<?xml version='1.0' encoding='utf-8'?>
<device xmlns:xsi="http://www.w3.org/2001/XMLSchema-instance" schemaVersion="1.3" xsi:noNamespaceSchemaLocation="CMSIS-SVD.xsd">
    <vendor>Renesas Electronics Corporation</vendor>
    <vendorID>Renesas</vendorID>
    <name>R7FA6M5BH</name>
    <series>RA6</series>
    <version>1.30.00</version>
    <description>Arm Cortex,M33 based Microcontroller RA6M5 group</description>
    <licenseText>This software is supplied by Renesas Electronics Corporation and is only intended for \n
use with Renesas products. No other uses are authorized. This software is owned by \n
Renesas Electronics Corporation and is protected under all applicable laws, including \n
copyright laws. \n
\n
THIS SOFTWARE IS PROVIDED "AS IS" AND RENESAS MAKES NO WARRANTIES REGARDING \n
THIS SOFTWARE, WHETHER EXPRESS, IMPLIED OR STATUTORY, INCLUDING BUT NOT LIMITED TO \n
WARRANTIES OF MERCHANTABILITY, FITNESS FOR A PARTICULAR PURPOSE AND NON-INFRINGEMENT. \n
ALL SUCH WARRANTIES ARE EXPRESSLY DISCLAIMED. TO THE MAXIMUM EXTENT PERMITTED NOT \n
PROHIBITED BY LAW, NEITHER RENESAS ELECTRONICS CORPORATION NOR ANY OF ITS AFFILIATED \n
COMPANIES SHALL BE LIABLE FOR ANY DIRECT, INDIRECT, SPECIAL, INCIDENTAL OR CONSEQUENTIAL \n
DAMAGES FOR ANY REASON RELATED TO THIS SOFTWARE, EVEN IF RENESAS OR ITS AFFILIATES HAVE \n
BEEN ADVISED OF THE POSSIBILITY OF SUCH DAMAGES. \n
\n
Renesas reserves the right, without notice, to make changes to this software and to \n
discontinue the availability of this software. By using this software, you agree to \n
the additional terms and conditions found by accessing the following link: \n
http://www.renesas.com/disclaimer \n
\n</licenseText>
    <cpu>
        <name>CM33</name>
        <revision>r0p4</revision>
        <endian>little</endian>
        <mpuPresent>true</mpuPresent>
        <fpuPresent>true</fpuPresent>
        <vtorPresent>true</vtorPresent>
        <nvicPrioBits>4</nvicPrioBits>
        <vendorSystickConfig>false</vendorSystickConfig>
        <deviceNumInterrupts>96</deviceNumInterrupts>
    </cpu>
    <headerSystemFilename>system_RA6</headerSystemFilename>
    <headerDefinitionsPrefix>R_</headerDefinitionsPrefix>
    <addressUnitBits>8</addressUnitBits>
    <width>32</width>
    <size>32</size>
    <access>read-write</access>
    <resetValue>0</resetValue>
    <resetMask>0xffffffff</resetMask>
    <peripherals>
        <peripheral>
            <name>RMPU</name>
            <description>Renesas Memory Protection Unit</description>
            <baseAddress>0x40000000</baseAddress>
            <addressBlock>
                <offset>0x00</offset>
                <size>2</size>
                <usage>registers</usage>
            </addressBlock>
            <addressBlock>
                <offset>0x04</offset>
                <size>2</size>
                <usage>registers</usage>
            </addressBlock>
            <addressBlock>
                <offset>0x100</offset>
                <size>2</size>
                <usage>registers</usage>
            </addressBlock>
            <addressBlock>
                <offset>0x104</offset>
                <size>2</size>
                <usage>registers</usage>
            </addressBlock>
            <addressBlock>
                <offset>0x108</offset>
                <size>2</size>
                <usage>registers</usage>
            </addressBlock>
            <addressBlock>
                <offset>0x10C</offset>
                <size>2</size>
                <usage>registers</usage>
            </addressBlock>
            <addressBlock>
                <offset>0x200</offset>
                <size>136</size>
                <usage>registers</usage>
            </addressBlock>
            <addressBlock>
                <offset>0x500</offset>
                <size>2</size>
                <usage>registers</usage>
            </addressBlock>
            <addressBlock>
                <offset>0x504</offset>
                <size>2</size>
                <usage>registers</usage>
            </addressBlock>
            <addressBlock>
                <offset>0x508</offset>
                <size>2</size>
                <usage>registers</usage>
            </addressBlock>
            <addressBlock>
                <offset>0x600</offset>
                <size>72</size>
                <usage>registers</usage>
            </addressBlock>
            <registers>
                <register>
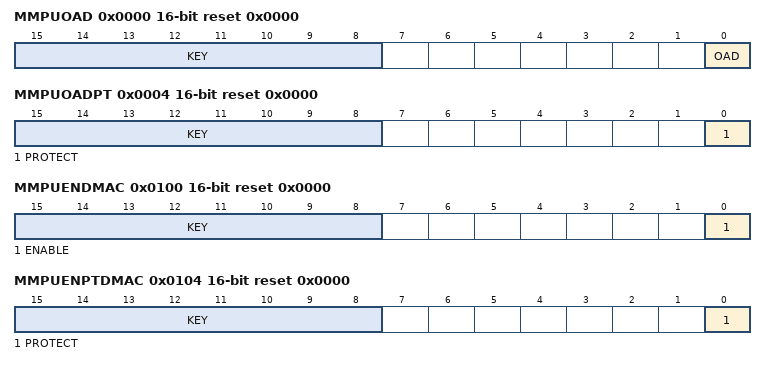
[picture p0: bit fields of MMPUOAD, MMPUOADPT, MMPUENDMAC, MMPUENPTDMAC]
                    <name>MMPUOAD</name>
                    <description>MMPU Operation After Detection Register</description>
                    <addressOffset>0x0000</addressOffset>
                    <size>16</size>
                    <access>read-write</access>
                    <resetValue>0x0000</resetValue>
                    <resetMask>0xffff</resetMask>
                    <fields>
                        <field>
                            <name>OAD</name>
                            <description>Operation after detection</description>
                            <lsb>0</lsb>
                            <msb>0</msb>
                            <access>read-write</access>
                            <enumeratedValues>
                                </enumeratedValues>
                        </field>
                        <field>
                            <name>KEY</name>
                            <description>This bit enables or disables writes to the OAD bit.</description>
                            <lsb>8</lsb>
                            <msb>15</msb>
                            <access>write-only</access>
                        </field>
                    </fields>
                </register>
                <register>
                    <name>MMPUOADPT</name>
                    <description>MMPU Operation After Detection Protect Register</description>
                    <addressOffset>0x0004</addressOffset>
                    <size>16</size>
                    <access>read-write</access>
                    <resetValue>0x0000</resetValue>
                    <resetMask>0xffff</resetMask>
                    <fields>
                        <field>
                            <name>PROTECT</name>
                            <description>Protection of register</description>
                            <lsb>0</lsb>
                            <msb>0</msb>
                            <access>read-write</access>
                            <enumeratedValues>
                                </enumeratedValues>
                        </field>
                        <field>
                            <name>KEY</name>
                            <description>Key code</description>
                            <lsb>8</lsb>
                            <msb>15</msb>
                            <access>write-only</access>
                        </field>
                    </fields>
                </register>
                <register>
                    <name>MMPUENDMAC</name>
                    <description>MMPU Enable Register for DMAC</description>
                    <addressOffset>0x0100</addressOffset>
                    <size>16</size>
                    <access>read-write</access>
                    <resetValue>0x0000</resetValue>
                    <resetMask>0xffff</resetMask>
                    <fields>
                        <field>
                            <name>ENABLE</name>
                            <description>Bus Master MPU of DMAC enable</description>
                            <lsb>0</lsb>
                            <msb>0</msb>
                            <access>read-write</access>
                            <enumeratedValues>
                                </enumeratedValues>
                        </field>
                        <field>
                            <name>KEY</name>
                            <description>These bits enable or disable writes to the ENABLE bit.</description>
                            <lsb>8</lsb>
                            <msb>15</msb>
                            <access>write-only</access>
                        </field>
                    </fields>
                </register>
                <register>
                    <name>MMPUENPTDMAC</name>
                    <description>MMPU Enable Protect Register for DMAC</description>
                    <addressOffset>0x0104</addressOffset>
                    <size>16</size>
                    <access>read-write</access>
                    <resetValue>0x0000</resetValue>
                    <resetMask>0xffff</resetMask>
                    <fields>
                        <field>
                            <name>PROTECT</name>
                            <description>Protection of register</description>
                            <lsb>0</lsb>
                            <msb>0</msb>
                            <access>read-write</access>
                            <enumeratedValues>
                                </enumeratedValues>
                        </field>
                        <field>
                            <name>KEY</name>
                            <description>These bits enable or disable writes to the PROTECT bit.</description>
                            <lsb>8</lsb>
                            <msb>15</msb>
                            <access>write-only</access>
                        </field>
                    </fields>
                </register>
                <register>
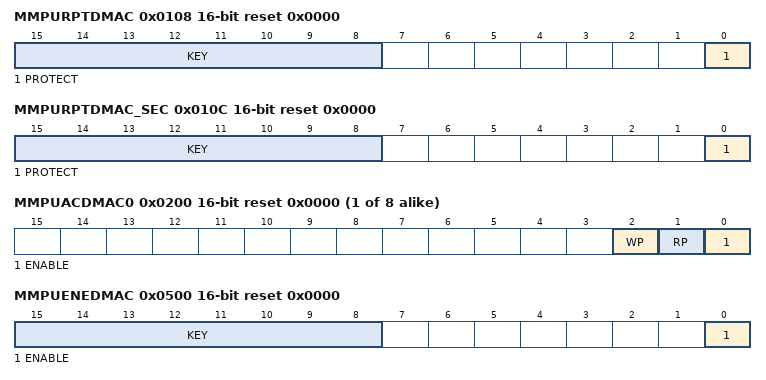
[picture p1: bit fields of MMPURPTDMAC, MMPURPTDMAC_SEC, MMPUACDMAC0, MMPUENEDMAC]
                    <name>MMPURPTDMAC</name>
                    <description>MMPU Regions Protect Register for DMAC</description>
                    <addressOffset>0x0108</addressOffset>
                    <size>16</size>
                    <access>read-write</access>
                    <resetValue>0x0000</resetValue>
                    <resetMask>0xffff</resetMask>
                    <fields>
                        <field>
                            <name>PROTECT</name>
                            <description>Protection of register</description>
                            <lsb>0</lsb>
                            <msb>0</msb>
                            <access>read-write</access>
                            <enumeratedValues>
                                </enumeratedValues>
                        </field>
                        <field>
                            <name>KEY</name>
                            <description>These bits enable or disable writes to the PROTECT bit.</description>
                            <lsb>8</lsb>
                            <msb>15</msb>
                            <access>write-only</access>
                        </field>
                    </fields>
                </register>
                <register>
                    <name>MMPURPTDMAC_SEC</name>
                    <description>MMPU Regions Protect register for DMAC Secure</description>
                    <addressOffset>0x010C</addressOffset>
                    <size>16</size>
                    <access>read-write</access>
                    <resetValue>0x0000</resetValue>
                    <resetMask>0xffff</resetMask>
                    <fields>
                        <field>
                            <name>PROTECT</name>
                            <description>Protection of register</description>
                            <lsb>0</lsb>
                            <msb>0</msb>
                            <access>read-write</access>
                            <enumeratedValues>
                                </enumeratedValues>
                        </field>
                        <field>
                            <name>KEY</name>
                            <description>These bits enable or disable writes to the PROTECT bit.</description>
                            <lsb>8</lsb>
                            <msb>15</msb>
                            <access>write-only</access>
                        </field>
                    </fields>
                </register>
                <register>
                    <dim>8</dim>
                    <dimIncrement>0x010</dimIncrement>
                    <dimIndex>0-7</dimIndex>
                    <name>MMPUACDMAC%s</name>
                    <description>MMPU Access Control Register for DMAC</description>
                    <addressOffset>0x0200</addressOffset>
                    <size>16</size>
                    <access>read-write</access>
                    <resetValue>0x0000</resetValue>
                    <resetMask>0xffff</resetMask>
                    <fields>
                        <field>
                            <name>ENABLE</name>
                            <description>Region enable</description>
                            <lsb>0</lsb>
                            <msb>0</msb>
                            <access>read-write</access>
                            <enumeratedValues>
                                </enumeratedValues>
                        </field>
                        <field>
                            <name>RP</name>
                            <description>Read protection</description>
                            <lsb>1</lsb>
                            <msb>1</msb>
                            <access>read-write</access>
                            <enumeratedValues>
                                </enumeratedValues>
                        </field>
                        <field>
                            <name>WP</name>
                            <description>Write protection</description>
                            <lsb>2</lsb>
                            <msb>2</msb>
                            <access>read-write</access>
                            <enumeratedValues>
                                </enumeratedValues>
                        </field>
                    </fields>
                </register>
                <register>
                    <dim>8</dim>
                    <dimIncrement>0x010</dimIncrement>
                    <dimIndex>0-7</dimIndex>
                    <name>MMPUSDMAC%s</name>
                    <description>MMPU Start Address Register for DMAC</description>
                    <addressOffset>0x0204</addressOffset>
                    <size>32</size>
                    <access>read-write</access>
                    <resetValue>0x00000000</resetValue>
                    <resetMask>0x0000001f</resetMask>
                    <fields>
                        <field>
                            <name>MMPUS</name>
                            <description>Region start address register</description>
                            <lsb>5</lsb>
                            <msb>31</msb>
                            <access>read-write</access>
                        </field>
                    </fields>
                </register>
                <register>
                    <dim>8</dim>
                    <dimIncrement>0x010</dimIncrement>
                    <dimIndex>0-7</dimIndex>
                    <name>MMPUEDMAC%s</name>
                    <description>MMPU End Address Register for DMAC</description>
                    <addressOffset>0x0208</addressOffset>
                    <size>32</size>
                    <access>read-write</access>
                    <resetValue>0x0000001f</resetValue>
                    <resetMask>0x0000001f</resetMask>
                    <fields>
                        <field>
                            <name>MMPUE</name>
                            <description>Region end address register</description>
                            <lsb>5</lsb>
                            <msb>31</msb>
                            <access>read-write</access>
                        </field>
                    </fields>
                </register>
                <register>
                    <name>MMPUENEDMAC</name>
                    <description>MMPU Enable Register for EDMAC</description>
                    <addressOffset>0x0500</addressOffset>
                    <size>16</size>
                    <access>read-write</access>
                    <resetValue>0x0000</resetValue>
                    <resetMask>0xffff</resetMask>
                    <fields>
                        <field>
                            <name>ENABLE</name>
                            <description>Bus Master MPU of EDMAC enable</description>
                            <lsb>0</lsb>
                            <msb>0</msb>
                            <access>read-write</access>
                            <enumeratedValues>
                                </enumeratedValues>
                        </field>
                        <field>
                            <name>KEY</name>
                            <description>These bits enable or disable writes to the ENABLE bit.</description>
                            <lsb>8</lsb>
                            <msb>15</msb>
                            <access>write-only</access>
                        </field>
                    </fields>
                </register>
                <register>
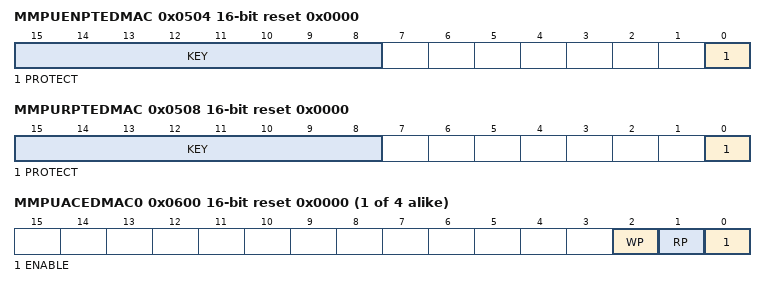
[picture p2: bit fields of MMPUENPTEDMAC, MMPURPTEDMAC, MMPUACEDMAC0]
                    <name>MMPUENPTEDMAC</name>
                    <description>MMPU Enable Protect Register for EDMAC</description>
                    <addressOffset>0x0504</addressOffset>
                    <size>16</size>
                    <access>read-write</access>
                    <resetValue>0x0000</resetValue>
                    <resetMask>0xffff</resetMask>
                    <fields>
                        <field>
                            <name>PROTECT</name>
                            <description>Protection of register</description>
                            <lsb>0</lsb>
                            <msb>0</msb>
                            <access>read-write</access>
                            <enumeratedValues>
                                </enumeratedValues>
                        </field>
                        <field>
                            <name>KEY</name>
                            <description>These bits enable or disable writes to the PROTECT bit.</description>
                            <lsb>8</lsb>
                            <msb>15</msb>
                            <access>write-only</access>
                        </field>
                    </fields>
                </register>
                <register>
                    <name>MMPURPTEDMAC</name>
                    <description>MMPU Regions Protect Register for EDMAC</description>
                    <addressOffset>0x0508</addressOffset>
                    <size>16</size>
                    <access>read-write</access>
                    <resetValue>0x0000</resetValue>
                    <resetMask>0xffff</resetMask>
                    <fields>
                        <field>
                            <name>PROTECT</name>
                            <description>Protection of register</description>
                            <lsb>0</lsb>
                            <msb>0</msb>
                            <access>read-write</access>
                            <enumeratedValues>
                                </enumeratedValues>
                        </field>
                        <field>
                            <name>KEY</name>
                            <description>This bit is used to enable or disable writing of the PROTECT bit.</description>
                            <lsb>8</lsb>
                            <msb>15</msb>
                            <access>write-only</access>
                        </field>
                    </fields>
                </register>
                <register>
                    <dim>4</dim>
                    <dimIncrement>0x010</dimIncrement>
                    <dimIndex>0-3</dimIndex>
                    <name>MMPUACEDMAC%s</name>
                    <description>MMPU Access Control Register for EDMAC</description>
                    <addressOffset>0x0600</addressOffset>
                    <size>16</size>
                    <access>read-write</access>
                    <resetValue>0x0000</resetValue>
                    <resetMask>0xffff</resetMask>
                    <fields>
                        <field>
                            <name>ENABLE</name>
                            <description>Region enable</description>
                            <lsb>0</lsb>
                            <msb>0</msb>
                            <access>read-write</access>
                            <enumeratedValues>
                                </enumeratedValues>
                        </field>
                        <field>
                            <name>RP</name>
                            <description>Read protection</description>
                            <lsb>1</lsb>
                            <msb>1</msb>
                            <access>read-write</access>
                            <enumeratedValues>
                                </enumeratedValues>
                        </field>
                        <field>
                            <name>WP</name>
                            <description>Write protection</description>
                            <lsb>2</lsb>
                            <msb>2</msb>
                            <access>read-write</access>
                            <enumeratedValues>
                                </enumeratedValues>
                        </field>
                    </fields>
                </register>
                <register>
                    <dim>4</dim>
                    <dimIncrement>0x010</dimIncrement>
                    <dimIndex>0-3</dimIndex>
                    <name>MMPUSEDMAC%s</name>
                    <description>MMPU Start Address Register for EDMAC</description>
                    <addressOffset>0x0604</addressOffset>
                    <size>32</size>
                    <access>read-write</access>
                    <resetValue>0x00000000</resetValue>
                    <resetMask>0x0000001f</resetMask>
                    <fields>
                        <field>
                            <name>MMPUS</name>
                            <description>Region start address register for EDMAC</description>
                            <lsb>5</lsb>
                            <msb>31</msb>
                            <access>read-write</access>
                        </field>
                    </fields>
                </register>
                <register>
                    <dim>4</dim>
                    <dimIncrement>0x010</dimIncrement>
                    <dimIndex>0-3</dimIndex>
                    <name>MMPUEEDMAC%s</name>
                    <description>MMPU End Address Register for EDMAC</description>
                    <addressOffset>0x0608</addressOffset>
                    <size>32</size>
                    <access>read-write</access>
                    <resetValue>0x0000001f</resetValue>
                    <resetMask>0x0000001f</resetMask>
                    <fields>
                        <field>
                            <name>MMPUE</name>
                            <description>Region end address register for EDMAC</description>
                            <lsb>5</lsb>
                            <msb>31</msb>
                            <access>read-write</access>
                        </field>
                    </fields>
                </register>
            </registers>
        </peripheral>
        <peripheral>
            <name>TZF</name>
            <description>TrustZone Filter</description>
            <baseAddress>0x40000E00</baseAddress>
            <addressBlock>
                <offset>0x00</offset>
                <size>2</size>
                <usage>registers</usage>
            </addressBlock>
            <addressBlock>
                <offset>0x04</offset>
                <size>2</size>
                <usage>registers</usage>
            </addressBlock>
            <registers>
                <register>
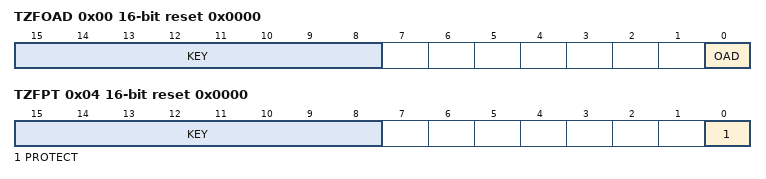
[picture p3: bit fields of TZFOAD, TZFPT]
                    <name>TZFOAD</name>
                    <description>TrustZone Filter Operation After Detection Register </description>
                    <addressOffset>0x00</addressOffset>
                    <size>16</size>
                    <access>read-write</access>
                    <resetValue>0x0000</resetValue>
                    <resetMask>0xffff</resetMask>
                    <fields>
                        <field>
                            <name>OAD</name>
                            <description>Operation after detection</description>
                            <lsb>0</lsb>
                            <msb>0</msb>
                            <access>read-write</access>
                            <enumeratedValues>
                                </enumeratedValues>
                        </field>
                        <field>
                            <name>KEY</name>
                            <description>KeyCode</description>
                            <lsb>8</lsb>
                            <msb>15</msb>
                            <access>write-only</access>
                        </field>
                    </fields>
                </register>
                <register>
                    <name>TZFPT</name>
                    <description>TrustZone Filter Protect Register</description>
                    <addressOffset>0x04</addressOffset>
                    <size>16</size>
                    <access>read-write</access>
                    <resetValue>0x0000</resetValue>
                    <resetMask>0xffff</resetMask>
                    <fields>
                        <field>
                            <name>PROTECT</name>
                            <description>Protection of register</description>
                            <lsb>0</lsb>
                            <msb>0</msb>
                            <access>read-write</access>
                            <enumeratedValues>
                                </enumeratedValues>
                        </field>
                        <field>
                            <name>KEY</name>
                            <description>KeyCode</description>
                            <lsb>8</lsb>
                            <msb>15</msb>
                            <access>write-only</access>
                        </field>
                    </fields>
                </register>
            </registers>
        </peripheral>
        <peripheral>
            <name>SRAM</name>
            <description>SRAM Control</description>
            <baseAddress>0x40002000</baseAddress>
            <addressBlock>
                <offset>0x00</offset>
                <size>1</size>
                <usage>registers</usage>
            </addressBlock>
            <addressBlock>
                <offset>0x04</offset>
                <size>1</size>
                <usage>registers</usage>
            </addressBlock>
            <addressBlock>
                <offset>0x08</offset>
                <size>1</size>
                <usage>registers</usage>
            </addressBlock>
            <addressBlock>
                <offset>0x0C</offset>
                <size>1</size>
                <usage>registers</usage>
            </addressBlock>
            <addressBlock>
                <offset>0xC0</offset>
                <size>5</size>
                <usage>registers</usage>
            </addressBlock>
            <addressBlock>
                <offset>0xD0</offset>
                <size>1</size>
                <usage>registers</usage>
            </addressBlock>
            <addressBlock>
                <offset>0xD4</offset>
                <size>1</size>
                <usage>registers</usage>
            </addressBlock>
            <addressBlock>
                <offset>0xD8</offset>
                <size>1</size>
                <usage>registers</usage>
            </addressBlock>
            <registers>
                <register>
                    <name>PARIOAD</name>
                    <description>SRAM Parity Error Operation After Detection Register</description>
                    <addressOffset>0x00</addressOffset>
                    <size>8</size>
                    <access>read-write</access>
                    <resetValue>0x00</resetValue>
                    <resetMask>0xff</resetMask>
                    <fields>
                        <field>
                            <name>OAD</name>
                            <description>Operation After Detection</description>
                            <lsb>0</lsb>
                            <msb>0</msb>
                            <access>read-write</access>
                            <enumeratedValues>
                                </enumeratedValues>
                        </field>
                    </fields>
                </register>
                <register>
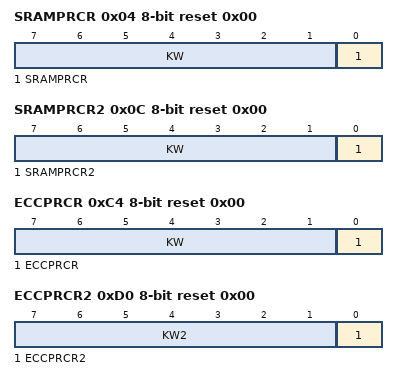
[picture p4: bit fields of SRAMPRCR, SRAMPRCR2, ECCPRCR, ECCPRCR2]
                    <name>SRAMPRCR</name>
                    <description>SRAM Protection Register</description>
                    <addressOffset>0x04</addressOffset>
                    <size>8</size>
                    <access>read-write</access>
                    <resetValue>0x00</resetValue>
                    <resetMask>0xff</resetMask>
                    <fields>
                        <field>
                            <name>SRAMPRCR</name>
                            <description>Register Write Control</description>
                            <lsb>0</lsb>
                            <msb>0</msb>
                            <access>read-write</access>
                            <enumeratedValues>
                                </enumeratedValues>
                        </field>
                        <field>
                            <name>KW</name>
                            <description>Write Key Code</description>
                            <lsb>1</lsb>
                            <msb>7</msb>
                            <access>write-only</access>
                        </field>
                    </fields>
                </register>
                <register>
                    <name>SRAMWTSC</name>
                    <description>SRAM Wait State Control Register</description>
                    <addressOffset>0x08</addressOffset>
                    <size>8</size>
                    <access>read-write</access>
                    <resetValue>0x01</resetValue>
                    <resetMask>0xff</resetMask>
                    <fields>
                        <field>
                            <name>SRAM0WTEN</name>
                            <description>SRAM0 wait enable</description>
                            <lsb>0</lsb>
                            <msb>0</msb>
                            <access>read-write</access>
                            <enumeratedValues>
                                </enumeratedValues>
                        </field>
                    </fields>
                </register>
                <register>
                    <name>SRAMPRCR2</name>
                    <description>SRAM Protection Register 2</description>
                    <addressOffset>0x0C</addressOffset>
                    <size>8</size>
                    <access>read-write</access>
                    <resetValue>0x00</resetValue>
                    <resetMask>0xff</resetMask>
                    <fields>
                        <field>
                            <name>SRAMPRCR2</name>
                            <description>Register Write Control</description>
                            <lsb>0</lsb>
                            <msb>0</msb>
                            <access>read-write</access>
                            <enumeratedValues>
                                </enumeratedValues>
                        </field>
                        <field>
                            <name>KW</name>
                            <description>Write Key Code</description>
                            <lsb>1</lsb>
                            <msb>7</msb>
                            <access>write-only</access>
                        </field>
                    </fields>
                </register>
                <register>
                    <name>ECCMODE</name>
                    <description>ECC Operating Mode Control Register</description>
                    <addressOffset>0xC0</addressOffset>
                    <size>8</size>
                    <access>read-write</access>
                    <resetValue>0x00</resetValue>
                    <resetMask>0xff</resetMask>
                    <fields>
                        <field>
                            <name>ECCMOD</name>
                            <description>ECC Operating Mode Select</description>
                            <lsb>0</lsb>
                            <msb>1</msb>
                            <access>read-write</access>
                            <enumeratedValues>
                                </enumeratedValues>
                        </field>
                    </fields>
                </register>
                <register>
                    <name>ECC2STS</name>
                    <description>ECC 2-Bit Error Status Register</description>
                    <addressOffset>0xC1</addressOffset>
                    <size>8</size>
                    <access>read-write</access>
                    <resetValue>0x00</resetValue>
                    <resetMask>0xff</resetMask>
                    <fields>
                        <field>
                            <name>ECC2ERR</name>
                            <description>ECC 2-Bit Error Status</description>
                            <lsb>0</lsb>
                            <msb>0</msb>
                            <access>read-write</access>
                            <enumeratedValues>
                                </enumeratedValues>
                        </field>
                    </fields>
                </register>
                <register>
                    <name>ECC1STSEN</name>
                    <description>ECC 1-Bit Error Information Update Enable Register</description>
                    <addressOffset>0xC2</addressOffset>
                    <size>8</size>
                    <access>read-write</access>
                    <resetValue>0x00</resetValue>
                    <resetMask>0xff</resetMask>
                    <fields>
                        <field>
                            <name>E1STSEN</name>
                            <description>ECC 1-Bit Error Information Update Enable</description>
                            <lsb>0</lsb>
                            <msb>0</msb>
                            <access>read-write</access>
                            <enumeratedValues>
                                </enumeratedValues>
                        </field>
                    </fields>
                </register>
                <register>
                    <name>ECC1STS</name>
                    <description>ECC 1-Bit Error Status Register</description>
                    <addressOffset>0xC3</addressOffset>
                    <size>8</size>
                    <access>read-write</access>
                    <resetValue>0x00</resetValue>
                    <resetMask>0xff</resetMask>
                    <fields>
                        <field>
                            <name>ECC1ERR</name>
                            <description>ECC 1-Bit Error Status</description>
                            <lsb>0</lsb>
                            <msb>0</msb>
                            <access>read-write</access>
                            <enumeratedValues>
                                </enumeratedValues>
                        </field>
                    </fields>
                </register>
                <register>
                    <name>ECCPRCR</name>
                    <description>ECC Protection Register</description>
                    <addressOffset>0xC4</addressOffset>
                    <size>8</size>
                    <access>read-write</access>
                    <resetValue>0x00</resetValue>
                    <resetMask>0xff</resetMask>
                    <fields>
                        <field>
                            <name>ECCPRCR</name>
                            <description>Register Write Control</description>
                            <lsb>0</lsb>
                            <msb>0</msb>
                            <access>read-write</access>
                            <enumeratedValues>
                                </enumeratedValues>
                        </field>
                        <field>
                            <name>KW</name>
                            <description>Write Key Code</description>
                            <lsb>1</lsb>
                            <msb>7</msb>
                            <access>write-only</access>
                            <enumeratedValues>
                                </enumeratedValues>
                        </field>
                    </fields>
                </register>
                <register>
                    <name>ECCPRCR2</name>
                    <description>ECC Protection Register 2</description>
                    <addressOffset>0xD0</addressOffset>
                    <size>8</size>
                    <access>read-write</access>
                    <resetValue>0x00</resetValue>
                    <resetMask>0xff</resetMask>
                    <fields>
                        <field>
                            <name>ECCPRCR2</name>
                            <description>Register Write Control</description>
                            <lsb>0</lsb>
                            <msb>0</msb>
                            <access>read-write</access>
                            <enumeratedValues>
                                </enumeratedValues>
                        </field>
                        <field>
                            <name>KW2</name>
                            <description>Write Key Code</description>
                            <lsb>1</lsb>
                            <msb>7</msb>
                            <access>write-only</access>
                            <enumeratedValues>
                                </enumeratedValues>
                        </field>
                    </fields>
                </register>
                <register>
                    <name>ECCETST</name>
                    <description>ECC Test Control Register</description>
                    <addressOffset>0xD4</addressOffset>
                    <size>8</size>
                    <access>read-write</access>
                    <resetValue>0x00</resetValue>
                    <resetMask>0xff</resetMask>
                    <fields>
                        <field>
                            <name>TSTBYP</name>
                            <description>ECC Bypass Select</description>
                            <lsb>0</lsb>
                            <msb>0</msb>
                            <access>read-write</access>
                            <enumeratedValues>
                                </enumeratedValues>
                        </field>
                    </fields>
                </register>
                <register>
                    <name>ECCOAD</name>
                    <description>SRAM ECC Error Operation After Detection Register</description>
                    <addressOffset>0xD8</addressOffset>
                    <size>8</size>
                    <access>read-write</access>
                    <resetValue>0x00</resetValue>
                    <resetMask>0xff</resetMask>
                    <fields>
                        <field>
                            <name>OAD</name>
                            <description>Operation After Detection</description>
                            <lsb>0</lsb>
                            <msb>0</msb>
                            <access>read-write</access>
                            <enumeratedValues>
                                </enumeratedValues>
                        </field>
                    </fields>
                </register>
            </registers>
        </peripheral>
        <peripheral>
            <name>BUS</name>
            <description>Bus Control</description>
            <baseAddress>0x40003000</baseAddress>
            <addressBlock>
                <offset>0x02</offset>
                <size>134</size>
                <usage>registers</usage>
            </addressBlock>
            <addressBlock>
                <offset>0x802</offset>
                <size>136</size>
                <usage>registers</usage>
            </addressBlock>
            <addressBlock>
                <offset>0x1100</offset>
                <size>2</size>
                <usage>registers</usage>
            </addressBlock>
            <addressBlock>
                <offset>0x1104</offset>
                <size>2</size>
                <usage>registers</usage>
            </addressBlock>
            <addressBlock>
                <offset>0x1110</offset>
                <size>2</size>
                <usage>registers</usage>
            </addressBlock>
            <addressBlock>
                <offset>0x1120</offset>
                <size>2</size>
                <usage>registers</usage>
            </addressBlock>
            <addressBlock>
                <offset>0x1130</offset>
                <size>2</size>
                <usage>registers</usage>
            </addressBlock>
            <addressBlock>
                <offset>0x1134</offset>
                <size>2</size>
                <usage>registers</usage>
            </addressBlock>
            <addressBlock>
                <offset>0x1140</offset>
                <size>2</size>
                <usage>registers</usage>
            </addressBlock>
            <addressBlock>
                <offset>0x1144</offset>
                <size>2</size>
                <usage>registers</usage>
            </addressBlock>
            <addressBlock>
                <offset>0x1148</offset>
                <size>2</size>
                <usage>registers</usage>
            </addressBlock>
            <addressBlock>
                <offset>0x1800</offset>
                <size>68</size>
                <usage>registers</usage>
            </addressBlock>
            <addressBlock>
                <offset>0x1900</offset>
                <size>68</size>
                <usage>registers</usage>
            </addressBlock>
            <addressBlock>
                <offset>0x1A00</offset>
                <size>72</size>
                <usage>registers</usage>
            </addressBlock>
            <registers>
                <register>
                    <dim>8</dim>
                    <dimIncrement>0x10</dimIncrement>
                    <dimIndex>0-7</dimIndex>
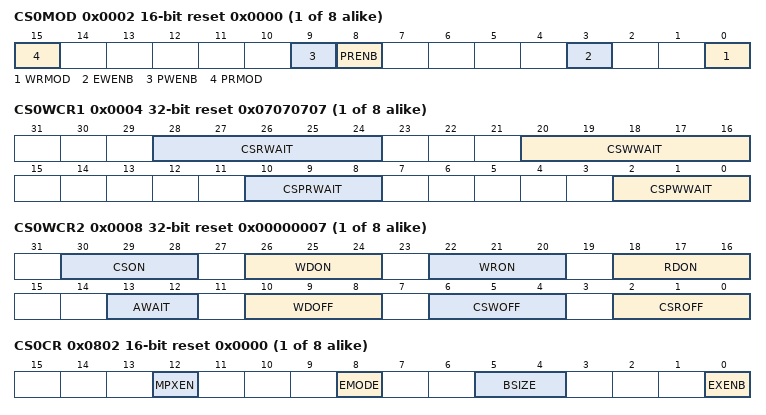
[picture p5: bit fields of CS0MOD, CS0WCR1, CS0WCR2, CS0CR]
                    <name>CS%sMOD</name>
                    <description>CS%s Mode Register</description>
                    <addressOffset>0x0002</addressOffset>
                    <size>16</size>
                    <access>read-write</access>
                    <resetValue>0x0000</resetValue>
                    <resetMask>0xffff</resetMask>
                    <fields>
                        <field>
                            <name>WRMOD</name>
                            <description>Write Access Mode Select</description>
                            <lsb>0</lsb>
                            <msb>0</msb>
                            <access>read-write</access>
                            <enumeratedValues>
                                </enumeratedValues>
                        </field>
                        <field>
                            <name>EWENB</name>
                            <description>External Wait Enable</description>
                            <lsb>3</lsb>
                            <msb>3</msb>
                            <access>read-write</access>
                            <enumeratedValues>
                                </enumeratedValues>
                        </field>
                        <field>
                            <name>PRENB</name>
                            <description>Page Read Access Enable</description>
                            <lsb>8</lsb>
                            <msb>8</msb>
                            <access>read-write</access>
                            <enumeratedValues>
                                </enumeratedValues>
                        </field>
                        <field>
                            <name>PWENB</name>
                            <description>Page Write Access Enable</description>
                            <lsb>9</lsb>
                            <msb>9</msb>
                            <access>read-write</access>
                            <enumeratedValues>
                                </enumeratedValues>
                        </field>
                        <field>
                            <name>PRMOD</name>
                            <description>Page Read Access Mode Select</description>
                            <lsb>15</lsb>
                            <msb>15</msb>
                            <access>read-write</access>
                            <enumeratedValues>
                                </enumeratedValues>
                        </field>
                    </fields>
                </register>
                <register>
                    <dim>8</dim>
                    <dimIncrement>0x10</dimIncrement>
                    <dimIndex>0-7</dimIndex>
                    <name>CS%sWCR1</name>
                    <description>CS%s Wait Control Register 1</description>
                    <addressOffset>0x0004</addressOffset>
                    <size>32</size>
                    <access>read-write</access>
                    <resetValue>0x07070707</resetValue>
                    <resetMask>0xffffffff</resetMask>
                    <fields>
                        <field>
                            <name>CSPWWAIT</name>
                            <description>Page Write Cycle Wait Select</description>
                            <lsb>0</lsb>
                            <msb>2</msb>
                            <access>read-write</access>
                        </field>
                        <field>
                            <name>CSPRWAIT</name>
                            <description>Page Read Cycle Wait Select</description>
                            <lsb>8</lsb>
                            <msb>10</msb>
                            <access>read-write</access>
                        </field>
                        <field>
                            <name>CSWWAIT</name>
                            <description>Normal Write Cycle Wait Select</description>
                            <lsb>16</lsb>
                            <msb>20</msb>
                            <access>read-write</access>
                        </field>
                        <field>
                            <name>CSRWAIT</name>
                            <description>Normal Read Cycle Wait Select</description>
                            <lsb>24</lsb>
                            <msb>28</msb>
                            <access>read-write</access>
                        </field>
                    </fields>
                </register>
                <register>
                    <dim>8</dim>
                    <dimIncrement>0x10</dimIncrement>
                    <dimIndex>0-7</dimIndex>
                    <name>CS%sWCR2</name>
                    <description>CS%s Wait Control Register 2</description>
                    <addressOffset>0x0008</addressOffset>
                    <size>32</size>
                    <access>read-write</access>
                    <resetValue>0x00000007</resetValue>
                    <resetMask>0xffffffff</resetMask>
                    <fields>
                        <field>
                            <name>CSROFF</name>
                            <description>Read,Access CS Extension Cycle Select</description>
                            <lsb>0</lsb>
                            <msb>2</msb>
                            <access>read-write</access>
                        </field>
                        <field>
                            <name>CSWOFF</name>
                            <description>Write,Access CS Extension Cycle Select</description>
                            <lsb>4</lsb>
                            <msb>6</msb>
                            <access>read-write</access>
                        </field>
                        <field>
                            <name>WDOFF</name>
                            <description>Write Data Output Extension Cycle Select</description>
                            <lsb>8</lsb>
                            <msb>10</msb>
                            <access>read-write</access>
                        </field>
                        <field>
                            <name>AWAIT</name>
                            <description>Address Cycle Wait Select</description>
                            <lsb>12</lsb>
                            <msb>13</msb>
                            <access>read-write</access>
                        </field>
                        <field>
                            <name>RDON</name>
                            <description>RD Assert Wait Select</description>
                            <lsb>16</lsb>
                            <msb>18</msb>
                            <access>read-write</access>
                        </field>
                        <field>
                            <name>WRON</name>
                            <description>WR Assert Wait Select</description>
                            <lsb>20</lsb>
                            <msb>22</msb>
                            <access>read-write</access>
                        </field>
                        <field>
                            <name>WDON</name>
                            <description>Write Data Output Wait Select</description>
                            <lsb>24</lsb>
                            <msb>26</msb>
                            <access>read-write</access>
                        </field>
                        <field>
                            <name>CSON</name>
                            <description>CS Assert Wait Select</description>
                            <lsb>28</lsb>
                            <msb>30</msb>
                            <access>read-write</access>
                        </field>
                    </fields>
                </register>
                <register>
                    <dim>8</dim>
                    <dimIncrement>0x10</dimIncrement>
                    <dimIndex>0-7</dimIndex>
                    <name>CS%sCR</name>
                    <description>CS%s Control Register</description>
                    <addressOffset>0x0802</addressOffset>
                    <size>16</size>
                    <access>read-write</access>
                    <resetValue>0x0000</resetValue>
                    <resetMask>0xffff</resetMask>
                    <fields>
                        <field>
                            <name>EXENB</name>
                            <description>Operation Enable</description>
                            <lsb>0</lsb>
                            <msb>0</msb>
                            <access>read-write</access>
                            <enumeratedValues>
                                </enumeratedValues>
                        </field>
                        <field>
                            <name>BSIZE</name>
                            <description>External Bus Width Select</description>
                            <lsb>4</lsb>
                            <msb>5</msb>
                            <access>read-write</access>
                            <enumeratedValues>
                                </enumeratedValues>
                        </field>
                        <field>
                            <name>EMODE</name>
                            <description>Endian Mode</description>
                            <lsb>8</lsb>
                            <msb>8</msb>
                            <access>read-write</access>
                            <enumeratedValues>
                                </enumeratedValues>
                        </field>
                        <field>
                            <name>MPXEN</name>
                            <description>Address/Data Multiplexed I/O Interface Select</description>
                            <lsb>12</lsb>
                            <msb>12</msb>
                            <access>read-write</access>
                            <enumeratedValues>
                                </enumeratedValues>
                        </field>
                    </fields>
                </register>
                <register>
                    <dim>8</dim>
                    <dimIncrement>0x10</dimIncrement>
                    <dimIndex>0-7</dimIndex>
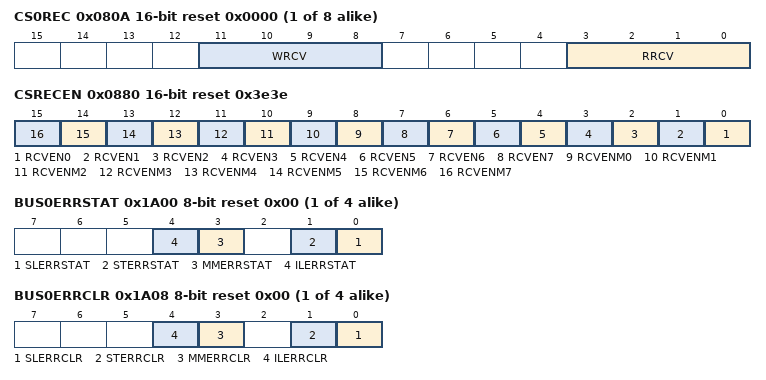
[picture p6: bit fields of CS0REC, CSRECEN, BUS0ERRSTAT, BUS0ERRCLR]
                    <name>CS%sREC</name>
                    <description>CS%s Recovery Cycle Register</description>
                    <addressOffset>0x080A</addressOffset>
                    <size>16</size>
                    <access>read-write</access>
                    <resetValue>0x0000</resetValue>
                    <resetMask>0xffff</resetMask>
                    <fields>
                        <field>
                            <name>RRCV</name>
                            <description>Read Recovery</description>
                            <lsb>0</lsb>
                            <msb>3</msb>
                            <access>read-write</access>
                            <enumeratedValues>
                                </enumeratedValues>
                        </field>
                        <field>
                            <name>WRCV</name>
                            <description>Write Recovery</description>
                            <lsb>8</lsb>
                            <msb>11</msb>
                            <access>read-write</access>
                            <enumeratedValues>
                                </enumeratedValues>
                        </field>
                    </fields>
                </register>
                <register>
                    <name>CSRECEN</name>
                    <description>CS Recovery Cycle Insertion Enable Register</description>
                    <addressOffset>0x0880</addressOffset>
                    <size>16</size>
                    <access>read-write</access>
                    <resetValue>0x3e3e</resetValue>
                    <resetMask>0xffff</resetMask>
                    <fields>
                        <field>
                            <name>RCVEN0</name>
                            <description>Separate Bus Recovery Cycle Insertion Enable 0</description>
                            <lsb>0</lsb>
                            <msb>0</msb>
                            <access>read-write</access>
                            <enumeratedValues>
                                </enumeratedValues>
                        </field>
                        <field>
                            <name>RCVEN1</name>
                            <description>Separate Bus Recovery Cycle Insertion Enable 1</description>
                            <lsb>1</lsb>
                            <msb>1</msb>
                            <access>read-write</access>
                            <enumeratedValues>
                                </enumeratedValues>
                        </field>
                        <field>
                            <name>RCVEN2</name>
                            <description>Separate Bus Recovery Cycle Insertion Enable 2</description>
                            <lsb>2</lsb>
                            <msb>2</msb>
                            <access>read-write</access>
                            <enumeratedValues>
                                </enumeratedValues>
                        </field>
                        <field>
                            <name>RCVEN3</name>
                            <description>Separate Bus Recovery Cycle Insertion Enable 3</description>
                            <lsb>3</lsb>
                            <msb>3</msb>
                            <access>read-write</access>
                            <enumeratedValues>
                                </enumeratedValues>
                        </field>
                        <field>
                            <name>RCVEN4</name>
                            <description>Separate Bus Recovery Cycle Insertion Enable 4</description>
                            <lsb>4</lsb>
                            <msb>4</msb>
                            <access>read-write</access>
                            <enumeratedValues>
                                </enumeratedValues>
                        </field>
                        <field>
                            <name>RCVEN5</name>
                            <description>Separate Bus Recovery Cycle Insertion Enable 5</description>
                            <lsb>5</lsb>
                            <msb>5</msb>
                            <access>read-write</access>
                            <enumeratedValues>
                                </enumeratedValues>
                        </field>
                        <field>
                            <name>RCVEN6</name>
                            <description>Separate Bus Recovery Cycle Insertion Enable 6</description>
                            <lsb>6</lsb>
                            <msb>6</msb>
                            <access>read-write</access>
                            <enumeratedValues>
                                </enumeratedValues>
                        </field>
                        <field>
                            <name>RCVEN7</name>
                            <description>Separate Bus Recovery Cycle Insertion Enable 7</description>
                            <lsb>7</lsb>
                            <msb>7</msb>
                            <access>read-write</access>
                            <enumeratedValues>
                                </enumeratedValues>
                        </field>
                        <field>
                            <name>RCVENM0</name>
                            <description>Multiplexed Bus Recovery Cycle Insertion Enable 0</description>
                            <lsb>8</lsb>
                            <msb>8</msb>
                            <access>read-write</access>
                            <enumeratedValues>
                                </enumeratedValues>
                        </field>
                        <field>
                            <name>RCVENM1</name>
                            <description>Multiplexed Bus Recovery Cycle Insertion Enable 1</description>
                            <lsb>9</lsb>
                            <msb>9</msb>
                            <access>read-write</access>
                            <enumeratedValues>
                                </enumeratedValues>
                        </field>
                        <field>
                            <name>RCVENM2</name>
                            <description>Multiplexed Bus Recovery Cycle Insertion Enable 2</description>
                            <lsb>10</lsb>
                            <msb>10</msb>
                            <access>read-write</access>
                            <enumeratedValues>
                                </enumeratedValues>
                        </field>
                        <field>
                            <name>RCVENM3</name>
                            <description>Multiplexed Bus Recovery Cycle Insertion Enable 3</description>
                            <lsb>11</lsb>
                            <msb>11</msb>
                            <access>read-write</access>
                            <enumeratedValues>
                                </enumeratedValues>
                        </field>
                        <field>
                            <name>RCVENM4</name>
                            <description>Multiplexed Bus Recovery Cycle Insertion Enable 4</description>
                            <lsb>12</lsb>
                            <msb>12</msb>
                            <access>read-write</access>
                            <enumeratedValues>
                                </enumeratedValues>
                        </field>
                        <field>
                            <name>RCVENM5</name>
                            <description>Multiplexed Bus Recovery Cycle Insertion Enable 5</description>
                            <lsb>13</lsb>
                            <msb>13</msb>
                            <access>read-write</access>
                            <enumeratedValues>
                                </enumeratedValues>
                        </field>
                        <field>
                            <name>RCVENM6</name>
                            <description>Multiplexed Bus Recovery Cycle Insertion Enable 6</description>
                            <lsb>14</lsb>
                            <msb>14</msb>
                            <access>read-write</access>
                            <enumeratedValues>
                                </enumeratedValues>
                        </field>
                        <field>
                            <name>RCVENM7</name>
                            <description>Multiplexed Bus Recovery Cycle Insertion Enable 7</description>
                            <lsb>15</lsb>
                            <msb>15</msb>
                            <access>read-write</access>
                            <enumeratedValues>
                                </enumeratedValues>
                        </field>
                    </fields>
                </register>
                <register>
                    <name>BUSSCNTFHBIU</name>
                    <description>Slave Bus Control Register</description>
                    <addressOffset>0x1100</addressOffset>
                    <size>16</size>
                    <access>read-write</access>
                    <resetValue>0x0000</resetValue>
                    <resetMask>0xffff</resetMask>
                    <fields>
                        <field>
                            <name>ARBS</name>
                            <description>Arbitration Select for three masters</description>
                            <lsb>0</lsb>
                            <msb>1</msb>
                            <access>read-write</access>
                            <enumeratedValues>
                                </enumeratedValues>
                        </field>
                    </fields>
                </register>
                <register>
                    <name>BUSSCNTFLBIU</name>
                    <description>Slave Bus Control Register</description>
                    <addressOffset>0x1104</addressOffset>
                    <size>16</size>
                    <access>read-write</access>
                    <resetValue>0x0000</resetValue>
                    <resetMask>0xffff</resetMask>
                    <fields>
                        <field>
                            <name>ARBS</name>
                            <description>Arbitration Select for three masters</description>
                            <lsb>0</lsb>
                            <msb>1</msb>
                            <access>read-write</access>
                            <enumeratedValues>
                                </enumeratedValues>
                        </field>
                    </fields>
                </register>
                <register>
                    <name>BUSSCNTS0BIU</name>
                    <description>Slave Bus Control Register</description>
                    <addressOffset>0x1110</addressOffset>
                    <size>16</size>
                    <access>read-write</access>
                    <resetValue>0x0000</resetValue>
                    <resetMask>0xffff</resetMask>
                    <fields>
                        <field>
                            <name>ARBS</name>
                            <description>Arbitration Select for three masters</description>
                            <lsb>0</lsb>
                            <msb>1</msb>
                            <access>read-write</access>
                            <enumeratedValues>
                                </enumeratedValues>
                        </field>
                    </fields>
                </register>
                <register>
                    <name>BUSSCNTPSBIU</name>
                    <description>Slave Bus Control Register</description>
                    <addressOffset>0x1120</addressOffset>
                    <size>16</size>
                    <access>read-write</access>
                    <resetValue>0x0000</resetValue>
                    <resetMask>0xffff</resetMask>
                    <fields>
                        <field>
                            <name>ARBS</name>
                            <description>Arbitration Select for two masters</description>
                            <lsb>0</lsb>
                            <msb>0</msb>
                            <access>read-write</access>
                            <enumeratedValues>
                                </enumeratedValues>
                        </field>
                    </fields>
                </register>
                <register>
                    <name>BUSSCNTPLBIU</name>
                    <description>Slave Bus Control Register</description>
                    <addressOffset>0x1130</addressOffset>
                    <size>16</size>
                    <access>read-write</access>
                    <resetValue>0x0000</resetValue>
                    <resetMask>0xffff</resetMask>
                    <fields>
                        <field>
                            <name>ARBS</name>
                            <description>Arbitration Select for two masters</description>
                            <lsb>0</lsb>
                            <msb>0</msb>
                            <access>read-write</access>
                            <enumeratedValues>
                                </enumeratedValues>
                        </field>
                    </fields>
                </register>
                <register>
                    <name>BUSSCNTPHBIU</name>
                    <description>Slave Bus Control Register</description>
                    <addressOffset>0x1134</addressOffset>
                    <size>16</size>
                    <access>read-write</access>
                    <resetValue>0x0000</resetValue>
                    <resetMask>0xffff</resetMask>
                    <fields>
                        <field>
                            <name>ARBS</name>
                            <description>Arbitration Select for two masters</description>
                            <lsb>0</lsb>
                            <msb>0</msb>
                            <access>read-write</access>
                            <enumeratedValues>
                                </enumeratedValues>
                        </field>
                    </fields>
                </register>
                <register>
                    <name>BUSSCNTEQBIU</name>
                    <description>Slave Bus Control Register</description>
                    <addressOffset>0x1140</addressOffset>
                    <size>16</size>
                    <access>read-write</access>
                    <resetValue>0x0000</resetValue>
                    <resetMask>0xffff</resetMask>
                    <fields>
                        <field>
                            <name>ARBS</name>
                            <description>Arbitration Select for three masters</description>
                            <lsb>0</lsb>
                            <msb>1</msb>
                            <access>read-write</access>
                            <enumeratedValues>
                                </enumeratedValues>
                        </field>
                    </fields>
                </register>
                <register>
                    <name>BUSSCNTEOBIU</name>
                    <description>Slave Bus Control Register</description>
                    <addressOffset>0x1144</addressOffset>
                    <size>16</size>
                    <access>read-write</access>
                    <resetValue>0x0000</resetValue>
                    <resetMask>0xffff</resetMask>
                    <fields>
                        <field>
                            <name>ARBS</name>
                            <description>Arbitration Select for three masters</description>
                            <lsb>0</lsb>
                            <msb>1</msb>
                            <access>read-write</access>
                            <enumeratedValues>
                                </enumeratedValues>
                        </field>
                    </fields>
                </register>
                <register>
                    <name>BUSSCNTECBIU</name>
                    <description>Slave Bus Control Register</description>
                    <addressOffset>0x1148</addressOffset>
                    <size>16</size>
                    <access>read-write</access>
                    <resetValue>0x0000</resetValue>
                    <resetMask>0xffff</resetMask>
                    <fields>
                        <field>
                            <name>ARBS</name>
                            <description>Arbitration Select for three masters</description>
                            <lsb>0</lsb>
                            <msb>1</msb>
                            <access>read-write</access>
                            <enumeratedValues>
                                </enumeratedValues>
                        </field>
                    </fields>
                </register>
                <register>
                    <dim>4</dim>
                    <dimIncrement>0x10</dimIncrement>
                    <dimIndex>1-4</dimIndex>
                    <name>BUS%sERRADD</name>
                    <description>BUS Error Address Register</description>
                    <addressOffset>0x1800</addressOffset>
                    <size>32</size>
                    <access>read-only</access>
                    <resetValue>0x00000000</resetValue>
                    <resetMask>0xffffffff</resetMask>
                    <fields>
                        <field>
                            <name>BERAD</name>
                            <description>Bus Error Address</description>
                            <lsb>0</lsb>
                            <msb>31</msb>
                            <access>read-only</access>
                        </field>
                    </fields>
                </register>
                <register>
                    <dim>4</dim>
                    <dimIncrement>0x10</dimIncrement>
                    <dimIndex>1-4</dimIndex>
                    <name>BUS%sERRRW</name>
                    <description>BUS Error Read Write Register</description>
                    <addressOffset>0x1804</addressOffset>
                    <size>8</size>
                    <access>read-write</access>
                    <resetValue>0x00</resetValue>
                    <resetMask>0xff</resetMask>
                    <fields>
                        <field>
                            <name>RWSTAT</name>
                            <description>Error Access Read/Write Status</description>
                            <lsb>0</lsb>
                            <msb>0</msb>
                            <access>read-only</access>
                            <enumeratedValues>
                                </enumeratedValues>
                        </field>
                    </fields>
                </register>
                <register>
                    <dim>4</dim>
                    <dimIncrement>0x10</dimIncrement>
                    <dimIndex>1-4</dimIndex>
                    <name>BTZF%sERRADD</name>
                    <description>BUS TZF Error Address Register</description>
                    <addressOffset>0x1900</addressOffset>
                    <size>32</size>
                    <access>read-only</access>
                    <resetValue>0x00000000</resetValue>
                    <resetMask>0xffffffff</resetMask>
                    <fields>
                        <field>
                            <name>BTZFERAD</name>
                            <description>Bus TrustZone Filter Error Address</description>
                            <lsb>0</lsb>
                            <msb>31</msb>
                            <access>read-only</access>
                        </field>
                    </fields>
                </register>
                <register>
                    <dim>4</dim>
                    <dimIncrement>0x10</dimIncrement>
                    <dimIndex>1-4</dimIndex>
                    <name>BTZF%sERRRW</name>
                    <description>BUS TZF Error Read Write Register</description>
                    <addressOffset>0x1904</addressOffset>
                    <size>8</size>
                    <access>read-write</access>
                    <resetValue>0x00</resetValue>
                    <resetMask>0xff</resetMask>
                    <fields>
                        <field>
                            <name>TRWSTAT</name>
                            <description>TrustZone filter error access Read/Write Status</description>
                            <lsb>0</lsb>
                            <msb>0</msb>
                            <access>read-only</access>
                            <enumeratedValues>
                                </enumeratedValues>
                        </field>
                    </fields>
                </register>
                <register>
                    <dim>4</dim>
                    <dimIncrement>0x10</dimIncrement>
                    <dimIndex>1-4</dimIndex>
                    <name>BUS%sERRSTAT</name>
                    <description>BUS Error Status Register %s</description>
                    <addressOffset>0x1A00</addressOffset>
                    <size>8</size>
                    <access>read-only</access>
                    <resetValue>0x00</resetValue>
                    <resetMask>0xff</resetMask>
                    <fields>
                        <field>
                            <name>SLERRSTAT</name>
                            <description>Slave bus Error Status</description>
                            <lsb>0</lsb>
                            <msb>0</msb>
                            <access>read-only</access>
                            <enumeratedValues>
                                </enumeratedValues>
                        </field>
                        <field>
                            <name>STERRSTAT</name>
                            <description>Slave TrustZone filter Error Status</description>
                            <lsb>1</lsb>
                            <msb>1</msb>
                            <access>read-only</access>
                            <enumeratedValues>
                                </enumeratedValues>
                        </field>
                        <field>
                            <name>MMERRSTAT</name>
                            <description>Master MPU Error Status</description>
                            <lsb>3</lsb>
                            <msb>3</msb>
                            <access>read-only</access>
                            <enumeratedValues>
                                </enumeratedValues>
                        </field>
                        <field>
                            <name>ILERRSTAT</name>
                            <description>Illegal address access Error Status</description>
                            <lsb>4</lsb>
                            <msb>4</msb>
                            <access>read-only</access>
                            <enumeratedValues>
                                </enumeratedValues>
                        </field>
                    </fields>
                </register>
                <register>
                    <dim>4</dim>
                    <dimIncrement>0x10</dimIncrement>
                    <dimIndex>1-4</dimIndex>
                    <name>BUS%sERRCLR</name>
                    <description>BUS Error Clear Register %s</description>
                    <addressOffset>0x1A08</addressOffset>
                    <size>8</size>
                    <access>read-write</access>
                    <resetValue>0x00</resetValue>
                    <resetMask>0xff</resetMask>
                    <fields>
                        <field>
                            <name>SLERRCLR</name>
                            <description>Slave bus Error Clear</description>
                            <lsb>0</lsb>
                            <msb>0</msb>
                            <access>read-write</access>
                        </field>
                        <field>
                            <name>STERRCLR</name>
                            <description>Slave TrustZone filter Error Clear</description>
                            <lsb>1</lsb>
                            <msb>1</msb>
                            <access>read-write</access>
                        </field>
                        <field>
                            <name>MMERRCLR</name>
                            <description>Master MPU Error Clear</description>
                            <lsb>3</lsb>
                            <msb>3</msb>
                            <access>read-write</access>
                        </field>
                        <field>
                            <name>ILERRCLR</name>
                            <description>Illegal Address Access Error Clear</description>
                            <lsb>4</lsb>
                            <msb>4</msb>
                            <access>read-write</access>
                        </field>
                    </fields>
                </register>
                <register>
                    <name>DMACDTCERRSTAT</name>
                    <description>DMAC/DTC Error Status Register</description>
                    <addressOffset>0x1A24</addressOffset>
                    <size>8</size>
                    <access>read-only</access>
                    <resetValue>0x00</resetValue>
                    <resetMask>0xff</resetMask>
                    <fields>
                        <field>
                            <name>MTERRSTAT</name>
                            <description>Master TrustZone Filter Error Status</description>
                            <lsb>0</lsb>
                            <msb>0</msb>
                            <access>read-only</access>
                            <enumeratedValues>
                                </enumeratedValues>
                        </field>
                    </fields>
                </register>
                <register>
                    <name>DMACDTCERRCLR</name>
                    <description>DMAC/DTC Error Clear Register</description>
                    <addressOffset>0x1A2C</addressOffset>
                    <size>8</size>
                    <access>read-write</access>
                    <resetValue>0x00</resetValue>
                    <resetMask>0xff</resetMask>
                    <fields>
                        <field>
                            <name>MTERRCLR</name>
                            <description>Master TrustZone filter Error Clear</description>
                            <lsb>0</lsb>
                            <msb>0</msb>
                            <access>read-write</access>
                        </field>
                    </fields>
                </register>
            </registers>
        </peripheral>
        <peripheral>
            <name>DMAC0</name>
            <description>Direct memory access controller 0</description>
            <baseAddress>0x40005000</baseAddress>
            <addressBlock>
                <offset>0x00</offset>
                <size>18</size>
                <usage>registers</usage>
            </addressBlock>
            <addressBlock>
                <offset>0x13</offset>
                <size>3</size>
                <usage>registers</usage>
            </addressBlock>
            <addressBlock>
                <offset>0x18</offset>
                <size>7</size>
                <usage>registers</usage>
            </addressBlock>
            <addressBlock>
                <offset>0x20</offset>
                <size>17</size>
                <usage>registers</usage>
            </addressBlock>
            <registers>
                <register>
                    <name>DMSAR</name>
                    <description>DMA Source Address Register</description>
                    <addressOffset>0x00</addressOffset>
                    <size>32</size>
                    <access>read-write</access>
                    <resetValue>0x00000000</resetValue>
                    <resetMask>0xffffffff</resetMask>
                </register>
                <register>
                    <name>DMDAR</name>
                    <description>DMA Destination Address Register</description>
                    <addressOffset>0x04</addressOffset>
                    <size>32</size>
                    <access>read-write</access>
                    <resetValue>0x00000000</resetValue>
                    <resetMask>0xffffffff</resetMask>
                </register>
                <register>
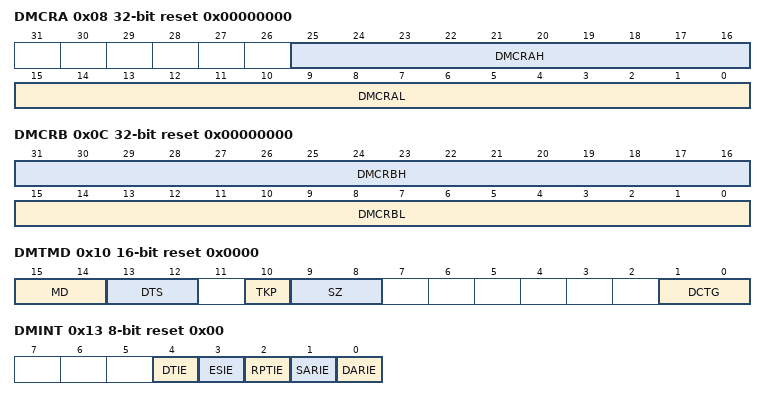
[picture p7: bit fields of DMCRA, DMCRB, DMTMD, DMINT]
                    <name>DMCRA</name>
                    <description>DMA Transfer Count Register</description>
                    <addressOffset>0x08</addressOffset>
                    <size>32</size>
                    <access>read-write</access>
                    <resetValue>0x00000000</resetValue>
                    <resetMask>0xffffffff</resetMask>
                    <fields>
                        <field>
                            <name>DMCRAL</name>
                            <description>Lower bits of transfer count</description>
                            <lsb>0</lsb>
                            <msb>15</msb>
                            <access>read-write</access>
                        </field>
                        <field>
                            <name>DMCRAH</name>
                            <description>Upper bits of transfer count</description>
                            <lsb>16</lsb>
                            <msb>25</msb>
                            <access>read-write</access>
                        </field>
                    </fields>
                </register>
                <register>
                    <name>DMCRB</name>
                    <description>DMA Block Transfer Count Register</description>
                    <addressOffset>0x0C</addressOffset>
                    <size>32</size>
                    <access>read-write</access>
                    <resetValue>0x00000000</resetValue>
                    <resetMask>0xffffffff</resetMask>
                    <fields>
                        <field>
                            <name>DMCRBL</name>
                            <description>Functions as a number of block, repeat or repeat,block transfer counter.</description>
                            <lsb>0</lsb>
                            <msb>15</msb>
                            <access>read-write</access>
                        </field>
                        <field>
                            <name>DMCRBH</name>
                            <description>Specifies the number of block, repeat or repeat,block transfer operations.</description>
                            <lsb>16</lsb>
                            <msb>31</msb>
                            <access>read-write</access>
                        </field>
                    </fields>
                </register>
                <register>
                    <name>DMTMD</name>
                    <description>DMA Transfer Mode Register</description>
                    <addressOffset>0x10</addressOffset>
                    <size>16</size>
                    <access>read-write</access>
                    <resetValue>0x0000</resetValue>
                    <resetMask>0xffff</resetMask>
                    <fields>
                        <field>
                            <name>DCTG</name>
                            <description>Transfer Request Source Select</description>
                            <lsb>0</lsb>
                            <msb>1</msb>
                            <access>read-write</access>
                            <enumeratedValues>
                                </enumeratedValues>
                        </field>
                        <field>
                            <name>SZ</name>
                            <description>Transfer Data Size Select</description>
                            <lsb>8</lsb>
                            <msb>9</msb>
                            <access>read-write</access>
                            <enumeratedValues>
                                </enumeratedValues>
                        </field>
                        <field>
                            <name>TKP</name>
                            <description>Transfer Keeping</description>
                            <lsb>10</lsb>
                            <msb>10</msb>
                            <access>read-write</access>
                            <enumeratedValues>
                                </enumeratedValues>
                        </field>
                        <field>
                            <name>DTS</name>
                            <description>Repeat Area Select</description>
                            <lsb>12</lsb>
                            <msb>13</msb>
                            <access>read-write</access>
                            <enumeratedValues>
                                </enumeratedValues>
                        </field>
                        <field>
                            <name>MD</name>
                            <description>Transfer Mode Select</description>
                            <lsb>14</lsb>
                            <msb>15</msb>
                            <access>read-write</access>
                            <enumeratedValues>
                                </enumeratedValues>
                        </field>
                    </fields>
                </register>
                <register>
                    <name>DMINT</name>
                    <description>DMA Interrupt Setting Register</description>
                    <addressOffset>0x13</addressOffset>
                    <size>8</size>
                    <access>read-write</access>
                    <resetValue>0x00</resetValue>
                    <resetMask>0xff</resetMask>
                    <fields>
                        <field>
                            <name>DARIE</name>
                            <description>Destination Address Extended Repeat Area Overflow Interrupt Enable</description>
                            <lsb>0</lsb>
                            <msb>0</msb>
                            <access>read-write</access>
                            <enumeratedValues>
                                </enumeratedValues>
                        </field>
                        <field>
                            <name>SARIE</name>
                            <description>Source Address Extended Repeat Area Overflow Interrupt Enable</description>
                            <lsb>1</lsb>
                            <msb>1</msb>
                            <access>read-write</access>
                            <enumeratedValues>
                                </enumeratedValues>
                        </field>
                        <field>
                            <name>RPTIE</name>
                            <description>Repeat Size End Interrupt Enable</description>
                            <lsb>2</lsb>
                            <msb>2</msb>
                            <access>read-write</access>
                            <enumeratedValues>
                                </enumeratedValues>
                        </field>
                        <field>
                            <name>ESIE</name>
                            <description>Transfer Escape End Interrupt Enable</description>
                            <lsb>3</lsb>
                            <msb>3</msb>
                            <access>read-write</access>
                            <enumeratedValues>
                                </enumeratedValues>
                        </field>
                        <field>
                            <name>DTIE</name>
                            <description>Transfer End Interrupt Enable</description>
                            <lsb>4</lsb>
                            <msb>4</msb>
                            <access>read-write</access>
                            <enumeratedValues>
                                </enumeratedValues>
                        </field>
                    </fields>
                </register>
                <register>
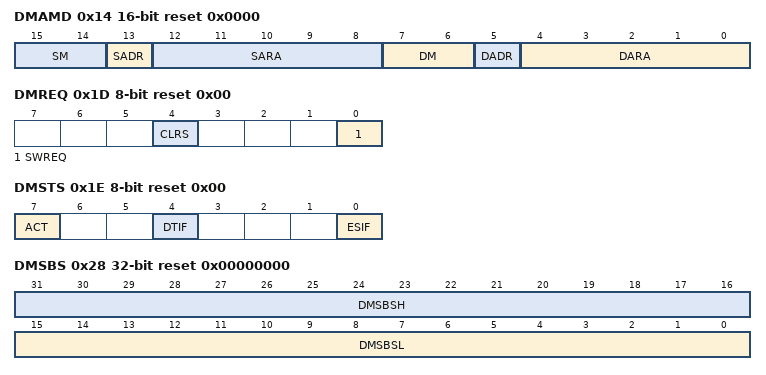
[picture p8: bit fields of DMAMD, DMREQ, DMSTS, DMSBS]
                    <name>DMAMD</name>
                    <description>DMA Address Mode Register</description>
                    <addressOffset>0x14</addressOffset>
                    <size>16</size>
                    <access>read-write</access>
                    <resetValue>0x0000</resetValue>
                    <resetMask>0xffff</resetMask>
                    <fields>
                        <field>
                            <name>DARA</name>
                            <description>Destination Address Extended Repeat Area</description>
                            <lsb>0</lsb>
                            <msb>4</msb>
                            <access>read-write</access>
                        </field>
                        <field>
                            <name>DADR</name>
                            <description>Destination Address Update Select After Reload</description>
                            <lsb>5</lsb>
                            <msb>5</msb>
                            <access>read-write</access>
                            <enumeratedValues>
                                </enumeratedValues>
                        </field>
                        <field>
                            <name>DM</name>
                            <description>Destination Address Update Mode</description>
                            <lsb>6</lsb>
                            <msb>7</msb>
                            <access>read-write</access>
                            <enumeratedValues>
                                </enumeratedValues>
                        </field>
                        <field>
                            <name>SARA</name>
                            <description>Source Address Extended Repeat Area</description>
                            <lsb>8</lsb>
                            <msb>12</msb>
                            <access>read-write</access>
                        </field>
                        <field>
                            <name>SADR</name>
                            <description>Source Address Update Select After Reload</description>
                            <lsb>13</lsb>
                            <msb>13</msb>
                            <access>read-write</access>
                            <enumeratedValues>
                                </enumeratedValues>
                        </field>
                        <field>
                            <name>SM</name>
                            <description>Source Address Update Mode</description>
                            <lsb>14</lsb>
                            <msb>15</msb>
                            <access>read-write</access>
                            <enumeratedValues>
                                </enumeratedValues>
                        </field>
                    </fields>
                </register>
                <register>
                    <name>DMOFR</name>
                    <description>DMA Offset Register</description>
                    <addressOffset>0x18</addressOffset>
                    <size>32</size>
                    <access>read-write</access>
                    <resetValue>0x00000000</resetValue>
                    <resetMask>0xffffffff</resetMask>
                </register>
                <register>
                    <name>DMCNT</name>
                    <description>DMA Transfer Enable Register</description>
                    <addressOffset>0x1C</addressOffset>
                    <size>8</size>
                    <access>read-write</access>
                    <resetValue>0x00</resetValue>
                    <resetMask>0xff</resetMask>
                    <fields>
                        <field>
                            <name>DTE</name>
                            <description>DMA Transfer Enable</description>
                            <lsb>0</lsb>
                            <msb>0</msb>
                            <access>read-write</access>
                            <enumeratedValues>
                                </enumeratedValues>
                        </field>
                    </fields>
                </register>
                <register>
                    <name>DMREQ</name>
                    <description>DMA Software Start Register</description>
                    <addressOffset>0x1D</addressOffset>
                    <size>8</size>
                    <access>read-write</access>
                    <resetValue>0x00</resetValue>
                    <resetMask>0xff</resetMask>
                    <fields>
                        <field>
                            <name>SWREQ</name>
                            <description>DMA Software Start</description>
                            <lsb>0</lsb>
                            <msb>0</msb>
                            <access>read-write</access>
                            <enumeratedValues>
                                </enumeratedValues>
                        </field>
                        <field>
                            <name>CLRS</name>
                            <description>DMA Software Start Bit Auto Clear Select</description>
                            <lsb>4</lsb>
                            <msb>4</msb>
                            <access>read-write</access>
                            <enumeratedValues>
                                </enumeratedValues>
                        </field>
                    </fields>
                </register>
                <register>
                    <name>DMSTS</name>
                    <description>DMA Status Register</description>
                    <addressOffset>0x1E</addressOffset>
                    <size>8</size>
                    <access>read-write</access>
                    <resetValue>0x00</resetValue>
                    <resetMask>0xff</resetMask>
                    <fields>
                        <field>
                            <name>ESIF</name>
                            <description>Transfer Escape End Interrupt Flag</description>
                            <lsb>0</lsb>
                            <msb>0</msb>
                            <access>read-write</access>
                            <enumeratedValues>
                                </enumeratedValues>
                        </field>
                        <field>
                            <name>DTIF</name>
                            <description>Transfer End Interrupt Flag</description>
                            <lsb>4</lsb>
                            <msb>4</msb>
                            <access>read-write</access>
                            <enumeratedValues>
                                </enumeratedValues>
                        </field>
                        <field>
                            <name>ACT</name>
                            <description>DMAC Active Flag</description>
                            <lsb>7</lsb>
                            <msb>7</msb>
                            <access>read-only</access>
                            <enumeratedValues>
                                </enumeratedValues>
                        </field>
                    </fields>
                </register>
                <register>
                    <name>DMSRR</name>
                    <description>DMA Source Reload Address Register</description>
                    <addressOffset>0x20</addressOffset>
                    <size>32</size>
                    <access>read-write</access>
                    <resetValue>0x00000000</resetValue>
                    <resetMask>0xffffffff</resetMask>
                </register>
                <register>
                    <name>DMDRR</name>
                    <description>DMA Destination Reload Address Register</description>
                    <addressOffset>0x24</addressOffset>
                    <size>32</size>
                    <access>read-write</access>
                    <resetValue>0x00000000</resetValue>
                    <resetMask>0xffffffff</resetMask>
                </register>
                <register>
                    <name>DMSBS</name>
                    <description>DMA Source Buffer Size Register</description>
                    <addressOffset>0x28</addressOffset>
                    <size>32</size>
                    <access>read-write</access>
                    <resetValue>0x00000000</resetValue>
                    <resetMask>0xffffffff</resetMask>
                    <fields>
                        <field>
                            <name>DMSBSL</name>
                            <description>Functions as data transfer counter in repeat,block transfer mode</description>
                            <lsb>0</lsb>
                            <msb>15</msb>
                            <access>read-write</access>
                        </field>
                        <field>
                            <name>DMSBSH</name>
                            <description>Specifies the repeat,area size in repeat,block transfer mode</description>
                            <lsb>16</lsb>
                            <msb>31</msb>
                            <access>read-write</access>
                        </field>
                    </fields>
                </register>
                <register>
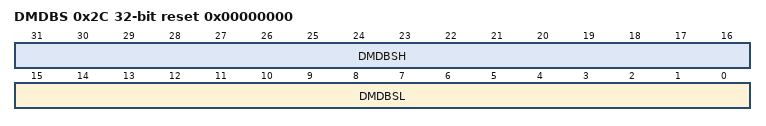
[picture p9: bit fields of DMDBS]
                    <name>DMDBS</name>
                    <description>DMA Destination Buffer Size Register</description>
                    <addressOffset>0x2C</addressOffset>
                    <size>32</size>
                    <access>read-write</access>
                    <resetValue>0x00000000</resetValue>
                    <resetMask>0xffffffff</resetMask>
                    <fields>
                        <field>
                            <name>DMDBSL</name>
                            <description>Functions as data transfer counter in repeat,block transfer mode.</description>
                            <lsb>0</lsb>
                            <msb>15</msb>
                            <access>read-write</access>
                        </field>
                        <field>
                            <name>DMDBSH</name>
                            <description>Specifies the repeat,area size in repeat,block transfer mode.</description>
                            <lsb>16</lsb>
                            <msb>31</msb>
                            <access>read-write</access>
                        </field>
                    </fields>
                </register>
                <register>
                    <name>DMBWR</name>
                    <description>DMA Bufferable Write Enable Register</description>
                    <addressOffset>0x30</addressOffset>
                    <size>8</size>
                    <access>read-write</access>
                    <resetValue>0x00</resetValue>
                    <resetMask>0xff</resetMask>
                    <fields>
                        <field>
                            <name>BWE</name>
                            <description>Bufferable Write Enable</description>
                            <lsb>0</lsb>
                            <msb>0</msb>
                            <access>read-write</access>
                            <enumeratedValues>
                                </enumeratedValues>
                        </field>
                    </fields>
                </register>
            </registers>
        </peripheral>
        <peripheral derivedFrom="DMAC0">
            <name>DMAC1</name>
            <description>Direct memory access controller 1</description>
            <baseAddress>0x40005040</baseAddress>
        </peripheral>
        <peripheral derivedFrom="DMAC0">
            <name>DMAC2</name>
            <description>Direct memory access controller 2</description>
            <baseAddress>0x40005080</baseAddress>
        </peripheral>
        <peripheral derivedFrom="DMAC0">
            <name>DMAC3</name>
            <description>Direct memory access controller 3</description>
            <baseAddress>0x400050C0</baseAddress>
        </peripheral>
        <peripheral derivedFrom="DMAC0">
            <name>DMAC4</name>
            <description>Direct memory access controller 4</description>
            <baseAddress>0x40005100</baseAddress>
        </peripheral>
        <peripheral derivedFrom="DMAC0">
            <name>DMAC5</name>
            <description>Direct memory access controller 5</description>
            <baseAddress>0x40005140</baseAddress>
        </peripheral>
        <peripheral derivedFrom="DMAC0">
            <name>DMAC6</name>
            <description>Direct memory access controller 6</description>
            <baseAddress>0x40005180</baseAddress>
        </peripheral>
        <peripheral derivedFrom="DMAC0">
            <name>DMAC7</name>
            <description>Direct memory access controller 7</description>
            <baseAddress>0x400051C0</baseAddress>
        </peripheral>
        <peripheral>
            <name>DMA</name>
            <description>DMAC Module Activation</description>
            <baseAddress>0x40005200</baseAddress>
            <addressBlock>
                <offset>0x00</offset>
                <size>1</size>
                <usage>registers</usage>
            </addressBlock>
            <addressBlock>
                <offset>0x40</offset>
                <size>4</size>
                <usage>registers</usage>
            </addressBlock>
            <registers>
                <register>
                    <name>DMAST</name>
                    <description>DMA Module Activation Register</description>
                    <addressOffset>0x00</addressOffset>
                    <size>8</size>
                    <access>read-write</access>
                    <resetValue>0x00</resetValue>
                    <resetMask>0xff</resetMask>
                    <fields>
                        <field>
                            <name>DMST</name>
                            <description>DMAC Operation Enable</description>
                            <lsb>0</lsb>
                            <msb>0</msb>
                            <access>read-write</access>
                            <enumeratedValues>
                                </enumeratedValues>
                        </field>
                    </fields>
                </register>
                <register>
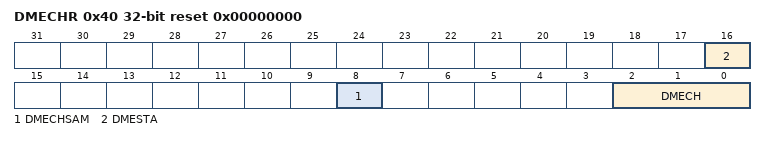
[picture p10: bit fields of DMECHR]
                    <name>DMECHR</name>
                    <description>DMAC Error Channel Register</description>
                    <addressOffset>0x40</addressOffset>
                    <size>32</size>
                    <access>read-write</access>
                    <resetValue>0x00000000</resetValue>
                    <resetMask>0xffffffff</resetMask>
                    <fields>
                        <field>
                            <name>DMECH</name>
                            <description>DMAC Error channel</description>
                            <lsb>0</lsb>
                            <msb>2</msb>
                            <access>read-only</access>
                        </field>
                        <field>
                            <name>DMECHSAM</name>
                            <description>DMAC Error channel Security Attribution Monitor</description>
                            <lsb>8</lsb>
                            <msb>8</msb>
                            <access>read-only</access>
                            <enumeratedValues>
                                </enumeratedValues>
                        </field>
                        <field>
                            <name>DMESTA</name>
                            <description>DMAC Error Status</description>
                            <lsb>16</lsb>
                            <msb>16</msb>
                            <access>read-write</access>
                            <enumeratedValues>
                                </enumeratedValues>
                        </field>
                    </fields>
                </register>
            </registers>
        </peripheral>
        <peripheral>
            <name>DTC</name>
            <description>Data Transfer Controller</description>
            <baseAddress>0x40005400</baseAddress>
            <addressBlock>
                <offset>0x00</offset>
                <size>1</size>
                <usage>registers</usage>
            </addressBlock>
            <addressBlock>
                <offset>0x04</offset>
                <size>4</size>
                <usage>registers</usage>
            </addressBlock>
            <addressBlock>
                <offset>0x0C</offset>
                <size>1</size>
                <usage>registers</usage>
            </addressBlock>
            <addressBlock>
                <offset>0x0E</offset>
                <size>3</size>
                <usage>registers</usage>
            </addressBlock>
            <addressBlock>
                <offset>0x14</offset>
                <size>4</size>
                <usage>registers</usage>
            </addressBlock>
            <addressBlock>
                <offset>0x20</offset>
                <size>4</size>
                <usage>registers</usage>
            </addressBlock>
            <registers>
                <register>
                    <name>DTCCR</name>
                    <description>DTC Control Register</description>
                    <addressOffset>0x00</addressOffset>
                    <size>8</size>
                    <access>read-write</access>
                    <resetValue>0x08</resetValue>
                    <resetMask>0xff</resetMask>
                    <fields>
                        <field>
                            <name>RRS</name>
                            <description>DTC Transfer Information Read Skip Enable</description>
                            <lsb>4</lsb>
                            <msb>4</msb>
                            <access>read-write</access>
                            <enumeratedValues>
                                </enumeratedValues>
                        </field>
                    </fields>
                </register>
                <register>
                    <name>DTCVBR</name>
                    <description>DTC Vector Base Register</description>
                    <addressOffset>0x04</addressOffset>
                    <size>32</size>
                    <access>read-write</access>
                    <resetValue>0x00000000</resetValue>
                    <resetMask>0xffffffff</resetMask>
                </register>
                <register>
                    <name>DTCST</name>
                    <description>DTC Module Start Register</description>
                    <addressOffset>0x0C</addressOffset>
                    <size>8</size>
                    <access>read-write</access>
                    <resetValue>0x00</resetValue>
                    <resetMask>0xff</resetMask>
                    <fields>
                        <field>
                            <name>DTCST</name>
                            <description>DTC Module Start</description>
                            <lsb>0</lsb>
                            <msb>0</msb>
                            <access>read-write</access>
                            <enumeratedValues>
                                </enumeratedValues>
                        </field>
                    </fields>
                </register>
                <register>
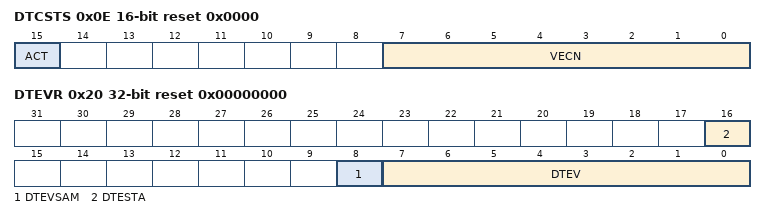
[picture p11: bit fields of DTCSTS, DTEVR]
                    <name>DTCSTS</name>
                    <description>DTC Status Register</description>
                    <addressOffset>0x0E</addressOffset>
                    <size>16</size>
                    <access>read-only</access>
                    <resetValue>0x0000</resetValue>
                    <resetMask>0xffff</resetMask>
                    <fields>
                        <field>
                            <name>VECN</name>
                            <description>DTC,Activating Vector Number Monitoring</description>
                            <lsb>0</lsb>
                            <msb>7</msb>
                            <access>read-only</access>
                        </field>
                        <field>
                            <name>ACT</name>
                            <description>DTC Active Flag</description>
                            <lsb>15</lsb>
                            <msb>15</msb>
                            <access>read-only</access>
                            <enumeratedValues>
                                </enumeratedValues>
                        </field>
                    </fields>
                </register>
                <register>
                    <name>DTCCR_SEC</name>
                    <description>DTC Control Register for secure Region</description>
                    <addressOffset>0x10</addressOffset>
                    <size>8</size>
                    <access>read-write</access>
                    <resetValue>0x08</resetValue>
                    <resetMask>0xff</resetMask>
                    <fields>
                        <field>
                            <name>RRS</name>
                            <description>DTC Transfer Information Read Skip Enable for Secure</description>
                            <lsb>4</lsb>
                            <msb>4</msb>
                            <access>read-write</access>
                            <enumeratedValues>
                                </enumeratedValues>
                        </field>
                    </fields>
                </register>
                <register>
                    <name>DTCVBR_SEC</name>
                    <description>DTC Vector Base Register for secure Region</description>
                    <addressOffset>0x14</addressOffset>
                    <size>32</size>
                    <access>read-write</access>
                    <resetValue>0x00000000</resetValue>
                    <resetMask>0xffffffff</resetMask>
                </register>
                <register>
                    <name>DTEVR</name>
                    <description>DTC Error Vector Register</description>
                    <addressOffset>0x20</addressOffset>
                    <size>32</size>
                    <access>read-write</access>
                    <resetValue>0x00000000</resetValue>
                    <resetMask>0xffffffff</resetMask>
                    <fields>
                        <field>
                            <name>DTEV</name>
                            <description>DTC Error Vector Number</description>
                            <lsb>0</lsb>
                            <msb>7</msb>
                            <access>read-only</access>
                        </field>
                        <field>
                            <name>DTEVSAM</name>
                            <description>DTC Error Vector Number SA Monitor</description>
                            <lsb>8</lsb>
                            <msb>8</msb>
                            <access>read-only</access>
                            <enumeratedValues>
                                </enumeratedValues>
                        </field>
                        <field>
                            <name>DTESTA</name>
                            <description>DTC Error Status Flag</description>
                            <lsb>16</lsb>
                            <msb>16</msb>
                            <access>read-write</access>
                            <enumeratedValues>
                                </enumeratedValues>
                        </field>
                    </fields>
                </register>
            </registers>
        </peripheral>
        <peripheral>
            <name>ICU</name>
            <description>Interrupt Controller</description>
            <baseAddress>0x40006000</baseAddress>
            <addressBlock>
                <offset>0x00</offset>
                <size>16</size>
                <usage>registers</usage>
            </addressBlock>
            <addressBlock>
                <offset>0x100</offset>
                <size>1</size>
                <usage>registers</usage>
            </addressBlock>
            <addressBlock>
                <offset>0x120</offset>
                <size>2</size>
                <usage>registers</usage>
            </addressBlock>
            <addressBlock>
                <offset>0x130</offset>
                <size>2</size>
                <usage>registers</usage>
            </addressBlock>
            <addressBlock>
                <offset>0x140</offset>
                <size>2</size>
                <usage>registers</usage>
            </addressBlock>
            <addressBlock>
                <offset>0x1A0</offset>
                <size>8</size>
                <usage>registers</usage>
            </addressBlock>
            <addressBlock>
                <offset>0x200</offset>
                <size>2</size>
                <usage>registers</usage>
            </addressBlock>
            <addressBlock>
                <offset>0x280</offset>
                <size>32</size>
                <usage>registers</usage>
            </addressBlock>
            <addressBlock>
                <offset>0x300</offset>
                <size>384</size>
                <usage>registers</usage>
            </addressBlock>
            <interrupt>
                <name>IEL0</name>
                <description>ICU Interrupt 0</description>
                <value>0</value>
            </interrupt>
            <interrupt>
                <name>IEL1</name>
                <description>ICU Interrupt 1</description>
                <value>1</value>
            </interrupt>
            <interrupt>
                <name>IEL2</name>
                <description>ICU Interrupt 2</description>
                <value>2</value>
            </interrupt>
            <interrupt>
                <name>IEL3</name>
                <description>ICU Interrupt 3</description>
                <value>3</value>
            </interrupt>
            <interrupt>
                <name>IEL4</name>
                <description>ICU Interrupt 4</description>
                <value>4</value>
            </interrupt>
            <interrupt>
                <name>IEL5</name>
                <description>ICU Interrupt 5</description>
                <value>5</value>
            </interrupt>
            <interrupt>
                <name>IEL6</name>
                <description>ICU Interrupt 6</description>
                <value>6</value>
            </interrupt>
            <interrupt>
                <name>IEL7</name>
                <description>ICU Interrupt 7</description>
                <value>7</value>
            </interrupt>
            <interrupt>
                <name>IEL8</name>
                <description>ICU Interrupt 8</description>
                <value>8</value>
            </interrupt>
            <interrupt>
                <name>IEL9</name>
                <description>ICU Interrupt 9</description>
                <value>9</value>
            </interrupt>
            <interrupt>
                <name>IEL10</name>
                <description>ICU Interrupt 10</description>
                <value>10</value>
            </interrupt>
            <interrupt>
                <name>IEL11</name>
                <description>ICU Interrupt 11</description>
                <value>11</value>
            </interrupt>
            <interrupt>
                <name>IEL12</name>
                <description>ICU Interrupt 12</description>
                <value>12</value>
            </interrupt>
            <interrupt>
                <name>IEL13</name>
                <description>ICU Interrupt 13</description>
                <value>13</value>
            </interrupt>
            <interrupt>
                <name>IEL14</name>
                <description>ICU Interrupt 14</description>
                <value>14</value>
            </interrupt>
            <interrupt>
                <name>IEL15</name>
                <description>ICU Interrupt 15</description>
                <value>15</value>
            </interrupt>
            <interrupt>
                <name>IEL16</name>
                <description>ICU Interrupt 16</description>
                <value>16</value>
            </interrupt>
            <interrupt>
                <name>IEL17</name>
                <description>ICU Interrupt 17</description>
                <value>17</value>
            </interrupt>
            <interrupt>
                <name>IEL18</name>
                <description>ICU Interrupt 18</description>
                <value>18</value>
            </interrupt>
            <interrupt>
                <name>IEL19</name>
                <description>ICU Interrupt 19</description>
                <value>19</value>
            </interrupt>
            <interrupt>
                <name>IEL20</name>
                <description>ICU Interrupt 20</description>
                <value>20</value>
            </interrupt>
            <interrupt>
                <name>IEL21</name>
                <description>ICU Interrupt 21</description>
                <value>21</value>
            </interrupt>
            <interrupt>
                <name>IEL22</name>
                <description>ICU Interrupt 22</description>
                <value>22</value>
            </interrupt>
            <interrupt>
                <name>IEL23</name>
                <description>ICU Interrupt 23</description>
                <value>23</value>
            </interrupt>
            <interrupt>
                <name>IEL24</name>
                <description>ICU Interrupt 24</description>
                <value>24</value>
            </interrupt>
            <interrupt>
                <name>IEL25</name>
                <description>ICU Interrupt 25</description>
                <value>25</value>
            </interrupt>
            <interrupt>
                <name>IEL26</name>
                <description>ICU Interrupt 26</description>
                <value>26</value>
            </interrupt>
            <interrupt>
                <name>IEL27</name>
                <description>ICU Interrupt 27</description>
                <value>27</value>
            </interrupt>
            <interrupt>
                <name>IEL28</name>
                <description>ICU Interrupt 28</description>
                <value>28</value>
            </interrupt>
            <interrupt>
                <name>IEL29</name>
                <description>ICU Interrupt 29</description>
                <value>29</value>
            </interrupt>
            <interrupt>
                <name>IEL30</name>
                <description>ICU Interrupt 30</description>
                <value>30</value>
            </interrupt>
            <interrupt>
                <name>IEL31</name>
                <description>ICU Interrupt 31</description>
                <value>31</value>
            </interrupt>
            <interrupt>
                <name>IEL32</name>
                <description>ICU Interrupt 32</description>
                <value>32</value>
            </interrupt>
            <interrupt>
                <name>IEL33</name>
                <description>ICU Interrupt 33</description>
                <value>33</value>
            </interrupt>
            <interrupt>
                <name>IEL34</name>
                <description>ICU Interrupt 34</description>
                <value>34</value>
            </interrupt>
            <interrupt>
                <name>IEL35</name>
                <description>ICU Interrupt 35</description>
                <value>35</value>
            </interrupt>
            <interrupt>
                <name>IEL36</name>
                <description>ICU Interrupt 36</description>
                <value>36</value>
            </interrupt>
            <interrupt>
                <name>IEL37</name>
                <description>ICU Interrupt 37</description>
                <value>37</value>
            </interrupt>
            <interrupt>
                <name>IEL38</name>
                <description>ICU Interrupt 38</description>
                <value>38</value>
            </interrupt>
            <interrupt>
                <name>IEL39</name>
                <description>ICU Interrupt 39</description>
                <value>39</value>
            </interrupt>
            <interrupt>
                <name>IEL40</name>
                <description>ICU Interrupt 40</description>
                <value>40</value>
            </interrupt>
            <interrupt>
                <name>IEL41</name>
                <description>ICU Interrupt 41</description>
                <value>41</value>
            </interrupt>
            <interrupt>
                <name>IEL42</name>
                <description>ICU Interrupt 42</description>
                <value>42</value>
            </interrupt>
            <interrupt>
                <name>IEL43</name>
                <description>ICU Interrupt 43</description>
                <value>43</value>
            </interrupt>
            <interrupt>
                <name>IEL44</name>
                <description>ICU Interrupt 44</description>
                <value>44</value>
            </interrupt>
            <interrupt>
                <name>IEL45</name>
                <description>ICU Interrupt 45</description>
                <value>45</value>
            </interrupt>
            <interrupt>
                <name>IEL46</name>
                <description>ICU Interrupt 46</description>
                <value>46</value>
            </interrupt>
            <interrupt>
                <name>IEL47</name>
                <description>ICU Interrupt 47</description>
                <value>47</value>
            </interrupt>
            <interrupt>
                <name>IEL48</name>
                <description>ICU Interrupt 48</description>
                <value>48</value>
            </interrupt>
            <interrupt>
                <name>IEL49</name>
                <description>ICU Interrupt 49</description>
                <value>49</value>
            </interrupt>
            <interrupt>
                <name>IEL50</name>
                <description>ICU Interrupt 50</description>
                <value>50</value>
            </interrupt>
            <interrupt>
                <name>IEL51</name>
                <description>ICU Interrupt 51</description>
                <value>51</value>
            </interrupt>
            <interrupt>
                <name>IEL52</name>
                <description>ICU Interrupt 52</description>
                <value>52</value>
            </interrupt>
            <interrupt>
                <name>IEL53</name>
                <description>ICU Interrupt 53</description>
                <value>53</value>
            </interrupt>
            <interrupt>
                <name>IEL54</name>
                <description>ICU Interrupt 54</description>
                <value>54</value>
            </interrupt>
            <interrupt>
                <name>IEL55</name>
                <description>ICU Interrupt 55</description>
                <value>55</value>
            </interrupt>
            <interrupt>
                <name>IEL56</name>
                <description>ICU Interrupt 56</description>
                <value>56</value>
            </interrupt>
            <interrupt>
                <name>IEL57</name>
                <description>ICU Interrupt 57</description>
                <value>57</value>
            </interrupt>
            <interrupt>
                <name>IEL58</name>
                <description>ICU Interrupt 58</description>
                <value>58</value>
            </interrupt>
            <interrupt>
                <name>IEL59</name>
                <description>ICU Interrupt 59</description>
                <value>59</value>
            </interrupt>
            <interrupt>
                <name>IEL60</name>
                <description>ICU Interrupt 60</description>
                <value>60</value>
            </interrupt>
            <interrupt>
                <name>IEL61</name>
                <description>ICU Interrupt 61</description>
                <value>61</value>
            </interrupt>
            <interrupt>
                <name>IEL62</name>
                <description>ICU Interrupt 62</description>
                <value>62</value>
            </interrupt>
            <interrupt>
                <name>IEL63</name>
                <description>ICU Interrupt 63</description>
                <value>63</value>
            </interrupt>
            <interrupt>
                <name>IEL64</name>
                <description>ICU Interrupt 64</description>
                <value>64</value>
            </interrupt>
            <interrupt>
                <name>IEL65</name>
                <description>ICU Interrupt 65</description>
                <value>65</value>
            </interrupt>
            <interrupt>
                <name>IEL66</name>
                <description>ICU Interrupt 66</description>
                <value>66</value>
            </interrupt>
            <interrupt>
                <name>IEL67</name>
                <description>ICU Interrupt 67</description>
                <value>67</value>
            </interrupt>
            <interrupt>
                <name>IEL68</name>
                <description>ICU Interrupt 68</description>
                <value>68</value>
            </interrupt>
            <interrupt>
                <name>IEL69</name>
                <description>ICU Interrupt 69</description>
                <value>69</value>
            </interrupt>
            <interrupt>
                <name>IEL70</name>
                <description>ICU Interrupt 70</description>
                <value>70</value>
            </interrupt>
            <interrupt>
                <name>IEL71</name>
                <description>ICU Interrupt 71</description>
                <value>71</value>
            </interrupt>
            <interrupt>
                <name>IEL72</name>
                <description>ICU Interrupt 72</description>
                <value>72</value>
            </interrupt>
            <interrupt>
                <name>IEL73</name>
                <description>ICU Interrupt 73</description>
                <value>73</value>
            </interrupt>
            <interrupt>
                <name>IEL74</name>
                <description>ICU Interrupt 74</description>
                <value>74</value>
            </interrupt>
            <interrupt>
                <name>IEL75</name>
                <description>ICU Interrupt 75</description>
                <value>75</value>
            </interrupt>
            <interrupt>
                <name>IEL76</name>
                <description>ICU Interrupt 76</description>
                <value>76</value>
            </interrupt>
            <interrupt>
                <name>IEL77</name>
                <description>ICU Interrupt 77</description>
                <value>77</value>
            </interrupt>
            <interrupt>
                <name>IEL78</name>
                <description>ICU Interrupt 78</description>
                <value>78</value>
            </interrupt>
            <interrupt>
                <name>IEL79</name>
                <description>ICU Interrupt 79</description>
                <value>79</value>
            </interrupt>
            <interrupt>
                <name>IEL80</name>
                <description>ICU Interrupt 80</description>
                <value>80</value>
            </interrupt>
            <interrupt>
                <name>IEL81</name>
                <description>ICU Interrupt 81</description>
                <value>81</value>
            </interrupt>
            <interrupt>
                <name>IEL82</name>
                <description>ICU Interrupt 82</description>
                <value>82</value>
            </interrupt>
            <interrupt>
                <name>IEL83</name>
                <description>ICU Interrupt 83</description>
                <value>83</value>
            </interrupt>
            <interrupt>
                <name>IEL84</name>
                <description>ICU Interrupt 84</description>
                <value>84</value>
            </interrupt>
            <interrupt>
                <name>IEL85</name>
                <description>ICU Interrupt 85</description>
                <value>85</value>
            </interrupt>
            <interrupt>
                <name>IEL86</name>
                <description>ICU Interrupt 86</description>
                <value>86</value>
            </interrupt>
            <interrupt>
                <name>IEL87</name>
                <description>ICU Interrupt 87</description>
                <value>87</value>
            </interrupt>
            <interrupt>
                <name>IEL88</name>
                <description>ICU Interrupt 88</description>
                <value>88</value>
            </interrupt>
            <interrupt>
                <name>IEL89</name>
                <description>ICU Interrupt 89</description>
                <value>89</value>
            </interrupt>
            <interrupt>
                <name>IEL90</name>
                <description>ICU Interrupt 90</description>
                <value>90</value>
            </interrupt>
            <interrupt>
                <name>IEL91</name>
                <description>ICU Interrupt 91</description>
                <value>91</value>
            </interrupt>
            <interrupt>
                <name>IEL92</name>
                <description>ICU Interrupt 92</description>
                <value>92</value>
            </interrupt>
            <interrupt>
                <name>IEL93</name>
                <description>ICU Interrupt 93</description>
                <value>93</value>
            </interrupt>
            <interrupt>
                <name>IEL94</name>
                <description>ICU Interrupt 94</description>
                <value>94</value>
            </interrupt>
            <interrupt>
                <name>IEL95</name>
                <description>ICU Interrupt 95</description>
                <value>95</value>
            </interrupt>
            <registers>
                <register>
                    <dim>16</dim>
                    <dimIncrement>0x1</dimIncrement>
                    <dimIndex>0-15</dimIndex>
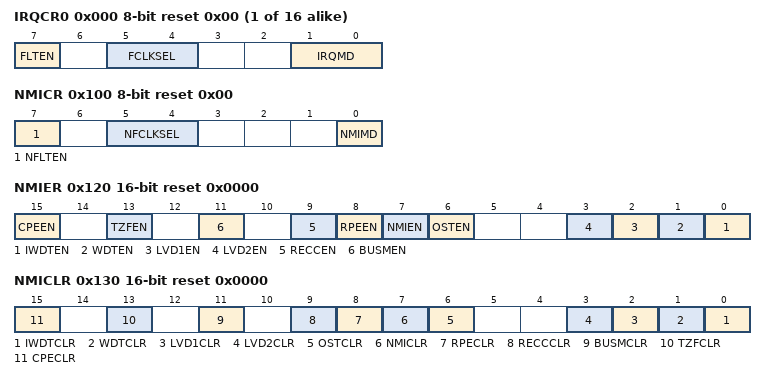
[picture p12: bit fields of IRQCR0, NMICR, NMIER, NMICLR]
                    <name>IRQCR%s</name>
                    <description>IRQ Control Register %s</description>
                    <addressOffset>0x000</addressOffset>
                    <size>8</size>
                    <access>read-write</access>
                    <resetValue>0x00</resetValue>
                    <resetMask>0xff</resetMask>
                    <fields>
                        <field>
                            <name>IRQMD</name>
                            <description>IRQi Detection Sense Select</description>
                            <lsb>0</lsb>
                            <msb>1</msb>
                            <access>read-write</access>
                            <enumeratedValues>
                                </enumeratedValues>
                        </field>
                        <field>
                            <name>FCLKSEL</name>
                            <description>IRQi Digital Filter Sampling Clock Select</description>
                            <lsb>4</lsb>
                            <msb>5</msb>
                            <access>read-write</access>
                            <enumeratedValues>
                                </enumeratedValues>
                        </field>
                        <field>
                            <name>FLTEN</name>
                            <description>IRQi Digital Filter Enable</description>
                            <lsb>7</lsb>
                            <msb>7</msb>
                            <access>read-write</access>
                            <enumeratedValues>
                                </enumeratedValues>
                        </field>
                    </fields>
                </register>
                <register>
                    <name>NMICR</name>
                    <description>NMI Pin Interrupt Control Register</description>
                    <addressOffset>0x100</addressOffset>
                    <size>8</size>
                    <access>read-write</access>
                    <resetValue>0x00</resetValue>
                    <resetMask>0xff</resetMask>
                    <fields>
                        <field>
                            <name>NMIMD</name>
                            <description>NMI Detection Set</description>
                            <lsb>0</lsb>
                            <msb>0</msb>
                            <access>read-write</access>
                            <enumeratedValues>
                                </enumeratedValues>
                        </field>
                        <field>
                            <name>NFCLKSEL</name>
                            <description>NMI Digital Filter Sampling Clock Select</description>
                            <lsb>4</lsb>
                            <msb>5</msb>
                            <access>read-write</access>
                            <enumeratedValues>
                                </enumeratedValues>
                        </field>
                        <field>
                            <name>NFLTEN</name>
                            <description>NMI Digital Filter Enable</description>
                            <lsb>7</lsb>
                            <msb>7</msb>
                            <access>read-write</access>
                            <enumeratedValues>
                                </enumeratedValues>
                        </field>
                    </fields>
                </register>
                <register>
                    <name>NMIER</name>
                    <description>Non,Maskable Interrupt Enable Register</description>
                    <addressOffset>0x120</addressOffset>
                    <size>16</size>
                    <access>read-write</access>
                    <resetValue>0x0000</resetValue>
                    <resetMask>0xffff</resetMask>
                    <fields>
                        <field>
                            <name>IWDTEN</name>
                            <description>IWDT Underflow/Refresh Error Interrupt Enable</description>
                            <lsb>0</lsb>
                            <msb>0</msb>
                            <access>read-write</access>
                            <enumeratedValues>
                                </enumeratedValues>
                        </field>
                        <field>
                            <name>WDTEN</name>
                            <description>WDT Underflow/Refresh Error Interrupt Enable</description>
                            <lsb>1</lsb>
                            <msb>1</msb>
                            <access>read-write</access>
                            <enumeratedValues>
                                </enumeratedValues>
                        </field>
                        <field>
                            <name>LVD1EN</name>
                            <description>Voltage monitor 1 Interrupt Enable</description>
                            <lsb>2</lsb>
                            <msb>2</msb>
                            <access>read-write</access>
                            <enumeratedValues>
                                </enumeratedValues>
                        </field>
                        <field>
                            <name>LVD2EN</name>
                            <description>Voltage monitor 2 Interrupt Enable</description>
                            <lsb>3</lsb>
                            <msb>3</msb>
                            <access>read-write</access>
                            <enumeratedValues>
                                </enumeratedValues>
                        </field>
                        <field>
                            <name>OSTEN</name>
                            <description>Main Clock Oscillation Stop Detection Interrupt Enable</description>
                            <lsb>6</lsb>
                            <msb>6</msb>
                            <access>read-write</access>
                            <enumeratedValues>
                                </enumeratedValues>
                        </field>
                        <field>
                            <name>NMIEN</name>
                            <description>NMI Pin Interrupt Enable</description>
                            <lsb>7</lsb>
                            <msb>7</msb>
                            <access>read-write</access>
                            <enumeratedValues>
                                </enumeratedValues>
                        </field>
                        <field>
                            <name>RPEEN</name>
                            <description>SRAM Parity Error Interrupt Enable</description>
                            <lsb>8</lsb>
                            <msb>8</msb>
                            <access>read-write</access>
                            <enumeratedValues>
                                </enumeratedValues>
                        </field>
                        <field>
                            <name>RECCEN</name>
                            <description>SRAM ECC Error Interrupt Enable</description>
                            <lsb>9</lsb>
                            <msb>9</msb>
                            <access>read-write</access>
                            <enumeratedValues>
                                </enumeratedValues>
                        </field>
                        <field>
                            <name>BUSMEN</name>
                            <description>Bus Master MPU Error Interrupt Enable</description>
                            <lsb>11</lsb>
                            <msb>11</msb>
                            <access>read-write</access>
                            <enumeratedValues>
                                </enumeratedValues>
                        </field>
                        <field>
                            <name>TZFEN</name>
                            <lsb>13</lsb>
                            <msb>13</msb>
                            <access>read-write</access>
                            <enumeratedValues>
                                </enumeratedValues>
                        </field>
                        <field>
                            <name>CPEEN</name>
                            <lsb>15</lsb>
                            <msb>15</msb>
                            <access>read-write</access>
                            <enumeratedValues>
                                </enumeratedValues>
                        </field>
                    </fields>
                </register>
                <register>
                    <name>NMICLR</name>
                    <description>Non,Maskable Interrupt Status Clear Register</description>
                    <addressOffset>0x130</addressOffset>
                    <size>16</size>
                    <access>read-write</access>
                    <resetValue>0x0000</resetValue>
                    <resetMask>0xffff</resetMask>
                    <fields>
                        <field>
                            <name>IWDTCLR</name>
                            <description>IWDT Underflow/Refresh Error Interrupt Status Flag Clear</description>
                            <lsb>0</lsb>
                            <msb>0</msb>
                            <access>read-write</access>
                            <enumeratedValues>
                                </enumeratedValues>
                        </field>
                        <field>
                            <name>WDTCLR</name>
                            <description>WDT Underflow/Refresh Error Interrupt Status Flag Clear</description>
                            <lsb>1</lsb>
                            <msb>1</msb>
                            <access>read-write</access>
                            <enumeratedValues>
                                </enumeratedValues>
                        </field>
                        <field>
                            <name>LVD1CLR</name>
                            <description>Voltage Monitor 1 Interrupt Status Flag Clear</description>
                            <lsb>2</lsb>
                            <msb>2</msb>
                            <access>read-write</access>
                            <enumeratedValues>
                                </enumeratedValues>
                        </field>
                        <field>
                            <name>LVD2CLR</name>
                            <description>Voltage Monitor 2 Interrupt Status Flag Clear</description>
                            <lsb>3</lsb>
                            <msb>3</msb>
                            <access>read-write</access>
                            <enumeratedValues>
                                </enumeratedValues>
                        </field>
                        <field>
                            <name>OSTCLR</name>
                            <description>Oscillation Stop Detection Interrupt Status Flag Clear</description>
                            <lsb>6</lsb>
                            <msb>6</msb>
                            <access>read-write</access>
                            <enumeratedValues>
                                </enumeratedValues>
                        </field>
                        <field>
                            <name>NMICLR</name>
                            <description>NMI Pin Interrupt Status Flag Clear</description>
                            <lsb>7</lsb>
                            <msb>7</msb>
                            <access>read-write</access>
                            <enumeratedValues>
                                </enumeratedValues>
                        </field>
                        <field>
                            <name>RPECLR</name>
                            <description>SRAM Parity Error Interrupt Status Flag Clear</description>
                            <lsb>8</lsb>
                            <msb>8</msb>
                            <access>read-write</access>
                            <enumeratedValues>
                                </enumeratedValues>
                        </field>
                        <field>
                            <name>RECCCLR</name>
                            <description>SRAM ECC Error Interrupt Status Flag Clear</description>
                            <lsb>9</lsb>
                            <msb>9</msb>
                            <access>read-write</access>
                            <enumeratedValues>
                                </enumeratedValues>
                        </field>
                        <field>
                            <name>BUSMCLR</name>
                            <description>Bus Master MPU Error Interrupt Status Flag Clear</description>
                            <lsb>11</lsb>
                            <msb>11</msb>
                            <access>read-write</access>
                            <enumeratedValues>
                                </enumeratedValues>
                        </field>
                        <field>
                            <name>TZFCLR</name>
                            <lsb>13</lsb>
                            <msb>13</msb>
                            <access>read-write</access>
                            <enumeratedValues>
                                </enumeratedValues>
                        </field>
                        <field>
                            <name>CPECLR</name>
                            <lsb>15</lsb>
                            <msb>15</msb>
                            <access>read-write</access>
                            <enumeratedValues>
                                </enumeratedValues>
                        </field>
                    </fields>
                </register>
                <register>
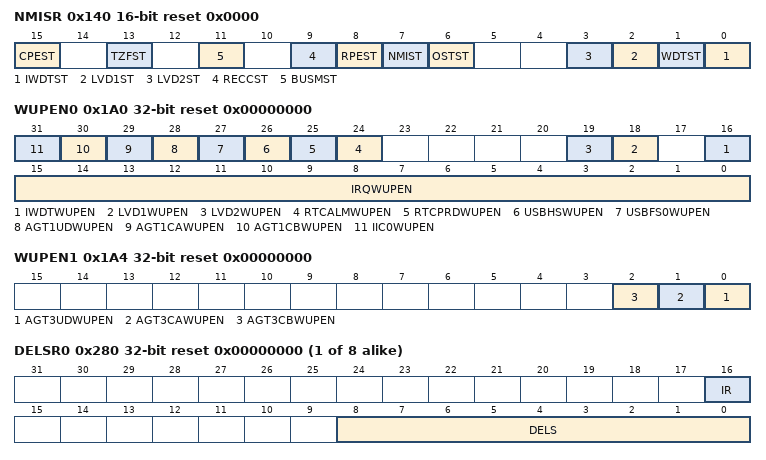
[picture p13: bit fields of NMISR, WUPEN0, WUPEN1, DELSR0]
                    <name>NMISR</name>
                    <description>Non,Maskable Interrupt Status Register</description>
                    <addressOffset>0x140</addressOffset>
                    <size>16</size>
                    <access>read-only</access>
                    <resetValue>0x0000</resetValue>
                    <resetMask>0xffff</resetMask>
                    <fields>
                        <field>
                            <name>IWDTST</name>
                            <description>IWDT Underflow/Refresh Error Interrupt Status Flag</description>
                            <lsb>0</lsb>
                            <msb>0</msb>
                            <access>read-only</access>
                            <enumeratedValues>
                                </enumeratedValues>
                        </field>
                        <field>
                            <name>WDTST</name>
                            <description>WDT Underflow/Refresh Error Interrupt Status Flag</description>
                            <lsb>1</lsb>
                            <msb>1</msb>
                            <access>read-only</access>
                            <enumeratedValues>
                                </enumeratedValues>
                        </field>
                        <field>
                            <name>LVD1ST</name>
                            <description>Voltage Monitor 1 Interrupt Status Flag</description>
                            <lsb>2</lsb>
                            <msb>2</msb>
                            <access>read-only</access>
                            <enumeratedValues>
                                </enumeratedValues>
                        </field>
                        <field>
                            <name>LVD2ST</name>
                            <description>Voltage Monitor 2 Interrupt Status Flag</description>
                            <lsb>3</lsb>
                            <msb>3</msb>
                            <access>read-only</access>
                            <enumeratedValues>
                                </enumeratedValues>
                        </field>
                        <field>
                            <name>OSTST</name>
                            <description>Main Clock Oscillation Stop Detection Interrupt Status Flag</description>
                            <lsb>6</lsb>
                            <msb>6</msb>
                            <access>read-only</access>
                            <enumeratedValues>
                                </enumeratedValues>
                        </field>
                        <field>
                            <name>NMIST</name>
                            <description>NMI Pin Interrupt Status Flag</description>
                            <lsb>7</lsb>
                            <msb>7</msb>
                            <access>read-only</access>
                            <enumeratedValues>
                                </enumeratedValues>
                        </field>
                        <field>
                            <name>RPEST</name>
                            <description>SRAM Parity Error Interrupt Status Flag</description>
                            <lsb>8</lsb>
                            <msb>8</msb>
                            <access>read-only</access>
                            <enumeratedValues>
                                </enumeratedValues>
                        </field>
                        <field>
                            <name>RECCST</name>
                            <description>SRAM ECC Error Interrupt Status Flag</description>
                            <lsb>9</lsb>
                            <msb>9</msb>
                            <access>read-only</access>
                            <enumeratedValues>
                                </enumeratedValues>
                        </field>
                        <field>
                            <name>BUSMST</name>
                            <description>Bus Master MPU Error Interrupt Status Flag</description>
                            <lsb>11</lsb>
                            <msb>11</msb>
                            <access>read-only</access>
                            <enumeratedValues>
                                </enumeratedValues>
                        </field>
                        <field>
                            <name>TZFST</name>
                            <lsb>13</lsb>
                            <msb>13</msb>
                            <access>read-only</access>
                            <enumeratedValues>
                                </enumeratedValues>
                        </field>
                        <field>
                            <name>CPEST</name>
                            <lsb>15</lsb>
                            <msb>15</msb>
                            <access>read-only</access>
                            <enumeratedValues>
                                </enumeratedValues>
                        </field>
                    </fields>
                </register>
                <register>
                    <name>WUPEN0</name>
                    <description>Wake Up Interrupt Enable Register 0</description>
                    <addressOffset>0x1A0</addressOffset>
                    <size>32</size>
                    <access>read-write</access>
                    <resetValue>0x00000000</resetValue>
                    <resetMask>0xffffffff</resetMask>
                    <fields>
                        <field>
                            <name>IRQWUPEN</name>
                            <description>IRQn Interrupt Software Standby/Snooze Mode Returns Enable bit (n = 0 to 15)</description>
                            <lsb>0</lsb>
                            <msb>15</msb>
                            <access>read-write</access>
                            <enumeratedValues>
                                </enumeratedValues>
                        </field>
                        <field>
                            <name>IWDTWUPEN</name>
                            <description>IWDT Interrupt Software Standby/Snooze Mode Returns Enable bit</description>
                            <lsb>16</lsb>
                            <msb>16</msb>
                            <access>read-write</access>
                            <enumeratedValues>
                                </enumeratedValues>
                        </field>
                        <field>
                            <name>LVD1WUPEN</name>
                            <description>LVD1 Interrupt Software Standby/Snooze Mode Returns Enable bit</description>
                            <lsb>18</lsb>
                            <msb>18</msb>
                            <access>read-write</access>
                            <enumeratedValues>
                                </enumeratedValues>
                        </field>
                        <field>
                            <name>LVD2WUPEN</name>
                            <description>LVD2 Interrupt Software Standby/Snooze Mode Returns Enable bit</description>
                            <lsb>19</lsb>
                            <msb>19</msb>
                            <access>read-write</access>
                            <enumeratedValues>
                                </enumeratedValues>
                        </field>
                        <field>
                            <name>RTCALMWUPEN</name>
                            <description>RTC Alarm Interrupt Software Standby/Snooze Mode Returns Enable bit</description>
                            <lsb>24</lsb>
                            <msb>24</msb>
                            <access>read-write</access>
                            <enumeratedValues>
                                </enumeratedValues>
                        </field>
                        <field>
                            <name>RTCPRDWUPEN</name>
                            <description>RTC Period Interrupt Software Standby/Snooze Mode Returns Enable bit</description>
                            <lsb>25</lsb>
                            <msb>25</msb>
                            <access>read-write</access>
                            <enumeratedValues>
                                </enumeratedValues>
                        </field>
                        <field>
                            <name>USBHSWUPEN</name>
                            <description>USBHS Interrupt Software Standby/Snooze Mode Returns Enable bit</description>
                            <lsb>26</lsb>
                            <msb>26</msb>
                            <access>read-write</access>
                            <enumeratedValues>
                                </enumeratedValues>
                        </field>
                        <field>
                            <name>USBFS0WUPEN</name>
                            <description>USBFS0 Interrupt Software Standby/Snooze Mode Returns Enable bit</description>
                            <lsb>27</lsb>
                            <msb>27</msb>
                            <access>read-write</access>
                            <enumeratedValues>
                                </enumeratedValues>
                        </field>
                        <field>
                            <name>AGT1UDWUPEN</name>
                            <description>AGT1 Underflow Interrupt Software Standby/Snooze Mode Returns Enable bit</description>
                            <lsb>28</lsb>
                            <msb>28</msb>
                            <access>read-write</access>
                            <enumeratedValues>
                                </enumeratedValues>
                        </field>
                        <field>
                            <name>AGT1CAWUPEN</name>
                            <description>AGT1 Compare Match A Interrupt Software Standby/Snooze Mode Returns Enable bit</description>
                            <lsb>29</lsb>
                            <msb>29</msb>
                            <access>read-write</access>
                            <enumeratedValues>
                                </enumeratedValues>
                        </field>
                        <field>
                            <name>AGT1CBWUPEN</name>
                            <description>AGT1 Compare Match B Interrupt Software Standby/Snooze Mode Returns Enable bit</description>
                            <lsb>30</lsb>
                            <msb>30</msb>
                            <access>read-write</access>
                            <enumeratedValues>
                                </enumeratedValues>
                        </field>
                        <field>
                            <name>IIC0WUPEN</name>
                            <description>IIC0 Address Match Interrupt Software Standby/Snooze Mode Returns Enable bit</description>
                            <lsb>31</lsb>
                            <msb>31</msb>
                            <access>read-write</access>
                            <enumeratedValues>
                                </enumeratedValues>
                        </field>
                    </fields>
                </register>
                <register>
                    <name>WUPEN1</name>
                    <description>Wake Up interrupt enable register 1</description>
                    <addressOffset>0x1A4</addressOffset>
                    <size>32</size>
                    <access>read-write</access>
                    <resetValue>0x00000000</resetValue>
                    <resetMask>0xffffffff</resetMask>
                    <fields>
                        <field>
                            <name>AGT3UDWUPEN</name>
                            <description>AGT3 Underflow Interrupt Software Standby Return Enable bit</description>
                            <lsb>0</lsb>
                            <msb>0</msb>
                            <access>read-write</access>
                            <enumeratedValues>
                                </enumeratedValues>
                        </field>
                        <field>
                            <name>AGT3CAWUPEN</name>
                            <description>AGT3 Compare Match A Interrupt Software Standby Return Enable bit</description>
                            <lsb>1</lsb>
                            <msb>1</msb>
                            <access>read-write</access>
                            <enumeratedValues>
                                </enumeratedValues>
                        </field>
                        <field>
                            <name>AGT3CBWUPEN</name>
                            <description>AGT3 Compare Match B Interrupt Software Standby Return Enable bit</description>
                            <lsb>2</lsb>
                            <msb>2</msb>
                            <access>read-write</access>
                            <enumeratedValues>
                                </enumeratedValues>
                        </field>
                    </fields>
                </register>
                <register>
                    <name>SELSR0</name>
                    <description>SYS Event Link Setting Register</description>
                    <addressOffset>0x200</addressOffset>
                    <size>16</size>
                    <access>read-write</access>
                    <resetValue>0x0000</resetValue>
                    <resetMask>0xffff</resetMask>
                </register>
                <register>
                    <dim>8</dim>
                    <dimIncrement>0x4</dimIncrement>
                    <dimIndex>0-7</dimIndex>
                    <name>DELSR%s</name>
                    <description>DMAC Event Link Setting Register %s</description>
                    <addressOffset>0x280</addressOffset>
                    <size>32</size>
                    <access>read-write</access>
                    <resetValue>0x00000000</resetValue>
                    <resetMask>0xffffffff</resetMask>
                    <fields>
                        <field>
                            <name>DELS</name>
                            <description>DMAC Event Link Select</description>
                            <lsb>0</lsb>
                            <msb>8</msb>
                            <access>read-write</access>
                            <enumeratedValues>
                                </enumeratedValues>
                        </field>
                        <field>
                            <name>IR</name>
                            <description>DMAC Activation Request Status Flag</description>
                            <lsb>16</lsb>
                            <msb>16</msb>
                            <access>read-write</access>
                            <enumeratedValues>
                                </enumeratedValues>
                        </field>
                    </fields>
                </register>
                <register>
                    <dim>96</dim>
                    <dimIncrement>0x4</dimIncrement>
                    <dimIndex>0-95</dimIndex>
                    <name>IELSR%s</name>
                    <description>ICU Event Link Setting Register %s</description>
                    <addressOffset>0x300</addressOffset>
                    <size>32</size>
                    <access>read-write</access>
                    <resetValue>0x00000000</resetValue>
                    <resetMask>0xffffffff</resetMask>
                </register>
            </registers>
        </peripheral>
        <peripheral>
            <name>CACHE</name>
            <description>CACHE</description>
            <baseAddress>0x40007000</baseAddress>
            <addressBlock>
                <offset>0x00</offset>
                <size>12</size>
                <usage>registers</usage>
            </addressBlock>
            <addressBlock>
                <offset>0x40</offset>
                <size>12</size>
                <usage>registers</usage>
            </addressBlock>
            <addressBlock>
                <offset>0x200</offset>
                <size>8</size>
                <usage>registers</usage>
            </addressBlock>
            <registers>
                <register>
                    <name>CCACTL</name>
                    <description>C,Cache Control Register</description>
                    <addressOffset>0x000</addressOffset>
                    <size>32</size>
                    <access>read-write</access>
                    <resetValue>0x00000000</resetValue>
                    <resetMask>0xffffffff</resetMask>
                    <fields>
                        <field>
                            <name>ENC</name>
                            <description>C,Cache Enable</description>
                            <lsb>0</lsb>
                            <msb>0</msb>
                            <access>read-write</access>
                            <enumeratedValues>
                                </enumeratedValues>
                        </field>
                    </fields>
                </register>
                <register>
                    <name>CCAFCT</name>
                    <description>C,Cache Flush Control Register</description>
                    <addressOffset>0x004</addressOffset>
                    <size>32</size>
                    <access>read-write</access>
                    <resetValue>0x00000000</resetValue>
                    <resetMask>0xffffffff</resetMask>
                    <fields>
                        <field>
                            <name>FC</name>
                            <description>C,Cache Flush</description>
                            <lsb>0</lsb>
                            <msb>0</msb>
                            <access>read-write</access>
                            <enumeratedValues>
                                </enumeratedValues>
                        </field>
                    </fields>
                </register>
                <register>
                    <name>CCALCF</name>
                    <description>C,Cache Line Configuration Register</description>
                    <addressOffset>0x008</addressOffset>
                    <size>32</size>
                    <access>read-write</access>
                    <resetValue>0x00000001</resetValue>
                    <resetMask>0xffffffff</resetMask>
                    <fields>
                        <field>
                            <name>CC</name>
                            <description>C,Cache Line Size</description>
                            <lsb>0</lsb>
                            <msb>1</msb>
                            <access>read-write</access>
                            <enumeratedValues>
                                </enumeratedValues>
                        </field>
                    </fields>
                </register>
                <register>
                    <name>SCACTL</name>
                    <description>S,Cache Control Register</description>
                    <addressOffset>0x040</addressOffset>
                    <size>32</size>
                    <access>read-write</access>
                    <resetValue>0x00000000</resetValue>
                    <resetMask>0xffffffff</resetMask>
                    <fields>
                        <field>
                            <name>ENS</name>
                            <description>S,Cache Enable</description>
                            <lsb>0</lsb>
                            <msb>0</msb>
                            <access>read-write</access>
                            <enumeratedValues>
                                </enumeratedValues>
                        </field>
                    </fields>
                </register>
                <register>
                    <name>SCAFCT</name>
                    <description>S,Cache Flush Control Register</description>
                    <addressOffset>0x044</addressOffset>
                    <size>32</size>
                    <access>read-write</access>
                    <resetValue>0x00000000</resetValue>
                    <resetMask>0xffffffff</resetMask>
                    <fields>
                        <field>
                            <name>FS</name>
                            <description>S,Cache Flush</description>
                            <lsb>0</lsb>
                            <msb>0</msb>
                            <access>read-write</access>
                            <enumeratedValues>
                                </enumeratedValues>
                        </field>
                    </fields>
                </register>
                <register>
                    <name>SCALCF</name>
                    <description>S,Cache Line Configuration Register</description>
                    <addressOffset>0x048</addressOffset>
                    <size>32</size>
                    <access>read-write</access>
                    <resetValue>0x00000001</resetValue>
                    <resetMask>0xffffffff</resetMask>
                    <fields>
                        <field>
                            <name>CS</name>
                            <description>S,Cache Line Size</description>
                            <lsb>0</lsb>
                            <msb>1</msb>
                            <access>read-write</access>
                            <enumeratedValues>
                                </enumeratedValues>
                        </field>
                    </fields>
                </register>
                <register>
                    <name>CAPOAD</name>
                    <description>Cache Parity Error Operation After Detection Register</description>
                    <addressOffset>0x200</addressOffset>
                    <size>32</size>
                    <access>read-write</access>
                    <resetValue>0x00000000</resetValue>
                    <resetMask>0xffffffff</resetMask>
                    <fields>
                        <field>
                            <name>OAD</name>
                            <description>Operation after Detection</description>
                            <lsb>0</lsb>
                            <msb>0</msb>
                            <access>read-write</access>
                            <enumeratedValues>
                                </enumeratedValues>
                        </field>
                    </fields>
                </register>
                <register>
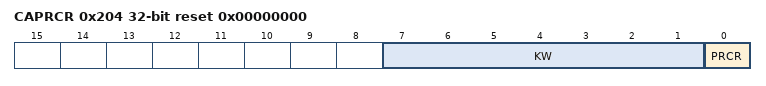
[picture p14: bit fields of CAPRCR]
                    <name>CAPRCR</name>
                    <description>Cache Protection Register</description>
                    <addressOffset>0x204</addressOffset>
                    <size>32</size>
                    <access>read-write</access>
                    <resetValue>0x00000000</resetValue>
                    <resetMask>0xffffffff</resetMask>
                    <fields>
                        <field>
                            <name>PRCR</name>
                            <description>Register Write Control</description>
                            <lsb>0</lsb>
                            <msb>0</msb>
                            <access>read-write</access>
                            <enumeratedValues>
                                </enumeratedValues>
                        </field>
                        <field>
                            <name>KW</name>
                            <description>Write key code</description>
                            <lsb>1</lsb>
                            <msb>7</msb>
                            <access>read-write</access>
                        </field>
                    </fields>
                </register>
            </registers>
        </peripheral>
        <peripheral>
            <name>CPSCU</name>
            <description>CPU System Security Control Unit</description>
            <baseAddress>0x40008000</baseAddress>
            <addressBlock>
                <offset>0x00</offset>
                <size>4</size>
                <usage>registers</usage>
            </addressBlock>
            <addressBlock>
                <offset>0x10</offset>
                <size>8</size>
                <usage>registers</usage>
            </addressBlock>
            <addressBlock>
                <offset>0x30</offset>
                <size>8</size>
                <usage>registers</usage>
            </addressBlock>
            <addressBlock>
                <offset>0x40</offset>
                <size>16</size>
                <usage>registers</usage>
            </addressBlock>
            <addressBlock>
                <offset>0x54</offset>
                <size>4</size>
                <usage>registers</usage>
            </addressBlock>
            <addressBlock>
                <offset>0x70</offset>
                <size>12</size>
                <usage>registers</usage>
            </addressBlock>
            <addressBlock>
                <offset>0x100</offset>
                <size>8</size>
                <usage>registers</usage>
            </addressBlock>
            <addressBlock>
                <offset>0x130</offset>
                <size>8</size>
                <usage>registers</usage>
            </addressBlock>
            <addressBlock>
                <offset>0x180</offset>
                <size>4</size>
                <usage>registers</usage>
            </addressBlock>
            <addressBlock>
                <offset>0x1B0</offset>
                <size>4</size>
                <usage>registers</usage>
            </addressBlock>
            <registers>
                <register>
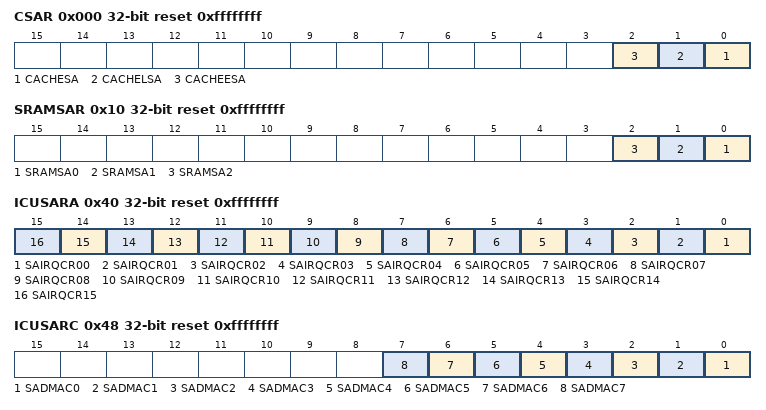
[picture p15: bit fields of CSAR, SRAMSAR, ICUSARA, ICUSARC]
                    <name>CSAR</name>
                    <description>Cache Security Attribution Register</description>
                    <addressOffset>0x000</addressOffset>
                    <size>32</size>
                    <access>read-write</access>
                    <resetValue>0xffffffff</resetValue>
                    <resetMask>0xffffffff</resetMask>
                    <fields>
                        <field>
                            <name>CACHESA</name>
                            <description>Security Attributes of Registers for Cache Control</description>
                            <lsb>0</lsb>
                            <msb>0</msb>
                            <access>read-write</access>
                            <enumeratedValues>
                                </enumeratedValues>
                        </field>
                        <field>
                            <name>CACHELSA</name>
                            <description>Security Attributes of Registers for Cache Line Configuration</description>
                            <lsb>1</lsb>
                            <msb>1</msb>
                            <access>read-write</access>
                            <enumeratedValues>
                                </enumeratedValues>
                        </field>
                        <field>
                            <name>CACHEESA</name>
                            <description>Security Attributes of Registers for Cache Error</description>
                            <lsb>2</lsb>
                            <msb>2</msb>
                            <access>read-write</access>
                            <enumeratedValues>
                                </enumeratedValues>
                        </field>
                    </fields>
                </register>
                <register>
                    <name>SRAMSAR</name>
                    <description>SRAM Security Attribution Register</description>
                    <addressOffset>0x10</addressOffset>
                    <size>32</size>
                    <access>read-write</access>
                    <resetValue>0xffffffff</resetValue>
                    <resetMask>0xffffffff</resetMask>
                    <fields>
                        <field>
                            <name>SRAMSA0</name>
                            <description>Security attributes of registers for SRAM Protection</description>
                            <lsb>0</lsb>
                            <msb>0</msb>
                            <access>read-write</access>
                            <enumeratedValues>
                                </enumeratedValues>
                        </field>
                        <field>
                            <name>SRAMSA1</name>
                            <description>Security attributes of registers for SRAM Protection 2</description>
                            <lsb>1</lsb>
                            <msb>1</msb>
                            <access>read-write</access>
                            <enumeratedValues>
                                </enumeratedValues>
                        </field>
                        <field>
                            <name>SRAMSA2</name>
                            <description>Security attributes of registers for ECC Relation</description>
                            <lsb>2</lsb>
                            <msb>2</msb>
                            <access>read-write</access>
                            <enumeratedValues>
                                </enumeratedValues>
                        </field>
                    </fields>
                </register>
                <register>
                    <name>STBRAMSAR</name>
                    <description>Standby RAM memory Security Attribution Register</description>
                    <addressOffset>0x014</addressOffset>
                    <size>32</size>
                    <access>read-write</access>
                    <resetValue>0xfffffff0</resetValue>
                    <resetMask>0xffffffff</resetMask>
                    <fields>
                        <field>
                            <name>NSBSTBR</name>
                            <description>Security attributes of each region for Standby RAM</description>
                            <lsb>0</lsb>
                            <msb>3</msb>
                            <access>read-write</access>
                            <enumeratedValues>
                                </enumeratedValues>
                        </field>
                    </fields>
                </register>
                <register>
                    <name>DTCSAR</name>
                    <description>DTC Controller Security Attribution Register</description>
                    <addressOffset>0x30</addressOffset>
                    <size>32</size>
                    <access>read-write</access>
                    <resetValue>0xffffffff</resetValue>
                    <resetMask>0xffffffff</resetMask>
                    <fields>
                        <field>
                            <name>DTCSTSA</name>
                            <description>DTC Security Attribution</description>
                            <lsb>0</lsb>
                            <msb>0</msb>
                            <access>read-write</access>
                            <enumeratedValues>
                                </enumeratedValues>
                        </field>
                    </fields>
                </register>
                <register>
                    <name>DMACSAR</name>
                    <description>DMAC Controller Security Attribution Register</description>
                    <addressOffset>0x34</addressOffset>
                    <size>32</size>
                    <access>read-write</access>
                    <resetValue>0xffffffff</resetValue>
                    <resetMask>0xffffffff</resetMask>
                    <fields>
                        <field>
                            <name>DMASTSA</name>
                            <description>DMAST Security Attribution</description>
                            <lsb>0</lsb>
                            <msb>0</msb>
                            <access>read-write</access>
                            <enumeratedValues>
                                </enumeratedValues>
                        </field>
                    </fields>
                </register>
                <register>
                    <name>ICUSARA</name>
                    <description>Interrupt Controller Unit Security Attribution Register A</description>
                    <addressOffset>0x40</addressOffset>
                    <size>32</size>
                    <access>read-write</access>
                    <resetValue>0xffffffff</resetValue>
                    <resetMask>0xffffffff</resetMask>
                    <fields>
                        <field>
                            <name>SAIRQCR00</name>
                            <description>Security attributes of registers for the IRQCRn register</description>
                            <lsb>0</lsb>
                            <msb>0</msb>
                            <access>read-write</access>
                            <enumeratedValues>
                                </enumeratedValues>
                        </field>
                        <field>
                            <name>SAIRQCR01</name>
                            <description>Security attributes of registers for the IRQCRn register</description>
                            <lsb>1</lsb>
                            <msb>1</msb>
                            <access>read-write</access>
                            <enumeratedValues>
                                </enumeratedValues>
                        </field>
                        <field>
                            <name>SAIRQCR02</name>
                            <description>Security attributes of registers for the IRQCRn register</description>
                            <lsb>2</lsb>
                            <msb>2</msb>
                            <access>read-write</access>
                            <enumeratedValues>
                                </enumeratedValues>
                        </field>
                        <field>
                            <name>SAIRQCR03</name>
                            <description>Security attributes of registers for the IRQCRn register</description>
                            <lsb>3</lsb>
                            <msb>3</msb>
                            <access>read-write</access>
                            <enumeratedValues>
                                </enumeratedValues>
                        </field>
                        <field>
                            <name>SAIRQCR04</name>
                            <description>Security attributes of registers for the IRQCRn register</description>
                            <lsb>4</lsb>
                            <msb>4</msb>
                            <access>read-write</access>
                            <enumeratedValues>
                                </enumeratedValues>
                        </field>
                        <field>
                            <name>SAIRQCR05</name>
                            <description>Security attributes of registers for the IRQCRn register</description>
                            <lsb>5</lsb>
                            <msb>5</msb>
                            <access>read-write</access>
                            <enumeratedValues>
                                </enumeratedValues>
                        </field>
                        <field>
                            <name>SAIRQCR06</name>
                            <description>Security attributes of registers for the IRQCRn register</description>
                            <lsb>6</lsb>
                            <msb>6</msb>
                            <access>read-write</access>
                            <enumeratedValues>
                                </enumeratedValues>
                        </field>
                        <field>
                            <name>SAIRQCR07</name>
                            <description>Security attributes of registers for the IRQCRn register</description>
                            <lsb>7</lsb>
                            <msb>7</msb>
                            <access>read-write</access>
                            <enumeratedValues>
                                </enumeratedValues>
                        </field>
                        <field>
                            <name>SAIRQCR08</name>
                            <description>Security attributes of registers for the IRQCRn register</description>
                            <lsb>8</lsb>
                            <msb>8</msb>
                            <access>read-write</access>
                            <enumeratedValues>
                                </enumeratedValues>
                        </field>
                        <field>
                            <name>SAIRQCR09</name>
                            <description>Security attributes of registers for the IRQCRn register</description>
                            <lsb>9</lsb>
                            <msb>9</msb>
                            <access>read-write</access>
                            <enumeratedValues>
                                </enumeratedValues>
                        </field>
                        <field>
                            <name>SAIRQCR10</name>
                            <description>Security attributes of registers for the IRQCRn register</description>
                            <lsb>10</lsb>
                            <msb>10</msb>
                            <access>read-write</access>
                            <enumeratedValues>
                                </enumeratedValues>
                        </field>
                        <field>
                            <name>SAIRQCR11</name>
                            <description>Security attributes of registers for the IRQCRn register</description>
                            <lsb>11</lsb>
                            <msb>11</msb>
                            <access>read-write</access>
                            <enumeratedValues>
                                </enumeratedValues>
                        </field>
                        <field>
                            <name>SAIRQCR12</name>
                            <description>Security attributes of registers for the IRQCRn register</description>
                            <lsb>12</lsb>
                            <msb>12</msb>
                            <access>read-write</access>
                            <enumeratedValues>
                                </enumeratedValues>
                        </field>
                        <field>
                            <name>SAIRQCR13</name>
                            <description>Security attributes of registers for the IRQCRn register</description>
                            <lsb>13</lsb>
                            <msb>13</msb>
                            <access>read-write</access>
                            <enumeratedValues>
                                </enumeratedValues>
                        </field>
                        <field>
                            <name>SAIRQCR14</name>
                            <description>Security attributes of registers for the IRQCRn register</description>
                            <lsb>14</lsb>
                            <msb>14</msb>
                            <access>read-write</access>
                            <enumeratedValues>
                                </enumeratedValues>
                        </field>
                        <field>
                            <name>SAIRQCR15</name>
                            <description>Security attributes of registers for the IRQCRn register</description>
                            <lsb>15</lsb>
                            <msb>15</msb>
                            <access>read-write</access>
                            <enumeratedValues>
                                </enumeratedValues>
                        </field>
                    </fields>
                </register>
                <register>
                    <name>ICUSARB</name>
                    <description>Interrupt Controller Unit Security Attribution Register B</description>
                    <addressOffset>0x44</addressOffset>
                    <size>32</size>
                    <access>read-write</access>
                    <resetValue>0xffffffff</resetValue>
                    <resetMask>0xffffffff</resetMask>
                    <fields>
                        <field>
                            <name>SANMI</name>
                            <description>Security attributes of registers for nonmaskable interrupt</description>
                            <lsb>0</lsb>
                            <msb>0</msb>
                            <access>read-write</access>
                            <enumeratedValues>
                                </enumeratedValues>
                        </field>
                    </fields>
                </register>
                <register>
                    <name>ICUSARC</name>
                    <description>Interrupt Controller Unit Security Attribution Register C</description>
                    <addressOffset>0x48</addressOffset>
                    <size>32</size>
                    <access>read-write</access>
                    <resetValue>0xffffffff</resetValue>
                    <resetMask>0xffffffff</resetMask>
                    <fields>
                        <field>
                            <name>SADMAC0</name>
                            <description>Security attributes of registers for DMAC channel</description>
                            <lsb>0</lsb>
                            <msb>0</msb>
                            <access>read-write</access>
                            <enumeratedValues>
                                </enumeratedValues>
                        </field>
                        <field>
                            <name>SADMAC1</name>
                            <description>Security attributes of registers for DMAC channel</description>
                            <lsb>1</lsb>
                            <msb>1</msb>
                            <access>read-write</access>
                            <enumeratedValues>
                                </enumeratedValues>
                        </field>
                        <field>
                            <name>SADMAC2</name>
                            <description>Security attributes of registers for DMAC channel</description>
                            <lsb>2</lsb>
                            <msb>2</msb>
                            <access>read-write</access>
                            <enumeratedValues>
                                </enumeratedValues>
                        </field>
                        <field>
                            <name>SADMAC3</name>
                            <description>Security attributes of registers for DMAC channel</description>
                            <lsb>3</lsb>
                            <msb>3</msb>
                            <access>read-write</access>
                            <enumeratedValues>
                                </enumeratedValues>
                        </field>
                        <field>
                            <name>SADMAC4</name>
                            <description>Security attributes of registers for DMAC channel</description>
                            <lsb>4</lsb>
                            <msb>4</msb>
                            <access>read-write</access>
                            <enumeratedValues>
                                </enumeratedValues>
                        </field>
                        <field>
                            <name>SADMAC5</name>
                            <description>Security attributes of registers for DMAC channel</description>
                            <lsb>5</lsb>
                            <msb>5</msb>
                            <access>read-write</access>
                            <enumeratedValues>
                                </enumeratedValues>
                        </field>
                        <field>
                            <name>SADMAC6</name>
                            <description>Security attributes of registers for DMAC channel</description>
                            <lsb>6</lsb>
                            <msb>6</msb>
                            <access>read-write</access>
                            <enumeratedValues>
                                </enumeratedValues>
                        </field>
                        <field>
                            <name>SADMAC7</name>
                            <description>Security attributes of registers for DMAC channel</description>
                            <lsb>7</lsb>
                            <msb>7</msb>
                            <access>read-write</access>
                            <enumeratedValues>
                                </enumeratedValues>
                        </field>
                    </fields>
                </register>
                <register>
                    <name>ICUSARD</name>
                    <description>Interrupt Controller Unit Security Attribution Register D</description>
                    <addressOffset>0x4C</addressOffset>
                    <size>32</size>
                    <access>read-write</access>
                    <resetValue>0xffffffff</resetValue>
                    <resetMask>0xffffffff</resetMask>
                    <fields>
                        <field>
                            <name>SASELSR0</name>
                            <description>Security attributes of registers for SELSR0</description>
                            <lsb>0</lsb>
                            <msb>0</msb>
                            <access>read-write</access>
                            <enumeratedValues>
                                </enumeratedValues>
                        </field>
                    </fields>
                </register>
                <register>
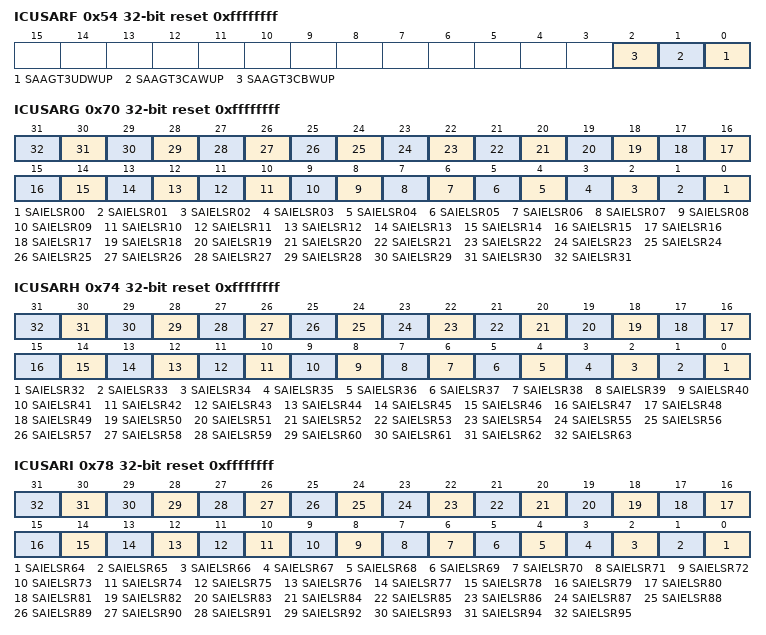
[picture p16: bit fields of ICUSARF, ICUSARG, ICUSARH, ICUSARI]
                    <name>ICUSARF</name>
                    <description>Interrupt Controller Unit Security Attribution Register F</description>
                    <addressOffset>0x54</addressOffset>
                    <size>32</size>
                    <access>read-write</access>
                    <resetValue>0xffffffff</resetValue>
                    <resetMask>0xffffffff</resetMask>
                    <fields>
                        <field>
                            <name>SAAGT3UDWUP</name>
                            <description>Security attributes of registers for WUPEN1.b0</description>
                            <lsb>0</lsb>
                            <msb>0</msb>
                            <access>read-write</access>
                            <enumeratedValues>
                                </enumeratedValues>
                        </field>
                        <field>
                            <name>SAAGT3CAWUP</name>
                            <description>Security attributes of registers for WUPEN1.b1</description>
                            <lsb>1</lsb>
                            <msb>1</msb>
                            <access>read-write</access>
                            <enumeratedValues>
                                </enumeratedValues>
                        </field>
                        <field>
                            <name>SAAGT3CBWUP</name>
                            <description>Security attributes of registers for WUPEN1.b2</description>
                            <lsb>2</lsb>
                            <msb>2</msb>
                            <access>read-write</access>
                            <enumeratedValues>
                                </enumeratedValues>
                        </field>
                    </fields>
                </register>
                <register>
                    <name>ICUSARG</name>
                    <description>Interrupt Controller Unit Security Attribution Register G</description>
                    <addressOffset>0x70</addressOffset>
                    <size>32</size>
                    <access>read-write</access>
                    <resetValue>0xffffffff</resetValue>
                    <resetMask>0xffffffff</resetMask>
                    <fields>
                        <field>
                            <name>SAIELSR00</name>
                            <description>Security attributes of registers for IELSR31 to IELSR0</description>
                            <lsb>0</lsb>
                            <msb>0</msb>
                            <access>read-write</access>
                            <enumeratedValues>
                                </enumeratedValues>
                        </field>
                        <field>
                            <name>SAIELSR01</name>
                            <description>Security attributes of registers for IELSR31 to IELSR0</description>
                            <lsb>1</lsb>
                            <msb>1</msb>
                            <access>read-write</access>
                            <enumeratedValues>
                                </enumeratedValues>
                        </field>
                        <field>
                            <name>SAIELSR02</name>
                            <description>Security attributes of registers for IELSR31 to IELSR0</description>
                            <lsb>2</lsb>
                            <msb>2</msb>
                            <access>read-write</access>
                            <enumeratedValues>
                                </enumeratedValues>
                        </field>
                        <field>
                            <name>SAIELSR03</name>
                            <description>Security attributes of registers for IELSR31 to IELSR0</description>
                            <lsb>3</lsb>
                            <msb>3</msb>
                            <access>read-write</access>
                            <enumeratedValues>
                                </enumeratedValues>
                        </field>
                        <field>
                            <name>SAIELSR04</name>
                            <description>Security attributes of registers for IELSR31 to IELSR0</description>
                            <lsb>4</lsb>
                            <msb>4</msb>
                            <access>read-write</access>
                            <enumeratedValues>
                                </enumeratedValues>
                        </field>
                        <field>
                            <name>SAIELSR05</name>
                            <description>Security attributes of registers for IELSR31 to IELSR0</description>
                            <lsb>5</lsb>
                            <msb>5</msb>
                            <access>read-write</access>
                            <enumeratedValues>
                                </enumeratedValues>
                        </field>
                        <field>
                            <name>SAIELSR06</name>
                            <description>Security attributes of registers for IELSR31 to IELSR0</description>
                            <lsb>6</lsb>
                            <msb>6</msb>
                            <access>read-write</access>
                            <enumeratedValues>
                                </enumeratedValues>
                        </field>
                        <field>
                            <name>SAIELSR07</name>
                            <description>Security attributes of registers for IELSR31 to IELSR0</description>
                            <lsb>7</lsb>
                            <msb>7</msb>
                            <access>read-write</access>
                            <enumeratedValues>
                                </enumeratedValues>
                        </field>
                        <field>
                            <name>SAIELSR08</name>
                            <description>Security attributes of registers for IELSR31 to IELSR0</description>
                            <lsb>8</lsb>
                            <msb>8</msb>
                            <access>read-write</access>
                            <enumeratedValues>
                                </enumeratedValues>
                        </field>
                        <field>
                            <name>SAIELSR09</name>
                            <description>Security attributes of registers for IELSR31 to IELSR0</description>
                            <lsb>9</lsb>
                            <msb>9</msb>
                            <access>read-write</access>
                            <enumeratedValues>
                                </enumeratedValues>
                        </field>
                        <field>
                            <name>SAIELSR10</name>
                            <description>Security attributes of registers for IELSR31 to IELSR0</description>
                            <lsb>10</lsb>
                            <msb>10</msb>
                            <access>read-write</access>
                            <enumeratedValues>
                                </enumeratedValues>
                        </field>
                        <field>
                            <name>SAIELSR11</name>
                            <description>Security attributes of registers for IELSR31 to IELSR0</description>
                            <lsb>11</lsb>
                            <msb>11</msb>
                            <access>read-write</access>
                            <enumeratedValues>
                                </enumeratedValues>
                        </field>
                        <field>
                            <name>SAIELSR12</name>
                            <description>Security attributes of registers for IELSR31 to IELSR0</description>
                            <lsb>12</lsb>
                            <msb>12</msb>
                            <access>read-write</access>
                            <enumeratedValues>
                                </enumeratedValues>
                        </field>
                        <field>
                            <name>SAIELSR13</name>
                            <description>Security attributes of registers for IELSR31 to IELSR0</description>
                            <lsb>13</lsb>
                            <msb>13</msb>
                            <access>read-write</access>
                            <enumeratedValues>
                                </enumeratedValues>
                        </field>
                        <field>
                            <name>SAIELSR14</name>
                            <description>Security attributes of registers for IELSR31 to IELSR0</description>
                            <lsb>14</lsb>
                            <msb>14</msb>
                            <access>read-write</access>
                            <enumeratedValues>
                                </enumeratedValues>
                        </field>
                        <field>
                            <name>SAIELSR15</name>
                            <description>Security attributes of registers for IELSR31 to IELSR0</description>
                            <lsb>15</lsb>
                            <msb>15</msb>
                            <access>read-write</access>
                            <enumeratedValues>
                                </enumeratedValues>
                        </field>
                        <field>
                            <name>SAIELSR16</name>
                            <description>Security attributes of registers for IELSR31 to IELSR0</description>
                            <lsb>16</lsb>
                            <msb>16</msb>
                            <access>read-write</access>
                            <enumeratedValues>
                                </enumeratedValues>
                        </field>
                        <field>
                            <name>SAIELSR17</name>
                            <description>Security attributes of registers for IELSR31 to IELSR0</description>
                            <lsb>17</lsb>
                            <msb>17</msb>
                            <access>read-write</access>
                            <enumeratedValues>
                                </enumeratedValues>
                        </field>
                        <field>
                            <name>SAIELSR18</name>
                            <description>Security attributes of registers for IELSR31 to IELSR0</description>
                            <lsb>18</lsb>
                            <msb>18</msb>
                            <access>read-write</access>
                            <enumeratedValues>
                                </enumeratedValues>
                        </field>
                        <field>
                            <name>SAIELSR19</name>
                            <description>Security attributes of registers for IELSR31 to IELSR0</description>
                            <lsb>19</lsb>
                            <msb>19</msb>
                            <access>read-write</access>
                            <enumeratedValues>
                                </enumeratedValues>
                        </field>
                        <field>
                            <name>SAIELSR20</name>
                            <description>Security attributes of registers for IELSR31 to IELSR0</description>
                            <lsb>20</lsb>
                            <msb>20</msb>
                            <access>read-write</access>
                            <enumeratedValues>
                                </enumeratedValues>
                        </field>
                        <field>
                            <name>SAIELSR21</name>
                            <description>Security attributes of registers for IELSR31 to IELSR0</description>
                            <lsb>21</lsb>
                            <msb>21</msb>
                            <access>read-write</access>
                            <enumeratedValues>
                                </enumeratedValues>
                        </field>
                        <field>
                            <name>SAIELSR22</name>
                            <description>Security attributes of registers for IELSR31 to IELSR0</description>
                            <lsb>22</lsb>
                            <msb>22</msb>
                            <access>read-write</access>
                            <enumeratedValues>
                                </enumeratedValues>
                        </field>
                        <field>
                            <name>SAIELSR23</name>
                            <description>Security attributes of registers for IELSR31 to IELSR0</description>
                            <lsb>23</lsb>
                            <msb>23</msb>
                            <access>read-write</access>
                            <enumeratedValues>
                                </enumeratedValues>
                        </field>
                        <field>
                            <name>SAIELSR24</name>
                            <description>Security attributes of registers for IELSR31 to IELSR0</description>
                            <lsb>24</lsb>
                            <msb>24</msb>
                            <access>read-write</access>
                            <enumeratedValues>
                                </enumeratedValues>
                        </field>
                        <field>
                            <name>SAIELSR25</name>
                            <description>Security attributes of registers for IELSR31 to IELSR0</description>
                            <lsb>25</lsb>
                            <msb>25</msb>
                            <access>read-write</access>
                            <enumeratedValues>
                                </enumeratedValues>
                        </field>
                        <field>
                            <name>SAIELSR26</name>
                            <description>Security attributes of registers for IELSR31 to IELSR0</description>
                            <lsb>26</lsb>
                            <msb>26</msb>
                            <access>read-write</access>
                            <enumeratedValues>
                                </enumeratedValues>
                        </field>
                        <field>
                            <name>SAIELSR27</name>
                            <description>Security attributes of registers for IELSR31 to IELSR0</description>
                            <lsb>27</lsb>
                            <msb>27</msb>
                            <access>read-write</access>
                            <enumeratedValues>
                                </enumeratedValues>
                        </field>
                        <field>
                            <name>SAIELSR28</name>
                            <description>Security attributes of registers for IELSR31 to IELSR0</description>
                            <lsb>28</lsb>
                            <msb>28</msb>
                            <access>read-write</access>
                            <enumeratedValues>
                                </enumeratedValues>
                        </field>
                        <field>
                            <name>SAIELSR29</name>
                            <description>Security attributes of registers for IELSR31 to IELSR0</description>
                            <lsb>29</lsb>
                            <msb>29</msb>
                            <access>read-write</access>
                            <enumeratedValues>
                                </enumeratedValues>
                        </field>
                        <field>
                            <name>SAIELSR30</name>
                            <description>Security attributes of registers for IELSR31 to IELSR0</description>
                            <lsb>30</lsb>
                            <msb>30</msb>
                            <access>read-write</access>
                            <enumeratedValues>
                                </enumeratedValues>
                        </field>
                        <field>
                            <name>SAIELSR31</name>
                            <description>Security attributes of registers for IELSR31 to IELSR0</description>
                            <lsb>31</lsb>
                            <msb>31</msb>
                            <access>read-write</access>
                            <enumeratedValues>
                                </enumeratedValues>
                        </field>
                    </fields>
                </register>
                <register>
                    <name>ICUSARH</name>
                    <description>Interrupt Controller Unit Security Attribution Register H</description>
                    <addressOffset>0x74</addressOffset>
                    <size>32</size>
                    <access>read-write</access>
                    <resetValue>0xffffffff</resetValue>
                    <resetMask>0xffffffff</resetMask>
                    <fields>
                        <field>
                            <name>SAIELSR32</name>
                            <description>Security attributes of registers for IELSR63 to IELSR32</description>
                            <lsb>0</lsb>
                            <msb>0</msb>
                            <access>read-write</access>
                            <enumeratedValues>
                                </enumeratedValues>
                        </field>
                        <field>
                            <name>SAIELSR33</name>
                            <description>Security attributes of registers for IELSR63 to IELSR32</description>
                            <lsb>1</lsb>
                            <msb>1</msb>
                            <access>read-write</access>
                            <enumeratedValues>
                                </enumeratedValues>
                        </field>
                        <field>
                            <name>SAIELSR34</name>
                            <description>Security attributes of registers for IELSR63 to IELSR32</description>
                            <lsb>2</lsb>
                            <msb>2</msb>
                            <access>read-write</access>
                            <enumeratedValues>
                                </enumeratedValues>
                        </field>
                        <field>
                            <name>SAIELSR35</name>
                            <description>Security attributes of registers for IELSR63 to IELSR32</description>
                            <lsb>3</lsb>
                            <msb>3</msb>
                            <access>read-write</access>
                            <enumeratedValues>
                                </enumeratedValues>
                        </field>
                        <field>
                            <name>SAIELSR36</name>
                            <description>Security attributes of registers for IELSR63 to IELSR32</description>
                            <lsb>4</lsb>
                            <msb>4</msb>
                            <access>read-write</access>
                            <enumeratedValues>
                                </enumeratedValues>
                        </field>
                        <field>
                            <name>SAIELSR37</name>
                            <description>Security attributes of registers for IELSR63 to IELSR32</description>
                            <lsb>5</lsb>
                            <msb>5</msb>
                            <access>read-write</access>
                            <enumeratedValues>
                                </enumeratedValues>
                        </field>
                        <field>
                            <name>SAIELSR38</name>
                            <description>Security attributes of registers for IELSR63 to IELSR32</description>
                            <lsb>6</lsb>
                            <msb>6</msb>
                            <access>read-write</access>
                            <enumeratedValues>
                                </enumeratedValues>
                        </field>
                        <field>
                            <name>SAIELSR39</name>
                            <description>Security attributes of registers for IELSR63 to IELSR32</description>
                            <lsb>7</lsb>
                            <msb>7</msb>
                            <access>read-write</access>
                            <enumeratedValues>
                                </enumeratedValues>
                        </field>
                        <field>
                            <name>SAIELSR40</name>
                            <description>Security attributes of registers for IELSR63 to IELSR32</description>
                            <lsb>8</lsb>
                            <msb>8</msb>
                            <access>read-write</access>
                            <enumeratedValues>
                                </enumeratedValues>
                        </field>
                        <field>
                            <name>SAIELSR41</name>
                            <description>Security attributes of registers for IELSR63 to IELSR32</description>
                            <lsb>9</lsb>
                            <msb>9</msb>
                            <access>read-write</access>
                            <enumeratedValues>
                                </enumeratedValues>
                        </field>
                        <field>
                            <name>SAIELSR42</name>
                            <description>Security attributes of registers for IELSR63 to IELSR32</description>
                            <lsb>10</lsb>
                            <msb>10</msb>
                            <access>read-write</access>
                            <enumeratedValues>
                                </enumeratedValues>
                        </field>
                        <field>
                            <name>SAIELSR43</name>
                            <description>Security attributes of registers for IELSR63 to IELSR32</description>
                            <lsb>11</lsb>
                            <msb>11</msb>
                            <access>read-write</access>
                            <enumeratedValues>
                                </enumeratedValues>
                        </field>
                        <field>
                            <name>SAIELSR44</name>
                            <description>Security attributes of registers for IELSR63 to IELSR32</description>
                            <lsb>12</lsb>
                            <msb>12</msb>
                            <access>read-write</access>
                            <enumeratedValues>
                                </enumeratedValues>
                        </field>
                        <field>
                            <name>SAIELSR45</name>
                            <description>Security attributes of registers for IELSR63 to IELSR32</description>
                            <lsb>13</lsb>
                            <msb>13</msb>
                            <access>read-write</access>
                            <enumeratedValues>
                                </enumeratedValues>
                        </field>
                        <field>
                            <name>SAIELSR46</name>
                            <description>Security attributes of registers for IELSR63 to IELSR32</description>
                            <lsb>14</lsb>
                            <msb>14</msb>
                            <access>read-write</access>
                            <enumeratedValues>
                                </enumeratedValues>
                        </field>
                        <field>
                            <name>SAIELSR47</name>
                            <description>Security attributes of registers for IELSR63 to IELSR32</description>
                            <lsb>15</lsb>
                            <msb>15</msb>
                            <access>read-write</access>
                            <enumeratedValues>
                                </enumeratedValues>
                        </field>
                        <field>
                            <name>SAIELSR48</name>
                            <description>Security attributes of registers for IELSR63 to IELSR32</description>
                            <lsb>16</lsb>
                            <msb>16</msb>
                            <access>read-write</access>
                            <enumeratedValues>
                                </enumeratedValues>
                        </field>
                        <field>
                            <name>SAIELSR49</name>
                            <description>Security attributes of registers for IELSR63 to IELSR32</description>
                            <lsb>17</lsb>
                            <msb>17</msb>
                            <access>read-write</access>
                            <enumeratedValues>
                                </enumeratedValues>
                        </field>
                        <field>
                            <name>SAIELSR50</name>
                            <description>Security attributes of registers for IELSR63 to IELSR32</description>
                            <lsb>18</lsb>
                            <msb>18</msb>
                            <access>read-write</access>
                            <enumeratedValues>
                                </enumeratedValues>
                        </field>
                        <field>
                            <name>SAIELSR51</name>
                            <description>Security attributes of registers for IELSR63 to IELSR32</description>
                            <lsb>19</lsb>
                            <msb>19</msb>
                            <access>read-write</access>
                            <enumeratedValues>
                                </enumeratedValues>
                        </field>
                        <field>
                            <name>SAIELSR52</name>
                            <description>Security attributes of registers for IELSR63 to IELSR32</description>
                            <lsb>20</lsb>
                            <msb>20</msb>
                            <access>read-write</access>
                            <enumeratedValues>
                                </enumeratedValues>
                        </field>
                        <field>
                            <name>SAIELSR53</name>
                            <description>Security attributes of registers for IELSR63 to IELSR32</description>
                            <lsb>21</lsb>
                            <msb>21</msb>
                            <access>read-write</access>
                            <enumeratedValues>
                                </enumeratedValues>
                        </field>
                        <field>
                            <name>SAIELSR54</name>
                            <description>Security attributes of registers for IELSR63 to IELSR32</description>
                            <lsb>22</lsb>
                            <msb>22</msb>
                            <access>read-write</access>
                            <enumeratedValues>
                                </enumeratedValues>
                        </field>
                        <field>
                            <name>SAIELSR55</name>
                            <description>Security attributes of registers for IELSR63 to IELSR32</description>
                            <lsb>23</lsb>
                            <msb>23</msb>
                            <access>read-write</access>
                            <enumeratedValues>
                                </enumeratedValues>
                        </field>
                        <field>
                            <name>SAIELSR56</name>
                            <description>Security attributes of registers for IELSR63 to IELSR32</description>
                            <lsb>24</lsb>
                            <msb>24</msb>
                            <access>read-write</access>
                            <enumeratedValues>
                                </enumeratedValues>
                        </field>
                        <field>
                            <name>SAIELSR57</name>
                            <description>Security attributes of registers for IELSR63 to IELSR32</description>
                            <lsb>25</lsb>
                            <msb>25</msb>
                            <access>read-write</access>
                            <enumeratedValues>
                                </enumeratedValues>
                        </field>
                        <field>
                            <name>SAIELSR58</name>
                            <description>Security attributes of registers for IELSR63 to IELSR32</description>
                            <lsb>26</lsb>
                            <msb>26</msb>
                            <access>read-write</access>
                            <enumeratedValues>
                                </enumeratedValues>
                        </field>
                        <field>
                            <name>SAIELSR59</name>
                            <description>Security attributes of registers for IELSR63 to IELSR32</description>
                            <lsb>27</lsb>
                            <msb>27</msb>
                            <access>read-write</access>
                            <enumeratedValues>
                                </enumeratedValues>
                        </field>
                        <field>
                            <name>SAIELSR60</name>
                            <description>Security attributes of registers for IELSR63 to IELSR32</description>
                            <lsb>28</lsb>
                            <msb>28</msb>
                            <access>read-write</access>
                            <enumeratedValues>
                                </enumeratedValues>
                        </field>
                        <field>
                            <name>SAIELSR61</name>
                            <description>Security attributes of registers for IELSR63 to IELSR32</description>
                            <lsb>29</lsb>
                            <msb>29</msb>
                            <access>read-write</access>
                            <enumeratedValues>
                                </enumeratedValues>
                        </field>
                        <field>
                            <name>SAIELSR62</name>
                            <description>Security attributes of registers for IELSR63 to IELSR32</description>
                            <lsb>30</lsb>
                            <msb>30</msb>
                            <access>read-write</access>
                            <enumeratedValues>
                                </enumeratedValues>
                        </field>
                        <field>
                            <name>SAIELSR63</name>
                            <description>Security attributes of registers for IELSR63 to IELSR32</description>
                            <lsb>31</lsb>
                            <msb>31</msb>
                            <access>read-write</access>
                            <enumeratedValues>
                                </enumeratedValues>
                        </field>
                    </fields>
                </register>
                <register>
                    <name>ICUSARI</name>
                    <description>Interrupt Controller Unit Security Attribution Register I</description>
                    <addressOffset>0x78</addressOffset>
                    <size>32</size>
                    <access>read-write</access>
                    <resetValue>0xffffffff</resetValue>
                    <resetMask>0xffffffff</resetMask>
                    <fields>
                        <field>
                            <name>SAIELSR64</name>
                            <description>Security attributes of registers for IELSR95 to IELSR64</description>
                            <lsb>0</lsb>
                            <msb>0</msb>
                            <access>read-write</access>
                            <enumeratedValues>
                                </enumeratedValues>
                        </field>
                        <field>
                            <name>SAIELSR65</name>
                            <description>Security attributes of registers for IELSR95 to IELSR64</description>
                            <lsb>1</lsb>
                            <msb>1</msb>
                            <access>read-write</access>
                            <enumeratedValues>
                                </enumeratedValues>
                        </field>
                        <field>
                            <name>SAIELSR66</name>
                            <description>Security attributes of registers for IELSR95 to IELSR64</description>
                            <lsb>2</lsb>
                            <msb>2</msb>
                            <access>read-write</access>
                            <enumeratedValues>
                                </enumeratedValues>
                        </field>
                        <field>
                            <name>SAIELSR67</name>
                            <description>Security attributes of registers for IELSR95 to IELSR64</description>
                            <lsb>3</lsb>
                            <msb>3</msb>
                            <access>read-write</access>
                            <enumeratedValues>
                                </enumeratedValues>
                        </field>
                        <field>
                            <name>SAIELSR68</name>
                            <description>Security attributes of registers for IELSR95 to IELSR64</description>
                            <lsb>4</lsb>
                            <msb>4</msb>
                            <access>read-write</access>
                            <enumeratedValues>
                                </enumeratedValues>
                        </field>
                        <field>
                            <name>SAIELSR69</name>
                            <description>Security attributes of registers for IELSR95 to IELSR64</description>
                            <lsb>5</lsb>
                            <msb>5</msb>
                            <access>read-write</access>
                            <enumeratedValues>
                                </enumeratedValues>
                        </field>
                        <field>
                            <name>SAIELSR70</name>
                            <description>Security attributes of registers for IELSR95 to IELSR64</description>
                            <lsb>6</lsb>
                            <msb>6</msb>
                            <access>read-write</access>
                            <enumeratedValues>
                                </enumeratedValues>
                        </field>
                        <field>
                            <name>SAIELSR71</name>
                            <description>Security attributes of registers for IELSR95 to IELSR64</description>
                            <lsb>7</lsb>
                            <msb>7</msb>
                            <access>read-write</access>
                            <enumeratedValues>
                                </enumeratedValues>
                        </field>
                        <field>
                            <name>SAIELSR72</name>
                            <description>Security attributes of registers for IELSR95 to IELSR64</description>
                            <lsb>8</lsb>
                            <msb>8</msb>
                            <access>read-write</access>
                            <enumeratedValues>
                                </enumeratedValues>
                        </field>
                        <field>
                            <name>SAIELSR73</name>
                            <description>Security attributes of registers for IELSR95 to IELSR64</description>
                            <lsb>9</lsb>
                            <msb>9</msb>
                            <access>read-write</access>
                            <enumeratedValues>
                                </enumeratedValues>
                        </field>
                        <field>
                            <name>SAIELSR74</name>
                            <description>Security attributes of registers for IELSR95 to IELSR64</description>
                            <lsb>10</lsb>
                            <msb>10</msb>
                            <access>read-write</access>
                            <enumeratedValues>
                                </enumeratedValues>
                        </field>
                        <field>
                            <name>SAIELSR75</name>
                            <description>Security attributes of registers for IELSR95 to IELSR64</description>
                            <lsb>11</lsb>
                            <msb>11</msb>
                            <access>read-write</access>
                            <enumeratedValues>
                                </enumeratedValues>
                        </field>
                        <field>
                            <name>SAIELSR76</name>
                            <description>Security attributes of registers for IELSR95 to IELSR64</description>
                            <lsb>12</lsb>
                            <msb>12</msb>
                            <access>read-write</access>
                            <enumeratedValues>
                                </enumeratedValues>
                        </field>
                        <field>
                            <name>SAIELSR77</name>
                            <description>Security attributes of registers for IELSR95 to IELSR64</description>
                            <lsb>13</lsb>
                            <msb>13</msb>
                            <access>read-write</access>
                            <enumeratedValues>
                                </enumeratedValues>
                        </field>
                        <field>
                            <name>SAIELSR78</name>
                            <description>Security attributes of registers for IELSR95 to IELSR64</description>
                            <lsb>14</lsb>
                            <msb>14</msb>
                            <access>read-write</access>
                            <enumeratedValues>
                                </enumeratedValues>
                        </field>
                        <field>
                            <name>SAIELSR79</name>
                            <description>Security attributes of registers for IELSR95 to IELSR64</description>
                            <lsb>15</lsb>
                            <msb>15</msb>
                            <access>read-write</access>
                            <enumeratedValues>
                                </enumeratedValues>
                        </field>
                        <field>
                            <name>SAIELSR80</name>
                            <description>Security attributes of registers for IELSR95 to IELSR64</description>
                            <lsb>16</lsb>
                            <msb>16</msb>
                            <access>read-write</access>
                            <enumeratedValues>
                                </enumeratedValues>
                        </field>
                        <field>
                            <name>SAIELSR81</name>
                            <description>Security attributes of registers for IELSR95 to IELSR64</description>
                            <lsb>17</lsb>
                            <msb>17</msb>
                            <access>read-write</access>
                            <enumeratedValues>
                                </enumeratedValues>
                        </field>
                        <field>
                            <name>SAIELSR82</name>
                            <description>Security attributes of registers for IELSR95 to IELSR64</description>
                            <lsb>18</lsb>
                            <msb>18</msb>
                            <access>read-write</access>
                            <enumeratedValues>
                                </enumeratedValues>
                        </field>
                        <field>
                            <name>SAIELSR83</name>
                            <description>Security attributes of registers for IELSR95 to IELSR64</description>
                            <lsb>19</lsb>
                            <msb>19</msb>
                            <access>read-write</access>
                            <enumeratedValues>
                                </enumeratedValues>
                        </field>
                        <field>
                            <name>SAIELSR84</name>
                            <description>Security attributes of registers for IELSR95 to IELSR64</description>
                            <lsb>20</lsb>
                            <msb>20</msb>
                            <access>read-write</access>
                            <enumeratedValues>
                                </enumeratedValues>
                        </field>
                        <field>
                            <name>SAIELSR85</name>
                            <description>Security attributes of registers for IELSR95 to IELSR64</description>
                            <lsb>21</lsb>
                            <msb>21</msb>
                            <access>read-write</access>
                            <enumeratedValues>
                                </enumeratedValues>
                        </field>
                        <field>
                            <name>SAIELSR86</name>
                            <description>Security attributes of registers for IELSR95 to IELSR64</description>
                            <lsb>22</lsb>
                            <msb>22</msb>
                            <access>read-write</access>
                            <enumeratedValues>
                                </enumeratedValues>
                        </field>
                        <field>
                            <name>SAIELSR87</name>
                            <description>Security attributes of registers for IELSR95 to IELSR64</description>
                            <lsb>23</lsb>
                            <msb>23</msb>
                            <access>read-write</access>
                            <enumeratedValues>
                                </enumeratedValues>
                        </field>
                        <field>
                            <name>SAIELSR88</name>
                            <description>Security attributes of registers for IELSR95 to IELSR64</description>
                            <lsb>24</lsb>
                            <msb>24</msb>
                            <access>read-write</access>
                            <enumeratedValues>
                                </enumeratedValues>
                        </field>
                        <field>
                            <name>SAIELSR89</name>
                            <description>Security attributes of registers for IELSR95 to IELSR64</description>
                            <lsb>25</lsb>
                            <msb>25</msb>
                            <access>read-write</access>
                            <enumeratedValues>
                                </enumeratedValues>
                        </field>
                        <field>
                            <name>SAIELSR90</name>
                            <description>Security attributes of registers for IELSR95 to IELSR64</description>
                            <lsb>26</lsb>
                            <msb>26</msb>
                            <access>read-write</access>
                            <enumeratedValues>
                                </enumeratedValues>
                        </field>
                        <field>
                            <name>SAIELSR91</name>
                            <description>Security attributes of registers for IELSR95 to IELSR64</description>
                            <lsb>27</lsb>
                            <msb>27</msb>
                            <access>read-write</access>
                            <enumeratedValues>
                                </enumeratedValues>
                        </field>
                        <field>
                            <name>SAIELSR92</name>
                            <description>Security attributes of registers for IELSR95 to IELSR64</description>
                            <lsb>28</lsb>
                            <msb>28</msb>
                            <access>read-write</access>
                            <enumeratedValues>
                                </enumeratedValues>
                        </field>
                        <field>
                            <name>SAIELSR93</name>
                            <description>Security attributes of registers for IELSR95 to IELSR64</description>
                            <lsb>29</lsb>
                            <msb>29</msb>
                            <access>read-write</access>
                            <enumeratedValues>
                                </enumeratedValues>
                        </field>
                        <field>
                            <name>SAIELSR94</name>
                            <description>Security attributes of registers for IELSR95 to IELSR64</description>
                            <lsb>30</lsb>
                            <msb>30</msb>
                            <access>read-write</access>
                            <enumeratedValues>
                                </enumeratedValues>
                        </field>
                        <field>
                            <name>SAIELSR95</name>
                            <description>Security attributes of registers for IELSR95 to IELSR64</description>
                            <lsb>31</lsb>
                            <msb>31</msb>
                            <access>read-write</access>
                            <enumeratedValues>
                                </enumeratedValues>
                        </field>
                    </fields>
                </register>
                <register>
                    <name>BUSSARA</name>
                    <description>BUS Security Attribution Register A</description>
                    <addressOffset>0x0100</addressOffset>
                    <size>32</size>
                    <access>read-write</access>
                    <resetValue>0xffffffff</resetValue>
                    <resetMask>0xffffffff</resetMask>
                    <fields>
                        <field>
                            <name>BUSSA0</name>
                            <description>BUS Security Attribution A0</description>
                            <lsb>0</lsb>
                            <msb>0</msb>
                            <access>read-write</access>
                            <enumeratedValues>
                                </enumeratedValues>
                        </field>
                    </fields>
                </register>
                <register>
                    <name>BUSSARB</name>
                    <description>BUS Security Attribution Register B</description>
                    <addressOffset>0x0104</addressOffset>
                    <size>32</size>
                    <access>read-write</access>
                    <resetValue>0xffffffff</resetValue>
                    <resetMask>0xffffffff</resetMask>
                    <fields>
                        <field>
                            <name>BUSSB0</name>
                            <description>BUS Security Attribution B0</description>
                            <lsb>0</lsb>
                            <msb>0</msb>
                            <access>read-write</access>
                            <enumeratedValues>
                                </enumeratedValues>
                        </field>
                    </fields>
                </register>
                <register>
                    <name>MMPUSARA</name>
                    <description>Master Memory Protection Unit Security Attribution Register A</description>
                    <addressOffset>0x130</addressOffset>
                    <size>32</size>
                    <access>read-write</access>
                    <resetValue>0xffffffff</resetValue>
                    <resetMask>0xffffffff</resetMask>
                    <fields>
                        <field>
                            <name>MMPUASAn</name>
                            <description>MMPUA Security Attribution (n = 0 to 7)</description>
                            <lsb>0</lsb>
                            <msb>7</msb>
                            <access>read-write</access>
                            <enumeratedValues>
                                </enumeratedValues>
                        </field>
                    </fields>
                </register>
                <register>
                    <name>MMPUSARB</name>
                    <description>Master Memory Protection Unit Security Attribution Register B</description>
                    <addressOffset>0x134</addressOffset>
                    <size>32</size>
                    <access>read-write</access>
                    <resetValue>0xffffffff</resetValue>
                    <resetMask>0xffffffff</resetMask>
                    <fields>
                        <field>
                            <name>MMPUBSA0</name>
                            <description>MMPUB Security Attribution</description>
                            <lsb>0</lsb>
                            <msb>0</msb>
                            <access>read-write</access>
                            <enumeratedValues>
                                </enumeratedValues>
                        </field>
                    </fields>
                </register>
                <register>
                    <name>TZFSAR</name>
                    <description>TrustZone Filter Security Attribution Register</description>
                    <addressOffset>0x180</addressOffset>
                    <size>32</size>
                    <access>read-write</access>
                    <resetValue>0xfffffffe</resetValue>
                    <resetMask>0xffffffff</resetMask>
                    <fields>
                        <field>
                            <name>TZFSA0</name>
                            <description>Security attributes of registers for TrustZone Filter</description>
                            <lsb>0</lsb>
                            <msb>0</msb>
                            <access>read-write</access>
                            <enumeratedValues>
                                </enumeratedValues>
                        </field>
                    </fields>
                </register>
                <register>
                    <name>CPUDSAR</name>
                    <description>CPU Debug Security Attribution Register</description>
                    <addressOffset>0x1B0</addressOffset>
                    <size>32</size>
                    <access>read-write</access>
                    <resetValue>0xfffffffe</resetValue>
                    <resetMask>0xffffffff</resetMask>
                    <fields>
                        <field>
                            <name>CPUDSA0</name>
                            <description>CPU Debug Security Attribution 0</description>
                            <lsb>0</lsb>
                            <msb>0</msb>
                            <access>read-write</access>
                            <enumeratedValues>
                                </enumeratedValues>
                        </field>
                    </fields>
                </register>
            </registers>
        </peripheral>
        <peripheral>
            <name>DBG</name>
            <description>Debug Function</description>
            <baseAddress>0x4001B000</baseAddress>
            <addressBlock>
                <offset>0x00</offset>
                <size>4</size>
                <usage>registers</usage>
            </addressBlock>
            <addressBlock>
                <offset>0x10</offset>
                <size>4</size>
                <usage>registers</usage>
            </addressBlock>
            <registers>
                <register>
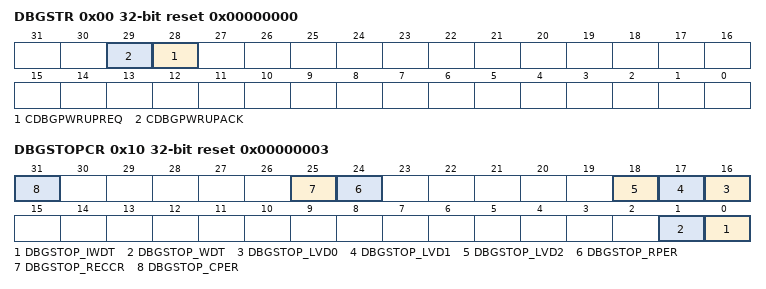
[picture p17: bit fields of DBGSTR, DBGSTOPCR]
                    <name>DBGSTR</name>
                    <description>Debug Status Register</description>
                    <addressOffset>0x00</addressOffset>
                    <size>32</size>
                    <access>read-only</access>
                    <resetValue>0x00000000</resetValue>
                    <resetMask>0xffffffff</resetMask>
                    <fields>
                        <field>
                            <name>CDBGPWRUPREQ</name>
                            <description>Debug power,up request</description>
                            <lsb>28</lsb>
                            <msb>28</msb>
                            <access>read-only</access>
                            <enumeratedValues>
                                </enumeratedValues>
                        </field>
                        <field>
                            <name>CDBGPWRUPACK</name>
                            <description>Debug power,up acknowledge</description>
                            <lsb>29</lsb>
                            <msb>29</msb>
                            <access>read-only</access>
                            <enumeratedValues>
                                </enumeratedValues>
                        </field>
                    </fields>
                </register>
                <register>
                    <name>DBGSTOPCR</name>
                    <description>Debug Stop Control Register</description>
                    <addressOffset>0x10</addressOffset>
                    <size>32</size>
                    <access>read-write</access>
                    <resetValue>0x00000003</resetValue>
                    <resetMask>0xffffffff</resetMask>
                    <fields>
                        <field>
                            <name>DBGSTOP_IWDT</name>
                            <description>Mask bit for IWDT reset/interrupt in the OCD run mode</description>
                            <lsb>0</lsb>
                            <msb>0</msb>
                            <access>read-write</access>
                            <enumeratedValues>
                                </enumeratedValues>
                        </field>
                        <field>
                            <name>DBGSTOP_WDT</name>
                            <description>Mask bit for WDT reset/interrupt in the OCD run mode</description>
                            <lsb>1</lsb>
                            <msb>1</msb>
                            <access>read-write</access>
                            <enumeratedValues>
                                </enumeratedValues>
                        </field>
                        <field>
                            <name>DBGSTOP_LVD0</name>
                            <description>Mask bit for LVD0 reset</description>
                            <lsb>16</lsb>
                            <msb>16</msb>
                            <access>read-write</access>
                            <enumeratedValues>
                                </enumeratedValues>
                        </field>
                        <field>
                            <name>DBGSTOP_LVD1</name>
                            <description>Mask bit for LVD1 reset/interrupt</description>
                            <lsb>17</lsb>
                            <msb>17</msb>
                            <access>read-write</access>
                            <enumeratedValues>
                                </enumeratedValues>
                        </field>
                        <field>
                            <name>DBGSTOP_LVD2</name>
                            <description>Mask bit for LVD2 reset/interrupt</description>
                            <lsb>18</lsb>
                            <msb>18</msb>
                            <access>read-write</access>
                            <enumeratedValues>
                                </enumeratedValues>
                        </field>
                        <field>
                            <name>DBGSTOP_RPER</name>
                            <description>Mask bit for SRAM parity error reset/interrupt</description>
                            <lsb>24</lsb>
                            <msb>24</msb>
                            <access>read-write</access>
                            <enumeratedValues>
                                </enumeratedValues>
                        </field>
                        <field>
                            <name>DBGSTOP_RECCR</name>
                            <description>Mask bit for SRAM ECC error reset/interrupt</description>
                            <lsb>25</lsb>
                            <msb>25</msb>
                            <access>read-write</access>
                            <enumeratedValues>
                                </enumeratedValues>
                        </field>
                        <field>
                            <name>DBGSTOP_CPER</name>
                            <description>Mask bit for Cache SRAM parity error reset/interrupt</description>
                            <lsb>31</lsb>
                            <msb>31</msb>
                            <access>read-write</access>
                            <enumeratedValues>
                                </enumeratedValues>
                        </field>
                    </fields>
                </register>
            </registers>
        </peripheral>
        <peripheral>
            <name>FCACHE</name>
            <description>SYSTEM/FLASH</description>
            <baseAddress>0x4001C100</baseAddress>
            <addressBlock>
                <offset>0x00</offset>
                <size>2</size>
                <usage>registers</usage>
            </addressBlock>
            <addressBlock>
                <offset>0x04</offset>
                <size>2</size>
                <usage>registers</usage>
            </addressBlock>
            <addressBlock>
                <offset>0x1C</offset>
                <size>1</size>
                <usage>registers</usage>
            </addressBlock>
            <addressBlock>
                <offset>0x40</offset>
                <size>2</size>
                <usage>registers</usage>
            </addressBlock>
            <registers>
                <register>
                    <name>FCACHEE</name>
                    <description>Flash Cache Enable Register</description>
                    <addressOffset>0x000</addressOffset>
                    <size>16</size>
                    <access>read-write</access>
                    <resetValue>0x0000</resetValue>
                    <resetMask>0xffff</resetMask>
                    <fields>
                        <field>
                            <name>FCACHEEN</name>
                            <description>Flash Cache Enable</description>
                            <lsb>0</lsb>
                            <msb>0</msb>
                            <access>read-write</access>
                            <enumeratedValues>
                                </enumeratedValues>
                        </field>
                    </fields>
                </register>
                <register>
                    <name>FCACHEIV</name>
                    <description>Flash Cache Invalidate Register</description>
                    <addressOffset>0x004</addressOffset>
                    <size>16</size>
                    <access>read-write</access>
                    <resetValue>0x0000</resetValue>
                    <resetMask>0xffff</resetMask>
                    <fields>
                        <field>
                            <name>FCACHEIV</name>
                            <description>Flash Cache Invalidate</description>
                            <lsb>0</lsb>
                            <msb>0</msb>
                            <access>read-write</access>
                            <enumeratedValues>
                                </enumeratedValues>
                        </field>
                    </fields>
                </register>
                <register>
                    <name>FLWT</name>
                    <description>Flash Wait Cycle Register</description>
                    <addressOffset>0x01C</addressOffset>
                    <size>8</size>
                    <access>read-write</access>
                    <resetValue>0x00</resetValue>
                    <resetMask>0xff</resetMask>
                    <fields>
                        <field>
                            <name>FLWT</name>
                            <description>Flash Wait Cycle</description>
                            <lsb>0</lsb>
                            <msb>2</msb>
                            <access>read-write</access>
                        </field>
                    </fields>
                </register>
                <register>
                    <name>FSAR</name>
                    <description>Flash Security Attribution Register</description>
                    <addressOffset>0x040</addressOffset>
                    <size>16</size>
                    <access>read-write</access>
                    <resetValue>0xffff</resetValue>
                    <resetMask>0xffff</resetMask>
                    <fields>
                        <field>
                            <name>FLWTSA</name>
                            <description>FLWT Security Attribution</description>
                            <lsb>0</lsb>
                            <msb>0</msb>
                            <access>read-write</access>
                            <enumeratedValues>
                                </enumeratedValues>
                        </field>
                        <field>
                            <name>FCKMHZSA</name>
                            <description>FCKMHZ Security Attribution</description>
                            <lsb>8</lsb>
                            <msb>8</msb>
                            <access>read-write</access>
                            <enumeratedValues>
                                </enumeratedValues>
                        </field>
                    </fields>
                </register>
            </registers>
        </peripheral>
        <peripheral>
            <name>SYSC</name>
            <description>System Control</description>
            <baseAddress>0x4001E000</baseAddress>
            <addressBlock>
                <offset>0x0C</offset>
                <size>2</size>
                <usage>registers</usage>
            </addressBlock>
            <addressBlock>
                <offset>0x20</offset>
                <size>4</size>
                <usage>registers</usage>
            </addressBlock>
            <addressBlock>
                <offset>0x26</offset>
                <size>1</size>
                <usage>registers</usage>
            </addressBlock>
            <addressBlock>
                <offset>0x28</offset>
                <size>3</size>
                <usage>registers</usage>
            </addressBlock>
            <addressBlock>
                <offset>0x30</offset>
                <size>1</size>
                <usage>registers</usage>
            </addressBlock>
            <addressBlock>
                <offset>0x32</offset>
                <size>1</size>
                <usage>registers</usage>
            </addressBlock>
            <addressBlock>
                <offset>0x36</offset>
                <size>1</size>
                <usage>registers</usage>
            </addressBlock>
            <addressBlock>
                <offset>0x38</offset>
                <size>5</size>
                <usage>registers</usage>
            </addressBlock>
            <addressBlock>
                <offset>0x3E</offset>
                <size>4</size>
                <usage>registers</usage>
            </addressBlock>
            <addressBlock>
                <offset>0x48</offset>
                <size>3</size>
                <usage>registers</usage>
            </addressBlock>
            <addressBlock>
                <offset>0x52</offset>
                <size>1</size>
                <usage>registers</usage>
            </addressBlock>
            <addressBlock>
                <offset>0x61</offset>
                <size>2</size>
                <usage>registers</usage>
            </addressBlock>
            <addressBlock>
                <offset>0x6C</offset>
                <size>5</size>
                <usage>registers</usage>
            </addressBlock>
            <addressBlock>
                <offset>0x74</offset>
                <size>5</size>
                <usage>registers</usage>
            </addressBlock>
            <addressBlock>
                <offset>0x88</offset>
                <size>4</size>
                <usage>registers</usage>
            </addressBlock>
            <addressBlock>
                <offset>0x92</offset>
                <size>1</size>
                <usage>registers</usage>
            </addressBlock>
            <addressBlock>
                <offset>0x94</offset>
                <size>2</size>
                <usage>registers</usage>
            </addressBlock>
            <addressBlock>
                <offset>0x98</offset>
                <size>4</size>
                <usage>registers</usage>
            </addressBlock>
            <addressBlock>
                <offset>0xA0</offset>
                <size>1</size>
                <usage>registers</usage>
            </addressBlock>
            <addressBlock>
                <offset>0xA2</offset>
                <size>1</size>
                <usage>registers</usage>
            </addressBlock>
            <addressBlock>
                <offset>0xAA</offset>
                <size>1</size>
                <usage>registers</usage>
            </addressBlock>
            <addressBlock>
                <offset>0xC0</offset>
                <size>2</size>
                <usage>registers</usage>
            </addressBlock>
            <addressBlock>
                <offset>0xE0</offset>
                <size>4</size>
                <usage>registers</usage>
            </addressBlock>
            <addressBlock>
                <offset>0x3C0</offset>
                <size>20</size>
                <usage>registers</usage>
            </addressBlock>
            <addressBlock>
                <offset>0x3E0</offset>
                <size>4</size>
                <usage>registers</usage>
            </addressBlock>
            <addressBlock>
                <offset>0x3FE</offset>
                <size>15</size>
                <usage>registers</usage>
            </addressBlock>
            <addressBlock>
                <offset>0x40E</offset>
                <size>1</size>
                <usage>registers</usage>
            </addressBlock>
            <addressBlock>
                <offset>0x410</offset>
                <size>2</size>
                <usage>registers</usage>
            </addressBlock>
            <addressBlock>
                <offset>0x413</offset>
                <size>1</size>
                <usage>registers</usage>
            </addressBlock>
            <addressBlock>
                <offset>0x416</offset>
                <size>3</size>
                <usage>registers</usage>
            </addressBlock>
            <addressBlock>
                <offset>0x41A</offset>
                <size>2</size>
                <usage>registers</usage>
            </addressBlock>
            <addressBlock>
                <offset>0x41D</offset>
                <size>2</size>
                <usage>registers</usage>
            </addressBlock>
            <addressBlock>
                <offset>0x480</offset>
                <size>2</size>
                <usage>registers</usage>
            </addressBlock>
            <addressBlock>
                <offset>0x490</offset>
                <size>1</size>
                <usage>registers</usage>
            </addressBlock>
            <addressBlock>
                <offset>0x492</offset>
                <size>1</size>
                <usage>registers</usage>
            </addressBlock>
            <addressBlock>
                <offset>0x4BB</offset>
                <size>1</size>
                <usage>registers</usage>
            </addressBlock>
            <addressBlock>
                <offset>0x4C0</offset>
                <size>1</size>
                <usage>registers</usage>
            </addressBlock>
            <addressBlock>
                <offset>0x500</offset>
                <size>128</size>
                <usage>registers</usage>
            </addressBlock>
            <registers>
                <register>
                    <name>SBYCR</name>
                    <description>Standby Control Register</description>
                    <addressOffset>0x00C</addressOffset>
                    <size>16</size>
                    <access>read-write</access>
                    <resetValue>0x4000</resetValue>
                    <resetMask>0xffff</resetMask>
                    <fields>
                        <field>
                            <name>OPE</name>
                            <description>Output Port Enable </description>
                            <lsb>14</lsb>
                            <msb>14</msb>
                            <access>read-write</access>
                            <enumeratedValues>
                                </enumeratedValues>
                        </field>
                        <field>
                            <name>SSBY</name>
                            <description>Software Standby Mode Select</description>
                            <lsb>15</lsb>
                            <msb>15</msb>
                            <access>read-write</access>
                            <enumeratedValues>
                                </enumeratedValues>
                        </field>
                    </fields>
                </register>
                <register>
                    <name>SCKDIVCR</name>
                    <description>System Clock Division Control Register</description>
                    <addressOffset>0x020</addressOffset>
                    <size>32</size>
                    <access>read-write</access>
                    <resetValue>0x22022222</resetValue>
                    <resetMask>0xffffffff</resetMask>
                    <fields>
                        <field>
                            <name>PCKD</name>
                            <description>Peripheral Module Clock D (PCLKD) Select</description>
                            <lsb>0</lsb>
                            <msb>2</msb>
                            <access>read-write</access>
                            <enumeratedValues>
                                </enumeratedValues>
                        </field>
                        <field>
                            <name>PCKC</name>
                            <description>Peripheral Module Clock C (PCLKC) Select</description>
                            <lsb>4</lsb>
                            <msb>6</msb>
                            <access>read-write</access>
                            <enumeratedValues>
                                </enumeratedValues>
                        </field>
                        <field>
                            <name>PCKB</name>
                            <description>Peripheral Module Clock B (PCLKB) Select</description>
                            <lsb>8</lsb>
                            <msb>10</msb>
                            <access>read-write</access>
                            <enumeratedValues>
                                </enumeratedValues>
                        </field>
                        <field>
                            <name>PCKA</name>
                            <description>Peripheral Module Clock A (PCLKA) Select</description>
                            <lsb>12</lsb>
                            <msb>14</msb>
                            <access>read-write</access>
                            <enumeratedValues>
                                </enumeratedValues>
                        </field>
                        <field>
                            <name>ICK</name>
                            <description>System Clock (ICLK) Select</description>
                            <lsb>24</lsb>
                            <msb>26</msb>
                            <access>read-write</access>
                            <enumeratedValues>
                                </enumeratedValues>
                        </field>
                        <field>
                            <name>FCK</name>
                            <description>FlashIF Clock (FCLK) Select</description>
                            <lsb>28</lsb>
                            <msb>30</msb>
                            <access>read-write</access>
                            <enumeratedValues>
                                </enumeratedValues>
                        </field>
                    </fields>
                </register>
                <register>
                    <name>SCKSCR</name>
                    <description>System Clock Source Control Register</description>
                    <addressOffset>0x026</addressOffset>
                    <size>8</size>
                    <access>read-write</access>
                    <resetValue>0x01</resetValue>
                    <resetMask>0xff</resetMask>
                    <fields>
                        <field>
                            <name>CKSEL</name>
                            <description>Clock Source Select</description>
                            <lsb>0</lsb>
                            <msb>2</msb>
                            <access>read-write</access>
                            <enumeratedValues>
                                </enumeratedValues>
                        </field>
                    </fields>
                </register>
                <register>
                    <name>PLLCCR</name>
                    <description>PLL Clock Control Register</description>
                    <addressOffset>0x028</addressOffset>
                    <size>16</size>
                    <access>read-write</access>
                    <resetValue>0x1300</resetValue>
                    <resetMask>0xffff</resetMask>
                    <fields>
                        <field>
                            <name>PLIDIV</name>
                            <description>PLL Input Frequency Division Ratio Select</description>
                            <lsb>0</lsb>
                            <msb>1</msb>
                            <access>read-write</access>
                            <enumeratedValues>
                                </enumeratedValues>
                        </field>
                        <field>
                            <name>PLSRCSEL</name>
                            <description>PLL Clock Source Select</description>
                            <lsb>4</lsb>
                            <msb>4</msb>
                            <access>read-write</access>
                            <enumeratedValues>
                                </enumeratedValues>
                        </field>
                        <field>
                            <name>PLLMUL</name>
                            <description>PLL Frequency Multiplication Factor Select</description>
                            <lsb>8</lsb>
                            <msb>13</msb>
                            <access>read-write</access>
                            <writeConstraint>
                                <range>
                                    <minimum>0x13</minimum>
                                    <maximum>0x3B</maximum>
                                </range>
                            </writeConstraint>
                        </field>
                    </fields>
                </register>
                <register>
                    <name>PLLCR</name>
                    <description>PLL Control Register</description>
                    <addressOffset>0x02A</addressOffset>
                    <size>8</size>
                    <access>read-write</access>
                    <resetValue>0x01</resetValue>
                    <resetMask>0xff</resetMask>
                    <fields>
                        <field>
                            <name>PLLSTP</name>
                            <description>PLL Stop Control</description>
                            <lsb>0</lsb>
                            <msb>0</msb>
                            <access>read-write</access>
                            <enumeratedValues>
                                </enumeratedValues>
                        </field>
                    </fields>
                </register>
                <register>
                    <name>BCKCR</name>
                    <description>External Bus Clock Control Register</description>
                    <addressOffset>0x030</addressOffset>
                    <size>8</size>
                    <access>read-write</access>
                    <resetValue>0x00</resetValue>
                    <resetMask>0xff</resetMask>
                    <fields>
                        <field>
                            <name>BCLKDIV</name>
                            <description>BCLK Pin Output Select</description>
                            <lsb>0</lsb>
                            <msb>0</msb>
                            <access>read-write</access>
                            <enumeratedValues>
                                </enumeratedValues>
                        </field>
                    </fields>
                </register>
                <register>
                    <name>MOSCCR</name>
                    <description>Main Clock Oscillator Control Register</description>
                    <addressOffset>0x032</addressOffset>
                    <size>8</size>
                    <access>read-write</access>
                    <resetValue>0x01</resetValue>
                    <resetMask>0xff</resetMask>
                    <fields>
                        <field>
                            <name>MOSTP</name>
                            <description>Main Clock Oscillator Stop</description>
                            <lsb>0</lsb>
                            <msb>0</msb>
                            <access>read-write</access>
                            <enumeratedValues>
                                </enumeratedValues>
                        </field>
                    </fields>
                </register>
                <register>
                    <name>HOCOCR</name>
                    <description>High,Speed On,Chip Oscillator Control Register</description>
                    <addressOffset>0x036</addressOffset>
                    <size>8</size>
                    <access>read-write</access>
                    <resetValue>0x00</resetValue>
                    <resetMask>0xfe</resetMask>
                    <fields>
                        <field>
                            <name>HCSTP</name>
                            <description>HOCO Stop</description>
                            <lsb>0</lsb>
                            <msb>0</msb>
                            <access>read-write</access>
                            <enumeratedValues>
                                </enumeratedValues>
                        </field>
                    </fields>
                </register>
                <register>
                    <name>MOCOCR</name>
                    <description>Middle,Speed On,Chip Oscillator Control Register</description>
                    <addressOffset>0x038</addressOffset>
                    <size>8</size>
                    <access>read-write</access>
                    <resetValue>0x00</resetValue>
                    <resetMask>0xff</resetMask>
                    <fields>
                        <field>
                            <name>MCSTP</name>
                            <description>MOCO Stop</description>
                            <lsb>0</lsb>
                            <msb>0</msb>
                            <access>read-write</access>
                            <enumeratedValues>
                                </enumeratedValues>
                        </field>
                    </fields>
                </register>
                <register>
                    <name>FLLCR1</name>
                    <description>FLL Control Register1</description>
                    <addressOffset>0x039</addressOffset>
                    <size>8</size>
                    <access>read-write</access>
                    <resetValue>0x00</resetValue>
                    <resetMask>0xff</resetMask>
                    <fields>
                        <field>
                            <name>FLLEN</name>
                            <description>FLL Enable</description>
                            <lsb>0</lsb>
                            <msb>0</msb>
                            <access>read-write</access>
                            <enumeratedValues>
                                </enumeratedValues>
                        </field>
                    </fields>
                </register>
                <register>
                    <name>FLLCR2</name>
                    <description>FLL Control Register2</description>
                    <addressOffset>0x03A</addressOffset>
                    <size>16</size>
                    <access>read-write</access>
                    <resetValue>0x0000</resetValue>
                    <resetMask>0xffff</resetMask>
                    <fields>
                        <field>
                            <name>FLLCNTL</name>
                            <description>FLL Multiplication Control</description>
                            <lsb>0</lsb>
                            <msb>10</msb>
                            <access>read-write</access>
                        </field>
                    </fields>
                </register>
                <register>
                    <name>OSCSF</name>
                    <description>Oscillation Stabilization Flag Register</description>
                    <addressOffset>0x03C</addressOffset>
                    <size>8</size>
                    <access>read-only</access>
                    <resetValue>0x00</resetValue>
                    <resetMask>0xfe</resetMask>
                    <fields>
                        <field>
                            <name>HOCOSF</name>
                            <description>HOCO Clock Oscillation Stabilization Flag</description>
                            <lsb>0</lsb>
                            <msb>0</msb>
                            <access>read-only</access>
                            <enumeratedValues>
                                </enumeratedValues>
                        </field>
                        <field>
                            <name>MOSCSF</name>
                            <description>Main Clock Oscillation Stabilization Flag</description>
                            <lsb>3</lsb>
                            <msb>3</msb>
                            <access>read-only</access>
                            <enumeratedValues>
                                </enumeratedValues>
                        </field>
                        <field>
                            <name>PLLSF</name>
                            <description>PLL Clock Oscillation Stabilization Flag</description>
                            <lsb>5</lsb>
                            <msb>5</msb>
                            <access>read-only</access>
                            <enumeratedValues>
                                </enumeratedValues>
                        </field>
                        <field>
                            <name>PLL2SF</name>
                            <description>PLL2 Clock Oscillation Stabilization Flag</description>
                            <lsb>6</lsb>
                            <msb>6</msb>
                            <access>read-only</access>
                            <enumeratedValues>
                                </enumeratedValues>
                        </field>
                    </fields>
                </register>
                <register>
                    <name>CKOCR</name>
                    <description>Clock Out Control Register</description>
                    <addressOffset>0x03E</addressOffset>
                    <size>8</size>
                    <access>read-write</access>
                    <resetValue>0x00</resetValue>
                    <resetMask>0xff</resetMask>
                    <fields>
                        <field>
                            <name>CKOSEL</name>
                            <description>Clock Out Source Select</description>
                            <lsb>0</lsb>
                            <msb>2</msb>
                            <access>read-write</access>
                            <enumeratedValues>
                                </enumeratedValues>
                        </field>
                        <field>
                            <name>CKODIV</name>
                            <description>Clock Output Frequency Division Ratio</description>
                            <lsb>4</lsb>
                            <msb>6</msb>
                            <access>read-write</access>
                            <enumeratedValues>
                                </enumeratedValues>
                        </field>
                        <field>
                            <name>CKOEN</name>
                            <description>Clock Out Enable</description>
                            <lsb>7</lsb>
                            <msb>7</msb>
                            <access>read-write</access>
                            <enumeratedValues>
                                </enumeratedValues>
                        </field>
                    </fields>
                </register>
                <register>
                    <name>TRCKCR</name>
                    <description>Trace Clock Control Register</description>
                    <addressOffset>0x03F</addressOffset>
                    <size>8</size>
                    <access>read-write</access>
                    <resetValue>0x01</resetValue>
                    <resetMask>0xff</resetMask>
                    <fields>
                        <field>
                            <name>TRCK</name>
                            <description>Trace Clock operating frequency select</description>
                            <lsb>0</lsb>
                            <msb>3</msb>
                            <access>read-write</access>
                            <enumeratedValues>
                                </enumeratedValues>
                        </field>
                        <field>
                            <name>TRCKEN</name>
                            <description>Trace Clock operating Enable</description>
                            <lsb>7</lsb>
                            <msb>7</msb>
                            <access>read-write</access>
                            <enumeratedValues>
                                </enumeratedValues>
                        </field>
                    </fields>
                </register>
                <register>
                    <name>OSTDCR</name>
                    <description>Oscillation Stop Detection Control Register</description>
                    <addressOffset>0x040</addressOffset>
                    <size>8</size>
                    <access>read-write</access>
                    <resetValue>0x00</resetValue>
                    <resetMask>0xff</resetMask>
                    <fields>
                        <field>
                            <name>OSTDIE</name>
                            <description>Oscillation Stop Detection Interrupt Enable</description>
                            <lsb>0</lsb>
                            <msb>0</msb>
                            <access>read-write</access>
                            <enumeratedValues>
                                </enumeratedValues>
                        </field>
                        <field>
                            <name>OSTDE</name>
                            <description>Oscillation Stop Detection Function Enable</description>
                            <lsb>7</lsb>
                            <msb>7</msb>
                            <access>read-write</access>
                            <enumeratedValues>
                                </enumeratedValues>
                        </field>
                    </fields>
                </register>
                <register>
                    <name>OSTDSR</name>
                    <description>Oscillation Stop Detection Status Register</description>
                    <addressOffset>0x041</addressOffset>
                    <size>8</size>
                    <access>read-write</access>
                    <resetValue>0x00</resetValue>
                    <resetMask>0xff</resetMask>
                    <fields>
                        <field>
                            <name>OSTDF</name>
                            <description>Oscillation Stop Detection Flag</description>
                            <lsb>0</lsb>
                            <msb>0</msb>
                            <access>read-write</access>
                            <enumeratedValues>
                                </enumeratedValues>
                        </field>
                    </fields>
                </register>
                <register>
                    <name>PLL2CCR</name>
                    <description>PLL2 Clock Control Register</description>
                    <addressOffset>0x048</addressOffset>
                    <size>16</size>
                    <access>read-write</access>
                    <resetValue>0x1300</resetValue>
                    <resetMask>0xffff</resetMask>
                    <fields>
                        <field>
                            <name>PL2IDIV</name>
                            <description>PLL2 Input Frequency Division Ratio Select</description>
                            <lsb>0</lsb>
                            <msb>1</msb>
                            <access>read-write</access>
                            <enumeratedValues>
                                </enumeratedValues>
                        </field>
                        <field>
                            <name>PL2SRCSEL</name>
                            <description>PLL2 Clock Source Select</description>
                            <lsb>4</lsb>
                            <msb>4</msb>
                            <access>read-write</access>
                            <enumeratedValues>
                                </enumeratedValues>
                        </field>
                        <field>
                            <name>PLL2MUL</name>
                            <description>PLL2 Frequency Multiplication Factor Select</description>
                            <lsb>8</lsb>
                            <msb>13</msb>
                            <access>read-write</access>
                        </field>
                    </fields>
                </register>
                <register>
                    <name>PLL2CR</name>
                    <description>PLL2 Control Register</description>
                    <addressOffset>0x04A</addressOffset>
                    <size>8</size>
                    <access>read-write</access>
                    <resetValue>0x01</resetValue>
                    <resetMask>0xff</resetMask>
                    <fields>
                        <field>
                            <name>PLL2STP</name>
                            <description>PLL2 Stop Control</description>
                            <lsb>0</lsb>
                            <msb>0</msb>
                            <access>read-write</access>
                            <enumeratedValues>
                                </enumeratedValues>
                        </field>
                    </fields>
                </register>
                <register>
                    <name>EBCKOCR</name>
                    <description>External Bus Clock Output Control Register</description>
                    <addressOffset>0x052</addressOffset>
                    <size>8</size>
                    <access>read-write</access>
                    <resetValue>0x00</resetValue>
                    <resetMask>0xff</resetMask>
                    <fields>
                        <field>
                            <name>EBCKOEN</name>
                            <description>EBCLK Pin Output Control</description>
                            <lsb>0</lsb>
                            <msb>0</msb>
                            <access>read-write</access>
                            <enumeratedValues>
                                </enumeratedValues>
                        </field>
                    </fields>
                </register>
                <register>
                    <name>MOCOUTCR</name>
                    <description>MOCO User Trimming Control Register</description>
                    <addressOffset>0x061</addressOffset>
                    <size>8</size>
                    <access>read-write</access>
                    <resetValue>0x00</resetValue>
                    <resetMask>0xff</resetMask>
                    <fields>
                        <field>
                            <name>MOCOUTRM</name>
                            <description>MOCO User Trimming</description>
                            <lsb>0</lsb>
                            <msb>7</msb>
                            <access>read-write</access>
                        </field>
                    </fields>
                </register>
                <register>
                    <name>HOCOUTCR</name>
                    <description>HOCO User Trimming Control Register</description>
                    <addressOffset>0x062</addressOffset>
                    <size>8</size>
                    <access>read-write</access>
                    <resetValue>0x00</resetValue>
                    <resetMask>0xff</resetMask>
                    <fields>
                        <field>
                            <name>HOCOUTRM</name>
                            <description>HOCO User Trimming</description>
                            <lsb>0</lsb>
                            <msb>7</msb>
                            <access>read-write</access>
                        </field>
                    </fields>
                </register>
                <register>
                    <name>USBCKDIVCR</name>
                    <description>USB Clock Division Control Register</description>
                    <addressOffset>0x06C</addressOffset>
                    <size>8</size>
                    <access>read-write</access>
                    <resetValue>0x00</resetValue>
                    <resetMask>0xff</resetMask>
                    <fields>
                        <field>
                            <name>USBCKDIV</name>
                            <description>USB Clock (USBCLK) Division Select</description>
                            <lsb>0</lsb>
                            <msb>2</msb>
                            <access>read-write</access>
                            <enumeratedValues>
                                </enumeratedValues>
                        </field>
                    </fields>
                </register>
                <register>
                    <name>OCTACKDIVCR</name>
                    <description>Octal,SPI Clock Division Control Register</description>
                    <addressOffset>0x06D</addressOffset>
                    <size>8</size>
                    <access>read-write</access>
                    <resetValue>0x00</resetValue>
                    <resetMask>0xff</resetMask>
                    <fields>
                        <field>
                            <name>OCTACKDIV</name>
                            <description>Octal,SPI Clock (OCTACLK) Division Select</description>
                            <lsb>0</lsb>
                            <msb>2</msb>
                            <access>read-write</access>
                            <enumeratedValues>
                                </enumeratedValues>
                        </field>
                    </fields>
                </register>
                <register>
                    <name>CANFDCKDIVCR</name>
                    <description>CANFD Clock Division Control Register</description>
                    <addressOffset>0x06E</addressOffset>
                    <size>8</size>
                    <access>read-write</access>
                    <resetValue>0x00</resetValue>
                    <resetMask>0xff</resetMask>
                    <fields>
                        <field>
                            <name>CANFDCKDIV</name>
                            <description>CANFD clock (CANFDCLK) Division Select</description>
                            <lsb>0</lsb>
                            <msb>2</msb>
                            <access>read-write</access>
                            <enumeratedValues>
                                </enumeratedValues>
                        </field>
                    </fields>
                </register>
                <register>
                    <name>USB60CKDIVCR</name>
                    <description>USB60 Clock Division Control Register</description>
                    <addressOffset>0x06F</addressOffset>
                    <size>8</size>
                    <access>read-write</access>
                    <resetValue>0x00</resetValue>
                    <resetMask>0xff</resetMask>
                    <fields>
                        <field>
                            <name>USB60CKDIV</name>
                            <description>USB clock (USB60CLK) Division Select</description>
                            <lsb>0</lsb>
                            <msb>2</msb>
                            <access>read-write</access>
                            <enumeratedValues>
                                </enumeratedValues>
                        </field>
                    </fields>
                </register>
                <register>
                    <name>CECCKDIVCR</name>
                    <description>CEC Clock Division Control Register</description>
                    <addressOffset>0x070</addressOffset>
                    <size>8</size>
                    <access>read-write</access>
                    <resetValue>0x01</resetValue>
                    <resetMask>0xff</resetMask>
                    <fields>
                        <field>
                            <name>CECCKDIV</name>
                            <description>CEC clock (CECCLK) Division Select</description>
                            <lsb>0</lsb>
                            <msb>2</msb>
                            <access>read-write</access>
                            <enumeratedValues>
                                </enumeratedValues>
                        </field>
                    </fields>
                </register>
                <register>
                    <name>USBCKCR</name>
                    <description>USB Clock Control Register</description>
                    <addressOffset>0x074</addressOffset>
                    <size>8</size>
                    <access>read-write</access>
                    <resetValue>0x01</resetValue>
                    <resetMask>0xff</resetMask>
                    <fields>
                        <field>
                            <name>USBCKSEL</name>
                            <description>USB Clock (USBCLK) Source Select</description>
                            <lsb>0</lsb>
                            <msb>2</msb>
                            <access>read-write</access>
                            <enumeratedValues>
                                </enumeratedValues>
                        </field>
                        <field>
                            <name>USBCKSREQ</name>
                            <description>USB Clock (USBCLK) Switching Request</description>
                            <lsb>6</lsb>
                            <msb>6</msb>
                            <access>read-write</access>
                            <enumeratedValues>
                                </enumeratedValues>
                        </field>
                        <field>
                            <name>USBCKSRDY</name>
                            <description>USB Clock (USBCLK) Switching Ready state flag</description>
                            <lsb>7</lsb>
                            <msb>7</msb>
                            <access>read-only</access>
                            <enumeratedValues>
                                </enumeratedValues>
                        </field>
                    </fields>
                </register>
                <register>
                    <name>OCTACKCR</name>
                    <description>Octal,SPI Clock Control Register</description>
                    <addressOffset>0x075</addressOffset>
                    <size>8</size>
                    <access>read-write</access>
                    <resetValue>0x01</resetValue>
                    <resetMask>0xff</resetMask>
                    <fields>
                        <field>
                            <name>OCTACKSEL</name>
                            <description>Octal,SPI Clock (OCTACLK) Source Select</description>
                            <lsb>0</lsb>
                            <msb>2</msb>
                            <access>read-write</access>
                            <enumeratedValues>
                                </enumeratedValues>
                        </field>
                        <field>
                            <name>OCTACKSREQ</name>
                            <description>Octal,SPI Clock (OCTACLK) Switching Request</description>
                            <lsb>6</lsb>
                            <msb>6</msb>
                            <access>read-write</access>
                            <enumeratedValues>
                                </enumeratedValues>
                        </field>
                        <field>
                            <name>OCTACKSRDY</name>
                            <description>Octal,SPI Clock (OCTACLK) Switching Ready state flag</description>
                            <lsb>7</lsb>
                            <msb>7</msb>
                            <access>read-only</access>
                            <enumeratedValues>
                                </enumeratedValues>
                        </field>
                    </fields>
                </register>
                <register>
                    <name>CANFDCKCR</name>
                    <description>CANFD Clock Control Register</description>
                    <addressOffset>0x076</addressOffset>
                    <size>8</size>
                    <access>read-write</access>
                    <resetValue>0x01</resetValue>
                    <resetMask>0xff</resetMask>
                    <fields>
                        <field>
                            <name>CANFDCKSEL</name>
                            <description>CANFD clock (CANFDCLK) Source Select</description>
                            <lsb>0</lsb>
                            <msb>2</msb>
                            <access>read-write</access>
                            <enumeratedValues>
                                </enumeratedValues>
                        </field>
                        <field>
                            <name>CANFDCKSREQ</name>
                            <description>CANFD clock (CANFDCLK) Switching Request</description>
                            <lsb>6</lsb>
                            <msb>6</msb>
                            <access>read-write</access>
                            <enumeratedValues>
                                </enumeratedValues>
                        </field>
                        <field>
                            <name>CANFDCKSRDY</name>
                            <description>CANFD clock (CANFDCLK) Switching Ready state flag</description>
                            <lsb>7</lsb>
                            <msb>7</msb>
                            <access>read-only</access>
                            <enumeratedValues>
                                </enumeratedValues>
                        </field>
                    </fields>
                </register>
                <register>
                    <name>USB60CKCR</name>
                    <description>USB60 Clock Control Register</description>
                    <addressOffset>0x077</addressOffset>
                    <size>8</size>
                    <access>read-write</access>
                    <resetValue>0x01</resetValue>
                    <resetMask>0xff</resetMask>
                    <fields>
                        <field>
                            <name>USB60CKSEL</name>
                            <description>USB clock (USB60CLK) Source Select</description>
                            <lsb>0</lsb>
                            <msb>2</msb>
                            <access>read-write</access>
                            <enumeratedValues>
                                </enumeratedValues>
                        </field>
                        <field>
                            <name>USB60CKSREQ</name>
                            <description>USB clock (USB60CLK) Switching Request</description>
                            <lsb>6</lsb>
                            <msb>6</msb>
                            <access>read-write</access>
                            <enumeratedValues>
                                </enumeratedValues>
                        </field>
                        <field>
                            <name>USB60CKSRDY</name>
                            <description>USB clock (USB60CLK) Switching Ready state flag</description>
                            <lsb>7</lsb>
                            <msb>7</msb>
                            <access>read-only</access>
                            <enumeratedValues>
                                </enumeratedValues>
                        </field>
                    </fields>
                </register>
                <register>
                    <name>CECCKCR</name>
                    <description>CEC Clock Control Register</description>
                    <addressOffset>0x078</addressOffset>
                    <size>8</size>
                    <access>read-write</access>
                    <resetValue>0x01</resetValue>
                    <resetMask>0xff</resetMask>
                    <fields>
                        <field>
                            <name>CECCKSEL</name>
                            <description>CEC clock (CECCLK) Source Select</description>
                            <lsb>0</lsb>
                            <msb>2</msb>
                            <access>read-write</access>
                            <enumeratedValues>
                                </enumeratedValues>
                        </field>
                        <field>
                            <name>CECCKSREQ</name>
                            <description>CEC clock (CECCLK) Switching Request</description>
                            <lsb>6</lsb>
                            <msb>6</msb>
                            <access>read-write</access>
                            <enumeratedValues>
                                </enumeratedValues>
                        </field>
                        <field>
                            <name>CECCKSRDY</name>
                            <description>CEC clock (CECCLK) Switching Ready state flag</description>
                            <lsb>7</lsb>
                            <msb>7</msb>
                            <access>read-only</access>
                            <enumeratedValues>
                                </enumeratedValues>
                        </field>
                    </fields>
                </register>
                <register>
                    <name>SNZREQCR1</name>
                    <description>Snooze Request Control Register 1</description>
                    <addressOffset>0x088</addressOffset>
                    <size>32</size>
                    <access>read-write</access>
                    <resetValue>0x00000000</resetValue>
                    <resetMask>0xffffffff</resetMask>
                    <fields>
                        <field>
                            <name>SNZREQEN0</name>
                            <description>Enable AGT3 underflow snooze request</description>
                            <lsb>0</lsb>
                            <msb>0</msb>
                            <access>read-write</access>
                            <enumeratedValues>
                                </enumeratedValues>
                        </field>
                        <field>
                            <name>SNZREQEN1</name>
                            <description>Enable AGT3 compare match A snooze request</description>
                            <lsb>1</lsb>
                            <msb>1</msb>
                            <access>read-write</access>
                            <enumeratedValues>
                                </enumeratedValues>
                        </field>
                        <field>
                            <name>SNZREQEN2</name>
                            <description>Enable AGT3 compare match B snooze request</description>
                            <lsb>2</lsb>
                            <msb>2</msb>
                            <access>read-write</access>
                            <enumeratedValues>
                                </enumeratedValues>
                        </field>
                    </fields>
                </register>
                <register>
                    <name>SNZCR</name>
                    <description>Snooze Control Register</description>
                    <addressOffset>0x092</addressOffset>
                    <size>8</size>
                    <access>read-write</access>
                    <resetValue>0x00</resetValue>
                    <resetMask>0xff</resetMask>
                    <fields>
                        <field>
                            <name>RXDREQEN</name>
                            <description>RXD0 Snooze Request Enable</description>
                            <lsb>0</lsb>
                            <msb>0</msb>
                            <access>read-write</access>
                            <enumeratedValues>
                                </enumeratedValues>
                        </field>
                        <field>
                            <name>SNZDTCEN</name>
                            <description>DTC Enable in Snooze mode</description>
                            <lsb>1</lsb>
                            <msb>1</msb>
                            <access>read-write</access>
                            <enumeratedValues>
                                </enumeratedValues>
                        </field>
                        <field>
                            <name>SNZE</name>
                            <description>Snooze mode Enable</description>
                            <lsb>7</lsb>
                            <msb>7</msb>
                            <access>read-write</access>
                            <enumeratedValues>
                                </enumeratedValues>
                        </field>
                    </fields>
                </register>
                <register>
                    <name>SNZEDCR0</name>
                    <description>Snooze End Control Register 0</description>
                    <addressOffset>0x094</addressOffset>
                    <size>8</size>
                    <access>read-write</access>
                    <resetValue>0x00</resetValue>
                    <resetMask>0xff</resetMask>
                    <fields>
                        <field>
                            <name>AGTUNFED</name>
                            <description>AGT1 Underflow Snooze End Enable</description>
                            <lsb>0</lsb>
                            <msb>0</msb>
                            <access>read-write</access>
                            <enumeratedValues>
                                </enumeratedValues>
                        </field>
                        <field>
                            <name>DTCZRED</name>
                            <description>Last DTC Transmission Completion Snooze End Enable</description>
                            <lsb>1</lsb>
                            <msb>1</msb>
                            <access>read-write</access>
                            <enumeratedValues>
                                </enumeratedValues>
                        </field>
                        <field>
                            <name>DTCNZRED</name>
                            <description>Not Last DTC Transmission Completion Snooze End Enable</description>
                            <lsb>2</lsb>
                            <msb>2</msb>
                            <access>read-write</access>
                            <enumeratedValues>
                                </enumeratedValues>
                        </field>
                        <field>
                            <name>AD0MATED</name>
                            <description>ADC120 Compare Match Snooze End Enable</description>
                            <lsb>3</lsb>
                            <msb>3</msb>
                            <access>read-write</access>
                            <enumeratedValues>
                                </enumeratedValues>
                        </field>
                        <field>
                            <name>AD0UMTED</name>
                            <description>ADC120 Compare Mismatch Snooze End Enable</description>
                            <lsb>4</lsb>
                            <msb>4</msb>
                            <access>read-write</access>
                            <enumeratedValues>
                                </enumeratedValues>
                        </field>
                        <field>
                            <name>AD1MATED</name>
                            <description>ADC121 Compare Match Snooze End Enable</description>
                            <lsb>5</lsb>
                            <msb>5</msb>
                            <access>read-write</access>
                            <enumeratedValues>
                                </enumeratedValues>
                        </field>
                        <field>
                            <name>AD1UMTED</name>
                            <description>ADC121 Compare Mismatch Snooze End Enable</description>
                            <lsb>6</lsb>
                            <msb>6</msb>
                            <access>read-write</access>
                            <enumeratedValues>
                                </enumeratedValues>
                        </field>
                        <field>
                            <name>SCI0UMTED</name>
                            <description>SCI0 Address Mismatch Snooze End Enable</description>
                            <lsb>7</lsb>
                            <msb>7</msb>
                            <access>read-write</access>
                            <enumeratedValues>
                                </enumeratedValues>
                        </field>
                    </fields>
                </register>
                <register>
                    <name>SNZEDCR1</name>
                    <description>Snooze End Control Register 1</description>
                    <addressOffset>0x095</addressOffset>
                    <size>8</size>
                    <access>read-write</access>
                    <resetValue>0x00</resetValue>
                    <resetMask>0xff</resetMask>
                    <fields>
                        <field>
                            <name>AGT3UNFED</name>
                            <description>AGT3 underflow Snooze End Enable</description>
                            <lsb>0</lsb>
                            <msb>0</msb>
                            <access>read-write</access>
                            <enumeratedValues>
                                </enumeratedValues>
                        </field>
                    </fields>
                </register>
                <register>
                    <name>SNZREQCR0</name>
                    <description>Snooze Request Control Register 0</description>
                    <addressOffset>0x098</addressOffset>
                    <size>32</size>
                    <access>read-write</access>
                    <resetValue>0x00000000</resetValue>
                    <resetMask>0xffffffff</resetMask>
                    <fields>
                        <field>
                            <name>SNZREQEN0</name>
                            <description>Enable IRQ0 pin snooze request</description>
                            <lsb>0</lsb>
                            <msb>0</msb>
                            <access>read-write</access>
                            <enumeratedValues>
                                </enumeratedValues>
                        </field>
                        <field>
                            <name>SNZREQEN1</name>
                            <description>Enable IRQ1 pin snooze request</description>
                            <lsb>1</lsb>
                            <msb>1</msb>
                            <access>read-write</access>
                            <enumeratedValues>
                                </enumeratedValues>
                        </field>
                        <field>
                            <name>SNZREQEN2</name>
                            <description>Enable IRQ2 pin snooze request</description>
                            <lsb>2</lsb>
                            <msb>2</msb>
                            <access>read-write</access>
                            <enumeratedValues>
                                </enumeratedValues>
                        </field>
                        <field>
                            <name>SNZREQEN3</name>
                            <description>Enable IRQ3 pin snooze request</description>
                            <lsb>3</lsb>
                            <msb>3</msb>
                            <access>read-write</access>
                            <enumeratedValues>
                                </enumeratedValues>
                        </field>
                        <field>
                            <name>SNZREQEN4</name>
                            <description>Enable IRQ4 pin snooze request</description>
                            <lsb>4</lsb>
                            <msb>4</msb>
                            <access>read-write</access>
                            <enumeratedValues>
                                </enumeratedValues>
                        </field>
                        <field>
                            <name>SNZREQEN5</name>
                            <description>Enable IRQ5 pin snooze request</description>
                            <lsb>5</lsb>
                            <msb>5</msb>
                            <access>read-write</access>
                            <enumeratedValues>
                                </enumeratedValues>
                        </field>
                        <field>
                            <name>SNZREQEN6</name>
                            <description>Enable IRQ6 pin snooze request</description>
                            <lsb>6</lsb>
                            <msb>6</msb>
                            <access>read-write</access>
                            <enumeratedValues>
                                </enumeratedValues>
                        </field>
                        <field>
                            <name>SNZREQEN7</name>
                            <description>Enable IRQ7 pin snooze request</description>
                            <lsb>7</lsb>
                            <msb>7</msb>
                            <access>read-write</access>
                            <enumeratedValues>
                                </enumeratedValues>
                        </field>
                        <field>
                            <name>SNZREQEN8</name>
                            <description>Enable IRQ8 pin snooze request</description>
                            <lsb>8</lsb>
                            <msb>8</msb>
                            <access>read-write</access>
                            <enumeratedValues>
                                </enumeratedValues>
                        </field>
                        <field>
                            <name>SNZREQEN9</name>
                            <description>Enable IRQ9 pin snooze request</description>
                            <lsb>9</lsb>
                            <msb>9</msb>
                            <access>read-write</access>
                            <enumeratedValues>
                                </enumeratedValues>
                        </field>
                        <field>
                            <name>SNZREQEN10</name>
                            <description>Enable IRQ10 pin snooze request</description>
                            <lsb>10</lsb>
                            <msb>10</msb>
                            <access>read-write</access>
                            <enumeratedValues>
                                </enumeratedValues>
                        </field>
                        <field>
                            <name>SNZREQEN11</name>
                            <description>Enable IRQ11 pin snooze request</description>
                            <lsb>11</lsb>
                            <msb>11</msb>
                            <access>read-write</access>
                            <enumeratedValues>
                                </enumeratedValues>
                        </field>
                        <field>
                            <name>SNZREQEN12</name>
                            <description>Enable IRQ12 pin snooze request</description>
                            <lsb>12</lsb>
                            <msb>12</msb>
                            <access>read-write</access>
                            <enumeratedValues>
                                </enumeratedValues>
                        </field>
                        <field>
                            <name>SNZREQEN13</name>
                            <description>Enable IRQ13 pin snooze request</description>
                            <lsb>13</lsb>
                            <msb>13</msb>
                            <access>read-write</access>
                            <enumeratedValues>
                                </enumeratedValues>
                        </field>
                        <field>
                            <name>SNZREQEN14</name>
                            <description>Enable IRQ14 pin snooze request</description>
                            <lsb>14</lsb>
                            <msb>14</msb>
                            <access>read-write</access>
                            <enumeratedValues>
                                </enumeratedValues>
                        </field>
                        <field>
                            <name>SNZREQEN15</name>
                            <description>Enable IRQ15 pin snooze request</description>
                            <lsb>15</lsb>
                            <msb>15</msb>
                            <access>read-write</access>
                            <enumeratedValues>
                                </enumeratedValues>
                        </field>
                        <field>
                            <name>SNZREQEN24</name>
                            <description>Enable RTC alarm snooze request</description>
                            <lsb>24</lsb>
                            <msb>24</msb>
                            <access>read-write</access>
                            <enumeratedValues>
                                </enumeratedValues>
                        </field>
                        <field>
                            <name>SNZREQEN25</name>
                            <description>Enable RTC period snooze request</description>
                            <lsb>25</lsb>
                            <msb>25</msb>
                            <access>read-write</access>
                            <enumeratedValues>
                                </enumeratedValues>
                        </field>
                        <field>
                            <name>SNZREQEN28</name>
                            <description>Enable AGT1 underflow snooze request</description>
                            <lsb>28</lsb>
                            <msb>28</msb>
                            <access>read-write</access>
                            <enumeratedValues>
                                </enumeratedValues>
                        </field>
                        <field>
                            <name>SNZREQEN29</name>
                            <description>Enable AGT1 compare match A snooze request</description>
                            <lsb>29</lsb>
                            <msb>29</msb>
                            <access>read-write</access>
                            <enumeratedValues>
                                </enumeratedValues>
                        </field>
                        <field>
                            <name>SNZREQEN30</name>
                            <description>Enable AGT1 compare match B snooze request</description>
                            <lsb>30</lsb>
                            <msb>30</msb>
                            <access>read-write</access>
                            <enumeratedValues>
                                </enumeratedValues>
                        </field>
                    </fields>
                </register>
                <register>
                    <name>OPCCR</name>
                    <description>Operating Power Control Register</description>
                    <addressOffset>0x0A0</addressOffset>
                    <size>8</size>
                    <access>read-write</access>
                    <resetValue>0x00</resetValue>
                    <resetMask>0xff</resetMask>
                    <fields>
                        <field>
                            <name>OPCM</name>
                            <description>Operating Power Control Mode Select</description>
                            <lsb>0</lsb>
                            <msb>1</msb>
                            <access>read-write</access>
                            <enumeratedValues>
                                </enumeratedValues>
                        </field>
                        <field>
                            <name>OPCMTSF</name>
                            <description>Operating Power Control Mode Transition Status Flag</description>
                            <lsb>4</lsb>
                            <msb>4</msb>
                            <access>read-only</access>
                            <enumeratedValues>
                                </enumeratedValues>
                        </field>
                    </fields>
                </register>
                <register>
                    <name>MOSCWTCR</name>
                    <description>Main Clock Oscillator Wait Control Register</description>
                    <addressOffset>0x0A2</addressOffset>
                    <size>8</size>
                    <access>read-write</access>
                    <resetValue>0x05</resetValue>
                    <resetMask>0xff</resetMask>
                    <fields>
                        <field>
                            <name>MSTS</name>
                            <description>Main Clock Oscillator Wait Time Setting</description>
                            <lsb>0</lsb>
                            <msb>3</msb>
                            <access>read-write</access>
                            <enumeratedValues>
                                </enumeratedValues>
                        </field>
                    </fields>
                </register>
                <register>
                    <name>SOPCCR</name>
                    <description>Sub Operating Power Control Register</description>
                    <addressOffset>0x0AA</addressOffset>
                    <size>8</size>
                    <access>read-write</access>
                    <resetValue>0x00</resetValue>
                    <resetMask>0xff</resetMask>
                    <fields>
                        <field>
                            <name>SOPCM</name>
                            <description>Sub Operating Power Control Mode Select</description>
                            <lsb>0</lsb>
                            <msb>0</msb>
                            <access>read-write</access>
                            <enumeratedValues>
                                </enumeratedValues>
                        </field>
                        <field>
                            <name>SOPCMTSF</name>
                            <description>Operating Power Control Mode Transition Status Flag</description>
                            <lsb>4</lsb>
                            <msb>4</msb>
                            <access>read-only</access>
                            <enumeratedValues>
                                </enumeratedValues>
                        </field>
                    </fields>
                </register>
                <register>
                    <name>RSTSR1</name>
                    <description>Reset Status Register 1</description>
                    <addressOffset>0x0C0</addressOffset>
                    <size>16</size>
                    <access>read-write</access>
                    <resetValue>0x0000</resetValue>
                    <resetMask>0x54f8</resetMask>
                    <fields>
                        <field>
                            <name>IWDTRF</name>
                            <description>Independent Watchdog Timer Reset Detect Flag</description>
                            <lsb>0</lsb>
                            <msb>0</msb>
                            <access>read-write</access>
                            <enumeratedValues>
                                </enumeratedValues>
                        </field>
                        <field>
                            <name>WDTRF</name>
                            <description>Watchdog Timer Reset Detect Flag</description>
                            <lsb>1</lsb>
                            <msb>1</msb>
                            <access>read-write</access>
                            <enumeratedValues>
                                </enumeratedValues>
                        </field>
                        <field>
                            <name>SWRF</name>
                            <description>Software Reset Detect Flag</description>
                            <lsb>2</lsb>
                            <msb>2</msb>
                            <access>read-write</access>
                            <enumeratedValues>
                                </enumeratedValues>
                        </field>
                        <field>
                            <name>RPERF</name>
                            <description>SRAM Parity Error Reset Detect Flag</description>
                            <lsb>8</lsb>
                            <msb>8</msb>
                            <access>read-write</access>
                            <enumeratedValues>
                                </enumeratedValues>
                        </field>
                        <field>
                            <name>REERF</name>
                            <description>SRAM ECC Error Reset Detect Flag</description>
                            <lsb>9</lsb>
                            <msb>9</msb>
                            <access>read-write</access>
                            <enumeratedValues>
                                </enumeratedValues>
                        </field>
                        <field>
                            <name>BUSMRF</name>
                            <description>Bus Master MPU Error Reset Detect Flag</description>
                            <lsb>11</lsb>
                            <msb>11</msb>
                            <access>read-write</access>
                            <enumeratedValues>
                                </enumeratedValues>
                        </field>
                        <field>
                            <name>TZERF</name>
                            <description>TrustZone Error Reset Detect Flag</description>
                            <lsb>13</lsb>
                            <msb>13</msb>
                            <access>read-write</access>
                            <enumeratedValues>
                                </enumeratedValues>
                        </field>
                        <field>
                            <name>CPERF</name>
                            <description>Cache Parity Error Reset Detect Flag</description>
                            <lsb>15</lsb>
                            <msb>15</msb>
                            <access>read-write</access>
                            <enumeratedValues>
                                </enumeratedValues>
                        </field>
                    </fields>
                </register>
                <register>
                    <name>LVD1CR1</name>
                    <description>Voltage Monitor 1 Circuit Control Register</description>
                    <addressOffset>0x0E0</addressOffset>
                    <size>8</size>
                    <access>read-write</access>
                    <resetValue>0x01</resetValue>
                    <resetMask>0xff</resetMask>
                    <fields>
                        <field>
                            <name>IDTSEL</name>
                            <description>Voltage Monitor 1 Interrupt Generation Condition Select</description>
                            <lsb>0</lsb>
                            <msb>1</msb>
                            <access>read-write</access>
                            <enumeratedValues>
                                </enumeratedValues>
                        </field>
                        <field>
                            <name>IRQSEL</name>
                            <description>Voltage Monitor 1 Interrupt Type Select</description>
                            <lsb>2</lsb>
                            <msb>2</msb>
                            <access>read-write</access>
                            <enumeratedValues>
                                </enumeratedValues>
                        </field>
                    </fields>
                </register>
                <register>
                    <name>LVD1SR</name>
                    <description>Voltage Monitor 1 Circuit Status Register</description>
                    <addressOffset>0x0E1</addressOffset>
                    <size>8</size>
                    <access>read-write</access>
                    <resetValue>0x02</resetValue>
                    <resetMask>0xff</resetMask>
                    <fields>
                        <field>
                            <name>DET</name>
                            <description>Voltage Monitor 1 Voltage Variation Detection Flag</description>
                            <lsb>0</lsb>
                            <msb>0</msb>
                            <access>read-write</access>
                            <enumeratedValues>
                                </enumeratedValues>
                        </field>
                        <field>
                            <name>MON</name>
                            <description>Voltage Monitor 1 Signal Monitor Flag</description>
                            <lsb>1</lsb>
                            <msb>1</msb>
                            <access>read-only</access>
                            <enumeratedValues>
                                </enumeratedValues>
                        </field>
                    </fields>
                </register>
                <register>
                    <name>LVD2CR1</name>
                    <description>Voltage Monitor 2 Circuit Control Register 1</description>
                    <addressOffset>0x0E2</addressOffset>
                    <size>8</size>
                    <access>read-write</access>
                    <resetValue>0x01</resetValue>
                    <resetMask>0xff</resetMask>
                    <fields>
                        <field>
                            <name>IDTSEL</name>
                            <description>Voltage Monitor 2 Interrupt Generation Condition Select</description>
                            <lsb>0</lsb>
                            <msb>1</msb>
                            <access>read-write</access>
                            <enumeratedValues>
                                </enumeratedValues>
                        </field>
                        <field>
                            <name>IRQSEL</name>
                            <description>Voltage Monitor 2 Interrupt Type Select</description>
                            <lsb>2</lsb>
                            <msb>2</msb>
                            <access>read-write</access>
                            <enumeratedValues>
                                </enumeratedValues>
                        </field>
                    </fields>
                </register>
                <register>
                    <name>LVD2SR</name>
                    <description>Voltage Monitor 2 Circuit Status Register</description>
                    <addressOffset>0x0E3</addressOffset>
                    <size>8</size>
                    <access>read-write</access>
                    <resetValue>0x02</resetValue>
                    <resetMask>0xff</resetMask>
                    <fields>
                        <field>
                            <name>DET</name>
                            <description>Voltage Monitor 2 Voltage Variation Detection Flag</description>
                            <lsb>0</lsb>
                            <msb>0</msb>
                            <access>read-write</access>
                            <enumeratedValues>
                                </enumeratedValues>
                        </field>
                        <field>
                            <name>MON</name>
                            <description>Voltage Monitor 2 Signal Monitor Flag</description>
                            <lsb>1</lsb>
                            <msb>1</msb>
                            <access>read-only</access>
                            <enumeratedValues>
                                </enumeratedValues>
                        </field>
                    </fields>
                </register>
                <register>
                    <name>CGFSAR</name>
                    <description>Clock Generation Function Security Attribute Register</description>
                    <addressOffset>0x3C0</addressOffset>
                    <size>32</size>
                    <access>read-write</access>
                    <resetValue>0xffffffff</resetValue>
                    <resetMask>0xffffffff</resetMask>
                    <fields>
                        <field>
                            <name>NONSEC00</name>
                            <description>Non Secure Attribute bit 00</description>
                            <lsb>0</lsb>
                            <msb>0</msb>
                            <access>read-write</access>
                            <enumeratedValues>
                                </enumeratedValues>
                        </field>
                        <field>
                            <name>NONSEC02</name>
                            <description>Non Secure Attribute bit 02</description>
                            <lsb>2</lsb>
                            <msb>2</msb>
                            <access>read-write</access>
                            <enumeratedValues>
                                </enumeratedValues>
                        </field>
                        <field>
                            <name>NONSEC03</name>
                            <description>Non Secure Attribute bit 03</description>
                            <lsb>3</lsb>
                            <msb>3</msb>
                            <access>read-write</access>
                            <enumeratedValues>
                                </enumeratedValues>
                        </field>
                        <field>
                            <name>NONSEC04</name>
                            <description>Non Secure Attribute bit 04</description>
                            <lsb>4</lsb>
                            <msb>4</msb>
                            <access>read-write</access>
                            <enumeratedValues>
                                </enumeratedValues>
                        </field>
                        <field>
                            <name>NONSEC05</name>
                            <description>Non Secure Attribute bit 05</description>
                            <lsb>5</lsb>
                            <msb>5</msb>
                            <access>read-write</access>
                            <enumeratedValues>
                                </enumeratedValues>
                        </field>
                        <field>
                            <name>NONSEC06</name>
                            <description>Non Secure Attribute bit 06</description>
                            <lsb>6</lsb>
                            <msb>6</msb>
                            <access>read-write</access>
                            <enumeratedValues>
                                </enumeratedValues>
                        </field>
                        <field>
                            <name>NONSEC07</name>
                            <description>Non Secure Attribute bit 07</description>
                            <lsb>7</lsb>
                            <msb>7</msb>
                            <access>read-write</access>
                            <enumeratedValues>
                                </enumeratedValues>
                        </field>
                        <field>
                            <name>NONSEC08</name>
                            <description>Non Secure Attribute bit 08</description>
                            <lsb>8</lsb>
                            <msb>8</msb>
                            <access>read-write</access>
                            <enumeratedValues>
                                </enumeratedValues>
                        </field>
                        <field>
                            <name>NONSEC09</name>
                            <description>Non Secure Attribute bit 09</description>
                            <lsb>9</lsb>
                            <msb>9</msb>
                            <access>read-write</access>
                            <enumeratedValues>
                                </enumeratedValues>
                        </field>
                        <field>
                            <name>NONSEC11</name>
                            <description>Non Secure Attribute bit 11</description>
                            <lsb>11</lsb>
                            <msb>11</msb>
                            <access>read-write</access>
                            <enumeratedValues>
                                </enumeratedValues>
                        </field>
                        <field>
                            <name>NONSEC12</name>
                            <description>Non Secure Attribute bit 12</description>
                            <lsb>12</lsb>
                            <msb>12</msb>
                            <access>read-write</access>
                            <enumeratedValues>
                                </enumeratedValues>
                        </field>
                        <field>
                            <name>NONSEC16</name>
                            <description>Non Secure Attribute bit 16</description>
                            <lsb>16</lsb>
                            <msb>16</msb>
                            <access>read-write</access>
                            <enumeratedValues>
                                </enumeratedValues>
                        </field>
                        <field>
                            <name>NONSEC17</name>
                            <description>Non Secure Attribute bit 17</description>
                            <lsb>17</lsb>
                            <msb>17</msb>
                            <access>read-write</access>
                            <enumeratedValues>
                                </enumeratedValues>
                        </field>
                        <field>
                            <name>NONSEC18</name>
                            <description>Non Secure Attribute bit 18</description>
                            <lsb>18</lsb>
                            <msb>18</msb>
                            <access>read-write</access>
                            <enumeratedValues>
                                </enumeratedValues>
                        </field>
                        <field>
                            <name>NONSEC19</name>
                            <description>Non Secure Attribute bit 19</description>
                            <lsb>19</lsb>
                            <msb>19</msb>
                            <access>read-write</access>
                            <enumeratedValues>
                                </enumeratedValues>
                        </field>
                        <field>
                            <name>NONSEC20</name>
                            <description>Non Secure Attribute bit 20</description>
                            <lsb>20</lsb>
                            <msb>20</msb>
                            <access>read-write</access>
                            <enumeratedValues>
                                </enumeratedValues>
                        </field>
                    </fields>
                </register>
                <register>
                    <name>RSTSAR</name>
                    <description>Reset Security Attribution Register</description>
                    <addressOffset>0x3C4</addressOffset>
                    <size>32</size>
                    <access>read-write</access>
                    <resetValue>0xffffffff</resetValue>
                    <resetMask>0xffffffff</resetMask>
                    <fields>
                        <field>
                            <name>NONSEC0</name>
                            <description>Non Secure Attribute bit 0</description>
                            <lsb>0</lsb>
                            <msb>0</msb>
                            <access>read-write</access>
                            <enumeratedValues>
                                </enumeratedValues>
                        </field>
                        <field>
                            <name>NONSEC1</name>
                            <description>Non Secure Attribute bit 1</description>
                            <lsb>1</lsb>
                            <msb>1</msb>
                            <access>read-write</access>
                            <enumeratedValues>
                                </enumeratedValues>
                        </field>
                        <field>
                            <name>NONSEC2</name>
                            <description>Non Secure Attribute bit 2</description>
                            <lsb>2</lsb>
                            <msb>2</msb>
                            <access>read-write</access>
                            <enumeratedValues>
                                </enumeratedValues>
                        </field>
                    </fields>
                </register>
                <register>
                    <name>LPMSAR</name>
                    <description>Low Power Mode Security Attribution Register</description>
                    <addressOffset>0x3C8</addressOffset>
                    <size>32</size>
                    <access>read-write</access>
                    <resetValue>0xffffffff</resetValue>
                    <resetMask>0xffffffff</resetMask>
                    <fields>
                        <field>
                            <name>NONSEC0</name>
                            <description>Non Secure Attribute bit 0</description>
                            <lsb>0</lsb>
                            <msb>0</msb>
                            <access>read-write</access>
                            <enumeratedValues>
                                </enumeratedValues>
                        </field>
                        <field>
                            <name>NONSEC2</name>
                            <description>Non Secure Attribute bit 2</description>
                            <lsb>2</lsb>
                            <msb>2</msb>
                            <access>read-write</access>
                            <enumeratedValues>
                                </enumeratedValues>
                        </field>
                        <field>
                            <name>NONSEC4</name>
                            <description>Non Secure Attribute bit 4</description>
                            <lsb>4</lsb>
                            <msb>4</msb>
                            <access>read-write</access>
                            <enumeratedValues>
                                </enumeratedValues>
                        </field>
                        <field>
                            <name>NONSEC8</name>
                            <description>Non Secure Attribute bit 8</description>
                            <lsb>8</lsb>
                            <msb>8</msb>
                            <access>read-write</access>
                            <enumeratedValues>
                                </enumeratedValues>
                        </field>
                        <field>
                            <name>NONSEC9</name>
                            <description>Non Secure Attribute bit 9</description>
                            <lsb>9</lsb>
                            <msb>9</msb>
                            <access>read-write</access>
                            <enumeratedValues>
                                </enumeratedValues>
                        </field>
                    </fields>
                </register>
                <register>
                    <name>LVDSAR</name>
                    <description>Low Voltage Detection Security Attribution Register</description>
                    <addressOffset>0x3CC</addressOffset>
                    <size>32</size>
                    <access>read-write</access>
                    <resetValue>0xffffffff</resetValue>
                    <resetMask>0xffffffff</resetMask>
                    <fields>
                        <field>
                            <name>NONSEC0</name>
                            <description>Non Secure Attribute bit 0</description>
                            <lsb>0</lsb>
                            <msb>0</msb>
                            <access>read-write</access>
                            <enumeratedValues>
                                </enumeratedValues>
                        </field>
                        <field>
                            <name>NONSEC1</name>
                            <description>Non Secure Attribute bit 1</description>
                            <lsb>1</lsb>
                            <msb>1</msb>
                            <access>read-write</access>
                            <enumeratedValues>
                                </enumeratedValues>
                        </field>
                    </fields>
                </register>
                <register>
                    <name>BBFSAR</name>
                    <description>Battery Backup Function Security Attribute Register</description>
                    <addressOffset>0x3D0</addressOffset>
                    <size>32</size>
                    <access>read-write</access>
                    <resetValue>0x0000ffff</resetValue>
                    <resetMask>0xffffffff</resetMask>
                    <fields>
                        <field>
                            <name>NONSEC0</name>
                            <description>Non Secure Attribute bit 0</description>
                            <lsb>0</lsb>
                            <msb>0</msb>
                            <access>read-write</access>
                            <enumeratedValues>
                                </enumeratedValues>
                        </field>
                        <field>
                            <name>NONSEC1</name>
                            <description>Non Secure Attribute bit 1</description>
                            <lsb>1</lsb>
                            <msb>1</msb>
                            <access>read-write</access>
                            <enumeratedValues>
                                </enumeratedValues>
                        </field>
                        <field>
                            <name>NONSEC2</name>
                            <description>Non Secure Attribute bit 2</description>
                            <lsb>2</lsb>
                            <msb>2</msb>
                            <access>read-write</access>
                            <enumeratedValues>
                                </enumeratedValues>
                        </field>
                        <field>
                            <name>NONSEC16</name>
                            <description>Non Secure Attribute bit 16</description>
                            <lsb>16</lsb>
                            <msb>16</msb>
                            <access>read-write</access>
                            <enumeratedValues>
                                </enumeratedValues>
                        </field>
                        <field>
                            <name>NONSEC17</name>
                            <description>Non Secure Attribute bit 17</description>
                            <lsb>17</lsb>
                            <msb>17</msb>
                            <access>read-write</access>
                            <enumeratedValues>
                                </enumeratedValues>
                        </field>
                        <field>
                            <name>NONSEC18</name>
                            <description>Non Secure Attribute bit 18</description>
                            <lsb>18</lsb>
                            <msb>18</msb>
                            <access>read-write</access>
                            <enumeratedValues>
                                </enumeratedValues>
                        </field>
                        <field>
                            <name>NONSEC19</name>
                            <description>Non Secure Attribute bit 19</description>
                            <lsb>19</lsb>
                            <msb>19</msb>
                            <access>read-write</access>
                            <enumeratedValues>
                                </enumeratedValues>
                        </field>
                        <field>
                            <name>NONSEC20</name>
                            <description>Non Secure Attribute bit 20</description>
                            <lsb>20</lsb>
                            <msb>20</msb>
                            <access>read-write</access>
                            <enumeratedValues>
                                </enumeratedValues>
                        </field>
                        <field>
                            <name>NONSEC21</name>
                            <description>Non Secure Attribute bit 21</description>
                            <lsb>21</lsb>
                            <msb>21</msb>
                            <access>read-write</access>
                            <enumeratedValues>
                                </enumeratedValues>
                        </field>
                        <field>
                            <name>NONSEC22</name>
                            <description>Non Secure Attribute bit 22</description>
                            <lsb>22</lsb>
                            <msb>22</msb>
                            <access>read-write</access>
                            <enumeratedValues>
                                </enumeratedValues>
                        </field>
                        <field>
                            <name>NONSEC23</name>
                            <description>Non Secure Attribute bit 23</description>
                            <lsb>23</lsb>
                            <msb>23</msb>
                            <access>read-write</access>
                            <enumeratedValues>
                                </enumeratedValues>
                        </field>
                    </fields>
                </register>
                <register>
                    <name>DPFSAR</name>
                    <description>Deep Software Standby Interrupt Factor Security Attribution Register</description>
                    <addressOffset>0x3E0</addressOffset>
                    <size>32</size>
                    <access>read-write</access>
                    <resetValue>0xffffffff</resetValue>
                    <resetMask>0xffffffff</resetMask>
                    <fields>
                        <field>
                            <name>DPFSA0</name>
                            <description>Deep Software Standby Interrupt Factor Security Attribute bit n (n = 0 to 7)</description>
                            <lsb>0</lsb>
                            <msb>0</msb>
                            <access>read-write</access>
                            <enumeratedValues>
                                </enumeratedValues>
                        </field>
                        <field>
                            <name>DPFSA1</name>
                            <description>Deep Software Standby Interrupt Factor Security Attribute bit n (n = 0 to 7)</description>
                            <lsb>1</lsb>
                            <msb>1</msb>
                            <access>read-write</access>
                            <enumeratedValues>
                                </enumeratedValues>
                        </field>
                        <field>
                            <name>DPFSA2</name>
                            <description>Deep Software Standby Interrupt Factor Security Attribute bit n (n = 0 to 7)</description>
                            <lsb>2</lsb>
                            <msb>2</msb>
                            <access>read-write</access>
                            <enumeratedValues>
                                </enumeratedValues>
                        </field>
                        <field>
                            <name>DPFSA3</name>
                            <description>Deep Software Standby Interrupt Factor Security Attribute bit n (n = 0 to 7)</description>
                            <lsb>3</lsb>
                            <msb>3</msb>
                            <access>read-write</access>
                            <enumeratedValues>
                                </enumeratedValues>
                        </field>
                        <field>
                            <name>DPFSA4</name>
                            <description>Deep Software Standby Interrupt Factor Security Attribute bit n (n = 0 to 7)</description>
                            <lsb>4</lsb>
                            <msb>4</msb>
                            <access>read-write</access>
                            <enumeratedValues>
                                </enumeratedValues>
                        </field>
                        <field>
                            <name>DPFSA5</name>
                            <description>Deep Software Standby Interrupt Factor Security Attribute bit n (n = 0 to 7)</description>
                            <lsb>5</lsb>
                            <msb>5</msb>
                            <access>read-write</access>
                            <enumeratedValues>
                                </enumeratedValues>
                        </field>
                        <field>
                            <name>DPFSA6</name>
                            <description>Deep Software Standby Interrupt Factor Security Attribute bit n (n = 0 to 7)</description>
                            <lsb>6</lsb>
                            <msb>6</msb>
                            <access>read-write</access>
                            <enumeratedValues>
                                </enumeratedValues>
                        </field>
                        <field>
                            <name>DPFSA7</name>
                            <description>Deep Software Standby Interrupt Factor Security Attribute bit n (n = 0 to 7)</description>
                            <lsb>7</lsb>
                            <msb>7</msb>
                            <access>read-write</access>
                            <enumeratedValues>
                                </enumeratedValues>
                        </field>
                        <field>
                            <name>DPFSA08</name>
                            <description>Deep Software Standby Interrupt Factor Security Attribute bit n (n = 8 to 15)</description>
                            <lsb>8</lsb>
                            <msb>8</msb>
                            <access>read-write</access>
                            <enumeratedValues>
                                </enumeratedValues>
                        </field>
                        <field>
                            <name>DPFSA09</name>
                            <description>Deep Software Standby Interrupt Factor Security Attribute bit n (n = 8 to 15)</description>
                            <lsb>9</lsb>
                            <msb>9</msb>
                            <access>read-write</access>
                            <enumeratedValues>
                                </enumeratedValues>
                        </field>
                        <field>
                            <name>DPFSA10</name>
                            <description>Deep Software Standby Interrupt Factor Security Attribute bit n (n = 8 to 15)</description>
                            <lsb>10</lsb>
                            <msb>10</msb>
                            <access>read-write</access>
                            <enumeratedValues>
                                </enumeratedValues>
                        </field>
                        <field>
                            <name>DPFSA11</name>
                            <description>Deep Software Standby Interrupt Factor Security Attribute bit n (n = 8 to 15)</description>
                            <lsb>11</lsb>
                            <msb>11</msb>
                            <access>read-write</access>
                            <enumeratedValues>
                                </enumeratedValues>
                        </field>
                        <field>
                            <name>DPFSA12</name>
                            <description>Deep Software Standby Interrupt Factor Security Attribute bit n (n = 8 to 15)</description>
                            <lsb>12</lsb>
                            <msb>12</msb>
                            <access>read-write</access>
                            <enumeratedValues>
                                </enumeratedValues>
                        </field>
                        <field>
                            <name>DPFSA13</name>
                            <description>Deep Software Standby Interrupt Factor Security Attribute bit n (n = 8 to 15)</description>
                            <lsb>13</lsb>
                            <msb>13</msb>
                            <access>read-write</access>
                            <enumeratedValues>
                                </enumeratedValues>
                        </field>
                        <field>
                            <name>DPFSA14</name>
                            <description>Deep Software Standby Interrupt Factor Security Attribute bit n (n = 8 to 15)</description>
                            <lsb>14</lsb>
                            <msb>14</msb>
                            <access>read-write</access>
                            <enumeratedValues>
                                </enumeratedValues>
                        </field>
                        <field>
                            <name>DPFSA15</name>
                            <description>Deep Software Standby Interrupt Factor Security Attribute bit n (n = 8 to 15)</description>
                            <lsb>15</lsb>
                            <msb>15</msb>
                            <access>read-write</access>
                            <enumeratedValues>
                                </enumeratedValues>
                        </field>
                        <field>
                            <name>DPFSA16</name>
                            <description>Deep Software Standby Interrupt Factor Security Attribute bit 16</description>
                            <lsb>16</lsb>
                            <msb>16</msb>
                            <access>read-write</access>
                            <enumeratedValues>
                                </enumeratedValues>
                        </field>
                        <field>
                            <name>DPFSA17</name>
                            <description>Deep Software Standby Interrupt Factor Security Attribute bit 17</description>
                            <lsb>17</lsb>
                            <msb>17</msb>
                            <access>read-write</access>
                            <enumeratedValues>
                                </enumeratedValues>
                        </field>
                        <field>
                            <name>DPFSA18</name>
                            <description>Deep Software Standby Interrupt Factor Security Attribute bit 18</description>
                            <lsb>18</lsb>
                            <msb>18</msb>
                            <access>read-write</access>
                            <enumeratedValues>
                                </enumeratedValues>
                        </field>
                        <field>
                            <name>DPFSA19</name>
                            <description>Deep Software Standby Interrupt Factor Security Attribute bit 19</description>
                            <lsb>19</lsb>
                            <msb>19</msb>
                            <access>read-write</access>
                            <enumeratedValues>
                                </enumeratedValues>
                        </field>
                        <field>
                            <name>DPFSA20</name>
                            <description>Deep Software Standby Interrupt Factor Security Attribute bit 20</description>
                            <lsb>20</lsb>
                            <msb>20</msb>
                            <access>read-write</access>
                            <enumeratedValues>
                                </enumeratedValues>
                        </field>
                        <field>
                            <name>DPFSA24</name>
                            <description>Deep Software Standby Interrupt Factor Security Attribute bit 24</description>
                            <lsb>24</lsb>
                            <msb>24</msb>
                            <access>read-write</access>
                            <enumeratedValues>
                                </enumeratedValues>
                        </field>
                        <field>
                            <name>DPFSA25</name>
                            <description>Deep Software Standby Interrupt Factor Security Attribute bit 25</description>
                            <lsb>25</lsb>
                            <msb>25</msb>
                            <access>read-write</access>
                            <enumeratedValues>
                                </enumeratedValues>
                        </field>
                        <field>
                            <name>DPFSA26</name>
                            <description>Deep Software Standby Interrupt Factor Security Attribute bit 26</description>
                            <lsb>26</lsb>
                            <msb>26</msb>
                            <access>read-write</access>
                            <enumeratedValues>
                                </enumeratedValues>
                        </field>
                        <field>
                            <name>DPFSA27</name>
                            <description>Deep Software Standby Interrupt Factor Security Attribute bit 27</description>
                            <lsb>27</lsb>
                            <msb>27</msb>
                            <access>read-write</access>
                            <enumeratedValues>
                                </enumeratedValues>
                        </field>
                    </fields>
                </register>
                <register>
                    <name>PRCR</name>
                    <description>Protect Register</description>
                    <addressOffset>0x3FE</addressOffset>
                    <size>16</size>
                    <access>read-write</access>
                    <resetValue>0x0000</resetValue>
                    <resetMask>0xffff</resetMask>
                    <fields>
                        <field>
                            <name>PRC0</name>
                            <description>Enable writing to the registers related to the clock generation circuit</description>
                            <lsb>0</lsb>
                            <msb>0</msb>
                            <access>read-write</access>
                            <enumeratedValues>
                                </enumeratedValues>
                        </field>
                        <field>
                            <name>PRC1</name>
                            <description>Enable writing to the registers related to the low power modes, and the battery backup function</description>
                            <lsb>1</lsb>
                            <msb>1</msb>
                            <access>read-write</access>
                            <enumeratedValues>
                                </enumeratedValues>
                        </field>
                        <field>
                            <name>PRC3</name>
                            <description>Enable writing to the registers related to the LVD</description>
                            <lsb>3</lsb>
                            <msb>3</msb>
                            <access>read-write</access>
                            <enumeratedValues>
                                </enumeratedValues>
                        </field>
                        <field>
                            <name>PRC4</name>
                            <lsb>4</lsb>
                            <msb>4</msb>
                            <access>read-write</access>
                            <enumeratedValues>
                                </enumeratedValues>
                        </field>
                        <field>
                            <name>PRKEY</name>
                            <description>PRC Key Code</description>
                            <lsb>8</lsb>
                            <msb>15</msb>
                            <access>write-only</access>
                        </field>
                    </fields>
                </register>
                <register>
                    <name>DPSBYCR</name>
                    <description>Deep Software Standby Control Register</description>
                    <addressOffset>0x400</addressOffset>
                    <size>8</size>
                    <access>read-write</access>
                    <resetValue>0x01</resetValue>
                    <resetMask>0xff</resetMask>
                    <fields>
                        <field>
                            <name>DEEPCUT</name>
                            <description>Power,Supply Control</description>
                            <lsb>0</lsb>
                            <msb>1</msb>
                            <access>read-write</access>
                            <enumeratedValues>
                                </enumeratedValues>
                        </field>
                        <field>
                            <name>IOKEEP</name>
                            <description>I/O Port Retention</description>
                            <lsb>6</lsb>
                            <msb>6</msb>
                            <access>read-write</access>
                            <enumeratedValues>
                                </enumeratedValues>
                        </field>
                        <field>
                            <name>DPSBY</name>
                            <description>Deep Software Standby</description>
                            <lsb>7</lsb>
                            <msb>7</msb>
                            <access>read-write</access>
                            <enumeratedValues>
                                </enumeratedValues>
                        </field>
                    </fields>
                </register>
                <register>
                    <name>DPSWCR</name>
                    <description>Deep Software Standby Wait Control Register</description>
                    <addressOffset>0x401</addressOffset>
                    <size>8</size>
                    <access>read-write</access>
                    <resetValue>0x19</resetValue>
                    <resetMask>0xff</resetMask>
                    <fields>
                        <field>
                            <name>WTSTS</name>
                            <description>Deep Software Wait Standby Time Setting Bit</description>
                            <lsb>0</lsb>
                            <msb>5</msb>
                            <access>read-write</access>
                            <enumeratedValues>
                                </enumeratedValues>
                        </field>
                    </fields>
                </register>
                <register>
                    <name>DPSIER0</name>
                    <description>Deep Software Standby Interrupt Enable Register 0</description>
                    <addressOffset>0x402</addressOffset>
                    <size>8</size>
                    <access>read-write</access>
                    <resetValue>0x00</resetValue>
                    <resetMask>0xff</resetMask>
                    <fields>
                        <field>
                            <name>DIRQ0E</name>
                            <description>IRQ0-DS Pin Enable</description>
                            <lsb>0</lsb>
                            <msb>0</msb>
                            <access>read-write</access>
                            <enumeratedValues>
                                </enumeratedValues>
                        </field>
                        <field>
                            <name>DIRQ1E</name>
                            <description>IRQ1-DS Pin Enable</description>
                            <lsb>1</lsb>
                            <msb>1</msb>
                            <access>read-write</access>
                            <enumeratedValues>
                                </enumeratedValues>
                        </field>
                        <field>
                            <name>DIRQ2E</name>
                            <description>IRQ2-DS Pin Enable</description>
                            <lsb>2</lsb>
                            <msb>2</msb>
                            <access>read-write</access>
                            <enumeratedValues>
                                </enumeratedValues>
                        </field>
                        <field>
                            <name>DIRQ3E</name>
                            <description>IRQ3-DS Pin Enable</description>
                            <lsb>3</lsb>
                            <msb>3</msb>
                            <access>read-write</access>
                            <enumeratedValues>
                                </enumeratedValues>
                        </field>
                        <field>
                            <name>DIRQ4E</name>
                            <description>IRQ4-DS Pin Enable</description>
                            <lsb>4</lsb>
                            <msb>4</msb>
                            <access>read-write</access>
                            <enumeratedValues>
                                </enumeratedValues>
                        </field>
                        <field>
                            <name>DIRQ5E</name>
                            <description>IRQ5-DS Pin Enable</description>
                            <lsb>5</lsb>
                            <msb>5</msb>
                            <access>read-write</access>
                            <enumeratedValues>
                                </enumeratedValues>
                        </field>
                        <field>
                            <name>DIRQ6E</name>
                            <description>IRQ6-DS Pin Enable</description>
                            <lsb>6</lsb>
                            <msb>6</msb>
                            <access>read-write</access>
                            <enumeratedValues>
                                </enumeratedValues>
                        </field>
                        <field>
                            <name>DIRQ7E</name>
                            <description>IRQ7-DS Pin Enable</description>
                            <lsb>7</lsb>
                            <msb>7</msb>
                            <access>read-write</access>
                            <enumeratedValues>
                                </enumeratedValues>
                        </field>
                    </fields>
                </register>
                <register>
                    <name>DPSIER1</name>
                    <description>Deep Software Standby Interrupt Enable Register 1</description>
                    <addressOffset>0x403</addressOffset>
                    <size>8</size>
                    <access>read-write</access>
                    <resetValue>0x00</resetValue>
                    <resetMask>0xff</resetMask>
                    <fields>
                        <field>
                            <name>DIRQ8E</name>
                            <description>IRQ8-DS Pin Enable</description>
                            <lsb>0</lsb>
                            <msb>0</msb>
                            <access>read-write</access>
                            <enumeratedValues>
                                </enumeratedValues>
                        </field>
                        <field>
                            <name>DIRQ9E</name>
                            <description>IRQ9-DS Pin Enable</description>
                            <lsb>1</lsb>
                            <msb>1</msb>
                            <access>read-write</access>
                            <enumeratedValues>
                                </enumeratedValues>
                        </field>
                        <field>
                            <name>DIRQ10E</name>
                            <description>IRQ10-DS Pin Enable</description>
                            <lsb>2</lsb>
                            <msb>2</msb>
                            <access>read-write</access>
                            <enumeratedValues>
                                </enumeratedValues>
                        </field>
                        <field>
                            <name>DIRQ11E</name>
                            <description>IRQ11-DS Pin Enable</description>
                            <lsb>3</lsb>
                            <msb>3</msb>
                            <access>read-write</access>
                            <enumeratedValues>
                                </enumeratedValues>
                        </field>
                        <field>
                            <name>DIRQ12E</name>
                            <description>IRQ12-DS Pin Enable</description>
                            <lsb>4</lsb>
                            <msb>4</msb>
                            <access>read-write</access>
                            <enumeratedValues>
                                </enumeratedValues>
                        </field>
                        <field>
                            <name>DIRQ13E</name>
                            <description>IRQ13-DS Pin Enable</description>
                            <lsb>5</lsb>
                            <msb>5</msb>
                            <access>read-write</access>
                            <enumeratedValues>
                                </enumeratedValues>
                        </field>
                        <field>
                            <name>DIRQ14E</name>
                            <description>IRQ14-DS Pin Enable</description>
                            <lsb>6</lsb>
                            <msb>6</msb>
                            <access>read-write</access>
                            <enumeratedValues>
                                </enumeratedValues>
                        </field>
                        <field>
                            <name>DIRQ15E</name>
                            <description>IRQ15-DS Pin Enable</description>
                            <lsb>7</lsb>
                            <msb>7</msb>
                            <access>read-write</access>
                            <enumeratedValues>
                                </enumeratedValues>
                        </field>
                    </fields>
                </register>
                <register>
                    <name>DPSIER2</name>
                    <description>Deep Software Standby Interrupt Enable Register 2</description>
                    <addressOffset>0x404</addressOffset>
                    <size>8</size>
                    <access>read-write</access>
                    <resetValue>0x00</resetValue>
                    <resetMask>0xff</resetMask>
                    <fields>
                        <field>
                            <name>DLVD1IE</name>
                            <description>LVD1 Deep Software Standby Cancel Signal Enable</description>
                            <lsb>0</lsb>
                            <msb>0</msb>
                            <access>read-write</access>
                            <enumeratedValues>
                                </enumeratedValues>
                        </field>
                        <field>
                            <name>DLVD2IE</name>
                            <description>LVD2 Deep Software Standby Cancel Signal Enable</description>
                            <lsb>1</lsb>
                            <msb>1</msb>
                            <access>read-write</access>
                            <enumeratedValues>
                                </enumeratedValues>
                        </field>
                        <field>
                            <name>DRTCIIE</name>
                            <description>RTC Interval interrupt Deep Software Standby Cancel Signal Enable</description>
                            <lsb>2</lsb>
                            <msb>2</msb>
                            <access>read-write</access>
                            <enumeratedValues>
                                </enumeratedValues>
                        </field>
                        <field>
                            <name>DRTCAIE</name>
                            <description>RTC Alarm interrupt Deep Software Standby Cancel Signal Enable</description>
                            <lsb>3</lsb>
                            <msb>3</msb>
                            <access>read-write</access>
                            <enumeratedValues>
                                </enumeratedValues>
                        </field>
                        <field>
                            <name>DNMIE</name>
                            <description>NMI Pin Enable</description>
                            <lsb>4</lsb>
                            <msb>4</msb>
                            <access>read-write</access>
                            <enumeratedValues>
                                </enumeratedValues>
                        </field>
                    </fields>
                </register>
                <register>
                    <name>DPSIER3</name>
                    <description>Deep Software Standby Interrupt Enable Register 3</description>
                    <addressOffset>0x405</addressOffset>
                    <size>8</size>
                    <access>read-write</access>
                    <resetValue>0x00</resetValue>
                    <resetMask>0xff</resetMask>
                    <fields>
                        <field>
                            <name>DUSBFS0IE</name>
                            <description>USBFS0 Suspend/Resume Deep Software Standby Cancel Signal Enable</description>
                            <lsb>0</lsb>
                            <msb>0</msb>
                            <access>read-write</access>
                            <enumeratedValues>
                                </enumeratedValues>
                        </field>
                        <field>
                            <name>DUSBHSIE</name>
                            <description>USBHS Suspend/Resume Deep Software Standby Cancel Signal Enable</description>
                            <lsb>1</lsb>
                            <msb>1</msb>
                            <access>read-write</access>
                            <enumeratedValues>
                                </enumeratedValues>
                        </field>
                        <field>
                            <name>DAGT1IE</name>
                            <description>AGT1 Underflow Deep Software Standby Cancel Signal Enable</description>
                            <lsb>2</lsb>
                            <msb>2</msb>
                            <access>read-write</access>
                            <enumeratedValues>
                                </enumeratedValues>
                        </field>
                        <field>
                            <name>DAGT3IE</name>
                            <description>AGT3 Underflow Deep Software Standby Cancel Signal Enable</description>
                            <lsb>3</lsb>
                            <msb>3</msb>
                            <access>read-write</access>
                            <enumeratedValues>
                                </enumeratedValues>
                        </field>
                    </fields>
                </register>
                <register>
                    <name>DPSIFR0</name>
                    <description>Deep Software Standby Interrupt Flag Register 0</description>
                    <addressOffset>0x406</addressOffset>
                    <size>8</size>
                    <access>read-write</access>
                    <resetValue>0x00</resetValue>
                    <resetMask>0xff</resetMask>
                    <fields>
                        <field>
                            <name>DIRQ0F</name>
                            <description>IRQ0-DS Pin Deep Software Standby Cancel Flag</description>
                            <lsb>0</lsb>
                            <msb>0</msb>
                            <access>read-write</access>
                            <enumeratedValues>
                                </enumeratedValues>
                        </field>
                        <field>
                            <name>DIRQ1F</name>
                            <description>IRQ1-DS Pin Deep Software Standby Cancel Flag</description>
                            <lsb>1</lsb>
                            <msb>1</msb>
                            <access>read-write</access>
                            <enumeratedValues>
                                </enumeratedValues>
                        </field>
                        <field>
                            <name>DIRQ2F</name>
                            <description>IRQ2-DS Pin Deep Software Standby Cancel Flag</description>
                            <lsb>2</lsb>
                            <msb>2</msb>
                            <access>read-write</access>
                            <enumeratedValues>
                                </enumeratedValues>
                        </field>
                        <field>
                            <name>DIRQ3F</name>
                            <description>IRQ3-DS Pin Deep Software Standby Cancel Flag</description>
                            <lsb>3</lsb>
                            <msb>3</msb>
                            <access>read-write</access>
                            <enumeratedValues>
                                </enumeratedValues>
                        </field>
                        <field>
                            <name>DIRQ4F</name>
                            <description>IRQ4-DS Pin Deep Software Standby Cancel Flag</description>
                            <lsb>4</lsb>
                            <msb>4</msb>
                            <access>read-write</access>
                            <enumeratedValues>
                                </enumeratedValues>
                        </field>
                        <field>
                            <name>DIRQ5F</name>
                            <description>IRQ5-DS Pin Deep Software Standby Cancel Flag</description>
                            <lsb>5</lsb>
                            <msb>5</msb>
                            <access>read-write</access>
                            <enumeratedValues>
                                </enumeratedValues>
                        </field>
                        <field>
                            <name>DIRQ6F</name>
                            <description>IRQ6-DS Pin Deep Software Standby Cancel Flag</description>
                            <lsb>6</lsb>
                            <msb>6</msb>
                            <access>read-write</access>
                            <enumeratedValues>
                                </enumeratedValues>
                        </field>
                        <field>
                            <name>DIRQ7F</name>
                            <description>IRQ7-DS Pin Deep Software Standby Cancel Flag</description>
                            <lsb>7</lsb>
                            <msb>7</msb>
                            <access>read-write</access>
                            <enumeratedValues>
                                </enumeratedValues>
                        </field>
                    </fields>
                </register>
                <register>
                    <name>DPSIFR1</name>
                    <description>Deep Software Standby Interrupt Flag Register 1</description>
                    <addressOffset>0x407</addressOffset>
                    <size>8</size>
                    <access>read-write</access>
                    <resetValue>0x00</resetValue>
                    <resetMask>0xff</resetMask>
                    <fields>
                        <field>
                            <name>DIRQ8F</name>
                            <description>IRQ8-DS Pin Deep Software Standby Cancel Flag</description>
                            <lsb>0</lsb>
                            <msb>0</msb>
                            <access>read-write</access>
                            <enumeratedValues>
                                </enumeratedValues>
                        </field>
                        <field>
                            <name>DIRQ9F</name>
                            <description>IRQ9-DS Pin Deep Software Standby Cancel Flag</description>
                            <lsb>1</lsb>
                            <msb>1</msb>
                            <access>read-write</access>
                            <enumeratedValues>
                                </enumeratedValues>
                        </field>
                        <field>
                            <name>DIRQ10F</name>
                            <description>IRQ10-DS Pin Deep Software Standby Cancel Flag</description>
                            <lsb>2</lsb>
                            <msb>2</msb>
                            <access>read-write</access>
                            <enumeratedValues>
                                </enumeratedValues>
                        </field>
                        <field>
                            <name>DIRQ11F</name>
                            <description>IRQ11-DS Pin Deep Software Standby Cancel Flag</description>
                            <lsb>3</lsb>
                            <msb>3</msb>
                            <access>read-write</access>
                            <enumeratedValues>
                                </enumeratedValues>
                        </field>
                        <field>
                            <name>DIRQ12F</name>
                            <description>IRQ12-DS Pin Deep Software Standby Cancel Flag</description>
                            <lsb>4</lsb>
                            <msb>4</msb>
                            <access>read-write</access>
                            <enumeratedValues>
                                </enumeratedValues>
                        </field>
                        <field>
                            <name>DIRQ13F</name>
                            <description>IRQ13-DS Pin Deep Software Standby Cancel Flag</description>
                            <lsb>5</lsb>
                            <msb>5</msb>
                            <access>read-write</access>
                            <enumeratedValues>
                                </enumeratedValues>
                        </field>
                        <field>
                            <name>DIRQ14F</name>
                            <description>IRQ14-DS Pin Deep Software Standby Cancel Flag</description>
                            <lsb>6</lsb>
                            <msb>6</msb>
                            <access>read-write</access>
                            <enumeratedValues>
                                </enumeratedValues>
                        </field>
                        <field>
                            <name>DIRQ15F</name>
                            <description>IRQ15-DS Pin Deep Software Standby Cancel Flag</description>
                            <lsb>7</lsb>
                            <msb>7</msb>
                            <access>read-write</access>
                            <enumeratedValues>
                                </enumeratedValues>
                        </field>
                    </fields>
                </register>
                <register>
                    <name>DPSIFR2</name>
                    <description>Deep Software Standby Interrupt Flag Register 2</description>
                    <addressOffset>0x408</addressOffset>
                    <size>8</size>
                    <access>read-write</access>
                    <resetValue>0x00</resetValue>
                    <resetMask>0xff</resetMask>
                    <fields>
                        <field>
                            <name>DLVD1IF</name>
                            <description>LVD1 Deep Software Standby Cancel Flag</description>
                            <lsb>0</lsb>
                            <msb>0</msb>
                            <access>read-write</access>
                            <enumeratedValues>
                                </enumeratedValues>
                        </field>
                        <field>
                            <name>DLVD2IF</name>
                            <description>LVD2 Deep Software Standby Cancel Flag</description>
                            <lsb>1</lsb>
                            <msb>1</msb>
                            <access>read-write</access>
                            <enumeratedValues>
                                </enumeratedValues>
                        </field>
                        <field>
                            <name>DRTCIIF</name>
                            <description>RTC Interval Interrupt Deep Software Standby Cancel Flag</description>
                            <lsb>2</lsb>
                            <msb>2</msb>
                            <access>read-write</access>
                            <enumeratedValues>
                                </enumeratedValues>
                        </field>
                        <field>
                            <name>DRTCAIF</name>
                            <description>RTC Alarm Interrupt Deep Software Standby Cancel Flag</description>
                            <lsb>3</lsb>
                            <msb>3</msb>
                            <access>read-write</access>
                            <enumeratedValues>
                                </enumeratedValues>
                        </field>
                        <field>
                            <name>DNMIF</name>
                            <description>NMI Pin Deep Software Standby Cancel Flag</description>
                            <lsb>4</lsb>
                            <msb>4</msb>
                            <access>read-write</access>
                            <enumeratedValues>
                                </enumeratedValues>
                        </field>
                    </fields>
                </register>
                <register>
                    <name>DPSIFR3</name>
                    <description>Deep Software Standby Interrupt Flag Register 3</description>
                    <addressOffset>0x409</addressOffset>
                    <size>8</size>
                    <access>read-write</access>
                    <resetValue>0x00</resetValue>
                    <resetMask>0xff</resetMask>
                    <fields>
                        <field>
                            <name>DUSBFS0IF</name>
                            <description>USBFS0 Suspend/Resume Deep Software Standby Cancel Flag</description>
                            <lsb>0</lsb>
                            <msb>0</msb>
                            <access>read-write</access>
                            <enumeratedValues>
                                </enumeratedValues>
                        </field>
                        <field>
                            <name>DUSBHSIF</name>
                            <description>USBHS Suspend/Resume Deep Software Standby Cancel Flag</description>
                            <lsb>1</lsb>
                            <msb>1</msb>
                            <access>read-write</access>
                            <enumeratedValues>
                                </enumeratedValues>
                        </field>
                        <field>
                            <name>DAGT1IF</name>
                            <description>AGT1 Underflow Deep Software Standby Cancel Flag</description>
                            <lsb>2</lsb>
                            <msb>2</msb>
                            <access>read-write</access>
                            <enumeratedValues>
                                </enumeratedValues>
                        </field>
                        <field>
                            <name>DAGT3IF</name>
                            <description>AGT3 Underflow Deep Software Standby Cancel Flag</description>
                            <lsb>3</lsb>
                            <msb>3</msb>
                            <access>read-write</access>
                            <enumeratedValues>
                                </enumeratedValues>
                        </field>
                    </fields>
                </register>
                <register>
                    <name>DPSIEGR0</name>
                    <description>Deep Software Standby Interrupt Edge Register 0</description>
                    <addressOffset>0x40A</addressOffset>
                    <size>8</size>
                    <access>read-write</access>
                    <resetValue>0x00</resetValue>
                    <resetMask>0xff</resetMask>
                    <fields>
                        <field>
                            <name>DIRQ0EG</name>
                            <description>IRQ0-DS Pin Edge Select</description>
                            <lsb>0</lsb>
                            <msb>0</msb>
                            <access>read-write</access>
                            <enumeratedValues>
                                </enumeratedValues>
                        </field>
                        <field>
                            <name>DIRQ1EG</name>
                            <description>IRQ1-DS Pin Edge Select</description>
                            <lsb>1</lsb>
                            <msb>1</msb>
                            <access>read-write</access>
                            <enumeratedValues>
                                </enumeratedValues>
                        </field>
                        <field>
                            <name>DIRQ2EG</name>
                            <description>IRQ2-DS Pin Edge Select</description>
                            <lsb>2</lsb>
                            <msb>2</msb>
                            <access>read-write</access>
                            <enumeratedValues>
                                </enumeratedValues>
                        </field>
                        <field>
                            <name>DIRQ3EG</name>
                            <description>IRQ3-DS Pin Edge Select</description>
                            <lsb>3</lsb>
                            <msb>3</msb>
                            <access>read-write</access>
                            <enumeratedValues>
                                </enumeratedValues>
                        </field>
                        <field>
                            <name>DIRQ4EG</name>
                            <description>IRQ4-DS Pin Edge Select</description>
                            <lsb>4</lsb>
                            <msb>4</msb>
                            <access>read-write</access>
                            <enumeratedValues>
                                </enumeratedValues>
                        </field>
                        <field>
                            <name>DIRQ5EG</name>
                            <description>IRQ5-DS Pin Edge Select</description>
                            <lsb>5</lsb>
                            <msb>5</msb>
                            <access>read-write</access>
                            <enumeratedValues>
                                </enumeratedValues>
                        </field>
                        <field>
                            <name>DIRQ6EG</name>
                            <description>IRQ6-DS Pin Edge Select</description>
                            <lsb>6</lsb>
                            <msb>6</msb>
                            <access>read-write</access>
                            <enumeratedValues>
                                </enumeratedValues>
                        </field>
                        <field>
                            <name>DIRQ7EG</name>
                            <description>IRQ7-DS Pin Edge Select</description>
                            <lsb>7</lsb>
                            <msb>7</msb>
                            <access>read-write</access>
                            <enumeratedValues>
                                </enumeratedValues>
                        </field>
                    </fields>
                </register>
                <register>
                    <name>DPSIEGR1</name>
                    <description>Deep Software Standby Interrupt Edge Register 1</description>
                    <addressOffset>0x40B</addressOffset>
                    <size>8</size>
                    <access>read-write</access>
                    <resetValue>0x00</resetValue>
                    <resetMask>0xff</resetMask>
                    <fields>
                        <field>
                            <name>DIRQ8EG</name>
                            <description>IRQ8-DS Pin Edge Select</description>
                            <lsb>0</lsb>
                            <msb>0</msb>
                            <access>read-write</access>
                            <enumeratedValues>
                                </enumeratedValues>
                        </field>
                        <field>
                            <name>DIRQ9EG</name>
                            <description>IRQ9-DS Pin Edge Select</description>
                            <lsb>1</lsb>
                            <msb>1</msb>
                            <access>read-write</access>
                            <enumeratedValues>
                                </enumeratedValues>
                        </field>
                        <field>
                            <name>DIRQ10EG</name>
                            <description>IRQ10-DS Pin Edge Select</description>
                            <lsb>2</lsb>
                            <msb>2</msb>
                            <access>read-write</access>
                            <enumeratedValues>
                                </enumeratedValues>
                        </field>
                        <field>
                            <name>DIRQ11EG</name>
                            <description>IRQ11-DS Pin Edge Select</description>
                            <lsb>3</lsb>
                            <msb>3</msb>
                            <access>read-write</access>
                            <enumeratedValues>
                                </enumeratedValues>
                        </field>
                        <field>
                            <name>DIRQ12EG</name>
                            <description>IRQ12-DS Pin Edge Select</description>
                            <lsb>4</lsb>
                            <msb>4</msb>
                            <access>read-write</access>
                            <enumeratedValues>
                                </enumeratedValues>
                        </field>
                        <field>
                            <name>DIRQ13EG</name>
                            <description>IRQ13-DS Pin Edge Select</description>
                            <lsb>5</lsb>
                            <msb>5</msb>
                            <access>read-write</access>
                            <enumeratedValues>
                                </enumeratedValues>
                        </field>
                        <field>
                            <name>DIRQ14EG</name>
                            <description>IRQ14-DS Pin Edge Select</description>
                            <lsb>6</lsb>
                            <msb>6</msb>
                            <access>read-write</access>
                            <enumeratedValues>
                                </enumeratedValues>
                        </field>
                        <field>
                            <name>DIRQ15EG</name>
                            <description>IRQ15-DS Pin Edge Select</description>
                            <lsb>7</lsb>
                            <msb>7</msb>
                            <access>read-write</access>
                            <enumeratedValues>
                                </enumeratedValues>
                        </field>
                    </fields>
                </register>
                <register>
                    <name>DPSIEGR2</name>
                    <description>Deep Software Standby Interrupt Edge Register 2</description>
                    <addressOffset>0x40C</addressOffset>
                    <size>8</size>
                    <access>read-write</access>
                    <resetValue>0x00</resetValue>
                    <resetMask>0xff</resetMask>
                    <fields>
                        <field>
                            <name>DLVD1EG</name>
                            <description>LVD1 Edge Select</description>
                            <lsb>0</lsb>
                            <msb>0</msb>
                            <access>read-write</access>
                            <enumeratedValues>
                                </enumeratedValues>
                        </field>
                        <field>
                            <name>DLVD2EG</name>
                            <description>LVD2 Edge Select</description>
                            <lsb>1</lsb>
                            <msb>1</msb>
                            <access>read-write</access>
                            <enumeratedValues>
                                </enumeratedValues>
                        </field>
                        <field>
                            <name>DNMIEG</name>
                            <description>NMI Pin Edge Select</description>
                            <lsb>4</lsb>
                            <msb>4</msb>
                            <access>read-write</access>
                            <enumeratedValues>
                                </enumeratedValues>
                        </field>
                    </fields>
                </register>
                <register>
                    <name>SYOCDCR</name>
                    <description>System Control OCD Control Register</description>
                    <addressOffset>0x040E</addressOffset>
                    <size>8</size>
                    <access>read-write</access>
                    <resetValue>0x00</resetValue>
                    <resetMask>0xfe</resetMask>
                    <fields>
                        <field>
                            <name>DOCDF</name>
                            <description>Deep Software Standby OCD flag</description>
                            <lsb>0</lsb>
                            <msb>0</msb>
                            <access>read-write</access>
                            <enumeratedValues>
                                </enumeratedValues>
                        </field>
                        <field>
                            <name>DBGEN</name>
                            <description>Debugger Enable bit</description>
                            <lsb>7</lsb>
                            <msb>7</msb>
                            <access>read-write</access>
                            <enumeratedValues>
                                </enumeratedValues>
                        </field>
                    </fields>
                </register>
                <register>
                    <name>RSTSR0</name>
                    <description>Reset Status Register 0</description>
                    <addressOffset>0x410</addressOffset>
                    <size>8</size>
                    <access>read-write</access>
                    <resetValue>0x00</resetValue>
                    <resetMask>0x70</resetMask>
                    <fields>
                        <field>
                            <name>PORF</name>
                            <description>Power,On Reset Detect Flag</description>
                            <lsb>0</lsb>
                            <msb>0</msb>
                            <access>read-write</access>
                            <enumeratedValues>
                                </enumeratedValues>
                        </field>
                        <field>
                            <name>LVD0RF</name>
                            <description>Voltage Monitor 0 Reset Detect Flag</description>
                            <lsb>1</lsb>
                            <msb>1</msb>
                            <access>read-write</access>
                            <enumeratedValues>
                                </enumeratedValues>
                        </field>
                        <field>
                            <name>LVD1RF</name>
                            <description>Voltage Monitor 1 Reset Detect Flag</description>
                            <lsb>2</lsb>
                            <msb>2</msb>
                            <access>read-write</access>
                            <enumeratedValues>
                                </enumeratedValues>
                        </field>
                        <field>
                            <name>LVD2RF</name>
                            <description>Voltage Monitor 2 Reset Detect Flag</description>
                            <lsb>3</lsb>
                            <msb>3</msb>
                            <access>read-write</access>
                            <enumeratedValues>
                                </enumeratedValues>
                        </field>
                        <field>
                            <name>DPSRSTF</name>
                            <description>Deep Software Standby Reset Detect Flag</description>
                            <lsb>7</lsb>
                            <msb>7</msb>
                            <access>read-write</access>
                            <enumeratedValues>
                                </enumeratedValues>
                        </field>
                    </fields>
                </register>
                <register>
                    <name>RSTSR2</name>
                    <description>Reset Status Register 2</description>
                    <addressOffset>0x411</addressOffset>
                    <size>8</size>
                    <access>read-write</access>
                    <resetValue>0x00</resetValue>
                    <resetMask>0xfe</resetMask>
                    <fields>
                        <field>
                            <name>CWSF</name>
                            <description>Cold/Warm Start Determination Flag</description>
                            <lsb>0</lsb>
                            <msb>0</msb>
                            <access>read-write</access>
                            <enumeratedValues>
                                </enumeratedValues>
                        </field>
                    </fields>
                </register>
                <register>
                    <name>MOMCR</name>
                    <description>Main Clock Oscillator Mode Oscillation Control Register</description>
                    <addressOffset>0x413</addressOffset>
                    <size>8</size>
                    <access>read-write</access>
                    <resetValue>0x00</resetValue>
                    <resetMask>0xff</resetMask>
                    <fields>
                        <field>
                            <name>MODRV</name>
                            <description>Main Clock Oscillator Drive Capability 0 Switching</description>
                            <lsb>4</lsb>
                            <msb>5</msb>
                            <access>read-write</access>
                            <enumeratedValues>
                                </enumeratedValues>
                        </field>
                        <field>
                            <name>MOSEL</name>
                            <description>Main Clock Oscillator Switching</description>
                            <lsb>6</lsb>
                            <msb>6</msb>
                            <access>read-write</access>
                            <enumeratedValues>
                                </enumeratedValues>
                        </field>
                    </fields>
                </register>
                <register>
                    <name>FWEPROR</name>
                    <description>Flash P/E Protect Register</description>
                    <addressOffset>0x416</addressOffset>
                    <size>8</size>
                    <access>read-write</access>
                    <resetValue>0x02</resetValue>
                    <resetMask>0xff</resetMask>
                    <fields>
                        <field>
                            <name>FLWE</name>
                            <description>Flash Programming and Erasure</description>
                            <lsb>0</lsb>
                            <msb>1</msb>
                            <access>read-write</access>
                            <enumeratedValues>
                                </enumeratedValues>
                        </field>
                    </fields>
                </register>
                <register>
                    <name>LVD1CMPCR</name>
                    <description>Voltage Monitoring 1 Comparator Control Register</description>
                    <addressOffset>0x417</addressOffset>
                    <size>8</size>
                    <access>read-write</access>
                    <resetValue>0x13</resetValue>
                    <resetMask>0xff</resetMask>
                    <fields>
                        <field>
                            <name>LVD1LVL</name>
                            <description>Voltage Detection 1 Level Select (Standard voltage during drop in voltage)</description>
                            <lsb>0</lsb>
                            <msb>4</msb>
                            <access>read-write</access>
                            <enumeratedValues>
                                </enumeratedValues>
                        </field>
                        <field>
                            <name>LVD1E</name>
                            <description>Voltage Detection 1 Enable</description>
                            <lsb>7</lsb>
                            <msb>7</msb>
                            <access>read-write</access>
                            <enumeratedValues>
                                </enumeratedValues>
                        </field>
                    </fields>
                </register>
                <register>
                    <name>LVD2CMPCR</name>
                    <description>Voltage Monitoring 2 Comparator Control Register</description>
                    <addressOffset>0x418</addressOffset>
                    <size>8</size>
                    <access>read-write</access>
                    <resetValue>0x07</resetValue>
                    <resetMask>0xff</resetMask>
                    <fields>
                        <field>
                            <name>LVD2LVL</name>
                            <description>Voltage Detection 2 Level Select (Standard voltage during drop in voltage)</description>
                            <lsb>0</lsb>
                            <msb>2</msb>
                            <access>read-write</access>
                            <enumeratedValues>
                                </enumeratedValues>
                        </field>
                        <field>
                            <name>LVD2E</name>
                            <description>Voltage Detection 2 Enable</description>
                            <lsb>7</lsb>
                            <msb>7</msb>
                            <access>read-write</access>
                            <enumeratedValues>
                                </enumeratedValues>
                        </field>
                    </fields>
                </register>
                <register>
                    <name>LVD1CR0</name>
                    <description>Voltage Monitor 1 Circuit Control Register 0</description>
                    <addressOffset>0x41A</addressOffset>
                    <size>8</size>
                    <access>read-write</access>
                    <resetValue>0x82</resetValue>
                    <resetMask>0xf7</resetMask>
                    <fields>
                        <field>
                            <name>RIE</name>
                            <description>Voltage Monitor 1 Interrupt/Reset Enable</description>
                            <lsb>0</lsb>
                            <msb>0</msb>
                            <access>read-write</access>
                            <enumeratedValues>
                                </enumeratedValues>
                        </field>
                        <field>
                            <name>DFDIS</name>
                            <description>Voltage monitor 1 Digital Filter Disabled Mode Select</description>
                            <lsb>1</lsb>
                            <msb>1</msb>
                            <access>read-write</access>
                            <enumeratedValues>
                                </enumeratedValues>
                        </field>
                        <field>
                            <name>CMPE</name>
                            <description>Voltage Monitor 1 Circuit Comparison Result Output Enable</description>
                            <lsb>2</lsb>
                            <msb>2</msb>
                            <access>read-write</access>
                            <enumeratedValues>
                                </enumeratedValues>
                        </field>
                        <field>
                            <name>FSAMP</name>
                            <description>Sampling Clock Select</description>
                            <lsb>4</lsb>
                            <msb>5</msb>
                            <access>read-write</access>
                            <enumeratedValues>
                                </enumeratedValues>
                        </field>
                        <field>
                            <name>RI</name>
                            <description>Voltage Monitor 1 Circuit Mode Select</description>
                            <lsb>6</lsb>
                            <msb>6</msb>
                            <access>read-write</access>
                            <enumeratedValues>
                                </enumeratedValues>
                        </field>
                        <field>
                            <name>RN</name>
                            <description>Voltage Monitor 1 Reset Negate Select</description>
                            <lsb>7</lsb>
                            <msb>7</msb>
                            <access>read-write</access>
                            <enumeratedValues>
                                </enumeratedValues>
                        </field>
                    </fields>
                </register>
                <register>
                    <name>LVD2CR0</name>
                    <description>Voltage Monitor 2 Circuit Control Register 0</description>
                    <addressOffset>0x41B</addressOffset>
                    <size>8</size>
                    <access>read-write</access>
                    <resetValue>0x82</resetValue>
                    <resetMask>0xf7</resetMask>
                    <fields>
                        <field>
                            <name>RIE</name>
                            <description>Voltage Monitor 2 Interrupt/Reset Enable</description>
                            <lsb>0</lsb>
                            <msb>0</msb>
                            <access>read-write</access>
                            <enumeratedValues>
                                </enumeratedValues>
                        </field>
                        <field>
                            <name>DFDIS</name>
                            <description>Voltage monitor 2 Digital Filter Disabled Mode Select</description>
                            <lsb>1</lsb>
                            <msb>1</msb>
                            <access>read-write</access>
                            <enumeratedValues>
                                </enumeratedValues>
                        </field>
                        <field>
                            <name>CMPE</name>
                            <description>Voltage Monitor 2 Circuit Comparison Result Output Enable</description>
                            <lsb>2</lsb>
                            <msb>2</msb>
                            <access>read-write</access>
                            <enumeratedValues>
                                </enumeratedValues>
                        </field>
                        <field>
                            <name>FSAMP</name>
                            <description>Sampling Clock Select</description>
                            <lsb>4</lsb>
                            <msb>5</msb>
                            <access>read-write</access>
                            <enumeratedValues>
                                </enumeratedValues>
                        </field>
                        <field>
                            <name>RI</name>
                            <description>Voltage Monitor 2 Circuit Mode Select</description>
                            <lsb>6</lsb>
                            <msb>6</msb>
                            <access>read-write</access>
                            <enumeratedValues>
                                </enumeratedValues>
                        </field>
                        <field>
                            <name>RN</name>
                            <description>Voltage Monitor 2 Reset Negate Select</description>
                            <lsb>7</lsb>
                            <msb>7</msb>
                            <access>read-write</access>
                            <enumeratedValues>
                                </enumeratedValues>
                        </field>
                    </fields>
                </register>
                <register>
                    <name>VBATTMNSELR</name>
                    <description>Battery Backup Voltage Monitor Function Select Register</description>
                    <addressOffset>0x41D</addressOffset>
                    <size>8</size>
                    <access>read-write</access>
                    <resetValue>0x00</resetValue>
                    <resetMask>0xff</resetMask>
                    <fields>
                        <field>
                            <name>VBATTMNSEL</name>
                            <description>VBATT Low Voltage Detect Function Select Bit</description>
                            <lsb>0</lsb>
                            <msb>0</msb>
                            <access>read-write</access>
                            <enumeratedValues>
                                </enumeratedValues>
                        </field>
                    </fields>
                </register>
                <register>
                    <name>VBATTMONR</name>
                    <description>Battery Backup Voltage Monitor Register</description>
                    <addressOffset>0x41E</addressOffset>
                    <size>8</size>
                    <access>read-only</access>
                    <resetValue>0x00</resetValue>
                    <resetMask>0xff</resetMask>
                    <fields>
                        <field>
                            <name>VBATTMON</name>
                            <description>VBATT Voltage Monitor Bit</description>
                            <lsb>0</lsb>
                            <msb>0</msb>
                            <access>read-only</access>
                            <enumeratedValues>
                                </enumeratedValues>
                        </field>
                    </fields>
                </register>
                <register>
                    <name>SOSCCR</name>
                    <description>Sub,Clock Oscillator Control Register</description>
                    <addressOffset>0x480</addressOffset>
                    <size>8</size>
                    <access>read-write</access>
                    <resetValue>0x00</resetValue>
                    <resetMask>0xff</resetMask>
                    <fields>
                        <field>
                            <name>SOSTP</name>
                            <description>Sub Clock Oscillator Stop</description>
                            <lsb>0</lsb>
                            <msb>0</msb>
                            <access>read-write</access>
                            <enumeratedValues>
                                </enumeratedValues>
                        </field>
                    </fields>
                </register>
                <register>
                    <name>SOMCR</name>
                    <description>Sub,Clock Oscillator Mode Control Register</description>
                    <addressOffset>0x481</addressOffset>
                    <size>8</size>
                    <access>read-write</access>
                    <resetValue>0x00</resetValue>
                    <resetMask>0xff</resetMask>
                    <fields>
                        <field>
                            <name>SODRV</name>
                            <description>Sub,Clock Oscillator Drive Capability Switching</description>
                            <lsb>1</lsb>
                            <msb>1</msb>
                            <access>read-write</access>
                            <enumeratedValues>
                                </enumeratedValues>
                        </field>
                    </fields>
                </register>
                <register>
                    <name>LOCOCR</name>
                    <description>Low,Speed On,Chip Oscillator Control Register</description>
                    <addressOffset>0x490</addressOffset>
                    <size>8</size>
                    <access>read-write</access>
                    <resetValue>0x00</resetValue>
                    <resetMask>0xff</resetMask>
                    <fields>
                        <field>
                            <name>LCSTP</name>
                            <description>LOCO Stop</description>
                            <lsb>0</lsb>
                            <msb>0</msb>
                            <access>read-write</access>
                            <enumeratedValues>
                                </enumeratedValues>
                        </field>
                    </fields>
                </register>
                <register>
                    <name>LOCOUTCR</name>
                    <description>LOCO User Trimming Control Register</description>
                    <addressOffset>0x492</addressOffset>
                    <size>8</size>
                    <access>read-write</access>
                    <resetValue>0x00</resetValue>
                    <resetMask>0xff</resetMask>
                    <fields>
                        <field>
                            <name>LOCOUTRM</name>
                            <description>LOCO User Trimming</description>
                            <lsb>0</lsb>
                            <msb>7</msb>
                            <access>read-write</access>
                        </field>
                    </fields>
                </register>
                <register>
                    <name>VBTICTLR</name>
                    <description>VBATT Input Control Register</description>
                    <addressOffset>0x4BB</addressOffset>
                    <size>8</size>
                    <access>read-write</access>
                    <resetValue>0x00</resetValue>
                    <resetMask>0xf8</resetMask>
                    <fields>
                        <field>
                            <name>VCH0INEN</name>
                            <description>VBATT CH0 Input Enable</description>
                            <lsb>0</lsb>
                            <msb>0</msb>
                            <access>read-write</access>
                            <enumeratedValues>
                                </enumeratedValues>
                        </field>
                        <field>
                            <name>VCH1INEN</name>
                            <description>VBATT CH1 Input Enable</description>
                            <lsb>1</lsb>
                            <msb>1</msb>
                            <access>read-write</access>
                            <enumeratedValues>
                                </enumeratedValues>
                        </field>
                        <field>
                            <name>VCH2INEN</name>
                            <description>VBATT CH2 Input Enable</description>
                            <lsb>2</lsb>
                            <msb>2</msb>
                            <access>read-write</access>
                            <enumeratedValues>
                                </enumeratedValues>
                        </field>
                    </fields>
                </register>
                <register>
                    <name>VBTBER</name>
                    <description>VBATT Backup Enable Register</description>
                    <addressOffset>0x4C0</addressOffset>
                    <size>8</size>
                    <access>read-write</access>
                    <resetValue>0x08</resetValue>
                    <resetMask>0xff</resetMask>
                    <fields>
                        <field>
                            <name>VBAE</name>
                            <description>VBATT backup register access enable bit</description>
                            <lsb>3</lsb>
                            <msb>3</msb>
                            <access>read-write</access>
                            <enumeratedValues>
                                </enumeratedValues>
                        </field>
                    </fields>
                </register>
                <register>
                    <dim>128</dim>
                    <dimIncrement>0x001</dimIncrement>
                    <name>VBTBKR[%s]</name>
                    <description>VBATT Backup Register</description>
                    <addressOffset>0x500</addressOffset>
                    <size>8</size>
                    <access>read-write</access>
                    <resetValue>0x00</resetValue>
                    <resetMask>0x00</resetMask>
                    <fields>
                        <field>
                            <name>VBTBKR</name>
                            <description>VBATT Backup Register</description>
                            <lsb>0</lsb>
                            <msb>7</msb>
                            <access>read-write</access>
                        </field>
                    </fields>
                </register>
            </registers>
        </peripheral>
        <peripheral>
            <name>PORT0</name>
            <description>Pmn Pin FunctionPort 0 Control RegistersPmn Pin Function Control Register</description>
            <baseAddress>0x40080000</baseAddress>
            <addressBlock>
                <offset>0x00</offset>
                <size>12</size>
                <usage>registers</usage>
            </addressBlock>
            <registers>
                <register>
                    <name>PCNTR1</name>
                    <description>Port Control Register 1</description>
                    <addressOffset>0x000</addressOffset>
                    <size>32</size>
                    <access>read-write</access>
                    <resetValue>0x00000000</resetValue>
                    <resetMask>0xffffffff</resetMask>
                    <fields>
                        <field>
                            <name>PDR00</name>
                            <description>Pmn Direction</description>
                            <lsb>0</lsb>
                            <msb>0</msb>
                            <access>read-write</access>
                            <enumeratedValues>
                                </enumeratedValues>
                        </field>
                        <field>
                            <name>PDR01</name>
                            <description>Pmn Direction</description>
                            <lsb>1</lsb>
                            <msb>1</msb>
                            <access>read-write</access>
                            <enumeratedValues>
                                </enumeratedValues>
                        </field>
                        <field>
                            <name>PDR02</name>
                            <description>Pmn Direction</description>
                            <lsb>2</lsb>
                            <msb>2</msb>
                            <access>read-write</access>
                            <enumeratedValues>
                                </enumeratedValues>
                        </field>
                        <field>
                            <name>PDR03</name>
                            <description>Pmn Direction</description>
                            <lsb>3</lsb>
                            <msb>3</msb>
                            <access>read-write</access>
                            <enumeratedValues>
                                </enumeratedValues>
                        </field>
                        <field>
                            <name>PDR04</name>
                            <description>Pmn Direction</description>
                            <lsb>4</lsb>
                            <msb>4</msb>
                            <access>read-write</access>
                            <enumeratedValues>
                                </enumeratedValues>
                        </field>
                        <field>
                            <name>PDR05</name>
                            <description>Pmn Direction</description>
                            <lsb>5</lsb>
                            <msb>5</msb>
                            <access>read-write</access>
                            <enumeratedValues>
                                </enumeratedValues>
                        </field>
                        <field>
                            <name>PDR06</name>
                            <description>Pmn Direction</description>
                            <lsb>6</lsb>
                            <msb>6</msb>
                            <access>read-write</access>
                            <enumeratedValues>
                                </enumeratedValues>
                        </field>
                        <field>
                            <name>PDR07</name>
                            <description>Pmn Direction</description>
                            <lsb>7</lsb>
                            <msb>7</msb>
                            <access>read-write</access>
                            <enumeratedValues>
                                </enumeratedValues>
                        </field>
                        <field>
                            <name>PDR08</name>
                            <description>Pmn Direction</description>
                            <lsb>8</lsb>
                            <msb>8</msb>
                            <access>read-write</access>
                            <enumeratedValues>
                                </enumeratedValues>
                        </field>
                        <field>
                            <name>PDR09</name>
                            <description>Pmn Direction</description>
                            <lsb>9</lsb>
                            <msb>9</msb>
                            <access>read-write</access>
                            <enumeratedValues>
                                </enumeratedValues>
                        </field>
                        <field>
                            <name>PDR10</name>
                            <description>Pmn Direction</description>
                            <lsb>10</lsb>
                            <msb>10</msb>
                            <access>read-write</access>
                            <enumeratedValues>
                                </enumeratedValues>
                        </field>
                        <field>
                            <name>PDR11</name>
                            <description>Pmn Direction</description>
                            <lsb>11</lsb>
                            <msb>11</msb>
                            <access>read-write</access>
                            <enumeratedValues>
                                </enumeratedValues>
                        </field>
                        <field>
                            <name>PDR12</name>
                            <description>Pmn Direction</description>
                            <lsb>12</lsb>
                            <msb>12</msb>
                            <access>read-write</access>
                            <enumeratedValues>
                                </enumeratedValues>
                        </field>
                        <field>
                            <name>PDR13</name>
                            <description>Pmn Direction</description>
                            <lsb>13</lsb>
                            <msb>13</msb>
                            <access>read-write</access>
                            <enumeratedValues>
                                </enumeratedValues>
                        </field>
                        <field>
                            <name>PDR14</name>
                            <description>Pmn Direction</description>
                            <lsb>14</lsb>
                            <msb>14</msb>
                            <access>read-write</access>
                            <enumeratedValues>
                                </enumeratedValues>
                        </field>
                        <field>
                            <name>PDR15</name>
                            <description>Pmn Direction</description>
                            <lsb>15</lsb>
                            <msb>15</msb>
                            <access>read-write</access>
                            <enumeratedValues>
                                </enumeratedValues>
                        </field>
                        <field>
                            <name>PODR00</name>
                            <description>Pmn Output Data</description>
                            <lsb>16</lsb>
                            <msb>16</msb>
                            <access>read-write</access>
                            <enumeratedValues>
                                </enumeratedValues>
                        </field>
                        <field>
                            <name>PODR01</name>
                            <description>Pmn Output Data</description>
                            <lsb>17</lsb>
                            <msb>17</msb>
                            <access>read-write</access>
                            <enumeratedValues>
                                </enumeratedValues>
                        </field>
                        <field>
                            <name>PODR02</name>
                            <description>Pmn Output Data</description>
                            <lsb>18</lsb>
                            <msb>18</msb>
                            <access>read-write</access>
                            <enumeratedValues>
                                </enumeratedValues>
                        </field>
                        <field>
                            <name>PODR03</name>
                            <description>Pmn Output Data</description>
                            <lsb>19</lsb>
                            <msb>19</msb>
                            <access>read-write</access>
                            <enumeratedValues>
                                </enumeratedValues>
                        </field>
                        <field>
                            <name>PODR04</name>
                            <description>Pmn Output Data</description>
                            <lsb>20</lsb>
                            <msb>20</msb>
                            <access>read-write</access>
                            <enumeratedValues>
                                </enumeratedValues>
                        </field>
                        <field>
                            <name>PODR05</name>
                            <description>Pmn Output Data</description>
                            <lsb>21</lsb>
                            <msb>21</msb>
                            <access>read-write</access>
                            <enumeratedValues>
                                </enumeratedValues>
                        </field>
                        <field>
                            <name>PODR06</name>
                            <description>Pmn Output Data</description>
                            <lsb>22</lsb>
                            <msb>22</msb>
                            <access>read-write</access>
                            <enumeratedValues>
                                </enumeratedValues>
                        </field>
                        <field>
                            <name>PODR07</name>
                            <description>Pmn Output Data</description>
                            <lsb>23</lsb>
                            <msb>23</msb>
                            <access>read-write</access>
                            <enumeratedValues>
                                </enumeratedValues>
                        </field>
                        <field>
                            <name>PODR08</name>
                            <description>Pmn Output Data</description>
                            <lsb>24</lsb>
                            <msb>24</msb>
                            <access>read-write</access>
                            <enumeratedValues>
                                </enumeratedValues>
                        </field>
                        <field>
                            <name>PODR09</name>
                            <description>Pmn Output Data</description>
                            <lsb>25</lsb>
                            <msb>25</msb>
                            <access>read-write</access>
                            <enumeratedValues>
                                </enumeratedValues>
                        </field>
                        <field>
                            <name>PODR10</name>
                            <description>Pmn Output Data</description>
                            <lsb>26</lsb>
                            <msb>26</msb>
                            <access>read-write</access>
                            <enumeratedValues>
                                </enumeratedValues>
                        </field>
                        <field>
                            <name>PODR11</name>
                            <description>Pmn Output Data</description>
                            <lsb>27</lsb>
                            <msb>27</msb>
                            <access>read-write</access>
                            <enumeratedValues>
                                </enumeratedValues>
                        </field>
                        <field>
                            <name>PODR12</name>
                            <description>Pmn Output Data</description>
                            <lsb>28</lsb>
                            <msb>28</msb>
                            <access>read-write</access>
                            <enumeratedValues>
                                </enumeratedValues>
                        </field>
                        <field>
                            <name>PODR13</name>
                            <description>Pmn Output Data</description>
                            <lsb>29</lsb>
                            <msb>29</msb>
                            <access>read-write</access>
                            <enumeratedValues>
                                </enumeratedValues>
                        </field>
                        <field>
                            <name>PODR14</name>
                            <description>Pmn Output Data</description>
                            <lsb>30</lsb>
                            <msb>30</msb>
                            <access>read-write</access>
                            <enumeratedValues>
                                </enumeratedValues>
                        </field>
                        <field>
                            <name>PODR15</name>
                            <description>Pmn Output Data</description>
                            <lsb>31</lsb>
                            <msb>31</msb>
                            <access>read-write</access>
                            <enumeratedValues>
                                </enumeratedValues>
                        </field>
                    </fields>
                </register>
                <register>
                    <name>PODR</name>
                    <description>Port Control Register 1</description>
                    <alternateRegister>PCNTR1</alternateRegister>
                    <addressOffset>0x000</addressOffset>
                    <size>16</size>
                    <access>read-write</access>
                    <resetValue>0x0000</resetValue>
                    <resetMask>0xffff</resetMask>
                    <fields>
                        <field>
                            <name>PODR00</name>
                            <description>Pmn Output Data</description>
                            <lsb>0</lsb>
                            <msb>0</msb>
                            <access>read-write</access>
                            <enumeratedValues>
                                </enumeratedValues>
                        </field>
                        <field>
                            <name>PODR01</name>
                            <description>Pmn Output Data</description>
                            <lsb>1</lsb>
                            <msb>1</msb>
                            <access>read-write</access>
                            <enumeratedValues>
                                </enumeratedValues>
                        </field>
                        <field>
                            <name>PODR02</name>
                            <description>Pmn Output Data</description>
                            <lsb>2</lsb>
                            <msb>2</msb>
                            <access>read-write</access>
                            <enumeratedValues>
                                </enumeratedValues>
                        </field>
                        <field>
                            <name>PODR03</name>
                            <description>Pmn Output Data</description>
                            <lsb>3</lsb>
                            <msb>3</msb>
                            <access>read-write</access>
                            <enumeratedValues>
                                </enumeratedValues>
                        </field>
                        <field>
                            <name>PODR04</name>
                            <description>Pmn Output Data</description>
                            <lsb>4</lsb>
                            <msb>4</msb>
                            <access>read-write</access>
                            <enumeratedValues>
                                </enumeratedValues>
                        </field>
                        <field>
                            <name>PODR05</name>
                            <description>Pmn Output Data</description>
                            <lsb>5</lsb>
                            <msb>5</msb>
                            <access>read-write</access>
                            <enumeratedValues>
                                </enumeratedValues>
                        </field>
                        <field>
                            <name>PODR06</name>
                            <description>Pmn Output Data</description>
                            <lsb>6</lsb>
                            <msb>6</msb>
                            <access>read-write</access>
                            <enumeratedValues>
                                </enumeratedValues>
                        </field>
                        <field>
                            <name>PODR07</name>
                            <description>Pmn Output Data</description>
                            <lsb>7</lsb>
                            <msb>7</msb>
                            <access>read-write</access>
                            <enumeratedValues>
                                </enumeratedValues>
                        </field>
                        <field>
                            <name>PODR08</name>
                            <description>Pmn Output Data</description>
                            <lsb>8</lsb>
                            <msb>8</msb>
                            <access>read-write</access>
                            <enumeratedValues>
                                </enumeratedValues>
                        </field>
                        <field>
                            <name>PODR09</name>
                            <description>Pmn Output Data</description>
                            <lsb>9</lsb>
                            <msb>9</msb>
                            <access>read-write</access>
                            <enumeratedValues>
                                </enumeratedValues>
                        </field>
                        <field>
                            <name>PODR10</name>
                            <description>Pmn Output Data</description>
                            <lsb>10</lsb>
                            <msb>10</msb>
                            <access>read-write</access>
                            <enumeratedValues>
                                </enumeratedValues>
                        </field>
                        <field>
                            <name>PODR11</name>
                            <description>Pmn Output Data</description>
                            <lsb>11</lsb>
                            <msb>11</msb>
                            <access>read-write</access>
                            <enumeratedValues>
                                </enumeratedValues>
                        </field>
                        <field>
                            <name>PODR12</name>
                            <description>Pmn Output Data</description>
                            <lsb>12</lsb>
                            <msb>12</msb>
                            <access>read-write</access>
                            <enumeratedValues>
                                </enumeratedValues>
                        </field>
                        <field>
                            <name>PODR13</name>
                            <description>Pmn Output Data</description>
                            <lsb>13</lsb>
                            <msb>13</msb>
                            <access>read-write</access>
                            <enumeratedValues>
                                </enumeratedValues>
                        </field>
                        <field>
                            <name>PODR14</name>
                            <description>Pmn Output Data</description>
                            <lsb>14</lsb>
                            <msb>14</msb>
                            <access>read-write</access>
                            <enumeratedValues>
                                </enumeratedValues>
                        </field>
                        <field>
                            <name>PODR15</name>
                            <description>Pmn Output Data</description>
                            <lsb>15</lsb>
                            <msb>15</msb>
                            <access>read-write</access>
                            <enumeratedValues>
                                </enumeratedValues>
                        </field>
                    </fields>
                </register>
                <register>
                    <name>PDR</name>
                    <description>Port Control Register 1</description>
                    <alternateRegister>PCNTR1</alternateRegister>
                    <addressOffset>0x002</addressOffset>
                    <size>16</size>
                    <access>read-write</access>
                    <resetValue>0x0000</resetValue>
                    <resetMask>0xffff</resetMask>
                    <fields>
                        <field>
                            <name>PDR00</name>
                            <description>Pmn Direction</description>
                            <lsb>0</lsb>
                            <msb>0</msb>
                            <access>read-write</access>
                            <enumeratedValues>
                                </enumeratedValues>
                        </field>
                        <field>
                            <name>PDR01</name>
                            <description>Pmn Direction</description>
                            <lsb>1</lsb>
                            <msb>1</msb>
                            <access>read-write</access>
                            <enumeratedValues>
                                </enumeratedValues>
                        </field>
                        <field>
                            <name>PDR02</name>
                            <description>Pmn Direction</description>
                            <lsb>2</lsb>
                            <msb>2</msb>
                            <access>read-write</access>
                            <enumeratedValues>
                                </enumeratedValues>
                        </field>
                        <field>
                            <name>PDR03</name>
                            <description>Pmn Direction</description>
                            <lsb>3</lsb>
                            <msb>3</msb>
                            <access>read-write</access>
                            <enumeratedValues>
                                </enumeratedValues>
                        </field>
                        <field>
                            <name>PDR04</name>
                            <description>Pmn Direction</description>
                            <lsb>4</lsb>
                            <msb>4</msb>
                            <access>read-write</access>
                            <enumeratedValues>
                                </enumeratedValues>
                        </field>
                        <field>
                            <name>PDR05</name>
                            <description>Pmn Direction</description>
                            <lsb>5</lsb>
                            <msb>5</msb>
                            <access>read-write</access>
                            <enumeratedValues>
                                </enumeratedValues>
                        </field>
                        <field>
                            <name>PDR06</name>
                            <description>Pmn Direction</description>
                            <lsb>6</lsb>
                            <msb>6</msb>
                            <access>read-write</access>
                            <enumeratedValues>
                                </enumeratedValues>
                        </field>
                        <field>
                            <name>PDR07</name>
                            <description>Pmn Direction</description>
                            <lsb>7</lsb>
                            <msb>7</msb>
                            <access>read-write</access>
                            <enumeratedValues>
                                </enumeratedValues>
                        </field>
                        <field>
                            <name>PDR08</name>
                            <description>Pmn Direction</description>
                            <lsb>8</lsb>
                            <msb>8</msb>
                            <access>read-write</access>
                            <enumeratedValues>
                                </enumeratedValues>
                        </field>
                        <field>
                            <name>PDR09</name>
                            <description>Pmn Direction</description>
                            <lsb>9</lsb>
                            <msb>9</msb>
                            <access>read-write</access>
                            <enumeratedValues>
                                </enumeratedValues>
                        </field>
                        <field>
                            <name>PDR10</name>
                            <description>Pmn Direction</description>
                            <lsb>10</lsb>
                            <msb>10</msb>
                            <access>read-write</access>
                            <enumeratedValues>
                                </enumeratedValues>
                        </field>
                        <field>
                            <name>PDR11</name>
                            <description>Pmn Direction</description>
                            <lsb>11</lsb>
                            <msb>11</msb>
                            <access>read-write</access>
                            <enumeratedValues>
                                </enumeratedValues>
                        </field>
                        <field>
                            <name>PDR12</name>
                            <description>Pmn Direction</description>
                            <lsb>12</lsb>
                            <msb>12</msb>
                            <access>read-write</access>
                            <enumeratedValues>
                                </enumeratedValues>
                        </field>
                        <field>
                            <name>PDR13</name>
                            <description>Pmn Direction</description>
                            <lsb>13</lsb>
                            <msb>13</msb>
                            <access>read-write</access>
                            <enumeratedValues>
                                </enumeratedValues>
                        </field>
                        <field>
                            <name>PDR14</name>
                            <description>Pmn Direction</description>
                            <lsb>14</lsb>
                            <msb>14</msb>
                            <access>read-write</access>
                            <enumeratedValues>
                                </enumeratedValues>
                        </field>
                        <field>
                            <name>PDR15</name>
                            <description>Pmn Direction</description>
                            <lsb>15</lsb>
                            <msb>15</msb>
                            <access>read-write</access>
                            <enumeratedValues>
                                </enumeratedValues>
                        </field>
                    </fields>
                </register>
                <register>
                    <name>PCNTR2</name>
                    <description>Port Control Register 2</description>
                    <addressOffset>0x004</addressOffset>
                    <size>32</size>
                    <access>read-only</access>
                    <resetValue>0x00000000</resetValue>
                    <resetMask>0xffff0000</resetMask>
                    <fields>
                        <field>
                            <name>PIDR00</name>
                            <description>Pmn State</description>
                            <lsb>0</lsb>
                            <msb>0</msb>
                            <access>read-only</access>
                            <enumeratedValues>
                                </enumeratedValues>
                        </field>
                        <field>
                            <name>PIDR01</name>
                            <description>Pmn State</description>
                            <lsb>1</lsb>
                            <msb>1</msb>
                            <access>read-only</access>
                            <enumeratedValues>
                                </enumeratedValues>
                        </field>
                        <field>
                            <name>PIDR02</name>
                            <description>Pmn State</description>
                            <lsb>2</lsb>
                            <msb>2</msb>
                            <access>read-only</access>
                            <enumeratedValues>
                                </enumeratedValues>
                        </field>
                        <field>
                            <name>PIDR03</name>
                            <description>Pmn State</description>
                            <lsb>3</lsb>
                            <msb>3</msb>
                            <access>read-only</access>
                            <enumeratedValues>
                                </enumeratedValues>
                        </field>
                        <field>
                            <name>PIDR04</name>
                            <description>Pmn State</description>
                            <lsb>4</lsb>
                            <msb>4</msb>
                            <access>read-only</access>
                            <enumeratedValues>
                                </enumeratedValues>
                        </field>
                        <field>
                            <name>PIDR05</name>
                            <description>Pmn State</description>
                            <lsb>5</lsb>
                            <msb>5</msb>
                            <access>read-only</access>
                            <enumeratedValues>
                                </enumeratedValues>
                        </field>
                        <field>
                            <name>PIDR06</name>
                            <description>Pmn State</description>
                            <lsb>6</lsb>
                            <msb>6</msb>
                            <access>read-only</access>
                            <enumeratedValues>
                                </enumeratedValues>
                        </field>
                        <field>
                            <name>PIDR07</name>
                            <description>Pmn State</description>
                            <lsb>7</lsb>
                            <msb>7</msb>
                            <access>read-only</access>
                            <enumeratedValues>
                                </enumeratedValues>
                        </field>
                        <field>
                            <name>PIDR08</name>
                            <description>Pmn State</description>
                            <lsb>8</lsb>
                            <msb>8</msb>
                            <access>read-only</access>
                            <enumeratedValues>
                                </enumeratedValues>
                        </field>
                        <field>
                            <name>PIDR09</name>
                            <description>Pmn State</description>
                            <lsb>9</lsb>
                            <msb>9</msb>
                            <access>read-only</access>
                            <enumeratedValues>
                                </enumeratedValues>
                        </field>
                        <field>
                            <name>PIDR10</name>
                            <description>Pmn State</description>
                            <lsb>10</lsb>
                            <msb>10</msb>
                            <access>read-only</access>
                            <enumeratedValues>
                                </enumeratedValues>
                        </field>
                        <field>
                            <name>PIDR11</name>
                            <description>Pmn State</description>
                            <lsb>11</lsb>
                            <msb>11</msb>
                            <access>read-only</access>
                            <enumeratedValues>
                                </enumeratedValues>
                        </field>
                        <field>
                            <name>PIDR12</name>
                            <description>Pmn State</description>
                            <lsb>12</lsb>
                            <msb>12</msb>
                            <access>read-only</access>
                            <enumeratedValues>
                                </enumeratedValues>
                        </field>
                        <field>
                            <name>PIDR13</name>
                            <description>Pmn State</description>
                            <lsb>13</lsb>
                            <msb>13</msb>
                            <access>read-only</access>
                            <enumeratedValues>
                                </enumeratedValues>
                        </field>
                        <field>
                            <name>PIDR14</name>
                            <description>Pmn State</description>
                            <lsb>14</lsb>
                            <msb>14</msb>
                            <access>read-only</access>
                            <enumeratedValues>
                                </enumeratedValues>
                        </field>
                        <field>
                            <name>PIDR15</name>
                            <description>Pmn State</description>
                            <lsb>15</lsb>
                            <msb>15</msb>
                            <access>read-only</access>
                            <enumeratedValues>
                                </enumeratedValues>
                        </field>
                    </fields>
                </register>
                <register>
                    <name>PIDR</name>
                    <description>Port Control Register 2</description>
                    <alternateRegister>PCNTR2</alternateRegister>
                    <addressOffset>0x006</addressOffset>
                    <size>16</size>
                    <access>read-only</access>
                    <resetValue>0x0000</resetValue>
                    <resetMask>0x0000</resetMask>
                    <fields>
                        <field>
                            <name>PIDR00</name>
                            <description>Pmn State</description>
                            <lsb>0</lsb>
                            <msb>0</msb>
                            <access>read-only</access>
                            <enumeratedValues>
                                </enumeratedValues>
                        </field>
                        <field>
                            <name>PIDR01</name>
                            <description>Pmn State</description>
                            <lsb>1</lsb>
                            <msb>1</msb>
                            <access>read-only</access>
                            <enumeratedValues>
                                </enumeratedValues>
                        </field>
                        <field>
                            <name>PIDR02</name>
                            <description>Pmn State</description>
                            <lsb>2</lsb>
                            <msb>2</msb>
                            <access>read-only</access>
                            <enumeratedValues>
                                </enumeratedValues>
                        </field>
                        <field>
                            <name>PIDR03</name>
                            <description>Pmn State</description>
                            <lsb>3</lsb>
                            <msb>3</msb>
                            <access>read-only</access>
                            <enumeratedValues>
                                </enumeratedValues>
                        </field>
                        <field>
                            <name>PIDR04</name>
                            <description>Pmn State</description>
                            <lsb>4</lsb>
                            <msb>4</msb>
                            <access>read-only</access>
                            <enumeratedValues>
                                </enumeratedValues>
                        </field>
                        <field>
                            <name>PIDR05</name>
                            <description>Pmn State</description>
                            <lsb>5</lsb>
                            <msb>5</msb>
                            <access>read-only</access>
                            <enumeratedValues>
                                </enumeratedValues>
                        </field>
                        <field>
                            <name>PIDR06</name>
                            <description>Pmn State</description>
                            <lsb>6</lsb>
                            <msb>6</msb>
                            <access>read-only</access>
                            <enumeratedValues>
                                </enumeratedValues>
                        </field>
                        <field>
                            <name>PIDR07</name>
                            <description>Pmn State</description>
                            <lsb>7</lsb>
                            <msb>7</msb>
                            <access>read-only</access>
                            <enumeratedValues>
                                </enumeratedValues>
                        </field>
                        <field>
                            <name>PIDR08</name>
                            <description>Pmn State</description>
                            <lsb>8</lsb>
                            <msb>8</msb>
                            <access>read-only</access>
                            <enumeratedValues>
                                </enumeratedValues>
                        </field>
                        <field>
                            <name>PIDR09</name>
                            <description>Pmn State</description>
                            <lsb>9</lsb>
                            <msb>9</msb>
                            <access>read-only</access>
                            <enumeratedValues>
                                </enumeratedValues>
                        </field>
                        <field>
                            <name>PIDR10</name>
                            <description>Pmn State</description>
                            <lsb>10</lsb>
                            <msb>10</msb>
                            <access>read-only</access>
                            <enumeratedValues>
                                </enumeratedValues>
                        </field>
                        <field>
                            <name>PIDR11</name>
                            <description>Pmn State</description>
                            <lsb>11</lsb>
                            <msb>11</msb>
                            <access>read-only</access>
                            <enumeratedValues>
                                </enumeratedValues>
                        </field>
                        <field>
                            <name>PIDR12</name>
                            <description>Pmn State</description>
                            <lsb>12</lsb>
                            <msb>12</msb>
                            <access>read-only</access>
                            <enumeratedValues>
                                </enumeratedValues>
                        </field>
                        <field>
                            <name>PIDR13</name>
                            <description>Pmn State</description>
                            <lsb>13</lsb>
                            <msb>13</msb>
                            <access>read-only</access>
                            <enumeratedValues>
                                </enumeratedValues>
                        </field>
                        <field>
                            <name>PIDR14</name>
                            <description>Pmn State</description>
                            <lsb>14</lsb>
                            <msb>14</msb>
                            <access>read-only</access>
                            <enumeratedValues>
                                </enumeratedValues>
                        </field>
                        <field>
                            <name>PIDR15</name>
                            <description>Pmn State</description>
                            <lsb>15</lsb>
                            <msb>15</msb>
                            <access>read-only</access>
                            <enumeratedValues>
                                </enumeratedValues>
                        </field>
                    </fields>
                </register>
                <register>
                    <name>PCNTR3</name>
                    <description>Port Control Register 3</description>
                    <addressOffset>0x008</addressOffset>
                    <size>32</size>
                    <access>write-only</access>
                    <resetValue>0x00000000</resetValue>
                    <resetMask>0xffffffff</resetMask>
                    <fields>
                        <field>
                            <name>POSR00</name>
                            <description>Pmn Output Set</description>
                            <lsb>0</lsb>
                            <msb>0</msb>
                            <access>write-only</access>
                            <enumeratedValues>
                                </enumeratedValues>
                        </field>
                        <field>
                            <name>POSR01</name>
                            <description>Pmn Output Set</description>
                            <lsb>1</lsb>
                            <msb>1</msb>
                            <access>write-only</access>
                            <enumeratedValues>
                                </enumeratedValues>
                        </field>
                        <field>
                            <name>POSR02</name>
                            <description>Pmn Output Set</description>
                            <lsb>2</lsb>
                            <msb>2</msb>
                            <access>write-only</access>
                            <enumeratedValues>
                                </enumeratedValues>
                        </field>
                        <field>
                            <name>POSR03</name>
                            <description>Pmn Output Set</description>
                            <lsb>3</lsb>
                            <msb>3</msb>
                            <access>write-only</access>
                            <enumeratedValues>
                                </enumeratedValues>
                        </field>
                        <field>
                            <name>POSR04</name>
                            <description>Pmn Output Set</description>
                            <lsb>4</lsb>
                            <msb>4</msb>
                            <access>write-only</access>
                            <enumeratedValues>
                                </enumeratedValues>
                        </field>
                        <field>
                            <name>POSR05</name>
                            <description>Pmn Output Set</description>
                            <lsb>5</lsb>
                            <msb>5</msb>
                            <access>write-only</access>
                            <enumeratedValues>
                                </enumeratedValues>
                        </field>
                        <field>
                            <name>POSR06</name>
                            <description>Pmn Output Set</description>
                            <lsb>6</lsb>
                            <msb>6</msb>
                            <access>write-only</access>
                            <enumeratedValues>
                                </enumeratedValues>
                        </field>
                        <field>
                            <name>POSR07</name>
                            <description>Pmn Output Set</description>
                            <lsb>7</lsb>
                            <msb>7</msb>
                            <access>write-only</access>
                            <enumeratedValues>
                                </enumeratedValues>
                        </field>
                        <field>
                            <name>POSR08</name>
                            <description>Pmn Output Set</description>
                            <lsb>8</lsb>
                            <msb>8</msb>
                            <access>write-only</access>
                            <enumeratedValues>
                                </enumeratedValues>
                        </field>
                        <field>
                            <name>POSR09</name>
                            <description>Pmn Output Set</description>
                            <lsb>9</lsb>
                            <msb>9</msb>
                            <access>write-only</access>
                            <enumeratedValues>
                                </enumeratedValues>
                        </field>
                        <field>
                            <name>POSR10</name>
                            <description>Pmn Output Set</description>
                            <lsb>10</lsb>
                            <msb>10</msb>
                            <access>write-only</access>
                            <enumeratedValues>
                                </enumeratedValues>
                        </field>
                        <field>
                            <name>POSR11</name>
                            <description>Pmn Output Set</description>
                            <lsb>11</lsb>
                            <msb>11</msb>
                            <access>write-only</access>
                            <enumeratedValues>
                                </enumeratedValues>
                        </field>
                        <field>
                            <name>POSR12</name>
                            <description>Pmn Output Set</description>
                            <lsb>12</lsb>
                            <msb>12</msb>
                            <access>write-only</access>
                            <enumeratedValues>
                                </enumeratedValues>
                        </field>
                        <field>
                            <name>POSR13</name>
                            <description>Pmn Output Set</description>
                            <lsb>13</lsb>
                            <msb>13</msb>
                            <access>write-only</access>
                            <enumeratedValues>
                                </enumeratedValues>
                        </field>
                        <field>
                            <name>POSR14</name>
                            <description>Pmn Output Set</description>
                            <lsb>14</lsb>
                            <msb>14</msb>
                            <access>write-only</access>
                            <enumeratedValues>
                                </enumeratedValues>
                        </field>
                        <field>
                            <name>POSR15</name>
                            <description>Pmn Output Set</description>
                            <lsb>15</lsb>
                            <msb>15</msb>
                            <access>write-only</access>
                            <enumeratedValues>
                                </enumeratedValues>
                        </field>
                        <field>
                            <name>PORR00</name>
                            <description>Pmn Output Reset</description>
                            <lsb>16</lsb>
                            <msb>16</msb>
                            <access>write-only</access>
                            <enumeratedValues>
                                </enumeratedValues>
                        </field>
                        <field>
                            <name>PORR01</name>
                            <description>Pmn Output Reset</description>
                            <lsb>17</lsb>
                            <msb>17</msb>
                            <access>write-only</access>
                            <enumeratedValues>
                                </enumeratedValues>
                        </field>
                        <field>
                            <name>PORR02</name>
                            <description>Pmn Output Reset</description>
                            <lsb>18</lsb>
                            <msb>18</msb>
                            <access>write-only</access>
                            <enumeratedValues>
                                </enumeratedValues>
                        </field>
                        <field>
                            <name>PORR03</name>
                            <description>Pmn Output Reset</description>
                            <lsb>19</lsb>
                            <msb>19</msb>
                            <access>write-only</access>
                            <enumeratedValues>
                                </enumeratedValues>
                        </field>
                        <field>
                            <name>PORR04</name>
                            <description>Pmn Output Reset</description>
                            <lsb>20</lsb>
                            <msb>20</msb>
                            <access>write-only</access>
                            <enumeratedValues>
                                </enumeratedValues>
                        </field>
                        <field>
                            <name>PORR05</name>
                            <description>Pmn Output Reset</description>
                            <lsb>21</lsb>
                            <msb>21</msb>
                            <access>write-only</access>
                            <enumeratedValues>
                                </enumeratedValues>
                        </field>
                        <field>
                            <name>PORR06</name>
                            <description>Pmn Output Reset</description>
                            <lsb>22</lsb>
                            <msb>22</msb>
                            <access>write-only</access>
                            <enumeratedValues>
                                </enumeratedValues>
                        </field>
                        <field>
                            <name>PORR07</name>
                            <description>Pmn Output Reset</description>
                            <lsb>23</lsb>
                            <msb>23</msb>
                            <access>write-only</access>
                            <enumeratedValues>
                                </enumeratedValues>
                        </field>
                        <field>
                            <name>PORR08</name>
                            <description>Pmn Output Reset</description>
                            <lsb>24</lsb>
                            <msb>24</msb>
                            <access>write-only</access>
                            <enumeratedValues>
                                </enumeratedValues>
                        </field>
                        <field>
                            <name>PORR09</name>
                            <description>Pmn Output Reset</description>
                            <lsb>25</lsb>
                            <msb>25</msb>
                            <access>write-only</access>
                            <enumeratedValues>
                                </enumeratedValues>
                        </field>
                        <field>
                            <name>PORR10</name>
                            <description>Pmn Output Reset</description>
                            <lsb>26</lsb>
                            <msb>26</msb>
                            <access>write-only</access>
                            <enumeratedValues>
                                </enumeratedValues>
                        </field>
                        <field>
                            <name>PORR11</name>
                            <description>Pmn Output Reset</description>
                            <lsb>27</lsb>
                            <msb>27</msb>
                            <access>write-only</access>
                            <enumeratedValues>
                                </enumeratedValues>
                        </field>
                        <field>
                            <name>PORR12</name>
                            <description>Pmn Output Reset</description>
                            <lsb>28</lsb>
                            <msb>28</msb>
                            <access>write-only</access>
                            <enumeratedValues>
                                </enumeratedValues>
                        </field>
                        <field>
                            <name>PORR13</name>
                            <description>Pmn Output Reset</description>
                            <lsb>29</lsb>
                            <msb>29</msb>
                            <access>write-only</access>
                            <enumeratedValues>
                                </enumeratedValues>
                        </field>
                        <field>
                            <name>PORR14</name>
                            <description>Pmn Output Reset</description>
                            <lsb>30</lsb>
                            <msb>30</msb>
                            <access>write-only</access>
                            <enumeratedValues>
                                </enumeratedValues>
                        </field>
                        <field>
                            <name>PORR15</name>
                            <description>Pmn Output Reset</description>
                            <lsb>31</lsb>
                            <msb>31</msb>
                            <access>write-only</access>
                            <enumeratedValues>
                                </enumeratedValues>
                        </field>
                    </fields>
                </register>
                <register>
                    <name>PORR</name>
                    <description>Port Control Register 3</description>
                    <alternateRegister>PCNTR3</alternateRegister>
                    <addressOffset>0x008</addressOffset>
                    <size>16</size>
                    <access>write-only</access>
                    <resetValue>0x0000</resetValue>
                    <resetMask>0xffff</resetMask>
                    <fields>
                        <field>
                            <name>PORR00</name>
                            <description>Pmn Output Reset</description>
                            <lsb>0</lsb>
                            <msb>0</msb>
                            <access>write-only</access>
                            <enumeratedValues>
                                </enumeratedValues>
                        </field>
                        <field>
                            <name>PORR01</name>
                            <description>Pmn Output Reset</description>
                            <lsb>1</lsb>
                            <msb>1</msb>
                            <access>write-only</access>
                            <enumeratedValues>
                                </enumeratedValues>
                        </field>
                        <field>
                            <name>PORR02</name>
                            <description>Pmn Output Reset</description>
                            <lsb>2</lsb>
                            <msb>2</msb>
                            <access>write-only</access>
                            <enumeratedValues>
                                </enumeratedValues>
                        </field>
                        <field>
                            <name>PORR03</name>
                            <description>Pmn Output Reset</description>
                            <lsb>3</lsb>
                            <msb>3</msb>
                            <access>write-only</access>
                            <enumeratedValues>
                                </enumeratedValues>
                        </field>
                        <field>
                            <name>PORR04</name>
                            <description>Pmn Output Reset</description>
                            <lsb>4</lsb>
                            <msb>4</msb>
                            <access>write-only</access>
                            <enumeratedValues>
                                </enumeratedValues>
                        </field>
                        <field>
                            <name>PORR05</name>
                            <description>Pmn Output Reset</description>
                            <lsb>5</lsb>
                            <msb>5</msb>
                            <access>write-only</access>
                            <enumeratedValues>
                                </enumeratedValues>
                        </field>
                        <field>
                            <name>PORR06</name>
                            <description>Pmn Output Reset</description>
                            <lsb>6</lsb>
                            <msb>6</msb>
                            <access>write-only</access>
                            <enumeratedValues>
                                </enumeratedValues>
                        </field>
                        <field>
                            <name>PORR07</name>
                            <description>Pmn Output Reset</description>
                            <lsb>7</lsb>
                            <msb>7</msb>
                            <access>write-only</access>
                            <enumeratedValues>
                                </enumeratedValues>
                        </field>
                        <field>
                            <name>PORR08</name>
                            <description>Pmn Output Reset</description>
                            <lsb>8</lsb>
                            <msb>8</msb>
                            <access>write-only</access>
                            <enumeratedValues>
                                </enumeratedValues>
                        </field>
                        <field>
                            <name>PORR09</name>
                            <description>Pmn Output Reset</description>
                            <lsb>9</lsb>
                            <msb>9</msb>
                            <access>write-only</access>
                            <enumeratedValues>
                                </enumeratedValues>
                        </field>
                        <field>
                            <name>PORR10</name>
                            <description>Pmn Output Reset</description>
                            <lsb>10</lsb>
                            <msb>10</msb>
                            <access>write-only</access>
                            <enumeratedValues>
                                </enumeratedValues>
                        </field>
                        <field>
                            <name>PORR11</name>
                            <description>Pmn Output Reset</description>
                            <lsb>11</lsb>
                            <msb>11</msb>
                            <access>write-only</access>
                            <enumeratedValues>
                                </enumeratedValues>
                        </field>
                        <field>
                            <name>PORR12</name>
                            <description>Pmn Output Reset</description>
                            <lsb>12</lsb>
                            <msb>12</msb>
                            <access>write-only</access>
                            <enumeratedValues>
                                </enumeratedValues>
                        </field>
                        <field>
                            <name>PORR13</name>
                            <description>Pmn Output Reset</description>
                            <lsb>13</lsb>
                            <msb>13</msb>
                            <access>write-only</access>
                            <enumeratedValues>
                                </enumeratedValues>
                        </field>
                        <field>
                            <name>PORR14</name>
                            <description>Pmn Output Reset</description>
                            <lsb>14</lsb>
                            <msb>14</msb>
                            <access>write-only</access>
                            <enumeratedValues>
                                </enumeratedValues>
                        </field>
                        <field>
                            <name>PORR15</name>
                            <description>Pmn Output Reset</description>
                            <lsb>15</lsb>
                            <msb>15</msb>
                            <access>write-only</access>
                            <enumeratedValues>
                                </enumeratedValues>
                        </field>
                    </fields>
                </register>
                <register>
                    <name>POSR</name>
                    <description>Port Control Register 3</description>
                    <alternateRegister>PCNTR3</alternateRegister>
                    <addressOffset>0x00A</addressOffset>
                    <size>16</size>
                    <access>write-only</access>
                    <resetValue>0x0000</resetValue>
                    <resetMask>0xffff</resetMask>
                    <fields>
                        <field>
                            <name>POSR00</name>
                            <description>Pmn Output Set</description>
                            <lsb>0</lsb>
                            <msb>0</msb>
                            <access>write-only</access>
                            <enumeratedValues>
                                </enumeratedValues>
                        </field>
                        <field>
                            <name>POSR01</name>
                            <description>Pmn Output Set</description>
                            <lsb>1</lsb>
                            <msb>1</msb>
                            <access>write-only</access>
                            <enumeratedValues>
                                </enumeratedValues>
                        </field>
                        <field>
                            <name>POSR02</name>
                            <description>Pmn Output Set</description>
                            <lsb>2</lsb>
                            <msb>2</msb>
                            <access>write-only</access>
                            <enumeratedValues>
                                </enumeratedValues>
                        </field>
                        <field>
                            <name>POSR03</name>
                            <description>Pmn Output Set</description>
                            <lsb>3</lsb>
                            <msb>3</msb>
                            <access>write-only</access>
                            <enumeratedValues>
                                </enumeratedValues>
                        </field>
                        <field>
                            <name>POSR04</name>
                            <description>Pmn Output Set</description>
                            <lsb>4</lsb>
                            <msb>4</msb>
                            <access>write-only</access>
                            <enumeratedValues>
                                </enumeratedValues>
                        </field>
                        <field>
                            <name>POSR05</name>
                            <description>Pmn Output Set</description>
                            <lsb>5</lsb>
                            <msb>5</msb>
                            <access>write-only</access>
                            <enumeratedValues>
                                </enumeratedValues>
                        </field>
                        <field>
                            <name>POSR06</name>
                            <description>Pmn Output Set</description>
                            <lsb>6</lsb>
                            <msb>6</msb>
                            <access>write-only</access>
                            <enumeratedValues>
                                </enumeratedValues>
                        </field>
                        <field>
                            <name>POSR07</name>
                            <description>Pmn Output Set</description>
                            <lsb>7</lsb>
                            <msb>7</msb>
                            <access>write-only</access>
                            <enumeratedValues>
                                </enumeratedValues>
                        </field>
                        <field>
                            <name>POSR08</name>
                            <description>Pmn Output Set</description>
                            <lsb>8</lsb>
                            <msb>8</msb>
                            <access>write-only</access>
                            <enumeratedValues>
                                </enumeratedValues>
                        </field>
                        <field>
                            <name>POSR09</name>
                            <description>Pmn Output Set</description>
                            <lsb>9</lsb>
                            <msb>9</msb>
                            <access>write-only</access>
                            <enumeratedValues>
                                </enumeratedValues>
                        </field>
                        <field>
                            <name>POSR10</name>
                            <description>Pmn Output Set</description>
                            <lsb>10</lsb>
                            <msb>10</msb>
                            <access>write-only</access>
                            <enumeratedValues>
                                </enumeratedValues>
                        </field>
                        <field>
                            <name>POSR11</name>
                            <description>Pmn Output Set</description>
                            <lsb>11</lsb>
                            <msb>11</msb>
                            <access>write-only</access>
                            <enumeratedValues>
                                </enumeratedValues>
                        </field>
                        <field>
                            <name>POSR12</name>
                            <description>Pmn Output Set</description>
                            <lsb>12</lsb>
                            <msb>12</msb>
                            <access>write-only</access>
                            <enumeratedValues>
                                </enumeratedValues>
                        </field>
                        <field>
                            <name>POSR13</name>
                            <description>Pmn Output Set</description>
                            <lsb>13</lsb>
                            <msb>13</msb>
                            <access>write-only</access>
                            <enumeratedValues>
                                </enumeratedValues>
                        </field>
                        <field>
                            <name>POSR14</name>
                            <description>Pmn Output Set</description>
                            <lsb>14</lsb>
                            <msb>14</msb>
                            <access>write-only</access>
                            <enumeratedValues>
                                </enumeratedValues>
                        </field>
                        <field>
                            <name>POSR15</name>
                            <description>Pmn Output Set</description>
                            <lsb>15</lsb>
                            <msb>15</msb>
                            <access>write-only</access>
                            <enumeratedValues>
                                </enumeratedValues>
                        </field>
                    </fields>
                </register>
            </registers>
        </peripheral>
        <peripheral>
            <name>PORT1</name>
            <description>Pmn Pin FunctionPort 1 Control RegistersPmn Pin Function Control Register</description>
            <baseAddress>0x40080020</baseAddress>
            <addressBlock>
                <offset>0x00</offset>
                <size>16</size>
                <usage>registers</usage>
            </addressBlock>
            <registers>
                <register>
                    <name>PCNTR1</name>
                    <description>Port Control Register 1</description>
                    <addressOffset>0x000</addressOffset>
                    <size>32</size>
                    <access>read-write</access>
                    <resetValue>0x00000000</resetValue>
                    <resetMask>0xffffffff</resetMask>
                    <fields>
                        <field>
                            <name>PDR00</name>
                            <description>Pmn Direction</description>
                            <lsb>0</lsb>
                            <msb>0</msb>
                            <access>read-write</access>
                            <enumeratedValues>
                                </enumeratedValues>
                        </field>
                        <field>
                            <name>PDR01</name>
                            <description>Pmn Direction</description>
                            <lsb>1</lsb>
                            <msb>1</msb>
                            <access>read-write</access>
                            <enumeratedValues>
                                </enumeratedValues>
                        </field>
                        <field>
                            <name>PDR02</name>
                            <description>Pmn Direction</description>
                            <lsb>2</lsb>
                            <msb>2</msb>
                            <access>read-write</access>
                            <enumeratedValues>
                                </enumeratedValues>
                        </field>
                        <field>
                            <name>PDR03</name>
                            <description>Pmn Direction</description>
                            <lsb>3</lsb>
                            <msb>3</msb>
                            <access>read-write</access>
                            <enumeratedValues>
                                </enumeratedValues>
                        </field>
                        <field>
                            <name>PDR04</name>
                            <description>Pmn Direction</description>
                            <lsb>4</lsb>
                            <msb>4</msb>
                            <access>read-write</access>
                            <enumeratedValues>
                                </enumeratedValues>
                        </field>
                        <field>
                            <name>PDR05</name>
                            <description>Pmn Direction</description>
                            <lsb>5</lsb>
                            <msb>5</msb>
                            <access>read-write</access>
                            <enumeratedValues>
                                </enumeratedValues>
                        </field>
                        <field>
                            <name>PDR06</name>
                            <description>Pmn Direction</description>
                            <lsb>6</lsb>
                            <msb>6</msb>
                            <access>read-write</access>
                            <enumeratedValues>
                                </enumeratedValues>
                        </field>
                        <field>
                            <name>PDR07</name>
                            <description>Pmn Direction</description>
                            <lsb>7</lsb>
                            <msb>7</msb>
                            <access>read-write</access>
                            <enumeratedValues>
                                </enumeratedValues>
                        </field>
                        <field>
                            <name>PDR08</name>
                            <description>Pmn Direction</description>
                            <lsb>8</lsb>
                            <msb>8</msb>
                            <access>read-write</access>
                            <enumeratedValues>
                                </enumeratedValues>
                        </field>
                        <field>
                            <name>PDR09</name>
                            <description>Pmn Direction</description>
                            <lsb>9</lsb>
                            <msb>9</msb>
                            <access>read-write</access>
                            <enumeratedValues>
                                </enumeratedValues>
                        </field>
                        <field>
                            <name>PDR10</name>
                            <description>Pmn Direction</description>
                            <lsb>10</lsb>
                            <msb>10</msb>
                            <access>read-write</access>
                            <enumeratedValues>
                                </enumeratedValues>
                        </field>
                        <field>
                            <name>PDR11</name>
                            <description>Pmn Direction</description>
                            <lsb>11</lsb>
                            <msb>11</msb>
                            <access>read-write</access>
                            <enumeratedValues>
                                </enumeratedValues>
                        </field>
                        <field>
                            <name>PDR12</name>
                            <description>Pmn Direction</description>
                            <lsb>12</lsb>
                            <msb>12</msb>
                            <access>read-write</access>
                            <enumeratedValues>
                                </enumeratedValues>
                        </field>
                        <field>
                            <name>PDR13</name>
                            <description>Pmn Direction</description>
                            <lsb>13</lsb>
                            <msb>13</msb>
                            <access>read-write</access>
                            <enumeratedValues>
                                </enumeratedValues>
                        </field>
                        <field>
                            <name>PDR14</name>
                            <description>Pmn Direction</description>
                            <lsb>14</lsb>
                            <msb>14</msb>
                            <access>read-write</access>
                            <enumeratedValues>
                                </enumeratedValues>
                        </field>
                        <field>
                            <name>PDR15</name>
                            <description>Pmn Direction</description>
                            <lsb>15</lsb>
                            <msb>15</msb>
                            <access>read-write</access>
                            <enumeratedValues>
                                </enumeratedValues>
                        </field>
                        <field>
                            <name>PODR00</name>
                            <description>Pmn Output Data</description>
                            <lsb>16</lsb>
                            <msb>16</msb>
                            <access>read-write</access>
                            <enumeratedValues>
                                </enumeratedValues>
                        </field>
                        <field>
                            <name>PODR01</name>
                            <description>Pmn Output Data</description>
                            <lsb>17</lsb>
                            <msb>17</msb>
                            <access>read-write</access>
                            <enumeratedValues>
                                </enumeratedValues>
                        </field>
                        <field>
                            <name>PODR02</name>
                            <description>Pmn Output Data</description>
                            <lsb>18</lsb>
                            <msb>18</msb>
                            <access>read-write</access>
                            <enumeratedValues>
                                </enumeratedValues>
                        </field>
                        <field>
                            <name>PODR03</name>
                            <description>Pmn Output Data</description>
                            <lsb>19</lsb>
                            <msb>19</msb>
                            <access>read-write</access>
                            <enumeratedValues>
                                </enumeratedValues>
                        </field>
                        <field>
                            <name>PODR04</name>
                            <description>Pmn Output Data</description>
                            <lsb>20</lsb>
                            <msb>20</msb>
                            <access>read-write</access>
                            <enumeratedValues>
                                </enumeratedValues>
                        </field>
                        <field>
                            <name>PODR05</name>
                            <description>Pmn Output Data</description>
                            <lsb>21</lsb>
                            <msb>21</msb>
                            <access>read-write</access>
                            <enumeratedValues>
                                </enumeratedValues>
                        </field>
                        <field>
                            <name>PODR06</name>
                            <description>Pmn Output Data</description>
                            <lsb>22</lsb>
                            <msb>22</msb>
                            <access>read-write</access>
                            <enumeratedValues>
                                </enumeratedValues>
                        </field>
                        <field>
                            <name>PODR07</name>
                            <description>Pmn Output Data</description>
                            <lsb>23</lsb>
                            <msb>23</msb>
                            <access>read-write</access>
                            <enumeratedValues>
                                </enumeratedValues>
                        </field>
                        <field>
                            <name>PODR08</name>
                            <description>Pmn Output Data</description>
                            <lsb>24</lsb>
                            <msb>24</msb>
                            <access>read-write</access>
                            <enumeratedValues>
                                </enumeratedValues>
                        </field>
                        <field>
                            <name>PODR09</name>
                            <description>Pmn Output Data</description>
                            <lsb>25</lsb>
                            <msb>25</msb>
                            <access>read-write</access>
                            <enumeratedValues>
                                </enumeratedValues>
                        </field>
                        <field>
                            <name>PODR10</name>
                            <description>Pmn Output Data</description>
                            <lsb>26</lsb>
                            <msb>26</msb>
                            <access>read-write</access>
                            <enumeratedValues>
                                </enumeratedValues>
                        </field>
                        <field>
                            <name>PODR11</name>
                            <description>Pmn Output Data</description>
                            <lsb>27</lsb>
                            <msb>27</msb>
                            <access>read-write</access>
                            <enumeratedValues>
                                </enumeratedValues>
                        </field>
                        <field>
                            <name>PODR12</name>
                            <description>Pmn Output Data</description>
                            <lsb>28</lsb>
                            <msb>28</msb>
                            <access>read-write</access>
                            <enumeratedValues>
                                </enumeratedValues>
                        </field>
                        <field>
                            <name>PODR13</name>
                            <description>Pmn Output Data</description>
                            <lsb>29</lsb>
                            <msb>29</msb>
                            <access>read-write</access>
                            <enumeratedValues>
                                </enumeratedValues>
                        </field>
                        <field>
                            <name>PODR14</name>
                            <description>Pmn Output Data</description>
                            <lsb>30</lsb>
                            <msb>30</msb>
                            <access>read-write</access>
                            <enumeratedValues>
                                </enumeratedValues>
                        </field>
                        <field>
                            <name>PODR15</name>
                            <description>Pmn Output Data</description>
                            <lsb>31</lsb>
                            <msb>31</msb>
                            <access>read-write</access>
                            <enumeratedValues>
                                </enumeratedValues>
                        </field>
                    </fields>
                </register>
                <register>
                    <name>PODR</name>
                    <description>Port Control Register 1</description>
                    <alternateRegister>PCNTR1</alternateRegister>
                    <addressOffset>0x000</addressOffset>
                    <size>16</size>
                    <access>read-write</access>
                    <resetValue>0x0000</resetValue>
                    <resetMask>0xffff</resetMask>
                    <fields>
                        <field>
                            <name>PODR00</name>
                            <description>Pmn Output Data</description>
                            <lsb>0</lsb>
                            <msb>0</msb>
                            <access>read-write</access>
                            <enumeratedValues>
                                </enumeratedValues>
                        </field>
                        <field>
                            <name>PODR01</name>
                            <description>Pmn Output Data</description>
                            <lsb>1</lsb>
                            <msb>1</msb>
                            <access>read-write</access>
                            <enumeratedValues>
                                </enumeratedValues>
                        </field>
                        <field>
                            <name>PODR02</name>
                            <description>Pmn Output Data</description>
                            <lsb>2</lsb>
                            <msb>2</msb>
                            <access>read-write</access>
                            <enumeratedValues>
                                </enumeratedValues>
                        </field>
                        <field>
                            <name>PODR03</name>
                            <description>Pmn Output Data</description>
                            <lsb>3</lsb>
                            <msb>3</msb>
                            <access>read-write</access>
                            <enumeratedValues>
                                </enumeratedValues>
                        </field>
                        <field>
                            <name>PODR04</name>
                            <description>Pmn Output Data</description>
                            <lsb>4</lsb>
                            <msb>4</msb>
                            <access>read-write</access>
                            <enumeratedValues>
                                </enumeratedValues>
                        </field>
                        <field>
                            <name>PODR05</name>
                            <description>Pmn Output Data</description>
                            <lsb>5</lsb>
                            <msb>5</msb>
                            <access>read-write</access>
                            <enumeratedValues>
                                </enumeratedValues>
                        </field>
                        <field>
                            <name>PODR06</name>
                            <description>Pmn Output Data</description>
                            <lsb>6</lsb>
                            <msb>6</msb>
                            <access>read-write</access>
                            <enumeratedValues>
                                </enumeratedValues>
                        </field>
                        <field>
                            <name>PODR07</name>
                            <description>Pmn Output Data</description>
                            <lsb>7</lsb>
                            <msb>7</msb>
                            <access>read-write</access>
                            <enumeratedValues>
                                </enumeratedValues>
                        </field>
                        <field>
                            <name>PODR08</name>
                            <description>Pmn Output Data</description>
                            <lsb>8</lsb>
                            <msb>8</msb>
                            <access>read-write</access>
                            <enumeratedValues>
                                </enumeratedValues>
                        </field>
                        <field>
                            <name>PODR09</name>
                            <description>Pmn Output Data</description>
                            <lsb>9</lsb>
                            <msb>9</msb>
                            <access>read-write</access>
                            <enumeratedValues>
                                </enumeratedValues>
                        </field>
                        <field>
                            <name>PODR10</name>
                            <description>Pmn Output Data</description>
                            <lsb>10</lsb>
                            <msb>10</msb>
                            <access>read-write</access>
                            <enumeratedValues>
                                </enumeratedValues>
                        </field>
                        <field>
                            <name>PODR11</name>
                            <description>Pmn Output Data</description>
                            <lsb>11</lsb>
                            <msb>11</msb>
                            <access>read-write</access>
                            <enumeratedValues>
                                </enumeratedValues>
                        </field>
                        <field>
                            <name>PODR12</name>
                            <description>Pmn Output Data</description>
                            <lsb>12</lsb>
                            <msb>12</msb>
                            <access>read-write</access>
                            <enumeratedValues>
                                </enumeratedValues>
                        </field>
                        <field>
                            <name>PODR13</name>
                            <description>Pmn Output Data</description>
                            <lsb>13</lsb>
                            <msb>13</msb>
                            <access>read-write</access>
                            <enumeratedValues>
                                </enumeratedValues>
                        </field>
                        <field>
                            <name>PODR14</name>
                            <description>Pmn Output Data</description>
                            <lsb>14</lsb>
                            <msb>14</msb>
                            <access>read-write</access>
                            <enumeratedValues>
                                </enumeratedValues>
                        </field>
                        <field>
                            <name>PODR15</name>
                            <description>Pmn Output Data</description>
                            <lsb>15</lsb>
                            <msb>15</msb>
                            <access>read-write</access>
                            <enumeratedValues>
                                </enumeratedValues>
                        </field>
                    </fields>
                </register>
                <register>
                    <name>PDR</name>
                    <description>Port Control Register 1</description>
                    <alternateRegister>PCNTR1</alternateRegister>
                    <addressOffset>0x002</addressOffset>
                    <size>16</size>
                    <access>read-write</access>
                    <resetValue>0x0000</resetValue>
                    <resetMask>0xffff</resetMask>
                    <fields>
                        <field>
                            <name>PDR00</name>
                            <description>Pmn Direction</description>
                            <lsb>0</lsb>
                            <msb>0</msb>
                            <access>read-write</access>
                            <enumeratedValues>
                                </enumeratedValues>
                        </field>
                        <field>
                            <name>PDR01</name>
                            <description>Pmn Direction</description>
                            <lsb>1</lsb>
                            <msb>1</msb>
                            <access>read-write</access>
                            <enumeratedValues>
                                </enumeratedValues>
                        </field>
                        <field>
                            <name>PDR02</name>
                            <description>Pmn Direction</description>
                            <lsb>2</lsb>
                            <msb>2</msb>
                            <access>read-write</access>
                            <enumeratedValues>
                                </enumeratedValues>
                        </field>
                        <field>
                            <name>PDR03</name>
                            <description>Pmn Direction</description>
                            <lsb>3</lsb>
                            <msb>3</msb>
                            <access>read-write</access>
                            <enumeratedValues>
                                </enumeratedValues>
                        </field>
                        <field>
                            <name>PDR04</name>
                            <description>Pmn Direction</description>
                            <lsb>4</lsb>
                            <msb>4</msb>
                            <access>read-write</access>
                            <enumeratedValues>
                                </enumeratedValues>
                        </field>
                        <field>
                            <name>PDR05</name>
                            <description>Pmn Direction</description>
                            <lsb>5</lsb>
                            <msb>5</msb>
                            <access>read-write</access>
                            <enumeratedValues>
                                </enumeratedValues>
                        </field>
                        <field>
                            <name>PDR06</name>
                            <description>Pmn Direction</description>
                            <lsb>6</lsb>
                            <msb>6</msb>
                            <access>read-write</access>
                            <enumeratedValues>
                                </enumeratedValues>
                        </field>
                        <field>
                            <name>PDR07</name>
                            <description>Pmn Direction</description>
                            <lsb>7</lsb>
                            <msb>7</msb>
                            <access>read-write</access>
                            <enumeratedValues>
                                </enumeratedValues>
                        </field>
                        <field>
                            <name>PDR08</name>
                            <description>Pmn Direction</description>
                            <lsb>8</lsb>
                            <msb>8</msb>
                            <access>read-write</access>
                            <enumeratedValues>
                                </enumeratedValues>
                        </field>
                        <field>
                            <name>PDR09</name>
                            <description>Pmn Direction</description>
                            <lsb>9</lsb>
                            <msb>9</msb>
                            <access>read-write</access>
                            <enumeratedValues>
                                </enumeratedValues>
                        </field>
                        <field>
                            <name>PDR10</name>
                            <description>Pmn Direction</description>
                            <lsb>10</lsb>
                            <msb>10</msb>
                            <access>read-write</access>
                            <enumeratedValues>
                                </enumeratedValues>
                        </field>
                        <field>
                            <name>PDR11</name>
                            <description>Pmn Direction</description>
                            <lsb>11</lsb>
                            <msb>11</msb>
                            <access>read-write</access>
                            <enumeratedValues>
                                </enumeratedValues>
                        </field>
                        <field>
                            <name>PDR12</name>
                            <description>Pmn Direction</description>
                            <lsb>12</lsb>
                            <msb>12</msb>
                            <access>read-write</access>
                            <enumeratedValues>
                                </enumeratedValues>
                        </field>
                        <field>
                            <name>PDR13</name>
                            <description>Pmn Direction</description>
                            <lsb>13</lsb>
                            <msb>13</msb>
                            <access>read-write</access>
                            <enumeratedValues>
                                </enumeratedValues>
                        </field>
                        <field>
                            <name>PDR14</name>
                            <description>Pmn Direction</description>
                            <lsb>14</lsb>
                            <msb>14</msb>
                            <access>read-write</access>
                            <enumeratedValues>
                                </enumeratedValues>
                        </field>
                        <field>
                            <name>PDR15</name>
                            <description>Pmn Direction</description>
                            <lsb>15</lsb>
                            <msb>15</msb>
                            <access>read-write</access>
                            <enumeratedValues>
                                </enumeratedValues>
                        </field>
                    </fields>
                </register>
                <register>
                    <name>PCNTR2</name>
                    <description>Port Control Register 2</description>
                    <addressOffset>0x004</addressOffset>
                    <size>32</size>
                    <access>read-only</access>
                    <resetValue>0x00000000</resetValue>
                    <resetMask>0xffff0000</resetMask>
                    <fields>
                        <field>
                            <name>PIDR00</name>
                            <description>Pmn State</description>
                            <lsb>0</lsb>
                            <msb>0</msb>
                            <access>read-only</access>
                            <enumeratedValues>
                                </enumeratedValues>
                        </field>
                        <field>
                            <name>PIDR01</name>
                            <description>Pmn State</description>
                            <lsb>1</lsb>
                            <msb>1</msb>
                            <access>read-only</access>
                            <enumeratedValues>
                                </enumeratedValues>
                        </field>
                        <field>
                            <name>PIDR02</name>
                            <description>Pmn State</description>
                            <lsb>2</lsb>
                            <msb>2</msb>
                            <access>read-only</access>
                            <enumeratedValues>
                                </enumeratedValues>
                        </field>
                        <field>
                            <name>PIDR03</name>
                            <description>Pmn State</description>
                            <lsb>3</lsb>
                            <msb>3</msb>
                            <access>read-only</access>
                            <enumeratedValues>
                                </enumeratedValues>
                        </field>
                        <field>
                            <name>PIDR04</name>
                            <description>Pmn State</description>
                            <lsb>4</lsb>
                            <msb>4</msb>
                            <access>read-only</access>
                            <enumeratedValues>
                                </enumeratedValues>
                        </field>
                        <field>
                            <name>PIDR05</name>
                            <description>Pmn State</description>
                            <lsb>5</lsb>
                            <msb>5</msb>
                            <access>read-only</access>
                            <enumeratedValues>
                                </enumeratedValues>
                        </field>
                        <field>
                            <name>PIDR06</name>
                            <description>Pmn State</description>
                            <lsb>6</lsb>
                            <msb>6</msb>
                            <access>read-only</access>
                            <enumeratedValues>
                                </enumeratedValues>
                        </field>
                        <field>
                            <name>PIDR07</name>
                            <description>Pmn State</description>
                            <lsb>7</lsb>
                            <msb>7</msb>
                            <access>read-only</access>
                            <enumeratedValues>
                                </enumeratedValues>
                        </field>
                        <field>
                            <name>PIDR08</name>
                            <description>Pmn State</description>
                            <lsb>8</lsb>
                            <msb>8</msb>
                            <access>read-only</access>
                            <enumeratedValues>
                                </enumeratedValues>
                        </field>
                        <field>
                            <name>PIDR09</name>
                            <description>Pmn State</description>
                            <lsb>9</lsb>
                            <msb>9</msb>
                            <access>read-only</access>
                            <enumeratedValues>
                                </enumeratedValues>
                        </field>
                        <field>
                            <name>PIDR10</name>
                            <description>Pmn State</description>
                            <lsb>10</lsb>
                            <msb>10</msb>
                            <access>read-only</access>
                            <enumeratedValues>
                                </enumeratedValues>
                        </field>
                        <field>
                            <name>PIDR11</name>
                            <description>Pmn State</description>
                            <lsb>11</lsb>
                            <msb>11</msb>
                            <access>read-only</access>
                            <enumeratedValues>
                                </enumeratedValues>
                        </field>
                        <field>
                            <name>PIDR12</name>
                            <description>Pmn State</description>
                            <lsb>12</lsb>
                            <msb>12</msb>
                            <access>read-only</access>
                            <enumeratedValues>
                                </enumeratedValues>
                        </field>
                        <field>
                            <name>PIDR13</name>
                            <description>Pmn State</description>
                            <lsb>13</lsb>
                            <msb>13</msb>
                            <access>read-only</access>
                            <enumeratedValues>
                                </enumeratedValues>
                        </field>
                        <field>
                            <name>PIDR14</name>
                            <description>Pmn State</description>
                            <lsb>14</lsb>
                            <msb>14</msb>
                            <access>read-only</access>
                            <enumeratedValues>
                                </enumeratedValues>
                        </field>
                        <field>
                            <name>PIDR15</name>
                            <description>Pmn State</description>
                            <lsb>15</lsb>
                            <msb>15</msb>
                            <access>read-only</access>
                            <enumeratedValues>
                                </enumeratedValues>
                        </field>
                        <field>
                            <name>EIDR00</name>
                            <description>Port Event Input Data</description>
                            <lsb>16</lsb>
                            <msb>16</msb>
                            <access>read-only</access>
                            <enumeratedValues>
                                </enumeratedValues>
                        </field>
                        <field>
                            <name>EIDR01</name>
                            <description>Port Event Input Data</description>
                            <lsb>17</lsb>
                            <msb>17</msb>
                            <access>read-only</access>
                            <enumeratedValues>
                                </enumeratedValues>
                        </field>
                        <field>
                            <name>EIDR02</name>
                            <description>Port Event Input Data</description>
                            <lsb>18</lsb>
                            <msb>18</msb>
                            <access>read-only</access>
                            <enumeratedValues>
                                </enumeratedValues>
                        </field>
                        <field>
                            <name>EIDR03</name>
                            <description>Port Event Input Data</description>
                            <lsb>19</lsb>
                            <msb>19</msb>
                            <access>read-only</access>
                            <enumeratedValues>
                                </enumeratedValues>
                        </field>
                        <field>
                            <name>EIDR04</name>
                            <description>Port Event Input Data</description>
                            <lsb>20</lsb>
                            <msb>20</msb>
                            <access>read-only</access>
                            <enumeratedValues>
                                </enumeratedValues>
                        </field>
                        <field>
                            <name>EIDR05</name>
                            <description>Port Event Input Data</description>
                            <lsb>21</lsb>
                            <msb>21</msb>
                            <access>read-only</access>
                            <enumeratedValues>
                                </enumeratedValues>
                        </field>
                        <field>
                            <name>EIDR06</name>
                            <description>Port Event Input Data</description>
                            <lsb>22</lsb>
                            <msb>22</msb>
                            <access>read-only</access>
                            <enumeratedValues>
                                </enumeratedValues>
                        </field>
                        <field>
                            <name>EIDR07</name>
                            <description>Port Event Input Data</description>
                            <lsb>23</lsb>
                            <msb>23</msb>
                            <access>read-only</access>
                            <enumeratedValues>
                                </enumeratedValues>
                        </field>
                        <field>
                            <name>EIDR08</name>
                            <description>Port Event Input Data</description>
                            <lsb>24</lsb>
                            <msb>24</msb>
                            <access>read-only</access>
                            <enumeratedValues>
                                </enumeratedValues>
                        </field>
                        <field>
                            <name>EIDR09</name>
                            <description>Port Event Input Data</description>
                            <lsb>25</lsb>
                            <msb>25</msb>
                            <access>read-only</access>
                            <enumeratedValues>
                                </enumeratedValues>
                        </field>
                        <field>
                            <name>EIDR10</name>
                            <description>Port Event Input Data</description>
                            <lsb>26</lsb>
                            <msb>26</msb>
                            <access>read-only</access>
                            <enumeratedValues>
                                </enumeratedValues>
                        </field>
                        <field>
                            <name>EIDR11</name>
                            <description>Port Event Input Data</description>
                            <lsb>27</lsb>
                            <msb>27</msb>
                            <access>read-only</access>
                            <enumeratedValues>
                                </enumeratedValues>
                        </field>
                        <field>
                            <name>EIDR12</name>
                            <description>Port Event Input Data</description>
                            <lsb>28</lsb>
                            <msb>28</msb>
                            <access>read-only</access>
                            <enumeratedValues>
                                </enumeratedValues>
                        </field>
                        <field>
                            <name>EIDR13</name>
                            <description>Port Event Input Data</description>
                            <lsb>29</lsb>
                            <msb>29</msb>
                            <access>read-only</access>
                            <enumeratedValues>
                                </enumeratedValues>
                        </field>
                        <field>
                            <name>EIDR14</name>
                            <description>Port Event Input Data</description>
                            <lsb>30</lsb>
                            <msb>30</msb>
                            <access>read-only</access>
                            <enumeratedValues>
                                </enumeratedValues>
                        </field>
                        <field>
                            <name>EIDR15</name>
                            <description>Port Event Input Data</description>
                            <lsb>31</lsb>
                            <msb>31</msb>
                            <access>read-only</access>
                            <enumeratedValues>
                                </enumeratedValues>
                        </field>
                    </fields>
                </register>
                <register>
                    <name>EIDR</name>
                    <description>Port Control Register 2</description>
                    <alternateRegister>PCNTR2</alternateRegister>
                    <addressOffset>0x004</addressOffset>
                    <size>16</size>
                    <access>read-only</access>
                    <resetValue>0x0000</resetValue>
                    <resetMask>0xffff</resetMask>
                    <fields>
                        <field>
                            <name>EIDR00</name>
                            <description>Port Event Input Data</description>
                            <lsb>0</lsb>
                            <msb>0</msb>
                            <access>read-only</access>
                            <enumeratedValues>
                                </enumeratedValues>
                        </field>
                        <field>
                            <name>EIDR01</name>
                            <description>Port Event Input Data</description>
                            <lsb>1</lsb>
                            <msb>1</msb>
                            <access>read-only</access>
                            <enumeratedValues>
                                </enumeratedValues>
                        </field>
                        <field>
                            <name>EIDR02</name>
                            <description>Port Event Input Data</description>
                            <lsb>2</lsb>
                            <msb>2</msb>
                            <access>read-only</access>
                            <enumeratedValues>
                                </enumeratedValues>
                        </field>
                        <field>
                            <name>EIDR03</name>
                            <description>Port Event Input Data</description>
                            <lsb>3</lsb>
                            <msb>3</msb>
                            <access>read-only</access>
                            <enumeratedValues>
                                </enumeratedValues>
                        </field>
                        <field>
                            <name>EIDR04</name>
                            <description>Port Event Input Data</description>
                            <lsb>4</lsb>
                            <msb>4</msb>
                            <access>read-only</access>
                            <enumeratedValues>
                                </enumeratedValues>
                        </field>
                        <field>
                            <name>EIDR05</name>
                            <description>Port Event Input Data</description>
                            <lsb>5</lsb>
                            <msb>5</msb>
                            <access>read-only</access>
                            <enumeratedValues>
                                </enumeratedValues>
                        </field>
                        <field>
                            <name>EIDR06</name>
                            <description>Port Event Input Data</description>
                            <lsb>6</lsb>
                            <msb>6</msb>
                            <access>read-only</access>
                            <enumeratedValues>
                                </enumeratedValues>
                        </field>
                        <field>
                            <name>EIDR07</name>
                            <description>Port Event Input Data</description>
                            <lsb>7</lsb>
                            <msb>7</msb>
                            <access>read-only</access>
                            <enumeratedValues>
                                </enumeratedValues>
                        </field>
                        <field>
                            <name>EIDR08</name>
                            <description>Port Event Input Data</description>
                            <lsb>8</lsb>
                            <msb>8</msb>
                            <access>read-only</access>
                            <enumeratedValues>
                                </enumeratedValues>
                        </field>
                        <field>
                            <name>EIDR09</name>
                            <description>Port Event Input Data</description>
                            <lsb>9</lsb>
                            <msb>9</msb>
                            <access>read-only</access>
                            <enumeratedValues>
                                </enumeratedValues>
                        </field>
                        <field>
                            <name>EIDR10</name>
                            <description>Port Event Input Data</description>
                            <lsb>10</lsb>
                            <msb>10</msb>
                            <access>read-only</access>
                            <enumeratedValues>
                                </enumeratedValues>
                        </field>
                        <field>
                            <name>EIDR11</name>
                            <description>Port Event Input Data</description>
                            <lsb>11</lsb>
                            <msb>11</msb>
                            <access>read-only</access>
                            <enumeratedValues>
                                </enumeratedValues>
                        </field>
                        <field>
                            <name>EIDR12</name>
                            <description>Port Event Input Data</description>
                            <lsb>12</lsb>
                            <msb>12</msb>
                            <access>read-only</access>
                            <enumeratedValues>
                                </enumeratedValues>
                        </field>
                        <field>
                            <name>EIDR13</name>
                            <description>Port Event Input Data</description>
                            <lsb>13</lsb>
                            <msb>13</msb>
                            <access>read-only</access>
                            <enumeratedValues>
                                </enumeratedValues>
                        </field>
                        <field>
                            <name>EIDR14</name>
                            <description>Port Event Input Data</description>
                            <lsb>14</lsb>
                            <msb>14</msb>
                            <access>read-only</access>
                            <enumeratedValues>
                                </enumeratedValues>
                        </field>
                        <field>
                            <name>EIDR15</name>
                            <description>Port Event Input Data</description>
                            <lsb>15</lsb>
                            <msb>15</msb>
                            <access>read-only</access>
                            <enumeratedValues>
                                </enumeratedValues>
                        </field>
                    </fields>
                </register>
                <register>
                    <name>PIDR</name>
                    <description>Port Control Register 2</description>
                    <alternateRegister>PCNTR2</alternateRegister>
                    <addressOffset>0x006</addressOffset>
                    <size>16</size>
                    <access>read-only</access>
                    <resetValue>0x0000</resetValue>
                    <resetMask>0x0000</resetMask>
                    <fields>
                        <field>
                            <name>PIDR00</name>
                            <description>Pmn State</description>
                            <lsb>0</lsb>
                            <msb>0</msb>
                            <access>read-only</access>
                            <enumeratedValues>
                                </enumeratedValues>
                        </field>
                        <field>
                            <name>PIDR01</name>
                            <description>Pmn State</description>
                            <lsb>1</lsb>
                            <msb>1</msb>
                            <access>read-only</access>
                            <enumeratedValues>
                                </enumeratedValues>
                        </field>
                        <field>
                            <name>PIDR02</name>
                            <description>Pmn State</description>
                            <lsb>2</lsb>
                            <msb>2</msb>
                            <access>read-only</access>
                            <enumeratedValues>
                                </enumeratedValues>
                        </field>
                        <field>
                            <name>PIDR03</name>
                            <description>Pmn State</description>
                            <lsb>3</lsb>
                            <msb>3</msb>
                            <access>read-only</access>
                            <enumeratedValues>
                                </enumeratedValues>
                        </field>
                        <field>
                            <name>PIDR04</name>
                            <description>Pmn State</description>
                            <lsb>4</lsb>
                            <msb>4</msb>
                            <access>read-only</access>
                            <enumeratedValues>
                                </enumeratedValues>
                        </field>
                        <field>
                            <name>PIDR05</name>
                            <description>Pmn State</description>
                            <lsb>5</lsb>
                            <msb>5</msb>
                            <access>read-only</access>
                            <enumeratedValues>
                                </enumeratedValues>
                        </field>
                        <field>
                            <name>PIDR06</name>
                            <description>Pmn State</description>
                            <lsb>6</lsb>
                            <msb>6</msb>
                            <access>read-only</access>
                            <enumeratedValues>
                                </enumeratedValues>
                        </field>
                        <field>
                            <name>PIDR07</name>
                            <description>Pmn State</description>
                            <lsb>7</lsb>
                            <msb>7</msb>
                            <access>read-only</access>
                            <enumeratedValues>
                                </enumeratedValues>
                        </field>
                        <field>
                            <name>PIDR08</name>
                            <description>Pmn State</description>
                            <lsb>8</lsb>
                            <msb>8</msb>
                            <access>read-only</access>
                            <enumeratedValues>
                                </enumeratedValues>
                        </field>
                        <field>
                            <name>PIDR09</name>
                            <description>Pmn State</description>
                            <lsb>9</lsb>
                            <msb>9</msb>
                            <access>read-only</access>
                            <enumeratedValues>
                                </enumeratedValues>
                        </field>
                        <field>
                            <name>PIDR10</name>
                            <description>Pmn State</description>
                            <lsb>10</lsb>
                            <msb>10</msb>
                            <access>read-only</access>
                            <enumeratedValues>
                                </enumeratedValues>
                        </field>
                        <field>
                            <name>PIDR11</name>
                            <description>Pmn State</description>
                            <lsb>11</lsb>
                            <msb>11</msb>
                            <access>read-only</access>
                            <enumeratedValues>
                                </enumeratedValues>
                        </field>
                        <field>
                            <name>PIDR12</name>
                            <description>Pmn State</description>
                            <lsb>12</lsb>
                            <msb>12</msb>
                            <access>read-only</access>
                            <enumeratedValues>
                                </enumeratedValues>
                        </field>
                        <field>
                            <name>PIDR13</name>
                            <description>Pmn State</description>
                            <lsb>13</lsb>
                            <msb>13</msb>
                            <access>read-only</access>
                            <enumeratedValues>
                                </enumeratedValues>
                        </field>
                        <field>
                            <name>PIDR14</name>
                            <description>Pmn State</description>
                            <lsb>14</lsb>
                            <msb>14</msb>
                            <access>read-only</access>
                            <enumeratedValues>
                                </enumeratedValues>
                        </field>
                        <field>
                            <name>PIDR15</name>
                            <description>Pmn State</description>
                            <lsb>15</lsb>
                            <msb>15</msb>
                            <access>read-only</access>
                            <enumeratedValues>
                                </enumeratedValues>
                        </field>
                    </fields>
                </register>
                <register>
                    <name>PCNTR3</name>
                    <description>Port Control Register 3</description>
                    <addressOffset>0x008</addressOffset>
                    <size>32</size>
                    <access>write-only</access>
                    <resetValue>0x00000000</resetValue>
                    <resetMask>0xffffffff</resetMask>
                    <fields>
                        <field>
                            <name>POSR00</name>
                            <description>Pmn Output Set</description>
                            <lsb>0</lsb>
                            <msb>0</msb>
                            <access>write-only</access>
                            <enumeratedValues>
                                </enumeratedValues>
                        </field>
                        <field>
                            <name>POSR01</name>
                            <description>Pmn Output Set</description>
                            <lsb>1</lsb>
                            <msb>1</msb>
                            <access>write-only</access>
                            <enumeratedValues>
                                </enumeratedValues>
                        </field>
                        <field>
                            <name>POSR02</name>
                            <description>Pmn Output Set</description>
                            <lsb>2</lsb>
                            <msb>2</msb>
                            <access>write-only</access>
                            <enumeratedValues>
                                </enumeratedValues>
                        </field>
                        <field>
                            <name>POSR03</name>
                            <description>Pmn Output Set</description>
                            <lsb>3</lsb>
                            <msb>3</msb>
                            <access>write-only</access>
                            <enumeratedValues>
                                </enumeratedValues>
                        </field>
                        <field>
                            <name>POSR04</name>
                            <description>Pmn Output Set</description>
                            <lsb>4</lsb>
                            <msb>4</msb>
                            <access>write-only</access>
                            <enumeratedValues>
                                </enumeratedValues>
                        </field>
                        <field>
                            <name>POSR05</name>
                            <description>Pmn Output Set</description>
                            <lsb>5</lsb>
                            <msb>5</msb>
                            <access>write-only</access>
                            <enumeratedValues>
                                </enumeratedValues>
                        </field>
                        <field>
                            <name>POSR06</name>
                            <description>Pmn Output Set</description>
                            <lsb>6</lsb>
                            <msb>6</msb>
                            <access>write-only</access>
                            <enumeratedValues>
                                </enumeratedValues>
                        </field>
                        <field>
                            <name>POSR07</name>
                            <description>Pmn Output Set</description>
                            <lsb>7</lsb>
                            <msb>7</msb>
                            <access>write-only</access>
                            <enumeratedValues>
                                </enumeratedValues>
                        </field>
                        <field>
                            <name>POSR08</name>
                            <description>Pmn Output Set</description>
                            <lsb>8</lsb>
                            <msb>8</msb>
                            <access>write-only</access>
                            <enumeratedValues>
                                </enumeratedValues>
                        </field>
                        <field>
                            <name>POSR09</name>
                            <description>Pmn Output Set</description>
                            <lsb>9</lsb>
                            <msb>9</msb>
                            <access>write-only</access>
                            <enumeratedValues>
                                </enumeratedValues>
                        </field>
                        <field>
                            <name>POSR10</name>
                            <description>Pmn Output Set</description>
                            <lsb>10</lsb>
                            <msb>10</msb>
                            <access>write-only</access>
                            <enumeratedValues>
                                </enumeratedValues>
                        </field>
                        <field>
                            <name>POSR11</name>
                            <description>Pmn Output Set</description>
                            <lsb>11</lsb>
                            <msb>11</msb>
                            <access>write-only</access>
                            <enumeratedValues>
                                </enumeratedValues>
                        </field>
                        <field>
                            <name>POSR12</name>
                            <description>Pmn Output Set</description>
                            <lsb>12</lsb>
                            <msb>12</msb>
                            <access>write-only</access>
                            <enumeratedValues>
                                </enumeratedValues>
                        </field>
                        <field>
                            <name>POSR13</name>
                            <description>Pmn Output Set</description>
                            <lsb>13</lsb>
                            <msb>13</msb>
                            <access>write-only</access>
                            <enumeratedValues>
                                </enumeratedValues>
                        </field>
                        <field>
                            <name>POSR14</name>
                            <description>Pmn Output Set</description>
                            <lsb>14</lsb>
                            <msb>14</msb>
                            <access>write-only</access>
                            <enumeratedValues>
                                </enumeratedValues>
                        </field>
                        <field>
                            <name>POSR15</name>
                            <description>Pmn Output Set</description>
                            <lsb>15</lsb>
                            <msb>15</msb>
                            <access>write-only</access>
                            <enumeratedValues>
                                </enumeratedValues>
                        </field>
                        <field>
                            <name>PORR00</name>
                            <description>Pmn Output Reset</description>
                            <lsb>16</lsb>
                            <msb>16</msb>
                            <access>write-only</access>
                            <enumeratedValues>
                                </enumeratedValues>
                        </field>
                        <field>
                            <name>PORR01</name>
                            <description>Pmn Output Reset</description>
                            <lsb>17</lsb>
                            <msb>17</msb>
                            <access>write-only</access>
                            <enumeratedValues>
                                </enumeratedValues>
                        </field>
                        <field>
                            <name>PORR02</name>
                            <description>Pmn Output Reset</description>
                            <lsb>18</lsb>
                            <msb>18</msb>
                            <access>write-only</access>
                            <enumeratedValues>
                                </enumeratedValues>
                        </field>
                        <field>
                            <name>PORR03</name>
                            <description>Pmn Output Reset</description>
                            <lsb>19</lsb>
                            <msb>19</msb>
                            <access>write-only</access>
                            <enumeratedValues>
                                </enumeratedValues>
                        </field>
                        <field>
                            <name>PORR04</name>
                            <description>Pmn Output Reset</description>
                            <lsb>20</lsb>
                            <msb>20</msb>
                            <access>write-only</access>
                            <enumeratedValues>
                                </enumeratedValues>
                        </field>
                        <field>
                            <name>PORR05</name>
                            <description>Pmn Output Reset</description>
                            <lsb>21</lsb>
                            <msb>21</msb>
                            <access>write-only</access>
                            <enumeratedValues>
                                </enumeratedValues>
                        </field>
                        <field>
                            <name>PORR06</name>
                            <description>Pmn Output Reset</description>
                            <lsb>22</lsb>
                            <msb>22</msb>
                            <access>write-only</access>
                            <enumeratedValues>
                                </enumeratedValues>
                        </field>
                        <field>
                            <name>PORR07</name>
                            <description>Pmn Output Reset</description>
                            <lsb>23</lsb>
                            <msb>23</msb>
                            <access>write-only</access>
                            <enumeratedValues>
                                </enumeratedValues>
                        </field>
                        <field>
                            <name>PORR08</name>
                            <description>Pmn Output Reset</description>
                            <lsb>24</lsb>
                            <msb>24</msb>
                            <access>write-only</access>
                            <enumeratedValues>
                                </enumeratedValues>
                        </field>
                        <field>
                            <name>PORR09</name>
                            <description>Pmn Output Reset</description>
                            <lsb>25</lsb>
                            <msb>25</msb>
                            <access>write-only</access>
                            <enumeratedValues>
                                </enumeratedValues>
                        </field>
                        <field>
                            <name>PORR10</name>
                            <description>Pmn Output Reset</description>
                            <lsb>26</lsb>
                            <msb>26</msb>
                            <access>write-only</access>
                            <enumeratedValues>
                                </enumeratedValues>
                        </field>
                        <field>
                            <name>PORR11</name>
                            <description>Pmn Output Reset</description>
                            <lsb>27</lsb>
                            <msb>27</msb>
                            <access>write-only</access>
                            <enumeratedValues>
                                </enumeratedValues>
                        </field>
                        <field>
                            <name>PORR12</name>
                            <description>Pmn Output Reset</description>
                            <lsb>28</lsb>
                            <msb>28</msb>
                            <access>write-only</access>
                            <enumeratedValues>
                                </enumeratedValues>
                        </field>
                        <field>
                            <name>PORR13</name>
                            <description>Pmn Output Reset</description>
                            <lsb>29</lsb>
                            <msb>29</msb>
                            <access>write-only</access>
                            <enumeratedValues>
                                </enumeratedValues>
                        </field>
                        <field>
                            <name>PORR14</name>
                            <description>Pmn Output Reset</description>
                            <lsb>30</lsb>
                            <msb>30</msb>
                            <access>write-only</access>
                            <enumeratedValues>
                                </enumeratedValues>
                        </field>
                        <field>
                            <name>PORR15</name>
                            <description>Pmn Output Reset</description>
                            <lsb>31</lsb>
                            <msb>31</msb>
                            <access>write-only</access>
                            <enumeratedValues>
                                </enumeratedValues>
                        </field>
                    </fields>
                </register>
                <register>
                    <name>PORR</name>
                    <description>Port Control Register 3</description>
                    <alternateRegister>PCNTR3</alternateRegister>
                    <addressOffset>0x008</addressOffset>
                    <size>16</size>
                    <access>write-only</access>
                    <resetValue>0x0000</resetValue>
                    <resetMask>0xffff</resetMask>
                    <fields>
                        <field>
                            <name>PORR00</name>
                            <description>Pmn Output Reset</description>
                            <lsb>0</lsb>
                            <msb>0</msb>
                            <access>write-only</access>
                            <enumeratedValues>
                                </enumeratedValues>
                        </field>
                        <field>
                            <name>PORR01</name>
                            <description>Pmn Output Reset</description>
                            <lsb>1</lsb>
                            <msb>1</msb>
                            <access>write-only</access>
                            <enumeratedValues>
                                </enumeratedValues>
                        </field>
                        <field>
                            <name>PORR02</name>
                            <description>Pmn Output Reset</description>
                            <lsb>2</lsb>
                            <msb>2</msb>
                            <access>write-only</access>
                            <enumeratedValues>
                                </enumeratedValues>
                        </field>
                        <field>
                            <name>PORR03</name>
                            <description>Pmn Output Reset</description>
                            <lsb>3</lsb>
                            <msb>3</msb>
                            <access>write-only</access>
                            <enumeratedValues>
                                </enumeratedValues>
                        </field>
                        <field>
                            <name>PORR04</name>
                            <description>Pmn Output Reset</description>
                            <lsb>4</lsb>
                            <msb>4</msb>
                            <access>write-only</access>
                            <enumeratedValues>
                                </enumeratedValues>
                        </field>
                        <field>
                            <name>PORR05</name>
                            <description>Pmn Output Reset</description>
                            <lsb>5</lsb>
                            <msb>5</msb>
                            <access>write-only</access>
                            <enumeratedValues>
                                </enumeratedValues>
                        </field>
                        <field>
                            <name>PORR06</name>
                            <description>Pmn Output Reset</description>
                            <lsb>6</lsb>
                            <msb>6</msb>
                            <access>write-only</access>
                            <enumeratedValues>
                                </enumeratedValues>
                        </field>
                        <field>
                            <name>PORR07</name>
                            <description>Pmn Output Reset</description>
                            <lsb>7</lsb>
                            <msb>7</msb>
                            <access>write-only</access>
                            <enumeratedValues>
                                </enumeratedValues>
                        </field>
                        <field>
                            <name>PORR08</name>
                            <description>Pmn Output Reset</description>
                            <lsb>8</lsb>
                            <msb>8</msb>
                            <access>write-only</access>
                            <enumeratedValues>
                                </enumeratedValues>
                        </field>
                        <field>
                            <name>PORR09</name>
                            <description>Pmn Output Reset</description>
                            <lsb>9</lsb>
                            <msb>9</msb>
                            <access>write-only</access>
                            <enumeratedValues>
                                </enumeratedValues>
                        </field>
                        <field>
                            <name>PORR10</name>
                            <description>Pmn Output Reset</description>
                            <lsb>10</lsb>
                            <msb>10</msb>
                            <access>write-only</access>
                            <enumeratedValues>
                                </enumeratedValues>
                        </field>
                        <field>
                            <name>PORR11</name>
                            <description>Pmn Output Reset</description>
                            <lsb>11</lsb>
                            <msb>11</msb>
                            <access>write-only</access>
                            <enumeratedValues>
                                </enumeratedValues>
                        </field>
                        <field>
                            <name>PORR12</name>
                            <description>Pmn Output Reset</description>
                            <lsb>12</lsb>
                            <msb>12</msb>
                            <access>write-only</access>
                            <enumeratedValues>
                                </enumeratedValues>
                        </field>
                        <field>
                            <name>PORR13</name>
                            <description>Pmn Output Reset</description>
                            <lsb>13</lsb>
                            <msb>13</msb>
                            <access>write-only</access>
                            <enumeratedValues>
                                </enumeratedValues>
                        </field>
                        <field>
                            <name>PORR14</name>
                            <description>Pmn Output Reset</description>
                            <lsb>14</lsb>
                            <msb>14</msb>
                            <access>write-only</access>
                            <enumeratedValues>
                                </enumeratedValues>
                        </field>
                        <field>
                            <name>PORR15</name>
                            <description>Pmn Output Reset</description>
                            <lsb>15</lsb>
                            <msb>15</msb>
                            <access>write-only</access>
                            <enumeratedValues>
                                </enumeratedValues>
                        </field>
                    </fields>
                </register>
                <register>
                    <name>POSR</name>
                    <description>Port Control Register 3</description>
                    <alternateRegister>PCNTR3</alternateRegister>
                    <addressOffset>0x00A</addressOffset>
                    <size>16</size>
                    <access>write-only</access>
                    <resetValue>0x0000</resetValue>
                    <resetMask>0xffff</resetMask>
                    <fields>
                        <field>
                            <name>POSR00</name>
                            <description>Pmn Output Set</description>
                            <lsb>0</lsb>
                            <msb>0</msb>
                            <access>write-only</access>
                            <enumeratedValues>
                                </enumeratedValues>
                        </field>
                        <field>
                            <name>POSR01</name>
                            <description>Pmn Output Set</description>
                            <lsb>1</lsb>
                            <msb>1</msb>
                            <access>write-only</access>
                            <enumeratedValues>
                                </enumeratedValues>
                        </field>
                        <field>
                            <name>POSR02</name>
                            <description>Pmn Output Set</description>
                            <lsb>2</lsb>
                            <msb>2</msb>
                            <access>write-only</access>
                            <enumeratedValues>
                                </enumeratedValues>
                        </field>
                        <field>
                            <name>POSR03</name>
                            <description>Pmn Output Set</description>
                            <lsb>3</lsb>
                            <msb>3</msb>
                            <access>write-only</access>
                            <enumeratedValues>
                                </enumeratedValues>
                        </field>
                        <field>
                            <name>POSR04</name>
                            <description>Pmn Output Set</description>
                            <lsb>4</lsb>
                            <msb>4</msb>
                            <access>write-only</access>
                            <enumeratedValues>
                                </enumeratedValues>
                        </field>
                        <field>
                            <name>POSR05</name>
                            <description>Pmn Output Set</description>
                            <lsb>5</lsb>
                            <msb>5</msb>
                            <access>write-only</access>
                            <enumeratedValues>
                                </enumeratedValues>
                        </field>
                        <field>
                            <name>POSR06</name>
                            <description>Pmn Output Set</description>
                            <lsb>6</lsb>
                            <msb>6</msb>
                            <access>write-only</access>
                            <enumeratedValues>
                                </enumeratedValues>
                        </field>
                        <field>
                            <name>POSR07</name>
                            <description>Pmn Output Set</description>
                            <lsb>7</lsb>
                            <msb>7</msb>
                            <access>write-only</access>
                            <enumeratedValues>
                                </enumeratedValues>
                        </field>
                        <field>
                            <name>POSR08</name>
                            <description>Pmn Output Set</description>
                            <lsb>8</lsb>
                            <msb>8</msb>
                            <access>write-only</access>
                            <enumeratedValues>
                                </enumeratedValues>
                        </field>
                        <field>
                            <name>POSR09</name>
                            <description>Pmn Output Set</description>
                            <lsb>9</lsb>
                            <msb>9</msb>
                            <access>write-only</access>
                            <enumeratedValues>
                                </enumeratedValues>
                        </field>
                        <field>
                            <name>POSR10</name>
                            <description>Pmn Output Set</description>
                            <lsb>10</lsb>
                            <msb>10</msb>
                            <access>write-only</access>
                            <enumeratedValues>
                                </enumeratedValues>
                        </field>
                        <field>
                            <name>POSR11</name>
                            <description>Pmn Output Set</description>
                            <lsb>11</lsb>
                            <msb>11</msb>
                            <access>write-only</access>
                            <enumeratedValues>
                                </enumeratedValues>
                        </field>
                        <field>
                            <name>POSR12</name>
                            <description>Pmn Output Set</description>
                            <lsb>12</lsb>
                            <msb>12</msb>
                            <access>write-only</access>
                            <enumeratedValues>
                                </enumeratedValues>
                        </field>
                        <field>
                            <name>POSR13</name>
                            <description>Pmn Output Set</description>
                            <lsb>13</lsb>
                            <msb>13</msb>
                            <access>write-only</access>
                            <enumeratedValues>
                                </enumeratedValues>
                        </field>
                        <field>
                            <name>POSR14</name>
                            <description>Pmn Output Set</description>
                            <lsb>14</lsb>
                            <msb>14</msb>
                            <access>write-only</access>
                            <enumeratedValues>
                                </enumeratedValues>
                        </field>
                        <field>
                            <name>POSR15</name>
                            <description>Pmn Output Set</description>
                            <lsb>15</lsb>
                            <msb>15</msb>
                            <access>write-only</access>
                            <enumeratedValues>
                                </enumeratedValues>
                        </field>
                    </fields>
                </register>
                <register>
                    <name>PCNTR4</name>
                    <description>Port Control Register 4</description>
                    <addressOffset>0x00C</addressOffset>
                    <size>32</size>
                    <access>read-write</access>
                    <resetValue>0x00000000</resetValue>
                    <resetMask>0xffffffff</resetMask>
                    <fields>
                        <field>
                            <name>EOSR00</name>
                            <description>Pmn Event Output Set</description>
                            <lsb>0</lsb>
                            <msb>0</msb>
                            <access>read-write</access>
                            <enumeratedValues>
                                </enumeratedValues>
                        </field>
                        <field>
                            <name>EOSR01</name>
                            <description>Pmn Event Output Set</description>
                            <lsb>1</lsb>
                            <msb>1</msb>
                            <access>read-write</access>
                            <enumeratedValues>
                                </enumeratedValues>
                        </field>
                        <field>
                            <name>EOSR02</name>
                            <description>Pmn Event Output Set</description>
                            <lsb>2</lsb>
                            <msb>2</msb>
                            <access>read-write</access>
                            <enumeratedValues>
                                </enumeratedValues>
                        </field>
                        <field>
                            <name>EOSR03</name>
                            <description>Pmn Event Output Set</description>
                            <lsb>3</lsb>
                            <msb>3</msb>
                            <access>read-write</access>
                            <enumeratedValues>
                                </enumeratedValues>
                        </field>
                        <field>
                            <name>EOSR04</name>
                            <description>Pmn Event Output Set</description>
                            <lsb>4</lsb>
                            <msb>4</msb>
                            <access>read-write</access>
                            <enumeratedValues>
                                </enumeratedValues>
                        </field>
                        <field>
                            <name>EOSR05</name>
                            <description>Pmn Event Output Set</description>
                            <lsb>5</lsb>
                            <msb>5</msb>
                            <access>read-write</access>
                            <enumeratedValues>
                                </enumeratedValues>
                        </field>
                        <field>
                            <name>EOSR06</name>
                            <description>Pmn Event Output Set</description>
                            <lsb>6</lsb>
                            <msb>6</msb>
                            <access>read-write</access>
                            <enumeratedValues>
                                </enumeratedValues>
                        </field>
                        <field>
                            <name>EOSR07</name>
                            <description>Pmn Event Output Set</description>
                            <lsb>7</lsb>
                            <msb>7</msb>
                            <access>read-write</access>
                            <enumeratedValues>
                                </enumeratedValues>
                        </field>
                        <field>
                            <name>EOSR08</name>
                            <description>Pmn Event Output Set</description>
                            <lsb>8</lsb>
                            <msb>8</msb>
                            <access>read-write</access>
                            <enumeratedValues>
                                </enumeratedValues>
                        </field>
                        <field>
                            <name>EOSR09</name>
                            <description>Pmn Event Output Set</description>
                            <lsb>9</lsb>
                            <msb>9</msb>
                            <access>read-write</access>
                            <enumeratedValues>
                                </enumeratedValues>
                        </field>
                        <field>
                            <name>EOSR10</name>
                            <description>Pmn Event Output Set</description>
                            <lsb>10</lsb>
                            <msb>10</msb>
                            <access>read-write</access>
                            <enumeratedValues>
                                </enumeratedValues>
                        </field>
                        <field>
                            <name>EOSR11</name>
                            <description>Pmn Event Output Set</description>
                            <lsb>11</lsb>
                            <msb>11</msb>
                            <access>read-write</access>
                            <enumeratedValues>
                                </enumeratedValues>
                        </field>
                        <field>
                            <name>EOSR12</name>
                            <description>Pmn Event Output Set</description>
                            <lsb>12</lsb>
                            <msb>12</msb>
                            <access>read-write</access>
                            <enumeratedValues>
                                </enumeratedValues>
                        </field>
                        <field>
                            <name>EOSR13</name>
                            <description>Pmn Event Output Set</description>
                            <lsb>13</lsb>
                            <msb>13</msb>
                            <access>read-write</access>
                            <enumeratedValues>
                                </enumeratedValues>
                        </field>
                        <field>
                            <name>EOSR14</name>
                            <description>Pmn Event Output Set</description>
                            <lsb>14</lsb>
                            <msb>14</msb>
                            <access>read-write</access>
                            <enumeratedValues>
                                </enumeratedValues>
                        </field>
                        <field>
                            <name>EOSR15</name>
                            <description>Pmn Event Output Set</description>
                            <lsb>15</lsb>
                            <msb>15</msb>
                            <access>read-write</access>
                            <enumeratedValues>
                                </enumeratedValues>
                        </field>
                        <field>
                            <name>EORR00</name>
                            <description>Pmn Event Output Reset</description>
                            <lsb>16</lsb>
                            <msb>16</msb>
                            <access>read-write</access>
                            <enumeratedValues>
                                </enumeratedValues>
                        </field>
                        <field>
                            <name>EORR01</name>
                            <description>Pmn Event Output Reset</description>
                            <lsb>17</lsb>
                            <msb>17</msb>
                            <access>read-write</access>
                            <enumeratedValues>
                                </enumeratedValues>
                        </field>
                        <field>
                            <name>EORR02</name>
                            <description>Pmn Event Output Reset</description>
                            <lsb>18</lsb>
                            <msb>18</msb>
                            <access>read-write</access>
                            <enumeratedValues>
                                </enumeratedValues>
                        </field>
                        <field>
                            <name>EORR03</name>
                            <description>Pmn Event Output Reset</description>
                            <lsb>19</lsb>
                            <msb>19</msb>
                            <access>read-write</access>
                            <enumeratedValues>
                                </enumeratedValues>
                        </field>
                        <field>
                            <name>EORR04</name>
                            <description>Pmn Event Output Reset</description>
                            <lsb>20</lsb>
                            <msb>20</msb>
                            <access>read-write</access>
                            <enumeratedValues>
                                </enumeratedValues>
                        </field>
                        <field>
                            <name>EORR05</name>
                            <description>Pmn Event Output Reset</description>
                            <lsb>21</lsb>
                            <msb>21</msb>
                            <access>read-write</access>
                            <enumeratedValues>
                                </enumeratedValues>
                        </field>
                        <field>
                            <name>EORR06</name>
                            <description>Pmn Event Output Reset</description>
                            <lsb>22</lsb>
                            <msb>22</msb>
                            <access>read-write</access>
                            <enumeratedValues>
                                </enumeratedValues>
                        </field>
                        <field>
                            <name>EORR07</name>
                            <description>Pmn Event Output Reset</description>
                            <lsb>23</lsb>
                            <msb>23</msb>
                            <access>read-write</access>
                            <enumeratedValues>
                                </enumeratedValues>
                        </field>
                        <field>
                            <name>EORR08</name>
                            <description>Pmn Event Output Reset</description>
                            <lsb>24</lsb>
                            <msb>24</msb>
                            <access>read-write</access>
                            <enumeratedValues>
                                </enumeratedValues>
                        </field>
                        <field>
                            <name>EORR09</name>
                            <description>Pmn Event Output Reset</description>
                            <lsb>25</lsb>
                            <msb>25</msb>
                            <access>read-write</access>
                            <enumeratedValues>
                                </enumeratedValues>
                        </field>
                        <field>
                            <name>EORR10</name>
                            <description>Pmn Event Output Reset</description>
                            <lsb>26</lsb>
                            <msb>26</msb>
                            <access>read-write</access>
                            <enumeratedValues>
                                </enumeratedValues>
                        </field>
                        <field>
                            <name>EORR11</name>
                            <description>Pmn Event Output Reset</description>
                            <lsb>27</lsb>
                            <msb>27</msb>
                            <access>read-write</access>
                            <enumeratedValues>
                                </enumeratedValues>
                        </field>
                        <field>
                            <name>EORR12</name>
                            <description>Pmn Event Output Reset</description>
                            <lsb>28</lsb>
                            <msb>28</msb>
                            <access>read-write</access>
                            <enumeratedValues>
                                </enumeratedValues>
                        </field>
                        <field>
                            <name>EORR13</name>
                            <description>Pmn Event Output Reset</description>
                            <lsb>29</lsb>
                            <msb>29</msb>
                            <access>read-write</access>
                            <enumeratedValues>
                                </enumeratedValues>
                        </field>
                        <field>
                            <name>EORR14</name>
                            <description>Pmn Event Output Reset</description>
                            <lsb>30</lsb>
                            <msb>30</msb>
                            <access>read-write</access>
                            <enumeratedValues>
                                </enumeratedValues>
                        </field>
                        <field>
                            <name>EORR15</name>
                            <description>Pmn Event Output Reset</description>
                            <lsb>31</lsb>
                            <msb>31</msb>
                            <access>read-write</access>
                            <enumeratedValues>
                                </enumeratedValues>
                        </field>
                    </fields>
                </register>
                <register>
                    <name>EORR</name>
                    <description>Port Control Register 4</description>
                    <alternateRegister>PCNTR4</alternateRegister>
                    <addressOffset>0x00C</addressOffset>
                    <size>16</size>
                    <access>read-write</access>
                    <resetValue>0x0000</resetValue>
                    <resetMask>0xffff</resetMask>
                    <fields>
                        <field>
                            <name>EORR00</name>
                            <description>Pmn Event Output Reset</description>
                            <lsb>0</lsb>
                            <msb>0</msb>
                            <access>read-write</access>
                            <enumeratedValues>
                                </enumeratedValues>
                        </field>
                        <field>
                            <name>EORR01</name>
                            <description>Pmn Event Output Reset</description>
                            <lsb>1</lsb>
                            <msb>1</msb>
                            <access>read-write</access>
                            <enumeratedValues>
                                </enumeratedValues>
                        </field>
                        <field>
                            <name>EORR02</name>
                            <description>Pmn Event Output Reset</description>
                            <lsb>2</lsb>
                            <msb>2</msb>
                            <access>read-write</access>
                            <enumeratedValues>
                                </enumeratedValues>
                        </field>
                        <field>
                            <name>EORR03</name>
                            <description>Pmn Event Output Reset</description>
                            <lsb>3</lsb>
                            <msb>3</msb>
                            <access>read-write</access>
                            <enumeratedValues>
                                </enumeratedValues>
                        </field>
                        <field>
                            <name>EORR04</name>
                            <description>Pmn Event Output Reset</description>
                            <lsb>4</lsb>
                            <msb>4</msb>
                            <access>read-write</access>
                            <enumeratedValues>
                                </enumeratedValues>
                        </field>
                        <field>
                            <name>EORR05</name>
                            <description>Pmn Event Output Reset</description>
                            <lsb>5</lsb>
                            <msb>5</msb>
                            <access>read-write</access>
                            <enumeratedValues>
                                </enumeratedValues>
                        </field>
                        <field>
                            <name>EORR06</name>
                            <description>Pmn Event Output Reset</description>
                            <lsb>6</lsb>
                            <msb>6</msb>
                            <access>read-write</access>
                            <enumeratedValues>
                                </enumeratedValues>
                        </field>
                        <field>
                            <name>EORR07</name>
                            <description>Pmn Event Output Reset</description>
                            <lsb>7</lsb>
                            <msb>7</msb>
                            <access>read-write</access>
                            <enumeratedValues>
                                </enumeratedValues>
                        </field>
                        <field>
                            <name>EORR08</name>
                            <description>Pmn Event Output Reset</description>
                            <lsb>8</lsb>
                            <msb>8</msb>
                            <access>read-write</access>
                            <enumeratedValues>
                                </enumeratedValues>
                        </field>
                        <field>
                            <name>EORR09</name>
                            <description>Pmn Event Output Reset</description>
                            <lsb>9</lsb>
                            <msb>9</msb>
                            <access>read-write</access>
                            <enumeratedValues>
                                </enumeratedValues>
                        </field>
                        <field>
                            <name>EORR10</name>
                            <description>Pmn Event Output Reset</description>
                            <lsb>10</lsb>
                            <msb>10</msb>
                            <access>read-write</access>
                            <enumeratedValues>
                                </enumeratedValues>
                        </field>
                        <field>
                            <name>EORR11</name>
                            <description>Pmn Event Output Reset</description>
                            <lsb>11</lsb>
                            <msb>11</msb>
                            <access>read-write</access>
                            <enumeratedValues>
                                </enumeratedValues>
                        </field>
                        <field>
                            <name>EORR12</name>
                            <description>Pmn Event Output Reset</description>
                            <lsb>12</lsb>
                            <msb>12</msb>
                            <access>read-write</access>
                            <enumeratedValues>
                                </enumeratedValues>
                        </field>
                        <field>
                            <name>EORR13</name>
                            <description>Pmn Event Output Reset</description>
                            <lsb>13</lsb>
                            <msb>13</msb>
                            <access>read-write</access>
                            <enumeratedValues>
                                </enumeratedValues>
                        </field>
                        <field>
                            <name>EORR14</name>
                            <description>Pmn Event Output Reset</description>
                            <lsb>14</lsb>
                            <msb>14</msb>
                            <access>read-write</access>
                            <enumeratedValues>
                                </enumeratedValues>
                        </field>
                        <field>
                            <name>EORR15</name>
                            <description>Pmn Event Output Reset</description>
                            <lsb>15</lsb>
                            <msb>15</msb>
                            <access>read-write</access>
                            <enumeratedValues>
                                </enumeratedValues>
                        </field>
                    </fields>
                </register>
                <register>
                    <name>EOSR</name>
                    <description>Port Control Register 4</description>
                    <alternateRegister>PCNTR4</alternateRegister>
                    <addressOffset>0x00E</addressOffset>
                    <size>16</size>
                    <access>read-write</access>
                    <resetValue>0x0000</resetValue>
                    <resetMask>0xffff</resetMask>
                    <fields>
                        <field>
                            <name>EOSR00</name>
                            <description>Pmn Event Output Set</description>
                            <lsb>0</lsb>
                            <msb>0</msb>
                            <access>read-write</access>
                            <enumeratedValues>
                                </enumeratedValues>
                        </field>
                        <field>
                            <name>EOSR01</name>
                            <description>Pmn Event Output Set</description>
                            <lsb>1</lsb>
                            <msb>1</msb>
                            <access>read-write</access>
                            <enumeratedValues>
                                </enumeratedValues>
                        </field>
                        <field>
                            <name>EOSR02</name>
                            <description>Pmn Event Output Set</description>
                            <lsb>2</lsb>
                            <msb>2</msb>
                            <access>read-write</access>
                            <enumeratedValues>
                                </enumeratedValues>
                        </field>
                        <field>
                            <name>EOSR03</name>
                            <description>Pmn Event Output Set</description>
                            <lsb>3</lsb>
                            <msb>3</msb>
                            <access>read-write</access>
                            <enumeratedValues>
                                </enumeratedValues>
                        </field>
                        <field>
                            <name>EOSR04</name>
                            <description>Pmn Event Output Set</description>
                            <lsb>4</lsb>
                            <msb>4</msb>
                            <access>read-write</access>
                            <enumeratedValues>
                                </enumeratedValues>
                        </field>
                        <field>
                            <name>EOSR05</name>
                            <description>Pmn Event Output Set</description>
                            <lsb>5</lsb>
                            <msb>5</msb>
                            <access>read-write</access>
                            <enumeratedValues>
                                </enumeratedValues>
                        </field>
                        <field>
                            <name>EOSR06</name>
                            <description>Pmn Event Output Set</description>
                            <lsb>6</lsb>
                            <msb>6</msb>
                            <access>read-write</access>
                            <enumeratedValues>
                                </enumeratedValues>
                        </field>
                        <field>
                            <name>EOSR07</name>
                            <description>Pmn Event Output Set</description>
                            <lsb>7</lsb>
                            <msb>7</msb>
                            <access>read-write</access>
                            <enumeratedValues>
                                </enumeratedValues>
                        </field>
                        <field>
                            <name>EOSR08</name>
                            <description>Pmn Event Output Set</description>
                            <lsb>8</lsb>
                            <msb>8</msb>
                            <access>read-write</access>
                            <enumeratedValues>
                                </enumeratedValues>
                        </field>
                        <field>
                            <name>EOSR09</name>
                            <description>Pmn Event Output Set</description>
                            <lsb>9</lsb>
                            <msb>9</msb>
                            <access>read-write</access>
                            <enumeratedValues>
                                </enumeratedValues>
                        </field>
                        <field>
                            <name>EOSR10</name>
                            <description>Pmn Event Output Set</description>
                            <lsb>10</lsb>
                            <msb>10</msb>
                            <access>read-write</access>
                            <enumeratedValues>
                                </enumeratedValues>
                        </field>
                        <field>
                            <name>EOSR11</name>
                            <description>Pmn Event Output Set</description>
                            <lsb>11</lsb>
                            <msb>11</msb>
                            <access>read-write</access>
                            <enumeratedValues>
                                </enumeratedValues>
                        </field>
                        <field>
                            <name>EOSR12</name>
                            <description>Pmn Event Output Set</description>
                            <lsb>12</lsb>
                            <msb>12</msb>
                            <access>read-write</access>
                            <enumeratedValues>
                                </enumeratedValues>
                        </field>
                        <field>
                            <name>EOSR13</name>
                            <description>Pmn Event Output Set</description>
                            <lsb>13</lsb>
                            <msb>13</msb>
                            <access>read-write</access>
                            <enumeratedValues>
                                </enumeratedValues>
                        </field>
                        <field>
                            <name>EOSR14</name>
                            <description>Pmn Event Output Set</description>
                            <lsb>14</lsb>
                            <msb>14</msb>
                            <access>read-write</access>
                            <enumeratedValues>
                                </enumeratedValues>
                        </field>
                        <field>
                            <name>EOSR15</name>
                            <description>Pmn Event Output Set</description>
                            <lsb>15</lsb>
                            <msb>15</msb>
                            <access>read-write</access>
                            <enumeratedValues>
                                </enumeratedValues>
                        </field>
                    </fields>
                </register>
            </registers>
        </peripheral>
        <peripheral derivedFrom="PORT1">
            <name>PORT2</name>
            <description>Pmn Pin FunctionPort 2 Control RegistersPmn Pin Function Control Register</description>
            <baseAddress>0x40080040</baseAddress>
        </peripheral>
        <peripheral derivedFrom="PORT1">
            <name>PORT3</name>
            <description>Pmn Pin FunctionPort 3 Control RegistersPmn Pin Function Control Register</description>
            <baseAddress>0x40080060</baseAddress>
        </peripheral>
        <peripheral derivedFrom="PORT1">
            <name>PORT4</name>
            <description>Pmn Pin FunctionPort 4 Control RegistersPmn Pin Function Control Register</description>
            <baseAddress>0x40080080</baseAddress>
        </peripheral>
        <peripheral derivedFrom="PORT0">
            <name>PORT5</name>
            <description>Pmn Pin FunctionPort 5 Control RegistersPmn Pin Function Control Register</description>
            <baseAddress>0x400800A0</baseAddress>
        </peripheral>
        <peripheral derivedFrom="PORT0">
            <name>PORT6</name>
            <description>Pmn Pin FunctionPort 6 Control RegistersPmn Pin Function Control Register</description>
            <baseAddress>0x400800C0</baseAddress>
        </peripheral>
        <peripheral derivedFrom="PORT0">
            <name>PORT7</name>
            <description>Pmn Pin FunctionPort 7 Control RegistersPmn Pin Function Control Register</description>
            <baseAddress>0x400800E0</baseAddress>
        </peripheral>
        <peripheral derivedFrom="PORT0">
            <name>PORT8</name>
            <description>Pmn Pin FunctionPort 8 Control RegistersPmn Pin Function Control Register</description>
            <baseAddress>0x40080100</baseAddress>
        </peripheral>
        <peripheral derivedFrom="PORT0">
            <name>PORT9</name>
            <description>Pmn Pin FunctionPort 9 Control RegistersPmn Pin Function Control Register</description>
            <baseAddress>0x40080120</baseAddress>
        </peripheral>
        <peripheral>
            <name>PORTA</name>
            <description>Pmn Pin FunctionPort A Control RegistersPmn Pin Function Control Register</description>
            <baseAddress>0x40080140</baseAddress>
            <addressBlock>
                <offset>0x00</offset>
                <size>12</size>
                <usage>registers</usage>
            </addressBlock>
            <registers>
                <register>
                    <name>PCNTR1</name>
                    <description>Port Control Register 1</description>
                    <addressOffset>0x000</addressOffset>
                    <size>32</size>
                    <access>read-write</access>
                    <resetValue>0x00000000</resetValue>
                    <resetMask>0xffffffff</resetMask>
                    <fields>
                        <field>
                            <name>PDR00</name>
                            <description>Pmn Direction</description>
                            <lsb>0</lsb>
                            <msb>0</msb>
                            <access>read-write</access>
                            <enumeratedValues>
                                </enumeratedValues>
                        </field>
                        <field>
                            <name>PDR01</name>
                            <description>Pmn Direction</description>
                            <lsb>1</lsb>
                            <msb>1</msb>
                            <access>read-write</access>
                            <enumeratedValues>
                                </enumeratedValues>
                        </field>
                        <field>
                            <name>PDR02</name>
                            <description>Pmn Direction</description>
                            <lsb>2</lsb>
                            <msb>2</msb>
                            <access>read-write</access>
                            <enumeratedValues>
                                </enumeratedValues>
                        </field>
                        <field>
                            <name>PDR03</name>
                            <description>Pmn Direction</description>
                            <lsb>3</lsb>
                            <msb>3</msb>
                            <access>read-write</access>
                            <enumeratedValues>
                                </enumeratedValues>
                        </field>
                        <field>
                            <name>PDR04</name>
                            <description>Pmn Direction</description>
                            <lsb>4</lsb>
                            <msb>4</msb>
                            <access>read-write</access>
                            <enumeratedValues>
                                </enumeratedValues>
                        </field>
                        <field>
                            <name>PDR05</name>
                            <description>Pmn Direction</description>
                            <lsb>5</lsb>
                            <msb>5</msb>
                            <access>read-write</access>
                            <enumeratedValues>
                                </enumeratedValues>
                        </field>
                        <field>
                            <name>PDR06</name>
                            <description>Pmn Direction</description>
                            <lsb>6</lsb>
                            <msb>6</msb>
                            <access>read-write</access>
                            <enumeratedValues>
                                </enumeratedValues>
                        </field>
                        <field>
                            <name>PDR07</name>
                            <description>Pmn Direction</description>
                            <lsb>7</lsb>
                            <msb>7</msb>
                            <access>read-write</access>
                            <enumeratedValues>
                                </enumeratedValues>
                        </field>
                        <field>
                            <name>PDR08</name>
                            <description>Pmn Direction</description>
                            <lsb>8</lsb>
                            <msb>8</msb>
                            <access>read-write</access>
                            <enumeratedValues>
                                </enumeratedValues>
                        </field>
                        <field>
                            <name>PDR09</name>
                            <description>Pmn Direction</description>
                            <lsb>9</lsb>
                            <msb>9</msb>
                            <access>read-write</access>
                            <enumeratedValues>
                                </enumeratedValues>
                        </field>
                        <field>
                            <name>PDR10</name>
                            <description>Pmn Direction</description>
                            <lsb>10</lsb>
                            <msb>10</msb>
                            <access>read-write</access>
                            <enumeratedValues>
                                </enumeratedValues>
                        </field>
                        <field>
                            <name>PDR11</name>
                            <description>Pmn Direction</description>
                            <lsb>11</lsb>
                            <msb>11</msb>
                            <access>read-write</access>
                            <enumeratedValues>
                                </enumeratedValues>
                        </field>
                        <field>
                            <name>PDR12</name>
                            <description>Pmn Direction</description>
                            <lsb>12</lsb>
                            <msb>12</msb>
                            <access>read-write</access>
                            <enumeratedValues>
                                </enumeratedValues>
                        </field>
                        <field>
                            <name>PDR13</name>
                            <description>Pmn Direction</description>
                            <lsb>13</lsb>
                            <msb>13</msb>
                            <access>read-write</access>
                            <enumeratedValues>
                                </enumeratedValues>
                        </field>
                        <field>
                            <name>PDR14</name>
                            <description>Pmn Direction</description>
                            <lsb>14</lsb>
                            <msb>14</msb>
                            <access>read-write</access>
                            <enumeratedValues>
                                </enumeratedValues>
                        </field>
                        <field>
                            <name>PDR15</name>
                            <description>Pmn Direction</description>
                            <lsb>15</lsb>
                            <msb>15</msb>
                            <access>read-write</access>
                            <enumeratedValues>
                                </enumeratedValues>
                        </field>
                        <field>
                            <name>PODR00</name>
                            <description>Pmn Output Data</description>
                            <lsb>16</lsb>
                            <msb>16</msb>
                            <access>read-write</access>
                            <enumeratedValues>
                                </enumeratedValues>
                        </field>
                        <field>
                            <name>PODR01</name>
                            <description>Pmn Output Data</description>
                            <lsb>17</lsb>
                            <msb>17</msb>
                            <access>read-write</access>
                            <enumeratedValues>
                                </enumeratedValues>
                        </field>
                        <field>
                            <name>PODR02</name>
                            <description>Pmn Output Data</description>
                            <lsb>18</lsb>
                            <msb>18</msb>
                            <access>read-write</access>
                            <enumeratedValues>
                                </enumeratedValues>
                        </field>
                        <field>
                            <name>PODR03</name>
                            <description>Pmn Output Data</description>
                            <lsb>19</lsb>
                            <msb>19</msb>
                            <access>read-write</access>
                            <enumeratedValues>
                                </enumeratedValues>
                        </field>
                        <field>
                            <name>PODR04</name>
                            <description>Pmn Output Data</description>
                            <lsb>20</lsb>
                            <msb>20</msb>
                            <access>read-write</access>
                            <enumeratedValues>
                                </enumeratedValues>
                        </field>
                        <field>
                            <name>PODR05</name>
                            <description>Pmn Output Data</description>
                            <lsb>21</lsb>
                            <msb>21</msb>
                            <access>read-write</access>
                            <enumeratedValues>
                                </enumeratedValues>
                        </field>
                        <field>
                            <name>PODR06</name>
                            <description>Pmn Output Data</description>
                            <lsb>22</lsb>
                            <msb>22</msb>
                            <access>read-write</access>
                            <enumeratedValues>
                                </enumeratedValues>
                        </field>
                        <field>
                            <name>PODR07</name>
                            <description>Pmn Output Data</description>
                            <lsb>23</lsb>
                            <msb>23</msb>
                            <access>read-write</access>
                            <enumeratedValues>
                                </enumeratedValues>
                        </field>
                        <field>
                            <name>PODR08</name>
                            <description>Pmn Output Data</description>
                            <lsb>24</lsb>
                            <msb>24</msb>
                            <access>read-write</access>
                            <enumeratedValues>
                                </enumeratedValues>
                        </field>
                        <field>
                            <name>PODR09</name>
                            <description>Pmn Output Data</description>
                            <lsb>25</lsb>
                            <msb>25</msb>
                            <access>read-write</access>
                            <enumeratedValues>
                                </enumeratedValues>
                        </field>
                        <field>
                            <name>PODR10</name>
                            <description>Pmn Output Data</description>
                            <lsb>26</lsb>
                            <msb>26</msb>
                            <access>read-write</access>
                            <enumeratedValues>
                                </enumeratedValues>
                        </field>
                        <field>
                            <name>PODR11</name>
                            <description>Pmn Output Data</description>
                            <lsb>27</lsb>
                            <msb>27</msb>
                            <access>read-write</access>
                            <enumeratedValues>
                                </enumeratedValues>
                        </field>
                        <field>
                            <name>PODR12</name>
                            <description>Pmn Output Data</description>
                            <lsb>28</lsb>
                            <msb>28</msb>
                            <access>read-write</access>
                            <enumeratedValues>
                                </enumeratedValues>
                        </field>
                        <field>
                            <name>PODR13</name>
                            <description>Pmn Output Data</description>
                            <lsb>29</lsb>
                            <msb>29</msb>
                            <access>read-write</access>
                            <enumeratedValues>
                                </enumeratedValues>
                        </field>
                        <field>
                            <name>PODR14</name>
                            <description>Pmn Output Data</description>
                            <lsb>30</lsb>
                            <msb>30</msb>
                            <access>read-write</access>
                            <enumeratedValues>
                                </enumeratedValues>
                        </field>
                        <field>
                            <name>PODR15</name>
                            <description>Pmn Output Data</description>
                            <lsb>31</lsb>
                            <msb>31</msb>
                            <access>read-write</access>
                            <enumeratedValues>
                                </enumeratedValues>
                        </field>
                    </fields>
                </register>
                <register>
                    <name>PODR</name>
                    <description>Port Control Register 1</description>
                    <alternateRegister>PCNTR1</alternateRegister>
                    <addressOffset>0x000</addressOffset>
                    <size>16</size>
                    <access>read-write</access>
                    <resetValue>0x0000</resetValue>
                    <resetMask>0xffff</resetMask>
                    <fields>
                        <field>
                            <name>PODR00</name>
                            <description>Pmn Output Data</description>
                            <lsb>0</lsb>
                            <msb>0</msb>
                            <access>read-write</access>
                            <enumeratedValues>
                                </enumeratedValues>
                        </field>
                        <field>
                            <name>PODR01</name>
                            <description>Pmn Output Data</description>
                            <lsb>1</lsb>
                            <msb>1</msb>
                            <access>read-write</access>
                            <enumeratedValues>
                                </enumeratedValues>
                        </field>
                        <field>
                            <name>PODR02</name>
                            <description>Pmn Output Data</description>
                            <lsb>2</lsb>
                            <msb>2</msb>
                            <access>read-write</access>
                            <enumeratedValues>
                                </enumeratedValues>
                        </field>
                        <field>
                            <name>PODR03</name>
                            <description>Pmn Output Data</description>
                            <lsb>3</lsb>
                            <msb>3</msb>
                            <access>read-write</access>
                            <enumeratedValues>
                                </enumeratedValues>
                        </field>
                        <field>
                            <name>PODR04</name>
                            <description>Pmn Output Data</description>
                            <lsb>4</lsb>
                            <msb>4</msb>
                            <access>read-write</access>
                            <enumeratedValues>
                                </enumeratedValues>
                        </field>
                        <field>
                            <name>PODR05</name>
                            <description>Pmn Output Data</description>
                            <lsb>5</lsb>
                            <msb>5</msb>
                            <access>read-write</access>
                            <enumeratedValues>
                                </enumeratedValues>
                        </field>
                        <field>
                            <name>PODR06</name>
                            <description>Pmn Output Data</description>
                            <lsb>6</lsb>
                            <msb>6</msb>
                            <access>read-write</access>
                            <enumeratedValues>
                                </enumeratedValues>
                        </field>
                        <field>
                            <name>PODR07</name>
                            <description>Pmn Output Data</description>
                            <lsb>7</lsb>
                            <msb>7</msb>
                            <access>read-write</access>
                            <enumeratedValues>
                                </enumeratedValues>
                        </field>
                        <field>
                            <name>PODR08</name>
                            <description>Pmn Output Data</description>
                            <lsb>8</lsb>
                            <msb>8</msb>
                            <access>read-write</access>
                            <enumeratedValues>
                                </enumeratedValues>
                        </field>
                        <field>
                            <name>PODR09</name>
                            <description>Pmn Output Data</description>
                            <lsb>9</lsb>
                            <msb>9</msb>
                            <access>read-write</access>
                            <enumeratedValues>
                                </enumeratedValues>
                        </field>
                        <field>
                            <name>PODR10</name>
                            <description>Pmn Output Data</description>
                            <lsb>10</lsb>
                            <msb>10</msb>
                            <access>read-write</access>
                            <enumeratedValues>
                                </enumeratedValues>
                        </field>
                        <field>
                            <name>PODR11</name>
                            <description>Pmn Output Data</description>
                            <lsb>11</lsb>
                            <msb>11</msb>
                            <access>read-write</access>
                            <enumeratedValues>
                                </enumeratedValues>
                        </field>
                        <field>
                            <name>PODR12</name>
                            <description>Pmn Output Data</description>
                            <lsb>12</lsb>
                            <msb>12</msb>
                            <access>read-write</access>
                            <enumeratedValues>
                                </enumeratedValues>
                        </field>
                        <field>
                            <name>PODR13</name>
                            <description>Pmn Output Data</description>
                            <lsb>13</lsb>
                            <msb>13</msb>
                            <access>read-write</access>
                            <enumeratedValues>
                                </enumeratedValues>
                        </field>
                        <field>
                            <name>PODR14</name>
                            <description>Pmn Output Data</description>
                            <lsb>14</lsb>
                            <msb>14</msb>
                            <access>read-write</access>
                            <enumeratedValues>
                                </enumeratedValues>
                        </field>
                        <field>
                            <name>PODR15</name>
                            <description>Pmn Output Data</description>
                            <lsb>15</lsb>
                            <msb>15</msb>
                            <access>read-write</access>
                            <enumeratedValues>
                                </enumeratedValues>
                        </field>
                    </fields>
                </register>
                <register>
                    <name>PDR</name>
                    <description>Port Control Register 1</description>
                    <alternateRegister>PCNTR1</alternateRegister>
                    <addressOffset>0x002</addressOffset>
                    <size>16</size>
                    <access>read-write</access>
                    <resetValue>0x0000</resetValue>
                    <resetMask>0xffff</resetMask>
                    <fields>
                        <field>
                            <name>PDR00</name>
                            <description>Pmn Direction</description>
                            <lsb>0</lsb>
                            <msb>0</msb>
                            <access>read-write</access>
                            <enumeratedValues>
                                </enumeratedValues>
                        </field>
                        <field>
                            <name>PDR01</name>
                            <description>Pmn Direction</description>
                            <lsb>1</lsb>
                            <msb>1</msb>
                            <access>read-write</access>
                            <enumeratedValues>
                                </enumeratedValues>
                        </field>
                        <field>
                            <name>PDR02</name>
                            <description>Pmn Direction</description>
                            <lsb>2</lsb>
                            <msb>2</msb>
                            <access>read-write</access>
                            <enumeratedValues>
                                </enumeratedValues>
                        </field>
                        <field>
                            <name>PDR03</name>
                            <description>Pmn Direction</description>
                            <lsb>3</lsb>
                            <msb>3</msb>
                            <access>read-write</access>
                            <enumeratedValues>
                                </enumeratedValues>
                        </field>
                        <field>
                            <name>PDR04</name>
                            <description>Pmn Direction</description>
                            <lsb>4</lsb>
                            <msb>4</msb>
                            <access>read-write</access>
                            <enumeratedValues>
                                </enumeratedValues>
                        </field>
                        <field>
                            <name>PDR05</name>
                            <description>Pmn Direction</description>
                            <lsb>5</lsb>
                            <msb>5</msb>
                            <access>read-write</access>
                            <enumeratedValues>
                                </enumeratedValues>
                        </field>
                        <field>
                            <name>PDR06</name>
                            <description>Pmn Direction</description>
                            <lsb>6</lsb>
                            <msb>6</msb>
                            <access>read-write</access>
                            <enumeratedValues>
                                </enumeratedValues>
                        </field>
                        <field>
                            <name>PDR07</name>
                            <description>Pmn Direction</description>
                            <lsb>7</lsb>
                            <msb>7</msb>
                            <access>read-write</access>
                            <enumeratedValues>
                                </enumeratedValues>
                        </field>
                        <field>
                            <name>PDR08</name>
                            <description>Pmn Direction</description>
                            <lsb>8</lsb>
                            <msb>8</msb>
                            <access>read-write</access>
                            <enumeratedValues>
                                </enumeratedValues>
                        </field>
                        <field>
                            <name>PDR09</name>
                            <description>Pmn Direction</description>
                            <lsb>9</lsb>
                            <msb>9</msb>
                            <access>read-write</access>
                            <enumeratedValues>
                                </enumeratedValues>
                        </field>
                        <field>
                            <name>PDR10</name>
                            <description>Pmn Direction</description>
                            <lsb>10</lsb>
                            <msb>10</msb>
                            <access>read-write</access>
                            <enumeratedValues>
                                </enumeratedValues>
                        </field>
                        <field>
                            <name>PDR11</name>
                            <description>Pmn Direction</description>
                            <lsb>11</lsb>
                            <msb>11</msb>
                            <access>read-write</access>
                            <enumeratedValues>
                                </enumeratedValues>
                        </field>
                        <field>
                            <name>PDR12</name>
                            <description>Pmn Direction</description>
                            <lsb>12</lsb>
                            <msb>12</msb>
                            <access>read-write</access>
                            <enumeratedValues>
                                </enumeratedValues>
                        </field>
                        <field>
                            <name>PDR13</name>
                            <description>Pmn Direction</description>
                            <lsb>13</lsb>
                            <msb>13</msb>
                            <access>read-write</access>
                            <enumeratedValues>
                                </enumeratedValues>
                        </field>
                        <field>
                            <name>PDR14</name>
                            <description>Pmn Direction</description>
                            <lsb>14</lsb>
                            <msb>14</msb>
                            <access>read-write</access>
                            <enumeratedValues>
                                </enumeratedValues>
                        </field>
                        <field>
                            <name>PDR15</name>
                            <description>Pmn Direction</description>
                            <lsb>15</lsb>
                            <msb>15</msb>
                            <access>read-write</access>
                            <enumeratedValues>
                                </enumeratedValues>
                        </field>
                    </fields>
                </register>
                <register>
                    <name>PCNTR2</name>
                    <description>Port Control Register 2</description>
                    <addressOffset>0x004</addressOffset>
                    <size>32</size>
                    <access>read-only</access>
                    <resetValue>0x00000000</resetValue>
                    <resetMask>0xffff0000</resetMask>
                    <fields>
                        <field>
                            <name>PIDR00</name>
                            <description>Pmn State</description>
                            <lsb>0</lsb>
                            <msb>0</msb>
                            <access>read-only</access>
                            <enumeratedValues>
                                </enumeratedValues>
                        </field>
                        <field>
                            <name>PIDR01</name>
                            <description>Pmn State</description>
                            <lsb>1</lsb>
                            <msb>1</msb>
                            <access>read-only</access>
                            <enumeratedValues>
                                </enumeratedValues>
                        </field>
                        <field>
                            <name>PIDR02</name>
                            <description>Pmn State</description>
                            <lsb>2</lsb>
                            <msb>2</msb>
                            <access>read-only</access>
                            <enumeratedValues>
                                </enumeratedValues>
                        </field>
                        <field>
                            <name>PIDR03</name>
                            <description>Pmn State</description>
                            <lsb>3</lsb>
                            <msb>3</msb>
                            <access>read-only</access>
                            <enumeratedValues>
                                </enumeratedValues>
                        </field>
                        <field>
                            <name>PIDR04</name>
                            <description>Pmn State</description>
                            <lsb>4</lsb>
                            <msb>4</msb>
                            <access>read-only</access>
                            <enumeratedValues>
                                </enumeratedValues>
                        </field>
                        <field>
                            <name>PIDR05</name>
                            <description>Pmn State</description>
                            <lsb>5</lsb>
                            <msb>5</msb>
                            <access>read-only</access>
                            <enumeratedValues>
                                </enumeratedValues>
                        </field>
                        <field>
                            <name>PIDR06</name>
                            <description>Pmn State</description>
                            <lsb>6</lsb>
                            <msb>6</msb>
                            <access>read-only</access>
                            <enumeratedValues>
                                </enumeratedValues>
                        </field>
                        <field>
                            <name>PIDR07</name>
                            <description>Pmn State</description>
                            <lsb>7</lsb>
                            <msb>7</msb>
                            <access>read-only</access>
                            <enumeratedValues>
                                </enumeratedValues>
                        </field>
                        <field>
                            <name>PIDR08</name>
                            <description>Pmn State</description>
                            <lsb>8</lsb>
                            <msb>8</msb>
                            <access>read-only</access>
                            <enumeratedValues>
                                </enumeratedValues>
                        </field>
                        <field>
                            <name>PIDR09</name>
                            <description>Pmn State</description>
                            <lsb>9</lsb>
                            <msb>9</msb>
                            <access>read-only</access>
                            <enumeratedValues>
                                </enumeratedValues>
                        </field>
                        <field>
                            <name>PIDR10</name>
                            <description>Pmn State</description>
                            <lsb>10</lsb>
                            <msb>10</msb>
                            <access>read-only</access>
                            <enumeratedValues>
                                </enumeratedValues>
                        </field>
                        <field>
                            <name>PIDR11</name>
                            <description>Pmn State</description>
                            <lsb>11</lsb>
                            <msb>11</msb>
                            <access>read-only</access>
                            <enumeratedValues>
                                </enumeratedValues>
                        </field>
                        <field>
                            <name>PIDR12</name>
                            <description>Pmn State</description>
                            <lsb>12</lsb>
                            <msb>12</msb>
                            <access>read-only</access>
                            <enumeratedValues>
                                </enumeratedValues>
                        </field>
                        <field>
                            <name>PIDR13</name>
                            <description>Pmn State</description>
                            <lsb>13</lsb>
                            <msb>13</msb>
                            <access>read-only</access>
                            <enumeratedValues>
                                </enumeratedValues>
                        </field>
                        <field>
                            <name>PIDR14</name>
                            <description>Pmn State</description>
                            <lsb>14</lsb>
                            <msb>14</msb>
                            <access>read-only</access>
                            <enumeratedValues>
                                </enumeratedValues>
                        </field>
                        <field>
                            <name>PIDR15</name>
                            <description>Pmn State</description>
                            <lsb>15</lsb>
                            <msb>15</msb>
                            <access>read-only</access>
                            <enumeratedValues>
                                </enumeratedValues>
                        </field>
                    </fields>
                </register>
                <register>
                    <name>PIDR</name>
                    <description>Port Control Register 2</description>
                    <alternateRegister>PCNTR2</alternateRegister>
                    <addressOffset>0x006</addressOffset>
                    <size>16</size>
                    <access>read-only</access>
                    <resetValue>0x0000</resetValue>
                    <resetMask>0x0000</resetMask>
                    <fields>
                        <field>
                            <name>PIDR00</name>
                            <description>Pmn State</description>
                            <lsb>0</lsb>
                            <msb>0</msb>
                            <access>read-only</access>
                            <enumeratedValues>
                                </enumeratedValues>
                        </field>
                        <field>
                            <name>PIDR01</name>
                            <description>Pmn State</description>
                            <lsb>1</lsb>
                            <msb>1</msb>
                            <access>read-only</access>
                            <enumeratedValues>
                                </enumeratedValues>
                        </field>
                        <field>
                            <name>PIDR02</name>
                            <description>Pmn State</description>
                            <lsb>2</lsb>
                            <msb>2</msb>
                            <access>read-only</access>
                            <enumeratedValues>
                                </enumeratedValues>
                        </field>
                        <field>
                            <name>PIDR03</name>
                            <description>Pmn State</description>
                            <lsb>3</lsb>
                            <msb>3</msb>
                            <access>read-only</access>
                            <enumeratedValues>
                                </enumeratedValues>
                        </field>
                        <field>
                            <name>PIDR04</name>
                            <description>Pmn State</description>
                            <lsb>4</lsb>
                            <msb>4</msb>
                            <access>read-only</access>
                            <enumeratedValues>
                                </enumeratedValues>
                        </field>
                        <field>
                            <name>PIDR05</name>
                            <description>Pmn State</description>
                            <lsb>5</lsb>
                            <msb>5</msb>
                            <access>read-only</access>
                            <enumeratedValues>
                                </enumeratedValues>
                        </field>
                        <field>
                            <name>PIDR06</name>
                            <description>Pmn State</description>
                            <lsb>6</lsb>
                            <msb>6</msb>
                            <access>read-only</access>
                            <enumeratedValues>
                                </enumeratedValues>
                        </field>
                        <field>
                            <name>PIDR07</name>
                            <description>Pmn State</description>
                            <lsb>7</lsb>
                            <msb>7</msb>
                            <access>read-only</access>
                            <enumeratedValues>
                                </enumeratedValues>
                        </field>
                        <field>
                            <name>PIDR08</name>
                            <description>Pmn State</description>
                            <lsb>8</lsb>
                            <msb>8</msb>
                            <access>read-only</access>
                            <enumeratedValues>
                                </enumeratedValues>
                        </field>
                        <field>
                            <name>PIDR09</name>
                            <description>Pmn State</description>
                            <lsb>9</lsb>
                            <msb>9</msb>
                            <access>read-only</access>
                            <enumeratedValues>
                                </enumeratedValues>
                        </field>
                        <field>
                            <name>PIDR10</name>
                            <description>Pmn State</description>
                            <lsb>10</lsb>
                            <msb>10</msb>
                            <access>read-only</access>
                            <enumeratedValues>
                                </enumeratedValues>
                        </field>
                        <field>
                            <name>PIDR11</name>
                            <description>Pmn State</description>
                            <lsb>11</lsb>
                            <msb>11</msb>
                            <access>read-only</access>
                            <enumeratedValues>
                                </enumeratedValues>
                        </field>
                        <field>
                            <name>PIDR12</name>
                            <description>Pmn State</description>
                            <lsb>12</lsb>
                            <msb>12</msb>
                            <access>read-only</access>
                            <enumeratedValues>
                                </enumeratedValues>
                        </field>
                        <field>
                            <name>PIDR13</name>
                            <description>Pmn State</description>
                            <lsb>13</lsb>
                            <msb>13</msb>
                            <access>read-only</access>
                            <enumeratedValues>
                                </enumeratedValues>
                        </field>
                        <field>
                            <name>PIDR14</name>
                            <description>Pmn State</description>
                            <lsb>14</lsb>
                            <msb>14</msb>
                            <access>read-only</access>
                            <enumeratedValues>
                                </enumeratedValues>
                        </field>
                        <field>
                            <name>PIDR15</name>
                            <description>Pmn State</description>
                            <lsb>15</lsb>
                            <msb>15</msb>
                            <access>read-only</access>
                            <enumeratedValues>
                                </enumeratedValues>
                        </field>
                    </fields>
                </register>
                <register>
                    <name>PCNTR3</name>
                    <description>Port Control Register 3</description>
                    <addressOffset>0x008</addressOffset>
                    <size>32</size>
                    <access>write-only</access>
                    <resetValue>0x00000000</resetValue>
                    <resetMask>0xffffffff</resetMask>
                    <fields>
                        <field>
                            <name>POSR00</name>
                            <description>Pmn Output Set</description>
                            <lsb>0</lsb>
                            <msb>0</msb>
                            <access>write-only</access>
                            <enumeratedValues>
                                </enumeratedValues>
                        </field>
                        <field>
                            <name>POSR01</name>
                            <description>Pmn Output Set</description>
                            <lsb>1</lsb>
                            <msb>1</msb>
                            <access>write-only</access>
                            <enumeratedValues>
                                </enumeratedValues>
                        </field>
                        <field>
                            <name>POSR02</name>
                            <description>Pmn Output Set</description>
                            <lsb>2</lsb>
                            <msb>2</msb>
                            <access>write-only</access>
                            <enumeratedValues>
                                </enumeratedValues>
                        </field>
                        <field>
                            <name>POSR03</name>
                            <description>Pmn Output Set</description>
                            <lsb>3</lsb>
                            <msb>3</msb>
                            <access>write-only</access>
                            <enumeratedValues>
                                </enumeratedValues>
                        </field>
                        <field>
                            <name>POSR04</name>
                            <description>Pmn Output Set</description>
                            <lsb>4</lsb>
                            <msb>4</msb>
                            <access>write-only</access>
                            <enumeratedValues>
                                </enumeratedValues>
                        </field>
                        <field>
                            <name>POSR05</name>
                            <description>Pmn Output Set</description>
                            <lsb>5</lsb>
                            <msb>5</msb>
                            <access>write-only</access>
                            <enumeratedValues>
                                </enumeratedValues>
                        </field>
                        <field>
                            <name>POSR06</name>
                            <description>Pmn Output Set</description>
                            <lsb>6</lsb>
                            <msb>6</msb>
                            <access>write-only</access>
                            <enumeratedValues>
                                </enumeratedValues>
                        </field>
                        <field>
                            <name>POSR07</name>
                            <description>Pmn Output Set</description>
                            <lsb>7</lsb>
                            <msb>7</msb>
                            <access>write-only</access>
                            <enumeratedValues>
                                </enumeratedValues>
                        </field>
                        <field>
                            <name>POSR08</name>
                            <description>Pmn Output Set</description>
                            <lsb>8</lsb>
                            <msb>8</msb>
                            <access>write-only</access>
                            <enumeratedValues>
                                </enumeratedValues>
                        </field>
                        <field>
                            <name>POSR09</name>
                            <description>Pmn Output Set</description>
                            <lsb>9</lsb>
                            <msb>9</msb>
                            <access>write-only</access>
                            <enumeratedValues>
                                </enumeratedValues>
                        </field>
                        <field>
                            <name>POSR10</name>
                            <description>Pmn Output Set</description>
                            <lsb>10</lsb>
                            <msb>10</msb>
                            <access>write-only</access>
                            <enumeratedValues>
                                </enumeratedValues>
                        </field>
                        <field>
                            <name>POSR11</name>
                            <description>Pmn Output Set</description>
                            <lsb>11</lsb>
                            <msb>11</msb>
                            <access>write-only</access>
                            <enumeratedValues>
                                </enumeratedValues>
                        </field>
                        <field>
                            <name>POSR12</name>
                            <description>Pmn Output Set</description>
                            <lsb>12</lsb>
                            <msb>12</msb>
                            <access>write-only</access>
                            <enumeratedValues>
                                </enumeratedValues>
                        </field>
                        <field>
                            <name>POSR13</name>
                            <description>Pmn Output Set</description>
                            <lsb>13</lsb>
                            <msb>13</msb>
                            <access>write-only</access>
                            <enumeratedValues>
                                </enumeratedValues>
                        </field>
                        <field>
                            <name>POSR14</name>
                            <description>Pmn Output Set</description>
                            <lsb>14</lsb>
                            <msb>14</msb>
                            <access>write-only</access>
                            <enumeratedValues>
                                </enumeratedValues>
                        </field>
                        <field>
                            <name>POSR15</name>
                            <description>Pmn Output Set</description>
                            <lsb>15</lsb>
                            <msb>15</msb>
                            <access>write-only</access>
                            <enumeratedValues>
                                </enumeratedValues>
                        </field>
                        <field>
                            <name>PORR00</name>
                            <description>Pmn Output Reset</description>
                            <lsb>16</lsb>
                            <msb>16</msb>
                            <access>write-only</access>
                            <enumeratedValues>
                                </enumeratedValues>
                        </field>
                        <field>
                            <name>PORR01</name>
                            <description>Pmn Output Reset</description>
                            <lsb>17</lsb>
                            <msb>17</msb>
                            <access>write-only</access>
                            <enumeratedValues>
                                </enumeratedValues>
                        </field>
                        <field>
                            <name>PORR02</name>
                            <description>Pmn Output Reset</description>
                            <lsb>18</lsb>
                            <msb>18</msb>
                            <access>write-only</access>
                            <enumeratedValues>
                                </enumeratedValues>
                        </field>
                        <field>
                            <name>PORR03</name>
                            <description>Pmn Output Reset</description>
                            <lsb>19</lsb>
                            <msb>19</msb>
                            <access>write-only</access>
                            <enumeratedValues>
                                </enumeratedValues>
                        </field>
                        <field>
                            <name>PORR04</name>
                            <description>Pmn Output Reset</description>
                            <lsb>20</lsb>
                            <msb>20</msb>
                            <access>write-only</access>
                            <enumeratedValues>
                                </enumeratedValues>
                        </field>
                        <field>
                            <name>PORR05</name>
                            <description>Pmn Output Reset</description>
                            <lsb>21</lsb>
                            <msb>21</msb>
                            <access>write-only</access>
                            <enumeratedValues>
                                </enumeratedValues>
                        </field>
                        <field>
                            <name>PORR06</name>
                            <description>Pmn Output Reset</description>
                            <lsb>22</lsb>
                            <msb>22</msb>
                            <access>write-only</access>
                            <enumeratedValues>
                                </enumeratedValues>
                        </field>
                        <field>
                            <name>PORR07</name>
                            <description>Pmn Output Reset</description>
                            <lsb>23</lsb>
                            <msb>23</msb>
                            <access>write-only</access>
                            <enumeratedValues>
                                </enumeratedValues>
                        </field>
                        <field>
                            <name>PORR08</name>
                            <description>Pmn Output Reset</description>
                            <lsb>24</lsb>
                            <msb>24</msb>
                            <access>write-only</access>
                            <enumeratedValues>
                                </enumeratedValues>
                        </field>
                        <field>
                            <name>PORR09</name>
                            <description>Pmn Output Reset</description>
                            <lsb>25</lsb>
                            <msb>25</msb>
                            <access>write-only</access>
                            <enumeratedValues>
                                </enumeratedValues>
                        </field>
                        <field>
                            <name>PORR10</name>
                            <description>Pmn Output Reset</description>
                            <lsb>26</lsb>
                            <msb>26</msb>
                            <access>write-only</access>
                            <enumeratedValues>
                                </enumeratedValues>
                        </field>
                        <field>
                            <name>PORR11</name>
                            <description>Pmn Output Reset</description>
                            <lsb>27</lsb>
                            <msb>27</msb>
                            <access>write-only</access>
                            <enumeratedValues>
                                </enumeratedValues>
                        </field>
                        <field>
                            <name>PORR12</name>
                            <description>Pmn Output Reset</description>
                            <lsb>28</lsb>
                            <msb>28</msb>
                            <access>write-only</access>
                            <enumeratedValues>
                                </enumeratedValues>
                        </field>
                        <field>
                            <name>PORR13</name>
                            <description>Pmn Output Reset</description>
                            <lsb>29</lsb>
                            <msb>29</msb>
                            <access>write-only</access>
                            <enumeratedValues>
                                </enumeratedValues>
                        </field>
                        <field>
                            <name>PORR14</name>
                            <description>Pmn Output Reset</description>
                            <lsb>30</lsb>
                            <msb>30</msb>
                            <access>write-only</access>
                            <enumeratedValues>
                                </enumeratedValues>
                        </field>
                        <field>
                            <name>PORR15</name>
                            <description>Pmn Output Reset</description>
                            <lsb>31</lsb>
                            <msb>31</msb>
                            <access>write-only</access>
                            <enumeratedValues>
                                </enumeratedValues>
                        </field>
                    </fields>
                </register>
                <register>
                    <name>PORR</name>
                    <description>Port Control Register 3</description>
                    <alternateRegister>PCNTR3</alternateRegister>
                    <addressOffset>0x008</addressOffset>
                    <size>16</size>
                    <access>write-only</access>
                    <resetValue>0x0000</resetValue>
                    <resetMask>0xffff</resetMask>
                    <fields>
                        <field>
                            <name>PORR00</name>
                            <description>Pmn Output Reset</description>
                            <lsb>0</lsb>
                            <msb>0</msb>
                            <access>write-only</access>
                            <enumeratedValues>
                                </enumeratedValues>
                        </field>
                        <field>
                            <name>PORR01</name>
                            <description>Pmn Output Reset</description>
                            <lsb>1</lsb>
                            <msb>1</msb>
                            <access>write-only</access>
                            <enumeratedValues>
                                </enumeratedValues>
                        </field>
                        <field>
                            <name>PORR02</name>
                            <description>Pmn Output Reset</description>
                            <lsb>2</lsb>
                            <msb>2</msb>
                            <access>write-only</access>
                            <enumeratedValues>
                                </enumeratedValues>
                        </field>
                        <field>
                            <name>PORR03</name>
                            <description>Pmn Output Reset</description>
                            <lsb>3</lsb>
                            <msb>3</msb>
                            <access>write-only</access>
                            <enumeratedValues>
                                </enumeratedValues>
                        </field>
                        <field>
                            <name>PORR04</name>
                            <description>Pmn Output Reset</description>
                            <lsb>4</lsb>
                            <msb>4</msb>
                            <access>write-only</access>
                            <enumeratedValues>
                                </enumeratedValues>
                        </field>
                        <field>
                            <name>PORR05</name>
                            <description>Pmn Output Reset</description>
                            <lsb>5</lsb>
                            <msb>5</msb>
                            <access>write-only</access>
                            <enumeratedValues>
                                </enumeratedValues>
                        </field>
                        <field>
                            <name>PORR06</name>
                            <description>Pmn Output Reset</description>
                            <lsb>6</lsb>
                            <msb>6</msb>
                            <access>write-only</access>
                            <enumeratedValues>
                                </enumeratedValues>
                        </field>
                        <field>
                            <name>PORR07</name>
                            <description>Pmn Output Reset</description>
                            <lsb>7</lsb>
                            <msb>7</msb>
                            <access>write-only</access>
                            <enumeratedValues>
                                </enumeratedValues>
                        </field>
                        <field>
                            <name>PORR08</name>
                            <description>Pmn Output Reset</description>
                            <lsb>8</lsb>
                            <msb>8</msb>
                            <access>write-only</access>
                            <enumeratedValues>
                                </enumeratedValues>
                        </field>
                        <field>
                            <name>PORR09</name>
                            <description>Pmn Output Reset</description>
                            <lsb>9</lsb>
                            <msb>9</msb>
                            <access>write-only</access>
                            <enumeratedValues>
                                </enumeratedValues>
                        </field>
                        <field>
                            <name>PORR10</name>
                            <description>Pmn Output Reset</description>
                            <lsb>10</lsb>
                            <msb>10</msb>
                            <access>write-only</access>
                            <enumeratedValues>
                                </enumeratedValues>
                        </field>
                        <field>
                            <name>PORR11</name>
                            <description>Pmn Output Reset</description>
                            <lsb>11</lsb>
                            <msb>11</msb>
                            <access>write-only</access>
                            <enumeratedValues>
                                </enumeratedValues>
                        </field>
                        <field>
                            <name>PORR12</name>
                            <description>Pmn Output Reset</description>
                            <lsb>12</lsb>
                            <msb>12</msb>
                            <access>write-only</access>
                            <enumeratedValues>
                                </enumeratedValues>
                        </field>
                        <field>
                            <name>PORR13</name>
                            <description>Pmn Output Reset</description>
                            <lsb>13</lsb>
                            <msb>13</msb>
                            <access>write-only</access>
                            <enumeratedValues>
                                </enumeratedValues>
                        </field>
                        <field>
                            <name>PORR14</name>
                            <description>Pmn Output Reset</description>
                            <lsb>14</lsb>
                            <msb>14</msb>
                            <access>write-only</access>
                            <enumeratedValues>
                                </enumeratedValues>
                        </field>
                        <field>
                            <name>PORR15</name>
                            <description>Pmn Output Reset</description>
                            <lsb>15</lsb>
                            <msb>15</msb>
                            <access>write-only</access>
                            <enumeratedValues>
                                </enumeratedValues>
                        </field>
                    </fields>
                </register>
                <register>
                    <name>POSR</name>
                    <description>Port Control Register 3</description>
                    <alternateRegister>PCNTR3</alternateRegister>
                    <addressOffset>0x00A</addressOffset>
                    <size>16</size>
                    <access>write-only</access>
                    <resetValue>0x0000</resetValue>
                    <resetMask>0xffff</resetMask>
                    <fields>
                        <field>
                            <name>POSR00</name>
                            <description>Pmn Output Set</description>
                            <lsb>0</lsb>
                            <msb>0</msb>
                            <access>write-only</access>
                            <enumeratedValues>
                                </enumeratedValues>
                        </field>
                        <field>
                            <name>POSR01</name>
                            <description>Pmn Output Set</description>
                            <lsb>1</lsb>
                            <msb>1</msb>
                            <access>write-only</access>
                            <enumeratedValues>
                                </enumeratedValues>
                        </field>
                        <field>
                            <name>POSR02</name>
                            <description>Pmn Output Set</description>
                            <lsb>2</lsb>
                            <msb>2</msb>
                            <access>write-only</access>
                            <enumeratedValues>
                                </enumeratedValues>
                        </field>
                        <field>
                            <name>POSR03</name>
                            <description>Pmn Output Set</description>
                            <lsb>3</lsb>
                            <msb>3</msb>
                            <access>write-only</access>
                            <enumeratedValues>
                                </enumeratedValues>
                        </field>
                        <field>
                            <name>POSR04</name>
                            <description>Pmn Output Set</description>
                            <lsb>4</lsb>
                            <msb>4</msb>
                            <access>write-only</access>
                            <enumeratedValues>
                                </enumeratedValues>
                        </field>
                        <field>
                            <name>POSR05</name>
                            <description>Pmn Output Set</description>
                            <lsb>5</lsb>
                            <msb>5</msb>
                            <access>write-only</access>
                            <enumeratedValues>
                                </enumeratedValues>
                        </field>
                        <field>
                            <name>POSR06</name>
                            <description>Pmn Output Set</description>
                            <lsb>6</lsb>
                            <msb>6</msb>
                            <access>write-only</access>
                            <enumeratedValues>
                                </enumeratedValues>
                        </field>
                        <field>
                            <name>POSR07</name>
                            <description>Pmn Output Set</description>
                            <lsb>7</lsb>
                            <msb>7</msb>
                            <access>write-only</access>
                            <enumeratedValues>
                                </enumeratedValues>
                        </field>
                        <field>
                            <name>POSR08</name>
                            <description>Pmn Output Set</description>
                            <lsb>8</lsb>
                            <msb>8</msb>
                            <access>write-only</access>
                            <enumeratedValues>
                                </enumeratedValues>
                        </field>
                        <field>
                            <name>POSR09</name>
                            <description>Pmn Output Set</description>
                            <lsb>9</lsb>
                            <msb>9</msb>
                            <access>write-only</access>
                            <enumeratedValues>
                                </enumeratedValues>
                        </field>
                        <field>
                            <name>POSR10</name>
                            <description>Pmn Output Set</description>
                            <lsb>10</lsb>
                            <msb>10</msb>
                            <access>write-only</access>
                            <enumeratedValues>
                                </enumeratedValues>
                        </field>
                        <field>
                            <name>POSR11</name>
                            <description>Pmn Output Set</description>
                            <lsb>11</lsb>
                            <msb>11</msb>
                            <access>write-only</access>
                            <enumeratedValues>
                                </enumeratedValues>
                        </field>
                        <field>
                            <name>POSR12</name>
                            <description>Pmn Output Set</description>
                            <lsb>12</lsb>
                            <msb>12</msb>
                            <access>write-only</access>
                            <enumeratedValues>
                                </enumeratedValues>
                        </field>
                        <field>
                            <name>POSR13</name>
                            <description>Pmn Output Set</description>
                            <lsb>13</lsb>
                            <msb>13</msb>
                            <access>write-only</access>
                            <enumeratedValues>
                                </enumeratedValues>
                        </field>
                        <field>
                            <name>POSR14</name>
                            <description>Pmn Output Set</description>
                            <lsb>14</lsb>
                            <msb>14</msb>
                            <access>write-only</access>
                            <enumeratedValues>
                                </enumeratedValues>
                        </field>
                        <field>
                            <name>POSR15</name>
                            <description>Pmn Output Set</description>
                            <lsb>15</lsb>
                            <msb>15</msb>
                            <access>write-only</access>
                            <enumeratedValues>
                                </enumeratedValues>
                        </field>
                    </fields>
                </register>
            </registers>
        </peripheral>
        <peripheral>
            <name>PORTB</name>
            <description>Pmn Pin FunctionPort B Control RegistersPmn Pin Function Control Register</description>
            <baseAddress>0x40080160</baseAddress>
            <addressBlock>
                <offset>0x00</offset>
                <size>12</size>
                <usage>registers</usage>
            </addressBlock>
            <registers>
                <register>
                    <name>PCNTR1</name>
                    <description>Port Control Register 1</description>
                    <addressOffset>0x000</addressOffset>
                    <size>32</size>
                    <access>read-write</access>
                    <resetValue>0x00000000</resetValue>
                    <resetMask>0xffffffff</resetMask>
                    <fields>
                        <field>
                            <name>PDR00</name>
                            <description>Pmn Direction</description>
                            <lsb>0</lsb>
                            <msb>0</msb>
                            <access>read-write</access>
                            <enumeratedValues>
                                </enumeratedValues>
                        </field>
                        <field>
                            <name>PDR01</name>
                            <description>Pmn Direction</description>
                            <lsb>1</lsb>
                            <msb>1</msb>
                            <access>read-write</access>
                            <enumeratedValues>
                                </enumeratedValues>
                        </field>
                        <field>
                            <name>PDR02</name>
                            <description>Pmn Direction</description>
                            <lsb>2</lsb>
                            <msb>2</msb>
                            <access>read-write</access>
                            <enumeratedValues>
                                </enumeratedValues>
                        </field>
                        <field>
                            <name>PDR03</name>
                            <description>Pmn Direction</description>
                            <lsb>3</lsb>
                            <msb>3</msb>
                            <access>read-write</access>
                            <enumeratedValues>
                                </enumeratedValues>
                        </field>
                        <field>
                            <name>PDR04</name>
                            <description>Pmn Direction</description>
                            <lsb>4</lsb>
                            <msb>4</msb>
                            <access>read-write</access>
                            <enumeratedValues>
                                </enumeratedValues>
                        </field>
                        <field>
                            <name>PDR05</name>
                            <description>Pmn Direction</description>
                            <lsb>5</lsb>
                            <msb>5</msb>
                            <access>read-write</access>
                            <enumeratedValues>
                                </enumeratedValues>
                        </field>
                        <field>
                            <name>PDR06</name>
                            <description>Pmn Direction</description>
                            <lsb>6</lsb>
                            <msb>6</msb>
                            <access>read-write</access>
                            <enumeratedValues>
                                </enumeratedValues>
                        </field>
                        <field>
                            <name>PDR07</name>
                            <description>Pmn Direction</description>
                            <lsb>7</lsb>
                            <msb>7</msb>
                            <access>read-write</access>
                            <enumeratedValues>
                                </enumeratedValues>
                        </field>
                        <field>
                            <name>PDR08</name>
                            <description>Pmn Direction</description>
                            <lsb>8</lsb>
                            <msb>8</msb>
                            <access>read-write</access>
                            <enumeratedValues>
                                </enumeratedValues>
                        </field>
                        <field>
                            <name>PDR09</name>
                            <description>Pmn Direction</description>
                            <lsb>9</lsb>
                            <msb>9</msb>
                            <access>read-write</access>
                            <enumeratedValues>
                                </enumeratedValues>
                        </field>
                        <field>
                            <name>PDR10</name>
                            <description>Pmn Direction</description>
                            <lsb>10</lsb>
                            <msb>10</msb>
                            <access>read-write</access>
                            <enumeratedValues>
                                </enumeratedValues>
                        </field>
                        <field>
                            <name>PDR11</name>
                            <description>Pmn Direction</description>
                            <lsb>11</lsb>
                            <msb>11</msb>
                            <access>read-write</access>
                            <enumeratedValues>
                                </enumeratedValues>
                        </field>
                        <field>
                            <name>PDR12</name>
                            <description>Pmn Direction</description>
                            <lsb>12</lsb>
                            <msb>12</msb>
                            <access>read-write</access>
                            <enumeratedValues>
                                </enumeratedValues>
                        </field>
                        <field>
                            <name>PDR13</name>
                            <description>Pmn Direction</description>
                            <lsb>13</lsb>
                            <msb>13</msb>
                            <access>read-write</access>
                            <enumeratedValues>
                                </enumeratedValues>
                        </field>
                        <field>
                            <name>PDR14</name>
                            <description>Pmn Direction</description>
                            <lsb>14</lsb>
                            <msb>14</msb>
                            <access>read-write</access>
                            <enumeratedValues>
                                </enumeratedValues>
                        </field>
                        <field>
                            <name>PDR15</name>
                            <description>Pmn Direction</description>
                            <lsb>15</lsb>
                            <msb>15</msb>
                            <access>read-write</access>
                            <enumeratedValues>
                                </enumeratedValues>
                        </field>
                        <field>
                            <name>PODR00</name>
                            <description>Pmn Output Data</description>
                            <lsb>16</lsb>
                            <msb>16</msb>
                            <access>read-write</access>
                            <enumeratedValues>
                                </enumeratedValues>
                        </field>
                        <field>
                            <name>PODR01</name>
                            <description>Pmn Output Data</description>
                            <lsb>17</lsb>
                            <msb>17</msb>
                            <access>read-write</access>
                            <enumeratedValues>
                                </enumeratedValues>
                        </field>
                        <field>
                            <name>PODR02</name>
                            <description>Pmn Output Data</description>
                            <lsb>18</lsb>
                            <msb>18</msb>
                            <access>read-write</access>
                            <enumeratedValues>
                                </enumeratedValues>
                        </field>
                        <field>
                            <name>PODR03</name>
                            <description>Pmn Output Data</description>
                            <lsb>19</lsb>
                            <msb>19</msb>
                            <access>read-write</access>
                            <enumeratedValues>
                                </enumeratedValues>
                        </field>
                        <field>
                            <name>PODR04</name>
                            <description>Pmn Output Data</description>
                            <lsb>20</lsb>
                            <msb>20</msb>
                            <access>read-write</access>
                            <enumeratedValues>
                                </enumeratedValues>
                        </field>
                        <field>
                            <name>PODR05</name>
                            <description>Pmn Output Data</description>
                            <lsb>21</lsb>
                            <msb>21</msb>
                            <access>read-write</access>
                            <enumeratedValues>
                                </enumeratedValues>
                        </field>
                        <field>
                            <name>PODR06</name>
                            <description>Pmn Output Data</description>
                            <lsb>22</lsb>
                            <msb>22</msb>
                            <access>read-write</access>
                            <enumeratedValues>
                                </enumeratedValues>
                        </field>
                        <field>
                            <name>PODR07</name>
                            <description>Pmn Output Data</description>
                            <lsb>23</lsb>
                            <msb>23</msb>
                            <access>read-write</access>
                            <enumeratedValues>
                                </enumeratedValues>
                        </field>
                        <field>
                            <name>PODR08</name>
                            <description>Pmn Output Data</description>
                            <lsb>24</lsb>
                            <msb>24</msb>
                            <access>read-write</access>
                            <enumeratedValues>
                                </enumeratedValues>
                        </field>
                        <field>
                            <name>PODR09</name>
                            <description>Pmn Output Data</description>
                            <lsb>25</lsb>
                            <msb>25</msb>
                            <access>read-write</access>
                            <enumeratedValues>
                                </enumeratedValues>
                        </field>
                        <field>
                            <name>PODR10</name>
                            <description>Pmn Output Data</description>
                            <lsb>26</lsb>
                            <msb>26</msb>
                            <access>read-write</access>
                            <enumeratedValues>
                                </enumeratedValues>
                        </field>
                        <field>
                            <name>PODR11</name>
                            <description>Pmn Output Data</description>
                            <lsb>27</lsb>
                            <msb>27</msb>
                            <access>read-write</access>
                            <enumeratedValues>
                                </enumeratedValues>
                        </field>
                        <field>
                            <name>PODR12</name>
                            <description>Pmn Output Data</description>
                            <lsb>28</lsb>
                            <msb>28</msb>
                            <access>read-write</access>
                            <enumeratedValues>
                                </enumeratedValues>
                        </field>
                        <field>
                            <name>PODR13</name>
                            <description>Pmn Output Data</description>
                            <lsb>29</lsb>
                            <msb>29</msb>
                            <access>read-write</access>
                            <enumeratedValues>
                                </enumeratedValues>
                        </field>
                        <field>
                            <name>PODR14</name>
                            <description>Pmn Output Data</description>
                            <lsb>30</lsb>
                            <msb>30</msb>
                            <access>read-write</access>
                            <enumeratedValues>
                                </enumeratedValues>
                        </field>
                        <field>
                            <name>PODR15</name>
                            <description>Pmn Output Data</description>
                            <lsb>31</lsb>
                            <msb>31</msb>
                            <access>read-write</access>
                            <enumeratedValues>
                                </enumeratedValues>
                        </field>
                    </fields>
                </register>
                <register>
                    <name>PODR</name>
                    <description>Port Control Register 1</description>
                    <alternateRegister>PCNTR1</alternateRegister>
                    <addressOffset>0x000</addressOffset>
                    <size>16</size>
                    <access>read-write</access>
                    <resetValue>0x0000</resetValue>
                    <resetMask>0xffff</resetMask>
                    <fields>
                        <field>
                            <name>PODR00</name>
                            <description>Pmn Output Data</description>
                            <lsb>0</lsb>
                            <msb>0</msb>
                            <access>read-write</access>
                            <enumeratedValues>
                                </enumeratedValues>
                        </field>
                        <field>
                            <name>PODR01</name>
                            <description>Pmn Output Data</description>
                            <lsb>1</lsb>
                            <msb>1</msb>
                            <access>read-write</access>
                            <enumeratedValues>
                                </enumeratedValues>
                        </field>
                        <field>
                            <name>PODR02</name>
                            <description>Pmn Output Data</description>
                            <lsb>2</lsb>
                            <msb>2</msb>
                            <access>read-write</access>
                            <enumeratedValues>
                                </enumeratedValues>
                        </field>
                        <field>
                            <name>PODR03</name>
                            <description>Pmn Output Data</description>
                            <lsb>3</lsb>
                            <msb>3</msb>
                            <access>read-write</access>
                            <enumeratedValues>
                                </enumeratedValues>
                        </field>
                        <field>
                            <name>PODR04</name>
                            <description>Pmn Output Data</description>
                            <lsb>4</lsb>
                            <msb>4</msb>
                            <access>read-write</access>
                            <enumeratedValues>
                                </enumeratedValues>
                        </field>
                        <field>
                            <name>PODR05</name>
                            <description>Pmn Output Data</description>
                            <lsb>5</lsb>
                            <msb>5</msb>
                            <access>read-write</access>
                            <enumeratedValues>
                                </enumeratedValues>
                        </field>
                        <field>
                            <name>PODR06</name>
                            <description>Pmn Output Data</description>
                            <lsb>6</lsb>
                            <msb>6</msb>
                            <access>read-write</access>
                            <enumeratedValues>
                                </enumeratedValues>
                        </field>
                        <field>
                            <name>PODR07</name>
                            <description>Pmn Output Data</description>
                            <lsb>7</lsb>
                            <msb>7</msb>
                            <access>read-write</access>
                            <enumeratedValues>
                                </enumeratedValues>
                        </field>
                        <field>
                            <name>PODR08</name>
                            <description>Pmn Output Data</description>
                            <lsb>8</lsb>
                            <msb>8</msb>
                            <access>read-write</access>
                            <enumeratedValues>
                                </enumeratedValues>
                        </field>
                        <field>
                            <name>PODR09</name>
                            <description>Pmn Output Data</description>
                            <lsb>9</lsb>
                            <msb>9</msb>
                            <access>read-write</access>
                            <enumeratedValues>
                                </enumeratedValues>
                        </field>
                        <field>
                            <name>PODR10</name>
                            <description>Pmn Output Data</description>
                            <lsb>10</lsb>
                            <msb>10</msb>
                            <access>read-write</access>
                            <enumeratedValues>
                                </enumeratedValues>
                        </field>
                        <field>
                            <name>PODR11</name>
                            <description>Pmn Output Data</description>
                            <lsb>11</lsb>
                            <msb>11</msb>
                            <access>read-write</access>
                            <enumeratedValues>
                                </enumeratedValues>
                        </field>
                        <field>
                            <name>PODR12</name>
                            <description>Pmn Output Data</description>
                            <lsb>12</lsb>
                            <msb>12</msb>
                            <access>read-write</access>
                            <enumeratedValues>
                                </enumeratedValues>
                        </field>
                        <field>
                            <name>PODR13</name>
                            <description>Pmn Output Data</description>
                            <lsb>13</lsb>
                            <msb>13</msb>
                            <access>read-write</access>
                            <enumeratedValues>
                                </enumeratedValues>
                        </field>
                        <field>
                            <name>PODR14</name>
                            <description>Pmn Output Data</description>
                            <lsb>14</lsb>
                            <msb>14</msb>
                            <access>read-write</access>
                            <enumeratedValues>
                                </enumeratedValues>
                        </field>
                        <field>
                            <name>PODR15</name>
                            <description>Pmn Output Data</description>
                            <lsb>15</lsb>
                            <msb>15</msb>
                            <access>read-write</access>
                            <enumeratedValues>
                                </enumeratedValues>
                        </field>
                    </fields>
                </register>
                <register>
                    <name>PDR</name>
                    <description>Port Control Register 1</description>
                    <alternateRegister>PCNTR1</alternateRegister>
                    <addressOffset>0x002</addressOffset>
                    <size>16</size>
                    <access>read-write</access>
                    <resetValue>0x0000</resetValue>
                    <resetMask>0xffff</resetMask>
                    <fields>
                        <field>
                            <name>PDR00</name>
                            <description>Pmn Direction</description>
                            <lsb>0</lsb>
                            <msb>0</msb>
                            <access>read-write</access>
                            <enumeratedValues>
                                </enumeratedValues>
                        </field>
                        <field>
                            <name>PDR01</name>
                            <description>Pmn Direction</description>
                            <lsb>1</lsb>
                            <msb>1</msb>
                            <access>read-write</access>
                            <enumeratedValues>
                                </enumeratedValues>
                        </field>
                        <field>
                            <name>PDR02</name>
                            <description>Pmn Direction</description>
                            <lsb>2</lsb>
                            <msb>2</msb>
                            <access>read-write</access>
                            <enumeratedValues>
                                </enumeratedValues>
                        </field>
                        <field>
                            <name>PDR03</name>
                            <description>Pmn Direction</description>
                            <lsb>3</lsb>
                            <msb>3</msb>
                            <access>read-write</access>
                            <enumeratedValues>
                                </enumeratedValues>
                        </field>
                        <field>
                            <name>PDR04</name>
                            <description>Pmn Direction</description>
                            <lsb>4</lsb>
                            <msb>4</msb>
                            <access>read-write</access>
                            <enumeratedValues>
                                </enumeratedValues>
                        </field>
                        <field>
                            <name>PDR05</name>
                            <description>Pmn Direction</description>
                            <lsb>5</lsb>
                            <msb>5</msb>
                            <access>read-write</access>
                            <enumeratedValues>
                                </enumeratedValues>
                        </field>
                        <field>
                            <name>PDR06</name>
                            <description>Pmn Direction</description>
                            <lsb>6</lsb>
                            <msb>6</msb>
                            <access>read-write</access>
                            <enumeratedValues>
                                </enumeratedValues>
                        </field>
                        <field>
                            <name>PDR07</name>
                            <description>Pmn Direction</description>
                            <lsb>7</lsb>
                            <msb>7</msb>
                            <access>read-write</access>
                            <enumeratedValues>
                                </enumeratedValues>
                        </field>
                        <field>
                            <name>PDR08</name>
                            <description>Pmn Direction</description>
                            <lsb>8</lsb>
                            <msb>8</msb>
                            <access>read-write</access>
                            <enumeratedValues>
                                </enumeratedValues>
                        </field>
                        <field>
                            <name>PDR09</name>
                            <description>Pmn Direction</description>
                            <lsb>9</lsb>
                            <msb>9</msb>
                            <access>read-write</access>
                            <enumeratedValues>
                                </enumeratedValues>
                        </field>
                        <field>
                            <name>PDR10</name>
                            <description>Pmn Direction</description>
                            <lsb>10</lsb>
                            <msb>10</msb>
                            <access>read-write</access>
                            <enumeratedValues>
                                </enumeratedValues>
                        </field>
                        <field>
                            <name>PDR11</name>
                            <description>Pmn Direction</description>
                            <lsb>11</lsb>
                            <msb>11</msb>
                            <access>read-write</access>
                            <enumeratedValues>
                                </enumeratedValues>
                        </field>
                        <field>
                            <name>PDR12</name>
                            <description>Pmn Direction</description>
                            <lsb>12</lsb>
                            <msb>12</msb>
                            <access>read-write</access>
                            <enumeratedValues>
                                </enumeratedValues>
                        </field>
                        <field>
                            <name>PDR13</name>
                            <description>Pmn Direction</description>
                            <lsb>13</lsb>
                            <msb>13</msb>
                            <access>read-write</access>
                            <enumeratedValues>
                                </enumeratedValues>
                        </field>
                        <field>
                            <name>PDR14</name>
                            <description>Pmn Direction</description>
                            <lsb>14</lsb>
                            <msb>14</msb>
                            <access>read-write</access>
                            <enumeratedValues>
                                </enumeratedValues>
                        </field>
                        <field>
                            <name>PDR15</name>
                            <description>Pmn Direction</description>
                            <lsb>15</lsb>
                            <msb>15</msb>
                            <access>read-write</access>
                            <enumeratedValues>
                                </enumeratedValues>
                        </field>
                    </fields>
                </register>
                <register>
                    <name>PCNTR2</name>
                    <description>Port Control Register 2</description>
                    <addressOffset>0x004</addressOffset>
                    <size>32</size>
                    <access>read-only</access>
                    <resetValue>0x00000000</resetValue>
                    <resetMask>0xffff0000</resetMask>
                    <fields>
                        <field>
                            <name>PIDR00</name>
                            <description>Pmn State</description>
                            <lsb>0</lsb>
                            <msb>0</msb>
                            <access>read-only</access>
                            <enumeratedValues>
                                </enumeratedValues>
                        </field>
                        <field>
                            <name>PIDR01</name>
                            <description>Pmn State</description>
                            <lsb>1</lsb>
                            <msb>1</msb>
                            <access>read-only</access>
                            <enumeratedValues>
                                </enumeratedValues>
                        </field>
                        <field>
                            <name>PIDR02</name>
                            <description>Pmn State</description>
                            <lsb>2</lsb>
                            <msb>2</msb>
                            <access>read-only</access>
                            <enumeratedValues>
                                </enumeratedValues>
                        </field>
                        <field>
                            <name>PIDR03</name>
                            <description>Pmn State</description>
                            <lsb>3</lsb>
                            <msb>3</msb>
                            <access>read-only</access>
                            <enumeratedValues>
                                </enumeratedValues>
                        </field>
                        <field>
                            <name>PIDR04</name>
                            <description>Pmn State</description>
                            <lsb>4</lsb>
                            <msb>4</msb>
                            <access>read-only</access>
                            <enumeratedValues>
                                </enumeratedValues>
                        </field>
                        <field>
                            <name>PIDR05</name>
                            <description>Pmn State</description>
                            <lsb>5</lsb>
                            <msb>5</msb>
                            <access>read-only</access>
                            <enumeratedValues>
                                </enumeratedValues>
                        </field>
                        <field>
                            <name>PIDR06</name>
                            <description>Pmn State</description>
                            <lsb>6</lsb>
                            <msb>6</msb>
                            <access>read-only</access>
                            <enumeratedValues>
                                </enumeratedValues>
                        </field>
                        <field>
                            <name>PIDR07</name>
                            <description>Pmn State</description>
                            <lsb>7</lsb>
                            <msb>7</msb>
                            <access>read-only</access>
                            <enumeratedValues>
                                </enumeratedValues>
                        </field>
                        <field>
                            <name>PIDR08</name>
                            <description>Pmn State</description>
                            <lsb>8</lsb>
                            <msb>8</msb>
                            <access>read-only</access>
                            <enumeratedValues>
                                </enumeratedValues>
                        </field>
                        <field>
                            <name>PIDR09</name>
                            <description>Pmn State</description>
                            <lsb>9</lsb>
                            <msb>9</msb>
                            <access>read-only</access>
                            <enumeratedValues>
                                </enumeratedValues>
                        </field>
                        <field>
                            <name>PIDR10</name>
                            <description>Pmn State</description>
                            <lsb>10</lsb>
                            <msb>10</msb>
                            <access>read-only</access>
                            <enumeratedValues>
                                </enumeratedValues>
                        </field>
                        <field>
                            <name>PIDR11</name>
                            <description>Pmn State</description>
                            <lsb>11</lsb>
                            <msb>11</msb>
                            <access>read-only</access>
                            <enumeratedValues>
                                </enumeratedValues>
                        </field>
                        <field>
                            <name>PIDR12</name>
                            <description>Pmn State</description>
                            <lsb>12</lsb>
                            <msb>12</msb>
                            <access>read-only</access>
                            <enumeratedValues>
                                </enumeratedValues>
                        </field>
                        <field>
                            <name>PIDR13</name>
                            <description>Pmn State</description>
                            <lsb>13</lsb>
                            <msb>13</msb>
                            <access>read-only</access>
                            <enumeratedValues>
                                </enumeratedValues>
                        </field>
                        <field>
                            <name>PIDR14</name>
                            <description>Pmn State</description>
                            <lsb>14</lsb>
                            <msb>14</msb>
                            <access>read-only</access>
                            <enumeratedValues>
                                </enumeratedValues>
                        </field>
                        <field>
                            <name>PIDR15</name>
                            <description>Pmn State</description>
                            <lsb>15</lsb>
                            <msb>15</msb>
                            <access>read-only</access>
                            <enumeratedValues>
                                </enumeratedValues>
                        </field>
                    </fields>
                </register>
                <register>
                    <name>PIDR</name>
                    <description>Port Control Register 2</description>
                    <alternateRegister>PCNTR2</alternateRegister>
                    <addressOffset>0x006</addressOffset>
                    <size>16</size>
                    <access>read-only</access>
                    <resetValue>0x0000</resetValue>
                    <resetMask>0x0000</resetMask>
                    <fields>
                        <field>
                            <name>PIDR00</name>
                            <description>Pmn State</description>
                            <lsb>0</lsb>
                            <msb>0</msb>
                            <access>read-only</access>
                            <enumeratedValues>
                                </enumeratedValues>
                        </field>
                        <field>
                            <name>PIDR01</name>
                            <description>Pmn State</description>
                            <lsb>1</lsb>
                            <msb>1</msb>
                            <access>read-only</access>
                            <enumeratedValues>
                                </enumeratedValues>
                        </field>
                        <field>
                            <name>PIDR02</name>
                            <description>Pmn State</description>
                            <lsb>2</lsb>
                            <msb>2</msb>
                            <access>read-only</access>
                            <enumeratedValues>
                                </enumeratedValues>
                        </field>
                        <field>
                            <name>PIDR03</name>
                            <description>Pmn State</description>
                            <lsb>3</lsb>
                            <msb>3</msb>
                            <access>read-only</access>
                            <enumeratedValues>
                                </enumeratedValues>
                        </field>
                        <field>
                            <name>PIDR04</name>
                            <description>Pmn State</description>
                            <lsb>4</lsb>
                            <msb>4</msb>
                            <access>read-only</access>
                            <enumeratedValues>
                                </enumeratedValues>
                        </field>
                        <field>
                            <name>PIDR05</name>
                            <description>Pmn State</description>
                            <lsb>5</lsb>
                            <msb>5</msb>
                            <access>read-only</access>
                            <enumeratedValues>
                                </enumeratedValues>
                        </field>
                        <field>
                            <name>PIDR06</name>
                            <description>Pmn State</description>
                            <lsb>6</lsb>
                            <msb>6</msb>
                            <access>read-only</access>
                            <enumeratedValues>
                                </enumeratedValues>
                        </field>
                        <field>
                            <name>PIDR07</name>
                            <description>Pmn State</description>
                            <lsb>7</lsb>
                            <msb>7</msb>
                            <access>read-only</access>
                            <enumeratedValues>
                                </enumeratedValues>
                        </field>
                        <field>
                            <name>PIDR08</name>
                            <description>Pmn State</description>
                            <lsb>8</lsb>
                            <msb>8</msb>
                            <access>read-only</access>
                            <enumeratedValues>
                                </enumeratedValues>
                        </field>
                        <field>
                            <name>PIDR09</name>
                            <description>Pmn State</description>
                            <lsb>9</lsb>
                            <msb>9</msb>
                            <access>read-only</access>
                            <enumeratedValues>
                                </enumeratedValues>
                        </field>
                        <field>
                            <name>PIDR10</name>
                            <description>Pmn State</description>
                            <lsb>10</lsb>
                            <msb>10</msb>
                            <access>read-only</access>
                            <enumeratedValues>
                                </enumeratedValues>
                        </field>
                        <field>
                            <name>PIDR11</name>
                            <description>Pmn State</description>
                            <lsb>11</lsb>
                            <msb>11</msb>
                            <access>read-only</access>
                            <enumeratedValues>
                                </enumeratedValues>
                        </field>
                        <field>
                            <name>PIDR12</name>
                            <description>Pmn State</description>
                            <lsb>12</lsb>
                            <msb>12</msb>
                            <access>read-only</access>
                            <enumeratedValues>
                                </enumeratedValues>
                        </field>
                        <field>
                            <name>PIDR13</name>
                            <description>Pmn State</description>
                            <lsb>13</lsb>
                            <msb>13</msb>
                            <access>read-only</access>
                            <enumeratedValues>
                                </enumeratedValues>
                        </field>
                        <field>
                            <name>PIDR14</name>
                            <description>Pmn State</description>
                            <lsb>14</lsb>
                            <msb>14</msb>
                            <access>read-only</access>
                            <enumeratedValues>
                                </enumeratedValues>
                        </field>
                        <field>
                            <name>PIDR15</name>
                            <description>Pmn State</description>
                            <lsb>15</lsb>
                            <msb>15</msb>
                            <access>read-only</access>
                            <enumeratedValues>
                                </enumeratedValues>
                        </field>
                    </fields>
                </register>
                <register>
                    <name>PCNTR3</name>
                    <description>Port Control Register 3</description>
                    <addressOffset>0x008</addressOffset>
                    <size>32</size>
                    <access>write-only</access>
                    <resetValue>0x00000000</resetValue>
                    <resetMask>0xffffffff</resetMask>
                    <fields>
                        <field>
                            <name>POSR00</name>
                            <description>Pmn Output Set</description>
                            <lsb>0</lsb>
                            <msb>0</msb>
                            <access>write-only</access>
                            <enumeratedValues>
                                </enumeratedValues>
                        </field>
                        <field>
                            <name>POSR01</name>
                            <description>Pmn Output Set</description>
                            <lsb>1</lsb>
                            <msb>1</msb>
                            <access>write-only</access>
                            <enumeratedValues>
                                </enumeratedValues>
                        </field>
                        <field>
                            <name>POSR02</name>
                            <description>Pmn Output Set</description>
                            <lsb>2</lsb>
                            <msb>2</msb>
                            <access>write-only</access>
                            <enumeratedValues>
                                </enumeratedValues>
                        </field>
                        <field>
                            <name>POSR03</name>
                            <description>Pmn Output Set</description>
                            <lsb>3</lsb>
                            <msb>3</msb>
                            <access>write-only</access>
                            <enumeratedValues>
                                </enumeratedValues>
                        </field>
                        <field>
                            <name>POSR04</name>
                            <description>Pmn Output Set</description>
                            <lsb>4</lsb>
                            <msb>4</msb>
                            <access>write-only</access>
                            <enumeratedValues>
                                </enumeratedValues>
                        </field>
                        <field>
                            <name>POSR05</name>
                            <description>Pmn Output Set</description>
                            <lsb>5</lsb>
                            <msb>5</msb>
                            <access>write-only</access>
                            <enumeratedValues>
                                </enumeratedValues>
                        </field>
                        <field>
                            <name>POSR06</name>
                            <description>Pmn Output Set</description>
                            <lsb>6</lsb>
                            <msb>6</msb>
                            <access>write-only</access>
                            <enumeratedValues>
                                </enumeratedValues>
                        </field>
                        <field>
                            <name>POSR07</name>
                            <description>Pmn Output Set</description>
                            <lsb>7</lsb>
                            <msb>7</msb>
                            <access>write-only</access>
                            <enumeratedValues>
                                </enumeratedValues>
                        </field>
                        <field>
                            <name>POSR08</name>
                            <description>Pmn Output Set</description>
                            <lsb>8</lsb>
                            <msb>8</msb>
                            <access>write-only</access>
                            <enumeratedValues>
                                </enumeratedValues>
                        </field>
                        <field>
                            <name>POSR09</name>
                            <description>Pmn Output Set</description>
                            <lsb>9</lsb>
                            <msb>9</msb>
                            <access>write-only</access>
                            <enumeratedValues>
                                </enumeratedValues>
                        </field>
                        <field>
                            <name>POSR10</name>
                            <description>Pmn Output Set</description>
                            <lsb>10</lsb>
                            <msb>10</msb>
                            <access>write-only</access>
                            <enumeratedValues>
                                </enumeratedValues>
                        </field>
                        <field>
                            <name>POSR11</name>
                            <description>Pmn Output Set</description>
                            <lsb>11</lsb>
                            <msb>11</msb>
                            <access>write-only</access>
                            <enumeratedValues>
                                </enumeratedValues>
                        </field>
                        <field>
                            <name>POSR12</name>
                            <description>Pmn Output Set</description>
                            <lsb>12</lsb>
                            <msb>12</msb>
                            <access>write-only</access>
                            <enumeratedValues>
                                </enumeratedValues>
                        </field>
                        <field>
                            <name>POSR13</name>
                            <description>Pmn Output Set</description>
                            <lsb>13</lsb>
                            <msb>13</msb>
                            <access>write-only</access>
                            <enumeratedValues>
                                </enumeratedValues>
                        </field>
                        <field>
                            <name>POSR14</name>
                            <description>Pmn Output Set</description>
                            <lsb>14</lsb>
                            <msb>14</msb>
                            <access>write-only</access>
                            <enumeratedValues>
                                </enumeratedValues>
                        </field>
                        <field>
                            <name>POSR15</name>
                            <description>Pmn Output Set</description>
                            <lsb>15</lsb>
                            <msb>15</msb>
                            <access>write-only</access>
                            <enumeratedValues>
                                </enumeratedValues>
                        </field>
                        <field>
                            <name>PORR00</name>
                            <description>Pmn Output Reset</description>
                            <lsb>16</lsb>
                            <msb>16</msb>
                            <access>write-only</access>
                            <enumeratedValues>
                                </enumeratedValues>
                        </field>
                        <field>
                            <name>PORR01</name>
                            <description>Pmn Output Reset</description>
                            <lsb>17</lsb>
                            <msb>17</msb>
                            <access>write-only</access>
                            <enumeratedValues>
                                </enumeratedValues>
                        </field>
                        <field>
                            <name>PORR02</name>
                            <description>Pmn Output Reset</description>
                            <lsb>18</lsb>
                            <msb>18</msb>
                            <access>write-only</access>
                            <enumeratedValues>
                                </enumeratedValues>
                        </field>
                        <field>
                            <name>PORR03</name>
                            <description>Pmn Output Reset</description>
                            <lsb>19</lsb>
                            <msb>19</msb>
                            <access>write-only</access>
                            <enumeratedValues>
                                </enumeratedValues>
                        </field>
                        <field>
                            <name>PORR04</name>
                            <description>Pmn Output Reset</description>
                            <lsb>20</lsb>
                            <msb>20</msb>
                            <access>write-only</access>
                            <enumeratedValues>
                                </enumeratedValues>
                        </field>
                        <field>
                            <name>PORR05</name>
                            <description>Pmn Output Reset</description>
                            <lsb>21</lsb>
                            <msb>21</msb>
                            <access>write-only</access>
                            <enumeratedValues>
                                </enumeratedValues>
                        </field>
                        <field>
                            <name>PORR06</name>
                            <description>Pmn Output Reset</description>
                            <lsb>22</lsb>
                            <msb>22</msb>
                            <access>write-only</access>
                            <enumeratedValues>
                                </enumeratedValues>
                        </field>
                        <field>
                            <name>PORR07</name>
                            <description>Pmn Output Reset</description>
                            <lsb>23</lsb>
                            <msb>23</msb>
                            <access>write-only</access>
                            <enumeratedValues>
                                </enumeratedValues>
                        </field>
                        <field>
                            <name>PORR08</name>
                            <description>Pmn Output Reset</description>
                            <lsb>24</lsb>
                            <msb>24</msb>
                            <access>write-only</access>
                            <enumeratedValues>
                                </enumeratedValues>
                        </field>
                        <field>
                            <name>PORR09</name>
                            <description>Pmn Output Reset</description>
                            <lsb>25</lsb>
                            <msb>25</msb>
                            <access>write-only</access>
                            <enumeratedValues>
                                </enumeratedValues>
                        </field>
                        <field>
                            <name>PORR10</name>
                            <description>Pmn Output Reset</description>
                            <lsb>26</lsb>
                            <msb>26</msb>
                            <access>write-only</access>
                            <enumeratedValues>
                                </enumeratedValues>
                        </field>
                        <field>
                            <name>PORR11</name>
                            <description>Pmn Output Reset</description>
                            <lsb>27</lsb>
                            <msb>27</msb>
                            <access>write-only</access>
                            <enumeratedValues>
                                </enumeratedValues>
                        </field>
                        <field>
                            <name>PORR12</name>
                            <description>Pmn Output Reset</description>
                            <lsb>28</lsb>
                            <msb>28</msb>
                            <access>write-only</access>
                            <enumeratedValues>
                                </enumeratedValues>
                        </field>
                        <field>
                            <name>PORR13</name>
                            <description>Pmn Output Reset</description>
                            <lsb>29</lsb>
                            <msb>29</msb>
                            <access>write-only</access>
                            <enumeratedValues>
                                </enumeratedValues>
                        </field>
                        <field>
                            <name>PORR14</name>
                            <description>Pmn Output Reset</description>
                            <lsb>30</lsb>
                            <msb>30</msb>
                            <access>write-only</access>
                            <enumeratedValues>
                                </enumeratedValues>
                        </field>
                        <field>
                            <name>PORR15</name>
                            <description>Pmn Output Reset</description>
                            <lsb>31</lsb>
                            <msb>31</msb>
                            <access>write-only</access>
                            <enumeratedValues>
                                </enumeratedValues>
                        </field>
                    </fields>
                </register>
                <register>
                    <name>PORR</name>
                    <description>Port Control Register 3</description>
                    <alternateRegister>PCNTR3</alternateRegister>
                    <addressOffset>0x008</addressOffset>
                    <size>16</size>
                    <access>write-only</access>
                    <resetValue>0x0000</resetValue>
                    <resetMask>0xffff</resetMask>
                    <fields>
                        <field>
                            <name>PORR00</name>
                            <description>Pmn Output Reset</description>
                            <lsb>0</lsb>
                            <msb>0</msb>
                            <access>write-only</access>
                            <enumeratedValues>
                                </enumeratedValues>
                        </field>
                        <field>
                            <name>PORR01</name>
                            <description>Pmn Output Reset</description>
                            <lsb>1</lsb>
                            <msb>1</msb>
                            <access>write-only</access>
                            <enumeratedValues>
                                </enumeratedValues>
                        </field>
                        <field>
                            <name>PORR02</name>
                            <description>Pmn Output Reset</description>
                            <lsb>2</lsb>
                            <msb>2</msb>
                            <access>write-only</access>
                            <enumeratedValues>
                                </enumeratedValues>
                        </field>
                        <field>
                            <name>PORR03</name>
                            <description>Pmn Output Reset</description>
                            <lsb>3</lsb>
                            <msb>3</msb>
                            <access>write-only</access>
                            <enumeratedValues>
                                </enumeratedValues>
                        </field>
                        <field>
                            <name>PORR04</name>
                            <description>Pmn Output Reset</description>
                            <lsb>4</lsb>
                            <msb>4</msb>
                            <access>write-only</access>
                            <enumeratedValues>
                                </enumeratedValues>
                        </field>
                        <field>
                            <name>PORR05</name>
                            <description>Pmn Output Reset</description>
                            <lsb>5</lsb>
                            <msb>5</msb>
                            <access>write-only</access>
                            <enumeratedValues>
                                </enumeratedValues>
                        </field>
                        <field>
                            <name>PORR06</name>
                            <description>Pmn Output Reset</description>
                            <lsb>6</lsb>
                            <msb>6</msb>
                            <access>write-only</access>
                            <enumeratedValues>
                                </enumeratedValues>
                        </field>
                        <field>
                            <name>PORR07</name>
                            <description>Pmn Output Reset</description>
                            <lsb>7</lsb>
                            <msb>7</msb>
                            <access>write-only</access>
                            <enumeratedValues>
                                </enumeratedValues>
                        </field>
                        <field>
                            <name>PORR08</name>
                            <description>Pmn Output Reset</description>
                            <lsb>8</lsb>
                            <msb>8</msb>
                            <access>write-only</access>
                            <enumeratedValues>
                                </enumeratedValues>
                        </field>
                        <field>
                            <name>PORR09</name>
                            <description>Pmn Output Reset</description>
                            <lsb>9</lsb>
                            <msb>9</msb>
                            <access>write-only</access>
                            <enumeratedValues>
                                </enumeratedValues>
                        </field>
                        <field>
                            <name>PORR10</name>
                            <description>Pmn Output Reset</description>
                            <lsb>10</lsb>
                            <msb>10</msb>
                            <access>write-only</access>
                            <enumeratedValues>
                                </enumeratedValues>
                        </field>
                        <field>
                            <name>PORR11</name>
                            <description>Pmn Output Reset</description>
                            <lsb>11</lsb>
                            <msb>11</msb>
                            <access>write-only</access>
                            <enumeratedValues>
                                </enumeratedValues>
                        </field>
                        <field>
                            <name>PORR12</name>
                            <description>Pmn Output Reset</description>
                            <lsb>12</lsb>
                            <msb>12</msb>
                            <access>write-only</access>
                            <enumeratedValues>
                                </enumeratedValues>
                        </field>
                        <field>
                            <name>PORR13</name>
                            <description>Pmn Output Reset</description>
                            <lsb>13</lsb>
                            <msb>13</msb>
                            <access>write-only</access>
                            <enumeratedValues>
                                </enumeratedValues>
                        </field>
                        <field>
                            <name>PORR14</name>
                            <description>Pmn Output Reset</description>
                            <lsb>14</lsb>
                            <msb>14</msb>
                            <access>write-only</access>
                            <enumeratedValues>
                                </enumeratedValues>
                        </field>
                        <field>
                            <name>PORR15</name>
                            <description>Pmn Output Reset</description>
                            <lsb>15</lsb>
                            <msb>15</msb>
                            <access>write-only</access>
                            <enumeratedValues>
                                </enumeratedValues>
                        </field>
                    </fields>
                </register>
                <register>
                    <name>POSR</name>
                    <description>Port Control Register 3</description>
                    <alternateRegister>PCNTR3</alternateRegister>
                    <addressOffset>0x00A</addressOffset>
                    <size>16</size>
                    <access>write-only</access>
                    <resetValue>0x0000</resetValue>
                    <resetMask>0xffff</resetMask>
                    <fields>
                        <field>
                            <name>POSR00</name>
                            <description>Pmn Output Set</description>
                            <lsb>0</lsb>
                            <msb>0</msb>
                            <access>write-only</access>
                            <enumeratedValues>
                                </enumeratedValues>
                        </field>
                        <field>
                            <name>POSR01</name>
                            <description>Pmn Output Set</description>
                            <lsb>1</lsb>
                            <msb>1</msb>
                            <access>write-only</access>
                            <enumeratedValues>
                                </enumeratedValues>
                        </field>
                        <field>
                            <name>POSR02</name>
                            <description>Pmn Output Set</description>
                            <lsb>2</lsb>
                            <msb>2</msb>
                            <access>write-only</access>
                            <enumeratedValues>
                                </enumeratedValues>
                        </field>
                        <field>
                            <name>POSR03</name>
                            <description>Pmn Output Set</description>
                            <lsb>3</lsb>
                            <msb>3</msb>
                            <access>write-only</access>
                            <enumeratedValues>
                                </enumeratedValues>
                        </field>
                        <field>
                            <name>POSR04</name>
                            <description>Pmn Output Set</description>
                            <lsb>4</lsb>
                            <msb>4</msb>
                            <access>write-only</access>
                            <enumeratedValues>
                                </enumeratedValues>
                        </field>
                        <field>
                            <name>POSR05</name>
                            <description>Pmn Output Set</description>
                            <lsb>5</lsb>
                            <msb>5</msb>
                            <access>write-only</access>
                            <enumeratedValues>
                                </enumeratedValues>
                        </field>
                        <field>
                            <name>POSR06</name>
                            <description>Pmn Output Set</description>
                            <lsb>6</lsb>
                            <msb>6</msb>
                            <access>write-only</access>
                            <enumeratedValues>
                                </enumeratedValues>
                        </field>
                        <field>
                            <name>POSR07</name>
                            <description>Pmn Output Set</description>
                            <lsb>7</lsb>
                            <msb>7</msb>
                            <access>write-only</access>
                            <enumeratedValues>
                                </enumeratedValues>
                        </field>
                        <field>
                            <name>POSR08</name>
                            <description>Pmn Output Set</description>
                            <lsb>8</lsb>
                            <msb>8</msb>
                            <access>write-only</access>
                            <enumeratedValues>
                                </enumeratedValues>
                        </field>
                        <field>
                            <name>POSR09</name>
                            <description>Pmn Output Set</description>
                            <lsb>9</lsb>
                            <msb>9</msb>
                            <access>write-only</access>
                            <enumeratedValues>
                                </enumeratedValues>
                        </field>
                        <field>
                            <name>POSR10</name>
                            <description>Pmn Output Set</description>
                            <lsb>10</lsb>
                            <msb>10</msb>
                            <access>write-only</access>
                            <enumeratedValues>
                                </enumeratedValues>
                        </field>
                        <field>
                            <name>POSR11</name>
                            <description>Pmn Output Set</description>
                            <lsb>11</lsb>
                            <msb>11</msb>
                            <access>write-only</access>
                            <enumeratedValues>
                                </enumeratedValues>
                        </field>
                        <field>
                            <name>POSR12</name>
                            <description>Pmn Output Set</description>
                            <lsb>12</lsb>
                            <msb>12</msb>
                            <access>write-only</access>
                            <enumeratedValues>
                                </enumeratedValues>
                        </field>
                        <field>
                            <name>POSR13</name>
                            <description>Pmn Output Set</description>
                            <lsb>13</lsb>
                            <msb>13</msb>
                            <access>write-only</access>
                            <enumeratedValues>
                                </enumeratedValues>
                        </field>
                        <field>
                            <name>POSR14</name>
                            <description>Pmn Output Set</description>
                            <lsb>14</lsb>
                            <msb>14</msb>
                            <access>write-only</access>
                            <enumeratedValues>
                                </enumeratedValues>
                        </field>
                        <field>
                            <name>POSR15</name>
                            <description>Pmn Output Set</description>
                            <lsb>15</lsb>
                            <msb>15</msb>
                            <access>write-only</access>
                            <enumeratedValues>
                                </enumeratedValues>
                        </field>
                    </fields>
                </register>
            </registers>
        </peripheral>
        <peripheral>
            <name>PFS</name>
            <description>Control Register</description>
            <baseAddress>0x40080800</baseAddress>
            <addressBlock>
                <offset>0x00</offset>
                <size>44</size>
                <usage>registers</usage>
            </addressBlock>
            <addressBlock>
                <offset>0x38</offset>
                <size>135</size>
                <usage>registers</usage>
            </addressBlock>
            <addressBlock>
                <offset>0xC0</offset>
                <size>167</size>
                <usage>registers</usage>
            </addressBlock>
            <addressBlock>
                <offset>0x16C</offset>
                <size>15</size>
                <usage>registers</usage>
            </addressBlock>
            <addressBlock>
                <offset>0x180</offset>
                <size>123</size>
                <usage>registers</usage>
            </addressBlock>
            <addressBlock>
                <offset>0x200</offset>
                <size>31</size>
                <usage>registers</usage>
            </addressBlock>
            <addressBlock>
                <offset>0x240</offset>
                <size>11</size>
                <usage>registers</usage>
            </addressBlock>
            <addressBlock>
                <offset>0x254</offset>
                <size>19</size>
                <usage>registers</usage>
            </addressBlock>
            <addressBlock>
                <offset>0x280</offset>
                <size>11</size>
                <usage>registers</usage>
            </addressBlock>
            <addressBlock>
                <offset>0x2A0</offset>
                <size>12</size>
                <usage>registers</usage>
            </addressBlock>
            <addressBlock>
                <offset>0x2C0</offset>
                <size>11</size>
                <usage>registers</usage>
            </addressBlock>
            <addressBlock>
                <offset>0x500</offset>
                <size>1</size>
                <usage>registers</usage>
            </addressBlock>
            <addressBlock>
                <offset>0x503</offset>
                <size>1</size>
                <usage>registers</usage>
            </addressBlock>
            <addressBlock>
                <offset>0x505</offset>
                <size>1</size>
                <usage>registers</usage>
            </addressBlock>
            <addressBlock>
                <offset>0x510</offset>
                <size>24</size>
                <usage>registers</usage>
            </addressBlock>
            <registers>
                <register>
                    <dim>8</dim>
                    <dimIncrement>0x4</dimIncrement>
                    <dimIndex>0-7</dimIndex>
                    <name>P00%sPFS</name>
                    <description>Port 00%s Pin Function Select Register</description>
                    <addressOffset>0x000</addressOffset>
                    <size>32</size>
                    <access>read-write</access>
                    <resetValue>0x00000000</resetValue>
                    <resetMask>0xfffffffd</resetMask>
                    <fields>
                        <field>
                            <name>PODR</name>
                            <description>Port Output Data</description>
                            <lsb>0</lsb>
                            <msb>0</msb>
                            <access>read-write</access>
                            <enumeratedValues>
                                </enumeratedValues>
                        </field>
                        <field>
                            <name>PIDR</name>
                            <description>Port State</description>
                            <lsb>1</lsb>
                            <msb>1</msb>
                            <access>read-only</access>
                            <enumeratedValues>
                                </enumeratedValues>
                        </field>
                        <field>
                            <name>PDR</name>
                            <description>Port Direction</description>
                            <lsb>2</lsb>
                            <msb>2</msb>
                            <access>read-write</access>
                            <enumeratedValues>
                                </enumeratedValues>
                        </field>
                        <field>
                            <name>PCR</name>
                            <description>Pull,up Control</description>
                            <lsb>4</lsb>
                            <msb>4</msb>
                            <access>read-write</access>
                            <enumeratedValues>
                                </enumeratedValues>
                        </field>
                        <field>
                            <name>NCODR</name>
                            <description>N,Channel Open,Drain Control</description>
                            <lsb>6</lsb>
                            <msb>6</msb>
                            <access>read-write</access>
                            <enumeratedValues>
                                </enumeratedValues>
                        </field>
                        <field>
                            <name>ISEL</name>
                            <description>IRQ Input Enable</description>
                            <lsb>14</lsb>
                            <msb>14</msb>
                            <access>read-write</access>
                            <enumeratedValues>
                                </enumeratedValues>
                        </field>
                        <field>
                            <name>ASEL</name>
                            <description>Analog Input Enable</description>
                            <lsb>15</lsb>
                            <msb>15</msb>
                            <access>read-write</access>
                            <enumeratedValues>
                                </enumeratedValues>
                        </field>
                        <field>
                            <name>PMR</name>
                            <description>Port Mode Control</description>
                            <lsb>16</lsb>
                            <msb>16</msb>
                            <access>read-write</access>
                            <enumeratedValues>
                                </enumeratedValues>
                        </field>
                        <field>
                            <name>PSEL</name>
                            <description>Peripheral Select</description>
                            <lsb>24</lsb>
                            <msb>28</msb>
                            <access>read-write</access>
                        </field>
                    </fields>
                </register>
                <register>
                    <dim>8</dim>
                    <dimIncrement>0x4</dimIncrement>
                    <dimIndex>0-7</dimIndex>
                    <name>P00%sPFS_HA</name>
                    <description>Port 00%s Pin Function Select Register</description>
                    <alternateRegister>P00%sPFS</alternateRegister>
                    <addressOffset>0x002</addressOffset>
                    <size>16</size>
                    <access>read-write</access>
                    <resetValue>0x0000</resetValue>
                    <resetMask>0xfffd</resetMask>
                    <fields>
                        <field>
                            <name>PODR</name>
                            <description>Port Output Data</description>
                            <lsb>0</lsb>
                            <msb>0</msb>
                            <access>read-write</access>
                            <enumeratedValues>
                                </enumeratedValues>
                        </field>
                        <field>
                            <name>PIDR</name>
                            <description>Port State</description>
                            <lsb>1</lsb>
                            <msb>1</msb>
                            <access>read-only</access>
                            <enumeratedValues>
                                </enumeratedValues>
                        </field>
                        <field>
                            <name>PDR</name>
                            <description>Port Direction</description>
                            <lsb>2</lsb>
                            <msb>2</msb>
                            <access>read-write</access>
                            <enumeratedValues>
                                </enumeratedValues>
                        </field>
                        <field>
                            <name>PCR</name>
                            <description>Pull,up Control</description>
                            <lsb>4</lsb>
                            <msb>4</msb>
                            <access>read-write</access>
                            <enumeratedValues>
                                </enumeratedValues>
                        </field>
                        <field>
                            <name>NCODR</name>
                            <description>N,Channel Open,Drain Control</description>
                            <lsb>6</lsb>
                            <msb>6</msb>
                            <access>read-write</access>
                            <enumeratedValues>
                                </enumeratedValues>
                        </field>
                        <field>
                            <name>ISEL</name>
                            <description>IRQ Input Enable</description>
                            <lsb>14</lsb>
                            <msb>14</msb>
                            <access>read-write</access>
                            <enumeratedValues>
                                </enumeratedValues>
                        </field>
                        <field>
                            <name>ASEL</name>
                            <description>Analog Input Enable</description>
                            <lsb>15</lsb>
                            <msb>15</msb>
                            <access>read-write</access>
                            <enumeratedValues>
                                </enumeratedValues>
                        </field>
                    </fields>
                </register>
                <register>
                    <dim>8</dim>
                    <dimIncrement>0x4</dimIncrement>
                    <dimIndex>0-7</dimIndex>
                    <name>P00%sPFS_BY</name>
                    <description>Port 00%s Pin Function Select Register</description>
                    <alternateRegister>P00%sPFS</alternateRegister>
                    <addressOffset>0x003</addressOffset>
                    <size>8</size>
                    <access>read-write</access>
                    <resetValue>0x00</resetValue>
                    <resetMask>0xfd</resetMask>
                    <fields>
                        <field>
                            <name>PODR</name>
                            <description>Port Output Data</description>
                            <lsb>0</lsb>
                            <msb>0</msb>
                            <access>read-write</access>
                            <enumeratedValues>
                                </enumeratedValues>
                        </field>
                        <field>
                            <name>PIDR</name>
                            <description>Port State</description>
                            <lsb>1</lsb>
                            <msb>1</msb>
                            <access>read-only</access>
                            <enumeratedValues>
                                </enumeratedValues>
                        </field>
                        <field>
                            <name>PDR</name>
                            <description>Port Direction</description>
                            <lsb>2</lsb>
                            <msb>2</msb>
                            <access>read-write</access>
                            <enumeratedValues>
                                </enumeratedValues>
                        </field>
                        <field>
                            <name>PCR</name>
                            <description>Pull,up Control</description>
                            <lsb>4</lsb>
                            <msb>4</msb>
                            <access>read-write</access>
                            <enumeratedValues>
                                </enumeratedValues>
                        </field>
                        <field>
                            <name>NCODR</name>
                            <description>N,Channel Open,Drain Control</description>
                            <lsb>6</lsb>
                            <msb>6</msb>
                            <access>read-write</access>
                            <enumeratedValues>
                                </enumeratedValues>
                        </field>
                    </fields>
                </register>
                <register>
                    <name>P008PFS</name>
                    <description>Port 008 Pin Function Select Register</description>
                    <addressOffset>0x020</addressOffset>
                    <size>32</size>
                    <access>read-write</access>
                    <resetValue>0x00010410</resetValue>
                    <resetMask>0xfffffffd</resetMask>
                    <fields>
                        <field>
                            <name>PODR</name>
                            <description>Port Output Data</description>
                            <lsb>0</lsb>
                            <msb>0</msb>
                            <access>read-write</access>
                            <enumeratedValues>
                                </enumeratedValues>
                        </field>
                        <field>
                            <name>PIDR</name>
                            <description>Port State</description>
                            <lsb>1</lsb>
                            <msb>1</msb>
                            <access>read-only</access>
                            <enumeratedValues>
                                </enumeratedValues>
                        </field>
                        <field>
                            <name>PDR</name>
                            <description>Port Direction</description>
                            <lsb>2</lsb>
                            <msb>2</msb>
                            <access>read-write</access>
                            <enumeratedValues>
                                </enumeratedValues>
                        </field>
                        <field>
                            <name>PCR</name>
                            <description>Pull,up Control</description>
                            <lsb>4</lsb>
                            <msb>4</msb>
                            <access>read-write</access>
                            <enumeratedValues>
                                </enumeratedValues>
                        </field>
                        <field>
                            <name>NCODR</name>
                            <description>N,Channel Open,Drain Control</description>
                            <lsb>6</lsb>
                            <msb>6</msb>
                            <access>read-write</access>
                            <enumeratedValues>
                                </enumeratedValues>
                        </field>
                        <field>
                            <name>ISEL</name>
                            <description>IRQ Input Enable</description>
                            <lsb>14</lsb>
                            <msb>14</msb>
                            <access>read-write</access>
                            <enumeratedValues>
                                </enumeratedValues>
                        </field>
                        <field>
                            <name>ASEL</name>
                            <description>Analog Input Enable</description>
                            <lsb>15</lsb>
                            <msb>15</msb>
                            <access>read-write</access>
                            <enumeratedValues>
                                </enumeratedValues>
                        </field>
                        <field>
                            <name>PMR</name>
                            <description>Port Mode Control</description>
                            <lsb>16</lsb>
                            <msb>16</msb>
                            <access>read-write</access>
                            <enumeratedValues>
                                </enumeratedValues>
                        </field>
                        <field>
                            <name>PSEL</name>
                            <description>Peripheral Select</description>
                            <lsb>24</lsb>
                            <msb>28</msb>
                            <access>read-write</access>
                        </field>
                    </fields>
                </register>
                <register>
                    <name>P008PFS_HA</name>
                    <description>Port 008 Pin Function Select Register</description>
                    <alternateRegister>P008PFS</alternateRegister>
                    <addressOffset>0x022</addressOffset>
                    <size>16</size>
                    <access>read-write</access>
                    <resetValue>0x0410</resetValue>
                    <resetMask>0xfffd</resetMask>
                    <fields>
                        <field>
                            <name>PODR</name>
                            <description>Port Output Data</description>
                            <lsb>0</lsb>
                            <msb>0</msb>
                            <access>read-write</access>
                            <enumeratedValues>
                                </enumeratedValues>
                        </field>
                        <field>
                            <name>PIDR</name>
                            <description>Port State</description>
                            <lsb>1</lsb>
                            <msb>1</msb>
                            <access>read-only</access>
                            <enumeratedValues>
                                </enumeratedValues>
                        </field>
                        <field>
                            <name>PDR</name>
                            <description>Port Direction</description>
                            <lsb>2</lsb>
                            <msb>2</msb>
                            <access>read-write</access>
                            <enumeratedValues>
                                </enumeratedValues>
                        </field>
                        <field>
                            <name>PCR</name>
                            <description>Pull,up Control</description>
                            <lsb>4</lsb>
                            <msb>4</msb>
                            <access>read-write</access>
                            <enumeratedValues>
                                </enumeratedValues>
                        </field>
                        <field>
                            <name>NCODR</name>
                            <description>N,Channel Open,Drain Control</description>
                            <lsb>6</lsb>
                            <msb>6</msb>
                            <access>read-write</access>
                            <enumeratedValues>
                                </enumeratedValues>
                        </field>
                        <field>
                            <name>ISEL</name>
                            <description>IRQ Input Enable</description>
                            <lsb>14</lsb>
                            <msb>14</msb>
                            <access>read-write</access>
                            <enumeratedValues>
                                </enumeratedValues>
                        </field>
                        <field>
                            <name>ASEL</name>
                            <description>Analog Input Enable</description>
                            <lsb>15</lsb>
                            <msb>15</msb>
                            <access>read-write</access>
                            <enumeratedValues>
                                </enumeratedValues>
                        </field>
                    </fields>
                </register>
                <register>
                    <name>P008PFS_BY</name>
                    <description>Port 008 Pin Function Select Register</description>
                    <alternateRegister>P008PFS</alternateRegister>
                    <addressOffset>0x023</addressOffset>
                    <size>8</size>
                    <access>read-write</access>
                    <resetValue>0x10</resetValue>
                    <resetMask>0xfd</resetMask>
                    <fields>
                        <field>
                            <name>PODR</name>
                            <description>Port Output Data</description>
                            <lsb>0</lsb>
                            <msb>0</msb>
                            <access>read-write</access>
                            <enumeratedValues>
                                </enumeratedValues>
                        </field>
                        <field>
                            <name>PIDR</name>
                            <description>Port State</description>
                            <lsb>1</lsb>
                            <msb>1</msb>
                            <access>read-only</access>
                            <enumeratedValues>
                                </enumeratedValues>
                        </field>
                        <field>
                            <name>PDR</name>
                            <description>Port Direction</description>
                            <lsb>2</lsb>
                            <msb>2</msb>
                            <access>read-write</access>
                            <enumeratedValues>
                                </enumeratedValues>
                        </field>
                        <field>
                            <name>PCR</name>
                            <description>Pull,up Control</description>
                            <lsb>4</lsb>
                            <msb>4</msb>
                            <access>read-write</access>
                            <enumeratedValues>
                                </enumeratedValues>
                        </field>
                        <field>
                            <name>NCODR</name>
                            <description>N,Channel Open,Drain Control</description>
                            <lsb>6</lsb>
                            <msb>6</msb>
                            <access>read-write</access>
                            <enumeratedValues>
                                </enumeratedValues>
                        </field>
                    </fields>
                </register>
                <register>
                    <name>P009PFS</name>
                    <description>Port 009 Pin Function Select Register</description>
                    <addressOffset>0x024</addressOffset>
                    <size>32</size>
                    <access>read-write</access>
                    <resetValue>0x00010400</resetValue>
                    <resetMask>0xfffffffd</resetMask>
                    <fields>
                        <field>
                            <name>PODR</name>
                            <description>Port Output Data</description>
                            <lsb>0</lsb>
                            <msb>0</msb>
                            <access>read-write</access>
                            <enumeratedValues>
                                </enumeratedValues>
                        </field>
                        <field>
                            <name>PIDR</name>
                            <description>Port State</description>
                            <lsb>1</lsb>
                            <msb>1</msb>
                            <access>read-only</access>
                            <enumeratedValues>
                                </enumeratedValues>
                        </field>
                        <field>
                            <name>PDR</name>
                            <description>Port Direction</description>
                            <lsb>2</lsb>
                            <msb>2</msb>
                            <access>read-write</access>
                            <enumeratedValues>
                                </enumeratedValues>
                        </field>
                        <field>
                            <name>PCR</name>
                            <description>Pull,up Control</description>
                            <lsb>4</lsb>
                            <msb>4</msb>
                            <access>read-write</access>
                            <enumeratedValues>
                                </enumeratedValues>
                        </field>
                        <field>
                            <name>NCODR</name>
                            <description>N,Channel Open,Drain Control</description>
                            <lsb>6</lsb>
                            <msb>6</msb>
                            <access>read-write</access>
                            <enumeratedValues>
                                </enumeratedValues>
                        </field>
                        <field>
                            <name>ISEL</name>
                            <description>IRQ Input Enable</description>
                            <lsb>14</lsb>
                            <msb>14</msb>
                            <access>read-write</access>
                            <enumeratedValues>
                                </enumeratedValues>
                        </field>
                        <field>
                            <name>ASEL</name>
                            <description>Analog Input Enable</description>
                            <lsb>15</lsb>
                            <msb>15</msb>
                            <access>read-write</access>
                            <enumeratedValues>
                                </enumeratedValues>
                        </field>
                        <field>
                            <name>PMR</name>
                            <description>Port Mode Control</description>
                            <lsb>16</lsb>
                            <msb>16</msb>
                            <access>read-write</access>
                            <enumeratedValues>
                                </enumeratedValues>
                        </field>
                        <field>
                            <name>PSEL</name>
                            <description>Peripheral Select</description>
                            <lsb>24</lsb>
                            <msb>28</msb>
                            <access>read-write</access>
                        </field>
                    </fields>
                </register>
                <register>
                    <name>P009PFS_HA</name>
                    <description>Port 009 Pin Function Select Register</description>
                    <alternateRegister>P009PFS</alternateRegister>
                    <addressOffset>0x026</addressOffset>
                    <size>16</size>
                    <access>read-write</access>
                    <resetValue>0x0400</resetValue>
                    <resetMask>0xfffd</resetMask>
                    <fields>
                        <field>
                            <name>PODR</name>
                            <description>Port Output Data</description>
                            <lsb>0</lsb>
                            <msb>0</msb>
                            <access>read-write</access>
                            <enumeratedValues>
                                </enumeratedValues>
                        </field>
                        <field>
                            <name>PIDR</name>
                            <description>Port State</description>
                            <lsb>1</lsb>
                            <msb>1</msb>
                            <access>read-only</access>
                            <enumeratedValues>
                                </enumeratedValues>
                        </field>
                        <field>
                            <name>PDR</name>
                            <description>Port Direction</description>
                            <lsb>2</lsb>
                            <msb>2</msb>
                            <access>read-write</access>
                            <enumeratedValues>
                                </enumeratedValues>
                        </field>
                        <field>
                            <name>PCR</name>
                            <description>Pull,up Control</description>
                            <lsb>4</lsb>
                            <msb>4</msb>
                            <access>read-write</access>
                            <enumeratedValues>
                                </enumeratedValues>
                        </field>
                        <field>
                            <name>NCODR</name>
                            <description>N,Channel Open,Drain Control</description>
                            <lsb>6</lsb>
                            <msb>6</msb>
                            <access>read-write</access>
                            <enumeratedValues>
                                </enumeratedValues>
                        </field>
                        <field>
                            <name>ISEL</name>
                            <description>IRQ Input Enable</description>
                            <lsb>14</lsb>
                            <msb>14</msb>
                            <access>read-write</access>
                            <enumeratedValues>
                                </enumeratedValues>
                        </field>
                        <field>
                            <name>ASEL</name>
                            <description>Analog Input Enable</description>
                            <lsb>15</lsb>
                            <msb>15</msb>
                            <access>read-write</access>
                            <enumeratedValues>
                                </enumeratedValues>
                        </field>
                    </fields>
                </register>
                <register>
                    <name>P009PFS_BY</name>
                    <description>Port 009 Pin Function Select Register</description>
                    <alternateRegister>P009PFS</alternateRegister>
                    <addressOffset>0x027</addressOffset>
                    <size>8</size>
                    <access>read-write</access>
                    <resetValue>0x00</resetValue>
                    <resetMask>0xfd</resetMask>
                    <fields>
                        <field>
                            <name>PODR</name>
                            <description>Port Output Data</description>
                            <lsb>0</lsb>
                            <msb>0</msb>
                            <access>read-write</access>
                            <enumeratedValues>
                                </enumeratedValues>
                        </field>
                        <field>
                            <name>PIDR</name>
                            <description>Port State</description>
                            <lsb>1</lsb>
                            <msb>1</msb>
                            <access>read-only</access>
                            <enumeratedValues>
                                </enumeratedValues>
                        </field>
                        <field>
                            <name>PDR</name>
                            <description>Port Direction</description>
                            <lsb>2</lsb>
                            <msb>2</msb>
                            <access>read-write</access>
                            <enumeratedValues>
                                </enumeratedValues>
                        </field>
                        <field>
                            <name>PCR</name>
                            <description>Pull,up Control</description>
                            <lsb>4</lsb>
                            <msb>4</msb>
                            <access>read-write</access>
                            <enumeratedValues>
                                </enumeratedValues>
                        </field>
                        <field>
                            <name>NCODR</name>
                            <description>N,Channel Open,Drain Control</description>
                            <lsb>6</lsb>
                            <msb>6</msb>
                            <access>read-write</access>
                            <enumeratedValues>
                                </enumeratedValues>
                        </field>
                    </fields>
                </register>
                <register>
                    <name>P010PFS</name>
                    <description>Port 010 Pin Function Select Register</description>
                    <addressOffset>0x028</addressOffset>
                    <size>32</size>
                    <access>read-write</access>
                    <resetValue>0x00000000</resetValue>
                    <resetMask>0xfffffffd</resetMask>
                    <fields>
                        <field>
                            <name>PODR</name>
                            <description>Port Output Data</description>
                            <lsb>0</lsb>
                            <msb>0</msb>
                            <access>read-write</access>
                            <enumeratedValues>
                                </enumeratedValues>
                        </field>
                        <field>
                            <name>PIDR</name>
                            <description>Port State</description>
                            <lsb>1</lsb>
                            <msb>1</msb>
                            <access>read-only</access>
                            <enumeratedValues>
                                </enumeratedValues>
                        </field>
                        <field>
                            <name>PDR</name>
                            <description>Port Direction</description>
                            <lsb>2</lsb>
                            <msb>2</msb>
                            <access>read-write</access>
                            <enumeratedValues>
                                </enumeratedValues>
                        </field>
                        <field>
                            <name>PCR</name>
                            <description>Pull,up Control</description>
                            <lsb>4</lsb>
                            <msb>4</msb>
                            <access>read-write</access>
                            <enumeratedValues>
                                </enumeratedValues>
                        </field>
                        <field>
                            <name>NCODR</name>
                            <description>N,Channel Open,Drain Control</description>
                            <lsb>6</lsb>
                            <msb>6</msb>
                            <access>read-write</access>
                            <enumeratedValues>
                                </enumeratedValues>
                        </field>
                        <field>
                            <name>ISEL</name>
                            <description>IRQ Input Enable</description>
                            <lsb>14</lsb>
                            <msb>14</msb>
                            <access>read-write</access>
                            <enumeratedValues>
                                </enumeratedValues>
                        </field>
                        <field>
                            <name>ASEL</name>
                            <description>Analog Input Enable</description>
                            <lsb>15</lsb>
                            <msb>15</msb>
                            <access>read-write</access>
                            <enumeratedValues>
                                </enumeratedValues>
                        </field>
                        <field>
                            <name>PMR</name>
                            <description>Port Mode Control</description>
                            <lsb>16</lsb>
                            <msb>16</msb>
                            <access>read-write</access>
                            <enumeratedValues>
                                </enumeratedValues>
                        </field>
                        <field>
                            <name>PSEL</name>
                            <description>Peripheral Select</description>
                            <lsb>24</lsb>
                            <msb>28</msb>
                            <access>read-write</access>
                        </field>
                    </fields>
                </register>
                <register>
                    <name>P010PFS_HA</name>
                    <description>Port 010 Pin Function Select Register</description>
                    <alternateRegister>P010PFS</alternateRegister>
                    <addressOffset>0x02A</addressOffset>
                    <size>16</size>
                    <access>read-write</access>
                    <resetValue>0x0000</resetValue>
                    <resetMask>0xfffd</resetMask>
                    <fields>
                        <field>
                            <name>PODR</name>
                            <description>Port Output Data</description>
                            <lsb>0</lsb>
                            <msb>0</msb>
                            <access>read-write</access>
                            <enumeratedValues>
                                </enumeratedValues>
                        </field>
                        <field>
                            <name>PIDR</name>
                            <description>Port State</description>
                            <lsb>1</lsb>
                            <msb>1</msb>
                            <access>read-only</access>
                            <enumeratedValues>
                                </enumeratedValues>
                        </field>
                        <field>
                            <name>PDR</name>
                            <description>Port Direction</description>
                            <lsb>2</lsb>
                            <msb>2</msb>
                            <access>read-write</access>
                            <enumeratedValues>
                                </enumeratedValues>
                        </field>
                        <field>
                            <name>PCR</name>
                            <description>Pull,up Control</description>
                            <lsb>4</lsb>
                            <msb>4</msb>
                            <access>read-write</access>
                            <enumeratedValues>
                                </enumeratedValues>
                        </field>
                        <field>
                            <name>NCODR</name>
                            <description>N,Channel Open,Drain Control</description>
                            <lsb>6</lsb>
                            <msb>6</msb>
                            <access>read-write</access>
                            <enumeratedValues>
                                </enumeratedValues>
                        </field>
                        <field>
                            <name>ISEL</name>
                            <description>IRQ Input Enable</description>
                            <lsb>14</lsb>
                            <msb>14</msb>
                            <access>read-write</access>
                            <enumeratedValues>
                                </enumeratedValues>
                        </field>
                        <field>
                            <name>ASEL</name>
                            <description>Analog Input Enable</description>
                            <lsb>15</lsb>
                            <msb>15</msb>
                            <access>read-write</access>
                            <enumeratedValues>
                                </enumeratedValues>
                        </field>
                    </fields>
                </register>
                <register>
                    <name>P010PFS_BY</name>
                    <description>Port 010 Pin Function Select Register</description>
                    <alternateRegister>P010PFS</alternateRegister>
                    <addressOffset>0x02B</addressOffset>
                    <size>8</size>
                    <access>read-write</access>
                    <resetValue>0x00</resetValue>
                    <resetMask>0xfd</resetMask>
                    <fields>
                        <field>
                            <name>PODR</name>
                            <description>Port Output Data</description>
                            <lsb>0</lsb>
                            <msb>0</msb>
                            <access>read-write</access>
                            <enumeratedValues>
                                </enumeratedValues>
                        </field>
                        <field>
                            <name>PIDR</name>
                            <description>Port State</description>
                            <lsb>1</lsb>
                            <msb>1</msb>
                            <access>read-only</access>
                            <enumeratedValues>
                                </enumeratedValues>
                        </field>
                        <field>
                            <name>PDR</name>
                            <description>Port Direction</description>
                            <lsb>2</lsb>
                            <msb>2</msb>
                            <access>read-write</access>
                            <enumeratedValues>
                                </enumeratedValues>
                        </field>
                        <field>
                            <name>PCR</name>
                            <description>Pull,up Control</description>
                            <lsb>4</lsb>
                            <msb>4</msb>
                            <access>read-write</access>
                            <enumeratedValues>
                                </enumeratedValues>
                        </field>
                        <field>
                            <name>NCODR</name>
                            <description>N,Channel Open,Drain Control</description>
                            <lsb>6</lsb>
                            <msb>6</msb>
                            <access>read-write</access>
                            <enumeratedValues>
                                </enumeratedValues>
                        </field>
                    </fields>
                </register>
                <register>
                    <dim>2</dim>
                    <dimIncrement>0x4</dimIncrement>
                    <dimIndex>14-15</dimIndex>
                    <name>P0%sPFS</name>
                    <description>Port 0%s Pin Function Select Register</description>
                    <addressOffset>0x038</addressOffset>
                    <size>32</size>
                    <access>read-write</access>
                    <resetValue>0x00000000</resetValue>
                    <resetMask>0xfffffffd</resetMask>
                    <fields>
                        <field>
                            <name>PODR</name>
                            <description>Port Output Data</description>
                            <lsb>0</lsb>
                            <msb>0</msb>
                            <access>read-write</access>
                            <enumeratedValues>
                                </enumeratedValues>
                        </field>
                        <field>
                            <name>PIDR</name>
                            <description>Port State</description>
                            <lsb>1</lsb>
                            <msb>1</msb>
                            <access>read-only</access>
                            <enumeratedValues>
                                </enumeratedValues>
                        </field>
                        <field>
                            <name>PDR</name>
                            <description>Port Direction</description>
                            <lsb>2</lsb>
                            <msb>2</msb>
                            <access>read-write</access>
                            <enumeratedValues>
                                </enumeratedValues>
                        </field>
                        <field>
                            <name>PCR</name>
                            <description>Pull,up Control</description>
                            <lsb>4</lsb>
                            <msb>4</msb>
                            <access>read-write</access>
                            <enumeratedValues>
                                </enumeratedValues>
                        </field>
                        <field>
                            <name>NCODR</name>
                            <description>N,Channel Open,Drain Control</description>
                            <lsb>6</lsb>
                            <msb>6</msb>
                            <access>read-write</access>
                            <enumeratedValues>
                                </enumeratedValues>
                        </field>
                        <field>
                            <name>ISEL</name>
                            <description>IRQ Input Enable</description>
                            <lsb>14</lsb>
                            <msb>14</msb>
                            <access>read-write</access>
                            <enumeratedValues>
                                </enumeratedValues>
                        </field>
                        <field>
                            <name>ASEL</name>
                            <description>Analog Input Enable</description>
                            <lsb>15</lsb>
                            <msb>15</msb>
                            <access>read-write</access>
                            <enumeratedValues>
                                </enumeratedValues>
                        </field>
                        <field>
                            <name>PMR</name>
                            <description>Port Mode Control</description>
                            <lsb>16</lsb>
                            <msb>16</msb>
                            <access>read-write</access>
                            <enumeratedValues>
                                </enumeratedValues>
                        </field>
                        <field>
                            <name>PSEL</name>
                            <description>Peripheral Select</description>
                            <lsb>24</lsb>
                            <msb>28</msb>
                            <access>read-write</access>
                        </field>
                    </fields>
                </register>
                <register>
                    <dim>2</dim>
                    <dimIncrement>0x4</dimIncrement>
                    <dimIndex>14-15</dimIndex>
                    <name>P0%sPFS_HA</name>
                    <description>Port 0%s Pin Function Select Register</description>
                    <alternateRegister>P0%sPFS</alternateRegister>
                    <addressOffset>0x03A</addressOffset>
                    <size>16</size>
                    <access>read-write</access>
                    <resetValue>0x0000</resetValue>
                    <resetMask>0xfffd</resetMask>
                    <fields>
                        <field>
                            <name>PODR</name>
                            <description>Port Output Data</description>
                            <lsb>0</lsb>
                            <msb>0</msb>
                            <access>read-write</access>
                            <enumeratedValues>
                                </enumeratedValues>
                        </field>
                        <field>
                            <name>PIDR</name>
                            <description>Port State</description>
                            <lsb>1</lsb>
                            <msb>1</msb>
                            <access>read-only</access>
                            <enumeratedValues>
                                </enumeratedValues>
                        </field>
                        <field>
                            <name>PDR</name>
                            <description>Port Direction</description>
                            <lsb>2</lsb>
                            <msb>2</msb>
                            <access>read-write</access>
                            <enumeratedValues>
                                </enumeratedValues>
                        </field>
                        <field>
                            <name>PCR</name>
                            <description>Pull,up Control</description>
                            <lsb>4</lsb>
                            <msb>4</msb>
                            <access>read-write</access>
                            <enumeratedValues>
                                </enumeratedValues>
                        </field>
                        <field>
                            <name>NCODR</name>
                            <description>N,Channel Open,Drain Control</description>
                            <lsb>6</lsb>
                            <msb>6</msb>
                            <access>read-write</access>
                            <enumeratedValues>
                                </enumeratedValues>
                        </field>
                        <field>
                            <name>ISEL</name>
                            <description>IRQ Input Enable</description>
                            <lsb>14</lsb>
                            <msb>14</msb>
                            <access>read-write</access>
                            <enumeratedValues>
                                </enumeratedValues>
                        </field>
                        <field>
                            <name>ASEL</name>
                            <description>Analog Input Enable</description>
                            <lsb>15</lsb>
                            <msb>15</msb>
                            <access>read-write</access>
                            <enumeratedValues>
                                </enumeratedValues>
                        </field>
                    </fields>
                </register>
                <register>
                    <dim>2</dim>
                    <dimIncrement>0x4</dimIncrement>
                    <dimIndex>14-15</dimIndex>
                    <name>P0%sPFS_BY</name>
                    <description>Port 0%s Pin Function Select Register</description>
                    <alternateRegister>P0%sPFS</alternateRegister>
                    <addressOffset>0x03B</addressOffset>
                    <size>8</size>
                    <access>read-write</access>
                    <resetValue>0x00</resetValue>
                    <resetMask>0xfd</resetMask>
                    <fields>
                        <field>
                            <name>PODR</name>
                            <description>Port Output Data</description>
                            <lsb>0</lsb>
                            <msb>0</msb>
                            <access>read-write</access>
                            <enumeratedValues>
                                </enumeratedValues>
                        </field>
                        <field>
                            <name>PIDR</name>
                            <description>Port State</description>
                            <lsb>1</lsb>
                            <msb>1</msb>
                            <access>read-only</access>
                            <enumeratedValues>
                                </enumeratedValues>
                        </field>
                        <field>
                            <name>PDR</name>
                            <description>Port Direction</description>
                            <lsb>2</lsb>
                            <msb>2</msb>
                            <access>read-write</access>
                            <enumeratedValues>
                                </enumeratedValues>
                        </field>
                        <field>
                            <name>PCR</name>
                            <description>Pull,up Control</description>
                            <lsb>4</lsb>
                            <msb>4</msb>
                            <access>read-write</access>
                            <enumeratedValues>
                                </enumeratedValues>
                        </field>
                        <field>
                            <name>NCODR</name>
                            <description>N,Channel Open,Drain Control</description>
                            <lsb>6</lsb>
                            <msb>6</msb>
                            <access>read-write</access>
                            <enumeratedValues>
                                </enumeratedValues>
                        </field>
                    </fields>
                </register>
                <register>
                    <dim>10</dim>
                    <dimIncrement>0x4</dimIncrement>
                    <dimIndex>0-9</dimIndex>
                    <name>P10%sPFS</name>
                    <description>Port 10%s Pin Function Select Register</description>
                    <addressOffset>0x040</addressOffset>
                    <size>32</size>
                    <access>read-write</access>
                    <resetValue>0x00000000</resetValue>
                    <resetMask>0xfffffffd</resetMask>
                    <fields>
                        <field>
                            <name>PODR</name>
                            <description>Port Output Data</description>
                            <lsb>0</lsb>
                            <msb>0</msb>
                            <access>read-write</access>
                            <enumeratedValues>
                                </enumeratedValues>
                        </field>
                        <field>
                            <name>PIDR</name>
                            <description>Port State</description>
                            <lsb>1</lsb>
                            <msb>1</msb>
                            <access>read-only</access>
                            <enumeratedValues>
                                </enumeratedValues>
                        </field>
                        <field>
                            <name>PDR</name>
                            <description>Port Direction</description>
                            <lsb>2</lsb>
                            <msb>2</msb>
                            <access>read-write</access>
                            <enumeratedValues>
                                </enumeratedValues>
                        </field>
                        <field>
                            <name>PCR</name>
                            <description>Pull,up Control</description>
                            <lsb>4</lsb>
                            <msb>4</msb>
                            <access>read-write</access>
                            <enumeratedValues>
                                </enumeratedValues>
                        </field>
                        <field>
                            <name>NCODR</name>
                            <description>N,Channel Open,Drain Control</description>
                            <lsb>6</lsb>
                            <msb>6</msb>
                            <access>read-write</access>
                            <enumeratedValues>
                                </enumeratedValues>
                        </field>
                        <field>
                            <name>EOFR</name>
                            <description>Event on Falling/Event on Rising</description>
                            <lsb>12</lsb>
                            <msb>13</msb>
                            <access>read-write</access>
                            <enumeratedValues>
                                </enumeratedValues>
                        </field>
                        <field>
                            <name>ISEL</name>
                            <description>IRQ Input Enable</description>
                            <lsb>14</lsb>
                            <msb>14</msb>
                            <access>read-write</access>
                            <enumeratedValues>
                                </enumeratedValues>
                        </field>
                        <field>
                            <name>ASEL</name>
                            <description>Analog Input Enable</description>
                            <lsb>15</lsb>
                            <msb>15</msb>
                            <access>read-write</access>
                            <enumeratedValues>
                                </enumeratedValues>
                        </field>
                        <field>
                            <name>PMR</name>
                            <description>Port Mode Control</description>
                            <lsb>16</lsb>
                            <msb>16</msb>
                            <access>read-write</access>
                            <enumeratedValues>
                                </enumeratedValues>
                        </field>
                        <field>
                            <name>PSEL</name>
                            <description>Peripheral Select</description>
                            <lsb>24</lsb>
                            <msb>28</msb>
                            <access>read-write</access>
                        </field>
                    </fields>
                </register>
                <register>
                    <dim>10</dim>
                    <dimIncrement>0x4</dimIncrement>
                    <dimIndex>0-9</dimIndex>
                    <name>P10%sPFS_HA</name>
                    <description>Port 10%s Pin Function Select Register</description>
                    <alternateRegister>P10%sPFS</alternateRegister>
                    <addressOffset>0x042</addressOffset>
                    <size>16</size>
                    <access>read-write</access>
                    <resetValue>0x0000</resetValue>
                    <resetMask>0xfffd</resetMask>
                    <fields>
                        <field>
                            <name>PODR</name>
                            <description>Port Output Data</description>
                            <lsb>0</lsb>
                            <msb>0</msb>
                            <access>read-write</access>
                            <enumeratedValues>
                                </enumeratedValues>
                        </field>
                        <field>
                            <name>PIDR</name>
                            <description>Port State</description>
                            <lsb>1</lsb>
                            <msb>1</msb>
                            <access>read-only</access>
                            <enumeratedValues>
                                </enumeratedValues>
                        </field>
                        <field>
                            <name>PDR</name>
                            <description>Port Direction</description>
                            <lsb>2</lsb>
                            <msb>2</msb>
                            <access>read-write</access>
                            <enumeratedValues>
                                </enumeratedValues>
                        </field>
                        <field>
                            <name>PCR</name>
                            <description>Pull,up Control</description>
                            <lsb>4</lsb>
                            <msb>4</msb>
                            <access>read-write</access>
                            <enumeratedValues>
                                </enumeratedValues>
                        </field>
                        <field>
                            <name>NCODR</name>
                            <description>N,Channel Open,Drain Control</description>
                            <lsb>6</lsb>
                            <msb>6</msb>
                            <access>read-write</access>
                            <enumeratedValues>
                                </enumeratedValues>
                        </field>
                        <field>
                            <name>EOFR</name>
                            <description>Event on Falling/Event on Rising</description>
                            <lsb>12</lsb>
                            <msb>13</msb>
                            <access>read-write</access>
                            <enumeratedValues>
                                </enumeratedValues>
                        </field>
                        <field>
                            <name>ISEL</name>
                            <description>IRQ Input Enable</description>
                            <lsb>14</lsb>
                            <msb>14</msb>
                            <access>read-write</access>
                            <enumeratedValues>
                                </enumeratedValues>
                        </field>
                        <field>
                            <name>ASEL</name>
                            <description>Analog Input Enable</description>
                            <lsb>15</lsb>
                            <msb>15</msb>
                            <access>read-write</access>
                            <enumeratedValues>
                                </enumeratedValues>
                        </field>
                    </fields>
                </register>
                <register>
                    <dim>10</dim>
                    <dimIncrement>0x4</dimIncrement>
                    <dimIndex>0-9</dimIndex>
                    <name>P10%sPFS_BY</name>
                    <description>Port 10%s Pin Function Select Register</description>
                    <alternateRegister>P10%sPFS</alternateRegister>
                    <addressOffset>0x043</addressOffset>
                    <size>8</size>
                    <access>read-write</access>
                    <resetValue>0x00</resetValue>
                    <resetMask>0xfd</resetMask>
                    <fields>
                        <field>
                            <name>PODR</name>
                            <description>Port Output Data</description>
                            <lsb>0</lsb>
                            <msb>0</msb>
                            <access>read-write</access>
                            <enumeratedValues>
                                </enumeratedValues>
                        </field>
                        <field>
                            <name>PIDR</name>
                            <description>Port State</description>
                            <lsb>1</lsb>
                            <msb>1</msb>
                            <access>read-only</access>
                            <enumeratedValues>
                                </enumeratedValues>
                        </field>
                        <field>
                            <name>PDR</name>
                            <description>Port Direction</description>
                            <lsb>2</lsb>
                            <msb>2</msb>
                            <access>read-write</access>
                            <enumeratedValues>
                                </enumeratedValues>
                        </field>
                        <field>
                            <name>PCR</name>
                            <description>Pull,up Control</description>
                            <lsb>4</lsb>
                            <msb>4</msb>
                            <access>read-write</access>
                            <enumeratedValues>
                                </enumeratedValues>
                        </field>
                        <field>
                            <name>NCODR</name>
                            <description>N,Channel Open,Drain Control</description>
                            <lsb>6</lsb>
                            <msb>6</msb>
                            <access>read-write</access>
                            <enumeratedValues>
                                </enumeratedValues>
                        </field>
                    </fields>
                </register>
                <register>
                    <dim>6</dim>
                    <dimIncrement>0x4</dimIncrement>
                    <dimIndex>10-15</dimIndex>
                    <name>P1%sPFS</name>
                    <description>Port 1%s Pin Function Select Register</description>
                    <addressOffset>0x068</addressOffset>
                    <size>32</size>
                    <access>read-write</access>
                    <resetValue>0x00000000</resetValue>
                    <resetMask>0xfffffffd</resetMask>
                    <fields>
                        <field>
                            <name>PODR</name>
                            <description>Port Output Data</description>
                            <lsb>0</lsb>
                            <msb>0</msb>
                            <access>read-write</access>
                            <enumeratedValues>
                                </enumeratedValues>
                        </field>
                        <field>
                            <name>PIDR</name>
                            <description>Port State</description>
                            <lsb>1</lsb>
                            <msb>1</msb>
                            <access>read-only</access>
                            <enumeratedValues>
                                </enumeratedValues>
                        </field>
                        <field>
                            <name>PDR</name>
                            <description>Port Direction</description>
                            <lsb>2</lsb>
                            <msb>2</msb>
                            <access>read-write</access>
                            <enumeratedValues>
                                </enumeratedValues>
                        </field>
                        <field>
                            <name>PCR</name>
                            <description>Pull,up Control</description>
                            <lsb>4</lsb>
                            <msb>4</msb>
                            <access>read-write</access>
                            <enumeratedValues>
                                </enumeratedValues>
                        </field>
                        <field>
                            <name>NCODR</name>
                            <description>N,Channel Open,Drain Control</description>
                            <lsb>6</lsb>
                            <msb>6</msb>
                            <access>read-write</access>
                            <enumeratedValues>
                                </enumeratedValues>
                        </field>
                        <field>
                            <name>EOFR</name>
                            <description>Event on Falling/Event on Rising</description>
                            <lsb>12</lsb>
                            <msb>13</msb>
                            <access>read-write</access>
                            <enumeratedValues>
                                </enumeratedValues>
                        </field>
                        <field>
                            <name>ISEL</name>
                            <description>IRQ Input Enable</description>
                            <lsb>14</lsb>
                            <msb>14</msb>
                            <access>read-write</access>
                            <enumeratedValues>
                                </enumeratedValues>
                        </field>
                        <field>
                            <name>ASEL</name>
                            <description>Analog Input Enable</description>
                            <lsb>15</lsb>
                            <msb>15</msb>
                            <access>read-write</access>
                            <enumeratedValues>
                                </enumeratedValues>
                        </field>
                        <field>
                            <name>PMR</name>
                            <description>Port Mode Control</description>
                            <lsb>16</lsb>
                            <msb>16</msb>
                            <access>read-write</access>
                            <enumeratedValues>
                                </enumeratedValues>
                        </field>
                        <field>
                            <name>PSEL</name>
                            <description>Peripheral Select</description>
                            <lsb>24</lsb>
                            <msb>28</msb>
                            <access>read-write</access>
                        </field>
                    </fields>
                </register>
                <register>
                    <dim>6</dim>
                    <dimIncrement>0x4</dimIncrement>
                    <dimIndex>10-15</dimIndex>
                    <name>P1%sPFS_HA</name>
                    <description>Port 1%s Pin Function Select Register</description>
                    <alternateRegister>P1%sPFS</alternateRegister>
                    <addressOffset>0x06A</addressOffset>
                    <size>16</size>
                    <access>read-write</access>
                    <resetValue>0x0000</resetValue>
                    <resetMask>0xfffd</resetMask>
                    <fields>
                        <field>
                            <name>PODR</name>
                            <description>Port Output Data</description>
                            <lsb>0</lsb>
                            <msb>0</msb>
                            <access>read-write</access>
                            <enumeratedValues>
                                </enumeratedValues>
                        </field>
                        <field>
                            <name>PIDR</name>
                            <description>Port State</description>
                            <lsb>1</lsb>
                            <msb>1</msb>
                            <access>read-only</access>
                            <enumeratedValues>
                                </enumeratedValues>
                        </field>
                        <field>
                            <name>PDR</name>
                            <description>Port Direction</description>
                            <lsb>2</lsb>
                            <msb>2</msb>
                            <access>read-write</access>
                            <enumeratedValues>
                                </enumeratedValues>
                        </field>
                        <field>
                            <name>PCR</name>
                            <description>Pull,up Control</description>
                            <lsb>4</lsb>
                            <msb>4</msb>
                            <access>read-write</access>
                            <enumeratedValues>
                                </enumeratedValues>
                        </field>
                        <field>
                            <name>NCODR</name>
                            <description>N,Channel Open,Drain Control</description>
                            <lsb>6</lsb>
                            <msb>6</msb>
                            <access>read-write</access>
                            <enumeratedValues>
                                </enumeratedValues>
                        </field>
                        <field>
                            <name>EOFR</name>
                            <description>Event on Falling/Event on Rising</description>
                            <lsb>12</lsb>
                            <msb>13</msb>
                            <access>read-write</access>
                            <enumeratedValues>
                                </enumeratedValues>
                        </field>
                        <field>
                            <name>ISEL</name>
                            <description>IRQ Input Enable</description>
                            <lsb>14</lsb>
                            <msb>14</msb>
                            <access>read-write</access>
                            <enumeratedValues>
                                </enumeratedValues>
                        </field>
                        <field>
                            <name>ASEL</name>
                            <description>Analog Input Enable</description>
                            <lsb>15</lsb>
                            <msb>15</msb>
                            <access>read-write</access>
                            <enumeratedValues>
                                </enumeratedValues>
                        </field>
                    </fields>
                </register>
                <register>
                    <dim>6</dim>
                    <dimIncrement>0x4</dimIncrement>
                    <dimIndex>10-15</dimIndex>
                    <name>P1%sPFS_BY</name>
                    <description>Port 1%s Pin Function Select Register</description>
                    <alternateRegister>P1%sPFS</alternateRegister>
                    <addressOffset>0x06B</addressOffset>
                    <size>8</size>
                    <access>read-write</access>
                    <resetValue>0x00</resetValue>
                    <resetMask>0xfd</resetMask>
                    <fields>
                        <field>
                            <name>PODR</name>
                            <description>Port Output Data</description>
                            <lsb>0</lsb>
                            <msb>0</msb>
                            <access>read-write</access>
                            <enumeratedValues>
                                </enumeratedValues>
                        </field>
                        <field>
                            <name>PIDR</name>
                            <description>Port State</description>
                            <lsb>1</lsb>
                            <msb>1</msb>
                            <access>read-only</access>
                            <enumeratedValues>
                                </enumeratedValues>
                        </field>
                        <field>
                            <name>PDR</name>
                            <description>Port Direction</description>
                            <lsb>2</lsb>
                            <msb>2</msb>
                            <access>read-write</access>
                            <enumeratedValues>
                                </enumeratedValues>
                        </field>
                        <field>
                            <name>PCR</name>
                            <description>Pull,up Control</description>
                            <lsb>4</lsb>
                            <msb>4</msb>
                            <access>read-write</access>
                            <enumeratedValues>
                                </enumeratedValues>
                        </field>
                        <field>
                            <name>NCODR</name>
                            <description>N,Channel Open,Drain Control</description>
                            <lsb>6</lsb>
                            <msb>6</msb>
                            <access>read-write</access>
                            <enumeratedValues>
                                </enumeratedValues>
                        </field>
                    </fields>
                </register>
                <register>
                    <name>P200PFS</name>
                    <description>Port 200 Pin Function Select Register</description>
                    <addressOffset>0x080</addressOffset>
                    <size>32</size>
                    <access>read-write</access>
                    <resetValue>0x00000000</resetValue>
                    <resetMask>0xfffffffd</resetMask>
                    <fields>
                        <field>
                            <name>PODR</name>
                            <description>Port Output Data</description>
                            <lsb>0</lsb>
                            <msb>0</msb>
                            <access>read-write</access>
                            <enumeratedValues>
                                </enumeratedValues>
                        </field>
                        <field>
                            <name>PIDR</name>
                            <description>Port State</description>
                            <lsb>1</lsb>
                            <msb>1</msb>
                            <access>read-only</access>
                            <enumeratedValues>
                                </enumeratedValues>
                        </field>
                        <field>
                            <name>PDR</name>
                            <description>Port Direction</description>
                            <lsb>2</lsb>
                            <msb>2</msb>
                            <access>read-write</access>
                            <enumeratedValues>
                                </enumeratedValues>
                        </field>
                        <field>
                            <name>PCR</name>
                            <description>Pull,up Control</description>
                            <lsb>4</lsb>
                            <msb>4</msb>
                            <access>read-write</access>
                            <enumeratedValues>
                                </enumeratedValues>
                        </field>
                        <field>
                            <name>NCODR</name>
                            <description>N,Channel Open,Drain Control</description>
                            <lsb>6</lsb>
                            <msb>6</msb>
                            <access>read-write</access>
                            <enumeratedValues>
                                </enumeratedValues>
                        </field>
                        <field>
                            <name>EOFR</name>
                            <description>Event on Falling/Event on Rising</description>
                            <lsb>12</lsb>
                            <msb>13</msb>
                            <access>read-write</access>
                            <enumeratedValues>
                                </enumeratedValues>
                        </field>
                        <field>
                            <name>ISEL</name>
                            <description>IRQ Input Enable</description>
                            <lsb>14</lsb>
                            <msb>14</msb>
                            <access>read-write</access>
                            <enumeratedValues>
                                </enumeratedValues>
                        </field>
                        <field>
                            <name>ASEL</name>
                            <description>Analog Input Enable</description>
                            <lsb>15</lsb>
                            <msb>15</msb>
                            <access>read-write</access>
                            <enumeratedValues>
                                </enumeratedValues>
                        </field>
                        <field>
                            <name>PMR</name>
                            <description>Port Mode Control</description>
                            <lsb>16</lsb>
                            <msb>16</msb>
                            <access>read-write</access>
                            <enumeratedValues>
                                </enumeratedValues>
                        </field>
                        <field>
                            <name>PSEL</name>
                            <description>Peripheral Select</description>
                            <lsb>24</lsb>
                            <msb>28</msb>
                            <access>read-write</access>
                        </field>
                    </fields>
                </register>
                <register>
                    <name>P200PFS_HA</name>
                    <description>Port 200 Pin Function Select Register</description>
                    <alternateRegister>P200PFS</alternateRegister>
                    <addressOffset>0x082</addressOffset>
                    <size>16</size>
                    <access>read-write</access>
                    <resetValue>0x0000</resetValue>
                    <resetMask>0xfffd</resetMask>
                    <fields>
                        <field>
                            <name>PODR</name>
                            <description>Port Output Data</description>
                            <lsb>0</lsb>
                            <msb>0</msb>
                            <access>read-write</access>
                            <enumeratedValues>
                                </enumeratedValues>
                        </field>
                        <field>
                            <name>PIDR</name>
                            <description>Port State</description>
                            <lsb>1</lsb>
                            <msb>1</msb>
                            <access>read-only</access>
                            <enumeratedValues>
                                </enumeratedValues>
                        </field>
                        <field>
                            <name>PDR</name>
                            <description>Port Direction</description>
                            <lsb>2</lsb>
                            <msb>2</msb>
                            <access>read-write</access>
                            <enumeratedValues>
                                </enumeratedValues>
                        </field>
                        <field>
                            <name>PCR</name>
                            <description>Pull,up Control</description>
                            <lsb>4</lsb>
                            <msb>4</msb>
                            <access>read-write</access>
                            <enumeratedValues>
                                </enumeratedValues>
                        </field>
                        <field>
                            <name>NCODR</name>
                            <description>N,Channel Open,Drain Control</description>
                            <lsb>6</lsb>
                            <msb>6</msb>
                            <access>read-write</access>
                            <enumeratedValues>
                                </enumeratedValues>
                        </field>
                        <field>
                            <name>EOFR</name>
                            <description>Event on Falling/Event on Rising</description>
                            <lsb>12</lsb>
                            <msb>13</msb>
                            <access>read-write</access>
                            <enumeratedValues>
                                </enumeratedValues>
                        </field>
                        <field>
                            <name>ISEL</name>
                            <description>IRQ Input Enable</description>
                            <lsb>14</lsb>
                            <msb>14</msb>
                            <access>read-write</access>
                            <enumeratedValues>
                                </enumeratedValues>
                        </field>
                        <field>
                            <name>ASEL</name>
                            <description>Analog Input Enable</description>
                            <lsb>15</lsb>
                            <msb>15</msb>
                            <access>read-write</access>
                            <enumeratedValues>
                                </enumeratedValues>
                        </field>
                    </fields>
                </register>
                <register>
                    <name>P200PFS_BY</name>
                    <description>Port 200 Pin Function Select Register</description>
                    <alternateRegister>P200PFS</alternateRegister>
                    <addressOffset>0x083</addressOffset>
                    <size>8</size>
                    <access>read-write</access>
                    <resetValue>0x00</resetValue>
                    <resetMask>0xfd</resetMask>
                    <fields>
                        <field>
                            <name>PODR</name>
                            <description>Port Output Data</description>
                            <lsb>0</lsb>
                            <msb>0</msb>
                            <access>read-write</access>
                            <enumeratedValues>
                                </enumeratedValues>
                        </field>
                        <field>
                            <name>PIDR</name>
                            <description>Port State</description>
                            <lsb>1</lsb>
                            <msb>1</msb>
                            <access>read-only</access>
                            <enumeratedValues>
                                </enumeratedValues>
                        </field>
                        <field>
                            <name>PDR</name>
                            <description>Port Direction</description>
                            <lsb>2</lsb>
                            <msb>2</msb>
                            <access>read-write</access>
                            <enumeratedValues>
                                </enumeratedValues>
                        </field>
                        <field>
                            <name>PCR</name>
                            <description>Pull,up Control</description>
                            <lsb>4</lsb>
                            <msb>4</msb>
                            <access>read-write</access>
                            <enumeratedValues>
                                </enumeratedValues>
                        </field>
                        <field>
                            <name>NCODR</name>
                            <description>N,Channel Open,Drain Control</description>
                            <lsb>6</lsb>
                            <msb>6</msb>
                            <access>read-write</access>
                            <enumeratedValues>
                                </enumeratedValues>
                        </field>
                    </fields>
                </register>
                <register>
                    <name>P201PFS</name>
                    <description>Port 201 Pin Function Select Register</description>
                    <addressOffset>0x084</addressOffset>
                    <size>32</size>
                    <access>read-write</access>
                    <resetValue>0x00000010</resetValue>
                    <resetMask>0xfffffffd</resetMask>
                    <fields>
                        <field>
                            <name>PODR</name>
                            <description>Port Output Data</description>
                            <lsb>0</lsb>
                            <msb>0</msb>
                            <access>read-write</access>
                            <enumeratedValues>
                                </enumeratedValues>
                        </field>
                        <field>
                            <name>PIDR</name>
                            <description>Port State</description>
                            <lsb>1</lsb>
                            <msb>1</msb>
                            <access>read-only</access>
                            <enumeratedValues>
                                </enumeratedValues>
                        </field>
                        <field>
                            <name>PDR</name>
                            <description>Port Direction</description>
                            <lsb>2</lsb>
                            <msb>2</msb>
                            <access>read-write</access>
                            <enumeratedValues>
                                </enumeratedValues>
                        </field>
                        <field>
                            <name>PCR</name>
                            <description>Pull,up Control</description>
                            <lsb>4</lsb>
                            <msb>4</msb>
                            <access>read-write</access>
                            <enumeratedValues>
                                </enumeratedValues>
                        </field>
                        <field>
                            <name>NCODR</name>
                            <description>N,Channel Open,Drain Control</description>
                            <lsb>6</lsb>
                            <msb>6</msb>
                            <access>read-write</access>
                            <enumeratedValues>
                                </enumeratedValues>
                        </field>
                        <field>
                            <name>EOFR</name>
                            <description>Event on Falling/Event on Rising</description>
                            <lsb>12</lsb>
                            <msb>13</msb>
                            <access>read-write</access>
                            <enumeratedValues>
                                </enumeratedValues>
                        </field>
                        <field>
                            <name>ISEL</name>
                            <description>IRQ Input Enable</description>
                            <lsb>14</lsb>
                            <msb>14</msb>
                            <access>read-write</access>
                            <enumeratedValues>
                                </enumeratedValues>
                        </field>
                        <field>
                            <name>ASEL</name>
                            <description>Analog Input Enable</description>
                            <lsb>15</lsb>
                            <msb>15</msb>
                            <access>read-write</access>
                            <enumeratedValues>
                                </enumeratedValues>
                        </field>
                        <field>
                            <name>PMR</name>
                            <description>Port Mode Control</description>
                            <lsb>16</lsb>
                            <msb>16</msb>
                            <access>read-write</access>
                            <enumeratedValues>
                                </enumeratedValues>
                        </field>
                        <field>
                            <name>PSEL</name>
                            <description>Peripheral Select</description>
                            <lsb>24</lsb>
                            <msb>28</msb>
                            <access>read-write</access>
                        </field>
                    </fields>
                </register>
                <register>
                    <name>P201PFS_HA</name>
                    <description>Port 201 Pin Function Select Register</description>
                    <alternateRegister>P201PFS</alternateRegister>
                    <addressOffset>0x086</addressOffset>
                    <size>16</size>
                    <access>read-write</access>
                    <resetValue>0x0010</resetValue>
                    <resetMask>0xfffd</resetMask>
                    <fields>
                        <field>
                            <name>PODR</name>
                            <description>Port Output Data</description>
                            <lsb>0</lsb>
                            <msb>0</msb>
                            <access>read-write</access>
                            <enumeratedValues>
                                </enumeratedValues>
                        </field>
                        <field>
                            <name>PIDR</name>
                            <description>Port State</description>
                            <lsb>1</lsb>
                            <msb>1</msb>
                            <access>read-only</access>
                            <enumeratedValues>
                                </enumeratedValues>
                        </field>
                        <field>
                            <name>PDR</name>
                            <description>Port Direction</description>
                            <lsb>2</lsb>
                            <msb>2</msb>
                            <access>read-write</access>
                            <enumeratedValues>
                                </enumeratedValues>
                        </field>
                        <field>
                            <name>PCR</name>
                            <description>Pull,up Control</description>
                            <lsb>4</lsb>
                            <msb>4</msb>
                            <access>read-write</access>
                            <enumeratedValues>
                                </enumeratedValues>
                        </field>
                        <field>
                            <name>NCODR</name>
                            <description>N,Channel Open,Drain Control</description>
                            <lsb>6</lsb>
                            <msb>6</msb>
                            <access>read-write</access>
                            <enumeratedValues>
                                </enumeratedValues>
                        </field>
                        <field>
                            <name>EOFR</name>
                            <description>Event on Falling/Event on Rising</description>
                            <lsb>12</lsb>
                            <msb>13</msb>
                            <access>read-write</access>
                            <enumeratedValues>
                                </enumeratedValues>
                        </field>
                        <field>
                            <name>ISEL</name>
                            <description>IRQ Input Enable</description>
                            <lsb>14</lsb>
                            <msb>14</msb>
                            <access>read-write</access>
                            <enumeratedValues>
                                </enumeratedValues>
                        </field>
                        <field>
                            <name>ASEL</name>
                            <description>Analog Input Enable</description>
                            <lsb>15</lsb>
                            <msb>15</msb>
                            <access>read-write</access>
                            <enumeratedValues>
                                </enumeratedValues>
                        </field>
                    </fields>
                </register>
                <register>
                    <name>P201PFS_BY</name>
                    <description>Port 201 Pin Function Select Register</description>
                    <alternateRegister>P201PFS</alternateRegister>
                    <addressOffset>0x087</addressOffset>
                    <size>8</size>
                    <access>read-write</access>
                    <resetValue>0x10</resetValue>
                    <resetMask>0xfd</resetMask>
                    <fields>
                        <field>
                            <name>PODR</name>
                            <description>Port Output Data</description>
                            <lsb>0</lsb>
                            <msb>0</msb>
                            <access>read-write</access>
                            <enumeratedValues>
                                </enumeratedValues>
                        </field>
                        <field>
                            <name>PIDR</name>
                            <description>Port State</description>
                            <lsb>1</lsb>
                            <msb>1</msb>
                            <access>read-only</access>
                            <enumeratedValues>
                                </enumeratedValues>
                        </field>
                        <field>
                            <name>PDR</name>
                            <description>Port Direction</description>
                            <lsb>2</lsb>
                            <msb>2</msb>
                            <access>read-write</access>
                            <enumeratedValues>
                                </enumeratedValues>
                        </field>
                        <field>
                            <name>PCR</name>
                            <description>Pull,up Control</description>
                            <lsb>4</lsb>
                            <msb>4</msb>
                            <access>read-write</access>
                            <enumeratedValues>
                                </enumeratedValues>
                        </field>
                        <field>
                            <name>NCODR</name>
                            <description>N,Channel Open,Drain Control</description>
                            <lsb>6</lsb>
                            <msb>6</msb>
                            <access>read-write</access>
                            <enumeratedValues>
                                </enumeratedValues>
                        </field>
                    </fields>
                </register>
                <register>
                    <dim>8</dim>
                    <dimIncrement>0x4</dimIncrement>
                    <dimIndex>2-9</dimIndex>
                    <name>P20%sPFS</name>
                    <description>Port 20%s Pin Function Select Register</description>
                    <addressOffset>0x088</addressOffset>
                    <size>32</size>
                    <access>read-write</access>
                    <resetValue>0x00000000</resetValue>
                    <resetMask>0xfffffffd</resetMask>
                    <fields>
                        <field>
                            <name>PODR</name>
                            <description>Port Output Data</description>
                            <lsb>0</lsb>
                            <msb>0</msb>
                            <access>read-write</access>
                            <enumeratedValues>
                                </enumeratedValues>
                        </field>
                        <field>
                            <name>PIDR</name>
                            <description>Port State</description>
                            <lsb>1</lsb>
                            <msb>1</msb>
                            <access>read-only</access>
                            <enumeratedValues>
                                </enumeratedValues>
                        </field>
                        <field>
                            <name>PDR</name>
                            <description>Port Direction</description>
                            <lsb>2</lsb>
                            <msb>2</msb>
                            <access>read-write</access>
                            <enumeratedValues>
                                </enumeratedValues>
                        </field>
                        <field>
                            <name>PCR</name>
                            <description>Pull,up Control</description>
                            <lsb>4</lsb>
                            <msb>4</msb>
                            <access>read-write</access>
                            <enumeratedValues>
                                </enumeratedValues>
                        </field>
                        <field>
                            <name>NCODR</name>
                            <description>N,Channel Open,Drain Control</description>
                            <lsb>6</lsb>
                            <msb>6</msb>
                            <access>read-write</access>
                            <enumeratedValues>
                                </enumeratedValues>
                        </field>
                        <field>
                            <name>EOFR</name>
                            <description>Event on Falling/Event on Rising</description>
                            <lsb>12</lsb>
                            <msb>13</msb>
                            <access>read-write</access>
                            <enumeratedValues>
                                </enumeratedValues>
                        </field>
                        <field>
                            <name>ISEL</name>
                            <description>IRQ Input Enable</description>
                            <lsb>14</lsb>
                            <msb>14</msb>
                            <access>read-write</access>
                            <enumeratedValues>
                                </enumeratedValues>
                        </field>
                        <field>
                            <name>ASEL</name>
                            <description>Analog Input Enable</description>
                            <lsb>15</lsb>
                            <msb>15</msb>
                            <access>read-write</access>
                            <enumeratedValues>
                                </enumeratedValues>
                        </field>
                        <field>
                            <name>PMR</name>
                            <description>Port Mode Control</description>
                            <lsb>16</lsb>
                            <msb>16</msb>
                            <access>read-write</access>
                            <enumeratedValues>
                                </enumeratedValues>
                        </field>
                        <field>
                            <name>PSEL</name>
                            <description>Peripheral Select</description>
                            <lsb>24</lsb>
                            <msb>28</msb>
                            <access>read-write</access>
                        </field>
                    </fields>
                </register>
                <register>
                    <dim>8</dim>
                    <dimIncrement>0x4</dimIncrement>
                    <dimIndex>2-9</dimIndex>
                    <name>P20%sPFS_HA</name>
                    <description>Port 20%s Pin Function Select Register</description>
                    <alternateRegister>P20%sPFS</alternateRegister>
                    <addressOffset>0x08A</addressOffset>
                    <size>16</size>
                    <access>read-write</access>
                    <resetValue>0x0000</resetValue>
                    <resetMask>0xfffd</resetMask>
                    <fields>
                        <field>
                            <name>PODR</name>
                            <description>Port Output Data</description>
                            <lsb>0</lsb>
                            <msb>0</msb>
                            <access>read-write</access>
                            <enumeratedValues>
                                </enumeratedValues>
                        </field>
                        <field>
                            <name>PIDR</name>
                            <description>Port State</description>
                            <lsb>1</lsb>
                            <msb>1</msb>
                            <access>read-only</access>
                            <enumeratedValues>
                                </enumeratedValues>
                        </field>
                        <field>
                            <name>PDR</name>
                            <description>Port Direction</description>
                            <lsb>2</lsb>
                            <msb>2</msb>
                            <access>read-write</access>
                            <enumeratedValues>
                                </enumeratedValues>
                        </field>
                        <field>
                            <name>PCR</name>
                            <description>Pull,up Control</description>
                            <lsb>4</lsb>
                            <msb>4</msb>
                            <access>read-write</access>
                            <enumeratedValues>
                                </enumeratedValues>
                        </field>
                        <field>
                            <name>NCODR</name>
                            <description>N,Channel Open,Drain Control</description>
                            <lsb>6</lsb>
                            <msb>6</msb>
                            <access>read-write</access>
                            <enumeratedValues>
                                </enumeratedValues>
                        </field>
                        <field>
                            <name>EOFR</name>
                            <description>Event on Falling/Event on Rising</description>
                            <lsb>12</lsb>
                            <msb>13</msb>
                            <access>read-write</access>
                            <enumeratedValues>
                                </enumeratedValues>
                        </field>
                        <field>
                            <name>ISEL</name>
                            <description>IRQ Input Enable</description>
                            <lsb>14</lsb>
                            <msb>14</msb>
                            <access>read-write</access>
                            <enumeratedValues>
                                </enumeratedValues>
                        </field>
                        <field>
                            <name>ASEL</name>
                            <description>Analog Input Enable</description>
                            <lsb>15</lsb>
                            <msb>15</msb>
                            <access>read-write</access>
                            <enumeratedValues>
                                </enumeratedValues>
                        </field>
                    </fields>
                </register>
                <register>
                    <dim>8</dim>
                    <dimIncrement>0x4</dimIncrement>
                    <dimIndex>2-9</dimIndex>
                    <name>P20%sPFS_BY</name>
                    <description>Port 20%s Pin Function Select Register</description>
                    <alternateRegister>P20%sPFS</alternateRegister>
                    <addressOffset>0x08B</addressOffset>
                    <size>8</size>
                    <access>read-write</access>
                    <resetValue>0x00</resetValue>
                    <resetMask>0xfd</resetMask>
                    <fields>
                        <field>
                            <name>PODR</name>
                            <description>Port Output Data</description>
                            <lsb>0</lsb>
                            <msb>0</msb>
                            <access>read-write</access>
                            <enumeratedValues>
                                </enumeratedValues>
                        </field>
                        <field>
                            <name>PIDR</name>
                            <description>Port State</description>
                            <lsb>1</lsb>
                            <msb>1</msb>
                            <access>read-only</access>
                            <enumeratedValues>
                                </enumeratedValues>
                        </field>
                        <field>
                            <name>PDR</name>
                            <description>Port Direction</description>
                            <lsb>2</lsb>
                            <msb>2</msb>
                            <access>read-write</access>
                            <enumeratedValues>
                                </enumeratedValues>
                        </field>
                        <field>
                            <name>PCR</name>
                            <description>Pull,up Control</description>
                            <lsb>4</lsb>
                            <msb>4</msb>
                            <access>read-write</access>
                            <enumeratedValues>
                                </enumeratedValues>
                        </field>
                        <field>
                            <name>NCODR</name>
                            <description>N,Channel Open,Drain Control</description>
                            <lsb>6</lsb>
                            <msb>6</msb>
                            <access>read-write</access>
                            <enumeratedValues>
                                </enumeratedValues>
                        </field>
                    </fields>
                </register>
                <register>
                    <dim>5</dim>
                    <dimIncrement>0x4</dimIncrement>
                    <dimIndex>10-14</dimIndex>
                    <name>P2%sPFS</name>
                    <description>Port 2%s Pin Function Select Register</description>
                    <addressOffset>0x0A8</addressOffset>
                    <size>32</size>
                    <access>read-write</access>
                    <resetValue>0x00000000</resetValue>
                    <resetMask>0xfffffffd</resetMask>
                    <fields>
                        <field>
                            <name>PODR</name>
                            <description>Port Output Data</description>
                            <lsb>0</lsb>
                            <msb>0</msb>
                            <access>read-write</access>
                            <enumeratedValues>
                                </enumeratedValues>
                        </field>
                        <field>
                            <name>PIDR</name>
                            <description>Port State</description>
                            <lsb>1</lsb>
                            <msb>1</msb>
                            <access>read-only</access>
                            <enumeratedValues>
                                </enumeratedValues>
                        </field>
                        <field>
                            <name>PDR</name>
                            <description>Port Direction</description>
                            <lsb>2</lsb>
                            <msb>2</msb>
                            <access>read-write</access>
                            <enumeratedValues>
                                </enumeratedValues>
                        </field>
                        <field>
                            <name>PCR</name>
                            <description>Pull,up Control</description>
                            <lsb>4</lsb>
                            <msb>4</msb>
                            <access>read-write</access>
                            <enumeratedValues>
                                </enumeratedValues>
                        </field>
                        <field>
                            <name>NCODR</name>
                            <description>N,Channel Open,Drain Control</description>
                            <lsb>6</lsb>
                            <msb>6</msb>
                            <access>read-write</access>
                            <enumeratedValues>
                                </enumeratedValues>
                        </field>
                        <field>
                            <name>EOFR</name>
                            <description>Event on Falling/Event on Rising</description>
                            <lsb>12</lsb>
                            <msb>13</msb>
                            <access>read-write</access>
                            <enumeratedValues>
                                </enumeratedValues>
                        </field>
                        <field>
                            <name>ISEL</name>
                            <description>IRQ Input Enable</description>
                            <lsb>14</lsb>
                            <msb>14</msb>
                            <access>read-write</access>
                            <enumeratedValues>
                                </enumeratedValues>
                        </field>
                        <field>
                            <name>ASEL</name>
                            <description>Analog Input Enable</description>
                            <lsb>15</lsb>
                            <msb>15</msb>
                            <access>read-write</access>
                            <enumeratedValues>
                                </enumeratedValues>
                        </field>
                        <field>
                            <name>PMR</name>
                            <description>Port Mode Control</description>
                            <lsb>16</lsb>
                            <msb>16</msb>
                            <access>read-write</access>
                            <enumeratedValues>
                                </enumeratedValues>
                        </field>
                        <field>
                            <name>PSEL</name>
                            <description>Peripheral Select</description>
                            <lsb>24</lsb>
                            <msb>28</msb>
                            <access>read-write</access>
                        </field>
                    </fields>
                </register>
                <register>
                    <dim>5</dim>
                    <dimIncrement>0x4</dimIncrement>
                    <dimIndex>10-14</dimIndex>
                    <name>P2%sPFS_HA</name>
                    <description>Port 2%s Pin Function Select Register</description>
                    <alternateRegister>P2%sPFS</alternateRegister>
                    <addressOffset>0x0AA</addressOffset>
                    <size>16</size>
                    <access>read-write</access>
                    <resetValue>0x0000</resetValue>
                    <resetMask>0xfffd</resetMask>
                    <fields>
                        <field>
                            <name>PODR</name>
                            <description>Port Output Data</description>
                            <lsb>0</lsb>
                            <msb>0</msb>
                            <access>read-write</access>
                            <enumeratedValues>
                                </enumeratedValues>
                        </field>
                        <field>
                            <name>PIDR</name>
                            <description>Port State</description>
                            <lsb>1</lsb>
                            <msb>1</msb>
                            <access>read-only</access>
                            <enumeratedValues>
                                </enumeratedValues>
                        </field>
                        <field>
                            <name>PDR</name>
                            <description>Port Direction</description>
                            <lsb>2</lsb>
                            <msb>2</msb>
                            <access>read-write</access>
                            <enumeratedValues>
                                </enumeratedValues>
                        </field>
                        <field>
                            <name>PCR</name>
                            <description>Pull,up Control</description>
                            <lsb>4</lsb>
                            <msb>4</msb>
                            <access>read-write</access>
                            <enumeratedValues>
                                </enumeratedValues>
                        </field>
                        <field>
                            <name>NCODR</name>
                            <description>N,Channel Open,Drain Control</description>
                            <lsb>6</lsb>
                            <msb>6</msb>
                            <access>read-write</access>
                            <enumeratedValues>
                                </enumeratedValues>
                        </field>
                        <field>
                            <name>EOFR</name>
                            <description>Event on Falling/Event on Rising</description>
                            <lsb>12</lsb>
                            <msb>13</msb>
                            <access>read-write</access>
                            <enumeratedValues>
                                </enumeratedValues>
                        </field>
                        <field>
                            <name>ISEL</name>
                            <description>IRQ Input Enable</description>
                            <lsb>14</lsb>
                            <msb>14</msb>
                            <access>read-write</access>
                            <enumeratedValues>
                                </enumeratedValues>
                        </field>
                        <field>
                            <name>ASEL</name>
                            <description>Analog Input Enable</description>
                            <lsb>15</lsb>
                            <msb>15</msb>
                            <access>read-write</access>
                            <enumeratedValues>
                                </enumeratedValues>
                        </field>
                    </fields>
                </register>
                <register>
                    <dim>5</dim>
                    <dimIncrement>0x4</dimIncrement>
                    <dimIndex>10-14</dimIndex>
                    <name>P2%sPFS_BY</name>
                    <description>Port 2%s Pin Function Select Register</description>
                    <alternateRegister>P2%sPFS</alternateRegister>
                    <addressOffset>0x0AB</addressOffset>
                    <size>8</size>
                    <access>read-write</access>
                    <resetValue>0x00</resetValue>
                    <resetMask>0xfd</resetMask>
                    <fields>
                        <field>
                            <name>PODR</name>
                            <description>Port Output Data</description>
                            <lsb>0</lsb>
                            <msb>0</msb>
                            <access>read-write</access>
                            <enumeratedValues>
                                </enumeratedValues>
                        </field>
                        <field>
                            <name>PIDR</name>
                            <description>Port State</description>
                            <lsb>1</lsb>
                            <msb>1</msb>
                            <access>read-only</access>
                            <enumeratedValues>
                                </enumeratedValues>
                        </field>
                        <field>
                            <name>PDR</name>
                            <description>Port Direction</description>
                            <lsb>2</lsb>
                            <msb>2</msb>
                            <access>read-write</access>
                            <enumeratedValues>
                                </enumeratedValues>
                        </field>
                        <field>
                            <name>PCR</name>
                            <description>Pull,up Control</description>
                            <lsb>4</lsb>
                            <msb>4</msb>
                            <access>read-write</access>
                            <enumeratedValues>
                                </enumeratedValues>
                        </field>
                        <field>
                            <name>NCODR</name>
                            <description>N,Channel Open,Drain Control</description>
                            <lsb>6</lsb>
                            <msb>6</msb>
                            <access>read-write</access>
                            <enumeratedValues>
                                </enumeratedValues>
                        </field>
                    </fields>
                </register>
                <register>
                    <name>P300PFS</name>
                    <description>Port 300 Pin Function Select Register</description>
                    <addressOffset>0x0C0</addressOffset>
                    <size>32</size>
                    <access>read-write</access>
                    <resetValue>0x00010010</resetValue>
                    <resetMask>0xfffffffd</resetMask>
                    <fields>
                        <field>
                            <name>PODR</name>
                            <description>Port Output Data</description>
                            <lsb>0</lsb>
                            <msb>0</msb>
                            <access>read-write</access>
                            <enumeratedValues>
                                </enumeratedValues>
                        </field>
                        <field>
                            <name>PIDR</name>
                            <description>Port State</description>
                            <lsb>1</lsb>
                            <msb>1</msb>
                            <access>read-only</access>
                            <enumeratedValues>
                                </enumeratedValues>
                        </field>
                        <field>
                            <name>PDR</name>
                            <description>Port Direction</description>
                            <lsb>2</lsb>
                            <msb>2</msb>
                            <access>read-write</access>
                            <enumeratedValues>
                                </enumeratedValues>
                        </field>
                        <field>
                            <name>PCR</name>
                            <description>Pull,up Control</description>
                            <lsb>4</lsb>
                            <msb>4</msb>
                            <access>read-write</access>
                            <enumeratedValues>
                                </enumeratedValues>
                        </field>
                        <field>
                            <name>NCODR</name>
                            <description>N,Channel Open,Drain Control</description>
                            <lsb>6</lsb>
                            <msb>6</msb>
                            <access>read-write</access>
                            <enumeratedValues>
                                </enumeratedValues>
                        </field>
                        <field>
                            <name>EOFR</name>
                            <description>Event on Falling/Event on Rising</description>
                            <lsb>12</lsb>
                            <msb>13</msb>
                            <access>read-write</access>
                            <enumeratedValues>
                                </enumeratedValues>
                        </field>
                        <field>
                            <name>ISEL</name>
                            <description>IRQ Input Enable</description>
                            <lsb>14</lsb>
                            <msb>14</msb>
                            <access>read-write</access>
                            <enumeratedValues>
                                </enumeratedValues>
                        </field>
                        <field>
                            <name>ASEL</name>
                            <description>Analog Input Enable</description>
                            <lsb>15</lsb>
                            <msb>15</msb>
                            <access>read-write</access>
                            <enumeratedValues>
                                </enumeratedValues>
                        </field>
                        <field>
                            <name>PMR</name>
                            <description>Port Mode Control</description>
                            <lsb>16</lsb>
                            <msb>16</msb>
                            <access>read-write</access>
                            <enumeratedValues>
                                </enumeratedValues>
                        </field>
                        <field>
                            <name>PSEL</name>
                            <description>Peripheral Select</description>
                            <lsb>24</lsb>
                            <msb>28</msb>
                            <access>read-write</access>
                        </field>
                    </fields>
                </register>
                <register>
                    <name>P300PFS_HA</name>
                    <description>Port 300 Pin Function Select Register</description>
                    <alternateRegister>P300PFS</alternateRegister>
                    <addressOffset>0x0C2</addressOffset>
                    <size>16</size>
                    <access>read-write</access>
                    <resetValue>0x0010</resetValue>
                    <resetMask>0xfffd</resetMask>
                    <fields>
                        <field>
                            <name>PODR</name>
                            <description>Port Output Data</description>
                            <lsb>0</lsb>
                            <msb>0</msb>
                            <access>read-write</access>
                            <enumeratedValues>
                                </enumeratedValues>
                        </field>
                        <field>
                            <name>PIDR</name>
                            <description>Port State</description>
                            <lsb>1</lsb>
                            <msb>1</msb>
                            <access>read-only</access>
                            <enumeratedValues>
                                </enumeratedValues>
                        </field>
                        <field>
                            <name>PDR</name>
                            <description>Port Direction</description>
                            <lsb>2</lsb>
                            <msb>2</msb>
                            <access>read-write</access>
                            <enumeratedValues>
                                </enumeratedValues>
                        </field>
                        <field>
                            <name>PCR</name>
                            <description>Pull,up Control</description>
                            <lsb>4</lsb>
                            <msb>4</msb>
                            <access>read-write</access>
                            <enumeratedValues>
                                </enumeratedValues>
                        </field>
                        <field>
                            <name>NCODR</name>
                            <description>N,Channel Open,Drain Control</description>
                            <lsb>6</lsb>
                            <msb>6</msb>
                            <access>read-write</access>
                            <enumeratedValues>
                                </enumeratedValues>
                        </field>
                        <field>
                            <name>EOFR</name>
                            <description>Event on Falling/Event on Rising</description>
                            <lsb>12</lsb>
                            <msb>13</msb>
                            <access>read-write</access>
                            <enumeratedValues>
                                </enumeratedValues>
                        </field>
                        <field>
                            <name>ISEL</name>
                            <description>IRQ Input Enable</description>
                            <lsb>14</lsb>
                            <msb>14</msb>
                            <access>read-write</access>
                            <enumeratedValues>
                                </enumeratedValues>
                        </field>
                        <field>
                            <name>ASEL</name>
                            <description>Analog Input Enable</description>
                            <lsb>15</lsb>
                            <msb>15</msb>
                            <access>read-write</access>
                            <enumeratedValues>
                                </enumeratedValues>
                        </field>
                    </fields>
                </register>
                <register>
                    <name>P300PFS_BY</name>
                    <description>Port 300 Pin Function Select Register</description>
                    <alternateRegister>P300PFS</alternateRegister>
                    <addressOffset>0x0C3</addressOffset>
                    <size>8</size>
                    <access>read-write</access>
                    <resetValue>0x10</resetValue>
                    <resetMask>0xfd</resetMask>
                    <fields>
                        <field>
                            <name>PODR</name>
                            <description>Port Output Data</description>
                            <lsb>0</lsb>
                            <msb>0</msb>
                            <access>read-write</access>
                            <enumeratedValues>
                                </enumeratedValues>
                        </field>
                        <field>
                            <name>PIDR</name>
                            <description>Port State</description>
                            <lsb>1</lsb>
                            <msb>1</msb>
                            <access>read-only</access>
                            <enumeratedValues>
                                </enumeratedValues>
                        </field>
                        <field>
                            <name>PDR</name>
                            <description>Port Direction</description>
                            <lsb>2</lsb>
                            <msb>2</msb>
                            <access>read-write</access>
                            <enumeratedValues>
                                </enumeratedValues>
                        </field>
                        <field>
                            <name>PCR</name>
                            <description>Pull,up Control</description>
                            <lsb>4</lsb>
                            <msb>4</msb>
                            <access>read-write</access>
                            <enumeratedValues>
                                </enumeratedValues>
                        </field>
                        <field>
                            <name>NCODR</name>
                            <description>N,Channel Open,Drain Control</description>
                            <lsb>6</lsb>
                            <msb>6</msb>
                            <access>read-write</access>
                            <enumeratedValues>
                                </enumeratedValues>
                        </field>
                    </fields>
                </register>
                <register>
                    <dim>9</dim>
                    <dimIncrement>0x4</dimIncrement>
                    <dimIndex>1-9</dimIndex>
                    <name>P30%sPFS</name>
                    <description>Port 30%s Pin Function Select Register</description>
                    <addressOffset>0x0C4</addressOffset>
                    <size>32</size>
                    <access>read-write</access>
                    <resetValue>0x00000000</resetValue>
                    <resetMask>0xfffffffd</resetMask>
                    <fields>
                        <field>
                            <name>PODR</name>
                            <description>Port Output Data</description>
                            <lsb>0</lsb>
                            <msb>0</msb>
                            <access>read-write</access>
                            <enumeratedValues>
                                </enumeratedValues>
                        </field>
                        <field>
                            <name>PIDR</name>
                            <description>Port State</description>
                            <lsb>1</lsb>
                            <msb>1</msb>
                            <access>read-only</access>
                            <enumeratedValues>
                                </enumeratedValues>
                        </field>
                        <field>
                            <name>PDR</name>
                            <description>Port Direction</description>
                            <lsb>2</lsb>
                            <msb>2</msb>
                            <access>read-write</access>
                            <enumeratedValues>
                                </enumeratedValues>
                        </field>
                        <field>
                            <name>PCR</name>
                            <description>Pull,up Control</description>
                            <lsb>4</lsb>
                            <msb>4</msb>
                            <access>read-write</access>
                            <enumeratedValues>
                                </enumeratedValues>
                        </field>
                        <field>
                            <name>NCODR</name>
                            <description>N,Channel Open,Drain Control</description>
                            <lsb>6</lsb>
                            <msb>6</msb>
                            <access>read-write</access>
                            <enumeratedValues>
                                </enumeratedValues>
                        </field>
                        <field>
                            <name>EOFR</name>
                            <description>Event on Falling/Event on Rising</description>
                            <lsb>12</lsb>
                            <msb>13</msb>
                            <access>read-write</access>
                            <enumeratedValues>
                                </enumeratedValues>
                        </field>
                        <field>
                            <name>ISEL</name>
                            <description>IRQ Input Enable</description>
                            <lsb>14</lsb>
                            <msb>14</msb>
                            <access>read-write</access>
                            <enumeratedValues>
                                </enumeratedValues>
                        </field>
                        <field>
                            <name>ASEL</name>
                            <description>Analog Input Enable</description>
                            <lsb>15</lsb>
                            <msb>15</msb>
                            <access>read-write</access>
                            <enumeratedValues>
                                </enumeratedValues>
                        </field>
                        <field>
                            <name>PMR</name>
                            <description>Port Mode Control</description>
                            <lsb>16</lsb>
                            <msb>16</msb>
                            <access>read-write</access>
                            <enumeratedValues>
                                </enumeratedValues>
                        </field>
                        <field>
                            <name>PSEL</name>
                            <description>Peripheral Select</description>
                            <lsb>24</lsb>
                            <msb>28</msb>
                            <access>read-write</access>
                        </field>
                    </fields>
                </register>
                <register>
                    <dim>9</dim>
                    <dimIncrement>0x4</dimIncrement>
                    <dimIndex>1-9</dimIndex>
                    <name>P30%sPFS_HA</name>
                    <description>Port 30%s Pin Function Select Register</description>
                    <alternateRegister>P30%sPFS</alternateRegister>
                    <addressOffset>0x0C6</addressOffset>
                    <size>16</size>
                    <access>read-write</access>
                    <resetValue>0x0000</resetValue>
                    <resetMask>0xfffd</resetMask>
                    <fields>
                        <field>
                            <name>PODR</name>
                            <description>Port Output Data</description>
                            <lsb>0</lsb>
                            <msb>0</msb>
                            <access>read-write</access>
                            <enumeratedValues>
                                </enumeratedValues>
                        </field>
                        <field>
                            <name>PIDR</name>
                            <description>Port State</description>
                            <lsb>1</lsb>
                            <msb>1</msb>
                            <access>read-only</access>
                            <enumeratedValues>
                                </enumeratedValues>
                        </field>
                        <field>
                            <name>PDR</name>
                            <description>Port Direction</description>
                            <lsb>2</lsb>
                            <msb>2</msb>
                            <access>read-write</access>
                            <enumeratedValues>
                                </enumeratedValues>
                        </field>
                        <field>
                            <name>PCR</name>
                            <description>Pull,up Control</description>
                            <lsb>4</lsb>
                            <msb>4</msb>
                            <access>read-write</access>
                            <enumeratedValues>
                                </enumeratedValues>
                        </field>
                        <field>
                            <name>NCODR</name>
                            <description>N,Channel Open,Drain Control</description>
                            <lsb>6</lsb>
                            <msb>6</msb>
                            <access>read-write</access>
                            <enumeratedValues>
                                </enumeratedValues>
                        </field>
                        <field>
                            <name>EOFR</name>
                            <description>Event on Falling/Event on Rising</description>
                            <lsb>12</lsb>
                            <msb>13</msb>
                            <access>read-write</access>
                            <enumeratedValues>
                                </enumeratedValues>
                        </field>
                        <field>
                            <name>ISEL</name>
                            <description>IRQ Input Enable</description>
                            <lsb>14</lsb>
                            <msb>14</msb>
                            <access>read-write</access>
                            <enumeratedValues>
                                </enumeratedValues>
                        </field>
                        <field>
                            <name>ASEL</name>
                            <description>Analog Input Enable</description>
                            <lsb>15</lsb>
                            <msb>15</msb>
                            <access>read-write</access>
                            <enumeratedValues>
                                </enumeratedValues>
                        </field>
                    </fields>
                </register>
                <register>
                    <dim>9</dim>
                    <dimIncrement>0x4</dimIncrement>
                    <dimIndex>1-9</dimIndex>
                    <name>P30%sPFS_BY</name>
                    <description>Port 30%s Pin Function Select Register</description>
                    <alternateRegister>P30%sPFS</alternateRegister>
                    <addressOffset>0x0C7</addressOffset>
                    <size>8</size>
                    <access>read-write</access>
                    <resetValue>0x00</resetValue>
                    <resetMask>0xfd</resetMask>
                    <fields>
                        <field>
                            <name>PODR</name>
                            <description>Port Output Data</description>
                            <lsb>0</lsb>
                            <msb>0</msb>
                            <access>read-write</access>
                            <enumeratedValues>
                                </enumeratedValues>
                        </field>
                        <field>
                            <name>PIDR</name>
                            <description>Port State</description>
                            <lsb>1</lsb>
                            <msb>1</msb>
                            <access>read-only</access>
                            <enumeratedValues>
                                </enumeratedValues>
                        </field>
                        <field>
                            <name>PDR</name>
                            <description>Port Direction</description>
                            <lsb>2</lsb>
                            <msb>2</msb>
                            <access>read-write</access>
                            <enumeratedValues>
                                </enumeratedValues>
                        </field>
                        <field>
                            <name>PCR</name>
                            <description>Pull,up Control</description>
                            <lsb>4</lsb>
                            <msb>4</msb>
                            <access>read-write</access>
                            <enumeratedValues>
                                </enumeratedValues>
                        </field>
                        <field>
                            <name>NCODR</name>
                            <description>N,Channel Open,Drain Control</description>
                            <lsb>6</lsb>
                            <msb>6</msb>
                            <access>read-write</access>
                            <enumeratedValues>
                                </enumeratedValues>
                        </field>
                    </fields>
                </register>
                <register>
                    <dim>6</dim>
                    <dimIncrement>0x4</dimIncrement>
                    <dimIndex>10-15</dimIndex>
                    <name>P3%sPFS</name>
                    <description>Port 3%s Pin Function Select Register</description>
                    <addressOffset>0x0E8</addressOffset>
                    <size>32</size>
                    <access>read-write</access>
                    <resetValue>0x00000000</resetValue>
                    <resetMask>0xfffffffd</resetMask>
                    <fields>
                        <field>
                            <name>PODR</name>
                            <description>Port Output Data</description>
                            <lsb>0</lsb>
                            <msb>0</msb>
                            <access>read-write</access>
                            <enumeratedValues>
                                </enumeratedValues>
                        </field>
                        <field>
                            <name>PIDR</name>
                            <description>Port State</description>
                            <lsb>1</lsb>
                            <msb>1</msb>
                            <access>read-only</access>
                            <enumeratedValues>
                                </enumeratedValues>
                        </field>
                        <field>
                            <name>PDR</name>
                            <description>Port Direction</description>
                            <lsb>2</lsb>
                            <msb>2</msb>
                            <access>read-write</access>
                            <enumeratedValues>
                                </enumeratedValues>
                        </field>
                        <field>
                            <name>PCR</name>
                            <description>Pull,up Control</description>
                            <lsb>4</lsb>
                            <msb>4</msb>
                            <access>read-write</access>
                            <enumeratedValues>
                                </enumeratedValues>
                        </field>
                        <field>
                            <name>NCODR</name>
                            <description>N,Channel Open,Drain Control</description>
                            <lsb>6</lsb>
                            <msb>6</msb>
                            <access>read-write</access>
                            <enumeratedValues>
                                </enumeratedValues>
                        </field>
                        <field>
                            <name>EOFR</name>
                            <description>Event on Falling/Event on Rising</description>
                            <lsb>12</lsb>
                            <msb>13</msb>
                            <access>read-write</access>
                            <enumeratedValues>
                                </enumeratedValues>
                        </field>
                        <field>
                            <name>ISEL</name>
                            <description>IRQ Input Enable</description>
                            <lsb>14</lsb>
                            <msb>14</msb>
                            <access>read-write</access>
                            <enumeratedValues>
                                </enumeratedValues>
                        </field>
                        <field>
                            <name>ASEL</name>
                            <description>Analog Input Enable</description>
                            <lsb>15</lsb>
                            <msb>15</msb>
                            <access>read-write</access>
                            <enumeratedValues>
                                </enumeratedValues>
                        </field>
                        <field>
                            <name>PMR</name>
                            <description>Port Mode Control</description>
                            <lsb>16</lsb>
                            <msb>16</msb>
                            <access>read-write</access>
                            <enumeratedValues>
                                </enumeratedValues>
                        </field>
                        <field>
                            <name>PSEL</name>
                            <description>Peripheral Select</description>
                            <lsb>24</lsb>
                            <msb>28</msb>
                            <access>read-write</access>
                        </field>
                    </fields>
                </register>
                <register>
                    <dim>6</dim>
                    <dimIncrement>0x4</dimIncrement>
                    <dimIndex>10-15</dimIndex>
                    <name>P3%sPFS_HA</name>
                    <description>Port 3%s Pin Function Select Register</description>
                    <alternateRegister>P3%sPFS</alternateRegister>
                    <addressOffset>0x0EA</addressOffset>
                    <size>16</size>
                    <access>read-write</access>
                    <resetValue>0x0000</resetValue>
                    <resetMask>0xfffd</resetMask>
                    <fields>
                        <field>
                            <name>PODR</name>
                            <description>Port Output Data</description>
                            <lsb>0</lsb>
                            <msb>0</msb>
                            <access>read-write</access>
                            <enumeratedValues>
                                </enumeratedValues>
                        </field>
                        <field>
                            <name>PIDR</name>
                            <description>Port State</description>
                            <lsb>1</lsb>
                            <msb>1</msb>
                            <access>read-only</access>
                            <enumeratedValues>
                                </enumeratedValues>
                        </field>
                        <field>
                            <name>PDR</name>
                            <description>Port Direction</description>
                            <lsb>2</lsb>
                            <msb>2</msb>
                            <access>read-write</access>
                            <enumeratedValues>
                                </enumeratedValues>
                        </field>
                        <field>
                            <name>PCR</name>
                            <description>Pull,up Control</description>
                            <lsb>4</lsb>
                            <msb>4</msb>
                            <access>read-write</access>
                            <enumeratedValues>
                                </enumeratedValues>
                        </field>
                        <field>
                            <name>NCODR</name>
                            <description>N,Channel Open,Drain Control</description>
                            <lsb>6</lsb>
                            <msb>6</msb>
                            <access>read-write</access>
                            <enumeratedValues>
                                </enumeratedValues>
                        </field>
                        <field>
                            <name>EOFR</name>
                            <description>Event on Falling/Event on Rising</description>
                            <lsb>12</lsb>
                            <msb>13</msb>
                            <access>read-write</access>
                            <enumeratedValues>
                                </enumeratedValues>
                        </field>
                        <field>
                            <name>ISEL</name>
                            <description>IRQ Input Enable</description>
                            <lsb>14</lsb>
                            <msb>14</msb>
                            <access>read-write</access>
                            <enumeratedValues>
                                </enumeratedValues>
                        </field>
                        <field>
                            <name>ASEL</name>
                            <description>Analog Input Enable</description>
                            <lsb>15</lsb>
                            <msb>15</msb>
                            <access>read-write</access>
                            <enumeratedValues>
                                </enumeratedValues>
                        </field>
                    </fields>
                </register>
                <register>
                    <dim>6</dim>
                    <dimIncrement>0x4</dimIncrement>
                    <dimIndex>10-15</dimIndex>
                    <name>P3%sPFS_BY</name>
                    <description>Port 3%s Pin Function Select Register</description>
                    <alternateRegister>P3%sPFS</alternateRegister>
                    <addressOffset>0x0EB</addressOffset>
                    <size>8</size>
                    <access>read-write</access>
                    <resetValue>0x00</resetValue>
                    <resetMask>0xfd</resetMask>
                    <fields>
                        <field>
                            <name>PODR</name>
                            <description>Port Output Data</description>
                            <lsb>0</lsb>
                            <msb>0</msb>
                            <access>read-write</access>
                            <enumeratedValues>
                                </enumeratedValues>
                        </field>
                        <field>
                            <name>PIDR</name>
                            <description>Port State</description>
                            <lsb>1</lsb>
                            <msb>1</msb>
                            <access>read-only</access>
                            <enumeratedValues>
                                </enumeratedValues>
                        </field>
                        <field>
                            <name>PDR</name>
                            <description>Port Direction</description>
                            <lsb>2</lsb>
                            <msb>2</msb>
                            <access>read-write</access>
                            <enumeratedValues>
                                </enumeratedValues>
                        </field>
                        <field>
                            <name>PCR</name>
                            <description>Pull,up Control</description>
                            <lsb>4</lsb>
                            <msb>4</msb>
                            <access>read-write</access>
                            <enumeratedValues>
                                </enumeratedValues>
                        </field>
                        <field>
                            <name>NCODR</name>
                            <description>N,Channel Open,Drain Control</description>
                            <lsb>6</lsb>
                            <msb>6</msb>
                            <access>read-write</access>
                            <enumeratedValues>
                                </enumeratedValues>
                        </field>
                    </fields>
                </register>
                <register>
                    <dim>10</dim>
                    <dimIncrement>0x4</dimIncrement>
                    <dimIndex>0-9</dimIndex>
                    <name>P40%sPFS</name>
                    <description>Port 40%s Pin Function Select Register</description>
                    <addressOffset>0x100</addressOffset>
                    <size>32</size>
                    <access>read-write</access>
                    <resetValue>0x00000000</resetValue>
                    <resetMask>0xfffffffd</resetMask>
                    <fields>
                        <field>
                            <name>PODR</name>
                            <description>Port Output Data</description>
                            <lsb>0</lsb>
                            <msb>0</msb>
                            <access>read-write</access>
                            <enumeratedValues>
                                </enumeratedValues>
                        </field>
                        <field>
                            <name>PIDR</name>
                            <description>Port State</description>
                            <lsb>1</lsb>
                            <msb>1</msb>
                            <access>read-only</access>
                            <enumeratedValues>
                                </enumeratedValues>
                        </field>
                        <field>
                            <name>PDR</name>
                            <description>Port Direction</description>
                            <lsb>2</lsb>
                            <msb>2</msb>
                            <access>read-write</access>
                            <enumeratedValues>
                                </enumeratedValues>
                        </field>
                        <field>
                            <name>PCR</name>
                            <description>Pull,up Control</description>
                            <lsb>4</lsb>
                            <msb>4</msb>
                            <access>read-write</access>
                            <enumeratedValues>
                                </enumeratedValues>
                        </field>
                        <field>
                            <name>NCODR</name>
                            <description>N,Channel Open,Drain Control</description>
                            <lsb>6</lsb>
                            <msb>6</msb>
                            <access>read-write</access>
                            <enumeratedValues>
                                </enumeratedValues>
                        </field>
                        <field>
                            <name>EOFR</name>
                            <description>Event on Falling/Event on Rising</description>
                            <lsb>12</lsb>
                            <msb>13</msb>
                            <access>read-write</access>
                            <enumeratedValues>
                                </enumeratedValues>
                        </field>
                        <field>
                            <name>ISEL</name>
                            <description>IRQ Input Enable</description>
                            <lsb>14</lsb>
                            <msb>14</msb>
                            <access>read-write</access>
                            <enumeratedValues>
                                </enumeratedValues>
                        </field>
                        <field>
                            <name>ASEL</name>
                            <description>Analog Input Enable</description>
                            <lsb>15</lsb>
                            <msb>15</msb>
                            <access>read-write</access>
                            <enumeratedValues>
                                </enumeratedValues>
                        </field>
                        <field>
                            <name>PMR</name>
                            <description>Port Mode Control</description>
                            <lsb>16</lsb>
                            <msb>16</msb>
                            <access>read-write</access>
                            <enumeratedValues>
                                </enumeratedValues>
                        </field>
                        <field>
                            <name>PSEL</name>
                            <description>Peripheral Select</description>
                            <lsb>24</lsb>
                            <msb>28</msb>
                            <access>read-write</access>
                        </field>
                    </fields>
                </register>
                <register>
                    <dim>10</dim>
                    <dimIncrement>0x4</dimIncrement>
                    <dimIndex>0-9</dimIndex>
                    <name>P40%sPFS_HA</name>
                    <description>Port 40%s Pin Function Select Register</description>
                    <alternateRegister>P40%sPFS</alternateRegister>
                    <addressOffset>0x102</addressOffset>
                    <size>16</size>
                    <access>read-write</access>
                    <resetValue>0x0000</resetValue>
                    <resetMask>0xfffd</resetMask>
                    <fields>
                        <field>
                            <name>PODR</name>
                            <description>Port Output Data</description>
                            <lsb>0</lsb>
                            <msb>0</msb>
                            <access>read-write</access>
                            <enumeratedValues>
                                </enumeratedValues>
                        </field>
                        <field>
                            <name>PIDR</name>
                            <description>Port State</description>
                            <lsb>1</lsb>
                            <msb>1</msb>
                            <access>read-only</access>
                            <enumeratedValues>
                                </enumeratedValues>
                        </field>
                        <field>
                            <name>PDR</name>
                            <description>Port Direction</description>
                            <lsb>2</lsb>
                            <msb>2</msb>
                            <access>read-write</access>
                            <enumeratedValues>
                                </enumeratedValues>
                        </field>
                        <field>
                            <name>PCR</name>
                            <description>Pull,up Control</description>
                            <lsb>4</lsb>
                            <msb>4</msb>
                            <access>read-write</access>
                            <enumeratedValues>
                                </enumeratedValues>
                        </field>
                        <field>
                            <name>NCODR</name>
                            <description>N,Channel Open,Drain Control</description>
                            <lsb>6</lsb>
                            <msb>6</msb>
                            <access>read-write</access>
                            <enumeratedValues>
                                </enumeratedValues>
                        </field>
                        <field>
                            <name>EOFR</name>
                            <description>Event on Falling/Event on Rising</description>
                            <lsb>12</lsb>
                            <msb>13</msb>
                            <access>read-write</access>
                            <enumeratedValues>
                                </enumeratedValues>
                        </field>
                        <field>
                            <name>ISEL</name>
                            <description>IRQ Input Enable</description>
                            <lsb>14</lsb>
                            <msb>14</msb>
                            <access>read-write</access>
                            <enumeratedValues>
                                </enumeratedValues>
                        </field>
                        <field>
                            <name>ASEL</name>
                            <description>Analog Input Enable</description>
                            <lsb>15</lsb>
                            <msb>15</msb>
                            <access>read-write</access>
                            <enumeratedValues>
                                </enumeratedValues>
                        </field>
                    </fields>
                </register>
                <register>
                    <dim>10</dim>
                    <dimIncrement>0x4</dimIncrement>
                    <dimIndex>0-9</dimIndex>
                    <name>P40%sPFS_BY</name>
                    <description>Port 40%s Pin Function Select Register</description>
                    <alternateRegister>P40%sPFS</alternateRegister>
                    <addressOffset>0x103</addressOffset>
                    <size>8</size>
                    <access>read-write</access>
                    <resetValue>0x00</resetValue>
                    <resetMask>0xfd</resetMask>
                    <fields>
                        <field>
                            <name>PODR</name>
                            <description>Port Output Data</description>
                            <lsb>0</lsb>
                            <msb>0</msb>
                            <access>read-write</access>
                            <enumeratedValues>
                                </enumeratedValues>
                        </field>
                        <field>
                            <name>PIDR</name>
                            <description>Port State</description>
                            <lsb>1</lsb>
                            <msb>1</msb>
                            <access>read-only</access>
                            <enumeratedValues>
                                </enumeratedValues>
                        </field>
                        <field>
                            <name>PDR</name>
                            <description>Port Direction</description>
                            <lsb>2</lsb>
                            <msb>2</msb>
                            <access>read-write</access>
                            <enumeratedValues>
                                </enumeratedValues>
                        </field>
                        <field>
                            <name>PCR</name>
                            <description>Pull,up Control</description>
                            <lsb>4</lsb>
                            <msb>4</msb>
                            <access>read-write</access>
                            <enumeratedValues>
                                </enumeratedValues>
                        </field>
                        <field>
                            <name>NCODR</name>
                            <description>N,Channel Open,Drain Control</description>
                            <lsb>6</lsb>
                            <msb>6</msb>
                            <access>read-write</access>
                            <enumeratedValues>
                                </enumeratedValues>
                        </field>
                    </fields>
                </register>
                <register>
                    <dim>6</dim>
                    <dimIncrement>0x4</dimIncrement>
                    <dimIndex>10-15</dimIndex>
                    <name>P4%sPFS</name>
                    <description>Port 4%s Pin Function Select Register</description>
                    <addressOffset>0x128</addressOffset>
                    <size>32</size>
                    <access>read-write</access>
                    <resetValue>0x00000000</resetValue>
                    <resetMask>0xfffffffd</resetMask>
                    <fields>
                        <field>
                            <name>PODR</name>
                            <description>Port Output Data</description>
                            <lsb>0</lsb>
                            <msb>0</msb>
                            <access>read-write</access>
                            <enumeratedValues>
                                </enumeratedValues>
                        </field>
                        <field>
                            <name>PIDR</name>
                            <description>Port State</description>
                            <lsb>1</lsb>
                            <msb>1</msb>
                            <access>read-only</access>
                            <enumeratedValues>
                                </enumeratedValues>
                        </field>
                        <field>
                            <name>PDR</name>
                            <description>Port Direction</description>
                            <lsb>2</lsb>
                            <msb>2</msb>
                            <access>read-write</access>
                            <enumeratedValues>
                                </enumeratedValues>
                        </field>
                        <field>
                            <name>PCR</name>
                            <description>Pull,up Control</description>
                            <lsb>4</lsb>
                            <msb>4</msb>
                            <access>read-write</access>
                            <enumeratedValues>
                                </enumeratedValues>
                        </field>
                        <field>
                            <name>NCODR</name>
                            <description>N,Channel Open,Drain Control</description>
                            <lsb>6</lsb>
                            <msb>6</msb>
                            <access>read-write</access>
                            <enumeratedValues>
                                </enumeratedValues>
                        </field>
                        <field>
                            <name>EOFR</name>
                            <description>Event on Falling/Event on Rising</description>
                            <lsb>12</lsb>
                            <msb>13</msb>
                            <access>read-write</access>
                            <enumeratedValues>
                                </enumeratedValues>
                        </field>
                        <field>
                            <name>ISEL</name>
                            <description>IRQ Input Enable</description>
                            <lsb>14</lsb>
                            <msb>14</msb>
                            <access>read-write</access>
                            <enumeratedValues>
                                </enumeratedValues>
                        </field>
                        <field>
                            <name>ASEL</name>
                            <description>Analog Input Enable</description>
                            <lsb>15</lsb>
                            <msb>15</msb>
                            <access>read-write</access>
                            <enumeratedValues>
                                </enumeratedValues>
                        </field>
                        <field>
                            <name>PMR</name>
                            <description>Port Mode Control</description>
                            <lsb>16</lsb>
                            <msb>16</msb>
                            <access>read-write</access>
                            <enumeratedValues>
                                </enumeratedValues>
                        </field>
                        <field>
                            <name>PSEL</name>
                            <description>Peripheral Select</description>
                            <lsb>24</lsb>
                            <msb>28</msb>
                            <access>read-write</access>
                        </field>
                    </fields>
                </register>
                <register>
                    <dim>6</dim>
                    <dimIncrement>0x4</dimIncrement>
                    <dimIndex>10-15</dimIndex>
                    <name>P4%sPFS_HA</name>
                    <description>Port 4%s Pin Function Select Register</description>
                    <alternateRegister>P4%sPFS</alternateRegister>
                    <addressOffset>0x12A</addressOffset>
                    <size>16</size>
                    <access>read-write</access>
                    <resetValue>0x0000</resetValue>
                    <resetMask>0xfffd</resetMask>
                    <fields>
                        <field>
                            <name>PODR</name>
                            <description>Port Output Data</description>
                            <lsb>0</lsb>
                            <msb>0</msb>
                            <access>read-write</access>
                            <enumeratedValues>
                                </enumeratedValues>
                        </field>
                        <field>
                            <name>PIDR</name>
                            <description>Port State</description>
                            <lsb>1</lsb>
                            <msb>1</msb>
                            <access>read-only</access>
                            <enumeratedValues>
                                </enumeratedValues>
                        </field>
                        <field>
                            <name>PDR</name>
                            <description>Port Direction</description>
                            <lsb>2</lsb>
                            <msb>2</msb>
                            <access>read-write</access>
                            <enumeratedValues>
                                </enumeratedValues>
                        </field>
                        <field>
                            <name>PCR</name>
                            <description>Pull,up Control</description>
                            <lsb>4</lsb>
                            <msb>4</msb>
                            <access>read-write</access>
                            <enumeratedValues>
                                </enumeratedValues>
                        </field>
                        <field>
                            <name>NCODR</name>
                            <description>N,Channel Open,Drain Control</description>
                            <lsb>6</lsb>
                            <msb>6</msb>
                            <access>read-write</access>
                            <enumeratedValues>
                                </enumeratedValues>
                        </field>
                        <field>
                            <name>EOFR</name>
                            <description>Event on Falling/Event on Rising</description>
                            <lsb>12</lsb>
                            <msb>13</msb>
                            <access>read-write</access>
                            <enumeratedValues>
                                </enumeratedValues>
                        </field>
                        <field>
                            <name>ISEL</name>
                            <description>IRQ Input Enable</description>
                            <lsb>14</lsb>
                            <msb>14</msb>
                            <access>read-write</access>
                            <enumeratedValues>
                                </enumeratedValues>
                        </field>
                        <field>
                            <name>ASEL</name>
                            <description>Analog Input Enable</description>
                            <lsb>15</lsb>
                            <msb>15</msb>
                            <access>read-write</access>
                            <enumeratedValues>
                                </enumeratedValues>
                        </field>
                    </fields>
                </register>
                <register>
                    <dim>6</dim>
                    <dimIncrement>0x4</dimIncrement>
                    <dimIndex>10-15</dimIndex>
                    <name>P4%sPFS_BY</name>
                    <description>Port 4%s Pin Function Select Register</description>
                    <alternateRegister>P4%sPFS</alternateRegister>
                    <addressOffset>0x12B</addressOffset>
                    <size>8</size>
                    <access>read-write</access>
                    <resetValue>0x00</resetValue>
                    <resetMask>0xfd</resetMask>
                    <fields>
                        <field>
                            <name>PODR</name>
                            <description>Port Output Data</description>
                            <lsb>0</lsb>
                            <msb>0</msb>
                            <access>read-write</access>
                            <enumeratedValues>
                                </enumeratedValues>
                        </field>
                        <field>
                            <name>PIDR</name>
                            <description>Port State</description>
                            <lsb>1</lsb>
                            <msb>1</msb>
                            <access>read-only</access>
                            <enumeratedValues>
                                </enumeratedValues>
                        </field>
                        <field>
                            <name>PDR</name>
                            <description>Port Direction</description>
                            <lsb>2</lsb>
                            <msb>2</msb>
                            <access>read-write</access>
                            <enumeratedValues>
                                </enumeratedValues>
                        </field>
                        <field>
                            <name>PCR</name>
                            <description>Pull,up Control</description>
                            <lsb>4</lsb>
                            <msb>4</msb>
                            <access>read-write</access>
                            <enumeratedValues>
                                </enumeratedValues>
                        </field>
                        <field>
                            <name>NCODR</name>
                            <description>N,Channel Open,Drain Control</description>
                            <lsb>6</lsb>
                            <msb>6</msb>
                            <access>read-write</access>
                            <enumeratedValues>
                                </enumeratedValues>
                        </field>
                    </fields>
                </register>
                <register>
                    <dim>9</dim>
                    <dimIncrement>0x4</dimIncrement>
                    <dimIndex>0-8</dimIndex>
                    <name>P50%sPFS</name>
                    <description>Port 50%s Pin Function Select Register</description>
                    <addressOffset>0x140</addressOffset>
                    <size>32</size>
                    <access>read-write</access>
                    <resetValue>0x00000000</resetValue>
                    <resetMask>0xfffffffd</resetMask>
                    <fields>
                        <field>
                            <name>PODR</name>
                            <description>Port Output Data</description>
                            <lsb>0</lsb>
                            <msb>0</msb>
                            <access>read-write</access>
                            <enumeratedValues>
                                </enumeratedValues>
                        </field>
                        <field>
                            <name>PIDR</name>
                            <description>Port State</description>
                            <lsb>1</lsb>
                            <msb>1</msb>
                            <access>read-only</access>
                            <enumeratedValues>
                                </enumeratedValues>
                        </field>
                        <field>
                            <name>PDR</name>
                            <description>Port Direction</description>
                            <lsb>2</lsb>
                            <msb>2</msb>
                            <access>read-write</access>
                            <enumeratedValues>
                                </enumeratedValues>
                        </field>
                        <field>
                            <name>PCR</name>
                            <description>Pull,up Control</description>
                            <lsb>4</lsb>
                            <msb>4</msb>
                            <access>read-write</access>
                            <enumeratedValues>
                                </enumeratedValues>
                        </field>
                        <field>
                            <name>NCODR</name>
                            <description>N,Channel Open,Drain Control</description>
                            <lsb>6</lsb>
                            <msb>6</msb>
                            <access>read-write</access>
                            <enumeratedValues>
                                </enumeratedValues>
                        </field>
                        <field>
                            <name>ISEL</name>
                            <description>IRQ Input Enable</description>
                            <lsb>14</lsb>
                            <msb>14</msb>
                            <access>read-write</access>
                            <enumeratedValues>
                                </enumeratedValues>
                        </field>
                        <field>
                            <name>ASEL</name>
                            <description>Analog Input Enable</description>
                            <lsb>15</lsb>
                            <msb>15</msb>
                            <access>read-write</access>
                            <enumeratedValues>
                                </enumeratedValues>
                        </field>
                        <field>
                            <name>PMR</name>
                            <description>Port Mode Control</description>
                            <lsb>16</lsb>
                            <msb>16</msb>
                            <access>read-write</access>
                            <enumeratedValues>
                                </enumeratedValues>
                        </field>
                        <field>
                            <name>PSEL</name>
                            <description>Peripheral Select</description>
                            <lsb>24</lsb>
                            <msb>28</msb>
                            <access>read-write</access>
                        </field>
                    </fields>
                </register>
                <register>
                    <dim>9</dim>
                    <dimIncrement>0x4</dimIncrement>
                    <dimIndex>0-8</dimIndex>
                    <name>P50%sPFS_HA</name>
                    <description>Port 50%s Pin Function Select Register</description>
                    <alternateRegister>P50%sPFS</alternateRegister>
                    <addressOffset>0x142</addressOffset>
                    <size>16</size>
                    <access>read-write</access>
                    <resetValue>0x0000</resetValue>
                    <resetMask>0xfffd</resetMask>
                    <fields>
                        <field>
                            <name>PODR</name>
                            <description>Port Output Data</description>
                            <lsb>0</lsb>
                            <msb>0</msb>
                            <access>read-write</access>
                            <enumeratedValues>
                                </enumeratedValues>
                        </field>
                        <field>
                            <name>PIDR</name>
                            <description>Port State</description>
                            <lsb>1</lsb>
                            <msb>1</msb>
                            <access>read-only</access>
                            <enumeratedValues>
                                </enumeratedValues>
                        </field>
                        <field>
                            <name>PDR</name>
                            <description>Port Direction</description>
                            <lsb>2</lsb>
                            <msb>2</msb>
                            <access>read-write</access>
                            <enumeratedValues>
                                </enumeratedValues>
                        </field>
                        <field>
                            <name>PCR</name>
                            <description>Pull,up Control</description>
                            <lsb>4</lsb>
                            <msb>4</msb>
                            <access>read-write</access>
                            <enumeratedValues>
                                </enumeratedValues>
                        </field>
                        <field>
                            <name>NCODR</name>
                            <description>N,Channel Open,Drain Control</description>
                            <lsb>6</lsb>
                            <msb>6</msb>
                            <access>read-write</access>
                            <enumeratedValues>
                                </enumeratedValues>
                        </field>
                        <field>
                            <name>ISEL</name>
                            <description>IRQ Input Enable</description>
                            <lsb>14</lsb>
                            <msb>14</msb>
                            <access>read-write</access>
                            <enumeratedValues>
                                </enumeratedValues>
                        </field>
                        <field>
                            <name>ASEL</name>
                            <description>Analog Input Enable</description>
                            <lsb>15</lsb>
                            <msb>15</msb>
                            <access>read-write</access>
                            <enumeratedValues>
                                </enumeratedValues>
                        </field>
                    </fields>
                </register>
                <register>
                    <dim>9</dim>
                    <dimIncrement>0x4</dimIncrement>
                    <dimIndex>0-8</dimIndex>
                    <name>P50%sPFS_BY</name>
                    <description>Port 50%s Pin Function Select Register</description>
                    <alternateRegister>P50%sPFS</alternateRegister>
                    <addressOffset>0x143</addressOffset>
                    <size>8</size>
                    <access>read-write</access>
                    <resetValue>0x00</resetValue>
                    <resetMask>0xfd</resetMask>
                    <fields>
                        <field>
                            <name>PODR</name>
                            <description>Port Output Data</description>
                            <lsb>0</lsb>
                            <msb>0</msb>
                            <access>read-write</access>
                            <enumeratedValues>
                                </enumeratedValues>
                        </field>
                        <field>
                            <name>PIDR</name>
                            <description>Port State</description>
                            <lsb>1</lsb>
                            <msb>1</msb>
                            <access>read-only</access>
                            <enumeratedValues>
                                </enumeratedValues>
                        </field>
                        <field>
                            <name>PDR</name>
                            <description>Port Direction</description>
                            <lsb>2</lsb>
                            <msb>2</msb>
                            <access>read-write</access>
                            <enumeratedValues>
                                </enumeratedValues>
                        </field>
                        <field>
                            <name>PCR</name>
                            <description>Pull,up Control</description>
                            <lsb>4</lsb>
                            <msb>4</msb>
                            <access>read-write</access>
                            <enumeratedValues>
                                </enumeratedValues>
                        </field>
                        <field>
                            <name>NCODR</name>
                            <description>N,Channel Open,Drain Control</description>
                            <lsb>6</lsb>
                            <msb>6</msb>
                            <access>read-write</access>
                            <enumeratedValues>
                                </enumeratedValues>
                        </field>
                    </fields>
                </register>
                <register>
                    <dim>3</dim>
                    <dimIncrement>0x4</dimIncrement>
                    <dimIndex>11-13</dimIndex>
                    <name>P5%sPFS</name>
                    <description>Port 5%s Pin Function Select Register</description>
                    <addressOffset>0x16C</addressOffset>
                    <size>32</size>
                    <access>read-write</access>
                    <resetValue>0x00000000</resetValue>
                    <resetMask>0xfffffffd</resetMask>
                    <fields>
                        <field>
                            <name>PODR</name>
                            <description>Port Output Data</description>
                            <lsb>0</lsb>
                            <msb>0</msb>
                            <access>read-write</access>
                            <enumeratedValues>
                                </enumeratedValues>
                        </field>
                        <field>
                            <name>PIDR</name>
                            <description>Port State</description>
                            <lsb>1</lsb>
                            <msb>1</msb>
                            <access>read-only</access>
                            <enumeratedValues>
                                </enumeratedValues>
                        </field>
                        <field>
                            <name>PDR</name>
                            <description>Port Direction</description>
                            <lsb>2</lsb>
                            <msb>2</msb>
                            <access>read-write</access>
                            <enumeratedValues>
                                </enumeratedValues>
                        </field>
                        <field>
                            <name>PCR</name>
                            <description>Pull,up Control</description>
                            <lsb>4</lsb>
                            <msb>4</msb>
                            <access>read-write</access>
                            <enumeratedValues>
                                </enumeratedValues>
                        </field>
                        <field>
                            <name>NCODR</name>
                            <description>N,Channel Open,Drain Control</description>
                            <lsb>6</lsb>
                            <msb>6</msb>
                            <access>read-write</access>
                            <enumeratedValues>
                                </enumeratedValues>
                        </field>
                        <field>
                            <name>ISEL</name>
                            <description>IRQ Input Enable</description>
                            <lsb>14</lsb>
                            <msb>14</msb>
                            <access>read-write</access>
                            <enumeratedValues>
                                </enumeratedValues>
                        </field>
                        <field>
                            <name>ASEL</name>
                            <description>Analog Input Enable</description>
                            <lsb>15</lsb>
                            <msb>15</msb>
                            <access>read-write</access>
                            <enumeratedValues>
                                </enumeratedValues>
                        </field>
                        <field>
                            <name>PMR</name>
                            <description>Port Mode Control</description>
                            <lsb>16</lsb>
                            <msb>16</msb>
                            <access>read-write</access>
                            <enumeratedValues>
                                </enumeratedValues>
                        </field>
                        <field>
                            <name>PSEL</name>
                            <description>Peripheral Select</description>
                            <lsb>24</lsb>
                            <msb>28</msb>
                            <access>read-write</access>
                        </field>
                    </fields>
                </register>
                <register>
                    <dim>3</dim>
                    <dimIncrement>0x4</dimIncrement>
                    <dimIndex>11-13</dimIndex>
                    <name>P5%sPFS_HA</name>
                    <description>Port 5%s Pin Function Select Register</description>
                    <alternateRegister>P5%sPFS</alternateRegister>
                    <addressOffset>0x16E</addressOffset>
                    <size>16</size>
                    <access>read-write</access>
                    <resetValue>0x0000</resetValue>
                    <resetMask>0xfffd</resetMask>
                    <fields>
                        <field>
                            <name>PODR</name>
                            <description>Port Output Data</description>
                            <lsb>0</lsb>
                            <msb>0</msb>
                            <access>read-write</access>
                            <enumeratedValues>
                                </enumeratedValues>
                        </field>
                        <field>
                            <name>PIDR</name>
                            <description>Port State</description>
                            <lsb>1</lsb>
                            <msb>1</msb>
                            <access>read-only</access>
                            <enumeratedValues>
                                </enumeratedValues>
                        </field>
                        <field>
                            <name>PDR</name>
                            <description>Port Direction</description>
                            <lsb>2</lsb>
                            <msb>2</msb>
                            <access>read-write</access>
                            <enumeratedValues>
                                </enumeratedValues>
                        </field>
                        <field>
                            <name>PCR</name>
                            <description>Pull,up Control</description>
                            <lsb>4</lsb>
                            <msb>4</msb>
                            <access>read-write</access>
                            <enumeratedValues>
                                </enumeratedValues>
                        </field>
                        <field>
                            <name>NCODR</name>
                            <description>N,Channel Open,Drain Control</description>
                            <lsb>6</lsb>
                            <msb>6</msb>
                            <access>read-write</access>
                            <enumeratedValues>
                                </enumeratedValues>
                        </field>
                        <field>
                            <name>ISEL</name>
                            <description>IRQ Input Enable</description>
                            <lsb>14</lsb>
                            <msb>14</msb>
                            <access>read-write</access>
                            <enumeratedValues>
                                </enumeratedValues>
                        </field>
                        <field>
                            <name>ASEL</name>
                            <description>Analog Input Enable</description>
                            <lsb>15</lsb>
                            <msb>15</msb>
                            <access>read-write</access>
                            <enumeratedValues>
                                </enumeratedValues>
                        </field>
                    </fields>
                </register>
                <register>
                    <dim>3</dim>
                    <dimIncrement>0x4</dimIncrement>
                    <dimIndex>11-13</dimIndex>
                    <name>P5%sPFS_BY</name>
                    <description>Port 5%s Pin Function Select Register</description>
                    <alternateRegister>P5%sPFS</alternateRegister>
                    <addressOffset>0x16F</addressOffset>
                    <size>8</size>
                    <access>read-write</access>
                    <resetValue>0x00</resetValue>
                    <resetMask>0xfd</resetMask>
                    <fields>
                        <field>
                            <name>PODR</name>
                            <description>Port Output Data</description>
                            <lsb>0</lsb>
                            <msb>0</msb>
                            <access>read-write</access>
                            <enumeratedValues>
                                </enumeratedValues>
                        </field>
                        <field>
                            <name>PIDR</name>
                            <description>Port State</description>
                            <lsb>1</lsb>
                            <msb>1</msb>
                            <access>read-only</access>
                            <enumeratedValues>
                                </enumeratedValues>
                        </field>
                        <field>
                            <name>PDR</name>
                            <description>Port Direction</description>
                            <lsb>2</lsb>
                            <msb>2</msb>
                            <access>read-write</access>
                            <enumeratedValues>
                                </enumeratedValues>
                        </field>
                        <field>
                            <name>PCR</name>
                            <description>Pull,up Control</description>
                            <lsb>4</lsb>
                            <msb>4</msb>
                            <access>read-write</access>
                            <enumeratedValues>
                                </enumeratedValues>
                        </field>
                        <field>
                            <name>NCODR</name>
                            <description>N,Channel Open,Drain Control</description>
                            <lsb>6</lsb>
                            <msb>6</msb>
                            <access>read-write</access>
                            <enumeratedValues>
                                </enumeratedValues>
                        </field>
                    </fields>
                </register>
                <register>
                    <dim>10</dim>
                    <dimIncrement>0x4</dimIncrement>
                    <dimIndex>0-9</dimIndex>
                    <name>P60%sPFS</name>
                    <description>Port 60%s Pin Function Select Register</description>
                    <addressOffset>0x180</addressOffset>
                    <size>32</size>
                    <access>read-write</access>
                    <resetValue>0x00000000</resetValue>
                    <resetMask>0xfffffffd</resetMask>
                    <fields>
                        <field>
                            <name>PODR</name>
                            <description>Port Output Data</description>
                            <lsb>0</lsb>
                            <msb>0</msb>
                            <access>read-write</access>
                            <enumeratedValues>
                                </enumeratedValues>
                        </field>
                        <field>
                            <name>PIDR</name>
                            <description>Port State</description>
                            <lsb>1</lsb>
                            <msb>1</msb>
                            <access>read-only</access>
                            <enumeratedValues>
                                </enumeratedValues>
                        </field>
                        <field>
                            <name>PDR</name>
                            <description>Port Direction</description>
                            <lsb>2</lsb>
                            <msb>2</msb>
                            <access>read-write</access>
                            <enumeratedValues>
                                </enumeratedValues>
                        </field>
                        <field>
                            <name>PCR</name>
                            <description>Pull,up Control</description>
                            <lsb>4</lsb>
                            <msb>4</msb>
                            <access>read-write</access>
                            <enumeratedValues>
                                </enumeratedValues>
                        </field>
                        <field>
                            <name>NCODR</name>
                            <description>N,Channel Open,Drain Control</description>
                            <lsb>6</lsb>
                            <msb>6</msb>
                            <access>read-write</access>
                            <enumeratedValues>
                                </enumeratedValues>
                        </field>
                        <field>
                            <name>ISEL</name>
                            <description>IRQ Input Enable</description>
                            <lsb>14</lsb>
                            <msb>14</msb>
                            <access>read-write</access>
                            <enumeratedValues>
                                </enumeratedValues>
                        </field>
                        <field>
                            <name>ASEL</name>
                            <description>Analog Input Enable</description>
                            <lsb>15</lsb>
                            <msb>15</msb>
                            <access>read-write</access>
                            <enumeratedValues>
                                </enumeratedValues>
                        </field>
                        <field>
                            <name>PMR</name>
                            <description>Port Mode Control</description>
                            <lsb>16</lsb>
                            <msb>16</msb>
                            <access>read-write</access>
                            <enumeratedValues>
                                </enumeratedValues>
                        </field>
                        <field>
                            <name>PSEL</name>
                            <description>Peripheral Select</description>
                            <lsb>24</lsb>
                            <msb>28</msb>
                            <access>read-write</access>
                        </field>
                    </fields>
                </register>
                <register>
                    <dim>10</dim>
                    <dimIncrement>0x4</dimIncrement>
                    <dimIndex>0-9</dimIndex>
                    <name>P60%sPFS_HA</name>
                    <description>Port 60%s Pin Function Select Register</description>
                    <alternateRegister>P60%sPFS</alternateRegister>
                    <addressOffset>0x182</addressOffset>
                    <size>16</size>
                    <access>read-write</access>
                    <resetValue>0x0000</resetValue>
                    <resetMask>0xfffd</resetMask>
                    <fields>
                        <field>
                            <name>PODR</name>
                            <description>Port Output Data</description>
                            <lsb>0</lsb>
                            <msb>0</msb>
                            <access>read-write</access>
                            <enumeratedValues>
                                </enumeratedValues>
                        </field>
                        <field>
                            <name>PIDR</name>
                            <description>Port State</description>
                            <lsb>1</lsb>
                            <msb>1</msb>
                            <access>read-only</access>
                            <enumeratedValues>
                                </enumeratedValues>
                        </field>
                        <field>
                            <name>PDR</name>
                            <description>Port Direction</description>
                            <lsb>2</lsb>
                            <msb>2</msb>
                            <access>read-write</access>
                            <enumeratedValues>
                                </enumeratedValues>
                        </field>
                        <field>
                            <name>PCR</name>
                            <description>Pull,up Control</description>
                            <lsb>4</lsb>
                            <msb>4</msb>
                            <access>read-write</access>
                            <enumeratedValues>
                                </enumeratedValues>
                        </field>
                        <field>
                            <name>NCODR</name>
                            <description>N,Channel Open,Drain Control</description>
                            <lsb>6</lsb>
                            <msb>6</msb>
                            <access>read-write</access>
                            <enumeratedValues>
                                </enumeratedValues>
                        </field>
                        <field>
                            <name>ISEL</name>
                            <description>IRQ Input Enable</description>
                            <lsb>14</lsb>
                            <msb>14</msb>
                            <access>read-write</access>
                            <enumeratedValues>
                                </enumeratedValues>
                        </field>
                        <field>
                            <name>ASEL</name>
                            <description>Analog Input Enable</description>
                            <lsb>15</lsb>
                            <msb>15</msb>
                            <access>read-write</access>
                            <enumeratedValues>
                                </enumeratedValues>
                        </field>
                    </fields>
                </register>
                <register>
                    <dim>10</dim>
                    <dimIncrement>0x4</dimIncrement>
                    <dimIndex>0-9</dimIndex>
                    <name>P60%sPFS_BY</name>
                    <description>Port 60%s Pin Function Select Register</description>
                    <alternateRegister>P60%sPFS</alternateRegister>
                    <addressOffset>0x183</addressOffset>
                    <size>8</size>
                    <access>read-write</access>
                    <resetValue>0x00</resetValue>
                    <resetMask>0xfd</resetMask>
                    <fields>
                        <field>
                            <name>PODR</name>
                            <description>Port Output Data</description>
                            <lsb>0</lsb>
                            <msb>0</msb>
                            <access>read-write</access>
                            <enumeratedValues>
                                </enumeratedValues>
                        </field>
                        <field>
                            <name>PIDR</name>
                            <description>Port State</description>
                            <lsb>1</lsb>
                            <msb>1</msb>
                            <access>read-only</access>
                            <enumeratedValues>
                                </enumeratedValues>
                        </field>
                        <field>
                            <name>PDR</name>
                            <description>Port Direction</description>
                            <lsb>2</lsb>
                            <msb>2</msb>
                            <access>read-write</access>
                            <enumeratedValues>
                                </enumeratedValues>
                        </field>
                        <field>
                            <name>PCR</name>
                            <description>Pull,up Control</description>
                            <lsb>4</lsb>
                            <msb>4</msb>
                            <access>read-write</access>
                            <enumeratedValues>
                                </enumeratedValues>
                        </field>
                        <field>
                            <name>NCODR</name>
                            <description>N,Channel Open,Drain Control</description>
                            <lsb>6</lsb>
                            <msb>6</msb>
                            <access>read-write</access>
                            <enumeratedValues>
                                </enumeratedValues>
                        </field>
                    </fields>
                </register>
                <register>
                    <dim>6</dim>
                    <dimIncrement>0x4</dimIncrement>
                    <dimIndex>10-15</dimIndex>
                    <name>P6%sPFS</name>
                    <description>Port 6%s Pin Function Select Register</description>
                    <addressOffset>0x1A8</addressOffset>
                    <size>32</size>
                    <access>read-write</access>
                    <resetValue>0x00000000</resetValue>
                    <resetMask>0xfffffffd</resetMask>
                    <fields>
                        <field>
                            <name>PODR</name>
                            <description>Port Output Data</description>
                            <lsb>0</lsb>
                            <msb>0</msb>
                            <access>read-write</access>
                            <enumeratedValues>
                                </enumeratedValues>
                        </field>
                        <field>
                            <name>PIDR</name>
                            <description>Port State</description>
                            <lsb>1</lsb>
                            <msb>1</msb>
                            <access>read-only</access>
                            <enumeratedValues>
                                </enumeratedValues>
                        </field>
                        <field>
                            <name>PDR</name>
                            <description>Port Direction</description>
                            <lsb>2</lsb>
                            <msb>2</msb>
                            <access>read-write</access>
                            <enumeratedValues>
                                </enumeratedValues>
                        </field>
                        <field>
                            <name>PCR</name>
                            <description>Pull,up Control</description>
                            <lsb>4</lsb>
                            <msb>4</msb>
                            <access>read-write</access>
                            <enumeratedValues>
                                </enumeratedValues>
                        </field>
                        <field>
                            <name>NCODR</name>
                            <description>N,Channel Open,Drain Control</description>
                            <lsb>6</lsb>
                            <msb>6</msb>
                            <access>read-write</access>
                            <enumeratedValues>
                                </enumeratedValues>
                        </field>
                        <field>
                            <name>ISEL</name>
                            <description>IRQ Input Enable</description>
                            <lsb>14</lsb>
                            <msb>14</msb>
                            <access>read-write</access>
                            <enumeratedValues>
                                </enumeratedValues>
                        </field>
                        <field>
                            <name>ASEL</name>
                            <description>Analog Input Enable</description>
                            <lsb>15</lsb>
                            <msb>15</msb>
                            <access>read-write</access>
                            <enumeratedValues>
                                </enumeratedValues>
                        </field>
                        <field>
                            <name>PMR</name>
                            <description>Port Mode Control</description>
                            <lsb>16</lsb>
                            <msb>16</msb>
                            <access>read-write</access>
                            <enumeratedValues>
                                </enumeratedValues>
                        </field>
                        <field>
                            <name>PSEL</name>
                            <description>Peripheral Select</description>
                            <lsb>24</lsb>
                            <msb>28</msb>
                            <access>read-write</access>
                        </field>
                    </fields>
                </register>
                <register>
                    <dim>6</dim>
                    <dimIncrement>0x4</dimIncrement>
                    <dimIndex>10-15</dimIndex>
                    <name>P6%sPFS_HA</name>
                    <description>Port 6%s Pin Function Select Register</description>
                    <alternateRegister>P6%sPFS</alternateRegister>
                    <addressOffset>0x1AA</addressOffset>
                    <size>16</size>
                    <access>read-write</access>
                    <resetValue>0x0000</resetValue>
                    <resetMask>0xfffd</resetMask>
                    <fields>
                        <field>
                            <name>PODR</name>
                            <description>Port Output Data</description>
                            <lsb>0</lsb>
                            <msb>0</msb>
                            <access>read-write</access>
                            <enumeratedValues>
                                </enumeratedValues>
                        </field>
                        <field>
                            <name>PIDR</name>
                            <description>Port State</description>
                            <lsb>1</lsb>
                            <msb>1</msb>
                            <access>read-only</access>
                            <enumeratedValues>
                                </enumeratedValues>
                        </field>
                        <field>
                            <name>PDR</name>
                            <description>Port Direction</description>
                            <lsb>2</lsb>
                            <msb>2</msb>
                            <access>read-write</access>
                            <enumeratedValues>
                                </enumeratedValues>
                        </field>
                        <field>
                            <name>PCR</name>
                            <description>Pull,up Control</description>
                            <lsb>4</lsb>
                            <msb>4</msb>
                            <access>read-write</access>
                            <enumeratedValues>
                                </enumeratedValues>
                        </field>
                        <field>
                            <name>NCODR</name>
                            <description>N,Channel Open,Drain Control</description>
                            <lsb>6</lsb>
                            <msb>6</msb>
                            <access>read-write</access>
                            <enumeratedValues>
                                </enumeratedValues>
                        </field>
                        <field>
                            <name>ISEL</name>
                            <description>IRQ Input Enable</description>
                            <lsb>14</lsb>
                            <msb>14</msb>
                            <access>read-write</access>
                            <enumeratedValues>
                                </enumeratedValues>
                        </field>
                        <field>
                            <name>ASEL</name>
                            <description>Analog Input Enable</description>
                            <lsb>15</lsb>
                            <msb>15</msb>
                            <access>read-write</access>
                            <enumeratedValues>
                                </enumeratedValues>
                        </field>
                    </fields>
                </register>
                <register>
                    <dim>6</dim>
                    <dimIncrement>0x4</dimIncrement>
                    <dimIndex>10-15</dimIndex>
                    <name>P6%sPFS_BY</name>
                    <description>Port 6%s Pin Function Select Register</description>
                    <alternateRegister>P6%sPFS</alternateRegister>
                    <addressOffset>0x1AB</addressOffset>
                    <size>8</size>
                    <access>read-write</access>
                    <resetValue>0x00</resetValue>
                    <resetMask>0xfd</resetMask>
                    <fields>
                        <field>
                            <name>PODR</name>
                            <description>Port Output Data</description>
                            <lsb>0</lsb>
                            <msb>0</msb>
                            <access>read-write</access>
                            <enumeratedValues>
                                </enumeratedValues>
                        </field>
                        <field>
                            <name>PIDR</name>
                            <description>Port State</description>
                            <lsb>1</lsb>
                            <msb>1</msb>
                            <access>read-only</access>
                            <enumeratedValues>
                                </enumeratedValues>
                        </field>
                        <field>
                            <name>PDR</name>
                            <description>Port Direction</description>
                            <lsb>2</lsb>
                            <msb>2</msb>
                            <access>read-write</access>
                            <enumeratedValues>
                                </enumeratedValues>
                        </field>
                        <field>
                            <name>PCR</name>
                            <description>Pull,up Control</description>
                            <lsb>4</lsb>
                            <msb>4</msb>
                            <access>read-write</access>
                            <enumeratedValues>
                                </enumeratedValues>
                        </field>
                        <field>
                            <name>NCODR</name>
                            <description>N,Channel Open,Drain Control</description>
                            <lsb>6</lsb>
                            <msb>6</msb>
                            <access>read-write</access>
                            <enumeratedValues>
                                </enumeratedValues>
                        </field>
                    </fields>
                </register>
                <register>
                    <dim>8</dim>
                    <dimIncrement>0x4</dimIncrement>
                    <dimIndex>0-7</dimIndex>
                    <name>P70%sPFS</name>
                    <description>Port 70%s Pin Function Select Register</description>
                    <addressOffset>0x1C0</addressOffset>
                    <size>32</size>
                    <access>read-write</access>
                    <resetValue>0x00000000</resetValue>
                    <resetMask>0xfffffffd</resetMask>
                    <fields>
                        <field>
                            <name>PODR</name>
                            <description>Port Output Data</description>
                            <lsb>0</lsb>
                            <msb>0</msb>
                            <access>read-write</access>
                            <enumeratedValues>
                                </enumeratedValues>
                        </field>
                        <field>
                            <name>PIDR</name>
                            <description>Port State</description>
                            <lsb>1</lsb>
                            <msb>1</msb>
                            <access>read-only</access>
                            <enumeratedValues>
                                </enumeratedValues>
                        </field>
                        <field>
                            <name>PDR</name>
                            <description>Port Direction</description>
                            <lsb>2</lsb>
                            <msb>2</msb>
                            <access>read-write</access>
                            <enumeratedValues>
                                </enumeratedValues>
                        </field>
                        <field>
                            <name>PCR</name>
                            <description>Pull,up Control</description>
                            <lsb>4</lsb>
                            <msb>4</msb>
                            <access>read-write</access>
                            <enumeratedValues>
                                </enumeratedValues>
                        </field>
                        <field>
                            <name>NCODR</name>
                            <description>N,Channel Open,Drain Control</description>
                            <lsb>6</lsb>
                            <msb>6</msb>
                            <access>read-write</access>
                            <enumeratedValues>
                                </enumeratedValues>
                        </field>
                        <field>
                            <name>ISEL</name>
                            <description>IRQ Input Enable</description>
                            <lsb>14</lsb>
                            <msb>14</msb>
                            <access>read-write</access>
                            <enumeratedValues>
                                </enumeratedValues>
                        </field>
                        <field>
                            <name>ASEL</name>
                            <description>Analog Input Enable</description>
                            <lsb>15</lsb>
                            <msb>15</msb>
                            <access>read-write</access>
                            <enumeratedValues>
                                </enumeratedValues>
                        </field>
                        <field>
                            <name>PMR</name>
                            <description>Port Mode Control</description>
                            <lsb>16</lsb>
                            <msb>16</msb>
                            <access>read-write</access>
                            <enumeratedValues>
                                </enumeratedValues>
                        </field>
                        <field>
                            <name>PSEL</name>
                            <description>Peripheral Select</description>
                            <lsb>24</lsb>
                            <msb>28</msb>
                            <access>read-write</access>
                        </field>
                    </fields>
                </register>
                <register>
                    <dim>8</dim>
                    <dimIncrement>0x4</dimIncrement>
                    <dimIndex>0-7</dimIndex>
                    <name>P70%sPFS_HA</name>
                    <description>Port 70%s Pin Function Select Register</description>
                    <alternateRegister>P70%sPFS</alternateRegister>
                    <addressOffset>0x1C2</addressOffset>
                    <size>16</size>
                    <access>read-write</access>
                    <resetValue>0x0000</resetValue>
                    <resetMask>0xfffd</resetMask>
                    <fields>
                        <field>
                            <name>PODR</name>
                            <description>Port Output Data</description>
                            <lsb>0</lsb>
                            <msb>0</msb>
                            <access>read-write</access>
                            <enumeratedValues>
                                </enumeratedValues>
                        </field>
                        <field>
                            <name>PIDR</name>
                            <description>Port State</description>
                            <lsb>1</lsb>
                            <msb>1</msb>
                            <access>read-only</access>
                            <enumeratedValues>
                                </enumeratedValues>
                        </field>
                        <field>
                            <name>PDR</name>
                            <description>Port Direction</description>
                            <lsb>2</lsb>
                            <msb>2</msb>
                            <access>read-write</access>
                            <enumeratedValues>
                                </enumeratedValues>
                        </field>
                        <field>
                            <name>PCR</name>
                            <description>Pull,up Control</description>
                            <lsb>4</lsb>
                            <msb>4</msb>
                            <access>read-write</access>
                            <enumeratedValues>
                                </enumeratedValues>
                        </field>
                        <field>
                            <name>NCODR</name>
                            <description>N,Channel Open,Drain Control</description>
                            <lsb>6</lsb>
                            <msb>6</msb>
                            <access>read-write</access>
                            <enumeratedValues>
                                </enumeratedValues>
                        </field>
                        <field>
                            <name>ISEL</name>
                            <description>IRQ Input Enable</description>
                            <lsb>14</lsb>
                            <msb>14</msb>
                            <access>read-write</access>
                            <enumeratedValues>
                                </enumeratedValues>
                        </field>
                        <field>
                            <name>ASEL</name>
                            <description>Analog Input Enable</description>
                            <lsb>15</lsb>
                            <msb>15</msb>
                            <access>read-write</access>
                            <enumeratedValues>
                                </enumeratedValues>
                        </field>
                    </fields>
                </register>
                <register>
                    <dim>8</dim>
                    <dimIncrement>0x4</dimIncrement>
                    <dimIndex>0-7</dimIndex>
                    <name>P70%sPFS_BY</name>
                    <description>Port 70%s Pin Function Select Register</description>
                    <alternateRegister>P70%sPFS</alternateRegister>
                    <addressOffset>0x1C3</addressOffset>
                    <size>8</size>
                    <access>read-write</access>
                    <resetValue>0x00</resetValue>
                    <resetMask>0xfd</resetMask>
                    <fields>
                        <field>
                            <name>PODR</name>
                            <description>Port Output Data</description>
                            <lsb>0</lsb>
                            <msb>0</msb>
                            <access>read-write</access>
                            <enumeratedValues>
                                </enumeratedValues>
                        </field>
                        <field>
                            <name>PIDR</name>
                            <description>Port State</description>
                            <lsb>1</lsb>
                            <msb>1</msb>
                            <access>read-only</access>
                            <enumeratedValues>
                                </enumeratedValues>
                        </field>
                        <field>
                            <name>PDR</name>
                            <description>Port Direction</description>
                            <lsb>2</lsb>
                            <msb>2</msb>
                            <access>read-write</access>
                            <enumeratedValues>
                                </enumeratedValues>
                        </field>
                        <field>
                            <name>PCR</name>
                            <description>Pull,up Control</description>
                            <lsb>4</lsb>
                            <msb>4</msb>
                            <access>read-write</access>
                            <enumeratedValues>
                                </enumeratedValues>
                        </field>
                        <field>
                            <name>NCODR</name>
                            <description>N,Channel Open,Drain Control</description>
                            <lsb>6</lsb>
                            <msb>6</msb>
                            <access>read-write</access>
                            <enumeratedValues>
                                </enumeratedValues>
                        </field>
                    </fields>
                </register>
                <register>
                    <dim>2</dim>
                    <dimIncrement>0x4</dimIncrement>
                    <dimIndex>8-9</dimIndex>
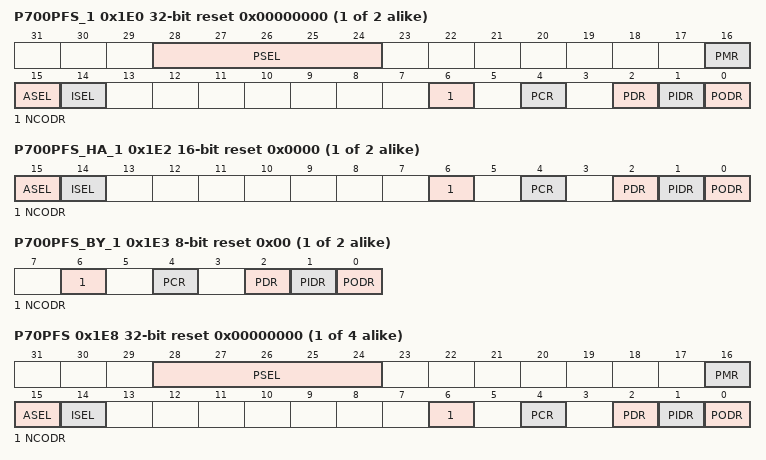
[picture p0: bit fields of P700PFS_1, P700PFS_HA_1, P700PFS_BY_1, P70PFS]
                    <name>P70%sPFS_1</name>
                    <description>Port 70%s Pin Function Select Register</description>
                    <addressOffset>0x1E0</addressOffset>
                    <size>32</size>
                    <access>read-write</access>
                    <resetValue>0x00000000</resetValue>
                    <resetMask>0xfffffffd</resetMask>
                    <fields>
                        <field>
                            <name>PODR</name>
                            <description>Port Output Data</description>
                            <lsb>0</lsb>
                            <msb>0</msb>
                            <access>read-write</access>
                            <enumeratedValues>
                                </enumeratedValues>
                        </field>
                        <field>
                            <name>PIDR</name>
                            <description>Port State</description>
                            <lsb>1</lsb>
                            <msb>1</msb>
                            <access>read-only</access>
                            <enumeratedValues>
                                </enumeratedValues>
                        </field>
                        <field>
                            <name>PDR</name>
                            <description>Port Direction</description>
                            <lsb>2</lsb>
                            <msb>2</msb>
                            <access>read-write</access>
                            <enumeratedValues>
                                </enumeratedValues>
                        </field>
                        <field>
                            <name>PCR</name>
                            <description>Pull,up Control</description>
                            <lsb>4</lsb>
                            <msb>4</msb>
                            <access>read-write</access>
                            <enumeratedValues>
                                </enumeratedValues>
                        </field>
                        <field>
                            <name>NCODR</name>
                            <description>N,Channel Open,Drain Control</description>
                            <lsb>6</lsb>
                            <msb>6</msb>
                            <access>read-write</access>
                            <enumeratedValues>
                                </enumeratedValues>
                        </field>
                        <field>
                            <name>ISEL</name>
                            <description>IRQ Input Enable</description>
                            <lsb>14</lsb>
                            <msb>14</msb>
                            <access>read-write</access>
                            <enumeratedValues>
                                </enumeratedValues>
                        </field>
                        <field>
                            <name>ASEL</name>
                            <description>Analog Input Enable</description>
                            <lsb>15</lsb>
                            <msb>15</msb>
                            <access>read-write</access>
                            <enumeratedValues>
                                </enumeratedValues>
                        </field>
                        <field>
                            <name>PMR</name>
                            <description>Port Mode Control</description>
                            <lsb>16</lsb>
                            <msb>16</msb>
                            <access>read-write</access>
                            <enumeratedValues>
                                </enumeratedValues>
                        </field>
                        <field>
                            <name>PSEL</name>
                            <description>Peripheral Select</description>
                            <lsb>24</lsb>
                            <msb>28</msb>
                            <access>read-write</access>
                        </field>
                    </fields>
                </register>
                <register>
                    <dim>2</dim>
                    <dimIncrement>0x4</dimIncrement>
                    <dimIndex>8-9</dimIndex>
                    <name>P70%sPFS_HA_1</name>
                    <description>Port 70%s Pin Function Select Register</description>
                    <alternateRegister>P70%sPFS</alternateRegister>
                    <addressOffset>0x1E2</addressOffset>
                    <size>16</size>
                    <access>read-write</access>
                    <resetValue>0x0000</resetValue>
                    <resetMask>0xfffd</resetMask>
                    <fields>
                        <field>
                            <name>PODR</name>
                            <description>Port Output Data</description>
                            <lsb>0</lsb>
                            <msb>0</msb>
                            <access>read-write</access>
                            <enumeratedValues>
                                </enumeratedValues>
                        </field>
                        <field>
                            <name>PIDR</name>
                            <description>Port State</description>
                            <lsb>1</lsb>
                            <msb>1</msb>
                            <access>read-only</access>
                            <enumeratedValues>
                                </enumeratedValues>
                        </field>
                        <field>
                            <name>PDR</name>
                            <description>Port Direction</description>
                            <lsb>2</lsb>
                            <msb>2</msb>
                            <access>read-write</access>
                            <enumeratedValues>
                                </enumeratedValues>
                        </field>
                        <field>
                            <name>PCR</name>
                            <description>Pull,up Control</description>
                            <lsb>4</lsb>
                            <msb>4</msb>
                            <access>read-write</access>
                            <enumeratedValues>
                                </enumeratedValues>
                        </field>
                        <field>
                            <name>NCODR</name>
                            <description>N,Channel Open,Drain Control</description>
                            <lsb>6</lsb>
                            <msb>6</msb>
                            <access>read-write</access>
                            <enumeratedValues>
                                </enumeratedValues>
                        </field>
                        <field>
                            <name>ISEL</name>
                            <description>IRQ Input Enable</description>
                            <lsb>14</lsb>
                            <msb>14</msb>
                            <access>read-write</access>
                            <enumeratedValues>
                                </enumeratedValues>
                        </field>
                        <field>
                            <name>ASEL</name>
                            <description>Analog Input Enable</description>
                            <lsb>15</lsb>
                            <msb>15</msb>
                            <access>read-write</access>
                            <enumeratedValues>
                                </enumeratedValues>
                        </field>
                    </fields>
                </register>
                <register>
                    <dim>2</dim>
                    <dimIncrement>0x4</dimIncrement>
                    <dimIndex>8-9</dimIndex>
                    <name>P70%sPFS_BY_1</name>
                    <description>Port 70%s Pin Function Select Register</description>
                    <alternateRegister>P70%sPFS</alternateRegister>
                    <addressOffset>0x1E3</addressOffset>
                    <size>8</size>
                    <access>read-write</access>
                    <resetValue>0x00</resetValue>
                    <resetMask>0xfd</resetMask>
                    <fields>
                        <field>
                            <name>PODR</name>
                            <description>Port Output Data</description>
                            <lsb>0</lsb>
                            <msb>0</msb>
                            <access>read-write</access>
                            <enumeratedValues>
                                </enumeratedValues>
                        </field>
                        <field>
                            <name>PIDR</name>
                            <description>Port State</description>
                            <lsb>1</lsb>
                            <msb>1</msb>
                            <access>read-only</access>
                            <enumeratedValues>
                                </enumeratedValues>
                        </field>
                        <field>
                            <name>PDR</name>
                            <description>Port Direction</description>
                            <lsb>2</lsb>
                            <msb>2</msb>
                            <access>read-write</access>
                            <enumeratedValues>
                                </enumeratedValues>
                        </field>
                        <field>
                            <name>PCR</name>
                            <description>Pull,up Control</description>
                            <lsb>4</lsb>
                            <msb>4</msb>
                            <access>read-write</access>
                            <enumeratedValues>
                                </enumeratedValues>
                        </field>
                        <field>
                            <name>NCODR</name>
                            <description>N,Channel Open,Drain Control</description>
                            <lsb>6</lsb>
                            <msb>6</msb>
                            <access>read-write</access>
                            <enumeratedValues>
                                </enumeratedValues>
                        </field>
                    </fields>
                </register>
                <register>
                    <dim>4</dim>
                    <dimIncrement>0x4</dimIncrement>
                    <dimIndex>10-13</dimIndex>
                    <name>P7%sPFS</name>
                    <description>Port 7%s Pin Function Select Register</description>
                    <addressOffset>0x1E8</addressOffset>
                    <size>32</size>
                    <access>read-write</access>
                    <resetValue>0x00000000</resetValue>
                    <resetMask>0xfffffffd</resetMask>
                    <fields>
                        <field>
                            <name>PODR</name>
                            <description>Port Output Data</description>
                            <lsb>0</lsb>
                            <msb>0</msb>
                            <access>read-write</access>
                            <enumeratedValues>
                                </enumeratedValues>
                        </field>
                        <field>
                            <name>PIDR</name>
                            <description>Port State</description>
                            <lsb>1</lsb>
                            <msb>1</msb>
                            <access>read-only</access>
                            <enumeratedValues>
                                </enumeratedValues>
                        </field>
                        <field>
                            <name>PDR</name>
                            <description>Port Direction</description>
                            <lsb>2</lsb>
                            <msb>2</msb>
                            <access>read-write</access>
                            <enumeratedValues>
                                </enumeratedValues>
                        </field>
                        <field>
                            <name>PCR</name>
                            <description>Pull,up Control</description>
                            <lsb>4</lsb>
                            <msb>4</msb>
                            <access>read-write</access>
                            <enumeratedValues>
                                </enumeratedValues>
                        </field>
                        <field>
                            <name>NCODR</name>
                            <description>N,Channel Open,Drain Control</description>
                            <lsb>6</lsb>
                            <msb>6</msb>
                            <access>read-write</access>
                            <enumeratedValues>
                                </enumeratedValues>
                        </field>
                        <field>
                            <name>ISEL</name>
                            <description>IRQ Input Enable</description>
                            <lsb>14</lsb>
                            <msb>14</msb>
                            <access>read-write</access>
                            <enumeratedValues>
                                </enumeratedValues>
                        </field>
                        <field>
                            <name>ASEL</name>
                            <description>Analog Input Enable</description>
                            <lsb>15</lsb>
                            <msb>15</msb>
                            <access>read-write</access>
                            <enumeratedValues>
                                </enumeratedValues>
                        </field>
                        <field>
                            <name>PMR</name>
                            <description>Port Mode Control</description>
                            <lsb>16</lsb>
                            <msb>16</msb>
                            <access>read-write</access>
                            <enumeratedValues>
                                </enumeratedValues>
                        </field>
                        <field>
                            <name>PSEL</name>
                            <description>Peripheral Select</description>
                            <lsb>24</lsb>
                            <msb>28</msb>
                            <access>read-write</access>
                        </field>
                    </fields>
                </register>
                <register>
                    <dim>4</dim>
                    <dimIncrement>0x4</dimIncrement>
                    <dimIndex>10-13</dimIndex>
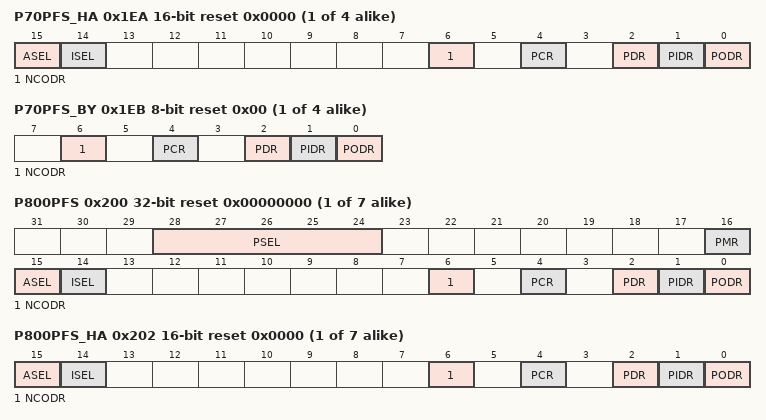
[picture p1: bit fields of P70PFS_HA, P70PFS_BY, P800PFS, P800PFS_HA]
                    <name>P7%sPFS_HA</name>
                    <description>Port 7%s Pin Function Select Register</description>
                    <alternateRegister>P7%sPFS</alternateRegister>
                    <addressOffset>0x1EA</addressOffset>
                    <size>16</size>
                    <access>read-write</access>
                    <resetValue>0x0000</resetValue>
                    <resetMask>0xfffd</resetMask>
                    <fields>
                        <field>
                            <name>PODR</name>
                            <description>Port Output Data</description>
                            <lsb>0</lsb>
                            <msb>0</msb>
                            <access>read-write</access>
                            <enumeratedValues>
                                </enumeratedValues>
                        </field>
                        <field>
                            <name>PIDR</name>
                            <description>Port State</description>
                            <lsb>1</lsb>
                            <msb>1</msb>
                            <access>read-only</access>
                            <enumeratedValues>
                                </enumeratedValues>
                        </field>
                        <field>
                            <name>PDR</name>
                            <description>Port Direction</description>
                            <lsb>2</lsb>
                            <msb>2</msb>
                            <access>read-write</access>
                            <enumeratedValues>
                                </enumeratedValues>
                        </field>
                        <field>
                            <name>PCR</name>
                            <description>Pull,up Control</description>
                            <lsb>4</lsb>
                            <msb>4</msb>
                            <access>read-write</access>
                            <enumeratedValues>
                                </enumeratedValues>
                        </field>
                        <field>
                            <name>NCODR</name>
                            <description>N,Channel Open,Drain Control</description>
                            <lsb>6</lsb>
                            <msb>6</msb>
                            <access>read-write</access>
                            <enumeratedValues>
                                </enumeratedValues>
                        </field>
                        <field>
                            <name>ISEL</name>
                            <description>IRQ Input Enable</description>
                            <lsb>14</lsb>
                            <msb>14</msb>
                            <access>read-write</access>
                            <enumeratedValues>
                                </enumeratedValues>
                        </field>
                        <field>
                            <name>ASEL</name>
                            <description>Analog Input Enable</description>
                            <lsb>15</lsb>
                            <msb>15</msb>
                            <access>read-write</access>
                            <enumeratedValues>
                                </enumeratedValues>
                        </field>
                    </fields>
                </register>
                <register>
                    <dim>4</dim>
                    <dimIncrement>0x4</dimIncrement>
                    <dimIndex>10-13</dimIndex>
                    <name>P7%sPFS_BY</name>
                    <description>Port 7%s Pin Function Select Register</description>
                    <alternateRegister>P7%sPFS</alternateRegister>
                    <addressOffset>0x1EB</addressOffset>
                    <size>8</size>
                    <access>read-write</access>
                    <resetValue>0x00</resetValue>
                    <resetMask>0xfd</resetMask>
                    <fields>
                        <field>
                            <name>PODR</name>
                            <description>Port Output Data</description>
                            <lsb>0</lsb>
                            <msb>0</msb>
                            <access>read-write</access>
                            <enumeratedValues>
                                </enumeratedValues>
                        </field>
                        <field>
                            <name>PIDR</name>
                            <description>Port State</description>
                            <lsb>1</lsb>
                            <msb>1</msb>
                            <access>read-only</access>
                            <enumeratedValues>
                                </enumeratedValues>
                        </field>
                        <field>
                            <name>PDR</name>
                            <description>Port Direction</description>
                            <lsb>2</lsb>
                            <msb>2</msb>
                            <access>read-write</access>
                            <enumeratedValues>
                                </enumeratedValues>
                        </field>
                        <field>
                            <name>PCR</name>
                            <description>Pull,up Control</description>
                            <lsb>4</lsb>
                            <msb>4</msb>
                            <access>read-write</access>
                            <enumeratedValues>
                                </enumeratedValues>
                        </field>
                        <field>
                            <name>NCODR</name>
                            <description>N,Channel Open,Drain Control</description>
                            <lsb>6</lsb>
                            <msb>6</msb>
                            <access>read-write</access>
                            <enumeratedValues>
                                </enumeratedValues>
                        </field>
                    </fields>
                </register>
                <register>
                    <dim>7</dim>
                    <dimIncrement>0x4</dimIncrement>
                    <dimIndex>0-6</dimIndex>
                    <name>P80%sPFS</name>
                    <description>Port 80%s Pin Function Select Register</description>
                    <addressOffset>0x200</addressOffset>
                    <size>32</size>
                    <access>read-write</access>
                    <resetValue>0x00000000</resetValue>
                    <resetMask>0xfffffffd</resetMask>
                    <fields>
                        <field>
                            <name>PODR</name>
                            <description>Port Output Data</description>
                            <lsb>0</lsb>
                            <msb>0</msb>
                            <access>read-write</access>
                            <enumeratedValues>
                                </enumeratedValues>
                        </field>
                        <field>
                            <name>PIDR</name>
                            <description>Port State</description>
                            <lsb>1</lsb>
                            <msb>1</msb>
                            <access>read-only</access>
                            <enumeratedValues>
                                </enumeratedValues>
                        </field>
                        <field>
                            <name>PDR</name>
                            <description>Port Direction</description>
                            <lsb>2</lsb>
                            <msb>2</msb>
                            <access>read-write</access>
                            <enumeratedValues>
                                </enumeratedValues>
                        </field>
                        <field>
                            <name>PCR</name>
                            <description>Pull,up Control</description>
                            <lsb>4</lsb>
                            <msb>4</msb>
                            <access>read-write</access>
                            <enumeratedValues>
                                </enumeratedValues>
                        </field>
                        <field>
                            <name>NCODR</name>
                            <description>N,Channel Open,Drain Control</description>
                            <lsb>6</lsb>
                            <msb>6</msb>
                            <access>read-write</access>
                            <enumeratedValues>
                                </enumeratedValues>
                        </field>
                        <field>
                            <name>ISEL</name>
                            <description>IRQ Input Enable</description>
                            <lsb>14</lsb>
                            <msb>14</msb>
                            <access>read-write</access>
                            <enumeratedValues>
                                </enumeratedValues>
                        </field>
                        <field>
                            <name>ASEL</name>
                            <description>Analog Input Enable</description>
                            <lsb>15</lsb>
                            <msb>15</msb>
                            <access>read-write</access>
                            <enumeratedValues>
                                </enumeratedValues>
                        </field>
                        <field>
                            <name>PMR</name>
                            <description>Port Mode Control</description>
                            <lsb>16</lsb>
                            <msb>16</msb>
                            <access>read-write</access>
                            <enumeratedValues>
                                </enumeratedValues>
                        </field>
                        <field>
                            <name>PSEL</name>
                            <description>Peripheral Select</description>
                            <lsb>24</lsb>
                            <msb>28</msb>
                            <access>read-write</access>
                        </field>
                    </fields>
                </register>
                <register>
                    <dim>7</dim>
                    <dimIncrement>0x4</dimIncrement>
                    <dimIndex>0-6</dimIndex>
                    <name>P80%sPFS_HA</name>
                    <description>Port 80%s Pin Function Select Register</description>
                    <alternateRegister>P80%sPFS</alternateRegister>
                    <addressOffset>0x202</addressOffset>
                    <size>16</size>
                    <access>read-write</access>
                    <resetValue>0x0000</resetValue>
                    <resetMask>0xfffd</resetMask>
                    <fields>
                        <field>
                            <name>PODR</name>
                            <description>Port Output Data</description>
                            <lsb>0</lsb>
                            <msb>0</msb>
                            <access>read-write</access>
                            <enumeratedValues>
                                </enumeratedValues>
                        </field>
                        <field>
                            <name>PIDR</name>
                            <description>Port State</description>
                            <lsb>1</lsb>
                            <msb>1</msb>
                            <access>read-only</access>
                            <enumeratedValues>
                                </enumeratedValues>
                        </field>
                        <field>
                            <name>PDR</name>
                            <description>Port Direction</description>
                            <lsb>2</lsb>
                            <msb>2</msb>
                            <access>read-write</access>
                            <enumeratedValues>
                                </enumeratedValues>
                        </field>
                        <field>
                            <name>PCR</name>
                            <description>Pull,up Control</description>
                            <lsb>4</lsb>
                            <msb>4</msb>
                            <access>read-write</access>
                            <enumeratedValues>
                                </enumeratedValues>
                        </field>
                        <field>
                            <name>NCODR</name>
                            <description>N,Channel Open,Drain Control</description>
                            <lsb>6</lsb>
                            <msb>6</msb>
                            <access>read-write</access>
                            <enumeratedValues>
                                </enumeratedValues>
                        </field>
                        <field>
                            <name>ISEL</name>
                            <description>IRQ Input Enable</description>
                            <lsb>14</lsb>
                            <msb>14</msb>
                            <access>read-write</access>
                            <enumeratedValues>
                                </enumeratedValues>
                        </field>
                        <field>
                            <name>ASEL</name>
                            <description>Analog Input Enable</description>
                            <lsb>15</lsb>
                            <msb>15</msb>
                            <access>read-write</access>
                            <enumeratedValues>
                                </enumeratedValues>
                        </field>
                    </fields>
                </register>
                <register>
                    <dim>7</dim>
                    <dimIncrement>0x4</dimIncrement>
                    <dimIndex>0-6</dimIndex>
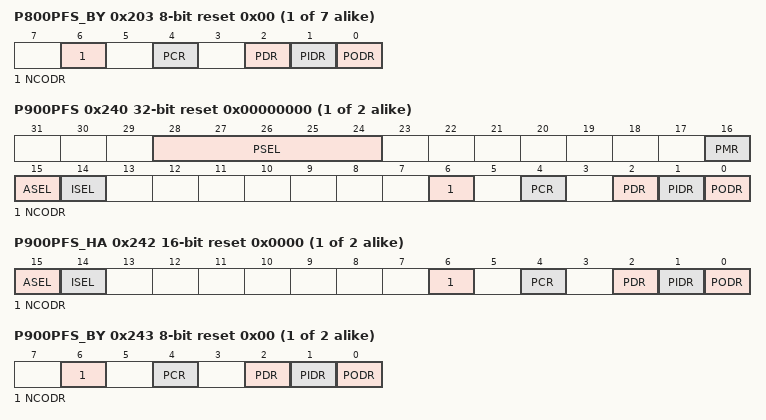
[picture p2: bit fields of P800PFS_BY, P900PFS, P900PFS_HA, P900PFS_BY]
                    <name>P80%sPFS_BY</name>
                    <description>Port 80%s Pin Function Select Register</description>
                    <alternateRegister>P80%sPFS</alternateRegister>
                    <addressOffset>0x203</addressOffset>
                    <size>8</size>
                    <access>read-write</access>
                    <resetValue>0x00</resetValue>
                    <resetMask>0xfd</resetMask>
                    <fields>
                        <field>
                            <name>PODR</name>
                            <description>Port Output Data</description>
                            <lsb>0</lsb>
                            <msb>0</msb>
                            <access>read-write</access>
                            <enumeratedValues>
                                </enumeratedValues>
                        </field>
                        <field>
                            <name>PIDR</name>
                            <description>Port State</description>
                            <lsb>1</lsb>
                            <msb>1</msb>
                            <access>read-only</access>
                            <enumeratedValues>
                                </enumeratedValues>
                        </field>
                        <field>
                            <name>PDR</name>
                            <description>Port Direction</description>
                            <lsb>2</lsb>
                            <msb>2</msb>
                            <access>read-write</access>
                            <enumeratedValues>
                                </enumeratedValues>
                        </field>
                        <field>
                            <name>PCR</name>
                            <description>Pull,up Control</description>
                            <lsb>4</lsb>
                            <msb>4</msb>
                            <access>read-write</access>
                            <enumeratedValues>
                                </enumeratedValues>
                        </field>
                        <field>
                            <name>NCODR</name>
                            <description>N,Channel Open,Drain Control</description>
                            <lsb>6</lsb>
                            <msb>6</msb>
                            <access>read-write</access>
                            <enumeratedValues>
                                </enumeratedValues>
                        </field>
                    </fields>
                </register>
                <register>
                    <dim>2</dim>
                    <dimIncrement>0x4</dimIncrement>
                    <dimIndex>0-1</dimIndex>
                    <name>P90%sPFS</name>
                    <description>Port 90%s Pin Function Select Register</description>
                    <addressOffset>0x240</addressOffset>
                    <size>32</size>
                    <access>read-write</access>
                    <resetValue>0x00000000</resetValue>
                    <resetMask>0xfffffffd</resetMask>
                    <fields>
                        <field>
                            <name>PODR</name>
                            <description>Port Output Data</description>
                            <lsb>0</lsb>
                            <msb>0</msb>
                            <access>read-write</access>
                            <enumeratedValues>
                                </enumeratedValues>
                        </field>
                        <field>
                            <name>PIDR</name>
                            <description>Port State</description>
                            <lsb>1</lsb>
                            <msb>1</msb>
                            <access>read-only</access>
                            <enumeratedValues>
                                </enumeratedValues>
                        </field>
                        <field>
                            <name>PDR</name>
                            <description>Port Direction</description>
                            <lsb>2</lsb>
                            <msb>2</msb>
                            <access>read-write</access>
                            <enumeratedValues>
                                </enumeratedValues>
                        </field>
                        <field>
                            <name>PCR</name>
                            <description>Pull,up Control</description>
                            <lsb>4</lsb>
                            <msb>4</msb>
                            <access>read-write</access>
                            <enumeratedValues>
                                </enumeratedValues>
                        </field>
                        <field>
                            <name>NCODR</name>
                            <description>N,Channel Open,Drain Control</description>
                            <lsb>6</lsb>
                            <msb>6</msb>
                            <access>read-write</access>
                            <enumeratedValues>
                                </enumeratedValues>
                        </field>
                        <field>
                            <name>ISEL</name>
                            <description>IRQ Input Enable</description>
                            <lsb>14</lsb>
                            <msb>14</msb>
                            <access>read-write</access>
                            <enumeratedValues>
                                </enumeratedValues>
                        </field>
                        <field>
                            <name>ASEL</name>
                            <description>Analog Input Enable</description>
                            <lsb>15</lsb>
                            <msb>15</msb>
                            <access>read-write</access>
                            <enumeratedValues>
                                </enumeratedValues>
                        </field>
                        <field>
                            <name>PMR</name>
                            <description>Port Mode Control</description>
                            <lsb>16</lsb>
                            <msb>16</msb>
                            <access>read-write</access>
                            <enumeratedValues>
                                </enumeratedValues>
                        </field>
                        <field>
                            <name>PSEL</name>
                            <description>Peripheral Select</description>
                            <lsb>24</lsb>
                            <msb>28</msb>
                            <access>read-write</access>
                        </field>
                    </fields>
                </register>
                <register>
                    <dim>2</dim>
                    <dimIncrement>0x4</dimIncrement>
                    <dimIndex>0-1</dimIndex>
                    <name>P90%sPFS_HA</name>
                    <description>Port 90%s Pin Function Select Register</description>
                    <alternateRegister>P90%sPFS</alternateRegister>
                    <addressOffset>0x242</addressOffset>
                    <size>16</size>
                    <access>read-write</access>
                    <resetValue>0x0000</resetValue>
                    <resetMask>0xfffd</resetMask>
                    <fields>
                        <field>
                            <name>PODR</name>
                            <description>Port Output Data</description>
                            <lsb>0</lsb>
                            <msb>0</msb>
                            <access>read-write</access>
                            <enumeratedValues>
                                </enumeratedValues>
                        </field>
                        <field>
                            <name>PIDR</name>
                            <description>Port State</description>
                            <lsb>1</lsb>
                            <msb>1</msb>
                            <access>read-only</access>
                            <enumeratedValues>
                                </enumeratedValues>
                        </field>
                        <field>
                            <name>PDR</name>
                            <description>Port Direction</description>
                            <lsb>2</lsb>
                            <msb>2</msb>
                            <access>read-write</access>
                            <enumeratedValues>
                                </enumeratedValues>
                        </field>
                        <field>
                            <name>PCR</name>
                            <description>Pull,up Control</description>
                            <lsb>4</lsb>
                            <msb>4</msb>
                            <access>read-write</access>
                            <enumeratedValues>
                                </enumeratedValues>
                        </field>
                        <field>
                            <name>NCODR</name>
                            <description>N,Channel Open,Drain Control</description>
                            <lsb>6</lsb>
                            <msb>6</msb>
                            <access>read-write</access>
                            <enumeratedValues>
                                </enumeratedValues>
                        </field>
                        <field>
                            <name>ISEL</name>
                            <description>IRQ Input Enable</description>
                            <lsb>14</lsb>
                            <msb>14</msb>
                            <access>read-write</access>
                            <enumeratedValues>
                                </enumeratedValues>
                        </field>
                        <field>
                            <name>ASEL</name>
                            <description>Analog Input Enable</description>
                            <lsb>15</lsb>
                            <msb>15</msb>
                            <access>read-write</access>
                            <enumeratedValues>
                                </enumeratedValues>
                        </field>
                    </fields>
                </register>
                <register>
                    <dim>2</dim>
                    <dimIncrement>0x4</dimIncrement>
                    <dimIndex>0-1</dimIndex>
                    <name>P90%sPFS_BY</name>
                    <description>Port 90%s Pin Function Select Register</description>
                    <alternateRegister>P90%sPFS</alternateRegister>
                    <addressOffset>0x243</addressOffset>
                    <size>8</size>
                    <access>read-write</access>
                    <resetValue>0x00</resetValue>
                    <resetMask>0xfd</resetMask>
                    <fields>
                        <field>
                            <name>PODR</name>
                            <description>Port Output Data</description>
                            <lsb>0</lsb>
                            <msb>0</msb>
                            <access>read-write</access>
                            <enumeratedValues>
                                </enumeratedValues>
                        </field>
                        <field>
                            <name>PIDR</name>
                            <description>Port State</description>
                            <lsb>1</lsb>
                            <msb>1</msb>
                            <access>read-only</access>
                            <enumeratedValues>
                                </enumeratedValues>
                        </field>
                        <field>
                            <name>PDR</name>
                            <description>Port Direction</description>
                            <lsb>2</lsb>
                            <msb>2</msb>
                            <access>read-write</access>
                            <enumeratedValues>
                                </enumeratedValues>
                        </field>
                        <field>
                            <name>PCR</name>
                            <description>Pull,up Control</description>
                            <lsb>4</lsb>
                            <msb>4</msb>
                            <access>read-write</access>
                            <enumeratedValues>
                                </enumeratedValues>
                        </field>
                        <field>
                            <name>NCODR</name>
                            <description>N,Channel Open,Drain Control</description>
                            <lsb>6</lsb>
                            <msb>6</msb>
                            <access>read-write</access>
                            <enumeratedValues>
                                </enumeratedValues>
                        </field>
                    </fields>
                </register>
                <register>
                    <dim>4</dim>
                    <dimIncrement>0x4</dimIncrement>
                    <dimIndex>5-8</dimIndex>
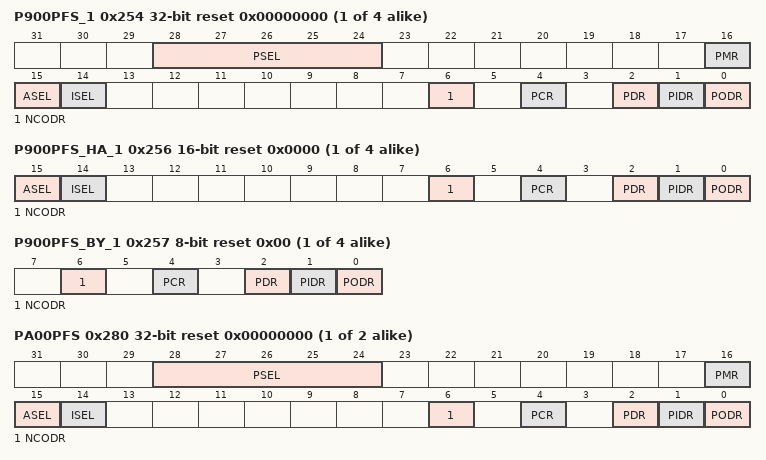
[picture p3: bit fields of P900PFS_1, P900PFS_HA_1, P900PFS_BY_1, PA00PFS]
                    <name>P90%sPFS_1</name>
                    <description>Port 90%s Pin Function Select Register</description>
                    <addressOffset>0x254</addressOffset>
                    <size>32</size>
                    <access>read-write</access>
                    <resetValue>0x00000000</resetValue>
                    <resetMask>0xfffffffd</resetMask>
                    <fields>
                        <field>
                            <name>PODR</name>
                            <description>Port Output Data</description>
                            <lsb>0</lsb>
                            <msb>0</msb>
                            <access>read-write</access>
                            <enumeratedValues>
                                </enumeratedValues>
                        </field>
                        <field>
                            <name>PIDR</name>
                            <description>Port State</description>
                            <lsb>1</lsb>
                            <msb>1</msb>
                            <access>read-only</access>
                            <enumeratedValues>
                                </enumeratedValues>
                        </field>
                        <field>
                            <name>PDR</name>
                            <description>Port Direction</description>
                            <lsb>2</lsb>
                            <msb>2</msb>
                            <access>read-write</access>
                            <enumeratedValues>
                                </enumeratedValues>
                        </field>
                        <field>
                            <name>PCR</name>
                            <description>Pull,up Control</description>
                            <lsb>4</lsb>
                            <msb>4</msb>
                            <access>read-write</access>
                            <enumeratedValues>
                                </enumeratedValues>
                        </field>
                        <field>
                            <name>NCODR</name>
                            <description>N,Channel Open,Drain Control</description>
                            <lsb>6</lsb>
                            <msb>6</msb>
                            <access>read-write</access>
                            <enumeratedValues>
                                </enumeratedValues>
                        </field>
                        <field>
                            <name>ISEL</name>
                            <description>IRQ Input Enable</description>
                            <lsb>14</lsb>
                            <msb>14</msb>
                            <access>read-write</access>
                            <enumeratedValues>
                                </enumeratedValues>
                        </field>
                        <field>
                            <name>ASEL</name>
                            <description>Analog Input Enable</description>
                            <lsb>15</lsb>
                            <msb>15</msb>
                            <access>read-write</access>
                            <enumeratedValues>
                                </enumeratedValues>
                        </field>
                        <field>
                            <name>PMR</name>
                            <description>Port Mode Control</description>
                            <lsb>16</lsb>
                            <msb>16</msb>
                            <access>read-write</access>
                            <enumeratedValues>
                                </enumeratedValues>
                        </field>
                        <field>
                            <name>PSEL</name>
                            <description>Peripheral Select</description>
                            <lsb>24</lsb>
                            <msb>28</msb>
                            <access>read-write</access>
                        </field>
                    </fields>
                </register>
                <register>
                    <dim>4</dim>
                    <dimIncrement>0x4</dimIncrement>
                    <dimIndex>5-8</dimIndex>
                    <name>P90%sPFS_HA_1</name>
                    <description>Port 90%s Pin Function Select Register</description>
                    <alternateRegister>P90%sPFS</alternateRegister>
                    <addressOffset>0x256</addressOffset>
                    <size>16</size>
                    <access>read-write</access>
                    <resetValue>0x0000</resetValue>
                    <resetMask>0xfffd</resetMask>
                    <fields>
                        <field>
                            <name>PODR</name>
                            <description>Port Output Data</description>
                            <lsb>0</lsb>
                            <msb>0</msb>
                            <access>read-write</access>
                            <enumeratedValues>
                                </enumeratedValues>
                        </field>
                        <field>
                            <name>PIDR</name>
                            <description>Port State</description>
                            <lsb>1</lsb>
                            <msb>1</msb>
                            <access>read-only</access>
                            <enumeratedValues>
                                </enumeratedValues>
                        </field>
                        <field>
                            <name>PDR</name>
                            <description>Port Direction</description>
                            <lsb>2</lsb>
                            <msb>2</msb>
                            <access>read-write</access>
                            <enumeratedValues>
                                </enumeratedValues>
                        </field>
                        <field>
                            <name>PCR</name>
                            <description>Pull,up Control</description>
                            <lsb>4</lsb>
                            <msb>4</msb>
                            <access>read-write</access>
                            <enumeratedValues>
                                </enumeratedValues>
                        </field>
                        <field>
                            <name>NCODR</name>
                            <description>N,Channel Open,Drain Control</description>
                            <lsb>6</lsb>
                            <msb>6</msb>
                            <access>read-write</access>
                            <enumeratedValues>
                                </enumeratedValues>
                        </field>
                        <field>
                            <name>ISEL</name>
                            <description>IRQ Input Enable</description>
                            <lsb>14</lsb>
                            <msb>14</msb>
                            <access>read-write</access>
                            <enumeratedValues>
                                </enumeratedValues>
                        </field>
                        <field>
                            <name>ASEL</name>
                            <description>Analog Input Enable</description>
                            <lsb>15</lsb>
                            <msb>15</msb>
                            <access>read-write</access>
                            <enumeratedValues>
                                </enumeratedValues>
                        </field>
                    </fields>
                </register>
                <register>
                    <dim>4</dim>
                    <dimIncrement>0x4</dimIncrement>
                    <dimIndex>5-8</dimIndex>
                    <name>P90%sPFS_BY_1</name>
                    <description>Port 90%s Pin Function Select Register</description>
                    <alternateRegister>P90%sPFS</alternateRegister>
                    <addressOffset>0x257</addressOffset>
                    <size>8</size>
                    <access>read-write</access>
                    <resetValue>0x00</resetValue>
                    <resetMask>0xfd</resetMask>
                    <fields>
                        <field>
                            <name>PODR</name>
                            <description>Port Output Data</description>
                            <lsb>0</lsb>
                            <msb>0</msb>
                            <access>read-write</access>
                            <enumeratedValues>
                                </enumeratedValues>
                        </field>
                        <field>
                            <name>PIDR</name>
                            <description>Port State</description>
                            <lsb>1</lsb>
                            <msb>1</msb>
                            <access>read-only</access>
                            <enumeratedValues>
                                </enumeratedValues>
                        </field>
                        <field>
                            <name>PDR</name>
                            <description>Port Direction</description>
                            <lsb>2</lsb>
                            <msb>2</msb>
                            <access>read-write</access>
                            <enumeratedValues>
                                </enumeratedValues>
                        </field>
                        <field>
                            <name>PCR</name>
                            <description>Pull,up Control</description>
                            <lsb>4</lsb>
                            <msb>4</msb>
                            <access>read-write</access>
                            <enumeratedValues>
                                </enumeratedValues>
                        </field>
                        <field>
                            <name>NCODR</name>
                            <description>N,Channel Open,Drain Control</description>
                            <lsb>6</lsb>
                            <msb>6</msb>
                            <access>read-write</access>
                            <enumeratedValues>
                                </enumeratedValues>
                        </field>
                    </fields>
                </register>
                <register>
                    <dim>2</dim>
                    <dimIncrement>0x4</dimIncrement>
                    <dimIndex>0-1</dimIndex>
                    <name>PA0%sPFS</name>
                    <description>Port A0%s Pin Function Select Register</description>
                    <addressOffset>0x280</addressOffset>
                    <size>32</size>
                    <access>read-write</access>
                    <resetValue>0x00000000</resetValue>
                    <resetMask>0xfffffffd</resetMask>
                    <fields>
                        <field>
                            <name>PODR</name>
                            <description>Port Output Data</description>
                            <lsb>0</lsb>
                            <msb>0</msb>
                            <access>read-write</access>
                            <enumeratedValues>
                                </enumeratedValues>
                        </field>
                        <field>
                            <name>PIDR</name>
                            <description>Port State</description>
                            <lsb>1</lsb>
                            <msb>1</msb>
                            <access>read-only</access>
                            <enumeratedValues>
                                </enumeratedValues>
                        </field>
                        <field>
                            <name>PDR</name>
                            <description>Port Direction</description>
                            <lsb>2</lsb>
                            <msb>2</msb>
                            <access>read-write</access>
                            <enumeratedValues>
                                </enumeratedValues>
                        </field>
                        <field>
                            <name>PCR</name>
                            <description>Pull,up Control</description>
                            <lsb>4</lsb>
                            <msb>4</msb>
                            <access>read-write</access>
                            <enumeratedValues>
                                </enumeratedValues>
                        </field>
                        <field>
                            <name>NCODR</name>
                            <description>N,Channel Open,Drain Control</description>
                            <lsb>6</lsb>
                            <msb>6</msb>
                            <access>read-write</access>
                            <enumeratedValues>
                                </enumeratedValues>
                        </field>
                        <field>
                            <name>ISEL</name>
                            <description>IRQ Input Enable</description>
                            <lsb>14</lsb>
                            <msb>14</msb>
                            <access>read-write</access>
                            <enumeratedValues>
                                </enumeratedValues>
                        </field>
                        <field>
                            <name>ASEL</name>
                            <description>Analog Input Enable</description>
                            <lsb>15</lsb>
                            <msb>15</msb>
                            <access>read-write</access>
                            <enumeratedValues>
                                </enumeratedValues>
                        </field>
                        <field>
                            <name>PMR</name>
                            <description>Port Mode Control</description>
                            <lsb>16</lsb>
                            <msb>16</msb>
                            <access>read-write</access>
                            <enumeratedValues>
                                </enumeratedValues>
                        </field>
                        <field>
                            <name>PSEL</name>
                            <description>Peripheral Select</description>
                            <lsb>24</lsb>
                            <msb>28</msb>
                            <access>read-write</access>
                        </field>
                    </fields>
                </register>
                <register>
                    <dim>2</dim>
                    <dimIncrement>0x4</dimIncrement>
                    <dimIndex>0-1</dimIndex>
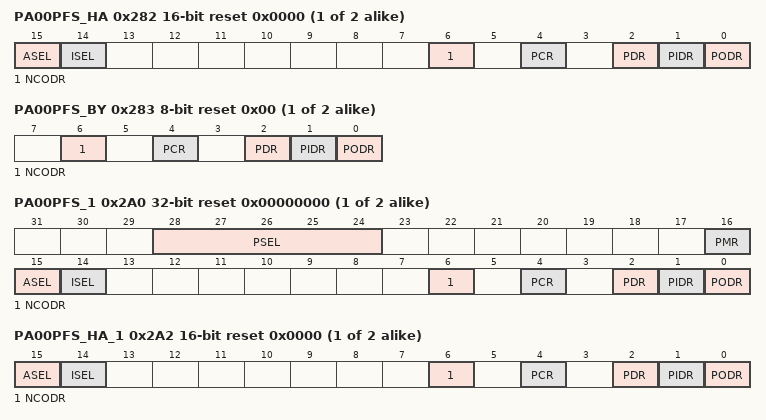
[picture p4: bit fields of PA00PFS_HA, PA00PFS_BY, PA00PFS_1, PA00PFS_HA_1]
                    <name>PA0%sPFS_HA</name>
                    <description>Port A0%s Pin Function Select Register</description>
                    <alternateRegister>PA0%sPFS</alternateRegister>
                    <addressOffset>0x282</addressOffset>
                    <size>16</size>
                    <access>read-write</access>
                    <resetValue>0x0000</resetValue>
                    <resetMask>0xfffd</resetMask>
                    <fields>
                        <field>
                            <name>PODR</name>
                            <description>Port Output Data</description>
                            <lsb>0</lsb>
                            <msb>0</msb>
                            <access>read-write</access>
                            <enumeratedValues>
                                </enumeratedValues>
                        </field>
                        <field>
                            <name>PIDR</name>
                            <description>Port State</description>
                            <lsb>1</lsb>
                            <msb>1</msb>
                            <access>read-only</access>
                            <enumeratedValues>
                                </enumeratedValues>
                        </field>
                        <field>
                            <name>PDR</name>
                            <description>Port Direction</description>
                            <lsb>2</lsb>
                            <msb>2</msb>
                            <access>read-write</access>
                            <enumeratedValues>
                                </enumeratedValues>
                        </field>
                        <field>
                            <name>PCR</name>
                            <description>Pull,up Control</description>
                            <lsb>4</lsb>
                            <msb>4</msb>
                            <access>read-write</access>
                            <enumeratedValues>
                                </enumeratedValues>
                        </field>
                        <field>
                            <name>NCODR</name>
                            <description>N,Channel Open,Drain Control</description>
                            <lsb>6</lsb>
                            <msb>6</msb>
                            <access>read-write</access>
                            <enumeratedValues>
                                </enumeratedValues>
                        </field>
                        <field>
                            <name>ISEL</name>
                            <description>IRQ Input Enable</description>
                            <lsb>14</lsb>
                            <msb>14</msb>
                            <access>read-write</access>
                            <enumeratedValues>
                                </enumeratedValues>
                        </field>
                        <field>
                            <name>ASEL</name>
                            <description>Analog Input Enable</description>
                            <lsb>15</lsb>
                            <msb>15</msb>
                            <access>read-write</access>
                            <enumeratedValues>
                                </enumeratedValues>
                        </field>
                    </fields>
                </register>
                <register>
                    <dim>2</dim>
                    <dimIncrement>0x4</dimIncrement>
                    <dimIndex>0-1</dimIndex>
                    <name>PA0%sPFS_BY</name>
                    <description>Port A0%s Pin Function Select Register</description>
                    <alternateRegister>PA0%sPFS</alternateRegister>
                    <addressOffset>0x283</addressOffset>
                    <size>8</size>
                    <access>read-write</access>
                    <resetValue>0x00</resetValue>
                    <resetMask>0xfd</resetMask>
                    <fields>
                        <field>
                            <name>PODR</name>
                            <description>Port Output Data</description>
                            <lsb>0</lsb>
                            <msb>0</msb>
                            <access>read-write</access>
                            <enumeratedValues>
                                </enumeratedValues>
                        </field>
                        <field>
                            <name>PIDR</name>
                            <description>Port State</description>
                            <lsb>1</lsb>
                            <msb>1</msb>
                            <access>read-only</access>
                            <enumeratedValues>
                                </enumeratedValues>
                        </field>
                        <field>
                            <name>PDR</name>
                            <description>Port Direction</description>
                            <lsb>2</lsb>
                            <msb>2</msb>
                            <access>read-write</access>
                            <enumeratedValues>
                                </enumeratedValues>
                        </field>
                        <field>
                            <name>PCR</name>
                            <description>Pull,up Control</description>
                            <lsb>4</lsb>
                            <msb>4</msb>
                            <access>read-write</access>
                            <enumeratedValues>
                                </enumeratedValues>
                        </field>
                        <field>
                            <name>NCODR</name>
                            <description>N,Channel Open,Drain Control</description>
                            <lsb>6</lsb>
                            <msb>6</msb>
                            <access>read-write</access>
                            <enumeratedValues>
                                </enumeratedValues>
                        </field>
                    </fields>
                </register>
                <register>
                    <dim>2</dim>
                    <dimIncrement>0x4</dimIncrement>
                    <dimIndex>8-9</dimIndex>
                    <name>PA0%sPFS_1</name>
                    <description>Port A0%s Pin Function Select Register</description>
                    <addressOffset>0x2A0</addressOffset>
                    <size>32</size>
                    <access>read-write</access>
                    <resetValue>0x00000000</resetValue>
                    <resetMask>0xfffffffd</resetMask>
                    <fields>
                        <field>
                            <name>PODR</name>
                            <description>Port Output Data</description>
                            <lsb>0</lsb>
                            <msb>0</msb>
                            <access>read-write</access>
                            <enumeratedValues>
                                </enumeratedValues>
                        </field>
                        <field>
                            <name>PIDR</name>
                            <description>Port State</description>
                            <lsb>1</lsb>
                            <msb>1</msb>
                            <access>read-only</access>
                            <enumeratedValues>
                                </enumeratedValues>
                        </field>
                        <field>
                            <name>PDR</name>
                            <description>Port Direction</description>
                            <lsb>2</lsb>
                            <msb>2</msb>
                            <access>read-write</access>
                            <enumeratedValues>
                                </enumeratedValues>
                        </field>
                        <field>
                            <name>PCR</name>
                            <description>Pull,up Control</description>
                            <lsb>4</lsb>
                            <msb>4</msb>
                            <access>read-write</access>
                            <enumeratedValues>
                                </enumeratedValues>
                        </field>
                        <field>
                            <name>NCODR</name>
                            <description>N,Channel Open,Drain Control</description>
                            <lsb>6</lsb>
                            <msb>6</msb>
                            <access>read-write</access>
                            <enumeratedValues>
                                </enumeratedValues>
                        </field>
                        <field>
                            <name>ISEL</name>
                            <description>IRQ Input Enable</description>
                            <lsb>14</lsb>
                            <msb>14</msb>
                            <access>read-write</access>
                            <enumeratedValues>
                                </enumeratedValues>
                        </field>
                        <field>
                            <name>ASEL</name>
                            <description>Analog Input Enable</description>
                            <lsb>15</lsb>
                            <msb>15</msb>
                            <access>read-write</access>
                            <enumeratedValues>
                                </enumeratedValues>
                        </field>
                        <field>
                            <name>PMR</name>
                            <description>Port Mode Control</description>
                            <lsb>16</lsb>
                            <msb>16</msb>
                            <access>read-write</access>
                            <enumeratedValues>
                                </enumeratedValues>
                        </field>
                        <field>
                            <name>PSEL</name>
                            <description>Peripheral Select</description>
                            <lsb>24</lsb>
                            <msb>28</msb>
                            <access>read-write</access>
                        </field>
                    </fields>
                </register>
                <register>
                    <dim>2</dim>
                    <dimIncrement>0x4</dimIncrement>
                    <dimIndex>8-9</dimIndex>
                    <name>PA0%sPFS_HA_1</name>
                    <description>Port A0%s Pin Function Select Register</description>
                    <alternateRegister>PA0%sPFS</alternateRegister>
                    <addressOffset>0x2A2</addressOffset>
                    <size>16</size>
                    <access>read-write</access>
                    <resetValue>0x0000</resetValue>
                    <resetMask>0xfffd</resetMask>
                    <fields>
                        <field>
                            <name>PODR</name>
                            <description>Port Output Data</description>
                            <lsb>0</lsb>
                            <msb>0</msb>
                            <access>read-write</access>
                            <enumeratedValues>
                                </enumeratedValues>
                        </field>
                        <field>
                            <name>PIDR</name>
                            <description>Port State</description>
                            <lsb>1</lsb>
                            <msb>1</msb>
                            <access>read-only</access>
                            <enumeratedValues>
                                </enumeratedValues>
                        </field>
                        <field>
                            <name>PDR</name>
                            <description>Port Direction</description>
                            <lsb>2</lsb>
                            <msb>2</msb>
                            <access>read-write</access>
                            <enumeratedValues>
                                </enumeratedValues>
                        </field>
                        <field>
                            <name>PCR</name>
                            <description>Pull,up Control</description>
                            <lsb>4</lsb>
                            <msb>4</msb>
                            <access>read-write</access>
                            <enumeratedValues>
                                </enumeratedValues>
                        </field>
                        <field>
                            <name>NCODR</name>
                            <description>N,Channel Open,Drain Control</description>
                            <lsb>6</lsb>
                            <msb>6</msb>
                            <access>read-write</access>
                            <enumeratedValues>
                                </enumeratedValues>
                        </field>
                        <field>
                            <name>ISEL</name>
                            <description>IRQ Input Enable</description>
                            <lsb>14</lsb>
                            <msb>14</msb>
                            <access>read-write</access>
                            <enumeratedValues>
                                </enumeratedValues>
                        </field>
                        <field>
                            <name>ASEL</name>
                            <description>Analog Input Enable</description>
                            <lsb>15</lsb>
                            <msb>15</msb>
                            <access>read-write</access>
                            <enumeratedValues>
                                </enumeratedValues>
                        </field>
                    </fields>
                </register>
                <register>
                    <dim>2</dim>
                    <dimIncrement>0x4</dimIncrement>
                    <dimIndex>8-9</dimIndex>
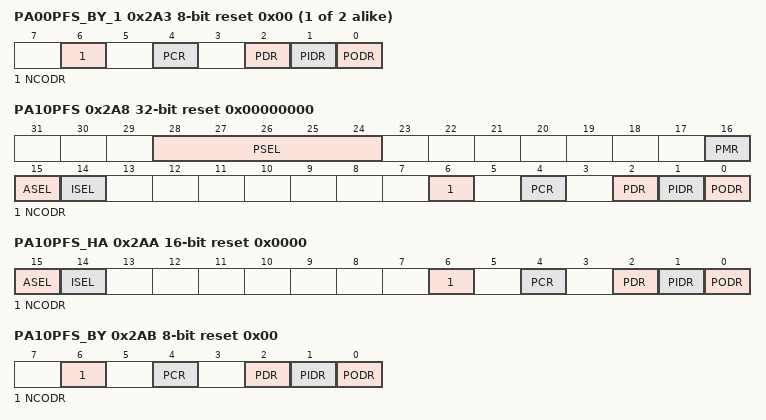
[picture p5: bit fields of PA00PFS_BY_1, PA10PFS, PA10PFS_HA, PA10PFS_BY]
                    <name>PA0%sPFS_BY_1</name>
                    <description>Port A0%s Pin Function Select Register</description>
                    <alternateRegister>PA0%sPFS</alternateRegister>
                    <addressOffset>0x2A3</addressOffset>
                    <size>8</size>
                    <access>read-write</access>
                    <resetValue>0x00</resetValue>
                    <resetMask>0xfd</resetMask>
                    <fields>
                        <field>
                            <name>PODR</name>
                            <description>Port Output Data</description>
                            <lsb>0</lsb>
                            <msb>0</msb>
                            <access>read-write</access>
                            <enumeratedValues>
                                </enumeratedValues>
                        </field>
                        <field>
                            <name>PIDR</name>
                            <description>Port State</description>
                            <lsb>1</lsb>
                            <msb>1</msb>
                            <access>read-only</access>
                            <enumeratedValues>
                                </enumeratedValues>
                        </field>
                        <field>
                            <name>PDR</name>
                            <description>Port Direction</description>
                            <lsb>2</lsb>
                            <msb>2</msb>
                            <access>read-write</access>
                            <enumeratedValues>
                                </enumeratedValues>
                        </field>
                        <field>
                            <name>PCR</name>
                            <description>Pull,up Control</description>
                            <lsb>4</lsb>
                            <msb>4</msb>
                            <access>read-write</access>
                            <enumeratedValues>
                                </enumeratedValues>
                        </field>
                        <field>
                            <name>NCODR</name>
                            <description>N,Channel Open,Drain Control</description>
                            <lsb>6</lsb>
                            <msb>6</msb>
                            <access>read-write</access>
                            <enumeratedValues>
                                </enumeratedValues>
                        </field>
                    </fields>
                </register>
                <register>
                    <name>PA10PFS</name>
                    <description>Port A10 Pin Function Select Register</description>
                    <addressOffset>0x2A8</addressOffset>
                    <size>32</size>
                    <access>read-write</access>
                    <resetValue>0x00000000</resetValue>
                    <resetMask>0xfffffffd</resetMask>
                    <fields>
                        <field>
                            <name>PODR</name>
                            <description>Port Output Data</description>
                            <lsb>0</lsb>
                            <msb>0</msb>
                            <access>read-write</access>
                            <enumeratedValues>
                                </enumeratedValues>
                        </field>
                        <field>
                            <name>PIDR</name>
                            <description>Port State</description>
                            <lsb>1</lsb>
                            <msb>1</msb>
                            <access>read-only</access>
                            <enumeratedValues>
                                </enumeratedValues>
                        </field>
                        <field>
                            <name>PDR</name>
                            <description>Port Direction</description>
                            <lsb>2</lsb>
                            <msb>2</msb>
                            <access>read-write</access>
                            <enumeratedValues>
                                </enumeratedValues>
                        </field>
                        <field>
                            <name>PCR</name>
                            <description>Pull,up Control</description>
                            <lsb>4</lsb>
                            <msb>4</msb>
                            <access>read-write</access>
                            <enumeratedValues>
                                </enumeratedValues>
                        </field>
                        <field>
                            <name>NCODR</name>
                            <description>N,Channel Open,Drain Control</description>
                            <lsb>6</lsb>
                            <msb>6</msb>
                            <access>read-write</access>
                            <enumeratedValues>
                                </enumeratedValues>
                        </field>
                        <field>
                            <name>ISEL</name>
                            <description>IRQ Input Enable</description>
                            <lsb>14</lsb>
                            <msb>14</msb>
                            <access>read-write</access>
                            <enumeratedValues>
                                </enumeratedValues>
                        </field>
                        <field>
                            <name>ASEL</name>
                            <description>Analog Input Enable</description>
                            <lsb>15</lsb>
                            <msb>15</msb>
                            <access>read-write</access>
                            <enumeratedValues>
                                </enumeratedValues>
                        </field>
                        <field>
                            <name>PMR</name>
                            <description>Port Mode Control</description>
                            <lsb>16</lsb>
                            <msb>16</msb>
                            <access>read-write</access>
                            <enumeratedValues>
                                </enumeratedValues>
                        </field>
                        <field>
                            <name>PSEL</name>
                            <description>Peripheral Select</description>
                            <lsb>24</lsb>
                            <msb>28</msb>
                            <access>read-write</access>
                        </field>
                    </fields>
                </register>
                <register>
                    <name>PA10PFS_HA</name>
                    <description>Port A10 Pin Function Select Register</description>
                    <alternateRegister>PA10PFS</alternateRegister>
                    <addressOffset>0x2AA</addressOffset>
                    <size>16</size>
                    <access>read-write</access>
                    <resetValue>0x0000</resetValue>
                    <resetMask>0xfffd</resetMask>
                    <fields>
                        <field>
                            <name>PODR</name>
                            <description>Port Output Data</description>
                            <lsb>0</lsb>
                            <msb>0</msb>
                            <access>read-write</access>
                            <enumeratedValues>
                                </enumeratedValues>
                        </field>
                        <field>
                            <name>PIDR</name>
                            <description>Port State</description>
                            <lsb>1</lsb>
                            <msb>1</msb>
                            <access>read-only</access>
                            <enumeratedValues>
                                </enumeratedValues>
                        </field>
                        <field>
                            <name>PDR</name>
                            <description>Port Direction</description>
                            <lsb>2</lsb>
                            <msb>2</msb>
                            <access>read-write</access>
                            <enumeratedValues>
                                </enumeratedValues>
                        </field>
                        <field>
                            <name>PCR</name>
                            <description>Pull,up Control</description>
                            <lsb>4</lsb>
                            <msb>4</msb>
                            <access>read-write</access>
                            <enumeratedValues>
                                </enumeratedValues>
                        </field>
                        <field>
                            <name>NCODR</name>
                            <description>N,Channel Open,Drain Control</description>
                            <lsb>6</lsb>
                            <msb>6</msb>
                            <access>read-write</access>
                            <enumeratedValues>
                                </enumeratedValues>
                        </field>
                        <field>
                            <name>ISEL</name>
                            <description>IRQ Input Enable</description>
                            <lsb>14</lsb>
                            <msb>14</msb>
                            <access>read-write</access>
                            <enumeratedValues>
                                </enumeratedValues>
                        </field>
                        <field>
                            <name>ASEL</name>
                            <description>Analog Input Enable</description>
                            <lsb>15</lsb>
                            <msb>15</msb>
                            <access>read-write</access>
                            <enumeratedValues>
                                </enumeratedValues>
                        </field>
                    </fields>
                </register>
                <register>
                    <name>PA10PFS_BY</name>
                    <description>Port A10 Pin Function Select Register</description>
                    <alternateRegister>PA10PFS</alternateRegister>
                    <addressOffset>0x2AB</addressOffset>
                    <size>8</size>
                    <access>read-write</access>
                    <resetValue>0x00</resetValue>
                    <resetMask>0xfd</resetMask>
                    <fields>
                        <field>
                            <name>PODR</name>
                            <description>Port Output Data</description>
                            <lsb>0</lsb>
                            <msb>0</msb>
                            <access>read-write</access>
                            <enumeratedValues>
                                </enumeratedValues>
                        </field>
                        <field>
                            <name>PIDR</name>
                            <description>Port State</description>
                            <lsb>1</lsb>
                            <msb>1</msb>
                            <access>read-only</access>
                            <enumeratedValues>
                                </enumeratedValues>
                        </field>
                        <field>
                            <name>PDR</name>
                            <description>Port Direction</description>
                            <lsb>2</lsb>
                            <msb>2</msb>
                            <access>read-write</access>
                            <enumeratedValues>
                                </enumeratedValues>
                        </field>
                        <field>
                            <name>PCR</name>
                            <description>Pull,up Control</description>
                            <lsb>4</lsb>
                            <msb>4</msb>
                            <access>read-write</access>
                            <enumeratedValues>
                                </enumeratedValues>
                        </field>
                        <field>
                            <name>NCODR</name>
                            <description>N,Channel Open,Drain Control</description>
                            <lsb>6</lsb>
                            <msb>6</msb>
                            <access>read-write</access>
                            <enumeratedValues>
                                </enumeratedValues>
                        </field>
                    </fields>
                </register>
                <register>
                    <dim>2</dim>
                    <dimIncrement>0x4</dimIncrement>
                    <dimIndex>0-1</dimIndex>
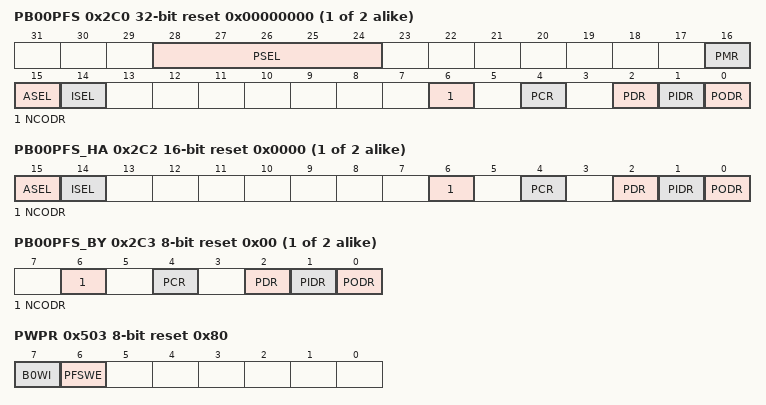
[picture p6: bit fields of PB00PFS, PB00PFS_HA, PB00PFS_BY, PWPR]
                    <name>PB0%sPFS</name>
                    <description>Port B0%s Pin Function Select Register</description>
                    <addressOffset>0x2C0</addressOffset>
                    <size>32</size>
                    <access>read-write</access>
                    <resetValue>0x00000000</resetValue>
                    <resetMask>0xfffffffd</resetMask>
                    <fields>
                        <field>
                            <name>PODR</name>
                            <description>Port Output Data</description>
                            <lsb>0</lsb>
                            <msb>0</msb>
                            <access>read-write</access>
                            <enumeratedValues>
                                </enumeratedValues>
                        </field>
                        <field>
                            <name>PIDR</name>
                            <description>Port State</description>
                            <lsb>1</lsb>
                            <msb>1</msb>
                            <access>read-only</access>
                            <enumeratedValues>
                                </enumeratedValues>
                        </field>
                        <field>
                            <name>PDR</name>
                            <description>Port Direction</description>
                            <lsb>2</lsb>
                            <msb>2</msb>
                            <access>read-write</access>
                            <enumeratedValues>
                                </enumeratedValues>
                        </field>
                        <field>
                            <name>PCR</name>
                            <description>Pull,up Control</description>
                            <lsb>4</lsb>
                            <msb>4</msb>
                            <access>read-write</access>
                            <enumeratedValues>
                                </enumeratedValues>
                        </field>
                        <field>
                            <name>NCODR</name>
                            <description>N,Channel Open,Drain Control</description>
                            <lsb>6</lsb>
                            <msb>6</msb>
                            <access>read-write</access>
                            <enumeratedValues>
                                </enumeratedValues>
                        </field>
                        <field>
                            <name>ISEL</name>
                            <description>IRQ Input Enable</description>
                            <lsb>14</lsb>
                            <msb>14</msb>
                            <access>read-write</access>
                            <enumeratedValues>
                                </enumeratedValues>
                        </field>
                        <field>
                            <name>ASEL</name>
                            <description>Analog Input Enable</description>
                            <lsb>15</lsb>
                            <msb>15</msb>
                            <access>read-write</access>
                            <enumeratedValues>
                                </enumeratedValues>
                        </field>
                        <field>
                            <name>PMR</name>
                            <description>Port Mode Control</description>
                            <lsb>16</lsb>
                            <msb>16</msb>
                            <access>read-write</access>
                            <enumeratedValues>
                                </enumeratedValues>
                        </field>
                        <field>
                            <name>PSEL</name>
                            <description>Peripheral Select</description>
                            <lsb>24</lsb>
                            <msb>28</msb>
                            <access>read-write</access>
                        </field>
                    </fields>
                </register>
                <register>
                    <dim>2</dim>
                    <dimIncrement>0x4</dimIncrement>
                    <dimIndex>0-1</dimIndex>
                    <name>PB0%sPFS_HA</name>
                    <description>Port B0%s Pin Function Select Register</description>
                    <alternateRegister>PB0%sPFS</alternateRegister>
                    <addressOffset>0x2C2</addressOffset>
                    <size>16</size>
                    <access>read-write</access>
                    <resetValue>0x0000</resetValue>
                    <resetMask>0xfffd</resetMask>
                    <fields>
                        <field>
                            <name>PODR</name>
                            <description>Port Output Data</description>
                            <lsb>0</lsb>
                            <msb>0</msb>
                            <access>read-write</access>
                            <enumeratedValues>
                                </enumeratedValues>
                        </field>
                        <field>
                            <name>PIDR</name>
                            <description>Port State</description>
                            <lsb>1</lsb>
                            <msb>1</msb>
                            <access>read-only</access>
                            <enumeratedValues>
                                </enumeratedValues>
                        </field>
                        <field>
                            <name>PDR</name>
                            <description>Port Direction</description>
                            <lsb>2</lsb>
                            <msb>2</msb>
                            <access>read-write</access>
                            <enumeratedValues>
                                </enumeratedValues>
                        </field>
                        <field>
                            <name>PCR</name>
                            <description>Pull,up Control</description>
                            <lsb>4</lsb>
                            <msb>4</msb>
                            <access>read-write</access>
                            <enumeratedValues>
                                </enumeratedValues>
                        </field>
                        <field>
                            <name>NCODR</name>
                            <description>N,Channel Open,Drain Control</description>
                            <lsb>6</lsb>
                            <msb>6</msb>
                            <access>read-write</access>
                            <enumeratedValues>
                                </enumeratedValues>
                        </field>
                        <field>
                            <name>ISEL</name>
                            <description>IRQ Input Enable</description>
                            <lsb>14</lsb>
                            <msb>14</msb>
                            <access>read-write</access>
                            <enumeratedValues>
                                </enumeratedValues>
                        </field>
                        <field>
                            <name>ASEL</name>
                            <description>Analog Input Enable</description>
                            <lsb>15</lsb>
                            <msb>15</msb>
                            <access>read-write</access>
                            <enumeratedValues>
                                </enumeratedValues>
                        </field>
                    </fields>
                </register>
                <register>
                    <dim>2</dim>
                    <dimIncrement>0x4</dimIncrement>
                    <dimIndex>0-1</dimIndex>
                    <name>PB0%sPFS_BY</name>
                    <description>Port B0%s Pin Function Select Register</description>
                    <alternateRegister>PB0%sPFS</alternateRegister>
                    <addressOffset>0x2C3</addressOffset>
                    <size>8</size>
                    <access>read-write</access>
                    <resetValue>0x00</resetValue>
                    <resetMask>0xfd</resetMask>
                    <fields>
                        <field>
                            <name>PODR</name>
                            <description>Port Output Data</description>
                            <lsb>0</lsb>
                            <msb>0</msb>
                            <access>read-write</access>
                            <enumeratedValues>
                                </enumeratedValues>
                        </field>
                        <field>
                            <name>PIDR</name>
                            <description>Port State</description>
                            <lsb>1</lsb>
                            <msb>1</msb>
                            <access>read-only</access>
                            <enumeratedValues>
                                </enumeratedValues>
                        </field>
                        <field>
                            <name>PDR</name>
                            <description>Port Direction</description>
                            <lsb>2</lsb>
                            <msb>2</msb>
                            <access>read-write</access>
                            <enumeratedValues>
                                </enumeratedValues>
                        </field>
                        <field>
                            <name>PCR</name>
                            <description>Pull,up Control</description>
                            <lsb>4</lsb>
                            <msb>4</msb>
                            <access>read-write</access>
                            <enumeratedValues>
                                </enumeratedValues>
                        </field>
                        <field>
                            <name>NCODR</name>
                            <description>N,Channel Open,Drain Control</description>
                            <lsb>6</lsb>
                            <msb>6</msb>
                            <access>read-write</access>
                            <enumeratedValues>
                                </enumeratedValues>
                        </field>
                    </fields>
                </register>
                <register>
                    <name>PFENET</name>
                    <description>Ethernet Control Register</description>
                    <addressOffset>0x500</addressOffset>
                    <size>8</size>
                    <access>read-write</access>
                    <resetValue>0x00</resetValue>
                    <resetMask>0xff</resetMask>
                    <fields>
                        <field>
                            <name>PHYMODE0</name>
                            <description>Ethernet Mode Setting ch0</description>
                            <lsb>4</lsb>
                            <msb>4</msb>
                            <access>read-write</access>
                            <enumeratedValues>
                                </enumeratedValues>
                        </field>
                    </fields>
                </register>
                <register>
                    <name>PWPR</name>
                    <description>Write,Protect Register</description>
                    <addressOffset>0x503</addressOffset>
                    <size>8</size>
                    <access>read-write</access>
                    <resetValue>0x80</resetValue>
                    <resetMask>0xff</resetMask>
                    <fields>
                        <field>
                            <name>PFSWE</name>
                            <description>PmnPFS Register Write Enable</description>
                            <lsb>6</lsb>
                            <msb>6</msb>
                            <access>read-write</access>
                            <enumeratedValues>
                                </enumeratedValues>
                        </field>
                        <field>
                            <name>B0WI</name>
                            <description>PFSWE Bit Write Disable</description>
                            <lsb>7</lsb>
                            <msb>7</msb>
                            <access>read-write</access>
                            <enumeratedValues>
                                </enumeratedValues>
                        </field>
                    </fields>
                </register>
                <register>
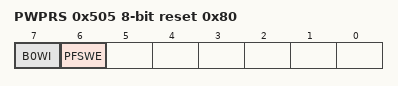
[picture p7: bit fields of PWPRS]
                    <name>PWPRS</name>
                    <description>Write,Protect Register for Secure</description>
                    <addressOffset>0x505</addressOffset>
                    <size>8</size>
                    <access>read-write</access>
                    <resetValue>0x80</resetValue>
                    <resetMask>0xff</resetMask>
                    <fields>
                        <field>
                            <name>PFSWE</name>
                            <description>PmnPFS Register Write Enable</description>
                            <lsb>6</lsb>
                            <msb>6</msb>
                            <access>read-write</access>
                            <enumeratedValues>
                                </enumeratedValues>
                        </field>
                        <field>
                            <name>B0WI</name>
                            <description>PFSWE Bit Write Disable</description>
                            <lsb>7</lsb>
                            <msb>7</msb>
                            <access>read-write</access>
                            <enumeratedValues>
                                </enumeratedValues>
                        </field>
                    </fields>
                </register>
                <register>
                    <dim>10</dim>
                    <dimIncrement>0x002</dimIncrement>
                    <dimIndex>0-9</dimIndex>
                    <name>P%sSAR</name>
                    <description>Port Security Attribution register</description>
                    <addressOffset>0x510</addressOffset>
                    <size>16</size>
                    <access>read-write</access>
                    <resetValue>0xffff</resetValue>
                    <resetMask>0xffff</resetMask>
                    <fields>
                        <field>
                            <name>PMNSA</name>
                            <description>Pmn Security Attribution</description>
                            <lsb>0</lsb>
                            <msb>15</msb>
                            <access>read-write</access>
                            <enumeratedValues>
                                </enumeratedValues>
                        </field>
                    </fields>
                </register>
                <register>
                    <dim>2</dim>
                    <dimIncrement>0x002</dimIncrement>
                    <dimIndex>A-B</dimIndex>
                    <name>P%sSAR_1</name>
                    <description>Port Security Attribution register</description>
                    <addressOffset>0x524</addressOffset>
                    <size>16</size>
                    <access>read-write</access>
                    <resetValue>0xffff</resetValue>
                    <resetMask>0xffff</resetMask>
                    <fields>
                        <field>
                            <name>PMNSA</name>
                            <description>Pmn Security Attribution</description>
                            <lsb>0</lsb>
                            <msb>15</msb>
                            <access>read-write</access>
                            <enumeratedValues>
                                </enumeratedValues>
                        </field>
                    </fields>
                </register>
            </registers>
        </peripheral>
        <peripheral>
            <name>ELC</name>
            <description>Event Link Controller</description>
            <baseAddress>0x40082000</baseAddress>
            <addressBlock>
                <offset>0x00</offset>
                <size>1</size>
                <usage>registers</usage>
            </addressBlock>
            <addressBlock>
                <offset>0x02</offset>
                <size>4</size>
                <usage>registers</usage>
            </addressBlock>
            <addressBlock>
                <offset>0x10</offset>
                <size>76</size>
                <usage>registers</usage>
            </addressBlock>
            <addressBlock>
                <offset>0x74</offset>
                <size>2</size>
                <usage>registers</usage>
            </addressBlock>
            <addressBlock>
                <offset>0x78</offset>
                <size>2</size>
                <usage>registers</usage>
            </addressBlock>
            <addressBlock>
                <offset>0x7C</offset>
                <size>2</size>
                <usage>registers</usage>
            </addressBlock>
            <registers>
                <register>
                    <name>ELCR</name>
                    <description>Event Link Controller Register</description>
                    <addressOffset>0x00</addressOffset>
                    <size>8</size>
                    <access>read-write</access>
                    <resetValue>0x00</resetValue>
                    <resetMask>0xff</resetMask>
                    <fields>
                        <field>
                            <name>ELCON</name>
                            <description>All Event Link Enable</description>
                            <lsb>7</lsb>
                            <msb>7</msb>
                            <access>read-write</access>
                            <enumeratedValues>
                                </enumeratedValues>
                        </field>
                    </fields>
                </register>
                <register>
                    <dim>2</dim>
                    <dimIncrement>0x02</dimIncrement>
                    <dimIndex>0-1</dimIndex>
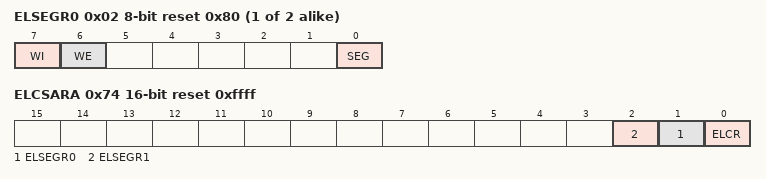
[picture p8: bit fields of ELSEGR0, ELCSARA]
                    <name>ELSEGR%s</name>
                    <description>Event Link Software Event Generation Register %s</description>
                    <addressOffset>0x02</addressOffset>
                    <size>8</size>
                    <access>read-write</access>
                    <resetValue>0x80</resetValue>
                    <resetMask>0xff</resetMask>
                    <fields>
                        <field>
                            <name>SEG</name>
                            <description>Software Event Generation</description>
                            <lsb>0</lsb>
                            <msb>0</msb>
                            <access>write-only</access>
                            <enumeratedValues>
                                </enumeratedValues>
                        </field>
                        <field>
                            <name>WE</name>
                            <description>SEG Bit Write Enable</description>
                            <lsb>6</lsb>
                            <msb>6</msb>
                            <access>read-write</access>
                            <enumeratedValues>
                                </enumeratedValues>
                        </field>
                        <field>
                            <name>WI</name>
                            <description>ELSEGR Register Write Disable</description>
                            <lsb>7</lsb>
                            <msb>7</msb>
                            <access>write-only</access>
                            <enumeratedValues>
                                </enumeratedValues>
                        </field>
                    </fields>
                </register>
                <register>
                    <dim>19</dim>
                    <dimIncrement>0x04</dimIncrement>
                    <dimIndex>0-18</dimIndex>
                    <name>ELSR%s</name>
                    <description>Event Link Setting Register %s</description>
                    <addressOffset>0x10</addressOffset>
                    <size>16</size>
                    <access>read-write</access>
                    <resetValue>0x0000</resetValue>
                    <resetMask>0xffff</resetMask>
                    <fields>
                        <field>
                            <name>ELS</name>
                            <description>Event Link Select</description>
                            <lsb>0</lsb>
                            <msb>8</msb>
                            <access>read-write</access>
                        </field>
                    </fields>
                </register>
                <register>
                    <name>ELCSARA</name>
                    <description>Event Link Controller Security Attribution Register A</description>
                    <addressOffset>0x74</addressOffset>
                    <size>16</size>
                    <access>read-write</access>
                    <resetValue>0xffff</resetValue>
                    <resetMask>0xffff</resetMask>
                    <fields>
                        <field>
                            <name>ELCR</name>
                            <description>Event Link Controller Register Security Attribution</description>
                            <lsb>0</lsb>
                            <msb>0</msb>
                            <access>read-write</access>
                            <enumeratedValues>
                                </enumeratedValues>
                        </field>
                        <field>
                            <name>ELSEGR0</name>
                            <description>Event Link Software Event Generation Register 0 Security Attribution</description>
                            <lsb>1</lsb>
                            <msb>1</msb>
                            <access>read-write</access>
                            <enumeratedValues>
                                </enumeratedValues>
                        </field>
                        <field>
                            <name>ELSEGR1</name>
                            <description>Event Link Software Event Generation Register 1 Security Attribution</description>
                            <lsb>2</lsb>
                            <msb>2</msb>
                            <access>read-write</access>
                            <enumeratedValues>
                                </enumeratedValues>
                        </field>
                    </fields>
                </register>
                <register>
                    <name>ELCSARB</name>
                    <description>Event Link Controller Security Attribution Register B</description>
                    <addressOffset>0x78</addressOffset>
                    <size>16</size>
                    <access>read-write</access>
                    <resetValue>0xffff</resetValue>
                    <resetMask>0xffff</resetMask>
                    <fields>
                        <field>
                            <name>ELSR</name>
                            <description>Event Link Setting Register n Security Attribution</description>
                            <lsb>0</lsb>
                            <msb>15</msb>
                            <access>read-write</access>
                            <enumeratedValues>
                                </enumeratedValues>
                        </field>
                    </fields>
                </register>
                <register>
                    <name>ELCSARC</name>
                    <description>Event Link Controller Security Attribution Register C</description>
                    <addressOffset>0x7C</addressOffset>
                    <size>16</size>
                    <access>read-write</access>
                    <resetValue>0xffff</resetValue>
                    <resetMask>0xffff</resetMask>
                    <fields>
                        <field>
                            <name>ELSR</name>
                            <description>Event Link Setting Register n Security Attribution (n = 16 to 18)</description>
                            <lsb>0</lsb>
                            <msb>2</msb>
                            <access>read-write</access>
                            <enumeratedValues>
                                </enumeratedValues>
                        </field>
                    </fields>
                </register>
            </registers>
        </peripheral>
        <peripheral>
            <name>RTC</name>
            <description>Realtime Clock</description>
            <baseAddress>0x40083000</baseAddress>
            <addressBlock>
                <offset>0x00</offset>
                <size>1</size>
                <usage>registers</usage>
            </addressBlock>
            <addressBlock>
                <offset>0x02</offset>
                <size>8</size>
                <usage>registers</usage>
            </addressBlock>
            <addressBlock>
                <offset>0x0A</offset>
                <size>1</size>
                <usage>registers</usage>
            </addressBlock>
            <addressBlock>
                <offset>0x0C</offset>
                <size>1</size>
                <usage>registers</usage>
            </addressBlock>
            <addressBlock>
                <offset>0x0E</offset>
                <size>10</size>
                <usage>registers</usage>
            </addressBlock>
            <addressBlock>
                <offset>0x18</offset>
                <size>4</size>
                <usage>registers</usage>
            </addressBlock>
            <addressBlock>
                <offset>0x1C</offset>
                <size>3</size>
                <usage>registers</usage>
            </addressBlock>
            <addressBlock>
                <offset>0x22</offset>
                <size>1</size>
                <usage>registers</usage>
            </addressBlock>
            <addressBlock>
                <offset>0x24</offset>
                <size>1</size>
                <usage>registers</usage>
            </addressBlock>
            <addressBlock>
                <offset>0x28</offset>
                <size>1</size>
                <usage>registers</usage>
            </addressBlock>
            <addressBlock>
                <offset>0x2A</offset>
                <size>5</size>
                <usage>registers</usage>
            </addressBlock>
            <addressBlock>
                <offset>0x40</offset>
                <size>6</size>
                <usage>registers</usage>
            </addressBlock>
            <addressBlock>
                <offset>0x52</offset>
                <size>58</size>
                <usage>registers</usage>
            </addressBlock>
            <registers>
                <register>
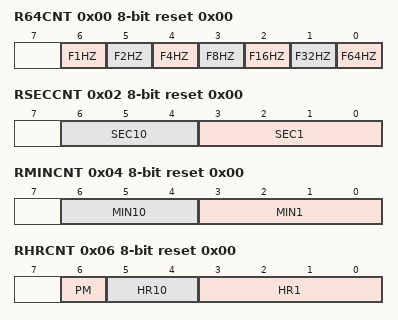
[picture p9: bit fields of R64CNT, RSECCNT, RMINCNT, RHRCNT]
                    <name>R64CNT</name>
                    <description>64-Hz Counter</description>
                    <addressOffset>0x00</addressOffset>
                    <size>8</size>
                    <access>read-only</access>
                    <resetValue>0x00</resetValue>
                    <resetMask>0x80</resetMask>
                    <fields>
                        <field>
                            <name>F64HZ</name>
                            <description>64-Hz Flag</description>
                            <lsb>0</lsb>
                            <msb>0</msb>
                            <access>read-only</access>
                        </field>
                        <field>
                            <name>F32HZ</name>
                            <description>32-Hz Flag</description>
                            <lsb>1</lsb>
                            <msb>1</msb>
                            <access>read-only</access>
                        </field>
                        <field>
                            <name>F16HZ</name>
                            <description>16-Hz Flag</description>
                            <lsb>2</lsb>
                            <msb>2</msb>
                            <access>read-only</access>
                        </field>
                        <field>
                            <name>F8HZ</name>
                            <description>8-Hz Flag</description>
                            <lsb>3</lsb>
                            <msb>3</msb>
                            <access>read-only</access>
                        </field>
                        <field>
                            <name>F4HZ</name>
                            <description>4-Hz Flag</description>
                            <lsb>4</lsb>
                            <msb>4</msb>
                            <access>read-only</access>
                        </field>
                        <field>
                            <name>F2HZ</name>
                            <description>2-Hz Flag</description>
                            <lsb>5</lsb>
                            <msb>5</msb>
                            <access>read-only</access>
                        </field>
                        <field>
                            <name>F1HZ</name>
                            <description>1-Hz Flag</description>
                            <lsb>6</lsb>
                            <msb>6</msb>
                            <access>read-only</access>
                        </field>
                    </fields>
                </register>
                <register>
                    <dim>4</dim>
                    <dimIncrement>0x02</dimIncrement>
                    <dimIndex>0-3</dimIndex>
                    <name>BCNT%s</name>
                    <description>Binary Counter %s</description>
                    <addressOffset>0x02</addressOffset>
                    <size>8</size>
                    <access>read-write</access>
                    <resetValue>0x00</resetValue>
                    <resetMask>0x00</resetMask>
                    <fields>
                        <field>
                            <name>BCNT</name>
                            <description>Binary Counter</description>
                            <lsb>0</lsb>
                            <msb>7</msb>
                            <access>read-write</access>
                        </field>
                    </fields>
                </register>
                <register>
                    <name>RSECCNT</name>
                    <description>Second Counter (in Calendar Count Mode)</description>
                    <addressOffset>0x02</addressOffset>
                    <size>8</size>
                    <access>read-write</access>
                    <resetValue>0x00</resetValue>
                    <resetMask>0x00</resetMask>
                    <fields>
                        <field>
                            <name>SEC1</name>
                            <description>1-Second Count</description>
                            <lsb>0</lsb>
                            <msb>3</msb>
                            <access>read-write</access>
                        </field>
                        <field>
                            <name>SEC10</name>
                            <description>10-Second Count</description>
                            <lsb>4</lsb>
                            <msb>6</msb>
                            <access>read-write</access>
                        </field>
                    </fields>
                </register>
                <register>
                    <name>RMINCNT</name>
                    <description>Minute Counter (in Calendar Count Mode)</description>
                    <addressOffset>0x04</addressOffset>
                    <size>8</size>
                    <access>read-write</access>
                    <resetValue>0x00</resetValue>
                    <resetMask>0x00</resetMask>
                    <fields>
                        <field>
                            <name>MIN1</name>
                            <description>1-Minute Count</description>
                            <lsb>0</lsb>
                            <msb>3</msb>
                            <access>read-write</access>
                        </field>
                        <field>
                            <name>MIN10</name>
                            <description>10-Minute Count</description>
                            <lsb>4</lsb>
                            <msb>6</msb>
                            <access>read-write</access>
                        </field>
                    </fields>
                </register>
                <register>
                    <name>RHRCNT</name>
                    <description>Hour Counter (in Calendar Count Mode)</description>
                    <addressOffset>0x06</addressOffset>
                    <size>8</size>
                    <access>read-write</access>
                    <resetValue>0x00</resetValue>
                    <resetMask>0x00</resetMask>
                    <fields>
                        <field>
                            <name>HR1</name>
                            <description>1-Hour Count</description>
                            <lsb>0</lsb>
                            <msb>3</msb>
                            <access>read-write</access>
                        </field>
                        <field>
                            <name>HR10</name>
                            <description>10-Hour Count</description>
                            <lsb>4</lsb>
                            <msb>5</msb>
                            <access>read-write</access>
                        </field>
                        <field>
                            <name>PM</name>
                            <description>AM/PM select for time counter setting.</description>
                            <lsb>6</lsb>
                            <msb>6</msb>
                            <access>read-write</access>
                            <enumeratedValues>
                                </enumeratedValues>
                        </field>
                    </fields>
                </register>
                <register>
                    <name>RWKCNT</name>
                    <description>Day,of,Week Counter (in Calendar Count Mode)</description>
                    <addressOffset>0x08</addressOffset>
                    <size>8</size>
                    <access>read-write</access>
                    <resetValue>0x00</resetValue>
                    <resetMask>0x00</resetMask>
                    <fields>
                        <field>
                            <name>DAYW</name>
                            <description>Day,of,Week Counting</description>
                            <lsb>0</lsb>
                            <msb>2</msb>
                            <access>read-write</access>
                            <enumeratedValues>
                                </enumeratedValues>
                        </field>
                    </fields>
                </register>
                <register>
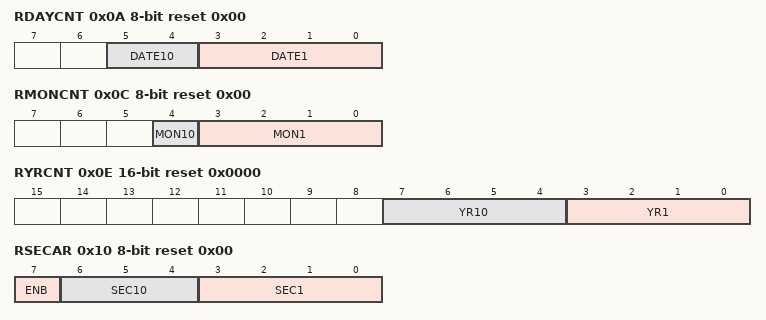
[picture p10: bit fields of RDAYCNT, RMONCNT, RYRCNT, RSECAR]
                    <name>RDAYCNT</name>
                    <description>Day Counter</description>
                    <addressOffset>0x0A</addressOffset>
                    <size>8</size>
                    <access>read-write</access>
                    <resetValue>0x00</resetValue>
                    <resetMask>0xc0</resetMask>
                    <fields>
                        <field>
                            <name>DATE1</name>
                            <description>1-Day Count</description>
                            <lsb>0</lsb>
                            <msb>3</msb>
                            <access>read-write</access>
                        </field>
                        <field>
                            <name>DATE10</name>
                            <description>10-Day Count</description>
                            <lsb>4</lsb>
                            <msb>5</msb>
                            <access>read-write</access>
                        </field>
                    </fields>
                </register>
                <register>
                    <name>RMONCNT</name>
                    <description>Month Counter</description>
                    <addressOffset>0x0C</addressOffset>
                    <size>8</size>
                    <access>read-write</access>
                    <resetValue>0x00</resetValue>
                    <resetMask>0xe0</resetMask>
                    <fields>
                        <field>
                            <name>MON1</name>
                            <description>1-Month Count</description>
                            <lsb>0</lsb>
                            <msb>3</msb>
                            <access>read-write</access>
                        </field>
                        <field>
                            <name>MON10</name>
                            <description>10-Month Count</description>
                            <lsb>4</lsb>
                            <msb>4</msb>
                            <access>read-write</access>
                        </field>
                    </fields>
                </register>
                <register>
                    <name>RYRCNT</name>
                    <description>Year Counter</description>
                    <addressOffset>0x0E</addressOffset>
                    <size>16</size>
                    <access>read-write</access>
                    <resetValue>0x0000</resetValue>
                    <resetMask>0xff00</resetMask>
                    <fields>
                        <field>
                            <name>YR1</name>
                            <description>1-Year Count</description>
                            <lsb>0</lsb>
                            <msb>3</msb>
                            <access>read-write</access>
                        </field>
                        <field>
                            <name>YR10</name>
                            <description>10-Year Count</description>
                            <lsb>4</lsb>
                            <msb>7</msb>
                            <access>read-write</access>
                        </field>
                    </fields>
                </register>
                <register>
                    <dim>4</dim>
                    <dimIncrement>0x02</dimIncrement>
                    <dimIndex>0-3</dimIndex>
                    <name>BCNT%sAR</name>
                    <description>Binary Counter %s Alarm Register</description>
                    <addressOffset>0x10</addressOffset>
                    <size>8</size>
                    <access>read-write</access>
                    <resetValue>0x00</resetValue>
                    <resetMask>0x00</resetMask>
                    <fields>
                        <field>
                            <name>BCNTAR</name>
                            <description>Alarm register associated with the 32-bit binary counter</description>
                            <lsb>0</lsb>
                            <msb>7</msb>
                            <access>read-write</access>
                        </field>
                    </fields>
                </register>
                <register>
                    <name>RSECAR</name>
                    <description>Second Alarm Register (in Calendar Count Mode)</description>
                    <addressOffset>0x10</addressOffset>
                    <size>8</size>
                    <access>read-write</access>
                    <resetValue>0x00</resetValue>
                    <resetMask>0x00</resetMask>
                    <fields>
                        <field>
                            <name>SEC1</name>
                            <description>1 Second</description>
                            <lsb>0</lsb>
                            <msb>3</msb>
                            <access>read-write</access>
                        </field>
                        <field>
                            <name>SEC10</name>
                            <description>10 Seconds</description>
                            <lsb>4</lsb>
                            <msb>6</msb>
                            <access>read-write</access>
                        </field>
                        <field>
                            <name>ENB</name>
                            <description>ENB</description>
                            <lsb>7</lsb>
                            <msb>7</msb>
                            <access>read-write</access>
                            <enumeratedValues>
                                </enumeratedValues>
                        </field>
                    </fields>
                </register>
                <register>
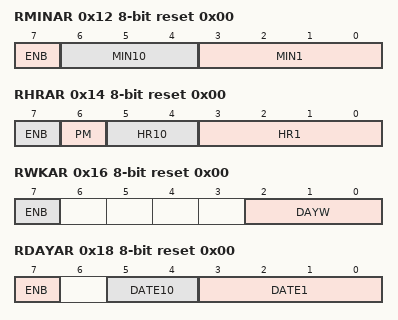
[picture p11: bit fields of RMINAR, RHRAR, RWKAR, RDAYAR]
                    <name>RMINAR</name>
                    <description>Minute Alarm Register (in Calendar Count Mode)</description>
                    <addressOffset>0x12</addressOffset>
                    <size>8</size>
                    <access>read-write</access>
                    <resetValue>0x00</resetValue>
                    <resetMask>0x00</resetMask>
                    <fields>
                        <field>
                            <name>MIN1</name>
                            <description>1 Minute</description>
                            <lsb>0</lsb>
                            <msb>3</msb>
                            <access>read-write</access>
                        </field>
                        <field>
                            <name>MIN10</name>
                            <description>10 Minutes</description>
                            <lsb>4</lsb>
                            <msb>6</msb>
                            <access>read-write</access>
                        </field>
                        <field>
                            <name>ENB</name>
                            <description>ENB</description>
                            <lsb>7</lsb>
                            <msb>7</msb>
                            <access>read-write</access>
                            <enumeratedValues>
                                </enumeratedValues>
                        </field>
                    </fields>
                </register>
                <register>
                    <name>RHRAR</name>
                    <description>Hour Alarm Register (in Calendar Count Mode)</description>
                    <addressOffset>0x14</addressOffset>
                    <size>8</size>
                    <access>read-write</access>
                    <resetValue>0x00</resetValue>
                    <resetMask>0x00</resetMask>
                    <fields>
                        <field>
                            <name>HR1</name>
                            <description>1 Hour</description>
                            <lsb>0</lsb>
                            <msb>3</msb>
                            <access>read-write</access>
                        </field>
                        <field>
                            <name>HR10</name>
                            <description>10 Hours</description>
                            <lsb>4</lsb>
                            <msb>5</msb>
                            <access>read-write</access>
                        </field>
                        <field>
                            <name>PM</name>
                            <description>AM/PM select for alarm setting.</description>
                            <lsb>6</lsb>
                            <msb>6</msb>
                            <access>read-write</access>
                            <enumeratedValues>
                                </enumeratedValues>
                        </field>
                        <field>
                            <name>ENB</name>
                            <description>ENB</description>
                            <lsb>7</lsb>
                            <msb>7</msb>
                            <access>read-write</access>
                            <enumeratedValues>
                                </enumeratedValues>
                        </field>
                    </fields>
                </register>
                <register>
                    <name>RWKAR</name>
                    <description>Day,of,Week Alarm Register (in Calendar Count Mode)</description>
                    <addressOffset>0x16</addressOffset>
                    <size>8</size>
                    <access>read-write</access>
                    <resetValue>0x00</resetValue>
                    <resetMask>0x00</resetMask>
                    <fields>
                        <field>
                            <name>DAYW</name>
                            <description>Day,of,Week Setting</description>
                            <lsb>0</lsb>
                            <msb>2</msb>
                            <access>read-write</access>
                            <enumeratedValues>
                                </enumeratedValues>
                        </field>
                        <field>
                            <name>ENB</name>
                            <description>ENB</description>
                            <lsb>7</lsb>
                            <msb>7</msb>
                            <access>read-write</access>
                            <enumeratedValues>
                                </enumeratedValues>
                        </field>
                    </fields>
                </register>
                <register>
                    <dim>2</dim>
                    <dimIncrement>0x02</dimIncrement>
                    <dimIndex>0-1</dimIndex>
                    <name>BCNT%sAER</name>
                    <description>Binary Counter %s Alarm Enable Register</description>
                    <addressOffset>0x18</addressOffset>
                    <size>8</size>
                    <access>read-write</access>
                    <resetValue>0x00</resetValue>
                    <resetMask>0x00</resetMask>
                    <fields>
                        <field>
                            <name>ENB</name>
                            <description>Setting the alarm enable associated with the 32-bit binary counter</description>
                            <lsb>0</lsb>
                            <msb>7</msb>
                            <access>read-write</access>
                        </field>
                    </fields>
                </register>
                <register>
                    <name>RDAYAR</name>
                    <description>Date Alarm Register (in Calendar Count Mode)</description>
                    <addressOffset>0x18</addressOffset>
                    <size>8</size>
                    <access>read-write</access>
                    <resetValue>0x00</resetValue>
                    <resetMask>0x00</resetMask>
                    <fields>
                        <field>
                            <name>DATE1</name>
                            <description>1 Day</description>
                            <lsb>0</lsb>
                            <msb>3</msb>
                            <access>read-write</access>
                        </field>
                        <field>
                            <name>DATE10</name>
                            <description>10 Days</description>
                            <lsb>4</lsb>
                            <msb>5</msb>
                            <access>read-write</access>
                        </field>
                        <field>
                            <name>ENB</name>
                            <description>ENB</description>
                            <lsb>7</lsb>
                            <msb>7</msb>
                            <access>read-write</access>
                            <enumeratedValues>
                                </enumeratedValues>
                        </field>
                    </fields>
                </register>
                <register>
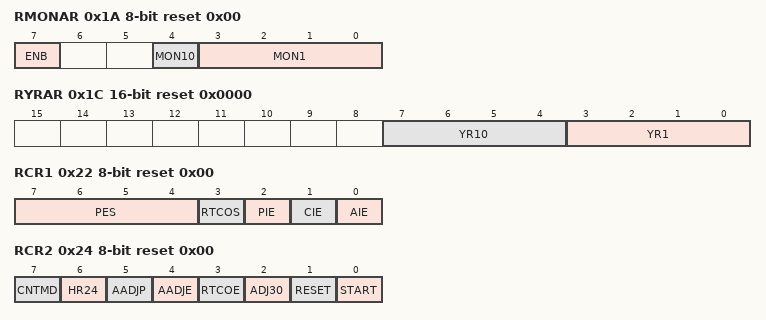
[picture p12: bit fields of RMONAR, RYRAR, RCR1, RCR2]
                    <name>RMONAR</name>
                    <description>Month Alarm Register (in Calendar Count Mode)</description>
                    <addressOffset>0x1A</addressOffset>
                    <size>8</size>
                    <access>read-write</access>
                    <resetValue>0x00</resetValue>
                    <resetMask>0x00</resetMask>
                    <fields>
                        <field>
                            <name>MON1</name>
                            <description>1 Month</description>
                            <lsb>0</lsb>
                            <msb>3</msb>
                            <access>read-write</access>
                        </field>
                        <field>
                            <name>MON10</name>
                            <description>10 Months</description>
                            <lsb>4</lsb>
                            <msb>4</msb>
                            <access>read-write</access>
                        </field>
                        <field>
                            <name>ENB</name>
                            <description>ENB</description>
                            <lsb>7</lsb>
                            <msb>7</msb>
                            <access>read-write</access>
                            <enumeratedValues>
                                </enumeratedValues>
                        </field>
                    </fields>
                </register>
                <register>
                    <name>BCNT2AER</name>
                    <description>Binary Counter 2 Alarm Enable Register</description>
                    <addressOffset>0x1C</addressOffset>
                    <size>16</size>
                    <access>read-write</access>
                    <resetValue>0x0000</resetValue>
                    <resetMask>0xff00</resetMask>
                    <fields>
                        <field>
                            <name>ENB</name>
                            <description>Setting the alarm enable associated with the 32-bit binary counter</description>
                            <lsb>0</lsb>
                            <msb>7</msb>
                            <access>read-write</access>
                        </field>
                    </fields>
                </register>
                <register>
                    <name>RYRAR</name>
                    <description>Year Alarm Register (in Calendar Count Mode)</description>
                    <alternateRegister>BCNT2AER</alternateRegister>
                    <addressOffset>0x1C</addressOffset>
                    <size>16</size>
                    <access>read-write</access>
                    <resetValue>0x0000</resetValue>
                    <resetMask>0xff00</resetMask>
                    <fields>
                        <field>
                            <name>YR1</name>
                            <description>1 Year</description>
                            <lsb>0</lsb>
                            <msb>3</msb>
                            <access>read-write</access>
                        </field>
                        <field>
                            <name>YR10</name>
                            <description>10 Years</description>
                            <lsb>4</lsb>
                            <msb>7</msb>
                            <access>read-write</access>
                        </field>
                    </fields>
                </register>
                <register>
                    <name>BCNT3AER</name>
                    <description>Binary Counter 3 Alarm Enable Register</description>
                    <addressOffset>0x1E</addressOffset>
                    <size>8</size>
                    <access>read-write</access>
                    <resetValue>0x00</resetValue>
                    <resetMask>0x00</resetMask>
                    <fields>
                        <field>
                            <name>ENB</name>
                            <description>Setting the alarm enable associated with the 32-bit binary counter</description>
                            <lsb>0</lsb>
                            <msb>7</msb>
                            <access>read-write</access>
                        </field>
                    </fields>
                </register>
                <register>
                    <name>RYRAREN</name>
                    <description>Year Alarm Enable Register (in Calendar Count Mode)</description>
                    <alternateRegister>BCNT3AER</alternateRegister>
                    <addressOffset>0x1E</addressOffset>
                    <size>8</size>
                    <access>read-write</access>
                    <resetValue>0x00</resetValue>
                    <resetMask>0x00</resetMask>
                    <fields>
                        <field>
                            <name>ENB</name>
                            <description>ENB</description>
                            <lsb>7</lsb>
                            <msb>7</msb>
                            <access>read-write</access>
                            <enumeratedValues>
                                </enumeratedValues>
                        </field>
                    </fields>
                </register>
                <register>
                    <name>RCR1</name>
                    <description>RTC Control Register 1</description>
                    <addressOffset>0x22</addressOffset>
                    <size>8</size>
                    <access>read-write</access>
                    <resetValue>0x00</resetValue>
                    <resetMask>0x0a</resetMask>
                    <fields>
                        <field>
                            <name>AIE</name>
                            <description>Alarm Interrupt Enable</description>
                            <lsb>0</lsb>
                            <msb>0</msb>
                            <access>read-write</access>
                            <enumeratedValues>
                                </enumeratedValues>
                        </field>
                        <field>
                            <name>CIE</name>
                            <description>Carry Interrupt Enable</description>
                            <lsb>1</lsb>
                            <msb>1</msb>
                            <access>read-write</access>
                            <enumeratedValues>
                                </enumeratedValues>
                        </field>
                        <field>
                            <name>PIE</name>
                            <description>Periodic Interrupt Enable</description>
                            <lsb>2</lsb>
                            <msb>2</msb>
                            <access>read-write</access>
                            <enumeratedValues>
                                </enumeratedValues>
                        </field>
                        <field>
                            <name>RTCOS</name>
                            <description>RTCOUT Output Select</description>
                            <lsb>3</lsb>
                            <msb>3</msb>
                            <access>read-write</access>
                            <enumeratedValues>
                                </enumeratedValues>
                        </field>
                        <field>
                            <name>PES</name>
                            <description>Periodic Interrupt Select</description>
                            <lsb>4</lsb>
                            <msb>7</msb>
                            <access>read-write</access>
                            <enumeratedValues>
                                </enumeratedValues>
                        </field>
                    </fields>
                </register>
                <register>
                    <name>RCR2</name>
                    <description>RTC Control Register 2 (in Calendar Count Mode)</description>
                    <addressOffset>0x24</addressOffset>
                    <size>8</size>
                    <access>read-write</access>
                    <resetValue>0x00</resetValue>
                    <resetMask>0x0e</resetMask>
                    <fields>
                        <field>
                            <name>START</name>
                            <description>Start</description>
                            <lsb>0</lsb>
                            <msb>0</msb>
                            <access>read-write</access>
                            <enumeratedValues>
                                </enumeratedValues>
                        </field>
                        <field>
                            <name>RESET</name>
                            <description>RTC Software Reset</description>
                            <lsb>1</lsb>
                            <msb>1</msb>
                            <access>read-write</access>
                            <enumeratedValues>
                                </enumeratedValues>
                        </field>
                        <field>
                            <name>ADJ30</name>
                            <description>30-Second Adjustment</description>
                            <lsb>2</lsb>
                            <msb>2</msb>
                            <access>read-write</access>
                            <enumeratedValues>
                                </enumeratedValues>
                        </field>
                        <field>
                            <name>RTCOE</name>
                            <description>RTCOUT Output Enable</description>
                            <lsb>3</lsb>
                            <msb>3</msb>
                            <access>read-write</access>
                            <enumeratedValues>
                                </enumeratedValues>
                        </field>
                        <field>
                            <name>AADJE</name>
                            <description>Automatic Adjustment Enable</description>
                            <lsb>4</lsb>
                            <msb>4</msb>
                            <access>read-write</access>
                            <enumeratedValues>
                                </enumeratedValues>
                        </field>
                        <field>
                            <name>AADJP</name>
                            <description>Automatic Adjustment Period Select</description>
                            <lsb>5</lsb>
                            <msb>5</msb>
                            <access>read-write</access>
                            <enumeratedValues>
                                </enumeratedValues>
                        </field>
                        <field>
                            <name>HR24</name>
                            <description>Hours Mode</description>
                            <lsb>6</lsb>
                            <msb>6</msb>
                            <access>read-write</access>
                            <enumeratedValues>
                                </enumeratedValues>
                        </field>
                        <field>
                            <name>CNTMD</name>
                            <description>Count Mode Select</description>
                            <lsb>7</lsb>
                            <msb>7</msb>
                            <access>read-write</access>
                            <enumeratedValues>
                                </enumeratedValues>
                        </field>
                    </fields>
                </register>
                <register>
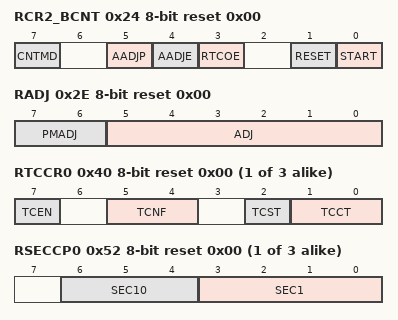
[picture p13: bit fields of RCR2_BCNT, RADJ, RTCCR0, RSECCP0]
                    <name>RCR2_BCNT</name>
                    <description>RTC Control Register 2 (in Binary Count Mode)</description>
                    <alternateRegister>RCR2</alternateRegister>
                    <addressOffset>0x24</addressOffset>
                    <size>8</size>
                    <access>read-write</access>
                    <resetValue>0x00</resetValue>
                    <resetMask>0x0e</resetMask>
                    <fields>
                        <field>
                            <name>START</name>
                            <description>Start</description>
                            <lsb>0</lsb>
                            <msb>0</msb>
                            <access>read-write</access>
                            <enumeratedValues>
                                </enumeratedValues>
                        </field>
                        <field>
                            <name>RESET</name>
                            <description>RTC Software Reset</description>
                            <lsb>1</lsb>
                            <msb>1</msb>
                            <access>read-write</access>
                            <enumeratedValues>
                                </enumeratedValues>
                        </field>
                        <field>
                            <name>RTCOE</name>
                            <description>RTCOUT Output Enable</description>
                            <lsb>3</lsb>
                            <msb>3</msb>
                            <access>read-write</access>
                            <enumeratedValues>
                                </enumeratedValues>
                        </field>
                        <field>
                            <name>AADJE</name>
                            <description>Automatic Adjustment Enable</description>
                            <lsb>4</lsb>
                            <msb>4</msb>
                            <access>read-write</access>
                            <enumeratedValues>
                                </enumeratedValues>
                        </field>
                        <field>
                            <name>AADJP</name>
                            <description>Automatic Adjustment Period Select</description>
                            <lsb>5</lsb>
                            <msb>5</msb>
                            <access>read-write</access>
                            <enumeratedValues>
                                </enumeratedValues>
                        </field>
                        <field>
                            <name>CNTMD</name>
                            <description>Count Mode Select</description>
                            <lsb>7</lsb>
                            <msb>7</msb>
                            <access>read-write</access>
                            <enumeratedValues>
                                </enumeratedValues>
                        </field>
                    </fields>
                </register>
                <register>
                    <name>RCR4</name>
                    <description>RTC Control Register 4</description>
                    <addressOffset>0x28</addressOffset>
                    <size>8</size>
                    <access>read-write</access>
                    <resetValue>0x00</resetValue>
                    <resetMask>0xfe</resetMask>
                    <fields>
                        <field>
                            <name>RCKSEL</name>
                            <description>Count Source Select </description>
                            <lsb>0</lsb>
                            <msb>0</msb>
                            <access>read-write</access>
                            <enumeratedValues>
                                </enumeratedValues>
                        </field>
                    </fields>
                </register>
                <register>
                    <name>RFRH</name>
                    <description>Frequency Register H</description>
                    <addressOffset>0x2A</addressOffset>
                    <size>16</size>
                    <access>read-write</access>
                    <resetValue>0x0000</resetValue>
                    <resetMask>0xfffe</resetMask>
                    <fields>
                        <field>
                            <name>RFC16</name>
                            <description>Write 0 before writing to the RFRL register after a cold start.</description>
                            <lsb>0</lsb>
                            <msb>0</msb>
                            <access>read-write</access>
                        </field>
                    </fields>
                </register>
                <register>
                    <name>RFRL</name>
                    <description>Frequency Register L</description>
                    <addressOffset>0x2C</addressOffset>
                    <size>16</size>
                    <access>read-write</access>
                    <resetValue>0x0000</resetValue>
                    <resetMask>0x0000</resetMask>
                    <fields>
                        <field>
                            <name>RFC</name>
                            <description>Frequency Comparison Value</description>
                            <lsb>0</lsb>
                            <msb>15</msb>
                            <access>read-write</access>
                        </field>
                    </fields>
                </register>
                <register>
                    <name>RADJ</name>
                    <description>Time Error Adjustment Register</description>
                    <addressOffset>0x2E</addressOffset>
                    <size>8</size>
                    <access>read-write</access>
                    <resetValue>0x00</resetValue>
                    <resetMask>0x00</resetMask>
                    <fields>
                        <field>
                            <name>ADJ</name>
                            <description>Adjustment Value</description>
                            <lsb>0</lsb>
                            <msb>5</msb>
                            <access>read-write</access>
                        </field>
                        <field>
                            <name>PMADJ</name>
                            <description>Plus,Minus</description>
                            <lsb>6</lsb>
                            <msb>7</msb>
                            <access>read-write</access>
                            <enumeratedValues>
                                </enumeratedValues>
                        </field>
                    </fields>
                </register>
                <register>
                    <dim>3</dim>
                    <dimIncrement>0x02</dimIncrement>
                    <dimIndex>0-2</dimIndex>
                    <name>RTCCR%s</name>
                    <description>Time Capture Control Register %s</description>
                    <addressOffset>0x40</addressOffset>
                    <size>8</size>
                    <access>read-write</access>
                    <resetValue>0x00</resetValue>
                    <resetMask>0x48</resetMask>
                    <fields>
                        <field>
                            <name>TCCT</name>
                            <description>Time Capture Control</description>
                            <lsb>0</lsb>
                            <msb>1</msb>
                            <access>read-write</access>
                            <enumeratedValues>
                                </enumeratedValues>
                        </field>
                        <field>
                            <name>TCST</name>
                            <description>Time Capture Status</description>
                            <lsb>2</lsb>
                            <msb>2</msb>
                            <access>read-write</access>
                            <enumeratedValues>
                                </enumeratedValues>
                        </field>
                        <field>
                            <name>TCNF</name>
                            <description>Time Capture Noise Filter Control</description>
                            <lsb>4</lsb>
                            <msb>5</msb>
                            <access>read-write</access>
                            <enumeratedValues>
                                </enumeratedValues>
                        </field>
                        <field>
                            <name>TCEN</name>
                            <description>Time Capture Event Input Pin Enable</description>
                            <lsb>7</lsb>
                            <msb>7</msb>
                            <access>read-write</access>
                            <enumeratedValues>
                                </enumeratedValues>
                        </field>
                    </fields>
                </register>
                <register>
                    <dim>3</dim>
                    <dimIncrement>0x10</dimIncrement>
                    <dimIndex>0-2</dimIndex>
                    <name>BCNT0CP%s</name>
                    <description>BCNT0 Capture Register %s</description>
                    <addressOffset>0x52</addressOffset>
                    <size>8</size>
                    <access>read-only</access>
                    <resetValue>0x00</resetValue>
                    <resetMask>0x00</resetMask>
                </register>
                <register>
                    <dim>3</dim>
                    <dimIncrement>0x10</dimIncrement>
                    <dimIndex>0-2</dimIndex>
                    <name>RSECCP%s</name>
                    <description>Second Capture Register %s</description>
                    <alternateRegister>BCNT0CP%s</alternateRegister>
                    <addressOffset>0x52</addressOffset>
                    <size>8</size>
                    <access>read-only</access>
                    <resetValue>0x00</resetValue>
                    <resetMask>0x00</resetMask>
                    <fields>
                        <field>
                            <name>SEC1</name>
                            <description>1-Second Capture</description>
                            <lsb>0</lsb>
                            <msb>3</msb>
                            <access>read-only</access>
                        </field>
                        <field>
                            <name>SEC10</name>
                            <description>10-Second Capture</description>
                            <lsb>4</lsb>
                            <msb>6</msb>
                            <access>read-only</access>
                        </field>
                    </fields>
                </register>
                <register>
                    <dim>3</dim>
                    <dimIncrement>0x10</dimIncrement>
                    <dimIndex>0-2</dimIndex>
                    <name>BCNT1CP%s</name>
                    <description>BCNT1 Capture Register %s</description>
                    <addressOffset>0x54</addressOffset>
                    <size>8</size>
                    <access>read-only</access>
                    <resetValue>0x00</resetValue>
                    <resetMask>0x00</resetMask>
                </register>
                <register>
                    <dim>3</dim>
                    <dimIncrement>0x10</dimIncrement>
                    <dimIndex>0-2</dimIndex>
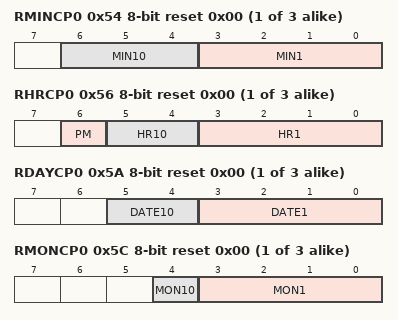
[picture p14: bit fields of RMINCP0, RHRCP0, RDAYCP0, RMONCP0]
                    <name>RMINCP%s</name>
                    <description>Minute Capture Register %s</description>
                    <alternateRegister>BCNT1CP%s</alternateRegister>
                    <addressOffset>0x54</addressOffset>
                    <size>8</size>
                    <access>read-only</access>
                    <resetValue>0x00</resetValue>
                    <resetMask>0x00</resetMask>
                    <fields>
                        <field>
                            <name>MIN1</name>
                            <description>1-Minute Capture</description>
                            <lsb>0</lsb>
                            <msb>3</msb>
                            <access>read-only</access>
                        </field>
                        <field>
                            <name>MIN10</name>
                            <description>10-Minute Capture</description>
                            <lsb>4</lsb>
                            <msb>6</msb>
                            <access>read-only</access>
                        </field>
                    </fields>
                </register>
                <register>
                    <dim>3</dim>
                    <dimIncrement>0x10</dimIncrement>
                    <dimIndex>0-2</dimIndex>
                    <name>BCNT2CP%s</name>
                    <description>BCNT2 Capture Register %s</description>
                    <addressOffset>0x56</addressOffset>
                    <size>8</size>
                    <access>read-only</access>
                    <resetValue>0x00</resetValue>
                    <resetMask>0x00</resetMask>
                </register>
                <register>
                    <dim>3</dim>
                    <dimIncrement>0x10</dimIncrement>
                    <dimIndex>0-2</dimIndex>
                    <name>RHRCP%s</name>
                    <description>Hour Capture Register %s</description>
                    <alternateRegister>BCNT2CP%s</alternateRegister>
                    <addressOffset>0x56</addressOffset>
                    <size>8</size>
                    <access>read-only</access>
                    <resetValue>0x00</resetValue>
                    <resetMask>0x00</resetMask>
                    <fields>
                        <field>
                            <name>HR1</name>
                            <description>1-Hour Capture</description>
                            <lsb>0</lsb>
                            <msb>3</msb>
                            <access>read-only</access>
                        </field>
                        <field>
                            <name>HR10</name>
                            <description>10-Hour Capture</description>
                            <lsb>4</lsb>
                            <msb>5</msb>
                            <access>read-only</access>
                        </field>
                        <field>
                            <name>PM</name>
                            <description>PM</description>
                            <lsb>6</lsb>
                            <msb>6</msb>
                            <access>read-only</access>
                            <enumeratedValues>
                                </enumeratedValues>
                        </field>
                    </fields>
                </register>
                <register>
                    <dim>3</dim>
                    <dimIncrement>0x10</dimIncrement>
                    <dimIndex>0-2</dimIndex>
                    <name>BCNT3CP%s</name>
                    <description>BCNT3 Capture Register %s</description>
                    <addressOffset>0x5A</addressOffset>
                    <size>8</size>
                    <access>read-only</access>
                    <resetValue>0x00</resetValue>
                    <resetMask>0x00</resetMask>
                </register>
                <register>
                    <dim>3</dim>
                    <dimIncrement>0x10</dimIncrement>
                    <dimIndex>0-2</dimIndex>
                    <name>RDAYCP%s</name>
                    <description>Date Capture Register %s</description>
                    <alternateRegister>BCNT3CP%s</alternateRegister>
                    <addressOffset>0x5A</addressOffset>
                    <size>8</size>
                    <access>read-only</access>
                    <resetValue>0x00</resetValue>
                    <resetMask>0x00</resetMask>
                    <fields>
                        <field>
                            <name>DATE1</name>
                            <description>1-Day Capture</description>
                            <lsb>0</lsb>
                            <msb>3</msb>
                            <access>read-only</access>
                        </field>
                        <field>
                            <name>DATE10</name>
                            <description>10-Day Capture</description>
                            <lsb>4</lsb>
                            <msb>5</msb>
                            <access>read-only</access>
                        </field>
                    </fields>
                </register>
                <register>
                    <dim>3</dim>
                    <dimIncrement>0x10</dimIncrement>
                    <dimIndex>0-2</dimIndex>
                    <name>RMONCP%s</name>
                    <description>Month Capture Register %s</description>
                    <addressOffset>0x5C</addressOffset>
                    <size>8</size>
                    <access>read-only</access>
                    <resetValue>0x00</resetValue>
                    <resetMask>0xe0</resetMask>
                    <fields>
                        <field>
                            <name>MON1</name>
                            <description>1-Month Capture</description>
                            <lsb>0</lsb>
                            <msb>3</msb>
                            <access>read-only</access>
                        </field>
                        <field>
                            <name>MON10</name>
                            <description>10-Month Capture</description>
                            <lsb>4</lsb>
                            <msb>4</msb>
                            <access>read-only</access>
                        </field>
                    </fields>
                </register>
            </registers>
        </peripheral>
        <peripheral>
            <name>IWDT</name>
            <description>Independent Watchdog Timer</description>
            <baseAddress>0x40083200</baseAddress>
            <addressBlock>
                <offset>0x00</offset>
                <size>1</size>
                <usage>registers</usage>
            </addressBlock>
            <addressBlock>
                <offset>0x04</offset>
                <size>2</size>
                <usage>registers</usage>
            </addressBlock>
            <registers>
                <register>
                    <name>IWDTRR</name>
                    <description>IWDT Refresh Register</description>
                    <addressOffset>0x00</addressOffset>
                    <size>8</size>
                    <access>read-write</access>
                    <resetValue>0xff</resetValue>
                    <resetMask>0xff</resetMask>
                </register>
                <register>
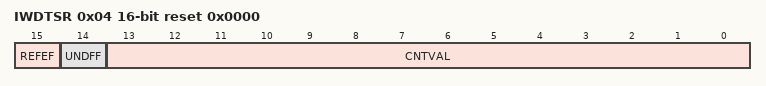
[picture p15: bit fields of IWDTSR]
                    <name>IWDTSR</name>
                    <description>IWDT Status Register</description>
                    <addressOffset>0x04</addressOffset>
                    <size>16</size>
                    <access>read-write</access>
                    <resetValue>0x0000</resetValue>
                    <resetMask>0xffff</resetMask>
                    <fields>
                        <field>
                            <name>CNTVAL</name>
                            <description>Down,counter Value</description>
                            <lsb>0</lsb>
                            <msb>13</msb>
                            <access>read-only</access>
                        </field>
                        <field>
                            <name>UNDFF</name>
                            <description>Underflow Flag</description>
                            <lsb>14</lsb>
                            <msb>14</msb>
                            <access>read-write</access>
                            <enumeratedValues>
                                </enumeratedValues>
                        </field>
                        <field>
                            <name>REFEF</name>
                            <description>Refresh Error Flag</description>
                            <lsb>15</lsb>
                            <msb>15</msb>
                            <access>read-write</access>
                            <enumeratedValues>
                                </enumeratedValues>
                        </field>
                    </fields>
                </register>
            </registers>
        </peripheral>
        <peripheral>
            <name>WDT</name>
            <description>Watchdog Timer</description>
            <baseAddress>0x40083400</baseAddress>
            <addressBlock>
                <offset>0x00</offset>
                <size>1</size>
                <usage>registers</usage>
            </addressBlock>
            <addressBlock>
                <offset>0x02</offset>
                <size>5</size>
                <usage>registers</usage>
            </addressBlock>
            <addressBlock>
                <offset>0x08</offset>
                <size>1</size>
                <usage>registers</usage>
            </addressBlock>
            <registers>
                <register>
                    <name>WDTRR</name>
                    <description>WDT Refresh Register</description>
                    <addressOffset>0x00</addressOffset>
                    <size>8</size>
                    <access>read-write</access>
                    <resetValue>0xff</resetValue>
                    <resetMask>0xff</resetMask>
                </register>
                <register>
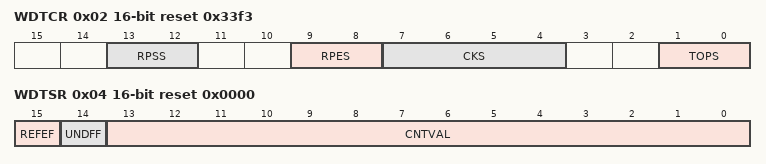
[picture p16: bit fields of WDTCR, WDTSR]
                    <name>WDTCR</name>
                    <description>WDT Control Register</description>
                    <addressOffset>0x02</addressOffset>
                    <size>16</size>
                    <access>read-write</access>
                    <resetValue>0x33f3</resetValue>
                    <resetMask>0xffff</resetMask>
                    <fields>
                        <field>
                            <name>TOPS</name>
                            <description>Timeout Period Select</description>
                            <lsb>0</lsb>
                            <msb>1</msb>
                            <access>read-write</access>
                            <enumeratedValues>
                                </enumeratedValues>
                        </field>
                        <field>
                            <name>CKS</name>
                            <description>Clock Division Ratio Select</description>
                            <lsb>4</lsb>
                            <msb>7</msb>
                            <access>read-write</access>
                            <enumeratedValues>
                                </enumeratedValues>
                        </field>
                        <field>
                            <name>RPES</name>
                            <description>Window End Position Select</description>
                            <lsb>8</lsb>
                            <msb>9</msb>
                            <access>read-write</access>
                            <enumeratedValues>
                                </enumeratedValues>
                        </field>
                        <field>
                            <name>RPSS</name>
                            <description>Window Start Position Select</description>
                            <lsb>12</lsb>
                            <msb>13</msb>
                            <access>read-write</access>
                            <enumeratedValues>
                                </enumeratedValues>
                        </field>
                    </fields>
                </register>
                <register>
                    <name>WDTSR</name>
                    <description>WDT Status Register</description>
                    <addressOffset>0x04</addressOffset>
                    <size>16</size>
                    <access>read-write</access>
                    <resetValue>0x0000</resetValue>
                    <resetMask>0xffff</resetMask>
                    <fields>
                        <field>
                            <name>CNTVAL</name>
                            <description>Down,Counter Value</description>
                            <lsb>0</lsb>
                            <msb>13</msb>
                            <access>read-only</access>
                        </field>
                        <field>
                            <name>UNDFF</name>
                            <description>Underflow Flag</description>
                            <lsb>14</lsb>
                            <msb>14</msb>
                            <access>read-write</access>
                            <enumeratedValues>
                                </enumeratedValues>
                        </field>
                        <field>
                            <name>REFEF</name>
                            <description>Refresh Error Flag</description>
                            <lsb>15</lsb>
                            <msb>15</msb>
                            <access>read-write</access>
                            <enumeratedValues>
                                </enumeratedValues>
                        </field>
                    </fields>
                </register>
                <register>
                    <name>WDTRCR</name>
                    <description>WDT Reset Control Register</description>
                    <addressOffset>0x06</addressOffset>
                    <size>8</size>
                    <access>read-write</access>
                    <resetValue>0x80</resetValue>
                    <resetMask>0xff</resetMask>
                    <fields>
                        <field>
                            <name>RSTIRQS</name>
                            <description>WDT Behavior Selection</description>
                            <lsb>7</lsb>
                            <msb>7</msb>
                            <access>read-write</access>
                            <enumeratedValues>
                                </enumeratedValues>
                        </field>
                    </fields>
                </register>
                <register>
                    <name>WDTCSTPR</name>
                    <description>WDT Count Stop Control Register</description>
                    <addressOffset>0x08</addressOffset>
                    <size>8</size>
                    <access>read-write</access>
                    <resetValue>0x80</resetValue>
                    <resetMask>0xff</resetMask>
                    <fields>
                        <field>
                            <name>SLCSTP</name>
                            <description>Sleep,Mode Count Stop Control Register</description>
                            <lsb>7</lsb>
                            <msb>7</msb>
                            <access>read-write</access>
                            <enumeratedValues>
                                </enumeratedValues>
                        </field>
                    </fields>
                </register>
            </registers>
        </peripheral>
        <peripheral>
            <name>CAC</name>
            <description>Clock Frequency Accuracy Measurement Circuit</description>
            <baseAddress>0x40083600</baseAddress>
            <addressBlock>
                <offset>0x00</offset>
                <size>5</size>
                <usage>registers</usage>
            </addressBlock>
            <addressBlock>
                <offset>0x06</offset>
                <size>6</size>
                <usage>registers</usage>
            </addressBlock>
            <registers>
                <register>
                    <name>CACR0</name>
                    <description>CAC Control Register 0</description>
                    <addressOffset>0x00</addressOffset>
                    <size>8</size>
                    <access>read-write</access>
                    <resetValue>0x00</resetValue>
                    <resetMask>0xff</resetMask>
                    <fields>
                        <field>
                            <name>CFME</name>
                            <description>Clock Frequency Measurement Enable</description>
                            <lsb>0</lsb>
                            <msb>0</msb>
                            <access>read-write</access>
                            <enumeratedValues>
                                </enumeratedValues>
                        </field>
                    </fields>
                </register>
                <register>
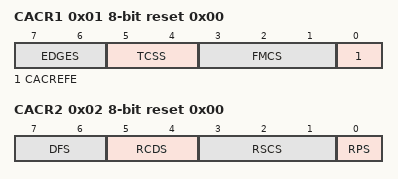
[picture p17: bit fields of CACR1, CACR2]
                    <name>CACR1</name>
                    <description>CAC Control Register 1</description>
                    <addressOffset>0x01</addressOffset>
                    <size>8</size>
                    <access>read-write</access>
                    <resetValue>0x00</resetValue>
                    <resetMask>0xff</resetMask>
                    <fields>
                        <field>
                            <name>CACREFE</name>
                            <description>CACREF Pin Input Enable</description>
                            <lsb>0</lsb>
                            <msb>0</msb>
                            <access>read-write</access>
                            <enumeratedValues>
                                </enumeratedValues>
                        </field>
                        <field>
                            <name>FMCS</name>
                            <description>Measurement Target Clock Select</description>
                            <lsb>1</lsb>
                            <msb>3</msb>
                            <access>read-write</access>
                            <enumeratedValues>
                                </enumeratedValues>
                        </field>
                        <field>
                            <name>TCSS</name>
                            <description>Timer Count Clock Source Select</description>
                            <lsb>4</lsb>
                            <msb>5</msb>
                            <access>read-write</access>
                            <enumeratedValues>
                                </enumeratedValues>
                        </field>
                        <field>
                            <name>EDGES</name>
                            <description>Valid Edge Select</description>
                            <lsb>6</lsb>
                            <msb>7</msb>
                            <access>read-write</access>
                            <enumeratedValues>
                                </enumeratedValues>
                        </field>
                    </fields>
                </register>
                <register>
                    <name>CACR2</name>
                    <description>CAC Control Register 2</description>
                    <addressOffset>0x02</addressOffset>
                    <size>8</size>
                    <access>read-write</access>
                    <resetValue>0x00</resetValue>
                    <resetMask>0xff</resetMask>
                    <fields>
                        <field>
                            <name>RPS</name>
                            <description>Reference Signal Select</description>
                            <lsb>0</lsb>
                            <msb>0</msb>
                            <access>read-write</access>
                            <enumeratedValues>
                                </enumeratedValues>
                        </field>
                        <field>
                            <name>RSCS</name>
                            <description>Measurement Reference Clock Select</description>
                            <lsb>1</lsb>
                            <msb>3</msb>
                            <access>read-write</access>
                            <enumeratedValues>
                                </enumeratedValues>
                        </field>
                        <field>
                            <name>RCDS</name>
                            <description>Measurement Reference Clock Frequency Division Ratio Select</description>
                            <lsb>4</lsb>
                            <msb>5</msb>
                            <access>read-write</access>
                            <enumeratedValues>
                                </enumeratedValues>
                        </field>
                        <field>
                            <name>DFS</name>
                            <description>Digital Filter Select</description>
                            <lsb>6</lsb>
                            <msb>7</msb>
                            <access>read-write</access>
                            <enumeratedValues>
                                </enumeratedValues>
                        </field>
                    </fields>
                </register>
                <register>
                    <name>CAICR</name>
                    <description>CAC Interrupt Control Register</description>
                    <addressOffset>0x03</addressOffset>
                    <size>8</size>
                    <access>read-write</access>
                    <resetValue>0x00</resetValue>
                    <resetMask>0xff</resetMask>
                    <fields>
                        <field>
                            <name>FERRIE</name>
                            <description>Frequency Error Interrupt Request Enable</description>
                            <lsb>0</lsb>
                            <msb>0</msb>
                            <access>read-write</access>
                            <enumeratedValues>
                                </enumeratedValues>
                        </field>
                        <field>
                            <name>MENDIE</name>
                            <description>Measurement End Interrupt Request Enable</description>
                            <lsb>1</lsb>
                            <msb>1</msb>
                            <access>read-write</access>
                            <enumeratedValues>
                                </enumeratedValues>
                        </field>
                        <field>
                            <name>OVFIE</name>
                            <description>Overflow Interrupt Request Enable</description>
                            <lsb>2</lsb>
                            <msb>2</msb>
                            <access>read-write</access>
                            <enumeratedValues>
                                </enumeratedValues>
                        </field>
                        <field>
                            <name>FERRFCL</name>
                            <description>FERRF Clear</description>
                            <lsb>4</lsb>
                            <msb>4</msb>
                            <access>write-only</access>
                            <enumeratedValues>
                                </enumeratedValues>
                        </field>
                        <field>
                            <name>MENDFCL</name>
                            <description>MENDF Clear</description>
                            <lsb>5</lsb>
                            <msb>5</msb>
                            <access>write-only</access>
                            <enumeratedValues>
                                </enumeratedValues>
                        </field>
                        <field>
                            <name>OVFFCL</name>
                            <description>OVFF Clear</description>
                            <lsb>6</lsb>
                            <msb>6</msb>
                            <access>write-only</access>
                            <enumeratedValues>
                                </enumeratedValues>
                        </field>
                    </fields>
                </register>
                <register>
                    <name>CASTR</name>
                    <description>CAC Status Register</description>
                    <addressOffset>0x04</addressOffset>
                    <size>8</size>
                    <access>read-only</access>
                    <resetValue>0x00</resetValue>
                    <resetMask>0xff</resetMask>
                    <fields>
                        <field>
                            <name>FERRF</name>
                            <description>Frequency Error Flag</description>
                            <lsb>0</lsb>
                            <msb>0</msb>
                            <access>read-only</access>
                            <enumeratedValues>
                                </enumeratedValues>
                        </field>
                        <field>
                            <name>MENDF</name>
                            <description>Measurement End Flag</description>
                            <lsb>1</lsb>
                            <msb>1</msb>
                            <access>read-only</access>
                            <enumeratedValues>
                                </enumeratedValues>
                        </field>
                        <field>
                            <name>OVFF</name>
                            <description>Overflow Flag</description>
                            <lsb>2</lsb>
                            <msb>2</msb>
                            <access>read-only</access>
                            <enumeratedValues>
                                </enumeratedValues>
                        </field>
                    </fields>
                </register>
                <register>
                    <name>CAULVR</name>
                    <description>CAC Upper,Limit Value Setting Register</description>
                    <addressOffset>0x06</addressOffset>
                    <size>16</size>
                    <access>read-write</access>
                    <resetValue>0x0000</resetValue>
                    <resetMask>0xffff</resetMask>
                </register>
                <register>
                    <name>CALLVR</name>
                    <description>CAC Lower,Limit Value Setting Register</description>
                    <addressOffset>0x08</addressOffset>
                    <size>16</size>
                    <access>read-write</access>
                    <resetValue>0x0000</resetValue>
                    <resetMask>0xffff</resetMask>
                </register>
                <register>
                    <name>CACNTBR</name>
                    <description>CAC Counter Buffer Register</description>
                    <addressOffset>0x0A</addressOffset>
                    <size>16</size>
                    <access>read-only</access>
                    <resetValue>0x0000</resetValue>
                    <resetMask>0xffff</resetMask>
                </register>
            </registers>
        </peripheral>
        <peripheral>
            <name>MSTP</name>
            <description>Module Stop Control</description>
            <baseAddress>0x40084000</baseAddress>
            <addressBlock>
                <offset>0x00</offset>
                <size>20</size>
                <usage>registers</usage>
            </addressBlock>
            <registers>
                <register>
                    <name>MSTPCRA</name>
                    <description>Module Stop Control Register A</description>
                    <addressOffset>0x000</addressOffset>
                    <size>32</size>
                    <access>read-write</access>
                    <resetValue>0xffbfff7e</resetValue>
                    <resetMask>0xffffffff</resetMask>
                    <fields>
                        <field>
                            <name>MSTPA0</name>
                            <description>SRAM0 Module Stop</description>
                            <lsb>0</lsb>
                            <msb>0</msb>
                            <access>read-write</access>
                            <enumeratedValues>
                                </enumeratedValues>
                        </field>
                        <field>
                            <name>MSTPA7</name>
                            <description>Standby SRAM Module Stop</description>
                            <lsb>7</lsb>
                            <msb>7</msb>
                            <access>read-write</access>
                            <enumeratedValues>
                                </enumeratedValues>
                        </field>
                        <field>
                            <name>MSTPA22</name>
                            <description>DMA Controller/Data Transfer Controller Module Stop</description>
                            <lsb>22</lsb>
                            <msb>22</msb>
                            <access>read-write</access>
                            <enumeratedValues>
                                </enumeratedValues>
                        </field>
                    </fields>
                </register>
                <register>
                    <name>MSTPCRB</name>
                    <description>Module Stop Control Register B</description>
                    <addressOffset>0x004</addressOffset>
                    <size>32</size>
                    <access>read-write</access>
                    <resetValue>0xffffffff</resetValue>
                    <resetMask>0xffffffff</resetMask>
                    <fields>
                        <field>
                            <name>MSTPB3</name>
                            <description>CEC Module Stop</description>
                            <lsb>3</lsb>
                            <msb>3</msb>
                            <access>read-write</access>
                            <enumeratedValues>
                                </enumeratedValues>
                        </field>
                        <field>
                            <name>MSTPB6</name>
                            <description>Quad Serial Peripheral Interface Module Stop</description>
                            <lsb>6</lsb>
                            <msb>6</msb>
                            <access>read-write</access>
                            <enumeratedValues>
                                </enumeratedValues>
                        </field>
                        <field>
                            <name>MSTPB7</name>
                            <description>I2C Bus Interface 2 Module Stop</description>
                            <lsb>7</lsb>
                            <msb>7</msb>
                            <access>read-write</access>
                            <enumeratedValues>
                                </enumeratedValues>
                        </field>
                        <field>
                            <name>MSTPB8</name>
                            <description>I2C Bus Interface 1 Module Stop</description>
                            <lsb>8</lsb>
                            <msb>8</msb>
                            <access>read-write</access>
                            <enumeratedValues>
                                </enumeratedValues>
                        </field>
                        <field>
                            <name>MSTPB9</name>
                            <description>I2C Bus Interface 0 Module Stop</description>
                            <lsb>9</lsb>
                            <msb>9</msb>
                            <access>read-write</access>
                            <enumeratedValues>
                                </enumeratedValues>
                        </field>
                        <field>
                            <name>MSTPB11</name>
                            <description>Universal Serial Bus 2.0 FS Interface 0 Module Stop</description>
                            <lsb>11</lsb>
                            <msb>11</msb>
                            <access>read-write</access>
                            <enumeratedValues>
                                </enumeratedValues>
                        </field>
                        <field>
                            <name>MSTPB12</name>
                            <description>Universal Serial Bus 2.0 HS Interface Module Stop</description>
                            <lsb>12</lsb>
                            <msb>12</msb>
                            <access>read-write</access>
                            <enumeratedValues>
                                </enumeratedValues>
                        </field>
                        <field>
                            <name>MSTPB15</name>
                            <description>ETHERC0 and EDMAC0 Module Stop</description>
                            <lsb>15</lsb>
                            <msb>15</msb>
                            <access>read-write</access>
                            <enumeratedValues>
                                </enumeratedValues>
                        </field>
                        <field>
                            <name>MSTPB16</name>
                            <description>OSPI Module Stop</description>
                            <lsb>16</lsb>
                            <msb>16</msb>
                            <access>read-write</access>
                            <enumeratedValues>
                                </enumeratedValues>
                        </field>
                        <field>
                            <name>MSTPB18</name>
                            <description>Serial Peripheral Interface 1 Module Stop</description>
                            <lsb>18</lsb>
                            <msb>18</msb>
                            <access>read-write</access>
                            <enumeratedValues>
                                </enumeratedValues>
                        </field>
                        <field>
                            <name>MSTPB19</name>
                            <description>Serial Peripheral Interface 0 Module Stop</description>
                            <lsb>19</lsb>
                            <msb>19</msb>
                            <access>read-write</access>
                            <enumeratedValues>
                                </enumeratedValues>
                        </field>
                        <field>
                            <name>MSTPB22</name>
                            <description>Serial Communication Interface 9 Module Stop</description>
                            <lsb>22</lsb>
                            <msb>22</msb>
                            <access>read-write</access>
                            <enumeratedValues>
                                </enumeratedValues>
                        </field>
                        <field>
                            <name>MSTPB23</name>
                            <description>Serial Communication Interface 8 Module Stop</description>
                            <lsb>23</lsb>
                            <msb>23</msb>
                            <access>read-write</access>
                            <enumeratedValues>
                                </enumeratedValues>
                        </field>
                        <field>
                            <name>MSTPB24</name>
                            <description>Serial Communication Interface 7 Module Stop</description>
                            <lsb>24</lsb>
                            <msb>24</msb>
                            <access>read-write</access>
                            <enumeratedValues>
                                </enumeratedValues>
                        </field>
                        <field>
                            <name>MSTPB25</name>
                            <description>Serial Communication Interface 6 Module Stop</description>
                            <lsb>25</lsb>
                            <msb>25</msb>
                            <access>read-write</access>
                            <enumeratedValues>
                                </enumeratedValues>
                        </field>
                        <field>
                            <name>MSTPB26</name>
                            <description>Serial Communication Interface 5 Module Stop</description>
                            <lsb>26</lsb>
                            <msb>26</msb>
                            <access>read-write</access>
                            <enumeratedValues>
                                </enumeratedValues>
                        </field>
                        <field>
                            <name>MSTPB27</name>
                            <description>Serial Communication Interface 4 Module Stop</description>
                            <lsb>27</lsb>
                            <msb>27</msb>
                            <access>read-write</access>
                            <enumeratedValues>
                                </enumeratedValues>
                        </field>
                        <field>
                            <name>MSTPB28</name>
                            <description>Serial Communication Interface 3 Module Stop</description>
                            <lsb>28</lsb>
                            <msb>28</msb>
                            <access>read-write</access>
                            <enumeratedValues>
                                </enumeratedValues>
                        </field>
                        <field>
                            <name>MSTPB29</name>
                            <description>Serial Communication Interface 2 Module Stop</description>
                            <lsb>29</lsb>
                            <msb>29</msb>
                            <access>read-write</access>
                            <enumeratedValues>
                                </enumeratedValues>
                        </field>
                        <field>
                            <name>MSTPB30</name>
                            <description>Serial Communication Interface 1 Module Stop</description>
                            <lsb>30</lsb>
                            <msb>30</msb>
                            <access>read-write</access>
                            <enumeratedValues>
                                </enumeratedValues>
                        </field>
                        <field>
                            <name>MSTPB31</name>
                            <description>Serial Communication Interface 0 Module Stop</description>
                            <lsb>31</lsb>
                            <msb>31</msb>
                            <access>read-write</access>
                            <enumeratedValues>
                                </enumeratedValues>
                        </field>
                    </fields>
                </register>
                <register>
                    <name>MSTPCRC</name>
                    <description>Module Stop Control Register C</description>
                    <addressOffset>0x008</addressOffset>
                    <size>32</size>
                    <access>read-write</access>
                    <resetValue>0xffffffff</resetValue>
                    <resetMask>0xffffffff</resetMask>
                    <fields>
                        <field>
                            <name>MSTPC0</name>
                            <description>Clock Frequency Accuracy Measurement Circuit Module Stop</description>
                            <lsb>0</lsb>
                            <msb>0</msb>
                            <access>read-write</access>
                            <enumeratedValues>
                                </enumeratedValues>
                        </field>
                        <field>
                            <name>MSTPC1</name>
                            <description>Cyclic Redundancy Check Calculator Module Stop</description>
                            <lsb>1</lsb>
                            <msb>1</msb>
                            <access>read-write</access>
                            <enumeratedValues>
                                </enumeratedValues>
                        </field>
                        <field>
                            <name>MSTPC3</name>
                            <description>Capacitive Touch Sensing Unit Module Stop</description>
                            <lsb>3</lsb>
                            <msb>3</msb>
                            <access>read-write</access>
                            <enumeratedValues>
                                </enumeratedValues>
                        </field>
                        <field>
                            <name>MSTPC8</name>
                            <description>Serial Sound Interface Enhanced Module Stop</description>
                            <lsb>8</lsb>
                            <msb>8</msb>
                            <access>read-write</access>
                            <enumeratedValues>
                                </enumeratedValues>
                        </field>
                        <field>
                            <name>MSTPC12</name>
                            <description>Secure Digital HOST IF / Multi Media Card 0 Module Stop</description>
                            <lsb>12</lsb>
                            <msb>12</msb>
                            <access>read-write</access>
                            <enumeratedValues>
                                </enumeratedValues>
                        </field>
                        <field>
                            <name>MSTPC13</name>
                            <description>Data Operation Circuit Module Stop</description>
                            <lsb>13</lsb>
                            <msb>13</msb>
                            <access>read-write</access>
                            <enumeratedValues>
                                </enumeratedValues>
                        </field>
                        <field>
                            <name>MSTPC14</name>
                            <description>Event Link Controller Module Stop</description>
                            <lsb>14</lsb>
                            <msb>14</msb>
                            <access>read-write</access>
                            <enumeratedValues>
                                </enumeratedValues>
                        </field>
                        <field>
                            <name>MSTPC27</name>
                            <description>CANFD Module Stop</description>
                            <lsb>27</lsb>
                            <msb>27</msb>
                            <access>read-write</access>
                            <enumeratedValues>
                                </enumeratedValues>
                        </field>
                        <field>
                            <name>MSTPC31</name>
                            <description>SCE9 Module Stop</description>
                            <lsb>31</lsb>
                            <msb>31</msb>
                            <access>read-write</access>
                            <enumeratedValues>
                                </enumeratedValues>
                        </field>
                    </fields>
                </register>
                <register>
                    <name>MSTPCRD</name>
                    <description>Module Stop Control Register D</description>
                    <addressOffset>0x00C</addressOffset>
                    <size>32</size>
                    <access>read-write</access>
                    <resetValue>0xffffffff</resetValue>
                    <resetMask>0xffffffff</resetMask>
                    <fields>
                        <field>
                            <name>MSTPD0</name>
                            <description>Low Power Asynchronous General Purpose Timer 3 Module Stop</description>
                            <lsb>0</lsb>
                            <msb>0</msb>
                            <access>read-write</access>
                            <enumeratedValues>
                                </enumeratedValues>
                        </field>
                        <field>
                            <name>MSTPD1</name>
                            <description>Low Power Asynchronous General Purpose Timer 2 Module Stop</description>
                            <lsb>1</lsb>
                            <msb>1</msb>
                            <access>read-write</access>
                            <enumeratedValues>
                                </enumeratedValues>
                        </field>
                        <field>
                            <name>MSTPD2</name>
                            <description>Low Power Asynchronous General Purpose Timer 1 Module Stop</description>
                            <lsb>2</lsb>
                            <msb>2</msb>
                            <access>read-write</access>
                            <enumeratedValues>
                                </enumeratedValues>
                        </field>
                        <field>
                            <name>MSTPD3</name>
                            <description>Low Power Asynchronous General Purpose Timer 0 Module Stop</description>
                            <lsb>3</lsb>
                            <msb>3</msb>
                            <access>read-write</access>
                            <enumeratedValues>
                                </enumeratedValues>
                        </field>
                        <field>
                            <name>MSTPD11</name>
                            <description>Port Output Enable for GPT Group D Module Stop</description>
                            <lsb>11</lsb>
                            <msb>11</msb>
                            <access>read-write</access>
                            <enumeratedValues>
                                </enumeratedValues>
                        </field>
                        <field>
                            <name>MSTPD12</name>
                            <description>Port Output Enable for GPT Group C Module Stop</description>
                            <lsb>12</lsb>
                            <msb>12</msb>
                            <access>read-write</access>
                            <enumeratedValues>
                                </enumeratedValues>
                        </field>
                        <field>
                            <name>MSTPD13</name>
                            <description>Port Output Enable for GPT Group B Module Stop</description>
                            <lsb>13</lsb>
                            <msb>13</msb>
                            <access>read-write</access>
                            <enumeratedValues>
                                </enumeratedValues>
                        </field>
                        <field>
                            <name>MSTPD14</name>
                            <description>Port Output Enable for GPT Group A Module Stop</description>
                            <lsb>14</lsb>
                            <msb>14</msb>
                            <access>read-write</access>
                            <enumeratedValues>
                                </enumeratedValues>
                        </field>
                        <field>
                            <name>MSTPD15</name>
                            <description>12-bit A/D Converter 1 Module Stop</description>
                            <lsb>15</lsb>
                            <msb>15</msb>
                            <access>read-write</access>
                            <enumeratedValues>
                                </enumeratedValues>
                        </field>
                        <field>
                            <name>MSTPD16</name>
                            <description>12-bit A/D Converter 0 Module Stop</description>
                            <lsb>16</lsb>
                            <msb>16</msb>
                            <access>read-write</access>
                            <enumeratedValues>
                                </enumeratedValues>
                        </field>
                        <field>
                            <name>MSTPD20</name>
                            <description>12-bit D/A Converter Module Stop</description>
                            <lsb>20</lsb>
                            <msb>20</msb>
                            <access>read-write</access>
                            <enumeratedValues>
                                </enumeratedValues>
                        </field>
                        <field>
                            <name>MSTPD22</name>
                            <description>Temperature Sensor Module Stop</description>
                            <lsb>22</lsb>
                            <msb>22</msb>
                            <access>read-write</access>
                            <enumeratedValues>
                                </enumeratedValues>
                        </field>
                    </fields>
                </register>
                <register>
                    <name>MSTPCRE</name>
                    <description>Module Stop Control Register E</description>
                    <addressOffset>0x010</addressOffset>
                    <size>32</size>
                    <access>read-write</access>
                    <resetValue>0xffffffff</resetValue>
                    <resetMask>0xffffffff</resetMask>
                    <fields>
                        <field>
                            <name>MSTPE14</name>
                            <description>Low Power Asynchronous General Purpose Timer 5 Module Stop</description>
                            <lsb>14</lsb>
                            <msb>14</msb>
                            <access>read-write</access>
                            <enumeratedValues>
                                </enumeratedValues>
                        </field>
                        <field>
                            <name>MSTPE15</name>
                            <description>Low Power Asynchronous General Purpose Timer 4 Module Stop</description>
                            <lsb>15</lsb>
                            <msb>15</msb>
                            <access>read-write</access>
                            <enumeratedValues>
                                </enumeratedValues>
                        </field>
                        <field>
                            <name>MSTPE22</name>
                            <description>GPT9 Module Stop</description>
                            <lsb>22</lsb>
                            <msb>22</msb>
                            <access>read-write</access>
                            <enumeratedValues>
                                </enumeratedValues>
                        </field>
                        <field>
                            <name>MSTPE23</name>
                            <description>GPT8 Module Stop</description>
                            <lsb>23</lsb>
                            <msb>23</msb>
                            <access>read-write</access>
                            <enumeratedValues>
                                </enumeratedValues>
                        </field>
                        <field>
                            <name>MSTPE24</name>
                            <description>GPT7 Module Stop</description>
                            <lsb>24</lsb>
                            <msb>24</msb>
                            <access>read-write</access>
                            <enumeratedValues>
                                </enumeratedValues>
                        </field>
                        <field>
                            <name>MSTPE25</name>
                            <description>GPT6 Module Stop</description>
                            <lsb>25</lsb>
                            <msb>25</msb>
                            <access>read-write</access>
                            <enumeratedValues>
                                </enumeratedValues>
                        </field>
                        <field>
                            <name>MSTPE26</name>
                            <description>GPT5 Module Stop</description>
                            <lsb>26</lsb>
                            <msb>26</msb>
                            <access>read-write</access>
                            <enumeratedValues>
                                </enumeratedValues>
                        </field>
                        <field>
                            <name>MSTPE27</name>
                            <description>GPT4 Module Stop</description>
                            <lsb>27</lsb>
                            <msb>27</msb>
                            <access>read-write</access>
                            <enumeratedValues>
                                </enumeratedValues>
                        </field>
                        <field>
                            <name>MSTPE28</name>
                            <description>GPT3 Module Stop</description>
                            <lsb>28</lsb>
                            <msb>28</msb>
                            <access>read-write</access>
                            <enumeratedValues>
                                </enumeratedValues>
                        </field>
                        <field>
                            <name>MSTPE29</name>
                            <description>GPT2 Module Stop</description>
                            <lsb>29</lsb>
                            <msb>29</msb>
                            <access>read-write</access>
                            <enumeratedValues>
                                </enumeratedValues>
                        </field>
                        <field>
                            <name>MSTPE30</name>
                            <description>GPT1 Module Stop</description>
                            <lsb>30</lsb>
                            <msb>30</msb>
                            <access>read-write</access>
                            <enumeratedValues>
                                </enumeratedValues>
                        </field>
                        <field>
                            <name>MSTPE31</name>
                            <description>GPT0 Module Stop</description>
                            <lsb>31</lsb>
                            <msb>31</msb>
                            <access>read-write</access>
                            <enumeratedValues>
                                </enumeratedValues>
                        </field>
                    </fields>
                </register>
            </registers>
        </peripheral>
        <peripheral>
            <name>POEG</name>
            <description>Port Output Enable Module for GPT</description>
            <baseAddress>0x4008A000</baseAddress>
            <addressBlock>
                <offset>0x00</offset>
                <size>4</size>
                <usage>registers</usage>
            </addressBlock>
            <addressBlock>
                <offset>0x100</offset>
                <size>4</size>
                <usage>registers</usage>
            </addressBlock>
            <addressBlock>
                <offset>0x200</offset>
                <size>4</size>
                <usage>registers</usage>
            </addressBlock>
            <addressBlock>
                <offset>0x300</offset>
                <size>4</size>
                <usage>registers</usage>
            </addressBlock>
            <registers>
                <register>
                    <name>POEGGA</name>
                    <description>POEG Group A Setting Register</description>
                    <addressOffset>0x000</addressOffset>
                    <size>32</size>
                    <access>read-write</access>
                    <resetValue>0x00000000</resetValue>
                    <resetMask>0xffffffff</resetMask>
                    <fields>
                        <field>
                            <name>PIDF</name>
                            <description>Port Input Detection Flag</description>
                            <lsb>0</lsb>
                            <msb>0</msb>
                            <access>read-write</access>
                            <enumeratedValues>
                                </enumeratedValues>
                        </field>
                        <field>
                            <name>IOCF</name>
                            <description>Detection Flag for GPT Output,Disable Request</description>
                            <lsb>1</lsb>
                            <msb>1</msb>
                            <access>read-write</access>
                            <enumeratedValues>
                                </enumeratedValues>
                        </field>
                        <field>
                            <name>OSTPF</name>
                            <description>Oscillation Stop Detection Flag</description>
                            <lsb>2</lsb>
                            <msb>2</msb>
                            <access>read-write</access>
                            <enumeratedValues>
                                </enumeratedValues>
                        </field>
                        <field>
                            <name>SSF</name>
                            <description>Software Stop Flag</description>
                            <lsb>3</lsb>
                            <msb>3</msb>
                            <access>read-write</access>
                            <enumeratedValues>
                                </enumeratedValues>
                        </field>
                        <field>
                            <name>PIDE</name>
                            <description>Port Input Detection Enable</description>
                            <lsb>4</lsb>
                            <msb>4</msb>
                            <access>read-write</access>
                            <enumeratedValues>
                                </enumeratedValues>
                        </field>
                        <field>
                            <name>IOCE</name>
                            <description>Enable for GPT Output,Disable Request</description>
                            <lsb>5</lsb>
                            <msb>5</msb>
                            <access>read-write</access>
                            <enumeratedValues>
                                </enumeratedValues>
                        </field>
                        <field>
                            <name>OSTPE</name>
                            <description>Oscillation Stop Detection Enable</description>
                            <lsb>6</lsb>
                            <msb>6</msb>
                            <access>read-write</access>
                            <enumeratedValues>
                                </enumeratedValues>
                        </field>
                        <field>
                            <name>ST</name>
                            <description>GTETRGn Input Status Flag</description>
                            <lsb>16</lsb>
                            <msb>16</msb>
                            <access>read-only</access>
                            <enumeratedValues>
                                </enumeratedValues>
                        </field>
                        <field>
                            <name>INV</name>
                            <description>GTETRGn Input Reverse</description>
                            <lsb>28</lsb>
                            <msb>28</msb>
                            <access>read-write</access>
                            <enumeratedValues>
                                </enumeratedValues>
                        </field>
                        <field>
                            <name>NFEN</name>
                            <description>Noise Filter Enable</description>
                            <lsb>29</lsb>
                            <msb>29</msb>
                            <access>read-write</access>
                            <enumeratedValues>
                                </enumeratedValues>
                        </field>
                        <field>
                            <name>NFCS</name>
                            <description>Noise Filter Clock Select</description>
                            <lsb>30</lsb>
                            <msb>31</msb>
                            <access>read-write</access>
                            <enumeratedValues>
                                </enumeratedValues>
                        </field>
                    </fields>
                </register>
                <register>
                    <name>POEGGB</name>
                    <description>POEG Group B Setting Register</description>
                    <addressOffset>0x100</addressOffset>
                    <size>32</size>
                    <access>read-write</access>
                    <resetValue>0x00000000</resetValue>
                    <resetMask>0xffffffff</resetMask>
                    <fields>
                        <field>
                            <name>PIDF</name>
                            <description>Port Input Detection Flag</description>
                            <lsb>0</lsb>
                            <msb>0</msb>
                            <access>read-write</access>
                            <enumeratedValues>
                                </enumeratedValues>
                        </field>
                        <field>
                            <name>IOCF</name>
                            <description>Detection Flag for GPT Output,Disable Request</description>
                            <lsb>1</lsb>
                            <msb>1</msb>
                            <access>read-write</access>
                            <enumeratedValues>
                                </enumeratedValues>
                        </field>
                        <field>
                            <name>OSTPF</name>
                            <description>Oscillation Stop Detection Flag</description>
                            <lsb>2</lsb>
                            <msb>2</msb>
                            <access>read-write</access>
                            <enumeratedValues>
                                </enumeratedValues>
                        </field>
                        <field>
                            <name>SSF</name>
                            <description>Software Stop Flag</description>
                            <lsb>3</lsb>
                            <msb>3</msb>
                            <access>read-write</access>
                            <enumeratedValues>
                                </enumeratedValues>
                        </field>
                        <field>
                            <name>PIDE</name>
                            <description>Port Input Detection Enable</description>
                            <lsb>4</lsb>
                            <msb>4</msb>
                            <access>read-write</access>
                            <enumeratedValues>
                                </enumeratedValues>
                        </field>
                        <field>
                            <name>IOCE</name>
                            <description>Enable for GPT Output,Disable Request</description>
                            <lsb>5</lsb>
                            <msb>5</msb>
                            <access>read-write</access>
                            <enumeratedValues>
                                </enumeratedValues>
                        </field>
                        <field>
                            <name>OSTPE</name>
                            <description>Oscillation Stop Detection Enable</description>
                            <lsb>6</lsb>
                            <msb>6</msb>
                            <access>read-write</access>
                            <enumeratedValues>
                                </enumeratedValues>
                        </field>
                        <field>
                            <name>ST</name>
                            <description>GTETRGn Input Status Flag</description>
                            <lsb>16</lsb>
                            <msb>16</msb>
                            <access>read-only</access>
                            <enumeratedValues>
                                </enumeratedValues>
                        </field>
                        <field>
                            <name>INV</name>
                            <description>GTETRGn Input Reverse</description>
                            <lsb>28</lsb>
                            <msb>28</msb>
                            <access>read-write</access>
                            <enumeratedValues>
                                </enumeratedValues>
                        </field>
                        <field>
                            <name>NFEN</name>
                            <description>Noise Filter Enable</description>
                            <lsb>29</lsb>
                            <msb>29</msb>
                            <access>read-write</access>
                            <enumeratedValues>
                                </enumeratedValues>
                        </field>
                        <field>
                            <name>NFCS</name>
                            <description>Noise Filter Clock Select</description>
                            <lsb>30</lsb>
                            <msb>31</msb>
                            <access>read-write</access>
                            <enumeratedValues>
                                </enumeratedValues>
                        </field>
                    </fields>
                </register>
                <register>
                    <name>POEGGC</name>
                    <description>POEG Group C Setting Register</description>
                    <addressOffset>0x200</addressOffset>
                    <size>32</size>
                    <access>read-write</access>
                    <resetValue>0x00000000</resetValue>
                    <resetMask>0xffffffff</resetMask>
                    <fields>
                        <field>
                            <name>PIDF</name>
                            <description>Port Input Detection Flag</description>
                            <lsb>0</lsb>
                            <msb>0</msb>
                            <access>read-write</access>
                            <enumeratedValues>
                                </enumeratedValues>
                        </field>
                        <field>
                            <name>IOCF</name>
                            <description>Detection Flag for GPT Output,Disable Request</description>
                            <lsb>1</lsb>
                            <msb>1</msb>
                            <access>read-write</access>
                            <enumeratedValues>
                                </enumeratedValues>
                        </field>
                        <field>
                            <name>OSTPF</name>
                            <description>Oscillation Stop Detection Flag</description>
                            <lsb>2</lsb>
                            <msb>2</msb>
                            <access>read-write</access>
                            <enumeratedValues>
                                </enumeratedValues>
                        </field>
                        <field>
                            <name>SSF</name>
                            <description>Software Stop Flag</description>
                            <lsb>3</lsb>
                            <msb>3</msb>
                            <access>read-write</access>
                            <enumeratedValues>
                                </enumeratedValues>
                        </field>
                        <field>
                            <name>PIDE</name>
                            <description>Port Input Detection Enable</description>
                            <lsb>4</lsb>
                            <msb>4</msb>
                            <access>read-write</access>
                            <enumeratedValues>
                                </enumeratedValues>
                        </field>
                        <field>
                            <name>IOCE</name>
                            <description>Enable for GPT Output,Disable Request</description>
                            <lsb>5</lsb>
                            <msb>5</msb>
                            <access>read-write</access>
                            <enumeratedValues>
                                </enumeratedValues>
                        </field>
                        <field>
                            <name>OSTPE</name>
                            <description>Oscillation Stop Detection Enable</description>
                            <lsb>6</lsb>
                            <msb>6</msb>
                            <access>read-write</access>
                            <enumeratedValues>
                                </enumeratedValues>
                        </field>
                        <field>
                            <name>ST</name>
                            <description>GTETRGn Input Status Flag</description>
                            <lsb>16</lsb>
                            <msb>16</msb>
                            <access>read-only</access>
                            <enumeratedValues>
                                </enumeratedValues>
                        </field>
                        <field>
                            <name>INV</name>
                            <description>GTETRGn Input Reverse</description>
                            <lsb>28</lsb>
                            <msb>28</msb>
                            <access>read-write</access>
                            <enumeratedValues>
                                </enumeratedValues>
                        </field>
                        <field>
                            <name>NFEN</name>
                            <description>Noise Filter Enable</description>
                            <lsb>29</lsb>
                            <msb>29</msb>
                            <access>read-write</access>
                            <enumeratedValues>
                                </enumeratedValues>
                        </field>
                        <field>
                            <name>NFCS</name>
                            <description>Noise Filter Clock Select</description>
                            <lsb>30</lsb>
                            <msb>31</msb>
                            <access>read-write</access>
                            <enumeratedValues>
                                </enumeratedValues>
                        </field>
                    </fields>
                </register>
                <register>
                    <name>POEGGD</name>
                    <description>POEG Group D Setting Register</description>
                    <addressOffset>0x300</addressOffset>
                    <size>32</size>
                    <access>read-write</access>
                    <resetValue>0x00000000</resetValue>
                    <resetMask>0xffffffff</resetMask>
                    <fields>
                        <field>
                            <name>PIDF</name>
                            <description>Port Input Detection Flag</description>
                            <lsb>0</lsb>
                            <msb>0</msb>
                            <access>read-write</access>
                            <enumeratedValues>
                                </enumeratedValues>
                        </field>
                        <field>
                            <name>IOCF</name>
                            <description>Detection Flag for GPT Output,Disable Request</description>
                            <lsb>1</lsb>
                            <msb>1</msb>
                            <access>read-write</access>
                            <enumeratedValues>
                                </enumeratedValues>
                        </field>
                        <field>
                            <name>OSTPF</name>
                            <description>Oscillation Stop Detection Flag</description>
                            <lsb>2</lsb>
                            <msb>2</msb>
                            <access>read-write</access>
                            <enumeratedValues>
                                </enumeratedValues>
                        </field>
                        <field>
                            <name>SSF</name>
                            <description>Software Stop Flag</description>
                            <lsb>3</lsb>
                            <msb>3</msb>
                            <access>read-write</access>
                            <enumeratedValues>
                                </enumeratedValues>
                        </field>
                        <field>
                            <name>PIDE</name>
                            <description>Port Input Detection Enable</description>
                            <lsb>4</lsb>
                            <msb>4</msb>
                            <access>read-write</access>
                            <enumeratedValues>
                                </enumeratedValues>
                        </field>
                        <field>
                            <name>IOCE</name>
                            <description>Enable for GPT Output,Disable Request</description>
                            <lsb>5</lsb>
                            <msb>5</msb>
                            <access>read-write</access>
                            <enumeratedValues>
                                </enumeratedValues>
                        </field>
                        <field>
                            <name>OSTPE</name>
                            <description>Oscillation Stop Detection Enable</description>
                            <lsb>6</lsb>
                            <msb>6</msb>
                            <access>read-write</access>
                            <enumeratedValues>
                                </enumeratedValues>
                        </field>
                        <field>
                            <name>ST</name>
                            <description>GTETRGn Input Status Flag</description>
                            <lsb>16</lsb>
                            <msb>16</msb>
                            <access>read-only</access>
                            <enumeratedValues>
                                </enumeratedValues>
                        </field>
                        <field>
                            <name>INV</name>
                            <description>GTETRGn Input Reverse</description>
                            <lsb>28</lsb>
                            <msb>28</msb>
                            <access>read-write</access>
                            <enumeratedValues>
                                </enumeratedValues>
                        </field>
                        <field>
                            <name>NFEN</name>
                            <description>Noise Filter Enable</description>
                            <lsb>29</lsb>
                            <msb>29</msb>
                            <access>read-write</access>
                            <enumeratedValues>
                                </enumeratedValues>
                        </field>
                        <field>
                            <name>NFCS</name>
                            <description>Noise Filter Clock Select</description>
                            <lsb>30</lsb>
                            <msb>31</msb>
                            <access>read-write</access>
                            <enumeratedValues>
                                </enumeratedValues>
                        </field>
                    </fields>
                </register>
            </registers>
        </peripheral>
        <peripheral>
            <name>USBFS</name>
            <description>USB 2.0 Full,Speed Module</description>
            <baseAddress>0x40090000</baseAddress>
            <addressBlock>
                <offset>0x00</offset>
                <size>2</size>
                <usage>registers</usage>
            </addressBlock>
            <addressBlock>
                <offset>0x04</offset>
                <size>2</size>
                <usage>registers</usage>
            </addressBlock>
            <addressBlock>
                <offset>0x08</offset>
                <size>2</size>
                <usage>registers</usage>
            </addressBlock>
            <addressBlock>
                <offset>0x14</offset>
                <size>2</size>
                <usage>registers</usage>
            </addressBlock>
            <addressBlock>
                <offset>0x18</offset>
                <size>12</size>
                <usage>registers</usage>
            </addressBlock>
            <addressBlock>
                <offset>0x28</offset>
                <size>12</size>
                <usage>registers</usage>
            </addressBlock>
            <addressBlock>
                <offset>0x36</offset>
                <size>8</size>
                <usage>registers</usage>
            </addressBlock>
            <addressBlock>
                <offset>0x40</offset>
                <size>4</size>
                <usage>registers</usage>
            </addressBlock>
            <addressBlock>
                <offset>0x46</offset>
                <size>12</size>
                <usage>registers</usage>
            </addressBlock>
            <addressBlock>
                <offset>0x54</offset>
                <size>14</size>
                <usage>registers</usage>
            </addressBlock>
            <addressBlock>
                <offset>0x64</offset>
                <size>2</size>
                <usage>registers</usage>
            </addressBlock>
            <addressBlock>
                <offset>0x68</offset>
                <size>2</size>
                <usage>registers</usage>
            </addressBlock>
            <addressBlock>
                <offset>0x6C</offset>
                <size>22</size>
                <usage>registers</usage>
            </addressBlock>
            <addressBlock>
                <offset>0x90</offset>
                <size>22</size>
                <usage>registers</usage>
            </addressBlock>
            <addressBlock>
                <offset>0xB0</offset>
                <size>8</size>
                <usage>registers</usage>
            </addressBlock>
            <addressBlock>
                <offset>0xD0</offset>
                <size>12</size>
                <usage>registers</usage>
            </addressBlock>
            <addressBlock>
                <offset>0xF4</offset>
                <size>4</size>
                <usage>registers</usage>
            </addressBlock>
            <addressBlock>
                <offset>0x400</offset>
                <size>8</size>
                <usage>registers</usage>
            </addressBlock>
            <registers>
                <register>
                    <name>SYSCFG</name>
                    <description>System Configuration Control Register</description>
                    <addressOffset>0x000</addressOffset>
                    <size>16</size>
                    <access>read-write</access>
                    <resetValue>0x0000</resetValue>
                    <resetMask>0xffff</resetMask>
                    <fields>
                        <field>
                            <name>USBE</name>
                            <description>USBFS Operation Enable</description>
                            <lsb>0</lsb>
                            <msb>0</msb>
                            <access>read-write</access>
                            <enumeratedValues>
                                </enumeratedValues>
                        </field>
                        <field>
                            <name>DPRPU</name>
                            <description>D+ Line Resistor Control</description>
                            <lsb>4</lsb>
                            <msb>4</msb>
                            <access>read-write</access>
                            <enumeratedValues>
                                </enumeratedValues>
                        </field>
                        <field>
                            <name>DRPD</name>
                            <description>D+/D– Line Resistor Control</description>
                            <lsb>5</lsb>
                            <msb>5</msb>
                            <access>read-write</access>
                            <enumeratedValues>
                                </enumeratedValues>
                        </field>
                        <field>
                            <name>DCFM</name>
                            <description>Controller Function Select</description>
                            <lsb>6</lsb>
                            <msb>6</msb>
                            <access>read-write</access>
                            <enumeratedValues>
                                </enumeratedValues>
                        </field>
                        <field>
                            <name>SCKE</name>
                            <description>USB Clock Enable</description>
                            <lsb>10</lsb>
                            <msb>10</msb>
                            <access>read-write</access>
                            <enumeratedValues>
                                </enumeratedValues>
                        </field>
                    </fields>
                </register>
                <register>
                    <name>SYSSTS0</name>
                    <description>System Configuration Status Register 0</description>
                    <addressOffset>0x004</addressOffset>
                    <size>16</size>
                    <access>read-only</access>
                    <resetValue>0x0000</resetValue>
                    <resetMask>0x3ffb</resetMask>
                    <fields>
                        <field>
                            <name>LNST</name>
                            <description>USB Data Line Status Monitor</description>
                            <lsb>0</lsb>
                            <msb>1</msb>
                            <access>read-only</access>
                        </field>
                        <field>
                            <name>IDMON</name>
                            <description>External ID0 Input Pin Monitor</description>
                            <lsb>2</lsb>
                            <msb>2</msb>
                            <access>read-only</access>
                            <enumeratedValues>
                                </enumeratedValues>
                        </field>
                        <field>
                            <name>SOFEA</name>
                            <description>Active Monitor When the Host Controller Is Selected</description>
                            <lsb>5</lsb>
                            <msb>5</msb>
                            <access>read-only</access>
                            <enumeratedValues>
                                </enumeratedValues>
                        </field>
                        <field>
                            <name>HTACT</name>
                            <description>USB Host Sequencer Status Monitor</description>
                            <lsb>6</lsb>
                            <msb>6</msb>
                            <access>read-only</access>
                            <enumeratedValues>
                                </enumeratedValues>
                        </field>
                        <field>
                            <name>OVCMON</name>
                            <description>External USB_OVRCURA/ USB_OVRCURB Input Pin Monitor</description>
                            <lsb>14</lsb>
                            <msb>15</msb>
                            <access>read-only</access>
                        </field>
                    </fields>
                </register>
                <register>
                    <name>DVSTCTR0</name>
                    <description>Device State Control Register 0</description>
                    <addressOffset>0x008</addressOffset>
                    <size>16</size>
                    <access>read-write</access>
                    <resetValue>0x0000</resetValue>
                    <resetMask>0xffff</resetMask>
                    <fields>
                        <field>
                            <name>RHST</name>
                            <description>USB Bus Reset Status</description>
                            <lsb>0</lsb>
                            <msb>2</msb>
                            <access>read-only</access>
                            <enumeratedValues>
                                </enumeratedValues>
                        </field>
                        <field>
                            <name>UACT</name>
                            <description>USB Bus Enable</description>
                            <lsb>4</lsb>
                            <msb>4</msb>
                            <access>read-write</access>
                            <enumeratedValues>
                                </enumeratedValues>
                        </field>
                        <field>
                            <name>RESUME</name>
                            <description>Resume Output</description>
                            <lsb>5</lsb>
                            <msb>5</msb>
                            <access>read-write</access>
                            <enumeratedValues>
                                </enumeratedValues>
                        </field>
                        <field>
                            <name>USBRST</name>
                            <description>USB Bus Reset Output</description>
                            <lsb>6</lsb>
                            <msb>6</msb>
                            <access>read-write</access>
                            <enumeratedValues>
                                </enumeratedValues>
                        </field>
                        <field>
                            <name>RWUPE</name>
                            <description>Wakeup Detection Enable</description>
                            <lsb>7</lsb>
                            <msb>7</msb>
                            <access>read-write</access>
                            <enumeratedValues>
                                </enumeratedValues>
                        </field>
                        <field>
                            <name>WKUP</name>
                            <description>Wakeup Output</description>
                            <lsb>8</lsb>
                            <msb>8</msb>
                            <access>read-write</access>
                            <enumeratedValues>
                                </enumeratedValues>
                        </field>
                        <field>
                            <name>VBUSEN</name>
                            <description>USB_VBUSEN Output Pin Control</description>
                            <lsb>9</lsb>
                            <msb>9</msb>
                            <access>read-write</access>
                            <enumeratedValues>
                                </enumeratedValues>
                        </field>
                        <field>
                            <name>EXICEN</name>
                            <description>USB_EXICEN Output Pin Control</description>
                            <lsb>10</lsb>
                            <msb>10</msb>
                            <access>read-write</access>
                            <enumeratedValues>
                                </enumeratedValues>
                        </field>
                        <field>
                            <name>HNPBTOA</name>
                            <description>Host Negotiation Protocol (HNP) Control</description>
                            <lsb>11</lsb>
                            <msb>11</msb>
                            <access>read-write</access>
                        </field>
                    </fields>
                </register>
                <register>
                    <name>CFIFO</name>
                    <description>CFIFO Port Register</description>
                    <addressOffset>0x014</addressOffset>
                    <size>16</size>
                    <access>read-write</access>
                    <resetValue>0x0000</resetValue>
                    <resetMask>0xffff</resetMask>
                    <fields>
                        <field>
                            <name>FIFOPORT</name>
                            <description>FIFO Port</description>
                            <lsb>0</lsb>
                            <msb>15</msb>
                            <access>read-write</access>
                        </field>
                    </fields>
                </register>
                <register>
                    <name>CFIFOL</name>
                    <description>CFIFO Port Register</description>
                    <alternateRegister>CFIFO</alternateRegister>
                    <addressOffset>0x014</addressOffset>
                    <size>8</size>
                    <access>read-write</access>
                    <resetValue>0x00</resetValue>
                    <resetMask>0xff</resetMask>
                </register>
                <register>
                    <dim>2</dim>
                    <dimIncrement>0x4</dimIncrement>
                    <dimIndex>0-1</dimIndex>
                    <name>D%sFIFO</name>
                    <description>D%sFIFO Port Register</description>
                    <addressOffset>0x018</addressOffset>
                    <size>16</size>
                    <access>read-write</access>
                    <resetValue>0x0000</resetValue>
                    <resetMask>0xffff</resetMask>
                    <fields>
                        <field>
                            <name>FIFOPORT</name>
                            <description>FIFO Port</description>
                            <lsb>0</lsb>
                            <msb>15</msb>
                            <access>read-write</access>
                        </field>
                    </fields>
                </register>
                <register>
                    <dim>2</dim>
                    <dimIncrement>0x4</dimIncrement>
                    <dimIndex>0-1</dimIndex>
                    <name>D%sFIFOL</name>
                    <description>D%sFIFO Port Register</description>
                    <alternateRegister>D%sFIFO</alternateRegister>
                    <addressOffset>0x018</addressOffset>
                    <size>8</size>
                    <access>read-write</access>
                    <resetValue>0x00</resetValue>
                    <resetMask>0xff</resetMask>
                </register>
                <register>
                    <name>CFIFOSEL</name>
                    <description>CFIFO Port Select Register</description>
                    <addressOffset>0x020</addressOffset>
                    <size>16</size>
                    <access>read-write</access>
                    <resetValue>0x0000</resetValue>
                    <resetMask>0xffff</resetMask>
                    <fields>
                        <field>
                            <name>CURPIPE</name>
                            <description>CFIFO Port Access Pipe Specification</description>
                            <lsb>0</lsb>
                            <msb>3</msb>
                            <access>read-write</access>
                            <enumeratedValues>
                                </enumeratedValues>
                        </field>
                        <field>
                            <name>ISEL</name>
                            <description>CFIFO Port Access Direction When DCP Is Selected</description>
                            <lsb>5</lsb>
                            <msb>5</msb>
                            <access>read-write</access>
                            <enumeratedValues>
                                </enumeratedValues>
                        </field>
                        <field>
                            <name>BIGEND</name>
                            <description>CFIFO Port Endian Control</description>
                            <lsb>8</lsb>
                            <msb>8</msb>
                            <access>read-write</access>
                            <enumeratedValues>
                                </enumeratedValues>
                        </field>
                        <field>
                            <name>MBW</name>
                            <description>CFIFO Port Access Bit Width</description>
                            <lsb>10</lsb>
                            <msb>10</msb>
                            <access>read-write</access>
                            <enumeratedValues>
                                </enumeratedValues>
                        </field>
                        <field>
                            <name>REW</name>
                            <description>Buffer Pointer Rewind</description>
                            <lsb>14</lsb>
                            <msb>14</msb>
                            <access>write-only</access>
                            <enumeratedValues>
                                </enumeratedValues>
                        </field>
                        <field>
                            <name>RCNT</name>
                            <description>Read Count Mode</description>
                            <lsb>15</lsb>
                            <msb>15</msb>
                            <access>read-write</access>
                            <enumeratedValues>
                                </enumeratedValues>
                        </field>
                    </fields>
                </register>
                <register>
                    <name>CFIFOCTR</name>
                    <description>CFIFO Port Control Register</description>
                    <addressOffset>0x022</addressOffset>
                    <size>16</size>
                    <access>read-write</access>
                    <resetValue>0x0000</resetValue>
                    <resetMask>0xffff</resetMask>
                    <fields>
                        <field>
                            <name>DTLN</name>
                            <description>Receive Data Length</description>
                            <lsb>0</lsb>
                            <msb>8</msb>
                            <access>read-only</access>
                        </field>
                        <field>
                            <name>FRDY</name>
                            <description>FIFO Port Ready</description>
                            <lsb>13</lsb>
                            <msb>13</msb>
                            <access>read-only</access>
                            <enumeratedValues>
                                </enumeratedValues>
                        </field>
                        <field>
                            <name>BCLR</name>
                            <description>CPU Buffer Clear</description>
                            <lsb>14</lsb>
                            <msb>14</msb>
                            <access>write-only</access>
                            <enumeratedValues>
                                </enumeratedValues>
                        </field>
                        <field>
                            <name>BVAL</name>
                            <description>Buffer Memory Valid Flag</description>
                            <lsb>15</lsb>
                            <msb>15</msb>
                            <access>read-write</access>
                            <enumeratedValues>
                                </enumeratedValues>
                        </field>
                    </fields>
                </register>
                <register>
                    <dim>2</dim>
                    <dimIncrement>0x4</dimIncrement>
                    <dimIndex>0-1</dimIndex>
                    <name>D%sFIFOSEL</name>
                    <description>D%sFIFO Port Select Register</description>
                    <addressOffset>0x028</addressOffset>
                    <size>16</size>
                    <access>read-write</access>
                    <resetValue>0x0000</resetValue>
                    <resetMask>0xffff</resetMask>
                    <fields>
                        <field>
                            <name>CURPIPE</name>
                            <description>FIFO Port Access Pipe Specification</description>
                            <lsb>0</lsb>
                            <msb>3</msb>
                            <access>read-write</access>
                            <enumeratedValues>
                                </enumeratedValues>
                        </field>
                        <field>
                            <name>BIGEND</name>
                            <description>FIFO Port Endian Control</description>
                            <lsb>8</lsb>
                            <msb>8</msb>
                            <access>read-write</access>
                            <enumeratedValues>
                                </enumeratedValues>
                        </field>
                        <field>
                            <name>MBW</name>
                            <description>FIFO Port Access Bit Width</description>
                            <lsb>10</lsb>
                            <msb>10</msb>
                            <access>read-write</access>
                            <enumeratedValues>
                                </enumeratedValues>
                        </field>
                        <field>
                            <name>DREQE</name>
                            <description>DMA/DTC Transfer Request Enable</description>
                            <lsb>12</lsb>
                            <msb>12</msb>
                            <access>read-write</access>
                            <enumeratedValues>
                                </enumeratedValues>
                        </field>
                        <field>
                            <name>DCLRM</name>
                            <description>Auto Buffer Memory Clear Mode Accessed after Specified Pipe Data is Read</description>
                            <lsb>13</lsb>
                            <msb>13</msb>
                            <access>read-write</access>
                            <enumeratedValues>
                                </enumeratedValues>
                        </field>
                        <field>
                            <name>REW</name>
                            <description>Buffer Pointer Rewind</description>
                            <lsb>14</lsb>
                            <msb>14</msb>
                            <access>write-only</access>
                            <enumeratedValues>
                                </enumeratedValues>
                        </field>
                        <field>
                            <name>RCNT</name>
                            <description>Read Count Mode</description>
                            <lsb>15</lsb>
                            <msb>15</msb>
                            <access>read-write</access>
                            <enumeratedValues>
                                </enumeratedValues>
                        </field>
                    </fields>
                </register>
                <register>
                    <dim>2</dim>
                    <dimIncrement>0x4</dimIncrement>
                    <dimIndex>0-1</dimIndex>
                    <name>D%sFIFOCTR</name>
                    <description>D%sFIFO Port Control Register</description>
                    <addressOffset>0x02A</addressOffset>
                    <size>16</size>
                    <access>read-write</access>
                    <resetValue>0x0000</resetValue>
                    <resetMask>0xffff</resetMask>
                    <fields>
                        <field>
                            <name>DTLN</name>
                            <description>Receive Data Length</description>
                            <lsb>0</lsb>
                            <msb>8</msb>
                            <access>read-only</access>
                        </field>
                        <field>
                            <name>FRDY</name>
                            <description>FIFO Port Ready</description>
                            <lsb>13</lsb>
                            <msb>13</msb>
                            <access>read-only</access>
                            <enumeratedValues>
                                </enumeratedValues>
                        </field>
                        <field>
                            <name>BCLR</name>
                            <description>CPU Buffer Clear</description>
                            <lsb>14</lsb>
                            <msb>14</msb>
                            <access>read-write</access>
                            <enumeratedValues>
                                </enumeratedValues>
                        </field>
                        <field>
                            <name>BVAL</name>
                            <description>Buffer Memory Valid Flag</description>
                            <lsb>15</lsb>
                            <msb>15</msb>
                            <access>read-write</access>
                            <enumeratedValues>
                                </enumeratedValues>
                        </field>
                    </fields>
                </register>
                <register>
                    <name>INTENB0</name>
                    <description>Interrupt Enable Register 0</description>
                    <addressOffset>0x030</addressOffset>
                    <size>16</size>
                    <access>read-write</access>
                    <resetValue>0x0000</resetValue>
                    <resetMask>0xffff</resetMask>
                    <fields>
                        <field>
                            <name>BRDYE</name>
                            <description>Buffer Ready Interrupt Enable</description>
                            <lsb>8</lsb>
                            <msb>8</msb>
                            <access>read-write</access>
                            <enumeratedValues>
                                </enumeratedValues>
                        </field>
                        <field>
                            <name>NRDYE</name>
                            <description>Buffer Not Ready Response Interrupt Enable</description>
                            <lsb>9</lsb>
                            <msb>9</msb>
                            <access>read-write</access>
                            <enumeratedValues>
                                </enumeratedValues>
                        </field>
                        <field>
                            <name>BEMPE</name>
                            <description>Buffer Empty Interrupt Enable</description>
                            <lsb>10</lsb>
                            <msb>10</msb>
                            <access>read-write</access>
                            <enumeratedValues>
                                </enumeratedValues>
                        </field>
                        <field>
                            <name>CTRE</name>
                            <description>Control Transfer Stage Transition Interrupt Enable</description>
                            <lsb>11</lsb>
                            <msb>11</msb>
                            <access>read-write</access>
                            <enumeratedValues>
                                </enumeratedValues>
                        </field>
                        <field>
                            <name>DVSE</name>
                            <description>Device State Transition Interrupt Enable</description>
                            <lsb>12</lsb>
                            <msb>12</msb>
                            <access>read-write</access>
                            <enumeratedValues>
                                </enumeratedValues>
                        </field>
                        <field>
                            <name>SOFE</name>
                            <description>Frame Number Update Interrupt Enable</description>
                            <lsb>13</lsb>
                            <msb>13</msb>
                            <access>read-write</access>
                            <enumeratedValues>
                                </enumeratedValues>
                        </field>
                        <field>
                            <name>RSME</name>
                            <description>Resume Interrupt Enable</description>
                            <lsb>14</lsb>
                            <msb>14</msb>
                            <access>read-write</access>
                            <enumeratedValues>
                                </enumeratedValues>
                        </field>
                        <field>
                            <name>VBSE</name>
                            <description>VBUS Interrupt Enable</description>
                            <lsb>15</lsb>
                            <msb>15</msb>
                            <access>read-write</access>
                            <enumeratedValues>
                                </enumeratedValues>
                        </field>
                    </fields>
                </register>
                <register>
                    <name>INTENB1</name>
                    <description>Interrupt Enable Register 1</description>
                    <addressOffset>0x032</addressOffset>
                    <size>16</size>
                    <access>read-write</access>
                    <resetValue>0x0000</resetValue>
                    <resetMask>0xffff</resetMask>
                    <fields>
                        <field>
                            <name>PDDETINTE</name>
                            <description>PDDETINT Detection Interrupt Request Enable</description>
                            <lsb>0</lsb>
                            <msb>0</msb>
                            <access>read-write</access>
                            <enumeratedValues>
                                </enumeratedValues>
                        </field>
                        <field>
                            <name>SACKE</name>
                            <description>Setup Transaction Normal Response Interrupt Enable</description>
                            <lsb>4</lsb>
                            <msb>4</msb>
                            <access>read-write</access>
                            <enumeratedValues>
                                </enumeratedValues>
                        </field>
                        <field>
                            <name>SIGNE</name>
                            <description>Setup Transaction Error Interrupt Enable</description>
                            <lsb>5</lsb>
                            <msb>5</msb>
                            <access>read-write</access>
                            <enumeratedValues>
                                </enumeratedValues>
                        </field>
                        <field>
                            <name>EOFERRE</name>
                            <description>EOF Error Detection Interrupt Enable</description>
                            <lsb>6</lsb>
                            <msb>6</msb>
                            <access>read-write</access>
                            <enumeratedValues>
                                </enumeratedValues>
                        </field>
                        <field>
                            <name>ATTCHE</name>
                            <description>Connection Detection Interrupt Enable</description>
                            <lsb>11</lsb>
                            <msb>11</msb>
                            <access>read-write</access>
                            <enumeratedValues>
                                </enumeratedValues>
                        </field>
                        <field>
                            <name>DTCHE</name>
                            <description>Disconnection Detection Interrupt Enable</description>
                            <lsb>12</lsb>
                            <msb>12</msb>
                            <access>read-write</access>
                            <enumeratedValues>
                                </enumeratedValues>
                        </field>
                        <field>
                            <name>BCHGE</name>
                            <description>USB Bus Change Interrupt Enable</description>
                            <lsb>14</lsb>
                            <msb>14</msb>
                            <access>read-write</access>
                            <enumeratedValues>
                                </enumeratedValues>
                        </field>
                        <field>
                            <name>OVRCRE</name>
                            <description>Overcurrent Input Change Interrupt Enable</description>
                            <lsb>15</lsb>
                            <msb>15</msb>
                            <access>read-write</access>
                            <enumeratedValues>
                                </enumeratedValues>
                        </field>
                    </fields>
                </register>
                <register>
                    <name>BRDYENB</name>
                    <description>BRDY Interrupt Enable Register</description>
                    <addressOffset>0x036</addressOffset>
                    <size>16</size>
                    <access>read-write</access>
                    <resetValue>0x0000</resetValue>
                    <resetMask>0xffff</resetMask>
                    <fields>
                        <field>
                            <name>PIPE0BRDYE</name>
                            <description>BRDY Interrupt Enable for Pipe 0</description>
                            <lsb>0</lsb>
                            <msb>0</msb>
                            <access>read-write</access>
                            <enumeratedValues>
                                </enumeratedValues>
                        </field>
                        <field>
                            <name>PIPE1BRDYE</name>
                            <description>BRDY Interrupt Enable for Pipe 1</description>
                            <lsb>1</lsb>
                            <msb>1</msb>
                            <access>read-write</access>
                            <enumeratedValues>
                                </enumeratedValues>
                        </field>
                        <field>
                            <name>PIPE2BRDYE</name>
                            <description>BRDY Interrupt Enable for Pipe 2</description>
                            <lsb>2</lsb>
                            <msb>2</msb>
                            <access>read-write</access>
                            <enumeratedValues>
                                </enumeratedValues>
                        </field>
                        <field>
                            <name>PIPE3BRDYE</name>
                            <description>BRDY Interrupt Enable for Pipe 3</description>
                            <lsb>3</lsb>
                            <msb>3</msb>
                            <access>read-write</access>
                            <enumeratedValues>
                                </enumeratedValues>
                        </field>
                        <field>
                            <name>PIPE4BRDYE</name>
                            <description>BRDY Interrupt Enable for Pipe 4</description>
                            <lsb>4</lsb>
                            <msb>4</msb>
                            <access>read-write</access>
                            <enumeratedValues>
                                </enumeratedValues>
                        </field>
                        <field>
                            <name>PIPE5BRDYE</name>
                            <description>BRDY Interrupt Enable for Pipe 5</description>
                            <lsb>5</lsb>
                            <msb>5</msb>
                            <access>read-write</access>
                            <enumeratedValues>
                                </enumeratedValues>
                        </field>
                        <field>
                            <name>PIPE6BRDYE</name>
                            <description>BRDY Interrupt Enable for Pipe 6</description>
                            <lsb>6</lsb>
                            <msb>6</msb>
                            <access>read-write</access>
                            <enumeratedValues>
                                </enumeratedValues>
                        </field>
                        <field>
                            <name>PIPE7BRDYE</name>
                            <description>BRDY Interrupt Enable for Pipe 7</description>
                            <lsb>7</lsb>
                            <msb>7</msb>
                            <access>read-write</access>
                            <enumeratedValues>
                                </enumeratedValues>
                        </field>
                        <field>
                            <name>PIPE8BRDYE</name>
                            <description>BRDY Interrupt Enable for Pipe 8</description>
                            <lsb>8</lsb>
                            <msb>8</msb>
                            <access>read-write</access>
                            <enumeratedValues>
                                </enumeratedValues>
                        </field>
                        <field>
                            <name>PIPE9BRDYE</name>
                            <description>BRDY Interrupt Enable for Pipe 9</description>
                            <lsb>9</lsb>
                            <msb>9</msb>
                            <access>read-write</access>
                            <enumeratedValues>
                                </enumeratedValues>
                        </field>
                    </fields>
                </register>
                <register>
                    <name>NRDYENB</name>
                    <description>NRDY Interrupt Enable Register</description>
                    <addressOffset>0x038</addressOffset>
                    <size>16</size>
                    <access>read-write</access>
                    <resetValue>0x0000</resetValue>
                    <resetMask>0xffff</resetMask>
                    <fields>
                        <field>
                            <name>PIPE0NRDYE</name>
                            <description>NRDY Interrupt Enable for Pipe 0</description>
                            <lsb>0</lsb>
                            <msb>0</msb>
                            <access>read-write</access>
                            <enumeratedValues>
                                </enumeratedValues>
                        </field>
                        <field>
                            <name>PIPE1NRDYE</name>
                            <description>NRDY Interrupt Enable for Pipe 1</description>
                            <lsb>1</lsb>
                            <msb>1</msb>
                            <access>read-write</access>
                            <enumeratedValues>
                                </enumeratedValues>
                        </field>
                        <field>
                            <name>PIPE2NRDYE</name>
                            <description>NRDY Interrupt Enable for Pipe 2</description>
                            <lsb>2</lsb>
                            <msb>2</msb>
                            <access>read-write</access>
                            <enumeratedValues>
                                </enumeratedValues>
                        </field>
                        <field>
                            <name>PIPE3NRDYE</name>
                            <description>NRDY Interrupt Enable for Pipe 3</description>
                            <lsb>3</lsb>
                            <msb>3</msb>
                            <access>read-write</access>
                            <enumeratedValues>
                                </enumeratedValues>
                        </field>
                        <field>
                            <name>PIPE4NRDYE</name>
                            <description>NRDY Interrupt Enable for Pipe 4</description>
                            <lsb>4</lsb>
                            <msb>4</msb>
                            <access>read-write</access>
                            <enumeratedValues>
                                </enumeratedValues>
                        </field>
                        <field>
                            <name>PIPE5NRDYE</name>
                            <description>NRDY Interrupt Enable for Pipe 5</description>
                            <lsb>5</lsb>
                            <msb>5</msb>
                            <access>read-write</access>
                            <enumeratedValues>
                                </enumeratedValues>
                        </field>
                        <field>
                            <name>PIPE6NRDYE</name>
                            <description>NRDY Interrupt Enable for Pipe 6</description>
                            <lsb>6</lsb>
                            <msb>6</msb>
                            <access>read-write</access>
                            <enumeratedValues>
                                </enumeratedValues>
                        </field>
                        <field>
                            <name>PIPE7NRDYE</name>
                            <description>NRDY Interrupt Enable for Pipe 7</description>
                            <lsb>7</lsb>
                            <msb>7</msb>
                            <access>read-write</access>
                            <enumeratedValues>
                                </enumeratedValues>
                        </field>
                        <field>
                            <name>PIPE8NRDYE</name>
                            <description>NRDY Interrupt Enable for Pipe 8</description>
                            <lsb>8</lsb>
                            <msb>8</msb>
                            <access>read-write</access>
                            <enumeratedValues>
                                </enumeratedValues>
                        </field>
                        <field>
                            <name>PIPE9NRDYE</name>
                            <description>NRDY Interrupt Enable for Pipe 9</description>
                            <lsb>9</lsb>
                            <msb>9</msb>
                            <access>read-write</access>
                            <enumeratedValues>
                                </enumeratedValues>
                        </field>
                    </fields>
                </register>
                <register>
                    <name>BEMPENB</name>
                    <description>BEMP Interrupt Enable Register</description>
                    <addressOffset>0x03A</addressOffset>
                    <size>16</size>
                    <access>read-write</access>
                    <resetValue>0x0000</resetValue>
                    <resetMask>0xffff</resetMask>
                    <fields>
                        <field>
                            <name>PIPE0BEMPE</name>
                            <description>BEMP Interrupt Enable for Pipe 0</description>
                            <lsb>0</lsb>
                            <msb>0</msb>
                            <access>read-write</access>
                            <enumeratedValues>
                                </enumeratedValues>
                        </field>
                        <field>
                            <name>PIPE1BEMPE</name>
                            <description>BEMP Interrupt Enable for Pipe 1</description>
                            <lsb>1</lsb>
                            <msb>1</msb>
                            <access>read-write</access>
                            <enumeratedValues>
                                </enumeratedValues>
                        </field>
                        <field>
                            <name>PIPE2BEMPE</name>
                            <description>BEMP Interrupt Enable for Pipe 2</description>
                            <lsb>2</lsb>
                            <msb>2</msb>
                            <access>read-write</access>
                            <enumeratedValues>
                                </enumeratedValues>
                        </field>
                        <field>
                            <name>PIPE3BEMPE</name>
                            <description>BEMP Interrupt Enable for Pipe 3</description>
                            <lsb>3</lsb>
                            <msb>3</msb>
                            <access>read-write</access>
                            <enumeratedValues>
                                </enumeratedValues>
                        </field>
                        <field>
                            <name>PIPE4BEMPE</name>
                            <description>BEMP Interrupt Enable for Pipe 4</description>
                            <lsb>4</lsb>
                            <msb>4</msb>
                            <access>read-write</access>
                            <enumeratedValues>
                                </enumeratedValues>
                        </field>
                        <field>
                            <name>PIPE5BEMPE</name>
                            <description>BEMP Interrupt Enable for Pipe 5</description>
                            <lsb>5</lsb>
                            <msb>5</msb>
                            <access>read-write</access>
                            <enumeratedValues>
                                </enumeratedValues>
                        </field>
                        <field>
                            <name>PIPE6BEMPE</name>
                            <description>BEMP Interrupt Enable for Pipe 6</description>
                            <lsb>6</lsb>
                            <msb>6</msb>
                            <access>read-write</access>
                            <enumeratedValues>
                                </enumeratedValues>
                        </field>
                        <field>
                            <name>PIPE7BEMPE</name>
                            <description>BEMP Interrupt Enable for Pipe 7</description>
                            <lsb>7</lsb>
                            <msb>7</msb>
                            <access>read-write</access>
                            <enumeratedValues>
                                </enumeratedValues>
                        </field>
                        <field>
                            <name>PIPE8BEMPE</name>
                            <description>BEMP Interrupt Enable for Pipe 8</description>
                            <lsb>8</lsb>
                            <msb>8</msb>
                            <access>read-write</access>
                            <enumeratedValues>
                                </enumeratedValues>
                        </field>
                        <field>
                            <name>PIPE9BEMPE</name>
                            <description>BEMP Interrupt Enable for Pipe 9</description>
                            <lsb>9</lsb>
                            <msb>9</msb>
                            <access>read-write</access>
                            <enumeratedValues>
                                </enumeratedValues>
                        </field>
                    </fields>
                </register>
                <register>
                    <name>SOFCFG</name>
                    <description>SOF Output Configuration Register</description>
                    <addressOffset>0x03C</addressOffset>
                    <size>16</size>
                    <access>read-write</access>
                    <resetValue>0x0000</resetValue>
                    <resetMask>0xffff</resetMask>
                    <fields>
                        <field>
                            <name>EDGESTS</name>
                            <description>Edge Interrupt Output Status Monitor</description>
                            <lsb>4</lsb>
                            <msb>4</msb>
                            <access>read-only</access>
                        </field>
                        <field>
                            <name>BRDYM</name>
                            <description>BRDY Interrupt Status Clear Timing</description>
                            <lsb>6</lsb>
                            <msb>6</msb>
                            <access>read-write</access>
                            <enumeratedValues>
                                </enumeratedValues>
                        </field>
                        <field>
                            <name>TRNENSEL</name>
                            <description>Transaction,Enabled Time Select</description>
                            <lsb>8</lsb>
                            <msb>8</msb>
                            <access>read-write</access>
                            <enumeratedValues>
                                </enumeratedValues>
                        </field>
                    </fields>
                </register>
                <register>
                    <name>INTSTS0</name>
                    <description>Interrupt Status Register 0</description>
                    <addressOffset>0x040</addressOffset>
                    <size>16</size>
                    <access>read-write</access>
                    <resetValue>0x0000</resetValue>
                    <resetMask>0xef6f</resetMask>
                    <fields>
                        <field>
                            <name>CTSQ</name>
                            <description>Control Transfer Stage</description>
                            <lsb>0</lsb>
                            <msb>2</msb>
                            <access>read-only</access>
                            <enumeratedValues>
                                </enumeratedValues>
                        </field>
                        <field>
                            <name>VALID</name>
                            <description>USB Request Reception</description>
                            <lsb>3</lsb>
                            <msb>3</msb>
                            <access>read-write</access>
                            <enumeratedValues>
                                </enumeratedValues>
                        </field>
                        <field>
                            <name>DVSQ</name>
                            <description>Device State</description>
                            <lsb>4</lsb>
                            <msb>6</msb>
                            <access>read-only</access>
                            <enumeratedValues>
                                </enumeratedValues>
                        </field>
                        <field>
                            <name>VBSTS</name>
                            <description>VBUS Input Status</description>
                            <lsb>7</lsb>
                            <msb>7</msb>
                            <access>read-only</access>
                            <enumeratedValues>
                                </enumeratedValues>
                        </field>
                        <field>
                            <name>BRDY</name>
                            <description>Buffer Ready Interrupt Status</description>
                            <lsb>8</lsb>
                            <msb>8</msb>
                            <access>read-only</access>
                            <enumeratedValues>
                                </enumeratedValues>
                        </field>
                        <field>
                            <name>NRDY</name>
                            <description>Buffer Not Ready Interrupt Status</description>
                            <lsb>9</lsb>
                            <msb>9</msb>
                            <access>read-only</access>
                            <enumeratedValues>
                                </enumeratedValues>
                        </field>
                        <field>
                            <name>BEMP</name>
                            <description>Buffer Empty Interrupt Status</description>
                            <lsb>10</lsb>
                            <msb>10</msb>
                            <access>read-only</access>
                            <enumeratedValues>
                                </enumeratedValues>
                        </field>
                        <field>
                            <name>CTRT</name>
                            <description>Control Transfer Stage Transition Interrupt Status</description>
                            <lsb>11</lsb>
                            <msb>11</msb>
                            <access>read-write</access>
                            <enumeratedValues>
                                </enumeratedValues>
                        </field>
                        <field>
                            <name>DVST</name>
                            <description>Device State Transition Interrupt Status</description>
                            <lsb>12</lsb>
                            <msb>12</msb>
                            <access>read-write</access>
                            <enumeratedValues>
                                </enumeratedValues>
                        </field>
                        <field>
                            <name>SOFR</name>
                            <description>Frame Number Refresh Interrupt Status</description>
                            <lsb>13</lsb>
                            <msb>13</msb>
                            <access>read-write</access>
                            <enumeratedValues>
                                </enumeratedValues>
                        </field>
                        <field>
                            <name>RESM</name>
                            <description>Resume Interrupt Status</description>
                            <lsb>14</lsb>
                            <msb>14</msb>
                            <access>read-write</access>
                            <enumeratedValues>
                                </enumeratedValues>
                        </field>
                        <field>
                            <name>VBINT</name>
                            <description>VBUS Interrupt Status</description>
                            <lsb>15</lsb>
                            <msb>15</msb>
                            <access>read-write</access>
                            <enumeratedValues>
                                </enumeratedValues>
                        </field>
                    </fields>
                </register>
                <register>
                    <name>INTSTS1</name>
                    <description>Interrupt Status Register 1</description>
                    <addressOffset>0x042</addressOffset>
                    <size>16</size>
                    <access>read-write</access>
                    <resetValue>0x0000</resetValue>
                    <resetMask>0xffff</resetMask>
                    <fields>
                        <field>
                            <name>PDDETINT</name>
                            <description>PDDET Detection Interrupt Status Flag</description>
                            <lsb>0</lsb>
                            <msb>0</msb>
                            <access>read-write</access>
                            <enumeratedValues>
                                </enumeratedValues>
                        </field>
                        <field>
                            <name>SACK</name>
                            <description>Setup Transaction Normal Response Interrupt Status</description>
                            <lsb>4</lsb>
                            <msb>4</msb>
                            <access>read-write</access>
                            <enumeratedValues>
                                </enumeratedValues>
                        </field>
                        <field>
                            <name>SIGN</name>
                            <description>Setup Transaction Error Interrupt Status</description>
                            <lsb>5</lsb>
                            <msb>5</msb>
                            <access>read-write</access>
                            <enumeratedValues>
                                </enumeratedValues>
                        </field>
                        <field>
                            <name>EOFERR</name>
                            <description>EOF Error Detection Interrupt Status</description>
                            <lsb>6</lsb>
                            <msb>6</msb>
                            <access>read-write</access>
                            <enumeratedValues>
                                </enumeratedValues>
                        </field>
                        <field>
                            <name>ATTCH</name>
                            <description>ATTCH Interrupt Status</description>
                            <lsb>11</lsb>
                            <msb>11</msb>
                            <access>read-write</access>
                            <enumeratedValues>
                                </enumeratedValues>
                        </field>
                        <field>
                            <name>DTCH</name>
                            <description>USB Disconnection Detection Interrupt Status</description>
                            <lsb>12</lsb>
                            <msb>12</msb>
                            <access>read-write</access>
                            <enumeratedValues>
                                </enumeratedValues>
                        </field>
                        <field>
                            <name>BCHG</name>
                            <description>USB Bus Change Interrupt Status</description>
                            <lsb>14</lsb>
                            <msb>14</msb>
                            <access>read-write</access>
                            <enumeratedValues>
                                </enumeratedValues>
                        </field>
                        <field>
                            <name>OVRCR</name>
                            <description>Overcurrent Input Change Interrupt Status</description>
                            <lsb>15</lsb>
                            <msb>15</msb>
                            <access>read-write</access>
                            <enumeratedValues>
                                </enumeratedValues>
                        </field>
                    </fields>
                </register>
                <register>
                    <name>BRDYSTS</name>
                    <description>BRDY Interrupt Status Register</description>
                    <addressOffset>0x046</addressOffset>
                    <size>16</size>
                    <access>read-write</access>
                    <resetValue>0x0000</resetValue>
                    <resetMask>0xffff</resetMask>
                    <fields>
                        <field>
                            <name>PIPE0BRDY</name>
                            <description>BRDY Interrupt Status for Pipe 0</description>
                            <lsb>0</lsb>
                            <msb>0</msb>
                            <access>read-write</access>
                            <enumeratedValues>
                                </enumeratedValues>
                        </field>
                        <field>
                            <name>PIPE1BRDY</name>
                            <description>BRDY Interrupt Status for Pipe 1</description>
                            <lsb>1</lsb>
                            <msb>1</msb>
                            <access>read-write</access>
                            <enumeratedValues>
                                </enumeratedValues>
                        </field>
                        <field>
                            <name>PIPE2BRDY</name>
                            <description>BRDY Interrupt Status for Pipe 2</description>
                            <lsb>2</lsb>
                            <msb>2</msb>
                            <access>read-write</access>
                            <enumeratedValues>
                                </enumeratedValues>
                        </field>
                        <field>
                            <name>PIPE3BRDY</name>
                            <description>BRDY Interrupt Status for Pipe 3</description>
                            <lsb>3</lsb>
                            <msb>3</msb>
                            <access>read-write</access>
                            <enumeratedValues>
                                </enumeratedValues>
                        </field>
                        <field>
                            <name>PIPE4BRDY</name>
                            <description>BRDY Interrupt Status for Pipe 4</description>
                            <lsb>4</lsb>
                            <msb>4</msb>
                            <access>read-write</access>
                            <enumeratedValues>
                                </enumeratedValues>
                        </field>
                        <field>
                            <name>PIPE5BRDY</name>
                            <description>BRDY Interrupt Status for Pipe 5</description>
                            <lsb>5</lsb>
                            <msb>5</msb>
                            <access>read-write</access>
                            <enumeratedValues>
                                </enumeratedValues>
                        </field>
                        <field>
                            <name>PIPE6BRDY</name>
                            <description>BRDY Interrupt Status for Pipe 6</description>
                            <lsb>6</lsb>
                            <msb>6</msb>
                            <access>read-write</access>
                            <enumeratedValues>
                                </enumeratedValues>
                        </field>
                        <field>
                            <name>PIPE7BRDY</name>
                            <description>BRDY Interrupt Status for Pipe 7</description>
                            <lsb>7</lsb>
                            <msb>7</msb>
                            <access>read-write</access>
                            <enumeratedValues>
                                </enumeratedValues>
                        </field>
                        <field>
                            <name>PIPE8BRDY</name>
                            <description>BRDY Interrupt Status for Pipe 8</description>
                            <lsb>8</lsb>
                            <msb>8</msb>
                            <access>read-write</access>
                            <enumeratedValues>
                                </enumeratedValues>
                        </field>
                        <field>
                            <name>PIPE9BRDY</name>
                            <description>BRDY Interrupt Status for Pipe 9</description>
                            <lsb>9</lsb>
                            <msb>9</msb>
                            <access>read-write</access>
                            <enumeratedValues>
                                </enumeratedValues>
                        </field>
                    </fields>
                </register>
                <register>
                    <name>NRDYSTS</name>
                    <description>NRDY Interrupt Status Register</description>
                    <addressOffset>0x048</addressOffset>
                    <size>16</size>
                    <access>read-write</access>
                    <resetValue>0x0000</resetValue>
                    <resetMask>0xffff</resetMask>
                    <fields>
                        <field>
                            <name>PIPE0NRDY</name>
                            <description>NRDY Interrupt Status for Pipe 0</description>
                            <lsb>0</lsb>
                            <msb>0</msb>
                            <access>read-write</access>
                            <enumeratedValues>
                                </enumeratedValues>
                        </field>
                        <field>
                            <name>PIPE1NRDY</name>
                            <description>NRDY Interrupt Status for Pipe 1</description>
                            <lsb>1</lsb>
                            <msb>1</msb>
                            <access>read-write</access>
                            <enumeratedValues>
                                </enumeratedValues>
                        </field>
                        <field>
                            <name>PIPE2NRDY</name>
                            <description>NRDY Interrupt Status for Pipe 2</description>
                            <lsb>2</lsb>
                            <msb>2</msb>
                            <access>read-write</access>
                            <enumeratedValues>
                                </enumeratedValues>
                        </field>
                        <field>
                            <name>PIPE3NRDY</name>
                            <description>NRDY Interrupt Status for Pipe 3</description>
                            <lsb>3</lsb>
                            <msb>3</msb>
                            <access>read-write</access>
                            <enumeratedValues>
                                </enumeratedValues>
                        </field>
                        <field>
                            <name>PIPE4NRDY</name>
                            <description>NRDY Interrupt Status for Pipe 4</description>
                            <lsb>4</lsb>
                            <msb>4</msb>
                            <access>read-write</access>
                            <enumeratedValues>
                                </enumeratedValues>
                        </field>
                        <field>
                            <name>PIPE5NRDY</name>
                            <description>NRDY Interrupt Status for Pipe 5</description>
                            <lsb>5</lsb>
                            <msb>5</msb>
                            <access>read-write</access>
                            <enumeratedValues>
                                </enumeratedValues>
                        </field>
                        <field>
                            <name>PIPE6NRDY</name>
                            <description>NRDY Interrupt Status for Pipe 6</description>
                            <lsb>6</lsb>
                            <msb>6</msb>
                            <access>read-write</access>
                            <enumeratedValues>
                                </enumeratedValues>
                        </field>
                        <field>
                            <name>PIPE7NRDY</name>
                            <description>NRDY Interrupt Status for Pipe 7</description>
                            <lsb>7</lsb>
                            <msb>7</msb>
                            <access>read-write</access>
                            <enumeratedValues>
                                </enumeratedValues>
                        </field>
                        <field>
                            <name>PIPE8NRDY</name>
                            <description>NRDY Interrupt Status for Pipe 8</description>
                            <lsb>8</lsb>
                            <msb>8</msb>
                            <access>read-write</access>
                            <enumeratedValues>
                                </enumeratedValues>
                        </field>
                        <field>
                            <name>PIPE9NRDY</name>
                            <description>NRDY Interrupt Status for Pipe 9</description>
                            <lsb>9</lsb>
                            <msb>9</msb>
                            <access>read-write</access>
                            <enumeratedValues>
                                </enumeratedValues>
                        </field>
                    </fields>
                </register>
                <register>
                    <name>BEMPSTS</name>
                    <description>BEMP Interrupt Status Register</description>
                    <addressOffset>0x04A</addressOffset>
                    <size>16</size>
                    <access>read-write</access>
                    <resetValue>0x0000</resetValue>
                    <resetMask>0xffff</resetMask>
                    <fields>
                        <field>
                            <name>PIPE0BEMP</name>
                            <description>BEMP Interrupt Status for Pipe 0</description>
                            <lsb>0</lsb>
                            <msb>0</msb>
                            <access>read-write</access>
                            <enumeratedValues>
                                </enumeratedValues>
                        </field>
                        <field>
                            <name>PIPE1BEMP</name>
                            <description>BEMP Interrupt Status for Pipe 1</description>
                            <lsb>1</lsb>
                            <msb>1</msb>
                            <access>read-write</access>
                            <enumeratedValues>
                                </enumeratedValues>
                        </field>
                        <field>
                            <name>PIPE2BEMP</name>
                            <description>BEMP Interrupt Status for Pipe 2</description>
                            <lsb>2</lsb>
                            <msb>2</msb>
                            <access>read-write</access>
                            <enumeratedValues>
                                </enumeratedValues>
                        </field>
                        <field>
                            <name>PIPE3BEMP</name>
                            <description>BEMP Interrupt Status for Pipe 3</description>
                            <lsb>3</lsb>
                            <msb>3</msb>
                            <access>read-write</access>
                            <enumeratedValues>
                                </enumeratedValues>
                        </field>
                        <field>
                            <name>PIPE4BEMP</name>
                            <description>BEMP Interrupt Status for Pipe 4</description>
                            <lsb>4</lsb>
                            <msb>4</msb>
                            <access>read-write</access>
                            <enumeratedValues>
                                </enumeratedValues>
                        </field>
                        <field>
                            <name>PIPE5BEMP</name>
                            <description>BEMP Interrupt Status for Pipe 5</description>
                            <lsb>5</lsb>
                            <msb>5</msb>
                            <access>read-write</access>
                            <enumeratedValues>
                                </enumeratedValues>
                        </field>
                        <field>
                            <name>PIPE6BEMP</name>
                            <description>BEMP Interrupt Status for Pipe 6</description>
                            <lsb>6</lsb>
                            <msb>6</msb>
                            <access>read-write</access>
                            <enumeratedValues>
                                </enumeratedValues>
                        </field>
                        <field>
                            <name>PIPE7BEMP</name>
                            <description>BEMP Interrupt Status for Pipe 7</description>
                            <lsb>7</lsb>
                            <msb>7</msb>
                            <access>read-write</access>
                            <enumeratedValues>
                                </enumeratedValues>
                        </field>
                        <field>
                            <name>PIPE8BEMP</name>
                            <description>BEMP Interrupt Status for Pipe 8</description>
                            <lsb>8</lsb>
                            <msb>8</msb>
                            <access>read-write</access>
                            <enumeratedValues>
                                </enumeratedValues>
                        </field>
                        <field>
                            <name>PIPE9BEMP</name>
                            <description>BEMP Interrupt Status for Pipe 9</description>
                            <lsb>9</lsb>
                            <msb>9</msb>
                            <access>read-write</access>
                            <enumeratedValues>
                                </enumeratedValues>
                        </field>
                    </fields>
                </register>
                <register>
                    <name>FRMNUM</name>
                    <description>Frame Number Register</description>
                    <addressOffset>0x04C</addressOffset>
                    <size>16</size>
                    <access>read-write</access>
                    <resetValue>0x0000</resetValue>
                    <resetMask>0xffff</resetMask>
                    <fields>
                        <field>
                            <name>FRNM</name>
                            <description>Frame Number</description>
                            <lsb>0</lsb>
                            <msb>10</msb>
                            <access>read-only</access>
                        </field>
                        <field>
                            <name>CRCE</name>
                            <description>Receive Data Error</description>
                            <lsb>14</lsb>
                            <msb>14</msb>
                            <access>read-write</access>
                            <enumeratedValues>
                                </enumeratedValues>
                        </field>
                        <field>
                            <name>OVRN</name>
                            <description>Overrun/Underrun Detection Status</description>
                            <lsb>15</lsb>
                            <msb>15</msb>
                            <access>read-write</access>
                            <enumeratedValues>
                                </enumeratedValues>
                        </field>
                    </fields>
                </register>
                <register>
                    <name>DVCHGR</name>
                    <description>Device State Change Register</description>
                    <addressOffset>0x04E</addressOffset>
                    <size>16</size>
                    <access>read-write</access>
                    <resetValue>0x0000</resetValue>
                    <resetMask>0xffff</resetMask>
                    <fields>
                        <field>
                            <name>DVCHG</name>
                            <description>Device State Change</description>
                            <lsb>15</lsb>
                            <msb>15</msb>
                            <access>read-write</access>
                            <enumeratedValues>
                                </enumeratedValues>
                        </field>
                    </fields>
                </register>
                <register>
                    <name>USBADDR</name>
                    <description>USB Address Register</description>
                    <addressOffset>0x050</addressOffset>
                    <size>16</size>
                    <access>read-write</access>
                    <resetValue>0x0000</resetValue>
                    <resetMask>0xffff</resetMask>
                    <fields>
                        <field>
                            <name>USBADDR</name>
                            <description>USB Address</description>
                            <lsb>0</lsb>
                            <msb>6</msb>
                            <access>read-write</access>
                        </field>
                        <field>
                            <name>STSRECOV</name>
                            <description>Status Recovery</description>
                            <lsb>8</lsb>
                            <msb>11</msb>
                            <access>read-write</access>
                            <enumeratedValues>
                                </enumeratedValues>
                        </field>
                    </fields>
                </register>
                <register>
                    <name>USBREQ</name>
                    <description>USB Request Type Register</description>
                    <addressOffset>0x054</addressOffset>
                    <size>16</size>
                    <access>read-write</access>
                    <resetValue>0x0000</resetValue>
                    <resetMask>0xffff</resetMask>
                    <fields>
                        <field>
                            <name>BMREQUESTTYPE</name>
                            <description>Request Type</description>
                            <lsb>0</lsb>
                            <msb>7</msb>
                            <access>read-write</access>
                        </field>
                        <field>
                            <name>BREQUEST</name>
                            <description>Request</description>
                            <lsb>8</lsb>
                            <msb>15</msb>
                            <access>read-write</access>
                        </field>
                    </fields>
                </register>
                <register>
                    <name>USBVAL</name>
                    <description>USB Request Value Register</description>
                    <addressOffset>0x056</addressOffset>
                    <size>16</size>
                    <access>read-write</access>
                    <resetValue>0x0000</resetValue>
                    <resetMask>0xffff</resetMask>
                    <fields>
                        <field>
                            <name>WVALUE</name>
                            <description>Value</description>
                            <lsb>0</lsb>
                            <msb>15</msb>
                            <access>read-write</access>
                        </field>
                    </fields>
                </register>
                <register>
                    <name>USBINDX</name>
                    <description>USB Request Index Register</description>
                    <addressOffset>0x058</addressOffset>
                    <size>16</size>
                    <access>read-write</access>
                    <resetValue>0x0000</resetValue>
                    <resetMask>0xffff</resetMask>
                    <fields>
                        <field>
                            <name>WINDEX</name>
                            <description>Index</description>
                            <lsb>0</lsb>
                            <msb>15</msb>
                            <access>read-write</access>
                        </field>
                    </fields>
                </register>
                <register>
                    <name>USBLENG</name>
                    <description>USB Request Length Register</description>
                    <addressOffset>0x05A</addressOffset>
                    <size>16</size>
                    <access>read-write</access>
                    <resetValue>0x0000</resetValue>
                    <resetMask>0xffff</resetMask>
                    <fields>
                        <field>
                            <name>WLENTUH</name>
                            <description>Length</description>
                            <lsb>0</lsb>
                            <msb>15</msb>
                            <access>read-write</access>
                        </field>
                    </fields>
                </register>
                <register>
                    <name>DCPCFG</name>
                    <description>DCP Configuration Register</description>
                    <addressOffset>0x05C</addressOffset>
                    <size>16</size>
                    <access>read-write</access>
                    <resetValue>0x0000</resetValue>
                    <resetMask>0xffff</resetMask>
                    <fields>
                        <field>
                            <name>DIR</name>
                            <description>Transfer Direction</description>
                            <lsb>4</lsb>
                            <msb>4</msb>
                            <access>read-write</access>
                            <enumeratedValues>
                                </enumeratedValues>
                        </field>
                        <field>
                            <name>SHTNAK</name>
                            <description>Pipe Disabled at End of Transfer</description>
                            <lsb>7</lsb>
                            <msb>7</msb>
                            <access>read-write</access>
                            <enumeratedValues>
                                </enumeratedValues>
                        </field>
                    </fields>
                </register>
                <register>
                    <name>DCPMAXP</name>
                    <description>DCP Maximum Packet Size Register</description>
                    <addressOffset>0x05E</addressOffset>
                    <size>16</size>
                    <access>read-write</access>
                    <resetValue>0x0040</resetValue>
                    <resetMask>0xffff</resetMask>
                    <fields>
                        <field>
                            <name>MXPS</name>
                            <description>Maximum Packet Size</description>
                            <lsb>0</lsb>
                            <msb>6</msb>
                            <access>read-write</access>
                        </field>
                        <field>
                            <name>DEVSEL</name>
                            <description>Device Select</description>
                            <lsb>12</lsb>
                            <msb>15</msb>
                            <access>read-write</access>
                            <enumeratedValues>
                                </enumeratedValues>
                        </field>
                    </fields>
                </register>
                <register>
                    <name>DCPCTR</name>
                    <description>DCP Control Register</description>
                    <addressOffset>0x060</addressOffset>
                    <size>16</size>
                    <access>read-write</access>
                    <resetValue>0x0040</resetValue>
                    <resetMask>0xffff</resetMask>
                    <fields>
                        <field>
                            <name>PID</name>
                            <description>Response PID</description>
                            <lsb>0</lsb>
                            <msb>1</msb>
                            <access>read-write</access>
                            <enumeratedValues>
                                </enumeratedValues>
                        </field>
                        <field>
                            <name>CCPL</name>
                            <description>Control Transfer End Enable</description>
                            <lsb>2</lsb>
                            <msb>2</msb>
                            <access>read-write</access>
                            <enumeratedValues>
                                </enumeratedValues>
                        </field>
                        <field>
                            <name>PBUSY</name>
                            <description>Pipe Busy</description>
                            <lsb>5</lsb>
                            <msb>5</msb>
                            <access>read-only</access>
                            <enumeratedValues>
                                </enumeratedValues>
                        </field>
                        <field>
                            <name>SQMON</name>
                            <description>Sequence Toggle Bit Monitor</description>
                            <lsb>6</lsb>
                            <msb>6</msb>
                            <access>read-only</access>
                            <enumeratedValues>
                                </enumeratedValues>
                        </field>
                        <field>
                            <name>SQSET</name>
                            <description>Sequence Toggle Bit Set</description>
                            <lsb>7</lsb>
                            <msb>7</msb>
                            <access>read-write</access>
                            <enumeratedValues>
                                </enumeratedValues>
                        </field>
                        <field>
                            <name>SQCLR</name>
                            <description>Sequence Toggle Bit Clear</description>
                            <lsb>8</lsb>
                            <msb>8</msb>
                            <access>read-write</access>
                            <enumeratedValues>
                                </enumeratedValues>
                        </field>
                        <field>
                            <name>SUREQCLR</name>
                            <description>SUREQ Bit Clear</description>
                            <lsb>11</lsb>
                            <msb>11</msb>
                            <access>read-write</access>
                            <enumeratedValues>
                                </enumeratedValues>
                        </field>
                        <field>
                            <name>SUREQ</name>
                            <description>Setup Token Transmission</description>
                            <lsb>14</lsb>
                            <msb>14</msb>
                            <access>read-write</access>
                            <enumeratedValues>
                                </enumeratedValues>
                        </field>
                        <field>
                            <name>BSTS</name>
                            <description>Buffer Status</description>
                            <lsb>15</lsb>
                            <msb>15</msb>
                            <access>read-only</access>
                            <enumeratedValues>
                                </enumeratedValues>
                        </field>
                    </fields>
                </register>
                <register>
                    <name>PIPESEL</name>
                    <description>Pipe Window Select Register</description>
                    <addressOffset>0x064</addressOffset>
                    <size>16</size>
                    <access>read-write</access>
                    <resetValue>0x0000</resetValue>
                    <resetMask>0xffff</resetMask>
                    <fields>
                        <field>
                            <name>PIPESEL</name>
                            <description>Pipe Window Select</description>
                            <lsb>0</lsb>
                            <msb>3</msb>
                            <access>read-write</access>
                            <enumeratedValues>
                                </enumeratedValues>
                        </field>
                    </fields>
                </register>
                <register>
                    <name>PIPECFG</name>
                    <description>Pipe Configuration Register</description>
                    <addressOffset>0x068</addressOffset>
                    <size>16</size>
                    <access>read-write</access>
                    <resetValue>0x0000</resetValue>
                    <resetMask>0xffff</resetMask>
                    <fields>
                        <field>
                            <name>EPNUM</name>
                            <description>Endpoint Number</description>
                            <lsb>0</lsb>
                            <msb>3</msb>
                            <access>read-write</access>
                        </field>
                        <field>
                            <name>DIR</name>
                            <description>Transfer Direction</description>
                            <lsb>4</lsb>
                            <msb>4</msb>
                            <access>read-write</access>
                            <enumeratedValues>
                                </enumeratedValues>
                        </field>
                        <field>
                            <name>SHTNAK</name>
                            <description>Pipe Disabled at End of Transfer</description>
                            <lsb>7</lsb>
                            <msb>7</msb>
                            <access>read-write</access>
                            <enumeratedValues>
                                </enumeratedValues>
                        </field>
                        <field>
                            <name>DBLB</name>
                            <description>Double Buffer Mode</description>
                            <lsb>9</lsb>
                            <msb>9</msb>
                            <access>read-write</access>
                            <enumeratedValues>
                                </enumeratedValues>
                        </field>
                        <field>
                            <name>BFRE</name>
                            <description>BRDY Interrupt Operation Specification</description>
                            <lsb>10</lsb>
                            <msb>10</msb>
                            <access>read-write</access>
                            <enumeratedValues>
                                </enumeratedValues>
                        </field>
                        <field>
                            <name>TYPE</name>
                            <description>Transfer Type</description>
                            <lsb>14</lsb>
                            <msb>15</msb>
                            <access>read-write</access>
                            <enumeratedValues>
                                </enumeratedValues>
                        </field>
                    </fields>
                </register>
                <register>
                    <name>PIPEMAXP</name>
                    <description>Pipe Maximum Packet Size Register</description>
                    <addressOffset>0x06C</addressOffset>
                    <size>16</size>
                    <access>read-write</access>
                    <resetValue>0x0000</resetValue>
                    <resetMask>0xffbf</resetMask>
                    <fields>
                        <field>
                            <name>MXPS</name>
                            <description>Maximum Packet Size</description>
                            <lsb>0</lsb>
                            <msb>8</msb>
                            <access>read-write</access>
                        </field>
                        <field>
                            <name>DEVSEL</name>
                            <description>Device Select</description>
                            <lsb>12</lsb>
                            <msb>15</msb>
                            <access>read-write</access>
                            <enumeratedValues>
                                </enumeratedValues>
                        </field>
                    </fields>
                </register>
                <register>
                    <name>PIPEPERI</name>
                    <description>Pipe Cycle Control Register</description>
                    <addressOffset>0x06E</addressOffset>
                    <size>16</size>
                    <access>read-write</access>
                    <resetValue>0x0000</resetValue>
                    <resetMask>0xffff</resetMask>
                    <fields>
                        <field>
                            <name>IITV</name>
                            <description>Interval Error Detection Interval</description>
                            <lsb>0</lsb>
                            <msb>2</msb>
                            <access>read-write</access>
                        </field>
                        <field>
                            <name>IFIS</name>
                            <description>Isochronous IN Buffer Flush</description>
                            <lsb>12</lsb>
                            <msb>12</msb>
                            <access>read-write</access>
                            <enumeratedValues>
                                </enumeratedValues>
                        </field>
                    </fields>
                </register>
                <register>
                    <dim>5</dim>
                    <dimIncrement>0x2</dimIncrement>
                    <dimIndex>1-5</dimIndex>
                    <name>PIPE%sCTR</name>
                    <description>PIPE%s Control Registers</description>
                    <addressOffset>0x070</addressOffset>
                    <size>16</size>
                    <access>read-write</access>
                    <resetValue>0x0000</resetValue>
                    <resetMask>0xffff</resetMask>
                    <fields>
                        <field>
                            <name>PID</name>
                            <description>Response PID</description>
                            <lsb>0</lsb>
                            <msb>1</msb>
                            <access>read-write</access>
                            <enumeratedValues>
                                </enumeratedValues>
                        </field>
                        <field>
                            <name>PBUSY</name>
                            <description>Pipe Busy</description>
                            <lsb>5</lsb>
                            <msb>5</msb>
                            <access>read-only</access>
                            <enumeratedValues>
                                </enumeratedValues>
                        </field>
                        <field>
                            <name>SQMON</name>
                            <description>Sequence Toggle Bit Confirmation</description>
                            <lsb>6</lsb>
                            <msb>6</msb>
                            <access>read-only</access>
                            <enumeratedValues>
                                </enumeratedValues>
                        </field>
                        <field>
                            <name>SQSET</name>
                            <description>Sequence Toggle Bit Set</description>
                            <lsb>7</lsb>
                            <msb>7</msb>
                            <access>read-write</access>
                            <enumeratedValues>
                                </enumeratedValues>
                        </field>
                        <field>
                            <name>SQCLR</name>
                            <description>Sequence Toggle Bit Clear</description>
                            <lsb>8</lsb>
                            <msb>8</msb>
                            <access>read-write</access>
                            <enumeratedValues>
                                </enumeratedValues>
                        </field>
                        <field>
                            <name>ACLRM</name>
                            <description>Auto Buffer Clear Mode</description>
                            <lsb>9</lsb>
                            <msb>9</msb>
                            <access>read-write</access>
                            <enumeratedValues>
                                </enumeratedValues>
                        </field>
                        <field>
                            <name>ATREPM</name>
                            <description>Auto Response Mode</description>
                            <lsb>10</lsb>
                            <msb>10</msb>
                            <access>read-write</access>
                            <enumeratedValues>
                                </enumeratedValues>
                        </field>
                        <field>
                            <name>INBUFM</name>
                            <description>Transmit Buffer Monitor</description>
                            <lsb>14</lsb>
                            <msb>14</msb>
                            <access>read-only</access>
                            <enumeratedValues>
                                </enumeratedValues>
                        </field>
                        <field>
                            <name>BSTS</name>
                            <description>Buffer Status</description>
                            <lsb>15</lsb>
                            <msb>15</msb>
                            <access>read-only</access>
                            <enumeratedValues>
                                </enumeratedValues>
                        </field>
                    </fields>
                </register>
                <register>
                    <dim>4</dim>
                    <dimIncrement>0x2</dimIncrement>
                    <dimIndex>6-9</dimIndex>
                    <name>PIPE%sCTR_1</name>
                    <description>PIPE%s Control Registers</description>
                    <addressOffset>0x07A</addressOffset>
                    <size>16</size>
                    <access>read-write</access>
                    <resetValue>0x0000</resetValue>
                    <resetMask>0xffff</resetMask>
                    <fields>
                        <field>
                            <name>PID</name>
                            <description>Response PID</description>
                            <lsb>0</lsb>
                            <msb>1</msb>
                            <access>read-write</access>
                            <enumeratedValues>
                                </enumeratedValues>
                        </field>
                        <field>
                            <name>PBUSY</name>
                            <description>Pipe Busy</description>
                            <lsb>5</lsb>
                            <msb>5</msb>
                            <access>read-only</access>
                            <enumeratedValues>
                                </enumeratedValues>
                        </field>
                        <field>
                            <name>SQMON</name>
                            <description>Sequence Toggle Bit Confirmation</description>
                            <lsb>6</lsb>
                            <msb>6</msb>
                            <access>read-only</access>
                            <enumeratedValues>
                                </enumeratedValues>
                        </field>
                        <field>
                            <name>SQSET</name>
                            <description>Sequence Toggle Bit Set</description>
                            <lsb>7</lsb>
                            <msb>7</msb>
                            <access>write-only</access>
                            <enumeratedValues>
                                </enumeratedValues>
                        </field>
                        <field>
                            <name>SQCLR</name>
                            <description>Sequence Toggle Bit Clear</description>
                            <lsb>8</lsb>
                            <msb>8</msb>
                            <access>write-only</access>
                            <enumeratedValues>
                                </enumeratedValues>
                        </field>
                        <field>
                            <name>ACLRM</name>
                            <description>Auto Buffer Clear Mode</description>
                            <lsb>9</lsb>
                            <msb>9</msb>
                            <access>read-write</access>
                            <enumeratedValues>
                                </enumeratedValues>
                        </field>
                        <field>
                            <name>BSTS</name>
                            <description>Buffer Status</description>
                            <lsb>15</lsb>
                            <msb>15</msb>
                            <access>read-only</access>
                            <enumeratedValues>
                                </enumeratedValues>
                        </field>
                    </fields>
                </register>
                <register>
                    <dim>5</dim>
                    <dimIncrement>0x4</dimIncrement>
                    <dimIndex>1-5</dimIndex>
                    <name>PIPE%sTRE</name>
                    <description>PIPE%s Transaction Counter Enable Register</description>
                    <addressOffset>0x090</addressOffset>
                    <size>16</size>
                    <access>read-write</access>
                    <resetValue>0x0000</resetValue>
                    <resetMask>0xffff</resetMask>
                    <fields>
                        <field>
                            <name>TRCLR</name>
                            <description>Transaction Counter Clear</description>
                            <lsb>8</lsb>
                            <msb>8</msb>
                            <access>read-write</access>
                            <enumeratedValues>
                                </enumeratedValues>
                        </field>
                        <field>
                            <name>TRENB</name>
                            <description>Transaction Counter Enable</description>
                            <lsb>9</lsb>
                            <msb>9</msb>
                            <access>read-write</access>
                            <enumeratedValues>
                                </enumeratedValues>
                        </field>
                    </fields>
                </register>
                <register>
                    <dim>5</dim>
                    <dimIncrement>0x4</dimIncrement>
                    <dimIndex>1-5</dimIndex>
                    <name>PIPE%sTRN</name>
                    <description>PIPE%s Transaction Counter Register</description>
                    <addressOffset>0x092</addressOffset>
                    <size>16</size>
                    <access>read-write</access>
                    <resetValue>0x0000</resetValue>
                    <resetMask>0xffff</resetMask>
                    <fields>
                        <field>
                            <name>TRNCNT</name>
                            <description>Transaction Counter</description>
                            <lsb>0</lsb>
                            <msb>15</msb>
                            <access>read-write</access>
                        </field>
                    </fields>
                </register>
                <register>
                    <name>BCCTRL1</name>
                    <description>Battery Charging Control Register 1</description>
                    <addressOffset>0x0B0</addressOffset>
                    <size>32</size>
                    <access>read-write</access>
                    <resetValue>0x00000000</resetValue>
                    <resetMask>0xffffffff</resetMask>
                    <fields>
                        <field>
                            <name>RPDME</name>
                            <description>D- Line Pull,down Control</description>
                            <lsb>0</lsb>
                            <msb>0</msb>
                            <access>read-write</access>
                            <enumeratedValues>
                                </enumeratedValues>
                        </field>
                        <field>
                            <name>IDPSRCE</name>
                            <description>D+ Line IDPSRC Output Control</description>
                            <lsb>1</lsb>
                            <msb>1</msb>
                            <access>read-write</access>
                            <enumeratedValues>
                                </enumeratedValues>
                        </field>
                        <field>
                            <name>VDMSRCE</name>
                            <description>D- Line VDMSRC (0.6 V) Output Control</description>
                            <lsb>2</lsb>
                            <msb>2</msb>
                            <access>read-write</access>
                            <enumeratedValues>
                                </enumeratedValues>
                        </field>
                        <field>
                            <name>VDPSRCE</name>
                            <description>D+ Line VDPSRC (0.6 V) Output Control</description>
                            <lsb>3</lsb>
                            <msb>3</msb>
                            <access>read-write</access>
                            <enumeratedValues>
                                </enumeratedValues>
                        </field>
                        <field>
                            <name>PDDETE</name>
                            <description>D+ Line 0.6 V Input Detection Control</description>
                            <lsb>4</lsb>
                            <msb>4</msb>
                            <access>read-write</access>
                            <enumeratedValues>
                                </enumeratedValues>
                        </field>
                        <field>
                            <name>CHGDETE</name>
                            <description>D- Line 0.6 V Input Detection Control</description>
                            <lsb>5</lsb>
                            <msb>5</msb>
                            <access>read-write</access>
                            <enumeratedValues>
                                </enumeratedValues>
                        </field>
                        <field>
                            <name>PDDETSTS</name>
                            <description>D+ Line 0.6 V Input Detection Status Flag</description>
                            <lsb>8</lsb>
                            <msb>8</msb>
                            <access>read-only</access>
                            <enumeratedValues>
                                </enumeratedValues>
                        </field>
                        <field>
                            <name>CHGDETSTS</name>
                            <description>D- Line 0.6 V Input Detection Status Flag</description>
                            <lsb>9</lsb>
                            <msb>9</msb>
                            <access>read-only</access>
                            <enumeratedValues>
                                </enumeratedValues>
                        </field>
                    </fields>
                </register>
                <register>
                    <name>BCCTRL2</name>
                    <description>Battery Charging Control Register 2</description>
                    <addressOffset>0x0B4</addressOffset>
                    <size>32</size>
                    <access>read-write</access>
                    <resetValue>0x00002000</resetValue>
                    <resetMask>0xffffffff</resetMask>
                    <fields>
                        <field>
                            <name>DCPMODE</name>
                            <description>Dedicated Charging Port (DCP) Mode Control</description>
                            <lsb>6</lsb>
                            <msb>6</msb>
                            <access>read-write</access>
                            <enumeratedValues>
                                </enumeratedValues>
                        </field>
                        <field>
                            <name>BATCHGE</name>
                            <description>Battery Charging Enable</description>
                            <lsb>7</lsb>
                            <msb>7</msb>
                            <access>read-write</access>
                            <enumeratedValues>
                                </enumeratedValues>
                        </field>
                        <field>
                            <name>PHYDET</name>
                            <description>Detect Sensitivity Adjustment</description>
                            <lsb>12</lsb>
                            <msb>13</msb>
                            <access>read-write</access>
                        </field>
                    </fields>
                </register>
                <register>
                    <dim>6</dim>
                    <dimIncrement>0x2</dimIncrement>
                    <dimIndex>0-5</dimIndex>
                    <name>DEVADD%s</name>
                    <description>Device Address %s Configuration Register</description>
                    <addressOffset>0x0D0</addressOffset>
                    <size>16</size>
                    <access>read-write</access>
                    <resetValue>0x0000</resetValue>
                    <resetMask>0xffff</resetMask>
                    <fields>
                        <field>
                            <name>USBSPD</name>
                            <description>Transfer Speed of Communication Target Device</description>
                            <lsb>6</lsb>
                            <msb>7</msb>
                            <access>read-write</access>
                            <enumeratedValues>
                                </enumeratedValues>
                        </field>
                    </fields>
                </register>
                <register>
                    <name>PHYSECTRL</name>
                    <description>PHY Single,ended Receiver Control Register</description>
                    <addressOffset>0x0F4</addressOffset>
                    <size>32</size>
                    <access>read-write</access>
                    <resetValue>0x00000000</resetValue>
                    <resetMask>0xffffffff</resetMask>
                    <fields>
                        <field>
                            <name>CNEN</name>
                            <description>Single,ended Receiver Enable</description>
                            <lsb>4</lsb>
                            <msb>4</msb>
                            <access>read-write</access>
                            <enumeratedValues>
                                </enumeratedValues>
                        </field>
                    </fields>
                </register>
                <register>
                    <name>DPUSR0R</name>
                    <description>Deep Software Standby USB Transceiver Control/Pin Monitor Register</description>
                    <addressOffset>0x400</addressOffset>
                    <size>32</size>
                    <access>read-write</access>
                    <resetValue>0x00000000</resetValue>
                    <resetMask>0xff4cffff</resetMask>
                    <fields>
                        <field>
                            <name>SRPC0</name>
                            <description>USB Single,ended Receiver Control</description>
                            <lsb>0</lsb>
                            <msb>0</msb>
                            <access>read-write</access>
                            <enumeratedValues>
                                </enumeratedValues>
                        </field>
                        <field>
                            <name>RPUE0</name>
                            <description>DP Pull,Up Resistor Control</description>
                            <lsb>1</lsb>
                            <msb>1</msb>
                            <access>read-write</access>
                            <enumeratedValues>
                                </enumeratedValues>
                        </field>
                        <field>
                            <name>DRPD0</name>
                            <description>D+/D- Pull,Down Resistor Control</description>
                            <lsb>3</lsb>
                            <msb>3</msb>
                            <access>read-write</access>
                            <enumeratedValues>
                                </enumeratedValues>
                        </field>
                        <field>
                            <name>FIXPHY0</name>
                            <description>USB Transceiver Output Fix</description>
                            <lsb>4</lsb>
                            <msb>4</msb>
                            <access>read-write</access>
                            <enumeratedValues>
                                </enumeratedValues>
                        </field>
                        <field>
                            <name>DP0</name>
                            <description>USB D+ Input</description>
                            <lsb>16</lsb>
                            <msb>16</msb>
                            <access>read-only</access>
                        </field>
                        <field>
                            <name>DM0</name>
                            <description>USB D- Input</description>
                            <lsb>17</lsb>
                            <msb>17</msb>
                            <access>read-only</access>
                        </field>
                        <field>
                            <name>DOVCA0</name>
                            <description>USB OVRCURA Input</description>
                            <lsb>20</lsb>
                            <msb>20</msb>
                            <access>read-only</access>
                        </field>
                        <field>
                            <name>DOVCB0</name>
                            <description>USB OVRCURB Input</description>
                            <lsb>21</lsb>
                            <msb>21</msb>
                            <access>read-only</access>
                        </field>
                        <field>
                            <name>DVBSTS0</name>
                            <description>USB VBUS Input</description>
                            <lsb>23</lsb>
                            <msb>23</msb>
                            <access>read-only</access>
                        </field>
                    </fields>
                </register>
                <register>
                    <name>DPUSR1R</name>
                    <description>Deep Software Standby USB Suspend/Resume Interrupt Register</description>
                    <addressOffset>0x404</addressOffset>
                    <size>32</size>
                    <access>read-write</access>
                    <resetValue>0x00000000</resetValue>
                    <resetMask>0xffffffff</resetMask>
                    <fields>
                        <field>
                            <name>DPINTE0</name>
                            <description>USB DP Interrupt Enable/Clear</description>
                            <lsb>0</lsb>
                            <msb>0</msb>
                            <access>read-write</access>
                            <enumeratedValues>
                                </enumeratedValues>
                        </field>
                        <field>
                            <name>DMINTE0</name>
                            <description>USB DM Interrupt Enable/Clear</description>
                            <lsb>1</lsb>
                            <msb>1</msb>
                            <access>read-write</access>
                            <enumeratedValues>
                                </enumeratedValues>
                        </field>
                        <field>
                            <name>DOVRCRAE0</name>
                            <description>USB OVRCURA Interrupt Enable/Clear</description>
                            <lsb>4</lsb>
                            <msb>4</msb>
                            <access>read-write</access>
                            <enumeratedValues>
                                </enumeratedValues>
                        </field>
                        <field>
                            <name>DOVRCRBE0</name>
                            <description>USB OVRCURB Interrupt Enable/Clear</description>
                            <lsb>5</lsb>
                            <msb>5</msb>
                            <access>read-write</access>
                            <enumeratedValues>
                                </enumeratedValues>
                        </field>
                        <field>
                            <name>DVBSE0</name>
                            <description>USB VBUS Interrupt Enable/Clear</description>
                            <lsb>7</lsb>
                            <msb>7</msb>
                            <access>read-write</access>
                            <enumeratedValues>
                                </enumeratedValues>
                        </field>
                        <field>
                            <name>DPINT0</name>
                            <description>USB DP Interrupt Source Recovery</description>
                            <lsb>16</lsb>
                            <msb>16</msb>
                            <access>read-only</access>
                            <enumeratedValues>
                                </enumeratedValues>
                        </field>
                        <field>
                            <name>DMINT0</name>
                            <description>USB DM Interrupt Source Recovery</description>
                            <lsb>17</lsb>
                            <msb>17</msb>
                            <access>read-only</access>
                            <enumeratedValues>
                                </enumeratedValues>
                        </field>
                        <field>
                            <name>DOVRCRA0</name>
                            <description>USB OVRCURA Interrupt Source Recovery</description>
                            <lsb>20</lsb>
                            <msb>20</msb>
                            <access>read-only</access>
                            <enumeratedValues>
                                </enumeratedValues>
                        </field>
                        <field>
                            <name>DOVRCRB0</name>
                            <description>USB OVRCURB Interrupt Source Recovery</description>
                            <lsb>21</lsb>
                            <msb>21</msb>
                            <access>read-only</access>
                            <enumeratedValues>
                                </enumeratedValues>
                        </field>
                        <field>
                            <name>DVBINT0</name>
                            <description>USB VBUS Interrupt Source Recovery</description>
                            <lsb>23</lsb>
                            <msb>23</msb>
                            <access>read-only</access>
                            <enumeratedValues>
                                </enumeratedValues>
                        </field>
                    </fields>
                </register>
            </registers>
        </peripheral>
        <peripheral>
            <name>SDHI0</name>
            <description>SD Host Interface 0</description>
            <baseAddress>0x40092000</baseAddress>
            <addressBlock>
                <offset>0x00</offset>
                <size>4</size>
                <usage>registers</usage>
            </addressBlock>
            <addressBlock>
                <offset>0x08</offset>
                <size>76</size>
                <usage>registers</usage>
            </addressBlock>
            <addressBlock>
                <offset>0x58</offset>
                <size>12</size>
                <usage>registers</usage>
            </addressBlock>
            <addressBlock>
                <offset>0x68</offset>
                <size>12</size>
                <usage>registers</usage>
            </addressBlock>
            <addressBlock>
                <offset>0x1B0</offset>
                <size>4</size>
                <usage>registers</usage>
            </addressBlock>
            <addressBlock>
                <offset>0x1C0</offset>
                <size>4</size>
                <usage>registers</usage>
            </addressBlock>
            <addressBlock>
                <offset>0x1CC</offset>
                <size>4</size>
                <usage>registers</usage>
            </addressBlock>
            <addressBlock>
                <offset>0x1E0</offset>
                <size>4</size>
                <usage>registers</usage>
            </addressBlock>
            <registers>
                <register>
                    <name>SD_CMD</name>
                    <description>Command Type Register</description>
                    <addressOffset>0x000</addressOffset>
                    <size>32</size>
                    <access>read-write</access>
                    <resetValue>0x00000000</resetValue>
                    <resetMask>0xffffffff</resetMask>
                    <fields>
                        <field>
                            <name>CMDIDX</name>
                            <description>Command Index Field Value Select</description>
                            <lsb>0</lsb>
                            <msb>5</msb>
                            <access>read-write</access>
                            <enumeratedValues>
                                </enumeratedValues>
                        </field>
                        <field>
                            <name>ACMD</name>
                            <description>Command Type Select</description>
                            <lsb>6</lsb>
                            <msb>7</msb>
                            <access>read-write</access>
                            <enumeratedValues>
                                </enumeratedValues>
                        </field>
                        <field>
                            <name>RSPTP</name>
                            <description>Response Type Select</description>
                            <lsb>8</lsb>
                            <msb>10</msb>
                            <access>read-write</access>
                            <enumeratedValues>
                                </enumeratedValues>
                        </field>
                        <field>
                            <name>CMDTP</name>
                            <description>Data Transfer Select</description>
                            <lsb>11</lsb>
                            <msb>11</msb>
                            <access>read-write</access>
                            <enumeratedValues>
                                </enumeratedValues>
                        </field>
                        <field>
                            <name>CMDRW</name>
                            <description>Data Transfer Direction Select</description>
                            <lsb>12</lsb>
                            <msb>12</msb>
                            <access>read-write</access>
                            <enumeratedValues>
                                </enumeratedValues>
                        </field>
                        <field>
                            <name>TRSTP</name>
                            <description>Block Transfer Select</description>
                            <lsb>13</lsb>
                            <msb>13</msb>
                            <access>read-write</access>
                            <enumeratedValues>
                                </enumeratedValues>
                        </field>
                        <field>
                            <name>CMD12AT</name>
                            <description>CMD12 Automatic Issue Select</description>
                            <lsb>14</lsb>
                            <msb>15</msb>
                            <access>read-write</access>
                            <enumeratedValues>
                                </enumeratedValues>
                        </field>
                    </fields>
                </register>
                <register>
                    <name>SD_ARG</name>
                    <description>SD Command Argument Register</description>
                    <addressOffset>0x008</addressOffset>
                    <size>32</size>
                    <access>read-write</access>
                    <resetValue>0x00000000</resetValue>
                    <resetMask>0xffffffff</resetMask>
                </register>
                <register>
                    <name>SD_ARG1</name>
                    <description>SD Command Argument Register 1</description>
                    <addressOffset>0x00C</addressOffset>
                    <size>32</size>
                    <access>read-write</access>
                    <resetValue>0x00000000</resetValue>
                    <resetMask>0xffffffff</resetMask>
                </register>
                <register>
                    <name>SD_STOP</name>
                    <description>Data Stop Register</description>
                    <addressOffset>0x010</addressOffset>
                    <size>32</size>
                    <access>read-write</access>
                    <resetValue>0x00000000</resetValue>
                    <resetMask>0xffffffff</resetMask>
                    <fields>
                        <field>
                            <name>STP</name>
                            <description>Transfer Stop</description>
                            <lsb>0</lsb>
                            <msb>0</msb>
                            <access>read-write</access>
                        </field>
                        <field>
                            <name>SEC</name>
                            <description>Block Count Register Value Select</description>
                            <lsb>8</lsb>
                            <msb>8</msb>
                            <access>read-write</access>
                            <enumeratedValues>
                                </enumeratedValues>
                        </field>
                    </fields>
                </register>
                <register>
                    <name>SD_SECCNT</name>
                    <description>Block Count Register</description>
                    <addressOffset>0x014</addressOffset>
                    <size>32</size>
                    <access>read-write</access>
                    <resetValue>0x00000000</resetValue>
                    <resetMask>0xffffffff</resetMask>
                </register>
                <register>
                    <name>SD_RSP10</name>
                    <description>SD Card Response Register 10</description>
                    <addressOffset>0x018</addressOffset>
                    <size>32</size>
                    <access>read-write</access>
                    <resetValue>0x00000000</resetValue>
                    <resetMask>0xffffffff</resetMask>
                </register>
                <register>
                    <name>SD_RSP1</name>
                    <description>SD Card Response Register 1</description>
                    <addressOffset>0x01C</addressOffset>
                    <size>32</size>
                    <access>read-only</access>
                    <resetValue>0x00000000</resetValue>
                    <resetMask>0xffffffff</resetMask>
                </register>
                <register>
                    <name>SD_RSP32</name>
                    <description>SD Card Response Register 32</description>
                    <addressOffset>0x020</addressOffset>
                    <size>32</size>
                    <access>read-write</access>
                    <resetValue>0x00000000</resetValue>
                    <resetMask>0xffffffff</resetMask>
                </register>
                <register>
                    <name>SD_RSP3</name>
                    <description>SD Card Response Register 3</description>
                    <addressOffset>0x024</addressOffset>
                    <size>32</size>
                    <access>read-only</access>
                    <resetValue>0x00000000</resetValue>
                    <resetMask>0xffffffff</resetMask>
                </register>
                <register>
                    <name>SD_RSP54</name>
                    <description>SD Card Response Register 54</description>
                    <addressOffset>0x028</addressOffset>
                    <size>32</size>
                    <access>read-write</access>
                    <resetValue>0x00000000</resetValue>
                    <resetMask>0xffffffff</resetMask>
                </register>
                <register>
                    <name>SD_RSP5</name>
                    <description>SD Card Response Register 5</description>
                    <addressOffset>0x02C</addressOffset>
                    <size>32</size>
                    <access>read-only</access>
                    <resetValue>0x00000000</resetValue>
                    <resetMask>0xffffffff</resetMask>
                </register>
                <register>
                    <name>SD_RSP76</name>
                    <description>SD Card Response Register 76</description>
                    <addressOffset>0x030</addressOffset>
                    <size>32</size>
                    <access>read-only</access>
                    <resetValue>0x00000000</resetValue>
                    <resetMask>0xffffffff</resetMask>
                    <fields>
                        <field>
                            <name>SD_RSP76</name>
                            <description>These bits store the response from the SD card/MMC.</description>
                            <lsb>0</lsb>
                            <msb>23</msb>
                            <access>read-only</access>
                        </field>
                    </fields>
                </register>
                <register>
                    <name>SD_RSP7</name>
                    <description>SD Card Response Register 7</description>
                    <addressOffset>0x034</addressOffset>
                    <size>32</size>
                    <access>read-only</access>
                    <resetValue>0x00000000</resetValue>
                    <resetMask>0xffffffff</resetMask>
                    <fields>
                        <field>
                            <name>SD_RSP7</name>
                            <description>These bits store the response from the SD card/MMC.</description>
                            <lsb>0</lsb>
                            <msb>7</msb>
                            <access>read-only</access>
                        </field>
                    </fields>
                </register>
                <register>
                    <name>SD_INFO1</name>
                    <description>SD Card Interrupt Flag Register 1</description>
                    <addressOffset>0x038</addressOffset>
                    <size>32</size>
                    <access>read-write</access>
                    <resetValue>0x00000000</resetValue>
                    <resetMask>0xfffffb5f</resetMask>
                    <fields>
                        <field>
                            <name>RSPEND</name>
                            <description>Response End Detection Flag</description>
                            <lsb>0</lsb>
                            <msb>0</msb>
                            <access>read-write</access>
                            <enumeratedValues>
                                </enumeratedValues>
                        </field>
                        <field>
                            <name>ACEND</name>
                            <description>Access End Detection Flag</description>
                            <lsb>2</lsb>
                            <msb>2</msb>
                            <access>read-write</access>
                            <enumeratedValues>
                                </enumeratedValues>
                        </field>
                        <field>
                            <name>SDCDRM</name>
                            <description>SDnCD Removal Flag</description>
                            <lsb>3</lsb>
                            <msb>3</msb>
                            <access>read-write</access>
                            <enumeratedValues>
                                </enumeratedValues>
                        </field>
                        <field>
                            <name>SDCDIN</name>
                            <description>SDnCD Insertion Flag</description>
                            <lsb>4</lsb>
                            <msb>4</msb>
                            <access>read-write</access>
                            <enumeratedValues>
                                </enumeratedValues>
                        </field>
                        <field>
                            <name>SDCDMON</name>
                            <description>SDnCD Pin Monitor Flag</description>
                            <lsb>5</lsb>
                            <msb>5</msb>
                            <access>read-only</access>
                            <enumeratedValues>
                                </enumeratedValues>
                        </field>
                        <field>
                            <name>SDWPMON</name>
                            <description>SDnWP Pin Monitor Flag</description>
                            <lsb>7</lsb>
                            <msb>7</msb>
                            <access>read-only</access>
                            <enumeratedValues>
                                </enumeratedValues>
                        </field>
                        <field>
                            <name>SDD3RM</name>
                            <description>SDnDAT3 Removal Flag</description>
                            <lsb>8</lsb>
                            <msb>8</msb>
                            <access>read-write</access>
                            <enumeratedValues>
                                </enumeratedValues>
                        </field>
                        <field>
                            <name>SDD3IN</name>
                            <description>SDnDAT3 Insertion Flag</description>
                            <lsb>9</lsb>
                            <msb>9</msb>
                            <access>read-write</access>
                            <enumeratedValues>
                                </enumeratedValues>
                        </field>
                        <field>
                            <name>SDD3MON</name>
                            <description>SDnDAT3 Pin Monitor Flag</description>
                            <lsb>10</lsb>
                            <msb>10</msb>
                            <access>read-only</access>
                            <enumeratedValues>
                                </enumeratedValues>
                        </field>
                    </fields>
                </register>
                <register>
                    <name>SD_INFO2</name>
                    <description>SD Card Interrupt Flag Register 2</description>
                    <addressOffset>0x03C</addressOffset>
                    <size>32</size>
                    <access>read-write</access>
                    <resetValue>0x00002000</resetValue>
                    <resetMask>0xfffff77f</resetMask>
                    <fields>
                        <field>
                            <name>CMDE</name>
                            <description>Command Error Detection Flag</description>
                            <lsb>0</lsb>
                            <msb>0</msb>
                            <access>read-write</access>
                            <enumeratedValues>
                                </enumeratedValues>
                        </field>
                        <field>
                            <name>CRCE</name>
                            <description>CRC Error Detection Flag</description>
                            <lsb>1</lsb>
                            <msb>1</msb>
                            <access>read-write</access>
                            <enumeratedValues>
                                </enumeratedValues>
                        </field>
                        <field>
                            <name>ENDE</name>
                            <description>End Bit Error Detection Flag</description>
                            <lsb>2</lsb>
                            <msb>2</msb>
                            <access>read-write</access>
                            <enumeratedValues>
                                </enumeratedValues>
                        </field>
                        <field>
                            <name>DTO</name>
                            <description>Data Timeout Detection Flag</description>
                            <lsb>3</lsb>
                            <msb>3</msb>
                            <access>read-write</access>
                            <enumeratedValues>
                                </enumeratedValues>
                        </field>
                        <field>
                            <name>ILW</name>
                            <description>SD_BUF0 Illegal Write Access Detection Flag</description>
                            <lsb>4</lsb>
                            <msb>4</msb>
                            <access>read-write</access>
                            <enumeratedValues>
                                </enumeratedValues>
                        </field>
                        <field>
                            <name>ILR</name>
                            <description>SD_BUF0 Illegal Read Access Detection Flag</description>
                            <lsb>5</lsb>
                            <msb>5</msb>
                            <access>read-write</access>
                            <enumeratedValues>
                                </enumeratedValues>
                        </field>
                        <field>
                            <name>RSPTO</name>
                            <description>Response Timeout Detection Flag</description>
                            <lsb>6</lsb>
                            <msb>6</msb>
                            <access>read-write</access>
                            <enumeratedValues>
                                </enumeratedValues>
                        </field>
                        <field>
                            <name>SDD0MON</name>
                            <description>SDnDAT0 Pin Status Flag</description>
                            <lsb>7</lsb>
                            <msb>7</msb>
                            <access>read-only</access>
                            <enumeratedValues>
                                </enumeratedValues>
                        </field>
                        <field>
                            <name>BRE</name>
                            <description>SD_BUF0 Read Enable Flag</description>
                            <lsb>8</lsb>
                            <msb>8</msb>
                            <access>read-write</access>
                            <enumeratedValues>
                                </enumeratedValues>
                        </field>
                        <field>
                            <name>BWE</name>
                            <description>SD_BUF0 Write Enable Flag</description>
                            <lsb>9</lsb>
                            <msb>9</msb>
                            <access>read-write</access>
                            <enumeratedValues>
                                </enumeratedValues>
                        </field>
                        <field>
                            <name>SD_CLK_CTRLEN</name>
                            <description>SD_CLK_CTRL Write Enable Flag</description>
                            <lsb>13</lsb>
                            <msb>13</msb>
                            <access>read-only</access>
                            <enumeratedValues>
                                </enumeratedValues>
                        </field>
                        <field>
                            <name>CBSY</name>
                            <description>Command Sequence Status Flag</description>
                            <lsb>14</lsb>
                            <msb>14</msb>
                            <access>read-only</access>
                            <enumeratedValues>
                                </enumeratedValues>
                        </field>
                        <field>
                            <name>ILA</name>
                            <description>Illegal Access Error Detection Flag</description>
                            <lsb>15</lsb>
                            <msb>15</msb>
                            <access>read-write</access>
                            <enumeratedValues>
                                </enumeratedValues>
                        </field>
                    </fields>
                </register>
                <register>
                    <name>SD_INFO1_MASK</name>
                    <description>SD INFO1 Interrupt Mask Register</description>
                    <addressOffset>0x040</addressOffset>
                    <size>32</size>
                    <access>read-write</access>
                    <resetValue>0x0000031d</resetValue>
                    <resetMask>0xffffffff</resetMask>
                    <fields>
                        <field>
                            <name>RSPENDM</name>
                            <description>Response End Interrupt Request Mask</description>
                            <lsb>0</lsb>
                            <msb>0</msb>
                            <access>read-write</access>
                            <enumeratedValues>
                                </enumeratedValues>
                        </field>
                        <field>
                            <name>ACENDM</name>
                            <description>Access End Interrupt Request Mask</description>
                            <lsb>2</lsb>
                            <msb>2</msb>
                            <access>read-write</access>
                            <enumeratedValues>
                                </enumeratedValues>
                        </field>
                        <field>
                            <name>SDCDRMM</name>
                            <description>SDnCD Removal Interrupt Request Mask</description>
                            <lsb>3</lsb>
                            <msb>3</msb>
                            <access>read-write</access>
                            <enumeratedValues>
                                </enumeratedValues>
                        </field>
                        <field>
                            <name>SDCDINM</name>
                            <description>SDnCD Insertion Interrupt Request Mask</description>
                            <lsb>4</lsb>
                            <msb>4</msb>
                            <access>read-write</access>
                            <enumeratedValues>
                                </enumeratedValues>
                        </field>
                        <field>
                            <name>SDD3RMM</name>
                            <description>SDnDAT3 Removal Interrupt Request Mask</description>
                            <lsb>8</lsb>
                            <msb>8</msb>
                            <access>read-write</access>
                            <enumeratedValues>
                                </enumeratedValues>
                        </field>
                        <field>
                            <name>SDD3INM</name>
                            <description>SDnDAT3 Insertion Interrupt Request Mask</description>
                            <lsb>9</lsb>
                            <msb>9</msb>
                            <access>read-write</access>
                            <enumeratedValues>
                                </enumeratedValues>
                        </field>
                    </fields>
                </register>
                <register>
                    <name>SD_INFO2_MASK</name>
                    <description>SD INFO2 Interrupt Mask Register</description>
                    <addressOffset>0x044</addressOffset>
                    <size>32</size>
                    <access>read-write</access>
                    <resetValue>0x00008b7f</resetValue>
                    <resetMask>0xffffffff</resetMask>
                    <fields>
                        <field>
                            <name>CMDEM</name>
                            <description>Command Error Interrupt Request Mask</description>
                            <lsb>0</lsb>
                            <msb>0</msb>
                            <access>read-write</access>
                            <enumeratedValues>
                                </enumeratedValues>
                        </field>
                        <field>
                            <name>CRCEM</name>
                            <description>CRC Error Interrupt Request Mask</description>
                            <lsb>1</lsb>
                            <msb>1</msb>
                            <access>read-write</access>
                            <enumeratedValues>
                                </enumeratedValues>
                        </field>
                        <field>
                            <name>ENDEM</name>
                            <description>End Bit Error Interrupt Request Mask</description>
                            <lsb>2</lsb>
                            <msb>2</msb>
                            <access>read-write</access>
                            <enumeratedValues>
                                </enumeratedValues>
                        </field>
                        <field>
                            <name>DTOM</name>
                            <description>Data Timeout Interrupt Request Mask</description>
                            <lsb>3</lsb>
                            <msb>3</msb>
                            <access>read-write</access>
                            <enumeratedValues>
                                </enumeratedValues>
                        </field>
                        <field>
                            <name>ILWM</name>
                            <description>SD_BUF0 Register Illegal Write Interrupt Request Mask</description>
                            <lsb>4</lsb>
                            <msb>4</msb>
                            <access>read-write</access>
                            <enumeratedValues>
                                </enumeratedValues>
                        </field>
                        <field>
                            <name>ILRM</name>
                            <description>SD_BUF0 Register Illegal Read Interrupt Request Mask</description>
                            <lsb>5</lsb>
                            <msb>5</msb>
                            <access>read-write</access>
                            <enumeratedValues>
                                </enumeratedValues>
                        </field>
                        <field>
                            <name>RSPTOM</name>
                            <description>Response Timeout Interrupt Request Mask</description>
                            <lsb>6</lsb>
                            <msb>6</msb>
                            <access>read-write</access>
                            <enumeratedValues>
                                </enumeratedValues>
                        </field>
                        <field>
                            <name>BREM</name>
                            <description>BRE Interrupt Request Mask</description>
                            <lsb>8</lsb>
                            <msb>8</msb>
                            <access>read-write</access>
                            <enumeratedValues>
                                </enumeratedValues>
                        </field>
                        <field>
                            <name>BWEM</name>
                            <description>BWE Interrupt Request Mask</description>
                            <lsb>9</lsb>
                            <msb>9</msb>
                            <access>read-write</access>
                            <enumeratedValues>
                                </enumeratedValues>
                        </field>
                        <field>
                            <name>ILAM</name>
                            <description>Illegal Access Error Interrupt Request Mask</description>
                            <lsb>15</lsb>
                            <msb>15</msb>
                            <access>read-write</access>
                            <enumeratedValues>
                                </enumeratedValues>
                        </field>
                    </fields>
                </register>
                <register>
                    <name>SD_CLK_CTRL</name>
                    <description>SD Clock Control Register</description>
                    <addressOffset>0x048</addressOffset>
                    <size>32</size>
                    <access>read-write</access>
                    <resetValue>0x00000020</resetValue>
                    <resetMask>0xffffffff</resetMask>
                    <fields>
                        <field>
                            <name>CLKSEL</name>
                            <description>SDHI Clock Frequency Select</description>
                            <lsb>0</lsb>
                            <msb>7</msb>
                            <access>read-write</access>
                            <enumeratedValues>
                                </enumeratedValues>
                        </field>
                        <field>
                            <name>CLKEN</name>
                            <description>SD/MMC Clock Output Control</description>
                            <lsb>8</lsb>
                            <msb>8</msb>
                            <access>read-write</access>
                            <enumeratedValues>
                                </enumeratedValues>
                        </field>
                        <field>
                            <name>CLKCTRLEN</name>
                            <description>SD/MMC Clock Output Automatic Control Select</description>
                            <lsb>9</lsb>
                            <msb>9</msb>
                            <access>read-write</access>
                            <enumeratedValues>
                                </enumeratedValues>
                        </field>
                    </fields>
                </register>
                <register>
                    <name>SD_SIZE</name>
                    <description>Transfer Data Length Register</description>
                    <addressOffset>0x04C</addressOffset>
                    <size>32</size>
                    <access>read-write</access>
                    <resetValue>0x00000200</resetValue>
                    <resetMask>0xffffffff</resetMask>
                    <fields>
                        <field>
                            <name>LEN</name>
                            <description>Transfer Data Size Setting</description>
                            <lsb>0</lsb>
                            <msb>9</msb>
                            <access>read-write</access>
                        </field>
                    </fields>
                </register>
                <register>
                    <name>SD_OPTION</name>
                    <description>SD Card Access Control Option Register</description>
                    <addressOffset>0x050</addressOffset>
                    <size>32</size>
                    <access>read-write</access>
                    <resetValue>0x000040ee</resetValue>
                    <resetMask>0xffffffff</resetMask>
                    <fields>
                        <field>
                            <name>CTOP</name>
                            <description>Card Detection Time Counter</description>
                            <lsb>0</lsb>
                            <msb>3</msb>
                            <access>read-write</access>
                            <enumeratedValues>
                                </enumeratedValues>
                        </field>
                        <field>
                            <name>TOP</name>
                            <description>Timeout Counter</description>
                            <lsb>4</lsb>
                            <msb>7</msb>
                            <access>read-write</access>
                            <enumeratedValues>
                                </enumeratedValues>
                        </field>
                        <field>
                            <name>TOUTMASK</name>
                            <description>Timeout Mask</description>
                            <lsb>8</lsb>
                            <msb>8</msb>
                            <access>read-write</access>
                            <enumeratedValues>
                                </enumeratedValues>
                        </field>
                        <field>
                            <name>WIDTH8</name>
                            <description>Bus Width</description>
                            <lsb>13</lsb>
                            <msb>13</msb>
                            <access>read-write</access>
                        </field>
                        <field>
                            <name>WIDTH</name>
                            <description>Bus Width</description>
                            <lsb>15</lsb>
                            <msb>15</msb>
                            <access>read-write</access>
                        </field>
                    </fields>
                </register>
                <register>
                    <name>SD_ERR_STS1</name>
                    <description>SD Error Status Register 1</description>
                    <addressOffset>0x058</addressOffset>
                    <size>32</size>
                    <access>read-only</access>
                    <resetValue>0x00002000</resetValue>
                    <resetMask>0x0000ffff</resetMask>
                    <fields>
                        <field>
                            <name>CMDE0</name>
                            <description>Command Error Flag 0</description>
                            <lsb>0</lsb>
                            <msb>0</msb>
                            <access>read-only</access>
                            <enumeratedValues>
                                </enumeratedValues>
                        </field>
                        <field>
                            <name>CMDE1</name>
                            <description>Command Error Flag 1</description>
                            <lsb>1</lsb>
                            <msb>1</msb>
                            <access>read-only</access>
                            <enumeratedValues>
                                </enumeratedValues>
                        </field>
                        <field>
                            <name>RSPLENE0</name>
                            <description>Response Length Error Flag 0</description>
                            <lsb>2</lsb>
                            <msb>2</msb>
                            <access>read-only</access>
                            <enumeratedValues>
                                </enumeratedValues>
                        </field>
                        <field>
                            <name>RSPLENE1</name>
                            <description>Response Length Error Flag 1</description>
                            <lsb>3</lsb>
                            <msb>3</msb>
                            <access>read-only</access>
                            <enumeratedValues>
                                </enumeratedValues>
                        </field>
                        <field>
                            <name>RDLENE</name>
                            <description>Read Data Length Error Flag</description>
                            <lsb>4</lsb>
                            <msb>4</msb>
                            <access>read-only</access>
                            <enumeratedValues>
                                </enumeratedValues>
                        </field>
                        <field>
                            <name>CRCLENE</name>
                            <description>CRC Status Token Length Error Flag</description>
                            <lsb>5</lsb>
                            <msb>5</msb>
                            <access>read-only</access>
                            <enumeratedValues>
                                </enumeratedValues>
                        </field>
                        <field>
                            <name>RSPCRCE0</name>
                            <description>Response CRC Error Flag 0</description>
                            <lsb>8</lsb>
                            <msb>8</msb>
                            <access>read-only</access>
                            <enumeratedValues>
                                </enumeratedValues>
                        </field>
                        <field>
                            <name>RSPCRCE1</name>
                            <description>Response CRC Error Flag 1</description>
                            <lsb>9</lsb>
                            <msb>9</msb>
                            <access>read-only</access>
                            <enumeratedValues>
                                </enumeratedValues>
                        </field>
                        <field>
                            <name>RDCRCE</name>
                            <description>Read Data CRC Error Flag</description>
                            <lsb>10</lsb>
                            <msb>10</msb>
                            <access>read-only</access>
                            <enumeratedValues>
                                </enumeratedValues>
                        </field>
                        <field>
                            <name>CRCTKE</name>
                            <description>CRC Status Token Error Flag</description>
                            <lsb>11</lsb>
                            <msb>11</msb>
                            <access>read-only</access>
                            <enumeratedValues>
                                </enumeratedValues>
                        </field>
                        <field>
                            <name>CRCTK</name>
                            <description>CRC Status Token</description>
                            <lsb>12</lsb>
                            <msb>14</msb>
                            <access>read-only</access>
                        </field>
                    </fields>
                </register>
                <register>
                    <name>SD_ERR_STS2</name>
                    <description>SD Error Status Register 2</description>
                    <addressOffset>0x05C</addressOffset>
                    <size>32</size>
                    <access>read-only</access>
                    <resetValue>0x00000000</resetValue>
                    <resetMask>0xffffffff</resetMask>
                    <fields>
                        <field>
                            <name>RSPTO0</name>
                            <description>Response Timeout Flag 0</description>
                            <lsb>0</lsb>
                            <msb>0</msb>
                            <access>read-only</access>
                            <enumeratedValues>
                                </enumeratedValues>
                        </field>
                        <field>
                            <name>RSPTO1</name>
                            <description>Response Timeout Flag 1</description>
                            <lsb>1</lsb>
                            <msb>1</msb>
                            <access>read-only</access>
                            <enumeratedValues>
                                </enumeratedValues>
                        </field>
                        <field>
                            <name>BSYTO0</name>
                            <description>Busy Timeout Flag 0</description>
                            <lsb>2</lsb>
                            <msb>2</msb>
                            <access>read-only</access>
                            <enumeratedValues>
                                </enumeratedValues>
                        </field>
                        <field>
                            <name>BSYTO1</name>
                            <description>Busy Timeout Flag 1</description>
                            <lsb>3</lsb>
                            <msb>3</msb>
                            <access>read-only</access>
                            <enumeratedValues>
                                </enumeratedValues>
                        </field>
                        <field>
                            <name>RDTO</name>
                            <description>Read Data Timeout Flag</description>
                            <lsb>4</lsb>
                            <msb>4</msb>
                            <access>read-only</access>
                        </field>
                        <field>
                            <name>CRCTO</name>
                            <description>CRC Status Token Timeout Flag</description>
                            <lsb>5</lsb>
                            <msb>5</msb>
                            <access>read-only</access>
                            <enumeratedValues>
                                </enumeratedValues>
                        </field>
                        <field>
                            <name>CRCBSYTO</name>
                            <description>CRC Status Token Busy Timeout Flag</description>
                            <lsb>6</lsb>
                            <msb>6</msb>
                            <access>read-only</access>
                            <enumeratedValues>
                                </enumeratedValues>
                        </field>
                    </fields>
                </register>
                <register>
                    <name>SD_BUF0</name>
                    <description>SD Buffer Register</description>
                    <addressOffset>0x060</addressOffset>
                    <size>32</size>
                    <access>read-write</access>
                    <resetValue>0x00000000</resetValue>
                    <resetMask>0x00000000</resetMask>
                </register>
                <register>
                    <name>SDIO_MODE</name>
                    <description>SDIO Mode Control Register</description>
                    <addressOffset>0x068</addressOffset>
                    <size>32</size>
                    <access>read-write</access>
                    <resetValue>0x00000000</resetValue>
                    <resetMask>0xffffffff</resetMask>
                    <fields>
                        <field>
                            <name>INTEN</name>
                            <description>SDIO Interrupt Acceptance Enable</description>
                            <lsb>0</lsb>
                            <msb>0</msb>
                            <access>read-write</access>
                            <enumeratedValues>
                                </enumeratedValues>
                        </field>
                        <field>
                            <name>RWREQ</name>
                            <description>Read Wait Request</description>
                            <lsb>2</lsb>
                            <msb>2</msb>
                            <access>read-write</access>
                            <enumeratedValues>
                                </enumeratedValues>
                        </field>
                        <field>
                            <name>IOABT</name>
                            <description>SDIO Abort</description>
                            <lsb>8</lsb>
                            <msb>8</msb>
                            <access>read-write</access>
                        </field>
                        <field>
                            <name>C52PUB</name>
                            <description>SDIO None Abort</description>
                            <lsb>9</lsb>
                            <msb>9</msb>
                            <access>read-write</access>
                        </field>
                    </fields>
                </register>
                <register>
                    <name>SDIO_INFO1</name>
                    <description>SDIO Interrupt Flag Register</description>
                    <addressOffset>0x06C</addressOffset>
                    <size>32</size>
                    <access>read-write</access>
                    <resetValue>0x00000000</resetValue>
                    <resetMask>0xfffffff9</resetMask>
                    <fields>
                        <field>
                            <name>IOIRQ</name>
                            <description>SDIO Interrupt Status Flag</description>
                            <lsb>0</lsb>
                            <msb>0</msb>
                            <access>read-write</access>
                            <enumeratedValues>
                                </enumeratedValues>
                        </field>
                        <field>
                            <name>EXPUB52</name>
                            <description>EXPUB52 Status Flag</description>
                            <lsb>14</lsb>
                            <msb>14</msb>
                            <access>read-write</access>
                        </field>
                        <field>
                            <name>EXWT</name>
                            <description>EXWT Status Flag</description>
                            <lsb>15</lsb>
                            <msb>15</msb>
                            <access>read-write</access>
                        </field>
                    </fields>
                </register>
                <register>
                    <name>SDIO_INFO1_MASK</name>
                    <description>SDIO INFO1 Interrupt Mask Register</description>
                    <addressOffset>0x070</addressOffset>
                    <size>32</size>
                    <access>read-write</access>
                    <resetValue>0x0000c007</resetValue>
                    <resetMask>0xffffffff</resetMask>
                    <fields>
                        <field>
                            <name>IOIRQM</name>
                            <description>IOIRQ Interrupt Mask Control</description>
                            <lsb>0</lsb>
                            <msb>0</msb>
                            <access>read-write</access>
                            <enumeratedValues>
                                </enumeratedValues>
                        </field>
                        <field>
                            <name>EXPUB52M</name>
                            <description>EXPUB52 Interrupt Request Mask Control</description>
                            <lsb>14</lsb>
                            <msb>14</msb>
                            <access>read-write</access>
                            <enumeratedValues>
                                </enumeratedValues>
                        </field>
                        <field>
                            <name>EXWTM</name>
                            <description>EXWT Interrupt Request Mask Control</description>
                            <lsb>15</lsb>
                            <msb>15</msb>
                            <access>read-write</access>
                            <enumeratedValues>
                                </enumeratedValues>
                        </field>
                    </fields>
                </register>
                <register>
                    <name>SD_DMAEN</name>
                    <description>DMA Mode Enable Register</description>
                    <addressOffset>0x1B0</addressOffset>
                    <size>32</size>
                    <access>read-write</access>
                    <resetValue>0x00001010</resetValue>
                    <resetMask>0xffffffff</resetMask>
                    <fields>
                        <field>
                            <name>DMAEN</name>
                            <description>DMA Transfer Enable</description>
                            <lsb>1</lsb>
                            <msb>1</msb>
                            <access>read-write</access>
                            <enumeratedValues>
                                </enumeratedValues>
                        </field>
                    </fields>
                </register>
                <register>
                    <name>SOFT_RST</name>
                    <description>Software Reset Register</description>
                    <addressOffset>0x1C0</addressOffset>
                    <size>32</size>
                    <access>read-write</access>
                    <resetValue>0x00000007</resetValue>
                    <resetMask>0xffffffff</resetMask>
                    <fields>
                        <field>
                            <name>SDRST</name>
                            <description>Software Reset Control</description>
                            <lsb>0</lsb>
                            <msb>0</msb>
                            <access>read-write</access>
                            <enumeratedValues>
                                </enumeratedValues>
                        </field>
                    </fields>
                </register>
                <register>
                    <name>SDIF_MODE</name>
                    <description>SD Interface Mode Setting Register</description>
                    <addressOffset>0x1CC</addressOffset>
                    <size>32</size>
                    <access>read-write</access>
                    <resetValue>0x00000000</resetValue>
                    <resetMask>0xffffffff</resetMask>
                    <fields>
                        <field>
                            <name>NOCHKCR</name>
                            <description>CRC Check Mask</description>
                            <lsb>8</lsb>
                            <msb>8</msb>
                            <access>read-write</access>
                            <enumeratedValues>
                                </enumeratedValues>
                        </field>
                    </fields>
                </register>
                <register>
                    <name>EXT_SWAP</name>
                    <description>Swap Control Register</description>
                    <addressOffset>0x1E0</addressOffset>
                    <size>32</size>
                    <access>read-write</access>
                    <resetValue>0x00000000</resetValue>
                    <resetMask>0xffffffff</resetMask>
                    <fields>
                        <field>
                            <name>BWSWP</name>
                            <description>SD_BUF0 Swap Write</description>
                            <lsb>6</lsb>
                            <msb>6</msb>
                            <access>read-write</access>
                            <enumeratedValues>
                                </enumeratedValues>
                        </field>
                        <field>
                            <name>BRSWP</name>
                            <description>SD_BUF0 Swap Read</description>
                            <lsb>7</lsb>
                            <msb>7</msb>
                            <access>read-write</access>
                            <enumeratedValues>
                                </enumeratedValues>
                        </field>
                    </fields>
                </register>
            </registers>
        </peripheral>
        <peripheral>
            <name>SSIE0</name>
            <description>Serial Sound Interface Enhanced (SSIE)</description>
            <baseAddress>0x4009D000</baseAddress>
            <addressBlock>
                <offset>0x00</offset>
                <size>8</size>
                <usage>registers</usage>
            </addressBlock>
            <addressBlock>
                <offset>0x10</offset>
                <size>24</size>
                <usage>registers</usage>
            </addressBlock>
            <registers>
                <register>
                    <name>SSICR</name>
                    <description>Control Register</description>
                    <addressOffset>0x00</addressOffset>
                    <size>32</size>
                    <access>read-write</access>
                    <resetValue>0x00000000</resetValue>
                    <resetMask>0xffffffff</resetMask>
                    <fields>
                        <field>
                            <name>REN</name>
                            <description>Reception Enable</description>
                            <lsb>0</lsb>
                            <msb>0</msb>
                            <access>read-write</access>
                            <enumeratedValues>
                                </enumeratedValues>
                        </field>
                        <field>
                            <name>TEN</name>
                            <description>Transmission Enable</description>
                            <lsb>1</lsb>
                            <msb>1</msb>
                            <access>read-write</access>
                            <enumeratedValues>
                                </enumeratedValues>
                        </field>
                        <field>
                            <name>MUEN</name>
                            <description>Mute Enable</description>
                            <lsb>3</lsb>
                            <msb>3</msb>
                            <access>read-write</access>
                            <enumeratedValues>
                                </enumeratedValues>
                        </field>
                        <field>
                            <name>CKDV</name>
                            <description>Selects Bit Clock Division Ratio</description>
                            <lsb>4</lsb>
                            <msb>7</msb>
                            <access>read-write</access>
                            <enumeratedValues>
                                </enumeratedValues>
                        </field>
                        <field>
                            <name>DEL</name>
                            <description>Selects Serial Data Delay</description>
                            <lsb>8</lsb>
                            <msb>8</msb>
                            <access>read-write</access>
                            <enumeratedValues>
                                </enumeratedValues>
                        </field>
                        <field>
                            <name>PDTA</name>
                            <description>Selects Placement Data Alignment</description>
                            <lsb>9</lsb>
                            <msb>9</msb>
                            <access>read-write</access>
                            <enumeratedValues>
                                </enumeratedValues>
                        </field>
                        <field>
                            <name>SDTA</name>
                            <description>Selects Serial Data Alignment</description>
                            <lsb>10</lsb>
                            <msb>10</msb>
                            <access>read-write</access>
                            <enumeratedValues>
                                </enumeratedValues>
                        </field>
                        <field>
                            <name>SPDP</name>
                            <description>Selects Serial Padding Polarity</description>
                            <lsb>11</lsb>
                            <msb>11</msb>
                            <access>read-write</access>
                            <enumeratedValues>
                                </enumeratedValues>
                        </field>
                        <field>
                            <name>LRCKP</name>
                            <description>Selects the Initial Value and Polarity of LR Clock/Frame Synchronization Signal</description>
                            <lsb>12</lsb>
                            <msb>12</msb>
                            <access>read-write</access>
                            <enumeratedValues>
                                </enumeratedValues>
                        </field>
                        <field>
                            <name>BCKP</name>
                            <description>Selects Bit Clock Polarity</description>
                            <lsb>13</lsb>
                            <msb>13</msb>
                            <access>read-write</access>
                            <enumeratedValues>
                                </enumeratedValues>
                        </field>
                        <field>
                            <name>MST</name>
                            <description>Master Enable</description>
                            <lsb>14</lsb>
                            <msb>14</msb>
                            <access>read-write</access>
                            <enumeratedValues>
                                </enumeratedValues>
                        </field>
                        <field>
                            <name>SWL</name>
                            <description>Selects System Word Length</description>
                            <lsb>16</lsb>
                            <msb>18</msb>
                            <access>read-write</access>
                            <enumeratedValues>
                                </enumeratedValues>
                        </field>
                        <field>
                            <name>DWL</name>
                            <description>Selects Data Word Length</description>
                            <lsb>19</lsb>
                            <msb>21</msb>
                            <access>read-write</access>
                            <enumeratedValues>
                                </enumeratedValues>
                        </field>
                        <field>
                            <name>FRM</name>
                            <description>Selects Frame Word Number</description>
                            <lsb>22</lsb>
                            <msb>23</msb>
                            <access>read-write</access>
                        </field>
                        <field>
                            <name>IIEN</name>
                            <description>Idle Mode Interrupt Output Enable</description>
                            <lsb>25</lsb>
                            <msb>25</msb>
                            <access>read-write</access>
                            <enumeratedValues>
                                </enumeratedValues>
                        </field>
                        <field>
                            <name>ROIEN</name>
                            <description>Receive Overflow Interrupt Output Enable</description>
                            <lsb>26</lsb>
                            <msb>26</msb>
                            <access>read-write</access>
                            <enumeratedValues>
                                </enumeratedValues>
                        </field>
                        <field>
                            <name>RUIEN</name>
                            <description>Receive Underflow Interrupt Output Enable</description>
                            <lsb>27</lsb>
                            <msb>27</msb>
                            <access>read-write</access>
                            <enumeratedValues>
                                </enumeratedValues>
                        </field>
                        <field>
                            <name>TOIEN</name>
                            <description>Transmit Overflow Interrupt Output Enable</description>
                            <lsb>28</lsb>
                            <msb>28</msb>
                            <access>read-write</access>
                            <enumeratedValues>
                                </enumeratedValues>
                        </field>
                        <field>
                            <name>TUIEN</name>
                            <description>Transmit Underflow Interrupt Output Enable</description>
                            <lsb>29</lsb>
                            <msb>29</msb>
                            <access>read-write</access>
                            <enumeratedValues>
                                </enumeratedValues>
                        </field>
                        <field>
                            <name>CKS</name>
                            <description>Selects an Audio Clock for Master,mode Communication</description>
                            <lsb>30</lsb>
                            <msb>30</msb>
                            <access>read-write</access>
                            <enumeratedValues>
                                </enumeratedValues>
                        </field>
                    </fields>
                </register>
                <register>
                    <name>SSISR</name>
                    <description>Status Register</description>
                    <addressOffset>0x04</addressOffset>
                    <size>32</size>
                    <access>read-write</access>
                    <resetValue>0x02000000</resetValue>
                    <resetMask>0xffffffff</resetMask>
                    <fields>
                        <field>
                            <name>IIRQ</name>
                            <description>Idle Mode Status Flag</description>
                            <lsb>25</lsb>
                            <msb>25</msb>
                            <access>read-only</access>
                            <enumeratedValues>
                                </enumeratedValues>
                        </field>
                        <field>
                            <name>ROIRQ</name>
                            <description>Receive Overflow Error Status Flag</description>
                            <lsb>26</lsb>
                            <msb>26</msb>
                            <access>read-write</access>
                            <enumeratedValues>
                                </enumeratedValues>
                        </field>
                        <field>
                            <name>RUIRQ</name>
                            <description>Receive Underflow Error Status Flag</description>
                            <lsb>27</lsb>
                            <msb>27</msb>
                            <access>read-write</access>
                            <enumeratedValues>
                                </enumeratedValues>
                        </field>
                        <field>
                            <name>TOIRQ</name>
                            <description>Transmit Overflow Error Status Flag</description>
                            <lsb>28</lsb>
                            <msb>28</msb>
                            <access>read-write</access>
                            <enumeratedValues>
                                </enumeratedValues>
                        </field>
                        <field>
                            <name>TUIRQ</name>
                            <description>Transmit Underflow Error Status flag</description>
                            <lsb>29</lsb>
                            <msb>29</msb>
                            <access>read-write</access>
                            <enumeratedValues>
                                </enumeratedValues>
                        </field>
                    </fields>
                </register>
                <register>
                    <name>SSIFCR</name>
                    <description>FIFO Control Register</description>
                    <addressOffset>0x10</addressOffset>
                    <size>32</size>
                    <access>read-write</access>
                    <resetValue>0x00000000</resetValue>
                    <resetMask>0xffffffff</resetMask>
                    <fields>
                        <field>
                            <name>RFRST</name>
                            <description>Receive FIFO Data Register Reset</description>
                            <lsb>0</lsb>
                            <msb>0</msb>
                            <access>read-write</access>
                            <enumeratedValues>
                                </enumeratedValues>
                        </field>
                        <field>
                            <name>TFRST</name>
                            <description>Transmit FIFO Data Register Reset</description>
                            <lsb>1</lsb>
                            <msb>1</msb>
                            <access>read-write</access>
                            <enumeratedValues>
                                </enumeratedValues>
                        </field>
                        <field>
                            <name>RIE</name>
                            <description>Receive Data Full Interrupt Output Enable</description>
                            <lsb>2</lsb>
                            <msb>2</msb>
                            <access>read-write</access>
                            <enumeratedValues>
                                </enumeratedValues>
                        </field>
                        <field>
                            <name>TIE</name>
                            <description>Transmit Data Empty Interrupt Output Enable</description>
                            <lsb>3</lsb>
                            <msb>3</msb>
                            <access>read-write</access>
                            <enumeratedValues>
                                </enumeratedValues>
                        </field>
                        <field>
                            <name>BSW</name>
                            <description>Byte Swap Enable</description>
                            <lsb>11</lsb>
                            <msb>11</msb>
                            <access>read-write</access>
                            <enumeratedValues>
                                </enumeratedValues>
                        </field>
                        <field>
                            <name>SSIRST</name>
                            <description>Software Reset</description>
                            <lsb>16</lsb>
                            <msb>16</msb>
                            <access>read-write</access>
                            <enumeratedValues>
                                </enumeratedValues>
                        </field>
                        <field>
                            <name>AUCKE</name>
                            <description>AUDIO_MCK Enable in Master,mode Communication</description>
                            <lsb>31</lsb>
                            <msb>31</msb>
                            <access>read-write</access>
                            <enumeratedValues>
                                </enumeratedValues>
                        </field>
                    </fields>
                </register>
                <register>
                    <name>SSIFSR</name>
                    <description>FIFO Status Register</description>
                    <addressOffset>0x14</addressOffset>
                    <size>32</size>
                    <access>read-write</access>
                    <resetValue>0x00010000</resetValue>
                    <resetMask>0xffffffff</resetMask>
                    <fields>
                        <field>
                            <name>RDF</name>
                            <description>Receive Data Full Flag</description>
                            <lsb>0</lsb>
                            <msb>0</msb>
                            <access>read-write</access>
                            <enumeratedValues>
                                </enumeratedValues>
                        </field>
                        <field>
                            <name>RDC</name>
                            <description>Receive Data Count</description>
                            <lsb>8</lsb>
                            <msb>13</msb>
                            <access>read-only</access>
                        </field>
                        <field>
                            <name>TDE</name>
                            <description>Transmit Data Empty Flag</description>
                            <lsb>16</lsb>
                            <msb>16</msb>
                            <access>read-write</access>
                            <enumeratedValues>
                                </enumeratedValues>
                        </field>
                        <field>
                            <name>TDC</name>
                            <description>Transmit Data Count</description>
                            <lsb>24</lsb>
                            <msb>29</msb>
                            <access>read-only</access>
                        </field>
                    </fields>
                </register>
                <register>
                    <name>SSIFTDR</name>
                    <description>Transmit FIFO Data Register</description>
                    <addressOffset>0x18</addressOffset>
                    <size>32</size>
                    <access>write-only</access>
                    <resetValue>0x00000000</resetValue>
                    <resetMask>0xffffffff</resetMask>
                    <fields>
                        <field>
                            <name>SSIFTDR</name>
                            <description>Transmit FIFO Data</description>
                            <lsb>0</lsb>
                            <msb>31</msb>
                            <access>write-only</access>
                        </field>
                    </fields>
                </register>
                <register>
                    <name>SSIFRDR</name>
                    <description>Receive FIFO Data Register</description>
                    <addressOffset>0x1C</addressOffset>
                    <size>32</size>
                    <access>read-only</access>
                    <resetValue>0x00000000</resetValue>
                    <resetMask>0xffffffff</resetMask>
                    <fields>
                        <field>
                            <name>SSIFRDR</name>
                            <description>Receive FIFO Data</description>
                            <lsb>0</lsb>
                            <msb>31</msb>
                            <access>read-only</access>
                        </field>
                    </fields>
                </register>
                <register>
                    <name>SSIOFR</name>
                    <description>Audio Format Register</description>
                    <addressOffset>0x20</addressOffset>
                    <size>32</size>
                    <access>read-write</access>
                    <resetValue>0x00000000</resetValue>
                    <resetMask>0xffffffff</resetMask>
                    <fields>
                        <field>
                            <name>OMOD</name>
                            <description>Audio Format Select</description>
                            <lsb>0</lsb>
                            <msb>1</msb>
                            <access>read-write</access>
                            <enumeratedValues>
                                </enumeratedValues>
                        </field>
                        <field>
                            <name>LRCONT</name>
                            <description>Whether to Enable LRCK/FS Continuation</description>
                            <lsb>8</lsb>
                            <msb>8</msb>
                            <access>read-write</access>
                            <enumeratedValues>
                                </enumeratedValues>
                        </field>
                        <field>
                            <name>BCKASTP</name>
                            <description>Whether to Enable Stopping BCK Output When SSIE is in Idle Status</description>
                            <lsb>9</lsb>
                            <msb>9</msb>
                            <access>read-write</access>
                            <enumeratedValues>
                                </enumeratedValues>
                        </field>
                    </fields>
                </register>
                <register>
                    <name>SSISCR</name>
                    <description>Status Control Register</description>
                    <addressOffset>0x24</addressOffset>
                    <size>32</size>
                    <access>read-write</access>
                    <resetValue>0x00000000</resetValue>
                    <resetMask>0xffffffff</resetMask>
                    <fields>
                        <field>
                            <name>RDFS</name>
                            <description>RDF Setting Condition Select</description>
                            <lsb>0</lsb>
                            <msb>4</msb>
                            <access>read-write</access>
                        </field>
                        <field>
                            <name>TDES</name>
                            <description>TDE Setting Condition Select</description>
                            <lsb>8</lsb>
                            <msb>12</msb>
                            <access>read-write</access>
                        </field>
                    </fields>
                </register>
            </registers>
        </peripheral>
        <peripheral>
            <name>IIC0</name>
            <description>Inter,Integrated Circuit 0</description>
            <baseAddress>0x4009F000</baseAddress>
            <addressBlock>
                <offset>0x00</offset>
                <size>20</size>
                <usage>registers</usage>
            </addressBlock>
            <registers>
                <register>
                    <name>ICCR1</name>
                    <description>I2C Bus Control Register 1</description>
                    <addressOffset>0x00</addressOffset>
                    <size>8</size>
                    <access>read-write</access>
                    <resetValue>0x1f</resetValue>
                    <resetMask>0xff</resetMask>
                    <fields>
                        <field>
                            <name>SDAI</name>
                            <description>SDA Line Monitor</description>
                            <lsb>0</lsb>
                            <msb>0</msb>
                            <access>read-only</access>
                            <enumeratedValues>
                                </enumeratedValues>
                        </field>
                        <field>
                            <name>SCLI</name>
                            <description>SCL Line Monitor</description>
                            <lsb>1</lsb>
                            <msb>1</msb>
                            <access>read-only</access>
                            <enumeratedValues>
                                </enumeratedValues>
                        </field>
                        <field>
                            <name>SDAO</name>
                            <description>SDA Output Control/Monitor</description>
                            <lsb>2</lsb>
                            <msb>2</msb>
                            <access>read-write</access>
                            <enumeratedValues>
                                </enumeratedValues>
                        </field>
                        <field>
                            <name>SCLO</name>
                            <description>SCL Output Control/Monitor</description>
                            <lsb>3</lsb>
                            <msb>3</msb>
                            <access>read-write</access>
                            <enumeratedValues>
                                </enumeratedValues>
                        </field>
                        <field>
                            <name>SOWP</name>
                            <description>SCLO/SDAO Write Protect</description>
                            <lsb>4</lsb>
                            <msb>4</msb>
                            <access>write-only</access>
                            <enumeratedValues>
                                </enumeratedValues>
                        </field>
                        <field>
                            <name>CLO</name>
                            <description>Extra SCL Clock Cycle Output</description>
                            <lsb>5</lsb>
                            <msb>5</msb>
                            <access>read-write</access>
                            <enumeratedValues>
                                </enumeratedValues>
                        </field>
                        <field>
                            <name>IICRST</name>
                            <description>I2C Bus Interface Internal Reset</description>
                            <lsb>6</lsb>
                            <msb>6</msb>
                            <access>read-write</access>
                            <enumeratedValues>
                                </enumeratedValues>
                        </field>
                        <field>
                            <name>ICE</name>
                            <description>I2C Bus Interface Enable</description>
                            <lsb>7</lsb>
                            <msb>7</msb>
                            <access>read-write</access>
                            <enumeratedValues>
                                </enumeratedValues>
                        </field>
                    </fields>
                </register>
                <register>
                    <name>ICCR2</name>
                    <description>I2C Bus Control Register 2</description>
                    <addressOffset>0x01</addressOffset>
                    <size>8</size>
                    <access>read-write</access>
                    <resetValue>0x00</resetValue>
                    <resetMask>0xff</resetMask>
                    <fields>
                        <field>
                            <name>ST</name>
                            <description>Start Condition Issuance Request</description>
                            <lsb>1</lsb>
                            <msb>1</msb>
                            <access>read-write</access>
                            <enumeratedValues>
                                </enumeratedValues>
                        </field>
                        <field>
                            <name>RS</name>
                            <description>Restart Condition Issuance Request</description>
                            <lsb>2</lsb>
                            <msb>2</msb>
                            <access>read-write</access>
                            <enumeratedValues>
                                </enumeratedValues>
                        </field>
                        <field>
                            <name>SP</name>
                            <description>Stop Condition Issuance Request</description>
                            <lsb>3</lsb>
                            <msb>3</msb>
                            <access>read-write</access>
                            <enumeratedValues>
                                </enumeratedValues>
                        </field>
                        <field>
                            <name>TRS</name>
                            <description>Transmit/Receive Mode</description>
                            <lsb>5</lsb>
                            <msb>5</msb>
                            <access>read-write</access>
                            <enumeratedValues>
                                </enumeratedValues>
                        </field>
                        <field>
                            <name>MST</name>
                            <description>Master/Slave Mode</description>
                            <lsb>6</lsb>
                            <msb>6</msb>
                            <access>read-write</access>
                            <enumeratedValues>
                                </enumeratedValues>
                        </field>
                        <field>
                            <name>BBSY</name>
                            <description>Bus Busy Detection Flag</description>
                            <lsb>7</lsb>
                            <msb>7</msb>
                            <access>read-only</access>
                            <enumeratedValues>
                                </enumeratedValues>
                        </field>
                    </fields>
                </register>
                <register>
                    <name>ICMR1</name>
                    <description>I2C Bus Mode Register 1</description>
                    <addressOffset>0x02</addressOffset>
                    <size>8</size>
                    <access>read-write</access>
                    <resetValue>0x08</resetValue>
                    <resetMask>0xff</resetMask>
                    <fields>
                        <field>
                            <name>BC</name>
                            <description>Bit Counter</description>
                            <lsb>0</lsb>
                            <msb>2</msb>
                            <access>read-write</access>
                            <enumeratedValues>
                                </enumeratedValues>
                        </field>
                        <field>
                            <name>BCWP</name>
                            <description>BC Write Protect</description>
                            <lsb>3</lsb>
                            <msb>3</msb>
                            <access>write-only</access>
                            <enumeratedValues>
                                </enumeratedValues>
                        </field>
                        <field>
                            <name>CKS</name>
                            <description>Internal Reference Clock Select</description>
                            <lsb>4</lsb>
                            <msb>6</msb>
                            <access>read-write</access>
                        </field>
                        <field>
                            <name>MTWP</name>
                            <description>MST/TRS Write Protect</description>
                            <lsb>7</lsb>
                            <msb>7</msb>
                            <access>read-write</access>
                            <enumeratedValues>
                                </enumeratedValues>
                        </field>
                    </fields>
                </register>
                <register>
                    <name>ICMR2</name>
                    <description>I2C Bus Mode Register 2</description>
                    <addressOffset>0x03</addressOffset>
                    <size>8</size>
                    <access>read-write</access>
                    <resetValue>0x06</resetValue>
                    <resetMask>0xff</resetMask>
                    <fields>
                        <field>
                            <name>TMOS</name>
                            <description>Timeout Detection Time Select</description>
                            <lsb>0</lsb>
                            <msb>0</msb>
                            <access>read-write</access>
                            <enumeratedValues>
                                </enumeratedValues>
                        </field>
                        <field>
                            <name>TMOL</name>
                            <description>Timeout L Count Control</description>
                            <lsb>1</lsb>
                            <msb>1</msb>
                            <access>read-write</access>
                            <enumeratedValues>
                                </enumeratedValues>
                        </field>
                        <field>
                            <name>TMOH</name>
                            <description>Timeout H Count Control</description>
                            <lsb>2</lsb>
                            <msb>2</msb>
                            <access>read-write</access>
                            <enumeratedValues>
                                </enumeratedValues>
                        </field>
                        <field>
                            <name>SDDL</name>
                            <description>SDA Output Delay Counter</description>
                            <lsb>4</lsb>
                            <msb>6</msb>
                            <access>read-write</access>
                            <enumeratedValues>
                                </enumeratedValues>
                        </field>
                        <field>
                            <name>DLCS</name>
                            <description>SDA Output Delay Clock Source Select</description>
                            <lsb>7</lsb>
                            <msb>7</msb>
                            <access>read-write</access>
                            <enumeratedValues>
                                </enumeratedValues>
                        </field>
                    </fields>
                </register>
                <register>
                    <name>ICMR3</name>
                    <description>I2C Bus Mode Register 3</description>
                    <addressOffset>0x04</addressOffset>
                    <size>8</size>
                    <access>read-write</access>
                    <resetValue>0x00</resetValue>
                    <resetMask>0xff</resetMask>
                    <fields>
                        <field>
                            <name>NF</name>
                            <description>Noise Filter Stage Select</description>
                            <lsb>0</lsb>
                            <msb>1</msb>
                            <access>read-write</access>
                            <enumeratedValues>
                                </enumeratedValues>
                        </field>
                        <field>
                            <name>ACKBR</name>
                            <description>Receive Acknowledge</description>
                            <lsb>2</lsb>
                            <msb>2</msb>
                            <access>read-only</access>
                            <enumeratedValues>
                                </enumeratedValues>
                        </field>
                        <field>
                            <name>ACKBT</name>
                            <description>Transmit Acknowledge</description>
                            <lsb>3</lsb>
                            <msb>3</msb>
                            <access>read-write</access>
                            <enumeratedValues>
                                </enumeratedValues>
                        </field>
                        <field>
                            <name>ACKWP</name>
                            <description>ACKBT Write Protect</description>
                            <lsb>4</lsb>
                            <msb>4</msb>
                            <access>read-write</access>
                            <enumeratedValues>
                                </enumeratedValues>
                        </field>
                        <field>
                            <name>RDRFS</name>
                            <description>RDRF Flag Set Timing Select</description>
                            <lsb>5</lsb>
                            <msb>5</msb>
                            <access>read-write</access>
                            <enumeratedValues>
                                </enumeratedValues>
                        </field>
                        <field>
                            <name>WAIT</name>
                            <description>Low,hold is released by reading ICDRR.</description>
                            <lsb>6</lsb>
                            <msb>6</msb>
                            <access>read-write</access>
                            <enumeratedValues>
                                </enumeratedValues>
                        </field>
                        <field>
                            <name>SMBS</name>
                            <description>SMBus/I2C Bus Select</description>
                            <lsb>7</lsb>
                            <msb>7</msb>
                            <access>read-write</access>
                            <enumeratedValues>
                                </enumeratedValues>
                        </field>
                    </fields>
                </register>
                <register>
                    <name>ICFER</name>
                    <description>I2C Bus Function Enable Register</description>
                    <addressOffset>0x05</addressOffset>
                    <size>8</size>
                    <access>read-write</access>
                    <resetValue>0x72</resetValue>
                    <resetMask>0xff</resetMask>
                    <fields>
                        <field>
                            <name>TMOE</name>
                            <description>Timeout Function Enable</description>
                            <lsb>0</lsb>
                            <msb>0</msb>
                            <access>read-write</access>
                            <enumeratedValues>
                                </enumeratedValues>
                        </field>
                        <field>
                            <name>MALE</name>
                            <description>Master Arbitration,Lost Detection Enable</description>
                            <lsb>1</lsb>
                            <msb>1</msb>
                            <access>read-write</access>
                            <enumeratedValues>
                                </enumeratedValues>
                        </field>
                        <field>
                            <name>NALE</name>
                            <description>NACK Transmission Arbitration,Lost Detection Enable</description>
                            <lsb>2</lsb>
                            <msb>2</msb>
                            <access>read-write</access>
                            <enumeratedValues>
                                </enumeratedValues>
                        </field>
                        <field>
                            <name>SALE</name>
                            <description>Slave Arbitration,Lost Detection Enable</description>
                            <lsb>3</lsb>
                            <msb>3</msb>
                            <access>read-write</access>
                            <enumeratedValues>
                                </enumeratedValues>
                        </field>
                        <field>
                            <name>NACKE</name>
                            <description>NACK Reception Transfer Suspension Enable</description>
                            <lsb>4</lsb>
                            <msb>4</msb>
                            <access>read-write</access>
                            <enumeratedValues>
                                </enumeratedValues>
                        </field>
                        <field>
                            <name>NFE</name>
                            <description>Digital Noise Filter Circuit Enable</description>
                            <lsb>5</lsb>
                            <msb>5</msb>
                            <access>read-write</access>
                            <enumeratedValues>
                                </enumeratedValues>
                        </field>
                        <field>
                            <name>SCLE</name>
                            <description>SCL Synchronous Circuit Enable</description>
                            <lsb>6</lsb>
                            <msb>6</msb>
                            <access>read-write</access>
                            <enumeratedValues>
                                </enumeratedValues>
                        </field>
                        <field>
                            <name>FMPE</name>
                            <description>Fast,Mode Plus Enable</description>
                            <lsb>7</lsb>
                            <msb>7</msb>
                            <access>read-write</access>
                            <enumeratedValues>
                                </enumeratedValues>
                        </field>
                    </fields>
                </register>
                <register>
                    <name>ICSER</name>
                    <description>I2C Bus Status Enable Register</description>
                    <addressOffset>0x06</addressOffset>
                    <size>8</size>
                    <access>read-write</access>
                    <resetValue>0x09</resetValue>
                    <resetMask>0xff</resetMask>
                    <fields>
                        <field>
                            <name>SAR0E</name>
                            <description>Slave Address Register 0 Enable</description>
                            <lsb>0</lsb>
                            <msb>0</msb>
                            <access>read-write</access>
                            <enumeratedValues>
                                </enumeratedValues>
                        </field>
                        <field>
                            <name>SAR1E</name>
                            <description>Slave Address Register 1 Enable</description>
                            <lsb>1</lsb>
                            <msb>1</msb>
                            <access>read-write</access>
                            <enumeratedValues>
                                </enumeratedValues>
                        </field>
                        <field>
                            <name>SAR2E</name>
                            <description>Slave Address Register 2 Enable</description>
                            <lsb>2</lsb>
                            <msb>2</msb>
                            <access>read-write</access>
                            <enumeratedValues>
                                </enumeratedValues>
                        </field>
                        <field>
                            <name>GCAE</name>
                            <description>General Call Address Enable</description>
                            <lsb>3</lsb>
                            <msb>3</msb>
                            <access>read-write</access>
                            <enumeratedValues>
                                </enumeratedValues>
                        </field>
                        <field>
                            <name>DIDE</name>
                            <description>Device,ID Address Detection Enable</description>
                            <lsb>5</lsb>
                            <msb>5</msb>
                            <access>read-write</access>
                            <enumeratedValues>
                                </enumeratedValues>
                        </field>
                        <field>
                            <name>HOAE</name>
                            <description>Host Address Enable</description>
                            <lsb>7</lsb>
                            <msb>7</msb>
                            <access>read-write</access>
                            <enumeratedValues>
                                </enumeratedValues>
                        </field>
                    </fields>
                </register>
                <register>
                    <name>ICIER</name>
                    <description>I2C Bus Interrupt Enable Register</description>
                    <addressOffset>0x07</addressOffset>
                    <size>8</size>
                    <access>read-write</access>
                    <resetValue>0x00</resetValue>
                    <resetMask>0xff</resetMask>
                    <fields>
                        <field>
                            <name>TMOIE</name>
                            <description>Timeout Interrupt Request Enable</description>
                            <lsb>0</lsb>
                            <msb>0</msb>
                            <access>read-write</access>
                            <enumeratedValues>
                                </enumeratedValues>
                        </field>
                        <field>
                            <name>ALIE</name>
                            <description>Arbitration,Lost Interrupt Request Enable</description>
                            <lsb>1</lsb>
                            <msb>1</msb>
                            <access>read-write</access>
                            <enumeratedValues>
                                </enumeratedValues>
                        </field>
                        <field>
                            <name>STIE</name>
                            <description>Start Condition Detection Interrupt Request Enable</description>
                            <lsb>2</lsb>
                            <msb>2</msb>
                            <access>read-write</access>
                            <enumeratedValues>
                                </enumeratedValues>
                        </field>
                        <field>
                            <name>SPIE</name>
                            <description>Stop Condition Detection Interrupt Request Enable</description>
                            <lsb>3</lsb>
                            <msb>3</msb>
                            <access>read-write</access>
                            <enumeratedValues>
                                </enumeratedValues>
                        </field>
                        <field>
                            <name>NAKIE</name>
                            <description>NACK Reception Interrupt Request Enable</description>
                            <lsb>4</lsb>
                            <msb>4</msb>
                            <access>read-write</access>
                            <enumeratedValues>
                                </enumeratedValues>
                        </field>
                        <field>
                            <name>RIE</name>
                            <description>Receive Data Full Interrupt Request Enable</description>
                            <lsb>5</lsb>
                            <msb>5</msb>
                            <access>read-write</access>
                            <enumeratedValues>
                                </enumeratedValues>
                        </field>
                        <field>
                            <name>TEIE</name>
                            <description>Transmit End Interrupt Request Enable</description>
                            <lsb>6</lsb>
                            <msb>6</msb>
                            <access>read-write</access>
                            <enumeratedValues>
                                </enumeratedValues>
                        </field>
                        <field>
                            <name>TIE</name>
                            <description>Transmit Data Empty Interrupt Request Enable</description>
                            <lsb>7</lsb>
                            <msb>7</msb>
                            <access>read-write</access>
                            <enumeratedValues>
                                </enumeratedValues>
                        </field>
                    </fields>
                </register>
                <register>
                    <name>ICSR1</name>
                    <description>I2C Bus Status Register 1</description>
                    <addressOffset>0x08</addressOffset>
                    <size>8</size>
                    <access>read-write</access>
                    <resetValue>0x00</resetValue>
                    <resetMask>0xff</resetMask>
                    <fields>
                        <field>
                            <name>AAS0</name>
                            <description>Slave Address 0 Detection Flag</description>
                            <lsb>0</lsb>
                            <msb>0</msb>
                            <access>read-write</access>
                            <enumeratedValues>
                                </enumeratedValues>
                        </field>
                        <field>
                            <name>AAS1</name>
                            <description>Slave Address 1 Detection Flag</description>
                            <lsb>1</lsb>
                            <msb>1</msb>
                            <access>read-write</access>
                            <enumeratedValues>
                                </enumeratedValues>
                        </field>
                        <field>
                            <name>AAS2</name>
                            <description>Slave Address 2 Detection Flag</description>
                            <lsb>2</lsb>
                            <msb>2</msb>
                            <access>read-write</access>
                            <enumeratedValues>
                                </enumeratedValues>
                        </field>
                        <field>
                            <name>GCA</name>
                            <description>General Call Address Detection Flag</description>
                            <lsb>3</lsb>
                            <msb>3</msb>
                            <access>read-write</access>
                            <enumeratedValues>
                                </enumeratedValues>
                        </field>
                        <field>
                            <name>DID</name>
                            <description>Device,ID Address Detection Flag</description>
                            <lsb>5</lsb>
                            <msb>5</msb>
                            <access>read-write</access>
                            <enumeratedValues>
                                </enumeratedValues>
                        </field>
                        <field>
                            <name>HOA</name>
                            <description>Host Address Detection Flag</description>
                            <lsb>7</lsb>
                            <msb>7</msb>
                            <access>read-write</access>
                            <enumeratedValues>
                                </enumeratedValues>
                        </field>
                    </fields>
                </register>
                <register>
                    <name>ICSR2</name>
                    <description>I2C Bus Status Register 2</description>
                    <addressOffset>0x09</addressOffset>
                    <size>8</size>
                    <access>read-write</access>
                    <resetValue>0x00</resetValue>
                    <resetMask>0xff</resetMask>
                    <fields>
                        <field>
                            <name>TMOF</name>
                            <description>Timeout Detection Flag</description>
                            <lsb>0</lsb>
                            <msb>0</msb>
                            <access>read-write</access>
                            <enumeratedValues>
                                </enumeratedValues>
                        </field>
                        <field>
                            <name>AL</name>
                            <description>Arbitration,Lost Flag</description>
                            <lsb>1</lsb>
                            <msb>1</msb>
                            <access>read-write</access>
                            <enumeratedValues>
                                </enumeratedValues>
                        </field>
                        <field>
                            <name>START</name>
                            <description>Start Condition Detection Flag</description>
                            <lsb>2</lsb>
                            <msb>2</msb>
                            <access>read-write</access>
                            <enumeratedValues>
                                </enumeratedValues>
                        </field>
                        <field>
                            <name>STOP</name>
                            <description>Stop Condition Detection Flag</description>
                            <lsb>3</lsb>
                            <msb>3</msb>
                            <access>read-write</access>
                            <enumeratedValues>
                                </enumeratedValues>
                        </field>
                        <field>
                            <name>NACKF</name>
                            <description>NACK Detection Flag</description>
                            <lsb>4</lsb>
                            <msb>4</msb>
                            <access>read-write</access>
                            <enumeratedValues>
                                </enumeratedValues>
                        </field>
                        <field>
                            <name>RDRF</name>
                            <description>Receive Data Full Flag</description>
                            <lsb>5</lsb>
                            <msb>5</msb>
                            <access>read-write</access>
                            <enumeratedValues>
                                </enumeratedValues>
                        </field>
                        <field>
                            <name>TEND</name>
                            <description>Transmit End Flag</description>
                            <lsb>6</lsb>
                            <msb>6</msb>
                            <access>read-write</access>
                            <enumeratedValues>
                                </enumeratedValues>
                        </field>
                        <field>
                            <name>TDRE</name>
                            <description>Transmit Data Empty Flag</description>
                            <lsb>7</lsb>
                            <msb>7</msb>
                            <access>read-only</access>
                            <enumeratedValues>
                                </enumeratedValues>
                        </field>
                    </fields>
                </register>
                <register>
                    <dim>3</dim>
                    <dimIncrement>0x02</dimIncrement>
                    <dimIndex>0-2</dimIndex>
                    <name>SARL%s</name>
                    <description>Slave Address Register Ly</description>
                    <addressOffset>0x0A</addressOffset>
                    <size>8</size>
                    <access>read-write</access>
                    <resetValue>0x00</resetValue>
                    <resetMask>0xff</resetMask>
                    <fields>
                        <field>
                            <name>SVA0</name>
                            <description>10-bit Address LSB</description>
                            <lsb>0</lsb>
                            <msb>0</msb>
                            <access>read-write</access>
                        </field>
                        <field>
                            <name>SVA</name>
                            <description>7-bit Address/10-bit Address Lower Bits</description>
                            <lsb>1</lsb>
                            <msb>7</msb>
                            <access>read-write</access>
                        </field>
                    </fields>
                </register>
                <register>
                    <dim>3</dim>
                    <dimIncrement>0x02</dimIncrement>
                    <dimIndex>0-2</dimIndex>
                    <name>SARU%s</name>
                    <description>Slave Address Register Uy</description>
                    <addressOffset>0x0B</addressOffset>
                    <size>8</size>
                    <access>read-write</access>
                    <resetValue>0x00</resetValue>
                    <resetMask>0xff</resetMask>
                    <fields>
                        <field>
                            <name>FS</name>
                            <description>7-bit/10-bit Address Format Select</description>
                            <lsb>0</lsb>
                            <msb>0</msb>
                            <access>read-write</access>
                            <enumeratedValues>
                                </enumeratedValues>
                        </field>
                        <field>
                            <name>SVA</name>
                            <description>10-bit Address Upper Bits</description>
                            <lsb>1</lsb>
                            <msb>2</msb>
                            <access>read-write</access>
                        </field>
                    </fields>
                </register>
                <register>
                    <name>ICBRL</name>
                    <description>I2C Bus Bit Rate Low,Level Register</description>
                    <addressOffset>0x10</addressOffset>
                    <size>8</size>
                    <access>read-write</access>
                    <resetValue>0xff</resetValue>
                    <resetMask>0xff</resetMask>
                    <fields>
                        <field>
                            <name>BRL</name>
                            <description>Bit Rate Low,Level Period</description>
                            <lsb>0</lsb>
                            <msb>4</msb>
                            <access>read-write</access>
                        </field>
                    </fields>
                </register>
                <register>
                    <name>ICBRH</name>
                    <description>I2C Bus Bit Rate High,Level Register</description>
                    <addressOffset>0x11</addressOffset>
                    <size>8</size>
                    <access>read-write</access>
                    <resetValue>0xff</resetValue>
                    <resetMask>0xff</resetMask>
                    <fields>
                        <field>
                            <name>BRH</name>
                            <description>Bit Rate High,Level Period</description>
                            <lsb>0</lsb>
                            <msb>4</msb>
                            <access>read-write</access>
                        </field>
                    </fields>
                </register>
                <register>
                    <name>ICDRT</name>
                    <description>I2C Bus Transmit Data Register</description>
                    <addressOffset>0x12</addressOffset>
                    <size>8</size>
                    <access>read-write</access>
                    <resetValue>0xff</resetValue>
                    <resetMask>0xff</resetMask>
                </register>
                <register>
                    <name>ICDRR</name>
                    <description>I2C Bus Receive Data Register</description>
                    <addressOffset>0x13</addressOffset>
                    <size>8</size>
                    <access>read-only</access>
                    <resetValue>0x00</resetValue>
                    <resetMask>0xff</resetMask>
                </register>
            </registers>
        </peripheral>
        <peripheral>
            <name>IIC0WU</name>
            <description>Inter,Integrated Circuit 0 Wake,up Unit</description>
            <baseAddress>0x4009F014</baseAddress>
            <addressBlock>
                <offset>0x02</offset>
                <size>2</size>
                <usage>registers</usage>
            </addressBlock>
            <registers>
                <register>
                    <name>ICWUR</name>
                    <description>I2C Bus Wakeup Unit Register</description>
                    <addressOffset>0x02</addressOffset>
                    <size>8</size>
                    <access>read-write</access>
                    <resetValue>0x10</resetValue>
                    <resetMask>0xff</resetMask>
                    <fields>
                        <field>
                            <name>WUAFA</name>
                            <description>Wakeup Analog Filter Additional Selection</description>
                            <lsb>0</lsb>
                            <msb>0</msb>
                            <access>read-write</access>
                            <enumeratedValues>
                                </enumeratedValues>
                        </field>
                        <field>
                            <name>WUACK</name>
                            <description>ACK Bit for Wakeup Mode</description>
                            <lsb>4</lsb>
                            <msb>4</msb>
                            <access>read-write</access>
                        </field>
                        <field>
                            <name>WUF</name>
                            <description>Wakeup Event Occurrence Flag</description>
                            <lsb>5</lsb>
                            <msb>5</msb>
                            <access>read-write</access>
                            <enumeratedValues>
                                </enumeratedValues>
                        </field>
                        <field>
                            <name>WUIE</name>
                            <description>Wakeup Interrupt Request Enable</description>
                            <lsb>6</lsb>
                            <msb>6</msb>
                            <access>read-write</access>
                            <enumeratedValues>
                                </enumeratedValues>
                        </field>
                        <field>
                            <name>WUE</name>
                            <description>Wakeup Function Enable</description>
                            <lsb>7</lsb>
                            <msb>7</msb>
                            <access>read-write</access>
                            <enumeratedValues>
                                </enumeratedValues>
                        </field>
                    </fields>
                </register>
                <register>
                    <name>ICWUR2</name>
                    <description>I2C Bus Wakeup Unit Register 2</description>
                    <addressOffset>0x03</addressOffset>
                    <size>8</size>
                    <access>read-write</access>
                    <resetValue>0xfd</resetValue>
                    <resetMask>0xff</resetMask>
                    <fields>
                        <field>
                            <name>WUSEN</name>
                            <description>Wakeup Function Synchronous Enable</description>
                            <lsb>0</lsb>
                            <msb>0</msb>
                            <access>read-write</access>
                            <enumeratedValues>
                                </enumeratedValues>
                        </field>
                        <field>
                            <name>WUASYF</name>
                            <description>Wakeup Function Asynchronous Operation Status Flag</description>
                            <lsb>1</lsb>
                            <msb>1</msb>
                            <access>read-only</access>
                            <enumeratedValues>
                                </enumeratedValues>
                        </field>
                        <field>
                            <name>WUSYF</name>
                            <description>Wakeup Function Synchronous Operation Status Flag</description>
                            <lsb>2</lsb>
                            <msb>2</msb>
                            <access>read-only</access>
                            <enumeratedValues>
                                </enumeratedValues>
                        </field>
                    </fields>
                </register>
            </registers>
        </peripheral>
        <peripheral derivedFrom="IIC0">
            <name>IIC1</name>
            <description>Inter,Integrated Circuit 1</description>
            <baseAddress>0x4009F100</baseAddress>
        </peripheral>
        <peripheral derivedFrom="IIC0">
            <name>IIC2</name>
            <description>Inter,Integrated Circuit 2</description>
            <baseAddress>0x4009F200</baseAddress>
        </peripheral>
        <peripheral>
            <name>OSPI</name>
            <description>Octa Serial Peripheral Interface</description>
            <baseAddress>0x400A6000</baseAddress>
            <addressBlock>
                <offset>0x00</offset>
                <size>36</size>
                <usage>registers</usage>
            </addressBlock>
            <addressBlock>
                <offset>0x34</offset>
                <size>52</size>
                <usage>registers</usage>
            </addressBlock>
            <addressBlock>
                <offset>0x7C</offset>
                <size>8</size>
                <usage>registers</usage>
            </addressBlock>
            <registers>
                <register>
                    <name>DCR</name>
                    <description>Device Command Register</description>
                    <addressOffset>0x00</addressOffset>
                    <size>32</size>
                    <access>read-write</access>
                    <resetValue>0x00000000</resetValue>
                    <resetMask>0xffffffff</resetMask>
                    <fields>
                        <field>
                            <name>DVCMD0</name>
                            <description>Device Command data</description>
                            <lsb>0</lsb>
                            <msb>7</msb>
                            <access>read-write</access>
                        </field>
                        <field>
                            <name>DVCMD1</name>
                            <description>Device Command data</description>
                            <lsb>8</lsb>
                            <msb>15</msb>
                            <access>read-write</access>
                        </field>
                    </fields>
                </register>
                <register>
                    <name>DAR</name>
                    <description>Device Address Register</description>
                    <addressOffset>0x04</addressOffset>
                    <size>32</size>
                    <access>read-write</access>
                    <resetValue>0x00000000</resetValue>
                    <resetMask>0xffffffff</resetMask>
                    <fields>
                        <field>
                            <name>DVAD0</name>
                            <description>Device Address data 0</description>
                            <lsb>0</lsb>
                            <msb>7</msb>
                            <access>read-write</access>
                        </field>
                        <field>
                            <name>DVAD1</name>
                            <description>Device Address data 1</description>
                            <lsb>8</lsb>
                            <msb>15</msb>
                            <access>read-write</access>
                        </field>
                        <field>
                            <name>DVAD2</name>
                            <description>Device Address data 2</description>
                            <lsb>16</lsb>
                            <msb>23</msb>
                            <access>read-write</access>
                        </field>
                        <field>
                            <name>DVAD3</name>
                            <description>Device Address data 3</description>
                            <lsb>24</lsb>
                            <msb>31</msb>
                            <access>read-write</access>
                        </field>
                    </fields>
                </register>
                <register>
                    <name>DCSR</name>
                    <description>Device Command Setting Register</description>
                    <addressOffset>0x08</addressOffset>
                    <size>32</size>
                    <access>read-write</access>
                    <resetValue>0x00000000</resetValue>
                    <resetMask>0xffffffff</resetMask>
                    <fields>
                        <field>
                            <name>DALEN</name>
                            <description>Transfer data length setting</description>
                            <lsb>0</lsb>
                            <msb>7</msb>
                            <access>read-write</access>
                        </field>
                        <field>
                            <name>DMLEN</name>
                            <description>Dummy cycle setting</description>
                            <lsb>8</lsb>
                            <msb>15</msb>
                            <access>read-write</access>
                        </field>
                        <field>
                            <name>ACDV</name>
                            <description>Access Device setting</description>
                            <lsb>19</lsb>
                            <msb>19</msb>
                            <access>read-write</access>
                            <enumeratedValues>
                                </enumeratedValues>
                        </field>
                        <field>
                            <name>CMDLEN</name>
                            <description>Transfer command length setting</description>
                            <lsb>20</lsb>
                            <msb>22</msb>
                            <access>read-write</access>
                        </field>
                        <field>
                            <name>DAOR</name>
                            <description>Data order setting</description>
                            <lsb>23</lsb>
                            <msb>23</msb>
                            <access>read-write</access>
                            <enumeratedValues>
                                </enumeratedValues>
                        </field>
                        <field>
                            <name>ADLEN</name>
                            <description>Transfer address length setting</description>
                            <lsb>24</lsb>
                            <msb>26</msb>
                            <access>read-write</access>
                        </field>
                        <field>
                            <name>DOPI</name>
                            <description>DOPI single byte setting</description>
                            <lsb>27</lsb>
                            <msb>27</msb>
                            <access>read-write</access>
                            <enumeratedValues>
                                </enumeratedValues>
                        </field>
                        <field>
                            <name>ACDA</name>
                            <description>Data Access Control</description>
                            <lsb>28</lsb>
                            <msb>28</msb>
                            <access>read-write</access>
                            <enumeratedValues>
                                </enumeratedValues>
                        </field>
                        <field>
                            <name>PREN</name>
                            <description>Preamble bit enable for OctaRAM</description>
                            <lsb>29</lsb>
                            <msb>29</msb>
                            <access>read-write</access>
                            <enumeratedValues>
                                </enumeratedValues>
                        </field>
                    </fields>
                </register>
                <register>
                    <name>DSR0</name>
                    <description>Device Size Register 0</description>
                    <addressOffset>0x0C</addressOffset>
                    <size>32</size>
                    <access>read-write</access>
                    <resetValue>0x00000000</resetValue>
                    <resetMask>0xffffffff</resetMask>
                    <fields>
                        <field>
                            <name>DV0SZ</name>
                            <description>Device 0 size setting</description>
                            <lsb>0</lsb>
                            <msb>29</msb>
                            <access>read-write</access>
                        </field>
                        <field>
                            <name>DV0TYP</name>
                            <description>Device 0 type setting</description>
                            <lsb>30</lsb>
                            <msb>31</msb>
                            <access>read-write</access>
                            <enumeratedValues>
                                </enumeratedValues>
                        </field>
                    </fields>
                </register>
                <register>
                    <name>DSR1</name>
                    <description>Device Size Register 1</description>
                    <addressOffset>0x10</addressOffset>
                    <size>32</size>
                    <access>read-write</access>
                    <resetValue>0x00000000</resetValue>
                    <resetMask>0xffffffff</resetMask>
                    <fields>
                        <field>
                            <name>DV1SZ</name>
                            <description>Device 1 size setting</description>
                            <lsb>0</lsb>
                            <msb>29</msb>
                            <access>read-write</access>
                        </field>
                        <field>
                            <name>DV1TYP</name>
                            <description>Device 1 type setting</description>
                            <lsb>30</lsb>
                            <msb>31</msb>
                            <access>read-write</access>
                            <enumeratedValues>
                                </enumeratedValues>
                        </field>
                    </fields>
                </register>
                <register>
                    <name>MDTR</name>
                    <description>Memory Delay Trim Register</description>
                    <addressOffset>0x14</addressOffset>
                    <size>32</size>
                    <access>read-write</access>
                    <resetValue>0x06009400</resetValue>
                    <resetMask>0xffffffff</resetMask>
                    <fields>
                        <field>
                            <name>DV0DEL</name>
                            <description>Device 0 delay setting</description>
                            <lsb>0</lsb>
                            <msb>7</msb>
                            <access>read-write</access>
                        </field>
                        <field>
                            <name>DQSERAM</name>
                            <description>OM_DQS enable counter</description>
                            <lsb>8</lsb>
                            <msb>11</msb>
                            <access>read-write</access>
                        </field>
                        <field>
                            <name>DQSESOPI</name>
                            <description>OM_DQS enable counter</description>
                            <lsb>12</lsb>
                            <msb>15</msb>
                            <access>read-write</access>
                        </field>
                        <field>
                            <name>DV1DEL</name>
                            <description>Device 1 delay setting</description>
                            <lsb>16</lsb>
                            <msb>23</msb>
                            <access>read-write</access>
                        </field>
                        <field>
                            <name>DQSEDOPI</name>
                            <description>OM_DQS enable counter</description>
                            <lsb>24</lsb>
                            <msb>27</msb>
                            <access>read-write</access>
                        </field>
                    </fields>
                </register>
                <register>
                    <name>ACTR</name>
                    <description>Auto,Calibration Timer Register</description>
                    <addressOffset>0x18</addressOffset>
                    <size>32</size>
                    <access>read-write</access>
                    <resetValue>0x10000000</resetValue>
                    <resetMask>0xffffffff</resetMask>
                    <fields>
                        <field>
                            <name>CTP</name>
                            <description>Automatic calibration cycle time setting</description>
                            <lsb>0</lsb>
                            <msb>31</msb>
                            <access>read-write</access>
                        </field>
                    </fields>
                </register>
                <register>
                    <name>ACAR0</name>
                    <description>Auto,Calibration Address Register 0</description>
                    <addressOffset>0x1C</addressOffset>
                    <size>32</size>
                    <access>read-write</access>
                    <resetValue>0x00000000</resetValue>
                    <resetMask>0xffffffff</resetMask>
                    <fields>
                        <field>
                            <name>CAD0</name>
                            <description>Automatic calibration address</description>
                            <lsb>0</lsb>
                            <msb>31</msb>
                            <access>read-write</access>
                        </field>
                    </fields>
                </register>
                <register>
                    <name>ACAR1</name>
                    <description>Auto,Calibration Address Register 1</description>
                    <addressOffset>0x20</addressOffset>
                    <size>32</size>
                    <access>read-write</access>
                    <resetValue>0x00000000</resetValue>
                    <resetMask>0xffffffff</resetMask>
                    <fields>
                        <field>
                            <name>CAD1</name>
                            <description>Automatic calibration address</description>
                            <lsb>0</lsb>
                            <msb>31</msb>
                            <access>read-write</access>
                        </field>
                    </fields>
                </register>
                <register>
                    <name>DRCSTR</name>
                    <description>Device Memory Map Read Chip Select Timing Setting Register</description>
                    <addressOffset>0x34</addressOffset>
                    <size>32</size>
                    <access>read-write</access>
                    <resetValue>0x00000000</resetValue>
                    <resetMask>0xffffffff</resetMask>
                    <fields>
                        <field>
                            <name>CTRW0</name>
                            <description>Device 0 single continuous read waiting cycle setting in PCLKA units</description>
                            <lsb>0</lsb>
                            <msb>6</msb>
                            <access>read-write</access>
                        </field>
                        <field>
                            <name>CTR0</name>
                            <description>Device 0 single continuous read mode setting</description>
                            <lsb>7</lsb>
                            <msb>7</msb>
                            <access>read-write</access>
                            <enumeratedValues>
                                </enumeratedValues>
                        </field>
                        <field>
                            <name>DVRDCMD0</name>
                            <description>Device 0 Command execution interval setting</description>
                            <lsb>8</lsb>
                            <msb>10</msb>
                            <access>read-write</access>
                            <enumeratedValues>
                                </enumeratedValues>
                        </field>
                        <field>
                            <name>DVRDHI0</name>
                            <description>Device 0 select signal pull,up timing setting</description>
                            <lsb>11</lsb>
                            <msb>13</msb>
                            <access>read-write</access>
                            <enumeratedValues>
                                </enumeratedValues>
                        </field>
                        <field>
                            <name>DVRDLO0</name>
                            <description>Device 0 select signal pull,down timing setting</description>
                            <lsb>14</lsb>
                            <msb>15</msb>
                            <access>read-write</access>
                            <enumeratedValues>
                                </enumeratedValues>
                        </field>
                        <field>
                            <name>CTRW1</name>
                            <description>Device 1 single continuous read waiting cycle setting in PCLKA units</description>
                            <lsb>16</lsb>
                            <msb>22</msb>
                            <access>read-write</access>
                        </field>
                        <field>
                            <name>CTR1</name>
                            <description>Device 1 single continuous read mode setting</description>
                            <lsb>23</lsb>
                            <msb>23</msb>
                            <access>read-write</access>
                            <enumeratedValues>
                                </enumeratedValues>
                        </field>
                        <field>
                            <name>DVRDCMD1</name>
                            <description>Device 1 Command execution interval</description>
                            <lsb>24</lsb>
                            <msb>26</msb>
                            <access>read-write</access>
                            <enumeratedValues>
                                </enumeratedValues>
                        </field>
                        <field>
                            <name>DVRDHI1</name>
                            <description>Device 1 select signal High timing setting</description>
                            <lsb>27</lsb>
                            <msb>29</msb>
                            <access>read-write</access>
                            <enumeratedValues>
                                </enumeratedValues>
                        </field>
                        <field>
                            <name>DVRDLO1</name>
                            <description>Device 1 select signal pull,down timing setting</description>
                            <lsb>30</lsb>
                            <msb>31</msb>
                            <access>read-write</access>
                            <enumeratedValues>
                                </enumeratedValues>
                        </field>
                    </fields>
                </register>
                <register>
                    <name>DWCSTR</name>
                    <description>Device Memory Map Write Chip Select Timing Setting Register</description>
                    <addressOffset>0x38</addressOffset>
                    <size>32</size>
                    <access>read-write</access>
                    <resetValue>0x00000000</resetValue>
                    <resetMask>0xffffffff</resetMask>
                    <fields>
                        <field>
                            <name>CTWW0</name>
                            <description>Device 0 single continuous write waiting cycle setting in PCLKA units</description>
                            <lsb>0</lsb>
                            <msb>6</msb>
                            <access>read-write</access>
                        </field>
                        <field>
                            <name>CTW0</name>
                            <description>Device 0 single continuous write mode setting</description>
                            <lsb>7</lsb>
                            <msb>7</msb>
                            <access>read-write</access>
                            <enumeratedValues>
                                </enumeratedValues>
                        </field>
                        <field>
                            <name>DVWCMD0</name>
                            <description>Device 0 Command execution interval setting</description>
                            <lsb>8</lsb>
                            <msb>10</msb>
                            <access>read-write</access>
                            <enumeratedValues>
                                </enumeratedValues>
                        </field>
                        <field>
                            <name>DVWHI0</name>
                            <description>Device 0 select signal pull,up timing setting</description>
                            <lsb>11</lsb>
                            <msb>13</msb>
                            <access>read-write</access>
                            <enumeratedValues>
                                </enumeratedValues>
                        </field>
                        <field>
                            <name>DVWLO0</name>
                            <description>Device 0 select signal pull,down timing setting</description>
                            <lsb>14</lsb>
                            <msb>15</msb>
                            <access>read-write</access>
                            <enumeratedValues>
                                </enumeratedValues>
                        </field>
                        <field>
                            <name>CTWW1</name>
                            <description>Device 1 single continuous write waiting cycle setting in PCLKA units</description>
                            <lsb>16</lsb>
                            <msb>22</msb>
                            <access>read-write</access>
                        </field>
                        <field>
                            <name>CTW1</name>
                            <description>Device 1 single continuous write mode setting</description>
                            <lsb>23</lsb>
                            <msb>23</msb>
                            <access>read-write</access>
                            <enumeratedValues>
                                </enumeratedValues>
                        </field>
                        <field>
                            <name>DVWCMD1</name>
                            <description>Device 1 Command execution interval setting</description>
                            <lsb>24</lsb>
                            <msb>26</msb>
                            <access>read-write</access>
                            <enumeratedValues>
                                </enumeratedValues>
                        </field>
                        <field>
                            <name>DVWHI1</name>
                            <description>Device 1 select signal pull,up timing setting</description>
                            <lsb>27</lsb>
                            <msb>29</msb>
                            <access>read-write</access>
                            <enumeratedValues>
                                </enumeratedValues>
                        </field>
                        <field>
                            <name>DVWLO1</name>
                            <description>Device 1 select signal pull,down timing setting</description>
                            <lsb>30</lsb>
                            <msb>31</msb>
                            <access>read-write</access>
                            <enumeratedValues>
                                </enumeratedValues>
                        </field>
                    </fields>
                </register>
                <register>
                    <name>DCSTR</name>
                    <description>Device Chip Select Timing Setting Register</description>
                    <addressOffset>0x3C</addressOffset>
                    <size>32</size>
                    <access>read-write</access>
                    <resetValue>0x00000000</resetValue>
                    <resetMask>0xffffffff</resetMask>
                    <fields>
                        <field>
                            <name>DVSELCMD</name>
                            <description>Device Command execution interval setting</description>
                            <lsb>8</lsb>
                            <msb>10</msb>
                            <access>read-write</access>
                            <enumeratedValues>
                                </enumeratedValues>
                        </field>
                        <field>
                            <name>DVSELHI</name>
                            <description>Device select signal pull,up timing setting</description>
                            <lsb>11</lsb>
                            <msb>13</msb>
                            <access>read-write</access>
                            <enumeratedValues>
                                </enumeratedValues>
                        </field>
                        <field>
                            <name>DVSELLO</name>
                            <description>Device select signal pull,down timing setting</description>
                            <lsb>14</lsb>
                            <msb>15</msb>
                            <access>read-write</access>
                            <enumeratedValues>
                                </enumeratedValues>
                        </field>
                    </fields>
                </register>
                <register>
                    <name>CDSR</name>
                    <description>Controller and Device Setting Register</description>
                    <addressOffset>0x40</addressOffset>
                    <size>32</size>
                    <access>read-write</access>
                    <resetValue>0x00000000</resetValue>
                    <resetMask>0xffffffff</resetMask>
                    <fields>
                        <field>
                            <name>DV0TTYP</name>
                            <description>Device0_transfer_type setting</description>
                            <lsb>0</lsb>
                            <msb>1</msb>
                            <access>read-write</access>
                            <enumeratedValues>
                                </enumeratedValues>
                        </field>
                        <field>
                            <name>DV1TTYP</name>
                            <description>Device1_transfer_type setting</description>
                            <lsb>2</lsb>
                            <msb>3</msb>
                            <access>read-write</access>
                            <enumeratedValues>
                                </enumeratedValues>
                        </field>
                        <field>
                            <name>DV0PC</name>
                            <description>Device0_memory precycle setting</description>
                            <lsb>4</lsb>
                            <msb>4</msb>
                            <access>read-write</access>
                            <enumeratedValues>
                                </enumeratedValues>
                        </field>
                        <field>
                            <name>DV1PC</name>
                            <description>Device1_memory precycle setting</description>
                            <lsb>5</lsb>
                            <msb>5</msb>
                            <access>read-write</access>
                            <enumeratedValues>
                                </enumeratedValues>
                        </field>
                        <field>
                            <name>ACMEME0</name>
                            <description>Automatic calibration memory enable setting for device 0</description>
                            <lsb>10</lsb>
                            <msb>10</msb>
                            <access>read-write</access>
                            <enumeratedValues>
                                </enumeratedValues>
                        </field>
                        <field>
                            <name>ACMEME1</name>
                            <description>Automatic calibration memory enable setting for device 1</description>
                            <lsb>11</lsb>
                            <msb>11</msb>
                            <access>read-write</access>
                            <enumeratedValues>
                                </enumeratedValues>
                        </field>
                        <field>
                            <name>ACMODE</name>
                            <description>Automatic calibration mode</description>
                            <lsb>12</lsb>
                            <msb>13</msb>
                            <access>read-write</access>
                            <enumeratedValues>
                                </enumeratedValues>
                        </field>
                        <field>
                            <name>DLFT</name>
                            <description>Deadlock Free Timer Enable</description>
                            <lsb>31</lsb>
                            <msb>31</msb>
                            <access>read-write</access>
                            <enumeratedValues>
                                </enumeratedValues>
                        </field>
                    </fields>
                </register>
                <register>
                    <name>MDLR</name>
                    <description>Memory Map Dummy Length Register</description>
                    <addressOffset>0x44</addressOffset>
                    <size>32</size>
                    <access>read-write</access>
                    <resetValue>0x00000000</resetValue>
                    <resetMask>0xffffffff</resetMask>
                    <fields>
                        <field>
                            <name>DV0RDL</name>
                            <description>Device 0 Read dummy length setting</description>
                            <lsb>0</lsb>
                            <msb>7</msb>
                            <access>read-write</access>
                        </field>
                        <field>
                            <name>DV0WDL</name>
                            <description>Device 0 Write dummy length setting</description>
                            <lsb>8</lsb>
                            <msb>15</msb>
                            <access>read-write</access>
                        </field>
                        <field>
                            <name>DV1RDL</name>
                            <description>Device 1 Read dummy length setting</description>
                            <lsb>16</lsb>
                            <msb>23</msb>
                            <access>read-write</access>
                        </field>
                        <field>
                            <name>DV1WDL</name>
                            <description>Device 1 Write dummy length setting</description>
                            <lsb>24</lsb>
                            <msb>31</msb>
                            <access>read-write</access>
                        </field>
                    </fields>
                </register>
                <register>
                    <name>MRWCR0</name>
                    <description>Memory Map Read/Write Command Register 0</description>
                    <addressOffset>0x48</addressOffset>
                    <size>32</size>
                    <access>read-write</access>
                    <resetValue>0x00000000</resetValue>
                    <resetMask>0xffffffff</resetMask>
                    <fields>
                        <field>
                            <name>D0MRCMD0</name>
                            <description>Memory map read command 0 setting</description>
                            <lsb>0</lsb>
                            <msb>7</msb>
                            <access>read-write</access>
                        </field>
                        <field>
                            <name>D0MRCMD1</name>
                            <description>Memory map read command 1 setting</description>
                            <lsb>8</lsb>
                            <msb>15</msb>
                            <access>read-write</access>
                        </field>
                        <field>
                            <name>D0MWCMD0</name>
                            <description>Memory map write command 0 setting</description>
                            <lsb>16</lsb>
                            <msb>23</msb>
                            <access>read-write</access>
                        </field>
                        <field>
                            <name>D0MWCMD1</name>
                            <description>Memory map write command 1 setting</description>
                            <lsb>24</lsb>
                            <msb>31</msb>
                            <access>read-write</access>
                        </field>
                    </fields>
                </register>
                <register>
                    <name>MRWCR1</name>
                    <description>Memory Map Read/Write Command Register 1</description>
                    <addressOffset>0x4C</addressOffset>
                    <size>32</size>
                    <access>read-write</access>
                    <resetValue>0x00000000</resetValue>
                    <resetMask>0xffffffff</resetMask>
                    <fields>
                        <field>
                            <name>D1MRCMD0</name>
                            <description>Memory map read command 0 setting</description>
                            <lsb>0</lsb>
                            <msb>7</msb>
                            <access>read-write</access>
                        </field>
                        <field>
                            <name>D1MRCMD1</name>
                            <description>Memory map read command 1 setting</description>
                            <lsb>8</lsb>
                            <msb>15</msb>
                            <access>read-write</access>
                        </field>
                        <field>
                            <name>D1MWCMD0</name>
                            <description>Memory map write command 0 setting</description>
                            <lsb>16</lsb>
                            <msb>23</msb>
                            <access>read-write</access>
                        </field>
                        <field>
                            <name>D1MWCMD1</name>
                            <description>Memory map write command 1 setting</description>
                            <lsb>24</lsb>
                            <msb>31</msb>
                            <access>read-write</access>
                        </field>
                    </fields>
                </register>
                <register>
                    <name>MRWCSR</name>
                    <description>Memory Map Read/Write Setting Register</description>
                    <addressOffset>0x50</addressOffset>
                    <size>32</size>
                    <access>read-write</access>
                    <resetValue>0x00000000</resetValue>
                    <resetMask>0xffffffff</resetMask>
                    <fields>
                        <field>
                            <name>MRAL0</name>
                            <description>Device 0 read address length setting</description>
                            <lsb>0</lsb>
                            <msb>2</msb>
                            <access>read-write</access>
                        </field>
                        <field>
                            <name>MRCL0</name>
                            <description>Device 0 read command length setting</description>
                            <lsb>3</lsb>
                            <msb>5</msb>
                            <access>read-write</access>
                        </field>
                        <field>
                            <name>MRO0</name>
                            <description>Device 0 read order setting</description>
                            <lsb>6</lsb>
                            <msb>6</msb>
                            <access>read-write</access>
                            <enumeratedValues>
                                </enumeratedValues>
                        </field>
                        <field>
                            <name>PREN0</name>
                            <description>Preamble bit enable for mem0 memory,map read</description>
                            <lsb>7</lsb>
                            <msb>7</msb>
                            <access>read-write</access>
                            <enumeratedValues>
                                </enumeratedValues>
                        </field>
                        <field>
                            <name>MWAL0</name>
                            <description>Device 0 write address length setting</description>
                            <lsb>8</lsb>
                            <msb>10</msb>
                            <access>read-write</access>
                        </field>
                        <field>
                            <name>MWCL0</name>
                            <description>Device 0 write command length setting</description>
                            <lsb>11</lsb>
                            <msb>13</msb>
                            <access>read-write</access>
                        </field>
                        <field>
                            <name>MWO0</name>
                            <description>Device 0 write order setting</description>
                            <lsb>14</lsb>
                            <msb>14</msb>
                            <access>read-write</access>
                            <enumeratedValues>
                                </enumeratedValues>
                        </field>
                        <field>
                            <name>MRAL1</name>
                            <description>Device 1 read address length setting</description>
                            <lsb>16</lsb>
                            <msb>18</msb>
                            <access>read-write</access>
                        </field>
                        <field>
                            <name>MRCL1</name>
                            <description>Device 1 read command length setting</description>
                            <lsb>19</lsb>
                            <msb>21</msb>
                            <access>read-write</access>
                        </field>
                        <field>
                            <name>MRO1</name>
                            <description>Device 1 read order setting</description>
                            <lsb>22</lsb>
                            <msb>22</msb>
                            <access>read-write</access>
                            <enumeratedValues>
                                </enumeratedValues>
                        </field>
                        <field>
                            <name>PREN1</name>
                            <description>Preamble bit enable for mem1 memory,map read</description>
                            <lsb>23</lsb>
                            <msb>23</msb>
                            <access>read-write</access>
                            <enumeratedValues>
                                </enumeratedValues>
                        </field>
                        <field>
                            <name>MWAL1</name>
                            <description>Device 1 write address length setting</description>
                            <lsb>24</lsb>
                            <msb>26</msb>
                            <access>read-write</access>
                        </field>
                        <field>
                            <name>MWCL1</name>
                            <description>Device 1 write command length setting</description>
                            <lsb>27</lsb>
                            <msb>29</msb>
                            <access>read-write</access>
                        </field>
                        <field>
                            <name>MWO1</name>
                            <description>Device 1 write order setting</description>
                            <lsb>30</lsb>
                            <msb>30</msb>
                            <access>read-write</access>
                            <enumeratedValues>
                                </enumeratedValues>
                        </field>
                    </fields>
                </register>
                <register>
                    <name>ESR</name>
                    <description>Error Status Register</description>
                    <addressOffset>0x54</addressOffset>
                    <size>32</size>
                    <access>read-write</access>
                    <resetValue>0x00000000</resetValue>
                    <resetMask>0xffffffff</resetMask>
                    <fields>
                        <field>
                            <name>MRESR</name>
                            <description>Memory map read error status</description>
                            <lsb>0</lsb>
                            <msb>7</msb>
                            <access>read-write</access>
                            <enumeratedValues>
                                </enumeratedValues>
                        </field>
                        <field>
                            <name>MWESR</name>
                            <description>Memory map write error status</description>
                            <lsb>8</lsb>
                            <msb>15</msb>
                            <access>read-write</access>
                            <enumeratedValues>
                                </enumeratedValues>
                        </field>
                    </fields>
                </register>
                <register>
                    <name>CWNDR</name>
                    <description>Configure Write without Data Register</description>
                    <addressOffset>0x58</addressOffset>
                    <size>32</size>
                    <access>write-only</access>
                    <resetValue>0x00000000</resetValue>
                    <resetMask>0xffffffff</resetMask>
                    <fields>
                        <field>
                            <name>WND</name>
                            <description>The write value should be 0.</description>
                            <lsb>0</lsb>
                            <msb>31</msb>
                            <access>write-only</access>
                        </field>
                    </fields>
                </register>
                <register>
                    <name>CWDR</name>
                    <description>Configure Write Data Register</description>
                    <addressOffset>0x5C</addressOffset>
                    <size>32</size>
                    <access>write-only</access>
                    <resetValue>0x00000000</resetValue>
                    <resetMask>0xffffffff</resetMask>
                    <fields>
                        <field>
                            <name>WD0</name>
                            <description>Write data 0</description>
                            <lsb>0</lsb>
                            <msb>7</msb>
                            <access>write-only</access>
                        </field>
                        <field>
                            <name>WD1</name>
                            <description>Write data 1</description>
                            <lsb>8</lsb>
                            <msb>15</msb>
                            <access>write-only</access>
                        </field>
                        <field>
                            <name>WD2</name>
                            <description>Write data 2</description>
                            <lsb>16</lsb>
                            <msb>23</msb>
                            <access>write-only</access>
                        </field>
                        <field>
                            <name>WD3</name>
                            <description>Write data 3</description>
                            <lsb>24</lsb>
                            <msb>31</msb>
                            <access>write-only</access>
                        </field>
                    </fields>
                </register>
                <register>
                    <name>CRR</name>
                    <description>Configure Read Register</description>
                    <addressOffset>0x60</addressOffset>
                    <size>32</size>
                    <access>read-only</access>
                    <resetValue>0x00000000</resetValue>
                    <resetMask>0xffffffff</resetMask>
                    <fields>
                        <field>
                            <name>RD0</name>
                            <description>Read data 0</description>
                            <lsb>0</lsb>
                            <msb>7</msb>
                            <access>read-only</access>
                        </field>
                        <field>
                            <name>RD1</name>
                            <description>Read data 1</description>
                            <lsb>8</lsb>
                            <msb>15</msb>
                            <access>read-only</access>
                        </field>
                        <field>
                            <name>RD2</name>
                            <description>Read data 2</description>
                            <lsb>16</lsb>
                            <msb>23</msb>
                            <access>read-only</access>
                        </field>
                        <field>
                            <name>RD3</name>
                            <description>Read data 3</description>
                            <lsb>24</lsb>
                            <msb>31</msb>
                            <access>read-only</access>
                        </field>
                    </fields>
                </register>
                <register>
                    <name>ACSR</name>
                    <description>Auto,Calibration Status Register</description>
                    <addressOffset>0x64</addressOffset>
                    <size>32</size>
                    <access>read-write</access>
                    <resetValue>0x00000000</resetValue>
                    <resetMask>0xffffffff</resetMask>
                    <fields>
                        <field>
                            <name>ACSR0</name>
                            <description>Auto,calibration status of device 0</description>
                            <lsb>0</lsb>
                            <msb>2</msb>
                            <access>read-write</access>
                            <enumeratedValues>
                                </enumeratedValues>
                        </field>
                        <field>
                            <name>ACSR1</name>
                            <description>Auto,calibration status of device 1</description>
                            <lsb>3</lsb>
                            <msb>5</msb>
                            <access>read-write</access>
                            <enumeratedValues>
                                </enumeratedValues>
                        </field>
                    </fields>
                </register>
                <register>
                    <name>DCSMXR</name>
                    <description>Device Chip Select Maximum Period Register</description>
                    <addressOffset>0x7C</addressOffset>
                    <size>32</size>
                    <access>read-write</access>
                    <resetValue>0x00000000</resetValue>
                    <resetMask>0xffffffff</resetMask>
                    <fields>
                        <field>
                            <name>CTWMX0</name>
                            <description>Indicates the maximum period that OM_CS0 and OM_CS1 are Low in single continuous write of OctaRAM.</description>
                            <lsb>0</lsb>
                            <msb>8</msb>
                            <access>read-write</access>
                        </field>
                        <field>
                            <name>CTWMX1</name>
                            <description>Indicates the maximum period that OM_CS0 and OM_CS1 are Low in single continuous read of OctaRAM.</description>
                            <lsb>16</lsb>
                            <msb>24</msb>
                            <access>read-write</access>
                        </field>
                    </fields>
                </register>
                <register>
                    <name>DWSCTSR</name>
                    <description>Device Memory Map Write single continuous translating size Register</description>
                    <addressOffset>0x80</addressOffset>
                    <size>32</size>
                    <access>read-write</access>
                    <resetValue>0x00000000</resetValue>
                    <resetMask>0xffffffff</resetMask>
                    <fields>
                        <field>
                            <name>CTSN0</name>
                            <description>Indicates the number of bytes to translate in single continuous write of device 0.</description>
                            <lsb>0</lsb>
                            <msb>10</msb>
                            <access>read-write</access>
                        </field>
                        <field>
                            <name>CTSN1</name>
                            <description>Indicates the number of bytes to translate in single continuous write of device 1.</description>
                            <lsb>16</lsb>
                            <msb>26</msb>
                            <access>read-write</access>
                        </field>
                    </fields>
                </register>
            </registers>
        </peripheral>
        <peripheral>
            <name>CEC</name>
            <description>Consumer Electronics Control</description>
            <baseAddress>0x400AC000</baseAddress>
            <addressBlock>
                <offset>0x00</offset>
                <size>3</size>
                <usage>registers</usage>
            </addressBlock>
            <addressBlock>
                <offset>0x04</offset>
                <size>34</size>
                <usage>registers</usage>
            </addressBlock>
            <addressBlock>
                <offset>0x28</offset>
                <size>1</size>
                <usage>registers</usage>
            </addressBlock>
            <addressBlock>
                <offset>0x2A</offset>
                <size>1</size>
                <usage>registers</usage>
            </addressBlock>
            <addressBlock>
                <offset>0x40</offset>
                <size>6</size>
                <usage>registers</usage>
            </addressBlock>
            <registers>
                <register>
                    <name>CADR</name>
                    <description>CEC Local Address Setting Register</description>
                    <addressOffset>0x00</addressOffset>
                    <size>16</size>
                    <access>read-write</access>
                    <resetValue>0x0000</resetValue>
                    <resetMask>0xffff</resetMask>
                    <fields>
                        <field>
                            <name>ADR00</name>
                            <description>Local Address at Address 0 (TV)</description>
                            <lsb>0</lsb>
                            <msb>0</msb>
                            <access>read-write</access>
                            <enumeratedValues>
                                </enumeratedValues>
                        </field>
                        <field>
                            <name>ADR01</name>
                            <description>Local Address Setting at Address 1 (recording device 1)</description>
                            <lsb>1</lsb>
                            <msb>1</msb>
                            <access>read-write</access>
                            <enumeratedValues>
                                </enumeratedValues>
                        </field>
                        <field>
                            <name>ADR02</name>
                            <description>Local Address Setting at Address 2 (recording device 2)</description>
                            <lsb>2</lsb>
                            <msb>2</msb>
                            <access>read-write</access>
                            <enumeratedValues>
                                </enumeratedValues>
                        </field>
                        <field>
                            <name>ADR03</name>
                            <description>Local Address Setting at Address 3 (tuner 1)</description>
                            <lsb>3</lsb>
                            <msb>3</msb>
                            <access>read-write</access>
                            <enumeratedValues>
                                </enumeratedValues>
                        </field>
                        <field>
                            <name>ADR04</name>
                            <description>Local Address Setting at Address 4 (playback device 1)</description>
                            <lsb>4</lsb>
                            <msb>4</msb>
                            <access>read-write</access>
                            <enumeratedValues>
                                </enumeratedValues>
                        </field>
                        <field>
                            <name>ADR05</name>
                            <description>Local Address Setting at Address 5 (audio system)</description>
                            <lsb>5</lsb>
                            <msb>5</msb>
                            <access>read-write</access>
                            <enumeratedValues>
                                </enumeratedValues>
                        </field>
                        <field>
                            <name>ADR06</name>
                            <description>Local Address Setting at Address 6 (tuner 2)</description>
                            <lsb>6</lsb>
                            <msb>6</msb>
                            <access>read-write</access>
                            <enumeratedValues>
                                </enumeratedValues>
                        </field>
                        <field>
                            <name>ADR07</name>
                            <description>Local Address Setting at Address 7 (tuner 3)</description>
                            <lsb>7</lsb>
                            <msb>7</msb>
                            <access>read-write</access>
                            <enumeratedValues>
                                </enumeratedValues>
                        </field>
                        <field>
                            <name>ADR08</name>
                            <description>Local Address Setting at Address 8 (playback device 2)</description>
                            <lsb>8</lsb>
                            <msb>8</msb>
                            <access>read-write</access>
                            <enumeratedValues>
                                </enumeratedValues>
                        </field>
                        <field>
                            <name>ADR09</name>
                            <description>Local Address Setting at Address 9 (recording device 3)</description>
                            <lsb>9</lsb>
                            <msb>9</msb>
                            <access>read-write</access>
                            <enumeratedValues>
                                </enumeratedValues>
                        </field>
                        <field>
                            <name>ADR10</name>
                            <description>Local Address Setting at Address 10 (tuner 4)</description>
                            <lsb>10</lsb>
                            <msb>10</msb>
                            <access>read-write</access>
                            <enumeratedValues>
                                </enumeratedValues>
                        </field>
                        <field>
                            <name>ADR11</name>
                            <description>Local Address Setting at Address 11 (playback device 3)</description>
                            <lsb>11</lsb>
                            <msb>11</msb>
                            <access>read-write</access>
                            <enumeratedValues>
                                </enumeratedValues>
                        </field>
                        <field>
                            <name>ADR12</name>
                            <description>Local Address Setting at Address 12 (reserved)</description>
                            <lsb>12</lsb>
                            <msb>12</msb>
                            <access>read-write</access>
                            <enumeratedValues>
                                </enumeratedValues>
                        </field>
                        <field>
                            <name>ADR13</name>
                            <description>Local Address Setting at Address 13 (reserved)</description>
                            <lsb>13</lsb>
                            <msb>13</msb>
                            <access>read-write</access>
                            <enumeratedValues>
                                </enumeratedValues>
                        </field>
                        <field>
                            <name>ADR14</name>
                            <description>Local Address Setting at Address 14 (specific use)</description>
                            <lsb>14</lsb>
                            <msb>14</msb>
                            <access>read-write</access>
                            <enumeratedValues>
                                </enumeratedValues>
                        </field>
                    </fields>
                </register>
                <register>
                    <name>CECCTL1</name>
                    <description>CEC Control Register 1</description>
                    <addressOffset>0x02</addressOffset>
                    <size>8</size>
                    <access>read-write</access>
                    <resetValue>0x00</resetValue>
                    <resetMask>0xff</resetMask>
                    <fields>
                        <field>
                            <name>SFT</name>
                            <description>Signal,Free Time Data Bit Width Select</description>
                            <lsb>0</lsb>
                            <msb>1</msb>
                            <access>read-write</access>
                            <enumeratedValues>
                                </enumeratedValues>
                        </field>
                        <field>
                            <name>CESEL</name>
                            <description>Communication Complete Interrupt (INTCE) Generation Timing Select</description>
                            <lsb>2</lsb>
                            <msb>3</msb>
                            <access>read-write</access>
                            <enumeratedValues>
                                </enumeratedValues>
                        </field>
                        <field>
                            <name>STERRD</name>
                            <description>Start Bit Error Detection Select</description>
                            <lsb>4</lsb>
                            <msb>4</msb>
                            <access>read-write</access>
                            <enumeratedValues>
                                </enumeratedValues>
                        </field>
                        <field>
                            <name>BLERRD</name>
                            <description>Bus Lock Detection Select</description>
                            <lsb>5</lsb>
                            <msb>5</msb>
                            <access>read-write</access>
                            <enumeratedValues>
                                </enumeratedValues>
                        </field>
                        <field>
                            <name>CINTMK</name>
                            <description>CEC Data Interrupt (INTDA) Generation Select</description>
                            <lsb>6</lsb>
                            <msb>6</msb>
                            <access>read-write</access>
                            <enumeratedValues>
                                </enumeratedValues>
                        </field>
                        <field>
                            <name>CDFC</name>
                            <description>Digital Filter Select</description>
                            <lsb>7</lsb>
                            <msb>7</msb>
                            <access>read-write</access>
                            <enumeratedValues>
                                </enumeratedValues>
                        </field>
                    </fields>
                </register>
                <register>
                    <name>STATB</name>
                    <description>CEC Transmission Start Bit Width Setting Register</description>
                    <addressOffset>0x04</addressOffset>
                    <size>16</size>
                    <access>read-write</access>
                    <resetValue>0x0000</resetValue>
                    <resetMask>0xffff</resetMask>
                    <fields>
                        <field>
                            <name>STATB</name>
                            <description>CEC Transmission Start Bit Width Setting</description>
                            <lsb>0</lsb>
                            <msb>8</msb>
                            <access>read-write</access>
                        </field>
                    </fields>
                </register>
                <register>
                    <name>STATL</name>
                    <description>CEC Transmission Start Bit Low Width Setting Register</description>
                    <addressOffset>0x06</addressOffset>
                    <size>16</size>
                    <access>read-write</access>
                    <resetValue>0x0000</resetValue>
                    <resetMask>0xffff</resetMask>
                    <fields>
                        <field>
                            <name>STATL</name>
                            <description>CEC Transmission Start Bit Low Width Setting</description>
                            <lsb>0</lsb>
                            <msb>8</msb>
                            <access>read-write</access>
                        </field>
                    </fields>
                </register>
                <register>
                    <name>LGC0L</name>
                    <description>CEC Transmission Logical 0 Low Width Setting Register</description>
                    <addressOffset>0x08</addressOffset>
                    <size>16</size>
                    <access>read-write</access>
                    <resetValue>0x0000</resetValue>
                    <resetMask>0xffff</resetMask>
                    <fields>
                        <field>
                            <name>LGC0L</name>
                            <description>CEC Transmission Logical 0 Low Width Setting</description>
                            <lsb>0</lsb>
                            <msb>8</msb>
                            <access>read-write</access>
                        </field>
                    </fields>
                </register>
                <register>
                    <name>LGC1L</name>
                    <description>CEC Transmission Logical 1 Low Width Setting Register</description>
                    <addressOffset>0x0A</addressOffset>
                    <size>16</size>
                    <access>read-write</access>
                    <resetValue>0x0000</resetValue>
                    <resetMask>0xffff</resetMask>
                    <fields>
                        <field>
                            <name>LGC1L</name>
                            <description>CEC Transmission Logical 1 Low Width Setting</description>
                            <lsb>0</lsb>
                            <msb>8</msb>
                            <access>read-write</access>
                        </field>
                    </fields>
                </register>
                <register>
                    <name>DATB</name>
                    <description>CEC Transmission Data Bit Width Setting Register</description>
                    <addressOffset>0x0C</addressOffset>
                    <size>16</size>
                    <access>read-write</access>
                    <resetValue>0x0000</resetValue>
                    <resetMask>0xffff</resetMask>
                    <fields>
                        <field>
                            <name>DATB</name>
                            <description>CEC Transmission Data Bit Width Setting</description>
                            <lsb>0</lsb>
                            <msb>8</msb>
                            <access>read-write</access>
                        </field>
                    </fields>
                </register>
                <register>
                    <name>NOMT</name>
                    <description>CEC Reception Data Sampling Time Setting Register</description>
                    <addressOffset>0x0E</addressOffset>
                    <size>16</size>
                    <access>read-write</access>
                    <resetValue>0x0000</resetValue>
                    <resetMask>0xffff</resetMask>
                    <fields>
                        <field>
                            <name>NOMT</name>
                            <description>CEC Reception Data Sampling Time Setting, </description>
                            <lsb>0</lsb>
                            <msb>8</msb>
                            <access>read-write</access>
                        </field>
                    </fields>
                </register>
                <register>
                    <name>STATLL</name>
                    <description>CEC Reception Start Bit Minimum Low Width Setting Register</description>
                    <addressOffset>0x10</addressOffset>
                    <size>16</size>
                    <access>read-write</access>
                    <resetValue>0x0000</resetValue>
                    <resetMask>0xffff</resetMask>
                    <fields>
                        <field>
                            <name>STATLL</name>
                            <description>CEC Reception Start Bit Minimum Low Width Setting</description>
                            <lsb>0</lsb>
                            <msb>8</msb>
                            <access>read-write</access>
                        </field>
                    </fields>
                </register>
                <register>
                    <name>STATLH</name>
                    <description>CEC Reception Start Bit Maximum Low Width Setting Register</description>
                    <addressOffset>0x12</addressOffset>
                    <size>16</size>
                    <access>read-write</access>
                    <resetValue>0x0000</resetValue>
                    <resetMask>0xffff</resetMask>
                    <fields>
                        <field>
                            <name>STATLH</name>
                            <description>CEC Reception Start Bit Maximum Bit Width Setting</description>
                            <lsb>0</lsb>
                            <msb>8</msb>
                            <access>read-write</access>
                        </field>
                    </fields>
                </register>
                <register>
                    <name>STATBL</name>
                    <description>CEC Reception Start Bit Minimum Bit Width Setting Register</description>
                    <addressOffset>0x14</addressOffset>
                    <size>16</size>
                    <access>read-write</access>
                    <resetValue>0x0000</resetValue>
                    <resetMask>0xffff</resetMask>
                    <fields>
                        <field>
                            <name>STATBL</name>
                            <description>CEC Reception Start Bit Minimum Bit Width Setting</description>
                            <lsb>0</lsb>
                            <msb>8</msb>
                            <access>read-write</access>
                        </field>
                    </fields>
                </register>
                <register>
                    <name>STATBH</name>
                    <description>CEC Reception Start Bit Maximum Bit Width Setting Register</description>
                    <addressOffset>0x16</addressOffset>
                    <size>16</size>
                    <access>read-write</access>
                    <resetValue>0x0000</resetValue>
                    <resetMask>0xffff</resetMask>
                    <fields>
                        <field>
                            <name>STATBH</name>
                            <description>CEC Reception Start Bit Maximum Bit Width Setting</description>
                            <lsb>0</lsb>
                            <msb>8</msb>
                            <access>read-write</access>
                        </field>
                    </fields>
                </register>
                <register>
                    <name>LGC0LL</name>
                    <description>CEC Reception Logical 0 Minimum Low Width Setting Register</description>
                    <addressOffset>0x18</addressOffset>
                    <size>16</size>
                    <access>read-write</access>
                    <resetValue>0x0000</resetValue>
                    <resetMask>0xffff</resetMask>
                    <fields>
                        <field>
                            <name>LGC0LL</name>
                            <description>CEC Reception Logical 0 Minimum Low Width Setting</description>
                            <lsb>0</lsb>
                            <msb>8</msb>
                            <access>read-write</access>
                        </field>
                    </fields>
                </register>
                <register>
                    <name>LGC0LH</name>
                    <description>CEC Reception Logical 0 Maximum Low Width Setting Register</description>
                    <addressOffset>0x1A</addressOffset>
                    <size>16</size>
                    <access>read-write</access>
                    <resetValue>0x0000</resetValue>
                    <resetMask>0xffff</resetMask>
                    <fields>
                        <field>
                            <name>LGC0LH</name>
                            <description>CEC Reception Logical 0 Minimum Low Width Setting</description>
                            <lsb>0</lsb>
                            <msb>8</msb>
                            <access>read-write</access>
                        </field>
                    </fields>
                </register>
                <register>
                    <name>LGC1LL</name>
                    <description>CEC Reception Logical 1 Minimum Low Width Setting Register</description>
                    <addressOffset>0x1C</addressOffset>
                    <size>16</size>
                    <access>read-write</access>
                    <resetValue>0x0000</resetValue>
                    <resetMask>0xffff</resetMask>
                    <fields>
                        <field>
                            <name>LGC1LL</name>
                            <description>CEC Reception Logical 1 Minimum Low Width Setting</description>
                            <lsb>0</lsb>
                            <msb>8</msb>
                            <access>read-write</access>
                        </field>
                    </fields>
                </register>
                <register>
                    <name>LGC1LH</name>
                    <description>CEC Reception Logical 1 Maximum Low Width Setting Register</description>
                    <addressOffset>0x1E</addressOffset>
                    <size>16</size>
                    <access>read-write</access>
                    <resetValue>0x0000</resetValue>
                    <resetMask>0xffff</resetMask>
                    <fields>
                        <field>
                            <name>LGC1LH</name>
                            <description>CEC Reception Logical 1 Maximum Low Width Setting</description>
                            <lsb>0</lsb>
                            <msb>8</msb>
                            <access>read-write</access>
                        </field>
                    </fields>
                </register>
                <register>
                    <name>DATBL</name>
                    <description>CEC Reception Data Bit Minimum Bit Width Setting Register</description>
                    <addressOffset>0x20</addressOffset>
                    <size>16</size>
                    <access>read-write</access>
                    <resetValue>0x0000</resetValue>
                    <resetMask>0xffff</resetMask>
                    <fields>
                        <field>
                            <name>DATBL</name>
                            <description>CEC Reception Data Bit Minimum Bit Width Setting</description>
                            <lsb>0</lsb>
                            <msb>8</msb>
                            <access>read-write</access>
                        </field>
                    </fields>
                </register>
                <register>
                    <name>DATBH</name>
                    <description>CEC Reception Data Bit Maximum Bit Width Setting Register</description>
                    <addressOffset>0x22</addressOffset>
                    <size>16</size>
                    <access>read-write</access>
                    <resetValue>0x0000</resetValue>
                    <resetMask>0xffff</resetMask>
                    <fields>
                        <field>
                            <name>DATBH</name>
                            <description>CEC Reception Data Bit Maximum Bit Width Setting</description>
                            <lsb>0</lsb>
                            <msb>8</msb>
                            <access>read-write</access>
                        </field>
                    </fields>
                </register>
                <register>
                    <name>NOMP</name>
                    <description>CEC Data Bit Reference Width Setting Register</description>
                    <addressOffset>0x24</addressOffset>
                    <size>16</size>
                    <access>read-write</access>
                    <resetValue>0x0000</resetValue>
                    <resetMask>0xffff</resetMask>
                    <fields>
                        <field>
                            <name>NOMP</name>
                            <description>CEC Data Bit Reference Width Setting</description>
                            <lsb>0</lsb>
                            <msb>8</msb>
                            <access>read-write</access>
                        </field>
                    </fields>
                </register>
                <register>
                    <name>CECEXMD</name>
                    <description>CEC Extension Mode Register</description>
                    <addressOffset>0x28</addressOffset>
                    <size>8</size>
                    <access>read-write</access>
                    <resetValue>0x00</resetValue>
                    <resetMask>0xff</resetMask>
                    <fields>
                        <field>
                            <name>LERPLEN</name>
                            <description>Pulse Output Function Enable by Long Bit Width Error</description>
                            <lsb>4</lsb>
                            <msb>4</msb>
                            <access>read-write</access>
                            <enumeratedValues>
                                </enumeratedValues>
                        </field>
                        <field>
                            <name>RERCVEN</name>
                            <description>Start Detection Reception Restart Enable</description>
                            <lsb>5</lsb>
                            <msb>5</msb>
                            <access>read-write</access>
                            <enumeratedValues>
                                </enumeratedValues>
                        </field>
                        <field>
                            <name>RCVINTDSEL</name>
                            <description>INTDA Reception Interrupt Timing Change</description>
                            <lsb>7</lsb>
                            <msb>7</msb>
                            <access>read-write</access>
                            <enumeratedValues>
                                </enumeratedValues>
                        </field>
                    </fields>
                </register>
                <register>
                    <name>CECEXMON</name>
                    <description>CEC Extension Monitor Register</description>
                    <addressOffset>0x2A</addressOffset>
                    <size>8</size>
                    <access>read-write</access>
                    <resetValue>0x00</resetValue>
                    <resetMask>0xfe</resetMask>
                    <fields>
                        <field>
                            <name>CECLNMON</name>
                            <description>CEC Line Monitor</description>
                            <lsb>0</lsb>
                            <msb>0</msb>
                            <access>read-only</access>
                            <enumeratedValues>
                                </enumeratedValues>
                        </field>
                        <field>
                            <name>ACKF</name>
                            <description>ACK Flag</description>
                            <lsb>1</lsb>
                            <msb>1</msb>
                            <access>read-only</access>
                        </field>
                    </fields>
                </register>
                <register>
                    <name>CTXD</name>
                    <description>CEC Transmission Buffer Register</description>
                    <addressOffset>0x40</addressOffset>
                    <size>8</size>
                    <access>read-write</access>
                    <resetValue>0x00</resetValue>
                    <resetMask>0xff</resetMask>
                </register>
                <register>
                    <name>CRXD</name>
                    <description>CEC Reception Buffer Register</description>
                    <addressOffset>0x41</addressOffset>
                    <size>8</size>
                    <access>read-write</access>
                    <resetValue>0x00</resetValue>
                    <resetMask>0xff</resetMask>
                </register>
                <register>
                    <name>CECES</name>
                    <description>CEC Communication Error Status Register</description>
                    <addressOffset>0x42</addressOffset>
                    <size>8</size>
                    <access>read-write</access>
                    <resetValue>0x00</resetValue>
                    <resetMask>0xff</resetMask>
                    <fields>
                        <field>
                            <name>OERR</name>
                            <description>Overrun Error Detection Flag</description>
                            <lsb>0</lsb>
                            <msb>0</msb>
                            <access>read-only</access>
                            <enumeratedValues>
                                </enumeratedValues>
                        </field>
                        <field>
                            <name>UERR</name>
                            <description>Underrun Error Detection Flag</description>
                            <lsb>1</lsb>
                            <msb>1</msb>
                            <access>read-only</access>
                            <enumeratedValues>
                                </enumeratedValues>
                        </field>
                        <field>
                            <name>ACKERR</name>
                            <description>ACK Error Detection Flag</description>
                            <lsb>2</lsb>
                            <msb>2</msb>
                            <access>read-only</access>
                            <enumeratedValues>
                                </enumeratedValues>
                        </field>
                        <field>
                            <name>TERR</name>
                            <description>Timing Error Detection Flag</description>
                            <lsb>3</lsb>
                            <msb>3</msb>
                            <access>read-only</access>
                            <enumeratedValues>
                                </enumeratedValues>
                        </field>
                        <field>
                            <name>TXERR</name>
                            <description>Transmission Error Detection Flag</description>
                            <lsb>4</lsb>
                            <msb>4</msb>
                            <access>read-only</access>
                            <enumeratedValues>
                                </enumeratedValues>
                        </field>
                        <field>
                            <name>AERR</name>
                            <description>Arbitration Loss Detection Flag</description>
                            <lsb>5</lsb>
                            <msb>5</msb>
                            <access>read-only</access>
                            <enumeratedValues>
                                </enumeratedValues>
                        </field>
                        <field>
                            <name>BLERR</name>
                            <description>Bus Lock Error Detection Flag</description>
                            <lsb>6</lsb>
                            <msb>6</msb>
                            <access>read-only</access>
                            <enumeratedValues>
                                </enumeratedValues>
                        </field>
                    </fields>
                </register>
                <register>
                    <name>CECS</name>
                    <description>CEC Communication Status Register</description>
                    <addressOffset>0x43</addressOffset>
                    <size>8</size>
                    <access>read-write</access>
                    <resetValue>0x00</resetValue>
                    <resetMask>0xff</resetMask>
                    <fields>
                        <field>
                            <name>ADRF</name>
                            <description>Address Match Detection Flag</description>
                            <lsb>0</lsb>
                            <msb>0</msb>
                            <access>read-only</access>
                            <enumeratedValues>
                                </enumeratedValues>
                        </field>
                        <field>
                            <name>BUSST</name>
                            <description>Bus Busy Detection Flag</description>
                            <lsb>1</lsb>
                            <msb>1</msb>
                            <access>read-only</access>
                            <enumeratedValues>
                                </enumeratedValues>
                        </field>
                        <field>
                            <name>TXST</name>
                            <description>Transmission Status Flag</description>
                            <lsb>2</lsb>
                            <msb>2</msb>
                            <access>read-only</access>
                            <enumeratedValues>
                                </enumeratedValues>
                        </field>
                        <field>
                            <name>EOMF</name>
                            <description>EOM Flag</description>
                            <lsb>3</lsb>
                            <msb>3</msb>
                            <access>read-only</access>
                            <enumeratedValues>
                                </enumeratedValues>
                        </field>
                        <field>
                            <name>ITCEF</name>
                            <description>INTCE Generation Source Flag</description>
                            <lsb>4</lsb>
                            <msb>4</msb>
                            <access>read-only</access>
                            <enumeratedValues>
                                </enumeratedValues>
                        </field>
                        <field>
                            <name>SFTST</name>
                            <description>Signal,Free Time Rewrite Disable Report Flag</description>
                            <lsb>7</lsb>
                            <msb>7</msb>
                            <access>read-only</access>
                            <enumeratedValues>
                                </enumeratedValues>
                        </field>
                    </fields>
                </register>
                <register>
                    <name>CECFC</name>
                    <description>CEC Communication Error Flag Clear Trigger Register</description>
                    <addressOffset>0x44</addressOffset>
                    <size>8</size>
                    <access>read-write</access>
                    <resetValue>0x00</resetValue>
                    <resetMask>0xff</resetMask>
                    <fields>
                        <field>
                            <name>OCTRG</name>
                            <description>Overrun Error Detection Flag Clear Trigger</description>
                            <lsb>0</lsb>
                            <msb>0</msb>
                            <access>write-only</access>
                            <enumeratedValues>
                                </enumeratedValues>
                        </field>
                        <field>
                            <name>UCTRG</name>
                            <description>Underrun Error Detection Flag Clear Trigger</description>
                            <lsb>1</lsb>
                            <msb>1</msb>
                            <access>write-only</access>
                            <enumeratedValues>
                                </enumeratedValues>
                        </field>
                        <field>
                            <name>ACKCTRG</name>
                            <description>ACK Error Detection Flag Clear Trigger</description>
                            <lsb>2</lsb>
                            <msb>2</msb>
                            <access>write-only</access>
                            <enumeratedValues>
                                </enumeratedValues>
                        </field>
                        <field>
                            <name>TCTRG</name>
                            <description>Timing Error Detection Flag Clear Trigger</description>
                            <lsb>3</lsb>
                            <msb>3</msb>
                            <access>write-only</access>
                            <enumeratedValues>
                                </enumeratedValues>
                        </field>
                        <field>
                            <name>TXCTRG</name>
                            <description>Transmission Error Detection Flag Clear Trigger</description>
                            <lsb>4</lsb>
                            <msb>4</msb>
                            <access>write-only</access>
                            <enumeratedValues>
                                </enumeratedValues>
                        </field>
                        <field>
                            <name>ACTRG</name>
                            <description>Arbitration Loss Detection Flag Clear Trigger</description>
                            <lsb>5</lsb>
                            <msb>5</msb>
                            <access>write-only</access>
                            <enumeratedValues>
                                </enumeratedValues>
                        </field>
                        <field>
                            <name>BLCTRG</name>
                            <description>Bus Lock Error Detection Flag Clear Trigger</description>
                            <lsb>6</lsb>
                            <msb>6</msb>
                            <access>write-only</access>
                            <enumeratedValues>
                                </enumeratedValues>
                        </field>
                    </fields>
                </register>
                <register>
                    <name>CECCTL0</name>
                    <description>CEC Control Register 0</description>
                    <addressOffset>0x45</addressOffset>
                    <size>8</size>
                    <access>read-write</access>
                    <resetValue>0x00</resetValue>
                    <resetMask>0xff</resetMask>
                    <fields>
                        <field>
                            <name>EOM</name>
                            <description>EOM Setting</description>
                            <lsb>0</lsb>
                            <msb>0</msb>
                            <access>read-write</access>
                            <enumeratedValues>
                                </enumeratedValues>
                        </field>
                        <field>
                            <name>CECRXEN</name>
                            <description>Reception Enable Control</description>
                            <lsb>1</lsb>
                            <msb>1</msb>
                            <access>read-write</access>
                            <enumeratedValues>
                                </enumeratedValues>
                        </field>
                        <field>
                            <name>TXTRG</name>
                            <description>Transmission Start Trigger</description>
                            <lsb>2</lsb>
                            <msb>2</msb>
                            <access>write-only</access>
                            <enumeratedValues>
                                </enumeratedValues>
                        </field>
                        <field>
                            <name>CCL</name>
                            <description>CEC Clock Select</description>
                            <lsb>3</lsb>
                            <msb>5</msb>
                            <access>read-write</access>
                            <enumeratedValues>
                                </enumeratedValues>
                        </field>
                        <field>
                            <name>ACKTEN</name>
                            <description>ACK Bit Timing Error (Bit Width) Check Enable</description>
                            <lsb>6</lsb>
                            <msb>6</msb>
                            <access>read-write</access>
                            <enumeratedValues>
                                </enumeratedValues>
                        </field>
                        <field>
                            <name>CECE</name>
                            <description>CEC Operation Enable Flag</description>
                            <lsb>7</lsb>
                            <msb>7</msb>
                            <access>read-write</access>
                            <enumeratedValues>
                                </enumeratedValues>
                        </field>
                    </fields>
                </register>
            </registers>
        </peripheral>
        <peripheral>
            <name>CANFD</name>
            <description>CANFD</description>
            <baseAddress>0x400B0000</baseAddress>
            <addressBlock>
                <offset>0x00</offset>
                <size>44</size>
                <usage>registers</usage>
            </addressBlock>
            <addressBlock>
                <offset>0x84</offset>
                <size>28</size>
                <usage>registers</usage>
            </addressBlock>
            <addressBlock>
                <offset>0xAC</offset>
                <size>8</size>
                <usage>registers</usage>
            </addressBlock>
            <addressBlock>
                <offset>0xC0</offset>
                <size>120</size>
                <usage>registers</usage>
            </addressBlock>
            <addressBlock>
                <offset>0x180</offset>
                <size>24</size>
                <usage>registers</usage>
            </addressBlock>
            <addressBlock>
                <offset>0x1E0</offset>
                <size>24</size>
                <usage>registers</usage>
            </addressBlock>
            <addressBlock>
                <offset>0x240</offset>
                <size>24</size>
                <usage>registers</usage>
            </addressBlock>
            <addressBlock>
                <offset>0x2A0</offset>
                <size>40</size>
                <usage>registers</usage>
            </addressBlock>
            <addressBlock>
                <offset>0x2D0</offset>
                <size>8</size>
                <usage>registers</usage>
            </addressBlock>
            <addressBlock>
                <offset>0x2F0</offset>
                <size>8</size>
                <usage>registers</usage>
            </addressBlock>
            <addressBlock>
                <offset>0x310</offset>
                <size>8</size>
                <usage>registers</usage>
            </addressBlock>
            <addressBlock>
                <offset>0x330</offset>
                <size>8</size>
                <usage>registers</usage>
            </addressBlock>
            <addressBlock>
                <offset>0x7D0</offset>
                <size>8</size>
                <usage>registers</usage>
            </addressBlock>
            <addressBlock>
                <offset>0x7F0</offset>
                <size>8</size>
                <usage>registers</usage>
            </addressBlock>
            <addressBlock>
                <offset>0x810</offset>
                <size>8</size>
                <usage>registers</usage>
            </addressBlock>
            <addressBlock>
                <offset>0x830</offset>
                <size>8</size>
                <usage>registers</usage>
            </addressBlock>
            <addressBlock>
                <offset>0xCD0</offset>
                <size>16</size>
                <usage>registers</usage>
            </addressBlock>
            <addressBlock>
                <offset>0xD70</offset>
                <size>16</size>
                <usage>registers</usage>
            </addressBlock>
            <addressBlock>
                <offset>0xE10</offset>
                <size>16</size>
                <usage>registers</usage>
            </addressBlock>
            <addressBlock>
                <offset>0xEB0</offset>
                <size>16</size>
                <usage>registers</usage>
            </addressBlock>
            <addressBlock>
                <offset>0xF50</offset>
                <size>16</size>
                <usage>registers</usage>
            </addressBlock>
            <addressBlock>
                <offset>0x1000</offset>
                <size>8</size>
                <usage>registers</usage>
            </addressBlock>
            <addressBlock>
                <offset>0x1020</offset>
                <size>8</size>
                <usage>registers</usage>
            </addressBlock>
            <addressBlock>
                <offset>0x1040</offset>
                <size>8</size>
                <usage>registers</usage>
            </addressBlock>
            <addressBlock>
                <offset>0x1060</offset>
                <size>8</size>
                <usage>registers</usage>
            </addressBlock>
            <addressBlock>
                <offset>0x1080</offset>
                <size>8</size>
                <usage>registers</usage>
            </addressBlock>
            <addressBlock>
                <offset>0x10A0</offset>
                <size>8</size>
                <usage>registers</usage>
            </addressBlock>
            <addressBlock>
                <offset>0x10C0</offset>
                <size>8</size>
                <usage>registers</usage>
            </addressBlock>
            <addressBlock>
                <offset>0x10E0</offset>
                <size>8</size>
                <usage>registers</usage>
            </addressBlock>
            <addressBlock>
                <offset>0x1100</offset>
                <size>8</size>
                <usage>registers</usage>
            </addressBlock>
            <addressBlock>
                <offset>0x1120</offset>
                <size>8</size>
                <usage>registers</usage>
            </addressBlock>
            <addressBlock>
                <offset>0x1140</offset>
                <size>8</size>
                <usage>registers</usage>
            </addressBlock>
            <addressBlock>
                <offset>0x1160</offset>
                <size>8</size>
                <usage>registers</usage>
            </addressBlock>
            <addressBlock>
                <offset>0x1180</offset>
                <size>12</size>
                <usage>registers</usage>
            </addressBlock>
            <addressBlock>
                <offset>0x1190</offset>
                <size>16</size>
                <usage>registers</usage>
            </addressBlock>
            <addressBlock>
                <offset>0x1200</offset>
                <size>8</size>
                <usage>registers</usage>
            </addressBlock>
            <addressBlock>
                <offset>0x1220</offset>
                <size>8</size>
                <usage>registers</usage>
            </addressBlock>
            <addressBlock>
                <offset>0x1240</offset>
                <size>8</size>
                <usage>registers</usage>
            </addressBlock>
            <addressBlock>
                <offset>0x1300</offset>
                <size>4</size>
                <usage>registers</usage>
            </addressBlock>
            <addressBlock>
                <offset>0x1308</offset>
                <size>8</size>
                <usage>registers</usage>
            </addressBlock>
            <addressBlock>
                <offset>0x1314</offset>
                <size>4</size>
                <usage>registers</usage>
            </addressBlock>
            <addressBlock>
                <offset>0x131C</offset>
                <size>4</size>
                <usage>registers</usage>
            </addressBlock>
            <addressBlock>
                <offset>0x1330</offset>
                <size>8</size>
                <usage>registers</usage>
            </addressBlock>
            <addressBlock>
                <offset>0x1340</offset>
                <size>8</size>
                <usage>registers</usage>
            </addressBlock>
            <addressBlock>
                <offset>0x1350</offset>
                <size>8</size>
                <usage>registers</usage>
            </addressBlock>
            <addressBlock>
                <offset>0x1380</offset>
                <size>4</size>
                <usage>registers</usage>
            </addressBlock>
            <addressBlock>
                <offset>0x1400</offset>
                <size>92</size>
                <usage>registers</usage>
            </addressBlock>
            <addressBlock>
                <offset>0x1800</offset>
                <size>268</size>
                <usage>registers</usage>
            </addressBlock>
            <addressBlock>
                <offset>0x2000</offset>
                <size>4168</size>
                <usage>registers</usage>
            </addressBlock>
            <addressBlock>
                <offset>0x6000</offset>
                <size>1864</size>
                <usage>registers</usage>
            </addressBlock>
            <addressBlock>
                <offset>0x8000</offset>
                <size>20</size>
                <usage>registers</usage>
            </addressBlock>
            <addressBlock>
                <offset>0x8400</offset>
                <size>256</size>
                <usage>registers</usage>
            </addressBlock>
            <addressBlock>
                <offset>0x10000</offset>
                <size>1096</size>
                <usage>registers</usage>
            </addressBlock>
            <addressBlock>
                <offset>0x11000</offset>
                <size>1096</size>
                <usage>registers</usage>
            </addressBlock>
            <addressBlock>
                <offset>0x12000</offset>
                <size>1096</size>
                <usage>registers</usage>
            </addressBlock>
            <addressBlock>
                <offset>0x13000</offset>
                <size>1096</size>
                <usage>registers</usage>
            </addressBlock>
            <registers>
                <register>
                    <dim>2</dim>
                    <dimIncrement>0x10</dimIncrement>
                    <dimIndex>0-1</dimIndex>
                    <name>CFDC%sNCFG</name>
                    <description>Channel %s Nominal Bitrate Configuration Register</description>
                    <addressOffset>0x0000</addressOffset>
                    <size>32</size>
                    <access>read-write</access>
                    <resetValue>0x00000000</resetValue>
                    <resetMask>0xffffffff</resetMask>
                    <fields>
                        <field>
                            <name>NBRP</name>
                            <description>Channel Nominal Baud Rate Prescaler</description>
                            <lsb>0</lsb>
                            <msb>9</msb>
                            <access>read-write</access>
                        </field>
                        <field>
                            <name>NSJW</name>
                            <description>Resynchronization Jump Width</description>
                            <lsb>10</lsb>
                            <msb>16</msb>
                            <access>read-write</access>
                        </field>
                        <field>
                            <name>NTSEG1</name>
                            <description>Timing Segment 1</description>
                            <lsb>17</lsb>
                            <msb>24</msb>
                            <access>read-write</access>
                        </field>
                        <field>
                            <name>NTSEG2</name>
                            <description>Timing Segment 2</description>
                            <lsb>25</lsb>
                            <msb>31</msb>
                            <access>read-write</access>
                        </field>
                    </fields>
                </register>
                <register>
                    <dim>2</dim>
                    <dimIncrement>0x10</dimIncrement>
                    <dimIndex>0-1</dimIndex>
                    <name>CFDC%sCTR</name>
                    <description>Channel %s Control Registers</description>
                    <addressOffset>0x0004</addressOffset>
                    <size>32</size>
                    <access>read-write</access>
                    <resetValue>0x00000005</resetValue>
                    <resetMask>0xffffffff</resetMask>
                    <fields>
                        <field>
                            <name>CHMDC</name>
                            <description>Channel Mode Control</description>
                            <lsb>0</lsb>
                            <msb>1</msb>
                            <access>read-write</access>
                            <enumeratedValues>
                                </enumeratedValues>
                        </field>
                        <field>
                            <name>CSLPR</name>
                            <description>Channel Sleep Request</description>
                            <lsb>2</lsb>
                            <msb>2</msb>
                            <access>read-write</access>
                            <enumeratedValues>
                                </enumeratedValues>
                        </field>
                        <field>
                            <name>RTBO</name>
                            <description>Return from Bus,Off</description>
                            <lsb>3</lsb>
                            <msb>3</msb>
                            <access>read-write</access>
                            <enumeratedValues>
                                </enumeratedValues>
                        </field>
                        <field>
                            <name>BEIE</name>
                            <description>Bus Error Interrupt Enable</description>
                            <lsb>8</lsb>
                            <msb>8</msb>
                            <access>read-write</access>
                            <enumeratedValues>
                                </enumeratedValues>
                        </field>
                        <field>
                            <name>EWIE</name>
                            <description>Error Warning Interrupt Enable</description>
                            <lsb>9</lsb>
                            <msb>9</msb>
                            <access>read-write</access>
                            <enumeratedValues>
                                </enumeratedValues>
                        </field>
                        <field>
                            <name>EPIE</name>
                            <description>Error Passive Interrupt Enable</description>
                            <lsb>10</lsb>
                            <msb>10</msb>
                            <access>read-write</access>
                            <enumeratedValues>
                                </enumeratedValues>
                        </field>
                        <field>
                            <name>BOEIE</name>
                            <description>Bus,Off Entry Interrupt Enable</description>
                            <lsb>11</lsb>
                            <msb>11</msb>
                            <access>read-write</access>
                            <enumeratedValues>
                                </enumeratedValues>
                        </field>
                        <field>
                            <name>BORIE</name>
                            <description>Bus,Off Recovery Interrupt Enable</description>
                            <lsb>12</lsb>
                            <msb>12</msb>
                            <access>read-write</access>
                            <enumeratedValues>
                                </enumeratedValues>
                        </field>
                        <field>
                            <name>OLIE</name>
                            <description>Overload Interrupt Enable</description>
                            <lsb>13</lsb>
                            <msb>13</msb>
                            <access>read-write</access>
                            <enumeratedValues>
                                </enumeratedValues>
                        </field>
                        <field>
                            <name>BLIE</name>
                            <description>Bus Lock Interrupt Enable</description>
                            <lsb>14</lsb>
                            <msb>14</msb>
                            <access>read-write</access>
                            <enumeratedValues>
                                </enumeratedValues>
                        </field>
                        <field>
                            <name>ALIE</name>
                            <description>Arbitration Lost Interrupt Enable</description>
                            <lsb>15</lsb>
                            <msb>15</msb>
                            <access>read-write</access>
                            <enumeratedValues>
                                </enumeratedValues>
                        </field>
                        <field>
                            <name>TAIE</name>
                            <description>Transmission Abort Interrupt Enable</description>
                            <lsb>16</lsb>
                            <msb>16</msb>
                            <access>read-write</access>
                            <enumeratedValues>
                                </enumeratedValues>
                        </field>
                        <field>
                            <name>EOCOIE</name>
                            <description>Error Occurrence Counter Overflow Interrupt Enable</description>
                            <lsb>17</lsb>
                            <msb>17</msb>
                            <access>read-write</access>
                            <enumeratedValues>
                                </enumeratedValues>
                        </field>
                        <field>
                            <name>SOCOIE</name>
                            <description>Successful Occurrence Counter Overflow Interrupt Enable</description>
                            <lsb>18</lsb>
                            <msb>18</msb>
                            <access>read-write</access>
                            <enumeratedValues>
                                </enumeratedValues>
                        </field>
                        <field>
                            <name>TDCVFIE</name>
                            <description>Transceiver Delay Compensation Violation Interrupt Enable</description>
                            <lsb>19</lsb>
                            <msb>19</msb>
                            <access>read-write</access>
                            <enumeratedValues>
                                </enumeratedValues>
                        </field>
                        <field>
                            <name>BOM</name>
                            <description>Channel Bus,Off Mode</description>
                            <lsb>21</lsb>
                            <msb>22</msb>
                            <access>read-write</access>
                            <enumeratedValues>
                                </enumeratedValues>
                        </field>
                        <field>
                            <name>ERRD</name>
                            <description>Channel Error Display</description>
                            <lsb>23</lsb>
                            <msb>23</msb>
                            <access>read-write</access>
                            <enumeratedValues>
                                </enumeratedValues>
                        </field>
                        <field>
                            <name>CTME</name>
                            <description>Channel Test Mode Enable</description>
                            <lsb>24</lsb>
                            <msb>24</msb>
                            <access>read-write</access>
                            <enumeratedValues>
                                </enumeratedValues>
                        </field>
                        <field>
                            <name>CTMS</name>
                            <description>Channel Test Mode Select</description>
                            <lsb>25</lsb>
                            <msb>26</msb>
                            <access>read-write</access>
                            <enumeratedValues>
                                </enumeratedValues>
                        </field>
                        <field>
                            <name>CRCT</name>
                            <description>CRC Error Test</description>
                            <lsb>30</lsb>
                            <msb>30</msb>
                            <access>read-write</access>
                            <enumeratedValues>
                                </enumeratedValues>
                        </field>
                        <field>
                            <name>ROM</name>
                            <description>Restricted Operation Mode</description>
                            <lsb>31</lsb>
                            <msb>31</msb>
                            <access>read-write</access>
                            <enumeratedValues>
                                </enumeratedValues>
                        </field>
                    </fields>
                </register>
                <register>
                    <dim>2</dim>
                    <dimIncrement>0x10</dimIncrement>
                    <dimIndex>0-1</dimIndex>
                    <name>CFDC%sSTS</name>
                    <description>Channel %s Status Registers</description>
                    <addressOffset>0x0008</addressOffset>
                    <size>32</size>
                    <access>read-write</access>
                    <resetValue>0x00000005</resetValue>
                    <resetMask>0xffffffff</resetMask>
                    <fields>
                        <field>
                            <name>CRSTSTS</name>
                            <description>Channel Reset Status</description>
                            <lsb>0</lsb>
                            <msb>0</msb>
                            <access>read-only</access>
                            <enumeratedValues>
                                </enumeratedValues>
                        </field>
                        <field>
                            <name>CHLTSTS</name>
                            <description>Channel Halt Status</description>
                            <lsb>1</lsb>
                            <msb>1</msb>
                            <access>read-only</access>
                            <enumeratedValues>
                                </enumeratedValues>
                        </field>
                        <field>
                            <name>CSLPSTS</name>
                            <description>Channel Sleep Status</description>
                            <lsb>2</lsb>
                            <msb>2</msb>
                            <access>read-only</access>
                            <enumeratedValues>
                                </enumeratedValues>
                        </field>
                        <field>
                            <name>EPSTS</name>
                            <description>Channel Error Passive Status</description>
                            <lsb>3</lsb>
                            <msb>3</msb>
                            <access>read-only</access>
                            <enumeratedValues>
                                </enumeratedValues>
                        </field>
                        <field>
                            <name>BOSTS</name>
                            <description>Channel Bus,Off Status</description>
                            <lsb>4</lsb>
                            <msb>4</msb>
                            <access>read-only</access>
                            <enumeratedValues>
                                </enumeratedValues>
                        </field>
                        <field>
                            <name>TRMSTS</name>
                            <description>Channel Transmit Status</description>
                            <lsb>5</lsb>
                            <msb>5</msb>
                            <access>read-only</access>
                            <enumeratedValues>
                                </enumeratedValues>
                        </field>
                        <field>
                            <name>RECSTS</name>
                            <description>Channel Receive Status</description>
                            <lsb>6</lsb>
                            <msb>6</msb>
                            <access>read-only</access>
                            <enumeratedValues>
                                </enumeratedValues>
                        </field>
                        <field>
                            <name>COMSTS</name>
                            <description>Channel Communication Status</description>
                            <lsb>7</lsb>
                            <msb>7</msb>
                            <access>read-only</access>
                            <enumeratedValues>
                                </enumeratedValues>
                        </field>
                        <field>
                            <name>ESIF</name>
                            <description>Error State Indication Flag</description>
                            <lsb>8</lsb>
                            <msb>8</msb>
                            <access>read-write</access>
                            <enumeratedValues>
                                </enumeratedValues>
                        </field>
                        <field>
                            <name>REC</name>
                            <description>Reception Error Count</description>
                            <lsb>16</lsb>
                            <msb>23</msb>
                            <access>read-only</access>
                        </field>
                        <field>
                            <name>TEC</name>
                            <description>Transmission Error Count</description>
                            <lsb>24</lsb>
                            <msb>31</msb>
                            <access>read-only</access>
                        </field>
                    </fields>
                </register>
                <register>
                    <dim>2</dim>
                    <dimIncrement>0x10</dimIncrement>
                    <dimIndex>0-1</dimIndex>
                    <name>CFDC%sERFL</name>
                    <description>Channel %s Error Flag Registers</description>
                    <addressOffset>0x000C</addressOffset>
                    <size>32</size>
                    <access>read-write</access>
                    <resetValue>0x00000000</resetValue>
                    <resetMask>0xffffffff</resetMask>
                    <fields>
                        <field>
                            <name>BEF</name>
                            <description>Bus Error Flag</description>
                            <lsb>0</lsb>
                            <msb>0</msb>
                            <access>read-write</access>
                            <enumeratedValues>
                                </enumeratedValues>
                        </field>
                        <field>
                            <name>EWF</name>
                            <description>Error Warning Flag</description>
                            <lsb>1</lsb>
                            <msb>1</msb>
                            <access>read-write</access>
                            <enumeratedValues>
                                </enumeratedValues>
                        </field>
                        <field>
                            <name>EPF</name>
                            <description>Error Passive Flag</description>
                            <lsb>2</lsb>
                            <msb>2</msb>
                            <access>read-write</access>
                            <enumeratedValues>
                                </enumeratedValues>
                        </field>
                        <field>
                            <name>BOEF</name>
                            <description>Bus,Off Entry Flag</description>
                            <lsb>3</lsb>
                            <msb>3</msb>
                            <access>read-write</access>
                            <enumeratedValues>
                                </enumeratedValues>
                        </field>
                        <field>
                            <name>BORF</name>
                            <description>Bus,Off Recovery Flag</description>
                            <lsb>4</lsb>
                            <msb>4</msb>
                            <access>read-write</access>
                            <enumeratedValues>
                                </enumeratedValues>
                        </field>
                        <field>
                            <name>OVLF</name>
                            <description>Overload Flag</description>
                            <lsb>5</lsb>
                            <msb>5</msb>
                            <access>read-write</access>
                            <enumeratedValues>
                                </enumeratedValues>
                        </field>
                        <field>
                            <name>BLF</name>
                            <description>Bus Lock Flag</description>
                            <lsb>6</lsb>
                            <msb>6</msb>
                            <access>read-write</access>
                            <enumeratedValues>
                                </enumeratedValues>
                        </field>
                        <field>
                            <name>ALF</name>
                            <description>Arbitration Lost Flag</description>
                            <lsb>7</lsb>
                            <msb>7</msb>
                            <access>read-write</access>
                            <enumeratedValues>
                                </enumeratedValues>
                        </field>
                        <field>
                            <name>SERR</name>
                            <description>Stuff Error</description>
                            <lsb>8</lsb>
                            <msb>8</msb>
                            <access>read-write</access>
                            <enumeratedValues>
                                </enumeratedValues>
                        </field>
                        <field>
                            <name>FERR</name>
                            <description>Form Error</description>
                            <lsb>9</lsb>
                            <msb>9</msb>
                            <access>read-write</access>
                            <enumeratedValues>
                                </enumeratedValues>
                        </field>
                        <field>
                            <name>AERR</name>
                            <description>Acknowledge Error</description>
                            <lsb>10</lsb>
                            <msb>10</msb>
                            <access>read-write</access>
                            <enumeratedValues>
                                </enumeratedValues>
                        </field>
                        <field>
                            <name>CERR</name>
                            <description>CRC Error</description>
                            <lsb>11</lsb>
                            <msb>11</msb>
                            <access>read-write</access>
                            <enumeratedValues>
                                </enumeratedValues>
                        </field>
                        <field>
                            <name>B1ERR</name>
                            <description>Bit 1 Error</description>
                            <lsb>12</lsb>
                            <msb>12</msb>
                            <access>read-write</access>
                            <enumeratedValues>
                                </enumeratedValues>
                        </field>
                        <field>
                            <name>B0ERR</name>
                            <description>Bit 0 Error</description>
                            <lsb>13</lsb>
                            <msb>13</msb>
                            <access>read-write</access>
                            <enumeratedValues>
                                </enumeratedValues>
                        </field>
                        <field>
                            <name>ADERR</name>
                            <description>Acknowledge Delimiter Error</description>
                            <lsb>14</lsb>
                            <msb>14</msb>
                            <access>read-write</access>
                            <enumeratedValues>
                                </enumeratedValues>
                        </field>
                        <field>
                            <name>CRCREG</name>
                            <description>CRC Register value</description>
                            <lsb>16</lsb>
                            <msb>30</msb>
                            <access>read-only</access>
                        </field>
                    </fields>
                </register>
                <register>
                    <name>CFDGCFG</name>
                    <description>Global Configuration Register</description>
                    <addressOffset>0x0084</addressOffset>
                    <size>32</size>
                    <access>read-write</access>
                    <resetValue>0x00000000</resetValue>
                    <resetMask>0xffffffff</resetMask>
                    <fields>
                        <field>
                            <name>TPRI</name>
                            <description>Transmission Priority</description>
                            <lsb>0</lsb>
                            <msb>0</msb>
                            <access>read-write</access>
                            <enumeratedValues>
                                </enumeratedValues>
                        </field>
                        <field>
                            <name>DCE</name>
                            <description>DLC Check Enable</description>
                            <lsb>1</lsb>
                            <msb>1</msb>
                            <access>read-write</access>
                            <enumeratedValues>
                                </enumeratedValues>
                        </field>
                        <field>
                            <name>DRE</name>
                            <description>DLC Replacement Enable</description>
                            <lsb>2</lsb>
                            <msb>2</msb>
                            <access>read-write</access>
                            <enumeratedValues>
                                </enumeratedValues>
                        </field>
                        <field>
                            <name>MME</name>
                            <description>Mirror Mode Enable</description>
                            <lsb>3</lsb>
                            <msb>3</msb>
                            <access>read-write</access>
                            <enumeratedValues>
                                </enumeratedValues>
                        </field>
                        <field>
                            <name>DCS</name>
                            <description>Data Link Controller Clock Select</description>
                            <lsb>4</lsb>
                            <msb>4</msb>
                            <access>read-write</access>
                            <enumeratedValues>
                                </enumeratedValues>
                        </field>
                        <field>
                            <name>CMPOC</name>
                            <description>CAN,FD Message Payload Overflow Configuration</description>
                            <lsb>5</lsb>
                            <msb>5</msb>
                            <access>read-write</access>
                            <enumeratedValues>
                                </enumeratedValues>
                        </field>
                        <field>
                            <name>TSP</name>
                            <description>Timestamp Prescaler</description>
                            <lsb>8</lsb>
                            <msb>11</msb>
                            <access>read-write</access>
                        </field>
                        <field>
                            <name>TSSS</name>
                            <description>Timestamp Source Select</description>
                            <lsb>12</lsb>
                            <msb>12</msb>
                            <access>read-write</access>
                            <enumeratedValues>
                                </enumeratedValues>
                        </field>
                        <field>
                            <name>TSBTCS</name>
                            <description>Timestamp Bit Time Channel Select</description>
                            <lsb>13</lsb>
                            <msb>15</msb>
                            <access>read-write</access>
                            <enumeratedValues>
                                </enumeratedValues>
                        </field>
                        <field>
                            <name>ITRCP</name>
                            <description>Interval Timer Reference Clock Prescaler</description>
                            <lsb>16</lsb>
                            <msb>31</msb>
                            <access>read-write</access>
                        </field>
                    </fields>
                </register>
                <register>
                    <name>CFDGCTR</name>
                    <description>Global Control Register</description>
                    <addressOffset>0x0088</addressOffset>
                    <size>32</size>
                    <access>read-write</access>
                    <resetValue>0x00000005</resetValue>
                    <resetMask>0xffffffff</resetMask>
                    <fields>
                        <field>
                            <name>GMDC</name>
                            <description>Global Mode Control</description>
                            <lsb>0</lsb>
                            <msb>1</msb>
                            <access>read-write</access>
                            <enumeratedValues>
                                </enumeratedValues>
                        </field>
                        <field>
                            <name>GSLPR</name>
                            <description>Global Sleep Request</description>
                            <lsb>2</lsb>
                            <msb>2</msb>
                            <access>read-write</access>
                            <enumeratedValues>
                                </enumeratedValues>
                        </field>
                        <field>
                            <name>DEIE</name>
                            <description>DLC Check Interrupt Enable</description>
                            <lsb>8</lsb>
                            <msb>8</msb>
                            <access>read-write</access>
                            <enumeratedValues>
                                </enumeratedValues>
                        </field>
                        <field>
                            <name>MEIE</name>
                            <description>Message Lost Error Interrupt Enable</description>
                            <lsb>9</lsb>
                            <msb>9</msb>
                            <access>read-write</access>
                            <enumeratedValues>
                                </enumeratedValues>
                        </field>
                        <field>
                            <name>THLEIE</name>
                            <description>TX History List Entry Lost Interrupt Enable</description>
                            <lsb>10</lsb>
                            <msb>10</msb>
                            <access>read-write</access>
                            <enumeratedValues>
                                </enumeratedValues>
                        </field>
                        <field>
                            <name>CMPOFIE</name>
                            <description>CANFD Message Payload Overflow Flag Interrupt Enable</description>
                            <lsb>11</lsb>
                            <msb>11</msb>
                            <access>read-write</access>
                            <enumeratedValues>
                                </enumeratedValues>
                        </field>
                        <field>
                            <name>QMEIE</name>
                            <description>TXQ Message Lost Error Interrupt Enable</description>
                            <lsb>14</lsb>
                            <msb>14</msb>
                            <access>read-write</access>
                            <enumeratedValues>
                                </enumeratedValues>
                        </field>
                        <field>
                            <name>MOWEIE</name>
                            <description>GW FIFO Message Overwrite Error Interrupt Enable</description>
                            <lsb>15</lsb>
                            <msb>15</msb>
                            <access>read-write</access>
                            <enumeratedValues>
                                </enumeratedValues>
                        </field>
                        <field>
                            <name>TSRST</name>
                            <description>Timestamp Reset</description>
                            <lsb>16</lsb>
                            <msb>16</msb>
                            <access>read-write</access>
                            <enumeratedValues>
                                </enumeratedValues>
                        </field>
                    </fields>
                </register>
                <register>
                    <name>CFDGSTS</name>
                    <description>Global Status Register</description>
                    <addressOffset>0x008C</addressOffset>
                    <size>32</size>
                    <access>read-only</access>
                    <resetValue>0x0000000d</resetValue>
                    <resetMask>0xffffffff</resetMask>
                    <fields>
                        <field>
                            <name>GRSTSTS</name>
                            <description>Global Reset Status</description>
                            <lsb>0</lsb>
                            <msb>0</msb>
                            <access>read-only</access>
                            <enumeratedValues>
                                </enumeratedValues>
                        </field>
                        <field>
                            <name>GHLTSTS</name>
                            <description>Global Halt Status</description>
                            <lsb>1</lsb>
                            <msb>1</msb>
                            <access>read-only</access>
                            <enumeratedValues>
                                </enumeratedValues>
                        </field>
                        <field>
                            <name>GSLPSTS</name>
                            <description>Global Sleep Status</description>
                            <lsb>2</lsb>
                            <msb>2</msb>
                            <access>read-only</access>
                            <enumeratedValues>
                                </enumeratedValues>
                        </field>
                        <field>
                            <name>GRAMINIT</name>
                            <description>Global RAM Initialization</description>
                            <lsb>3</lsb>
                            <msb>3</msb>
                            <access>read-only</access>
                            <enumeratedValues>
                                </enumeratedValues>
                        </field>
                    </fields>
                </register>
                <register>
                    <name>CFDGERFL</name>
                    <description>Global Error Flag Register</description>
                    <addressOffset>0x0090</addressOffset>
                    <size>32</size>
                    <access>read-write</access>
                    <resetValue>0x00000000</resetValue>
                    <resetMask>0xffffffff</resetMask>
                    <fields>
                        <field>
                            <name>DEF</name>
                            <description>DLC Error Flag</description>
                            <lsb>0</lsb>
                            <msb>0</msb>
                            <access>read-write</access>
                            <enumeratedValues>
                                </enumeratedValues>
                        </field>
                        <field>
                            <name>MES</name>
                            <description>Message Lost Error Status</description>
                            <lsb>1</lsb>
                            <msb>1</msb>
                            <access>read-only</access>
                            <enumeratedValues>
                                </enumeratedValues>
                        </field>
                        <field>
                            <name>THLES</name>
                            <description>TX History List Entry Lost Error Status</description>
                            <lsb>2</lsb>
                            <msb>2</msb>
                            <access>read-only</access>
                            <enumeratedValues>
                                </enumeratedValues>
                        </field>
                        <field>
                            <name>CMPOF</name>
                            <description>CANFD Message Payload Overflow Flag</description>
                            <lsb>3</lsb>
                            <msb>3</msb>
                            <access>read-write</access>
                            <enumeratedValues>
                                </enumeratedValues>
                        </field>
                        <field>
                            <name>QMES</name>
                            <description>TXQ Message Lost Error Status</description>
                            <lsb>6</lsb>
                            <msb>6</msb>
                            <access>read-only</access>
                            <enumeratedValues>
                                </enumeratedValues>
                        </field>
                        <field>
                            <name>EEF0</name>
                            <description>ECC Error Flag for Channel 0</description>
                            <lsb>16</lsb>
                            <msb>16</msb>
                            <access>read-write</access>
                            <enumeratedValues>
                                </enumeratedValues>
                        </field>
                        <field>
                            <name>EEF1</name>
                            <description>ECC Error Flag for Channel 1</description>
                            <lsb>17</lsb>
                            <msb>17</msb>
                            <access>read-write</access>
                            <enumeratedValues>
                                </enumeratedValues>
                        </field>
                    </fields>
                </register>
                <register>
                    <name>CFDGTSC</name>
                    <description>Global Timestamp Counter Register</description>
                    <addressOffset>0x0094</addressOffset>
                    <size>32</size>
                    <access>read-only</access>
                    <resetValue>0x00000000</resetValue>
                    <resetMask>0xffffffff</resetMask>
                    <fields>
                        <field>
                            <name>TS</name>
                            <description>Timestamp value</description>
                            <lsb>0</lsb>
                            <msb>15</msb>
                            <access>read-only</access>
                        </field>
                    </fields>
                </register>
                <register>
                    <name>CFDGAFLECTR</name>
                    <description>Global Acceptance Filter List Entry Control Register</description>
                    <addressOffset>0x0098</addressOffset>
                    <size>32</size>
                    <access>read-write</access>
                    <resetValue>0x00000000</resetValue>
                    <resetMask>0xffffffff</resetMask>
                    <fields>
                        <field>
                            <name>AFLPN</name>
                            <description>Acceptance Filter List Page Number</description>
                            <lsb>0</lsb>
                            <msb>3</msb>
                            <access>read-write</access>
                        </field>
                        <field>
                            <name>AFLDAE</name>
                            <description>Acceptance Filter List Data Access Enable</description>
                            <lsb>8</lsb>
                            <msb>8</msb>
                            <access>read-write</access>
                            <enumeratedValues>
                                </enumeratedValues>
                        </field>
                    </fields>
                </register>
                <register>
                    <name>CFDGAFLCFG0</name>
                    <description>Global Acceptance Filter List Configuration Register 0</description>
                    <addressOffset>0x009C</addressOffset>
                    <size>32</size>
                    <access>read-write</access>
                    <resetValue>0x00000000</resetValue>
                    <resetMask>0xffffffff</resetMask>
                    <fields>
                        <field>
                            <name>RNC1</name>
                            <description>Rule Number for Channel 1</description>
                            <lsb>0</lsb>
                            <msb>8</msb>
                            <access>read-write</access>
                        </field>
                        <field>
                            <name>RNC0</name>
                            <description>Rule Number for Channel 0</description>
                            <lsb>16</lsb>
                            <msb>24</msb>
                            <access>read-write</access>
                        </field>
                    </fields>
                </register>
                <register>
                    <name>CFDRMNB</name>
                    <description>RX Message Buffer Number Register</description>
                    <addressOffset>0x00AC</addressOffset>
                    <size>32</size>
                    <access>read-write</access>
                    <resetValue>0x00000000</resetValue>
                    <resetMask>0xffffffff</resetMask>
                    <fields>
                        <field>
                            <name>NRXMB</name>
                            <description>Number of RX Message Buffers</description>
                            <lsb>0</lsb>
                            <msb>7</msb>
                            <access>read-write</access>
                        </field>
                        <field>
                            <name>RMPLS</name>
                            <description>Reception Message Buffer Payload Data Size</description>
                            <lsb>8</lsb>
                            <msb>10</msb>
                            <access>read-write</access>
                            <enumeratedValues>
                                </enumeratedValues>
                        </field>
                    </fields>
                </register>
                <register>
                    <name>CFDRMND0</name>
                    <description>RX Message Buffer New Data Register 0</description>
                    <addressOffset>0x00B0</addressOffset>
                    <size>32</size>
                    <access>read-write</access>
                    <resetValue>0x00000000</resetValue>
                    <resetMask>0xffffffff</resetMask>
                    <fields>
                        <field>
                            <name>RMNS</name>
                            <description>RX Message Buffer New Data Status</description>
                            <lsb>0</lsb>
                            <msb>31</msb>
                            <access>read-write</access>
                            <enumeratedValues>
                                </enumeratedValues>
                        </field>
                    </fields>
                </register>
                <register>
                    <dim>8</dim>
                    <dimIncrement>0x04</dimIncrement>
                    <dimIndex>0-7</dimIndex>
                    <name>CFDRFCC%s</name>
                    <description>RX FIFO Configuration/Control Registers %s</description>
                    <addressOffset>0x00C0</addressOffset>
                    <size>32</size>
                    <access>read-write</access>
                    <resetValue>0x00000000</resetValue>
                    <resetMask>0xffffffff</resetMask>
                    <fields>
                        <field>
                            <name>RFE</name>
                            <description>RX FIFO Enable</description>
                            <lsb>0</lsb>
                            <msb>0</msb>
                            <access>read-write</access>
                            <enumeratedValues>
                                </enumeratedValues>
                        </field>
                        <field>
                            <name>RFIE</name>
                            <description>RX FIFO Interrupt Enable</description>
                            <lsb>1</lsb>
                            <msb>1</msb>
                            <access>read-write</access>
                            <enumeratedValues>
                                </enumeratedValues>
                        </field>
                        <field>
                            <name>RFPLS</name>
                            <description>Rx FIFO Payload Data Size Configuration</description>
                            <lsb>4</lsb>
                            <msb>6</msb>
                            <access>read-write</access>
                            <enumeratedValues>
                                </enumeratedValues>
                        </field>
                        <field>
                            <name>RFDC</name>
                            <description>RX FIFO Depth Configuration</description>
                            <lsb>8</lsb>
                            <msb>10</msb>
                            <access>read-write</access>
                            <enumeratedValues>
                                </enumeratedValues>
                        </field>
                        <field>
                            <name>RFIM</name>
                            <description>RX FIFO Interrupt Mode</description>
                            <lsb>12</lsb>
                            <msb>12</msb>
                            <access>read-write</access>
                            <enumeratedValues>
                                </enumeratedValues>
                        </field>
                        <field>
                            <name>RFIGCV</name>
                            <description>RX FIFO Interrupt Generation Counter Value</description>
                            <lsb>13</lsb>
                            <msb>15</msb>
                            <access>read-write</access>
                            <enumeratedValues>
                                </enumeratedValues>
                        </field>
                        <field>
                            <name>RFFIE</name>
                            <description>RX FIFO Full Interrupt Enable</description>
                            <lsb>16</lsb>
                            <msb>16</msb>
                            <access>read-write</access>
                            <enumeratedValues>
                                </enumeratedValues>
                        </field>
                    </fields>
                </register>
                <register>
                    <dim>8</dim>
                    <dimIncrement>0x04</dimIncrement>
                    <dimIndex>0-7</dimIndex>
                    <name>CFDRFSTS%s</name>
                    <description>RX FIFO Status Registers %s</description>
                    <addressOffset>0x00E0</addressOffset>
                    <size>32</size>
                    <access>read-write</access>
                    <resetValue>0x00000001</resetValue>
                    <resetMask>0xffffffff</resetMask>
                    <fields>
                        <field>
                            <name>RFEMP</name>
                            <description>RX FIFO Empty</description>
                            <lsb>0</lsb>
                            <msb>0</msb>
                            <access>read-only</access>
                            <enumeratedValues>
                                </enumeratedValues>
                        </field>
                        <field>
                            <name>RFFLL</name>
                            <description>RX FIFO Full</description>
                            <lsb>1</lsb>
                            <msb>1</msb>
                            <access>read-only</access>
                            <enumeratedValues>
                                </enumeratedValues>
                        </field>
                        <field>
                            <name>RFMLT</name>
                            <description>RX FIFO Message Lost</description>
                            <lsb>2</lsb>
                            <msb>2</msb>
                            <access>read-write</access>
                            <enumeratedValues>
                                </enumeratedValues>
                        </field>
                        <field>
                            <name>RFIF</name>
                            <description>RX FIFO Interrupt Flag</description>
                            <lsb>3</lsb>
                            <msb>3</msb>
                            <access>read-write</access>
                            <enumeratedValues>
                                </enumeratedValues>
                        </field>
                        <field>
                            <name>RFMC</name>
                            <description>RX FIFO Message Count</description>
                            <lsb>8</lsb>
                            <msb>15</msb>
                            <access>read-only</access>
                        </field>
                        <field>
                            <name>RFFIF</name>
                            <description>RX FIFO Full Interrupt Flag</description>
                            <lsb>16</lsb>
                            <msb>16</msb>
                            <access>read-write</access>
                            <enumeratedValues>
                                </enumeratedValues>
                        </field>
                    </fields>
                </register>
                <register>
                    <dim>8</dim>
                    <dimIncrement>0x04</dimIncrement>
                    <dimIndex>0-7</dimIndex>
                    <name>CFDRFPCTR%s</name>
                    <description>RX FIFO Pointer Control Registers %s</description>
                    <addressOffset>0x0100</addressOffset>
                    <size>32</size>
                    <access>read-write</access>
                    <resetValue>0x00000000</resetValue>
                    <resetMask>0xffffffff</resetMask>
                    <fields>
                        <field>
                            <name>RFPC</name>
                            <description>RX FIFO Pointer Control</description>
                            <lsb>0</lsb>
                            <msb>7</msb>
                            <access>write-only</access>
                        </field>
                    </fields>
                </register>
                <register>
                    <dim>6</dim>
                    <dimIncrement>0x04</dimIncrement>
                    <dimIndex>0-5</dimIndex>
                    <name>CFDCFCC%s</name>
                    <description>Common FIFO Configuration/Control Registers %s</description>
                    <addressOffset>0x0120</addressOffset>
                    <size>32</size>
                    <access>read-write</access>
                    <resetValue>0x00000000</resetValue>
                    <resetMask>0xffffffff</resetMask>
                    <fields>
                        <field>
                            <name>CFE</name>
                            <description>Common FIFO Enable</description>
                            <lsb>0</lsb>
                            <msb>0</msb>
                            <access>read-write</access>
                            <enumeratedValues>
                                </enumeratedValues>
                        </field>
                        <field>
                            <name>CFRXIE</name>
                            <description>Common FIFO RX Interrupt Enable</description>
                            <lsb>1</lsb>
                            <msb>1</msb>
                            <access>read-write</access>
                            <enumeratedValues>
                                </enumeratedValues>
                        </field>
                        <field>
                            <name>CFTXIE</name>
                            <description>Common FIFO TX Interrupt Enable</description>
                            <lsb>2</lsb>
                            <msb>2</msb>
                            <access>read-write</access>
                            <enumeratedValues>
                                </enumeratedValues>
                        </field>
                        <field>
                            <name>CFPLS</name>
                            <description>Common FIFO Payload Data Size Configuration</description>
                            <lsb>4</lsb>
                            <msb>6</msb>
                            <access>read-write</access>
                            <enumeratedValues>
                                </enumeratedValues>
                        </field>
                        <field>
                            <name>CFM</name>
                            <description>Common FIFO Mode</description>
                            <lsb>8</lsb>
                            <msb>9</msb>
                            <access>read-write</access>
                            <enumeratedValues>
                                </enumeratedValues>
                        </field>
                        <field>
                            <name>CFITSS</name>
                            <description>Common FIFO Interval Timer Source Select</description>
                            <lsb>10</lsb>
                            <msb>10</msb>
                            <access>read-write</access>
                            <enumeratedValues>
                                </enumeratedValues>
                        </field>
                        <field>
                            <name>CFITR</name>
                            <description>Common FIFO Interval Timer Resolution</description>
                            <lsb>11</lsb>
                            <msb>11</msb>
                            <access>read-write</access>
                            <enumeratedValues>
                                </enumeratedValues>
                        </field>
                        <field>
                            <name>CFIM</name>
                            <description>Common FIFO Interrupt Mode</description>
                            <lsb>12</lsb>
                            <msb>12</msb>
                            <access>read-write</access>
                            <enumeratedValues>
                                </enumeratedValues>
                        </field>
                        <field>
                            <name>CFIGCV</name>
                            <description>Common FIFO Interrupt Generation Counter Value</description>
                            <lsb>13</lsb>
                            <msb>15</msb>
                            <access>read-write</access>
                            <enumeratedValues>
                                </enumeratedValues>
                        </field>
                        <field>
                            <name>CFTML</name>
                            <description>Common FIFO TX Message Buffer Link</description>
                            <lsb>16</lsb>
                            <msb>20</msb>
                            <access>read-write</access>
                        </field>
                        <field>
                            <name>CFDC</name>
                            <description>Common FIFO Depth Configuration</description>
                            <lsb>21</lsb>
                            <msb>23</msb>
                            <access>read-write</access>
                            <enumeratedValues>
                                </enumeratedValues>
                        </field>
                        <field>
                            <name>CFITT</name>
                            <description>Common FIFO Interval Transmission Time</description>
                            <lsb>24</lsb>
                            <msb>31</msb>
                            <access>read-write</access>
                        </field>
                    </fields>
                </register>
                <register>
                    <dim>6</dim>
                    <dimIncrement>0x04</dimIncrement>
                    <dimIndex>0-5</dimIndex>
                    <name>CFDCFCCE%s</name>
                    <description>Common FIFO Configuration/Control Enhancement Registers %s</description>
                    <addressOffset>0x0180</addressOffset>
                    <size>32</size>
                    <access>read-write</access>
                    <resetValue>0x00000000</resetValue>
                    <resetMask>0xffffffff</resetMask>
                    <fields>
                        <field>
                            <name>CFFIE</name>
                            <description>Common FIFO Full Interrupt Enable</description>
                            <lsb>0</lsb>
                            <msb>0</msb>
                            <access>read-write</access>
                            <enumeratedValues>
                                </enumeratedValues>
                        </field>
                        <field>
                            <name>CFOFRXIE</name>
                            <description>Common FIFO One Frame Reception Interrupt Enable</description>
                            <lsb>1</lsb>
                            <msb>1</msb>
                            <access>read-write</access>
                            <enumeratedValues>
                                </enumeratedValues>
                        </field>
                        <field>
                            <name>CFOFTXIE</name>
                            <description>Common FIFO One Frame Transmission Interrupt Enable</description>
                            <lsb>2</lsb>
                            <msb>2</msb>
                            <access>read-write</access>
                            <enumeratedValues>
                                </enumeratedValues>
                        </field>
                        <field>
                            <name>CFMOWM</name>
                            <description>Common FIFO Message Overwrite Mode</description>
                            <lsb>8</lsb>
                            <msb>8</msb>
                            <access>read-write</access>
                            <enumeratedValues>
                                </enumeratedValues>
                        </field>
                        <field>
                            <name>CFBME</name>
                            <description>Common FIFO Buffering Mode Enable</description>
                            <lsb>16</lsb>
                            <msb>16</msb>
                            <access>read-write</access>
                            <enumeratedValues>
                                </enumeratedValues>
                        </field>
                    </fields>
                </register>
                <register>
                    <dim>6</dim>
                    <dimIncrement>0x04</dimIncrement>
                    <dimIndex>0-5</dimIndex>
                    <name>CFDCFSTS%s</name>
                    <description>Common FIFO Status Registers %s</description>
                    <addressOffset>0x01E0</addressOffset>
                    <size>32</size>
                    <access>read-write</access>
                    <resetValue>0x00000001</resetValue>
                    <resetMask>0xffffffff</resetMask>
                    <fields>
                        <field>
                            <name>CFEMP</name>
                            <description>Common FIFO Empty</description>
                            <lsb>0</lsb>
                            <msb>0</msb>
                            <access>read-only</access>
                            <enumeratedValues>
                                </enumeratedValues>
                        </field>
                        <field>
                            <name>CFFLL</name>
                            <description>Common FIFO Full</description>
                            <lsb>1</lsb>
                            <msb>1</msb>
                            <access>read-only</access>
                            <enumeratedValues>
                                </enumeratedValues>
                        </field>
                        <field>
                            <name>CFMLT</name>
                            <description>Common FIFO Message Lost</description>
                            <lsb>2</lsb>
                            <msb>2</msb>
                            <access>read-write</access>
                            <enumeratedValues>
                                </enumeratedValues>
                        </field>
                        <field>
                            <name>CFRXIF</name>
                            <description>Common RX FIFO Interrupt Flag</description>
                            <lsb>3</lsb>
                            <msb>3</msb>
                            <access>read-write</access>
                            <enumeratedValues>
                                </enumeratedValues>
                        </field>
                        <field>
                            <name>CFTXIF</name>
                            <description>Common TX FIFO Interrupt Flag</description>
                            <lsb>4</lsb>
                            <msb>4</msb>
                            <access>read-write</access>
                            <enumeratedValues>
                                </enumeratedValues>
                        </field>
                        <field>
                            <name>CFMC</name>
                            <description>Common FIFO Message Count</description>
                            <lsb>8</lsb>
                            <msb>15</msb>
                            <access>read-only</access>
                        </field>
                        <field>
                            <name>CFFIF</name>
                            <description>Common FIFO Full Interrupt Flag</description>
                            <lsb>16</lsb>
                            <msb>16</msb>
                            <access>read-write</access>
                            <enumeratedValues>
                                </enumeratedValues>
                        </field>
                        <field>
                            <name>CFOFRXIF</name>
                            <description>Common FIFO One Frame Reception Interrupt Flag</description>
                            <lsb>17</lsb>
                            <msb>17</msb>
                            <access>read-write</access>
                        </field>
                        <field>
                            <name>CFOFTXIF</name>
                            <description>Common FIFO One Frame Transmission Interrupt Flag</description>
                            <lsb>18</lsb>
                            <msb>18</msb>
                            <access>read-write</access>
                        </field>
                        <field>
                            <name>CFMOW</name>
                            <description>Common FIFO Message Overwrite</description>
                            <lsb>24</lsb>
                            <msb>24</msb>
                            <access>read-write</access>
                            <enumeratedValues>
                                </enumeratedValues>
                        </field>
                    </fields>
                </register>
                <register>
                    <dim>6</dim>
                    <dimIncrement>0x04</dimIncrement>
                    <dimIndex>0-5</dimIndex>
                    <name>CFDCFPCTR%s</name>
                    <description>Common FIFO Pointer Control Registers %s</description>
                    <addressOffset>0x0240</addressOffset>
                    <size>32</size>
                    <access>read-write</access>
                    <resetValue>0x00000000</resetValue>
                    <resetMask>0xffffffff</resetMask>
                    <fields>
                        <field>
                            <name>CFPC</name>
                            <description>Common FIFO Pointer Control</description>
                            <lsb>0</lsb>
                            <msb>7</msb>
                            <access>write-only</access>
                        </field>
                    </fields>
                </register>
                <register>
                    <name>CFDFESTS</name>
                    <description>FIFO Empty Status Register</description>
                    <addressOffset>0x02A0</addressOffset>
                    <size>32</size>
                    <access>read-only</access>
                    <resetValue>0x00003fff</resetValue>
                    <resetMask>0xffffffff</resetMask>
                    <fields>
                        <field>
                            <name>RFXEMP</name>
                            <description>RX FIFO Empty Status</description>
                            <lsb>0</lsb>
                            <msb>7</msb>
                            <access>read-only</access>
                            <enumeratedValues>
                                </enumeratedValues>
                        </field>
                        <field>
                            <name>CFXEMP</name>
                            <description>Common FIFO Empty Status</description>
                            <lsb>8</lsb>
                            <msb>13</msb>
                            <access>read-only</access>
                            <enumeratedValues>
                                </enumeratedValues>
                        </field>
                    </fields>
                </register>
                <register>
                    <name>CFDFFSTS</name>
                    <description>FIFO Full Status Register</description>
                    <addressOffset>0x02A4</addressOffset>
                    <size>32</size>
                    <access>read-only</access>
                    <resetValue>0x00000000</resetValue>
                    <resetMask>0xffffffff</resetMask>
                    <fields>
                        <field>
                            <name>RFXFLL</name>
                            <description>RX FIFO Full Status</description>
                            <lsb>0</lsb>
                            <msb>7</msb>
                            <access>read-only</access>
                            <enumeratedValues>
                                </enumeratedValues>
                        </field>
                        <field>
                            <name>CFXFLL</name>
                            <description>Common FIFO Full Status</description>
                            <lsb>8</lsb>
                            <msb>13</msb>
                            <access>read-only</access>
                            <enumeratedValues>
                                </enumeratedValues>
                        </field>
                    </fields>
                </register>
                <register>
                    <name>CFDFMSTS</name>
                    <description>FIFO Message Lost Status Register</description>
                    <addressOffset>0x02A8</addressOffset>
                    <size>32</size>
                    <access>read-only</access>
                    <resetValue>0x00000000</resetValue>
                    <resetMask>0xffffffff</resetMask>
                    <fields>
                        <field>
                            <name>RFXMLT</name>
                            <description>RX FIFO Message Lost Status</description>
                            <lsb>0</lsb>
                            <msb>7</msb>
                            <access>read-only</access>
                            <enumeratedValues>
                                </enumeratedValues>
                        </field>
                        <field>
                            <name>CFXMLT</name>
                            <description>Common FIFO Message Lost Status</description>
                            <lsb>8</lsb>
                            <msb>13</msb>
                            <access>read-only</access>
                            <enumeratedValues>
                                </enumeratedValues>
                        </field>
                    </fields>
                </register>
                <register>
                    <name>CFDRFISTS</name>
                    <description>RX FIFO Interrupt Flag Status Register</description>
                    <addressOffset>0x02AC</addressOffset>
                    <size>32</size>
                    <access>read-write</access>
                    <resetValue>0x00000000</resetValue>
                    <resetMask>0xffffffff</resetMask>
                    <fields>
                        <field>
                            <name>RFXIF</name>
                            <description>RX FIFO[x] Interrupt Flag Status</description>
                            <lsb>0</lsb>
                            <msb>7</msb>
                            <access>read-only</access>
                            <enumeratedValues>
                                </enumeratedValues>
                        </field>
                        <field>
                            <name>RFXFFLL</name>
                            <description>RX FIFO[x] Interrupt Full Flag Status</description>
                            <lsb>16</lsb>
                            <msb>23</msb>
                            <access>read-only</access>
                            <enumeratedValues>
                                </enumeratedValues>
                        </field>
                    </fields>
                </register>
                <register>
                    <name>CFDCFRISTS</name>
                    <description>Common FIFO RX Interrupt Flag Status Register</description>
                    <addressOffset>0x02B0</addressOffset>
                    <size>32</size>
                    <access>read-write</access>
                    <resetValue>0x00000000</resetValue>
                    <resetMask>0xffffffff</resetMask>
                    <fields>
                        <field>
                            <name>CFXRXIF</name>
                            <description>Common FIFO RX Interrupt Flag Status</description>
                            <lsb>0</lsb>
                            <msb>5</msb>
                            <access>read-only</access>
                            <enumeratedValues>
                                </enumeratedValues>
                        </field>
                    </fields>
                </register>
                <register>
                    <name>CFDCFTISTS</name>
                    <description>Common FIFO TX Interrupt Flag Status Register</description>
                    <addressOffset>0x02B4</addressOffset>
                    <size>32</size>
                    <access>read-write</access>
                    <resetValue>0x00000000</resetValue>
                    <resetMask>0xffffffff</resetMask>
                    <fields>
                        <field>
                            <name>CFXTXIF</name>
                            <description>Common FIFO [x] TX Interrupt Flag Status</description>
                            <lsb>0</lsb>
                            <msb>5</msb>
                            <access>read-only</access>
                            <enumeratedValues>
                                </enumeratedValues>
                        </field>
                    </fields>
                </register>
                <register>
                    <name>CFDCFOFRISTS</name>
                    <description>Common FIFO One Frame RX Interrupt Flag Status Register</description>
                    <addressOffset>0x02B8</addressOffset>
                    <size>32</size>
                    <access>read-only</access>
                    <resetValue>0x00000000</resetValue>
                    <resetMask>0xffffffff</resetMask>
                    <fields>
                        <field>
                            <name>CFXOFRXIF</name>
                            <description>Common FIFO One Frame RX Interrupt Flag Status</description>
                            <lsb>0</lsb>
                            <msb>5</msb>
                            <access>read-only</access>
                            <enumeratedValues>
                                </enumeratedValues>
                        </field>
                    </fields>
                </register>
                <register>
                    <name>CFDCFOFTISTS</name>
                    <description>Common FIFO One Frame TX Interrupt Flag Status Register</description>
                    <addressOffset>0x02BC</addressOffset>
                    <size>32</size>
                    <access>read-only</access>
                    <resetValue>0x00000000</resetValue>
                    <resetMask>0xffffffff</resetMask>
                    <fields>
                        <field>
                            <name>CFXOFTXIF</name>
                            <description>Common FIFO One Frame TX Interrupt Flag Status</description>
                            <lsb>0</lsb>
                            <msb>5</msb>
                            <access>read-only</access>
                            <enumeratedValues>
                                </enumeratedValues>
                        </field>
                    </fields>
                </register>
                <register>
                    <name>CFDCFMOWSTS</name>
                    <description>Common FIFO Message Over Write Status Register</description>
                    <addressOffset>0x02C0</addressOffset>
                    <size>32</size>
                    <access>read-only</access>
                    <resetValue>0x00000000</resetValue>
                    <resetMask>0xffffffff</resetMask>
                    <fields>
                        <field>
                            <name>CFXMOW</name>
                            <description>Common FIFO Massage Overwrite Status</description>
                            <lsb>0</lsb>
                            <msb>5</msb>
                            <access>read-only</access>
                            <enumeratedValues>
                                </enumeratedValues>
                        </field>
                    </fields>
                </register>
                <register>
                    <name>CFDFFFSTS</name>
                    <description>FIFO FDC Full Status Register</description>
                    <addressOffset>0x02C4</addressOffset>
                    <size>32</size>
                    <access>read-only</access>
                    <resetValue>0x00000000</resetValue>
                    <resetMask>0xffffffff</resetMask>
                    <fields>
                        <field>
                            <name>RFXFFLL</name>
                            <description>RX FIFO FDC Level Full Status</description>
                            <lsb>0</lsb>
                            <msb>7</msb>
                            <access>read-only</access>
                            <enumeratedValues>
                                </enumeratedValues>
                        </field>
                        <field>
                            <name>CFXFFLL</name>
                            <description>COMMON FIFO FDC Level Full Status</description>
                            <lsb>8</lsb>
                            <msb>13</msb>
                            <access>read-only</access>
                            <enumeratedValues>
                                </enumeratedValues>
                        </field>
                    </fields>
                </register>
                <register>
                    <dim>8</dim>
                    <dimIncrement>0x01</dimIncrement>
                    <dimIndex>0-7</dimIndex>
                    <name>CFDTMC%s</name>
                    <description>TX Message Buffer Control Registers %s</description>
                    <addressOffset>0x02D0</addressOffset>
                    <size>8</size>
                    <access>read-write</access>
                    <resetValue>0x00</resetValue>
                    <resetMask>0xff</resetMask>
                    <fields>
                        <field>
                            <name>TMTR</name>
                            <description>TX Message Buffer Transmission Request</description>
                            <lsb>0</lsb>
                            <msb>0</msb>
                            <access>read-write</access>
                            <enumeratedValues>
                                </enumeratedValues>
                        </field>
                        <field>
                            <name>TMTAR</name>
                            <description>TX Message Buffer Transmission Abort Request</description>
                            <lsb>1</lsb>
                            <msb>1</msb>
                            <access>read-write</access>
                            <enumeratedValues>
                                </enumeratedValues>
                        </field>
                        <field>
                            <name>TMOM</name>
                            <description>TX Message Buffer One,shot Mode</description>
                            <lsb>2</lsb>
                            <msb>2</msb>
                            <access>read-write</access>
                            <enumeratedValues>
                                </enumeratedValues>
                        </field>
                    </fields>
                </register>
                <register>
                    <dim>8</dim>
                    <dimIncrement>0x01</dimIncrement>
                    <dimIndex>32-39</dimIndex>
                    <name>CFDTMC%s_1</name>
                    <description>TX Message Buffer Control Registers %s</description>
                    <addressOffset>0x02F0</addressOffset>
                    <size>8</size>
                    <access>read-write</access>
                    <resetValue>0x00</resetValue>
                    <resetMask>0xff</resetMask>
                    <fields>
                        <field>
                            <name>TMTR</name>
                            <description>TX Message Buffer Transmission Request</description>
                            <lsb>0</lsb>
                            <msb>0</msb>
                            <access>read-write</access>
                            <enumeratedValues>
                                </enumeratedValues>
                        </field>
                        <field>
                            <name>TMTAR</name>
                            <description>TX Message Buffer Transmission Abort Request</description>
                            <lsb>1</lsb>
                            <msb>1</msb>
                            <access>read-write</access>
                            <enumeratedValues>
                                </enumeratedValues>
                        </field>
                        <field>
                            <name>TMOM</name>
                            <description>TX Message Buffer One,shot Mode</description>
                            <lsb>2</lsb>
                            <msb>2</msb>
                            <access>read-write</access>
                            <enumeratedValues>
                                </enumeratedValues>
                        </field>
                    </fields>
                </register>
                <register>
                    <dim>8</dim>
                    <dimIncrement>0x01</dimIncrement>
                    <dimIndex>64-71</dimIndex>
                    <name>CFDTMC%s_2</name>
                    <description>TX Message Buffer Control Registers %s</description>
                    <addressOffset>0x0310</addressOffset>
                    <size>8</size>
                    <access>read-write</access>
                    <resetValue>0x00</resetValue>
                    <resetMask>0xff</resetMask>
                    <fields>
                        <field>
                            <name>TMTR</name>
                            <description>TX Message Buffer Transmission Request</description>
                            <lsb>0</lsb>
                            <msb>0</msb>
                            <access>read-write</access>
                            <enumeratedValues>
                                </enumeratedValues>
                        </field>
                        <field>
                            <name>TMTAR</name>
                            <description>TX Message Buffer Transmission Abort Request</description>
                            <lsb>1</lsb>
                            <msb>1</msb>
                            <access>read-write</access>
                            <enumeratedValues>
                                </enumeratedValues>
                        </field>
                        <field>
                            <name>TMOM</name>
                            <description>TX Message Buffer One,shot Mode</description>
                            <lsb>2</lsb>
                            <msb>2</msb>
                            <access>read-write</access>
                            <enumeratedValues>
                                </enumeratedValues>
                        </field>
                    </fields>
                </register>
                <register>
                    <dim>8</dim>
                    <dimIncrement>0x01</dimIncrement>
                    <dimIndex>96-103</dimIndex>
                    <name>CFDTMC%s_3</name>
                    <description>TX Message Buffer Control Registers %s</description>
                    <addressOffset>0x0330</addressOffset>
                    <size>8</size>
                    <access>read-write</access>
                    <resetValue>0x00</resetValue>
                    <resetMask>0xff</resetMask>
                    <fields>
                        <field>
                            <name>TMTR</name>
                            <description>TX Message Buffer Transmission Request</description>
                            <lsb>0</lsb>
                            <msb>0</msb>
                            <access>read-write</access>
                            <enumeratedValues>
                                </enumeratedValues>
                        </field>
                        <field>
                            <name>TMTAR</name>
                            <description>TX Message Buffer Transmission Abort Request</description>
                            <lsb>1</lsb>
                            <msb>1</msb>
                            <access>read-write</access>
                            <enumeratedValues>
                                </enumeratedValues>
                        </field>
                        <field>
                            <name>TMOM</name>
                            <description>TX Message Buffer One,shot Mode</description>
                            <lsb>2</lsb>
                            <msb>2</msb>
                            <access>read-write</access>
                            <enumeratedValues>
                                </enumeratedValues>
                        </field>
                    </fields>
                </register>
                <register>
                    <dim>8</dim>
                    <dimIncrement>0x01</dimIncrement>
                    <dimIndex>0-7</dimIndex>
                    <name>CFDTMSTS%s</name>
                    <description>TX Message Buffer Status Registers %s</description>
                    <addressOffset>0x07D0</addressOffset>
                    <size>8</size>
                    <access>read-write</access>
                    <resetValue>0x00</resetValue>
                    <resetMask>0xff</resetMask>
                    <fields>
                        <field>
                            <name>TMTSTS</name>
                            <description>TX Message Buffer Transmission Status</description>
                            <lsb>0</lsb>
                            <msb>0</msb>
                            <access>read-only</access>
                            <enumeratedValues>
                                </enumeratedValues>
                        </field>
                        <field>
                            <name>TMTRF</name>
                            <description>TX Message Buffer Transmission Result Flag</description>
                            <lsb>1</lsb>
                            <msb>2</msb>
                            <access>read-write</access>
                            <enumeratedValues>
                                </enumeratedValues>
                        </field>
                        <field>
                            <name>TMTRM</name>
                            <description>TX Message Buffer Transmission Request Mirrored</description>
                            <lsb>3</lsb>
                            <msb>3</msb>
                            <access>read-only</access>
                            <enumeratedValues>
                                </enumeratedValues>
                        </field>
                        <field>
                            <name>TMTARM</name>
                            <description>TX Message Buffer Transmission Abort Request Mirrored</description>
                            <lsb>4</lsb>
                            <msb>4</msb>
                            <access>read-only</access>
                            <enumeratedValues>
                                </enumeratedValues>
                        </field>
                    </fields>
                </register>
                <register>
                    <dim>8</dim>
                    <dimIncrement>0x01</dimIncrement>
                    <dimIndex>32-39</dimIndex>
                    <name>CFDTMSTS%s_1</name>
                    <description>TX Message Buffer Status Registers %s</description>
                    <addressOffset>0x07F0</addressOffset>
                    <size>8</size>
                    <access>read-write</access>
                    <resetValue>0x00</resetValue>
                    <resetMask>0xff</resetMask>
                    <fields>
                        <field>
                            <name>TMTSTS</name>
                            <description>TX Message Buffer Transmission Status</description>
                            <lsb>0</lsb>
                            <msb>0</msb>
                            <access>read-only</access>
                            <enumeratedValues>
                                </enumeratedValues>
                        </field>
                        <field>
                            <name>TMTRF</name>
                            <description>TX Message Buffer Transmission Result Flag</description>
                            <lsb>1</lsb>
                            <msb>2</msb>
                            <access>read-write</access>
                            <enumeratedValues>
                                </enumeratedValues>
                        </field>
                        <field>
                            <name>TMTRM</name>
                            <description>TX Message Buffer Transmission Request Mirrored</description>
                            <lsb>3</lsb>
                            <msb>3</msb>
                            <access>read-only</access>
                            <enumeratedValues>
                                </enumeratedValues>
                        </field>
                        <field>
                            <name>TMTARM</name>
                            <description>TX Message Buffer Transmission Abort Request Mirrored</description>
                            <lsb>4</lsb>
                            <msb>4</msb>
                            <access>read-only</access>
                            <enumeratedValues>
                                </enumeratedValues>
                        </field>
                    </fields>
                </register>
                <register>
                    <dim>8</dim>
                    <dimIncrement>0x01</dimIncrement>
                    <dimIndex>64-71</dimIndex>
                    <name>CFDTMSTS%s_2</name>
                    <description>TX Message Buffer Status Registers %s</description>
                    <addressOffset>0x0810</addressOffset>
                    <size>8</size>
                    <access>read-write</access>
                    <resetValue>0x00</resetValue>
                    <resetMask>0xff</resetMask>
                    <fields>
                        <field>
                            <name>TMTSTS</name>
                            <description>TX Message Buffer Transmission Status</description>
                            <lsb>0</lsb>
                            <msb>0</msb>
                            <access>read-only</access>
                            <enumeratedValues>
                                </enumeratedValues>
                        </field>
                        <field>
                            <name>TMTRF</name>
                            <description>TX Message Buffer Transmission Result Flag</description>
                            <lsb>1</lsb>
                            <msb>2</msb>
                            <access>read-write</access>
                            <enumeratedValues>
                                </enumeratedValues>
                        </field>
                        <field>
                            <name>TMTRM</name>
                            <description>TX Message Buffer Transmission Request Mirrored</description>
                            <lsb>3</lsb>
                            <msb>3</msb>
                            <access>read-only</access>
                            <enumeratedValues>
                                </enumeratedValues>
                        </field>
                        <field>
                            <name>TMTARM</name>
                            <description>TX Message Buffer Transmission Abort Request Mirrored</description>
                            <lsb>4</lsb>
                            <msb>4</msb>
                            <access>read-only</access>
                            <enumeratedValues>
                                </enumeratedValues>
                        </field>
                    </fields>
                </register>
                <register>
                    <dim>8</dim>
                    <dimIncrement>0x01</dimIncrement>
                    <dimIndex>96-103</dimIndex>
                    <name>CFDTMSTS%s_3</name>
                    <description>TX Message Buffer Status Registers %s</description>
                    <addressOffset>0x0830</addressOffset>
                    <size>8</size>
                    <access>read-write</access>
                    <resetValue>0x00</resetValue>
                    <resetMask>0xff</resetMask>
                    <fields>
                        <field>
                            <name>TMTSTS</name>
                            <description>TX Message Buffer Transmission Status</description>
                            <lsb>0</lsb>
                            <msb>0</msb>
                            <access>read-only</access>
                            <enumeratedValues>
                                </enumeratedValues>
                        </field>
                        <field>
                            <name>TMTRF</name>
                            <description>TX Message Buffer Transmission Result Flag</description>
                            <lsb>1</lsb>
                            <msb>2</msb>
                            <access>read-write</access>
                            <enumeratedValues>
                                </enumeratedValues>
                        </field>
                        <field>
                            <name>TMTRM</name>
                            <description>TX Message Buffer Transmission Request Mirrored</description>
                            <lsb>3</lsb>
                            <msb>3</msb>
                            <access>read-only</access>
                            <enumeratedValues>
                                </enumeratedValues>
                        </field>
                        <field>
                            <name>TMTARM</name>
                            <description>TX Message Buffer Transmission Abort Request Mirrored</description>
                            <lsb>4</lsb>
                            <msb>4</msb>
                            <access>read-only</access>
                            <enumeratedValues>
                                </enumeratedValues>
                        </field>
                    </fields>
                </register>
                <register>
                    <dim>4</dim>
                    <dimIncrement>0x04</dimIncrement>
                    <dimIndex>0-3</dimIndex>
                    <name>CFDTMTRSTS%s</name>
                    <description>TX Message Buffer Transmission Request Status Register %s</description>
                    <addressOffset>0x0CD0</addressOffset>
                    <size>32</size>
                    <access>read-only</access>
                    <resetValue>0x00000000</resetValue>
                    <resetMask>0xffffffff</resetMask>
                    <fields>
                        <field>
                            <name>CFDTMTRSTS</name>
                            <description>TX Message Buffer Transmission Request Status</description>
                            <lsb>0</lsb>
                            <msb>7</msb>
                            <access>read-only</access>
                            <enumeratedValues>
                                </enumeratedValues>
                        </field>
                    </fields>
                </register>
                <register>
                    <dim>4</dim>
                    <dimIncrement>0x04</dimIncrement>
                    <dimIndex>0-3</dimIndex>
                    <name>CFDTMTARSTS%s</name>
                    <description>TX Message Buffer Transmission Abort Request Status Register %s</description>
                    <addressOffset>0x0D70</addressOffset>
                    <size>32</size>
                    <access>read-only</access>
                    <resetValue>0x00000000</resetValue>
                    <resetMask>0xffffffff</resetMask>
                    <fields>
                        <field>
                            <name>CFDTMTARSTS</name>
                            <description>TX Message Buffer Transmission Abort Request Status</description>
                            <lsb>0</lsb>
                            <msb>7</msb>
                            <access>read-only</access>
                            <enumeratedValues>
                                </enumeratedValues>
                        </field>
                    </fields>
                </register>
                <register>
                    <dim>4</dim>
                    <dimIncrement>0x04</dimIncrement>
                    <dimIndex>0-3</dimIndex>
                    <name>CFDTMTCSTS%s</name>
                    <description>TX Message Buffer Transmission Completion Status Register %s</description>
                    <addressOffset>0x0E10</addressOffset>
                    <size>32</size>
                    <access>read-only</access>
                    <resetValue>0x00000000</resetValue>
                    <resetMask>0xffffffff</resetMask>
                    <fields>
                        <field>
                            <name>CFDTMTCSTS</name>
                            <description>TX Message Buffer Transmission Completion Status</description>
                            <lsb>0</lsb>
                            <msb>7</msb>
                            <access>read-only</access>
                            <enumeratedValues>
                                </enumeratedValues>
                        </field>
                    </fields>
                </register>
                <register>
                    <dim>4</dim>
                    <dimIncrement>0x04</dimIncrement>
                    <dimIndex>0-3</dimIndex>
                    <name>CFDTMTASTS%s</name>
                    <description>TX Message Buffer Transmission Abort Status Register %s</description>
                    <addressOffset>0x0EB0</addressOffset>
                    <size>32</size>
                    <access>read-only</access>
                    <resetValue>0x00000000</resetValue>
                    <resetMask>0xffffffff</resetMask>
                    <fields>
                        <field>
                            <name>CFDTMTASTS</name>
                            <description>TX Message Buffer Transmission Abort Status</description>
                            <lsb>0</lsb>
                            <msb>7</msb>
                            <access>read-only</access>
                            <enumeratedValues>
                                </enumeratedValues>
                        </field>
                    </fields>
                </register>
                <register>
                    <dim>4</dim>
                    <dimIncrement>0x04</dimIncrement>
                    <dimIndex>0-3</dimIndex>
                    <name>CFDTMIEC%s</name>
                    <description>TX Message Buffer Interrupt Enable Configuration Register %s</description>
                    <addressOffset>0x0F50</addressOffset>
                    <size>32</size>
                    <access>read-write</access>
                    <resetValue>0x00000000</resetValue>
                    <resetMask>0xffffffff</resetMask>
                    <fields>
                        <field>
                            <name>TMIE</name>
                            <description>TX Message Buffer Interrupt Enable</description>
                            <lsb>0</lsb>
                            <msb>7</msb>
                            <access>read-write</access>
                            <enumeratedValues>
                                </enumeratedValues>
                        </field>
                    </fields>
                </register>
                <register>
                    <dim>2</dim>
                    <dimIncrement>0x04</dimIncrement>
                    <dimIndex>0-1</dimIndex>
                    <name>CFDTXQCC0%s</name>
                    <description>TX Queue Configuration/Control Registers 0%s</description>
                    <addressOffset>0x1000</addressOffset>
                    <size>32</size>
                    <access>read-write</access>
                    <resetValue>0x00000000</resetValue>
                    <resetMask>0xffffffff</resetMask>
                    <fields>
                        <field>
                            <name>TXQE</name>
                            <description>TX Queue Enable</description>
                            <lsb>0</lsb>
                            <msb>0</msb>
                            <access>read-write</access>
                            <enumeratedValues>
                                </enumeratedValues>
                        </field>
                        <field>
                            <name>TXQGWE</name>
                            <description>TX Queue Gateway Mode Enable</description>
                            <lsb>1</lsb>
                            <msb>1</msb>
                            <access>read-write</access>
                            <enumeratedValues>
                                </enumeratedValues>
                        </field>
                        <field>
                            <name>TXQTXIE</name>
                            <description>TX Queue TX Interrupt Enable</description>
                            <lsb>5</lsb>
                            <msb>5</msb>
                            <access>read-write</access>
                            <enumeratedValues>
                                </enumeratedValues>
                        </field>
                        <field>
                            <name>TXQIM</name>
                            <description>TX Queue Interrupt Mode</description>
                            <lsb>7</lsb>
                            <msb>7</msb>
                            <access>read-write</access>
                            <enumeratedValues>
                                </enumeratedValues>
                        </field>
                        <field>
                            <name>TXQDC</name>
                            <description>TX Queue Depth Configuration</description>
                            <lsb>8</lsb>
                            <msb>12</msb>
                            <access>read-write</access>
                        </field>
                        <field>
                            <name>TXQFIE</name>
                            <description>TXQ Full Interrupt Enable</description>
                            <lsb>16</lsb>
                            <msb>16</msb>
                            <access>read-write</access>
                            <enumeratedValues>
                                </enumeratedValues>
                        </field>
                        <field>
                            <name>TXQOFRXIE</name>
                            <description>TXQ One Frame Reception Interrupt Enable</description>
                            <lsb>17</lsb>
                            <msb>17</msb>
                            <access>read-write</access>
                            <enumeratedValues>
                                </enumeratedValues>
                        </field>
                        <field>
                            <name>TXQOFTXIE</name>
                            <description>TXQ One Frame Transmission Interrupt Enable</description>
                            <lsb>18</lsb>
                            <msb>18</msb>
                            <access>read-write</access>
                            <enumeratedValues>
                                </enumeratedValues>
                        </field>
                    </fields>
                </register>
                <register>
                    <dim>2</dim>
                    <dimIncrement>0x04</dimIncrement>
                    <dimIndex>0-1</dimIndex>
                    <name>CFDTXQSTS0%s</name>
                    <description>TX Queue Status Registers 0%s</description>
                    <addressOffset>0x1020</addressOffset>
                    <size>32</size>
                    <access>read-write</access>
                    <resetValue>0x00000001</resetValue>
                    <resetMask>0xffffffff</resetMask>
                    <fields>
                        <field>
                            <name>TXQEMP</name>
                            <description>TX Queue Empty</description>
                            <lsb>0</lsb>
                            <msb>0</msb>
                            <access>read-only</access>
                            <enumeratedValues>
                                </enumeratedValues>
                        </field>
                        <field>
                            <name>TXQFLL</name>
                            <description>TX Queue Full</description>
                            <lsb>1</lsb>
                            <msb>1</msb>
                            <access>read-only</access>
                            <enumeratedValues>
                                </enumeratedValues>
                        </field>
                        <field>
                            <name>TXQTXIF</name>
                            <description>TX Queue TX Interrupt Flag</description>
                            <lsb>2</lsb>
                            <msb>2</msb>
                            <access>read-write</access>
                            <enumeratedValues>
                                </enumeratedValues>
                        </field>
                        <field>
                            <name>TXQMC</name>
                            <description>TX Queue Message Count</description>
                            <lsb>8</lsb>
                            <msb>13</msb>
                            <access>read-only</access>
                        </field>
                        <field>
                            <name>TXQFIF</name>
                            <description>TXQ Full Interrupt Flag</description>
                            <lsb>16</lsb>
                            <msb>16</msb>
                            <access>read-write</access>
                        </field>
                        <field>
                            <name>TXQOFRXIF</name>
                            <description>TXQ One Frame Reception Interrupt Flag</description>
                            <lsb>17</lsb>
                            <msb>17</msb>
                            <access>read-write</access>
                        </field>
                        <field>
                            <name>TXQOFTXIF</name>
                            <description>TXQ One Frame Transmission Interrupt Flag</description>
                            <lsb>18</lsb>
                            <msb>18</msb>
                            <access>read-write</access>
                        </field>
                        <field>
                            <name>TXQMLT</name>
                            <description>TXQ Message Lost</description>
                            <lsb>19</lsb>
                            <msb>19</msb>
                            <access>read-write</access>
                            <enumeratedValues>
                                </enumeratedValues>
                        </field>
                    </fields>
                </register>
                <register>
                    <dim>2</dim>
                    <dimIncrement>0x04</dimIncrement>
                    <dimIndex>0-1</dimIndex>
                    <name>CFDTXQPCTR0%s</name>
                    <description>TX Queue Pointer Control Registers 0%s</description>
                    <addressOffset>0x1040</addressOffset>
                    <size>32</size>
                    <access>read-write</access>
                    <resetValue>0x00000000</resetValue>
                    <resetMask>0xffffffff</resetMask>
                    <fields>
                        <field>
                            <name>TXQPC</name>
                            <description>TX Queue Pointer Control</description>
                            <lsb>0</lsb>
                            <msb>7</msb>
                            <access>write-only</access>
                        </field>
                    </fields>
                </register>
                <register>
                    <dim>2</dim>
                    <dimIncrement>0x04</dimIncrement>
                    <dimIndex>0-1</dimIndex>
                    <name>CFDTXQCC1%s</name>
                    <description>TX Queue Configuration/Control Registers 1%s</description>
                    <addressOffset>0x1060</addressOffset>
                    <size>32</size>
                    <access>read-write</access>
                    <resetValue>0x00000000</resetValue>
                    <resetMask>0xffffffff</resetMask>
                    <fields>
                        <field>
                            <name>TXQE</name>
                            <description>TX Queue Enable</description>
                            <lsb>0</lsb>
                            <msb>0</msb>
                            <access>read-write</access>
                            <enumeratedValues>
                                </enumeratedValues>
                        </field>
                        <field>
                            <name>TXQGWE</name>
                            <description>TX Queue Gateway Mode Enable</description>
                            <lsb>1</lsb>
                            <msb>1</msb>
                            <access>read-write</access>
                            <enumeratedValues>
                                </enumeratedValues>
                        </field>
                        <field>
                            <name>TXQTXIE</name>
                            <description>TX Queue TX Interrupt Enable</description>
                            <lsb>5</lsb>
                            <msb>5</msb>
                            <access>read-write</access>
                            <enumeratedValues>
                                </enumeratedValues>
                        </field>
                        <field>
                            <name>TXQIM</name>
                            <description>TX Queue Interrupt Mode</description>
                            <lsb>7</lsb>
                            <msb>7</msb>
                            <access>read-write</access>
                            <enumeratedValues>
                                </enumeratedValues>
                        </field>
                        <field>
                            <name>TXQDC</name>
                            <description>TX Queue Depth Configuration</description>
                            <lsb>8</lsb>
                            <msb>12</msb>
                            <access>read-write</access>
                        </field>
                        <field>
                            <name>TXQFIE</name>
                            <description>TXQ Full Interrupt Enable</description>
                            <lsb>16</lsb>
                            <msb>16</msb>
                            <access>read-write</access>
                            <enumeratedValues>
                                </enumeratedValues>
                        </field>
                        <field>
                            <name>TXQOFRXIE</name>
                            <description>TXQ One Frame Reception Interrupt Enable</description>
                            <lsb>17</lsb>
                            <msb>17</msb>
                            <access>read-write</access>
                            <enumeratedValues>
                                </enumeratedValues>
                        </field>
                        <field>
                            <name>TXQOFTXIE</name>
                            <description>TXQ One Frame Transmission Interrupt Enable</description>
                            <lsb>18</lsb>
                            <msb>18</msb>
                            <access>read-write</access>
                            <enumeratedValues>
                                </enumeratedValues>
                        </field>
                    </fields>
                </register>
                <register>
                    <dim>2</dim>
                    <dimIncrement>0x04</dimIncrement>
                    <dimIndex>0-1</dimIndex>
                    <name>CFDTXQSTS1%s</name>
                    <description>TX Queue Status Registers 1%s</description>
                    <addressOffset>0x1080</addressOffset>
                    <size>32</size>
                    <access>read-write</access>
                    <resetValue>0x00000001</resetValue>
                    <resetMask>0xffffffff</resetMask>
                    <fields>
                        <field>
                            <name>TXQEMP</name>
                            <description>TX Queue Empty</description>
                            <lsb>0</lsb>
                            <msb>0</msb>
                            <access>read-only</access>
                            <enumeratedValues>
                                </enumeratedValues>
                        </field>
                        <field>
                            <name>TXQFLL</name>
                            <description>TX Queue Full</description>
                            <lsb>1</lsb>
                            <msb>1</msb>
                            <access>read-only</access>
                            <enumeratedValues>
                                </enumeratedValues>
                        </field>
                        <field>
                            <name>TXQTXIF</name>
                            <description>TX Queue TX Interrupt Flag</description>
                            <lsb>2</lsb>
                            <msb>2</msb>
                            <access>read-write</access>
                            <enumeratedValues>
                                </enumeratedValues>
                        </field>
                        <field>
                            <name>TXQMC</name>
                            <description>TX Queue Message Count</description>
                            <lsb>8</lsb>
                            <msb>13</msb>
                            <access>read-only</access>
                        </field>
                        <field>
                            <name>TXQFIF</name>
                            <description>TXQ Full Interrupt Flag</description>
                            <lsb>16</lsb>
                            <msb>16</msb>
                            <access>read-write</access>
                        </field>
                        <field>
                            <name>TXQOFRXIF</name>
                            <description>TXQ One Frame Reception Interrupt Flag</description>
                            <lsb>17</lsb>
                            <msb>17</msb>
                            <access>read-write</access>
                        </field>
                        <field>
                            <name>TXQOFTXIF</name>
                            <description>TXQ One Frame Transmission Interrupt Flag</description>
                            <lsb>18</lsb>
                            <msb>18</msb>
                            <access>read-write</access>
                        </field>
                        <field>
                            <name>TXQMLT</name>
                            <description>TXQ Message Lost</description>
                            <lsb>19</lsb>
                            <msb>19</msb>
                            <access>read-write</access>
                            <enumeratedValues>
                                </enumeratedValues>
                        </field>
                    </fields>
                </register>
                <register>
                    <dim>2</dim>
                    <dimIncrement>0x04</dimIncrement>
                    <dimIndex>0-1</dimIndex>
                    <name>CFDTXQPCTR1%s</name>
                    <description>TX Queue Pointer Control Registers 1%s</description>
                    <addressOffset>0x10A0</addressOffset>
                    <size>32</size>
                    <access>read-write</access>
                    <resetValue>0x00000000</resetValue>
                    <resetMask>0xffffffff</resetMask>
                    <fields>
                        <field>
                            <name>TXQPC</name>
                            <description>TX Queue Pointer Control</description>
                            <lsb>0</lsb>
                            <msb>7</msb>
                            <access>write-only</access>
                        </field>
                    </fields>
                </register>
                <register>
                    <dim>2</dim>
                    <dimIncrement>0x04</dimIncrement>
                    <dimIndex>0-1</dimIndex>
                    <name>CFDTXQCC2%s</name>
                    <description>TX Queue Configuration/Control Registers 2%s</description>
                    <addressOffset>0x10C0</addressOffset>
                    <size>32</size>
                    <access>read-write</access>
                    <resetValue>0x00000000</resetValue>
                    <resetMask>0xffffffff</resetMask>
                    <fields>
                        <field>
                            <name>TXQE</name>
                            <description>TX Queue Enable</description>
                            <lsb>0</lsb>
                            <msb>0</msb>
                            <access>read-write</access>
                            <enumeratedValues>
                                </enumeratedValues>
                        </field>
                        <field>
                            <name>TXQGWE</name>
                            <description>TX Queue Gateway Mode Enable</description>
                            <lsb>1</lsb>
                            <msb>1</msb>
                            <access>read-write</access>
                            <enumeratedValues>
                                </enumeratedValues>
                        </field>
                        <field>
                            <name>TXQTXIE</name>
                            <description>TX Queue TX Interrupt Enable</description>
                            <lsb>5</lsb>
                            <msb>5</msb>
                            <access>read-write</access>
                            <enumeratedValues>
                                </enumeratedValues>
                        </field>
                        <field>
                            <name>TXQIM</name>
                            <description>TX Queue Interrupt Mode</description>
                            <lsb>7</lsb>
                            <msb>7</msb>
                            <access>read-write</access>
                            <enumeratedValues>
                                </enumeratedValues>
                        </field>
                        <field>
                            <name>TXQDC</name>
                            <description>TX Queue Depth Configuration</description>
                            <lsb>8</lsb>
                            <msb>12</msb>
                            <access>read-write</access>
                        </field>
                        <field>
                            <name>TXQFIE</name>
                            <description>TXQ Full Interrupt Enable</description>
                            <lsb>16</lsb>
                            <msb>16</msb>
                            <access>read-write</access>
                            <enumeratedValues>
                                </enumeratedValues>
                        </field>
                        <field>
                            <name>TXQOFRXIE</name>
                            <description>TXQ One Frame Reception Interrupt Enable</description>
                            <lsb>17</lsb>
                            <msb>17</msb>
                            <access>read-write</access>
                            <enumeratedValues>
                                </enumeratedValues>
                        </field>
                        <field>
                            <name>TXQOFTXIE</name>
                            <description>TXQ One Frame Transmission Interrupt Enable</description>
                            <lsb>18</lsb>
                            <msb>18</msb>
                            <access>read-write</access>
                            <enumeratedValues>
                                </enumeratedValues>
                        </field>
                    </fields>
                </register>
                <register>
                    <dim>2</dim>
                    <dimIncrement>0x04</dimIncrement>
                    <dimIndex>0-1</dimIndex>
                    <name>CFDTXQSTS2%s</name>
                    <description>TX Queue Status Registers 2%s</description>
                    <addressOffset>0x10E0</addressOffset>
                    <size>32</size>
                    <access>read-write</access>
                    <resetValue>0x00000001</resetValue>
                    <resetMask>0xffffffff</resetMask>
                    <fields>
                        <field>
                            <name>TXQEMP</name>
                            <description>TX Queue Empty</description>
                            <lsb>0</lsb>
                            <msb>0</msb>
                            <access>read-only</access>
                            <enumeratedValues>
                                </enumeratedValues>
                        </field>
                        <field>
                            <name>TXQFLL</name>
                            <description>TX Queue Full</description>
                            <lsb>1</lsb>
                            <msb>1</msb>
                            <access>read-only</access>
                            <enumeratedValues>
                                </enumeratedValues>
                        </field>
                        <field>
                            <name>TXQTXIF</name>
                            <description>TX Queue TX Interrupt Flag</description>
                            <lsb>2</lsb>
                            <msb>2</msb>
                            <access>read-write</access>
                            <enumeratedValues>
                                </enumeratedValues>
                        </field>
                        <field>
                            <name>TXQMC</name>
                            <description>TX Queue Message Count</description>
                            <lsb>8</lsb>
                            <msb>13</msb>
                            <access>read-only</access>
                        </field>
                        <field>
                            <name>TXQFIF</name>
                            <description>TXQ Full Interrupt Flag</description>
                            <lsb>16</lsb>
                            <msb>16</msb>
                            <access>read-write</access>
                        </field>
                        <field>
                            <name>TXQOFRXIF</name>
                            <description>TXQ One Frame Reception Interrupt Flag</description>
                            <lsb>17</lsb>
                            <msb>17</msb>
                            <access>read-write</access>
                        </field>
                        <field>
                            <name>TXQOFTXIF</name>
                            <description>TXQ One Frame Transmission Interrupt Flag</description>
                            <lsb>18</lsb>
                            <msb>18</msb>
                            <access>read-write</access>
                        </field>
                        <field>
                            <name>TXQMLT</name>
                            <description>TXQ Message Lost</description>
                            <lsb>19</lsb>
                            <msb>19</msb>
                            <access>read-write</access>
                            <enumeratedValues>
                                </enumeratedValues>
                        </field>
                    </fields>
                </register>
                <register>
                    <dim>2</dim>
                    <dimIncrement>0x04</dimIncrement>
                    <dimIndex>0-1</dimIndex>
                    <name>CFDTXQPCTR2%s</name>
                    <description>TX Queue Pointer Control Registers 2%s</description>
                    <addressOffset>0x1100</addressOffset>
                    <size>32</size>
                    <access>read-write</access>
                    <resetValue>0x00000000</resetValue>
                    <resetMask>0xffffffff</resetMask>
                    <fields>
                        <field>
                            <name>TXQPC</name>
                            <description>TX Queue Pointer Control</description>
                            <lsb>0</lsb>
                            <msb>7</msb>
                            <access>write-only</access>
                        </field>
                    </fields>
                </register>
                <register>
                    <dim>2</dim>
                    <dimIncrement>0x04</dimIncrement>
                    <dimIndex>0-1</dimIndex>
                    <name>CFDTXQCC3%s</name>
                    <description>TX Queue Configuration/Control Registers 3%s</description>
                    <addressOffset>0x1120</addressOffset>
                    <size>32</size>
                    <access>read-write</access>
                    <resetValue>0x00000000</resetValue>
                    <resetMask>0xffffffff</resetMask>
                    <fields>
                        <field>
                            <name>TXQE</name>
                            <description>TX Queue Enable</description>
                            <lsb>0</lsb>
                            <msb>0</msb>
                            <access>read-write</access>
                            <enumeratedValues>
                                </enumeratedValues>
                        </field>
                        <field>
                            <name>TXQTXIE</name>
                            <description>TX Queue TX Interrupt Enable</description>
                            <lsb>5</lsb>
                            <msb>5</msb>
                            <access>read-write</access>
                            <enumeratedValues>
                                </enumeratedValues>
                        </field>
                        <field>
                            <name>TXQIM</name>
                            <description>TX Queue Interrupt Mode</description>
                            <lsb>7</lsb>
                            <msb>7</msb>
                            <access>read-write</access>
                            <enumeratedValues>
                                </enumeratedValues>
                        </field>
                        <field>
                            <name>TXQDC</name>
                            <description>TX Queue Depth Configuration</description>
                            <lsb>8</lsb>
                            <msb>12</msb>
                            <access>read-write</access>
                        </field>
                        <field>
                            <name>TXQOFTXIE</name>
                            <description>TXQ One Frame Transmission Interrupt Enable</description>
                            <lsb>18</lsb>
                            <msb>18</msb>
                            <access>read-write</access>
                            <enumeratedValues>
                                </enumeratedValues>
                        </field>
                    </fields>
                </register>
                <register>
                    <dim>2</dim>
                    <dimIncrement>0x04</dimIncrement>
                    <dimIndex>0-1</dimIndex>
                    <name>CFDTXQSTS3%s</name>
                    <description>TX Queue Status Registers 3%s</description>
                    <addressOffset>0x1140</addressOffset>
                    <size>32</size>
                    <access>read-write</access>
                    <resetValue>0x00000001</resetValue>
                    <resetMask>0xffffffff</resetMask>
                    <fields>
                        <field>
                            <name>TXQEMP</name>
                            <description>TX Queue Empty</description>
                            <lsb>0</lsb>
                            <msb>0</msb>
                            <access>read-only</access>
                            <enumeratedValues>
                                </enumeratedValues>
                        </field>
                        <field>
                            <name>TXQFLL</name>
                            <description>TX Queue Full</description>
                            <lsb>1</lsb>
                            <msb>1</msb>
                            <access>read-only</access>
                            <enumeratedValues>
                                </enumeratedValues>
                        </field>
                        <field>
                            <name>TXQTXIF</name>
                            <description>TX Queue TX Interrupt Flag</description>
                            <lsb>2</lsb>
                            <msb>2</msb>
                            <access>read-write</access>
                            <enumeratedValues>
                                </enumeratedValues>
                        </field>
                        <field>
                            <name>TXQMC</name>
                            <description>TX Queue Message Count</description>
                            <lsb>8</lsb>
                            <msb>13</msb>
                            <access>read-only</access>
                        </field>
                        <field>
                            <name>TXQOFTXIF</name>
                            <description>TXQ One Frame Transmission Interrupt Flag</description>
                            <lsb>18</lsb>
                            <msb>18</msb>
                            <access>read-write</access>
                        </field>
                    </fields>
                </register>
                <register>
                    <dim>2</dim>
                    <dimIncrement>0x04</dimIncrement>
                    <dimIndex>0-1</dimIndex>
                    <name>CFDTXQPCTR3%s</name>
                    <description>TX Queue Pointer Control Registers 3%s</description>
                    <addressOffset>0x1160</addressOffset>
                    <size>32</size>
                    <access>read-write</access>
                    <resetValue>0x00000000</resetValue>
                    <resetMask>0xffffffff</resetMask>
                    <fields>
                        <field>
                            <name>TXQPC</name>
                            <description>TX Queue Pointer Control</description>
                            <lsb>0</lsb>
                            <msb>7</msb>
                            <access>write-only</access>
                        </field>
                    </fields>
                </register>
                <register>
                    <name>CFDTXQESTS</name>
                    <description>TX Queue Empty Status Register</description>
                    <addressOffset>0x1180</addressOffset>
                    <size>32</size>
                    <access>read-only</access>
                    <resetValue>0x000000ff</resetValue>
                    <resetMask>0xffffffff</resetMask>
                    <fields>
                        <field>
                            <name>TXQxEMP</name>
                            <description>TXQ Empty Status</description>
                            <lsb>0</lsb>
                            <msb>7</msb>
                            <access>read-only</access>
                            <enumeratedValues>
                                </enumeratedValues>
                        </field>
                    </fields>
                </register>
                <register>
                    <name>CFDTXQFISTS</name>
                    <description>TX Queue Full Interrupt Status Register</description>
                    <addressOffset>0x1184</addressOffset>
                    <size>32</size>
                    <access>read-write</access>
                    <resetValue>0x00000000</resetValue>
                    <resetMask>0xffffffff</resetMask>
                    <fields>
                        <field>
                            <name>TXQ0FULL</name>
                            <description>TXQ Full Interrupt Status for Channel 0</description>
                            <lsb>0</lsb>
                            <msb>2</msb>
                            <access>read-only</access>
                            <enumeratedValues>
                                </enumeratedValues>
                        </field>
                        <field>
                            <name>TXQ1FULL</name>
                            <description>TXQ Full Interrupt Status for Channel 1</description>
                            <lsb>4</lsb>
                            <msb>6</msb>
                            <access>read-only</access>
                            <enumeratedValues>
                                </enumeratedValues>
                        </field>
                    </fields>
                </register>
                <register>
                    <name>CFDTXQMSTS</name>
                    <description>TX Queue Message Lost Status Register</description>
                    <addressOffset>0x1188</addressOffset>
                    <size>32</size>
                    <access>read-write</access>
                    <resetValue>0x00000000</resetValue>
                    <resetMask>0xffffffff</resetMask>
                    <fields>
                        <field>
                            <name>TXQ0ML</name>
                            <description>TXQ Message Lost Status for Channel 0</description>
                            <lsb>0</lsb>
                            <msb>2</msb>
                            <access>read-only</access>
                            <enumeratedValues>
                                </enumeratedValues>
                        </field>
                        <field>
                            <name>TXQ1ML</name>
                            <description>TXQ Message Lost Status for Channel 1</description>
                            <lsb>4</lsb>
                            <msb>6</msb>
                            <access>read-only</access>
                            <enumeratedValues>
                                </enumeratedValues>
                        </field>
                    </fields>
                </register>
                <register>
                    <name>CFDTXQISTS</name>
                    <description>TX Queue Interrupt Status Register</description>
                    <addressOffset>0x1190</addressOffset>
                    <size>32</size>
                    <access>read-write</access>
                    <resetValue>0x00000000</resetValue>
                    <resetMask>0xffffffff</resetMask>
                    <fields>
                        <field>
                            <name>TXQ0ISF</name>
                            <description>TXQ Interrupt Status Flag for Channel 0</description>
                            <lsb>0</lsb>
                            <msb>3</msb>
                            <access>read-only</access>
                            <enumeratedValues>
                                </enumeratedValues>
                        </field>
                        <field>
                            <name>TXQ1ISF</name>
                            <description>TXQ Interrupt Status Flag for Channel 1</description>
                            <lsb>4</lsb>
                            <msb>7</msb>
                            <access>read-only</access>
                            <enumeratedValues>
                                </enumeratedValues>
                        </field>
                    </fields>
                </register>
                <register>
                    <name>CFDTXQOFTISTS</name>
                    <description>TX Queue One Frame TX Interrupt Status Register</description>
                    <addressOffset>0x1194</addressOffset>
                    <size>32</size>
                    <access>read-write</access>
                    <resetValue>0x00000000</resetValue>
                    <resetMask>0xffffffff</resetMask>
                    <fields>
                        <field>
                            <name>TXQ0OFTISF</name>
                            <description>TXQ One Frame TX Interrupt Status Flag for Channel 0</description>
                            <lsb>0</lsb>
                            <msb>3</msb>
                            <access>read-only</access>
                            <enumeratedValues>
                                </enumeratedValues>
                        </field>
                        <field>
                            <name>TXQ1OFTISF</name>
                            <description>TXQ One Frame TX Interrupt Status Flag for Channel 1</description>
                            <lsb>4</lsb>
                            <msb>7</msb>
                            <access>read-only</access>
                            <enumeratedValues>
                                </enumeratedValues>
                        </field>
                    </fields>
                </register>
                <register>
                    <name>CFDTXQOFRISTS</name>
                    <description>TX Queue One Frame RX Interrupt Status Register</description>
                    <addressOffset>0x1198</addressOffset>
                    <size>32</size>
                    <access>read-write</access>
                    <resetValue>0x00000000</resetValue>
                    <resetMask>0xffffffff</resetMask>
                    <fields>
                        <field>
                            <name>TXQ0OFRISF</name>
                            <description>TXQ One Frame RX Interrupt Status Flag</description>
                            <lsb>0</lsb>
                            <msb>2</msb>
                            <access>read-only</access>
                            <enumeratedValues>
                                </enumeratedValues>
                        </field>
                        <field>
                            <name>TXQ1OFRISF</name>
                            <description>TXQ One Frame RX Interrupt Status Flag</description>
                            <lsb>4</lsb>
                            <msb>6</msb>
                            <access>read-only</access>
                            <enumeratedValues>
                                </enumeratedValues>
                        </field>
                    </fields>
                </register>
                <register>
                    <name>CFDTXQFSTS</name>
                    <description>TX Queue Full Status Register</description>
                    <addressOffset>0x119C</addressOffset>
                    <size>32</size>
                    <access>read-only</access>
                    <resetValue>0x00000000</resetValue>
                    <resetMask>0xffffffff</resetMask>
                    <fields>
                        <field>
                            <name>TXQ0FSF</name>
                            <description>TXQ Full Status Flag for Channel 0</description>
                            <lsb>0</lsb>
                            <msb>3</msb>
                            <access>read-only</access>
                            <enumeratedValues>
                                </enumeratedValues>
                        </field>
                        <field>
                            <name>TXQ1FSF</name>
                            <description>TXQ Full Status Flag for Channel 1</description>
                            <lsb>4</lsb>
                            <msb>7</msb>
                            <access>read-only</access>
                            <enumeratedValues>
                                </enumeratedValues>
                        </field>
                    </fields>
                </register>
                <register>
                    <dim>2</dim>
                    <dimIncrement>0x04</dimIncrement>
                    <dimIndex>0-1</dimIndex>
                    <name>CFDTHLCC%s</name>
                    <description>TX History List Configuration/Control Register %s</description>
                    <addressOffset>0x1200</addressOffset>
                    <size>32</size>
                    <access>read-write</access>
                    <resetValue>0x00000000</resetValue>
                    <resetMask>0xffffffff</resetMask>
                    <fields>
                        <field>
                            <name>THLE</name>
                            <description>TX History List Enable</description>
                            <lsb>0</lsb>
                            <msb>0</msb>
                            <access>read-write</access>
                            <enumeratedValues>
                                </enumeratedValues>
                        </field>
                        <field>
                            <name>THLIE</name>
                            <description>TX History List Interrupt Enable</description>
                            <lsb>8</lsb>
                            <msb>8</msb>
                            <access>read-write</access>
                            <enumeratedValues>
                                </enumeratedValues>
                        </field>
                        <field>
                            <name>THLIM</name>
                            <description>TX History List Interrupt Mode</description>
                            <lsb>9</lsb>
                            <msb>9</msb>
                            <access>read-write</access>
                            <enumeratedValues>
                                </enumeratedValues>
                        </field>
                        <field>
                            <name>THLDTE</name>
                            <description>TX History List Dedicated TX Enable</description>
                            <lsb>10</lsb>
                            <msb>10</msb>
                            <access>read-write</access>
                            <enumeratedValues>
                                </enumeratedValues>
                        </field>
                        <field>
                            <name>THLDGE</name>
                            <description>TX History List Dedicated Gateway Enable</description>
                            <lsb>11</lsb>
                            <msb>11</msb>
                            <access>read-write</access>
                            <enumeratedValues>
                                </enumeratedValues>
                        </field>
                    </fields>
                </register>
                <register>
                    <dim>2</dim>
                    <dimIncrement>0x04</dimIncrement>
                    <dimIndex>0-1</dimIndex>
                    <name>CFDTHLSTS%s</name>
                    <description>TX History List Status Register %s</description>
                    <addressOffset>0x1220</addressOffset>
                    <size>32</size>
                    <access>read-write</access>
                    <resetValue>0x00000001</resetValue>
                    <resetMask>0xffffffff</resetMask>
                    <fields>
                        <field>
                            <name>THLEMP</name>
                            <description>TX History List Empty</description>
                            <lsb>0</lsb>
                            <msb>0</msb>
                            <access>read-only</access>
                            <enumeratedValues>
                                </enumeratedValues>
                        </field>
                        <field>
                            <name>THLFLL</name>
                            <description>TX History List Full</description>
                            <lsb>1</lsb>
                            <msb>1</msb>
                            <access>read-only</access>
                            <enumeratedValues>
                                </enumeratedValues>
                        </field>
                        <field>
                            <name>THLELT</name>
                            <description>TX History List Entry Lost</description>
                            <lsb>2</lsb>
                            <msb>2</msb>
                            <access>read-write</access>
                            <enumeratedValues>
                                </enumeratedValues>
                        </field>
                        <field>
                            <name>THLIF</name>
                            <description>TX History List Interrupt Flag</description>
                            <lsb>3</lsb>
                            <msb>3</msb>
                            <access>read-write</access>
                            <enumeratedValues>
                                </enumeratedValues>
                        </field>
                        <field>
                            <name>THLMC</name>
                            <description>TX History List Message Count</description>
                            <lsb>8</lsb>
                            <msb>13</msb>
                            <access>read-only</access>
                        </field>
                    </fields>
                </register>
                <register>
                    <dim>2</dim>
                    <dimIncrement>0x04</dimIncrement>
                    <dimIndex>0-1</dimIndex>
                    <name>CFDTHLPCTR%s</name>
                    <description>TX History List Pointer Control Registers %s</description>
                    <addressOffset>0x1240</addressOffset>
                    <size>32</size>
                    <access>read-write</access>
                    <resetValue>0x00000000</resetValue>
                    <resetMask>0xffffffff</resetMask>
                    <fields>
                        <field>
                            <name>THLPC</name>
                            <description>TX History List Pointer Control</description>
                            <lsb>0</lsb>
                            <msb>7</msb>
                            <access>write-only</access>
                        </field>
                    </fields>
                </register>
                <register>
                    <name>CFDGTINTSTS0</name>
                    <description>Global TX Interrupt Status Register 0</description>
                    <addressOffset>0x1300</addressOffset>
                    <size>32</size>
                    <access>read-write</access>
                    <resetValue>0x00000000</resetValue>
                    <resetMask>0xffffffff</resetMask>
                    <fields>
                        <field>
                            <name>TSIF0</name>
                            <description>TX Successful Interrupt Flag Channel 0</description>
                            <lsb>0</lsb>
                            <msb>0</msb>
                            <access>read-only</access>
                            <enumeratedValues>
                                </enumeratedValues>
                        </field>
                        <field>
                            <name>TAI0</name>
                            <description>TX Abort Interrupt Flag Channel 0</description>
                            <lsb>1</lsb>
                            <msb>1</msb>
                            <access>read-only</access>
                            <enumeratedValues>
                                </enumeratedValues>
                        </field>
                        <field>
                            <name>TQIF0</name>
                            <description>TX Queue Interrupt Flag Channel 0</description>
                            <lsb>2</lsb>
                            <msb>2</msb>
                            <access>read-only</access>
                            <enumeratedValues>
                                </enumeratedValues>
                        </field>
                        <field>
                            <name>CFTIF0</name>
                            <description>COM FIFO TX/GW Mode Interrupt Flag Channel 0</description>
                            <lsb>3</lsb>
                            <msb>3</msb>
                            <access>read-only</access>
                            <enumeratedValues>
                                </enumeratedValues>
                        </field>
                        <field>
                            <name>THIF0</name>
                            <description>TX History List Interrupt Channel 0</description>
                            <lsb>4</lsb>
                            <msb>4</msb>
                            <access>read-only</access>
                            <enumeratedValues>
                                </enumeratedValues>
                        </field>
                        <field>
                            <name>TQOFIFO</name>
                            <description>TX Queue One Frame Transmission Interrupt Flag Channel 0</description>
                            <lsb>5</lsb>
                            <msb>5</msb>
                            <access>read-only</access>
                            <enumeratedValues>
                                </enumeratedValues>
                        </field>
                        <field>
                            <name>CFOTIFO</name>
                            <description>COM FIFO One Frame Transmission Interrupt Flag Channel 0</description>
                            <lsb>6</lsb>
                            <msb>6</msb>
                            <access>read-only</access>
                            <enumeratedValues>
                                </enumeratedValues>
                        </field>
                        <field>
                            <name>TSIF1</name>
                            <description>TX Successful Interrupt Flag Channel 1</description>
                            <lsb>8</lsb>
                            <msb>8</msb>
                            <access>read-only</access>
                            <enumeratedValues>
                                </enumeratedValues>
                        </field>
                        <field>
                            <name>TAIF1</name>
                            <description>TX Abort Interrupt Flag Channel 1</description>
                            <lsb>9</lsb>
                            <msb>9</msb>
                            <access>read-only</access>
                            <enumeratedValues>
                                </enumeratedValues>
                        </field>
                        <field>
                            <name>TQIF1</name>
                            <description>TX Queue Interrupt Flag Channel 1</description>
                            <lsb>10</lsb>
                            <msb>10</msb>
                            <access>read-only</access>
                            <enumeratedValues>
                                </enumeratedValues>
                        </field>
                        <field>
                            <name>CFTIF1</name>
                            <description>COM FIFO TX/GW Mode Interrupt Flag Channel 1</description>
                            <lsb>11</lsb>
                            <msb>11</msb>
                            <access>read-only</access>
                            <enumeratedValues>
                                </enumeratedValues>
                        </field>
                        <field>
                            <name>THIF1</name>
                            <description>TX History List Interrupt Channel 1</description>
                            <lsb>12</lsb>
                            <msb>12</msb>
                            <access>read-only</access>
                            <enumeratedValues>
                                </enumeratedValues>
                        </field>
                        <field>
                            <name>TQOFIF1</name>
                            <description>TX Queue One Frame Transmission Interrupt Flag Channel 1</description>
                            <lsb>13</lsb>
                            <msb>13</msb>
                            <access>read-only</access>
                            <enumeratedValues>
                                </enumeratedValues>
                        </field>
                        <field>
                            <name>CFOTIF1</name>
                            <description>COM FIFO One Frame Transmission Interrupt Flag Channel 1</description>
                            <lsb>14</lsb>
                            <msb>14</msb>
                            <access>read-only</access>
                            <enumeratedValues>
                                </enumeratedValues>
                        </field>
                    </fields>
                </register>
                <register>
                    <name>CFDGTSTCFG</name>
                    <description>Global Test Configuration Register</description>
                    <addressOffset>0x1308</addressOffset>
                    <size>32</size>
                    <access>read-write</access>
                    <resetValue>0x00000000</resetValue>
                    <resetMask>0xffffffff</resetMask>
                    <fields>
                        <field>
                            <name>ICBCE</name>
                            <description>Channel n Internal CAN Bus Communication Test Mode Enable</description>
                            <lsb>0</lsb>
                            <msb>1</msb>
                            <access>read-write</access>
                            <enumeratedValues>
                                </enumeratedValues>
                        </field>
                        <field>
                            <name>RTMPS</name>
                            <description>RAM Test Mode Page Select</description>
                            <lsb>16</lsb>
                            <msb>25</msb>
                            <access>read-write</access>
                        </field>
                    </fields>
                </register>
                <register>
                    <name>CFDGTSTCTR</name>
                    <description>Global Test Control Register</description>
                    <addressOffset>0x130C</addressOffset>
                    <size>32</size>
                    <access>read-write</access>
                    <resetValue>0x00000000</resetValue>
                    <resetMask>0xffffffff</resetMask>
                    <fields>
                        <field>
                            <name>ICBCTME</name>
                            <description>Internal CAN Bus Communication Test Mode Enable</description>
                            <lsb>0</lsb>
                            <msb>0</msb>
                            <access>read-write</access>
                            <enumeratedValues>
                                </enumeratedValues>
                        </field>
                        <field>
                            <name>RTME</name>
                            <description>RAM Test Mode Enable</description>
                            <lsb>2</lsb>
                            <msb>2</msb>
                            <access>read-write</access>
                            <enumeratedValues>
                                </enumeratedValues>
                        </field>
                    </fields>
                </register>
                <register>
                    <name>CFDGFDCFG</name>
                    <description>Global FD Configuration Register</description>
                    <addressOffset>0x1314</addressOffset>
                    <size>32</size>
                    <access>read-write</access>
                    <resetValue>0x00000000</resetValue>
                    <resetMask>0xffffffff</resetMask>
                    <fields>
                        <field>
                            <name>RPED</name>
                            <description>RES Bit Protocol Exception Disable</description>
                            <lsb>0</lsb>
                            <msb>0</msb>
                            <access>read-write</access>
                            <enumeratedValues>
                                </enumeratedValues>
                        </field>
                        <field>
                            <name>TSCCFG</name>
                            <description>Timestamp Capture Configuration</description>
                            <lsb>8</lsb>
                            <msb>9</msb>
                            <access>read-write</access>
                            <enumeratedValues>
                                </enumeratedValues>
                        </field>
                    </fields>
                </register>
                <register>
                    <name>CFDGLOCKK</name>
                    <description>Global Lock Key Register</description>
                    <addressOffset>0x131C</addressOffset>
                    <size>32</size>
                    <access>write-only</access>
                    <resetValue>0x00000000</resetValue>
                    <resetMask>0xffffffff</resetMask>
                    <fields>
                        <field>
                            <name>LOCK</name>
                            <description>Lock Key</description>
                            <lsb>0</lsb>
                            <msb>15</msb>
                            <access>write-only</access>
                        </field>
                    </fields>
                </register>
                <register>
                    <name>CFDCDTCT</name>
                    <description>DMA Transfer Control Register</description>
                    <addressOffset>0x1330</addressOffset>
                    <size>32</size>
                    <access>read-write</access>
                    <resetValue>0x00000000</resetValue>
                    <resetMask>0xffffffff</resetMask>
                    <fields>
                        <field>
                            <name>RFDMAE0</name>
                            <description>DMA Transfer Enable for RXFIFO 0</description>
                            <lsb>0</lsb>
                            <msb>0</msb>
                            <access>read-write</access>
                            <enumeratedValues>
                                </enumeratedValues>
                        </field>
                        <field>
                            <name>RFDMAE1</name>
                            <description>DMA Transfer Enable for RXFIFO 1</description>
                            <lsb>1</lsb>
                            <msb>1</msb>
                            <access>read-write</access>
                            <enumeratedValues>
                                </enumeratedValues>
                        </field>
                        <field>
                            <name>RFDMAE2</name>
                            <description>DMA Transfer Enable for RXFIFO 2</description>
                            <lsb>2</lsb>
                            <msb>2</msb>
                            <access>read-write</access>
                            <enumeratedValues>
                                </enumeratedValues>
                        </field>
                        <field>
                            <name>RFDMAE3</name>
                            <description>DMA Transfer Enable for RXFIFO 3</description>
                            <lsb>3</lsb>
                            <msb>3</msb>
                            <access>read-write</access>
                            <enumeratedValues>
                                </enumeratedValues>
                        </field>
                        <field>
                            <name>RFDMAE4</name>
                            <description>DMA Transfer Enable for RXFIFO 4</description>
                            <lsb>4</lsb>
                            <msb>4</msb>
                            <access>read-write</access>
                            <enumeratedValues>
                                </enumeratedValues>
                        </field>
                        <field>
                            <name>RFDMAE5</name>
                            <description>DMA Transfer Enable for RXFIFO 5</description>
                            <lsb>5</lsb>
                            <msb>5</msb>
                            <access>read-write</access>
                            <enumeratedValues>
                                </enumeratedValues>
                        </field>
                        <field>
                            <name>RFDMAE6</name>
                            <description>DMA Transfer Enable for RXFIFO 6</description>
                            <lsb>6</lsb>
                            <msb>6</msb>
                            <access>read-write</access>
                            <enumeratedValues>
                                </enumeratedValues>
                        </field>
                        <field>
                            <name>RFDMAE7</name>
                            <description>DMA Transfer Enable for RXFIFO 7</description>
                            <lsb>7</lsb>
                            <msb>7</msb>
                            <access>read-write</access>
                            <enumeratedValues>
                                </enumeratedValues>
                        </field>
                        <field>
                            <name>CFDMAE0</name>
                            <description>DMA Transfer Enable for Common FIFO 0 of Channel 0</description>
                            <lsb>8</lsb>
                            <msb>8</msb>
                            <access>read-write</access>
                            <enumeratedValues>
                                </enumeratedValues>
                        </field>
                        <field>
                            <name>CFDMAE1</name>
                            <description>DMA Transfer Enable for Common FIFO 0 of Channel 1</description>
                            <lsb>9</lsb>
                            <msb>9</msb>
                            <access>read-write</access>
                            <enumeratedValues>
                                </enumeratedValues>
                        </field>
                    </fields>
                </register>
                <register>
                    <name>CFDCDTSTS</name>
                    <description>DMA Transfer Status Register</description>
                    <addressOffset>0x1334</addressOffset>
                    <size>32</size>
                    <access>read-only</access>
                    <resetValue>0x00000000</resetValue>
                    <resetMask>0xffffffff</resetMask>
                    <fields>
                        <field>
                            <name>RFDMASTS0</name>
                            <description>DMA Transfer Status for RX FIFO 0</description>
                            <lsb>0</lsb>
                            <msb>0</msb>
                            <access>read-only</access>
                            <enumeratedValues>
                                </enumeratedValues>
                        </field>
                        <field>
                            <name>RFDMASTS1</name>
                            <description>DMA Transfer Status for RX FIFO 1</description>
                            <lsb>1</lsb>
                            <msb>1</msb>
                            <access>read-only</access>
                            <enumeratedValues>
                                </enumeratedValues>
                        </field>
                        <field>
                            <name>RFDMASTS2</name>
                            <description>DMA Transfer Status for RX FIFO 2</description>
                            <lsb>2</lsb>
                            <msb>2</msb>
                            <access>read-only</access>
                            <enumeratedValues>
                                </enumeratedValues>
                        </field>
                        <field>
                            <name>RFDMASTS3</name>
                            <description>DMA Transfer Status for RX FIFO 3</description>
                            <lsb>3</lsb>
                            <msb>3</msb>
                            <access>read-only</access>
                            <enumeratedValues>
                                </enumeratedValues>
                        </field>
                        <field>
                            <name>RFDMASTS4</name>
                            <description>DMA Transfer Status for RX FIFO 4</description>
                            <lsb>4</lsb>
                            <msb>4</msb>
                            <access>read-only</access>
                            <enumeratedValues>
                                </enumeratedValues>
                        </field>
                        <field>
                            <name>RFDMASTS5</name>
                            <description>DMA Transfer Status for RX FIFO 5</description>
                            <lsb>5</lsb>
                            <msb>5</msb>
                            <access>read-only</access>
                            <enumeratedValues>
                                </enumeratedValues>
                        </field>
                        <field>
                            <name>RFDMASTS6</name>
                            <description>DMA Transfer Status for RX FIFO 6</description>
                            <lsb>6</lsb>
                            <msb>6</msb>
                            <access>read-only</access>
                            <enumeratedValues>
                                </enumeratedValues>
                        </field>
                        <field>
                            <name>RFDMASTS7</name>
                            <description>DMA Transfer Status for RX FIFO 7</description>
                            <lsb>7</lsb>
                            <msb>7</msb>
                            <access>read-only</access>
                            <enumeratedValues>
                                </enumeratedValues>
                        </field>
                        <field>
                            <name>CFDMASTS0</name>
                            <description>DMA Transfer Status only for Common FIFO 0 of Channel 0</description>
                            <lsb>8</lsb>
                            <msb>8</msb>
                            <access>read-only</access>
                            <enumeratedValues>
                                </enumeratedValues>
                        </field>
                        <field>
                            <name>CFDMASTS1</name>
                            <description>DMA Transfer Status only for Common FIFO 0 of Channel 1</description>
                            <lsb>9</lsb>
                            <msb>9</msb>
                            <access>read-only</access>
                            <enumeratedValues>
                                </enumeratedValues>
                        </field>
                    </fields>
                </register>
                <register>
                    <name>CFDCDTTCT</name>
                    <description>DMA TX Transfer Control Register</description>
                    <addressOffset>0x1340</addressOffset>
                    <size>32</size>
                    <access>read-write</access>
                    <resetValue>0x00000000</resetValue>
                    <resetMask>0xffffffff</resetMask>
                    <fields>
                        <field>
                            <name>TQ0DMAE0</name>
                            <description>DMA TX Transfer Enable for TXQ 0 of Channel 0</description>
                            <lsb>0</lsb>
                            <msb>0</msb>
                            <access>read-write</access>
                            <enumeratedValues>
                                </enumeratedValues>
                        </field>
                        <field>
                            <name>TQ0DMAE1</name>
                            <description>DMA TX Transfer Enable for TXQ 0 of Channel 1</description>
                            <lsb>1</lsb>
                            <msb>1</msb>
                            <access>read-write</access>
                            <enumeratedValues>
                                </enumeratedValues>
                        </field>
                        <field>
                            <name>TQ3DMAE0</name>
                            <description>DMA TX Transfer Enable for TXQ 3 of Channel 0</description>
                            <lsb>8</lsb>
                            <msb>8</msb>
                            <access>read-write</access>
                            <enumeratedValues>
                                </enumeratedValues>
                        </field>
                        <field>
                            <name>TQ3DMAE1</name>
                            <description>DMA TX Transfer Enable for TXQ 3 of Channel 1</description>
                            <lsb>9</lsb>
                            <msb>9</msb>
                            <access>read-write</access>
                            <enumeratedValues>
                                </enumeratedValues>
                        </field>
                        <field>
                            <name>CFDMAE0</name>
                            <description>DMA TX Transfer Enable for Common FIFO 2 of Channel 0</description>
                            <lsb>16</lsb>
                            <msb>16</msb>
                            <access>read-write</access>
                            <enumeratedValues>
                                </enumeratedValues>
                        </field>
                        <field>
                            <name>CFDMAE1</name>
                            <description>DMA TX Transfer Enable for Common FIFO 2 of Channel 1</description>
                            <lsb>17</lsb>
                            <msb>17</msb>
                            <access>read-write</access>
                            <enumeratedValues>
                                </enumeratedValues>
                        </field>
                    </fields>
                </register>
                <register>
                    <name>CFDCDTTSTS</name>
                    <description>DMA TX Transfer Status Register</description>
                    <addressOffset>0x1344</addressOffset>
                    <size>32</size>
                    <access>read-write</access>
                    <resetValue>0x00000000</resetValue>
                    <resetMask>0xffffffff</resetMask>
                    <fields>
                        <field>
                            <name>TQ0DMASTS0</name>
                            <description>DMA TX Transfer Status for TXQ0 of Channel 0</description>
                            <lsb>0</lsb>
                            <msb>0</msb>
                            <access>read-only</access>
                            <enumeratedValues>
                                </enumeratedValues>
                        </field>
                        <field>
                            <name>TQ0DMASTS1</name>
                            <description>DMA TX Transfer Status for TXQ0 of Channel 1</description>
                            <lsb>1</lsb>
                            <msb>1</msb>
                            <access>read-only</access>
                            <enumeratedValues>
                                </enumeratedValues>
                        </field>
                        <field>
                            <name>TQ3DMASTS0</name>
                            <description>DMA TX Transfer Status for TXQ3 of Channel 0</description>
                            <lsb>8</lsb>
                            <msb>8</msb>
                            <access>read-only</access>
                            <enumeratedValues>
                                </enumeratedValues>
                        </field>
                        <field>
                            <name>TQ3DMASTS1</name>
                            <description>DMA TX Transfer Status for TXQ3 of Channel 1</description>
                            <lsb>9</lsb>
                            <msb>9</msb>
                            <access>read-only</access>
                            <enumeratedValues>
                                </enumeratedValues>
                        </field>
                        <field>
                            <name>CFDMASTS0</name>
                            <description>DMA TX Transfer Status only for Common FIFO 2 of Channel 0</description>
                            <lsb>16</lsb>
                            <msb>16</msb>
                            <access>read-only</access>
                            <enumeratedValues>
                                </enumeratedValues>
                        </field>
                        <field>
                            <name>CFDMASTS1</name>
                            <description>DMA TX Transfer Status only for Common FIFO 2 of Channel 1</description>
                            <lsb>17</lsb>
                            <msb>17</msb>
                            <access>read-only</access>
                            <enumeratedValues>
                                </enumeratedValues>
                        </field>
                    </fields>
                </register>
                <register>
                    <dim>2</dim>
                    <dimIncrement>0x04</dimIncrement>
                    <dimIndex>0-1</dimIndex>
                    <name>CFDGRINTSTS%s</name>
                    <description>Global RX Interrupt Status Register %s</description>
                    <addressOffset>0x1350</addressOffset>
                    <size>32</size>
                    <access>read-write</access>
                    <resetValue>0x00000000</resetValue>
                    <resetMask>0xffffffff</resetMask>
                    <fields>
                        <field>
                            <name>QFIF</name>
                            <description>TXQ Full Interrupt Flag Channel n (n = 0, 1)</description>
                            <lsb>0</lsb>
                            <msb>2</msb>
                            <access>read-only</access>
                            <enumeratedValues>
                                </enumeratedValues>
                        </field>
                        <field>
                            <name>QOFRIF</name>
                            <description>TXQ One Frame RX Interrupt Flag Channel n (n = 0, 1)</description>
                            <lsb>8</lsb>
                            <msb>10</msb>
                            <access>read-only</access>
                            <enumeratedValues>
                                </enumeratedValues>
                        </field>
                        <field>
                            <name>CFRIF</name>
                            <description>Common FIFO RX Interrupt Flag Channel n (n = 0, 1)</description>
                            <lsb>16</lsb>
                            <msb>18</msb>
                            <access>read-only</access>
                            <enumeratedValues>
                                </enumeratedValues>
                        </field>
                        <field>
                            <name>CFRFIF</name>
                            <description>Common FIFO FDC Level Full Interrupt Flag Channel n (n = 0, 1)</description>
                            <lsb>24</lsb>
                            <msb>26</msb>
                            <access>read-only</access>
                            <enumeratedValues>
                                </enumeratedValues>
                        </field>
                        <field>
                            <name>CFOFRIF</name>
                            <description>Common FIFO One Frame RX Interrupt Flag Channel n (n = 0, 1)</description>
                            <lsb>28</lsb>
                            <msb>30</msb>
                            <access>read-only</access>
                            <enumeratedValues>
                                </enumeratedValues>
                        </field>
                    </fields>
                </register>
                <register>
                    <name>CFDGRSTC</name>
                    <description>Global SW reset Register</description>
                    <addressOffset>0x1380</addressOffset>
                    <size>32</size>
                    <access>read-write</access>
                    <resetValue>0x00000000</resetValue>
                    <resetMask>0xffffffff</resetMask>
                    <fields>
                        <field>
                            <name>SRST</name>
                            <description>SW Reset</description>
                            <lsb>0</lsb>
                            <msb>0</msb>
                            <access>read-write</access>
                            <enumeratedValues>
                                </enumeratedValues>
                        </field>
                        <field>
                            <name>KEY</name>
                            <description>Key Code</description>
                            <lsb>8</lsb>
                            <msb>15</msb>
                            <access>write-only</access>
                        </field>
                    </fields>
                </register>
                <register>
                    <dim>2</dim>
                    <dimIncrement>0x20</dimIncrement>
                    <dimIndex>0-1</dimIndex>
                    <name>CFDC%sDCFG</name>
                    <description>Channel %s Data Bitrate Configuration Register</description>
                    <addressOffset>0x1400</addressOffset>
                    <size>32</size>
                    <access>read-write</access>
                    <resetValue>0x00000000</resetValue>
                    <resetMask>0xffffffff</resetMask>
                    <fields>
                        <field>
                            <name>DBRP</name>
                            <description>Channel Data Baud Rate Prescaler</description>
                            <lsb>0</lsb>
                            <msb>7</msb>
                            <access>read-write</access>
                        </field>
                        <field>
                            <name>DTSEG1</name>
                            <description>Timing Segment 1</description>
                            <lsb>8</lsb>
                            <msb>12</msb>
                            <access>read-write</access>
                        </field>
                        <field>
                            <name>DTSEG2</name>
                            <description>Timing Segment 2</description>
                            <lsb>16</lsb>
                            <msb>19</msb>
                            <access>read-write</access>
                        </field>
                        <field>
                            <name>DSJW</name>
                            <description>Resynchronization Jump Width</description>
                            <lsb>24</lsb>
                            <msb>27</msb>
                            <access>read-write</access>
                        </field>
                    </fields>
                </register>
                <register>
                    <dim>2</dim>
                    <dimIncrement>0x20</dimIncrement>
                    <dimIndex>0-1</dimIndex>
                    <name>CFDC%sFDCFG</name>
                    <description>Channel %s CAN,FD Configuration Register</description>
                    <addressOffset>0x1404</addressOffset>
                    <size>32</size>
                    <access>read-write</access>
                    <resetValue>0x00000000</resetValue>
                    <resetMask>0xffffffff</resetMask>
                    <fields>
                        <field>
                            <name>EOCCFG</name>
                            <description>Error Occurrence Counter Configuration</description>
                            <lsb>0</lsb>
                            <msb>2</msb>
                            <access>read-write</access>
                            <enumeratedValues>
                                </enumeratedValues>
                        </field>
                        <field>
                            <name>TDCOC</name>
                            <description>Transceiver Delay Compensation Offset Configuration</description>
                            <lsb>8</lsb>
                            <msb>8</msb>
                            <access>read-write</access>
                            <enumeratedValues>
                                </enumeratedValues>
                        </field>
                        <field>
                            <name>TDCE</name>
                            <description>Transceiver Delay Compensation Enable</description>
                            <lsb>9</lsb>
                            <msb>9</msb>
                            <access>read-write</access>
                            <enumeratedValues>
                                </enumeratedValues>
                        </field>
                        <field>
                            <name>ESIC</name>
                            <description>Error State Indication Configuration</description>
                            <lsb>10</lsb>
                            <msb>10</msb>
                            <access>read-write</access>
                            <enumeratedValues>
                                </enumeratedValues>
                        </field>
                        <field>
                            <name>TDCO</name>
                            <description>Transceiver Delay Compensation Offset</description>
                            <lsb>16</lsb>
                            <msb>23</msb>
                            <access>read-write</access>
                        </field>
                        <field>
                            <name>GWEN</name>
                            <description>CAN2.0, CAN,FD Multi,Gateway Enable</description>
                            <lsb>24</lsb>
                            <msb>24</msb>
                            <access>read-write</access>
                            <enumeratedValues>
                                </enumeratedValues>
                        </field>
                        <field>
                            <name>GWFDF</name>
                            <description>Gateway FDF Configuration Bit</description>
                            <lsb>25</lsb>
                            <msb>25</msb>
                            <access>read-write</access>
                            <enumeratedValues>
                                </enumeratedValues>
                        </field>
                        <field>
                            <name>GWBRS</name>
                            <description>Gateway BRS Configuration Bit</description>
                            <lsb>26</lsb>
                            <msb>26</msb>
                            <access>read-write</access>
                            <enumeratedValues>
                                </enumeratedValues>
                        </field>
                        <field>
                            <name>FDOE</name>
                            <description>FD,Only Enable</description>
                            <lsb>28</lsb>
                            <msb>28</msb>
                            <access>read-write</access>
                            <enumeratedValues>
                                </enumeratedValues>
                        </field>
                        <field>
                            <name>REFE</name>
                            <description>RX Edge Filter Enable</description>
                            <lsb>29</lsb>
                            <msb>29</msb>
                            <access>read-write</access>
                            <enumeratedValues>
                                </enumeratedValues>
                        </field>
                        <field>
                            <name>CLOE</name>
                            <description>Classical CAN Enable</description>
                            <lsb>30</lsb>
                            <msb>30</msb>
                            <access>read-write</access>
                            <enumeratedValues>
                                </enumeratedValues>
                        </field>
                        <field>
                            <name>CFDTE</name>
                            <description>CAN,FD Frame Distinction Enable</description>
                            <lsb>31</lsb>
                            <msb>31</msb>
                            <access>read-write</access>
                            <enumeratedValues>
                                </enumeratedValues>
                        </field>
                    </fields>
                </register>
                <register>
                    <dim>2</dim>
                    <dimIncrement>0x20</dimIncrement>
                    <dimIndex>0-1</dimIndex>
                    <name>CFDC%sFDCTR</name>
                    <description>Channel %s CANFD Control Register</description>
                    <addressOffset>0x1408</addressOffset>
                    <size>32</size>
                    <access>read-write</access>
                    <resetValue>0x00000000</resetValue>
                    <resetMask>0xffffffff</resetMask>
                    <fields>
                        <field>
                            <name>EOCCLR</name>
                            <description>Error Occurrence Counter Clear</description>
                            <lsb>0</lsb>
                            <msb>0</msb>
                            <access>read-write</access>
                            <enumeratedValues>
                                </enumeratedValues>
                        </field>
                        <field>
                            <name>SOCCLR</name>
                            <description>Successful Occurrence Counter Clear</description>
                            <lsb>1</lsb>
                            <msb>1</msb>
                            <access>read-write</access>
                            <enumeratedValues>
                                </enumeratedValues>
                        </field>
                    </fields>
                </register>
                <register>
                    <dim>2</dim>
                    <dimIncrement>0x20</dimIncrement>
                    <dimIndex>0-1</dimIndex>
                    <name>CFDC%sFDSTS</name>
                    <description>Channel %s CANFD Status Register</description>
                    <addressOffset>0x140C</addressOffset>
                    <size>32</size>
                    <access>read-write</access>
                    <resetValue>0x00000000</resetValue>
                    <resetMask>0xffffffff</resetMask>
                    <fields>
                        <field>
                            <name>TDCR</name>
                            <description>Transceiver Delay Compensation Result</description>
                            <lsb>0</lsb>
                            <msb>7</msb>
                            <access>read-only</access>
                        </field>
                        <field>
                            <name>EOCO</name>
                            <description>Error Occurrence Counter Overflow</description>
                            <lsb>8</lsb>
                            <msb>8</msb>
                            <access>read-write</access>
                            <enumeratedValues>
                                </enumeratedValues>
                        </field>
                        <field>
                            <name>SOCO</name>
                            <description>Successful Occurrence Counter Overflow</description>
                            <lsb>9</lsb>
                            <msb>9</msb>
                            <access>read-write</access>
                            <enumeratedValues>
                                </enumeratedValues>
                        </field>
                        <field>
                            <name>TDCVF</name>
                            <description>Transceiver Delay Compensation Violation Flag</description>
                            <lsb>15</lsb>
                            <msb>15</msb>
                            <access>read-write</access>
                            <enumeratedValues>
                                </enumeratedValues>
                        </field>
                        <field>
                            <name>EOC</name>
                            <description>Error Occurrence Counter</description>
                            <lsb>16</lsb>
                            <msb>23</msb>
                            <access>read-only</access>
                        </field>
                        <field>
                            <name>SOC</name>
                            <description>Successful occurrence counter</description>
                            <lsb>24</lsb>
                            <msb>31</msb>
                            <access>read-only</access>
                        </field>
                    </fields>
                </register>
                <register>
                    <dim>2</dim>
                    <dimIncrement>0x20</dimIncrement>
                    <dimIndex>0-1</dimIndex>
                    <name>CFDC%sFDCRC</name>
                    <description>Channel %s CANFD CRC Register</description>
                    <addressOffset>0x1410</addressOffset>
                    <size>32</size>
                    <access>read-write</access>
                    <resetValue>0x00000000</resetValue>
                    <resetMask>0xffffffff</resetMask>
                    <fields>
                        <field>
                            <name>CRCREG</name>
                            <description>CRC Register value</description>
                            <lsb>0</lsb>
                            <msb>20</msb>
                            <access>read-only</access>
                        </field>
                        <field>
                            <name>SCNT</name>
                            <description>Stuff bit count</description>
                            <lsb>24</lsb>
                            <msb>27</msb>
                            <access>read-only</access>
                        </field>
                    </fields>
                </register>
                <register>
                    <dim>2</dim>
                    <dimIncrement>0x20</dimIncrement>
                    <dimIndex>0-1</dimIndex>
                    <name>CFDC%sBLCT</name>
                    <description>Channel %s Bus Load Control Register</description>
                    <addressOffset>0x1418</addressOffset>
                    <size>32</size>
                    <access>read-write</access>
                    <resetValue>0x00000000</resetValue>
                    <resetMask>0xffffffff</resetMask>
                    <fields>
                        <field>
                            <name>BLCE</name>
                            <description>Bus Load Counter Enable</description>
                            <lsb>0</lsb>
                            <msb>0</msb>
                            <access>read-write</access>
                            <enumeratedValues>
                                </enumeratedValues>
                        </field>
                        <field>
                            <name>BLCLD</name>
                            <description>BUS Load Counter Load</description>
                            <lsb>8</lsb>
                            <msb>8</msb>
                            <access>write-only</access>
                        </field>
                    </fields>
                </register>
                <register>
                    <dim>2</dim>
                    <dimIncrement>0x20</dimIncrement>
                    <dimIndex>0-1</dimIndex>
                    <name>CFDC%sBLSTS</name>
                    <description>Channel %s Bus Load Status Register</description>
                    <addressOffset>0x141C</addressOffset>
                    <size>32</size>
                    <access>read-write</access>
                    <resetValue>0x00000000</resetValue>
                    <resetMask>0xffffffff</resetMask>
                    <fields>
                        <field>
                            <name>BLC</name>
                            <description>Bus Load Counter</description>
                            <lsb>3</lsb>
                            <msb>31</msb>
                            <access>read-only</access>
                        </field>
                    </fields>
                </register>
                <register>
                    <dim>16</dim>
                    <dimIncrement>0x10</dimIncrement>
                    <dimIndex>1-16</dimIndex>
                    <name>CFDGAFLID%s</name>
                    <description>Global Acceptance Filter List ID Registers</description>
                    <addressOffset>0x1800</addressOffset>
                    <size>32</size>
                    <access>read-write</access>
                    <resetValue>0x00000000</resetValue>
                    <resetMask>0xffffffff</resetMask>
                    <fields>
                        <field>
                            <name>GAFLID</name>
                            <description>Global Acceptance Filter List Entry ID Field</description>
                            <lsb>0</lsb>
                            <msb>28</msb>
                            <access>read-write</access>
                        </field>
                        <field>
                            <name>GAFLLB</name>
                            <description>Global Acceptance Filter List Entry Loopback Configuration</description>
                            <lsb>29</lsb>
                            <msb>29</msb>
                            <access>read-write</access>
                            <enumeratedValues>
                                </enumeratedValues>
                        </field>
                        <field>
                            <name>GAFLRTR</name>
                            <description>Global Acceptance Filter List Entry RTR Field</description>
                            <lsb>30</lsb>
                            <msb>30</msb>
                            <access>read-write</access>
                            <enumeratedValues>
                                </enumeratedValues>
                        </field>
                        <field>
                            <name>GAFLIDE</name>
                            <description>Global Acceptance Filter List Entry IDE Field</description>
                            <lsb>31</lsb>
                            <msb>31</msb>
                            <access>read-write</access>
                            <enumeratedValues>
                                </enumeratedValues>
                        </field>
                    </fields>
                </register>
                <register>
                    <dim>16</dim>
                    <dimIncrement>0x10</dimIncrement>
                    <dimIndex>1-16</dimIndex>
                    <name>CFDGAFLM%s</name>
                    <description>Global Acceptance Filter List Mask Registers</description>
                    <addressOffset>0x1804</addressOffset>
                    <size>32</size>
                    <access>read-write</access>
                    <resetValue>0x00000000</resetValue>
                    <resetMask>0xffffffff</resetMask>
                    <fields>
                        <field>
                            <name>GAFLIDM</name>
                            <description>Global Acceptance Filter List ID Mask Field</description>
                            <lsb>0</lsb>
                            <msb>28</msb>
                            <access>read-write</access>
                        </field>
                        <field>
                            <name>GAFLIFL1</name>
                            <description>Global Acceptance Filter List Information Label 1</description>
                            <lsb>29</lsb>
                            <msb>29</msb>
                            <access>read-write</access>
                        </field>
                        <field>
                            <name>GAFLRTRM</name>
                            <description>Global Acceptance Filter List Entry RTR Mask</description>
                            <lsb>30</lsb>
                            <msb>30</msb>
                            <access>read-write</access>
                            <enumeratedValues>
                                </enumeratedValues>
                        </field>
                        <field>
                            <name>GAFLIDEM</name>
                            <description>Global Acceptance Filter List IDE Mask</description>
                            <lsb>31</lsb>
                            <msb>31</msb>
                            <access>read-write</access>
                            <enumeratedValues>
                                </enumeratedValues>
                        </field>
                    </fields>
                </register>
                <register>
                    <dim>16</dim>
                    <dimIncrement>0x10</dimIncrement>
                    <dimIndex>1-16</dimIndex>
                    <name>CFDGAFLP0%s</name>
                    <description>Global Acceptance Filter List Pointer 0 Registers</description>
                    <addressOffset>0x1808</addressOffset>
                    <size>32</size>
                    <access>read-write</access>
                    <resetValue>0x00000000</resetValue>
                    <resetMask>0xffffffff</resetMask>
                    <fields>
                        <field>
                            <name>GAFLDLC</name>
                            <description>Global Acceptance Filter List DLC Field</description>
                            <lsb>0</lsb>
                            <msb>3</msb>
                            <access>read-write</access>
                        </field>
                        <field>
                            <name>GAFLSRD0</name>
                            <description>Global Acceptance Filter List Select Routing Destination 0</description>
                            <lsb>4</lsb>
                            <msb>4</msb>
                            <access>read-write</access>
                            <enumeratedValues>
                                </enumeratedValues>
                        </field>
                        <field>
                            <name>GAFLSRD1</name>
                            <description>Global Acceptance Filter List Select Routing Destination 1</description>
                            <lsb>5</lsb>
                            <msb>5</msb>
                            <access>read-write</access>
                            <enumeratedValues>
                                </enumeratedValues>
                        </field>
                        <field>
                            <name>GAFLSRD2</name>
                            <description>Global Acceptance Filter List Select Routing Destination 2</description>
                            <lsb>6</lsb>
                            <msb>6</msb>
                            <access>read-write</access>
                            <enumeratedValues>
                                </enumeratedValues>
                        </field>
                        <field>
                            <name>GAFLIFL0</name>
                            <description>Global Acceptance Filter List Information Label 0</description>
                            <lsb>7</lsb>
                            <msb>7</msb>
                            <access>read-write</access>
                        </field>
                        <field>
                            <name>GAFLRMDP</name>
                            <description>Global Acceptance Filter List RX Message Buffer Direction Pointer</description>
                            <lsb>8</lsb>
                            <msb>12</msb>
                            <access>read-write</access>
                        </field>
                        <field>
                            <name>GAFLRMV</name>
                            <description>Global Acceptance Filter List RX Message Buffer Valid</description>
                            <lsb>15</lsb>
                            <msb>15</msb>
                            <access>read-write</access>
                            <enumeratedValues>
                                </enumeratedValues>
                        </field>
                        <field>
                            <name>GAFLPTR</name>
                            <description>Global Acceptance Filter List Pointer</description>
                            <lsb>16</lsb>
                            <msb>31</msb>
                            <access>read-write</access>
                        </field>
                    </fields>
                </register>
                <register>
                    <dim>16</dim>
                    <dimIncrement>0x10</dimIncrement>
                    <dimIndex>1-16</dimIndex>
                    <name>CFDGAFLP1%s</name>
                    <description>Global Acceptance Filter List Pointer 1 Registers</description>
                    <addressOffset>0x180C</addressOffset>
                    <size>32</size>
                    <access>read-write</access>
                    <resetValue>0x00000000</resetValue>
                    <resetMask>0xffffffff</resetMask>
                    <fields>
                        <field>
                            <name>GAFLFDP</name>
                            <description>Global Acceptance Filter List FIFO Direction Pointer</description>
                            <lsb>0</lsb>
                            <msb>13</msb>
                            <access>read-write</access>
                        </field>
                    </fields>
                </register>
                <register>
                    <dim>16</dim>
                    <dimIncrement>0x080</dimIncrement>
                    <dimIndex>0-15</dimIndex>
                    <name>CFDRMID%s_0</name>
                    <description>RX Message Buffer ID Register %s Channel 0</description>
                    <addressOffset>0x2000</addressOffset>
                    <size>32</size>
                    <access>read-only</access>
                    <resetValue>0x00000000</resetValue>
                    <resetMask>0xffffffff</resetMask>
                    <fields>
                        <field>
                            <name>RMID</name>
                            <description>RX Message Buffer ID Field</description>
                            <lsb>0</lsb>
                            <msb>28</msb>
                            <access>read-only</access>
                        </field>
                        <field>
                            <name>RMRTR</name>
                            <description>RX Message Buffer RTR Bit</description>
                            <lsb>30</lsb>
                            <msb>30</msb>
                            <access>read-only</access>
                            <enumeratedValues>
                                </enumeratedValues>
                        </field>
                        <field>
                            <name>RMIDE</name>
                            <description>RX Message Buffer IDE Bit</description>
                            <lsb>31</lsb>
                            <msb>31</msb>
                            <access>read-only</access>
                            <enumeratedValues>
                                </enumeratedValues>
                        </field>
                    </fields>
                </register>
                <register>
                    <dim>16</dim>
                    <dimIncrement>0x080</dimIncrement>
                    <dimIndex>0-15</dimIndex>
                    <name>CFDRMPTR%s_0</name>
                    <description>RX Message Buffer Pointer Register %s Channel 0</description>
                    <addressOffset>0x2004</addressOffset>
                    <size>32</size>
                    <access>read-only</access>
                    <resetValue>0x00000000</resetValue>
                    <resetMask>0xffffffff</resetMask>
                    <fields>
                        <field>
                            <name>RMTS</name>
                            <description>RX Message Buffer Timestamp Field</description>
                            <lsb>0</lsb>
                            <msb>15</msb>
                            <access>read-only</access>
                        </field>
                        <field>
                            <name>RMDLC</name>
                            <description>RX Message Buffer DLC Field</description>
                            <lsb>28</lsb>
                            <msb>31</msb>
                            <access>read-only</access>
                        </field>
                    </fields>
                </register>
                <register>
                    <dim>16</dim>
                    <dimIncrement>0x080</dimIncrement>
                    <dimIndex>0-15</dimIndex>
                    <name>CFDRMFDSTS%s_0</name>
                    <description>RX Message Buffer CAN,FD Status Register %s Channel 0</description>
                    <addressOffset>0x2008</addressOffset>
                    <size>32</size>
                    <access>read-only</access>
                    <resetValue>0x00000000</resetValue>
                    <resetMask>0xffffffff</resetMask>
                    <fields>
                        <field>
                            <name>RMESI</name>
                            <description>Error State Indicator bit</description>
                            <lsb>0</lsb>
                            <msb>0</msb>
                            <access>read-only</access>
                            <enumeratedValues>
                                </enumeratedValues>
                        </field>
                        <field>
                            <name>RMBRS</name>
                            <description>Bit Rate Switch bit</description>
                            <lsb>1</lsb>
                            <msb>1</msb>
                            <access>read-only</access>
                            <enumeratedValues>
                                </enumeratedValues>
                        </field>
                        <field>
                            <name>RMFDF</name>
                            <description>CAN FD Format bit</description>
                            <lsb>2</lsb>
                            <msb>2</msb>
                            <access>read-only</access>
                            <enumeratedValues>
                                </enumeratedValues>
                        </field>
                        <field>
                            <name>RMIFL</name>
                            <description>RX Message Buffer Information Label Field</description>
                            <lsb>8</lsb>
                            <msb>9</msb>
                            <access>read-only</access>
                        </field>
                        <field>
                            <name>RMPTR</name>
                            <description>RX Message Buffer Pointer Field</description>
                            <lsb>16</lsb>
                            <msb>31</msb>
                            <access>read-only</access>
                        </field>
                    </fields>
                </register>
                <register>
                    <dim>16</dim>
                    <dimIncrement>0x080</dimIncrement>
                    <dimIndex>0-15</dimIndex>
                    <name>CFDRMDF0_%s_0</name>
                    <description>RX Message Buffer Data Field 0 Register %s Channel 0</description>
                    <addressOffset>0x200C</addressOffset>
                    <size>32</size>
                    <access>read-only</access>
                    <resetValue>0x00000000</resetValue>
                    <resetMask>0xffffffff</resetMask>
                    <fields>
                        <field>
                            <name>RMDB_LL</name>
                            <description>RX Message Buffer Data Byte 0</description>
                            <lsb>0</lsb>
                            <msb>7</msb>
                            <access>read-only</access>
                        </field>
                        <field>
                            <name>RMDB_LH</name>
                            <description>RX Message Buffer Data Byte 1</description>
                            <lsb>8</lsb>
                            <msb>15</msb>
                            <access>read-only</access>
                        </field>
                        <field>
                            <name>RMDB_HL</name>
                            <description>RX Message Buffer Data Byte 2</description>
                            <lsb>16</lsb>
                            <msb>23</msb>
                            <access>read-only</access>
                        </field>
                        <field>
                            <name>RMDB_HH</name>
                            <description>RX Message Buffer Data Byte 3</description>
                            <lsb>24</lsb>
                            <msb>31</msb>
                            <access>read-only</access>
                        </field>
                    </fields>
                </register>
                <register>
                    <dim>16</dim>
                    <dimIncrement>0x080</dimIncrement>
                    <dimIndex>0-15</dimIndex>
                    <name>CFDRMDF1_%s_0</name>
                    <description>RX Message Buffer Data Field 1 Register %s Channel 0</description>
                    <addressOffset>0x2010</addressOffset>
                    <size>32</size>
                    <access>read-only</access>
                    <resetValue>0x00000000</resetValue>
                    <resetMask>0xffffffff</resetMask>
                    <fields>
                        <field>
                            <name>RMDB_LL</name>
                            <description>RX Message Buffer Data Byte 4</description>
                            <lsb>0</lsb>
                            <msb>7</msb>
                            <access>read-only</access>
                        </field>
                        <field>
                            <name>RMDB_LH</name>
                            <description>RX Message Buffer Data Byte 5</description>
                            <lsb>8</lsb>
                            <msb>15</msb>
                            <access>read-only</access>
                        </field>
                        <field>
                            <name>RMDB_HL</name>
                            <description>RX Message Buffer Data Byte 6</description>
                            <lsb>16</lsb>
                            <msb>23</msb>
                            <access>read-only</access>
                        </field>
                        <field>
                            <name>RMDB_HH</name>
                            <description>RX Message Buffer Data Byte 7</description>
                            <lsb>24</lsb>
                            <msb>31</msb>
                            <access>read-only</access>
                        </field>
                    </fields>
                </register>
                <register>
                    <dim>16</dim>
                    <dimIncrement>0x080</dimIncrement>
                    <dimIndex>0-15</dimIndex>
                    <name>CFDRMDF2_%s_0</name>
                    <description>RX Message Buffer Data Field 2 Register %s Channel 0</description>
                    <addressOffset>0x2014</addressOffset>
                    <size>32</size>
                    <access>read-only</access>
                    <resetValue>0x00000000</resetValue>
                    <resetMask>0xffffffff</resetMask>
                    <fields>
                        <field>
                            <name>RMDB_LL</name>
                            <description>RX Message Buffer Data Byte 8</description>
                            <lsb>0</lsb>
                            <msb>7</msb>
                            <access>read-only</access>
                        </field>
                        <field>
                            <name>RMDB_LH</name>
                            <description>RX Message Buffer Data Byte 9</description>
                            <lsb>8</lsb>
                            <msb>15</msb>
                            <access>read-only</access>
                        </field>
                        <field>
                            <name>RMDB_HL</name>
                            <description>RX Message Buffer Data Byte 10</description>
                            <lsb>16</lsb>
                            <msb>23</msb>
                            <access>read-only</access>
                        </field>
                        <field>
                            <name>RMDB_HH</name>
                            <description>RX Message Buffer Data Byte 11</description>
                            <lsb>24</lsb>
                            <msb>31</msb>
                            <access>read-only</access>
                        </field>
                    </fields>
                </register>
                <register>
                    <dim>16</dim>
                    <dimIncrement>0x080</dimIncrement>
                    <dimIndex>0-15</dimIndex>
                    <name>CFDRMDF3_%s_0</name>
                    <description>RX Message Buffer Data Field 3 Register %s Channel 0</description>
                    <addressOffset>0x2018</addressOffset>
                    <size>32</size>
                    <access>read-only</access>
                    <resetValue>0x00000000</resetValue>
                    <resetMask>0xffffffff</resetMask>
                    <fields>
                        <field>
                            <name>RMDB_LL</name>
                            <description>RX Message Buffer Data Byte 12</description>
                            <lsb>0</lsb>
                            <msb>7</msb>
                            <access>read-only</access>
                        </field>
                        <field>
                            <name>RMDB_LH</name>
                            <description>RX Message Buffer Data Byte 13</description>
                            <lsb>8</lsb>
                            <msb>15</msb>
                            <access>read-only</access>
                        </field>
                        <field>
                            <name>RMDB_HL</name>
                            <description>RX Message Buffer Data Byte 14</description>
                            <lsb>16</lsb>
                            <msb>23</msb>
                            <access>read-only</access>
                        </field>
                        <field>
                            <name>RMDB_HH</name>
                            <description>RX Message Buffer Data Byte 15</description>
                            <lsb>24</lsb>
                            <msb>31</msb>
                            <access>read-only</access>
                        </field>
                    </fields>
                </register>
                <register>
                    <dim>16</dim>
                    <dimIncrement>0x080</dimIncrement>
                    <dimIndex>0-15</dimIndex>
                    <name>CFDRMDF4_%s_0</name>
                    <description>RX Message Buffer Data Field 4 Register %s Channel 0</description>
                    <addressOffset>0x201C</addressOffset>
                    <size>32</size>
                    <access>read-only</access>
                    <resetValue>0x00000000</resetValue>
                    <resetMask>0xffffffff</resetMask>
                    <fields>
                        <field>
                            <name>RMDB_LL</name>
                            <description>RX Message Buffer Data Byte 16</description>
                            <lsb>0</lsb>
                            <msb>7</msb>
                            <access>read-only</access>
                        </field>
                        <field>
                            <name>RMDB_LH</name>
                            <description>RX Message Buffer Data Byte 17</description>
                            <lsb>8</lsb>
                            <msb>15</msb>
                            <access>read-only</access>
                        </field>
                        <field>
                            <name>RMDB_HL</name>
                            <description>RX Message Buffer Data Byte 18</description>
                            <lsb>16</lsb>
                            <msb>23</msb>
                            <access>read-only</access>
                        </field>
                        <field>
                            <name>RMDB_HH</name>
                            <description>RX Message Buffer Data Byte 19</description>
                            <lsb>24</lsb>
                            <msb>31</msb>
                            <access>read-only</access>
                        </field>
                    </fields>
                </register>
                <register>
                    <dim>16</dim>
                    <dimIncrement>0x080</dimIncrement>
                    <dimIndex>0-15</dimIndex>
                    <name>CFDRMDF5_%s_0</name>
                    <description>RX Message Buffer Data Field 5 Register %s Channel 0</description>
                    <addressOffset>0x2020</addressOffset>
                    <size>32</size>
                    <access>read-only</access>
                    <resetValue>0x00000000</resetValue>
                    <resetMask>0xffffffff</resetMask>
                    <fields>
                        <field>
                            <name>RMDB_LL</name>
                            <description>RX Message Buffer Data Byte 20</description>
                            <lsb>0</lsb>
                            <msb>7</msb>
                            <access>read-only</access>
                        </field>
                        <field>
                            <name>RMDB_LH</name>
                            <description>RX Message Buffer Data Byte 21</description>
                            <lsb>8</lsb>
                            <msb>15</msb>
                            <access>read-only</access>
                        </field>
                        <field>
                            <name>RMDB_HL</name>
                            <description>RX Message Buffer Data Byte 22</description>
                            <lsb>16</lsb>
                            <msb>23</msb>
                            <access>read-only</access>
                        </field>
                        <field>
                            <name>RMDB_HH</name>
                            <description>RX Message Buffer Data Byte 23</description>
                            <lsb>24</lsb>
                            <msb>31</msb>
                            <access>read-only</access>
                        </field>
                    </fields>
                </register>
                <register>
                    <dim>16</dim>
                    <dimIncrement>0x080</dimIncrement>
                    <dimIndex>0-15</dimIndex>
                    <name>CFDRMDF6_%s_0</name>
                    <description>RX Message Buffer Data Field 6 Register %s Channel 0</description>
                    <addressOffset>0x2024</addressOffset>
                    <size>32</size>
                    <access>read-only</access>
                    <resetValue>0x00000000</resetValue>
                    <resetMask>0xffffffff</resetMask>
                    <fields>
                        <field>
                            <name>RMDB_LL</name>
                            <description>RX Message Buffer Data Byte 24</description>
                            <lsb>0</lsb>
                            <msb>7</msb>
                            <access>read-only</access>
                        </field>
                        <field>
                            <name>RMDB_LH</name>
                            <description>RX Message Buffer Data Byte 25</description>
                            <lsb>8</lsb>
                            <msb>15</msb>
                            <access>read-only</access>
                        </field>
                        <field>
                            <name>RMDB_HL</name>
                            <description>RX Message Buffer Data Byte 26</description>
                            <lsb>16</lsb>
                            <msb>23</msb>
                            <access>read-only</access>
                        </field>
                        <field>
                            <name>RMDB_HH</name>
                            <description>RX Message Buffer Data Byte 27</description>
                            <lsb>24</lsb>
                            <msb>31</msb>
                            <access>read-only</access>
                        </field>
                    </fields>
                </register>
                <register>
                    <dim>16</dim>
                    <dimIncrement>0x080</dimIncrement>
                    <dimIndex>0-15</dimIndex>
                    <name>CFDRMDF7_%s_0</name>
                    <description>RX Message Buffer Data Field 7 Register %s Channel 0</description>
                    <addressOffset>0x2028</addressOffset>
                    <size>32</size>
                    <access>read-only</access>
                    <resetValue>0x00000000</resetValue>
                    <resetMask>0xffffffff</resetMask>
                    <fields>
                        <field>
                            <name>RMDB_LL</name>
                            <description>RX Message Buffer Data Byte 27</description>
                            <lsb>0</lsb>
                            <msb>7</msb>
                            <access>read-only</access>
                        </field>
                        <field>
                            <name>RMDB_LH</name>
                            <description>RX Message Buffer Data Byte 28</description>
                            <lsb>8</lsb>
                            <msb>15</msb>
                            <access>read-only</access>
                        </field>
                        <field>
                            <name>RMDB_HL</name>
                            <description>RX Message Buffer Data Byte 29</description>
                            <lsb>16</lsb>
                            <msb>23</msb>
                            <access>read-only</access>
                        </field>
                        <field>
                            <name>RMDB_HH</name>
                            <description>RX Message Buffer Data Byte 30</description>
                            <lsb>24</lsb>
                            <msb>31</msb>
                            <access>read-only</access>
                        </field>
                    </fields>
                </register>
                <register>
                    <dim>16</dim>
                    <dimIncrement>0x080</dimIncrement>
                    <dimIndex>0-15</dimIndex>
                    <name>CFDRMDF8_%s_0</name>
                    <description>RX Message Buffer Data Field 8 Register %s Channel 0</description>
                    <addressOffset>0x202C</addressOffset>
                    <size>32</size>
                    <access>read-only</access>
                    <resetValue>0x00000000</resetValue>
                    <resetMask>0xffffffff</resetMask>
                    <fields>
                        <field>
                            <name>RMDB_LL</name>
                            <description>RX Message Buffer Data Byte (p * 4)</description>
                            <lsb>0</lsb>
                            <msb>7</msb>
                            <access>read-only</access>
                        </field>
                        <field>
                            <name>RMDB_LH</name>
                            <description>RX Message Buffer Data Byte ((p * 4) + 1)</description>
                            <lsb>8</lsb>
                            <msb>15</msb>
                            <access>read-only</access>
                        </field>
                        <field>
                            <name>RMDB_HL</name>
                            <description>RX Message Buffer Data Byte ((p * 4) + 2)</description>
                            <lsb>16</lsb>
                            <msb>23</msb>
                            <access>read-only</access>
                        </field>
                        <field>
                            <name>RMDB_HH</name>
                            <description>RX Message Buffer Data Byte ((p * 4) + 3)</description>
                            <lsb>24</lsb>
                            <msb>31</msb>
                            <access>read-only</access>
                        </field>
                    </fields>
                </register>
                <register>
                    <dim>16</dim>
                    <dimIncrement>0x080</dimIncrement>
                    <dimIndex>0-15</dimIndex>
                    <name>CFDRMDF9_%s_0</name>
                    <description>RX Message Buffer Data Field 9 Register %s Channel 0</description>
                    <addressOffset>0x2030</addressOffset>
                    <size>32</size>
                    <access>read-only</access>
                    <resetValue>0x00000000</resetValue>
                    <resetMask>0xffffffff</resetMask>
                    <fields>
                        <field>
                            <name>RMDB_LL</name>
                            <description>RX Message Buffer Data Byte 36</description>
                            <lsb>0</lsb>
                            <msb>7</msb>
                            <access>read-only</access>
                        </field>
                        <field>
                            <name>RMDB_LH</name>
                            <description>RX Message Buffer Data Byte 37</description>
                            <lsb>8</lsb>
                            <msb>15</msb>
                            <access>read-only</access>
                        </field>
                        <field>
                            <name>RMDB_HL</name>
                            <description>RX Message Buffer Data Byte 38</description>
                            <lsb>16</lsb>
                            <msb>23</msb>
                            <access>read-only</access>
                        </field>
                        <field>
                            <name>RMDB_HH</name>
                            <description>RX Message Buffer Data Byte 39</description>
                            <lsb>24</lsb>
                            <msb>31</msb>
                            <access>read-only</access>
                        </field>
                    </fields>
                </register>
                <register>
                    <dim>16</dim>
                    <dimIncrement>0x080</dimIncrement>
                    <dimIndex>0-15</dimIndex>
                    <name>CFDRMDF10_%s_0</name>
                    <description>RX Message Buffer Data Field 10 Register %s Channel 0</description>
                    <addressOffset>0x2034</addressOffset>
                    <size>32</size>
                    <access>read-only</access>
                    <resetValue>0x00000000</resetValue>
                    <resetMask>0xffffffff</resetMask>
                    <fields>
                        <field>
                            <name>RMDB_LL</name>
                            <description>RX Message Buffer Data Byte 40</description>
                            <lsb>0</lsb>
                            <msb>7</msb>
                            <access>read-only</access>
                        </field>
                        <field>
                            <name>RMDB_LH</name>
                            <description>RX Message Buffer Data Byte 41</description>
                            <lsb>8</lsb>
                            <msb>15</msb>
                            <access>read-only</access>
                        </field>
                        <field>
                            <name>RMDB_HL</name>
                            <description>RX Message Buffer Data Byte 42</description>
                            <lsb>16</lsb>
                            <msb>23</msb>
                            <access>read-only</access>
                        </field>
                        <field>
                            <name>RMDB_HH</name>
                            <description>RX Message Buffer Data Byte 43</description>
                            <lsb>24</lsb>
                            <msb>31</msb>
                            <access>read-only</access>
                        </field>
                    </fields>
                </register>
                <register>
                    <dim>16</dim>
                    <dimIncrement>0x080</dimIncrement>
                    <dimIndex>0-15</dimIndex>
                    <name>CFDRMDF11_%s_0</name>
                    <description>RX Message Buffer Data Field 11 Register %s Channel 0</description>
                    <addressOffset>0x2038</addressOffset>
                    <size>32</size>
                    <access>read-only</access>
                    <resetValue>0x00000000</resetValue>
                    <resetMask>0xffffffff</resetMask>
                    <fields>
                        <field>
                            <name>RMDB_LL</name>
                            <description>RX Message Buffer Data Byte 44</description>
                            <lsb>0</lsb>
                            <msb>7</msb>
                            <access>read-only</access>
                        </field>
                        <field>
                            <name>RMDB_LH</name>
                            <description>RX Message Buffer Data Byte 45</description>
                            <lsb>8</lsb>
                            <msb>15</msb>
                            <access>read-only</access>
                        </field>
                        <field>
                            <name>RMDB_HL</name>
                            <description>RX Message Buffer Data Byte 46</description>
                            <lsb>16</lsb>
                            <msb>23</msb>
                            <access>read-only</access>
                        </field>
                        <field>
                            <name>RMDB_HH</name>
                            <description>RX Message Buffer Data Byte 47</description>
                            <lsb>24</lsb>
                            <msb>31</msb>
                            <access>read-only</access>
                        </field>
                    </fields>
                </register>
                <register>
                    <dim>16</dim>
                    <dimIncrement>0x080</dimIncrement>
                    <dimIndex>0-15</dimIndex>
                    <name>CFDRMDF12_%s_0</name>
                    <description>RX Message Buffer Data Field 12 Register %s Channel 0</description>
                    <addressOffset>0x203C</addressOffset>
                    <size>32</size>
                    <access>read-only</access>
                    <resetValue>0x00000000</resetValue>
                    <resetMask>0xffffffff</resetMask>
                    <fields>
                        <field>
                            <name>RMDB_LL</name>
                            <description>RX Message Buffer Data Byte 48</description>
                            <lsb>0</lsb>
                            <msb>7</msb>
                            <access>read-only</access>
                        </field>
                        <field>
                            <name>RMDB_LH</name>
                            <description>RX Message Buffer Data Byte 49</description>
                            <lsb>8</lsb>
                            <msb>15</msb>
                            <access>read-only</access>
                        </field>
                        <field>
                            <name>RMDB_HL</name>
                            <description>RX Message Buffer Data Byte 50</description>
                            <lsb>16</lsb>
                            <msb>23</msb>
                            <access>read-only</access>
                        </field>
                        <field>
                            <name>RMDB_HH</name>
                            <description>RX Message Buffer Data Byte 51</description>
                            <lsb>24</lsb>
                            <msb>31</msb>
                            <access>read-only</access>
                        </field>
                    </fields>
                </register>
                <register>
                    <dim>16</dim>
                    <dimIncrement>0x080</dimIncrement>
                    <dimIndex>0-15</dimIndex>
                    <name>CFDRMDF13_%s_0</name>
                    <description>RX Message Buffer Data Field 13 Register %s Channel 0</description>
                    <addressOffset>0x2040</addressOffset>
                    <size>32</size>
                    <access>read-only</access>
                    <resetValue>0x00000000</resetValue>
                    <resetMask>0xffffffff</resetMask>
                    <fields>
                        <field>
                            <name>RMDB_LL</name>
                            <description>RX Message Buffer Data Byte 52</description>
                            <lsb>0</lsb>
                            <msb>7</msb>
                            <access>read-only</access>
                        </field>
                        <field>
                            <name>RMDB_LH</name>
                            <description>RX Message Buffer Data Byte 53</description>
                            <lsb>8</lsb>
                            <msb>15</msb>
                            <access>read-only</access>
                        </field>
                        <field>
                            <name>RMDB_HL</name>
                            <description>RX Message Buffer Data Byte 54</description>
                            <lsb>16</lsb>
                            <msb>23</msb>
                            <access>read-only</access>
                        </field>
                        <field>
                            <name>RMDB_HH</name>
                            <description>RX Message Buffer Data Byte 55</description>
                            <lsb>24</lsb>
                            <msb>31</msb>
                            <access>read-only</access>
                        </field>
                    </fields>
                </register>
                <register>
                    <dim>16</dim>
                    <dimIncrement>0x080</dimIncrement>
                    <dimIndex>0-15</dimIndex>
                    <name>CFDRMDF14_%s_0</name>
                    <description>RX Message Buffer Data Field 14 Register %s Channel 0</description>
                    <addressOffset>0x2044</addressOffset>
                    <size>32</size>
                    <access>read-only</access>
                    <resetValue>0x00000000</resetValue>
                    <resetMask>0xffffffff</resetMask>
                    <fields>
                        <field>
                            <name>RMDB_LL</name>
                            <description>RX Message Buffer Data Byte 56</description>
                            <lsb>0</lsb>
                            <msb>7</msb>
                            <access>read-only</access>
                        </field>
                        <field>
                            <name>RMDB_LH</name>
                            <description>RX Message Buffer Data Byte 57</description>
                            <lsb>8</lsb>
                            <msb>15</msb>
                            <access>read-only</access>
                        </field>
                        <field>
                            <name>RMDB_HL</name>
                            <description>RX Message Buffer Data Byte 58</description>
                            <lsb>16</lsb>
                            <msb>23</msb>
                            <access>read-only</access>
                        </field>
                        <field>
                            <name>RMDB_HH</name>
                            <description>RX Message Buffer Data Byte 59</description>
                            <lsb>24</lsb>
                            <msb>31</msb>
                            <access>read-only</access>
                        </field>
                    </fields>
                </register>
                <register>
                    <dim>16</dim>
                    <dimIncrement>0x080</dimIncrement>
                    <dimIndex>0-15</dimIndex>
                    <name>CFDRMDF15_%s_0</name>
                    <description>RX Message Buffer Data Field 15 Register %s Channel 0</description>
                    <addressOffset>0x2048</addressOffset>
                    <size>32</size>
                    <access>read-only</access>
                    <resetValue>0x00000000</resetValue>
                    <resetMask>0xffffffff</resetMask>
                    <fields>
                        <field>
                            <name>RMDB_LL</name>
                            <description>RX Message Buffer Data Byte 60</description>
                            <lsb>0</lsb>
                            <msb>7</msb>
                            <access>read-only</access>
                        </field>
                        <field>
                            <name>RMDB_LH</name>
                            <description>RX Message Buffer Data Byte 61</description>
                            <lsb>8</lsb>
                            <msb>15</msb>
                            <access>read-only</access>
                        </field>
                        <field>
                            <name>RMDB_HL</name>
                            <description>RX Message Buffer Data Byte 62</description>
                            <lsb>16</lsb>
                            <msb>23</msb>
                            <access>read-only</access>
                        </field>
                        <field>
                            <name>RMDB_HH</name>
                            <description>RX Message Buffer Data Byte 63</description>
                            <lsb>24</lsb>
                            <msb>31</msb>
                            <access>read-only</access>
                        </field>
                    </fields>
                </register>
                <register>
                    <dim>16</dim>
                    <dimIncrement>0x080</dimIncrement>
                    <dimIndex>0-15</dimIndex>
                    <name>CFDRMID%s_1</name>
                    <description>RX Message Buffer ID Register %s Channel 1</description>
                    <addressOffset>0x2800</addressOffset>
                    <size>32</size>
                    <access>read-only</access>
                    <resetValue>0x00000000</resetValue>
                    <resetMask>0xffffffff</resetMask>
                    <fields>
                        <field>
                            <name>RMID</name>
                            <description>RX Message Buffer ID Field</description>
                            <lsb>0</lsb>
                            <msb>28</msb>
                            <access>read-only</access>
                        </field>
                        <field>
                            <name>RMRTR</name>
                            <description>RX Message Buffer RTR Bit</description>
                            <lsb>30</lsb>
                            <msb>30</msb>
                            <access>read-only</access>
                            <enumeratedValues>
                                </enumeratedValues>
                        </field>
                        <field>
                            <name>RMIDE</name>
                            <description>RX Message Buffer IDE Bit</description>
                            <lsb>31</lsb>
                            <msb>31</msb>
                            <access>read-only</access>
                            <enumeratedValues>
                                </enumeratedValues>
                        </field>
                    </fields>
                </register>
                <register>
                    <dim>16</dim>
                    <dimIncrement>0x080</dimIncrement>
                    <dimIndex>0-15</dimIndex>
                    <name>CFDRMPTR%s_1</name>
                    <description>RX Message Buffer Pointer Register %s Channel 1</description>
                    <addressOffset>0x2804</addressOffset>
                    <size>32</size>
                    <access>read-only</access>
                    <resetValue>0x00000000</resetValue>
                    <resetMask>0xffffffff</resetMask>
                    <fields>
                        <field>
                            <name>RMTS</name>
                            <description>RX Message Buffer Timestamp Field</description>
                            <lsb>0</lsb>
                            <msb>15</msb>
                            <access>read-only</access>
                        </field>
                        <field>
                            <name>RMDLC</name>
                            <description>RX Message Buffer DLC Field</description>
                            <lsb>28</lsb>
                            <msb>31</msb>
                            <access>read-only</access>
                        </field>
                    </fields>
                </register>
                <register>
                    <dim>16</dim>
                    <dimIncrement>0x080</dimIncrement>
                    <dimIndex>0-15</dimIndex>
                    <name>CFDRMFDSTS%s_1</name>
                    <description>RX Message Buffer CAN,FD Status Register %s Channel 1</description>
                    <addressOffset>0x2808</addressOffset>
                    <size>32</size>
                    <access>read-only</access>
                    <resetValue>0x00000000</resetValue>
                    <resetMask>0xffffffff</resetMask>
                    <fields>
                        <field>
                            <name>RMESI</name>
                            <description>Error State Indicator bit</description>
                            <lsb>0</lsb>
                            <msb>0</msb>
                            <access>read-only</access>
                            <enumeratedValues>
                                </enumeratedValues>
                        </field>
                        <field>
                            <name>RMBRS</name>
                            <description>Bit Rate Switch bit</description>
                            <lsb>1</lsb>
                            <msb>1</msb>
                            <access>read-only</access>
                            <enumeratedValues>
                                </enumeratedValues>
                        </field>
                        <field>
                            <name>RMFDF</name>
                            <description>CAN FD Format bit</description>
                            <lsb>2</lsb>
                            <msb>2</msb>
                            <access>read-only</access>
                            <enumeratedValues>
                                </enumeratedValues>
                        </field>
                        <field>
                            <name>RMIFL</name>
                            <description>RX Message Buffer Information Label Field</description>
                            <lsb>8</lsb>
                            <msb>9</msb>
                            <access>read-only</access>
                        </field>
                        <field>
                            <name>RMPTR</name>
                            <description>RX Message Buffer Pointer Field</description>
                            <lsb>16</lsb>
                            <msb>31</msb>
                            <access>read-only</access>
                        </field>
                    </fields>
                </register>
                <register>
                    <dim>16</dim>
                    <dimIncrement>0x080</dimIncrement>
                    <dimIndex>0-15</dimIndex>
                    <name>CFDRMDF0_%s_1</name>
                    <description>RX Message Buffer Data Field 0 Register %s Channel 1</description>
                    <addressOffset>0x280C</addressOffset>
                    <size>32</size>
                    <access>read-only</access>
                    <resetValue>0x00000000</resetValue>
                    <resetMask>0xffffffff</resetMask>
                    <fields>
                        <field>
                            <name>RMDB_LL</name>
                            <description>RX Message Buffer Data Byte 0</description>
                            <lsb>0</lsb>
                            <msb>7</msb>
                            <access>read-only</access>
                        </field>
                        <field>
                            <name>RMDB_LH</name>
                            <description>RX Message Buffer Data Byte 1</description>
                            <lsb>8</lsb>
                            <msb>15</msb>
                            <access>read-only</access>
                        </field>
                        <field>
                            <name>RMDB_HL</name>
                            <description>RX Message Buffer Data Byte 2</description>
                            <lsb>16</lsb>
                            <msb>23</msb>
                            <access>read-only</access>
                        </field>
                        <field>
                            <name>RMDB_HH</name>
                            <description>RX Message Buffer Data Byte 3</description>
                            <lsb>24</lsb>
                            <msb>31</msb>
                            <access>read-only</access>
                        </field>
                    </fields>
                </register>
                <register>
                    <dim>16</dim>
                    <dimIncrement>0x080</dimIncrement>
                    <dimIndex>0-15</dimIndex>
                    <name>CFDRMDF1_%s_1</name>
                    <description>RX Message Buffer Data Field 1 Register %s Channel 1</description>
                    <addressOffset>0x2810</addressOffset>
                    <size>32</size>
                    <access>read-only</access>
                    <resetValue>0x00000000</resetValue>
                    <resetMask>0xffffffff</resetMask>
                    <fields>
                        <field>
                            <name>RMDB_LL</name>
                            <description>RX Message Buffer Data Byte 4</description>
                            <lsb>0</lsb>
                            <msb>7</msb>
                            <access>read-only</access>
                        </field>
                        <field>
                            <name>RMDB_LH</name>
                            <description>RX Message Buffer Data Byte 5</description>
                            <lsb>8</lsb>
                            <msb>15</msb>
                            <access>read-only</access>
                        </field>
                        <field>
                            <name>RMDB_HL</name>
                            <description>RX Message Buffer Data Byte 6</description>
                            <lsb>16</lsb>
                            <msb>23</msb>
                            <access>read-only</access>
                        </field>
                        <field>
                            <name>RMDB_HH</name>
                            <description>RX Message Buffer Data Byte 7</description>
                            <lsb>24</lsb>
                            <msb>31</msb>
                            <access>read-only</access>
                        </field>
                    </fields>
                </register>
                <register>
                    <dim>16</dim>
                    <dimIncrement>0x080</dimIncrement>
                    <dimIndex>0-15</dimIndex>
                    <name>CFDRMDF2_%s_1</name>
                    <description>RX Message Buffer Data Field 2 Register %s Channel 1</description>
                    <addressOffset>0x2814</addressOffset>
                    <size>32</size>
                    <access>read-only</access>
                    <resetValue>0x00000000</resetValue>
                    <resetMask>0xffffffff</resetMask>
                    <fields>
                        <field>
                            <name>RMDB_LL</name>
                            <description>RX Message Buffer Data Byte 8</description>
                            <lsb>0</lsb>
                            <msb>7</msb>
                            <access>read-only</access>
                        </field>
                        <field>
                            <name>RMDB_LH</name>
                            <description>RX Message Buffer Data Byte 9</description>
                            <lsb>8</lsb>
                            <msb>15</msb>
                            <access>read-only</access>
                        </field>
                        <field>
                            <name>RMDB_HL</name>
                            <description>RX Message Buffer Data Byte 10</description>
                            <lsb>16</lsb>
                            <msb>23</msb>
                            <access>read-only</access>
                        </field>
                        <field>
                            <name>RMDB_HH</name>
                            <description>RX Message Buffer Data Byte 11</description>
                            <lsb>24</lsb>
                            <msb>31</msb>
                            <access>read-only</access>
                        </field>
                    </fields>
                </register>
                <register>
                    <dim>16</dim>
                    <dimIncrement>0x080</dimIncrement>
                    <dimIndex>0-15</dimIndex>
                    <name>CFDRMDF3_%s_1</name>
                    <description>RX Message Buffer Data Field 3 Register %s Channel 1</description>
                    <addressOffset>0x2818</addressOffset>
                    <size>32</size>
                    <access>read-only</access>
                    <resetValue>0x00000000</resetValue>
                    <resetMask>0xffffffff</resetMask>
                    <fields>
                        <field>
                            <name>RMDB_LL</name>
                            <description>RX Message Buffer Data Byte 12</description>
                            <lsb>0</lsb>
                            <msb>7</msb>
                            <access>read-only</access>
                        </field>
                        <field>
                            <name>RMDB_LH</name>
                            <description>RX Message Buffer Data Byte 13</description>
                            <lsb>8</lsb>
                            <msb>15</msb>
                            <access>read-only</access>
                        </field>
                        <field>
                            <name>RMDB_HL</name>
                            <description>RX Message Buffer Data Byte 14</description>
                            <lsb>16</lsb>
                            <msb>23</msb>
                            <access>read-only</access>
                        </field>
                        <field>
                            <name>RMDB_HH</name>
                            <description>RX Message Buffer Data Byte 15</description>
                            <lsb>24</lsb>
                            <msb>31</msb>
                            <access>read-only</access>
                        </field>
                    </fields>
                </register>
                <register>
                    <dim>16</dim>
                    <dimIncrement>0x080</dimIncrement>
                    <dimIndex>0-15</dimIndex>
                    <name>CFDRMDF4_%s_1</name>
                    <description>RX Message Buffer Data Field 4 Register %s Channel 1</description>
                    <addressOffset>0x281C</addressOffset>
                    <size>32</size>
                    <access>read-only</access>
                    <resetValue>0x00000000</resetValue>
                    <resetMask>0xffffffff</resetMask>
                    <fields>
                        <field>
                            <name>RMDB_LL</name>
                            <description>RX Message Buffer Data Byte 16</description>
                            <lsb>0</lsb>
                            <msb>7</msb>
                            <access>read-only</access>
                        </field>
                        <field>
                            <name>RMDB_LH</name>
                            <description>RX Message Buffer Data Byte 17</description>
                            <lsb>8</lsb>
                            <msb>15</msb>
                            <access>read-only</access>
                        </field>
                        <field>
                            <name>RMDB_HL</name>
                            <description>RX Message Buffer Data Byte 18</description>
                            <lsb>16</lsb>
                            <msb>23</msb>
                            <access>read-only</access>
                        </field>
                        <field>
                            <name>RMDB_HH</name>
                            <description>RX Message Buffer Data Byte 19</description>
                            <lsb>24</lsb>
                            <msb>31</msb>
                            <access>read-only</access>
                        </field>
                    </fields>
                </register>
                <register>
                    <dim>16</dim>
                    <dimIncrement>0x080</dimIncrement>
                    <dimIndex>0-15</dimIndex>
                    <name>CFDRMDF5_%s_1</name>
                    <description>RX Message Buffer Data Field 5 Register %s Channel 1</description>
                    <addressOffset>0x2820</addressOffset>
                    <size>32</size>
                    <access>read-only</access>
                    <resetValue>0x00000000</resetValue>
                    <resetMask>0xffffffff</resetMask>
                    <fields>
                        <field>
                            <name>RMDB_LL</name>
                            <description>RX Message Buffer Data Byte 20</description>
                            <lsb>0</lsb>
                            <msb>7</msb>
                            <access>read-only</access>
                        </field>
                        <field>
                            <name>RMDB_LH</name>
                            <description>RX Message Buffer Data Byte 21</description>
                            <lsb>8</lsb>
                            <msb>15</msb>
                            <access>read-only</access>
                        </field>
                        <field>
                            <name>RMDB_HL</name>
                            <description>RX Message Buffer Data Byte 22</description>
                            <lsb>16</lsb>
                            <msb>23</msb>
                            <access>read-only</access>
                        </field>
                        <field>
                            <name>RMDB_HH</name>
                            <description>RX Message Buffer Data Byte 23</description>
                            <lsb>24</lsb>
                            <msb>31</msb>
                            <access>read-only</access>
                        </field>
                    </fields>
                </register>
                <register>
                    <dim>16</dim>
                    <dimIncrement>0x080</dimIncrement>
                    <dimIndex>0-15</dimIndex>
                    <name>CFDRMDF6_%s_1</name>
                    <description>RX Message Buffer Data Field 6 Register %s Channel 1</description>
                    <addressOffset>0x2824</addressOffset>
                    <size>32</size>
                    <access>read-only</access>
                    <resetValue>0x00000000</resetValue>
                    <resetMask>0xffffffff</resetMask>
                    <fields>
                        <field>
                            <name>RMDB_LL</name>
                            <description>RX Message Buffer Data Byte 24</description>
                            <lsb>0</lsb>
                            <msb>7</msb>
                            <access>read-only</access>
                        </field>
                        <field>
                            <name>RMDB_LH</name>
                            <description>RX Message Buffer Data Byte 25</description>
                            <lsb>8</lsb>
                            <msb>15</msb>
                            <access>read-only</access>
                        </field>
                        <field>
                            <name>RMDB_HL</name>
                            <description>RX Message Buffer Data Byte 26</description>
                            <lsb>16</lsb>
                            <msb>23</msb>
                            <access>read-only</access>
                        </field>
                        <field>
                            <name>RMDB_HH</name>
                            <description>RX Message Buffer Data Byte 27</description>
                            <lsb>24</lsb>
                            <msb>31</msb>
                            <access>read-only</access>
                        </field>
                    </fields>
                </register>
                <register>
                    <dim>16</dim>
                    <dimIncrement>0x080</dimIncrement>
                    <dimIndex>0-15</dimIndex>
                    <name>CFDRMDF7_%s_1</name>
                    <description>RX Message Buffer Data Field 7 Register %s Channel 1</description>
                    <addressOffset>0x2828</addressOffset>
                    <size>32</size>
                    <access>read-only</access>
                    <resetValue>0x00000000</resetValue>
                    <resetMask>0xffffffff</resetMask>
                    <fields>
                        <field>
                            <name>RMDB_LL</name>
                            <description>RX Message Buffer Data Byte 27</description>
                            <lsb>0</lsb>
                            <msb>7</msb>
                            <access>read-only</access>
                        </field>
                        <field>
                            <name>RMDB_LH</name>
                            <description>RX Message Buffer Data Byte 28</description>
                            <lsb>8</lsb>
                            <msb>15</msb>
                            <access>read-only</access>
                        </field>
                        <field>
                            <name>RMDB_HL</name>
                            <description>RX Message Buffer Data Byte 29</description>
                            <lsb>16</lsb>
                            <msb>23</msb>
                            <access>read-only</access>
                        </field>
                        <field>
                            <name>RMDB_HH</name>
                            <description>RX Message Buffer Data Byte 30</description>
                            <lsb>24</lsb>
                            <msb>31</msb>
                            <access>read-only</access>
                        </field>
                    </fields>
                </register>
                <register>
                    <dim>16</dim>
                    <dimIncrement>0x080</dimIncrement>
                    <dimIndex>0-15</dimIndex>
                    <name>CFDRMDF8_%s_1</name>
                    <description>RX Message Buffer Data Field 8 Register %s Channel 1</description>
                    <addressOffset>0x282C</addressOffset>
                    <size>32</size>
                    <access>read-only</access>
                    <resetValue>0x00000000</resetValue>
                    <resetMask>0xffffffff</resetMask>
                    <fields>
                        <field>
                            <name>RMDB_LL</name>
                            <description>RX Message Buffer Data Byte (p * 4)</description>
                            <lsb>0</lsb>
                            <msb>7</msb>
                            <access>read-only</access>
                        </field>
                        <field>
                            <name>RMDB_LH</name>
                            <description>RX Message Buffer Data Byte ((p * 4) + 1)</description>
                            <lsb>8</lsb>
                            <msb>15</msb>
                            <access>read-only</access>
                        </field>
                        <field>
                            <name>RMDB_HL</name>
                            <description>RX Message Buffer Data Byte ((p * 4) + 2)</description>
                            <lsb>16</lsb>
                            <msb>23</msb>
                            <access>read-only</access>
                        </field>
                        <field>
                            <name>RMDB_HH</name>
                            <description>RX Message Buffer Data Byte ((p * 4) + 3)</description>
                            <lsb>24</lsb>
                            <msb>31</msb>
                            <access>read-only</access>
                        </field>
                    </fields>
                </register>
                <register>
                    <dim>16</dim>
                    <dimIncrement>0x080</dimIncrement>
                    <dimIndex>0-15</dimIndex>
                    <name>CFDRMDF9_%s_1</name>
                    <description>RX Message Buffer Data Field 9 Register %s Channel 1</description>
                    <addressOffset>0x2830</addressOffset>
                    <size>32</size>
                    <access>read-only</access>
                    <resetValue>0x00000000</resetValue>
                    <resetMask>0xffffffff</resetMask>
                    <fields>
                        <field>
                            <name>RMDB_LL</name>
                            <description>RX Message Buffer Data Byte 36</description>
                            <lsb>0</lsb>
                            <msb>7</msb>
                            <access>read-only</access>
                        </field>
                        <field>
                            <name>RMDB_LH</name>
                            <description>RX Message Buffer Data Byte 37</description>
                            <lsb>8</lsb>
                            <msb>15</msb>
                            <access>read-only</access>
                        </field>
                        <field>
                            <name>RMDB_HL</name>
                            <description>RX Message Buffer Data Byte 38</description>
                            <lsb>16</lsb>
                            <msb>23</msb>
                            <access>read-only</access>
                        </field>
                        <field>
                            <name>RMDB_HH</name>
                            <description>RX Message Buffer Data Byte 39</description>
                            <lsb>24</lsb>
                            <msb>31</msb>
                            <access>read-only</access>
                        </field>
                    </fields>
                </register>
                <register>
                    <dim>16</dim>
                    <dimIncrement>0x080</dimIncrement>
                    <dimIndex>0-15</dimIndex>
                    <name>CFDRMDF10_%s_1</name>
                    <description>RX Message Buffer Data Field 10 Register %s Channel 1</description>
                    <addressOffset>0x2834</addressOffset>
                    <size>32</size>
                    <access>read-only</access>
                    <resetValue>0x00000000</resetValue>
                    <resetMask>0xffffffff</resetMask>
                    <fields>
                        <field>
                            <name>RMDB_LL</name>
                            <description>RX Message Buffer Data Byte 40</description>
                            <lsb>0</lsb>
                            <msb>7</msb>
                            <access>read-only</access>
                        </field>
                        <field>
                            <name>RMDB_LH</name>
                            <description>RX Message Buffer Data Byte 41</description>
                            <lsb>8</lsb>
                            <msb>15</msb>
                            <access>read-only</access>
                        </field>
                        <field>
                            <name>RMDB_HL</name>
                            <description>RX Message Buffer Data Byte 42</description>
                            <lsb>16</lsb>
                            <msb>23</msb>
                            <access>read-only</access>
                        </field>
                        <field>
                            <name>RMDB_HH</name>
                            <description>RX Message Buffer Data Byte 43</description>
                            <lsb>24</lsb>
                            <msb>31</msb>
                            <access>read-only</access>
                        </field>
                    </fields>
                </register>
                <register>
                    <dim>16</dim>
                    <dimIncrement>0x080</dimIncrement>
                    <dimIndex>0-15</dimIndex>
                    <name>CFDRMDF11_%s_1</name>
                    <description>RX Message Buffer Data Field 11 Register %s Channel 1</description>
                    <addressOffset>0x2838</addressOffset>
                    <size>32</size>
                    <access>read-only</access>
                    <resetValue>0x00000000</resetValue>
                    <resetMask>0xffffffff</resetMask>
                    <fields>
                        <field>
                            <name>RMDB_LL</name>
                            <description>RX Message Buffer Data Byte 44</description>
                            <lsb>0</lsb>
                            <msb>7</msb>
                            <access>read-only</access>
                        </field>
                        <field>
                            <name>RMDB_LH</name>
                            <description>RX Message Buffer Data Byte 45</description>
                            <lsb>8</lsb>
                            <msb>15</msb>
                            <access>read-only</access>
                        </field>
                        <field>
                            <name>RMDB_HL</name>
                            <description>RX Message Buffer Data Byte 46</description>
                            <lsb>16</lsb>
                            <msb>23</msb>
                            <access>read-only</access>
                        </field>
                        <field>
                            <name>RMDB_HH</name>
                            <description>RX Message Buffer Data Byte 47</description>
                            <lsb>24</lsb>
                            <msb>31</msb>
                            <access>read-only</access>
                        </field>
                    </fields>
                </register>
                <register>
                    <dim>16</dim>
                    <dimIncrement>0x080</dimIncrement>
                    <dimIndex>0-15</dimIndex>
                    <name>CFDRMDF12_%s_1</name>
                    <description>RX Message Buffer Data Field 12 Register %s Channel 1</description>
                    <addressOffset>0x283C</addressOffset>
                    <size>32</size>
                    <access>read-only</access>
                    <resetValue>0x00000000</resetValue>
                    <resetMask>0xffffffff</resetMask>
                    <fields>
                        <field>
                            <name>RMDB_LL</name>
                            <description>RX Message Buffer Data Byte 48</description>
                            <lsb>0</lsb>
                            <msb>7</msb>
                            <access>read-only</access>
                        </field>
                        <field>
                            <name>RMDB_LH</name>
                            <description>RX Message Buffer Data Byte 49</description>
                            <lsb>8</lsb>
                            <msb>15</msb>
                            <access>read-only</access>
                        </field>
                        <field>
                            <name>RMDB_HL</name>
                            <description>RX Message Buffer Data Byte 50</description>
                            <lsb>16</lsb>
                            <msb>23</msb>
                            <access>read-only</access>
                        </field>
                        <field>
                            <name>RMDB_HH</name>
                            <description>RX Message Buffer Data Byte 51</description>
                            <lsb>24</lsb>
                            <msb>31</msb>
                            <access>read-only</access>
                        </field>
                    </fields>
                </register>
                <register>
                    <dim>16</dim>
                    <dimIncrement>0x080</dimIncrement>
                    <dimIndex>0-15</dimIndex>
                    <name>CFDRMDF13_%s_1</name>
                    <description>RX Message Buffer Data Field 13 Register %s Channel 1</description>
                    <addressOffset>0x2840</addressOffset>
                    <size>32</size>
                    <access>read-only</access>
                    <resetValue>0x00000000</resetValue>
                    <resetMask>0xffffffff</resetMask>
                    <fields>
                        <field>
                            <name>RMDB_LL</name>
                            <description>RX Message Buffer Data Byte 52</description>
                            <lsb>0</lsb>
                            <msb>7</msb>
                            <access>read-only</access>
                        </field>
                        <field>
                            <name>RMDB_LH</name>
                            <description>RX Message Buffer Data Byte 53</description>
                            <lsb>8</lsb>
                            <msb>15</msb>
                            <access>read-only</access>
                        </field>
                        <field>
                            <name>RMDB_HL</name>
                            <description>RX Message Buffer Data Byte 54</description>
                            <lsb>16</lsb>
                            <msb>23</msb>
                            <access>read-only</access>
                        </field>
                        <field>
                            <name>RMDB_HH</name>
                            <description>RX Message Buffer Data Byte 55</description>
                            <lsb>24</lsb>
                            <msb>31</msb>
                            <access>read-only</access>
                        </field>
                    </fields>
                </register>
                <register>
                    <dim>16</dim>
                    <dimIncrement>0x080</dimIncrement>
                    <dimIndex>0-15</dimIndex>
                    <name>CFDRMDF14_%s_1</name>
                    <description>RX Message Buffer Data Field 14 Register %s Channel 1</description>
                    <addressOffset>0x2844</addressOffset>
                    <size>32</size>
                    <access>read-only</access>
                    <resetValue>0x00000000</resetValue>
                    <resetMask>0xffffffff</resetMask>
                    <fields>
                        <field>
                            <name>RMDB_LL</name>
                            <description>RX Message Buffer Data Byte 56</description>
                            <lsb>0</lsb>
                            <msb>7</msb>
                            <access>read-only</access>
                        </field>
                        <field>
                            <name>RMDB_LH</name>
                            <description>RX Message Buffer Data Byte 57</description>
                            <lsb>8</lsb>
                            <msb>15</msb>
                            <access>read-only</access>
                        </field>
                        <field>
                            <name>RMDB_HL</name>
                            <description>RX Message Buffer Data Byte 58</description>
                            <lsb>16</lsb>
                            <msb>23</msb>
                            <access>read-only</access>
                        </field>
                        <field>
                            <name>RMDB_HH</name>
                            <description>RX Message Buffer Data Byte 59</description>
                            <lsb>24</lsb>
                            <msb>31</msb>
                            <access>read-only</access>
                        </field>
                    </fields>
                </register>
                <register>
                    <dim>16</dim>
                    <dimIncrement>0x080</dimIncrement>
                    <dimIndex>0-15</dimIndex>
                    <name>CFDRMDF15_%s_1</name>
                    <description>RX Message Buffer Data Field 15 Register %s Channel 1</description>
                    <addressOffset>0x2848</addressOffset>
                    <size>32</size>
                    <access>read-only</access>
                    <resetValue>0x00000000</resetValue>
                    <resetMask>0xffffffff</resetMask>
                    <fields>
                        <field>
                            <name>RMDB_LL</name>
                            <description>RX Message Buffer Data Byte 60</description>
                            <lsb>0</lsb>
                            <msb>7</msb>
                            <access>read-only</access>
                        </field>
                        <field>
                            <name>RMDB_LH</name>
                            <description>RX Message Buffer Data Byte 61</description>
                            <lsb>8</lsb>
                            <msb>15</msb>
                            <access>read-only</access>
                        </field>
                        <field>
                            <name>RMDB_HL</name>
                            <description>RX Message Buffer Data Byte 62</description>
                            <lsb>16</lsb>
                            <msb>23</msb>
                            <access>read-only</access>
                        </field>
                        <field>
                            <name>RMDB_HH</name>
                            <description>RX Message Buffer Data Byte 63</description>
                            <lsb>24</lsb>
                            <msb>31</msb>
                            <access>read-only</access>
                        </field>
                    </fields>
                </register>
                <register>
                    <dim>8</dim>
                    <dimIncrement>0x080</dimIncrement>
                    <dimIndex>0-7</dimIndex>
                    <name>CFDRFID%s</name>
                    <description>RX FIFO Access ID Register %s</description>
                    <addressOffset>0x6000</addressOffset>
                    <size>32</size>
                    <access>read-only</access>
                    <resetValue>0x00000000</resetValue>
                    <resetMask>0xffffffff</resetMask>
                    <fields>
                        <field>
                            <name>RFID</name>
                            <description>RX FIFO Buffer ID Field</description>
                            <lsb>0</lsb>
                            <msb>28</msb>
                            <access>read-only</access>
                        </field>
                        <field>
                            <name>RFRTR</name>
                            <description>RX FIFO Buffer RTR bit</description>
                            <lsb>30</lsb>
                            <msb>30</msb>
                            <access>read-only</access>
                            <enumeratedValues>
                                </enumeratedValues>
                        </field>
                        <field>
                            <name>RFIDE</name>
                            <description>RX FIFO Buffer IDE bit</description>
                            <lsb>31</lsb>
                            <msb>31</msb>
                            <access>read-only</access>
                            <enumeratedValues>
                                </enumeratedValues>
                        </field>
                    </fields>
                </register>
                <register>
                    <dim>8</dim>
                    <dimIncrement>0x080</dimIncrement>
                    <dimIndex>0-7</dimIndex>
                    <name>CFDRFPTR%s</name>
                    <description>RX FIFO Access Pointer Register %s</description>
                    <addressOffset>0x6004</addressOffset>
                    <size>32</size>
                    <access>read-only</access>
                    <resetValue>0x00000000</resetValue>
                    <resetMask>0xffffffff</resetMask>
                    <fields>
                        <field>
                            <name>RFTS</name>
                            <description>RX FIFO Timestamp Value</description>
                            <lsb>0</lsb>
                            <msb>15</msb>
                            <access>read-only</access>
                        </field>
                        <field>
                            <name>RFDLC</name>
                            <description>RX FIFO Buffer DLC Field</description>
                            <lsb>28</lsb>
                            <msb>31</msb>
                            <access>read-only</access>
                        </field>
                    </fields>
                </register>
                <register>
                    <dim>8</dim>
                    <dimIncrement>0x080</dimIncrement>
                    <dimIndex>0-7</dimIndex>
                    <name>CFDRFFDSTS%s</name>
                    <description>RX FIFO Access CAN,FD Status Register %s</description>
                    <addressOffset>0x6008</addressOffset>
                    <size>32</size>
                    <access>read-only</access>
                    <resetValue>0x00000000</resetValue>
                    <resetMask>0xffffffff</resetMask>
                    <fields>
                        <field>
                            <name>RFESI</name>
                            <description>Error State Indicator bit</description>
                            <lsb>0</lsb>
                            <msb>0</msb>
                            <access>read-only</access>
                            <enumeratedValues>
                                </enumeratedValues>
                        </field>
                        <field>
                            <name>RFBRS</name>
                            <description>Bit Rate Switch bit</description>
                            <lsb>1</lsb>
                            <msb>1</msb>
                            <access>read-only</access>
                            <enumeratedValues>
                                </enumeratedValues>
                        </field>
                        <field>
                            <name>RFFDF</name>
                            <description>CAN FD Format bit</description>
                            <lsb>2</lsb>
                            <msb>2</msb>
                            <access>read-only</access>
                            <enumeratedValues>
                                </enumeratedValues>
                        </field>
                        <field>
                            <name>RFIFL</name>
                            <description>RX FIFO Buffer Information Label Field</description>
                            <lsb>8</lsb>
                            <msb>9</msb>
                            <access>read-only</access>
                        </field>
                        <field>
                            <name>CFDRFPTR</name>
                            <description>RX FIFO Buffer Pointer Field</description>
                            <lsb>16</lsb>
                            <msb>31</msb>
                            <access>read-only</access>
                        </field>
                    </fields>
                </register>
                <register>
                    <dim>8</dim>
                    <dimIncrement>0x080</dimIncrement>
                    <dimIndex>0-7</dimIndex>
                    <name>CFDRFDF0%s</name>
                    <description>RX FIFO Access Data Field 0 Register %s</description>
                    <addressOffset>0x600C</addressOffset>
                    <size>32</size>
                    <access>read-only</access>
                    <resetValue>0x00000000</resetValue>
                    <resetMask>0xffffffff</resetMask>
                    <fields>
                        <field>
                            <name>RFDB_LL</name>
                            <description>RX FIFO Buffer Data Byte 0</description>
                            <lsb>0</lsb>
                            <msb>7</msb>
                            <access>read-only</access>
                        </field>
                        <field>
                            <name>RFDB_LH</name>
                            <description>RX FIFO Buffer Data Byte 1</description>
                            <lsb>8</lsb>
                            <msb>15</msb>
                            <access>read-only</access>
                        </field>
                        <field>
                            <name>RFDB_HL</name>
                            <description>RX FIFO Buffer Data Byte 2</description>
                            <lsb>16</lsb>
                            <msb>23</msb>
                            <access>read-only</access>
                        </field>
                        <field>
                            <name>RFDB_HH</name>
                            <description>RX FIFO Buffer Data Byte 3</description>
                            <lsb>24</lsb>
                            <msb>31</msb>
                            <access>read-only</access>
                        </field>
                    </fields>
                </register>
                <register>
                    <dim>8</dim>
                    <dimIncrement>0x080</dimIncrement>
                    <dimIndex>0-7</dimIndex>
                    <name>CFDRFDF1%s</name>
                    <description>RX FIFO Access Data Field 1 Register %s</description>
                    <addressOffset>0x6010</addressOffset>
                    <size>32</size>
                    <access>read-only</access>
                    <resetValue>0x00000000</resetValue>
                    <resetMask>0xffffffff</resetMask>
                    <fields>
                        <field>
                            <name>RFDB_LL</name>
                            <description>RX FIFO Buffer Data Byte 4</description>
                            <lsb>0</lsb>
                            <msb>7</msb>
                            <access>read-only</access>
                        </field>
                        <field>
                            <name>RFDB_LH</name>
                            <description>RX FIFO Buffer Data Byte 5</description>
                            <lsb>8</lsb>
                            <msb>15</msb>
                            <access>read-only</access>
                        </field>
                        <field>
                            <name>RFDB_HL</name>
                            <description>RX FIFO Buffer Data Byte 6</description>
                            <lsb>16</lsb>
                            <msb>23</msb>
                            <access>read-only</access>
                        </field>
                        <field>
                            <name>RFDB_HH</name>
                            <description>RX FIFO Buffer Data Byte 7</description>
                            <lsb>24</lsb>
                            <msb>31</msb>
                            <access>read-only</access>
                        </field>
                    </fields>
                </register>
                <register>
                    <dim>8</dim>
                    <dimIncrement>0x080</dimIncrement>
                    <dimIndex>0-7</dimIndex>
                    <name>CFDRFDF2%s</name>
                    <description>RX FIFO Access Data Field 2 Register %s</description>
                    <addressOffset>0x6014</addressOffset>
                    <size>32</size>
                    <access>read-only</access>
                    <resetValue>0x00000000</resetValue>
                    <resetMask>0xffffffff</resetMask>
                    <fields>
                        <field>
                            <name>RFDB_LL</name>
                            <description>RX FIFO Buffer Data Byte 8</description>
                            <lsb>0</lsb>
                            <msb>7</msb>
                            <access>read-only</access>
                        </field>
                        <field>
                            <name>RFDB_LH</name>
                            <description>RX FIFO Buffer Data Byte 9</description>
                            <lsb>8</lsb>
                            <msb>15</msb>
                            <access>read-only</access>
                        </field>
                        <field>
                            <name>RFDB_HL</name>
                            <description>RX FIFO Buffer Data Byte 10</description>
                            <lsb>16</lsb>
                            <msb>23</msb>
                            <access>read-only</access>
                        </field>
                        <field>
                            <name>RFDB_HH</name>
                            <description>RX FIFO Buffer Data Byte 11</description>
                            <lsb>24</lsb>
                            <msb>31</msb>
                            <access>read-only</access>
                        </field>
                    </fields>
                </register>
                <register>
                    <dim>8</dim>
                    <dimIncrement>0x080</dimIncrement>
                    <dimIndex>0-7</dimIndex>
                    <name>CFDRFDF3%s</name>
                    <description>RX FIFO Access Data Field 3 Register %s</description>
                    <addressOffset>0x6018</addressOffset>
                    <size>32</size>
                    <access>read-only</access>
                    <resetValue>0x00000000</resetValue>
                    <resetMask>0xffffffff</resetMask>
                    <fields>
                        <field>
                            <name>RFDB_LL</name>
                            <description>RX FIFO Buffer Data Byte 12</description>
                            <lsb>0</lsb>
                            <msb>7</msb>
                            <access>read-only</access>
                        </field>
                        <field>
                            <name>RFDB_LH</name>
                            <description>RX FIFO Buffer Data Byte 13</description>
                            <lsb>8</lsb>
                            <msb>15</msb>
                            <access>read-only</access>
                        </field>
                        <field>
                            <name>RFDB_HL</name>
                            <description>RX FIFO Buffer Data Byte 14</description>
                            <lsb>16</lsb>
                            <msb>23</msb>
                            <access>read-only</access>
                        </field>
                        <field>
                            <name>RFDB_HH</name>
                            <description>RX FIFO Buffer Data Byte 15</description>
                            <lsb>24</lsb>
                            <msb>31</msb>
                            <access>read-only</access>
                        </field>
                    </fields>
                </register>
                <register>
                    <dim>8</dim>
                    <dimIncrement>0x080</dimIncrement>
                    <dimIndex>0-7</dimIndex>
                    <name>CFDRFDF4%s</name>
                    <description>RX FIFO Access Data Field 4 Register %s</description>
                    <addressOffset>0x601C</addressOffset>
                    <size>32</size>
                    <access>read-only</access>
                    <resetValue>0x00000000</resetValue>
                    <resetMask>0xffffffff</resetMask>
                    <fields>
                        <field>
                            <name>RFDB_LL</name>
                            <description>RX FIFO Buffer Data Byte 16</description>
                            <lsb>0</lsb>
                            <msb>7</msb>
                            <access>read-only</access>
                        </field>
                        <field>
                            <name>RFDB_LH</name>
                            <description>RX FIFO Buffer Data Byte 17</description>
                            <lsb>8</lsb>
                            <msb>15</msb>
                            <access>read-only</access>
                        </field>
                        <field>
                            <name>RFDB_HL</name>
                            <description>RX FIFO Buffer Data Byte 18</description>
                            <lsb>16</lsb>
                            <msb>23</msb>
                            <access>read-only</access>
                        </field>
                        <field>
                            <name>RFDB_HH</name>
                            <description>RX FIFO Buffer Data Byte 19</description>
                            <lsb>24</lsb>
                            <msb>31</msb>
                            <access>read-only</access>
                        </field>
                    </fields>
                </register>
                <register>
                    <dim>8</dim>
                    <dimIncrement>0x080</dimIncrement>
                    <dimIndex>0-7</dimIndex>
                    <name>CFDRFDF5%s</name>
                    <description>RX FIFO Access Data Field 5 Register %s</description>
                    <addressOffset>0x6020</addressOffset>
                    <size>32</size>
                    <access>read-only</access>
                    <resetValue>0x00000000</resetValue>
                    <resetMask>0xffffffff</resetMask>
                    <fields>
                        <field>
                            <name>RFDB_LL</name>
                            <description>RX FIFO Buffer Data Byte 20</description>
                            <lsb>0</lsb>
                            <msb>7</msb>
                            <access>read-only</access>
                        </field>
                        <field>
                            <name>RFDB_LH</name>
                            <description>RX FIFO Buffer Data Byte 21</description>
                            <lsb>8</lsb>
                            <msb>15</msb>
                            <access>read-only</access>
                        </field>
                        <field>
                            <name>RFDB_HL</name>
                            <description>RX FIFO Buffer Data Byte 22</description>
                            <lsb>16</lsb>
                            <msb>23</msb>
                            <access>read-only</access>
                        </field>
                        <field>
                            <name>RFDB_HH</name>
                            <description>RX FIFO Buffer Data Byte 23</description>
                            <lsb>24</lsb>
                            <msb>31</msb>
                            <access>read-only</access>
                        </field>
                    </fields>
                </register>
                <register>
                    <dim>8</dim>
                    <dimIncrement>0x080</dimIncrement>
                    <dimIndex>0-7</dimIndex>
                    <name>CFDRFDF6%s</name>
                    <description>RX FIFO Access Data Field 6 Register %s</description>
                    <addressOffset>0x6024</addressOffset>
                    <size>32</size>
                    <access>read-only</access>
                    <resetValue>0x00000000</resetValue>
                    <resetMask>0xffffffff</resetMask>
                    <fields>
                        <field>
                            <name>RFDB_LL</name>
                            <description>RX FIFO Buffer Data Byte 24</description>
                            <lsb>0</lsb>
                            <msb>7</msb>
                            <access>read-only</access>
                        </field>
                        <field>
                            <name>RFDB_LH</name>
                            <description>RX FIFO Buffer Data Byte 25</description>
                            <lsb>8</lsb>
                            <msb>15</msb>
                            <access>read-only</access>
                        </field>
                        <field>
                            <name>RFDB_HL</name>
                            <description>RX FIFO Buffer Data Byte 26</description>
                            <lsb>16</lsb>
                            <msb>23</msb>
                            <access>read-only</access>
                        </field>
                        <field>
                            <name>RFDB_HH</name>
                            <description>RX FIFO Buffer Data Byte 27</description>
                            <lsb>24</lsb>
                            <msb>31</msb>
                            <access>read-only</access>
                        </field>
                    </fields>
                </register>
                <register>
                    <dim>8</dim>
                    <dimIncrement>0x080</dimIncrement>
                    <dimIndex>0-7</dimIndex>
                    <name>CFDRFDF7%s</name>
                    <description>RX FIFO Access Data Field 7 Register %s</description>
                    <addressOffset>0x6028</addressOffset>
                    <size>32</size>
                    <access>read-only</access>
                    <resetValue>0x00000000</resetValue>
                    <resetMask>0xffffffff</resetMask>
                    <fields>
                        <field>
                            <name>RFDB_LL</name>
                            <description>RX FIFO Buffer Data Byte 28</description>
                            <lsb>0</lsb>
                            <msb>7</msb>
                            <access>read-only</access>
                        </field>
                        <field>
                            <name>RFDB_LH</name>
                            <description>RX FIFO Buffer Data Byte 29</description>
                            <lsb>8</lsb>
                            <msb>15</msb>
                            <access>read-only</access>
                        </field>
                        <field>
                            <name>RFDB_HL</name>
                            <description>RX FIFO Buffer Data Byte 30</description>
                            <lsb>16</lsb>
                            <msb>23</msb>
                            <access>read-only</access>
                        </field>
                        <field>
                            <name>RFDB_HH</name>
                            <description>RX FIFO Buffer Data Byte 31</description>
                            <lsb>24</lsb>
                            <msb>31</msb>
                            <access>read-only</access>
                        </field>
                    </fields>
                </register>
                <register>
                    <dim>8</dim>
                    <dimIncrement>0x080</dimIncrement>
                    <dimIndex>0-7</dimIndex>
                    <name>CFDRFDF8%s</name>
                    <description>RX FIFO Access Data Field 8 Register %s</description>
                    <addressOffset>0x602C</addressOffset>
                    <size>32</size>
                    <access>read-only</access>
                    <resetValue>0x00000000</resetValue>
                    <resetMask>0xffffffff</resetMask>
                    <fields>
                        <field>
                            <name>RFDB_LL</name>
                            <description>RX FIFO Buffer Data Byte 32</description>
                            <lsb>0</lsb>
                            <msb>7</msb>
                            <access>read-only</access>
                        </field>
                        <field>
                            <name>RFDB_LH</name>
                            <description>RX FIFO Buffer Data Byte 33</description>
                            <lsb>8</lsb>
                            <msb>15</msb>
                            <access>read-only</access>
                        </field>
                        <field>
                            <name>RFDB_HL</name>
                            <description>RX FIFO Buffer Data Byte 34</description>
                            <lsb>16</lsb>
                            <msb>23</msb>
                            <access>read-only</access>
                        </field>
                        <field>
                            <name>RFDB_HH</name>
                            <description>RX FIFO Buffer Data Byte 35</description>
                            <lsb>24</lsb>
                            <msb>31</msb>
                            <access>read-only</access>
                        </field>
                    </fields>
                </register>
                <register>
                    <dim>8</dim>
                    <dimIncrement>0x080</dimIncrement>
                    <dimIndex>0-7</dimIndex>
                    <name>CFDRFDF9%s</name>
                    <description>RX FIFO Access Data Field 9 Register %s</description>
                    <addressOffset>0x6030</addressOffset>
                    <size>32</size>
                    <access>read-only</access>
                    <resetValue>0x00000000</resetValue>
                    <resetMask>0xffffffff</resetMask>
                    <fields>
                        <field>
                            <name>RFDB_LL</name>
                            <description>RX FIFO Buffer Data Byte 36</description>
                            <lsb>0</lsb>
                            <msb>7</msb>
                            <access>read-only</access>
                        </field>
                        <field>
                            <name>RFDB_LH</name>
                            <description>RX FIFO Buffer Data Byte 37</description>
                            <lsb>8</lsb>
                            <msb>15</msb>
                            <access>read-only</access>
                        </field>
                        <field>
                            <name>RFDB_HL</name>
                            <description>RX FIFO Buffer Data Byte 38</description>
                            <lsb>16</lsb>
                            <msb>23</msb>
                            <access>read-only</access>
                        </field>
                        <field>
                            <name>RFDB_HH</name>
                            <description>RX FIFO Buffer Data Byte 39</description>
                            <lsb>24</lsb>
                            <msb>31</msb>
                            <access>read-only</access>
                        </field>
                    </fields>
                </register>
                <register>
                    <dim>8</dim>
                    <dimIncrement>0x080</dimIncrement>
                    <dimIndex>0-7</dimIndex>
                    <name>CFDRFDF10%s</name>
                    <description>RX FIFO Access Data Field 10 Register %s</description>
                    <addressOffset>0x6034</addressOffset>
                    <size>32</size>
                    <access>read-only</access>
                    <resetValue>0x00000000</resetValue>
                    <resetMask>0xffffffff</resetMask>
                    <fields>
                        <field>
                            <name>RFDB_LL</name>
                            <description>RX FIFO Buffer Data Byte 40</description>
                            <lsb>0</lsb>
                            <msb>7</msb>
                            <access>read-only</access>
                        </field>
                        <field>
                            <name>RFDB_LH</name>
                            <description>RX FIFO Buffer Data Byte 41</description>
                            <lsb>8</lsb>
                            <msb>15</msb>
                            <access>read-only</access>
                        </field>
                        <field>
                            <name>RFDB_HL</name>
                            <description>RX FIFO Buffer Data Byte 42</description>
                            <lsb>16</lsb>
                            <msb>23</msb>
                            <access>read-only</access>
                        </field>
                        <field>
                            <name>RFDB_HH</name>
                            <description>RX FIFO Buffer Data Byte 43</description>
                            <lsb>24</lsb>
                            <msb>31</msb>
                            <access>read-only</access>
                        </field>
                    </fields>
                </register>
                <register>
                    <dim>8</dim>
                    <dimIncrement>0x080</dimIncrement>
                    <dimIndex>0-7</dimIndex>
                    <name>CFDRFDF11%s</name>
                    <description>RX FIFO Access Data Field 11 Register %s</description>
                    <addressOffset>0x6038</addressOffset>
                    <size>32</size>
                    <access>read-only</access>
                    <resetValue>0x00000000</resetValue>
                    <resetMask>0xffffffff</resetMask>
                    <fields>
                        <field>
                            <name>RFDB_LL</name>
                            <description>RX FIFO Buffer Data Byte 44</description>
                            <lsb>0</lsb>
                            <msb>7</msb>
                            <access>read-only</access>
                        </field>
                        <field>
                            <name>RFDB_LH</name>
                            <description>RX FIFO Buffer Data Byte 45</description>
                            <lsb>8</lsb>
                            <msb>15</msb>
                            <access>read-only</access>
                        </field>
                        <field>
                            <name>RFDB_HL</name>
                            <description>RX FIFO Buffer Data Byte 46</description>
                            <lsb>16</lsb>
                            <msb>23</msb>
                            <access>read-only</access>
                        </field>
                        <field>
                            <name>RFDB_HH</name>
                            <description>RX FIFO Buffer Data Byte 47</description>
                            <lsb>24</lsb>
                            <msb>31</msb>
                            <access>read-only</access>
                        </field>
                    </fields>
                </register>
                <register>
                    <dim>8</dim>
                    <dimIncrement>0x080</dimIncrement>
                    <dimIndex>0-7</dimIndex>
                    <name>CFDRFDF12%s</name>
                    <description>RX FIFO Access Data Field 12 Register %s</description>
                    <addressOffset>0x603C</addressOffset>
                    <size>32</size>
                    <access>read-only</access>
                    <resetValue>0x00000000</resetValue>
                    <resetMask>0xffffffff</resetMask>
                    <fields>
                        <field>
                            <name>RFDB_LL</name>
                            <description>RX FIFO Buffer Data Byte 48</description>
                            <lsb>0</lsb>
                            <msb>7</msb>
                            <access>read-only</access>
                        </field>
                        <field>
                            <name>RFDB_LH</name>
                            <description>RX FIFO Buffer Data Byte 49</description>
                            <lsb>8</lsb>
                            <msb>15</msb>
                            <access>read-only</access>
                        </field>
                        <field>
                            <name>RFDB_HL</name>
                            <description>RX FIFO Buffer Data Byte 50</description>
                            <lsb>16</lsb>
                            <msb>23</msb>
                            <access>read-only</access>
                        </field>
                        <field>
                            <name>RFDB_HH</name>
                            <description>RX FIFO Buffer Data Byte 51</description>
                            <lsb>24</lsb>
                            <msb>31</msb>
                            <access>read-only</access>
                        </field>
                    </fields>
                </register>
                <register>
                    <dim>8</dim>
                    <dimIncrement>0x080</dimIncrement>
                    <dimIndex>0-7</dimIndex>
                    <name>CFDRFDF13%s</name>
                    <description>RX FIFO Access Data Field 13 Register %s</description>
                    <addressOffset>0x6040</addressOffset>
                    <size>32</size>
                    <access>read-only</access>
                    <resetValue>0x00000000</resetValue>
                    <resetMask>0xffffffff</resetMask>
                    <fields>
                        <field>
                            <name>RFDB_LL</name>
                            <description>RX FIFO Buffer Data Byte 52</description>
                            <lsb>0</lsb>
                            <msb>7</msb>
                            <access>read-only</access>
                        </field>
                        <field>
                            <name>RFDB_LH</name>
                            <description>RX FIFO Buffer Data Byte 53</description>
                            <lsb>8</lsb>
                            <msb>15</msb>
                            <access>read-only</access>
                        </field>
                        <field>
                            <name>RFDB_HL</name>
                            <description>RX FIFO Buffer Data Byte 54</description>
                            <lsb>16</lsb>
                            <msb>23</msb>
                            <access>read-only</access>
                        </field>
                        <field>
                            <name>RFDB_HH</name>
                            <description>RX FIFO Buffer Data Byte 55</description>
                            <lsb>24</lsb>
                            <msb>31</msb>
                            <access>read-only</access>
                        </field>
                    </fields>
                </register>
                <register>
                    <dim>8</dim>
                    <dimIncrement>0x080</dimIncrement>
                    <dimIndex>0-7</dimIndex>
                    <name>CFDRFDF14%s</name>
                    <description>RX FIFO Access Data Field 14 Register %s</description>
                    <addressOffset>0x6044</addressOffset>
                    <size>32</size>
                    <access>read-only</access>
                    <resetValue>0x00000000</resetValue>
                    <resetMask>0xffffffff</resetMask>
                    <fields>
                        <field>
                            <name>RFDB_LL</name>
                            <description>RX FIFO Buffer Data Byte 56</description>
                            <lsb>0</lsb>
                            <msb>7</msb>
                            <access>read-only</access>
                        </field>
                        <field>
                            <name>RFDB_LH</name>
                            <description>RX FIFO Buffer Data Byte 57</description>
                            <lsb>8</lsb>
                            <msb>15</msb>
                            <access>read-only</access>
                        </field>
                        <field>
                            <name>RFDB_HL</name>
                            <description>RX FIFO Buffer Data Byte 58</description>
                            <lsb>16</lsb>
                            <msb>23</msb>
                            <access>read-only</access>
                        </field>
                        <field>
                            <name>RFDB_HH</name>
                            <description>RX FIFO Buffer Data Byte 59</description>
                            <lsb>24</lsb>
                            <msb>31</msb>
                            <access>read-only</access>
                        </field>
                    </fields>
                </register>
                <register>
                    <dim>8</dim>
                    <dimIncrement>0x080</dimIncrement>
                    <dimIndex>0-7</dimIndex>
                    <name>CFDRFDF15%s</name>
                    <description>RX FIFO Access Data Field 15 Register %s</description>
                    <addressOffset>0x6048</addressOffset>
                    <size>32</size>
                    <access>read-only</access>
                    <resetValue>0x00000000</resetValue>
                    <resetMask>0xffffffff</resetMask>
                    <fields>
                        <field>
                            <name>RFDB_LL</name>
                            <description>RX FIFO Buffer Data Byte 60</description>
                            <lsb>0</lsb>
                            <msb>7</msb>
                            <access>read-only</access>
                        </field>
                        <field>
                            <name>RFDB_LH</name>
                            <description>RX FIFO Buffer Data Byte 61</description>
                            <lsb>8</lsb>
                            <msb>15</msb>
                            <access>read-only</access>
                        </field>
                        <field>
                            <name>RFDB_HL</name>
                            <description>RX FIFO Buffer Data Byte 62</description>
                            <lsb>16</lsb>
                            <msb>23</msb>
                            <access>read-only</access>
                        </field>
                        <field>
                            <name>RFDB_HH</name>
                            <description>RX FIFO Buffer Data Byte 63</description>
                            <lsb>24</lsb>
                            <msb>31</msb>
                            <access>read-only</access>
                        </field>
                    </fields>
                </register>
                <register>
                    <dim>3</dim>
                    <dimIncrement>0x080</dimIncrement>
                    <dimIndex>0-2</dimIndex>
                    <name>CFDCFID%s_0</name>
                    <description>Common FIFO Access ID Register %s Channel 0</description>
                    <addressOffset>0x6400</addressOffset>
                    <size>32</size>
                    <access>read-write</access>
                    <resetValue>0x00000000</resetValue>
                    <resetMask>0xffffffff</resetMask>
                    <fields>
                        <field>
                            <name>CFID</name>
                            <description>Common FIFO Buffer ID Field</description>
                            <lsb>0</lsb>
                            <msb>28</msb>
                            <access>read-write</access>
                        </field>
                        <field>
                            <name>THLEN</name>
                            <description>THL Entry Enable</description>
                            <lsb>29</lsb>
                            <msb>29</msb>
                            <access>read-write</access>
                            <enumeratedValues>
                                </enumeratedValues>
                        </field>
                        <field>
                            <name>CFRTR</name>
                            <description>Common FIFO Buffer RTR bit</description>
                            <lsb>30</lsb>
                            <msb>30</msb>
                            <access>read-write</access>
                            <enumeratedValues>
                                </enumeratedValues>
                        </field>
                        <field>
                            <name>CFIDE</name>
                            <description>Common FIFO Buffer IDE bit</description>
                            <lsb>31</lsb>
                            <msb>31</msb>
                            <access>read-write</access>
                            <enumeratedValues>
                                </enumeratedValues>
                        </field>
                    </fields>
                </register>
                <register>
                    <dim>3</dim>
                    <dimIncrement>0x080</dimIncrement>
                    <dimIndex>0-2</dimIndex>
                    <name>CFDCFPTR%s_0</name>
                    <description>Common FIFO Access Pointer Register %s Channel 0</description>
                    <addressOffset>0x6404</addressOffset>
                    <size>32</size>
                    <access>read-write</access>
                    <resetValue>0x00000000</resetValue>
                    <resetMask>0xffffffff</resetMask>
                    <fields>
                        <field>
                            <name>CFTS</name>
                            <description>Common FIFO Timestamp Value</description>
                            <lsb>0</lsb>
                            <msb>15</msb>
                            <access>read-write</access>
                        </field>
                        <field>
                            <name>CFDLC</name>
                            <description>Common FIFO Buffer DLC Field</description>
                            <lsb>28</lsb>
                            <msb>31</msb>
                            <access>read-write</access>
                        </field>
                    </fields>
                </register>
                <register>
                    <dim>3</dim>
                    <dimIncrement>0x080</dimIncrement>
                    <dimIndex>0-2</dimIndex>
                    <name>CFDCFFDCSTS%s_0</name>
                    <description>Common FIFO Access CAN,FD Control/Status Register %s Channel 0</description>
                    <addressOffset>0x6408</addressOffset>
                    <size>32</size>
                    <access>read-write</access>
                    <resetValue>0x00000000</resetValue>
                    <resetMask>0xffffffff</resetMask>
                    <fields>
                        <field>
                            <name>CFESI</name>
                            <description>Error State Indicator bit</description>
                            <lsb>0</lsb>
                            <msb>0</msb>
                            <access>read-write</access>
                            <enumeratedValues>
                                </enumeratedValues>
                        </field>
                        <field>
                            <name>CFBRS</name>
                            <description>Bit Rate Switch bit</description>
                            <lsb>1</lsb>
                            <msb>1</msb>
                            <access>read-write</access>
                            <enumeratedValues>
                                </enumeratedValues>
                        </field>
                        <field>
                            <name>CFFDF</name>
                            <description>CAN FD Format bit</description>
                            <lsb>2</lsb>
                            <msb>2</msb>
                            <access>read-write</access>
                            <enumeratedValues>
                                </enumeratedValues>
                        </field>
                        <field>
                            <name>CFIFL</name>
                            <description>COMMON FIFO Buffer Information Label Field</description>
                            <lsb>8</lsb>
                            <msb>9</msb>
                            <access>read-write</access>
                        </field>
                        <field>
                            <name>CFPTR</name>
                            <description>Common FIFO Buffer Pointer Field</description>
                            <lsb>16</lsb>
                            <msb>31</msb>
                            <access>read-write</access>
                        </field>
                    </fields>
                </register>
                <register>
                    <dim>3</dim>
                    <dimIncrement>0x080</dimIncrement>
                    <dimIndex>0-2</dimIndex>
                    <name>CFDCFDF0%s_0</name>
                    <description>Common FIFO Access Data Field 0 Register %s Channel 0</description>
                    <addressOffset>0x640C</addressOffset>
                    <size>32</size>
                    <access>read-write</access>
                    <resetValue>0x00000000</resetValue>
                    <resetMask>0xffffffff</resetMask>
                    <fields>
                        <field>
                            <name>CFDB_LL</name>
                            <description>Common FIFO Buffer Data Bytes 0</description>
                            <lsb>0</lsb>
                            <msb>7</msb>
                            <access>read-write</access>
                        </field>
                        <field>
                            <name>CFDB_LH</name>
                            <description>Common FIFO Buffer Data Bytes 1</description>
                            <lsb>8</lsb>
                            <msb>15</msb>
                            <access>read-write</access>
                        </field>
                        <field>
                            <name>CFDB_HL</name>
                            <description>Common FIFO Buffer Data Bytes 2</description>
                            <lsb>16</lsb>
                            <msb>23</msb>
                            <access>read-write</access>
                        </field>
                        <field>
                            <name>CFDB_HH</name>
                            <description>Common FIFO Buffer Data Bytes 3</description>
                            <lsb>24</lsb>
                            <msb>31</msb>
                            <access>read-write</access>
                        </field>
                    </fields>
                </register>
                <register>
                    <dim>3</dim>
                    <dimIncrement>0x080</dimIncrement>
                    <dimIndex>0-2</dimIndex>
                    <name>CFDCFDF1%s_0</name>
                    <description>Common FIFO Access Data Field 1 Register %s Channel 0</description>
                    <addressOffset>0x6410</addressOffset>
                    <size>32</size>
                    <access>read-write</access>
                    <resetValue>0x00000000</resetValue>
                    <resetMask>0xffffffff</resetMask>
                    <fields>
                        <field>
                            <name>CFDB_LL</name>
                            <description>Common FIFO Buffer Data Bytes 4</description>
                            <lsb>0</lsb>
                            <msb>7</msb>
                            <access>read-write</access>
                        </field>
                        <field>
                            <name>CFDB_LH</name>
                            <description>Common FIFO Buffer Data Bytes 5</description>
                            <lsb>8</lsb>
                            <msb>15</msb>
                            <access>read-write</access>
                        </field>
                        <field>
                            <name>CFDB_HL</name>
                            <description>Common FIFO Buffer Data Bytes 6</description>
                            <lsb>16</lsb>
                            <msb>23</msb>
                            <access>read-write</access>
                        </field>
                        <field>
                            <name>CFDB_HH</name>
                            <description>Common FIFO Buffer Data Bytes 7</description>
                            <lsb>24</lsb>
                            <msb>31</msb>
                            <access>read-write</access>
                        </field>
                    </fields>
                </register>
                <register>
                    <dim>3</dim>
                    <dimIncrement>0x080</dimIncrement>
                    <dimIndex>0-2</dimIndex>
                    <name>CFDCFDF2%s_0</name>
                    <description>Common FIFO Access Data Field 2 Register %s Channel 0</description>
                    <addressOffset>0x6414</addressOffset>
                    <size>32</size>
                    <access>read-write</access>
                    <resetValue>0x00000000</resetValue>
                    <resetMask>0xffffffff</resetMask>
                    <fields>
                        <field>
                            <name>CFDB_LL</name>
                            <description>Common FIFO Buffer Data Bytes 8</description>
                            <lsb>0</lsb>
                            <msb>7</msb>
                            <access>read-write</access>
                        </field>
                        <field>
                            <name>CFDB_LH</name>
                            <description>Common FIFO Buffer Data Bytes 9</description>
                            <lsb>8</lsb>
                            <msb>15</msb>
                            <access>read-write</access>
                        </field>
                        <field>
                            <name>CFDB_HL</name>
                            <description>Common FIFO Buffer Data Bytes 10</description>
                            <lsb>16</lsb>
                            <msb>23</msb>
                            <access>read-write</access>
                        </field>
                        <field>
                            <name>CFDB_HH</name>
                            <description>Common FIFO Buffer Data Bytes 11</description>
                            <lsb>24</lsb>
                            <msb>31</msb>
                            <access>read-write</access>
                        </field>
                    </fields>
                </register>
                <register>
                    <dim>3</dim>
                    <dimIncrement>0x080</dimIncrement>
                    <dimIndex>0-2</dimIndex>
                    <name>CFDCFDF3%s_0</name>
                    <description>Common FIFO Access Data Field 3 Register %s Channel 0</description>
                    <addressOffset>0x6418</addressOffset>
                    <size>32</size>
                    <access>read-write</access>
                    <resetValue>0x00000000</resetValue>
                    <resetMask>0xffffffff</resetMask>
                    <fields>
                        <field>
                            <name>CFDB_LL</name>
                            <description>Common FIFO Buffer Data Bytes 12</description>
                            <lsb>0</lsb>
                            <msb>7</msb>
                            <access>read-write</access>
                        </field>
                        <field>
                            <name>CFDB_LH</name>
                            <description>Common FIFO Buffer Data Bytes 13</description>
                            <lsb>8</lsb>
                            <msb>15</msb>
                            <access>read-write</access>
                        </field>
                        <field>
                            <name>CFDB_HL</name>
                            <description>Common FIFO Buffer Data Bytes 14</description>
                            <lsb>16</lsb>
                            <msb>23</msb>
                            <access>read-write</access>
                        </field>
                        <field>
                            <name>CFDB_HH</name>
                            <description>Common FIFO Buffer Data Bytes 15</description>
                            <lsb>24</lsb>
                            <msb>31</msb>
                            <access>read-write</access>
                        </field>
                    </fields>
                </register>
                <register>
                    <dim>3</dim>
                    <dimIncrement>0x080</dimIncrement>
                    <dimIndex>0-2</dimIndex>
                    <name>CFDCFDF4%s_0</name>
                    <description>Common FIFO Access Data Field 4 Register %s Channel 0</description>
                    <addressOffset>0x641C</addressOffset>
                    <size>32</size>
                    <access>read-write</access>
                    <resetValue>0x00000000</resetValue>
                    <resetMask>0xffffffff</resetMask>
                    <fields>
                        <field>
                            <name>CFDB_LL</name>
                            <description>Common FIFO Buffer Data Bytes 16</description>
                            <lsb>0</lsb>
                            <msb>7</msb>
                            <access>read-write</access>
                        </field>
                        <field>
                            <name>CFDB_LH</name>
                            <description>Common FIFO Buffer Data Bytes 17</description>
                            <lsb>8</lsb>
                            <msb>15</msb>
                            <access>read-write</access>
                        </field>
                        <field>
                            <name>CFDB_HL</name>
                            <description>Common FIFO Buffer Data Bytes 18</description>
                            <lsb>16</lsb>
                            <msb>23</msb>
                            <access>read-write</access>
                        </field>
                        <field>
                            <name>CFDB_HH</name>
                            <description>Common FIFO Buffer Data Bytes 19</description>
                            <lsb>24</lsb>
                            <msb>31</msb>
                            <access>read-write</access>
                        </field>
                    </fields>
                </register>
                <register>
                    <dim>3</dim>
                    <dimIncrement>0x080</dimIncrement>
                    <dimIndex>0-2</dimIndex>
                    <name>CFDCFDF5%s_0</name>
                    <description>Common FIFO Access Data Field 5 Register %s Channel 0</description>
                    <addressOffset>0x6420</addressOffset>
                    <size>32</size>
                    <access>read-write</access>
                    <resetValue>0x00000000</resetValue>
                    <resetMask>0xffffffff</resetMask>
                    <fields>
                        <field>
                            <name>CFDB_LL</name>
                            <description>Common FIFO Buffer Data Bytes 20</description>
                            <lsb>0</lsb>
                            <msb>7</msb>
                            <access>read-write</access>
                        </field>
                        <field>
                            <name>CFDB_LH</name>
                            <description>Common FIFO Buffer Data Bytes 21</description>
                            <lsb>8</lsb>
                            <msb>15</msb>
                            <access>read-write</access>
                        </field>
                        <field>
                            <name>CFDB_HL</name>
                            <description>Common FIFO Buffer Data Bytes 22</description>
                            <lsb>16</lsb>
                            <msb>23</msb>
                            <access>read-write</access>
                        </field>
                        <field>
                            <name>CFDB_HH</name>
                            <description>Common FIFO Buffer Data Bytes 23</description>
                            <lsb>24</lsb>
                            <msb>31</msb>
                            <access>read-write</access>
                        </field>
                    </fields>
                </register>
                <register>
                    <dim>3</dim>
                    <dimIncrement>0x080</dimIncrement>
                    <dimIndex>0-2</dimIndex>
                    <name>CFDCFDF6%s_0</name>
                    <description>Common FIFO Access Data Field 6 Register %s Channel 0</description>
                    <addressOffset>0x6424</addressOffset>
                    <size>32</size>
                    <access>read-write</access>
                    <resetValue>0x00000000</resetValue>
                    <resetMask>0xffffffff</resetMask>
                    <fields>
                        <field>
                            <name>CFDB_LL</name>
                            <description>Common FIFO Buffer Data Bytes 24</description>
                            <lsb>0</lsb>
                            <msb>7</msb>
                            <access>read-write</access>
                        </field>
                        <field>
                            <name>CFDB_LH</name>
                            <description>Common FIFO Buffer Data Bytes 25</description>
                            <lsb>8</lsb>
                            <msb>15</msb>
                            <access>read-write</access>
                        </field>
                        <field>
                            <name>CFDB_HL</name>
                            <description>Common FIFO Buffer Data Bytes 26</description>
                            <lsb>16</lsb>
                            <msb>23</msb>
                            <access>read-write</access>
                        </field>
                        <field>
                            <name>CFDB_HH</name>
                            <description>Common FIFO Buffer Data Bytes 27</description>
                            <lsb>24</lsb>
                            <msb>31</msb>
                            <access>read-write</access>
                        </field>
                    </fields>
                </register>
                <register>
                    <dim>3</dim>
                    <dimIncrement>0x080</dimIncrement>
                    <dimIndex>0-2</dimIndex>
                    <name>CFDCFDF7%s_0</name>
                    <description>Common FIFO Access Data Field 7 Register %s Channel 0</description>
                    <addressOffset>0x6428</addressOffset>
                    <size>32</size>
                    <access>read-write</access>
                    <resetValue>0x00000000</resetValue>
                    <resetMask>0xffffffff</resetMask>
                    <fields>
                        <field>
                            <name>CFDB_LL</name>
                            <description>Common FIFO Buffer Data Bytes 28</description>
                            <lsb>0</lsb>
                            <msb>7</msb>
                            <access>read-write</access>
                        </field>
                        <field>
                            <name>CFDB_LH</name>
                            <description>Common FIFO Buffer Data Bytes 29</description>
                            <lsb>8</lsb>
                            <msb>15</msb>
                            <access>read-write</access>
                        </field>
                        <field>
                            <name>CFDB_HL</name>
                            <description>Common FIFO Buffer Data Bytes 30</description>
                            <lsb>16</lsb>
                            <msb>23</msb>
                            <access>read-write</access>
                        </field>
                        <field>
                            <name>CFDB_HH</name>
                            <description>Common FIFO Buffer Data Bytes 31</description>
                            <lsb>24</lsb>
                            <msb>31</msb>
                            <access>read-write</access>
                        </field>
                    </fields>
                </register>
                <register>
                    <dim>3</dim>
                    <dimIncrement>0x080</dimIncrement>
                    <dimIndex>0-2</dimIndex>
                    <name>CFDCFDF8%s_0</name>
                    <description>Common FIFO Access Data Field 8 Register %s Channel 0</description>
                    <addressOffset>0x642C</addressOffset>
                    <size>32</size>
                    <access>read-write</access>
                    <resetValue>0x00000000</resetValue>
                    <resetMask>0xffffffff</resetMask>
                    <fields>
                        <field>
                            <name>CFDB_LL</name>
                            <description>Common FIFO Buffer Data Bytes 32</description>
                            <lsb>0</lsb>
                            <msb>7</msb>
                            <access>read-write</access>
                        </field>
                        <field>
                            <name>CFDB_LH</name>
                            <description>Common FIFO Buffer Data Bytes 33</description>
                            <lsb>8</lsb>
                            <msb>15</msb>
                            <access>read-write</access>
                        </field>
                        <field>
                            <name>CFDB_HL</name>
                            <description>Common FIFO Buffer Data Bytes 34</description>
                            <lsb>16</lsb>
                            <msb>23</msb>
                            <access>read-write</access>
                        </field>
                        <field>
                            <name>CFDB_HH</name>
                            <description>Common FIFO Buffer Data Bytes 35</description>
                            <lsb>24</lsb>
                            <msb>31</msb>
                            <access>read-write</access>
                        </field>
                    </fields>
                </register>
                <register>
                    <dim>3</dim>
                    <dimIncrement>0x080</dimIncrement>
                    <dimIndex>0-2</dimIndex>
                    <name>CFDCFDF9%s_0</name>
                    <description>Common FIFO Access Data Field 9 Register %s Channel 0</description>
                    <addressOffset>0x6430</addressOffset>
                    <size>32</size>
                    <access>read-write</access>
                    <resetValue>0x00000000</resetValue>
                    <resetMask>0xffffffff</resetMask>
                    <fields>
                        <field>
                            <name>CFDB_LL</name>
                            <description>Common FIFO Buffer Data Bytes 36</description>
                            <lsb>0</lsb>
                            <msb>7</msb>
                            <access>read-write</access>
                        </field>
                        <field>
                            <name>CFDB_LH</name>
                            <description>Common FIFO Buffer Data Bytes 37</description>
                            <lsb>8</lsb>
                            <msb>15</msb>
                            <access>read-write</access>
                        </field>
                        <field>
                            <name>CFDB_HL</name>
                            <description>Common FIFO Buffer Data Bytes 38</description>
                            <lsb>16</lsb>
                            <msb>23</msb>
                            <access>read-write</access>
                        </field>
                        <field>
                            <name>CFDB_HH</name>
                            <description>Common FIFO Buffer Data Bytes 39</description>
                            <lsb>24</lsb>
                            <msb>31</msb>
                            <access>read-write</access>
                        </field>
                    </fields>
                </register>
                <register>
                    <dim>3</dim>
                    <dimIncrement>0x080</dimIncrement>
                    <dimIndex>0-2</dimIndex>
                    <name>CFDCFDF10%s_0</name>
                    <description>Common FIFO Access Data Field 10 Register %s Channel 0</description>
                    <addressOffset>0x6434</addressOffset>
                    <size>32</size>
                    <access>read-write</access>
                    <resetValue>0x00000000</resetValue>
                    <resetMask>0xffffffff</resetMask>
                    <fields>
                        <field>
                            <name>CFDB_LL</name>
                            <description>Common FIFO Buffer Data Bytes 40</description>
                            <lsb>0</lsb>
                            <msb>7</msb>
                            <access>read-write</access>
                        </field>
                        <field>
                            <name>CFDB_LH</name>
                            <description>Common FIFO Buffer Data Bytes 41</description>
                            <lsb>8</lsb>
                            <msb>15</msb>
                            <access>read-write</access>
                        </field>
                        <field>
                            <name>CFDB_HL</name>
                            <description>Common FIFO Buffer Data Bytes 42</description>
                            <lsb>16</lsb>
                            <msb>23</msb>
                            <access>read-write</access>
                        </field>
                        <field>
                            <name>CFDB_HH</name>
                            <description>Common FIFO Buffer Data Bytes 43</description>
                            <lsb>24</lsb>
                            <msb>31</msb>
                            <access>read-write</access>
                        </field>
                    </fields>
                </register>
                <register>
                    <dim>3</dim>
                    <dimIncrement>0x080</dimIncrement>
                    <dimIndex>0-2</dimIndex>
                    <name>CFDCFDF11%s_0</name>
                    <description>Common FIFO Access Data Field 11 Register %s Channel 0</description>
                    <addressOffset>0x6438</addressOffset>
                    <size>32</size>
                    <access>read-write</access>
                    <resetValue>0x00000000</resetValue>
                    <resetMask>0xffffffff</resetMask>
                    <fields>
                        <field>
                            <name>CFDB_LL</name>
                            <description>Common FIFO Buffer Data Bytes 44</description>
                            <lsb>0</lsb>
                            <msb>7</msb>
                            <access>read-write</access>
                        </field>
                        <field>
                            <name>CFDB_LH</name>
                            <description>Common FIFO Buffer Data Bytes 45</description>
                            <lsb>8</lsb>
                            <msb>15</msb>
                            <access>read-write</access>
                        </field>
                        <field>
                            <name>CFDB_HL</name>
                            <description>Common FIFO Buffer Data Bytes 46</description>
                            <lsb>16</lsb>
                            <msb>23</msb>
                            <access>read-write</access>
                        </field>
                        <field>
                            <name>CFDB_HH</name>
                            <description>Common FIFO Buffer Data Bytes 47</description>
                            <lsb>24</lsb>
                            <msb>31</msb>
                            <access>read-write</access>
                        </field>
                    </fields>
                </register>
                <register>
                    <dim>3</dim>
                    <dimIncrement>0x080</dimIncrement>
                    <dimIndex>0-2</dimIndex>
                    <name>CFDCFDF12%s_0</name>
                    <description>Common FIFO Access Data Field 12 Register %s Channel 0</description>
                    <addressOffset>0x643C</addressOffset>
                    <size>32</size>
                    <access>read-write</access>
                    <resetValue>0x00000000</resetValue>
                    <resetMask>0xffffffff</resetMask>
                    <fields>
                        <field>
                            <name>CFDB_LL</name>
                            <description>Common FIFO Buffer Data Bytes 48</description>
                            <lsb>0</lsb>
                            <msb>7</msb>
                            <access>read-write</access>
                        </field>
                        <field>
                            <name>CFDB_LH</name>
                            <description>Common FIFO Buffer Data Bytes 49</description>
                            <lsb>8</lsb>
                            <msb>15</msb>
                            <access>read-write</access>
                        </field>
                        <field>
                            <name>CFDB_HL</name>
                            <description>Common FIFO Buffer Data Bytes 50</description>
                            <lsb>16</lsb>
                            <msb>23</msb>
                            <access>read-write</access>
                        </field>
                        <field>
                            <name>CFDB_HH</name>
                            <description>Common FIFO Buffer Data Bytes 51</description>
                            <lsb>24</lsb>
                            <msb>31</msb>
                            <access>read-write</access>
                        </field>
                    </fields>
                </register>
                <register>
                    <dim>3</dim>
                    <dimIncrement>0x080</dimIncrement>
                    <dimIndex>0-2</dimIndex>
                    <name>CFDCFDF13%s_0</name>
                    <description>Common FIFO Access Data Field 13 Register %s Channel 0</description>
                    <addressOffset>0x6440</addressOffset>
                    <size>32</size>
                    <access>read-write</access>
                    <resetValue>0x00000000</resetValue>
                    <resetMask>0xffffffff</resetMask>
                    <fields>
                        <field>
                            <name>CFDB_LL</name>
                            <description>Common FIFO Buffer Data Bytes 52</description>
                            <lsb>0</lsb>
                            <msb>7</msb>
                            <access>read-write</access>
                        </field>
                        <field>
                            <name>CFDB_LH</name>
                            <description>Common FIFO Buffer Data Bytes 53</description>
                            <lsb>8</lsb>
                            <msb>15</msb>
                            <access>read-write</access>
                        </field>
                        <field>
                            <name>CFDB_HL</name>
                            <description>Common FIFO Buffer Data Bytes 54</description>
                            <lsb>16</lsb>
                            <msb>23</msb>
                            <access>read-write</access>
                        </field>
                        <field>
                            <name>CFDB_HH</name>
                            <description>Common FIFO Buffer Data Bytes 55</description>
                            <lsb>24</lsb>
                            <msb>31</msb>
                            <access>read-write</access>
                        </field>
                    </fields>
                </register>
                <register>
                    <dim>3</dim>
                    <dimIncrement>0x080</dimIncrement>
                    <dimIndex>0-2</dimIndex>
                    <name>CFDCFDF14%s_0</name>
                    <description>Common FIFO Access Data Field 14 Register %s Channel 0</description>
                    <addressOffset>0x6444</addressOffset>
                    <size>32</size>
                    <access>read-write</access>
                    <resetValue>0x00000000</resetValue>
                    <resetMask>0xffffffff</resetMask>
                    <fields>
                        <field>
                            <name>CFDB_LL</name>
                            <description>Common FIFO Buffer Data Bytes 56</description>
                            <lsb>0</lsb>
                            <msb>7</msb>
                            <access>read-write</access>
                        </field>
                        <field>
                            <name>CFDB_LH</name>
                            <description>Common FIFO Buffer Data Bytes 57</description>
                            <lsb>8</lsb>
                            <msb>15</msb>
                            <access>read-write</access>
                        </field>
                        <field>
                            <name>CFDB_HL</name>
                            <description>Common FIFO Buffer Data Bytes 58</description>
                            <lsb>16</lsb>
                            <msb>23</msb>
                            <access>read-write</access>
                        </field>
                        <field>
                            <name>CFDB_HH</name>
                            <description>Common FIFO Buffer Data Bytes 59</description>
                            <lsb>24</lsb>
                            <msb>31</msb>
                            <access>read-write</access>
                        </field>
                    </fields>
                </register>
                <register>
                    <dim>3</dim>
                    <dimIncrement>0x080</dimIncrement>
                    <dimIndex>0-2</dimIndex>
                    <name>CFDCFDF15%s_0</name>
                    <description>Common FIFO Access Data Field 15 Register %s Channel 0</description>
                    <addressOffset>0x6448</addressOffset>
                    <size>32</size>
                    <access>read-write</access>
                    <resetValue>0x00000000</resetValue>
                    <resetMask>0xffffffff</resetMask>
                    <fields>
                        <field>
                            <name>CFDB_LL</name>
                            <description>Common FIFO Buffer Data Bytes 60</description>
                            <lsb>0</lsb>
                            <msb>7</msb>
                            <access>read-write</access>
                        </field>
                        <field>
                            <name>CFDB_LH</name>
                            <description>Common FIFO Buffer Data Bytes 61</description>
                            <lsb>8</lsb>
                            <msb>15</msb>
                            <access>read-write</access>
                        </field>
                        <field>
                            <name>CFDB_HL</name>
                            <description>Common FIFO Buffer Data Bytes 62</description>
                            <lsb>16</lsb>
                            <msb>23</msb>
                            <access>read-write</access>
                        </field>
                        <field>
                            <name>CFDB_HH</name>
                            <description>Common FIFO Buffer Data Bytes 63</description>
                            <lsb>24</lsb>
                            <msb>31</msb>
                            <access>read-write</access>
                        </field>
                    </fields>
                </register>
                <register>
                    <dim>3</dim>
                    <dimIncrement>0x080</dimIncrement>
                    <dimIndex>0-2</dimIndex>
                    <name>CFDCFID%s_1</name>
                    <description>Common FIFO Access ID Register %s Channel 1</description>
                    <addressOffset>0x6580</addressOffset>
                    <size>32</size>
                    <access>read-write</access>
                    <resetValue>0x00000000</resetValue>
                    <resetMask>0xffffffff</resetMask>
                    <fields>
                        <field>
                            <name>CFID</name>
                            <description>Common FIFO Buffer ID Field</description>
                            <lsb>0</lsb>
                            <msb>28</msb>
                            <access>read-write</access>
                        </field>
                        <field>
                            <name>THLEN</name>
                            <description>THL Entry Enable</description>
                            <lsb>29</lsb>
                            <msb>29</msb>
                            <access>read-write</access>
                            <enumeratedValues>
                                </enumeratedValues>
                        </field>
                        <field>
                            <name>CFRTR</name>
                            <description>Common FIFO Buffer RTR bit</description>
                            <lsb>30</lsb>
                            <msb>30</msb>
                            <access>read-write</access>
                            <enumeratedValues>
                                </enumeratedValues>
                        </field>
                        <field>
                            <name>CFIDE</name>
                            <description>Common FIFO Buffer IDE bit</description>
                            <lsb>31</lsb>
                            <msb>31</msb>
                            <access>read-write</access>
                            <enumeratedValues>
                                </enumeratedValues>
                        </field>
                    </fields>
                </register>
                <register>
                    <dim>3</dim>
                    <dimIncrement>0x080</dimIncrement>
                    <dimIndex>0-2</dimIndex>
                    <name>CFDCFPTR%s_1</name>
                    <description>Common FIFO Access Pointer Register %s Channel 1</description>
                    <addressOffset>0x6584</addressOffset>
                    <size>32</size>
                    <access>read-write</access>
                    <resetValue>0x00000000</resetValue>
                    <resetMask>0xffffffff</resetMask>
                    <fields>
                        <field>
                            <name>CFTS</name>
                            <description>Common FIFO Timestamp Value</description>
                            <lsb>0</lsb>
                            <msb>15</msb>
                            <access>read-write</access>
                        </field>
                        <field>
                            <name>CFDLC</name>
                            <description>Common FIFO Buffer DLC Field</description>
                            <lsb>28</lsb>
                            <msb>31</msb>
                            <access>read-write</access>
                        </field>
                    </fields>
                </register>
                <register>
                    <dim>3</dim>
                    <dimIncrement>0x080</dimIncrement>
                    <dimIndex>0-2</dimIndex>
                    <name>CFDCFFDCSTS%s_1</name>
                    <description>Common FIFO Access CAN,FD Control/Status Register %s Channel 1</description>
                    <addressOffset>0x6588</addressOffset>
                    <size>32</size>
                    <access>read-write</access>
                    <resetValue>0x00000000</resetValue>
                    <resetMask>0xffffffff</resetMask>
                    <fields>
                        <field>
                            <name>CFESI</name>
                            <description>Error State Indicator bit</description>
                            <lsb>0</lsb>
                            <msb>0</msb>
                            <access>read-write</access>
                            <enumeratedValues>
                                </enumeratedValues>
                        </field>
                        <field>
                            <name>CFBRS</name>
                            <description>Bit Rate Switch bit</description>
                            <lsb>1</lsb>
                            <msb>1</msb>
                            <access>read-write</access>
                            <enumeratedValues>
                                </enumeratedValues>
                        </field>
                        <field>
                            <name>CFFDF</name>
                            <description>CAN FD Format bit</description>
                            <lsb>2</lsb>
                            <msb>2</msb>
                            <access>read-write</access>
                            <enumeratedValues>
                                </enumeratedValues>
                        </field>
                        <field>
                            <name>CFIFL</name>
                            <description>COMMON FIFO Buffer Information Label Field</description>
                            <lsb>8</lsb>
                            <msb>9</msb>
                            <access>read-write</access>
                        </field>
                        <field>
                            <name>CFPTR</name>
                            <description>Common FIFO Buffer Pointer Field</description>
                            <lsb>16</lsb>
                            <msb>31</msb>
                            <access>read-write</access>
                        </field>
                    </fields>
                </register>
                <register>
                    <dim>3</dim>
                    <dimIncrement>0x080</dimIncrement>
                    <dimIndex>0-2</dimIndex>
                    <name>CFDCFDF0%s_1</name>
                    <description>Common FIFO Access Data Field 0 Register %s Channel 1</description>
                    <addressOffset>0x658C</addressOffset>
                    <size>32</size>
                    <access>read-write</access>
                    <resetValue>0x00000000</resetValue>
                    <resetMask>0xffffffff</resetMask>
                    <fields>
                        <field>
                            <name>CFDB_LL</name>
                            <description>Common FIFO Buffer Data Bytes 0</description>
                            <lsb>0</lsb>
                            <msb>7</msb>
                            <access>read-write</access>
                        </field>
                        <field>
                            <name>CFDB_LH</name>
                            <description>Common FIFO Buffer Data Bytes 1</description>
                            <lsb>8</lsb>
                            <msb>15</msb>
                            <access>read-write</access>
                        </field>
                        <field>
                            <name>CFDB_HL</name>
                            <description>Common FIFO Buffer Data Bytes 2</description>
                            <lsb>16</lsb>
                            <msb>23</msb>
                            <access>read-write</access>
                        </field>
                        <field>
                            <name>CFDB_HH</name>
                            <description>Common FIFO Buffer Data Bytes 3</description>
                            <lsb>24</lsb>
                            <msb>31</msb>
                            <access>read-write</access>
                        </field>
                    </fields>
                </register>
                <register>
                    <dim>3</dim>
                    <dimIncrement>0x080</dimIncrement>
                    <dimIndex>0-2</dimIndex>
                    <name>CFDCFDF1%s_1</name>
                    <description>Common FIFO Access Data Field 1 Register %s Channel 1</description>
                    <addressOffset>0x6590</addressOffset>
                    <size>32</size>
                    <access>read-write</access>
                    <resetValue>0x00000000</resetValue>
                    <resetMask>0xffffffff</resetMask>
                    <fields>
                        <field>
                            <name>CFDB_LL</name>
                            <description>Common FIFO Buffer Data Bytes 4</description>
                            <lsb>0</lsb>
                            <msb>7</msb>
                            <access>read-write</access>
                        </field>
                        <field>
                            <name>CFDB_LH</name>
                            <description>Common FIFO Buffer Data Bytes 5</description>
                            <lsb>8</lsb>
                            <msb>15</msb>
                            <access>read-write</access>
                        </field>
                        <field>
                            <name>CFDB_HL</name>
                            <description>Common FIFO Buffer Data Bytes 6</description>
                            <lsb>16</lsb>
                            <msb>23</msb>
                            <access>read-write</access>
                        </field>
                        <field>
                            <name>CFDB_HH</name>
                            <description>Common FIFO Buffer Data Bytes 7</description>
                            <lsb>24</lsb>
                            <msb>31</msb>
                            <access>read-write</access>
                        </field>
                    </fields>
                </register>
                <register>
                    <dim>3</dim>
                    <dimIncrement>0x080</dimIncrement>
                    <dimIndex>0-2</dimIndex>
                    <name>CFDCFDF2%s_1</name>
                    <description>Common FIFO Access Data Field 2 Register %s Channel 1</description>
                    <addressOffset>0x6594</addressOffset>
                    <size>32</size>
                    <access>read-write</access>
                    <resetValue>0x00000000</resetValue>
                    <resetMask>0xffffffff</resetMask>
                    <fields>
                        <field>
                            <name>CFDB_LL</name>
                            <description>Common FIFO Buffer Data Bytes 8</description>
                            <lsb>0</lsb>
                            <msb>7</msb>
                            <access>read-write</access>
                        </field>
                        <field>
                            <name>CFDB_LH</name>
                            <description>Common FIFO Buffer Data Bytes 9</description>
                            <lsb>8</lsb>
                            <msb>15</msb>
                            <access>read-write</access>
                        </field>
                        <field>
                            <name>CFDB_HL</name>
                            <description>Common FIFO Buffer Data Bytes 10</description>
                            <lsb>16</lsb>
                            <msb>23</msb>
                            <access>read-write</access>
                        </field>
                        <field>
                            <name>CFDB_HH</name>
                            <description>Common FIFO Buffer Data Bytes 11</description>
                            <lsb>24</lsb>
                            <msb>31</msb>
                            <access>read-write</access>
                        </field>
                    </fields>
                </register>
                <register>
                    <dim>3</dim>
                    <dimIncrement>0x080</dimIncrement>
                    <dimIndex>0-2</dimIndex>
                    <name>CFDCFDF3%s_1</name>
                    <description>Common FIFO Access Data Field 3 Register %s Channel 1</description>
                    <addressOffset>0x6598</addressOffset>
                    <size>32</size>
                    <access>read-write</access>
                    <resetValue>0x00000000</resetValue>
                    <resetMask>0xffffffff</resetMask>
                    <fields>
                        <field>
                            <name>CFDB_LL</name>
                            <description>Common FIFO Buffer Data Bytes 12</description>
                            <lsb>0</lsb>
                            <msb>7</msb>
                            <access>read-write</access>
                        </field>
                        <field>
                            <name>CFDB_LH</name>
                            <description>Common FIFO Buffer Data Bytes 13</description>
                            <lsb>8</lsb>
                            <msb>15</msb>
                            <access>read-write</access>
                        </field>
                        <field>
                            <name>CFDB_HL</name>
                            <description>Common FIFO Buffer Data Bytes 14</description>
                            <lsb>16</lsb>
                            <msb>23</msb>
                            <access>read-write</access>
                        </field>
                        <field>
                            <name>CFDB_HH</name>
                            <description>Common FIFO Buffer Data Bytes 15</description>
                            <lsb>24</lsb>
                            <msb>31</msb>
                            <access>read-write</access>
                        </field>
                    </fields>
                </register>
                <register>
                    <dim>3</dim>
                    <dimIncrement>0x080</dimIncrement>
                    <dimIndex>0-2</dimIndex>
                    <name>CFDCFDF4%s_1</name>
                    <description>Common FIFO Access Data Field 4 Register %s Channel 1</description>
                    <addressOffset>0x659C</addressOffset>
                    <size>32</size>
                    <access>read-write</access>
                    <resetValue>0x00000000</resetValue>
                    <resetMask>0xffffffff</resetMask>
                    <fields>
                        <field>
                            <name>CFDB_LL</name>
                            <description>Common FIFO Buffer Data Bytes 16</description>
                            <lsb>0</lsb>
                            <msb>7</msb>
                            <access>read-write</access>
                        </field>
                        <field>
                            <name>CFDB_LH</name>
                            <description>Common FIFO Buffer Data Bytes 17</description>
                            <lsb>8</lsb>
                            <msb>15</msb>
                            <access>read-write</access>
                        </field>
                        <field>
                            <name>CFDB_HL</name>
                            <description>Common FIFO Buffer Data Bytes 18</description>
                            <lsb>16</lsb>
                            <msb>23</msb>
                            <access>read-write</access>
                        </field>
                        <field>
                            <name>CFDB_HH</name>
                            <description>Common FIFO Buffer Data Bytes 19</description>
                            <lsb>24</lsb>
                            <msb>31</msb>
                            <access>read-write</access>
                        </field>
                    </fields>
                </register>
                <register>
                    <dim>3</dim>
                    <dimIncrement>0x080</dimIncrement>
                    <dimIndex>0-2</dimIndex>
                    <name>CFDCFDF5%s_1</name>
                    <description>Common FIFO Access Data Field 5 Register %s Channel 1</description>
                    <addressOffset>0x65A0</addressOffset>
                    <size>32</size>
                    <access>read-write</access>
                    <resetValue>0x00000000</resetValue>
                    <resetMask>0xffffffff</resetMask>
                    <fields>
                        <field>
                            <name>CFDB_LL</name>
                            <description>Common FIFO Buffer Data Bytes 20</description>
                            <lsb>0</lsb>
                            <msb>7</msb>
                            <access>read-write</access>
                        </field>
                        <field>
                            <name>CFDB_LH</name>
                            <description>Common FIFO Buffer Data Bytes 21</description>
                            <lsb>8</lsb>
                            <msb>15</msb>
                            <access>read-write</access>
                        </field>
                        <field>
                            <name>CFDB_HL</name>
                            <description>Common FIFO Buffer Data Bytes 22</description>
                            <lsb>16</lsb>
                            <msb>23</msb>
                            <access>read-write</access>
                        </field>
                        <field>
                            <name>CFDB_HH</name>
                            <description>Common FIFO Buffer Data Bytes 23</description>
                            <lsb>24</lsb>
                            <msb>31</msb>
                            <access>read-write</access>
                        </field>
                    </fields>
                </register>
                <register>
                    <dim>3</dim>
                    <dimIncrement>0x080</dimIncrement>
                    <dimIndex>0-2</dimIndex>
                    <name>CFDCFDF6%s_1</name>
                    <description>Common FIFO Access Data Field 6 Register %s Channel 1</description>
                    <addressOffset>0x65A4</addressOffset>
                    <size>32</size>
                    <access>read-write</access>
                    <resetValue>0x00000000</resetValue>
                    <resetMask>0xffffffff</resetMask>
                    <fields>
                        <field>
                            <name>CFDB_LL</name>
                            <description>Common FIFO Buffer Data Bytes 24</description>
                            <lsb>0</lsb>
                            <msb>7</msb>
                            <access>read-write</access>
                        </field>
                        <field>
                            <name>CFDB_LH</name>
                            <description>Common FIFO Buffer Data Bytes 25</description>
                            <lsb>8</lsb>
                            <msb>15</msb>
                            <access>read-write</access>
                        </field>
                        <field>
                            <name>CFDB_HL</name>
                            <description>Common FIFO Buffer Data Bytes 26</description>
                            <lsb>16</lsb>
                            <msb>23</msb>
                            <access>read-write</access>
                        </field>
                        <field>
                            <name>CFDB_HH</name>
                            <description>Common FIFO Buffer Data Bytes 27</description>
                            <lsb>24</lsb>
                            <msb>31</msb>
                            <access>read-write</access>
                        </field>
                    </fields>
                </register>
                <register>
                    <dim>3</dim>
                    <dimIncrement>0x080</dimIncrement>
                    <dimIndex>0-2</dimIndex>
                    <name>CFDCFDF7%s_1</name>
                    <description>Common FIFO Access Data Field 7 Register %s Channel 1</description>
                    <addressOffset>0x65A8</addressOffset>
                    <size>32</size>
                    <access>read-write</access>
                    <resetValue>0x00000000</resetValue>
                    <resetMask>0xffffffff</resetMask>
                    <fields>
                        <field>
                            <name>CFDB_LL</name>
                            <description>Common FIFO Buffer Data Bytes 28</description>
                            <lsb>0</lsb>
                            <msb>7</msb>
                            <access>read-write</access>
                        </field>
                        <field>
                            <name>CFDB_LH</name>
                            <description>Common FIFO Buffer Data Bytes 29</description>
                            <lsb>8</lsb>
                            <msb>15</msb>
                            <access>read-write</access>
                        </field>
                        <field>
                            <name>CFDB_HL</name>
                            <description>Common FIFO Buffer Data Bytes 30</description>
                            <lsb>16</lsb>
                            <msb>23</msb>
                            <access>read-write</access>
                        </field>
                        <field>
                            <name>CFDB_HH</name>
                            <description>Common FIFO Buffer Data Bytes 31</description>
                            <lsb>24</lsb>
                            <msb>31</msb>
                            <access>read-write</access>
                        </field>
                    </fields>
                </register>
                <register>
                    <dim>3</dim>
                    <dimIncrement>0x080</dimIncrement>
                    <dimIndex>0-2</dimIndex>
                    <name>CFDCFDF8%s_1</name>
                    <description>Common FIFO Access Data Field 8 Register %s Channel 1</description>
                    <addressOffset>0x65AC</addressOffset>
                    <size>32</size>
                    <access>read-write</access>
                    <resetValue>0x00000000</resetValue>
                    <resetMask>0xffffffff</resetMask>
                    <fields>
                        <field>
                            <name>CFDB_LL</name>
                            <description>Common FIFO Buffer Data Bytes 32</description>
                            <lsb>0</lsb>
                            <msb>7</msb>
                            <access>read-write</access>
                        </field>
                        <field>
                            <name>CFDB_LH</name>
                            <description>Common FIFO Buffer Data Bytes 33</description>
                            <lsb>8</lsb>
                            <msb>15</msb>
                            <access>read-write</access>
                        </field>
                        <field>
                            <name>CFDB_HL</name>
                            <description>Common FIFO Buffer Data Bytes 34</description>
                            <lsb>16</lsb>
                            <msb>23</msb>
                            <access>read-write</access>
                        </field>
                        <field>
                            <name>CFDB_HH</name>
                            <description>Common FIFO Buffer Data Bytes 35</description>
                            <lsb>24</lsb>
                            <msb>31</msb>
                            <access>read-write</access>
                        </field>
                    </fields>
                </register>
                <register>
                    <dim>3</dim>
                    <dimIncrement>0x080</dimIncrement>
                    <dimIndex>0-2</dimIndex>
                    <name>CFDCFDF9%s_1</name>
                    <description>Common FIFO Access Data Field 9 Register %s Channel 1</description>
                    <addressOffset>0x65B0</addressOffset>
                    <size>32</size>
                    <access>read-write</access>
                    <resetValue>0x00000000</resetValue>
                    <resetMask>0xffffffff</resetMask>
                    <fields>
                        <field>
                            <name>CFDB_LL</name>
                            <description>Common FIFO Buffer Data Bytes 36</description>
                            <lsb>0</lsb>
                            <msb>7</msb>
                            <access>read-write</access>
                        </field>
                        <field>
                            <name>CFDB_LH</name>
                            <description>Common FIFO Buffer Data Bytes 37</description>
                            <lsb>8</lsb>
                            <msb>15</msb>
                            <access>read-write</access>
                        </field>
                        <field>
                            <name>CFDB_HL</name>
                            <description>Common FIFO Buffer Data Bytes 38</description>
                            <lsb>16</lsb>
                            <msb>23</msb>
                            <access>read-write</access>
                        </field>
                        <field>
                            <name>CFDB_HH</name>
                            <description>Common FIFO Buffer Data Bytes 39</description>
                            <lsb>24</lsb>
                            <msb>31</msb>
                            <access>read-write</access>
                        </field>
                    </fields>
                </register>
                <register>
                    <dim>3</dim>
                    <dimIncrement>0x080</dimIncrement>
                    <dimIndex>0-2</dimIndex>
                    <name>CFDCFDF10%s_1</name>
                    <description>Common FIFO Access Data Field 10 Register %s Channel 1</description>
                    <addressOffset>0x65B4</addressOffset>
                    <size>32</size>
                    <access>read-write</access>
                    <resetValue>0x00000000</resetValue>
                    <resetMask>0xffffffff</resetMask>
                    <fields>
                        <field>
                            <name>CFDB_LL</name>
                            <description>Common FIFO Buffer Data Bytes 40</description>
                            <lsb>0</lsb>
                            <msb>7</msb>
                            <access>read-write</access>
                        </field>
                        <field>
                            <name>CFDB_LH</name>
                            <description>Common FIFO Buffer Data Bytes 41</description>
                            <lsb>8</lsb>
                            <msb>15</msb>
                            <access>read-write</access>
                        </field>
                        <field>
                            <name>CFDB_HL</name>
                            <description>Common FIFO Buffer Data Bytes 42</description>
                            <lsb>16</lsb>
                            <msb>23</msb>
                            <access>read-write</access>
                        </field>
                        <field>
                            <name>CFDB_HH</name>
                            <description>Common FIFO Buffer Data Bytes 43</description>
                            <lsb>24</lsb>
                            <msb>31</msb>
                            <access>read-write</access>
                        </field>
                    </fields>
                </register>
                <register>
                    <dim>3</dim>
                    <dimIncrement>0x080</dimIncrement>
                    <dimIndex>0-2</dimIndex>
                    <name>CFDCFDF11%s_1</name>
                    <description>Common FIFO Access Data Field 11 Register %s Channel 1</description>
                    <addressOffset>0x65B8</addressOffset>
                    <size>32</size>
                    <access>read-write</access>
                    <resetValue>0x00000000</resetValue>
                    <resetMask>0xffffffff</resetMask>
                    <fields>
                        <field>
                            <name>CFDB_LL</name>
                            <description>Common FIFO Buffer Data Bytes 44</description>
                            <lsb>0</lsb>
                            <msb>7</msb>
                            <access>read-write</access>
                        </field>
                        <field>
                            <name>CFDB_LH</name>
                            <description>Common FIFO Buffer Data Bytes 45</description>
                            <lsb>8</lsb>
                            <msb>15</msb>
                            <access>read-write</access>
                        </field>
                        <field>
                            <name>CFDB_HL</name>
                            <description>Common FIFO Buffer Data Bytes 46</description>
                            <lsb>16</lsb>
                            <msb>23</msb>
                            <access>read-write</access>
                        </field>
                        <field>
                            <name>CFDB_HH</name>
                            <description>Common FIFO Buffer Data Bytes 47</description>
                            <lsb>24</lsb>
                            <msb>31</msb>
                            <access>read-write</access>
                        </field>
                    </fields>
                </register>
                <register>
                    <dim>3</dim>
                    <dimIncrement>0x080</dimIncrement>
                    <dimIndex>0-2</dimIndex>
                    <name>CFDCFDF12%s_1</name>
                    <description>Common FIFO Access Data Field 12 Register %s Channel 1</description>
                    <addressOffset>0x65BC</addressOffset>
                    <size>32</size>
                    <access>read-write</access>
                    <resetValue>0x00000000</resetValue>
                    <resetMask>0xffffffff</resetMask>
                    <fields>
                        <field>
                            <name>CFDB_LL</name>
                            <description>Common FIFO Buffer Data Bytes 48</description>
                            <lsb>0</lsb>
                            <msb>7</msb>
                            <access>read-write</access>
                        </field>
                        <field>
                            <name>CFDB_LH</name>
                            <description>Common FIFO Buffer Data Bytes 49</description>
                            <lsb>8</lsb>
                            <msb>15</msb>
                            <access>read-write</access>
                        </field>
                        <field>
                            <name>CFDB_HL</name>
                            <description>Common FIFO Buffer Data Bytes 50</description>
                            <lsb>16</lsb>
                            <msb>23</msb>
                            <access>read-write</access>
                        </field>
                        <field>
                            <name>CFDB_HH</name>
                            <description>Common FIFO Buffer Data Bytes 51</description>
                            <lsb>24</lsb>
                            <msb>31</msb>
                            <access>read-write</access>
                        </field>
                    </fields>
                </register>
                <register>
                    <dim>3</dim>
                    <dimIncrement>0x080</dimIncrement>
                    <dimIndex>0-2</dimIndex>
                    <name>CFDCFDF13%s_1</name>
                    <description>Common FIFO Access Data Field 13 Register %s Channel 1</description>
                    <addressOffset>0x65C0</addressOffset>
                    <size>32</size>
                    <access>read-write</access>
                    <resetValue>0x00000000</resetValue>
                    <resetMask>0xffffffff</resetMask>
                    <fields>
                        <field>
                            <name>CFDB_LL</name>
                            <description>Common FIFO Buffer Data Bytes 52</description>
                            <lsb>0</lsb>
                            <msb>7</msb>
                            <access>read-write</access>
                        </field>
                        <field>
                            <name>CFDB_LH</name>
                            <description>Common FIFO Buffer Data Bytes 53</description>
                            <lsb>8</lsb>
                            <msb>15</msb>
                            <access>read-write</access>
                        </field>
                        <field>
                            <name>CFDB_HL</name>
                            <description>Common FIFO Buffer Data Bytes 54</description>
                            <lsb>16</lsb>
                            <msb>23</msb>
                            <access>read-write</access>
                        </field>
                        <field>
                            <name>CFDB_HH</name>
                            <description>Common FIFO Buffer Data Bytes 55</description>
                            <lsb>24</lsb>
                            <msb>31</msb>
                            <access>read-write</access>
                        </field>
                    </fields>
                </register>
                <register>
                    <dim>3</dim>
                    <dimIncrement>0x080</dimIncrement>
                    <dimIndex>0-2</dimIndex>
                    <name>CFDCFDF14%s_1</name>
                    <description>Common FIFO Access Data Field 14 Register %s Channel 1</description>
                    <addressOffset>0x65C4</addressOffset>
                    <size>32</size>
                    <access>read-write</access>
                    <resetValue>0x00000000</resetValue>
                    <resetMask>0xffffffff</resetMask>
                    <fields>
                        <field>
                            <name>CFDB_LL</name>
                            <description>Common FIFO Buffer Data Bytes 56</description>
                            <lsb>0</lsb>
                            <msb>7</msb>
                            <access>read-write</access>
                        </field>
                        <field>
                            <name>CFDB_LH</name>
                            <description>Common FIFO Buffer Data Bytes 57</description>
                            <lsb>8</lsb>
                            <msb>15</msb>
                            <access>read-write</access>
                        </field>
                        <field>
                            <name>CFDB_HL</name>
                            <description>Common FIFO Buffer Data Bytes 58</description>
                            <lsb>16</lsb>
                            <msb>23</msb>
                            <access>read-write</access>
                        </field>
                        <field>
                            <name>CFDB_HH</name>
                            <description>Common FIFO Buffer Data Bytes 59</description>
                            <lsb>24</lsb>
                            <msb>31</msb>
                            <access>read-write</access>
                        </field>
                    </fields>
                </register>
                <register>
                    <dim>3</dim>
                    <dimIncrement>0x080</dimIncrement>
                    <dimIndex>0-2</dimIndex>
                    <name>CFDCFDF15%s_1</name>
                    <description>Common FIFO Access Data Field 15 Register %s Channel 1</description>
                    <addressOffset>0x65C8</addressOffset>
                    <size>32</size>
                    <access>read-write</access>
                    <resetValue>0x00000000</resetValue>
                    <resetMask>0xffffffff</resetMask>
                    <fields>
                        <field>
                            <name>CFDB_LL</name>
                            <description>Common FIFO Buffer Data Bytes 60</description>
                            <lsb>0</lsb>
                            <msb>7</msb>
                            <access>read-write</access>
                        </field>
                        <field>
                            <name>CFDB_LH</name>
                            <description>Common FIFO Buffer Data Bytes 61</description>
                            <lsb>8</lsb>
                            <msb>15</msb>
                            <access>read-write</access>
                        </field>
                        <field>
                            <name>CFDB_HL</name>
                            <description>Common FIFO Buffer Data Bytes 62</description>
                            <lsb>16</lsb>
                            <msb>23</msb>
                            <access>read-write</access>
                        </field>
                        <field>
                            <name>CFDB_HH</name>
                            <description>Common FIFO Buffer Data Bytes 63</description>
                            <lsb>24</lsb>
                            <msb>31</msb>
                            <access>read-write</access>
                        </field>
                    </fields>
                </register>
                <register>
                    <dim>2</dim>
                    <dimIncrement>0x08</dimIncrement>
                    <dimIndex>0-1</dimIndex>
                    <name>CFDTHLACC0%s</name>
                    <description>TX History List Access Registers 0</description>
                    <addressOffset>0x8000</addressOffset>
                    <size>32</size>
                    <access>read-only</access>
                    <resetValue>0x00000000</resetValue>
                    <resetMask>0xffffffff</resetMask>
                    <fields>
                        <field>
                            <name>BT</name>
                            <description>Buffer Type</description>
                            <lsb>0</lsb>
                            <msb>2</msb>
                            <access>read-only</access>
                            <enumeratedValues>
                                </enumeratedValues>
                        </field>
                        <field>
                            <name>BN</name>
                            <description>Buffer Number</description>
                            <lsb>3</lsb>
                            <msb>9</msb>
                            <access>read-only</access>
                        </field>
                        <field>
                            <name>TGW</name>
                            <description>Transmit Gateway Buffer Indication</description>
                            <lsb>15</lsb>
                            <msb>15</msb>
                            <access>read-only</access>
                            <enumeratedValues>
                                </enumeratedValues>
                        </field>
                        <field>
                            <name>TMTS</name>
                            <description>Transmit Timestamp</description>
                            <lsb>16</lsb>
                            <msb>31</msb>
                            <access>read-only</access>
                        </field>
                    </fields>
                </register>
                <register>
                    <dim>2</dim>
                    <dimIncrement>0x08</dimIncrement>
                    <dimIndex>0-1</dimIndex>
                    <name>CFDTHLACC1%s</name>
                    <description>TX History List Access Registers 1</description>
                    <addressOffset>0x8004</addressOffset>
                    <size>32</size>
                    <access>read-write</access>
                    <resetValue>0x00000000</resetValue>
                    <resetMask>0xffffffff</resetMask>
                    <fields>
                        <field>
                            <name>TID</name>
                            <description>Transmit ID</description>
                            <lsb>0</lsb>
                            <msb>15</msb>
                            <access>read-only</access>
                        </field>
                        <field>
                            <name>TIFL</name>
                            <description>Transmit Information Label</description>
                            <lsb>16</lsb>
                            <msb>17</msb>
                            <access>read-only</access>
                        </field>
                    </fields>
                </register>
                <register>
                    <dim>64</dim>
                    <dimIncrement>0x04</dimIncrement>
                    <dimIndex>0-63</dimIndex>
                    <name>CFDRPGACC%s</name>
                    <description>RAM Test Page Access Registers %s</description>
                    <addressOffset>0x8400</addressOffset>
                    <size>32</size>
                    <access>read-write</access>
                    <resetValue>0x00000000</resetValue>
                    <resetMask>0xffffffff</resetMask>
                    <fields>
                        <field>
                            <name>RDTA</name>
                            <description>RAM Data Test Access</description>
                            <lsb>0</lsb>
                            <msb>31</msb>
                            <access>read-write</access>
                        </field>
                    </fields>
                </register>
                <register>
                    <dim>8</dim>
                    <dimIncrement>0x080</dimIncrement>
                    <dimIndex>0-7</dimIndex>
                    <name>CFDTMID%s_0</name>
                    <description>TX Message Buffer ID Register %s Channel 0</description>
                    <addressOffset>0x10000</addressOffset>
                    <size>32</size>
                    <access>read-write</access>
                    <resetValue>0x00000000</resetValue>
                    <resetMask>0xffffffff</resetMask>
                    <fields>
                        <field>
                            <name>TMID</name>
                            <description>TX Message Buffer ID Field</description>
                            <lsb>0</lsb>
                            <msb>28</msb>
                            <access>read-write</access>
                        </field>
                        <field>
                            <name>THLEN</name>
                            <description>Tx History List Entry</description>
                            <lsb>29</lsb>
                            <msb>29</msb>
                            <access>read-write</access>
                            <enumeratedValues>
                                </enumeratedValues>
                        </field>
                        <field>
                            <name>TMRTR</name>
                            <description>TX Message Buffer RTR bit</description>
                            <lsb>30</lsb>
                            <msb>30</msb>
                            <access>read-write</access>
                            <enumeratedValues>
                                </enumeratedValues>
                        </field>
                        <field>
                            <name>TMIDE</name>
                            <description>TX Message Buffer IDE bit</description>
                            <lsb>31</lsb>
                            <msb>31</msb>
                            <access>read-write</access>
                            <enumeratedValues>
                                </enumeratedValues>
                        </field>
                    </fields>
                </register>
                <register>
                    <dim>8</dim>
                    <dimIncrement>0x080</dimIncrement>
                    <dimIndex>0-7</dimIndex>
                    <name>CFDTMPTR%s_0</name>
                    <description>TX Message Buffer Pointer Register %s Channel 0</description>
                    <addressOffset>0x10004</addressOffset>
                    <size>32</size>
                    <access>read-write</access>
                    <resetValue>0x00000000</resetValue>
                    <resetMask>0xffffffff</resetMask>
                    <fields>
                        <field>
                            <name>TMDLC</name>
                            <description>TX Message Buffer DLC Field</description>
                            <lsb>28</lsb>
                            <msb>31</msb>
                            <access>read-write</access>
                        </field>
                    </fields>
                </register>
                <register>
                    <dim>8</dim>
                    <dimIncrement>0x080</dimIncrement>
                    <dimIndex>0-7</dimIndex>
                    <name>CFDTMFDCTR%s_0</name>
                    <description>TX Message Buffer CANFD Control Register %s Channel i</description>
                    <addressOffset>0x10008</addressOffset>
                    <size>32</size>
                    <access>read-write</access>
                    <resetValue>0x00000000</resetValue>
                    <resetMask>0xffffffff</resetMask>
                    <fields>
                        <field>
                            <name>TMESI</name>
                            <description>Error State Indicator bit</description>
                            <lsb>0</lsb>
                            <msb>0</msb>
                            <access>read-write</access>
                            <enumeratedValues>
                                </enumeratedValues>
                        </field>
                        <field>
                            <name>TMBRS</name>
                            <description>Bit Rate Switch bit</description>
                            <lsb>1</lsb>
                            <msb>1</msb>
                            <access>read-write</access>
                            <enumeratedValues>
                                </enumeratedValues>
                        </field>
                        <field>
                            <name>TMFDF</name>
                            <description>CAN FD Format bit</description>
                            <lsb>2</lsb>
                            <msb>2</msb>
                            <access>read-write</access>
                            <enumeratedValues>
                                </enumeratedValues>
                        </field>
                        <field>
                            <name>TMIFL</name>
                            <description>TX Message Buffer Information Label Field</description>
                            <lsb>8</lsb>
                            <msb>9</msb>
                            <access>read-write</access>
                        </field>
                        <field>
                            <name>TMPTR</name>
                            <description>TX Message Buffer Pointer Field</description>
                            <lsb>16</lsb>
                            <msb>31</msb>
                            <access>read-write</access>
                        </field>
                    </fields>
                </register>
                <register>
                    <dim>8</dim>
                    <dimIncrement>0x080</dimIncrement>
                    <dimIndex>0-7</dimIndex>
                    <name>CFDTMDF0_%s_0</name>
                    <description>TX Message Buffer Data Field 0 Register %s Channel 0</description>
                    <addressOffset>0x1000C</addressOffset>
                    <size>32</size>
                    <access>read-write</access>
                    <resetValue>0x00000000</resetValue>
                    <resetMask>0xffffffff</resetMask>
                    <fields>
                        <field>
                            <name>TMDB_LL</name>
                            <description>TX Message Buffer Data Byte 0</description>
                            <lsb>0</lsb>
                            <msb>7</msb>
                            <access>read-write</access>
                        </field>
                        <field>
                            <name>TMDB_LH</name>
                            <description>TX Message Buffer Data Byte 1</description>
                            <lsb>8</lsb>
                            <msb>15</msb>
                            <access>read-write</access>
                        </field>
                        <field>
                            <name>TMDB_HL</name>
                            <description>TX Message Buffer Data Byte 2</description>
                            <lsb>16</lsb>
                            <msb>23</msb>
                            <access>read-write</access>
                        </field>
                        <field>
                            <name>TMDB_HH</name>
                            <description>TX Message Buffer Data Byte 3</description>
                            <lsb>24</lsb>
                            <msb>31</msb>
                            <access>read-write</access>
                        </field>
                    </fields>
                </register>
                <register>
                    <dim>8</dim>
                    <dimIncrement>0x080</dimIncrement>
                    <dimIndex>0-7</dimIndex>
                    <name>CFDTMDF1_%s_0</name>
                    <description>TX Message Buffer Data Field 1 Register %s Channel 0</description>
                    <addressOffset>0x10010</addressOffset>
                    <size>32</size>
                    <access>read-write</access>
                    <resetValue>0x00000000</resetValue>
                    <resetMask>0xffffffff</resetMask>
                    <fields>
                        <field>
                            <name>TMDB_LL</name>
                            <description>TX Message Buffer Data Byte 4</description>
                            <lsb>0</lsb>
                            <msb>7</msb>
                            <access>read-write</access>
                        </field>
                        <field>
                            <name>TMDB_LH</name>
                            <description>TX Message Buffer Data Byte 5</description>
                            <lsb>8</lsb>
                            <msb>15</msb>
                            <access>read-write</access>
                        </field>
                        <field>
                            <name>TMDB_HL</name>
                            <description>TX Message Buffer Data Byte 6</description>
                            <lsb>16</lsb>
                            <msb>23</msb>
                            <access>read-write</access>
                        </field>
                        <field>
                            <name>TMDB_HH</name>
                            <description>TX Message Buffer Data Byte 7</description>
                            <lsb>24</lsb>
                            <msb>31</msb>
                            <access>read-write</access>
                        </field>
                    </fields>
                </register>
                <register>
                    <dim>8</dim>
                    <dimIncrement>0x080</dimIncrement>
                    <dimIndex>0-7</dimIndex>
                    <name>CFDTMDF2_%s_0</name>
                    <description>TX Message Buffer Data Field 2 Register %s Channel 0</description>
                    <addressOffset>0x10014</addressOffset>
                    <size>32</size>
                    <access>read-write</access>
                    <resetValue>0x00000000</resetValue>
                    <resetMask>0xffffffff</resetMask>
                    <fields>
                        <field>
                            <name>TMDB_LL</name>
                            <description>TX Message Buffer Data Byte 8</description>
                            <lsb>0</lsb>
                            <msb>7</msb>
                            <access>read-write</access>
                        </field>
                        <field>
                            <name>TMDB_LH</name>
                            <description>TX Message Buffer Data Byte 9</description>
                            <lsb>8</lsb>
                            <msb>15</msb>
                            <access>read-write</access>
                        </field>
                        <field>
                            <name>TMDB_HL</name>
                            <description>TX Message Buffer Data Byte 10</description>
                            <lsb>16</lsb>
                            <msb>23</msb>
                            <access>read-write</access>
                        </field>
                        <field>
                            <name>TMDB_HH</name>
                            <description>TX Message Buffer Data Byte 11</description>
                            <lsb>24</lsb>
                            <msb>31</msb>
                            <access>read-write</access>
                        </field>
                    </fields>
                </register>
                <register>
                    <dim>8</dim>
                    <dimIncrement>0x080</dimIncrement>
                    <dimIndex>0-7</dimIndex>
                    <name>CFDTMDF3_%s_0</name>
                    <description>TX Message Buffer Data Field 3 Register %s Channel 0</description>
                    <addressOffset>0x10018</addressOffset>
                    <size>32</size>
                    <access>read-write</access>
                    <resetValue>0x00000000</resetValue>
                    <resetMask>0xffffffff</resetMask>
                    <fields>
                        <field>
                            <name>TMDB_LL</name>
                            <description>TX Message Buffer Data Byte 12</description>
                            <lsb>0</lsb>
                            <msb>7</msb>
                            <access>read-write</access>
                        </field>
                        <field>
                            <name>TMDB_LH</name>
                            <description>TX Message Buffer Data Byte 12</description>
                            <lsb>8</lsb>
                            <msb>15</msb>
                            <access>read-write</access>
                        </field>
                        <field>
                            <name>TMDB_HL</name>
                            <description>TX Message Buffer Data Byte 12</description>
                            <lsb>16</lsb>
                            <msb>23</msb>
                            <access>read-write</access>
                        </field>
                        <field>
                            <name>TMDB_HH</name>
                            <description>TX Message Buffer Data Byte 12</description>
                            <lsb>24</lsb>
                            <msb>31</msb>
                            <access>read-write</access>
                        </field>
                    </fields>
                </register>
                <register>
                    <dim>8</dim>
                    <dimIncrement>0x080</dimIncrement>
                    <dimIndex>0-7</dimIndex>
                    <name>CFDTMDF4_%s_0</name>
                    <description>TX Message Buffer Data Field 4 Register %s Channel 0</description>
                    <addressOffset>0x1001C</addressOffset>
                    <size>32</size>
                    <access>read-write</access>
                    <resetValue>0x00000000</resetValue>
                    <resetMask>0xffffffff</resetMask>
                    <fields>
                        <field>
                            <name>TMDB_LL</name>
                            <description>TX Message Buffer Data Byte 16</description>
                            <lsb>0</lsb>
                            <msb>7</msb>
                            <access>read-write</access>
                        </field>
                        <field>
                            <name>TMDB_LH</name>
                            <description>TX Message Buffer Data Byte 17</description>
                            <lsb>8</lsb>
                            <msb>15</msb>
                            <access>read-write</access>
                        </field>
                        <field>
                            <name>TMDB_HL</name>
                            <description>TX Message Buffer Data Byte 18</description>
                            <lsb>16</lsb>
                            <msb>23</msb>
                            <access>read-write</access>
                        </field>
                        <field>
                            <name>TMDB_HH</name>
                            <description>TX Message Buffer Data Byte 19</description>
                            <lsb>24</lsb>
                            <msb>31</msb>
                            <access>read-write</access>
                        </field>
                    </fields>
                </register>
                <register>
                    <dim>8</dim>
                    <dimIncrement>0x080</dimIncrement>
                    <dimIndex>0-7</dimIndex>
                    <name>CFDTMDF5_%s_0</name>
                    <description>TX Message Buffer Data Field 5 Register %s Channel 0</description>
                    <addressOffset>0x10020</addressOffset>
                    <size>32</size>
                    <access>read-write</access>
                    <resetValue>0x00000000</resetValue>
                    <resetMask>0xffffffff</resetMask>
                    <fields>
                        <field>
                            <name>TMDB_LL</name>
                            <description>TX Message Buffer Data Byte 20</description>
                            <lsb>0</lsb>
                            <msb>7</msb>
                            <access>read-write</access>
                        </field>
                        <field>
                            <name>TMDB_LH</name>
                            <description>TX Message Buffer Data Byte 21</description>
                            <lsb>8</lsb>
                            <msb>15</msb>
                            <access>read-write</access>
                        </field>
                        <field>
                            <name>TMDB_HL</name>
                            <description>TX Message Buffer Data Byte 22</description>
                            <lsb>16</lsb>
                            <msb>23</msb>
                            <access>read-write</access>
                        </field>
                        <field>
                            <name>TMDB_HH</name>
                            <description>TX Message Buffer Data Byte 23</description>
                            <lsb>24</lsb>
                            <msb>31</msb>
                            <access>read-write</access>
                        </field>
                    </fields>
                </register>
                <register>
                    <dim>8</dim>
                    <dimIncrement>0x080</dimIncrement>
                    <dimIndex>0-7</dimIndex>
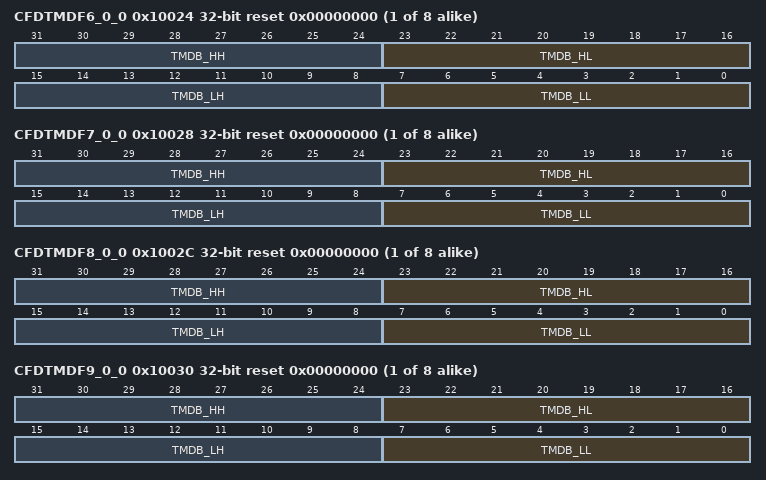
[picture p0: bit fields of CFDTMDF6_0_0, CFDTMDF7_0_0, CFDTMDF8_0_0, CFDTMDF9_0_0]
                    <name>CFDTMDF6_%s_0</name>
                    <description>TX Message Buffer Data Field 6 Register %s Channel 0</description>
                    <addressOffset>0x10024</addressOffset>
                    <size>32</size>
                    <access>read-write</access>
                    <resetValue>0x00000000</resetValue>
                    <resetMask>0xffffffff</resetMask>
                    <fields>
                        <field>
                            <name>TMDB_LL</name>
                            <description>TX Message Buffer Data Byte 24</description>
                            <lsb>0</lsb>
                            <msb>7</msb>
                            <access>read-write</access>
                        </field>
                        <field>
                            <name>TMDB_LH</name>
                            <description>TX Message Buffer Data Byte 25</description>
                            <lsb>8</lsb>
                            <msb>15</msb>
                            <access>read-write</access>
                        </field>
                        <field>
                            <name>TMDB_HL</name>
                            <description>TX Message Buffer Data Byte 26</description>
                            <lsb>16</lsb>
                            <msb>23</msb>
                            <access>read-write</access>
                        </field>
                        <field>
                            <name>TMDB_HH</name>
                            <description>TX Message Buffer Data Byte 27</description>
                            <lsb>24</lsb>
                            <msb>31</msb>
                            <access>read-write</access>
                        </field>
                    </fields>
                </register>
                <register>
                    <dim>8</dim>
                    <dimIncrement>0x080</dimIncrement>
                    <dimIndex>0-7</dimIndex>
                    <name>CFDTMDF7_%s_0</name>
                    <description>TX Message Buffer Data Field 7 Register %s Channel 0</description>
                    <addressOffset>0x10028</addressOffset>
                    <size>32</size>
                    <access>read-write</access>
                    <resetValue>0x00000000</resetValue>
                    <resetMask>0xffffffff</resetMask>
                    <fields>
                        <field>
                            <name>TMDB_LL</name>
                            <description>TX Message Buffer Data Byte 28</description>
                            <lsb>0</lsb>
                            <msb>7</msb>
                            <access>read-write</access>
                        </field>
                        <field>
                            <name>TMDB_LH</name>
                            <description>TX Message Buffer Data Byte29</description>
                            <lsb>8</lsb>
                            <msb>15</msb>
                            <access>read-write</access>
                        </field>
                        <field>
                            <name>TMDB_HL</name>
                            <description>TX Message Buffer Data Byte 30</description>
                            <lsb>16</lsb>
                            <msb>23</msb>
                            <access>read-write</access>
                        </field>
                        <field>
                            <name>TMDB_HH</name>
                            <description>TX Message Buffer Data Byte 31</description>
                            <lsb>24</lsb>
                            <msb>31</msb>
                            <access>read-write</access>
                        </field>
                    </fields>
                </register>
                <register>
                    <dim>8</dim>
                    <dimIncrement>0x080</dimIncrement>
                    <dimIndex>0-7</dimIndex>
                    <name>CFDTMDF8_%s_0</name>
                    <description>TX Message Buffer Data Field 8 Register %s Channel 0</description>
                    <addressOffset>0x1002C</addressOffset>
                    <size>32</size>
                    <access>read-write</access>
                    <resetValue>0x00000000</resetValue>
                    <resetMask>0xffffffff</resetMask>
                    <fields>
                        <field>
                            <name>TMDB_LL</name>
                            <description>TX Message Buffer Data Byte 32</description>
                            <lsb>0</lsb>
                            <msb>7</msb>
                            <access>read-write</access>
                        </field>
                        <field>
                            <name>TMDB_LH</name>
                            <description>TX Message Buffer Data Byte 33</description>
                            <lsb>8</lsb>
                            <msb>15</msb>
                            <access>read-write</access>
                        </field>
                        <field>
                            <name>TMDB_HL</name>
                            <description>TX Message Buffer Data Byte 34</description>
                            <lsb>16</lsb>
                            <msb>23</msb>
                            <access>read-write</access>
                        </field>
                        <field>
                            <name>TMDB_HH</name>
                            <description>TX Message Buffer Data Byte 35</description>
                            <lsb>24</lsb>
                            <msb>31</msb>
                            <access>read-write</access>
                        </field>
                    </fields>
                </register>
                <register>
                    <dim>8</dim>
                    <dimIncrement>0x080</dimIncrement>
                    <dimIndex>0-7</dimIndex>
                    <name>CFDTMDF9_%s_0</name>
                    <description>TX Message Buffer Data Field 9 Register %s Channel 0</description>
                    <addressOffset>0x10030</addressOffset>
                    <size>32</size>
                    <access>read-write</access>
                    <resetValue>0x00000000</resetValue>
                    <resetMask>0xffffffff</resetMask>
                    <fields>
                        <field>
                            <name>TMDB_LL</name>
                            <description>TX Message Buffer Data Byte 36</description>
                            <lsb>0</lsb>
                            <msb>7</msb>
                            <access>read-write</access>
                        </field>
                        <field>
                            <name>TMDB_LH</name>
                            <description>TX Message Buffer Data Byte 37</description>
                            <lsb>8</lsb>
                            <msb>15</msb>
                            <access>read-write</access>
                        </field>
                        <field>
                            <name>TMDB_HL</name>
                            <description>TX Message Buffer Data Byte 38</description>
                            <lsb>16</lsb>
                            <msb>23</msb>
                            <access>read-write</access>
                        </field>
                        <field>
                            <name>TMDB_HH</name>
                            <description>TX Message Buffer Data Byte 39</description>
                            <lsb>24</lsb>
                            <msb>31</msb>
                            <access>read-write</access>
                        </field>
                    </fields>
                </register>
                <register>
                    <dim>8</dim>
                    <dimIncrement>0x080</dimIncrement>
                    <dimIndex>0-7</dimIndex>
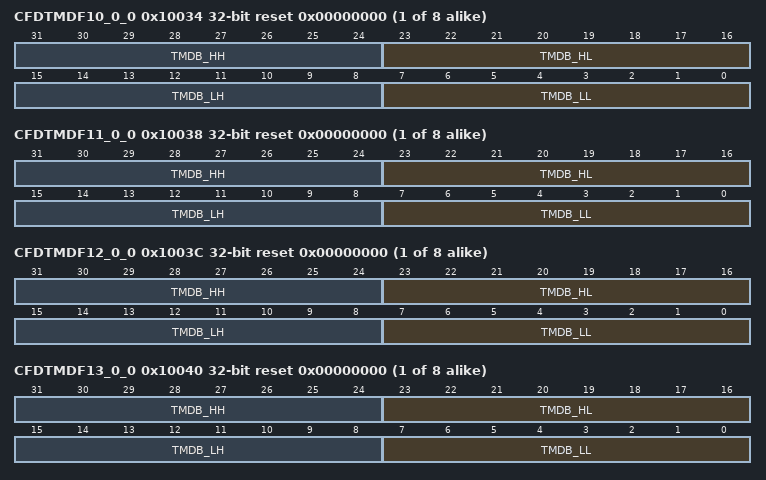
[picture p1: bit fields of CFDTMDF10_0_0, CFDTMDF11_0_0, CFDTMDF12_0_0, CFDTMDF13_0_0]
                    <name>CFDTMDF10_%s_0</name>
                    <description>TX Message Buffer Data Field 10 Register %s Channel 0</description>
                    <addressOffset>0x10034</addressOffset>
                    <size>32</size>
                    <access>read-write</access>
                    <resetValue>0x00000000</resetValue>
                    <resetMask>0xffffffff</resetMask>
                    <fields>
                        <field>
                            <name>TMDB_LL</name>
                            <description>TX Message Buffer Data Byte 40</description>
                            <lsb>0</lsb>
                            <msb>7</msb>
                            <access>read-write</access>
                        </field>
                        <field>
                            <name>TMDB_LH</name>
                            <description>TX Message Buffer Data Byte 41</description>
                            <lsb>8</lsb>
                            <msb>15</msb>
                            <access>read-write</access>
                        </field>
                        <field>
                            <name>TMDB_HL</name>
                            <description>TX Message Buffer Data Byte 42</description>
                            <lsb>16</lsb>
                            <msb>23</msb>
                            <access>read-write</access>
                        </field>
                        <field>
                            <name>TMDB_HH</name>
                            <description>TX Message Buffer Data Byte 43</description>
                            <lsb>24</lsb>
                            <msb>31</msb>
                            <access>read-write</access>
                        </field>
                    </fields>
                </register>
                <register>
                    <dim>8</dim>
                    <dimIncrement>0x080</dimIncrement>
                    <dimIndex>0-7</dimIndex>
                    <name>CFDTMDF11_%s_0</name>
                    <description>TX Message Buffer Data Field 11 Register %s Channel 0</description>
                    <addressOffset>0x10038</addressOffset>
                    <size>32</size>
                    <access>read-write</access>
                    <resetValue>0x00000000</resetValue>
                    <resetMask>0xffffffff</resetMask>
                    <fields>
                        <field>
                            <name>TMDB_LL</name>
                            <description>TX Message Buffer Data Byte 44</description>
                            <lsb>0</lsb>
                            <msb>7</msb>
                            <access>read-write</access>
                        </field>
                        <field>
                            <name>TMDB_LH</name>
                            <description>TX Message Buffer Data Byte 45</description>
                            <lsb>8</lsb>
                            <msb>15</msb>
                            <access>read-write</access>
                        </field>
                        <field>
                            <name>TMDB_HL</name>
                            <description>TX Message Buffer Data Byte 46</description>
                            <lsb>16</lsb>
                            <msb>23</msb>
                            <access>read-write</access>
                        </field>
                        <field>
                            <name>TMDB_HH</name>
                            <description>TX Message Buffer Data Byte 47</description>
                            <lsb>24</lsb>
                            <msb>31</msb>
                            <access>read-write</access>
                        </field>
                    </fields>
                </register>
                <register>
                    <dim>8</dim>
                    <dimIncrement>0x080</dimIncrement>
                    <dimIndex>0-7</dimIndex>
                    <name>CFDTMDF12_%s_0</name>
                    <description>TX Message Buffer Data Field 12 Register %s Channel 0</description>
                    <addressOffset>0x1003C</addressOffset>
                    <size>32</size>
                    <access>read-write</access>
                    <resetValue>0x00000000</resetValue>
                    <resetMask>0xffffffff</resetMask>
                    <fields>
                        <field>
                            <name>TMDB_LL</name>
                            <description>TX Message Buffer Data Byte 48</description>
                            <lsb>0</lsb>
                            <msb>7</msb>
                            <access>read-write</access>
                        </field>
                        <field>
                            <name>TMDB_LH</name>
                            <description>TX Message Buffer Data Byte 49</description>
                            <lsb>8</lsb>
                            <msb>15</msb>
                            <access>read-write</access>
                        </field>
                        <field>
                            <name>TMDB_HL</name>
                            <description>TX Message Buffer Data Byte 50</description>
                            <lsb>16</lsb>
                            <msb>23</msb>
                            <access>read-write</access>
                        </field>
                        <field>
                            <name>TMDB_HH</name>
                            <description>TX Message Buffer Data Byte 51</description>
                            <lsb>24</lsb>
                            <msb>31</msb>
                            <access>read-write</access>
                        </field>
                    </fields>
                </register>
                <register>
                    <dim>8</dim>
                    <dimIncrement>0x080</dimIncrement>
                    <dimIndex>0-7</dimIndex>
                    <name>CFDTMDF13_%s_0</name>
                    <description>TX Message Buffer Data Field 13 Register %s Channel 0</description>
                    <addressOffset>0x10040</addressOffset>
                    <size>32</size>
                    <access>read-write</access>
                    <resetValue>0x00000000</resetValue>
                    <resetMask>0xffffffff</resetMask>
                    <fields>
                        <field>
                            <name>TMDB_LL</name>
                            <description>TX Message Buffer Data Byte X</description>
                            <lsb>0</lsb>
                            <msb>7</msb>
                            <access>read-write</access>
                        </field>
                        <field>
                            <name>TMDB_LH</name>
                            <description>TX Message Buffer Data Byte X</description>
                            <lsb>8</lsb>
                            <msb>15</msb>
                            <access>read-write</access>
                        </field>
                        <field>
                            <name>TMDB_HL</name>
                            <description>TX Message Buffer Data Byte X</description>
                            <lsb>16</lsb>
                            <msb>23</msb>
                            <access>read-write</access>
                        </field>
                        <field>
                            <name>TMDB_HH</name>
                            <description>TX Message Buffer Data Byte X</description>
                            <lsb>24</lsb>
                            <msb>31</msb>
                            <access>read-write</access>
                        </field>
                    </fields>
                </register>
                <register>
                    <dim>8</dim>
                    <dimIncrement>0x080</dimIncrement>
                    <dimIndex>0-7</dimIndex>
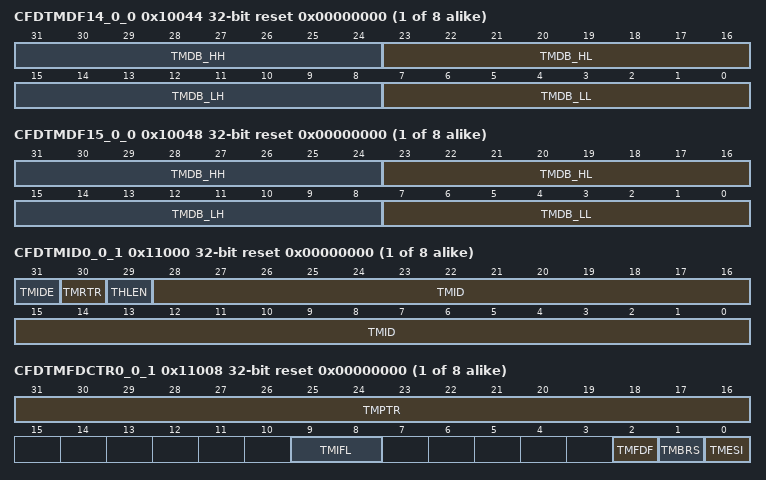
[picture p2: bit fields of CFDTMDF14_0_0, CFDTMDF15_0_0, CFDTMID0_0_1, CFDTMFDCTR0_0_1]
                    <name>CFDTMDF14_%s_0</name>
                    <description>TX Message Buffer Data Field 14 Register %s Channel 0</description>
                    <addressOffset>0x10044</addressOffset>
                    <size>32</size>
                    <access>read-write</access>
                    <resetValue>0x00000000</resetValue>
                    <resetMask>0xffffffff</resetMask>
                    <fields>
                        <field>
                            <name>TMDB_LL</name>
                            <description>TX Message Buffer Data Byte X</description>
                            <lsb>0</lsb>
                            <msb>7</msb>
                            <access>read-write</access>
                        </field>
                        <field>
                            <name>TMDB_LH</name>
                            <description>TX Message Buffer Data Byte X</description>
                            <lsb>8</lsb>
                            <msb>15</msb>
                            <access>read-write</access>
                        </field>
                        <field>
                            <name>TMDB_HL</name>
                            <description>TX Message Buffer Data Byte X</description>
                            <lsb>16</lsb>
                            <msb>23</msb>
                            <access>read-write</access>
                        </field>
                        <field>
                            <name>TMDB_HH</name>
                            <description>TX Message Buffer Data Byte X</description>
                            <lsb>24</lsb>
                            <msb>31</msb>
                            <access>read-write</access>
                        </field>
                    </fields>
                </register>
                <register>
                    <dim>8</dim>
                    <dimIncrement>0x080</dimIncrement>
                    <dimIndex>0-7</dimIndex>
                    <name>CFDTMDF15_%s_0</name>
                    <description>TX Message Buffer Data Field X Register 15 Channel 0</description>
                    <addressOffset>0x10048</addressOffset>
                    <size>32</size>
                    <access>read-write</access>
                    <resetValue>0x00000000</resetValue>
                    <resetMask>0xffffffff</resetMask>
                    <fields>
                        <field>
                            <name>TMDB_LL</name>
                            <description>TX Message Buffer Data Byte X</description>
                            <lsb>0</lsb>
                            <msb>7</msb>
                            <access>read-write</access>
                        </field>
                        <field>
                            <name>TMDB_LH</name>
                            <description>TX Message Buffer Data Byte X</description>
                            <lsb>8</lsb>
                            <msb>15</msb>
                            <access>read-write</access>
                        </field>
                        <field>
                            <name>TMDB_HL</name>
                            <description>TX Message Buffer Data Byte X</description>
                            <lsb>16</lsb>
                            <msb>23</msb>
                            <access>read-write</access>
                        </field>
                        <field>
                            <name>TMDB_HH</name>
                            <description>TX Message Buffer Data Byte X</description>
                            <lsb>24</lsb>
                            <msb>31</msb>
                            <access>read-write</access>
                        </field>
                    </fields>
                </register>
                <register>
                    <dim>8</dim>
                    <dimIncrement>0x080</dimIncrement>
                    <dimIndex>32-39</dimIndex>
                    <name>CFDTMID%s_0_1</name>
                    <description>TX Message Buffer ID Register %s Channel 0</description>
                    <addressOffset>0x11000</addressOffset>
                    <size>32</size>
                    <access>read-write</access>
                    <resetValue>0x00000000</resetValue>
                    <resetMask>0xffffffff</resetMask>
                    <fields>
                        <field>
                            <name>TMID</name>
                            <description>TX Message Buffer ID Field</description>
                            <lsb>0</lsb>
                            <msb>28</msb>
                            <access>read-write</access>
                        </field>
                        <field>
                            <name>THLEN</name>
                            <description>Tx History List Entry</description>
                            <lsb>29</lsb>
                            <msb>29</msb>
                            <access>read-write</access>
                            <enumeratedValues>
                                </enumeratedValues>
                        </field>
                        <field>
                            <name>TMRTR</name>
                            <description>TX Message Buffer RTR bit</description>
                            <lsb>30</lsb>
                            <msb>30</msb>
                            <access>read-write</access>
                            <enumeratedValues>
                                </enumeratedValues>
                        </field>
                        <field>
                            <name>TMIDE</name>
                            <description>TX Message Buffer IDE bit</description>
                            <lsb>31</lsb>
                            <msb>31</msb>
                            <access>read-write</access>
                            <enumeratedValues>
                                </enumeratedValues>
                        </field>
                    </fields>
                </register>
                <register>
                    <dim>8</dim>
                    <dimIncrement>0x080</dimIncrement>
                    <dimIndex>32-39</dimIndex>
                    <name>CFDTMPTR%s_0_1</name>
                    <description>TX Message Buffer Pointer Register %s Channel 0</description>
                    <addressOffset>0x11004</addressOffset>
                    <size>32</size>
                    <access>read-write</access>
                    <resetValue>0x00000000</resetValue>
                    <resetMask>0xffffffff</resetMask>
                    <fields>
                        <field>
                            <name>TMDLC</name>
                            <description>TX Message Buffer DLC Field</description>
                            <lsb>28</lsb>
                            <msb>31</msb>
                            <access>read-write</access>
                        </field>
                    </fields>
                </register>
                <register>
                    <dim>8</dim>
                    <dimIncrement>0x080</dimIncrement>
                    <dimIndex>32-39</dimIndex>
                    <name>CFDTMFDCTR%s_0_1</name>
                    <description>TX Message Buffer CANFD Control Register %s Channel i</description>
                    <addressOffset>0x11008</addressOffset>
                    <size>32</size>
                    <access>read-write</access>
                    <resetValue>0x00000000</resetValue>
                    <resetMask>0xffffffff</resetMask>
                    <fields>
                        <field>
                            <name>TMESI</name>
                            <description>Error State Indicator bit</description>
                            <lsb>0</lsb>
                            <msb>0</msb>
                            <access>read-write</access>
                            <enumeratedValues>
                                </enumeratedValues>
                        </field>
                        <field>
                            <name>TMBRS</name>
                            <description>Bit Rate Switch bit</description>
                            <lsb>1</lsb>
                            <msb>1</msb>
                            <access>read-write</access>
                            <enumeratedValues>
                                </enumeratedValues>
                        </field>
                        <field>
                            <name>TMFDF</name>
                            <description>CAN FD Format bit</description>
                            <lsb>2</lsb>
                            <msb>2</msb>
                            <access>read-write</access>
                            <enumeratedValues>
                                </enumeratedValues>
                        </field>
                        <field>
                            <name>TMIFL</name>
                            <description>TX Message Buffer Information Label Field</description>
                            <lsb>8</lsb>
                            <msb>9</msb>
                            <access>read-write</access>
                        </field>
                        <field>
                            <name>TMPTR</name>
                            <description>TX Message Buffer Pointer Field</description>
                            <lsb>16</lsb>
                            <msb>31</msb>
                            <access>read-write</access>
                        </field>
                    </fields>
                </register>
                <register>
                    <dim>8</dim>
                    <dimIncrement>0x080</dimIncrement>
                    <dimIndex>32-39</dimIndex>
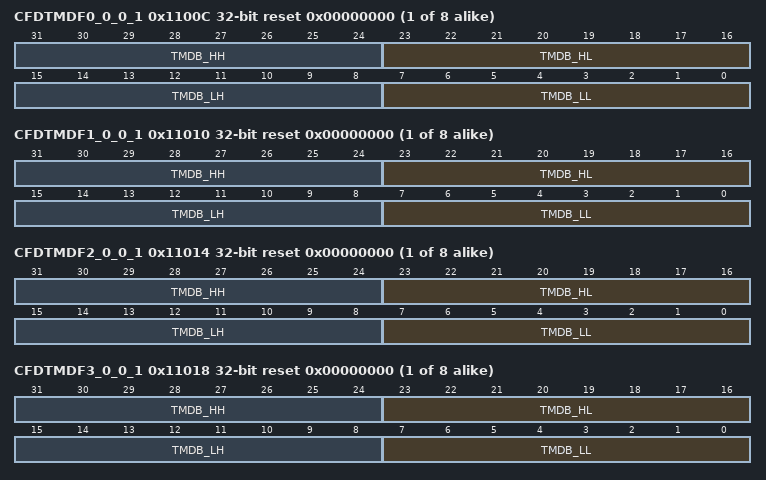
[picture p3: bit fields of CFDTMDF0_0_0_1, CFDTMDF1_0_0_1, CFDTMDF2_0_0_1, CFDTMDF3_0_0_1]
                    <name>CFDTMDF0_%s_0_1</name>
                    <description>TX Message Buffer Data Field 0 Register %s Channel 0</description>
                    <addressOffset>0x1100C</addressOffset>
                    <size>32</size>
                    <access>read-write</access>
                    <resetValue>0x00000000</resetValue>
                    <resetMask>0xffffffff</resetMask>
                    <fields>
                        <field>
                            <name>TMDB_LL</name>
                            <description>TX Message Buffer Data Byte 0</description>
                            <lsb>0</lsb>
                            <msb>7</msb>
                            <access>read-write</access>
                        </field>
                        <field>
                            <name>TMDB_LH</name>
                            <description>TX Message Buffer Data Byte 1</description>
                            <lsb>8</lsb>
                            <msb>15</msb>
                            <access>read-write</access>
                        </field>
                        <field>
                            <name>TMDB_HL</name>
                            <description>TX Message Buffer Data Byte 2</description>
                            <lsb>16</lsb>
                            <msb>23</msb>
                            <access>read-write</access>
                        </field>
                        <field>
                            <name>TMDB_HH</name>
                            <description>TX Message Buffer Data Byte 3</description>
                            <lsb>24</lsb>
                            <msb>31</msb>
                            <access>read-write</access>
                        </field>
                    </fields>
                </register>
                <register>
                    <dim>8</dim>
                    <dimIncrement>0x080</dimIncrement>
                    <dimIndex>32-39</dimIndex>
                    <name>CFDTMDF1_%s_0_1</name>
                    <description>TX Message Buffer Data Field 1 Register %s Channel 0</description>
                    <addressOffset>0x11010</addressOffset>
                    <size>32</size>
                    <access>read-write</access>
                    <resetValue>0x00000000</resetValue>
                    <resetMask>0xffffffff</resetMask>
                    <fields>
                        <field>
                            <name>TMDB_LL</name>
                            <description>TX Message Buffer Data Byte 4</description>
                            <lsb>0</lsb>
                            <msb>7</msb>
                            <access>read-write</access>
                        </field>
                        <field>
                            <name>TMDB_LH</name>
                            <description>TX Message Buffer Data Byte 5</description>
                            <lsb>8</lsb>
                            <msb>15</msb>
                            <access>read-write</access>
                        </field>
                        <field>
                            <name>TMDB_HL</name>
                            <description>TX Message Buffer Data Byte 6</description>
                            <lsb>16</lsb>
                            <msb>23</msb>
                            <access>read-write</access>
                        </field>
                        <field>
                            <name>TMDB_HH</name>
                            <description>TX Message Buffer Data Byte 7</description>
                            <lsb>24</lsb>
                            <msb>31</msb>
                            <access>read-write</access>
                        </field>
                    </fields>
                </register>
                <register>
                    <dim>8</dim>
                    <dimIncrement>0x080</dimIncrement>
                    <dimIndex>32-39</dimIndex>
                    <name>CFDTMDF2_%s_0_1</name>
                    <description>TX Message Buffer Data Field 2 Register %s Channel 0</description>
                    <addressOffset>0x11014</addressOffset>
                    <size>32</size>
                    <access>read-write</access>
                    <resetValue>0x00000000</resetValue>
                    <resetMask>0xffffffff</resetMask>
                    <fields>
                        <field>
                            <name>TMDB_LL</name>
                            <description>TX Message Buffer Data Byte 8</description>
                            <lsb>0</lsb>
                            <msb>7</msb>
                            <access>read-write</access>
                        </field>
                        <field>
                            <name>TMDB_LH</name>
                            <description>TX Message Buffer Data Byte 9</description>
                            <lsb>8</lsb>
                            <msb>15</msb>
                            <access>read-write</access>
                        </field>
                        <field>
                            <name>TMDB_HL</name>
                            <description>TX Message Buffer Data Byte 10</description>
                            <lsb>16</lsb>
                            <msb>23</msb>
                            <access>read-write</access>
                        </field>
                        <field>
                            <name>TMDB_HH</name>
                            <description>TX Message Buffer Data Byte 11</description>
                            <lsb>24</lsb>
                            <msb>31</msb>
                            <access>read-write</access>
                        </field>
                    </fields>
                </register>
                <register>
                    <dim>8</dim>
                    <dimIncrement>0x080</dimIncrement>
                    <dimIndex>32-39</dimIndex>
                    <name>CFDTMDF3_%s_0_1</name>
                    <description>TX Message Buffer Data Field 3 Register %s Channel 0</description>
                    <addressOffset>0x11018</addressOffset>
                    <size>32</size>
                    <access>read-write</access>
                    <resetValue>0x00000000</resetValue>
                    <resetMask>0xffffffff</resetMask>
                    <fields>
                        <field>
                            <name>TMDB_LL</name>
                            <description>TX Message Buffer Data Byte 12</description>
                            <lsb>0</lsb>
                            <msb>7</msb>
                            <access>read-write</access>
                        </field>
                        <field>
                            <name>TMDB_LH</name>
                            <description>TX Message Buffer Data Byte 12</description>
                            <lsb>8</lsb>
                            <msb>15</msb>
                            <access>read-write</access>
                        </field>
                        <field>
                            <name>TMDB_HL</name>
                            <description>TX Message Buffer Data Byte 12</description>
                            <lsb>16</lsb>
                            <msb>23</msb>
                            <access>read-write</access>
                        </field>
                        <field>
                            <name>TMDB_HH</name>
                            <description>TX Message Buffer Data Byte 12</description>
                            <lsb>24</lsb>
                            <msb>31</msb>
                            <access>read-write</access>
                        </field>
                    </fields>
                </register>
                <register>
                    <dim>8</dim>
                    <dimIncrement>0x080</dimIncrement>
                    <dimIndex>32-39</dimIndex>
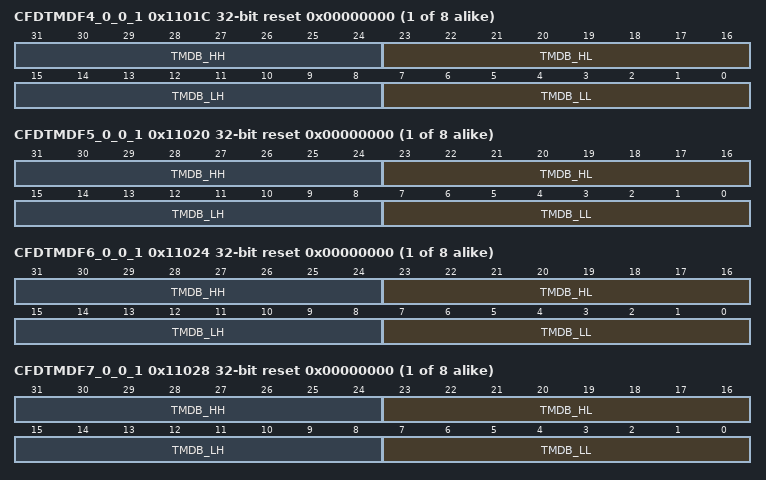
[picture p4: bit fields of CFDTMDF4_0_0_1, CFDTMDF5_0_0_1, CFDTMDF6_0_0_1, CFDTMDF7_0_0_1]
                    <name>CFDTMDF4_%s_0_1</name>
                    <description>TX Message Buffer Data Field 4 Register %s Channel 0</description>
                    <addressOffset>0x1101C</addressOffset>
                    <size>32</size>
                    <access>read-write</access>
                    <resetValue>0x00000000</resetValue>
                    <resetMask>0xffffffff</resetMask>
                    <fields>
                        <field>
                            <name>TMDB_LL</name>
                            <description>TX Message Buffer Data Byte 16</description>
                            <lsb>0</lsb>
                            <msb>7</msb>
                            <access>read-write</access>
                        </field>
                        <field>
                            <name>TMDB_LH</name>
                            <description>TX Message Buffer Data Byte 17</description>
                            <lsb>8</lsb>
                            <msb>15</msb>
                            <access>read-write</access>
                        </field>
                        <field>
                            <name>TMDB_HL</name>
                            <description>TX Message Buffer Data Byte 18</description>
                            <lsb>16</lsb>
                            <msb>23</msb>
                            <access>read-write</access>
                        </field>
                        <field>
                            <name>TMDB_HH</name>
                            <description>TX Message Buffer Data Byte 19</description>
                            <lsb>24</lsb>
                            <msb>31</msb>
                            <access>read-write</access>
                        </field>
                    </fields>
                </register>
                <register>
                    <dim>8</dim>
                    <dimIncrement>0x080</dimIncrement>
                    <dimIndex>32-39</dimIndex>
                    <name>CFDTMDF5_%s_0_1</name>
                    <description>TX Message Buffer Data Field 5 Register %s Channel 0</description>
                    <addressOffset>0x11020</addressOffset>
                    <size>32</size>
                    <access>read-write</access>
                    <resetValue>0x00000000</resetValue>
                    <resetMask>0xffffffff</resetMask>
                    <fields>
                        <field>
                            <name>TMDB_LL</name>
                            <description>TX Message Buffer Data Byte 20</description>
                            <lsb>0</lsb>
                            <msb>7</msb>
                            <access>read-write</access>
                        </field>
                        <field>
                            <name>TMDB_LH</name>
                            <description>TX Message Buffer Data Byte 21</description>
                            <lsb>8</lsb>
                            <msb>15</msb>
                            <access>read-write</access>
                        </field>
                        <field>
                            <name>TMDB_HL</name>
                            <description>TX Message Buffer Data Byte 22</description>
                            <lsb>16</lsb>
                            <msb>23</msb>
                            <access>read-write</access>
                        </field>
                        <field>
                            <name>TMDB_HH</name>
                            <description>TX Message Buffer Data Byte 23</description>
                            <lsb>24</lsb>
                            <msb>31</msb>
                            <access>read-write</access>
                        </field>
                    </fields>
                </register>
                <register>
                    <dim>8</dim>
                    <dimIncrement>0x080</dimIncrement>
                    <dimIndex>32-39</dimIndex>
                    <name>CFDTMDF6_%s_0_1</name>
                    <description>TX Message Buffer Data Field 6 Register %s Channel 0</description>
                    <addressOffset>0x11024</addressOffset>
                    <size>32</size>
                    <access>read-write</access>
                    <resetValue>0x00000000</resetValue>
                    <resetMask>0xffffffff</resetMask>
                    <fields>
                        <field>
                            <name>TMDB_LL</name>
                            <description>TX Message Buffer Data Byte 24</description>
                            <lsb>0</lsb>
                            <msb>7</msb>
                            <access>read-write</access>
                        </field>
                        <field>
                            <name>TMDB_LH</name>
                            <description>TX Message Buffer Data Byte 25</description>
                            <lsb>8</lsb>
                            <msb>15</msb>
                            <access>read-write</access>
                        </field>
                        <field>
                            <name>TMDB_HL</name>
                            <description>TX Message Buffer Data Byte 26</description>
                            <lsb>16</lsb>
                            <msb>23</msb>
                            <access>read-write</access>
                        </field>
                        <field>
                            <name>TMDB_HH</name>
                            <description>TX Message Buffer Data Byte 27</description>
                            <lsb>24</lsb>
                            <msb>31</msb>
                            <access>read-write</access>
                        </field>
                    </fields>
                </register>
                <register>
                    <dim>8</dim>
                    <dimIncrement>0x080</dimIncrement>
                    <dimIndex>32-39</dimIndex>
                    <name>CFDTMDF7_%s_0_1</name>
                    <description>TX Message Buffer Data Field 7 Register %s Channel 0</description>
                    <addressOffset>0x11028</addressOffset>
                    <size>32</size>
                    <access>read-write</access>
                    <resetValue>0x00000000</resetValue>
                    <resetMask>0xffffffff</resetMask>
                    <fields>
                        <field>
                            <name>TMDB_LL</name>
                            <description>TX Message Buffer Data Byte 28</description>
                            <lsb>0</lsb>
                            <msb>7</msb>
                            <access>read-write</access>
                        </field>
                        <field>
                            <name>TMDB_LH</name>
                            <description>TX Message Buffer Data Byte29</description>
                            <lsb>8</lsb>
                            <msb>15</msb>
                            <access>read-write</access>
                        </field>
                        <field>
                            <name>TMDB_HL</name>
                            <description>TX Message Buffer Data Byte 30</description>
                            <lsb>16</lsb>
                            <msb>23</msb>
                            <access>read-write</access>
                        </field>
                        <field>
                            <name>TMDB_HH</name>
                            <description>TX Message Buffer Data Byte 31</description>
                            <lsb>24</lsb>
                            <msb>31</msb>
                            <access>read-write</access>
                        </field>
                    </fields>
                </register>
                <register>
                    <dim>8</dim>
                    <dimIncrement>0x080</dimIncrement>
                    <dimIndex>32-39</dimIndex>
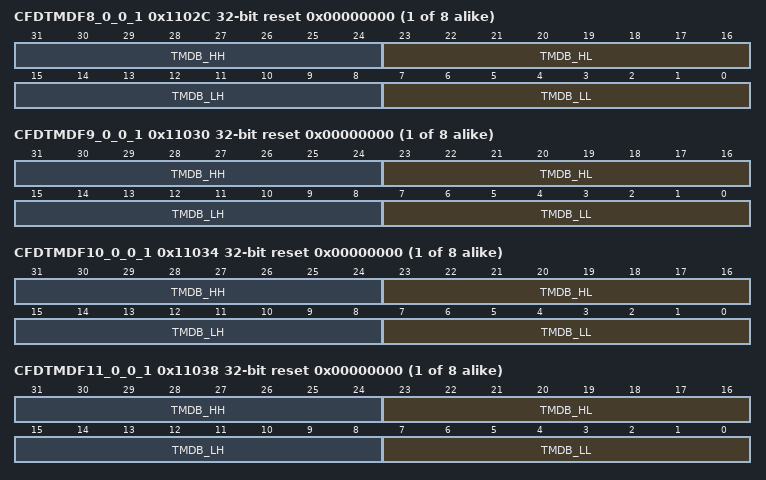
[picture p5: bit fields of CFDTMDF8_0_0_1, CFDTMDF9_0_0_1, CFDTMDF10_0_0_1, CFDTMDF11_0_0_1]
                    <name>CFDTMDF8_%s_0_1</name>
                    <description>TX Message Buffer Data Field 8 Register %s Channel 0</description>
                    <addressOffset>0x1102C</addressOffset>
                    <size>32</size>
                    <access>read-write</access>
                    <resetValue>0x00000000</resetValue>
                    <resetMask>0xffffffff</resetMask>
                    <fields>
                        <field>
                            <name>TMDB_LL</name>
                            <description>TX Message Buffer Data Byte 32</description>
                            <lsb>0</lsb>
                            <msb>7</msb>
                            <access>read-write</access>
                        </field>
                        <field>
                            <name>TMDB_LH</name>
                            <description>TX Message Buffer Data Byte 33</description>
                            <lsb>8</lsb>
                            <msb>15</msb>
                            <access>read-write</access>
                        </field>
                        <field>
                            <name>TMDB_HL</name>
                            <description>TX Message Buffer Data Byte 34</description>
                            <lsb>16</lsb>
                            <msb>23</msb>
                            <access>read-write</access>
                        </field>
                        <field>
                            <name>TMDB_HH</name>
                            <description>TX Message Buffer Data Byte 35</description>
                            <lsb>24</lsb>
                            <msb>31</msb>
                            <access>read-write</access>
                        </field>
                    </fields>
                </register>
                <register>
                    <dim>8</dim>
                    <dimIncrement>0x080</dimIncrement>
                    <dimIndex>32-39</dimIndex>
                    <name>CFDTMDF9_%s_0_1</name>
                    <description>TX Message Buffer Data Field 9 Register %s Channel 0</description>
                    <addressOffset>0x11030</addressOffset>
                    <size>32</size>
                    <access>read-write</access>
                    <resetValue>0x00000000</resetValue>
                    <resetMask>0xffffffff</resetMask>
                    <fields>
                        <field>
                            <name>TMDB_LL</name>
                            <description>TX Message Buffer Data Byte 36</description>
                            <lsb>0</lsb>
                            <msb>7</msb>
                            <access>read-write</access>
                        </field>
                        <field>
                            <name>TMDB_LH</name>
                            <description>TX Message Buffer Data Byte 37</description>
                            <lsb>8</lsb>
                            <msb>15</msb>
                            <access>read-write</access>
                        </field>
                        <field>
                            <name>TMDB_HL</name>
                            <description>TX Message Buffer Data Byte 38</description>
                            <lsb>16</lsb>
                            <msb>23</msb>
                            <access>read-write</access>
                        </field>
                        <field>
                            <name>TMDB_HH</name>
                            <description>TX Message Buffer Data Byte 39</description>
                            <lsb>24</lsb>
                            <msb>31</msb>
                            <access>read-write</access>
                        </field>
                    </fields>
                </register>
                <register>
                    <dim>8</dim>
                    <dimIncrement>0x080</dimIncrement>
                    <dimIndex>32-39</dimIndex>
                    <name>CFDTMDF10_%s_0_1</name>
                    <description>TX Message Buffer Data Field 10 Register %s Channel 0</description>
                    <addressOffset>0x11034</addressOffset>
                    <size>32</size>
                    <access>read-write</access>
                    <resetValue>0x00000000</resetValue>
                    <resetMask>0xffffffff</resetMask>
                    <fields>
                        <field>
                            <name>TMDB_LL</name>
                            <description>TX Message Buffer Data Byte 40</description>
                            <lsb>0</lsb>
                            <msb>7</msb>
                            <access>read-write</access>
                        </field>
                        <field>
                            <name>TMDB_LH</name>
                            <description>TX Message Buffer Data Byte 41</description>
                            <lsb>8</lsb>
                            <msb>15</msb>
                            <access>read-write</access>
                        </field>
                        <field>
                            <name>TMDB_HL</name>
                            <description>TX Message Buffer Data Byte 42</description>
                            <lsb>16</lsb>
                            <msb>23</msb>
                            <access>read-write</access>
                        </field>
                        <field>
                            <name>TMDB_HH</name>
                            <description>TX Message Buffer Data Byte 43</description>
                            <lsb>24</lsb>
                            <msb>31</msb>
                            <access>read-write</access>
                        </field>
                    </fields>
                </register>
                <register>
                    <dim>8</dim>
                    <dimIncrement>0x080</dimIncrement>
                    <dimIndex>32-39</dimIndex>
                    <name>CFDTMDF11_%s_0_1</name>
                    <description>TX Message Buffer Data Field 11 Register %s Channel 0</description>
                    <addressOffset>0x11038</addressOffset>
                    <size>32</size>
                    <access>read-write</access>
                    <resetValue>0x00000000</resetValue>
                    <resetMask>0xffffffff</resetMask>
                    <fields>
                        <field>
                            <name>TMDB_LL</name>
                            <description>TX Message Buffer Data Byte 44</description>
                            <lsb>0</lsb>
                            <msb>7</msb>
                            <access>read-write</access>
                        </field>
                        <field>
                            <name>TMDB_LH</name>
                            <description>TX Message Buffer Data Byte 45</description>
                            <lsb>8</lsb>
                            <msb>15</msb>
                            <access>read-write</access>
                        </field>
                        <field>
                            <name>TMDB_HL</name>
                            <description>TX Message Buffer Data Byte 46</description>
                            <lsb>16</lsb>
                            <msb>23</msb>
                            <access>read-write</access>
                        </field>
                        <field>
                            <name>TMDB_HH</name>
                            <description>TX Message Buffer Data Byte 47</description>
                            <lsb>24</lsb>
                            <msb>31</msb>
                            <access>read-write</access>
                        </field>
                    </fields>
                </register>
                <register>
                    <dim>8</dim>
                    <dimIncrement>0x080</dimIncrement>
                    <dimIndex>32-39</dimIndex>
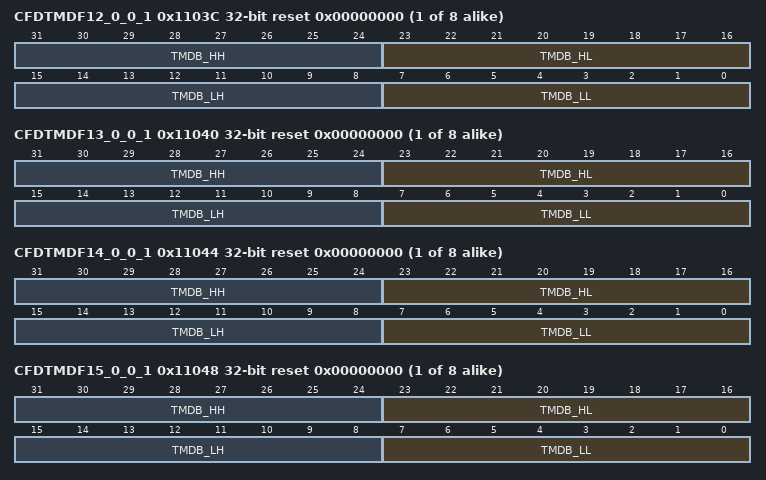
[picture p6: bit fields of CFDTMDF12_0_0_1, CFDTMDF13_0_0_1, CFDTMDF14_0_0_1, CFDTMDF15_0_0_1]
                    <name>CFDTMDF12_%s_0_1</name>
                    <description>TX Message Buffer Data Field 12 Register %s Channel 0</description>
                    <addressOffset>0x1103C</addressOffset>
                    <size>32</size>
                    <access>read-write</access>
                    <resetValue>0x00000000</resetValue>
                    <resetMask>0xffffffff</resetMask>
                    <fields>
                        <field>
                            <name>TMDB_LL</name>
                            <description>TX Message Buffer Data Byte 48</description>
                            <lsb>0</lsb>
                            <msb>7</msb>
                            <access>read-write</access>
                        </field>
                        <field>
                            <name>TMDB_LH</name>
                            <description>TX Message Buffer Data Byte 49</description>
                            <lsb>8</lsb>
                            <msb>15</msb>
                            <access>read-write</access>
                        </field>
                        <field>
                            <name>TMDB_HL</name>
                            <description>TX Message Buffer Data Byte 50</description>
                            <lsb>16</lsb>
                            <msb>23</msb>
                            <access>read-write</access>
                        </field>
                        <field>
                            <name>TMDB_HH</name>
                            <description>TX Message Buffer Data Byte 51</description>
                            <lsb>24</lsb>
                            <msb>31</msb>
                            <access>read-write</access>
                        </field>
                    </fields>
                </register>
                <register>
                    <dim>8</dim>
                    <dimIncrement>0x080</dimIncrement>
                    <dimIndex>32-39</dimIndex>
                    <name>CFDTMDF13_%s_0_1</name>
                    <description>TX Message Buffer Data Field 13 Register %s Channel 0</description>
                    <addressOffset>0x11040</addressOffset>
                    <size>32</size>
                    <access>read-write</access>
                    <resetValue>0x00000000</resetValue>
                    <resetMask>0xffffffff</resetMask>
                    <fields>
                        <field>
                            <name>TMDB_LL</name>
                            <description>TX Message Buffer Data Byte X</description>
                            <lsb>0</lsb>
                            <msb>7</msb>
                            <access>read-write</access>
                        </field>
                        <field>
                            <name>TMDB_LH</name>
                            <description>TX Message Buffer Data Byte X</description>
                            <lsb>8</lsb>
                            <msb>15</msb>
                            <access>read-write</access>
                        </field>
                        <field>
                            <name>TMDB_HL</name>
                            <description>TX Message Buffer Data Byte X</description>
                            <lsb>16</lsb>
                            <msb>23</msb>
                            <access>read-write</access>
                        </field>
                        <field>
                            <name>TMDB_HH</name>
                            <description>TX Message Buffer Data Byte X</description>
                            <lsb>24</lsb>
                            <msb>31</msb>
                            <access>read-write</access>
                        </field>
                    </fields>
                </register>
                <register>
                    <dim>8</dim>
                    <dimIncrement>0x080</dimIncrement>
                    <dimIndex>32-39</dimIndex>
                    <name>CFDTMDF14_%s_0_1</name>
                    <description>TX Message Buffer Data Field 14 Register %s Channel 0</description>
                    <addressOffset>0x11044</addressOffset>
                    <size>32</size>
                    <access>read-write</access>
                    <resetValue>0x00000000</resetValue>
                    <resetMask>0xffffffff</resetMask>
                    <fields>
                        <field>
                            <name>TMDB_LL</name>
                            <description>TX Message Buffer Data Byte X</description>
                            <lsb>0</lsb>
                            <msb>7</msb>
                            <access>read-write</access>
                        </field>
                        <field>
                            <name>TMDB_LH</name>
                            <description>TX Message Buffer Data Byte X</description>
                            <lsb>8</lsb>
                            <msb>15</msb>
                            <access>read-write</access>
                        </field>
                        <field>
                            <name>TMDB_HL</name>
                            <description>TX Message Buffer Data Byte X</description>
                            <lsb>16</lsb>
                            <msb>23</msb>
                            <access>read-write</access>
                        </field>
                        <field>
                            <name>TMDB_HH</name>
                            <description>TX Message Buffer Data Byte X</description>
                            <lsb>24</lsb>
                            <msb>31</msb>
                            <access>read-write</access>
                        </field>
                    </fields>
                </register>
                <register>
                    <dim>8</dim>
                    <dimIncrement>0x080</dimIncrement>
                    <dimIndex>32-39</dimIndex>
                    <name>CFDTMDF15_%s_0_1</name>
                    <description>TX Message Buffer Data Field X Register 15 Channel 0</description>
                    <addressOffset>0x11048</addressOffset>
                    <size>32</size>
                    <access>read-write</access>
                    <resetValue>0x00000000</resetValue>
                    <resetMask>0xffffffff</resetMask>
                    <fields>
                        <field>
                            <name>TMDB_LL</name>
                            <description>TX Message Buffer Data Byte X</description>
                            <lsb>0</lsb>
                            <msb>7</msb>
                            <access>read-write</access>
                        </field>
                        <field>
                            <name>TMDB_LH</name>
                            <description>TX Message Buffer Data Byte X</description>
                            <lsb>8</lsb>
                            <msb>15</msb>
                            <access>read-write</access>
                        </field>
                        <field>
                            <name>TMDB_HL</name>
                            <description>TX Message Buffer Data Byte X</description>
                            <lsb>16</lsb>
                            <msb>23</msb>
                            <access>read-write</access>
                        </field>
                        <field>
                            <name>TMDB_HH</name>
                            <description>TX Message Buffer Data Byte X</description>
                            <lsb>24</lsb>
                            <msb>31</msb>
                            <access>read-write</access>
                        </field>
                    </fields>
                </register>
                <register>
                    <dim>8</dim>
                    <dimIncrement>0x080</dimIncrement>
                    <dimIndex>0-7</dimIndex>
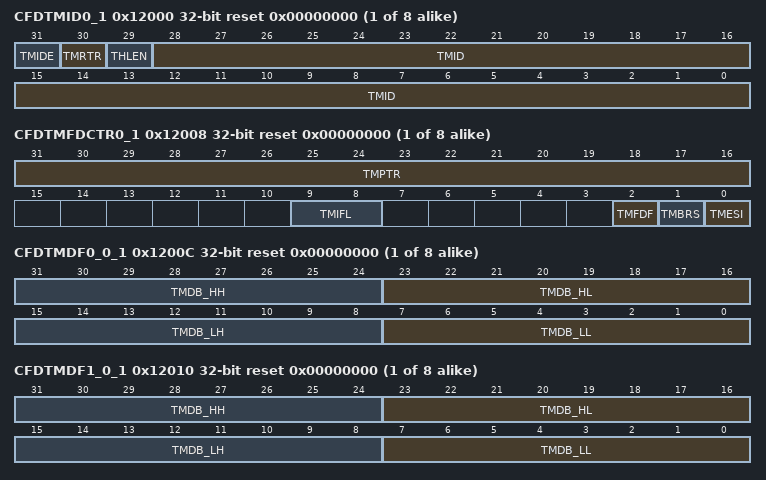
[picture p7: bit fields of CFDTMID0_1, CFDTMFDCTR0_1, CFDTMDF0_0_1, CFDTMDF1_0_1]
                    <name>CFDTMID%s_1</name>
                    <description>TX Message Buffer ID Register %s Channel 1</description>
                    <addressOffset>0x12000</addressOffset>
                    <size>32</size>
                    <access>read-write</access>
                    <resetValue>0x00000000</resetValue>
                    <resetMask>0xffffffff</resetMask>
                    <fields>
                        <field>
                            <name>TMID</name>
                            <description>TX Message Buffer ID Field</description>
                            <lsb>0</lsb>
                            <msb>28</msb>
                            <access>read-write</access>
                        </field>
                        <field>
                            <name>THLEN</name>
                            <description>Tx History List Entry</description>
                            <lsb>29</lsb>
                            <msb>29</msb>
                            <access>read-write</access>
                            <enumeratedValues>
                                </enumeratedValues>
                        </field>
                        <field>
                            <name>TMRTR</name>
                            <description>TX Message Buffer RTR bit</description>
                            <lsb>30</lsb>
                            <msb>30</msb>
                            <access>read-write</access>
                            <enumeratedValues>
                                </enumeratedValues>
                        </field>
                        <field>
                            <name>TMIDE</name>
                            <description>TX Message Buffer IDE bit</description>
                            <lsb>31</lsb>
                            <msb>31</msb>
                            <access>read-write</access>
                            <enumeratedValues>
                                </enumeratedValues>
                        </field>
                    </fields>
                </register>
                <register>
                    <dim>8</dim>
                    <dimIncrement>0x080</dimIncrement>
                    <dimIndex>0-7</dimIndex>
                    <name>CFDTMPTR%s_1</name>
                    <description>TX Message Buffer Pointer Register %s Channel 1</description>
                    <addressOffset>0x12004</addressOffset>
                    <size>32</size>
                    <access>read-write</access>
                    <resetValue>0x00000000</resetValue>
                    <resetMask>0xffffffff</resetMask>
                    <fields>
                        <field>
                            <name>TMDLC</name>
                            <description>TX Message Buffer DLC Field</description>
                            <lsb>28</lsb>
                            <msb>31</msb>
                            <access>read-write</access>
                        </field>
                    </fields>
                </register>
                <register>
                    <dim>8</dim>
                    <dimIncrement>0x080</dimIncrement>
                    <dimIndex>0-7</dimIndex>
                    <name>CFDTMFDCTR%s_1</name>
                    <description>TX Message Buffer CANFD Control Register %s Channel i</description>
                    <addressOffset>0x12008</addressOffset>
                    <size>32</size>
                    <access>read-write</access>
                    <resetValue>0x00000000</resetValue>
                    <resetMask>0xffffffff</resetMask>
                    <fields>
                        <field>
                            <name>TMESI</name>
                            <description>Error State Indicator bit</description>
                            <lsb>0</lsb>
                            <msb>0</msb>
                            <access>read-write</access>
                            <enumeratedValues>
                                </enumeratedValues>
                        </field>
                        <field>
                            <name>TMBRS</name>
                            <description>Bit Rate Switch bit</description>
                            <lsb>1</lsb>
                            <msb>1</msb>
                            <access>read-write</access>
                            <enumeratedValues>
                                </enumeratedValues>
                        </field>
                        <field>
                            <name>TMFDF</name>
                            <description>CAN FD Format bit</description>
                            <lsb>2</lsb>
                            <msb>2</msb>
                            <access>read-write</access>
                            <enumeratedValues>
                                </enumeratedValues>
                        </field>
                        <field>
                            <name>TMIFL</name>
                            <description>TX Message Buffer Information Label Field</description>
                            <lsb>8</lsb>
                            <msb>9</msb>
                            <access>read-write</access>
                        </field>
                        <field>
                            <name>TMPTR</name>
                            <description>TX Message Buffer Pointer Field</description>
                            <lsb>16</lsb>
                            <msb>31</msb>
                            <access>read-write</access>
                        </field>
                    </fields>
                </register>
                <register>
                    <dim>8</dim>
                    <dimIncrement>0x080</dimIncrement>
                    <dimIndex>0-7</dimIndex>
                    <name>CFDTMDF0_%s_1</name>
                    <description>TX Message Buffer Data Field 0 Register %s Channel 1</description>
                    <addressOffset>0x1200C</addressOffset>
                    <size>32</size>
                    <access>read-write</access>
                    <resetValue>0x00000000</resetValue>
                    <resetMask>0xffffffff</resetMask>
                    <fields>
                        <field>
                            <name>TMDB_LL</name>
                            <description>TX Message Buffer Data Byte 0</description>
                            <lsb>0</lsb>
                            <msb>7</msb>
                            <access>read-write</access>
                        </field>
                        <field>
                            <name>TMDB_LH</name>
                            <description>TX Message Buffer Data Byte 1</description>
                            <lsb>8</lsb>
                            <msb>15</msb>
                            <access>read-write</access>
                        </field>
                        <field>
                            <name>TMDB_HL</name>
                            <description>TX Message Buffer Data Byte 2</description>
                            <lsb>16</lsb>
                            <msb>23</msb>
                            <access>read-write</access>
                        </field>
                        <field>
                            <name>TMDB_HH</name>
                            <description>TX Message Buffer Data Byte 3</description>
                            <lsb>24</lsb>
                            <msb>31</msb>
                            <access>read-write</access>
                        </field>
                    </fields>
                </register>
                <register>
                    <dim>8</dim>
                    <dimIncrement>0x080</dimIncrement>
                    <dimIndex>0-7</dimIndex>
                    <name>CFDTMDF1_%s_1</name>
                    <description>TX Message Buffer Data Field 1 Register %s Channel 1</description>
                    <addressOffset>0x12010</addressOffset>
                    <size>32</size>
                    <access>read-write</access>
                    <resetValue>0x00000000</resetValue>
                    <resetMask>0xffffffff</resetMask>
                    <fields>
                        <field>
                            <name>TMDB_LL</name>
                            <description>TX Message Buffer Data Byte 4</description>
                            <lsb>0</lsb>
                            <msb>7</msb>
                            <access>read-write</access>
                        </field>
                        <field>
                            <name>TMDB_LH</name>
                            <description>TX Message Buffer Data Byte 5</description>
                            <lsb>8</lsb>
                            <msb>15</msb>
                            <access>read-write</access>
                        </field>
                        <field>
                            <name>TMDB_HL</name>
                            <description>TX Message Buffer Data Byte 6</description>
                            <lsb>16</lsb>
                            <msb>23</msb>
                            <access>read-write</access>
                        </field>
                        <field>
                            <name>TMDB_HH</name>
                            <description>TX Message Buffer Data Byte 7</description>
                            <lsb>24</lsb>
                            <msb>31</msb>
                            <access>read-write</access>
                        </field>
                    </fields>
                </register>
                <register>
                    <dim>8</dim>
                    <dimIncrement>0x080</dimIncrement>
                    <dimIndex>0-7</dimIndex>
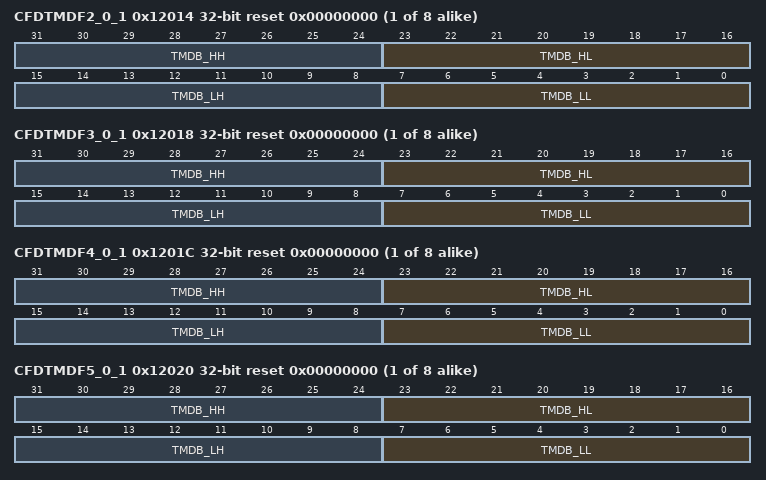
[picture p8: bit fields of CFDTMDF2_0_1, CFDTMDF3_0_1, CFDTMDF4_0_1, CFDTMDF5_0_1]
                    <name>CFDTMDF2_%s_1</name>
                    <description>TX Message Buffer Data Field 2 Register %s Channel 1</description>
                    <addressOffset>0x12014</addressOffset>
                    <size>32</size>
                    <access>read-write</access>
                    <resetValue>0x00000000</resetValue>
                    <resetMask>0xffffffff</resetMask>
                    <fields>
                        <field>
                            <name>TMDB_LL</name>
                            <description>TX Message Buffer Data Byte 8</description>
                            <lsb>0</lsb>
                            <msb>7</msb>
                            <access>read-write</access>
                        </field>
                        <field>
                            <name>TMDB_LH</name>
                            <description>TX Message Buffer Data Byte 9</description>
                            <lsb>8</lsb>
                            <msb>15</msb>
                            <access>read-write</access>
                        </field>
                        <field>
                            <name>TMDB_HL</name>
                            <description>TX Message Buffer Data Byte 10</description>
                            <lsb>16</lsb>
                            <msb>23</msb>
                            <access>read-write</access>
                        </field>
                        <field>
                            <name>TMDB_HH</name>
                            <description>TX Message Buffer Data Byte 11</description>
                            <lsb>24</lsb>
                            <msb>31</msb>
                            <access>read-write</access>
                        </field>
                    </fields>
                </register>
                <register>
                    <dim>8</dim>
                    <dimIncrement>0x080</dimIncrement>
                    <dimIndex>0-7</dimIndex>
                    <name>CFDTMDF3_%s_1</name>
                    <description>TX Message Buffer Data Field 3 Register %s Channel 1</description>
                    <addressOffset>0x12018</addressOffset>
                    <size>32</size>
                    <access>read-write</access>
                    <resetValue>0x00000000</resetValue>
                    <resetMask>0xffffffff</resetMask>
                    <fields>
                        <field>
                            <name>TMDB_LL</name>
                            <description>TX Message Buffer Data Byte 12</description>
                            <lsb>0</lsb>
                            <msb>7</msb>
                            <access>read-write</access>
                        </field>
                        <field>
                            <name>TMDB_LH</name>
                            <description>TX Message Buffer Data Byte 12</description>
                            <lsb>8</lsb>
                            <msb>15</msb>
                            <access>read-write</access>
                        </field>
                        <field>
                            <name>TMDB_HL</name>
                            <description>TX Message Buffer Data Byte 12</description>
                            <lsb>16</lsb>
                            <msb>23</msb>
                            <access>read-write</access>
                        </field>
                        <field>
                            <name>TMDB_HH</name>
                            <description>TX Message Buffer Data Byte 12</description>
                            <lsb>24</lsb>
                            <msb>31</msb>
                            <access>read-write</access>
                        </field>
                    </fields>
                </register>
                <register>
                    <dim>8</dim>
                    <dimIncrement>0x080</dimIncrement>
                    <dimIndex>0-7</dimIndex>
                    <name>CFDTMDF4_%s_1</name>
                    <description>TX Message Buffer Data Field 4 Register %s Channel 1</description>
                    <addressOffset>0x1201C</addressOffset>
                    <size>32</size>
                    <access>read-write</access>
                    <resetValue>0x00000000</resetValue>
                    <resetMask>0xffffffff</resetMask>
                    <fields>
                        <field>
                            <name>TMDB_LL</name>
                            <description>TX Message Buffer Data Byte 16</description>
                            <lsb>0</lsb>
                            <msb>7</msb>
                            <access>read-write</access>
                        </field>
                        <field>
                            <name>TMDB_LH</name>
                            <description>TX Message Buffer Data Byte 17</description>
                            <lsb>8</lsb>
                            <msb>15</msb>
                            <access>read-write</access>
                        </field>
                        <field>
                            <name>TMDB_HL</name>
                            <description>TX Message Buffer Data Byte 18</description>
                            <lsb>16</lsb>
                            <msb>23</msb>
                            <access>read-write</access>
                        </field>
                        <field>
                            <name>TMDB_HH</name>
                            <description>TX Message Buffer Data Byte 19</description>
                            <lsb>24</lsb>
                            <msb>31</msb>
                            <access>read-write</access>
                        </field>
                    </fields>
                </register>
                <register>
                    <dim>8</dim>
                    <dimIncrement>0x080</dimIncrement>
                    <dimIndex>0-7</dimIndex>
                    <name>CFDTMDF5_%s_1</name>
                    <description>TX Message Buffer Data Field 5 Register %s Channel 1</description>
                    <addressOffset>0x12020</addressOffset>
                    <size>32</size>
                    <access>read-write</access>
                    <resetValue>0x00000000</resetValue>
                    <resetMask>0xffffffff</resetMask>
                    <fields>
                        <field>
                            <name>TMDB_LL</name>
                            <description>TX Message Buffer Data Byte 20</description>
                            <lsb>0</lsb>
                            <msb>7</msb>
                            <access>read-write</access>
                        </field>
                        <field>
                            <name>TMDB_LH</name>
                            <description>TX Message Buffer Data Byte 21</description>
                            <lsb>8</lsb>
                            <msb>15</msb>
                            <access>read-write</access>
                        </field>
                        <field>
                            <name>TMDB_HL</name>
                            <description>TX Message Buffer Data Byte 22</description>
                            <lsb>16</lsb>
                            <msb>23</msb>
                            <access>read-write</access>
                        </field>
                        <field>
                            <name>TMDB_HH</name>
                            <description>TX Message Buffer Data Byte 23</description>
                            <lsb>24</lsb>
                            <msb>31</msb>
                            <access>read-write</access>
                        </field>
                    </fields>
                </register>
                <register>
                    <dim>8</dim>
                    <dimIncrement>0x080</dimIncrement>
                    <dimIndex>0-7</dimIndex>
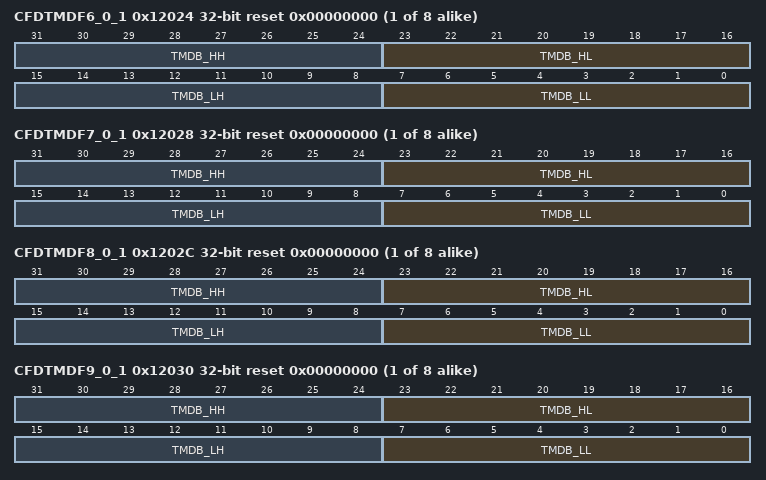
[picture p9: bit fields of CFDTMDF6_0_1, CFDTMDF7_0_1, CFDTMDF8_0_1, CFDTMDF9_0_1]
                    <name>CFDTMDF6_%s_1</name>
                    <description>TX Message Buffer Data Field 6 Register %s Channel 1</description>
                    <addressOffset>0x12024</addressOffset>
                    <size>32</size>
                    <access>read-write</access>
                    <resetValue>0x00000000</resetValue>
                    <resetMask>0xffffffff</resetMask>
                    <fields>
                        <field>
                            <name>TMDB_LL</name>
                            <description>TX Message Buffer Data Byte 24</description>
                            <lsb>0</lsb>
                            <msb>7</msb>
                            <access>read-write</access>
                        </field>
                        <field>
                            <name>TMDB_LH</name>
                            <description>TX Message Buffer Data Byte 25</description>
                            <lsb>8</lsb>
                            <msb>15</msb>
                            <access>read-write</access>
                        </field>
                        <field>
                            <name>TMDB_HL</name>
                            <description>TX Message Buffer Data Byte 26</description>
                            <lsb>16</lsb>
                            <msb>23</msb>
                            <access>read-write</access>
                        </field>
                        <field>
                            <name>TMDB_HH</name>
                            <description>TX Message Buffer Data Byte 27</description>
                            <lsb>24</lsb>
                            <msb>31</msb>
                            <access>read-write</access>
                        </field>
                    </fields>
                </register>
                <register>
                    <dim>8</dim>
                    <dimIncrement>0x080</dimIncrement>
                    <dimIndex>0-7</dimIndex>
                    <name>CFDTMDF7_%s_1</name>
                    <description>TX Message Buffer Data Field 7 Register %s Channel 1</description>
                    <addressOffset>0x12028</addressOffset>
                    <size>32</size>
                    <access>read-write</access>
                    <resetValue>0x00000000</resetValue>
                    <resetMask>0xffffffff</resetMask>
                    <fields>
                        <field>
                            <name>TMDB_LL</name>
                            <description>TX Message Buffer Data Byte 28</description>
                            <lsb>0</lsb>
                            <msb>7</msb>
                            <access>read-write</access>
                        </field>
                        <field>
                            <name>TMDB_LH</name>
                            <description>TX Message Buffer Data Byte29</description>
                            <lsb>8</lsb>
                            <msb>15</msb>
                            <access>read-write</access>
                        </field>
                        <field>
                            <name>TMDB_HL</name>
                            <description>TX Message Buffer Data Byte 30</description>
                            <lsb>16</lsb>
                            <msb>23</msb>
                            <access>read-write</access>
                        </field>
                        <field>
                            <name>TMDB_HH</name>
                            <description>TX Message Buffer Data Byte 31</description>
                            <lsb>24</lsb>
                            <msb>31</msb>
                            <access>read-write</access>
                        </field>
                    </fields>
                </register>
                <register>
                    <dim>8</dim>
                    <dimIncrement>0x080</dimIncrement>
                    <dimIndex>0-7</dimIndex>
                    <name>CFDTMDF8_%s_1</name>
                    <description>TX Message Buffer Data Field 8 Register %s Channel 1</description>
                    <addressOffset>0x1202C</addressOffset>
                    <size>32</size>
                    <access>read-write</access>
                    <resetValue>0x00000000</resetValue>
                    <resetMask>0xffffffff</resetMask>
                    <fields>
                        <field>
                            <name>TMDB_LL</name>
                            <description>TX Message Buffer Data Byte 32</description>
                            <lsb>0</lsb>
                            <msb>7</msb>
                            <access>read-write</access>
                        </field>
                        <field>
                            <name>TMDB_LH</name>
                            <description>TX Message Buffer Data Byte 33</description>
                            <lsb>8</lsb>
                            <msb>15</msb>
                            <access>read-write</access>
                        </field>
                        <field>
                            <name>TMDB_HL</name>
                            <description>TX Message Buffer Data Byte 34</description>
                            <lsb>16</lsb>
                            <msb>23</msb>
                            <access>read-write</access>
                        </field>
                        <field>
                            <name>TMDB_HH</name>
                            <description>TX Message Buffer Data Byte 35</description>
                            <lsb>24</lsb>
                            <msb>31</msb>
                            <access>read-write</access>
                        </field>
                    </fields>
                </register>
                <register>
                    <dim>8</dim>
                    <dimIncrement>0x080</dimIncrement>
                    <dimIndex>0-7</dimIndex>
                    <name>CFDTMDF9_%s_1</name>
                    <description>TX Message Buffer Data Field 9 Register %s Channel 1</description>
                    <addressOffset>0x12030</addressOffset>
                    <size>32</size>
                    <access>read-write</access>
                    <resetValue>0x00000000</resetValue>
                    <resetMask>0xffffffff</resetMask>
                    <fields>
                        <field>
                            <name>TMDB_LL</name>
                            <description>TX Message Buffer Data Byte 36</description>
                            <lsb>0</lsb>
                            <msb>7</msb>
                            <access>read-write</access>
                        </field>
                        <field>
                            <name>TMDB_LH</name>
                            <description>TX Message Buffer Data Byte 37</description>
                            <lsb>8</lsb>
                            <msb>15</msb>
                            <access>read-write</access>
                        </field>
                        <field>
                            <name>TMDB_HL</name>
                            <description>TX Message Buffer Data Byte 38</description>
                            <lsb>16</lsb>
                            <msb>23</msb>
                            <access>read-write</access>
                        </field>
                        <field>
                            <name>TMDB_HH</name>
                            <description>TX Message Buffer Data Byte 39</description>
                            <lsb>24</lsb>
                            <msb>31</msb>
                            <access>read-write</access>
                        </field>
                    </fields>
                </register>
                <register>
                    <dim>8</dim>
                    <dimIncrement>0x080</dimIncrement>
                    <dimIndex>0-7</dimIndex>
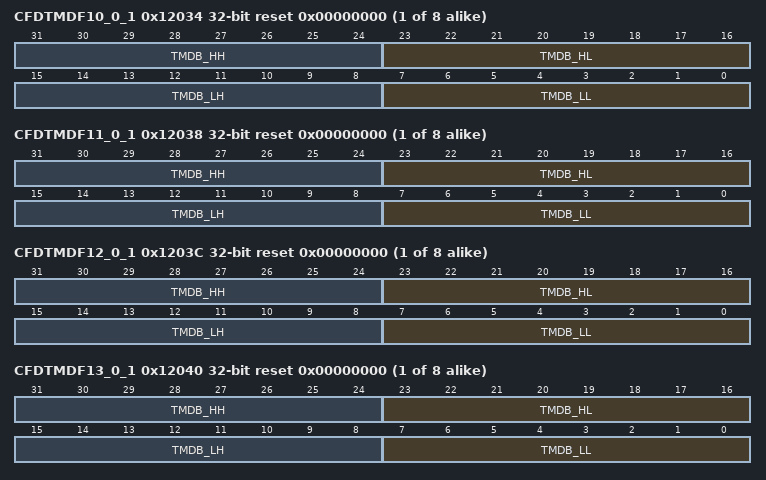
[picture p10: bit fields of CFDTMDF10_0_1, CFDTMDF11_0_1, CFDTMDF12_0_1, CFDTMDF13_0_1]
                    <name>CFDTMDF10_%s_1</name>
                    <description>TX Message Buffer Data Field 10 Register %s Channel 1</description>
                    <addressOffset>0x12034</addressOffset>
                    <size>32</size>
                    <access>read-write</access>
                    <resetValue>0x00000000</resetValue>
                    <resetMask>0xffffffff</resetMask>
                    <fields>
                        <field>
                            <name>TMDB_LL</name>
                            <description>TX Message Buffer Data Byte 40</description>
                            <lsb>0</lsb>
                            <msb>7</msb>
                            <access>read-write</access>
                        </field>
                        <field>
                            <name>TMDB_LH</name>
                            <description>TX Message Buffer Data Byte 41</description>
                            <lsb>8</lsb>
                            <msb>15</msb>
                            <access>read-write</access>
                        </field>
                        <field>
                            <name>TMDB_HL</name>
                            <description>TX Message Buffer Data Byte 42</description>
                            <lsb>16</lsb>
                            <msb>23</msb>
                            <access>read-write</access>
                        </field>
                        <field>
                            <name>TMDB_HH</name>
                            <description>TX Message Buffer Data Byte 43</description>
                            <lsb>24</lsb>
                            <msb>31</msb>
                            <access>read-write</access>
                        </field>
                    </fields>
                </register>
                <register>
                    <dim>8</dim>
                    <dimIncrement>0x080</dimIncrement>
                    <dimIndex>0-7</dimIndex>
                    <name>CFDTMDF11_%s_1</name>
                    <description>TX Message Buffer Data Field 11 Register %s Channel 1</description>
                    <addressOffset>0x12038</addressOffset>
                    <size>32</size>
                    <access>read-write</access>
                    <resetValue>0x00000000</resetValue>
                    <resetMask>0xffffffff</resetMask>
                    <fields>
                        <field>
                            <name>TMDB_LL</name>
                            <description>TX Message Buffer Data Byte 44</description>
                            <lsb>0</lsb>
                            <msb>7</msb>
                            <access>read-write</access>
                        </field>
                        <field>
                            <name>TMDB_LH</name>
                            <description>TX Message Buffer Data Byte 45</description>
                            <lsb>8</lsb>
                            <msb>15</msb>
                            <access>read-write</access>
                        </field>
                        <field>
                            <name>TMDB_HL</name>
                            <description>TX Message Buffer Data Byte 46</description>
                            <lsb>16</lsb>
                            <msb>23</msb>
                            <access>read-write</access>
                        </field>
                        <field>
                            <name>TMDB_HH</name>
                            <description>TX Message Buffer Data Byte 47</description>
                            <lsb>24</lsb>
                            <msb>31</msb>
                            <access>read-write</access>
                        </field>
                    </fields>
                </register>
                <register>
                    <dim>8</dim>
                    <dimIncrement>0x080</dimIncrement>
                    <dimIndex>0-7</dimIndex>
                    <name>CFDTMDF12_%s_1</name>
                    <description>TX Message Buffer Data Field 12 Register %s Channel 1</description>
                    <addressOffset>0x1203C</addressOffset>
                    <size>32</size>
                    <access>read-write</access>
                    <resetValue>0x00000000</resetValue>
                    <resetMask>0xffffffff</resetMask>
                    <fields>
                        <field>
                            <name>TMDB_LL</name>
                            <description>TX Message Buffer Data Byte 48</description>
                            <lsb>0</lsb>
                            <msb>7</msb>
                            <access>read-write</access>
                        </field>
                        <field>
                            <name>TMDB_LH</name>
                            <description>TX Message Buffer Data Byte 49</description>
                            <lsb>8</lsb>
                            <msb>15</msb>
                            <access>read-write</access>
                        </field>
                        <field>
                            <name>TMDB_HL</name>
                            <description>TX Message Buffer Data Byte 50</description>
                            <lsb>16</lsb>
                            <msb>23</msb>
                            <access>read-write</access>
                        </field>
                        <field>
                            <name>TMDB_HH</name>
                            <description>TX Message Buffer Data Byte 51</description>
                            <lsb>24</lsb>
                            <msb>31</msb>
                            <access>read-write</access>
                        </field>
                    </fields>
                </register>
                <register>
                    <dim>8</dim>
                    <dimIncrement>0x080</dimIncrement>
                    <dimIndex>0-7</dimIndex>
                    <name>CFDTMDF13_%s_1</name>
                    <description>TX Message Buffer Data Field 13 Register %s Channel 1</description>
                    <addressOffset>0x12040</addressOffset>
                    <size>32</size>
                    <access>read-write</access>
                    <resetValue>0x00000000</resetValue>
                    <resetMask>0xffffffff</resetMask>
                    <fields>
                        <field>
                            <name>TMDB_LL</name>
                            <description>TX Message Buffer Data Byte X</description>
                            <lsb>0</lsb>
                            <msb>7</msb>
                            <access>read-write</access>
                        </field>
                        <field>
                            <name>TMDB_LH</name>
                            <description>TX Message Buffer Data Byte X</description>
                            <lsb>8</lsb>
                            <msb>15</msb>
                            <access>read-write</access>
                        </field>
                        <field>
                            <name>TMDB_HL</name>
                            <description>TX Message Buffer Data Byte X</description>
                            <lsb>16</lsb>
                            <msb>23</msb>
                            <access>read-write</access>
                        </field>
                        <field>
                            <name>TMDB_HH</name>
                            <description>TX Message Buffer Data Byte X</description>
                            <lsb>24</lsb>
                            <msb>31</msb>
                            <access>read-write</access>
                        </field>
                    </fields>
                </register>
                <register>
                    <dim>8</dim>
                    <dimIncrement>0x080</dimIncrement>
                    <dimIndex>0-7</dimIndex>
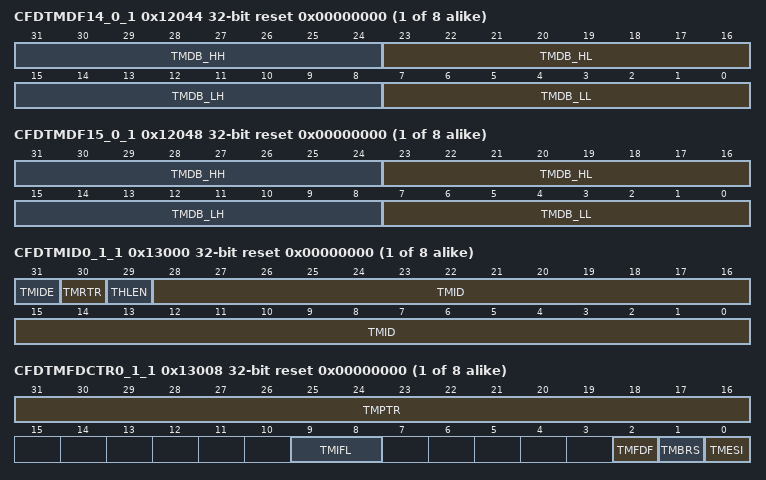
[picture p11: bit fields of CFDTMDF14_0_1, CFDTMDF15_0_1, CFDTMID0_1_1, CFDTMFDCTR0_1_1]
                    <name>CFDTMDF14_%s_1</name>
                    <description>TX Message Buffer Data Field 14 Register %s Channel 1</description>
                    <addressOffset>0x12044</addressOffset>
                    <size>32</size>
                    <access>read-write</access>
                    <resetValue>0x00000000</resetValue>
                    <resetMask>0xffffffff</resetMask>
                    <fields>
                        <field>
                            <name>TMDB_LL</name>
                            <description>TX Message Buffer Data Byte X</description>
                            <lsb>0</lsb>
                            <msb>7</msb>
                            <access>read-write</access>
                        </field>
                        <field>
                            <name>TMDB_LH</name>
                            <description>TX Message Buffer Data Byte X</description>
                            <lsb>8</lsb>
                            <msb>15</msb>
                            <access>read-write</access>
                        </field>
                        <field>
                            <name>TMDB_HL</name>
                            <description>TX Message Buffer Data Byte X</description>
                            <lsb>16</lsb>
                            <msb>23</msb>
                            <access>read-write</access>
                        </field>
                        <field>
                            <name>TMDB_HH</name>
                            <description>TX Message Buffer Data Byte X</description>
                            <lsb>24</lsb>
                            <msb>31</msb>
                            <access>read-write</access>
                        </field>
                    </fields>
                </register>
                <register>
                    <dim>8</dim>
                    <dimIncrement>0x080</dimIncrement>
                    <dimIndex>0-7</dimIndex>
                    <name>CFDTMDF15_%s_1</name>
                    <description>TX Message Buffer Data Field X Register 15 Channel 1</description>
                    <addressOffset>0x12048</addressOffset>
                    <size>32</size>
                    <access>read-write</access>
                    <resetValue>0x00000000</resetValue>
                    <resetMask>0xffffffff</resetMask>
                    <fields>
                        <field>
                            <name>TMDB_LL</name>
                            <description>TX Message Buffer Data Byte X</description>
                            <lsb>0</lsb>
                            <msb>7</msb>
                            <access>read-write</access>
                        </field>
                        <field>
                            <name>TMDB_LH</name>
                            <description>TX Message Buffer Data Byte X</description>
                            <lsb>8</lsb>
                            <msb>15</msb>
                            <access>read-write</access>
                        </field>
                        <field>
                            <name>TMDB_HL</name>
                            <description>TX Message Buffer Data Byte X</description>
                            <lsb>16</lsb>
                            <msb>23</msb>
                            <access>read-write</access>
                        </field>
                        <field>
                            <name>TMDB_HH</name>
                            <description>TX Message Buffer Data Byte X</description>
                            <lsb>24</lsb>
                            <msb>31</msb>
                            <access>read-write</access>
                        </field>
                    </fields>
                </register>
                <register>
                    <dim>8</dim>
                    <dimIncrement>0x080</dimIncrement>
                    <dimIndex>32-39</dimIndex>
                    <name>CFDTMID%s_1_1</name>
                    <description>TX Message Buffer ID Register %s Channel 1</description>
                    <addressOffset>0x13000</addressOffset>
                    <size>32</size>
                    <access>read-write</access>
                    <resetValue>0x00000000</resetValue>
                    <resetMask>0xffffffff</resetMask>
                    <fields>
                        <field>
                            <name>TMID</name>
                            <description>TX Message Buffer ID Field</description>
                            <lsb>0</lsb>
                            <msb>28</msb>
                            <access>read-write</access>
                        </field>
                        <field>
                            <name>THLEN</name>
                            <description>Tx History List Entry</description>
                            <lsb>29</lsb>
                            <msb>29</msb>
                            <access>read-write</access>
                            <enumeratedValues>
                                </enumeratedValues>
                        </field>
                        <field>
                            <name>TMRTR</name>
                            <description>TX Message Buffer RTR bit</description>
                            <lsb>30</lsb>
                            <msb>30</msb>
                            <access>read-write</access>
                            <enumeratedValues>
                                </enumeratedValues>
                        </field>
                        <field>
                            <name>TMIDE</name>
                            <description>TX Message Buffer IDE bit</description>
                            <lsb>31</lsb>
                            <msb>31</msb>
                            <access>read-write</access>
                            <enumeratedValues>
                                </enumeratedValues>
                        </field>
                    </fields>
                </register>
                <register>
                    <dim>8</dim>
                    <dimIncrement>0x080</dimIncrement>
                    <dimIndex>32-39</dimIndex>
                    <name>CFDTMPTR%s_1_1</name>
                    <description>TX Message Buffer Pointer Register %s Channel 1</description>
                    <addressOffset>0x13004</addressOffset>
                    <size>32</size>
                    <access>read-write</access>
                    <resetValue>0x00000000</resetValue>
                    <resetMask>0xffffffff</resetMask>
                    <fields>
                        <field>
                            <name>TMDLC</name>
                            <description>TX Message Buffer DLC Field</description>
                            <lsb>28</lsb>
                            <msb>31</msb>
                            <access>read-write</access>
                        </field>
                    </fields>
                </register>
                <register>
                    <dim>8</dim>
                    <dimIncrement>0x080</dimIncrement>
                    <dimIndex>32-39</dimIndex>
                    <name>CFDTMFDCTR%s_1_1</name>
                    <description>TX Message Buffer CANFD Control Register %s Channel i</description>
                    <addressOffset>0x13008</addressOffset>
                    <size>32</size>
                    <access>read-write</access>
                    <resetValue>0x00000000</resetValue>
                    <resetMask>0xffffffff</resetMask>
                    <fields>
                        <field>
                            <name>TMESI</name>
                            <description>Error State Indicator bit</description>
                            <lsb>0</lsb>
                            <msb>0</msb>
                            <access>read-write</access>
                            <enumeratedValues>
                                </enumeratedValues>
                        </field>
                        <field>
                            <name>TMBRS</name>
                            <description>Bit Rate Switch bit</description>
                            <lsb>1</lsb>
                            <msb>1</msb>
                            <access>read-write</access>
                            <enumeratedValues>
                                </enumeratedValues>
                        </field>
                        <field>
                            <name>TMFDF</name>
                            <description>CAN FD Format bit</description>
                            <lsb>2</lsb>
                            <msb>2</msb>
                            <access>read-write</access>
                            <enumeratedValues>
                                </enumeratedValues>
                        </field>
                        <field>
                            <name>TMIFL</name>
                            <description>TX Message Buffer Information Label Field</description>
                            <lsb>8</lsb>
                            <msb>9</msb>
                            <access>read-write</access>
                        </field>
                        <field>
                            <name>TMPTR</name>
                            <description>TX Message Buffer Pointer Field</description>
                            <lsb>16</lsb>
                            <msb>31</msb>
                            <access>read-write</access>
                        </field>
                    </fields>
                </register>
                <register>
                    <dim>8</dim>
                    <dimIncrement>0x080</dimIncrement>
                    <dimIndex>32-39</dimIndex>
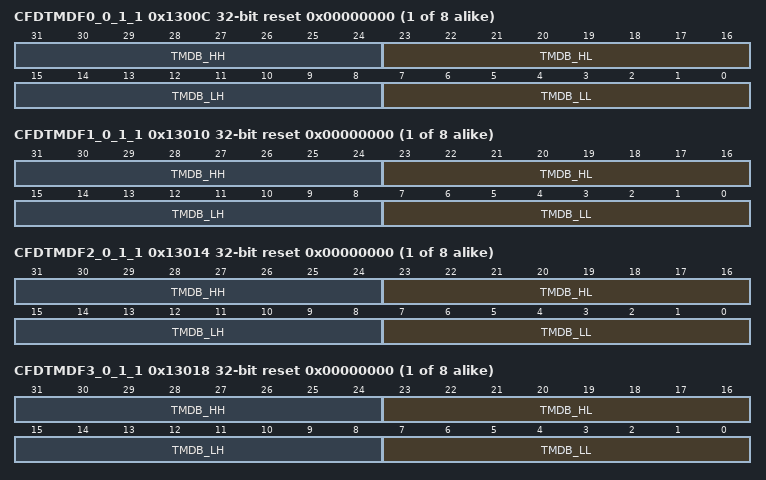
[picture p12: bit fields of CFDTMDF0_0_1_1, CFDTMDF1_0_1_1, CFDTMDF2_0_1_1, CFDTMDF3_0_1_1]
                    <name>CFDTMDF0_%s_1_1</name>
                    <description>TX Message Buffer Data Field 0 Register %s Channel 1</description>
                    <addressOffset>0x1300C</addressOffset>
                    <size>32</size>
                    <access>read-write</access>
                    <resetValue>0x00000000</resetValue>
                    <resetMask>0xffffffff</resetMask>
                    <fields>
                        <field>
                            <name>TMDB_LL</name>
                            <description>TX Message Buffer Data Byte 0</description>
                            <lsb>0</lsb>
                            <msb>7</msb>
                            <access>read-write</access>
                        </field>
                        <field>
                            <name>TMDB_LH</name>
                            <description>TX Message Buffer Data Byte 1</description>
                            <lsb>8</lsb>
                            <msb>15</msb>
                            <access>read-write</access>
                        </field>
                        <field>
                            <name>TMDB_HL</name>
                            <description>TX Message Buffer Data Byte 2</description>
                            <lsb>16</lsb>
                            <msb>23</msb>
                            <access>read-write</access>
                        </field>
                        <field>
                            <name>TMDB_HH</name>
                            <description>TX Message Buffer Data Byte 3</description>
                            <lsb>24</lsb>
                            <msb>31</msb>
                            <access>read-write</access>
                        </field>
                    </fields>
                </register>
                <register>
                    <dim>8</dim>
                    <dimIncrement>0x080</dimIncrement>
                    <dimIndex>32-39</dimIndex>
                    <name>CFDTMDF1_%s_1_1</name>
                    <description>TX Message Buffer Data Field 1 Register %s Channel 1</description>
                    <addressOffset>0x13010</addressOffset>
                    <size>32</size>
                    <access>read-write</access>
                    <resetValue>0x00000000</resetValue>
                    <resetMask>0xffffffff</resetMask>
                    <fields>
                        <field>
                            <name>TMDB_LL</name>
                            <description>TX Message Buffer Data Byte 4</description>
                            <lsb>0</lsb>
                            <msb>7</msb>
                            <access>read-write</access>
                        </field>
                        <field>
                            <name>TMDB_LH</name>
                            <description>TX Message Buffer Data Byte 5</description>
                            <lsb>8</lsb>
                            <msb>15</msb>
                            <access>read-write</access>
                        </field>
                        <field>
                            <name>TMDB_HL</name>
                            <description>TX Message Buffer Data Byte 6</description>
                            <lsb>16</lsb>
                            <msb>23</msb>
                            <access>read-write</access>
                        </field>
                        <field>
                            <name>TMDB_HH</name>
                            <description>TX Message Buffer Data Byte 7</description>
                            <lsb>24</lsb>
                            <msb>31</msb>
                            <access>read-write</access>
                        </field>
                    </fields>
                </register>
                <register>
                    <dim>8</dim>
                    <dimIncrement>0x080</dimIncrement>
                    <dimIndex>32-39</dimIndex>
                    <name>CFDTMDF2_%s_1_1</name>
                    <description>TX Message Buffer Data Field 2 Register %s Channel 1</description>
                    <addressOffset>0x13014</addressOffset>
                    <size>32</size>
                    <access>read-write</access>
                    <resetValue>0x00000000</resetValue>
                    <resetMask>0xffffffff</resetMask>
                    <fields>
                        <field>
                            <name>TMDB_LL</name>
                            <description>TX Message Buffer Data Byte 8</description>
                            <lsb>0</lsb>
                            <msb>7</msb>
                            <access>read-write</access>
                        </field>
                        <field>
                            <name>TMDB_LH</name>
                            <description>TX Message Buffer Data Byte 9</description>
                            <lsb>8</lsb>
                            <msb>15</msb>
                            <access>read-write</access>
                        </field>
                        <field>
                            <name>TMDB_HL</name>
                            <description>TX Message Buffer Data Byte 10</description>
                            <lsb>16</lsb>
                            <msb>23</msb>
                            <access>read-write</access>
                        </field>
                        <field>
                            <name>TMDB_HH</name>
                            <description>TX Message Buffer Data Byte 11</description>
                            <lsb>24</lsb>
                            <msb>31</msb>
                            <access>read-write</access>
                        </field>
                    </fields>
                </register>
                <register>
                    <dim>8</dim>
                    <dimIncrement>0x080</dimIncrement>
                    <dimIndex>32-39</dimIndex>
                    <name>CFDTMDF3_%s_1_1</name>
                    <description>TX Message Buffer Data Field 3 Register %s Channel 1</description>
                    <addressOffset>0x13018</addressOffset>
                    <size>32</size>
                    <access>read-write</access>
                    <resetValue>0x00000000</resetValue>
                    <resetMask>0xffffffff</resetMask>
                    <fields>
                        <field>
                            <name>TMDB_LL</name>
                            <description>TX Message Buffer Data Byte 12</description>
                            <lsb>0</lsb>
                            <msb>7</msb>
                            <access>read-write</access>
                        </field>
                        <field>
                            <name>TMDB_LH</name>
                            <description>TX Message Buffer Data Byte 12</description>
                            <lsb>8</lsb>
                            <msb>15</msb>
                            <access>read-write</access>
                        </field>
                        <field>
                            <name>TMDB_HL</name>
                            <description>TX Message Buffer Data Byte 12</description>
                            <lsb>16</lsb>
                            <msb>23</msb>
                            <access>read-write</access>
                        </field>
                        <field>
                            <name>TMDB_HH</name>
                            <description>TX Message Buffer Data Byte 12</description>
                            <lsb>24</lsb>
                            <msb>31</msb>
                            <access>read-write</access>
                        </field>
                    </fields>
                </register>
                <register>
                    <dim>8</dim>
                    <dimIncrement>0x080</dimIncrement>
                    <dimIndex>32-39</dimIndex>
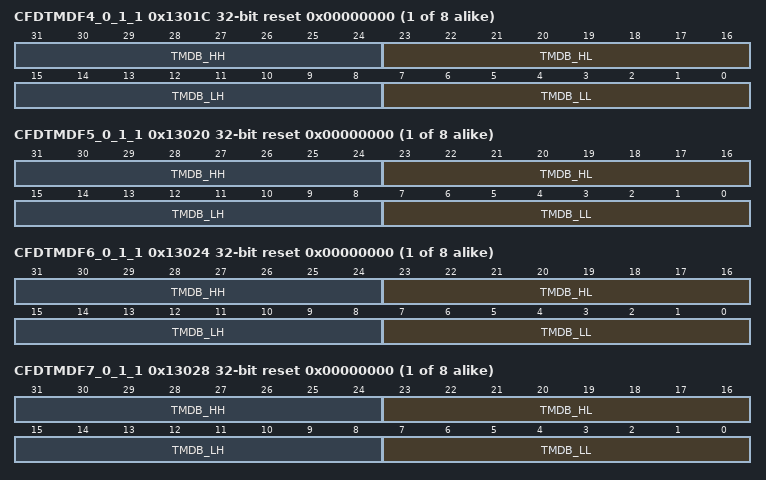
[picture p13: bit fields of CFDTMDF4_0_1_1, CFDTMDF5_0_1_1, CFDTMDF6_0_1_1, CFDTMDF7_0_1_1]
                    <name>CFDTMDF4_%s_1_1</name>
                    <description>TX Message Buffer Data Field 4 Register %s Channel 1</description>
                    <addressOffset>0x1301C</addressOffset>
                    <size>32</size>
                    <access>read-write</access>
                    <resetValue>0x00000000</resetValue>
                    <resetMask>0xffffffff</resetMask>
                    <fields>
                        <field>
                            <name>TMDB_LL</name>
                            <description>TX Message Buffer Data Byte 16</description>
                            <lsb>0</lsb>
                            <msb>7</msb>
                            <access>read-write</access>
                        </field>
                        <field>
                            <name>TMDB_LH</name>
                            <description>TX Message Buffer Data Byte 17</description>
                            <lsb>8</lsb>
                            <msb>15</msb>
                            <access>read-write</access>
                        </field>
                        <field>
                            <name>TMDB_HL</name>
                            <description>TX Message Buffer Data Byte 18</description>
                            <lsb>16</lsb>
                            <msb>23</msb>
                            <access>read-write</access>
                        </field>
                        <field>
                            <name>TMDB_HH</name>
                            <description>TX Message Buffer Data Byte 19</description>
                            <lsb>24</lsb>
                            <msb>31</msb>
                            <access>read-write</access>
                        </field>
                    </fields>
                </register>
                <register>
                    <dim>8</dim>
                    <dimIncrement>0x080</dimIncrement>
                    <dimIndex>32-39</dimIndex>
                    <name>CFDTMDF5_%s_1_1</name>
                    <description>TX Message Buffer Data Field 5 Register %s Channel 1</description>
                    <addressOffset>0x13020</addressOffset>
                    <size>32</size>
                    <access>read-write</access>
                    <resetValue>0x00000000</resetValue>
                    <resetMask>0xffffffff</resetMask>
                    <fields>
                        <field>
                            <name>TMDB_LL</name>
                            <description>TX Message Buffer Data Byte 20</description>
                            <lsb>0</lsb>
                            <msb>7</msb>
                            <access>read-write</access>
                        </field>
                        <field>
                            <name>TMDB_LH</name>
                            <description>TX Message Buffer Data Byte 21</description>
                            <lsb>8</lsb>
                            <msb>15</msb>
                            <access>read-write</access>
                        </field>
                        <field>
                            <name>TMDB_HL</name>
                            <description>TX Message Buffer Data Byte 22</description>
                            <lsb>16</lsb>
                            <msb>23</msb>
                            <access>read-write</access>
                        </field>
                        <field>
                            <name>TMDB_HH</name>
                            <description>TX Message Buffer Data Byte 23</description>
                            <lsb>24</lsb>
                            <msb>31</msb>
                            <access>read-write</access>
                        </field>
                    </fields>
                </register>
                <register>
                    <dim>8</dim>
                    <dimIncrement>0x080</dimIncrement>
                    <dimIndex>32-39</dimIndex>
                    <name>CFDTMDF6_%s_1_1</name>
                    <description>TX Message Buffer Data Field 6 Register %s Channel 1</description>
                    <addressOffset>0x13024</addressOffset>
                    <size>32</size>
                    <access>read-write</access>
                    <resetValue>0x00000000</resetValue>
                    <resetMask>0xffffffff</resetMask>
                    <fields>
                        <field>
                            <name>TMDB_LL</name>
                            <description>TX Message Buffer Data Byte 24</description>
                            <lsb>0</lsb>
                            <msb>7</msb>
                            <access>read-write</access>
                        </field>
                        <field>
                            <name>TMDB_LH</name>
                            <description>TX Message Buffer Data Byte 25</description>
                            <lsb>8</lsb>
                            <msb>15</msb>
                            <access>read-write</access>
                        </field>
                        <field>
                            <name>TMDB_HL</name>
                            <description>TX Message Buffer Data Byte 26</description>
                            <lsb>16</lsb>
                            <msb>23</msb>
                            <access>read-write</access>
                        </field>
                        <field>
                            <name>TMDB_HH</name>
                            <description>TX Message Buffer Data Byte 27</description>
                            <lsb>24</lsb>
                            <msb>31</msb>
                            <access>read-write</access>
                        </field>
                    </fields>
                </register>
                <register>
                    <dim>8</dim>
                    <dimIncrement>0x080</dimIncrement>
                    <dimIndex>32-39</dimIndex>
                    <name>CFDTMDF7_%s_1_1</name>
                    <description>TX Message Buffer Data Field 7 Register %s Channel 1</description>
                    <addressOffset>0x13028</addressOffset>
                    <size>32</size>
                    <access>read-write</access>
                    <resetValue>0x00000000</resetValue>
                    <resetMask>0xffffffff</resetMask>
                    <fields>
                        <field>
                            <name>TMDB_LL</name>
                            <description>TX Message Buffer Data Byte 28</description>
                            <lsb>0</lsb>
                            <msb>7</msb>
                            <access>read-write</access>
                        </field>
                        <field>
                            <name>TMDB_LH</name>
                            <description>TX Message Buffer Data Byte29</description>
                            <lsb>8</lsb>
                            <msb>15</msb>
                            <access>read-write</access>
                        </field>
                        <field>
                            <name>TMDB_HL</name>
                            <description>TX Message Buffer Data Byte 30</description>
                            <lsb>16</lsb>
                            <msb>23</msb>
                            <access>read-write</access>
                        </field>
                        <field>
                            <name>TMDB_HH</name>
                            <description>TX Message Buffer Data Byte 31</description>
                            <lsb>24</lsb>
                            <msb>31</msb>
                            <access>read-write</access>
                        </field>
                    </fields>
                </register>
                <register>
                    <dim>8</dim>
                    <dimIncrement>0x080</dimIncrement>
                    <dimIndex>32-39</dimIndex>
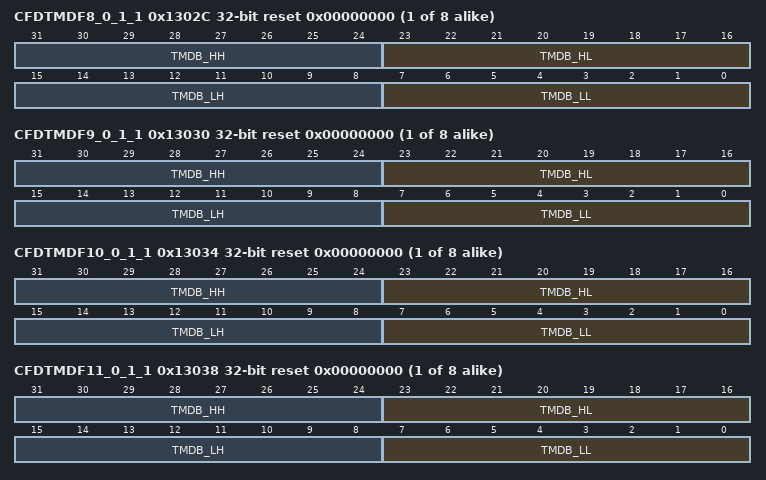
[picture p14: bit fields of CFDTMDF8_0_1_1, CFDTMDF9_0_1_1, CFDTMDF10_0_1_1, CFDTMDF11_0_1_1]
                    <name>CFDTMDF8_%s_1_1</name>
                    <description>TX Message Buffer Data Field 8 Register %s Channel 1</description>
                    <addressOffset>0x1302C</addressOffset>
                    <size>32</size>
                    <access>read-write</access>
                    <resetValue>0x00000000</resetValue>
                    <resetMask>0xffffffff</resetMask>
                    <fields>
                        <field>
                            <name>TMDB_LL</name>
                            <description>TX Message Buffer Data Byte 32</description>
                            <lsb>0</lsb>
                            <msb>7</msb>
                            <access>read-write</access>
                        </field>
                        <field>
                            <name>TMDB_LH</name>
                            <description>TX Message Buffer Data Byte 33</description>
                            <lsb>8</lsb>
                            <msb>15</msb>
                            <access>read-write</access>
                        </field>
                        <field>
                            <name>TMDB_HL</name>
                            <description>TX Message Buffer Data Byte 34</description>
                            <lsb>16</lsb>
                            <msb>23</msb>
                            <access>read-write</access>
                        </field>
                        <field>
                            <name>TMDB_HH</name>
                            <description>TX Message Buffer Data Byte 35</description>
                            <lsb>24</lsb>
                            <msb>31</msb>
                            <access>read-write</access>
                        </field>
                    </fields>
                </register>
                <register>
                    <dim>8</dim>
                    <dimIncrement>0x080</dimIncrement>
                    <dimIndex>32-39</dimIndex>
                    <name>CFDTMDF9_%s_1_1</name>
                    <description>TX Message Buffer Data Field 9 Register %s Channel 1</description>
                    <addressOffset>0x13030</addressOffset>
                    <size>32</size>
                    <access>read-write</access>
                    <resetValue>0x00000000</resetValue>
                    <resetMask>0xffffffff</resetMask>
                    <fields>
                        <field>
                            <name>TMDB_LL</name>
                            <description>TX Message Buffer Data Byte 36</description>
                            <lsb>0</lsb>
                            <msb>7</msb>
                            <access>read-write</access>
                        </field>
                        <field>
                            <name>TMDB_LH</name>
                            <description>TX Message Buffer Data Byte 37</description>
                            <lsb>8</lsb>
                            <msb>15</msb>
                            <access>read-write</access>
                        </field>
                        <field>
                            <name>TMDB_HL</name>
                            <description>TX Message Buffer Data Byte 38</description>
                            <lsb>16</lsb>
                            <msb>23</msb>
                            <access>read-write</access>
                        </field>
                        <field>
                            <name>TMDB_HH</name>
                            <description>TX Message Buffer Data Byte 39</description>
                            <lsb>24</lsb>
                            <msb>31</msb>
                            <access>read-write</access>
                        </field>
                    </fields>
                </register>
                <register>
                    <dim>8</dim>
                    <dimIncrement>0x080</dimIncrement>
                    <dimIndex>32-39</dimIndex>
                    <name>CFDTMDF10_%s_1_1</name>
                    <description>TX Message Buffer Data Field 10 Register %s Channel 1</description>
                    <addressOffset>0x13034</addressOffset>
                    <size>32</size>
                    <access>read-write</access>
                    <resetValue>0x00000000</resetValue>
                    <resetMask>0xffffffff</resetMask>
                    <fields>
                        <field>
                            <name>TMDB_LL</name>
                            <description>TX Message Buffer Data Byte 40</description>
                            <lsb>0</lsb>
                            <msb>7</msb>
                            <access>read-write</access>
                        </field>
                        <field>
                            <name>TMDB_LH</name>
                            <description>TX Message Buffer Data Byte 41</description>
                            <lsb>8</lsb>
                            <msb>15</msb>
                            <access>read-write</access>
                        </field>
                        <field>
                            <name>TMDB_HL</name>
                            <description>TX Message Buffer Data Byte 42</description>
                            <lsb>16</lsb>
                            <msb>23</msb>
                            <access>read-write</access>
                        </field>
                        <field>
                            <name>TMDB_HH</name>
                            <description>TX Message Buffer Data Byte 43</description>
                            <lsb>24</lsb>
                            <msb>31</msb>
                            <access>read-write</access>
                        </field>
                    </fields>
                </register>
                <register>
                    <dim>8</dim>
                    <dimIncrement>0x080</dimIncrement>
                    <dimIndex>32-39</dimIndex>
                    <name>CFDTMDF11_%s_1_1</name>
                    <description>TX Message Buffer Data Field 11 Register %s Channel 1</description>
                    <addressOffset>0x13038</addressOffset>
                    <size>32</size>
                    <access>read-write</access>
                    <resetValue>0x00000000</resetValue>
                    <resetMask>0xffffffff</resetMask>
                    <fields>
                        <field>
                            <name>TMDB_LL</name>
                            <description>TX Message Buffer Data Byte 44</description>
                            <lsb>0</lsb>
                            <msb>7</msb>
                            <access>read-write</access>
                        </field>
                        <field>
                            <name>TMDB_LH</name>
                            <description>TX Message Buffer Data Byte 45</description>
                            <lsb>8</lsb>
                            <msb>15</msb>
                            <access>read-write</access>
                        </field>
                        <field>
                            <name>TMDB_HL</name>
                            <description>TX Message Buffer Data Byte 46</description>
                            <lsb>16</lsb>
                            <msb>23</msb>
                            <access>read-write</access>
                        </field>
                        <field>
                            <name>TMDB_HH</name>
                            <description>TX Message Buffer Data Byte 47</description>
                            <lsb>24</lsb>
                            <msb>31</msb>
                            <access>read-write</access>
                        </field>
                    </fields>
                </register>
                <register>
                    <dim>8</dim>
                    <dimIncrement>0x080</dimIncrement>
                    <dimIndex>32-39</dimIndex>
                    <name>CFDTMDF12_%s_1_1</name>
                    <description>TX Message Buffer Data Field 12 Register %s Channel 1</description>
                    <addressOffset>0x1303C</addressOffset>
                    <size>32</size>
                    <access>read-write</access>
                    <resetValue>0x00000000</resetValue>
                    <resetMask>0xffffffff</resetMask>
                    <fields>
                        <field>
                            <name>TMDB_LL</name>
                            <description>TX Message Buffer Data Byte 48</description>
                            <lsb>0</lsb>
                            <msb>7</msb>
                            <access>read-write</access>
                        </field>
                        <field>
                            <name>TMDB_LH</name>
                            <description>TX Message Buffer Data Byte 49</description>
                            <lsb>8</lsb>
                            <msb>15</msb>
                            <access>read-write</access>
                        </field>
                        <field>
                            <name>TMDB_HL</name>
                            <description>TX Message Buffer Data Byte 50</description>
                            <lsb>16</lsb>
                            <msb>23</msb>
                            <access>read-write</access>
                        </field>
                        <field>
                            <name>TMDB_HH</name>
                            <description>TX Message Buffer Data Byte 51</description>
                            <lsb>24</lsb>
                            <msb>31</msb>
                            <access>read-write</access>
                        </field>
                    </fields>
                </register>
                <register>
                    <dim>8</dim>
                    <dimIncrement>0x080</dimIncrement>
                    <dimIndex>32-39</dimIndex>
                    <name>CFDTMDF13_%s_1_1</name>
                    <description>TX Message Buffer Data Field 13 Register %s Channel 1</description>
                    <addressOffset>0x13040</addressOffset>
                    <size>32</size>
                    <access>read-write</access>
                    <resetValue>0x00000000</resetValue>
                    <resetMask>0xffffffff</resetMask>
                    <fields>
                        <field>
                            <name>TMDB_LL</name>
                            <description>TX Message Buffer Data Byte X</description>
                            <lsb>0</lsb>
                            <msb>7</msb>
                            <access>read-write</access>
                        </field>
                        <field>
                            <name>TMDB_LH</name>
                            <description>TX Message Buffer Data Byte X</description>
                            <lsb>8</lsb>
                            <msb>15</msb>
                            <access>read-write</access>
                        </field>
                        <field>
                            <name>TMDB_HL</name>
                            <description>TX Message Buffer Data Byte X</description>
                            <lsb>16</lsb>
                            <msb>23</msb>
                            <access>read-write</access>
                        </field>
                        <field>
                            <name>TMDB_HH</name>
                            <description>TX Message Buffer Data Byte X</description>
                            <lsb>24</lsb>
                            <msb>31</msb>
                            <access>read-write</access>
                        </field>
                    </fields>
                </register>
                <register>
                    <dim>8</dim>
                    <dimIncrement>0x080</dimIncrement>
                    <dimIndex>32-39</dimIndex>
                    <name>CFDTMDF14_%s_1_1</name>
                    <description>TX Message Buffer Data Field 14 Register %s Channel 1</description>
                    <addressOffset>0x13044</addressOffset>
                    <size>32</size>
                    <access>read-write</access>
                    <resetValue>0x00000000</resetValue>
                    <resetMask>0xffffffff</resetMask>
                    <fields>
                        <field>
                            <name>TMDB_LL</name>
                            <description>TX Message Buffer Data Byte X</description>
                            <lsb>0</lsb>
                            <msb>7</msb>
                            <access>read-write</access>
                        </field>
                        <field>
                            <name>TMDB_LH</name>
                            <description>TX Message Buffer Data Byte X</description>
                            <lsb>8</lsb>
                            <msb>15</msb>
                            <access>read-write</access>
                        </field>
                        <field>
                            <name>TMDB_HL</name>
                            <description>TX Message Buffer Data Byte X</description>
                            <lsb>16</lsb>
                            <msb>23</msb>
                            <access>read-write</access>
                        </field>
                        <field>
                            <name>TMDB_HH</name>
                            <description>TX Message Buffer Data Byte X</description>
                            <lsb>24</lsb>
                            <msb>31</msb>
                            <access>read-write</access>
                        </field>
                    </fields>
                </register>
                <register>
                    <dim>8</dim>
                    <dimIncrement>0x080</dimIncrement>
                    <dimIndex>32-39</dimIndex>
                    <name>CFDTMDF15_%s_1_1</name>
                    <description>TX Message Buffer Data Field X Register 15 Channel 1</description>
                    <addressOffset>0x13048</addressOffset>
                    <size>32</size>
                    <access>read-write</access>
                    <resetValue>0x00000000</resetValue>
                    <resetMask>0xffffffff</resetMask>
                    <fields>
                        <field>
                            <name>TMDB_LL</name>
                            <description>TX Message Buffer Data Byte X</description>
                            <lsb>0</lsb>
                            <msb>7</msb>
                            <access>read-write</access>
                        </field>
                        <field>
                            <name>TMDB_LH</name>
                            <description>TX Message Buffer Data Byte X</description>
                            <lsb>8</lsb>
                            <msb>15</msb>
                            <access>read-write</access>
                        </field>
                        <field>
                            <name>TMDB_HL</name>
                            <description>TX Message Buffer Data Byte X</description>
                            <lsb>16</lsb>
                            <msb>23</msb>
                            <access>read-write</access>
                        </field>
                        <field>
                            <name>TMDB_HH</name>
                            <description>TX Message Buffer Data Byte X</description>
                            <lsb>24</lsb>
                            <msb>31</msb>
                            <access>read-write</access>
                        </field>
                    </fields>
                </register>
            </registers>
        </peripheral>
        <peripheral>
            <name>CTSU</name>
            <description>Capacitive Touch Sensing Unit</description>
            <baseAddress>0x400D0000</baseAddress>
            <addressBlock>
                <offset>0x00</offset>
                <size>9</size>
                <usage>registers</usage>
            </addressBlock>
            <addressBlock>
                <offset>0x0B</offset>
                <size>3</size>
                <usage>registers</usage>
            </addressBlock>
            <addressBlock>
                <offset>0x10</offset>
                <size>14</size>
                <usage>registers</usage>
            </addressBlock>
            <addressBlock>
                <offset>0x20</offset>
                <size>1</size>
                <usage>registers</usage>
            </addressBlock>
            <registers>
                <register>
                    <name>CTSUCR0</name>
                    <description>CTSU Control Register 0</description>
                    <addressOffset>0x00</addressOffset>
                    <size>8</size>
                    <access>read-write</access>
                    <resetValue>0x00</resetValue>
                    <resetMask>0xff</resetMask>
                </register>
                <register>
                    <name>CTSUCR1</name>
                    <description>CTSU Control Register 1</description>
                    <addressOffset>0x01</addressOffset>
                    <size>8</size>
                    <access>read-write</access>
                    <resetValue>0x00</resetValue>
                    <resetMask>0xff</resetMask>
                </register>
                <register>
                    <name>CTSUSDPRS</name>
                    <description>CTSU Synchronous Noise Reduction Setting Register</description>
                    <addressOffset>0x02</addressOffset>
                    <size>8</size>
                    <access>read-write</access>
                    <resetValue>0x00</resetValue>
                    <resetMask>0xff</resetMask>
                </register>
                <register>
                    <name>CTSUSST</name>
                    <description>CTSU Sensor Stabilization Wait Control Register</description>
                    <addressOffset>0x03</addressOffset>
                    <size>8</size>
                    <access>read-write</access>
                    <resetValue>0x00</resetValue>
                    <resetMask>0xff</resetMask>
                </register>
                <register>
                    <name>CTSUMCH0</name>
                    <description>CTSU Measurement Channel Register 0</description>
                    <addressOffset>0x04</addressOffset>
                    <size>8</size>
                    <access>read-write</access>
                    <resetValue>0x1f</resetValue>
                    <resetMask>0xff</resetMask>
                </register>
                <register>
                    <name>CTSUMCH1</name>
                    <description>CTSU Measurement Channel Register 1</description>
                    <addressOffset>0x05</addressOffset>
                    <size>8</size>
                    <access>read-only</access>
                    <resetValue>0x1f</resetValue>
                    <resetMask>0xff</resetMask>
                </register>
                <register>
                    <name>CTSUCHAC0</name>
                    <description>CTSU Channel Enable Control Register 0</description>
                    <addressOffset>0x06</addressOffset>
                    <size>8</size>
                    <access>read-write</access>
                    <resetValue>0x00</resetValue>
                    <resetMask>0xff</resetMask>
                </register>
                <register>
                    <name>CTSUCHAC1</name>
                    <description>CTSU Channel Enable Control Register 1</description>
                    <addressOffset>0x07</addressOffset>
                    <size>8</size>
                    <access>read-write</access>
                    <resetValue>0x00</resetValue>
                    <resetMask>0xff</resetMask>
                </register>
                <register>
                    <name>CTSUCHAC2</name>
                    <description>CTSU Channel Enable Control Register 2</description>
                    <addressOffset>0x08</addressOffset>
                    <size>8</size>
                    <access>read-write</access>
                    <resetValue>0x00</resetValue>
                    <resetMask>0xff</resetMask>
                </register>
                <register>
                    <name>CTSUCHTRC0</name>
                    <description>CTSU Channel Transmit/Receive Control Register 0</description>
                    <addressOffset>0x0B</addressOffset>
                    <size>8</size>
                    <access>read-write</access>
                    <resetValue>0x00</resetValue>
                    <resetMask>0xff</resetMask>
                </register>
                <register>
                    <name>CTSUCHTRC1</name>
                    <description>CTSU Channel Transmit/Receive Control Register 1</description>
                    <addressOffset>0x0C</addressOffset>
                    <size>8</size>
                    <access>read-write</access>
                    <resetValue>0x00</resetValue>
                    <resetMask>0xff</resetMask>
                </register>
                <register>
                    <name>CTSUCHTRC2</name>
                    <description>CTSU Channel Transmit/Receive Control Register 2</description>
                    <addressOffset>0x0D</addressOffset>
                    <size>8</size>
                    <access>read-write</access>
                    <resetValue>0x00</resetValue>
                    <resetMask>0xff</resetMask>
                </register>
                <register>
                    <name>CTSUDCLKC</name>
                    <description>CTSU High,Pass Noise Reduction Control Register</description>
                    <addressOffset>0x10</addressOffset>
                    <size>8</size>
                    <access>read-write</access>
                    <resetValue>0x00</resetValue>
                    <resetMask>0xff</resetMask>
                </register>
                <register>
                    <name>CTSUST</name>
                    <description>CTSU Status Register</description>
                    <addressOffset>0x11</addressOffset>
                    <size>8</size>
                    <access>read-write</access>
                    <resetValue>0x00</resetValue>
                    <resetMask>0xff</resetMask>
                </register>
                <register>
                    <name>CTSUSSC</name>
                    <description>CTSU High,Pass Noise Reduction Spectrum Diffusion Control Register</description>
                    <addressOffset>0x12</addressOffset>
                    <size>16</size>
                    <access>read-write</access>
                    <resetValue>0x0000</resetValue>
                    <resetMask>0xffff</resetMask>
                    <fields>
                        <field>
                            <name>CTSUSSDIV</name>
                            <description>CTSU Spectrum Diffusion Frequency Division Setting</description>
                            <lsb>8</lsb>
                            <msb>11</msb>
                            <access>read-write</access>
                        </field>
                    </fields>
                </register>
                <register>
                    <name>CTSUSO0</name>
                    <description>CTSU Sensor Offset Register 0</description>
                    <addressOffset>0x14</addressOffset>
                    <size>16</size>
                    <access>read-write</access>
                    <resetValue>0x0000</resetValue>
                    <resetMask>0xffff</resetMask>
                </register>
                <register>
                    <name>CTSUSO1</name>
                    <description>CTSU Sensor Offset Register 1</description>
                    <addressOffset>0x16</addressOffset>
                    <size>16</size>
                    <access>read-write</access>
                    <resetValue>0x0000</resetValue>
                    <resetMask>0xffff</resetMask>
                </register>
                <register>
                    <name>CTSUSC</name>
                    <description>CTSU Sensor Counter</description>
                    <addressOffset>0x18</addressOffset>
                    <size>16</size>
                    <access>read-only</access>
                    <resetValue>0x0000</resetValue>
                    <resetMask>0xffff</resetMask>
                </register>
                <register>
                    <name>CTSURC</name>
                    <description>CTSU Reference Counter</description>
                    <addressOffset>0x1A</addressOffset>
                    <size>16</size>
                    <access>read-only</access>
                    <resetValue>0x0000</resetValue>
                    <resetMask>0xffff</resetMask>
                    <fields>
                        <field>
                            <name>CTSURC</name>
                            <description>CTSU Reference Counter</description>
                            <lsb>0</lsb>
                            <msb>15</msb>
                            <access>read-only</access>
                        </field>
                    </fields>
                </register>
                <register>
                    <name>CTSUERRS</name>
                    <description>CTSU Error Status Register</description>
                    <addressOffset>0x1C</addressOffset>
                    <size>16</size>
                    <access>read-write</access>
                    <resetValue>0x0000</resetValue>
                    <resetMask>0x7fff</resetMask>
                    <fields>
                        <field>
                            <name>CTSUSPMD</name>
                            <description>Calibration Mode</description>
                            <lsb>0</lsb>
                            <msb>1</msb>
                            <access>read-write</access>
                            <enumeratedValues>
                                </enumeratedValues>
                        </field>
                        <field>
                            <name>CTSUTSOD</name>
                            <description>TS Pin Fixed Output</description>
                            <lsb>2</lsb>
                            <msb>2</msb>
                            <access>read-write</access>
                            <enumeratedValues>
                                </enumeratedValues>
                        </field>
                        <field>
                            <name>CTSUDRV</name>
                            <description>Calibration Setting 1</description>
                            <lsb>3</lsb>
                            <msb>3</msb>
                            <access>read-write</access>
                            <enumeratedValues>
                                </enumeratedValues>
                        </field>
                        <field>
                            <name>CTSUCLKSEL1</name>
                            <description>Calibration Setting 3</description>
                            <lsb>6</lsb>
                            <msb>6</msb>
                            <access>read-write</access>
                            <enumeratedValues>
                                </enumeratedValues>
                        </field>
                        <field>
                            <name>CTSUTSOC</name>
                            <description>Calibration Setting 2</description>
                            <lsb>7</lsb>
                            <msb>7</msb>
                            <access>read-write</access>
                            <enumeratedValues>
                                </enumeratedValues>
                        </field>
                        <field>
                            <name>CTSUICOMP</name>
                            <description>TSCAP Voltage Error Monitor</description>
                            <lsb>15</lsb>
                            <msb>15</msb>
                            <access>read-only</access>
                            <enumeratedValues>
                                </enumeratedValues>
                        </field>
                    </fields>
                </register>
                <register>
                    <name>CTSUTRMR</name>
                    <description>CTSU Reference Current Calibration Register</description>
                    <addressOffset>0x20</addressOffset>
                    <size>8</size>
                    <access>read-write</access>
                    <resetValue>0x00</resetValue>
                    <resetMask>0x00</resetMask>
                </register>
            </registers>
        </peripheral>
        <peripheral>
            <name>PSCU</name>
            <description>Peripheral Security Control Unit</description>
            <baseAddress>0x400E0000</baseAddress>
            <addressBlock>
                <offset>0x04</offset>
                <size>44</size>
                <usage>registers</usage>
            </addressBlock>
            <registers>
                <register>
                    <name>PSARB</name>
                    <description>Peripheral Security Attribution Register B</description>
                    <addressOffset>0x04</addressOffset>
                    <size>32</size>
                    <access>read-write</access>
                    <resetValue>0xffffffff</resetValue>
                    <resetMask>0xffffffff</resetMask>
                    <fields>
                        <field>
                            <name>PSARB3</name>
                            <description>CEC and the MSTPCRB.MSTPB3 bit security attribution</description>
                            <lsb>3</lsb>
                            <msb>3</msb>
                            <access>read-write</access>
                            <enumeratedValues>
                                </enumeratedValues>
                        </field>
                        <field>
                            <name>PSARB6</name>
                            <description>QSPI and the MSTPCRB.MSTPB6 bit security attribution</description>
                            <lsb>6</lsb>
                            <msb>6</msb>
                            <access>read-only</access>
                        </field>
                        <field>
                            <name>PSARB7</name>
                            <description>IIC2 and the MSTPCRB.MSTPB7 bit security attribution</description>
                            <lsb>7</lsb>
                            <msb>7</msb>
                            <access>read-write</access>
                            <enumeratedValues>
                                </enumeratedValues>
                        </field>
                        <field>
                            <name>PSARB8</name>
                            <description>IIC1 and the MSTPCRB.MSTPB8 bit security attribution</description>
                            <lsb>8</lsb>
                            <msb>8</msb>
                            <access>read-write</access>
                            <enumeratedValues>
                                </enumeratedValues>
                        </field>
                        <field>
                            <name>PSARB9</name>
                            <description>IIC0 and the MSTPCRB.MSTPB9 bit security attribution</description>
                            <lsb>9</lsb>
                            <msb>9</msb>
                            <access>read-write</access>
                            <enumeratedValues>
                                </enumeratedValues>
                        </field>
                        <field>
                            <name>PSARB11</name>
                            <description>USBFS and the MSTPCRB.MSTPB11 bit security attribution</description>
                            <lsb>11</lsb>
                            <msb>11</msb>
                            <access>read-write</access>
                            <enumeratedValues>
                                </enumeratedValues>
                        </field>
                        <field>
                            <name>PSARB12</name>
                            <description>USBHS and the MSTPCRB.MSTPB12 bit security attribution</description>
                            <lsb>12</lsb>
                            <msb>12</msb>
                            <access>read-write</access>
                            <enumeratedValues>
                                </enumeratedValues>
                        </field>
                        <field>
                            <name>PSARB15</name>
                            <description>ETHER0/EDMAC0, the MSTPCRB.MSTPB15 bit and the PFENET.PHYMODE0 bit security attribution</description>
                            <lsb>15</lsb>
                            <msb>15</msb>
                            <access>read-only</access>
                        </field>
                        <field>
                            <name>PSARB16</name>
                            <description>OSPI and the MSTPCRB.MSTPB16 bit security attribution</description>
                            <lsb>16</lsb>
                            <msb>16</msb>
                            <access>read-only</access>
                        </field>
                        <field>
                            <name>PSARB18</name>
                            <description>SPI1 and the MSTPCRB.MSTPB18 bit security attribution</description>
                            <lsb>18</lsb>
                            <msb>18</msb>
                            <access>read-write</access>
                            <enumeratedValues>
                                </enumeratedValues>
                        </field>
                        <field>
                            <name>PSARB19</name>
                            <description>SPI0 and the MSTPCRB.MSTPB19 bit security attribution</description>
                            <lsb>19</lsb>
                            <msb>19</msb>
                            <access>read-write</access>
                            <enumeratedValues>
                                </enumeratedValues>
                        </field>
                        <field>
                            <name>PSARB22</name>
                            <description>SCI9 and the MSTPCRB.MSTPB22 bit security attribution</description>
                            <lsb>22</lsb>
                            <msb>22</msb>
                            <access>read-write</access>
                            <enumeratedValues>
                                </enumeratedValues>
                        </field>
                        <field>
                            <name>PSARB23</name>
                            <description>SCI8 and the MSTPCRB.MSTPB23 bit security attribution</description>
                            <lsb>23</lsb>
                            <msb>23</msb>
                            <access>read-write</access>
                            <enumeratedValues>
                                </enumeratedValues>
                        </field>
                        <field>
                            <name>PSARB24</name>
                            <description>SCI7 and the MSTPCRB.MSTPB24 bit security attribution</description>
                            <lsb>24</lsb>
                            <msb>24</msb>
                            <access>read-write</access>
                            <enumeratedValues>
                                </enumeratedValues>
                        </field>
                        <field>
                            <name>PSARB25</name>
                            <description>SCI6 and the MSTPCRB.MSTPB25 bit security attribution</description>
                            <lsb>25</lsb>
                            <msb>25</msb>
                            <access>read-write</access>
                            <enumeratedValues>
                                </enumeratedValues>
                        </field>
                        <field>
                            <name>PSARB26</name>
                            <description>SCI5 and the MSTPCRB.MSTPB26 bit security attribution</description>
                            <lsb>26</lsb>
                            <msb>26</msb>
                            <access>read-write</access>
                            <enumeratedValues>
                                </enumeratedValues>
                        </field>
                        <field>
                            <name>PSARB27</name>
                            <description>SCI4 and the MSTPCRB.MSTPB27 bit security attribution</description>
                            <lsb>27</lsb>
                            <msb>27</msb>
                            <access>read-write</access>
                            <enumeratedValues>
                                </enumeratedValues>
                        </field>
                        <field>
                            <name>PSARB28</name>
                            <description>SCI3 and the MSTPCRB.MSTPB28 bit security attribution</description>
                            <lsb>28</lsb>
                            <msb>28</msb>
                            <access>read-write</access>
                            <enumeratedValues>
                                </enumeratedValues>
                        </field>
                        <field>
                            <name>PSARB29</name>
                            <description>SCI2 and the MSTPCRB.MSTPB29 bit security attribution</description>
                            <lsb>29</lsb>
                            <msb>29</msb>
                            <access>read-write</access>
                            <enumeratedValues>
                                </enumeratedValues>
                        </field>
                        <field>
                            <name>PSARB30</name>
                            <description>SCI1 and the MSTPCRB.MSTPB30 bit security attribution</description>
                            <lsb>30</lsb>
                            <msb>30</msb>
                            <access>read-write</access>
                            <enumeratedValues>
                                </enumeratedValues>
                        </field>
                        <field>
                            <name>PSARB31</name>
                            <description>SCI0 and the MSTPCRB.MSTPB31 bit security attribution</description>
                            <lsb>31</lsb>
                            <msb>31</msb>
                            <access>read-write</access>
                            <enumeratedValues>
                                </enumeratedValues>
                        </field>
                    </fields>
                </register>
                <register>
                    <name>PSARC</name>
                    <description>Peripheral Security Attribution Register C</description>
                    <addressOffset>0x08</addressOffset>
                    <size>32</size>
                    <access>read-write</access>
                    <resetValue>0xffffffff</resetValue>
                    <resetMask>0xffffffff</resetMask>
                    <fields>
                        <field>
                            <name>PSARC0</name>
                            <description>CAC and the MSTPCRC.MSTPC0 bit security attribution</description>
                            <lsb>0</lsb>
                            <msb>0</msb>
                            <access>read-write</access>
                            <enumeratedValues>
                                </enumeratedValues>
                        </field>
                        <field>
                            <name>PSARC1</name>
                            <description>CRC and the MSTPCRC.MSTPC1 bit security attribution</description>
                            <lsb>1</lsb>
                            <msb>1</msb>
                            <access>read-write</access>
                            <enumeratedValues>
                                </enumeratedValues>
                        </field>
                        <field>
                            <name>PSARC3</name>
                            <description>CTSU and the MSTPCRC.MSTPC3 bit security attribution</description>
                            <lsb>3</lsb>
                            <msb>3</msb>
                            <access>read-write</access>
                            <enumeratedValues>
                                </enumeratedValues>
                        </field>
                        <field>
                            <name>PSARC8</name>
                            <description>SSIE0 and the MSTPCRC.MSTPC8 bit security attribution</description>
                            <lsb>8</lsb>
                            <msb>8</msb>
                            <access>read-write</access>
                            <enumeratedValues>
                                </enumeratedValues>
                        </field>
                        <field>
                            <name>PSARC12</name>
                            <description>SDHI0 and the MSTPCRC.MSTPC12 bit security attribution</description>
                            <lsb>12</lsb>
                            <msb>12</msb>
                            <access>read-write</access>
                            <enumeratedValues>
                                </enumeratedValues>
                        </field>
                        <field>
                            <name>PSARC13</name>
                            <description>DOC and the MSTPCRC.MSTPC13 bit security attribution</description>
                            <lsb>13</lsb>
                            <msb>13</msb>
                            <access>read-write</access>
                            <enumeratedValues>
                                </enumeratedValues>
                        </field>
                        <field>
                            <name>PSARC27</name>
                            <description>CANFD0 and the MSTPCRC.MSTPC27 bit security attribution</description>
                            <lsb>27</lsb>
                            <msb>27</msb>
                            <access>read-write</access>
                            <enumeratedValues>
                                </enumeratedValues>
                        </field>
                        <field>
                            <name>PSARC31</name>
                            <description>SCE9 and the MSTPCRC.MSTPC31 bit security attribution</description>
                            <lsb>31</lsb>
                            <msb>31</msb>
                            <access>read-write</access>
                            <enumeratedValues>
                                </enumeratedValues>
                        </field>
                    </fields>
                </register>
                <register>
                    <name>PSARD</name>
                    <description>Peripheral Security Attribution Register D</description>
                    <addressOffset>0x0C</addressOffset>
                    <size>32</size>
                    <access>read-write</access>
                    <resetValue>0xffffffff</resetValue>
                    <resetMask>0xffffffff</resetMask>
                    <fields>
                        <field>
                            <name>PSARD0</name>
                            <description>AGT3 and the MSTPCRD.MSTPD0 bit security attribution</description>
                            <lsb>0</lsb>
                            <msb>0</msb>
                            <access>read-write</access>
                            <enumeratedValues>
                                </enumeratedValues>
                        </field>
                        <field>
                            <name>PSARD1</name>
                            <description>AGT2 and the MSTPCRD.MSTPD1 bit security attribution</description>
                            <lsb>1</lsb>
                            <msb>1</msb>
                            <access>read-write</access>
                            <enumeratedValues>
                                </enumeratedValues>
                        </field>
                        <field>
                            <name>PSARD2</name>
                            <description>AGT1 and the MSTPCRD.MSTPD2 bit security attribution</description>
                            <lsb>2</lsb>
                            <msb>2</msb>
                            <access>read-write</access>
                            <enumeratedValues>
                                </enumeratedValues>
                        </field>
                        <field>
                            <name>PSARD3</name>
                            <description>AGT0 and the MSTPCRD.MSTPD3 bit security attribution</description>
                            <lsb>3</lsb>
                            <msb>3</msb>
                            <access>read-write</access>
                            <enumeratedValues>
                                </enumeratedValues>
                        </field>
                        <field>
                            <name>PSARD11</name>
                            <description>POEG Group D and the MSTPCRD.MSTPD11 bit security attribution</description>
                            <lsb>11</lsb>
                            <msb>11</msb>
                            <access>read-write</access>
                            <enumeratedValues>
                                </enumeratedValues>
                        </field>
                        <field>
                            <name>PSARD12</name>
                            <description>POEG Group C and the MSTPCRD.MSTPD12 bit security attribution</description>
                            <lsb>12</lsb>
                            <msb>12</msb>
                            <access>read-write</access>
                            <enumeratedValues>
                                </enumeratedValues>
                        </field>
                        <field>
                            <name>PSARD13</name>
                            <description>POEG Group B and the MSTPCRD.MSTPD13 bit security attribution</description>
                            <lsb>13</lsb>
                            <msb>13</msb>
                            <access>read-write</access>
                            <enumeratedValues>
                                </enumeratedValues>
                        </field>
                        <field>
                            <name>PSARD14</name>
                            <description>POEG Group A and the MSTPCRD.MSTPD14 bit security attribution</description>
                            <lsb>14</lsb>
                            <msb>14</msb>
                            <access>read-write</access>
                            <enumeratedValues>
                                </enumeratedValues>
                        </field>
                        <field>
                            <name>PSARD15</name>
                            <description>ADC121 and the MSTPCRD.MSTPD15 bit security attribution</description>
                            <lsb>15</lsb>
                            <msb>15</msb>
                            <access>read-write</access>
                            <enumeratedValues>
                                </enumeratedValues>
                        </field>
                        <field>
                            <name>PSARD16</name>
                            <description>ADC120 and the MSTPCRD.MSTPD16 bit security attribution</description>
                            <lsb>16</lsb>
                            <msb>16</msb>
                            <access>read-write</access>
                            <enumeratedValues>
                                </enumeratedValues>
                        </field>
                        <field>
                            <name>PSARD20</name>
                            <description>DAC12 and the MSTPCRD.MSTPD20 bit security attribution</description>
                            <lsb>20</lsb>
                            <msb>20</msb>
                            <access>read-write</access>
                            <enumeratedValues>
                                </enumeratedValues>
                        </field>
                        <field>
                            <name>PSARD22</name>
                            <description>TSN and the MSTPCRD.MSTPD22 bit security attribution</description>
                            <lsb>22</lsb>
                            <msb>22</msb>
                            <access>read-write</access>
                            <enumeratedValues>
                                </enumeratedValues>
                        </field>
                    </fields>
                </register>
                <register>
                    <name>PSARE</name>
                    <description>Peripheral Security Attribution Register E</description>
                    <addressOffset>0x10</addressOffset>
                    <size>32</size>
                    <access>read-write</access>
                    <resetValue>0xffffffff</resetValue>
                    <resetMask>0xffffffff</resetMask>
                    <fields>
                        <field>
                            <name>PSARE0</name>
                            <description>WDT security attribution</description>
                            <lsb>0</lsb>
                            <msb>0</msb>
                            <access>read-write</access>
                            <enumeratedValues>
                                </enumeratedValues>
                        </field>
                        <field>
                            <name>PSARE1</name>
                            <description>IWDT security attribution</description>
                            <lsb>1</lsb>
                            <msb>1</msb>
                            <access>read-write</access>
                            <enumeratedValues>
                                </enumeratedValues>
                        </field>
                        <field>
                            <name>PSARE2</name>
                            <description>RTC security attribution</description>
                            <lsb>2</lsb>
                            <msb>2</msb>
                            <access>read-write</access>
                            <enumeratedValues>
                                </enumeratedValues>
                        </field>
                        <field>
                            <name>PSARE14</name>
                            <description>AGT5 and the MSTPCRE.MSTPE14 bit security attribution</description>
                            <lsb>14</lsb>
                            <msb>14</msb>
                            <access>read-write</access>
                            <enumeratedValues>
                                </enumeratedValues>
                        </field>
                        <field>
                            <name>PSARE15</name>
                            <description>AGT4 and the MSTPCRE.MSTPE15 bit security attribution</description>
                            <lsb>15</lsb>
                            <msb>15</msb>
                            <access>read-write</access>
                            <enumeratedValues>
                                </enumeratedValues>
                        </field>
                        <field>
                            <name>PSARE22</name>
                            <description>GPT9 and the MSTPCRE.MSTPE22 bit security attribution</description>
                            <lsb>22</lsb>
                            <msb>22</msb>
                            <access>read-write</access>
                            <enumeratedValues>
                                </enumeratedValues>
                        </field>
                        <field>
                            <name>PSARE23</name>
                            <description>GPT8 and the MSTPCRE.MSTPE23 bit security attribution</description>
                            <lsb>23</lsb>
                            <msb>23</msb>
                            <access>read-write</access>
                            <enumeratedValues>
                                </enumeratedValues>
                        </field>
                        <field>
                            <name>PSARE24</name>
                            <description>GPT7 and the MSTPCRE.MSTPE24 bit security attribution</description>
                            <lsb>24</lsb>
                            <msb>24</msb>
                            <access>read-write</access>
                            <enumeratedValues>
                                </enumeratedValues>
                        </field>
                        <field>
                            <name>PSARE25</name>
                            <description>GPT6 and the MSTPCRE.MSTPE25 bit security attribution</description>
                            <lsb>25</lsb>
                            <msb>25</msb>
                            <access>read-write</access>
                            <enumeratedValues>
                                </enumeratedValues>
                        </field>
                        <field>
                            <name>PSARE26</name>
                            <description>GPT5 and the MSTPCRE.MSTPE26 bit security attribution</description>
                            <lsb>26</lsb>
                            <msb>26</msb>
                            <access>read-write</access>
                            <enumeratedValues>
                                </enumeratedValues>
                        </field>
                        <field>
                            <name>PSARE27</name>
                            <description>GPT4 and the MSTPCRE.MSTPE27 bit security attribution</description>
                            <lsb>27</lsb>
                            <msb>27</msb>
                            <access>read-write</access>
                            <enumeratedValues>
                                </enumeratedValues>
                        </field>
                        <field>
                            <name>PSARE28</name>
                            <description>GPT3 and the MSTPCRE.MSTPE28 bit security attribution</description>
                            <lsb>28</lsb>
                            <msb>28</msb>
                            <access>read-write</access>
                            <enumeratedValues>
                                </enumeratedValues>
                        </field>
                        <field>
                            <name>PSARE29</name>
                            <description>GPT2 and the MSTPCRE.MSTPE29 bit security attribution</description>
                            <lsb>29</lsb>
                            <msb>29</msb>
                            <access>read-write</access>
                            <enumeratedValues>
                                </enumeratedValues>
                        </field>
                        <field>
                            <name>PSARE30</name>
                            <description>GPT1 and the MSTPCRE.MSTPE30 bit security attribution</description>
                            <lsb>30</lsb>
                            <msb>30</msb>
                            <access>read-write</access>
                            <enumeratedValues>
                                </enumeratedValues>
                        </field>
                        <field>
                            <name>PSARE31</name>
                            <description>GPT0, GPT_OPS and the MSTPCRE.MSTPE31 bit security attribution</description>
                            <lsb>31</lsb>
                            <msb>31</msb>
                            <access>read-write</access>
                            <enumeratedValues>
                                </enumeratedValues>
                        </field>
                    </fields>
                </register>
                <register>
                    <name>MSSAR</name>
                    <description>Module Stop Security Attribution Register</description>
                    <addressOffset>0x14</addressOffset>
                    <size>32</size>
                    <access>read-write</access>
                    <resetValue>0xffffffff</resetValue>
                    <resetMask>0xffffffff</resetMask>
                    <fields>
                        <field>
                            <name>MSSAR0</name>
                            <description>The MSTPCRC.MSTPC14 bit security attribution</description>
                            <lsb>0</lsb>
                            <msb>0</msb>
                            <access>read-write</access>
                            <enumeratedValues>
                                </enumeratedValues>
                        </field>
                        <field>
                            <name>MSSAR1</name>
                            <description>The MSTPCRA.MSTPA22 bit security attribution</description>
                            <lsb>1</lsb>
                            <msb>1</msb>
                            <access>read-write</access>
                            <enumeratedValues>
                                </enumeratedValues>
                        </field>
                        <field>
                            <name>MSSAR2</name>
                            <description>The MSTPCRA.MSTPA7 bit security attribution</description>
                            <lsb>2</lsb>
                            <msb>2</msb>
                            <access>read-write</access>
                            <enumeratedValues>
                                </enumeratedValues>
                        </field>
                        <field>
                            <name>MSSAR3</name>
                            <description>The MSTPCRA.MSTPA0 bit security attribution</description>
                            <lsb>3</lsb>
                            <msb>3</msb>
                            <access>read-write</access>
                            <enumeratedValues>
                                </enumeratedValues>
                        </field>
                    </fields>
                </register>
                <register>
                    <name>CFSAMONA</name>
                    <description>Code Flash Security Attribution Monitor Register A</description>
                    <addressOffset>0x18</addressOffset>
                    <size>32</size>
                    <access>read-only</access>
                    <resetValue>0x00000000</resetValue>
                    <resetMask>0xff007fff</resetMask>
                    <fields>
                        <field>
                            <name>CFS2</name>
                            <description>Code Flash Secure area 2</description>
                            <lsb>15</lsb>
                            <msb>23</msb>
                            <access>read-only</access>
                        </field>
                    </fields>
                </register>
                <register>
                    <name>CFSAMONB</name>
                    <description>Code Flash Security Attribution Monitor Register B</description>
                    <addressOffset>0x1C</addressOffset>
                    <size>32</size>
                    <access>read-only</access>
                    <resetValue>0x00000000</resetValue>
                    <resetMask>0xff0003ff</resetMask>
                    <fields>
                        <field>
                            <name>CFS1</name>
                            <description>Code Flash Secure area 1</description>
                            <lsb>10</lsb>
                            <msb>23</msb>
                            <access>read-only</access>
                        </field>
                    </fields>
                </register>
                <register>
                    <name>DFSAMON</name>
                    <description>Data Flash Security Attribution Monitor Register</description>
                    <addressOffset>0x20</addressOffset>
                    <size>32</size>
                    <access>read-only</access>
                    <resetValue>0x00000000</resetValue>
                    <resetMask>0xffff03ff</resetMask>
                    <fields>
                        <field>
                            <name>DFS</name>
                            <description>Data flash Secure area</description>
                            <lsb>10</lsb>
                            <msb>15</msb>
                            <access>read-only</access>
                        </field>
                    </fields>
                </register>
                <register>
                    <name>SSAMONA</name>
                    <description>SRAM Security Attribution Monitor Register A</description>
                    <addressOffset>0x24</addressOffset>
                    <size>32</size>
                    <access>read-only</access>
                    <resetValue>0x00000000</resetValue>
                    <resetMask>0xffe01fff</resetMask>
                    <fields>
                        <field>
                            <name>SS2</name>
                            <description>SRAM Secure area 2</description>
                            <lsb>13</lsb>
                            <msb>20</msb>
                            <access>read-only</access>
                        </field>
                    </fields>
                </register>
                <register>
                    <name>SSAMONB</name>
                    <description>SRAM Security Attribution Monitor Register B</description>
                    <addressOffset>0x28</addressOffset>
                    <size>32</size>
                    <access>read-only</access>
                    <resetValue>0x00000000</resetValue>
                    <resetMask>0xffe003ff</resetMask>
                    <fields>
                        <field>
                            <name>SS1</name>
                            <description>SRAM secure area 1</description>
                            <lsb>10</lsb>
                            <msb>20</msb>
                            <access>read-only</access>
                        </field>
                    </fields>
                </register>
                <register>
                    <name>DLMMON</name>
                    <description>Device Lifecycle Management State Monitor Register</description>
                    <addressOffset>0x2C</addressOffset>
                    <size>32</size>
                    <access>read-only</access>
                    <resetValue>0x00000000</resetValue>
                    <resetMask>0xfffffff0</resetMask>
                    <fields>
                        <field>
                            <name>DLMMON</name>
                            <description>Device Lifecycle Management State Monitor</description>
                            <lsb>0</lsb>
                            <msb>3</msb>
                            <access>read-only</access>
                            <enumeratedValues>
                                </enumeratedValues>
                        </field>
                    </fields>
                </register>
            </registers>
        </peripheral>
        <peripheral>
            <name>AGT0</name>
            <description>Low Power Asynchronous General Purpose Timer 0</description>
            <baseAddress>0x400E8000</baseAddress>
            <addressBlock>
                <offset>0x00</offset>
                <size>6</size>
                <usage>registers</usage>
            </addressBlock>
            <addressBlock>
                <offset>0x08</offset>
                <size>3</size>
                <usage>registers</usage>
            </addressBlock>
            <addressBlock>
                <offset>0x0C</offset>
                <size>4</size>
                <usage>registers</usage>
            </addressBlock>
            <registers>
                <register>
                    <name>AGT</name>
                    <description>AGT Counter Register</description>
                    <addressOffset>0x00</addressOffset>
                    <size>16</size>
                    <access>read-write</access>
                    <resetValue>0xffff</resetValue>
                    <resetMask>0xffff</resetMask>
                </register>
                <register>
                    <name>AGTCMA</name>
                    <description>AGT Compare Match A Register</description>
                    <addressOffset>0x02</addressOffset>
                    <size>16</size>
                    <access>read-write</access>
                    <resetValue>0xffff</resetValue>
                    <resetMask>0xffff</resetMask>
                </register>
                <register>
                    <name>AGTCMB</name>
                    <description>AGT Compare Match B Register</description>
                    <addressOffset>0x04</addressOffset>
                    <size>16</size>
                    <access>read-write</access>
                    <resetValue>0xffff</resetValue>
                    <resetMask>0xffff</resetMask>
                </register>
                <register>
                    <name>AGTCR</name>
                    <description>AGT Control Register</description>
                    <addressOffset>0x08</addressOffset>
                    <size>8</size>
                    <access>read-write</access>
                    <resetValue>0x00</resetValue>
                    <resetMask>0xff</resetMask>
                    <fields>
                        <field>
                            <name>TSTART</name>
                            <description>AGT Count Start</description>
                            <lsb>0</lsb>
                            <msb>0</msb>
                            <access>read-write</access>
                            <enumeratedValues>
                                </enumeratedValues>
                        </field>
                        <field>
                            <name>TCSTF</name>
                            <description>AGT Count Status Flag</description>
                            <lsb>1</lsb>
                            <msb>1</msb>
                            <access>read-only</access>
                            <enumeratedValues>
                                </enumeratedValues>
                        </field>
                        <field>
                            <name>TSTOP</name>
                            <description>AGT Count Forced Stop</description>
                            <lsb>2</lsb>
                            <msb>2</msb>
                            <access>write-only</access>
                            <enumeratedValues>
                                </enumeratedValues>
                        </field>
                        <field>
                            <name>TEDGF</name>
                            <description>Active Edge Judgment Flag</description>
                            <lsb>4</lsb>
                            <msb>4</msb>
                            <access>read-write</access>
                            <enumeratedValues>
                                </enumeratedValues>
                        </field>
                        <field>
                            <name>TUNDF</name>
                            <description>Underflow Flag</description>
                            <lsb>5</lsb>
                            <msb>5</msb>
                            <access>read-write</access>
                            <enumeratedValues>
                                </enumeratedValues>
                        </field>
                        <field>
                            <name>TCMAF</name>
                            <description>Compare Match A Flag</description>
                            <lsb>6</lsb>
                            <msb>6</msb>
                            <access>read-write</access>
                            <enumeratedValues>
                                </enumeratedValues>
                        </field>
                        <field>
                            <name>TCMBF</name>
                            <description>Compare Match B Flag</description>
                            <lsb>7</lsb>
                            <msb>7</msb>
                            <access>read-write</access>
                            <enumeratedValues>
                                </enumeratedValues>
                        </field>
                    </fields>
                </register>
                <register>
                    <name>AGTMR1</name>
                    <description>AGT Mode Register 1</description>
                    <addressOffset>0x09</addressOffset>
                    <size>8</size>
                    <access>read-write</access>
                    <resetValue>0x00</resetValue>
                    <resetMask>0xff</resetMask>
                    <fields>
                        <field>
                            <name>TMOD</name>
                            <description>Operating Mode</description>
                            <lsb>0</lsb>
                            <msb>2</msb>
                            <access>read-write</access>
                            <enumeratedValues>
                                </enumeratedValues>
                        </field>
                        <field>
                            <name>TEDGPL</name>
                            <description>Edge Polarity</description>
                            <lsb>3</lsb>
                            <msb>3</msb>
                            <access>read-write</access>
                            <enumeratedValues>
                                </enumeratedValues>
                        </field>
                        <field>
                            <name>TCK</name>
                            <description>Count Source</description>
                            <lsb>4</lsb>
                            <msb>6</msb>
                            <access>read-write</access>
                            <enumeratedValues>
                                </enumeratedValues>
                        </field>
                    </fields>
                </register>
                <register>
                    <name>AGTMR2</name>
                    <description>AGT Mode Register 2</description>
                    <addressOffset>0x0A</addressOffset>
                    <size>8</size>
                    <access>read-write</access>
                    <resetValue>0x00</resetValue>
                    <resetMask>0xff</resetMask>
                    <fields>
                        <field>
                            <name>CKS</name>
                            <description>AGTLCLK or AGTSCLK Count Source Clock Frequency Division Ratio</description>
                            <lsb>0</lsb>
                            <msb>2</msb>
                            <access>read-write</access>
                            <enumeratedValues>
                                </enumeratedValues>
                        </field>
                        <field>
                            <name>LPM</name>
                            <description>Low Power Mode</description>
                            <lsb>7</lsb>
                            <msb>7</msb>
                            <access>read-write</access>
                            <enumeratedValues>
                                </enumeratedValues>
                        </field>
                    </fields>
                </register>
                <register>
                    <name>AGTIOC</name>
                    <description>AGT I/O Control Register</description>
                    <addressOffset>0x0C</addressOffset>
                    <size>8</size>
                    <access>read-write</access>
                    <resetValue>0x00</resetValue>
                    <resetMask>0xff</resetMask>
                    <fields>
                        <field>
                            <name>TEDGSEL</name>
                            <description>I/O Polarity Switch</description>
                            <lsb>0</lsb>
                            <msb>0</msb>
                            <access>read-write</access>
                        </field>
                        <field>
                            <name>TOE</name>
                            <description>AGTOn pin Output Enable</description>
                            <lsb>2</lsb>
                            <msb>2</msb>
                            <access>read-write</access>
                            <enumeratedValues>
                                </enumeratedValues>
                        </field>
                        <field>
                            <name>TIPF</name>
                            <description>Input Filter</description>
                            <lsb>4</lsb>
                            <msb>5</msb>
                            <access>read-write</access>
                            <enumeratedValues>
                                </enumeratedValues>
                        </field>
                        <field>
                            <name>TIOGT</name>
                            <description>Count Control</description>
                            <lsb>6</lsb>
                            <msb>7</msb>
                            <access>read-write</access>
                            <enumeratedValues>
                                </enumeratedValues>
                        </field>
                    </fields>
                </register>
                <register>
                    <name>AGTISR</name>
                    <description>AGT Event Pin Select Register</description>
                    <addressOffset>0x0D</addressOffset>
                    <size>8</size>
                    <access>read-write</access>
                    <resetValue>0x00</resetValue>
                    <resetMask>0xff</resetMask>
                    <fields>
                        <field>
                            <name>EEPS</name>
                            <description>AGTEEn Polarity Selection</description>
                            <lsb>2</lsb>
                            <msb>2</msb>
                            <access>read-write</access>
                            <enumeratedValues>
                                </enumeratedValues>
                        </field>
                    </fields>
                </register>
                <register>
                    <name>AGTCMSR</name>
                    <description>AGT Compare Match Function Select Register</description>
                    <addressOffset>0x0E</addressOffset>
                    <size>8</size>
                    <access>read-write</access>
                    <resetValue>0x00</resetValue>
                    <resetMask>0xff</resetMask>
                    <fields>
                        <field>
                            <name>TCMEA</name>
                            <description>AGT Compare Match A Register Enable</description>
                            <lsb>0</lsb>
                            <msb>0</msb>
                            <access>read-write</access>
                            <enumeratedValues>
                                </enumeratedValues>
                        </field>
                        <field>
                            <name>TOEA</name>
                            <description>AGTOAn Pin Output Enable</description>
                            <lsb>1</lsb>
                            <msb>1</msb>
                            <access>read-write</access>
                            <enumeratedValues>
                                </enumeratedValues>
                        </field>
                        <field>
                            <name>TOPOLA</name>
                            <description>AGTOAn Pin Polarity Select</description>
                            <lsb>2</lsb>
                            <msb>2</msb>
                            <access>read-write</access>
                            <enumeratedValues>
                                </enumeratedValues>
                        </field>
                        <field>
                            <name>TCMEB</name>
                            <description>AGT Compare Match B Register Enable</description>
                            <lsb>4</lsb>
                            <msb>4</msb>
                            <access>read-write</access>
                            <enumeratedValues>
                                </enumeratedValues>
                        </field>
                        <field>
                            <name>TOEB</name>
                            <description>AGTOBn Pin Output Enable</description>
                            <lsb>5</lsb>
                            <msb>5</msb>
                            <access>read-write</access>
                            <enumeratedValues>
                                </enumeratedValues>
                        </field>
                        <field>
                            <name>TOPOLB</name>
                            <description>AGTOBn Pin Polarity Select</description>
                            <lsb>6</lsb>
                            <msb>6</msb>
                            <access>read-write</access>
                            <enumeratedValues>
                                </enumeratedValues>
                        </field>
                    </fields>
                </register>
                <register>
                    <name>AGTIOSEL</name>
                    <description>AGT Pin Select Register</description>
                    <addressOffset>0x0F</addressOffset>
                    <size>8</size>
                    <access>read-write</access>
                    <resetValue>0x00</resetValue>
                    <resetMask>0xff</resetMask>
                    <fields>
                        <field>
                            <name>SEL</name>
                            <description>AGTIOn Pin Select</description>
                            <lsb>0</lsb>
                            <msb>1</msb>
                            <access>read-write</access>
                            <enumeratedValues>
                                </enumeratedValues>
                        </field>
                        <field>
                            <name>TIES</name>
                            <description>AGTIOn Pin Input Enable</description>
                            <lsb>4</lsb>
                            <msb>4</msb>
                            <access>read-write</access>
                            <enumeratedValues>
                                </enumeratedValues>
                        </field>
                    </fields>
                </register>
            </registers>
        </peripheral>
        <peripheral derivedFrom="AGT0">
            <name>AGT1</name>
            <description>Low Power Asynchronous General Purpose Timer 1</description>
            <baseAddress>0x400E8100</baseAddress>
        </peripheral>
        <peripheral derivedFrom="AGT0">
            <name>AGT2</name>
            <description>Low Power Asynchronous General Purpose Timer 2</description>
            <baseAddress>0x400E8200</baseAddress>
        </peripheral>
        <peripheral derivedFrom="AGT0">
            <name>AGT3</name>
            <description>Low Power Asynchronous General Purpose Timer 3</description>
            <baseAddress>0x400E8300</baseAddress>
        </peripheral>
        <peripheral derivedFrom="AGT0">
            <name>AGT4</name>
            <description>Low Power Asynchronous General Purpose Timer 4</description>
            <baseAddress>0x400E8400</baseAddress>
        </peripheral>
        <peripheral derivedFrom="AGT0">
            <name>AGT5</name>
            <description>Low Power Asynchronous General Purpose Timer 5</description>
            <baseAddress>0x400E8500</baseAddress>
        </peripheral>
        <peripheral>
            <name>TSN</name>
            <description>Temperature Sensor</description>
            <baseAddress>0x400F3000</baseAddress>
            <addressBlock>
                <offset>0x00</offset>
                <size>1</size>
                <usage>registers</usage>
            </addressBlock>
            <registers>
                <register>
                    <name>TSCR</name>
                    <description>Temperature Sensor Control Register</description>
                    <addressOffset>0x00</addressOffset>
                    <size>8</size>
                    <access>read-write</access>
                    <resetValue>0x00</resetValue>
                    <resetMask>0xff</resetMask>
                    <fields>
                        <field>
                            <name>TSOE</name>
                            <description>Temperature Sensor Output Enable</description>
                            <lsb>4</lsb>
                            <msb>4</msb>
                            <access>read-write</access>
                            <enumeratedValues>
                                </enumeratedValues>
                        </field>
                        <field>
                            <name>TSEN</name>
                            <description>Temperature Sensor Enable</description>
                            <lsb>7</lsb>
                            <msb>7</msb>
                            <access>read-write</access>
                            <enumeratedValues>
                                </enumeratedValues>
                        </field>
                    </fields>
                </register>
            </registers>
        </peripheral>
        <peripheral>
            <name>CRC</name>
            <description>Cyclic Redundancy Check Calculator</description>
            <baseAddress>0x40108000</baseAddress>
            <addressBlock>
                <offset>0x00</offset>
                <size>1</size>
                <usage>registers</usage>
            </addressBlock>
            <addressBlock>
                <offset>0x04</offset>
                <size>4</size>
                <usage>registers</usage>
            </addressBlock>
            <addressBlock>
                <offset>0x08</offset>
                <size>4</size>
                <usage>registers</usage>
            </addressBlock>
            <registers>
                <register>
                    <name>CRCCR0</name>
                    <description>CRC Control Register 0</description>
                    <addressOffset>0x00</addressOffset>
                    <size>8</size>
                    <access>read-write</access>
                    <resetValue>0x00</resetValue>
                    <resetMask>0xff</resetMask>
                    <fields>
                        <field>
                            <name>GPS</name>
                            <description>CRC Generating Polynomial Switching</description>
                            <lsb>0</lsb>
                            <msb>2</msb>
                            <access>read-write</access>
                            <enumeratedValues>
                                </enumeratedValues>
                        </field>
                        <field>
                            <name>LMS</name>
                            <description>CRC Calculation Switching</description>
                            <lsb>6</lsb>
                            <msb>6</msb>
                            <access>read-write</access>
                            <enumeratedValues>
                                </enumeratedValues>
                        </field>
                        <field>
                            <name>DORCLR</name>
                            <description>CRCDOR/CRCDOR_HA/CRCDOR_BY Register Clear</description>
                            <lsb>7</lsb>
                            <msb>7</msb>
                            <access>write-only</access>
                            <enumeratedValues>
                                </enumeratedValues>
                        </field>
                    </fields>
                </register>
                <register>
                    <name>CRCDIR</name>
                    <description>CRC Data Input Register</description>
                    <addressOffset>0x04</addressOffset>
                    <size>32</size>
                    <access>read-write</access>
                    <resetValue>0x00000000</resetValue>
                    <resetMask>0xffffffff</resetMask>
                </register>
                <register>
                    <name>CRCDIR_BY</name>
                    <description>CRC Data Input Register</description>
                    <alternateRegister>CRCDIR</alternateRegister>
                    <addressOffset>0x04</addressOffset>
                    <size>8</size>
                    <access>read-write</access>
                    <resetValue>0x00</resetValue>
                    <resetMask>0xff</resetMask>
                </register>
                <register>
                    <name>CRCDOR</name>
                    <description>CRC Data Output Register</description>
                    <addressOffset>0x08</addressOffset>
                    <size>32</size>
                    <access>read-write</access>
                    <resetValue>0x00000000</resetValue>
                    <resetMask>0xffffffff</resetMask>
                </register>
                <register>
                    <name>CRCDOR_HA</name>
                    <description>CRC Data Output Register</description>
                    <alternateRegister>CRCDOR</alternateRegister>
                    <addressOffset>0x08</addressOffset>
                    <size>16</size>
                    <access>read-write</access>
                    <resetValue>0x0000</resetValue>
                    <resetMask>0xffff</resetMask>
                </register>
                <register>
                    <name>CRCDOR_BY</name>
                    <description>CRC Data Output Register</description>
                    <alternateRegister>CRCDOR</alternateRegister>
                    <addressOffset>0x08</addressOffset>
                    <size>8</size>
                    <access>read-write</access>
                    <resetValue>0x00</resetValue>
                    <resetMask>0xff</resetMask>
                </register>
            </registers>
        </peripheral>
        <peripheral>
            <name>DOC</name>
            <description>Data Operation Circuit</description>
            <baseAddress>0x40109000</baseAddress>
            <addressBlock>
                <offset>0x00</offset>
                <size>1</size>
                <usage>registers</usage>
            </addressBlock>
            <addressBlock>
                <offset>0x02</offset>
                <size>4</size>
                <usage>registers</usage>
            </addressBlock>
            <registers>
                <register>
                    <name>DOCR</name>
                    <description>DOC Control Register</description>
                    <addressOffset>0x00</addressOffset>
                    <size>8</size>
                    <access>read-write</access>
                    <resetValue>0x00</resetValue>
                    <resetMask>0xff</resetMask>
                    <fields>
                        <field>
                            <name>OMS</name>
                            <description>Operating Mode Select</description>
                            <lsb>0</lsb>
                            <msb>1</msb>
                            <access>read-write</access>
                            <enumeratedValues>
                                </enumeratedValues>
                        </field>
                        <field>
                            <name>DCSEL</name>
                            <description>Detection Condition Select</description>
                            <lsb>2</lsb>
                            <msb>2</msb>
                            <access>read-write</access>
                            <enumeratedValues>
                                </enumeratedValues>
                        </field>
                        <field>
                            <name>DOPCF</name>
                            <description>DOC Flag</description>
                            <lsb>5</lsb>
                            <msb>5</msb>
                            <access>read-only</access>
                        </field>
                        <field>
                            <name>DOPCFCL</name>
                            <description>DOPCF Clear</description>
                            <lsb>6</lsb>
                            <msb>6</msb>
                            <access>read-write</access>
                            <enumeratedValues>
                                </enumeratedValues>
                        </field>
                    </fields>
                </register>
                <register>
                    <name>DODIR</name>
                    <description>DOC Data Input Register</description>
                    <addressOffset>0x02</addressOffset>
                    <size>16</size>
                    <access>read-write</access>
                    <resetValue>0x0000</resetValue>
                    <resetMask>0xffff</resetMask>
                </register>
                <register>
                    <name>DODSR</name>
                    <description>DOC Data Setting Register</description>
                    <addressOffset>0x04</addressOffset>
                    <size>16</size>
                    <access>read-write</access>
                    <resetValue>0x0000</resetValue>
                    <resetMask>0xffff</resetMask>
                </register>
            </registers>
        </peripheral>
        <peripheral>
            <name>USBHS</name>
            <description>USB 2.0 High,Speed Module</description>
            <baseAddress>0x40111000</baseAddress>
            <addressBlock>
                <offset>0x00</offset>
                <size>10</size>
                <usage>registers</usage>
            </addressBlock>
            <addressBlock>
                <offset>0x0C</offset>
                <size>2</size>
                <usage>registers</usage>
            </addressBlock>
            <addressBlock>
                <offset>0x14</offset>
                <size>8</size>
                <usage>registers</usage>
            </addressBlock>
            <addressBlock>
                <offset>0x20</offset>
                <size>4</size>
                <usage>registers</usage>
            </addressBlock>
            <addressBlock>
                <offset>0x28</offset>
                <size>12</size>
                <usage>registers</usage>
            </addressBlock>
            <addressBlock>
                <offset>0x36</offset>
                <size>14</size>
                <usage>registers</usage>
            </addressBlock>
            <addressBlock>
                <offset>0x46</offset>
                <size>12</size>
                <usage>registers</usage>
            </addressBlock>
            <addressBlock>
                <offset>0x54</offset>
                <size>14</size>
                <usage>registers</usage>
            </addressBlock>
            <addressBlock>
                <offset>0x64</offset>
                <size>2</size>
                <usage>registers</usage>
            </addressBlock>
            <addressBlock>
                <offset>0x68</offset>
                <size>62</size>
                <usage>registers</usage>
            </addressBlock>
            <addressBlock>
                <offset>0xD0</offset>
                <size>22</size>
                <usage>registers</usage>
            </addressBlock>
            <addressBlock>
                <offset>0x100</offset>
                <size>4</size>
                <usage>registers</usage>
            </addressBlock>
            <addressBlock>
                <offset>0x140</offset>
                <size>2</size>
                <usage>registers</usage>
            </addressBlock>
            <addressBlock>
                <offset>0x144</offset>
                <size>8</size>
                <usage>registers</usage>
            </addressBlock>
            <addressBlock>
                <offset>0x160</offset>
                <size>12</size>
                <usage>registers</usage>
            </addressBlock>
            <registers>
                <register>
                    <name>SYSCFG</name>
                    <description>System Configuration Control Register</description>
                    <addressOffset>0x000</addressOffset>
                    <size>16</size>
                    <access>read-write</access>
                    <resetValue>0x0020</resetValue>
                    <resetMask>0x01f1</resetMask>
                    <fields>
                        <field>
                            <name>USBE</name>
                            <description>USBHS Operation Enable</description>
                            <lsb>0</lsb>
                            <msb>0</msb>
                            <access>read-write</access>
                            <enumeratedValues>
                                </enumeratedValues>
                        </field>
                        <field>
                            <name>DPRPU</name>
                            <description>D+ Line Resistor Control</description>
                            <lsb>4</lsb>
                            <msb>4</msb>
                            <access>read-write</access>
                            <enumeratedValues>
                                </enumeratedValues>
                        </field>
                        <field>
                            <name>DRPD</name>
                            <description>D+/D- Line Resistor Control</description>
                            <lsb>5</lsb>
                            <msb>5</msb>
                            <access>read-write</access>
                            <enumeratedValues>
                                </enumeratedValues>
                        </field>
                        <field>
                            <name>DCFM</name>
                            <description>Controller Operation Select</description>
                            <lsb>6</lsb>
                            <msb>6</msb>
                            <access>read-write</access>
                            <enumeratedValues>
                                </enumeratedValues>
                        </field>
                        <field>
                            <name>HSE</name>
                            <description>High,Speed Operation Enable</description>
                            <lsb>7</lsb>
                            <msb>7</msb>
                            <access>read-write</access>
                            <enumeratedValues>
                                </enumeratedValues>
                        </field>
                        <field>
                            <name>CNEN</name>
                            <description>Single,ended Receiver Enable</description>
                            <lsb>8</lsb>
                            <msb>8</msb>
                            <access>read-write</access>
                            <enumeratedValues>
                                </enumeratedValues>
                        </field>
                    </fields>
                </register>
                <register>
                    <name>BUSWAIT</name>
                    <description>CPU Bus Wait Register</description>
                    <addressOffset>0x002</addressOffset>
                    <size>16</size>
                    <access>read-write</access>
                    <resetValue>0x000f</resetValue>
                    <resetMask>0x3f3f</resetMask>
                    <fields>
                        <field>
                            <name>BWAIT</name>
                            <description>CPU Bus Access Wait Specification</description>
                            <lsb>0</lsb>
                            <msb>3</msb>
                            <access>read-write</access>
                        </field>
                    </fields>
                </register>
                <register>
                    <name>SYSSTS0</name>
                    <description>System Configuration Status Register</description>
                    <addressOffset>0x004</addressOffset>
                    <size>16</size>
                    <access>read-only</access>
                    <resetValue>0x0000</resetValue>
                    <resetMask>0x0060</resetMask>
                    <fields>
                        <field>
                            <name>LNST</name>
                            <description>USB Data Line Status Monitor Flag</description>
                            <lsb>0</lsb>
                            <msb>1</msb>
                            <access>read-only</access>
                        </field>
                        <field>
                            <name>IDMON</name>
                            <description>USBHS_ID Pin Monitor Flag</description>
                            <lsb>2</lsb>
                            <msb>2</msb>
                            <access>read-only</access>
                            <enumeratedValues>
                                </enumeratedValues>
                        </field>
                        <field>
                            <name>SOFEA</name>
                            <description>SOF Active Monitor Flag While Host Controller Operation Is Selected</description>
                            <lsb>5</lsb>
                            <msb>5</msb>
                            <access>read-only</access>
                            <enumeratedValues>
                                </enumeratedValues>
                        </field>
                        <field>
                            <name>HTACT</name>
                            <description>Host Sequencer Status Monitor Flag</description>
                            <lsb>6</lsb>
                            <msb>6</msb>
                            <access>read-only</access>
                            <enumeratedValues>
                                </enumeratedValues>
                        </field>
                        <field>
                            <name>OVCMON</name>
                            <description>External USBHS_OVRCURA/USBHS_O VRCURB Input Pin Monitor Flag</description>
                            <lsb>14</lsb>
                            <msb>15</msb>
                            <access>read-only</access>
                        </field>
                    </fields>
                </register>
                <register>
                    <name>PLLSTA</name>
                    <description>PLL Status Register</description>
                    <addressOffset>0x006</addressOffset>
                    <size>16</size>
                    <access>read-only</access>
                    <resetValue>0x0000</resetValue>
                    <resetMask>0x0001</resetMask>
                    <fields>
                        <field>
                            <name>PLLLOCK</name>
                            <description>PLL Lock Flag</description>
                            <lsb>0</lsb>
                            <msb>0</msb>
                            <access>read-only</access>
                            <enumeratedValues>
                                </enumeratedValues>
                        </field>
                    </fields>
                </register>
                <register>
                    <name>DVSTCTR0</name>
                    <description>Device State Control Register 0</description>
                    <addressOffset>0x008</addressOffset>
                    <size>16</size>
                    <access>read-write</access>
                    <resetValue>0x0000</resetValue>
                    <resetMask>0x0ff7</resetMask>
                    <fields>
                        <field>
                            <name>RHST</name>
                            <description>USB Bus Reset Status Flag</description>
                            <lsb>0</lsb>
                            <msb>2</msb>
                            <access>read-only</access>
                            <enumeratedValues>
                                </enumeratedValues>
                        </field>
                        <field>
                            <name>UACT</name>
                            <description>USB Bus Operation Enable for the Host Controller Operation</description>
                            <lsb>4</lsb>
                            <msb>4</msb>
                            <access>read-write</access>
                            <enumeratedValues>
                                </enumeratedValues>
                        </field>
                        <field>
                            <name>RESUME</name>
                            <description>Resume Signal Output for the Host Controller Operation</description>
                            <lsb>5</lsb>
                            <msb>5</msb>
                            <access>read-write</access>
                            <enumeratedValues>
                                </enumeratedValues>
                        </field>
                        <field>
                            <name>USBRST</name>
                            <description>USB Bus Reset Output for the Host Controller Operation</description>
                            <lsb>6</lsb>
                            <msb>6</msb>
                            <access>read-write</access>
                            <enumeratedValues>
                                </enumeratedValues>
                        </field>
                        <field>
                            <name>RWUPE</name>
                            <description>Remote Wakeup Detection Enable for the Host Controller Operation</description>
                            <lsb>7</lsb>
                            <msb>7</msb>
                            <access>read-write</access>
                            <enumeratedValues>
                                </enumeratedValues>
                        </field>
                        <field>
                            <name>WKUP</name>
                            <description>Remote Wakeup Output for the Device Controller Operation</description>
                            <lsb>8</lsb>
                            <msb>8</msb>
                            <access>read-write</access>
                            <enumeratedValues>
                                </enumeratedValues>
                        </field>
                        <field>
                            <name>VBUSEN</name>
                            <description>USBHS_VBUSEN Output Pin Control</description>
                            <lsb>9</lsb>
                            <msb>9</msb>
                            <access>read-write</access>
                            <enumeratedValues>
                                </enumeratedValues>
                        </field>
                        <field>
                            <name>EXICEN</name>
                            <description>USBHS_EXICEN Output Pin Control</description>
                            <lsb>10</lsb>
                            <msb>10</msb>
                            <access>read-write</access>
                            <enumeratedValues>
                                </enumeratedValues>
                        </field>
                        <field>
                            <name>HNPBTOA</name>
                            <description>Host Negotiation Protocol (HNP) Control</description>
                            <lsb>11</lsb>
                            <msb>11</msb>
                            <access>read-write</access>
                        </field>
                    </fields>
                </register>
                <register>
                    <name>TESTMODE</name>
                    <description>USB Test Mode Register</description>
                    <addressOffset>0x00C</addressOffset>
                    <size>16</size>
                    <access>read-write</access>
                    <resetValue>0x0000</resetValue>
                    <resetMask>0x000f</resetMask>
                    <fields>
                        <field>
                            <name>UTST</name>
                            <description>Test Mode</description>
                            <lsb>0</lsb>
                            <msb>3</msb>
                            <access>read-write</access>
                        </field>
                    </fields>
                </register>
                <register>
                    <name>CFIFO</name>
                    <description>FIFO Port Register</description>
                    <addressOffset>0x014</addressOffset>
                    <size>32</size>
                    <access>read-write</access>
                    <resetValue>0x00000000</resetValue>
                    <resetMask>0xffffffff</resetMask>
                    <fields>
                        <field>
                            <name>FIFOPORT</name>
                            <description>Read receive data from the FIFO buffer or write transmit data to the FIFO buffer by accessing these bits.</description>
                            <lsb>0</lsb>
                            <msb>31</msb>
                            <access>read-write</access>
                        </field>
                    </fields>
                </register>
                <register>
                    <name>CFIFOL</name>
                    <description>FIFO Port Register</description>
                    <alternateRegister>CFIFO</alternateRegister>
                    <addressOffset>0x014</addressOffset>
                    <size>16</size>
                    <access>read-write</access>
                    <resetValue>0x0000</resetValue>
                    <resetMask>0xffff</resetMask>
                </register>
                <register>
                    <name>CFIFOLL</name>
                    <description>FIFO Port Register</description>
                    <alternateRegister>CFIFO</alternateRegister>
                    <addressOffset>0x014</addressOffset>
                    <size>8</size>
                    <access>read-write</access>
                    <resetValue>0x00</resetValue>
                    <resetMask>0xff</resetMask>
                </register>
                <register>
                    <name>CFIFOH</name>
                    <description>FIFO Port Register</description>
                    <alternateRegister>CFIFO</alternateRegister>
                    <addressOffset>0x016</addressOffset>
                    <size>16</size>
                    <access>read-write</access>
                    <resetValue>0x0000</resetValue>
                    <resetMask>0xffff</resetMask>
                    <fields>
                        <field>
                            <name>FIFOPORT</name>
                            <description>Read receive data from the FIFO buffer or write transmit data to the FIFO buffer by accessing these bits.</description>
                            <lsb>0</lsb>
                            <msb>15</msb>
                            <access>read-write</access>
                        </field>
                    </fields>
                </register>
                <register>
                    <name>CFIFOHH</name>
                    <description>FIFO Port Register</description>
                    <alternateRegister>CFIFO</alternateRegister>
                    <addressOffset>0x017</addressOffset>
                    <size>8</size>
                    <access>read-write</access>
                    <resetValue>0x00</resetValue>
                    <resetMask>0xff</resetMask>
                    <fields>
                        <field>
                            <name>FIFOPORT</name>
                            <description>Read receive data from the FIFO buffer or write transmit data to the FIFO buffer by accessing these bits.</description>
                            <lsb>0</lsb>
                            <msb>7</msb>
                            <access>read-write</access>
                        </field>
                    </fields>
                </register>
                <register>
                    <name>D0FIFO</name>
                    <description>FIFO Port Register</description>
                    <addressOffset>0x018</addressOffset>
                    <size>32</size>
                    <access>read-write</access>
                    <resetValue>0x00000000</resetValue>
                    <resetMask>0xffffffff</resetMask>
                    <fields>
                        <field>
                            <name>FIFOPORT</name>
                            <description>Read receive data from the FIFO buffer or write transmit data to the FIFO buffer by accessing these bits.</description>
                            <lsb>0</lsb>
                            <msb>31</msb>
                            <access>read-write</access>
                        </field>
                    </fields>
                </register>
                <register>
                    <name>D1FIFO</name>
                    <description>FIFO Port Register</description>
                    <alternateRegister>D0FIFO</alternateRegister>
                    <addressOffset>0x018</addressOffset>
                    <size>32</size>
                    <access>read-write</access>
                    <resetValue>0x00000000</resetValue>
                    <resetMask>0xffffffff</resetMask>
                    <fields>
                        <field>
                            <name>FIFOPORT</name>
                            <description>Read receive data from the FIFO buffer or write transmit data to the FIFO buffer by accessing these bits.</description>
                            <lsb>0</lsb>
                            <msb>31</msb>
                            <access>read-write</access>
                        </field>
                    </fields>
                </register>
                <register>
                    <name>D0FIFOL</name>
                    <description>FIFO Port Register</description>
                    <alternateRegister>D0FIFO</alternateRegister>
                    <addressOffset>0x018</addressOffset>
                    <size>16</size>
                    <access>read-write</access>
                    <resetValue>0x0000</resetValue>
                    <resetMask>0xffff</resetMask>
                </register>
                <register>
                    <name>D1FIFOL</name>
                    <description>FIFO Port Register</description>
                    <alternateRegister>D0FIFO</alternateRegister>
                    <addressOffset>0x018</addressOffset>
                    <size>16</size>
                    <access>read-write</access>
                    <resetValue>0x0000</resetValue>
                    <resetMask>0xffff</resetMask>
                </register>
                <register>
                    <name>D0FIFOLL</name>
                    <description>FIFO Port Register</description>
                    <alternateRegister>D0FIFO</alternateRegister>
                    <addressOffset>0x018</addressOffset>
                    <size>8</size>
                    <access>read-write</access>
                    <resetValue>0x00</resetValue>
                    <resetMask>0xff</resetMask>
                </register>
                <register>
                    <name>D1FIFOLL</name>
                    <description>FIFO Port Register</description>
                    <alternateRegister>D0FIFO</alternateRegister>
                    <addressOffset>0x018</addressOffset>
                    <size>8</size>
                    <access>read-write</access>
                    <resetValue>0x00</resetValue>
                    <resetMask>0xff</resetMask>
                </register>
                <register>
                    <name>D0FIFOH</name>
                    <description>FIFO Port Register</description>
                    <alternateRegister>D0FIFO</alternateRegister>
                    <addressOffset>0x01A</addressOffset>
                    <size>16</size>
                    <access>read-write</access>
                    <resetValue>0x0000</resetValue>
                    <resetMask>0xffff</resetMask>
                    <fields>
                        <field>
                            <name>FIFOPORT</name>
                            <description>Read receive data from the FIFO buffer or write transmit data to the FIFO buffer by accessing these bits.</description>
                            <lsb>0</lsb>
                            <msb>15</msb>
                            <access>read-write</access>
                        </field>
                    </fields>
                </register>
                <register>
                    <name>D1FIFOH</name>
                    <description>FIFO Port Register</description>
                    <alternateRegister>D0FIFOH</alternateRegister>
                    <addressOffset>0x01A</addressOffset>
                    <size>16</size>
                    <access>read-write</access>
                    <resetValue>0x0000</resetValue>
                    <resetMask>0xffff</resetMask>
                    <fields>
                        <field>
                            <name>FIFOPORT</name>
                            <description>Read receive data from the FIFO buffer or write transmit data to the FIFO buffer by accessing these bits.</description>
                            <lsb>0</lsb>
                            <msb>15</msb>
                            <access>read-write</access>
                        </field>
                    </fields>
                </register>
                <register>
                    <name>D0FIFOHH</name>
                    <description>FIFO Port Register</description>
                    <alternateRegister>D0FIFO</alternateRegister>
                    <addressOffset>0x01B</addressOffset>
                    <size>8</size>
                    <access>read-write</access>
                    <resetValue>0x00</resetValue>
                    <resetMask>0xff</resetMask>
                    <fields>
                        <field>
                            <name>FIFOPORT</name>
                            <description>Read receive data from the FIFO buffer or write transmit data to the FIFO buffer by accessing these bits.</description>
                            <lsb>0</lsb>
                            <msb>7</msb>
                            <access>read-write</access>
                        </field>
                    </fields>
                </register>
                <register>
                    <name>D1FIFOHH</name>
                    <description>FIFO Port Register</description>
                    <alternateRegister>D0FIFOHH</alternateRegister>
                    <addressOffset>0x01B</addressOffset>
                    <size>8</size>
                    <access>read-write</access>
                    <resetValue>0x00</resetValue>
                    <resetMask>0xff</resetMask>
                    <fields>
                        <field>
                            <name>FIFOPORT</name>
                            <description>Read receive data from the FIFO buffer or write transmit data to the FIFO buffer by accessing these bits.</description>
                            <lsb>0</lsb>
                            <msb>7</msb>
                            <access>read-write</access>
                        </field>
                    </fields>
                </register>
                <register>
                    <name>CFIFOSEL</name>
                    <description>CFIFO Port Selection Register</description>
                    <addressOffset>0x020</addressOffset>
                    <size>16</size>
                    <access>read-write</access>
                    <resetValue>0x0000</resetValue>
                    <resetMask>0xcd2f</resetMask>
                    <fields>
                        <field>
                            <name>CURPIPE</name>
                            <description>FIFO Port Access Pipe Specification</description>
                            <lsb>0</lsb>
                            <msb>3</msb>
                            <access>read-write</access>
                            <enumeratedValues>
                                </enumeratedValues>
                        </field>
                        <field>
                            <name>ISEL</name>
                            <description>FIFO Port Access Direction when DCP Is Selected</description>
                            <lsb>5</lsb>
                            <msb>5</msb>
                            <access>read-write</access>
                            <enumeratedValues>
                                </enumeratedValues>
                        </field>
                        <field>
                            <name>BIGEND</name>
                            <description>FIFO Port Endian Control</description>
                            <lsb>8</lsb>
                            <msb>8</msb>
                            <access>read-write</access>
                            <enumeratedValues>
                                </enumeratedValues>
                        </field>
                        <field>
                            <name>MBW</name>
                            <description>CFIFO Port Access Bit Width</description>
                            <lsb>10</lsb>
                            <msb>11</msb>
                            <access>read-write</access>
                            <enumeratedValues>
                                </enumeratedValues>
                        </field>
                        <field>
                            <name>REW</name>
                            <description>Buffer Pointer Rewind</description>
                            <lsb>14</lsb>
                            <msb>14</msb>
                            <access>write-only</access>
                            <enumeratedValues>
                                </enumeratedValues>
                        </field>
                        <field>
                            <name>RCNT</name>
                            <description>Read Count Mode</description>
                            <lsb>15</lsb>
                            <msb>15</msb>
                            <access>read-write</access>
                            <enumeratedValues>
                                </enumeratedValues>
                        </field>
                    </fields>
                </register>
                <register>
                    <name>CFIFOCTR</name>
                    <description>FIFO Port Control Register</description>
                    <addressOffset>0x022</addressOffset>
                    <size>16</size>
                    <access>read-write</access>
                    <resetValue>0x0000</resetValue>
                    <resetMask>0xefff</resetMask>
                    <fields>
                        <field>
                            <name>DTLN</name>
                            <description>Receive Data Length Flag</description>
                            <lsb>0</lsb>
                            <msb>11</msb>
                            <access>read-only</access>
                        </field>
                        <field>
                            <name>FRDY</name>
                            <description>FIFO Port Ready Flag</description>
                            <lsb>13</lsb>
                            <msb>13</msb>
                            <access>read-only</access>
                            <enumeratedValues>
                                </enumeratedValues>
                        </field>
                        <field>
                            <name>BCLR</name>
                            <description>CPU Buffer Clear</description>
                            <lsb>14</lsb>
                            <msb>14</msb>
                            <access>write-only</access>
                            <enumeratedValues>
                                </enumeratedValues>
                        </field>
                        <field>
                            <name>BVAL</name>
                            <description>FIFO Buffer Valid Flag</description>
                            <lsb>15</lsb>
                            <msb>15</msb>
                            <access>read-write</access>
                            <enumeratedValues>
                                </enumeratedValues>
                        </field>
                    </fields>
                </register>
                <register>
                    <dim>2</dim>
                    <dimIncrement>0x4</dimIncrement>
                    <dimIndex>0-1</dimIndex>
                    <name>D%sFIFOSEL</name>
                    <description>D%sFIFO Port Selection Register</description>
                    <addressOffset>0x028</addressOffset>
                    <size>16</size>
                    <access>read-write</access>
                    <resetValue>0x0000</resetValue>
                    <resetMask>0xfd0f</resetMask>
                    <fields>
                        <field>
                            <name>CURPIPE</name>
                            <description>FIFO Port Access Pipe Specification</description>
                            <lsb>0</lsb>
                            <msb>3</msb>
                            <access>read-write</access>
                            <enumeratedValues>
                                </enumeratedValues>
                        </field>
                        <field>
                            <name>BIGEND</name>
                            <description>FIFO Port Endian Control</description>
                            <lsb>8</lsb>
                            <msb>8</msb>
                            <access>read-write</access>
                            <enumeratedValues>
                                </enumeratedValues>
                        </field>
                        <field>
                            <name>MBW</name>
                            <description>FIFO Port Access Bit Width</description>
                            <lsb>10</lsb>
                            <msb>11</msb>
                            <access>read-write</access>
                            <enumeratedValues>
                                </enumeratedValues>
                        </field>
                        <field>
                            <name>DREQE</name>
                            <description>DMA/DTC Transfer Request Enable</description>
                            <lsb>12</lsb>
                            <msb>12</msb>
                            <access>read-write</access>
                            <enumeratedValues>
                                </enumeratedValues>
                        </field>
                        <field>
                            <name>DCLRM</name>
                            <description>Auto FIFO Buffer Clear Mode after Specified Pipe is Read</description>
                            <lsb>13</lsb>
                            <msb>13</msb>
                            <access>read-write</access>
                            <enumeratedValues>
                                </enumeratedValues>
                        </field>
                        <field>
                            <name>REW</name>
                            <description>Buffer Pointer Rewind</description>
                            <lsb>14</lsb>
                            <msb>14</msb>
                            <access>write-only</access>
                            <enumeratedValues>
                                </enumeratedValues>
                        </field>
                        <field>
                            <name>RCNT</name>
                            <description>Read Count Mode</description>
                            <lsb>15</lsb>
                            <msb>15</msb>
                            <access>read-write</access>
                            <enumeratedValues>
                                </enumeratedValues>
                        </field>
                    </fields>
                </register>
                <register>
                    <dim>2</dim>
                    <dimIncrement>0x4</dimIncrement>
                    <dimIndex>0-1</dimIndex>
                    <name>D%sFIFOCTR</name>
                    <description>FIFO Port Control Register</description>
                    <addressOffset>0x02A</addressOffset>
                    <size>16</size>
                    <access>read-write</access>
                    <resetValue>0x0000</resetValue>
                    <resetMask>0xefff</resetMask>
                    <fields>
                        <field>
                            <name>DTLN</name>
                            <description>Receive Data Length Flag</description>
                            <lsb>0</lsb>
                            <msb>11</msb>
                            <access>read-only</access>
                        </field>
                        <field>
                            <name>FRDY</name>
                            <description>FIFO Port Ready Flag</description>
                            <lsb>13</lsb>
                            <msb>13</msb>
                            <access>read-only</access>
                            <enumeratedValues>
                                </enumeratedValues>
                        </field>
                        <field>
                            <name>BCLR</name>
                            <description>CPU Buffer Clear</description>
                            <lsb>14</lsb>
                            <msb>14</msb>
                            <access>write-only</access>
                            <enumeratedValues>
                                </enumeratedValues>
                        </field>
                        <field>
                            <name>BVAL</name>
                            <description>FIFO Buffer Valid Flag</description>
                            <lsb>15</lsb>
                            <msb>15</msb>
                            <access>read-write</access>
                            <enumeratedValues>
                                </enumeratedValues>
                        </field>
                    </fields>
                </register>
                <register>
                    <name>INTENB0</name>
                    <description>Interrupt Enable Register 0</description>
                    <addressOffset>0x030</addressOffset>
                    <size>16</size>
                    <access>read-write</access>
                    <resetValue>0x0000</resetValue>
                    <resetMask>0xff00</resetMask>
                    <fields>
                        <field>
                            <name>BRDYE</name>
                            <description>Buffer Ready Interrupt Request Enable</description>
                            <lsb>8</lsb>
                            <msb>8</msb>
                            <access>read-write</access>
                            <enumeratedValues>
                                </enumeratedValues>
                        </field>
                        <field>
                            <name>NRDYE</name>
                            <description>Buffer Not Ready Response Interrupt Request Enable</description>
                            <lsb>9</lsb>
                            <msb>9</msb>
                            <access>read-write</access>
                            <enumeratedValues>
                                </enumeratedValues>
                        </field>
                        <field>
                            <name>BEMPE</name>
                            <description>Buffer Empty Interrupt Request Enable</description>
                            <lsb>10</lsb>
                            <msb>10</msb>
                            <access>read-write</access>
                            <enumeratedValues>
                                </enumeratedValues>
                        </field>
                        <field>
                            <name>CTRE</name>
                            <description>Control Transfer Stage Transition Interrupt Request Enable</description>
                            <lsb>11</lsb>
                            <msb>11</msb>
                            <access>read-write</access>
                            <enumeratedValues>
                                </enumeratedValues>
                        </field>
                        <field>
                            <name>DVSE</name>
                            <description>Device State Transition Interrupt Request Enable</description>
                            <lsb>12</lsb>
                            <msb>12</msb>
                            <access>read-write</access>
                            <enumeratedValues>
                                </enumeratedValues>
                        </field>
                        <field>
                            <name>SOFE</name>
                            <description>Frame Number Update Interrupt Request Enable</description>
                            <lsb>13</lsb>
                            <msb>13</msb>
                            <access>read-write</access>
                            <enumeratedValues>
                                </enumeratedValues>
                        </field>
                        <field>
                            <name>RSME</name>
                            <description>Resume Interrupt Request Enable</description>
                            <lsb>14</lsb>
                            <msb>14</msb>
                            <access>read-write</access>
                            <enumeratedValues>
                                </enumeratedValues>
                        </field>
                        <field>
                            <name>VBSE</name>
                            <description>VBUS Interrupt Request Enable</description>
                            <lsb>15</lsb>
                            <msb>15</msb>
                            <access>read-write</access>
                            <enumeratedValues>
                                </enumeratedValues>
                        </field>
                    </fields>
                </register>
                <register>
                    <name>INTENB1</name>
                    <description>Interrupt Enable Register 1</description>
                    <addressOffset>0x032</addressOffset>
                    <size>16</size>
                    <access>read-write</access>
                    <resetValue>0x0000</resetValue>
                    <resetMask>0xdb71</resetMask>
                    <fields>
                        <field>
                            <name>PDDETINTE</name>
                            <description>PDDETINT Detection Interrupt Request Enable</description>
                            <lsb>0</lsb>
                            <msb>0</msb>
                            <access>read-write</access>
                            <enumeratedValues>
                                </enumeratedValues>
                        </field>
                        <field>
                            <name>SACKE</name>
                            <description>Setup Transaction Normal Response Interrupt Request Enable</description>
                            <lsb>4</lsb>
                            <msb>4</msb>
                            <access>read-write</access>
                            <enumeratedValues>
                                </enumeratedValues>
                        </field>
                        <field>
                            <name>SIGNE</name>
                            <description>Setup Transaction Error Interrupt Request Enable</description>
                            <lsb>5</lsb>
                            <msb>5</msb>
                            <access>read-write</access>
                            <enumeratedValues>
                                </enumeratedValues>
                        </field>
                        <field>
                            <name>EOFERRE</name>
                            <description>EOF Error Detection Interrupt Request Enable</description>
                            <lsb>6</lsb>
                            <msb>6</msb>
                            <access>read-write</access>
                            <enumeratedValues>
                                </enumeratedValues>
                        </field>
                        <field>
                            <name>LPMENDE</name>
                            <description>LPM Transaction End Interrupt Request Enable</description>
                            <lsb>8</lsb>
                            <msb>8</msb>
                            <access>read-write</access>
                            <enumeratedValues>
                                </enumeratedValues>
                        </field>
                        <field>
                            <name>L1RSMENDE</name>
                            <description>L1 Resume End Interrupt Enable</description>
                            <lsb>9</lsb>
                            <msb>9</msb>
                            <access>read-write</access>
                            <enumeratedValues>
                                </enumeratedValues>
                        </field>
                        <field>
                            <name>ATTCHE</name>
                            <description>Connection Detection Interrupt Request Enable</description>
                            <lsb>11</lsb>
                            <msb>11</msb>
                            <access>read-write</access>
                            <enumeratedValues>
                                </enumeratedValues>
                        </field>
                        <field>
                            <name>DTCHE</name>
                            <description>Disconnection Detection Interrupt Request Enable</description>
                            <lsb>12</lsb>
                            <msb>12</msb>
                            <access>read-write</access>
                            <enumeratedValues>
                                </enumeratedValues>
                        </field>
                        <field>
                            <name>BCHGE</name>
                            <description>USB Bus Change Interrupt Request Enable</description>
                            <lsb>14</lsb>
                            <msb>14</msb>
                            <access>read-write</access>
                            <enumeratedValues>
                                </enumeratedValues>
                        </field>
                        <field>
                            <name>OVRCRE</name>
                            <description>OVRCRE Interrupt Request Enable</description>
                            <lsb>15</lsb>
                            <msb>15</msb>
                            <access>read-write</access>
                            <enumeratedValues>
                                </enumeratedValues>
                        </field>
                    </fields>
                </register>
                <register>
                    <name>BRDYENB</name>
                    <description>BRDY Interrupt Enable Register</description>
                    <addressOffset>0x036</addressOffset>
                    <size>16</size>
                    <access>read-write</access>
                    <resetValue>0x0000</resetValue>
                    <resetMask>0xffff</resetMask>
                    <fields>
                        <field>
                            <name>PIPEBRDYE</name>
                            <description>BRDY Interrupt Request Enable for Pipes [9:0]</description>
                            <lsb>0</lsb>
                            <msb>9</msb>
                            <access>read-write</access>
                            <enumeratedValues>
                                </enumeratedValues>
                        </field>
                    </fields>
                </register>
                <register>
                    <name>NRDYENB</name>
                    <description>NRDY Interrupt Enable Register</description>
                    <addressOffset>0x038</addressOffset>
                    <size>16</size>
                    <access>read-write</access>
                    <resetValue>0x0000</resetValue>
                    <resetMask>0xffff</resetMask>
                    <fields>
                        <field>
                            <name>PIPENRDYE</name>
                            <description>NRDY Interrupt Enable for Pipes [9:0]</description>
                            <lsb>0</lsb>
                            <msb>9</msb>
                            <access>read-write</access>
                            <enumeratedValues>
                                </enumeratedValues>
                        </field>
                    </fields>
                </register>
                <register>
                    <name>BEMPENB</name>
                    <description>BEMP Interrupt Enable Register</description>
                    <addressOffset>0x03A</addressOffset>
                    <size>16</size>
                    <access>read-write</access>
                    <resetValue>0x0000</resetValue>
                    <resetMask>0xffff</resetMask>
                    <fields>
                        <field>
                            <name>PIPEBEMPE</name>
                            <description>BEMP Interrupt Enable for Pipes [9:0]</description>
                            <lsb>0</lsb>
                            <msb>9</msb>
                            <access>read-write</access>
                            <enumeratedValues>
                                </enumeratedValues>
                        </field>
                    </fields>
                </register>
                <register>
                    <name>SOFCFG</name>
                    <description>SOF Output Configuration Register</description>
                    <addressOffset>0x03C</addressOffset>
                    <size>16</size>
                    <access>read-write</access>
                    <resetValue>0x0000</resetValue>
                    <resetMask>0x0170</resetMask>
                    <fields>
                        <field>
                            <name>EDGESTS</name>
                            <description>Interrupt Edge Processing Status Flag</description>
                            <lsb>4</lsb>
                            <msb>4</msb>
                            <access>read-only</access>
                        </field>
                        <field>
                            <name>INTL</name>
                            <description>Interrupt Output Sense Select</description>
                            <lsb>5</lsb>
                            <msb>5</msb>
                            <access>read-write</access>
                            <enumeratedValues>
                                </enumeratedValues>
                        </field>
                        <field>
                            <name>BRDYM</name>
                            <description>PIPEBRDY Interrupt Status Clear Timing</description>
                            <lsb>6</lsb>
                            <msb>6</msb>
                            <access>read-write</access>
                            <enumeratedValues>
                                </enumeratedValues>
                        </field>
                        <field>
                            <name>TRNENSEL</name>
                            <description>Transaction,Enabled Time Select</description>
                            <lsb>8</lsb>
                            <msb>8</msb>
                            <access>read-write</access>
                            <enumeratedValues>
                                </enumeratedValues>
                        </field>
                    </fields>
                </register>
                <register>
                    <name>PHYSET</name>
                    <description>PHY Setting Register</description>
                    <addressOffset>0x03E</addressOffset>
                    <size>16</size>
                    <access>read-write</access>
                    <resetValue>0x0033</resetValue>
                    <resetMask>0x0b3b</resetMask>
                    <fields>
                        <field>
                            <name>DIRPD</name>
                            <description>Power,Down Control</description>
                            <lsb>0</lsb>
                            <msb>0</msb>
                            <access>read-write</access>
                            <enumeratedValues>
                                </enumeratedValues>
                        </field>
                        <field>
                            <name>PLLRESET</name>
                            <description>PLL Reset Control</description>
                            <lsb>1</lsb>
                            <msb>1</msb>
                            <access>read-write</access>
                            <enumeratedValues>
                                </enumeratedValues>
                        </field>
                        <field>
                            <name>CDPEN</name>
                            <description>Charging Downstream Port Enable</description>
                            <lsb>3</lsb>
                            <msb>3</msb>
                            <access>read-write</access>
                            <enumeratedValues>
                                </enumeratedValues>
                        </field>
                        <field>
                            <name>CLKSEL</name>
                            <description>Input System Clock Frequency</description>
                            <lsb>4</lsb>
                            <msb>5</msb>
                            <access>read-write</access>
                            <enumeratedValues>
                                </enumeratedValues>
                        </field>
                        <field>
                            <name>REPSEL</name>
                            <description>Terminating Resistance Adjustment Cycle</description>
                            <lsb>8</lsb>
                            <msb>9</msb>
                            <access>read-write</access>
                            <enumeratedValues>
                                </enumeratedValues>
                        </field>
                        <field>
                            <name>REPSTART</name>
                            <description>Forcibly Start Terminating Resistance Adjustment</description>
                            <lsb>11</lsb>
                            <msb>11</msb>
                            <access>read-write</access>
                            <enumeratedValues>
                                </enumeratedValues>
                        </field>
                        <field>
                            <name>HSEB</name>
                            <description>CL,only mode</description>
                            <lsb>15</lsb>
                            <msb>15</msb>
                            <access>read-write</access>
                            <enumeratedValues>
                                </enumeratedValues>
                        </field>
                    </fields>
                </register>
                <register>
                    <name>INTSTS0</name>
                    <description>Interrupt Status Register 0</description>
                    <addressOffset>0x040</addressOffset>
                    <size>16</size>
                    <access>read-write</access>
                    <resetValue>0x0000</resetValue>
                    <resetMask>0xff7f</resetMask>
                    <fields>
                        <field>
                            <name>CTSQ</name>
                            <description>Control Transfer Stage Flag</description>
                            <lsb>0</lsb>
                            <msb>2</msb>
                            <access>read-only</access>
                            <enumeratedValues>
                                </enumeratedValues>
                        </field>
                        <field>
                            <name>VALID</name>
                            <description>USB Request Reception Flag</description>
                            <lsb>3</lsb>
                            <msb>3</msb>
                            <access>read-write</access>
                            <enumeratedValues>
                                </enumeratedValues>
                        </field>
                        <field>
                            <name>DVSQ</name>
                            <description>Device State</description>
                            <lsb>4</lsb>
                            <msb>6</msb>
                            <access>read-only</access>
                            <enumeratedValues>
                                </enumeratedValues>
                        </field>
                        <field>
                            <name>VBSTS</name>
                            <description>VBUS Input Status Flag</description>
                            <lsb>7</lsb>
                            <msb>7</msb>
                            <access>read-only</access>
                            <enumeratedValues>
                                </enumeratedValues>
                        </field>
                        <field>
                            <name>BRDY</name>
                            <description>BRDY Interrupt Status Flag</description>
                            <lsb>8</lsb>
                            <msb>8</msb>
                            <access>read-only</access>
                            <enumeratedValues>
                                </enumeratedValues>
                        </field>
                        <field>
                            <name>NRDY</name>
                            <description>NRDY Interrupt Status Flag</description>
                            <lsb>9</lsb>
                            <msb>9</msb>
                            <access>read-only</access>
                            <enumeratedValues>
                                </enumeratedValues>
                        </field>
                        <field>
                            <name>BEMP</name>
                            <description>BEMP Interrupt Status Flag</description>
                            <lsb>10</lsb>
                            <msb>10</msb>
                            <access>read-only</access>
                            <enumeratedValues>
                                </enumeratedValues>
                        </field>
                        <field>
                            <name>CTRT</name>
                            <description>Control Transfer Stage Transition Interrupt Status Flag</description>
                            <lsb>11</lsb>
                            <msb>11</msb>
                            <access>read-write</access>
                            <enumeratedValues>
                                </enumeratedValues>
                        </field>
                        <field>
                            <name>DVST</name>
                            <description>Device State Transition Interrupt Status Flag</description>
                            <lsb>12</lsb>
                            <msb>12</msb>
                            <access>read-write</access>
                            <enumeratedValues>
                                </enumeratedValues>
                        </field>
                        <field>
                            <name>SOFR</name>
                            <description>Frame Number Refresh Interrupt Status Flag</description>
                            <lsb>13</lsb>
                            <msb>13</msb>
                            <access>read-write</access>
                            <enumeratedValues>
                                </enumeratedValues>
                        </field>
                        <field>
                            <name>RESM</name>
                            <description>Resume Interrupt Status Flag</description>
                            <lsb>14</lsb>
                            <msb>14</msb>
                            <access>read-write</access>
                            <enumeratedValues>
                                </enumeratedValues>
                        </field>
                        <field>
                            <name>VBINT</name>
                            <description>VBUS Interrupt Status Flag</description>
                            <lsb>15</lsb>
                            <msb>15</msb>
                            <access>read-write</access>
                            <enumeratedValues>
                                </enumeratedValues>
                        </field>
                    </fields>
                </register>
                <register>
                    <name>INTSTS1</name>
                    <description>Interrupt Status Register 1</description>
                    <addressOffset>0x042</addressOffset>
                    <size>16</size>
                    <access>read-write</access>
                    <resetValue>0x0000</resetValue>
                    <resetMask>0xdb71</resetMask>
                    <fields>
                        <field>
                            <name>PDDETINT</name>
                            <description>PDDET Detection Interrupt Status Flag</description>
                            <lsb>0</lsb>
                            <msb>0</msb>
                            <access>read-write</access>
                            <enumeratedValues>
                                </enumeratedValues>
                        </field>
                        <field>
                            <name>SACK</name>
                            <description>Setup Transaction Normal Response Interrupt Status Flag</description>
                            <lsb>4</lsb>
                            <msb>4</msb>
                            <access>read-write</access>
                            <enumeratedValues>
                                </enumeratedValues>
                        </field>
                        <field>
                            <name>SIGN</name>
                            <description>Setup Transaction Error Interrupt Status Flag</description>
                            <lsb>5</lsb>
                            <msb>5</msb>
                            <access>read-write</access>
                            <enumeratedValues>
                                </enumeratedValues>
                        </field>
                        <field>
                            <name>EOFERR</name>
                            <description>EOF Error Detection Interrupt Status Flag</description>
                            <lsb>6</lsb>
                            <msb>6</msb>
                            <access>read-write</access>
                            <enumeratedValues>
                                </enumeratedValues>
                        </field>
                        <field>
                            <name>LPMEND</name>
                            <description>LPM Transaction End Interrupt Status Flag</description>
                            <lsb>8</lsb>
                            <msb>8</msb>
                            <access>read-write</access>
                            <enumeratedValues>
                                </enumeratedValues>
                        </field>
                        <field>
                            <name>L1RSMEND</name>
                            <description>L1 Resume End Interrupt Status Flag</description>
                            <lsb>9</lsb>
                            <msb>9</msb>
                            <access>read-write</access>
                            <enumeratedValues>
                                </enumeratedValues>
                        </field>
                        <field>
                            <name>ATTCH</name>
                            <description>USB Connection Detection Interrupt Status Flag</description>
                            <lsb>11</lsb>
                            <msb>11</msb>
                            <access>read-write</access>
                            <enumeratedValues>
                                </enumeratedValues>
                        </field>
                        <field>
                            <name>DTCH</name>
                            <description>USB Disconnection Detection Interrupt Status Flag</description>
                            <lsb>12</lsb>
                            <msb>12</msb>
                            <access>read-write</access>
                            <enumeratedValues>
                                </enumeratedValues>
                        </field>
                        <field>
                            <name>BCHG</name>
                            <description>USB Bus Change Interrupt Status Flag</description>
                            <lsb>14</lsb>
                            <msb>14</msb>
                            <access>read-write</access>
                            <enumeratedValues>
                                </enumeratedValues>
                        </field>
                        <field>
                            <name>OVRCR</name>
                            <description>OVRCR Interrupt Status Flag</description>
                            <lsb>15</lsb>
                            <msb>15</msb>
                            <access>read-write</access>
                            <enumeratedValues>
                                </enumeratedValues>
                        </field>
                    </fields>
                </register>
                <register>
                    <name>BRDYSTS</name>
                    <description>BRDY Interrupt Status Register</description>
                    <addressOffset>0x046</addressOffset>
                    <size>16</size>
                    <access>read-write</access>
                    <resetValue>0x0000</resetValue>
                    <resetMask>0xffff</resetMask>
                    <fields>
                        <field>
                            <name>PIPEBRDY</name>
                            <description>BRDY Interrupt Status Flag for Pipe[9:0]</description>
                            <lsb>0</lsb>
                            <msb>9</msb>
                            <access>read-write</access>
                            <enumeratedValues>
                                </enumeratedValues>
                        </field>
                    </fields>
                </register>
                <register>
                    <name>NRDYSTS</name>
                    <description>NRDY Interrupt Status Register</description>
                    <addressOffset>0x048</addressOffset>
                    <size>16</size>
                    <access>read-write</access>
                    <resetValue>0x0000</resetValue>
                    <resetMask>0xffff</resetMask>
                    <fields>
                        <field>
                            <name>PIPENRDY</name>
                            <description>NRDY Interrupt Status Flag for Pipe[9:0]</description>
                            <lsb>0</lsb>
                            <msb>9</msb>
                            <access>read-write</access>
                            <enumeratedValues>
                                </enumeratedValues>
                        </field>
                    </fields>
                </register>
                <register>
                    <name>BEMPSTS</name>
                    <description>BEMP Interrupt Status Register</description>
                    <addressOffset>0x04A</addressOffset>
                    <size>16</size>
                    <access>read-write</access>
                    <resetValue>0x0000</resetValue>
                    <resetMask>0xffff</resetMask>
                    <fields>
                        <field>
                            <name>PIPEBEMP</name>
                            <description>BEMP Interrupt Status Flag for Pipe[9:0]</description>
                            <lsb>0</lsb>
                            <msb>9</msb>
                            <access>read-write</access>
                            <enumeratedValues>
                                </enumeratedValues>
                        </field>
                    </fields>
                </register>
                <register>
                    <name>FRMNUM</name>
                    <description>Frame Number Register</description>
                    <addressOffset>0x04C</addressOffset>
                    <size>16</size>
                    <access>read-write</access>
                    <resetValue>0x0000</resetValue>
                    <resetMask>0xffff</resetMask>
                    <fields>
                        <field>
                            <name>FRNM</name>
                            <description>Frame Number Flag</description>
                            <lsb>0</lsb>
                            <msb>10</msb>
                            <access>read-only</access>
                        </field>
                        <field>
                            <name>CRCE</name>
                            <description>CRC Error Detection Status Flag</description>
                            <lsb>14</lsb>
                            <msb>14</msb>
                            <access>read-write</access>
                            <enumeratedValues>
                                </enumeratedValues>
                        </field>
                        <field>
                            <name>OVRN</name>
                            <description>Overrun/Underrun Detection Status Flag</description>
                            <lsb>15</lsb>
                            <msb>15</msb>
                            <access>read-write</access>
                            <enumeratedValues>
                                </enumeratedValues>
                        </field>
                    </fields>
                </register>
                <register>
                    <name>UFRMNUM</name>
                    <description>µFrame Number Register</description>
                    <addressOffset>0x04E</addressOffset>
                    <size>16</size>
                    <access>read-write</access>
                    <resetValue>0x0000</resetValue>
                    <resetMask>0x8007</resetMask>
                    <fields>
                        <field>
                            <name>UFRNM</name>
                            <description>Microframe number</description>
                            <lsb>0</lsb>
                            <msb>2</msb>
                            <access>read-only</access>
                        </field>
                        <field>
                            <name>DVCHG</name>
                            <description>Device State Change</description>
                            <lsb>15</lsb>
                            <msb>15</msb>
                            <access>read-write</access>
                            <enumeratedValues>
                                </enumeratedValues>
                        </field>
                    </fields>
                </register>
                <register>
                    <name>USBADDR</name>
                    <description>USB Address Register</description>
                    <addressOffset>0x050</addressOffset>
                    <size>16</size>
                    <access>read-write</access>
                    <resetValue>0x0000</resetValue>
                    <resetMask>0x077f</resetMask>
                    <fields>
                        <field>
                            <name>USBADDR</name>
                            <description>USB Address Flag</description>
                            <lsb>0</lsb>
                            <msb>6</msb>
                            <access>read-only</access>
                        </field>
                        <field>
                            <name>STSRECOV0</name>
                            <description>Status Recovery</description>
                            <lsb>8</lsb>
                            <msb>10</msb>
                            <access>read-write</access>
                            <enumeratedValues>
                                </enumeratedValues>
                        </field>
                    </fields>
                </register>
                <register>
                    <name>USBREQ</name>
                    <description>USB Request Type Register</description>
                    <addressOffset>0x054</addressOffset>
                    <size>16</size>
                    <access>read-write</access>
                    <resetValue>0x0000</resetValue>
                    <resetMask>0xffff</resetMask>
                    <fields>
                        <field>
                            <name>BMREQUESTTYPE</name>
                            <description>USB request bmRequestType value</description>
                            <lsb>0</lsb>
                            <msb>7</msb>
                            <access>read-write</access>
                        </field>
                        <field>
                            <name>BREQUEST</name>
                            <description>USB request bRequest value</description>
                            <lsb>8</lsb>
                            <msb>15</msb>
                            <access>read-write</access>
                        </field>
                    </fields>
                </register>
                <register>
                    <name>USBVAL</name>
                    <description>USB Request Value Register</description>
                    <addressOffset>0x056</addressOffset>
                    <size>16</size>
                    <access>read-write</access>
                    <resetValue>0x0000</resetValue>
                    <resetMask>0xffff</resetMask>
                    <fields>
                        <field>
                            <name>WVALUE</name>
                            <description>USB request wValue value</description>
                            <lsb>0</lsb>
                            <msb>15</msb>
                            <access>read-write</access>
                        </field>
                    </fields>
                </register>
                <register>
                    <name>USBINDX</name>
                    <description>USB Request Index Register</description>
                    <addressOffset>0x058</addressOffset>
                    <size>16</size>
                    <access>read-write</access>
                    <resetValue>0x0000</resetValue>
                    <resetMask>0xffff</resetMask>
                    <fields>
                        <field>
                            <name>WINDEX</name>
                            <description>USB request wIndex value</description>
                            <lsb>0</lsb>
                            <msb>15</msb>
                            <access>read-write</access>
                        </field>
                    </fields>
                </register>
                <register>
                    <name>USBLENG</name>
                    <description>USB Request Length Register</description>
                    <addressOffset>0x05A</addressOffset>
                    <size>16</size>
                    <access>read-write</access>
                    <resetValue>0x0000</resetValue>
                    <resetMask>0xffff</resetMask>
                    <fields>
                        <field>
                            <name>WLENTUH</name>
                            <description>USB request wLength value</description>
                            <lsb>0</lsb>
                            <msb>15</msb>
                            <access>read-write</access>
                        </field>
                    </fields>
                </register>
                <register>
                    <name>DCPCFG</name>
                    <description>DCP Configuration Register</description>
                    <addressOffset>0x05C</addressOffset>
                    <size>16</size>
                    <access>read-write</access>
                    <resetValue>0x0000</resetValue>
                    <resetMask>0xffff</resetMask>
                    <fields>
                        <field>
                            <name>DIR</name>
                            <description>Transfer Direction</description>
                            <lsb>4</lsb>
                            <msb>4</msb>
                            <access>read-write</access>
                            <enumeratedValues>
                                </enumeratedValues>
                        </field>
                        <field>
                            <name>SHTNAK</name>
                            <description>Pipe Blocking on End of Transfer</description>
                            <lsb>7</lsb>
                            <msb>7</msb>
                            <access>read-write</access>
                            <enumeratedValues>
                                </enumeratedValues>
                        </field>
                        <field>
                            <name>CNTMD</name>
                            <description>Continuous Transfer Mode</description>
                            <lsb>8</lsb>
                            <msb>8</msb>
                            <access>read-write</access>
                            <enumeratedValues>
                                </enumeratedValues>
                        </field>
                    </fields>
                </register>
                <register>
                    <name>DCPMAXP</name>
                    <description>DCP Maximum Packet Size Register</description>
                    <addressOffset>0x05E</addressOffset>
                    <size>16</size>
                    <access>read-write</access>
                    <resetValue>0x0040</resetValue>
                    <resetMask>0xf07f</resetMask>
                    <fields>
                        <field>
                            <name>MXPS</name>
                            <description>Maximum Packet Size</description>
                            <lsb>0</lsb>
                            <msb>6</msb>
                            <access>read-write</access>
                        </field>
                        <field>
                            <name>DEVSEL</name>
                            <description>Device Select</description>
                            <lsb>12</lsb>
                            <msb>15</msb>
                            <access>read-write</access>
                            <enumeratedValues>
                                </enumeratedValues>
                        </field>
                    </fields>
                </register>
                <register>
                    <name>DCPCTR</name>
                    <description>DCP Control Register</description>
                    <addressOffset>0x060</addressOffset>
                    <size>16</size>
                    <access>read-write</access>
                    <resetValue>0x0040</resetValue>
                    <resetMask>0xf1f7</resetMask>
                    <fields>
                        <field>
                            <name>PID</name>
                            <description>Response PID</description>
                            <lsb>0</lsb>
                            <msb>1</msb>
                            <access>read-write</access>
                            <enumeratedValues>
                                </enumeratedValues>
                        </field>
                        <field>
                            <name>CCPL</name>
                            <description>Control Transfer End Enable</description>
                            <lsb>2</lsb>
                            <msb>2</msb>
                            <access>read-write</access>
                            <enumeratedValues>
                                </enumeratedValues>
                        </field>
                        <field>
                            <name>PINGE</name>
                            <description>PING Token Issue Enable</description>
                            <lsb>4</lsb>
                            <msb>4</msb>
                            <access>read-write</access>
                            <enumeratedValues>
                                </enumeratedValues>
                        </field>
                        <field>
                            <name>PBUSY</name>
                            <description>Pipe Busy Flag</description>
                            <lsb>5</lsb>
                            <msb>5</msb>
                            <access>read-only</access>
                            <enumeratedValues>
                                </enumeratedValues>
                        </field>
                        <field>
                            <name>SQMON</name>
                            <description>Sequence Toggle Bit Monitor Flag</description>
                            <lsb>6</lsb>
                            <msb>6</msb>
                            <access>read-only</access>
                            <enumeratedValues>
                                </enumeratedValues>
                        </field>
                        <field>
                            <name>SQSET</name>
                            <description>Sequence Toggle Bit Set</description>
                            <lsb>7</lsb>
                            <msb>7</msb>
                            <access>write-only</access>
                            <enumeratedValues>
                                </enumeratedValues>
                        </field>
                        <field>
                            <name>SQCLR</name>
                            <description>Sequence Toggle Bit Clear</description>
                            <lsb>8</lsb>
                            <msb>8</msb>
                            <access>write-only</access>
                            <enumeratedValues>
                                </enumeratedValues>
                        </field>
                        <field>
                            <name>SUREQCLR</name>
                            <description>SUREQ Bit Clear</description>
                            <lsb>11</lsb>
                            <msb>11</msb>
                            <access>write-only</access>
                            <enumeratedValues>
                                </enumeratedValues>
                        </field>
                        <field>
                            <name>CSSTS</name>
                            <description>CSSTS Status Flag</description>
                            <lsb>12</lsb>
                            <msb>12</msb>
                            <access>read-only</access>
                            <enumeratedValues>
                                </enumeratedValues>
                        </field>
                        <field>
                            <name>CSCLR</name>
                            <description>CSSTS Status Flag Clear</description>
                            <lsb>13</lsb>
                            <msb>13</msb>
                            <access>write-only</access>
                            <enumeratedValues>
                                </enumeratedValues>
                        </field>
                        <field>
                            <name>SUREQ</name>
                            <description>SETUP Token Transmission</description>
                            <lsb>14</lsb>
                            <msb>14</msb>
                            <access>read-write</access>
                            <enumeratedValues>
                                </enumeratedValues>
                        </field>
                        <field>
                            <name>BSTS</name>
                            <description>Buffer Status Flag</description>
                            <lsb>15</lsb>
                            <msb>15</msb>
                            <access>read-only</access>
                            <enumeratedValues>
                                </enumeratedValues>
                        </field>
                    </fields>
                </register>
                <register>
                    <name>PIPESEL</name>
                    <description>Pipe Window Select Register</description>
                    <addressOffset>0x064</addressOffset>
                    <size>16</size>
                    <access>read-write</access>
                    <resetValue>0x0000</resetValue>
                    <resetMask>0x000f</resetMask>
                    <fields>
                        <field>
                            <name>PIPESEL</name>
                            <description>Pipe Window Select</description>
                            <lsb>0</lsb>
                            <msb>3</msb>
                            <access>read-write</access>
                            <enumeratedValues>
                                </enumeratedValues>
                        </field>
                    </fields>
                </register>
                <register>
                    <name>PIPECFG</name>
                    <description>Pipe Configuration Register</description>
                    <addressOffset>0x068</addressOffset>
                    <size>16</size>
                    <access>read-write</access>
                    <resetValue>0x0000</resetValue>
                    <resetMask>0xc79f</resetMask>
                    <fields>
                        <field>
                            <name>EPNUM</name>
                            <description>Endpoint Number</description>
                            <lsb>0</lsb>
                            <msb>3</msb>
                            <access>read-write</access>
                        </field>
                        <field>
                            <name>DIR</name>
                            <description>Transfer Direction</description>
                            <lsb>4</lsb>
                            <msb>4</msb>
                            <access>read-write</access>
                            <enumeratedValues>
                                </enumeratedValues>
                        </field>
                        <field>
                            <name>SHTNAK</name>
                            <description>Pipe Disabled at End of Transfer</description>
                            <lsb>7</lsb>
                            <msb>7</msb>
                            <access>read-write</access>
                            <enumeratedValues>
                                </enumeratedValues>
                        </field>
                        <field>
                            <name>CNTMD</name>
                            <description>Continuous Transfer Mode</description>
                            <lsb>8</lsb>
                            <msb>8</msb>
                            <access>read-write</access>
                            <enumeratedValues>
                                </enumeratedValues>
                        </field>
                        <field>
                            <name>DBLB</name>
                            <description>Double Buffer Mode</description>
                            <lsb>9</lsb>
                            <msb>9</msb>
                            <access>read-write</access>
                            <enumeratedValues>
                                </enumeratedValues>
                        </field>
                        <field>
                            <name>BFRE</name>
                            <description>BRDY Interrupt Operation Specification</description>
                            <lsb>10</lsb>
                            <msb>10</msb>
                            <access>read-write</access>
                            <enumeratedValues>
                                </enumeratedValues>
                        </field>
                        <field>
                            <name>TYPE</name>
                            <description>Transfer Type</description>
                            <lsb>14</lsb>
                            <msb>15</msb>
                            <access>read-write</access>
                            <enumeratedValues>
                                </enumeratedValues>
                        </field>
                    </fields>
                </register>
                <register>
                    <name>PIPEBUF</name>
                    <description>Pipe Buffer Register</description>
                    <addressOffset>0x06A</addressOffset>
                    <size>16</size>
                    <access>read-write</access>
                    <resetValue>0x0000</resetValue>
                    <resetMask>0x7cff</resetMask>
                    <fields>
                        <field>
                            <name>BUFNMB</name>
                            <description>Buffer Number</description>
                            <lsb>0</lsb>
                            <msb>7</msb>
                            <access>read-write</access>
                        </field>
                        <field>
                            <name>BUFSIZE</name>
                            <description>Buffer Size</description>
                            <lsb>10</lsb>
                            <msb>14</msb>
                            <access>read-write</access>
                        </field>
                    </fields>
                </register>
                <register>
                    <name>PIPEMAXP</name>
                    <description>Pipe Maximum Packet Size Register</description>
                    <addressOffset>0x06C</addressOffset>
                    <size>16</size>
                    <access>read-write</access>
                    <resetValue>0x0000</resetValue>
                    <resetMask>0xefff</resetMask>
                    <fields>
                        <field>
                            <name>MXPS</name>
                            <description>Maximum Packet Size</description>
                            <lsb>0</lsb>
                            <msb>10</msb>
                            <access>read-write</access>
                        </field>
                        <field>
                            <name>DEVSEL</name>
                            <description>Device Select</description>
                            <lsb>12</lsb>
                            <msb>15</msb>
                            <access>read-write</access>
                        </field>
                    </fields>
                </register>
                <register>
                    <name>PIPEPERI</name>
                    <description>Pipe Cycle Control Register</description>
                    <addressOffset>0x06E</addressOffset>
                    <size>16</size>
                    <access>read-write</access>
                    <resetValue>0x0000</resetValue>
                    <resetMask>0x1007</resetMask>
                    <fields>
                        <field>
                            <name>IITV</name>
                            <description>Interval Error Detection Interval</description>
                            <lsb>0</lsb>
                            <msb>2</msb>
                            <access>read-write</access>
                        </field>
                        <field>
                            <name>IFIS</name>
                            <description>Isochronous IN Buffer Flush</description>
                            <lsb>12</lsb>
                            <msb>12</msb>
                            <access>read-write</access>
                            <enumeratedValues>
                                </enumeratedValues>
                        </field>
                    </fields>
                </register>
                <register>
                    <dim>9</dim>
                    <dimIncrement>0x4</dimIncrement>
                    <dimIndex>1-9</dimIndex>
                    <name>PIPE%sCTR</name>
                    <description>Pipe %s Control Register</description>
                    <addressOffset>0x070</addressOffset>
                    <size>16</size>
                    <access>read-write</access>
                    <resetValue>0x0000</resetValue>
                    <resetMask>0xf7e3</resetMask>
                    <fields>
                        <field>
                            <name>PID</name>
                            <description>Response PID</description>
                            <lsb>0</lsb>
                            <msb>1</msb>
                            <access>read-write</access>
                            <enumeratedValues>
                                </enumeratedValues>
                        </field>
                        <field>
                            <name>PBUSY</name>
                            <description>Pipe Busy Flag</description>
                            <lsb>5</lsb>
                            <msb>5</msb>
                            <access>read-only</access>
                            <enumeratedValues>
                                </enumeratedValues>
                        </field>
                        <field>
                            <name>SQMON</name>
                            <description>Sequence Toggle Bit Monitor Flag</description>
                            <lsb>6</lsb>
                            <msb>6</msb>
                            <access>read-only</access>
                            <enumeratedValues>
                                </enumeratedValues>
                        </field>
                        <field>
                            <name>SQSET</name>
                            <description>Sequence Toggle Bit Set</description>
                            <lsb>7</lsb>
                            <msb>7</msb>
                            <access>read-write</access>
                            <enumeratedValues>
                                </enumeratedValues>
                        </field>
                        <field>
                            <name>SQCLR</name>
                            <description>Sequence Toggle Bit Clear</description>
                            <lsb>8</lsb>
                            <msb>8</msb>
                            <access>write-only</access>
                            <enumeratedValues>
                                </enumeratedValues>
                        </field>
                        <field>
                            <name>ACLRM</name>
                            <description>Auto Buffer Clear Mode</description>
                            <lsb>9</lsb>
                            <msb>9</msb>
                            <access>read-write</access>
                            <enumeratedValues>
                                </enumeratedValues>
                        </field>
                        <field>
                            <name>ATREPM</name>
                            <description>Auto Response Mode</description>
                            <lsb>10</lsb>
                            <msb>10</msb>
                            <access>read-write</access>
                            <enumeratedValues>
                                </enumeratedValues>
                        </field>
                        <field>
                            <name>CSSTS</name>
                            <description>CSSTS Status Flag</description>
                            <lsb>12</lsb>
                            <msb>12</msb>
                            <access>read-only</access>
                            <enumeratedValues>
                                </enumeratedValues>
                        </field>
                        <field>
                            <name>CSCLR</name>
                            <description>CSPLIT Status Clear</description>
                            <lsb>13</lsb>
                            <msb>13</msb>
                            <access>write-only</access>
                            <enumeratedValues>
                                </enumeratedValues>
                        </field>
                        <field>
                            <name>INBUFM</name>
                            <description>Transmit Buffer Monitor Flag</description>
                            <lsb>14</lsb>
                            <msb>14</msb>
                            <access>read-only</access>
                            <enumeratedValues>
                                </enumeratedValues>
                        </field>
                        <field>
                            <name>BSTS</name>
                            <description>Buffer Status Flag</description>
                            <lsb>15</lsb>
                            <msb>15</msb>
                            <access>read-only</access>
                            <enumeratedValues>
                                </enumeratedValues>
                        </field>
                    </fields>
                </register>
                <register>
                    <dim>5</dim>
                    <dimIncrement>0x4</dimIncrement>
                    <dimIndex>1-5</dimIndex>
                    <name>PIPE%sTRE</name>
                    <description>Pipe %s Transaction Counter Enable Register</description>
                    <addressOffset>0x090</addressOffset>
                    <size>16</size>
                    <access>read-write</access>
                    <resetValue>0x0000</resetValue>
                    <resetMask>0x0300</resetMask>
                    <fields>
                        <field>
                            <name>TRCLR</name>
                            <description>Transaction Counter Clear</description>
                            <lsb>8</lsb>
                            <msb>8</msb>
                            <access>read-write</access>
                            <enumeratedValues>
                                </enumeratedValues>
                        </field>
                        <field>
                            <name>TRENB</name>
                            <description>Transaction Counter Enable</description>
                            <lsb>9</lsb>
                            <msb>9</msb>
                            <access>read-write</access>
                            <enumeratedValues>
                                </enumeratedValues>
                        </field>
                    </fields>
                </register>
                <register>
                    <dim>5</dim>
                    <dimIncrement>0x4</dimIncrement>
                    <dimIndex>1-5</dimIndex>
                    <name>PIPE%sTRN</name>
                    <description>Pipe %s Transaction Counter Register</description>
                    <addressOffset>0x092</addressOffset>
                    <size>16</size>
                    <access>read-write</access>
                    <resetValue>0x0000</resetValue>
                    <resetMask>0xffff</resetMask>
                    <fields>
                        <field>
                            <name>TRNCNT</name>
                            <description>Transaction Counter</description>
                            <lsb>0</lsb>
                            <msb>15</msb>
                            <access>read-write</access>
                        </field>
                    </fields>
                </register>
                <register>
                    <dim>10</dim>
                    <dimIncrement>0x2</dimIncrement>
                    <dimIndex>0-9</dimIndex>
                    <name>DEVADD%s</name>
                    <description>Device Address %s Configuration Register </description>
                    <addressOffset>0x0D0</addressOffset>
                    <size>16</size>
                    <access>read-write</access>
                    <resetValue>0x0000</resetValue>
                    <resetMask>0x7fc0</resetMask>
                    <fields>
                        <field>
                            <name>USBSPD</name>
                            <description>Transfer Speed of Communication Target Device</description>
                            <lsb>6</lsb>
                            <msb>7</msb>
                            <access>read-write</access>
                            <enumeratedValues>
                                </enumeratedValues>
                        </field>
                        <field>
                            <name>HUBPORT</name>
                            <description>Communication Target Connecting Hub Port</description>
                            <lsb>8</lsb>
                            <msb>10</msb>
                            <access>read-write</access>
                            <enumeratedValues>
                                </enumeratedValues>
                        </field>
                        <field>
                            <name>UPPHUB</name>
                            <description>Communication Target Connecting Hub Register</description>
                            <lsb>11</lsb>
                            <msb>14</msb>
                            <access>read-write</access>
                            <enumeratedValues>
                                </enumeratedValues>
                        </field>
                    </fields>
                </register>
                <register>
                    <name>DEVADDA</name>
                    <description>Device Address A Configuration Register </description>
                    <addressOffset>0x0E4</addressOffset>
                    <size>16</size>
                    <access>read-write</access>
                    <resetValue>0x0000</resetValue>
                    <resetMask>0x7fc0</resetMask>
                    <fields>
                        <field>
                            <name>USBSPD</name>
                            <description>Transfer Speed of Communication Target Device</description>
                            <lsb>6</lsb>
                            <msb>7</msb>
                            <access>read-write</access>
                            <enumeratedValues>
                                </enumeratedValues>
                        </field>
                        <field>
                            <name>HUBPORT</name>
                            <description>Communication Target Connecting Hub Port</description>
                            <lsb>8</lsb>
                            <msb>10</msb>
                            <access>read-write</access>
                            <enumeratedValues>
                                </enumeratedValues>
                        </field>
                        <field>
                            <name>UPPHUB</name>
                            <description>Communication Target Connecting Hub Register</description>
                            <lsb>11</lsb>
                            <msb>14</msb>
                            <access>read-write</access>
                            <enumeratedValues>
                                </enumeratedValues>
                        </field>
                    </fields>
                </register>
                <register>
                    <name>LPCTRL</name>
                    <description>Low Power Control Register</description>
                    <addressOffset>0x100</addressOffset>
                    <size>16</size>
                    <access>read-write</access>
                    <resetValue>0x0000</resetValue>
                    <resetMask>0x0181</resetMask>
                    <fields>
                        <field>
                            <name>HWUPM</name>
                            <description>Resume Return Mode Setting</description>
                            <lsb>7</lsb>
                            <msb>7</msb>
                            <access>read-write</access>
                            <enumeratedValues>
                                </enumeratedValues>
                        </field>
                    </fields>
                </register>
                <register>
                    <name>LPSTS</name>
                    <description>Low Power Status Register</description>
                    <addressOffset>0x102</addressOffset>
                    <size>16</size>
                    <access>read-write</access>
                    <resetValue>0x0000</resetValue>
                    <resetMask>0x510b</resetMask>
                    <fields>
                        <field>
                            <name>SUSPENDM</name>
                            <description>UTMI SuspendM Control</description>
                            <lsb>14</lsb>
                            <msb>14</msb>
                            <access>read-write</access>
                            <enumeratedValues>
                                </enumeratedValues>
                        </field>
                    </fields>
                </register>
                <register>
                    <name>BCCTRL</name>
                    <description>Battery Charging Control Register</description>
                    <addressOffset>0x140</addressOffset>
                    <size>16</size>
                    <access>read-write</access>
                    <resetValue>0x0000</resetValue>
                    <resetMask>0x033f</resetMask>
                    <fields>
                        <field>
                            <name>IDPSRCE</name>
                            <description>IDPSRC Control</description>
                            <lsb>0</lsb>
                            <msb>0</msb>
                            <access>read-write</access>
                            <enumeratedValues>
                                </enumeratedValues>
                        </field>
                        <field>
                            <name>IDMSINKE</name>
                            <description>IDMSINK Control</description>
                            <lsb>1</lsb>
                            <msb>1</msb>
                            <access>read-write</access>
                            <enumeratedValues>
                                </enumeratedValues>
                        </field>
                        <field>
                            <name>VDPSRCE</name>
                            <description>VDPSRC Control</description>
                            <lsb>2</lsb>
                            <msb>2</msb>
                            <access>read-write</access>
                            <enumeratedValues>
                                </enumeratedValues>
                        </field>
                        <field>
                            <name>IDPSINKE</name>
                            <description>IDPSINK Control</description>
                            <lsb>3</lsb>
                            <msb>3</msb>
                            <access>read-write</access>
                            <enumeratedValues>
                                </enumeratedValues>
                        </field>
                        <field>
                            <name>VDMSRCE</name>
                            <description>VDMSRC Control</description>
                            <lsb>4</lsb>
                            <msb>4</msb>
                            <access>read-write</access>
                            <enumeratedValues>
                                </enumeratedValues>
                        </field>
                        <field>
                            <name>DCPMODE</name>
                            <description>DCP Mode Control</description>
                            <lsb>5</lsb>
                            <msb>5</msb>
                            <access>read-write</access>
                            <enumeratedValues>
                                </enumeratedValues>
                        </field>
                        <field>
                            <name>CHGDETSTS</name>
                            <description>CHGDET Status Flag</description>
                            <lsb>8</lsb>
                            <msb>8</msb>
                            <access>read-only</access>
                            <enumeratedValues>
                                </enumeratedValues>
                        </field>
                        <field>
                            <name>PDDETSTS</name>
                            <description>PDDET Status Flag</description>
                            <lsb>9</lsb>
                            <msb>9</msb>
                            <access>read-only</access>
                            <enumeratedValues>
                                </enumeratedValues>
                        </field>
                    </fields>
                </register>
                <register>
                    <name>PL1CTRL1</name>
                    <description>Function L1 Control Register 1</description>
                    <addressOffset>0x144</addressOffset>
                    <size>16</size>
                    <access>read-write</access>
                    <resetValue>0x0000</resetValue>
                    <resetMask>0x4fff</resetMask>
                    <fields>
                        <field>
                            <name>L1RESPEN</name>
                            <description>L1 Response Enable</description>
                            <lsb>0</lsb>
                            <msb>0</msb>
                            <access>read-write</access>
                            <enumeratedValues>
                                </enumeratedValues>
                        </field>
                        <field>
                            <name>L1RESPMD</name>
                            <description>L1 Response Mode</description>
                            <lsb>1</lsb>
                            <msb>2</msb>
                            <access>read-write</access>
                            <enumeratedValues>
                                </enumeratedValues>
                        </field>
                        <field>
                            <name>L1NEGOMD</name>
                            <description>L1 Response Negotiation Control</description>
                            <lsb>3</lsb>
                            <msb>3</msb>
                            <access>read-write</access>
                            <enumeratedValues>
                                </enumeratedValues>
                        </field>
                        <field>
                            <name>DVSQ</name>
                            <description>DVSQ Extension Flag</description>
                            <lsb>4</lsb>
                            <msb>7</msb>
                            <access>read-only</access>
                            <enumeratedValues>
                                </enumeratedValues>
                        </field>
                        <field>
                            <name>HIRDTHR</name>
                            <description>L1 Response Negotiation Threshold Value</description>
                            <lsb>8</lsb>
                            <msb>11</msb>
                            <access>read-write</access>
                        </field>
                        <field>
                            <name>L1EXTMD</name>
                            <description>PHY Control Mode at L1 Return</description>
                            <lsb>14</lsb>
                            <msb>14</msb>
                            <access>read-write</access>
                            <enumeratedValues>
                                </enumeratedValues>
                        </field>
                    </fields>
                </register>
                <register>
                    <name>PL1CTRL2</name>
                    <description>Function L1 Control Register 2</description>
                    <addressOffset>0x146</addressOffset>
                    <size>16</size>
                    <access>read-write</access>
                    <resetValue>0x0000</resetValue>
                    <resetMask>0x1f00</resetMask>
                    <fields>
                        <field>
                            <name>HIRDMON</name>
                            <description>HIRD Value Monitor</description>
                            <lsb>8</lsb>
                            <msb>11</msb>
                            <access>read-only</access>
                        </field>
                        <field>
                            <name>RWEMON</name>
                            <description>RWE Value Monitor</description>
                            <lsb>12</lsb>
                            <msb>12</msb>
                            <access>read-only</access>
                        </field>
                    </fields>
                </register>
                <register>
                    <name>HL1CTRL1</name>
                    <description>Host L1 Control Register 1</description>
                    <addressOffset>0x148</addressOffset>
                    <size>16</size>
                    <access>read-write</access>
                    <resetValue>0x0000</resetValue>
                    <resetMask>0x0007</resetMask>
                    <fields>
                        <field>
                            <name>L1REQ</name>
                            <description>L1 Transition Request</description>
                            <lsb>0</lsb>
                            <msb>0</msb>
                            <access>read-write</access>
                        </field>
                        <field>
                            <name>L1STATUS</name>
                            <description>L1 Request Completion Status</description>
                            <lsb>1</lsb>
                            <msb>2</msb>
                            <access>read-only</access>
                            <enumeratedValues>
                                </enumeratedValues>
                        </field>
                    </fields>
                </register>
                <register>
                    <name>HL1CTRL2</name>
                    <description>Host L1 Control Register 2</description>
                    <addressOffset>0x14A</addressOffset>
                    <size>16</size>
                    <access>read-write</access>
                    <resetValue>0x0000</resetValue>
                    <resetMask>0x9f0f</resetMask>
                    <fields>
                        <field>
                            <name>L1ADDR</name>
                            <description>LPM Token DeviceAddress</description>
                            <lsb>0</lsb>
                            <msb>3</msb>
                            <access>read-write</access>
                        </field>
                        <field>
                            <name>HIRD</name>
                            <description>LPM Token HIRD</description>
                            <lsb>8</lsb>
                            <msb>11</msb>
                            <access>read-write</access>
                        </field>
                        <field>
                            <name>L1RWE</name>
                            <description>LPM Token L1 RemoteWake Enable</description>
                            <lsb>12</lsb>
                            <msb>12</msb>
                            <access>read-write</access>
                        </field>
                        <field>
                            <name>BESL</name>
                            <description>BESL &amp; Alternate HIRD</description>
                            <lsb>15</lsb>
                            <msb>15</msb>
                            <access>read-write</access>
                        </field>
                    </fields>
                </register>
                <register>
                    <name>DPUSR0R</name>
                    <description>Deep Software Standby USB Transceiver Control/Pin Monitor Register</description>
                    <addressOffset>0x160</addressOffset>
                    <size>32</size>
                    <access>read-only</access>
                    <resetValue>0x00000000</resetValue>
                    <resetMask>0xff4fffff</resetMask>
                    <fields>
                        <field>
                            <name>DOVCAHM</name>
                            <description>OVRCURA Input Flag</description>
                            <lsb>20</lsb>
                            <msb>20</msb>
                            <access>read-only</access>
                        </field>
                        <field>
                            <name>DOVCBHM</name>
                            <description>OVRCURB Input Flag</description>
                            <lsb>21</lsb>
                            <msb>21</msb>
                            <access>read-only</access>
                        </field>
                        <field>
                            <name>DVBSTSHM</name>
                            <description>VBUS Input Flag</description>
                            <lsb>23</lsb>
                            <msb>23</msb>
                            <access>read-only</access>
                        </field>
                    </fields>
                </register>
                <register>
                    <name>DPUSR1R</name>
                    <description>Deep Software Standby USB Suspend/Resume Interrupt Register</description>
                    <addressOffset>0x164</addressOffset>
                    <size>32</size>
                    <access>read-write</access>
                    <resetValue>0x00000000</resetValue>
                    <resetMask>0xffffffff</resetMask>
                    <fields>
                        <field>
                            <name>DOVCAHE</name>
                            <description>OVRCURA Interrupt Enable Clear</description>
                            <lsb>4</lsb>
                            <msb>4</msb>
                            <access>read-write</access>
                            <enumeratedValues>
                                </enumeratedValues>
                        </field>
                        <field>
                            <name>DOVCBHE</name>
                            <description>OVRCURB Interrupt Enable Clear</description>
                            <lsb>5</lsb>
                            <msb>5</msb>
                            <access>read-write</access>
                            <enumeratedValues>
                                </enumeratedValues>
                        </field>
                        <field>
                            <name>DVBSTSHE</name>
                            <description>VBUS Interrupt Enable/Clear</description>
                            <lsb>7</lsb>
                            <msb>7</msb>
                            <access>read-write</access>
                            <enumeratedValues>
                                </enumeratedValues>
                        </field>
                        <field>
                            <name>DOVCAH</name>
                            <description>OVRCURA Interrupt Source Return Status Flag</description>
                            <lsb>20</lsb>
                            <msb>20</msb>
                            <access>read-only</access>
                            <enumeratedValues>
                                </enumeratedValues>
                        </field>
                        <field>
                            <name>DOVCBH</name>
                            <description>OVRCURB Interrupt Source Return Status Flag</description>
                            <lsb>21</lsb>
                            <msb>21</msb>
                            <access>read-only</access>
                            <enumeratedValues>
                                </enumeratedValues>
                        </field>
                        <field>
                            <name>DVBSTSH</name>
                            <description>VBUS Interrupt Source Return Status Flag</description>
                            <lsb>23</lsb>
                            <msb>23</msb>
                            <access>read-only</access>
                            <enumeratedValues>
                                </enumeratedValues>
                        </field>
                    </fields>
                </register>
                <register>
                    <name>DPUSR2R</name>
                    <description>Deep Software Standby USB Suspend/Resume Interrupt Register</description>
                    <addressOffset>0x168</addressOffset>
                    <size>16</size>
                    <access>read-write</access>
                    <resetValue>0x0000</resetValue>
                    <resetMask>0xffff</resetMask>
                    <fields>
                        <field>
                            <name>DPINT</name>
                            <description>Indication of Return from DP Interrupt Source</description>
                            <lsb>0</lsb>
                            <msb>0</msb>
                            <access>read-only</access>
                            <enumeratedValues>
                                </enumeratedValues>
                        </field>
                        <field>
                            <name>DMINT</name>
                            <description>Indication of Return from DM Interrupt Source</description>
                            <lsb>1</lsb>
                            <msb>1</msb>
                            <access>read-only</access>
                            <enumeratedValues>
                                </enumeratedValues>
                        </field>
                        <field>
                            <name>DPVAL</name>
                            <description>DP Input</description>
                            <lsb>4</lsb>
                            <msb>4</msb>
                            <access>read-only</access>
                        </field>
                        <field>
                            <name>DMVAL</name>
                            <description>DM Input</description>
                            <lsb>5</lsb>
                            <msb>5</msb>
                            <access>read-only</access>
                        </field>
                        <field>
                            <name>DPINTE</name>
                            <description>DP Interrupt Enable Clear</description>
                            <lsb>8</lsb>
                            <msb>8</msb>
                            <access>read-write</access>
                            <enumeratedValues>
                                </enumeratedValues>
                        </field>
                        <field>
                            <name>DMINTE</name>
                            <description>DM Interrupt Enable Clear</description>
                            <lsb>9</lsb>
                            <msb>9</msb>
                            <access>read-write</access>
                            <enumeratedValues>
                                </enumeratedValues>
                        </field>
                    </fields>
                </register>
                <register>
                    <name>DPUSRCR</name>
                    <description>Deep Software Standby USB Suspend/Resume Command Register</description>
                    <addressOffset>0x16A</addressOffset>
                    <size>16</size>
                    <access>read-write</access>
                    <resetValue>0x0000</resetValue>
                    <resetMask>0xffff</resetMask>
                    <fields>
                        <field>
                            <name>FIXPHY</name>
                            <description>USB Transceiver Control Fix</description>
                            <lsb>0</lsb>
                            <msb>0</msb>
                            <access>read-write</access>
                            <enumeratedValues>
                                </enumeratedValues>
                        </field>
                        <field>
                            <name>FIXPHYPD</name>
                            <description>USB Transceiver Control Fix for PLL</description>
                            <lsb>1</lsb>
                            <msb>1</msb>
                            <access>read-write</access>
                            <enumeratedValues>
                                </enumeratedValues>
                        </field>
                    </fields>
                </register>
            </registers>
        </peripheral>
        <peripheral>
            <name>EDMAC0</name>
            <description>DMA Controller for the Ethernet Controller Channel 0</description>
            <baseAddress>0x40114000</baseAddress>
            <addressBlock>
                <offset>0x00</offset>
                <size>4</size>
                <usage>registers</usage>
            </addressBlock>
            <addressBlock>
                <offset>0x08</offset>
                <size>4</size>
                <usage>registers</usage>
            </addressBlock>
            <addressBlock>
                <offset>0x10</offset>
                <size>4</size>
                <usage>registers</usage>
            </addressBlock>
            <addressBlock>
                <offset>0x18</offset>
                <size>4</size>
                <usage>registers</usage>
            </addressBlock>
            <addressBlock>
                <offset>0x20</offset>
                <size>4</size>
                <usage>registers</usage>
            </addressBlock>
            <addressBlock>
                <offset>0x28</offset>
                <size>4</size>
                <usage>registers</usage>
            </addressBlock>
            <addressBlock>
                <offset>0x30</offset>
                <size>4</size>
                <usage>registers</usage>
            </addressBlock>
            <addressBlock>
                <offset>0x38</offset>
                <size>4</size>
                <usage>registers</usage>
            </addressBlock>
            <addressBlock>
                <offset>0x40</offset>
                <size>4</size>
                <usage>registers</usage>
            </addressBlock>
            <addressBlock>
                <offset>0x48</offset>
                <size>4</size>
                <usage>registers</usage>
            </addressBlock>
            <addressBlock>
                <offset>0x50</offset>
                <size>4</size>
                <usage>registers</usage>
            </addressBlock>
            <addressBlock>
                <offset>0x58</offset>
                <size>4</size>
                <usage>registers</usage>
            </addressBlock>
            <addressBlock>
                <offset>0x64</offset>
                <size>16</size>
                <usage>registers</usage>
            </addressBlock>
            <addressBlock>
                <offset>0x78</offset>
                <size>8</size>
                <usage>registers</usage>
            </addressBlock>
            <addressBlock>
                <offset>0xC8</offset>
                <size>8</size>
                <usage>registers</usage>
            </addressBlock>
            <addressBlock>
                <offset>0xD4</offset>
                <size>8</size>
                <usage>registers</usage>
            </addressBlock>
            <registers>
                <register>
                    <name>EDMR</name>
                    <description>EDMAC Mode Register</description>
                    <addressOffset>0x00</addressOffset>
                    <size>32</size>
                    <access>read-write</access>
                    <resetValue>0x00000000</resetValue>
                    <resetMask>0xffffffff</resetMask>
                    <fields>
                        <field>
                            <name>SWR</name>
                            <description>Software Reset</description>
                            <lsb>0</lsb>
                            <msb>0</msb>
                            <access>read-write</access>
                        </field>
                        <field>
                            <name>DL</name>
                            <description>Transmit/Receive Descriptor Length</description>
                            <lsb>4</lsb>
                            <msb>5</msb>
                            <access>read-write</access>
                            <enumeratedValues>
                                </enumeratedValues>
                        </field>
                        <field>
                            <name>DE</name>
                            <description>Big Endian Mode/Little Endian Mode</description>
                            <lsb>6</lsb>
                            <msb>6</msb>
                            <access>read-write</access>
                            <enumeratedValues>
                                </enumeratedValues>
                        </field>
                    </fields>
                </register>
                <register>
                    <name>EDTRR</name>
                    <description>EDMAC Transmit Request Register</description>
                    <addressOffset>0x08</addressOffset>
                    <size>32</size>
                    <access>read-write</access>
                    <resetValue>0x00000000</resetValue>
                    <resetMask>0xffffffff</resetMask>
                    <fields>
                        <field>
                            <name>TR</name>
                            <description>Transmit Request</description>
                            <lsb>0</lsb>
                            <msb>0</msb>
                            <access>read-write</access>
                        </field>
                    </fields>
                </register>
                <register>
                    <name>EDRRR</name>
                    <description>EDMAC Receive Request Register</description>
                    <addressOffset>0x10</addressOffset>
                    <size>32</size>
                    <access>read-write</access>
                    <resetValue>0x00000000</resetValue>
                    <resetMask>0xffffffff</resetMask>
                    <fields>
                        <field>
                            <name>RR</name>
                            <description>Receive Request</description>
                            <lsb>0</lsb>
                            <msb>0</msb>
                            <access>read-write</access>
                            <enumeratedValues>
                                </enumeratedValues>
                        </field>
                    </fields>
                </register>
                <register>
                    <name>TDLAR</name>
                    <description>Transmit Descriptor List Start Address Register</description>
                    <addressOffset>0x18</addressOffset>
                    <size>32</size>
                    <access>read-write</access>
                    <resetValue>0x00000000</resetValue>
                    <resetMask>0xffffffff</resetMask>
                </register>
                <register>
                    <name>RDLAR</name>
                    <description>Receive Descriptor List Start Address Register</description>
                    <addressOffset>0x20</addressOffset>
                    <size>32</size>
                    <access>read-write</access>
                    <resetValue>0x00000000</resetValue>
                    <resetMask>0xffffffff</resetMask>
                </register>
                <register>
                    <name>EESR</name>
                    <description>ETHERC/EDMAC Status Register</description>
                    <addressOffset>0x28</addressOffset>
                    <size>32</size>
                    <access>read-write</access>
                    <resetValue>0x00000000</resetValue>
                    <resetMask>0xffffffff</resetMask>
                    <fields>
                        <field>
                            <name>CERF</name>
                            <description>CRC Error Flag</description>
                            <lsb>0</lsb>
                            <msb>0</msb>
                            <access>read-write</access>
                            <enumeratedValues>
                                </enumeratedValues>
                        </field>
                        <field>
                            <name>PRE</name>
                            <description>PHY,LSI Receive Error Flag</description>
                            <lsb>1</lsb>
                            <msb>1</msb>
                            <access>read-write</access>
                            <enumeratedValues>
                                </enumeratedValues>
                        </field>
                        <field>
                            <name>RTSF</name>
                            <description>Frame,Too,Short Error Flag</description>
                            <lsb>2</lsb>
                            <msb>2</msb>
                            <access>read-write</access>
                            <enumeratedValues>
                                </enumeratedValues>
                        </field>
                        <field>
                            <name>RTLF</name>
                            <description>Frame,Too,Long Error Flag</description>
                            <lsb>3</lsb>
                            <msb>3</msb>
                            <access>read-write</access>
                            <enumeratedValues>
                                </enumeratedValues>
                        </field>
                        <field>
                            <name>RRF</name>
                            <description>Alignment Error Flag</description>
                            <lsb>4</lsb>
                            <msb>4</msb>
                            <access>read-write</access>
                            <enumeratedValues>
                                </enumeratedValues>
                        </field>
                        <field>
                            <name>RMAF</name>
                            <description>Multicast Address Frame Receive Flag</description>
                            <lsb>7</lsb>
                            <msb>7</msb>
                            <access>read-write</access>
                            <enumeratedValues>
                                </enumeratedValues>
                        </field>
                        <field>
                            <name>TRO</name>
                            <description>Transmit Retry Over Flag</description>
                            <lsb>8</lsb>
                            <msb>8</msb>
                            <access>read-write</access>
                            <enumeratedValues>
                                </enumeratedValues>
                        </field>
                        <field>
                            <name>CD</name>
                            <description>Late Collision Detect Flag</description>
                            <lsb>9</lsb>
                            <msb>9</msb>
                            <access>read-write</access>
                            <enumeratedValues>
                                </enumeratedValues>
                        </field>
                        <field>
                            <name>DLC</name>
                            <description>Loss of Carrier Detect Flag</description>
                            <lsb>10</lsb>
                            <msb>10</msb>
                            <access>read-write</access>
                            <enumeratedValues>
                                </enumeratedValues>
                        </field>
                        <field>
                            <name>CND</name>
                            <description>Carrier Not Detect Flag</description>
                            <lsb>11</lsb>
                            <msb>11</msb>
                            <access>read-write</access>
                            <enumeratedValues>
                                </enumeratedValues>
                        </field>
                        <field>
                            <name>RFOF</name>
                            <description>Receive FIFO Overflow Flag</description>
                            <lsb>16</lsb>
                            <msb>16</msb>
                            <access>read-write</access>
                            <enumeratedValues>
                                </enumeratedValues>
                        </field>
                        <field>
                            <name>RDE</name>
                            <description>Receive Descriptor Empty Flag</description>
                            <lsb>17</lsb>
                            <msb>17</msb>
                            <access>read-write</access>
                            <enumeratedValues>
                                </enumeratedValues>
                        </field>
                        <field>
                            <name>FR</name>
                            <description>Frame Receive Flag</description>
                            <lsb>18</lsb>
                            <msb>18</msb>
                            <access>read-write</access>
                            <enumeratedValues>
                                </enumeratedValues>
                        </field>
                        <field>
                            <name>TFUF</name>
                            <description>Transmit FIFO Underflow Flag</description>
                            <lsb>19</lsb>
                            <msb>19</msb>
                            <access>read-write</access>
                            <enumeratedValues>
                                </enumeratedValues>
                        </field>
                        <field>
                            <name>TDE</name>
                            <description>Transmit Descriptor Empty Flag</description>
                            <lsb>20</lsb>
                            <msb>20</msb>
                            <access>read-write</access>
                            <enumeratedValues>
                                </enumeratedValues>
                        </field>
                        <field>
                            <name>TC</name>
                            <description>Frame Transfer Complete Flag</description>
                            <lsb>21</lsb>
                            <msb>21</msb>
                            <access>read-write</access>
                            <enumeratedValues>
                                </enumeratedValues>
                        </field>
                        <field>
                            <name>ECI</name>
                            <description>ETHERC Status Register Source Flag</description>
                            <lsb>22</lsb>
                            <msb>22</msb>
                            <access>read-only</access>
                            <enumeratedValues>
                                </enumeratedValues>
                        </field>
                        <field>
                            <name>ADE</name>
                            <description>Address Error Flag</description>
                            <lsb>23</lsb>
                            <msb>23</msb>
                            <access>read-write</access>
                            <enumeratedValues>
                                </enumeratedValues>
                        </field>
                        <field>
                            <name>RFCOF</name>
                            <description>Receive Frame Counter Overflow Flag</description>
                            <lsb>24</lsb>
                            <msb>24</msb>
                            <access>read-write</access>
                            <enumeratedValues>
                                </enumeratedValues>
                        </field>
                        <field>
                            <name>RABT</name>
                            <description>Receive Abort Detect Flag</description>
                            <lsb>25</lsb>
                            <msb>25</msb>
                            <access>read-write</access>
                            <enumeratedValues>
                                </enumeratedValues>
                        </field>
                        <field>
                            <name>TABT</name>
                            <description>Transmit Abort Detect Flag</description>
                            <lsb>26</lsb>
                            <msb>26</msb>
                            <access>read-write</access>
                            <enumeratedValues>
                                </enumeratedValues>
                        </field>
                        <field>
                            <name>TWB</name>
                            <description>Write,Back Complete Flag</description>
                            <lsb>30</lsb>
                            <msb>30</msb>
                            <access>read-write</access>
                            <enumeratedValues>
                                </enumeratedValues>
                        </field>
                    </fields>
                </register>
                <register>
                    <name>EESIPR</name>
                    <description>ETHERC/EDMAC Status Interrupt Enable Register</description>
                    <addressOffset>0x30</addressOffset>
                    <size>32</size>
                    <access>read-write</access>
                    <resetValue>0x00000000</resetValue>
                    <resetMask>0xffffffff</resetMask>
                    <fields>
                        <field>
                            <name>CERFIP</name>
                            <description>CRC Error Interrupt Request Enable</description>
                            <lsb>0</lsb>
                            <msb>0</msb>
                            <access>read-write</access>
                            <enumeratedValues>
                                </enumeratedValues>
                        </field>
                        <field>
                            <name>PREIP</name>
                            <description>PHY,LSI Receive Error Interrupt Request Enable</description>
                            <lsb>1</lsb>
                            <msb>1</msb>
                            <access>read-write</access>
                            <enumeratedValues>
                                </enumeratedValues>
                        </field>
                        <field>
                            <name>RTSFIP</name>
                            <description>Frame,Too,Short Error Interrupt Request Enable</description>
                            <lsb>2</lsb>
                            <msb>2</msb>
                            <access>read-write</access>
                            <enumeratedValues>
                                </enumeratedValues>
                        </field>
                        <field>
                            <name>RTLFIP</name>
                            <description>Frame,Too,Long Error Interrupt Request Enable</description>
                            <lsb>3</lsb>
                            <msb>3</msb>
                            <access>read-write</access>
                            <enumeratedValues>
                                </enumeratedValues>
                        </field>
                        <field>
                            <name>RRFIP</name>
                            <description>Alignment Error Interrupt Request Enable</description>
                            <lsb>4</lsb>
                            <msb>4</msb>
                            <access>read-write</access>
                            <enumeratedValues>
                                </enumeratedValues>
                        </field>
                        <field>
                            <name>RMAFIP</name>
                            <description>Multicast Address Frame Receive Interrupt Request Enable</description>
                            <lsb>7</lsb>
                            <msb>7</msb>
                            <access>read-write</access>
                            <enumeratedValues>
                                </enumeratedValues>
                        </field>
                        <field>
                            <name>TROIP</name>
                            <description>Transmit Retry Over Interrupt Request Enable</description>
                            <lsb>8</lsb>
                            <msb>8</msb>
                            <access>read-write</access>
                            <enumeratedValues>
                                </enumeratedValues>
                        </field>
                        <field>
                            <name>CDIP</name>
                            <description>Late Collision Detect Interrupt Request Enable</description>
                            <lsb>9</lsb>
                            <msb>9</msb>
                            <access>read-write</access>
                            <enumeratedValues>
                                </enumeratedValues>
                        </field>
                        <field>
                            <name>DLCIP</name>
                            <description>Loss of Carrier Detect Interrupt Request Enable</description>
                            <lsb>10</lsb>
                            <msb>10</msb>
                            <access>read-write</access>
                            <enumeratedValues>
                                </enumeratedValues>
                        </field>
                        <field>
                            <name>CNDIP</name>
                            <description>Carrier Not Detect Interrupt Request Enable</description>
                            <lsb>11</lsb>
                            <msb>11</msb>
                            <access>read-write</access>
                            <enumeratedValues>
                                </enumeratedValues>
                        </field>
                        <field>
                            <name>RFOFIP</name>
                            <description>Receive FIFO Overflow Interrupt Request Enable</description>
                            <lsb>16</lsb>
                            <msb>16</msb>
                            <access>read-write</access>
                            <enumeratedValues>
                                </enumeratedValues>
                        </field>
                        <field>
                            <name>RDEIP</name>
                            <description>Receive Descriptor Empty Interrupt Request Enable</description>
                            <lsb>17</lsb>
                            <msb>17</msb>
                            <access>read-write</access>
                            <enumeratedValues>
                                </enumeratedValues>
                        </field>
                        <field>
                            <name>FRIP</name>
                            <description>Frame Receive Interrupt Request Enable</description>
                            <lsb>18</lsb>
                            <msb>18</msb>
                            <access>read-write</access>
                            <enumeratedValues>
                                </enumeratedValues>
                        </field>
                        <field>
                            <name>TFUFIP</name>
                            <description>Transmit FIFO Underflow Interrupt Request Enable</description>
                            <lsb>19</lsb>
                            <msb>19</msb>
                            <access>read-write</access>
                            <enumeratedValues>
                                </enumeratedValues>
                        </field>
                        <field>
                            <name>TDEIP</name>
                            <description>Transmit Descriptor Empty Interrupt Request Enable</description>
                            <lsb>20</lsb>
                            <msb>20</msb>
                            <access>read-write</access>
                            <enumeratedValues>
                                </enumeratedValues>
                        </field>
                        <field>
                            <name>TCIP</name>
                            <description>Frame Transfer Complete Interrupt Request Enable</description>
                            <lsb>21</lsb>
                            <msb>21</msb>
                            <access>read-write</access>
                            <enumeratedValues>
                                </enumeratedValues>
                        </field>
                        <field>
                            <name>ECIIP</name>
                            <description>ETHERC Status Register Source Interrupt Request Enable</description>
                            <lsb>22</lsb>
                            <msb>22</msb>
                            <access>read-write</access>
                            <enumeratedValues>
                                </enumeratedValues>
                        </field>
                        <field>
                            <name>ADEIP</name>
                            <description>Address Error Interrupt Request Enable</description>
                            <lsb>23</lsb>
                            <msb>23</msb>
                            <access>read-write</access>
                            <enumeratedValues>
                                </enumeratedValues>
                        </field>
                        <field>
                            <name>RFCOFIP</name>
                            <description>Receive Frame Counter Overflow Interrupt Request Enable</description>
                            <lsb>24</lsb>
                            <msb>24</msb>
                            <access>read-write</access>
                            <enumeratedValues>
                                </enumeratedValues>
                        </field>
                        <field>
                            <name>RABTIP</name>
                            <description>Receive Abort Detect Interrupt Request Enable</description>
                            <lsb>25</lsb>
                            <msb>25</msb>
                            <access>read-write</access>
                            <enumeratedValues>
                                </enumeratedValues>
                        </field>
                        <field>
                            <name>TABTIP</name>
                            <description>Transmit Abort Detect Interrupt Request Enable</description>
                            <lsb>26</lsb>
                            <msb>26</msb>
                            <access>read-write</access>
                            <enumeratedValues>
                                </enumeratedValues>
                        </field>
                        <field>
                            <name>TWBIP</name>
                            <description>Write,Back Complete Interrupt Request Enable</description>
                            <lsb>30</lsb>
                            <msb>30</msb>
                            <access>read-write</access>
                            <enumeratedValues>
                                </enumeratedValues>
                        </field>
                    </fields>
                </register>
                <register>
                    <name>TRSCER</name>
                    <description>ETHERC/EDMAC Transmit/Receive Status Copy Enable Register </description>
                    <addressOffset>0x38</addressOffset>
                    <size>32</size>
                    <access>read-write</access>
                    <resetValue>0x00000000</resetValue>
                    <resetMask>0xffffffff</resetMask>
                    <fields>
                        <field>
                            <name>RRFCE</name>
                            <description>RRF Flag Copy Enable</description>
                            <lsb>4</lsb>
                            <msb>4</msb>
                            <access>read-write</access>
                            <enumeratedValues>
                                </enumeratedValues>
                        </field>
                        <field>
                            <name>RMAFCE</name>
                            <description>RMAF Flag Copy Enable</description>
                            <lsb>7</lsb>
                            <msb>7</msb>
                            <access>read-write</access>
                            <enumeratedValues>
                                </enumeratedValues>
                        </field>
                    </fields>
                </register>
                <register>
                    <name>RMFCR</name>
                    <description>Missed,Frame Counter Register</description>
                    <addressOffset>0x40</addressOffset>
                    <size>32</size>
                    <access>read-write</access>
                    <resetValue>0x00000000</resetValue>
                    <resetMask>0xffffffff</resetMask>
                    <fields>
                        <field>
                            <name>MFC</name>
                            <description>Missed,Frame Counter</description>
                            <lsb>0</lsb>
                            <msb>15</msb>
                            <access>read-write</access>
                        </field>
                    </fields>
                </register>
                <register>
                    <name>TFTR</name>
                    <description>Transmit FIFO Threshold Register</description>
                    <addressOffset>0x48</addressOffset>
                    <size>32</size>
                    <access>read-write</access>
                    <resetValue>0x00000000</resetValue>
                    <resetMask>0xffffffff</resetMask>
                    <fields>
                        <field>
                            <name>TFT</name>
                            <description>Transmit FIFO Threshold</description>
                            <lsb>0</lsb>
                            <msb>10</msb>
                            <access>read-write</access>
                        </field>
                    </fields>
                </register>
                <register>
                    <name>FDR</name>
                    <description>FIFO Depth Register</description>
                    <addressOffset>0x50</addressOffset>
                    <size>32</size>
                    <access>read-write</access>
                    <resetValue>0x00000000</resetValue>
                    <resetMask>0xffffffff</resetMask>
                    <fields>
                        <field>
                            <name>RFD</name>
                            <description>Receive FIFO Depth</description>
                            <lsb>0</lsb>
                            <msb>4</msb>
                            <access>read-write</access>
                            <enumeratedValues>
                                </enumeratedValues>
                        </field>
                        <field>
                            <name>TFD</name>
                            <description>Transmit FIFO Depth</description>
                            <lsb>8</lsb>
                            <msb>12</msb>
                            <access>read-write</access>
                            <enumeratedValues>
                                </enumeratedValues>
                        </field>
                    </fields>
                </register>
                <register>
                    <name>RMCR</name>
                    <description>Receive Method Control Register</description>
                    <addressOffset>0x58</addressOffset>
                    <size>32</size>
                    <access>read-write</access>
                    <resetValue>0x00000000</resetValue>
                    <resetMask>0xffffffff</resetMask>
                    <fields>
                        <field>
                            <name>RNR</name>
                            <description>Receive Request Reset</description>
                            <lsb>0</lsb>
                            <msb>0</msb>
                            <access>read-write</access>
                            <enumeratedValues>
                                </enumeratedValues>
                        </field>
                    </fields>
                </register>
                <register>
                    <name>TFUCR</name>
                    <description>Transmit FIFO Underflow Counter</description>
                    <addressOffset>0x64</addressOffset>
                    <size>32</size>
                    <access>read-write</access>
                    <resetValue>0x00000000</resetValue>
                    <resetMask>0xffffffff</resetMask>
                    <fields>
                        <field>
                            <name>UNDER</name>
                            <description>Transmit FIFO Underflow Count</description>
                            <lsb>0</lsb>
                            <msb>15</msb>
                            <access>read-write</access>
                        </field>
                    </fields>
                </register>
                <register>
                    <name>RFOCR</name>
                    <description>Receive FIFO Overflow Counter</description>
                    <addressOffset>0x68</addressOffset>
                    <size>32</size>
                    <access>read-write</access>
                    <resetValue>0x00000000</resetValue>
                    <resetMask>0xffffffff</resetMask>
                    <fields>
                        <field>
                            <name>OVER</name>
                            <description>Receive FIFO Overflow Count</description>
                            <lsb>0</lsb>
                            <msb>15</msb>
                            <access>read-write</access>
                        </field>
                    </fields>
                </register>
                <register>
                    <name>IOSR</name>
                    <description>Independent Output Signal Setting Register</description>
                    <addressOffset>0x6C</addressOffset>
                    <size>32</size>
                    <access>read-write</access>
                    <resetValue>0x00000000</resetValue>
                    <resetMask>0xffffffff</resetMask>
                    <fields>
                        <field>
                            <name>ELB</name>
                            <description>External Loopback Mode</description>
                            <lsb>0</lsb>
                            <msb>0</msb>
                            <access>read-write</access>
                            <enumeratedValues>
                                </enumeratedValues>
                        </field>
                    </fields>
                </register>
                <register>
                    <name>FCFTR</name>
                    <description>Flow Control Start FIFO Threshold Setting Register</description>
                    <addressOffset>0x70</addressOffset>
                    <size>32</size>
                    <access>read-write</access>
                    <resetValue>0x00070007</resetValue>
                    <resetMask>0xffffffff</resetMask>
                    <fields>
                        <field>
                            <name>RFDO</name>
                            <description>Receive FIFO Data PAUSE Output Threshold</description>
                            <lsb>0</lsb>
                            <msb>2</msb>
                            <access>read-write</access>
                        </field>
                        <field>
                            <name>RFFO</name>
                            <description>Receive FIFO Frame PAUSE Output Threshold</description>
                            <lsb>16</lsb>
                            <msb>18</msb>
                            <access>read-write</access>
                        </field>
                    </fields>
                </register>
                <register>
                    <name>RPADIR</name>
                    <description>Receive Data Padding Insert Register</description>
                    <addressOffset>0x78</addressOffset>
                    <size>32</size>
                    <access>read-write</access>
                    <resetValue>0x00000000</resetValue>
                    <resetMask>0xffffffff</resetMask>
                    <fields>
                        <field>
                            <name>PADR</name>
                            <description>Padding Slot</description>
                            <lsb>0</lsb>
                            <msb>5</msb>
                            <access>read-write</access>
                        </field>
                        <field>
                            <name>PADS</name>
                            <description>Padding Size</description>
                            <lsb>16</lsb>
                            <msb>17</msb>
                            <access>read-write</access>
                            <enumeratedValues>
                                </enumeratedValues>
                        </field>
                    </fields>
                </register>
                <register>
                    <name>TRIMD</name>
                    <description>Transmit Interrupt Setting Register</description>
                    <addressOffset>0x7C</addressOffset>
                    <size>32</size>
                    <access>read-write</access>
                    <resetValue>0x00000000</resetValue>
                    <resetMask>0xffffffff</resetMask>
                    <fields>
                        <field>
                            <name>TIS</name>
                            <description>Transmit Interrupt Enable</description>
                            <lsb>0</lsb>
                            <msb>0</msb>
                            <access>read-write</access>
                            <enumeratedValues>
                                </enumeratedValues>
                        </field>
                        <field>
                            <name>TIM</name>
                            <description>Transmit Interrupt Mode</description>
                            <lsb>4</lsb>
                            <msb>4</msb>
                            <access>read-write</access>
                            <enumeratedValues>
                                </enumeratedValues>
                        </field>
                    </fields>
                </register>
                <register>
                    <name>RBWAR</name>
                    <description>Receive Buffer Write Address Register</description>
                    <addressOffset>0xC8</addressOffset>
                    <size>32</size>
                    <access>read-only</access>
                    <resetValue>0x00000000</resetValue>
                    <resetMask>0xffffffff</resetMask>
                </register>
                <register>
                    <name>RDFAR</name>
                    <description>Receive Descriptor Fetch Address Register</description>
                    <addressOffset>0xCC</addressOffset>
                    <size>32</size>
                    <access>read-only</access>
                    <resetValue>0x00000000</resetValue>
                    <resetMask>0xffffffff</resetMask>
                </register>
                <register>
                    <name>TBRAR</name>
                    <description>Transmit Buffer Read Address Register</description>
                    <addressOffset>0xD4</addressOffset>
                    <size>32</size>
                    <access>read-only</access>
                    <resetValue>0x00000000</resetValue>
                    <resetMask>0xffffffff</resetMask>
                </register>
                <register>
                    <name>TDFAR</name>
                    <description>Transmit Descriptor Fetch Address Register</description>
                    <addressOffset>0xD8</addressOffset>
                    <size>32</size>
                    <access>read-only</access>
                    <resetValue>0x00000000</resetValue>
                    <resetMask>0xffffffff</resetMask>
                </register>
            </registers>
        </peripheral>
        <peripheral>
            <name>ETHERC0</name>
            <description>Ethernet Controller Channel 0</description>
            <baseAddress>0x40114100</baseAddress>
            <addressBlock>
                <offset>0x00</offset>
                <size>4</size>
                <usage>registers</usage>
            </addressBlock>
            <addressBlock>
                <offset>0x08</offset>
                <size>4</size>
                <usage>registers</usage>
            </addressBlock>
            <addressBlock>
                <offset>0x10</offset>
                <size>4</size>
                <usage>registers</usage>
            </addressBlock>
            <addressBlock>
                <offset>0x18</offset>
                <size>4</size>
                <usage>registers</usage>
            </addressBlock>
            <addressBlock>
                <offset>0x20</offset>
                <size>4</size>
                <usage>registers</usage>
            </addressBlock>
            <addressBlock>
                <offset>0x28</offset>
                <size>4</size>
                <usage>registers</usage>
            </addressBlock>
            <addressBlock>
                <offset>0x40</offset>
                <size>4</size>
                <usage>registers</usage>
            </addressBlock>
            <addressBlock>
                <offset>0x50</offset>
                <size>12</size>
                <usage>registers</usage>
            </addressBlock>
            <addressBlock>
                <offset>0x60</offset>
                <size>16</size>
                <usage>registers</usage>
            </addressBlock>
            <addressBlock>
                <offset>0xC0</offset>
                <size>4</size>
                <usage>registers</usage>
            </addressBlock>
            <addressBlock>
                <offset>0xC8</offset>
                <size>4</size>
                <usage>registers</usage>
            </addressBlock>
            <addressBlock>
                <offset>0xD0</offset>
                <size>16</size>
                <usage>registers</usage>
            </addressBlock>
            <addressBlock>
                <offset>0xE4</offset>
                <size>24</size>
                <usage>registers</usage>
            </addressBlock>
            <registers>
                <register>
                    <name>ECMR</name>
                    <description>ETHERC Mode Register</description>
                    <addressOffset>0x00</addressOffset>
                    <size>32</size>
                    <access>read-write</access>
                    <resetValue>0x00000000</resetValue>
                    <resetMask>0xffffffff</resetMask>
                    <fields>
                        <field>
                            <name>PRM</name>
                            <description>Promiscuous Mode</description>
                            <lsb>0</lsb>
                            <msb>0</msb>
                            <access>read-write</access>
                            <enumeratedValues>
                                </enumeratedValues>
                        </field>
                        <field>
                            <name>DM</name>
                            <description>Duplex Mode</description>
                            <lsb>1</lsb>
                            <msb>1</msb>
                            <access>read-write</access>
                            <enumeratedValues>
                                </enumeratedValues>
                        </field>
                        <field>
                            <name>RTM</name>
                            <description>Bit Rate</description>
                            <lsb>2</lsb>
                            <msb>2</msb>
                            <access>read-write</access>
                            <enumeratedValues>
                                </enumeratedValues>
                        </field>
                        <field>
                            <name>ILB</name>
                            <description>Internal Loopback Mode</description>
                            <lsb>3</lsb>
                            <msb>3</msb>
                            <access>read-write</access>
                            <enumeratedValues>
                                </enumeratedValues>
                        </field>
                        <field>
                            <name>TE</name>
                            <description>Transmission Enable</description>
                            <lsb>5</lsb>
                            <msb>5</msb>
                            <access>read-write</access>
                            <enumeratedValues>
                                </enumeratedValues>
                        </field>
                        <field>
                            <name>RE</name>
                            <description>Reception Enable</description>
                            <lsb>6</lsb>
                            <msb>6</msb>
                            <access>read-write</access>
                            <enumeratedValues>
                                </enumeratedValues>
                        </field>
                        <field>
                            <name>MPDE</name>
                            <description>Magic Packet Detection Enable</description>
                            <lsb>9</lsb>
                            <msb>9</msb>
                            <access>read-write</access>
                            <enumeratedValues>
                                </enumeratedValues>
                        </field>
                        <field>
                            <name>PRCEF</name>
                            <description>CRC Error Frame Receive Mode</description>
                            <lsb>12</lsb>
                            <msb>12</msb>
                            <access>read-write</access>
                            <enumeratedValues>
                                </enumeratedValues>
                        </field>
                        <field>
                            <name>TXF</name>
                            <description>Transmit Flow Control Operating Mode</description>
                            <lsb>16</lsb>
                            <msb>16</msb>
                            <access>read-write</access>
                            <enumeratedValues>
                                </enumeratedValues>
                        </field>
                        <field>
                            <name>RXF</name>
                            <description>Receive Flow Control Operating Mode</description>
                            <lsb>17</lsb>
                            <msb>17</msb>
                            <access>read-write</access>
                            <enumeratedValues>
                                </enumeratedValues>
                        </field>
                        <field>
                            <name>PFR</name>
                            <description>PAUSE Frame Receive Mode</description>
                            <lsb>18</lsb>
                            <msb>18</msb>
                            <access>read-write</access>
                            <enumeratedValues>
                                </enumeratedValues>
                        </field>
                        <field>
                            <name>ZPF</name>
                            <description>0 Time PAUSE Frame Enable</description>
                            <lsb>19</lsb>
                            <msb>19</msb>
                            <access>read-write</access>
                            <enumeratedValues>
                                </enumeratedValues>
                        </field>
                        <field>
                            <name>TPC</name>
                            <description>PAUSE Frame Transmit</description>
                            <lsb>20</lsb>
                            <msb>20</msb>
                            <access>read-write</access>
                            <enumeratedValues>
                                </enumeratedValues>
                        </field>
                    </fields>
                </register>
                <register>
                    <name>RFLR</name>
                    <description>Receive Frame Maximum Length Register</description>
                    <addressOffset>0x08</addressOffset>
                    <size>32</size>
                    <access>read-write</access>
                    <resetValue>0x00000000</resetValue>
                    <resetMask>0xffffffff</resetMask>
                    <fields>
                        <field>
                            <name>RFL</name>
                            <description>Receive Frame Maximum Length</description>
                            <lsb>0</lsb>
                            <msb>11</msb>
                            <access>read-write</access>
                        </field>
                    </fields>
                </register>
                <register>
                    <name>ECSR</name>
                    <description>ETHERC Status Register</description>
                    <addressOffset>0x10</addressOffset>
                    <size>32</size>
                    <access>read-write</access>
                    <resetValue>0x00000000</resetValue>
                    <resetMask>0xffffffff</resetMask>
                    <fields>
                        <field>
                            <name>ICD</name>
                            <description>False Carrier Detect Flag</description>
                            <lsb>0</lsb>
                            <msb>0</msb>
                            <access>read-write</access>
                            <enumeratedValues>
                                </enumeratedValues>
                        </field>
                        <field>
                            <name>MPD</name>
                            <description>Magic Packet Detect Flag</description>
                            <lsb>1</lsb>
                            <msb>1</msb>
                            <access>read-write</access>
                            <enumeratedValues>
                                </enumeratedValues>
                        </field>
                        <field>
                            <name>LCHNG</name>
                            <description>Link Signal Change Flag</description>
                            <lsb>2</lsb>
                            <msb>2</msb>
                            <access>read-write</access>
                            <enumeratedValues>
                                </enumeratedValues>
                        </field>
                        <field>
                            <name>PSRTO</name>
                            <description>PAUSE Frame Retransmit Over Flag</description>
                            <lsb>4</lsb>
                            <msb>4</msb>
                            <access>read-write</access>
                            <enumeratedValues>
                                </enumeratedValues>
                        </field>
                        <field>
                            <name>BFR</name>
                            <description>Continuous Broadcast Frame Reception Flag</description>
                            <lsb>5</lsb>
                            <msb>5</msb>
                            <access>read-write</access>
                            <enumeratedValues>
                                </enumeratedValues>
                        </field>
                    </fields>
                </register>
                <register>
                    <name>ECSIPR</name>
                    <description>ETHERC Interrupt Enable Register</description>
                    <addressOffset>0x18</addressOffset>
                    <size>32</size>
                    <access>read-write</access>
                    <resetValue>0x00000000</resetValue>
                    <resetMask>0xffffffff</resetMask>
                    <fields>
                        <field>
                            <name>ICDIP</name>
                            <description>False Carrier Detect Interrupt Enable</description>
                            <lsb>0</lsb>
                            <msb>0</msb>
                            <access>read-write</access>
                            <enumeratedValues>
                                </enumeratedValues>
                        </field>
                        <field>
                            <name>MPDIP</name>
                            <description>Magic Packet Detect Interrupt Enable</description>
                            <lsb>1</lsb>
                            <msb>1</msb>
                            <access>read-write</access>
                            <enumeratedValues>
                                </enumeratedValues>
                        </field>
                        <field>
                            <name>LCHNGIP</name>
                            <description>LINK Signal Change Interrupt Enable</description>
                            <lsb>2</lsb>
                            <msb>2</msb>
                            <access>read-write</access>
                            <enumeratedValues>
                                </enumeratedValues>
                        </field>
                        <field>
                            <name>PSRTOIP</name>
                            <description>PAUSE Frame Retransmit Over Interrupt Enable</description>
                            <lsb>4</lsb>
                            <msb>4</msb>
                            <access>read-write</access>
                            <enumeratedValues>
                                </enumeratedValues>
                        </field>
                        <field>
                            <name>BFSIPR</name>
                            <description>Continuous Broadcast Frame Reception Interrupt Enable</description>
                            <lsb>5</lsb>
                            <msb>5</msb>
                            <access>read-write</access>
                            <enumeratedValues>
                                </enumeratedValues>
                        </field>
                    </fields>
                </register>
                <register>
                    <name>PIR</name>
                    <description>PHY Interface Register</description>
                    <addressOffset>0x20</addressOffset>
                    <size>32</size>
                    <access>read-write</access>
                    <resetValue>0x00000000</resetValue>
                    <resetMask>0xfffffff7</resetMask>
                    <fields>
                        <field>
                            <name>MDC</name>
                            <description>MII/RMII Management Data Clock</description>
                            <lsb>0</lsb>
                            <msb>0</msb>
                            <access>read-write</access>
                        </field>
                        <field>
                            <name>MMD</name>
                            <description>MII/RMII Management Mode</description>
                            <lsb>1</lsb>
                            <msb>1</msb>
                            <access>read-write</access>
                            <enumeratedValues>
                                </enumeratedValues>
                        </field>
                        <field>
                            <name>MDO</name>
                            <description>MII/RMII Management Data,Out</description>
                            <lsb>2</lsb>
                            <msb>2</msb>
                            <access>read-write</access>
                        </field>
                        <field>
                            <name>MDI</name>
                            <description>MII/RMII Management Data,In</description>
                            <lsb>3</lsb>
                            <msb>3</msb>
                            <access>read-only</access>
                        </field>
                    </fields>
                </register>
                <register>
                    <name>PSR</name>
                    <description>PHY Status Register</description>
                    <addressOffset>0x28</addressOffset>
                    <size>32</size>
                    <access>read-only</access>
                    <resetValue>0x00000000</resetValue>
                    <resetMask>0xfffffffe</resetMask>
                    <fields>
                        <field>
                            <name>LMON</name>
                            <description>ET0_LINKSTA Pin Status Flag</description>
                            <lsb>0</lsb>
                            <msb>0</msb>
                            <access>read-only</access>
                        </field>
                    </fields>
                </register>
                <register>
                    <name>RDMLR</name>
                    <description>Random Number Generation Counter Upper Limit Setting Register</description>
                    <addressOffset>0x40</addressOffset>
                    <size>32</size>
                    <access>read-write</access>
                    <resetValue>0x00000000</resetValue>
                    <resetMask>0xffff0000</resetMask>
                    <fields>
                        <field>
                            <name>RMD</name>
                            <description>Random Number Generation Counter</description>
                            <lsb>0</lsb>
                            <msb>19</msb>
                            <access>read-write</access>
                        </field>
                    </fields>
                </register>
                <register>
                    <name>IPGR</name>
                    <description>Interpacket Gap Register</description>
                    <addressOffset>0x50</addressOffset>
                    <size>32</size>
                    <access>read-write</access>
                    <resetValue>0x00000014</resetValue>
                    <resetMask>0xffffffff</resetMask>
                    <fields>
                        <field>
                            <name>IPG</name>
                            <lsb>0</lsb>
                            <msb>4</msb>
                            <access>read-write</access>
                        </field>
                    </fields>
                </register>
                <register>
                    <name>APR</name>
                    <description>Automatic PAUSE Frame Register</description>
                    <addressOffset>0x54</addressOffset>
                    <size>32</size>
                    <access>read-write</access>
                    <resetValue>0x00000000</resetValue>
                    <resetMask>0xffffffff</resetMask>
                    <fields>
                        <field>
                            <name>AP</name>
                            <description>Automatic PAUSE Time Setting</description>
                            <lsb>0</lsb>
                            <msb>15</msb>
                            <access>read-write</access>
                        </field>
                    </fields>
                </register>
                <register>
                    <name>MPR</name>
                    <description>Manual PAUSE Frame Register</description>
                    <addressOffset>0x58</addressOffset>
                    <size>32</size>
                    <access>read-write</access>
                    <resetValue>0x00000000</resetValue>
                    <resetMask>0xffff0000</resetMask>
                    <fields>
                        <field>
                            <name>MP</name>
                            <description>Manual PAUSE Time Setting</description>
                            <lsb>0</lsb>
                            <msb>15</msb>
                            <access>read-write</access>
                        </field>
                    </fields>
                </register>
                <register>
                    <name>RFCF</name>
                    <description>Received PAUSE Frame Counter</description>
                    <addressOffset>0x60</addressOffset>
                    <size>32</size>
                    <access>read-only</access>
                    <resetValue>0x00000000</resetValue>
                    <resetMask>0xffffffff</resetMask>
                    <fields>
                        <field>
                            <name>RPAUSE</name>
                            <description>Received PAUSE Frame Count</description>
                            <lsb>0</lsb>
                            <msb>7</msb>
                            <access>read-only</access>
                        </field>
                    </fields>
                </register>
                <register>
                    <name>TPAUSER</name>
                    <description>PAUSE Frame Retransmit Count Setting Register</description>
                    <addressOffset>0x64</addressOffset>
                    <size>32</size>
                    <access>read-write</access>
                    <resetValue>0x00000000</resetValue>
                    <resetMask>0xffffffff</resetMask>
                    <fields>
                        <field>
                            <name>TPAUSE</name>
                            <lsb>0</lsb>
                            <msb>15</msb>
                            <access>read-write</access>
                        </field>
                    </fields>
                </register>
                <register>
                    <name>TPAUSECR</name>
                    <description>PAUSE Frame Retransmit Counter</description>
                    <addressOffset>0x68</addressOffset>
                    <size>32</size>
                    <access>read-only</access>
                    <resetValue>0x00000000</resetValue>
                    <resetMask>0xffffffff</resetMask>
                    <fields>
                        <field>
                            <name>TXP</name>
                            <description>PAUSE Frame Retransmit Count</description>
                            <lsb>0</lsb>
                            <msb>7</msb>
                            <access>read-only</access>
                        </field>
                    </fields>
                </register>
                <register>
                    <name>BCFRR</name>
                    <description>Broadcast Frame Receive Count Setting Register</description>
                    <addressOffset>0x6C</addressOffset>
                    <size>32</size>
                    <access>read-write</access>
                    <resetValue>0x00000000</resetValue>
                    <resetMask>0xffffffff</resetMask>
                    <fields>
                        <field>
                            <name>BCF</name>
                            <lsb>0</lsb>
                            <msb>15</msb>
                            <access>read-write</access>
                        </field>
                    </fields>
                </register>
                <register>
                    <name>MAHR</name>
                    <description>MAC Address Upper Bit Register</description>
                    <addressOffset>0xC0</addressOffset>
                    <size>32</size>
                    <access>read-write</access>
                    <resetValue>0x00000000</resetValue>
                    <resetMask>0xffffffff</resetMask>
                    <fields>
                        <field>
                            <name>MAHR</name>
                            <description>MAC Address Upper Bit</description>
                            <lsb>0</lsb>
                            <msb>31</msb>
                            <access>read-write</access>
                        </field>
                    </fields>
                </register>
                <register>
                    <name>MALR</name>
                    <description>MAC Address Lower Bit Register</description>
                    <addressOffset>0xC8</addressOffset>
                    <size>32</size>
                    <access>read-write</access>
                    <resetValue>0x00000000</resetValue>
                    <resetMask>0xffffffff</resetMask>
                    <fields>
                        <field>
                            <name>MALR</name>
                            <description>MAC Address Lower Bit</description>
                            <lsb>0</lsb>
                            <msb>15</msb>
                            <access>read-write</access>
                        </field>
                    </fields>
                </register>
                <register>
                    <name>TROCR</name>
                    <description>Transmit Retry Over Counter Register</description>
                    <addressOffset>0xD0</addressOffset>
                    <size>32</size>
                    <access>read-write</access>
                    <resetValue>0x00000000</resetValue>
                    <resetMask>0xffffffff</resetMask>
                    <fields>
                        <field>
                            <name>TROCR</name>
                            <description>Transmit Retry Over Counter</description>
                            <lsb>0</lsb>
                            <msb>31</msb>
                            <access>read-write</access>
                        </field>
                    </fields>
                </register>
                <register>
                    <name>CDCR</name>
                    <description>Late Collision Detect Counter Register</description>
                    <addressOffset>0xD4</addressOffset>
                    <size>32</size>
                    <access>read-write</access>
                    <resetValue>0x00000000</resetValue>
                    <resetMask>0xffffffff</resetMask>
                    <fields>
                        <field>
                            <name>CDCR</name>
                            <description>Late Collision Detect Counter</description>
                            <lsb>0</lsb>
                            <msb>31</msb>
                            <access>read-write</access>
                        </field>
                    </fields>
                </register>
                <register>
                    <name>LCCR</name>
                    <description>Lost Carrier Counter Register</description>
                    <addressOffset>0xD8</addressOffset>
                    <size>32</size>
                    <access>read-write</access>
                    <resetValue>0x00000000</resetValue>
                    <resetMask>0xffffffff</resetMask>
                    <fields>
                        <field>
                            <name>LCCR</name>
                            <description>Lost Carrier Counter</description>
                            <lsb>0</lsb>
                            <msb>31</msb>
                            <access>read-write</access>
                        </field>
                    </fields>
                </register>
                <register>
                    <name>CNDCR</name>
                    <description>Carrier Not Detect Counter Register</description>
                    <addressOffset>0xDC</addressOffset>
                    <size>32</size>
                    <access>read-write</access>
                    <resetValue>0x00000000</resetValue>
                    <resetMask>0xffffffff</resetMask>
                    <fields>
                        <field>
                            <name>CNDCR</name>
                            <description>Carrier Not Detect Counter</description>
                            <lsb>0</lsb>
                            <msb>31</msb>
                            <access>read-write</access>
                        </field>
                    </fields>
                </register>
                <register>
                    <name>CEFCR</name>
                    <description>CRC Error Frame Receive Counter Register</description>
                    <addressOffset>0xE4</addressOffset>
                    <size>32</size>
                    <access>read-write</access>
                    <resetValue>0x00000000</resetValue>
                    <resetMask>0xffffffff</resetMask>
                    <fields>
                        <field>
                            <name>CEFCR</name>
                            <description>CRC Error Frame Receive Counter</description>
                            <lsb>0</lsb>
                            <msb>31</msb>
                            <access>read-write</access>
                        </field>
                    </fields>
                </register>
                <register>
                    <name>FRECR</name>
                    <description>Frame Receive Error Counter Register</description>
                    <addressOffset>0xE8</addressOffset>
                    <size>32</size>
                    <access>read-write</access>
                    <resetValue>0x00000000</resetValue>
                    <resetMask>0xffffffff</resetMask>
                    <fields>
                        <field>
                            <name>FRECR</name>
                            <description>Frame Receive Error Counter</description>
                            <lsb>0</lsb>
                            <msb>31</msb>
                            <access>read-write</access>
                        </field>
                    </fields>
                </register>
                <register>
                    <name>TSFRCR</name>
                    <description>Too,Short Frame Receive Counter Register</description>
                    <addressOffset>0xEC</addressOffset>
                    <size>32</size>
                    <access>read-write</access>
                    <resetValue>0x00000000</resetValue>
                    <resetMask>0xffffffff</resetMask>
                    <fields>
                        <field>
                            <name>TSFRCR</name>
                            <description>Too,Short Frame Receive Counter</description>
                            <lsb>0</lsb>
                            <msb>31</msb>
                            <access>read-write</access>
                        </field>
                    </fields>
                </register>
                <register>
                    <name>TLFRCR</name>
                    <description>Too,Long Frame Receive Counter Register</description>
                    <addressOffset>0xF0</addressOffset>
                    <size>32</size>
                    <access>read-write</access>
                    <resetValue>0x00000000</resetValue>
                    <resetMask>0xffffffff</resetMask>
                    <fields>
                        <field>
                            <name>TLFRCR</name>
                            <description>Too,Long Frame Receive Counter</description>
                            <lsb>0</lsb>
                            <msb>31</msb>
                            <access>read-write</access>
                        </field>
                    </fields>
                </register>
                <register>
                    <name>RFCR</name>
                    <description>Received Alignment Error Frame Counter Register</description>
                    <addressOffset>0xF4</addressOffset>
                    <size>32</size>
                    <access>read-write</access>
                    <resetValue>0x00000000</resetValue>
                    <resetMask>0xffffffff</resetMask>
                    <fields>
                        <field>
                            <name>RFCR</name>
                            <description>Received Alignment Error Frame Counter</description>
                            <lsb>0</lsb>
                            <msb>31</msb>
                            <access>read-write</access>
                        </field>
                    </fields>
                </register>
                <register>
                    <name>MAFCR</name>
                    <description>Multicast Address Frame Receive Counter Register</description>
                    <addressOffset>0xF8</addressOffset>
                    <size>32</size>
                    <access>read-write</access>
                    <resetValue>0x00000000</resetValue>
                    <resetMask>0xffffffff</resetMask>
                    <fields>
                        <field>
                            <name>MAFCR</name>
                            <description>Multicast Address Frame Receive Counter</description>
                            <lsb>0</lsb>
                            <msb>31</msb>
                            <access>read-write</access>
                        </field>
                    </fields>
                </register>
            </registers>
        </peripheral>
        <peripheral>
            <name>SCI0</name>
            <description>Serial Communication Interface</description>
            <baseAddress>0x40118000</baseAddress>
            <addressBlock>
                <offset>0x00</offset>
                <size>30</size>
                <usage>registers</usage>
            </addressBlock>
            <registers>
                <register>
                    <name>SMR</name>
                    <description>Serial Mode Register for Non,Smart Card Interface Mode (SCMR.SMIF = 0)</description>
                    <addressOffset>0x00</addressOffset>
                    <size>8</size>
                    <access>read-write</access>
                    <resetValue>0x00</resetValue>
                    <resetMask>0xff</resetMask>
                    <fields>
                        <field>
                            <name>CKS</name>
                            <description>Clock Select</description>
                            <lsb>0</lsb>
                            <msb>1</msb>
                            <access>read-write</access>
                            <enumeratedValues>
                                </enumeratedValues>
                        </field>
                        <field>
                            <name>MP</name>
                            <description>Multi,Processor Mode</description>
                            <lsb>2</lsb>
                            <msb>2</msb>
                            <access>read-write</access>
                            <enumeratedValues>
                                </enumeratedValues>
                        </field>
                        <field>
                            <name>STOP</name>
                            <description>Stop Bit Length</description>
                            <lsb>3</lsb>
                            <msb>3</msb>
                            <access>read-write</access>
                            <enumeratedValues>
                                </enumeratedValues>
                        </field>
                        <field>
                            <name>PM</name>
                            <description>Parity Mode</description>
                            <lsb>4</lsb>
                            <msb>4</msb>
                            <access>read-write</access>
                            <enumeratedValues>
                                </enumeratedValues>
                        </field>
                        <field>
                            <name>PE</name>
                            <description>Parity Enable</description>
                            <lsb>5</lsb>
                            <msb>5</msb>
                            <access>read-write</access>
                            <enumeratedValues>
                                </enumeratedValues>
                        </field>
                        <field>
                            <name>CHR</name>
                            <description>Character Length</description>
                            <lsb>6</lsb>
                            <msb>6</msb>
                            <access>read-write</access>
                            <enumeratedValues>
                                </enumeratedValues>
                        </field>
                        <field>
                            <name>CM</name>
                            <description>Communication Mode</description>
                            <lsb>7</lsb>
                            <msb>7</msb>
                            <access>read-write</access>
                            <enumeratedValues>
                                </enumeratedValues>
                        </field>
                    </fields>
                </register>
                <register>
                    <name>SMR_SMCI</name>
                    <description>Serial Mode Register for Smart Card Interface Mode (SCMR.SMIF = 1)</description>
                    <alternateRegister>SMR</alternateRegister>
                    <addressOffset>0x00</addressOffset>
                    <size>8</size>
                    <access>read-write</access>
                    <resetValue>0x00</resetValue>
                    <resetMask>0xff</resetMask>
                    <fields>
                        <field>
                            <name>CKS</name>
                            <description>Clock Select</description>
                            <lsb>0</lsb>
                            <msb>1</msb>
                            <access>read-write</access>
                            <enumeratedValues>
                                </enumeratedValues>
                        </field>
                        <field>
                            <name>BCP</name>
                            <description>Base Clock Pulse</description>
                            <lsb>2</lsb>
                            <msb>3</msb>
                            <access>read-write</access>
                        </field>
                        <field>
                            <name>PM</name>
                            <description>Parity Mode</description>
                            <lsb>4</lsb>
                            <msb>4</msb>
                            <access>read-write</access>
                            <enumeratedValues>
                                </enumeratedValues>
                        </field>
                        <field>
                            <name>PE</name>
                            <description>Parity Enable</description>
                            <lsb>5</lsb>
                            <msb>5</msb>
                            <access>read-write</access>
                        </field>
                        <field>
                            <name>BLK</name>
                            <description>Block Transfer Mode</description>
                            <lsb>6</lsb>
                            <msb>6</msb>
                            <access>read-write</access>
                            <enumeratedValues>
                                </enumeratedValues>
                        </field>
                        <field>
                            <name>GM</name>
                            <description>GSM Mode</description>
                            <lsb>7</lsb>
                            <msb>7</msb>
                            <access>read-write</access>
                            <enumeratedValues>
                                </enumeratedValues>
                        </field>
                    </fields>
                </register>
                <register>
                    <name>BRR</name>
                    <description>Bit Rate Register</description>
                    <addressOffset>0x01</addressOffset>
                    <size>8</size>
                    <access>read-write</access>
                    <resetValue>0xff</resetValue>
                    <resetMask>0xff</resetMask>
                </register>
                <register>
                    <name>SCR</name>
                    <description>Serial Control Register for Non,Smart Card Interface Mode (SCMR.SMIF = 0)</description>
                    <addressOffset>0x02</addressOffset>
                    <size>8</size>
                    <access>read-write</access>
                    <resetValue>0x00</resetValue>
                    <resetMask>0xff</resetMask>
                    <fields>
                        <field>
                            <name>CKE</name>
                            <description>Clock Enable</description>
                            <lsb>0</lsb>
                            <msb>1</msb>
                            <access>read-write</access>
                            <enumeratedValues>
                                </enumeratedValues>
                        </field>
                        <field>
                            <name>TEIE</name>
                            <description>Transmit End Interrupt Enable</description>
                            <lsb>2</lsb>
                            <msb>2</msb>
                            <access>read-write</access>
                            <enumeratedValues>
                                </enumeratedValues>
                        </field>
                        <field>
                            <name>MPIE</name>
                            <description>Multi,Processor Interrupt Enable</description>
                            <lsb>3</lsb>
                            <msb>3</msb>
                            <access>read-write</access>
                            <enumeratedValues>
                                </enumeratedValues>
                        </field>
                        <field>
                            <name>RE</name>
                            <description>Receive Enable</description>
                            <lsb>4</lsb>
                            <msb>4</msb>
                            <access>read-write</access>
                            <enumeratedValues>
                                </enumeratedValues>
                        </field>
                        <field>
                            <name>TE</name>
                            <description>Transmit Enable</description>
                            <lsb>5</lsb>
                            <msb>5</msb>
                            <access>read-write</access>
                            <enumeratedValues>
                                </enumeratedValues>
                        </field>
                        <field>
                            <name>RIE</name>
                            <description>Receive Interrupt Enable</description>
                            <lsb>6</lsb>
                            <msb>6</msb>
                            <access>read-write</access>
                            <enumeratedValues>
                                </enumeratedValues>
                        </field>
                        <field>
                            <name>TIE</name>
                            <description>Transmit Interrupt Enable</description>
                            <lsb>7</lsb>
                            <msb>7</msb>
                            <access>read-write</access>
                            <enumeratedValues>
                                </enumeratedValues>
                        </field>
                    </fields>
                </register>
                <register>
                    <name>SCR_SMCI</name>
                    <description>Serial Control Register for Smart Card Interface Mode (SCMR.SMIF = 1)</description>
                    <alternateRegister>SCR</alternateRegister>
                    <addressOffset>0x02</addressOffset>
                    <size>8</size>
                    <access>read-write</access>
                    <resetValue>0x00</resetValue>
                    <resetMask>0xff</resetMask>
                    <fields>
                        <field>
                            <name>CKE</name>
                            <description>Clock Enable</description>
                            <lsb>0</lsb>
                            <msb>1</msb>
                            <access>read-write</access>
                            <enumeratedValues>
                                </enumeratedValues>
                        </field>
                        <field>
                            <name>TEIE</name>
                            <description>Transmit End Interrupt Enable</description>
                            <lsb>2</lsb>
                            <msb>2</msb>
                            <access>read-write</access>
                        </field>
                        <field>
                            <name>MPIE</name>
                            <description>Multi,Processor Interrupt Enable</description>
                            <lsb>3</lsb>
                            <msb>3</msb>
                            <access>read-write</access>
                        </field>
                        <field>
                            <name>RE</name>
                            <description>Receive Enable</description>
                            <lsb>4</lsb>
                            <msb>4</msb>
                            <access>read-write</access>
                            <enumeratedValues>
                                </enumeratedValues>
                        </field>
                        <field>
                            <name>TE</name>
                            <description>Transmit Enable</description>
                            <lsb>5</lsb>
                            <msb>5</msb>
                            <access>read-write</access>
                            <enumeratedValues>
                                </enumeratedValues>
                        </field>
                        <field>
                            <name>RIE</name>
                            <description>Receive Interrupt Enable</description>
                            <lsb>6</lsb>
                            <msb>6</msb>
                            <access>read-write</access>
                            <enumeratedValues>
                                </enumeratedValues>
                        </field>
                        <field>
                            <name>TIE</name>
                            <description>Transmit Interrupt Enable</description>
                            <lsb>7</lsb>
                            <msb>7</msb>
                            <access>read-write</access>
                            <enumeratedValues>
                                </enumeratedValues>
                        </field>
                    </fields>
                </register>
                <register>
                    <name>TDR</name>
                    <description>Transmit Data Register</description>
                    <addressOffset>0x03</addressOffset>
                    <size>8</size>
                    <access>read-write</access>
                    <resetValue>0xff</resetValue>
                    <resetMask>0xff</resetMask>
                </register>
                <register>
                    <name>SSR</name>
                    <description>Serial Status Register for Non,Smart Card Interface and Non,FIFO Mode (SCMR.SMIF = 0, FCR.FM = 0, and MMR.MANEN = 0)</description>
                    <addressOffset>0x04</addressOffset>
                    <size>8</size>
                    <access>read-write</access>
                    <resetValue>0x84</resetValue>
                    <resetMask>0xff</resetMask>
                    <fields>
                        <field>
                            <name>MPBT</name>
                            <description>Multi,Processor Bit Transfer</description>
                            <lsb>0</lsb>
                            <msb>0</msb>
                            <access>read-write</access>
                            <enumeratedValues>
                                </enumeratedValues>
                        </field>
                        <field>
                            <name>MPB</name>
                            <description>Multi,Processor</description>
                            <lsb>1</lsb>
                            <msb>1</msb>
                            <access>read-only</access>
                            <enumeratedValues>
                                </enumeratedValues>
                        </field>
                        <field>
                            <name>TEND</name>
                            <description>Transmit End Flag</description>
                            <lsb>2</lsb>
                            <msb>2</msb>
                            <access>read-only</access>
                            <enumeratedValues>
                                </enumeratedValues>
                        </field>
                        <field>
                            <name>PER</name>
                            <description>Parity Error Flag</description>
                            <lsb>3</lsb>
                            <msb>3</msb>
                            <access>read-write</access>
                            <enumeratedValues>
                                </enumeratedValues>
                        </field>
                        <field>
                            <name>FER</name>
                            <description>Framing Error Flag</description>
                            <lsb>4</lsb>
                            <msb>4</msb>
                            <access>read-write</access>
                            <enumeratedValues>
                                </enumeratedValues>
                        </field>
                        <field>
                            <name>ORER</name>
                            <description>Overrun Error Flag</description>
                            <lsb>5</lsb>
                            <msb>5</msb>
                            <access>read-write</access>
                            <enumeratedValues>
                                </enumeratedValues>
                        </field>
                        <field>
                            <name>RDRF</name>
                            <description>Receive Data Full Flag</description>
                            <lsb>6</lsb>
                            <msb>6</msb>
                            <access>read-write</access>
                            <enumeratedValues>
                                </enumeratedValues>
                        </field>
                        <field>
                            <name>TDRE</name>
                            <description>Transmit Data Empty Flag</description>
                            <lsb>7</lsb>
                            <msb>7</msb>
                            <access>read-write</access>
                            <enumeratedValues>
                                </enumeratedValues>
                        </field>
                    </fields>
                </register>
                <register>
                    <name>SSR_FIFO</name>
                    <description>Serial Status Register for Non,Smart Card Interface and FIFO Mode (SCMR.SMIF = 0, FCR.FM = 1, and MMR.MANEN = 0)</description>
                    <alternateRegister>SSR</alternateRegister>
                    <addressOffset>0x04</addressOffset>
                    <size>8</size>
                    <access>read-write</access>
                    <resetValue>0x80</resetValue>
                    <resetMask>0xfd</resetMask>
                    <fields>
                        <field>
                            <name>DR</name>
                            <description>Receive Data Ready Flag</description>
                            <lsb>0</lsb>
                            <msb>0</msb>
                            <access>read-write</access>
                            <enumeratedValues>
                                </enumeratedValues>
                        </field>
                        <field>
                            <name>TEND</name>
                            <description>Transmit End Flag</description>
                            <lsb>2</lsb>
                            <msb>2</msb>
                            <access>read-write</access>
                            <enumeratedValues>
                                </enumeratedValues>
                        </field>
                        <field>
                            <name>PER</name>
                            <description>Parity Error Flag</description>
                            <lsb>3</lsb>
                            <msb>3</msb>
                            <access>read-write</access>
                            <enumeratedValues>
                                </enumeratedValues>
                        </field>
                        <field>
                            <name>FER</name>
                            <description>Framing Error Flag</description>
                            <lsb>4</lsb>
                            <msb>4</msb>
                            <access>read-write</access>
                            <enumeratedValues>
                                </enumeratedValues>
                        </field>
                        <field>
                            <name>ORER</name>
                            <description>Overrun Error Flag</description>
                            <lsb>5</lsb>
                            <msb>5</msb>
                            <access>read-write</access>
                            <enumeratedValues>
                                </enumeratedValues>
                        </field>
                        <field>
                            <name>RDF</name>
                            <description>Receive FIFO Data Full Flag</description>
                            <lsb>6</lsb>
                            <msb>6</msb>
                            <access>read-write</access>
                            <enumeratedValues>
                                </enumeratedValues>
                        </field>
                        <field>
                            <name>TDFE</name>
                            <description>Transmit FIFO Data Empty Flag</description>
                            <lsb>7</lsb>
                            <msb>7</msb>
                            <access>read-write</access>
                            <enumeratedValues>
                                </enumeratedValues>
                        </field>
                    </fields>
                </register>
                <register>
                    <name>SSR_SMCI</name>
                    <description>Serial Status Register for Smart Card Interface Mode (SCMR.SMIF = 1, and MMR.MANEN = 0)</description>
                    <alternateRegister>SSR</alternateRegister>
                    <addressOffset>0x04</addressOffset>
                    <size>8</size>
                    <access>read-write</access>
                    <resetValue>0x84</resetValue>
                    <resetMask>0xff</resetMask>
                    <fields>
                        <field>
                            <name>MPBT</name>
                            <description>Multi,Processor Bit Transfer</description>
                            <lsb>0</lsb>
                            <msb>0</msb>
                            <access>read-write</access>
                        </field>
                        <field>
                            <name>MPB</name>
                            <description>Multi,Processor</description>
                            <lsb>1</lsb>
                            <msb>1</msb>
                            <access>read-only</access>
                        </field>
                        <field>
                            <name>TEND</name>
                            <description>Transmit End Flag</description>
                            <lsb>2</lsb>
                            <msb>2</msb>
                            <access>read-only</access>
                            <enumeratedValues>
                                </enumeratedValues>
                        </field>
                        <field>
                            <name>PER</name>
                            <description>Parity Error Flag</description>
                            <lsb>3</lsb>
                            <msb>3</msb>
                            <access>read-write</access>
                            <enumeratedValues>
                                </enumeratedValues>
                        </field>
                        <field>
                            <name>ERS</name>
                            <description>Error Signal Status Flag</description>
                            <lsb>4</lsb>
                            <msb>4</msb>
                            <access>read-write</access>
                            <enumeratedValues>
                                </enumeratedValues>
                        </field>
                        <field>
                            <name>ORER</name>
                            <description>Overrun Error Flag</description>
                            <lsb>5</lsb>
                            <msb>5</msb>
                            <access>read-write</access>
                            <enumeratedValues>
                                </enumeratedValues>
                        </field>
                        <field>
                            <name>RDRF</name>
                            <description>Receive Data Full Flag</description>
                            <lsb>6</lsb>
                            <msb>6</msb>
                            <access>read-write</access>
                            <enumeratedValues>
                                </enumeratedValues>
                        </field>
                        <field>
                            <name>TDRE</name>
                            <description>Transmit Data Empty Flag</description>
                            <lsb>7</lsb>
                            <msb>7</msb>
                            <access>read-write</access>
                            <enumeratedValues>
                                </enumeratedValues>
                        </field>
                    </fields>
                </register>
                <register>
                    <name>RDR</name>
                    <description>Receive Data Register</description>
                    <addressOffset>0x05</addressOffset>
                    <size>8</size>
                    <access>read-only</access>
                    <resetValue>0x00</resetValue>
                    <resetMask>0xff</resetMask>
                </register>
                <register>
                    <name>SCMR</name>
                    <description>Smart Card Mode Register</description>
                    <addressOffset>0x06</addressOffset>
                    <size>8</size>
                    <access>read-write</access>
                    <resetValue>0xf2</resetValue>
                    <resetMask>0xff</resetMask>
                    <fields>
                        <field>
                            <name>SMIF</name>
                            <description>Smart Card Interface Mode Select</description>
                            <lsb>0</lsb>
                            <msb>0</msb>
                            <access>read-write</access>
                            <enumeratedValues>
                                </enumeratedValues>
                        </field>
                        <field>
                            <name>SINV</name>
                            <description>Transmitted/Received Data Invert</description>
                            <lsb>2</lsb>
                            <msb>2</msb>
                            <access>read-write</access>
                            <enumeratedValues>
                                </enumeratedValues>
                        </field>
                        <field>
                            <name>SDIR</name>
                            <description>Transmitted/Received Data Transfer Direction</description>
                            <lsb>3</lsb>
                            <msb>3</msb>
                            <access>read-write</access>
                            <enumeratedValues>
                                </enumeratedValues>
                        </field>
                        <field>
                            <name>CHR1</name>
                            <description>Character Length 1</description>
                            <lsb>4</lsb>
                            <msb>4</msb>
                            <access>read-write</access>
                            <enumeratedValues>
                                </enumeratedValues>
                        </field>
                        <field>
                            <name>BCP2</name>
                            <description>Base Clock Pulse 2</description>
                            <lsb>7</lsb>
                            <msb>7</msb>
                            <access>read-write</access>
                        </field>
                    </fields>
                </register>
                <register>
                    <name>SEMR</name>
                    <description>Serial Extended Mode Register</description>
                    <addressOffset>0x07</addressOffset>
                    <size>8</size>
                    <access>read-write</access>
                    <resetValue>0x00</resetValue>
                    <resetMask>0xff</resetMask>
                    <fields>
                        <field>
                            <name>ACS0</name>
                            <description>Asynchronous Mode Clock Source Select</description>
                            <lsb>0</lsb>
                            <msb>0</msb>
                            <access>read-write</access>
                            <enumeratedValues>
                                </enumeratedValues>
                        </field>
                        <field>
                            <name>PADIS</name>
                            <description>Preamble function Disable</description>
                            <lsb>1</lsb>
                            <msb>1</msb>
                            <access>read-write</access>
                            <enumeratedValues>
                                </enumeratedValues>
                        </field>
                        <field>
                            <name>BRME</name>
                            <description>Bit Rate Modulation Enable</description>
                            <lsb>2</lsb>
                            <msb>2</msb>
                            <access>read-write</access>
                            <enumeratedValues>
                                </enumeratedValues>
                        </field>
                        <field>
                            <name>ABCSE</name>
                            <description>Asynchronous Mode Extended Base Clock Select 1</description>
                            <lsb>3</lsb>
                            <msb>3</msb>
                            <access>read-write</access>
                            <enumeratedValues>
                                </enumeratedValues>
                        </field>
                        <field>
                            <name>ABCS</name>
                            <description>Asynchronous Mode Base Clock Select</description>
                            <lsb>4</lsb>
                            <msb>4</msb>
                            <access>read-write</access>
                            <enumeratedValues>
                                </enumeratedValues>
                        </field>
                        <field>
                            <name>NFEN</name>
                            <description>Digital Noise Filter Function Enable</description>
                            <lsb>5</lsb>
                            <msb>5</msb>
                            <access>read-write</access>
                            <enumeratedValues>
                                </enumeratedValues>
                        </field>
                        <field>
                            <name>BGDM</name>
                            <description>Baud Rate Generator Double,Speed Mode Select</description>
                            <lsb>6</lsb>
                            <msb>6</msb>
                            <access>read-write</access>
                            <enumeratedValues>
                                </enumeratedValues>
                        </field>
                        <field>
                            <name>RXDESEL</name>
                            <description>Asynchronous Start Bit Edge Detection Select</description>
                            <lsb>7</lsb>
                            <msb>7</msb>
                            <access>read-write</access>
                            <enumeratedValues>
                                </enumeratedValues>
                        </field>
                    </fields>
                </register>
                <register>
                    <name>SNFR</name>
                    <description>Noise Filter Setting Register</description>
                    <addressOffset>0x08</addressOffset>
                    <size>8</size>
                    <access>read-write</access>
                    <resetValue>0x00</resetValue>
                    <resetMask>0xff</resetMask>
                    <fields>
                        <field>
                            <name>NFCS</name>
                            <description>Noise Filter Clock Select</description>
                            <lsb>0</lsb>
                            <msb>2</msb>
                            <access>read-write</access>
                            <enumeratedValues>
                                </enumeratedValues>
                        </field>
                    </fields>
                </register>
                <register>
                    <name>SIMR1</name>
                    <description>IIC Mode Register 1</description>
                    <addressOffset>0x09</addressOffset>
                    <size>8</size>
                    <access>read-write</access>
                    <resetValue>0x00</resetValue>
                    <resetMask>0xff</resetMask>
                    <fields>
                        <field>
                            <name>IICM</name>
                            <description>Simple IIC Mode Select</description>
                            <lsb>0</lsb>
                            <msb>0</msb>
                            <access>read-write</access>
                            <enumeratedValues>
                                </enumeratedValues>
                        </field>
                        <field>
                            <name>IICDL</name>
                            <description>SDAn Delay Output Select</description>
                            <lsb>3</lsb>
                            <msb>7</msb>
                            <access>read-write</access>
                            <enumeratedValues>
                                </enumeratedValues>
                        </field>
                    </fields>
                </register>
                <register>
                    <name>SIMR2</name>
                    <description>IIC Mode Register 2</description>
                    <addressOffset>0x0A</addressOffset>
                    <size>8</size>
                    <access>read-write</access>
                    <resetValue>0x00</resetValue>
                    <resetMask>0xff</resetMask>
                    <fields>
                        <field>
                            <name>IICINTM</name>
                            <description>IIC Interrupt Mode Select</description>
                            <lsb>0</lsb>
                            <msb>0</msb>
                            <access>read-write</access>
                            <enumeratedValues>
                                </enumeratedValues>
                        </field>
                        <field>
                            <name>IICCSC</name>
                            <description>Clock Synchronization</description>
                            <lsb>1</lsb>
                            <msb>1</msb>
                            <access>read-write</access>
                            <enumeratedValues>
                                </enumeratedValues>
                        </field>
                        <field>
                            <name>IICACKT</name>
                            <description>ACK Transmission Data</description>
                            <lsb>5</lsb>
                            <msb>5</msb>
                            <access>read-write</access>
                            <enumeratedValues>
                                </enumeratedValues>
                        </field>
                    </fields>
                </register>
                <register>
                    <name>SIMR3</name>
                    <description>IIC Mode Register 3</description>
                    <addressOffset>0x0B</addressOffset>
                    <size>8</size>
                    <access>read-write</access>
                    <resetValue>0x00</resetValue>
                    <resetMask>0xff</resetMask>
                    <fields>
                        <field>
                            <name>IICSTAREQ</name>
                            <description>Start Condition Generation</description>
                            <lsb>0</lsb>
                            <msb>0</msb>
                            <access>read-write</access>
                            <enumeratedValues>
                                </enumeratedValues>
                        </field>
                        <field>
                            <name>IICRSTAREQ</name>
                            <description>Restart Condition Generation</description>
                            <lsb>1</lsb>
                            <msb>1</msb>
                            <access>read-write</access>
                            <enumeratedValues>
                                </enumeratedValues>
                        </field>
                        <field>
                            <name>IICSTPREQ</name>
                            <description>Stop Condition Generation</description>
                            <lsb>2</lsb>
                            <msb>2</msb>
                            <access>read-write</access>
                            <enumeratedValues>
                                </enumeratedValues>
                        </field>
                        <field>
                            <name>IICSTIF</name>
                            <description>Issuing of Start, Restart, or Stop Condition Completed Flag</description>
                            <lsb>3</lsb>
                            <msb>3</msb>
                            <access>read-write</access>
                            <enumeratedValues>
                                </enumeratedValues>
                        </field>
                        <field>
                            <name>IICSDAS</name>
                            <description>SDAn Output Select</description>
                            <lsb>4</lsb>
                            <msb>5</msb>
                            <access>read-write</access>
                            <enumeratedValues>
                                </enumeratedValues>
                        </field>
                        <field>
                            <name>IICSCLS</name>
                            <description>SCLn Output Select</description>
                            <lsb>6</lsb>
                            <msb>7</msb>
                            <access>read-write</access>
                            <enumeratedValues>
                                </enumeratedValues>
                        </field>
                    </fields>
                </register>
                <register>
                    <name>SISR</name>
                    <description>IIC Status Register</description>
                    <addressOffset>0x0C</addressOffset>
                    <size>8</size>
                    <access>read-only</access>
                    <resetValue>0x00</resetValue>
                    <resetMask>0xcb</resetMask>
                    <fields>
                        <field>
                            <name>IICACKR</name>
                            <description>ACK Reception Data Flag</description>
                            <lsb>0</lsb>
                            <msb>0</msb>
                            <access>read-only</access>
                            <enumeratedValues>
                                </enumeratedValues>
                        </field>
                    </fields>
                </register>
                <register>
                    <name>SPMR</name>
                    <description>SPI Mode Register</description>
                    <addressOffset>0x0D</addressOffset>
                    <size>8</size>
                    <access>read-write</access>
                    <resetValue>0x00</resetValue>
                    <resetMask>0xff</resetMask>
                    <fields>
                        <field>
                            <name>SSE</name>
                            <description>SSn Pin Function Enable</description>
                            <lsb>0</lsb>
                            <msb>0</msb>
                            <access>read-write</access>
                            <enumeratedValues>
                                </enumeratedValues>
                        </field>
                        <field>
                            <name>CTSE</name>
                            <description>CTS Enable</description>
                            <lsb>1</lsb>
                            <msb>1</msb>
                            <access>read-write</access>
                            <enumeratedValues>
                                </enumeratedValues>
                        </field>
                        <field>
                            <name>MSS</name>
                            <description>Master Slave Select</description>
                            <lsb>2</lsb>
                            <msb>2</msb>
                            <access>read-write</access>
                            <enumeratedValues>
                                </enumeratedValues>
                        </field>
                        <field>
                            <name>CTSPEN</name>
                            <description>CTS external pin Enable</description>
                            <lsb>3</lsb>
                            <msb>3</msb>
                            <access>read-write</access>
                            <enumeratedValues>
                                </enumeratedValues>
                        </field>
                        <field>
                            <name>MFF</name>
                            <description>Mode Fault Flag</description>
                            <lsb>4</lsb>
                            <msb>4</msb>
                            <access>read-write</access>
                            <enumeratedValues>
                                </enumeratedValues>
                        </field>
                        <field>
                            <name>CKPOL</name>
                            <description>Clock Polarity Select</description>
                            <lsb>6</lsb>
                            <msb>6</msb>
                            <access>read-write</access>
                            <enumeratedValues>
                                </enumeratedValues>
                        </field>
                        <field>
                            <name>CKPH</name>
                            <description>Clock Phase Select</description>
                            <lsb>7</lsb>
                            <msb>7</msb>
                            <access>read-write</access>
                            <enumeratedValues>
                                </enumeratedValues>
                        </field>
                    </fields>
                </register>
                <register>
                    <name>FTDRHL</name>
                    <description>Transmit FIFO Data Register</description>
                    <addressOffset>0x0E</addressOffset>
                    <size>16</size>
                    <access>write-only</access>
                    <resetValue>0xffff</resetValue>
                    <resetMask>0xffff</resetMask>
                    <fields>
                        <field>
                            <name>TDAT</name>
                            <description>Serial transmit data</description>
                            <lsb>0</lsb>
                            <msb>8</msb>
                            <access>write-only</access>
                        </field>
                        <field>
                            <name>MPBT</name>
                            <description>Multi,Processor Transfer Bit Flag</description>
                            <lsb>9</lsb>
                            <msb>9</msb>
                            <access>write-only</access>
                            <enumeratedValues>
                                </enumeratedValues>
                        </field>
                    </fields>
                </register>
                <register>
                    <name>TDRHL</name>
                    <description>Transmit Data Register for Non,Manchester mode (MMR.MANEN = 0)</description>
                    <alternateRegister>FTDRHL</alternateRegister>
                    <addressOffset>0x0E</addressOffset>
                    <size>16</size>
                    <access>read-write</access>
                    <resetValue>0xffff</resetValue>
                    <resetMask>0xffff</resetMask>
                    <fields>
                        <field>
                            <name>TDAT</name>
                            <description>Serial Transmit Data</description>
                            <lsb>0</lsb>
                            <msb>8</msb>
                            <access>read-write</access>
                        </field>
                    </fields>
                </register>
                <register>
                    <name>FTDRH</name>
                    <description>Transmit FIFO Data Register</description>
                    <alternateRegister>FTDRHL</alternateRegister>
                    <addressOffset>0x0E</addressOffset>
                    <size>8</size>
                    <access>write-only</access>
                    <resetValue>0xff</resetValue>
                    <resetMask>0xff</resetMask>
                    <fields>
                        <field>
                            <name>MPBT</name>
                            <description>Multi,Processor Transfer Bit Flag</description>
                            <lsb>1</lsb>
                            <msb>1</msb>
                            <access>write-only</access>
                            <enumeratedValues>
                                </enumeratedValues>
                        </field>
                    </fields>
                </register>
                <register>
                    <name>FTDRL</name>
                    <description>Transmit FIFO Data Register</description>
                    <alternateRegister>FTDRHL</alternateRegister>
                    <addressOffset>0x0F</addressOffset>
                    <size>8</size>
                    <access>write-only</access>
                    <resetValue>0xff</resetValue>
                    <resetMask>0xff</resetMask>
                    <fields>
                        <field>
                            <name>TDAT</name>
                            <description>Serial transmit data</description>
                            <lsb>0</lsb>
                            <msb>7</msb>
                            <access>write-only</access>
                        </field>
                    </fields>
                </register>
                <register>
                    <name>FRDRHL</name>
                    <description>Receive FIFO Data Register</description>
                    <addressOffset>0x10</addressOffset>
                    <size>16</size>
                    <access>read-only</access>
                    <resetValue>0x0000</resetValue>
                    <resetMask>0xffff</resetMask>
                    <fields>
                        <field>
                            <name>RDAT</name>
                            <description>Serial receive data</description>
                            <lsb>0</lsb>
                            <msb>8</msb>
                            <access>read-only</access>
                        </field>
                        <field>
                            <name>MPB</name>
                            <description>Multi,Processor Bit Flag</description>
                            <lsb>9</lsb>
                            <msb>9</msb>
                            <access>read-only</access>
                            <enumeratedValues>
                                </enumeratedValues>
                        </field>
                        <field>
                            <name>DR</name>
                            <description>Receive Data Ready Flag</description>
                            <lsb>10</lsb>
                            <msb>10</msb>
                            <access>read-only</access>
                            <enumeratedValues>
                                </enumeratedValues>
                        </field>
                        <field>
                            <name>PER</name>
                            <description>Parity Error Flag</description>
                            <lsb>11</lsb>
                            <msb>11</msb>
                            <access>read-only</access>
                            <enumeratedValues>
                                </enumeratedValues>
                        </field>
                        <field>
                            <name>FER</name>
                            <description>Framing Error Flag</description>
                            <lsb>12</lsb>
                            <msb>12</msb>
                            <access>read-only</access>
                            <enumeratedValues>
                                </enumeratedValues>
                        </field>
                        <field>
                            <name>ORER</name>
                            <description>Overrun Error Flag</description>
                            <lsb>13</lsb>
                            <msb>13</msb>
                            <access>read-only</access>
                            <enumeratedValues>
                                </enumeratedValues>
                        </field>
                        <field>
                            <name>RDF</name>
                            <description>Receive FIFO Data Full Flag</description>
                            <lsb>14</lsb>
                            <msb>14</msb>
                            <access>read-only</access>
                            <enumeratedValues>
                                </enumeratedValues>
                        </field>
                    </fields>
                </register>
                <register>
                    <name>RDRHL</name>
                    <description>Receive Data Register for Non,Manchester mode (MMR.MANEN = 0)</description>
                    <alternateRegister>FRDRHL</alternateRegister>
                    <addressOffset>0x10</addressOffset>
                    <size>16</size>
                    <access>read-only</access>
                    <resetValue>0x0000</resetValue>
                    <resetMask>0xffff</resetMask>
                    <fields>
                        <field>
                            <name>RDAT</name>
                            <description>Serial Receive Data</description>
                            <lsb>0</lsb>
                            <msb>8</msb>
                            <access>read-only</access>
                        </field>
                    </fields>
                </register>
                <register>
                    <name>FRDRH</name>
                    <description>Receive FIFO Data Register</description>
                    <alternateRegister>FRDRHL</alternateRegister>
                    <addressOffset>0x10</addressOffset>
                    <size>8</size>
                    <access>read-only</access>
                    <resetValue>0x00</resetValue>
                    <resetMask>0xff</resetMask>
                    <fields>
                        <field>
                            <name>MPB</name>
                            <description>Multi,Processor Bit Flag</description>
                            <lsb>1</lsb>
                            <msb>1</msb>
                            <access>read-only</access>
                            <enumeratedValues>
                                </enumeratedValues>
                        </field>
                        <field>
                            <name>DR</name>
                            <description>Receive Data Ready Flag</description>
                            <lsb>2</lsb>
                            <msb>2</msb>
                            <access>read-only</access>
                            <enumeratedValues>
                                </enumeratedValues>
                        </field>
                        <field>
                            <name>PER</name>
                            <description>Parity Error Flag</description>
                            <lsb>3</lsb>
                            <msb>3</msb>
                            <access>read-only</access>
                            <enumeratedValues>
                                </enumeratedValues>
                        </field>
                        <field>
                            <name>FER</name>
                            <description>Framing Error Flag</description>
                            <lsb>4</lsb>
                            <msb>4</msb>
                            <access>read-only</access>
                            <enumeratedValues>
                                </enumeratedValues>
                        </field>
                        <field>
                            <name>ORER</name>
                            <description>Overrun Error Flag</description>
                            <lsb>5</lsb>
                            <msb>5</msb>
                            <access>read-only</access>
                            <enumeratedValues>
                                </enumeratedValues>
                        </field>
                        <field>
                            <name>RDF</name>
                            <description>Receive FIFO Data Full Flag</description>
                            <lsb>6</lsb>
                            <msb>6</msb>
                            <access>read-only</access>
                            <enumeratedValues>
                                </enumeratedValues>
                        </field>
                    </fields>
                </register>
                <register>
                    <name>FRDRL</name>
                    <description>Receive FIFO Data Register</description>
                    <alternateRegister>FRDRHL</alternateRegister>
                    <addressOffset>0x11</addressOffset>
                    <size>8</size>
                    <access>read-only</access>
                    <resetValue>0x00</resetValue>
                    <resetMask>0xff</resetMask>
                    <fields>
                        <field>
                            <name>RDAT</name>
                            <description>Serial receive data</description>
                            <lsb>0</lsb>
                            <msb>7</msb>
                            <access>read-only</access>
                        </field>
                    </fields>
                </register>
                <register>
                    <name>MDDR</name>
                    <description>Modulation Duty Register</description>
                    <addressOffset>0x12</addressOffset>
                    <size>8</size>
                    <access>read-write</access>
                    <resetValue>0xff</resetValue>
                    <resetMask>0xff</resetMask>
                </register>
                <register>
                    <name>DCCR</name>
                    <description>Data Compare Match Control Register</description>
                    <addressOffset>0x13</addressOffset>
                    <size>8</size>
                    <access>read-write</access>
                    <resetValue>0x40</resetValue>
                    <resetMask>0xff</resetMask>
                    <fields>
                        <field>
                            <name>DCMF</name>
                            <description>Data Compare Match Flag</description>
                            <lsb>0</lsb>
                            <msb>0</msb>
                            <access>read-write</access>
                            <enumeratedValues>
                                </enumeratedValues>
                        </field>
                        <field>
                            <name>DPER</name>
                            <description>Data Compare Match Parity Error Flag</description>
                            <lsb>3</lsb>
                            <msb>3</msb>
                            <access>read-write</access>
                            <enumeratedValues>
                                </enumeratedValues>
                        </field>
                        <field>
                            <name>DFER</name>
                            <description>Data Compare Match Framing Error Flag</description>
                            <lsb>4</lsb>
                            <msb>4</msb>
                            <access>read-write</access>
                            <enumeratedValues>
                                </enumeratedValues>
                        </field>
                        <field>
                            <name>IDSEL</name>
                            <description>ID Frame Select</description>
                            <lsb>6</lsb>
                            <msb>6</msb>
                            <access>read-write</access>
                            <enumeratedValues>
                                </enumeratedValues>
                        </field>
                        <field>
                            <name>DCME</name>
                            <description>Data Compare Match Enable</description>
                            <lsb>7</lsb>
                            <msb>7</msb>
                            <access>read-write</access>
                            <enumeratedValues>
                                </enumeratedValues>
                        </field>
                    </fields>
                </register>
                <register>
                    <name>FCR</name>
                    <description>FIFO Control Register</description>
                    <addressOffset>0x14</addressOffset>
                    <size>16</size>
                    <access>read-write</access>
                    <resetValue>0xf800</resetValue>
                    <resetMask>0xffff</resetMask>
                    <fields>
                        <field>
                            <name>FM</name>
                            <description>FIFO Mode Select</description>
                            <lsb>0</lsb>
                            <msb>0</msb>
                            <access>read-write</access>
                            <enumeratedValues>
                                </enumeratedValues>
                        </field>
                        <field>
                            <name>RFRST</name>
                            <description>Receive FIFO Data Register Reset</description>
                            <lsb>1</lsb>
                            <msb>1</msb>
                            <access>read-write</access>
                            <enumeratedValues>
                                </enumeratedValues>
                        </field>
                        <field>
                            <name>TFRST</name>
                            <description>Transmit FIFO Data Register Reset</description>
                            <lsb>2</lsb>
                            <msb>2</msb>
                            <access>read-write</access>
                            <enumeratedValues>
                                </enumeratedValues>
                        </field>
                        <field>
                            <name>DRES</name>
                            <description>Receive Data Ready Error Select</description>
                            <lsb>3</lsb>
                            <msb>3</msb>
                            <access>read-write</access>
                            <enumeratedValues>
                                </enumeratedValues>
                        </field>
                        <field>
                            <name>TTRG</name>
                            <description>Transmit FIFO Data Trigger Number</description>
                            <lsb>4</lsb>
                            <msb>7</msb>
                            <access>read-write</access>
                        </field>
                        <field>
                            <name>RTRG</name>
                            <description>Receive FIFO Data Trigger Number</description>
                            <lsb>8</lsb>
                            <msb>11</msb>
                            <access>read-write</access>
                        </field>
                        <field>
                            <name>RSTRG</name>
                            <description>RTS Output Active Trigger Number Select</description>
                            <lsb>12</lsb>
                            <msb>15</msb>
                            <access>read-write</access>
                        </field>
                    </fields>
                </register>
                <register>
                    <name>FDR</name>
                    <description>FIFO Data Count Register</description>
                    <addressOffset>0x16</addressOffset>
                    <size>16</size>
                    <access>read-only</access>
                    <resetValue>0x0000</resetValue>
                    <resetMask>0xffff</resetMask>
                    <fields>
                        <field>
                            <name>R</name>
                            <description>Receive FIFO Data Count</description>
                            <lsb>0</lsb>
                            <msb>4</msb>
                            <access>read-only</access>
                        </field>
                        <field>
                            <name>T</name>
                            <description>Transmit FIFO Data Count</description>
                            <lsb>8</lsb>
                            <msb>12</msb>
                            <access>read-only</access>
                        </field>
                    </fields>
                </register>
                <register>
                    <name>LSR</name>
                    <description>Line Status Register</description>
                    <addressOffset>0x18</addressOffset>
                    <size>16</size>
                    <access>read-only</access>
                    <resetValue>0x0000</resetValue>
                    <resetMask>0xffff</resetMask>
                    <fields>
                        <field>
                            <name>ORER</name>
                            <description>Overrun Error Flag</description>
                            <lsb>0</lsb>
                            <msb>0</msb>
                            <access>read-only</access>
                            <enumeratedValues>
                                </enumeratedValues>
                        </field>
                        <field>
                            <name>FNUM</name>
                            <description>Framing Error Count</description>
                            <lsb>2</lsb>
                            <msb>6</msb>
                            <access>read-only</access>
                        </field>
                        <field>
                            <name>PNUM</name>
                            <description>Parity Error Count</description>
                            <lsb>8</lsb>
                            <msb>12</msb>
                            <access>read-only</access>
                        </field>
                    </fields>
                </register>
                <register>
                    <name>CDR</name>
                    <description>Compare Match Data Register</description>
                    <addressOffset>0x1A</addressOffset>
                    <size>16</size>
                    <access>read-write</access>
                    <resetValue>0x0000</resetValue>
                    <resetMask>0xffff</resetMask>
                    <fields>
                        <field>
                            <name>CMPD</name>
                            <description>Compare Match Data</description>
                            <lsb>0</lsb>
                            <msb>8</msb>
                            <access>read-write</access>
                        </field>
                    </fields>
                </register>
                <register>
                    <name>SPTR</name>
                    <description>Serial Port Register</description>
                    <addressOffset>0x1C</addressOffset>
                    <size>8</size>
                    <access>read-write</access>
                    <resetValue>0x03</resetValue>
                    <resetMask>0xff</resetMask>
                    <fields>
                        <field>
                            <name>RXDMON</name>
                            <description>Serial Input Data Monitor</description>
                            <lsb>0</lsb>
                            <msb>0</msb>
                            <access>read-only</access>
                        </field>
                        <field>
                            <name>SPB2DT</name>
                            <description>Serial Port Break Data Select</description>
                            <lsb>1</lsb>
                            <msb>1</msb>
                            <access>read-write</access>
                        </field>
                        <field>
                            <name>SPB2IO</name>
                            <description>Serial Port Break I/O</description>
                            <lsb>2</lsb>
                            <msb>2</msb>
                            <access>read-write</access>
                            <enumeratedValues>
                                </enumeratedValues>
                        </field>
                        <field>
                            <name>RINV</name>
                            <description>RXD invert bit</description>
                            <lsb>4</lsb>
                            <msb>4</msb>
                            <access>read-write</access>
                            <enumeratedValues>
                                </enumeratedValues>
                        </field>
                        <field>
                            <name>TINV</name>
                            <description>TXD invert bit</description>
                            <lsb>5</lsb>
                            <msb>5</msb>
                            <access>read-write</access>
                            <enumeratedValues>
                                </enumeratedValues>
                        </field>
                        <field>
                            <name>ASEN</name>
                            <description>Adjust receive sampling timing enable</description>
                            <lsb>6</lsb>
                            <msb>6</msb>
                            <access>read-write</access>
                            <enumeratedValues>
                                </enumeratedValues>
                        </field>
                        <field>
                            <name>ATEN</name>
                            <description>Adjust transmit timing enable</description>
                            <lsb>7</lsb>
                            <msb>7</msb>
                            <access>read-write</access>
                            <enumeratedValues>
                                </enumeratedValues>
                        </field>
                    </fields>
                </register>
                <register>
                    <name>ACTR</name>
                    <description>Adjustment Communication Timing Register</description>
                    <addressOffset>0x1D</addressOffset>
                    <size>8</size>
                    <access>read-write</access>
                    <resetValue>0x00</resetValue>
                    <resetMask>0xff</resetMask>
                    <fields>
                        <field>
                            <name>AST</name>
                            <description>Adjustment value for receive Sampling Timing</description>
                            <lsb>0</lsb>
                            <msb>2</msb>
                            <access>read-write</access>
                        </field>
                        <field>
                            <name>AJD</name>
                            <description>Adjustment Direction for receive sampling timing</description>
                            <lsb>3</lsb>
                            <msb>3</msb>
                            <access>read-write</access>
                            <enumeratedValues>
                                </enumeratedValues>
                        </field>
                        <field>
                            <name>ATT</name>
                            <description>Adjustment value for Transmit timing</description>
                            <lsb>4</lsb>
                            <msb>6</msb>
                            <access>read-write</access>
                        </field>
                        <field>
                            <name>AET</name>
                            <description>Adjustment edge for transmit timing</description>
                            <lsb>7</lsb>
                            <msb>7</msb>
                            <access>read-write</access>
                            <enumeratedValues>
                                </enumeratedValues>
                        </field>
                    </fields>
                </register>
            </registers>
        </peripheral>
        <peripheral>
            <name>SCI1</name>
            <description>Serial Communication Interface 0</description>
            <baseAddress>0x40118100</baseAddress>
            <addressBlock>
                <offset>0x00</offset>
                <size>19</size>
                <usage>registers</usage>
            </addressBlock>
            <addressBlock>
                <offset>0x20</offset>
                <size>20</size>
                <usage>registers</usage>
            </addressBlock>
            <registers>
                <register>
                    <name>SMR</name>
                    <description>Serial Mode Register for Non,Smart Card Interface Mode (SCMR.SMIF = 0)</description>
                    <addressOffset>0x00</addressOffset>
                    <size>8</size>
                    <access>read-write</access>
                    <resetValue>0x00</resetValue>
                    <resetMask>0xff</resetMask>
                    <fields>
                        <field>
                            <name>CKS</name>
                            <description>Clock Select</description>
                            <lsb>0</lsb>
                            <msb>1</msb>
                            <access>read-write</access>
                            <enumeratedValues>
                                </enumeratedValues>
                        </field>
                        <field>
                            <name>MP</name>
                            <description>Multi,Processor Mode</description>
                            <lsb>2</lsb>
                            <msb>2</msb>
                            <access>read-write</access>
                            <enumeratedValues>
                                </enumeratedValues>
                        </field>
                        <field>
                            <name>STOP</name>
                            <description>Stop Bit Length</description>
                            <lsb>3</lsb>
                            <msb>3</msb>
                            <access>read-write</access>
                            <enumeratedValues>
                                </enumeratedValues>
                        </field>
                        <field>
                            <name>PM</name>
                            <description>Parity Mode</description>
                            <lsb>4</lsb>
                            <msb>4</msb>
                            <access>read-write</access>
                            <enumeratedValues>
                                </enumeratedValues>
                        </field>
                        <field>
                            <name>PE</name>
                            <description>Parity Enable</description>
                            <lsb>5</lsb>
                            <msb>5</msb>
                            <access>read-write</access>
                            <enumeratedValues>
                                </enumeratedValues>
                        </field>
                        <field>
                            <name>CHR</name>
                            <description>Character Length</description>
                            <lsb>6</lsb>
                            <msb>6</msb>
                            <access>read-write</access>
                            <enumeratedValues>
                                </enumeratedValues>
                        </field>
                        <field>
                            <name>CM</name>
                            <description>Communication Mode</description>
                            <lsb>7</lsb>
                            <msb>7</msb>
                            <access>read-write</access>
                            <enumeratedValues>
                                </enumeratedValues>
                        </field>
                    </fields>
                </register>
                <register>
                    <name>SMR_SMCI</name>
                    <description>Serial Mode Register for Smart Card Interface Mode (SCMR.SMIF = 1)</description>
                    <alternateRegister>SMR</alternateRegister>
                    <addressOffset>0x00</addressOffset>
                    <size>8</size>
                    <access>read-write</access>
                    <resetValue>0x00</resetValue>
                    <resetMask>0xff</resetMask>
                    <fields>
                        <field>
                            <name>CKS</name>
                            <description>Clock Select</description>
                            <lsb>0</lsb>
                            <msb>1</msb>
                            <access>read-write</access>
                            <enumeratedValues>
                                </enumeratedValues>
                        </field>
                        <field>
                            <name>BCP</name>
                            <description>Base Clock Pulse</description>
                            <lsb>2</lsb>
                            <msb>3</msb>
                            <access>read-write</access>
                        </field>
                        <field>
                            <name>PM</name>
                            <description>Parity Mode</description>
                            <lsb>4</lsb>
                            <msb>4</msb>
                            <access>read-write</access>
                            <enumeratedValues>
                                </enumeratedValues>
                        </field>
                        <field>
                            <name>PE</name>
                            <description>Parity Enable</description>
                            <lsb>5</lsb>
                            <msb>5</msb>
                            <access>read-write</access>
                        </field>
                        <field>
                            <name>BLK</name>
                            <description>Block Transfer Mode</description>
                            <lsb>6</lsb>
                            <msb>6</msb>
                            <access>read-write</access>
                            <enumeratedValues>
                                </enumeratedValues>
                        </field>
                        <field>
                            <name>GM</name>
                            <description>GSM Mode</description>
                            <lsb>7</lsb>
                            <msb>7</msb>
                            <access>read-write</access>
                            <enumeratedValues>
                                </enumeratedValues>
                        </field>
                    </fields>
                </register>
                <register>
                    <name>BRR</name>
                    <description>Bit Rate Register</description>
                    <addressOffset>0x01</addressOffset>
                    <size>8</size>
                    <access>read-write</access>
                    <resetValue>0xff</resetValue>
                    <resetMask>0xff</resetMask>
                </register>
                <register>
                    <name>SCR</name>
                    <description>Serial Control Register for Non,Smart Card Interface Mode (SCMR.SMIF = 0)</description>
                    <addressOffset>0x02</addressOffset>
                    <size>8</size>
                    <access>read-write</access>
                    <resetValue>0x00</resetValue>
                    <resetMask>0xff</resetMask>
                    <fields>
                        <field>
                            <name>CKE</name>
                            <description>Clock Enable</description>
                            <lsb>0</lsb>
                            <msb>1</msb>
                            <access>read-write</access>
                            <enumeratedValues>
                                </enumeratedValues>
                        </field>
                        <field>
                            <name>TEIE</name>
                            <description>Transmit End Interrupt Enable</description>
                            <lsb>2</lsb>
                            <msb>2</msb>
                            <access>read-write</access>
                            <enumeratedValues>
                                </enumeratedValues>
                        </field>
                        <field>
                            <name>MPIE</name>
                            <description>Multi,Processor Interrupt Enable</description>
                            <lsb>3</lsb>
                            <msb>3</msb>
                            <access>read-write</access>
                            <enumeratedValues>
                                </enumeratedValues>
                        </field>
                        <field>
                            <name>RE</name>
                            <description>Receive Enable</description>
                            <lsb>4</lsb>
                            <msb>4</msb>
                            <access>read-write</access>
                            <enumeratedValues>
                                </enumeratedValues>
                        </field>
                        <field>
                            <name>TE</name>
                            <description>Transmit Enable</description>
                            <lsb>5</lsb>
                            <msb>5</msb>
                            <access>read-write</access>
                            <enumeratedValues>
                                </enumeratedValues>
                        </field>
                        <field>
                            <name>RIE</name>
                            <description>Receive Interrupt Enable</description>
                            <lsb>6</lsb>
                            <msb>6</msb>
                            <access>read-write</access>
                            <enumeratedValues>
                                </enumeratedValues>
                        </field>
                        <field>
                            <name>TIE</name>
                            <description>Transmit Interrupt Enable</description>
                            <lsb>7</lsb>
                            <msb>7</msb>
                            <access>read-write</access>
                            <enumeratedValues>
                                </enumeratedValues>
                        </field>
                    </fields>
                </register>
                <register>
                    <name>SCR_SMCI</name>
                    <description>Serial Control Register for Smart Card Interface Mode (SCMR.SMIF = 1)</description>
                    <alternateRegister>SCR</alternateRegister>
                    <addressOffset>0x02</addressOffset>
                    <size>8</size>
                    <access>read-write</access>
                    <resetValue>0x00</resetValue>
                    <resetMask>0xff</resetMask>
                    <fields>
                        <field>
                            <name>CKE</name>
                            <description>Clock Enable</description>
                            <lsb>0</lsb>
                            <msb>1</msb>
                            <access>read-write</access>
                            <enumeratedValues>
                                </enumeratedValues>
                        </field>
                        <field>
                            <name>TEIE</name>
                            <description>Transmit End Interrupt Enable</description>
                            <lsb>2</lsb>
                            <msb>2</msb>
                            <access>read-write</access>
                        </field>
                        <field>
                            <name>MPIE</name>
                            <description>Multi,Processor Interrupt Enable</description>
                            <lsb>3</lsb>
                            <msb>3</msb>
                            <access>read-write</access>
                        </field>
                        <field>
                            <name>RE</name>
                            <description>Receive Enable</description>
                            <lsb>4</lsb>
                            <msb>4</msb>
                            <access>read-write</access>
                            <enumeratedValues>
                                </enumeratedValues>
                        </field>
                        <field>
                            <name>TE</name>
                            <description>Transmit Enable</description>
                            <lsb>5</lsb>
                            <msb>5</msb>
                            <access>read-write</access>
                            <enumeratedValues>
                                </enumeratedValues>
                        </field>
                        <field>
                            <name>RIE</name>
                            <description>Receive Interrupt Enable</description>
                            <lsb>6</lsb>
                            <msb>6</msb>
                            <access>read-write</access>
                            <enumeratedValues>
                                </enumeratedValues>
                        </field>
                        <field>
                            <name>TIE</name>
                            <description>Transmit Interrupt Enable</description>
                            <lsb>7</lsb>
                            <msb>7</msb>
                            <access>read-write</access>
                            <enumeratedValues>
                                </enumeratedValues>
                        </field>
                    </fields>
                </register>
                <register>
                    <name>TDR</name>
                    <description>Transmit Data Register</description>
                    <addressOffset>0x03</addressOffset>
                    <size>8</size>
                    <access>read-write</access>
                    <resetValue>0xff</resetValue>
                    <resetMask>0xff</resetMask>
                </register>
                <register>
                    <name>SSR</name>
                    <description>Serial Status Register for Non,Smart Card Interface and Non,FIFO Mode (SCMR.SMIF = 0, FCR.FM = 0, and MMR.MANEN = 0)</description>
                    <addressOffset>0x04</addressOffset>
                    <size>8</size>
                    <access>read-write</access>
                    <resetValue>0x84</resetValue>
                    <resetMask>0xff</resetMask>
                    <fields>
                        <field>
                            <name>MPBT</name>
                            <description>Multi,Processor Bit Transfer</description>
                            <lsb>0</lsb>
                            <msb>0</msb>
                            <access>read-write</access>
                            <enumeratedValues>
                                </enumeratedValues>
                        </field>
                        <field>
                            <name>MPB</name>
                            <description>Multi,Processor</description>
                            <lsb>1</lsb>
                            <msb>1</msb>
                            <access>read-only</access>
                            <enumeratedValues>
                                </enumeratedValues>
                        </field>
                        <field>
                            <name>TEND</name>
                            <description>Transmit End Flag</description>
                            <lsb>2</lsb>
                            <msb>2</msb>
                            <access>read-only</access>
                            <enumeratedValues>
                                </enumeratedValues>
                        </field>
                        <field>
                            <name>PER</name>
                            <description>Parity Error Flag</description>
                            <lsb>3</lsb>
                            <msb>3</msb>
                            <access>read-write</access>
                            <enumeratedValues>
                                </enumeratedValues>
                        </field>
                        <field>
                            <name>FER</name>
                            <description>Framing Error Flag</description>
                            <lsb>4</lsb>
                            <msb>4</msb>
                            <access>read-write</access>
                            <enumeratedValues>
                                </enumeratedValues>
                        </field>
                        <field>
                            <name>ORER</name>
                            <description>Overrun Error Flag</description>
                            <lsb>5</lsb>
                            <msb>5</msb>
                            <access>read-write</access>
                            <enumeratedValues>
                                </enumeratedValues>
                        </field>
                        <field>
                            <name>RDRF</name>
                            <description>Receive Data Full Flag</description>
                            <lsb>6</lsb>
                            <msb>6</msb>
                            <access>read-write</access>
                            <enumeratedValues>
                                </enumeratedValues>
                        </field>
                        <field>
                            <name>TDRE</name>
                            <description>Transmit Data Empty Flag</description>
                            <lsb>7</lsb>
                            <msb>7</msb>
                            <access>read-write</access>
                            <enumeratedValues>
                                </enumeratedValues>
                        </field>
                    </fields>
                </register>
                <register>
                    <name>SSR_SMCI</name>
                    <description>Serial Status Register for Smart Card Interface Mode (SCMR.SMIF = 1, and MMR.MANEN = 0)</description>
                    <alternateRegister>SSR</alternateRegister>
                    <addressOffset>0x04</addressOffset>
                    <size>8</size>
                    <access>read-write</access>
                    <resetValue>0x84</resetValue>
                    <resetMask>0xff</resetMask>
                    <fields>
                        <field>
                            <name>MPBT</name>
                            <description>Multi,Processor Bit Transfer</description>
                            <lsb>0</lsb>
                            <msb>0</msb>
                            <access>read-write</access>
                        </field>
                        <field>
                            <name>MPB</name>
                            <description>Multi,Processor</description>
                            <lsb>1</lsb>
                            <msb>1</msb>
                            <access>read-only</access>
                        </field>
                        <field>
                            <name>TEND</name>
                            <description>Transmit End Flag</description>
                            <lsb>2</lsb>
                            <msb>2</msb>
                            <access>read-only</access>
                            <enumeratedValues>
                                </enumeratedValues>
                        </field>
                        <field>
                            <name>PER</name>
                            <description>Parity Error Flag</description>
                            <lsb>3</lsb>
                            <msb>3</msb>
                            <access>read-write</access>
                            <enumeratedValues>
                                </enumeratedValues>
                        </field>
                        <field>
                            <name>ERS</name>
                            <description>Error Signal Status Flag</description>
                            <lsb>4</lsb>
                            <msb>4</msb>
                            <access>read-write</access>
                            <enumeratedValues>
                                </enumeratedValues>
                        </field>
                        <field>
                            <name>ORER</name>
                            <description>Overrun Error Flag</description>
                            <lsb>5</lsb>
                            <msb>5</msb>
                            <access>read-write</access>
                            <enumeratedValues>
                                </enumeratedValues>
                        </field>
                        <field>
                            <name>RDRF</name>
                            <description>Receive Data Full Flag</description>
                            <lsb>6</lsb>
                            <msb>6</msb>
                            <access>read-write</access>
                            <enumeratedValues>
                                </enumeratedValues>
                        </field>
                        <field>
                            <name>TDRE</name>
                            <description>Transmit Data Empty Flag</description>
                            <lsb>7</lsb>
                            <msb>7</msb>
                            <access>read-write</access>
                            <enumeratedValues>
                                </enumeratedValues>
                        </field>
                    </fields>
                </register>
                <register>
                    <name>RDR</name>
                    <description>Receive Data Register</description>
                    <addressOffset>0x05</addressOffset>
                    <size>8</size>
                    <access>read-only</access>
                    <resetValue>0x00</resetValue>
                    <resetMask>0xff</resetMask>
                </register>
                <register>
                    <name>SCMR</name>
                    <description>Smart Card Mode Register</description>
                    <addressOffset>0x06</addressOffset>
                    <size>8</size>
                    <access>read-write</access>
                    <resetValue>0xf2</resetValue>
                    <resetMask>0xff</resetMask>
                    <fields>
                        <field>
                            <name>SMIF</name>
                            <description>Smart Card Interface Mode Select</description>
                            <lsb>0</lsb>
                            <msb>0</msb>
                            <access>read-write</access>
                            <enumeratedValues>
                                </enumeratedValues>
                        </field>
                        <field>
                            <name>SINV</name>
                            <description>Transmitted/Received Data Invert</description>
                            <lsb>2</lsb>
                            <msb>2</msb>
                            <access>read-write</access>
                            <enumeratedValues>
                                </enumeratedValues>
                        </field>
                        <field>
                            <name>SDIR</name>
                            <description>Transmitted/Received Data Transfer Direction</description>
                            <lsb>3</lsb>
                            <msb>3</msb>
                            <access>read-write</access>
                            <enumeratedValues>
                                </enumeratedValues>
                        </field>
                        <field>
                            <name>CHR1</name>
                            <description>Character Length 1</description>
                            <lsb>4</lsb>
                            <msb>4</msb>
                            <access>read-write</access>
                            <enumeratedValues>
                                </enumeratedValues>
                        </field>
                        <field>
                            <name>BCP2</name>
                            <description>Base Clock Pulse 2</description>
                            <lsb>7</lsb>
                            <msb>7</msb>
                            <access>read-write</access>
                        </field>
                    </fields>
                </register>
                <register>
                    <name>SEMR</name>
                    <description>Serial Extended Mode Register</description>
                    <addressOffset>0x07</addressOffset>
                    <size>8</size>
                    <access>read-write</access>
                    <resetValue>0x00</resetValue>
                    <resetMask>0xff</resetMask>
                    <fields>
                        <field>
                            <name>ACS0</name>
                            <description>Asynchronous Mode Clock Source Select</description>
                            <lsb>0</lsb>
                            <msb>0</msb>
                            <access>read-write</access>
                            <enumeratedValues>
                                </enumeratedValues>
                        </field>
                        <field>
                            <name>PADIS</name>
                            <description>Preamble function Disable</description>
                            <lsb>1</lsb>
                            <msb>1</msb>
                            <access>read-write</access>
                            <enumeratedValues>
                                </enumeratedValues>
                        </field>
                        <field>
                            <name>BRME</name>
                            <description>Bit Rate Modulation Enable</description>
                            <lsb>2</lsb>
                            <msb>2</msb>
                            <access>read-write</access>
                            <enumeratedValues>
                                </enumeratedValues>
                        </field>
                        <field>
                            <name>ABCSE</name>
                            <description>Asynchronous Mode Extended Base Clock Select 1</description>
                            <lsb>3</lsb>
                            <msb>3</msb>
                            <access>read-write</access>
                            <enumeratedValues>
                                </enumeratedValues>
                        </field>
                        <field>
                            <name>ABCS</name>
                            <description>Asynchronous Mode Base Clock Select</description>
                            <lsb>4</lsb>
                            <msb>4</msb>
                            <access>read-write</access>
                            <enumeratedValues>
                                </enumeratedValues>
                        </field>
                        <field>
                            <name>NFEN</name>
                            <description>Digital Noise Filter Function Enable</description>
                            <lsb>5</lsb>
                            <msb>5</msb>
                            <access>read-write</access>
                            <enumeratedValues>
                                </enumeratedValues>
                        </field>
                        <field>
                            <name>BGDM</name>
                            <description>Baud Rate Generator Double,Speed Mode Select</description>
                            <lsb>6</lsb>
                            <msb>6</msb>
                            <access>read-write</access>
                            <enumeratedValues>
                                </enumeratedValues>
                        </field>
                        <field>
                            <name>RXDESEL</name>
                            <description>Asynchronous Start Bit Edge Detection Select</description>
                            <lsb>7</lsb>
                            <msb>7</msb>
                            <access>read-write</access>
                            <enumeratedValues>
                                </enumeratedValues>
                        </field>
                    </fields>
                </register>
                <register>
                    <name>SNFR</name>
                    <description>Noise Filter Setting Register</description>
                    <addressOffset>0x08</addressOffset>
                    <size>8</size>
                    <access>read-write</access>
                    <resetValue>0x00</resetValue>
                    <resetMask>0xff</resetMask>
                    <fields>
                        <field>
                            <name>NFCS</name>
                            <description>Noise Filter Clock Select</description>
                            <lsb>0</lsb>
                            <msb>2</msb>
                            <access>read-write</access>
                            <enumeratedValues>
                                </enumeratedValues>
                        </field>
                    </fields>
                </register>
                <register>
                    <name>SIMR1</name>
                    <description>IIC Mode Register 1</description>
                    <addressOffset>0x09</addressOffset>
                    <size>8</size>
                    <access>read-write</access>
                    <resetValue>0x00</resetValue>
                    <resetMask>0xff</resetMask>
                    <fields>
                        <field>
                            <name>IICM</name>
                            <description>Simple IIC Mode Select</description>
                            <lsb>0</lsb>
                            <msb>0</msb>
                            <access>read-write</access>
                            <enumeratedValues>
                                </enumeratedValues>
                        </field>
                        <field>
                            <name>IICDL</name>
                            <description>SDAn Delay Output Select</description>
                            <lsb>3</lsb>
                            <msb>7</msb>
                            <access>read-write</access>
                            <enumeratedValues>
                                </enumeratedValues>
                        </field>
                    </fields>
                </register>
                <register>
                    <name>SIMR2</name>
                    <description>IIC Mode Register 2</description>
                    <addressOffset>0x0A</addressOffset>
                    <size>8</size>
                    <access>read-write</access>
                    <resetValue>0x00</resetValue>
                    <resetMask>0xff</resetMask>
                    <fields>
                        <field>
                            <name>IICINTM</name>
                            <description>IIC Interrupt Mode Select</description>
                            <lsb>0</lsb>
                            <msb>0</msb>
                            <access>read-write</access>
                            <enumeratedValues>
                                </enumeratedValues>
                        </field>
                        <field>
                            <name>IICCSC</name>
                            <description>Clock Synchronization</description>
                            <lsb>1</lsb>
                            <msb>1</msb>
                            <access>read-write</access>
                            <enumeratedValues>
                                </enumeratedValues>
                        </field>
                        <field>
                            <name>IICACKT</name>
                            <description>ACK Transmission Data</description>
                            <lsb>5</lsb>
                            <msb>5</msb>
                            <access>read-write</access>
                            <enumeratedValues>
                                </enumeratedValues>
                        </field>
                    </fields>
                </register>
                <register>
                    <name>SIMR3</name>
                    <description>IIC Mode Register 3</description>
                    <addressOffset>0x0B</addressOffset>
                    <size>8</size>
                    <access>read-write</access>
                    <resetValue>0x00</resetValue>
                    <resetMask>0xff</resetMask>
                    <fields>
                        <field>
                            <name>IICSTAREQ</name>
                            <description>Start Condition Generation</description>
                            <lsb>0</lsb>
                            <msb>0</msb>
                            <access>read-write</access>
                            <enumeratedValues>
                                </enumeratedValues>
                        </field>
                        <field>
                            <name>IICRSTAREQ</name>
                            <description>Restart Condition Generation</description>
                            <lsb>1</lsb>
                            <msb>1</msb>
                            <access>read-write</access>
                            <enumeratedValues>
                                </enumeratedValues>
                        </field>
                        <field>
                            <name>IICSTPREQ</name>
                            <description>Stop Condition Generation</description>
                            <lsb>2</lsb>
                            <msb>2</msb>
                            <access>read-write</access>
                            <enumeratedValues>
                                </enumeratedValues>
                        </field>
                        <field>
                            <name>IICSTIF</name>
                            <description>Issuing of Start, Restart, or Stop Condition Completed Flag</description>
                            <lsb>3</lsb>
                            <msb>3</msb>
                            <access>read-write</access>
                            <enumeratedValues>
                                </enumeratedValues>
                        </field>
                        <field>
                            <name>IICSDAS</name>
                            <description>SDAn Output Select</description>
                            <lsb>4</lsb>
                            <msb>5</msb>
                            <access>read-write</access>
                            <enumeratedValues>
                                </enumeratedValues>
                        </field>
                        <field>
                            <name>IICSCLS</name>
                            <description>SCLn Output Select</description>
                            <lsb>6</lsb>
                            <msb>7</msb>
                            <access>read-write</access>
                            <enumeratedValues>
                                </enumeratedValues>
                        </field>
                    </fields>
                </register>
                <register>
                    <name>SISR</name>
                    <description>IIC Status Register</description>
                    <addressOffset>0x0C</addressOffset>
                    <size>8</size>
                    <access>read-only</access>
                    <resetValue>0x00</resetValue>
                    <resetMask>0xcb</resetMask>
                    <fields>
                        <field>
                            <name>IICACKR</name>
                            <description>ACK Reception Data Flag</description>
                            <lsb>0</lsb>
                            <msb>0</msb>
                            <access>read-only</access>
                            <enumeratedValues>
                                </enumeratedValues>
                        </field>
                    </fields>
                </register>
                <register>
                    <name>SPMR</name>
                    <description>SPI Mode Register</description>
                    <addressOffset>0x0D</addressOffset>
                    <size>8</size>
                    <access>read-write</access>
                    <resetValue>0x00</resetValue>
                    <resetMask>0xff</resetMask>
                    <fields>
                        <field>
                            <name>SSE</name>
                            <description>SSn Pin Function Enable</description>
                            <lsb>0</lsb>
                            <msb>0</msb>
                            <access>read-write</access>
                            <enumeratedValues>
                                </enumeratedValues>
                        </field>
                        <field>
                            <name>CTSE</name>
                            <description>CTS Enable</description>
                            <lsb>1</lsb>
                            <msb>1</msb>
                            <access>read-write</access>
                            <enumeratedValues>
                                </enumeratedValues>
                        </field>
                        <field>
                            <name>MSS</name>
                            <description>Master Slave Select</description>
                            <lsb>2</lsb>
                            <msb>2</msb>
                            <access>read-write</access>
                            <enumeratedValues>
                                </enumeratedValues>
                        </field>
                        <field>
                            <name>CTSPEN</name>
                            <description>CTS external pin Enable</description>
                            <lsb>3</lsb>
                            <msb>3</msb>
                            <access>read-write</access>
                            <enumeratedValues>
                                </enumeratedValues>
                        </field>
                        <field>
                            <name>MFF</name>
                            <description>Mode Fault Flag</description>
                            <lsb>4</lsb>
                            <msb>4</msb>
                            <access>read-write</access>
                            <enumeratedValues>
                                </enumeratedValues>
                        </field>
                        <field>
                            <name>CKPOL</name>
                            <description>Clock Polarity Select</description>
                            <lsb>6</lsb>
                            <msb>6</msb>
                            <access>read-write</access>
                            <enumeratedValues>
                                </enumeratedValues>
                        </field>
                        <field>
                            <name>CKPH</name>
                            <description>Clock Phase Select</description>
                            <lsb>7</lsb>
                            <msb>7</msb>
                            <access>read-write</access>
                            <enumeratedValues>
                                </enumeratedValues>
                        </field>
                    </fields>
                </register>
                <register>
                    <name>TDRHL</name>
                    <description>Transmit Data Register for Non,Manchester mode (MMR.MANEN = 0)</description>
                    <alternateRegister>FTDRHL</alternateRegister>
                    <addressOffset>0x0E</addressOffset>
                    <size>16</size>
                    <access>read-write</access>
                    <resetValue>0xffff</resetValue>
                    <resetMask>0xffff</resetMask>
                    <fields>
                        <field>
                            <name>TDAT</name>
                            <description>Serial Transmit Data</description>
                            <lsb>0</lsb>
                            <msb>8</msb>
                            <access>read-write</access>
                        </field>
                    </fields>
                </register>
                <register>
                    <name>RDRHL</name>
                    <description>Receive Data Register for Non,Manchester mode (MMR.MANEN = 0)</description>
                    <alternateRegister>FRDRHL</alternateRegister>
                    <addressOffset>0x10</addressOffset>
                    <size>16</size>
                    <access>read-only</access>
                    <resetValue>0x0000</resetValue>
                    <resetMask>0xffff</resetMask>
                    <fields>
                        <field>
                            <name>RDAT</name>
                            <description>Serial Receive Data</description>
                            <lsb>0</lsb>
                            <msb>8</msb>
                            <access>read-only</access>
                        </field>
                    </fields>
                </register>
                <register>
                    <name>MDDR</name>
                    <description>Modulation Duty Register</description>
                    <addressOffset>0x12</addressOffset>
                    <size>8</size>
                    <access>read-write</access>
                    <resetValue>0xff</resetValue>
                    <resetMask>0xff</resetMask>
                </register>
                <register>
                    <name>ESMER</name>
                    <description>Extended Serial Module Enable Register</description>
                    <addressOffset>0x20</addressOffset>
                    <size>8</size>
                    <access>read-write</access>
                    <resetValue>0x00</resetValue>
                    <resetMask>0xff</resetMask>
                    <fields>
                        <field>
                            <name>ESME</name>
                            <description>Extended Serial Mode Enable</description>
                            <lsb>0</lsb>
                            <msb>0</msb>
                            <access>read-write</access>
                            <enumeratedValues>
                                </enumeratedValues>
                        </field>
                    </fields>
                </register>
                <register>
                    <name>CR0</name>
                    <description>Control Register 0</description>
                    <addressOffset>0x21</addressOffset>
                    <size>8</size>
                    <access>read-write</access>
                    <resetValue>0x00</resetValue>
                    <resetMask>0xff</resetMask>
                    <fields>
                        <field>
                            <name>SFSF</name>
                            <description>Start Frame Status Flag</description>
                            <lsb>1</lsb>
                            <msb>1</msb>
                            <access>read-only</access>
                            <enumeratedValues>
                                </enumeratedValues>
                        </field>
                        <field>
                            <name>RXDSF</name>
                            <description>RXDXn Input Status Flag</description>
                            <lsb>2</lsb>
                            <msb>2</msb>
                            <access>read-only</access>
                            <enumeratedValues>
                                </enumeratedValues>
                        </field>
                        <field>
                            <name>BRME</name>
                            <description>Bit Rate Measurement Enable</description>
                            <lsb>3</lsb>
                            <msb>3</msb>
                            <access>read-write</access>
                            <enumeratedValues>
                                </enumeratedValues>
                        </field>
                    </fields>
                </register>
                <register>
                    <name>CR1</name>
                    <description>Control Register 1</description>
                    <addressOffset>0x22</addressOffset>
                    <size>8</size>
                    <access>read-write</access>
                    <resetValue>0x00</resetValue>
                    <resetMask>0xff</resetMask>
                    <fields>
                        <field>
                            <name>BFE</name>
                            <description>Break Field Enable</description>
                            <lsb>0</lsb>
                            <msb>0</msb>
                            <access>read-write</access>
                            <enumeratedValues>
                                </enumeratedValues>
                        </field>
                        <field>
                            <name>CF0RE</name>
                            <description>Control Field 0 Reception Enable</description>
                            <lsb>1</lsb>
                            <msb>1</msb>
                            <access>read-write</access>
                            <enumeratedValues>
                                </enumeratedValues>
                        </field>
                        <field>
                            <name>CF1DS</name>
                            <description>Control Field 1 Data Register Select</description>
                            <lsb>2</lsb>
                            <msb>3</msb>
                            <access>read-write</access>
                            <enumeratedValues>
                                </enumeratedValues>
                        </field>
                        <field>
                            <name>PIBE</name>
                            <description>Priority Interrupt Bit Enable</description>
                            <lsb>4</lsb>
                            <msb>4</msb>
                            <access>read-write</access>
                            <enumeratedValues>
                                </enumeratedValues>
                        </field>
                        <field>
                            <name>PIBS</name>
                            <description>Priority Interrupt Bit Select</description>
                            <lsb>5</lsb>
                            <msb>7</msb>
                            <access>read-write</access>
                            <enumeratedValues>
                                </enumeratedValues>
                        </field>
                    </fields>
                </register>
                <register>
                    <name>CR2</name>
                    <description>Control Register 2</description>
                    <addressOffset>0x23</addressOffset>
                    <size>8</size>
                    <access>read-write</access>
                    <resetValue>0x00</resetValue>
                    <resetMask>0xff</resetMask>
                    <fields>
                        <field>
                            <name>DFCS</name>
                            <description>RXDXn Signal Digital Filter Clock Select</description>
                            <lsb>0</lsb>
                            <msb>2</msb>
                            <access>read-write</access>
                            <enumeratedValues>
                                </enumeratedValues>
                        </field>
                        <field>
                            <name>BCCS</name>
                            <description>Bus Collision Detection Clock Select</description>
                            <lsb>4</lsb>
                            <msb>5</msb>
                            <access>read-write</access>
                            <enumeratedValues>
                                </enumeratedValues>
                        </field>
                        <field>
                            <name>RTS</name>
                            <description>RXDXn Reception Sampling Timing Select</description>
                            <lsb>6</lsb>
                            <msb>7</msb>
                            <access>read-write</access>
                            <enumeratedValues>
                                </enumeratedValues>
                        </field>
                    </fields>
                </register>
                <register>
                    <name>CR3</name>
                    <description>Control Register 3</description>
                    <addressOffset>0x24</addressOffset>
                    <size>8</size>
                    <access>read-write</access>
                    <resetValue>0x00</resetValue>
                    <resetMask>0xff</resetMask>
                    <fields>
                        <field>
                            <name>SDST</name>
                            <description>Start Frame Detection Start</description>
                            <lsb>0</lsb>
                            <msb>0</msb>
                            <access>read-write</access>
                            <enumeratedValues>
                                </enumeratedValues>
                        </field>
                    </fields>
                </register>
                <register>
                    <name>PCR</name>
                    <description>Port Control Register</description>
                    <addressOffset>0x25</addressOffset>
                    <size>8</size>
                    <access>read-write</access>
                    <resetValue>0x00</resetValue>
                    <resetMask>0xff</resetMask>
                    <fields>
                        <field>
                            <name>TXDXPS</name>
                            <description>TXDXn Signal Polarity Select</description>
                            <lsb>0</lsb>
                            <msb>0</msb>
                            <access>read-write</access>
                            <enumeratedValues>
                                </enumeratedValues>
                        </field>
                        <field>
                            <name>RXDXPS</name>
                            <description>RXDXn Signal Polarity Select</description>
                            <lsb>1</lsb>
                            <msb>1</msb>
                            <access>read-write</access>
                            <enumeratedValues>
                                </enumeratedValues>
                        </field>
                        <field>
                            <name>SHARPS</name>
                            <description>TXDXn/RXDXn Pin Multiplexing Select</description>
                            <lsb>4</lsb>
                            <msb>4</msb>
                            <access>read-write</access>
                            <enumeratedValues>
                                </enumeratedValues>
                        </field>
                    </fields>
                </register>
                <register>
                    <name>ICR</name>
                    <description>Interrupt Control Register</description>
                    <addressOffset>0x26</addressOffset>
                    <size>8</size>
                    <access>read-write</access>
                    <resetValue>0x00</resetValue>
                    <resetMask>0xff</resetMask>
                    <fields>
                        <field>
                            <name>BFDIE</name>
                            <description>Break Field Low Width Detected Interrupt Enable</description>
                            <lsb>0</lsb>
                            <msb>0</msb>
                            <access>read-write</access>
                            <enumeratedValues>
                                </enumeratedValues>
                        </field>
                        <field>
                            <name>CF0MIE</name>
                            <description>Control Field 0 Match Detected Interrupt Enable</description>
                            <lsb>1</lsb>
                            <msb>1</msb>
                            <access>read-write</access>
                            <enumeratedValues>
                                </enumeratedValues>
                        </field>
                        <field>
                            <name>CF1MIE</name>
                            <description>Control Field 1 Match Detected Interrupt Enable</description>
                            <lsb>2</lsb>
                            <msb>2</msb>
                            <access>read-write</access>
                            <enumeratedValues>
                                </enumeratedValues>
                        </field>
                        <field>
                            <name>PIBDIE</name>
                            <description>Priority Interrupt Bit Detected Interrupt Enable</description>
                            <lsb>3</lsb>
                            <msb>3</msb>
                            <access>read-write</access>
                            <enumeratedValues>
                                </enumeratedValues>
                        </field>
                        <field>
                            <name>BCDIE</name>
                            <description>Bus Collision Detected Interrupt Enable</description>
                            <lsb>4</lsb>
                            <msb>4</msb>
                            <access>read-write</access>
                            <enumeratedValues>
                                </enumeratedValues>
                        </field>
                        <field>
                            <name>AEDIE</name>
                            <description>Valid Edge Detected Interrupt Enable</description>
                            <lsb>5</lsb>
                            <msb>5</msb>
                            <access>read-write</access>
                            <enumeratedValues>
                                </enumeratedValues>
                        </field>
                    </fields>
                </register>
                <register>
                    <name>STR</name>
                    <description>Status Register</description>
                    <addressOffset>0x27</addressOffset>
                    <size>8</size>
                    <access>read-only</access>
                    <resetValue>0x00</resetValue>
                    <resetMask>0xff</resetMask>
                    <fields>
                        <field>
                            <name>BFDF</name>
                            <description>Break Field Low Width Detection Flag</description>
                            <lsb>0</lsb>
                            <msb>0</msb>
                            <access>read-only</access>
                        </field>
                        <field>
                            <name>CF0MF</name>
                            <description>Control Field 0 Match Flag</description>
                            <lsb>1</lsb>
                            <msb>1</msb>
                            <access>read-only</access>
                        </field>
                        <field>
                            <name>CF1MF</name>
                            <description>Control Field 1 Match Flag</description>
                            <lsb>2</lsb>
                            <msb>2</msb>
                            <access>read-only</access>
                        </field>
                        <field>
                            <name>PIBDF</name>
                            <description>Priority Interrupt Bit Detection Flag</description>
                            <lsb>3</lsb>
                            <msb>3</msb>
                            <access>read-only</access>
                        </field>
                        <field>
                            <name>BCDF</name>
                            <description>Bus Collision Detected Flag</description>
                            <lsb>4</lsb>
                            <msb>4</msb>
                            <access>read-only</access>
                        </field>
                        <field>
                            <name>AEDF</name>
                            <description>Valid Edge Detection Flag</description>
                            <lsb>5</lsb>
                            <msb>5</msb>
                            <access>read-only</access>
                        </field>
                    </fields>
                </register>
                <register>
                    <name>STCR</name>
                    <description>Status Clear Register</description>
                    <addressOffset>0x28</addressOffset>
                    <size>8</size>
                    <access>read-write</access>
                    <resetValue>0x00</resetValue>
                    <resetMask>0xff</resetMask>
                    <fields>
                        <field>
                            <name>BFDCL</name>
                            <description>BFDF Clear</description>
                            <lsb>0</lsb>
                            <msb>0</msb>
                            <access>read-write</access>
                        </field>
                        <field>
                            <name>CF0MCL</name>
                            <description>CF0MF Clear</description>
                            <lsb>1</lsb>
                            <msb>1</msb>
                            <access>read-write</access>
                        </field>
                        <field>
                            <name>CF1MCL</name>
                            <description>CF1MF Clear</description>
                            <lsb>2</lsb>
                            <msb>2</msb>
                            <access>read-write</access>
                        </field>
                        <field>
                            <name>PIBDCL</name>
                            <description>PIBDF Clear</description>
                            <lsb>3</lsb>
                            <msb>3</msb>
                            <access>read-write</access>
                        </field>
                        <field>
                            <name>BCDCL</name>
                            <description>BCDF Clear</description>
                            <lsb>4</lsb>
                            <msb>4</msb>
                            <access>read-write</access>
                        </field>
                        <field>
                            <name>AEDCL</name>
                            <description>AEDF Clear</description>
                            <lsb>5</lsb>
                            <msb>5</msb>
                            <access>read-write</access>
                        </field>
                    </fields>
                </register>
                <register>
                    <name>CF0DR</name>
                    <description>Control Field 0 Data Register</description>
                    <addressOffset>0x29</addressOffset>
                    <size>8</size>
                    <access>read-write</access>
                    <resetValue>0x00</resetValue>
                    <resetMask>0xff</resetMask>
                </register>
                <register>
                    <name>CF0CR</name>
                    <description>Control Field 0 Compare Enable Register</description>
                    <addressOffset>0x2A</addressOffset>
                    <size>8</size>
                    <access>read-write</access>
                    <resetValue>0x00</resetValue>
                    <resetMask>0xff</resetMask>
                    <fields>
                        <field>
                            <name>CF0CE0</name>
                            <description>Control Field 0 Bit 0 Compare Enable</description>
                            <lsb>0</lsb>
                            <msb>0</msb>
                            <access>read-write</access>
                            <enumeratedValues>
                                </enumeratedValues>
                        </field>
                        <field>
                            <name>CF0CE1</name>
                            <description>Control Field 1 Bit 0 Compare Enable</description>
                            <lsb>1</lsb>
                            <msb>1</msb>
                            <access>read-write</access>
                            <enumeratedValues>
                                </enumeratedValues>
                        </field>
                        <field>
                            <name>CF0CE2</name>
                            <description>Control Field 2 Bit 0 Compare Enable</description>
                            <lsb>2</lsb>
                            <msb>2</msb>
                            <access>read-write</access>
                            <enumeratedValues>
                                </enumeratedValues>
                        </field>
                        <field>
                            <name>CF0CE3</name>
                            <description>Control Field 3 Bit 0 Compare Enable</description>
                            <lsb>3</lsb>
                            <msb>3</msb>
                            <access>read-write</access>
                            <enumeratedValues>
                                </enumeratedValues>
                        </field>
                        <field>
                            <name>CF0CE4</name>
                            <description>Control Field 4 Bit 0 Compare Enable</description>
                            <lsb>4</lsb>
                            <msb>4</msb>
                            <access>read-write</access>
                            <enumeratedValues>
                                </enumeratedValues>
                        </field>
                        <field>
                            <name>CF0CE5</name>
                            <description>Control Field 5 Bit 0 Compare Enable</description>
                            <lsb>5</lsb>
                            <msb>5</msb>
                            <access>read-write</access>
                            <enumeratedValues>
                                </enumeratedValues>
                        </field>
                        <field>
                            <name>CF0CE6</name>
                            <description>Control Field 6 Bit 0 Compare Enable</description>
                            <lsb>6</lsb>
                            <msb>6</msb>
                            <access>read-write</access>
                            <enumeratedValues>
                                </enumeratedValues>
                        </field>
                        <field>
                            <name>CF0CE7</name>
                            <description>Control Field 7 Bit 0 Compare Enable</description>
                            <lsb>7</lsb>
                            <msb>7</msb>
                            <access>read-write</access>
                            <enumeratedValues>
                                </enumeratedValues>
                        </field>
                    </fields>
                </register>
                <register>
                    <name>CF0RR</name>
                    <description>Control Field 0 Receive Data Register</description>
                    <addressOffset>0x2B</addressOffset>
                    <size>8</size>
                    <access>read-write</access>
                    <resetValue>0x00</resetValue>
                    <resetMask>0xff</resetMask>
                </register>
                <register>
                    <name>PCF1DR</name>
                    <description>Primary Control Field 1 Data Register</description>
                    <addressOffset>0x2C</addressOffset>
                    <size>8</size>
                    <access>read-write</access>
                    <resetValue>0x00</resetValue>
                    <resetMask>0xff</resetMask>
                </register>
                <register>
                    <name>SCF1DR</name>
                    <description>Secondary Control Field 1 Data Register</description>
                    <addressOffset>0x2D</addressOffset>
                    <size>8</size>
                    <access>read-write</access>
                    <resetValue>0x00</resetValue>
                    <resetMask>0xff</resetMask>
                </register>
                <register>
                    <name>CF1CR</name>
                    <description>Control Field 1 Compare Enable Register</description>
                    <addressOffset>0x2E</addressOffset>
                    <size>8</size>
                    <access>read-write</access>
                    <resetValue>0x00</resetValue>
                    <resetMask>0xff</resetMask>
                    <fields>
                        <field>
                            <name>CF1CE0</name>
                            <description>Control Field 1 Bit 0 Compare Enable</description>
                            <lsb>0</lsb>
                            <msb>0</msb>
                            <access>read-write</access>
                            <enumeratedValues>
                                </enumeratedValues>
                        </field>
                        <field>
                            <name>CF1CE1</name>
                            <description>Control Field 1 Bit 1 Compare Enable</description>
                            <lsb>1</lsb>
                            <msb>1</msb>
                            <access>read-write</access>
                            <enumeratedValues>
                                </enumeratedValues>
                        </field>
                        <field>
                            <name>CF1CE2</name>
                            <description>Control Field 1 Bit 2 Compare Enable</description>
                            <lsb>2</lsb>
                            <msb>2</msb>
                            <access>read-write</access>
                            <enumeratedValues>
                                </enumeratedValues>
                        </field>
                        <field>
                            <name>CF1CE3</name>
                            <description>Control Field 1 Bit 3 Compare Enable</description>
                            <lsb>3</lsb>
                            <msb>3</msb>
                            <access>read-write</access>
                            <enumeratedValues>
                                </enumeratedValues>
                        </field>
                        <field>
                            <name>CF1CE4</name>
                            <description>Control Field 1 Bit 4 Compare Enable</description>
                            <lsb>4</lsb>
                            <msb>4</msb>
                            <access>read-write</access>
                            <enumeratedValues>
                                </enumeratedValues>
                        </field>
                        <field>
                            <name>CF1CE5</name>
                            <description>Control Field 1 Bit 5 Compare Enable</description>
                            <lsb>5</lsb>
                            <msb>5</msb>
                            <access>read-write</access>
                            <enumeratedValues>
                                </enumeratedValues>
                        </field>
                        <field>
                            <name>CF1CE6</name>
                            <description>Control Field 1 Bit 6 Compare Enable</description>
                            <lsb>6</lsb>
                            <msb>6</msb>
                            <access>read-write</access>
                            <enumeratedValues>
                                </enumeratedValues>
                        </field>
                        <field>
                            <name>CF1CE7</name>
                            <description>Control Field 1 Bit 7 Compare Enable</description>
                            <lsb>7</lsb>
                            <msb>7</msb>
                            <access>read-write</access>
                            <enumeratedValues>
                                </enumeratedValues>
                        </field>
                    </fields>
                </register>
                <register>
                    <name>CF1RR</name>
                    <description>Control Field 1 Receive Data Register</description>
                    <addressOffset>0x2F</addressOffset>
                    <size>8</size>
                    <access>read-write</access>
                    <resetValue>0x00</resetValue>
                    <resetMask>0xff</resetMask>
                </register>
                <register>
                    <name>TCR</name>
                    <description>Timer Control Register</description>
                    <addressOffset>0x30</addressOffset>
                    <size>8</size>
                    <access>read-write</access>
                    <resetValue>0x00</resetValue>
                    <resetMask>0xff</resetMask>
                    <fields>
                        <field>
                            <name>TCST</name>
                            <description>Timer Count Start</description>
                            <lsb>0</lsb>
                            <msb>0</msb>
                            <access>read-write</access>
                            <enumeratedValues>
                                </enumeratedValues>
                        </field>
                    </fields>
                </register>
                <register>
                    <name>TMR</name>
                    <description>Timer Mode Register</description>
                    <addressOffset>0x31</addressOffset>
                    <size>8</size>
                    <access>read-write</access>
                    <resetValue>0x00</resetValue>
                    <resetMask>0xff</resetMask>
                    <fields>
                        <field>
                            <name>TOMS</name>
                            <description>Timer Operating Mode Select</description>
                            <lsb>0</lsb>
                            <msb>1</msb>
                            <access>read-write</access>
                            <enumeratedValues>
                                </enumeratedValues>
                        </field>
                        <field>
                            <name>TWRC</name>
                            <description>Counter Write Control</description>
                            <lsb>3</lsb>
                            <msb>3</msb>
                            <access>read-write</access>
                            <enumeratedValues>
                                </enumeratedValues>
                        </field>
                        <field>
                            <name>TCSS</name>
                            <description>Timer Count Clock Source Select</description>
                            <lsb>4</lsb>
                            <msb>6</msb>
                            <access>read-write</access>
                            <enumeratedValues>
                                </enumeratedValues>
                        </field>
                    </fields>
                </register>
                <register>
                    <name>TPRE</name>
                    <description>Timer Prescaler Register</description>
                    <addressOffset>0x32</addressOffset>
                    <size>8</size>
                    <access>read-write</access>
                    <resetValue>0xff</resetValue>
                    <resetMask>0xff</resetMask>
                </register>
                <register>
                    <name>TCNT</name>
                    <description>Timer Count Register</description>
                    <addressOffset>0x33</addressOffset>
                    <size>8</size>
                    <access>read-write</access>
                    <resetValue>0xff</resetValue>
                    <resetMask>0xff</resetMask>
                </register>
            </registers>
        </peripheral>
        <peripheral derivedFrom="SCI1">
            <name>SCI2</name>
            <description>Serial Communication Interface 0</description>
            <baseAddress>0x40118200</baseAddress>
        </peripheral>
        <peripheral>
            <name>SCI3</name>
            <description>Serial Communication Interface</description>
            <baseAddress>0x40118300</baseAddress>
            <addressBlock>
                <offset>0x00</offset>
                <size>30</size>
                <usage>registers</usage>
            </addressBlock>
            <addressBlock>
                <offset>0x20</offset>
                <size>1</size>
                <usage>registers</usage>
            </addressBlock>
            <addressBlock>
                <offset>0x22</offset>
                <size>4</size>
                <usage>registers</usage>
            </addressBlock>
            <registers>
                <register>
                    <name>SMR</name>
                    <description>Serial Mode Register for Non,Smart Card Interface Mode (SCMR.SMIF = 0)</description>
                    <addressOffset>0x00</addressOffset>
                    <size>8</size>
                    <access>read-write</access>
                    <resetValue>0x00</resetValue>
                    <resetMask>0xff</resetMask>
                    <fields>
                        <field>
                            <name>CKS</name>
                            <description>Clock Select</description>
                            <lsb>0</lsb>
                            <msb>1</msb>
                            <access>read-write</access>
                            <enumeratedValues>
                                </enumeratedValues>
                        </field>
                        <field>
                            <name>MP</name>
                            <description>Multi,Processor Mode</description>
                            <lsb>2</lsb>
                            <msb>2</msb>
                            <access>read-write</access>
                            <enumeratedValues>
                                </enumeratedValues>
                        </field>
                        <field>
                            <name>STOP</name>
                            <description>Stop Bit Length</description>
                            <lsb>3</lsb>
                            <msb>3</msb>
                            <access>read-write</access>
                            <enumeratedValues>
                                </enumeratedValues>
                        </field>
                        <field>
                            <name>PM</name>
                            <description>Parity Mode</description>
                            <lsb>4</lsb>
                            <msb>4</msb>
                            <access>read-write</access>
                            <enumeratedValues>
                                </enumeratedValues>
                        </field>
                        <field>
                            <name>PE</name>
                            <description>Parity Enable</description>
                            <lsb>5</lsb>
                            <msb>5</msb>
                            <access>read-write</access>
                            <enumeratedValues>
                                </enumeratedValues>
                        </field>
                        <field>
                            <name>CHR</name>
                            <description>Character Length</description>
                            <lsb>6</lsb>
                            <msb>6</msb>
                            <access>read-write</access>
                            <enumeratedValues>
                                </enumeratedValues>
                        </field>
                        <field>
                            <name>CM</name>
                            <description>Communication Mode</description>
                            <lsb>7</lsb>
                            <msb>7</msb>
                            <access>read-write</access>
                            <enumeratedValues>
                                </enumeratedValues>
                        </field>
                    </fields>
                </register>
                <register>
                    <name>SMR_SMCI</name>
                    <description>Serial Mode Register for Smart Card Interface Mode (SCMR.SMIF = 1)</description>
                    <alternateRegister>SMR</alternateRegister>
                    <addressOffset>0x00</addressOffset>
                    <size>8</size>
                    <access>read-write</access>
                    <resetValue>0x00</resetValue>
                    <resetMask>0xff</resetMask>
                    <fields>
                        <field>
                            <name>CKS</name>
                            <description>Clock Select</description>
                            <lsb>0</lsb>
                            <msb>1</msb>
                            <access>read-write</access>
                            <enumeratedValues>
                                </enumeratedValues>
                        </field>
                        <field>
                            <name>BCP</name>
                            <description>Base Clock Pulse</description>
                            <lsb>2</lsb>
                            <msb>3</msb>
                            <access>read-write</access>
                        </field>
                        <field>
                            <name>PM</name>
                            <description>Parity Mode</description>
                            <lsb>4</lsb>
                            <msb>4</msb>
                            <access>read-write</access>
                            <enumeratedValues>
                                </enumeratedValues>
                        </field>
                        <field>
                            <name>PE</name>
                            <description>Parity Enable</description>
                            <lsb>5</lsb>
                            <msb>5</msb>
                            <access>read-write</access>
                        </field>
                        <field>
                            <name>BLK</name>
                            <description>Block Transfer Mode</description>
                            <lsb>6</lsb>
                            <msb>6</msb>
                            <access>read-write</access>
                            <enumeratedValues>
                                </enumeratedValues>
                        </field>
                        <field>
                            <name>GM</name>
                            <description>GSM Mode</description>
                            <lsb>7</lsb>
                            <msb>7</msb>
                            <access>read-write</access>
                            <enumeratedValues>
                                </enumeratedValues>
                        </field>
                    </fields>
                </register>
                <register>
                    <name>BRR</name>
                    <description>Bit Rate Register</description>
                    <addressOffset>0x01</addressOffset>
                    <size>8</size>
                    <access>read-write</access>
                    <resetValue>0xff</resetValue>
                    <resetMask>0xff</resetMask>
                </register>
                <register>
                    <name>SCR</name>
                    <description>Serial Control Register for Non,Smart Card Interface Mode (SCMR.SMIF = 0)</description>
                    <addressOffset>0x02</addressOffset>
                    <size>8</size>
                    <access>read-write</access>
                    <resetValue>0x00</resetValue>
                    <resetMask>0xff</resetMask>
                    <fields>
                        <field>
                            <name>CKE</name>
                            <description>Clock Enable</description>
                            <lsb>0</lsb>
                            <msb>1</msb>
                            <access>read-write</access>
                            <enumeratedValues>
                                </enumeratedValues>
                        </field>
                        <field>
                            <name>TEIE</name>
                            <description>Transmit End Interrupt Enable</description>
                            <lsb>2</lsb>
                            <msb>2</msb>
                            <access>read-write</access>
                            <enumeratedValues>
                                </enumeratedValues>
                        </field>
                        <field>
                            <name>MPIE</name>
                            <description>Multi,Processor Interrupt Enable</description>
                            <lsb>3</lsb>
                            <msb>3</msb>
                            <access>read-write</access>
                            <enumeratedValues>
                                </enumeratedValues>
                        </field>
                        <field>
                            <name>RE</name>
                            <description>Receive Enable</description>
                            <lsb>4</lsb>
                            <msb>4</msb>
                            <access>read-write</access>
                            <enumeratedValues>
                                </enumeratedValues>
                        </field>
                        <field>
                            <name>TE</name>
                            <description>Transmit Enable</description>
                            <lsb>5</lsb>
                            <msb>5</msb>
                            <access>read-write</access>
                            <enumeratedValues>
                                </enumeratedValues>
                        </field>
                        <field>
                            <name>RIE</name>
                            <description>Receive Interrupt Enable</description>
                            <lsb>6</lsb>
                            <msb>6</msb>
                            <access>read-write</access>
                            <enumeratedValues>
                                </enumeratedValues>
                        </field>
                        <field>
                            <name>TIE</name>
                            <description>Transmit Interrupt Enable</description>
                            <lsb>7</lsb>
                            <msb>7</msb>
                            <access>read-write</access>
                            <enumeratedValues>
                                </enumeratedValues>
                        </field>
                    </fields>
                </register>
                <register>
                    <name>SCR_SMCI</name>
                    <description>Serial Control Register for Smart Card Interface Mode (SCMR.SMIF = 1)</description>
                    <alternateRegister>SCR</alternateRegister>
                    <addressOffset>0x02</addressOffset>
                    <size>8</size>
                    <access>read-write</access>
                    <resetValue>0x00</resetValue>
                    <resetMask>0xff</resetMask>
                    <fields>
                        <field>
                            <name>CKE</name>
                            <description>Clock Enable</description>
                            <lsb>0</lsb>
                            <msb>1</msb>
                            <access>read-write</access>
                            <enumeratedValues>
                                </enumeratedValues>
                        </field>
                        <field>
                            <name>TEIE</name>
                            <description>Transmit End Interrupt Enable</description>
                            <lsb>2</lsb>
                            <msb>2</msb>
                            <access>read-write</access>
                        </field>
                        <field>
                            <name>MPIE</name>
                            <description>Multi,Processor Interrupt Enable</description>
                            <lsb>3</lsb>
                            <msb>3</msb>
                            <access>read-write</access>
                        </field>
                        <field>
                            <name>RE</name>
                            <description>Receive Enable</description>
                            <lsb>4</lsb>
                            <msb>4</msb>
                            <access>read-write</access>
                            <enumeratedValues>
                                </enumeratedValues>
                        </field>
                        <field>
                            <name>TE</name>
                            <description>Transmit Enable</description>
                            <lsb>5</lsb>
                            <msb>5</msb>
                            <access>read-write</access>
                            <enumeratedValues>
                                </enumeratedValues>
                        </field>
                        <field>
                            <name>RIE</name>
                            <description>Receive Interrupt Enable</description>
                            <lsb>6</lsb>
                            <msb>6</msb>
                            <access>read-write</access>
                            <enumeratedValues>
                                </enumeratedValues>
                        </field>
                        <field>
                            <name>TIE</name>
                            <description>Transmit Interrupt Enable</description>
                            <lsb>7</lsb>
                            <msb>7</msb>
                            <access>read-write</access>
                            <enumeratedValues>
                                </enumeratedValues>
                        </field>
                    </fields>
                </register>
                <register>
                    <name>TDR</name>
                    <description>Transmit Data Register</description>
                    <addressOffset>0x03</addressOffset>
                    <size>8</size>
                    <access>read-write</access>
                    <resetValue>0xff</resetValue>
                    <resetMask>0xff</resetMask>
                </register>
                <register>
                    <name>SSR</name>
                    <description>Serial Status Register for Non,Smart Card Interface and Non,FIFO Mode (SCMR.SMIF = 0, FCR.FM = 0, and MMR.MANEN = 0)</description>
                    <addressOffset>0x04</addressOffset>
                    <size>8</size>
                    <access>read-write</access>
                    <resetValue>0x84</resetValue>
                    <resetMask>0xff</resetMask>
                    <fields>
                        <field>
                            <name>MPBT</name>
                            <description>Multi,Processor Bit Transfer</description>
                            <lsb>0</lsb>
                            <msb>0</msb>
                            <access>read-write</access>
                            <enumeratedValues>
                                </enumeratedValues>
                        </field>
                        <field>
                            <name>MPB</name>
                            <description>Multi,Processor</description>
                            <lsb>1</lsb>
                            <msb>1</msb>
                            <access>read-only</access>
                            <enumeratedValues>
                                </enumeratedValues>
                        </field>
                        <field>
                            <name>TEND</name>
                            <description>Transmit End Flag</description>
                            <lsb>2</lsb>
                            <msb>2</msb>
                            <access>read-only</access>
                            <enumeratedValues>
                                </enumeratedValues>
                        </field>
                        <field>
                            <name>PER</name>
                            <description>Parity Error Flag</description>
                            <lsb>3</lsb>
                            <msb>3</msb>
                            <access>read-write</access>
                            <enumeratedValues>
                                </enumeratedValues>
                        </field>
                        <field>
                            <name>FER</name>
                            <description>Framing Error Flag</description>
                            <lsb>4</lsb>
                            <msb>4</msb>
                            <access>read-write</access>
                            <enumeratedValues>
                                </enumeratedValues>
                        </field>
                        <field>
                            <name>ORER</name>
                            <description>Overrun Error Flag</description>
                            <lsb>5</lsb>
                            <msb>5</msb>
                            <access>read-write</access>
                            <enumeratedValues>
                                </enumeratedValues>
                        </field>
                        <field>
                            <name>RDRF</name>
                            <description>Receive Data Full Flag</description>
                            <lsb>6</lsb>
                            <msb>6</msb>
                            <access>read-write</access>
                            <enumeratedValues>
                                </enumeratedValues>
                        </field>
                        <field>
                            <name>TDRE</name>
                            <description>Transmit Data Empty Flag</description>
                            <lsb>7</lsb>
                            <msb>7</msb>
                            <access>read-write</access>
                            <enumeratedValues>
                                </enumeratedValues>
                        </field>
                    </fields>
                </register>
                <register>
                    <name>SSR_FIFO</name>
                    <description>Serial Status Register for Non,Smart Card Interface and FIFO Mode (SCMR.SMIF = 0, FCR.FM = 1, and MMR.MANEN = 0)</description>
                    <alternateRegister>SSR</alternateRegister>
                    <addressOffset>0x04</addressOffset>
                    <size>8</size>
                    <access>read-write</access>
                    <resetValue>0x80</resetValue>
                    <resetMask>0xfd</resetMask>
                    <fields>
                        <field>
                            <name>DR</name>
                            <description>Receive Data Ready Flag</description>
                            <lsb>0</lsb>
                            <msb>0</msb>
                            <access>read-write</access>
                            <enumeratedValues>
                                </enumeratedValues>
                        </field>
                        <field>
                            <name>TEND</name>
                            <description>Transmit End Flag</description>
                            <lsb>2</lsb>
                            <msb>2</msb>
                            <access>read-write</access>
                            <enumeratedValues>
                                </enumeratedValues>
                        </field>
                        <field>
                            <name>PER</name>
                            <description>Parity Error Flag</description>
                            <lsb>3</lsb>
                            <msb>3</msb>
                            <access>read-write</access>
                            <enumeratedValues>
                                </enumeratedValues>
                        </field>
                        <field>
                            <name>FER</name>
                            <description>Framing Error Flag</description>
                            <lsb>4</lsb>
                            <msb>4</msb>
                            <access>read-write</access>
                            <enumeratedValues>
                                </enumeratedValues>
                        </field>
                        <field>
                            <name>ORER</name>
                            <description>Overrun Error Flag</description>
                            <lsb>5</lsb>
                            <msb>5</msb>
                            <access>read-write</access>
                            <enumeratedValues>
                                </enumeratedValues>
                        </field>
                        <field>
                            <name>RDF</name>
                            <description>Receive FIFO Data Full Flag</description>
                            <lsb>6</lsb>
                            <msb>6</msb>
                            <access>read-write</access>
                            <enumeratedValues>
                                </enumeratedValues>
                        </field>
                        <field>
                            <name>TDFE</name>
                            <description>Transmit FIFO Data Empty Flag</description>
                            <lsb>7</lsb>
                            <msb>7</msb>
                            <access>read-write</access>
                            <enumeratedValues>
                                </enumeratedValues>
                        </field>
                    </fields>
                </register>
                <register>
                    <name>SSR_MANC</name>
                    <description>Serial Status Register for Manchester Mode (SCMR.SMIF = 0, and MMR.MANEN = 1)</description>
                    <alternateRegister>SSR</alternateRegister>
                    <addressOffset>0x04</addressOffset>
                    <size>8</size>
                    <access>read-write</access>
                    <resetValue>0x84</resetValue>
                    <resetMask>0xff</resetMask>
                    <fields>
                        <field>
                            <name>MER</name>
                            <description>Manchester Error Flag</description>
                            <lsb>0</lsb>
                            <msb>0</msb>
                            <access>read-write</access>
                            <enumeratedValues>
                                </enumeratedValues>
                        </field>
                        <field>
                            <name>MPB</name>
                            <description>Multi,Processor</description>
                            <lsb>1</lsb>
                            <msb>1</msb>
                            <access>read-only</access>
                            <enumeratedValues>
                                </enumeratedValues>
                        </field>
                        <field>
                            <name>TEND</name>
                            <description>Transmit End Flag</description>
                            <lsb>2</lsb>
                            <msb>2</msb>
                            <access>read-only</access>
                            <enumeratedValues>
                                </enumeratedValues>
                        </field>
                        <field>
                            <name>PER</name>
                            <description>Parity Error Flag</description>
                            <lsb>3</lsb>
                            <msb>3</msb>
                            <access>read-write</access>
                            <enumeratedValues>
                                </enumeratedValues>
                        </field>
                        <field>
                            <name>FER</name>
                            <description>Framing Error Flag</description>
                            <lsb>4</lsb>
                            <msb>4</msb>
                            <access>read-write</access>
                            <enumeratedValues>
                                </enumeratedValues>
                        </field>
                        <field>
                            <name>ORER</name>
                            <description>Overrun Error Flag</description>
                            <lsb>5</lsb>
                            <msb>5</msb>
                            <access>read-write</access>
                            <enumeratedValues>
                                </enumeratedValues>
                        </field>
                        <field>
                            <name>RDRF</name>
                            <description>Receive Data Full Flag</description>
                            <lsb>6</lsb>
                            <msb>6</msb>
                            <access>read-write</access>
                            <enumeratedValues>
                                </enumeratedValues>
                        </field>
                        <field>
                            <name>TDRE</name>
                            <description>Transmit Data Empty Flag</description>
                            <lsb>7</lsb>
                            <msb>7</msb>
                            <access>read-write</access>
                            <enumeratedValues>
                                </enumeratedValues>
                        </field>
                    </fields>
                </register>
                <register>
                    <name>SSR_SMCI</name>
                    <description>Serial Status Register for Smart Card Interface Mode (SCMR.SMIF = 1, and MMR.MANEN = 0)</description>
                    <alternateRegister>SSR</alternateRegister>
                    <addressOffset>0x04</addressOffset>
                    <size>8</size>
                    <access>read-write</access>
                    <resetValue>0x84</resetValue>
                    <resetMask>0xff</resetMask>
                    <fields>
                        <field>
                            <name>MPBT</name>
                            <description>Multi,Processor Bit Transfer</description>
                            <lsb>0</lsb>
                            <msb>0</msb>
                            <access>read-write</access>
                        </field>
                        <field>
                            <name>MPB</name>
                            <description>Multi,Processor</description>
                            <lsb>1</lsb>
                            <msb>1</msb>
                            <access>read-only</access>
                        </field>
                        <field>
                            <name>TEND</name>
                            <description>Transmit End Flag</description>
                            <lsb>2</lsb>
                            <msb>2</msb>
                            <access>read-only</access>
                            <enumeratedValues>
                                </enumeratedValues>
                        </field>
                        <field>
                            <name>PER</name>
                            <description>Parity Error Flag</description>
                            <lsb>3</lsb>
                            <msb>3</msb>
                            <access>read-write</access>
                            <enumeratedValues>
                                </enumeratedValues>
                        </field>
                        <field>
                            <name>ERS</name>
                            <description>Error Signal Status Flag</description>
                            <lsb>4</lsb>
                            <msb>4</msb>
                            <access>read-write</access>
                            <enumeratedValues>
                                </enumeratedValues>
                        </field>
                        <field>
                            <name>ORER</name>
                            <description>Overrun Error Flag</description>
                            <lsb>5</lsb>
                            <msb>5</msb>
                            <access>read-write</access>
                            <enumeratedValues>
                                </enumeratedValues>
                        </field>
                        <field>
                            <name>RDRF</name>
                            <description>Receive Data Full Flag</description>
                            <lsb>6</lsb>
                            <msb>6</msb>
                            <access>read-write</access>
                            <enumeratedValues>
                                </enumeratedValues>
                        </field>
                        <field>
                            <name>TDRE</name>
                            <description>Transmit Data Empty Flag</description>
                            <lsb>7</lsb>
                            <msb>7</msb>
                            <access>read-write</access>
                            <enumeratedValues>
                                </enumeratedValues>
                        </field>
                    </fields>
                </register>
                <register>
                    <name>RDR</name>
                    <description>Receive Data Register</description>
                    <addressOffset>0x05</addressOffset>
                    <size>8</size>
                    <access>read-only</access>
                    <resetValue>0x00</resetValue>
                    <resetMask>0xff</resetMask>
                </register>
                <register>
                    <name>SCMR</name>
                    <description>Smart Card Mode Register</description>
                    <addressOffset>0x06</addressOffset>
                    <size>8</size>
                    <access>read-write</access>
                    <resetValue>0xf2</resetValue>
                    <resetMask>0xff</resetMask>
                    <fields>
                        <field>
                            <name>SMIF</name>
                            <description>Smart Card Interface Mode Select</description>
                            <lsb>0</lsb>
                            <msb>0</msb>
                            <access>read-write</access>
                            <enumeratedValues>
                                </enumeratedValues>
                        </field>
                        <field>
                            <name>SINV</name>
                            <description>Transmitted/Received Data Invert</description>
                            <lsb>2</lsb>
                            <msb>2</msb>
                            <access>read-write</access>
                            <enumeratedValues>
                                </enumeratedValues>
                        </field>
                        <field>
                            <name>SDIR</name>
                            <description>Transmitted/Received Data Transfer Direction</description>
                            <lsb>3</lsb>
                            <msb>3</msb>
                            <access>read-write</access>
                            <enumeratedValues>
                                </enumeratedValues>
                        </field>
                        <field>
                            <name>CHR1</name>
                            <description>Character Length 1</description>
                            <lsb>4</lsb>
                            <msb>4</msb>
                            <access>read-write</access>
                            <enumeratedValues>
                                </enumeratedValues>
                        </field>
                        <field>
                            <name>BCP2</name>
                            <description>Base Clock Pulse 2</description>
                            <lsb>7</lsb>
                            <msb>7</msb>
                            <access>read-write</access>
                        </field>
                    </fields>
                </register>
                <register>
                    <name>SEMR</name>
                    <description>Serial Extended Mode Register</description>
                    <addressOffset>0x07</addressOffset>
                    <size>8</size>
                    <access>read-write</access>
                    <resetValue>0x00</resetValue>
                    <resetMask>0xff</resetMask>
                    <fields>
                        <field>
                            <name>ACS0</name>
                            <description>Asynchronous Mode Clock Source Select</description>
                            <lsb>0</lsb>
                            <msb>0</msb>
                            <access>read-write</access>
                            <enumeratedValues>
                                </enumeratedValues>
                        </field>
                        <field>
                            <name>PADIS</name>
                            <description>Preamble function Disable</description>
                            <lsb>1</lsb>
                            <msb>1</msb>
                            <access>read-write</access>
                            <enumeratedValues>
                                </enumeratedValues>
                        </field>
                        <field>
                            <name>BRME</name>
                            <description>Bit Rate Modulation Enable</description>
                            <lsb>2</lsb>
                            <msb>2</msb>
                            <access>read-write</access>
                            <enumeratedValues>
                                </enumeratedValues>
                        </field>
                        <field>
                            <name>ABCSE</name>
                            <description>Asynchronous Mode Extended Base Clock Select 1</description>
                            <lsb>3</lsb>
                            <msb>3</msb>
                            <access>read-write</access>
                            <enumeratedValues>
                                </enumeratedValues>
                        </field>
                        <field>
                            <name>ABCS</name>
                            <description>Asynchronous Mode Base Clock Select</description>
                            <lsb>4</lsb>
                            <msb>4</msb>
                            <access>read-write</access>
                            <enumeratedValues>
                                </enumeratedValues>
                        </field>
                        <field>
                            <name>NFEN</name>
                            <description>Digital Noise Filter Function Enable</description>
                            <lsb>5</lsb>
                            <msb>5</msb>
                            <access>read-write</access>
                            <enumeratedValues>
                                </enumeratedValues>
                        </field>
                        <field>
                            <name>BGDM</name>
                            <description>Baud Rate Generator Double,Speed Mode Select</description>
                            <lsb>6</lsb>
                            <msb>6</msb>
                            <access>read-write</access>
                            <enumeratedValues>
                                </enumeratedValues>
                        </field>
                        <field>
                            <name>RXDESEL</name>
                            <description>Asynchronous Start Bit Edge Detection Select</description>
                            <lsb>7</lsb>
                            <msb>7</msb>
                            <access>read-write</access>
                            <enumeratedValues>
                                </enumeratedValues>
                        </field>
                    </fields>
                </register>
                <register>
                    <name>SNFR</name>
                    <description>Noise Filter Setting Register</description>
                    <addressOffset>0x08</addressOffset>
                    <size>8</size>
                    <access>read-write</access>
                    <resetValue>0x00</resetValue>
                    <resetMask>0xff</resetMask>
                    <fields>
                        <field>
                            <name>NFCS</name>
                            <description>Noise Filter Clock Select</description>
                            <lsb>0</lsb>
                            <msb>2</msb>
                            <access>read-write</access>
                            <enumeratedValues>
                                </enumeratedValues>
                        </field>
                    </fields>
                </register>
                <register>
                    <name>SIMR1</name>
                    <description>IIC Mode Register 1</description>
                    <addressOffset>0x09</addressOffset>
                    <size>8</size>
                    <access>read-write</access>
                    <resetValue>0x00</resetValue>
                    <resetMask>0xff</resetMask>
                    <fields>
                        <field>
                            <name>IICM</name>
                            <description>Simple IIC Mode Select</description>
                            <lsb>0</lsb>
                            <msb>0</msb>
                            <access>read-write</access>
                            <enumeratedValues>
                                </enumeratedValues>
                        </field>
                        <field>
                            <name>IICDL</name>
                            <description>SDAn Delay Output Select</description>
                            <lsb>3</lsb>
                            <msb>7</msb>
                            <access>read-write</access>
                            <enumeratedValues>
                                </enumeratedValues>
                        </field>
                    </fields>
                </register>
                <register>
                    <name>SIMR2</name>
                    <description>IIC Mode Register 2</description>
                    <addressOffset>0x0A</addressOffset>
                    <size>8</size>
                    <access>read-write</access>
                    <resetValue>0x00</resetValue>
                    <resetMask>0xff</resetMask>
                    <fields>
                        <field>
                            <name>IICINTM</name>
                            <description>IIC Interrupt Mode Select</description>
                            <lsb>0</lsb>
                            <msb>0</msb>
                            <access>read-write</access>
                            <enumeratedValues>
                                </enumeratedValues>
                        </field>
                        <field>
                            <name>IICCSC</name>
                            <description>Clock Synchronization</description>
                            <lsb>1</lsb>
                            <msb>1</msb>
                            <access>read-write</access>
                            <enumeratedValues>
                                </enumeratedValues>
                        </field>
                        <field>
                            <name>IICACKT</name>
                            <description>ACK Transmission Data</description>
                            <lsb>5</lsb>
                            <msb>5</msb>
                            <access>read-write</access>
                            <enumeratedValues>
                                </enumeratedValues>
                        </field>
                    </fields>
                </register>
                <register>
                    <name>SIMR3</name>
                    <description>IIC Mode Register 3</description>
                    <addressOffset>0x0B</addressOffset>
                    <size>8</size>
                    <access>read-write</access>
                    <resetValue>0x00</resetValue>
                    <resetMask>0xff</resetMask>
                    <fields>
                        <field>
                            <name>IICSTAREQ</name>
                            <description>Start Condition Generation</description>
                            <lsb>0</lsb>
                            <msb>0</msb>
                            <access>read-write</access>
                            <enumeratedValues>
                                </enumeratedValues>
                        </field>
                        <field>
                            <name>IICRSTAREQ</name>
                            <description>Restart Condition Generation</description>
                            <lsb>1</lsb>
                            <msb>1</msb>
                            <access>read-write</access>
                            <enumeratedValues>
                                </enumeratedValues>
                        </field>
                        <field>
                            <name>IICSTPREQ</name>
                            <description>Stop Condition Generation</description>
                            <lsb>2</lsb>
                            <msb>2</msb>
                            <access>read-write</access>
                            <enumeratedValues>
                                </enumeratedValues>
                        </field>
                        <field>
                            <name>IICSTIF</name>
                            <description>Issuing of Start, Restart, or Stop Condition Completed Flag</description>
                            <lsb>3</lsb>
                            <msb>3</msb>
                            <access>read-write</access>
                            <enumeratedValues>
                                </enumeratedValues>
                        </field>
                        <field>
                            <name>IICSDAS</name>
                            <description>SDAn Output Select</description>
                            <lsb>4</lsb>
                            <msb>5</msb>
                            <access>read-write</access>
                            <enumeratedValues>
                                </enumeratedValues>
                        </field>
                        <field>
                            <name>IICSCLS</name>
                            <description>SCLn Output Select</description>
                            <lsb>6</lsb>
                            <msb>7</msb>
                            <access>read-write</access>
                            <enumeratedValues>
                                </enumeratedValues>
                        </field>
                    </fields>
                </register>
                <register>
                    <name>SISR</name>
                    <description>IIC Status Register</description>
                    <addressOffset>0x0C</addressOffset>
                    <size>8</size>
                    <access>read-only</access>
                    <resetValue>0x00</resetValue>
                    <resetMask>0xcb</resetMask>
                    <fields>
                        <field>
                            <name>IICACKR</name>
                            <description>ACK Reception Data Flag</description>
                            <lsb>0</lsb>
                            <msb>0</msb>
                            <access>read-only</access>
                            <enumeratedValues>
                                </enumeratedValues>
                        </field>
                    </fields>
                </register>
                <register>
                    <name>SPMR</name>
                    <description>SPI Mode Register</description>
                    <addressOffset>0x0D</addressOffset>
                    <size>8</size>
                    <access>read-write</access>
                    <resetValue>0x00</resetValue>
                    <resetMask>0xff</resetMask>
                    <fields>
                        <field>
                            <name>SSE</name>
                            <description>SSn Pin Function Enable</description>
                            <lsb>0</lsb>
                            <msb>0</msb>
                            <access>read-write</access>
                            <enumeratedValues>
                                </enumeratedValues>
                        </field>
                        <field>
                            <name>CTSE</name>
                            <description>CTS Enable</description>
                            <lsb>1</lsb>
                            <msb>1</msb>
                            <access>read-write</access>
                            <enumeratedValues>
                                </enumeratedValues>
                        </field>
                        <field>
                            <name>MSS</name>
                            <description>Master Slave Select</description>
                            <lsb>2</lsb>
                            <msb>2</msb>
                            <access>read-write</access>
                            <enumeratedValues>
                                </enumeratedValues>
                        </field>
                        <field>
                            <name>CTSPEN</name>
                            <description>CTS external pin Enable</description>
                            <lsb>3</lsb>
                            <msb>3</msb>
                            <access>read-write</access>
                            <enumeratedValues>
                                </enumeratedValues>
                        </field>
                        <field>
                            <name>MFF</name>
                            <description>Mode Fault Flag</description>
                            <lsb>4</lsb>
                            <msb>4</msb>
                            <access>read-write</access>
                            <enumeratedValues>
                                </enumeratedValues>
                        </field>
                        <field>
                            <name>CKPOL</name>
                            <description>Clock Polarity Select</description>
                            <lsb>6</lsb>
                            <msb>6</msb>
                            <access>read-write</access>
                            <enumeratedValues>
                                </enumeratedValues>
                        </field>
                        <field>
                            <name>CKPH</name>
                            <description>Clock Phase Select</description>
                            <lsb>7</lsb>
                            <msb>7</msb>
                            <access>read-write</access>
                            <enumeratedValues>
                                </enumeratedValues>
                        </field>
                    </fields>
                </register>
                <register>
                    <name>FTDRHL</name>
                    <description>Transmit FIFO Data Register</description>
                    <addressOffset>0x0E</addressOffset>
                    <size>16</size>
                    <access>write-only</access>
                    <resetValue>0xffff</resetValue>
                    <resetMask>0xffff</resetMask>
                    <fields>
                        <field>
                            <name>TDAT</name>
                            <description>Serial transmit data</description>
                            <lsb>0</lsb>
                            <msb>8</msb>
                            <access>write-only</access>
                        </field>
                        <field>
                            <name>MPBT</name>
                            <description>Multi,Processor Transfer Bit Flag</description>
                            <lsb>9</lsb>
                            <msb>9</msb>
                            <access>write-only</access>
                            <enumeratedValues>
                                </enumeratedValues>
                        </field>
                    </fields>
                </register>
                <register>
                    <name>TDRHL</name>
                    <description>Transmit Data Register for Non,Manchester mode (MMR.MANEN = 0)</description>
                    <alternateRegister>FTDRHL</alternateRegister>
                    <addressOffset>0x0E</addressOffset>
                    <size>16</size>
                    <access>read-write</access>
                    <resetValue>0xffff</resetValue>
                    <resetMask>0xffff</resetMask>
                    <fields>
                        <field>
                            <name>TDAT</name>
                            <description>Serial Transmit Data</description>
                            <lsb>0</lsb>
                            <msb>8</msb>
                            <access>read-write</access>
                        </field>
                    </fields>
                </register>
                <register>
                    <name>TDRHL_MAN</name>
                    <description>Transmit Data Register for Manchester mode (MMR.MANEN = 1)</description>
                    <alternateRegister>FTDRHL</alternateRegister>
                    <addressOffset>0x0E</addressOffset>
                    <size>16</size>
                    <access>read-write</access>
                    <resetValue>0xffff</resetValue>
                    <resetMask>0xffff</resetMask>
                    <fields>
                        <field>
                            <name>TDAT</name>
                            <description>Serial transmit data</description>
                            <lsb>0</lsb>
                            <msb>8</msb>
                            <access>read-write</access>
                        </field>
                        <field>
                            <name>MPBT</name>
                            <description>Multi,processor transfer bit flag</description>
                            <lsb>9</lsb>
                            <msb>9</msb>
                            <access>read-write</access>
                            <enumeratedValues>
                                </enumeratedValues>
                        </field>
                        <field>
                            <name>TSYNC</name>
                            <description>Transmit SYNC data bit</description>
                            <lsb>12</lsb>
                            <msb>12</msb>
                            <access>read-write</access>
                            <enumeratedValues>
                                </enumeratedValues>
                        </field>
                    </fields>
                </register>
                <register>
                    <name>FTDRH</name>
                    <description>Transmit FIFO Data Register</description>
                    <alternateRegister>FTDRHL</alternateRegister>
                    <addressOffset>0x0E</addressOffset>
                    <size>8</size>
                    <access>write-only</access>
                    <resetValue>0xff</resetValue>
                    <resetMask>0xff</resetMask>
                    <fields>
                        <field>
                            <name>MPBT</name>
                            <description>Multi,Processor Transfer Bit Flag</description>
                            <lsb>1</lsb>
                            <msb>1</msb>
                            <access>write-only</access>
                            <enumeratedValues>
                                </enumeratedValues>
                        </field>
                    </fields>
                </register>
                <register>
                    <name>FTDRL</name>
                    <description>Transmit FIFO Data Register</description>
                    <alternateRegister>FTDRHL</alternateRegister>
                    <addressOffset>0x0F</addressOffset>
                    <size>8</size>
                    <access>write-only</access>
                    <resetValue>0xff</resetValue>
                    <resetMask>0xff</resetMask>
                    <fields>
                        <field>
                            <name>TDAT</name>
                            <description>Serial transmit data</description>
                            <lsb>0</lsb>
                            <msb>7</msb>
                            <access>write-only</access>
                        </field>
                    </fields>
                </register>
                <register>
                    <name>FRDRHL</name>
                    <description>Receive FIFO Data Register</description>
                    <addressOffset>0x10</addressOffset>
                    <size>16</size>
                    <access>read-only</access>
                    <resetValue>0x0000</resetValue>
                    <resetMask>0xffff</resetMask>
                    <fields>
                        <field>
                            <name>RDAT</name>
                            <description>Serial receive data</description>
                            <lsb>0</lsb>
                            <msb>8</msb>
                            <access>read-only</access>
                        </field>
                        <field>
                            <name>MPB</name>
                            <description>Multi,Processor Bit Flag</description>
                            <lsb>9</lsb>
                            <msb>9</msb>
                            <access>read-only</access>
                            <enumeratedValues>
                                </enumeratedValues>
                        </field>
                        <field>
                            <name>DR</name>
                            <description>Receive Data Ready Flag</description>
                            <lsb>10</lsb>
                            <msb>10</msb>
                            <access>read-only</access>
                            <enumeratedValues>
                                </enumeratedValues>
                        </field>
                        <field>
                            <name>PER</name>
                            <description>Parity Error Flag</description>
                            <lsb>11</lsb>
                            <msb>11</msb>
                            <access>read-only</access>
                            <enumeratedValues>
                                </enumeratedValues>
                        </field>
                        <field>
                            <name>FER</name>
                            <description>Framing Error Flag</description>
                            <lsb>12</lsb>
                            <msb>12</msb>
                            <access>read-only</access>
                            <enumeratedValues>
                                </enumeratedValues>
                        </field>
                        <field>
                            <name>ORER</name>
                            <description>Overrun Error Flag</description>
                            <lsb>13</lsb>
                            <msb>13</msb>
                            <access>read-only</access>
                            <enumeratedValues>
                                </enumeratedValues>
                        </field>
                        <field>
                            <name>RDF</name>
                            <description>Receive FIFO Data Full Flag</description>
                            <lsb>14</lsb>
                            <msb>14</msb>
                            <access>read-only</access>
                            <enumeratedValues>
                                </enumeratedValues>
                        </field>
                    </fields>
                </register>
                <register>
                    <name>RDRHL</name>
                    <description>Receive Data Register for Non,Manchester mode (MMR.MANEN = 0)</description>
                    <alternateRegister>FRDRHL</alternateRegister>
                    <addressOffset>0x10</addressOffset>
                    <size>16</size>
                    <access>read-only</access>
                    <resetValue>0x0000</resetValue>
                    <resetMask>0xffff</resetMask>
                    <fields>
                        <field>
                            <name>RDAT</name>
                            <description>Serial Receive Data</description>
                            <lsb>0</lsb>
                            <msb>8</msb>
                            <access>read-only</access>
                        </field>
                    </fields>
                </register>
                <register>
                    <name>RDRHL_MAN</name>
                    <description>Receive Data Register for Manchester mode (MMR.MANEN = 1)</description>
                    <alternateRegister>FRDRHL</alternateRegister>
                    <addressOffset>0x10</addressOffset>
                    <size>16</size>
                    <access>read-only</access>
                    <resetValue>0x0000</resetValue>
                    <resetMask>0xffff</resetMask>
                    <fields>
                        <field>
                            <name>RDAT</name>
                            <description>Serial receive data</description>
                            <lsb>0</lsb>
                            <msb>8</msb>
                            <access>read-only</access>
                        </field>
                        <field>
                            <name>MPB</name>
                            <description>Multi,processor bit</description>
                            <lsb>9</lsb>
                            <msb>9</msb>
                            <access>read-only</access>
                            <enumeratedValues>
                                </enumeratedValues>
                        </field>
                        <field>
                            <name>RSYNC</name>
                            <description>Receive SYNC data bit</description>
                            <lsb>12</lsb>
                            <msb>12</msb>
                            <access>read-only</access>
                            <enumeratedValues>
                                </enumeratedValues>
                        </field>
                    </fields>
                </register>
                <register>
                    <name>FRDRH</name>
                    <description>Receive FIFO Data Register</description>
                    <alternateRegister>FRDRHL</alternateRegister>
                    <addressOffset>0x10</addressOffset>
                    <size>8</size>
                    <access>read-only</access>
                    <resetValue>0x00</resetValue>
                    <resetMask>0xff</resetMask>
                    <fields>
                        <field>
                            <name>MPB</name>
                            <description>Multi,Processor Bit Flag</description>
                            <lsb>1</lsb>
                            <msb>1</msb>
                            <access>read-only</access>
                            <enumeratedValues>
                                </enumeratedValues>
                        </field>
                        <field>
                            <name>DR</name>
                            <description>Receive Data Ready Flag</description>
                            <lsb>2</lsb>
                            <msb>2</msb>
                            <access>read-only</access>
                            <enumeratedValues>
                                </enumeratedValues>
                        </field>
                        <field>
                            <name>PER</name>
                            <description>Parity Error Flag</description>
                            <lsb>3</lsb>
                            <msb>3</msb>
                            <access>read-only</access>
                            <enumeratedValues>
                                </enumeratedValues>
                        </field>
                        <field>
                            <name>FER</name>
                            <description>Framing Error Flag</description>
                            <lsb>4</lsb>
                            <msb>4</msb>
                            <access>read-only</access>
                            <enumeratedValues>
                                </enumeratedValues>
                        </field>
                        <field>
                            <name>ORER</name>
                            <description>Overrun Error Flag</description>
                            <lsb>5</lsb>
                            <msb>5</msb>
                            <access>read-only</access>
                            <enumeratedValues>
                                </enumeratedValues>
                        </field>
                        <field>
                            <name>RDF</name>
                            <description>Receive FIFO Data Full Flag</description>
                            <lsb>6</lsb>
                            <msb>6</msb>
                            <access>read-only</access>
                            <enumeratedValues>
                                </enumeratedValues>
                        </field>
                    </fields>
                </register>
                <register>
                    <name>FRDRL</name>
                    <description>Receive FIFO Data Register</description>
                    <alternateRegister>FRDRHL</alternateRegister>
                    <addressOffset>0x11</addressOffset>
                    <size>8</size>
                    <access>read-only</access>
                    <resetValue>0x00</resetValue>
                    <resetMask>0xff</resetMask>
                    <fields>
                        <field>
                            <name>RDAT</name>
                            <description>Serial receive data</description>
                            <lsb>0</lsb>
                            <msb>7</msb>
                            <access>read-only</access>
                        </field>
                    </fields>
                </register>
                <register>
                    <name>MDDR</name>
                    <description>Modulation Duty Register</description>
                    <addressOffset>0x12</addressOffset>
                    <size>8</size>
                    <access>read-write</access>
                    <resetValue>0xff</resetValue>
                    <resetMask>0xff</resetMask>
                </register>
                <register>
                    <name>DCCR</name>
                    <description>Data Compare Match Control Register</description>
                    <addressOffset>0x13</addressOffset>
                    <size>8</size>
                    <access>read-write</access>
                    <resetValue>0x40</resetValue>
                    <resetMask>0xff</resetMask>
                    <fields>
                        <field>
                            <name>DCMF</name>
                            <description>Data Compare Match Flag</description>
                            <lsb>0</lsb>
                            <msb>0</msb>
                            <access>read-write</access>
                            <enumeratedValues>
                                </enumeratedValues>
                        </field>
                        <field>
                            <name>DPER</name>
                            <description>Data Compare Match Parity Error Flag</description>
                            <lsb>3</lsb>
                            <msb>3</msb>
                            <access>read-write</access>
                            <enumeratedValues>
                                </enumeratedValues>
                        </field>
                        <field>
                            <name>DFER</name>
                            <description>Data Compare Match Framing Error Flag</description>
                            <lsb>4</lsb>
                            <msb>4</msb>
                            <access>read-write</access>
                            <enumeratedValues>
                                </enumeratedValues>
                        </field>
                        <field>
                            <name>IDSEL</name>
                            <description>ID Frame Select</description>
                            <lsb>6</lsb>
                            <msb>6</msb>
                            <access>read-write</access>
                            <enumeratedValues>
                                </enumeratedValues>
                        </field>
                        <field>
                            <name>DCME</name>
                            <description>Data Compare Match Enable</description>
                            <lsb>7</lsb>
                            <msb>7</msb>
                            <access>read-write</access>
                            <enumeratedValues>
                                </enumeratedValues>
                        </field>
                    </fields>
                </register>
                <register>
                    <name>FCR</name>
                    <description>FIFO Control Register</description>
                    <addressOffset>0x14</addressOffset>
                    <size>16</size>
                    <access>read-write</access>
                    <resetValue>0xf800</resetValue>
                    <resetMask>0xffff</resetMask>
                    <fields>
                        <field>
                            <name>FM</name>
                            <description>FIFO Mode Select</description>
                            <lsb>0</lsb>
                            <msb>0</msb>
                            <access>read-write</access>
                            <enumeratedValues>
                                </enumeratedValues>
                        </field>
                        <field>
                            <name>RFRST</name>
                            <description>Receive FIFO Data Register Reset</description>
                            <lsb>1</lsb>
                            <msb>1</msb>
                            <access>read-write</access>
                            <enumeratedValues>
                                </enumeratedValues>
                        </field>
                        <field>
                            <name>TFRST</name>
                            <description>Transmit FIFO Data Register Reset</description>
                            <lsb>2</lsb>
                            <msb>2</msb>
                            <access>read-write</access>
                            <enumeratedValues>
                                </enumeratedValues>
                        </field>
                        <field>
                            <name>DRES</name>
                            <description>Receive Data Ready Error Select</description>
                            <lsb>3</lsb>
                            <msb>3</msb>
                            <access>read-write</access>
                            <enumeratedValues>
                                </enumeratedValues>
                        </field>
                        <field>
                            <name>TTRG</name>
                            <description>Transmit FIFO Data Trigger Number</description>
                            <lsb>4</lsb>
                            <msb>7</msb>
                            <access>read-write</access>
                        </field>
                        <field>
                            <name>RTRG</name>
                            <description>Receive FIFO Data Trigger Number</description>
                            <lsb>8</lsb>
                            <msb>11</msb>
                            <access>read-write</access>
                        </field>
                        <field>
                            <name>RSTRG</name>
                            <description>RTS Output Active Trigger Number Select</description>
                            <lsb>12</lsb>
                            <msb>15</msb>
                            <access>read-write</access>
                        </field>
                    </fields>
                </register>
                <register>
                    <name>FDR</name>
                    <description>FIFO Data Count Register</description>
                    <addressOffset>0x16</addressOffset>
                    <size>16</size>
                    <access>read-only</access>
                    <resetValue>0x0000</resetValue>
                    <resetMask>0xffff</resetMask>
                    <fields>
                        <field>
                            <name>R</name>
                            <description>Receive FIFO Data Count</description>
                            <lsb>0</lsb>
                            <msb>4</msb>
                            <access>read-only</access>
                        </field>
                        <field>
                            <name>T</name>
                            <description>Transmit FIFO Data Count</description>
                            <lsb>8</lsb>
                            <msb>12</msb>
                            <access>read-only</access>
                        </field>
                    </fields>
                </register>
                <register>
                    <name>LSR</name>
                    <description>Line Status Register</description>
                    <addressOffset>0x18</addressOffset>
                    <size>16</size>
                    <access>read-only</access>
                    <resetValue>0x0000</resetValue>
                    <resetMask>0xffff</resetMask>
                    <fields>
                        <field>
                            <name>ORER</name>
                            <description>Overrun Error Flag</description>
                            <lsb>0</lsb>
                            <msb>0</msb>
                            <access>read-only</access>
                            <enumeratedValues>
                                </enumeratedValues>
                        </field>
                        <field>
                            <name>FNUM</name>
                            <description>Framing Error Count</description>
                            <lsb>2</lsb>
                            <msb>6</msb>
                            <access>read-only</access>
                        </field>
                        <field>
                            <name>PNUM</name>
                            <description>Parity Error Count</description>
                            <lsb>8</lsb>
                            <msb>12</msb>
                            <access>read-only</access>
                        </field>
                    </fields>
                </register>
                <register>
                    <name>CDR</name>
                    <description>Compare Match Data Register</description>
                    <addressOffset>0x1A</addressOffset>
                    <size>16</size>
                    <access>read-write</access>
                    <resetValue>0x0000</resetValue>
                    <resetMask>0xffff</resetMask>
                    <fields>
                        <field>
                            <name>CMPD</name>
                            <description>Compare Match Data</description>
                            <lsb>0</lsb>
                            <msb>8</msb>
                            <access>read-write</access>
                        </field>
                    </fields>
                </register>
                <register>
                    <name>SPTR</name>
                    <description>Serial Port Register</description>
                    <addressOffset>0x1C</addressOffset>
                    <size>8</size>
                    <access>read-write</access>
                    <resetValue>0x03</resetValue>
                    <resetMask>0xff</resetMask>
                    <fields>
                        <field>
                            <name>RXDMON</name>
                            <description>Serial Input Data Monitor</description>
                            <lsb>0</lsb>
                            <msb>0</msb>
                            <access>read-only</access>
                        </field>
                        <field>
                            <name>SPB2DT</name>
                            <description>Serial Port Break Data Select</description>
                            <lsb>1</lsb>
                            <msb>1</msb>
                            <access>read-write</access>
                        </field>
                        <field>
                            <name>SPB2IO</name>
                            <description>Serial Port Break I/O</description>
                            <lsb>2</lsb>
                            <msb>2</msb>
                            <access>read-write</access>
                            <enumeratedValues>
                                </enumeratedValues>
                        </field>
                        <field>
                            <name>RINV</name>
                            <description>RXD invert bit</description>
                            <lsb>4</lsb>
                            <msb>4</msb>
                            <access>read-write</access>
                            <enumeratedValues>
                                </enumeratedValues>
                        </field>
                        <field>
                            <name>TINV</name>
                            <description>TXD invert bit</description>
                            <lsb>5</lsb>
                            <msb>5</msb>
                            <access>read-write</access>
                            <enumeratedValues>
                                </enumeratedValues>
                        </field>
                        <field>
                            <name>ASEN</name>
                            <description>Adjust receive sampling timing enable</description>
                            <lsb>6</lsb>
                            <msb>6</msb>
                            <access>read-write</access>
                            <enumeratedValues>
                                </enumeratedValues>
                        </field>
                        <field>
                            <name>ATEN</name>
                            <description>Adjust transmit timing enable</description>
                            <lsb>7</lsb>
                            <msb>7</msb>
                            <access>read-write</access>
                            <enumeratedValues>
                                </enumeratedValues>
                        </field>
                    </fields>
                </register>
                <register>
                    <name>ACTR</name>
                    <description>Adjustment Communication Timing Register</description>
                    <addressOffset>0x1D</addressOffset>
                    <size>8</size>
                    <access>read-write</access>
                    <resetValue>0x00</resetValue>
                    <resetMask>0xff</resetMask>
                    <fields>
                        <field>
                            <name>AST</name>
                            <description>Adjustment value for receive Sampling Timing</description>
                            <lsb>0</lsb>
                            <msb>2</msb>
                            <access>read-write</access>
                        </field>
                        <field>
                            <name>AJD</name>
                            <description>Adjustment Direction for receive sampling timing</description>
                            <lsb>3</lsb>
                            <msb>3</msb>
                            <access>read-write</access>
                            <enumeratedValues>
                                </enumeratedValues>
                        </field>
                        <field>
                            <name>ATT</name>
                            <description>Adjustment value for Transmit timing</description>
                            <lsb>4</lsb>
                            <msb>6</msb>
                            <access>read-write</access>
                        </field>
                        <field>
                            <name>AET</name>
                            <description>Adjustment edge for transmit timing</description>
                            <lsb>7</lsb>
                            <msb>7</msb>
                            <access>read-write</access>
                            <enumeratedValues>
                                </enumeratedValues>
                        </field>
                    </fields>
                </register>
                <register>
                    <name>MMR</name>
                    <description>Manchester Mode Register</description>
                    <addressOffset>0x20</addressOffset>
                    <size>8</size>
                    <access>read-write</access>
                    <resetValue>0x00</resetValue>
                    <resetMask>0xff</resetMask>
                    <fields>
                        <field>
                            <name>RMPOL</name>
                            <description>Polarity of Received Manchester Code</description>
                            <lsb>0</lsb>
                            <msb>0</msb>
                            <access>read-write</access>
                            <enumeratedValues>
                                </enumeratedValues>
                        </field>
                        <field>
                            <name>TMPOL</name>
                            <description>Polarity of Transmit Manchester Code</description>
                            <lsb>1</lsb>
                            <msb>1</msb>
                            <access>read-write</access>
                            <enumeratedValues>
                                </enumeratedValues>
                        </field>
                        <field>
                            <name>ERTEN</name>
                            <description>Manchester Edge Retiming Enable</description>
                            <lsb>2</lsb>
                            <msb>2</msb>
                            <access>read-write</access>
                            <enumeratedValues>
                                </enumeratedValues>
                        </field>
                        <field>
                            <name>SYNVAL</name>
                            <description>SYNC value Setting</description>
                            <lsb>4</lsb>
                            <msb>4</msb>
                            <access>read-write</access>
                            <enumeratedValues>
                                </enumeratedValues>
                        </field>
                        <field>
                            <name>SYNSEL</name>
                            <description>SYNC Select</description>
                            <lsb>5</lsb>
                            <msb>5</msb>
                            <access>read-write</access>
                            <enumeratedValues>
                                </enumeratedValues>
                        </field>
                        <field>
                            <name>SBSEL</name>
                            <description>Start Bit Select</description>
                            <lsb>6</lsb>
                            <msb>6</msb>
                            <access>read-write</access>
                            <enumeratedValues>
                                </enumeratedValues>
                        </field>
                        <field>
                            <name>MANEN</name>
                            <description>Manchester Mode Enable</description>
                            <lsb>7</lsb>
                            <msb>7</msb>
                            <access>read-write</access>
                            <enumeratedValues>
                                </enumeratedValues>
                        </field>
                    </fields>
                </register>
                <register>
                    <name>TMPR</name>
                    <description>Transmit Manchester Preface Setting Register</description>
                    <addressOffset>0x22</addressOffset>
                    <size>8</size>
                    <access>read-write</access>
                    <resetValue>0x00</resetValue>
                    <resetMask>0xff</resetMask>
                    <fields>
                        <field>
                            <name>TPLEN</name>
                            <description>Transmit preface length</description>
                            <lsb>0</lsb>
                            <msb>3</msb>
                            <access>read-write</access>
                            <enumeratedValues>
                                </enumeratedValues>
                        </field>
                        <field>
                            <name>TPPAT</name>
                            <description>Transmit preface pattern</description>
                            <lsb>4</lsb>
                            <msb>5</msb>
                            <access>read-write</access>
                            <enumeratedValues>
                                </enumeratedValues>
                        </field>
                    </fields>
                </register>
                <register>
                    <name>RMPR</name>
                    <description>Receive Manchester Preface Setting Register</description>
                    <addressOffset>0x23</addressOffset>
                    <size>8</size>
                    <access>read-write</access>
                    <resetValue>0x00</resetValue>
                    <resetMask>0xff</resetMask>
                    <fields>
                        <field>
                            <name>RPLEN</name>
                            <description>Receive Preface Length</description>
                            <lsb>0</lsb>
                            <msb>3</msb>
                            <access>read-write</access>
                            <enumeratedValues>
                                </enumeratedValues>
                        </field>
                        <field>
                            <name>RPPAT</name>
                            <description>Receive Preface Pattern</description>
                            <lsb>4</lsb>
                            <msb>5</msb>
                            <access>read-write</access>
                            <enumeratedValues>
                                </enumeratedValues>
                        </field>
                    </fields>
                </register>
                <register>
                    <name>MESR</name>
                    <description>Manchester Extended Error Status Register</description>
                    <addressOffset>0x24</addressOffset>
                    <size>8</size>
                    <access>read-write</access>
                    <resetValue>0x00</resetValue>
                    <resetMask>0xff</resetMask>
                    <fields>
                        <field>
                            <name>PFER</name>
                            <description>Preface Error flag</description>
                            <lsb>0</lsb>
                            <msb>0</msb>
                            <access>read-write</access>
                            <enumeratedValues>
                                </enumeratedValues>
                        </field>
                        <field>
                            <name>SYER</name>
                            <description>SYNC Error flag</description>
                            <lsb>1</lsb>
                            <msb>1</msb>
                            <access>read-write</access>
                            <enumeratedValues>
                                </enumeratedValues>
                        </field>
                        <field>
                            <name>SBER</name>
                            <description>Start Bit Error flag</description>
                            <lsb>2</lsb>
                            <msb>2</msb>
                            <access>read-write</access>
                            <enumeratedValues>
                                </enumeratedValues>
                        </field>
                    </fields>
                </register>
                <register>
                    <name>MECR</name>
                    <description>Manchester Extended Error Control Register</description>
                    <addressOffset>0x25</addressOffset>
                    <size>8</size>
                    <access>read-write</access>
                    <resetValue>0x00</resetValue>
                    <resetMask>0xff</resetMask>
                    <fields>
                        <field>
                            <name>PFEREN</name>
                            <description>Preface Error Enable</description>
                            <lsb>0</lsb>
                            <msb>0</msb>
                            <access>read-write</access>
                            <enumeratedValues>
                                </enumeratedValues>
                        </field>
                        <field>
                            <name>SYEREN</name>
                            <description>Receive SYNC Error Enable</description>
                            <lsb>1</lsb>
                            <msb>1</msb>
                            <access>read-write</access>
                            <enumeratedValues>
                                </enumeratedValues>
                        </field>
                        <field>
                            <name>SBEREN</name>
                            <description>Start Bit Error Enable</description>
                            <lsb>2</lsb>
                            <msb>2</msb>
                            <access>read-write</access>
                            <enumeratedValues>
                                </enumeratedValues>
                        </field>
                    </fields>
                </register>
            </registers>
        </peripheral>
        <peripheral derivedFrom="SCI3">
            <name>SCI4</name>
            <description>Serial Communication Interface</description>
            <baseAddress>0x40118400</baseAddress>
        </peripheral>
        <peripheral derivedFrom="SCI0">
            <name>SCI5</name>
            <description>Serial Communication Interface</description>
            <baseAddress>0x40118500</baseAddress>
        </peripheral>
        <peripheral derivedFrom="SCI0">
            <name>SCI6</name>
            <description>Serial Communication Interface</description>
            <baseAddress>0x40118600</baseAddress>
        </peripheral>
        <peripheral derivedFrom="SCI0">
            <name>SCI7</name>
            <description>Serial Communication Interface</description>
            <baseAddress>0x40118700</baseAddress>
        </peripheral>
        <peripheral derivedFrom="SCI0">
            <name>SCI8</name>
            <description>Serial Communication Interface</description>
            <baseAddress>0x40118800</baseAddress>
        </peripheral>
        <peripheral derivedFrom="SCI0">
            <name>SCI9</name>
            <description>Serial Communication Interface</description>
            <baseAddress>0x40118900</baseAddress>
        </peripheral>
        <peripheral>
            <name>SPI0</name>
            <description>Serial Peripheral Interface 0</description>
            <baseAddress>0x4011A000</baseAddress>
            <addressBlock>
                <offset>0x00</offset>
                <size>8</size>
                <usage>registers</usage>
            </addressBlock>
            <addressBlock>
                <offset>0x08</offset>
                <size>26</size>
                <usage>registers</usage>
            </addressBlock>
            <registers>
                <register>
                    <name>SPCR</name>
                    <description>SPI Control Register</description>
                    <addressOffset>0x00</addressOffset>
                    <size>8</size>
                    <access>read-write</access>
                    <resetValue>0x00</resetValue>
                    <resetMask>0xff</resetMask>
                    <fields>
                        <field>
                            <name>SPMS</name>
                            <description>SPI Mode Select</description>
                            <lsb>0</lsb>
                            <msb>0</msb>
                            <access>read-write</access>
                            <enumeratedValues>
                                </enumeratedValues>
                        </field>
                        <field>
                            <name>TXMD</name>
                            <description>Communications Operating Mode Select</description>
                            <lsb>1</lsb>
                            <msb>1</msb>
                            <access>read-write</access>
                            <enumeratedValues>
                                </enumeratedValues>
                        </field>
                        <field>
                            <name>MODFEN</name>
                            <description>Mode Fault Error Detection Enable</description>
                            <lsb>2</lsb>
                            <msb>2</msb>
                            <access>read-write</access>
                            <enumeratedValues>
                                </enumeratedValues>
                        </field>
                        <field>
                            <name>MSTR</name>
                            <description>SPI Master/Slave Mode Select</description>
                            <lsb>3</lsb>
                            <msb>3</msb>
                            <access>read-write</access>
                            <enumeratedValues>
                                </enumeratedValues>
                        </field>
                        <field>
                            <name>SPEIE</name>
                            <description>SPI Error Interrupt Enable</description>
                            <lsb>4</lsb>
                            <msb>4</msb>
                            <access>read-write</access>
                            <enumeratedValues>
                                </enumeratedValues>
                        </field>
                        <field>
                            <name>SPTIE</name>
                            <description>Transmit Buffer Empty Interrupt Enable</description>
                            <lsb>5</lsb>
                            <msb>5</msb>
                            <access>read-write</access>
                            <enumeratedValues>
                                </enumeratedValues>
                        </field>
                        <field>
                            <name>SPE</name>
                            <description>SPI Function Enable</description>
                            <lsb>6</lsb>
                            <msb>6</msb>
                            <access>read-write</access>
                            <enumeratedValues>
                                </enumeratedValues>
                        </field>
                        <field>
                            <name>SPRIE</name>
                            <description>SPI Receive Buffer Full Interrupt Enable</description>
                            <lsb>7</lsb>
                            <msb>7</msb>
                            <access>read-write</access>
                            <enumeratedValues>
                                </enumeratedValues>
                        </field>
                    </fields>
                </register>
                <register>
                    <name>SSLP</name>
                    <description>SPI Slave Select Polarity Register</description>
                    <addressOffset>0x01</addressOffset>
                    <size>8</size>
                    <access>read-write</access>
                    <resetValue>0x00</resetValue>
                    <resetMask>0xff</resetMask>
                    <fields>
                        <field>
                            <name>SSL0P</name>
                            <description>SSLn0 Signal Polarity Setting</description>
                            <lsb>0</lsb>
                            <msb>0</msb>
                            <access>read-write</access>
                            <enumeratedValues>
                                </enumeratedValues>
                        </field>
                        <field>
                            <name>SSL1P</name>
                            <description>SSLn1 Signal Polarity Setting</description>
                            <lsb>1</lsb>
                            <msb>1</msb>
                            <access>read-write</access>
                            <enumeratedValues>
                                </enumeratedValues>
                        </field>
                        <field>
                            <name>SSL2P</name>
                            <description>SSLn2 Signal Polarity Setting</description>
                            <lsb>2</lsb>
                            <msb>2</msb>
                            <access>read-write</access>
                            <enumeratedValues>
                                </enumeratedValues>
                        </field>
                        <field>
                            <name>SSL3P</name>
                            <description>SSLn3 Signal Polarity Setting</description>
                            <lsb>3</lsb>
                            <msb>3</msb>
                            <access>read-write</access>
                            <enumeratedValues>
                                </enumeratedValues>
                        </field>
                    </fields>
                </register>
                <register>
                    <name>SPPCR</name>
                    <description>SPI Pin Control Register</description>
                    <addressOffset>0x02</addressOffset>
                    <size>8</size>
                    <access>read-write</access>
                    <resetValue>0x00</resetValue>
                    <resetMask>0xff</resetMask>
                    <fields>
                        <field>
                            <name>SPLP</name>
                            <description>SPI Loopback</description>
                            <lsb>0</lsb>
                            <msb>0</msb>
                            <access>read-write</access>
                            <enumeratedValues>
                                </enumeratedValues>
                        </field>
                        <field>
                            <name>SPLP2</name>
                            <description>SPI Loopback 2</description>
                            <lsb>1</lsb>
                            <msb>1</msb>
                            <access>read-write</access>
                            <enumeratedValues>
                                </enumeratedValues>
                        </field>
                        <field>
                            <name>MOIFV</name>
                            <description>MOSI Idle Fixed Value</description>
                            <lsb>4</lsb>
                            <msb>4</msb>
                            <access>read-write</access>
                            <enumeratedValues>
                                </enumeratedValues>
                        </field>
                        <field>
                            <name>MOIFE</name>
                            <description>MOSI Idle Value Fixing Enable</description>
                            <lsb>5</lsb>
                            <msb>5</msb>
                            <access>read-write</access>
                            <enumeratedValues>
                                </enumeratedValues>
                        </field>
                    </fields>
                </register>
                <register>
                    <name>SPSR</name>
                    <description>SPI Status Register</description>
                    <addressOffset>0x03</addressOffset>
                    <size>8</size>
                    <access>read-write</access>
                    <resetValue>0x20</resetValue>
                    <resetMask>0xff</resetMask>
                    <fields>
                        <field>
                            <name>OVRF</name>
                            <description>Overrun Error Flag</description>
                            <lsb>0</lsb>
                            <msb>0</msb>
                            <access>read-write</access>
                            <enumeratedValues>
                                </enumeratedValues>
                        </field>
                        <field>
                            <name>IDLNF</name>
                            <description>SPI Idle Flag</description>
                            <lsb>1</lsb>
                            <msb>1</msb>
                            <access>read-only</access>
                            <enumeratedValues>
                                </enumeratedValues>
                        </field>
                        <field>
                            <name>MODF</name>
                            <description>Mode Fault Error Flag</description>
                            <lsb>2</lsb>
                            <msb>2</msb>
                            <access>read-write</access>
                            <enumeratedValues>
                                </enumeratedValues>
                        </field>
                        <field>
                            <name>PERF</name>
                            <description>Parity Error Flag</description>
                            <lsb>3</lsb>
                            <msb>3</msb>
                            <access>read-write</access>
                            <enumeratedValues>
                                </enumeratedValues>
                        </field>
                        <field>
                            <name>UDRF</name>
                            <description>Underrun Error Flag</description>
                            <lsb>4</lsb>
                            <msb>4</msb>
                            <access>read-write</access>
                            <enumeratedValues>
                                </enumeratedValues>
                        </field>
                        <field>
                            <name>SPTEF</name>
                            <description>SPI Transmit Buffer Empty Flag</description>
                            <lsb>5</lsb>
                            <msb>5</msb>
                            <access>read-write</access>
                            <enumeratedValues>
                                </enumeratedValues>
                        </field>
                        <field>
                            <name>CENDF</name>
                            <description>Communication End Flag</description>
                            <lsb>6</lsb>
                            <msb>6</msb>
                            <access>read-write</access>
                            <enumeratedValues>
                                </enumeratedValues>
                        </field>
                        <field>
                            <name>SPRF</name>
                            <description>SPI Receive Buffer Full Flag</description>
                            <lsb>7</lsb>
                            <msb>7</msb>
                            <access>read-write</access>
                            <enumeratedValues>
                                </enumeratedValues>
                        </field>
                    </fields>
                </register>
                <register>
                    <name>SPDR</name>
                    <description>SPI Data Register</description>
                    <addressOffset>0x04</addressOffset>
                    <size>32</size>
                    <access>read-write</access>
                    <resetValue>0x00000000</resetValue>
                    <resetMask>0xffffffff</resetMask>
                </register>
                <register>
                    <name>SPDR_HA</name>
                    <description>SPI Data Register</description>
                    <alternateRegister>SPDR</alternateRegister>
                    <addressOffset>0x04</addressOffset>
                    <size>16</size>
                    <access>read-write</access>
                    <resetValue>0x0000</resetValue>
                    <resetMask>0xffff</resetMask>
                </register>
                <register>
                    <name>SPDR_BY</name>
                    <description>SPI Data Register</description>
                    <alternateRegister>SPDR</alternateRegister>
                    <addressOffset>0x04</addressOffset>
                    <size>8</size>
                    <access>read-write</access>
                    <resetValue>0x00</resetValue>
                    <resetMask>0xff</resetMask>
                </register>
                <register>
                    <name>SPSCR</name>
                    <description>SPI Sequence Control Register</description>
                    <addressOffset>0x08</addressOffset>
                    <size>8</size>
                    <access>read-write</access>
                    <resetValue>0x00</resetValue>
                    <resetMask>0xff</resetMask>
                    <fields>
                        <field>
                            <name>SPSLN</name>
                            <description>SPI Sequence Length Specification</description>
                            <lsb>0</lsb>
                            <msb>2</msb>
                            <access>read-write</access>
                            <enumeratedValues>
                                </enumeratedValues>
                        </field>
                    </fields>
                </register>
                <register>
                    <name>SPSSR</name>
                    <description>SPI Sequence Status Register</description>
                    <addressOffset>0x09</addressOffset>
                    <size>8</size>
                    <access>read-only</access>
                    <resetValue>0x00</resetValue>
                    <resetMask>0xff</resetMask>
                    <fields>
                        <field>
                            <name>SPCP</name>
                            <description>SPI Command Pointer</description>
                            <lsb>0</lsb>
                            <msb>2</msb>
                            <access>read-only</access>
                            <enumeratedValues>
                                </enumeratedValues>
                        </field>
                        <field>
                            <name>SPECM</name>
                            <description>SPI Error Command</description>
                            <lsb>4</lsb>
                            <msb>6</msb>
                            <access>read-only</access>
                            <enumeratedValues>
                                </enumeratedValues>
                        </field>
                    </fields>
                </register>
                <register>
                    <name>SPBR</name>
                    <description>SPI Bit Rate Register</description>
                    <addressOffset>0x0A</addressOffset>
                    <size>8</size>
                    <access>read-write</access>
                    <resetValue>0xff</resetValue>
                    <resetMask>0xff</resetMask>
                </register>
                <register>
                    <name>SPDCR</name>
                    <description>SPI Data Control Register</description>
                    <addressOffset>0x0B</addressOffset>
                    <size>8</size>
                    <access>read-write</access>
                    <resetValue>0x00</resetValue>
                    <resetMask>0xff</resetMask>
                    <fields>
                        <field>
                            <name>SPFC</name>
                            <description>Number of Frames Specification</description>
                            <lsb>0</lsb>
                            <msb>1</msb>
                            <access>read-write</access>
                            <enumeratedValues>
                                </enumeratedValues>
                        </field>
                        <field>
                            <name>SPRDTD</name>
                            <description>SPI Receive/Transmit Data Select</description>
                            <lsb>4</lsb>
                            <msb>4</msb>
                            <access>read-write</access>
                            <enumeratedValues>
                                </enumeratedValues>
                        </field>
                        <field>
                            <name>SPLW</name>
                            <description>SPI Word Access/Halfword Access Specification</description>
                            <lsb>5</lsb>
                            <msb>5</msb>
                            <access>read-write</access>
                            <enumeratedValues>
                                </enumeratedValues>
                        </field>
                        <field>
                            <name>SPBYT</name>
                            <description>SPI Byte Access Specification</description>
                            <lsb>6</lsb>
                            <msb>6</msb>
                            <access>read-write</access>
                            <enumeratedValues>
                                </enumeratedValues>
                        </field>
                    </fields>
                </register>
                <register>
                    <name>SPCKD</name>
                    <description>SPI Clock Delay Register</description>
                    <addressOffset>0x0C</addressOffset>
                    <size>8</size>
                    <access>read-write</access>
                    <resetValue>0x00</resetValue>
                    <resetMask>0xff</resetMask>
                    <fields>
                        <field>
                            <name>SCKDL</name>
                            <description>RSPCK Delay Setting</description>
                            <lsb>0</lsb>
                            <msb>2</msb>
                            <access>read-write</access>
                            <enumeratedValues>
                                </enumeratedValues>
                        </field>
                    </fields>
                </register>
                <register>
                    <name>SSLND</name>
                    <description>SPI Slave Select Negation Delay Register</description>
                    <addressOffset>0x0D</addressOffset>
                    <size>8</size>
                    <access>read-write</access>
                    <resetValue>0x00</resetValue>
                    <resetMask>0xff</resetMask>
                    <fields>
                        <field>
                            <name>SLNDL</name>
                            <description>SSL Negation Delay Setting</description>
                            <lsb>0</lsb>
                            <msb>2</msb>
                            <access>read-write</access>
                            <enumeratedValues>
                                </enumeratedValues>
                        </field>
                    </fields>
                </register>
                <register>
                    <name>SPND</name>
                    <description>SPI Next,Access Delay Register</description>
                    <addressOffset>0x0E</addressOffset>
                    <size>8</size>
                    <access>read-write</access>
                    <resetValue>0x00</resetValue>
                    <resetMask>0xff</resetMask>
                    <fields>
                        <field>
                            <name>SPNDL</name>
                            <description>SPI Next,Access Delay Setting</description>
                            <lsb>0</lsb>
                            <msb>2</msb>
                            <access>read-write</access>
                            <enumeratedValues>
                                </enumeratedValues>
                        </field>
                    </fields>
                </register>
                <register>
                    <name>SPCR2</name>
                    <description>SPI Control Register 2</description>
                    <addressOffset>0x0F</addressOffset>
                    <size>8</size>
                    <access>read-write</access>
                    <resetValue>0x00</resetValue>
                    <resetMask>0xff</resetMask>
                    <fields>
                        <field>
                            <name>SPPE</name>
                            <description>Parity Enable</description>
                            <lsb>0</lsb>
                            <msb>0</msb>
                            <access>read-write</access>
                            <enumeratedValues>
                                </enumeratedValues>
                        </field>
                        <field>
                            <name>SPOE</name>
                            <description>Parity Mode</description>
                            <lsb>1</lsb>
                            <msb>1</msb>
                            <access>read-write</access>
                            <enumeratedValues>
                                </enumeratedValues>
                        </field>
                        <field>
                            <name>SPIIE</name>
                            <description>SPI Idle Interrupt Enable</description>
                            <lsb>2</lsb>
                            <msb>2</msb>
                            <access>read-write</access>
                            <enumeratedValues>
                                </enumeratedValues>
                        </field>
                        <field>
                            <name>PTE</name>
                            <description>Parity Self,Testing</description>
                            <lsb>3</lsb>
                            <msb>3</msb>
                            <access>read-write</access>
                            <enumeratedValues>
                                </enumeratedValues>
                        </field>
                        <field>
                            <name>SCKASE</name>
                            <description>RSPCK Auto,Stop Function Enable</description>
                            <lsb>4</lsb>
                            <msb>4</msb>
                            <access>read-write</access>
                            <enumeratedValues>
                                </enumeratedValues>
                        </field>
                    </fields>
                </register>
                <register>
                    <dim>8</dim>
                    <dimIncrement>0x02</dimIncrement>
                    <dimIndex>0-7</dimIndex>
                    <name>SPCMD%s</name>
                    <description>SPI Command Register %s</description>
                    <addressOffset>0x10</addressOffset>
                    <size>16</size>
                    <access>read-write</access>
                    <resetValue>0x070d</resetValue>
                    <resetMask>0xffff</resetMask>
                    <fields>
                        <field>
                            <name>CPHA</name>
                            <description>RSPCK Phase Setting</description>
                            <lsb>0</lsb>
                            <msb>0</msb>
                            <access>read-write</access>
                            <enumeratedValues>
                                </enumeratedValues>
                        </field>
                        <field>
                            <name>CPOL</name>
                            <description>RSPCK Polarity Setting</description>
                            <lsb>1</lsb>
                            <msb>1</msb>
                            <access>read-write</access>
                            <enumeratedValues>
                                </enumeratedValues>
                        </field>
                        <field>
                            <name>BRDV</name>
                            <description>Bit Rate Division Setting</description>
                            <lsb>2</lsb>
                            <msb>3</msb>
                            <access>read-write</access>
                            <enumeratedValues>
                                </enumeratedValues>
                        </field>
                        <field>
                            <name>SSLA</name>
                            <description>SSL Signal Assertion Setting</description>
                            <lsb>4</lsb>
                            <msb>6</msb>
                            <access>read-write</access>
                            <enumeratedValues>
                                </enumeratedValues>
                        </field>
                        <field>
                            <name>SSLKP</name>
                            <description>SSL Signal Level Keeping</description>
                            <lsb>7</lsb>
                            <msb>7</msb>
                            <access>read-write</access>
                            <enumeratedValues>
                                </enumeratedValues>
                        </field>
                        <field>
                            <name>SPB</name>
                            <description>SPI Data Length Setting</description>
                            <lsb>8</lsb>
                            <msb>11</msb>
                            <access>read-write</access>
                            <enumeratedValues>
                                </enumeratedValues>
                        </field>
                        <field>
                            <name>LSBF</name>
                            <description>SPI LSB First</description>
                            <lsb>12</lsb>
                            <msb>12</msb>
                            <access>read-write</access>
                            <enumeratedValues>
                                </enumeratedValues>
                        </field>
                        <field>
                            <name>SPNDEN</name>
                            <description>SPI Next,Access Delay Enable</description>
                            <lsb>13</lsb>
                            <msb>13</msb>
                            <access>read-write</access>
                            <enumeratedValues>
                                </enumeratedValues>
                        </field>
                        <field>
                            <name>SLNDEN</name>
                            <description>SSL Negation Delay Setting Enable</description>
                            <lsb>14</lsb>
                            <msb>14</msb>
                            <access>read-write</access>
                            <enumeratedValues>
                                </enumeratedValues>
                        </field>
                        <field>
                            <name>SCKDEN</name>
                            <description>RSPCK Delay Setting Enable</description>
                            <lsb>15</lsb>
                            <msb>15</msb>
                            <access>read-write</access>
                            <enumeratedValues>
                                </enumeratedValues>
                        </field>
                    </fields>
                </register>
                <register>
                    <name>SPDCR2</name>
                    <description>SPI Data Control Register 2</description>
                    <addressOffset>0x20</addressOffset>
                    <size>8</size>
                    <access>read-write</access>
                    <resetValue>0x00</resetValue>
                    <resetMask>0xff</resetMask>
                    <fields>
                        <field>
                            <name>BYSW</name>
                            <description>Byte Swap Operating Mode Select</description>
                            <lsb>0</lsb>
                            <msb>0</msb>
                            <access>read-write</access>
                            <enumeratedValues>
                                </enumeratedValues>
                        </field>
                        <field>
                            <name>SINV</name>
                            <description>Serial Data Invert Bit</description>
                            <lsb>1</lsb>
                            <msb>1</msb>
                            <access>read-write</access>
                            <enumeratedValues>
                                </enumeratedValues>
                        </field>
                    </fields>
                </register>
                <register>
                    <name>SPCR3</name>
                    <description>SPI Control Register 3</description>
                    <addressOffset>0x21</addressOffset>
                    <size>8</size>
                    <access>read-write</access>
                    <resetValue>0x00</resetValue>
                    <resetMask>0xff</resetMask>
                    <fields>
                        <field>
                            <name>ETXMD</name>
                            <description>Extended Communication Mode Select</description>
                            <lsb>0</lsb>
                            <msb>0</msb>
                            <access>read-write</access>
                            <enumeratedValues>
                                </enumeratedValues>
                        </field>
                        <field>
                            <name>BFDS</name>
                            <description>Between Burst Transfer Frames Delay Select</description>
                            <lsb>1</lsb>
                            <msb>1</msb>
                            <access>read-write</access>
                            <enumeratedValues>
                                </enumeratedValues>
                        </field>
                        <field>
                            <name>CENDIE</name>
                            <description>SPI Communication End Interrupt Enable</description>
                            <lsb>4</lsb>
                            <msb>4</msb>
                            <access>read-write</access>
                            <enumeratedValues>
                                </enumeratedValues>
                        </field>
                    </fields>
                </register>
            </registers>
        </peripheral>
        <peripheral derivedFrom="SPI0">
            <name>SPI1</name>
            <description>Serial Peripheral Interface 1</description>
            <baseAddress>0x4011A100</baseAddress>
        </peripheral>
        <peripheral>
            <name>ECCAFL0</name>
            <description>ECCAFL</description>
            <baseAddress>0x4012F000</baseAddress>
            <addressBlock>
                <offset>0x00</offset>
                <size>6</size>
                <usage>registers</usage>
            </addressBlock>
            <addressBlock>
                <offset>0x0C</offset>
                <size>8</size>
                <usage>registers</usage>
            </addressBlock>
            <registers>
                <register>
                    <name>EC710CTL</name>
                    <description>ECC Control Register</description>
                    <addressOffset>0x00</addressOffset>
                    <size>32</size>
                    <access>read-write</access>
                    <resetValue>0x00000010</resetValue>
                    <resetMask>0xffffffff</resetMask>
                    <fields>
                        <field>
                            <name>ECEMF</name>
                            <description>ECC Error Message Flag</description>
                            <lsb>0</lsb>
                            <msb>0</msb>
                            <access>read-only</access>
                            <enumeratedValues>
                                </enumeratedValues>
                        </field>
                        <field>
                            <name>ECER1F</name>
                            <description>ECC Error Detection and Correction Flag</description>
                            <lsb>1</lsb>
                            <msb>1</msb>
                            <access>read-only</access>
                            <enumeratedValues>
                                </enumeratedValues>
                        </field>
                        <field>
                            <name>ECER2F</name>
                            <description>2-bit ECC Error Detection Flag</description>
                            <lsb>2</lsb>
                            <msb>2</msb>
                            <access>read-only</access>
                            <enumeratedValues>
                                </enumeratedValues>
                        </field>
                        <field>
                            <name>EC1EDIC</name>
                            <description>ECC 1-bit Error Detection Interrupt Control</description>
                            <lsb>3</lsb>
                            <msb>3</msb>
                            <access>read-write</access>
                            <enumeratedValues>
                                </enumeratedValues>
                        </field>
                        <field>
                            <name>EC2EDIC</name>
                            <description>ECC 2-bit Error Detection Interrupt Control</description>
                            <lsb>4</lsb>
                            <msb>4</msb>
                            <access>read-write</access>
                            <enumeratedValues>
                                </enumeratedValues>
                        </field>
                        <field>
                            <name>EC1ECP</name>
                            <description>ECC 1-bit Error Correction Permission</description>
                            <lsb>5</lsb>
                            <msb>5</msb>
                            <access>read-write</access>
                            <enumeratedValues>
                                </enumeratedValues>
                        </field>
                        <field>
                            <name>ECERVF</name>
                            <description>ECC Error Judgment Enable Flag</description>
                            <lsb>6</lsb>
                            <msb>6</msb>
                            <access>read-write</access>
                            <enumeratedValues>
                                </enumeratedValues>
                        </field>
                        <field>
                            <name>ECER1C</name>
                            <description>Accumulating ECC Error Detection and Correction Flag Clear</description>
                            <lsb>9</lsb>
                            <msb>9</msb>
                            <access>read-write</access>
                            <enumeratedValues>
                                </enumeratedValues>
                        </field>
                        <field>
                            <name>ECER2C</name>
                            <description>2-bit ECC Error Detection Flag Clear</description>
                            <lsb>10</lsb>
                            <msb>10</msb>
                            <access>read-write</access>
                            <enumeratedValues>
                                </enumeratedValues>
                        </field>
                        <field>
                            <name>ECOVFF</name>
                            <description>ECC Overflow Detection Flag</description>
                            <lsb>11</lsb>
                            <msb>11</msb>
                            <access>read-only</access>
                            <enumeratedValues>
                                </enumeratedValues>
                        </field>
                        <field>
                            <name>EMCA</name>
                            <description>Access Control to ECC Mode Select bit</description>
                            <lsb>14</lsb>
                            <msb>15</msb>
                            <access>read-write</access>
                        </field>
                        <field>
                            <name>ECSEDF0</name>
                            <description>ECC Single bit Error Address Detection Flag</description>
                            <lsb>16</lsb>
                            <msb>16</msb>
                            <access>read-only</access>
                            <enumeratedValues>
                                </enumeratedValues>
                        </field>
                        <field>
                            <name>ECDEDF0</name>
                            <description>ECC Dual Bit Error Address Detection Flag</description>
                            <lsb>17</lsb>
                            <msb>17</msb>
                            <access>read-only</access>
                            <enumeratedValues>
                                </enumeratedValues>
                        </field>
                    </fields>
                </register>
                <register>
                    <name>EC710TMC</name>
                    <description>ECC Test Mode Control Register</description>
                    <addressOffset>0x04</addressOffset>
                    <size>16</size>
                    <access>read-write</access>
                    <resetValue>0x0000</resetValue>
                    <resetMask>0xffff</resetMask>
                    <fields>
                        <field>
                            <name>ECDCS</name>
                            <description>ECC Decode Input Select</description>
                            <lsb>1</lsb>
                            <msb>1</msb>
                            <access>read-write</access>
                            <enumeratedValues>
                                </enumeratedValues>
                        </field>
                        <field>
                            <name>ECTMCE</name>
                            <description>ECC Test Mode Control Enable</description>
                            <lsb>7</lsb>
                            <msb>7</msb>
                            <access>read-write</access>
                            <enumeratedValues>
                                </enumeratedValues>
                        </field>
                        <field>
                            <name>ETMA</name>
                            <description>ECC Test Mode Bit Access Control</description>
                            <lsb>14</lsb>
                            <msb>15</msb>
                            <access>read-write</access>
                        </field>
                    </fields>
                </register>
                <register>
                    <name>EC710TED</name>
                    <description>ECC Test Substitute Data Register</description>
                    <addressOffset>0x0C</addressOffset>
                    <size>32</size>
                    <access>read-write</access>
                    <resetValue>0x00000000</resetValue>
                    <resetMask>0xffffffff</resetMask>
                    <fields>
                        <field>
                            <name>ECEDB</name>
                            <description>ECC Test Substitute Data</description>
                            <lsb>0</lsb>
                            <msb>31</msb>
                            <access>read-write</access>
                        </field>
                    </fields>
                </register>
                <register>
                    <name>EC710EAD0</name>
                    <description>ECC Error Address Register</description>
                    <addressOffset>0x10</addressOffset>
                    <size>32</size>
                    <access>read-only</access>
                    <resetValue>0x00000000</resetValue>
                    <resetMask>0xffffffff</resetMask>
                    <fields>
                        <field>
                            <name>ECEAD</name>
                            <description>ECC Error Address</description>
                            <lsb>0</lsb>
                            <msb>10</msb>
                            <access>read-only</access>
                        </field>
                    </fields>
                </register>
            </registers>
        </peripheral>
        <peripheral derivedFrom="ECCAFL0">
            <name>ECCAFL1</name>
            <description>ECCAFL</description>
            <baseAddress>0x4012F100</baseAddress>
        </peripheral>
        <peripheral>
            <name>ECCMB</name>
            <description>ECCMB</description>
            <baseAddress>0x4012F200</baseAddress>
            <addressBlock>
                <offset>0x00</offset>
                <size>6</size>
                <usage>registers</usage>
            </addressBlock>
            <addressBlock>
                <offset>0x0C</offset>
                <size>8</size>
                <usage>registers</usage>
            </addressBlock>
            <registers>
                <register>
                    <name>EC710CTL</name>
                    <description>ECC Control Register</description>
                    <addressOffset>0x00</addressOffset>
                    <size>32</size>
                    <access>read-write</access>
                    <resetValue>0x00000010</resetValue>
                    <resetMask>0xffffffff</resetMask>
                    <fields>
                        <field>
                            <name>ECEMF</name>
                            <description>ECC Error Message Flag</description>
                            <lsb>0</lsb>
                            <msb>0</msb>
                            <access>read-only</access>
                            <enumeratedValues>
                                </enumeratedValues>
                        </field>
                        <field>
                            <name>ECER1F</name>
                            <description>ECC Error Detection and Correction Flag</description>
                            <lsb>1</lsb>
                            <msb>1</msb>
                            <access>read-only</access>
                            <enumeratedValues>
                                </enumeratedValues>
                        </field>
                        <field>
                            <name>ECER2F</name>
                            <description>2-bit ECC Error Detection Flag</description>
                            <lsb>2</lsb>
                            <msb>2</msb>
                            <access>read-only</access>
                            <enumeratedValues>
                                </enumeratedValues>
                        </field>
                        <field>
                            <name>EC1EDIC</name>
                            <description>ECC 1-bit Error Detection Interrupt Control</description>
                            <lsb>3</lsb>
                            <msb>3</msb>
                            <access>read-write</access>
                            <enumeratedValues>
                                </enumeratedValues>
                        </field>
                        <field>
                            <name>EC2EDIC</name>
                            <description>ECC 2-bit Error Detection Interrupt Control</description>
                            <lsb>4</lsb>
                            <msb>4</msb>
                            <access>read-write</access>
                            <enumeratedValues>
                                </enumeratedValues>
                        </field>
                        <field>
                            <name>EC1ECP</name>
                            <description>ECC 1-bit Error Correction Permission</description>
                            <lsb>5</lsb>
                            <msb>5</msb>
                            <access>read-write</access>
                            <enumeratedValues>
                                </enumeratedValues>
                        </field>
                        <field>
                            <name>ECERVF</name>
                            <description>ECC Error Judgment Enable Flag</description>
                            <lsb>6</lsb>
                            <msb>6</msb>
                            <access>read-write</access>
                            <enumeratedValues>
                                </enumeratedValues>
                        </field>
                        <field>
                            <name>ECER1C</name>
                            <description>Accumulating ECC Error Detection and Correction Flag Clear</description>
                            <lsb>9</lsb>
                            <msb>9</msb>
                            <access>read-write</access>
                            <enumeratedValues>
                                </enumeratedValues>
                        </field>
                        <field>
                            <name>ECER2C</name>
                            <description>2-bit ECC Error Detection Flag Clear</description>
                            <lsb>10</lsb>
                            <msb>10</msb>
                            <access>read-write</access>
                            <enumeratedValues>
                                </enumeratedValues>
                        </field>
                        <field>
                            <name>ECOVFF</name>
                            <description>ECC Overflow Detection Flag</description>
                            <lsb>11</lsb>
                            <msb>11</msb>
                            <access>read-only</access>
                            <enumeratedValues>
                                </enumeratedValues>
                        </field>
                        <field>
                            <name>EMCA</name>
                            <description>Access Control to ECC Mode Select bit</description>
                            <lsb>14</lsb>
                            <msb>15</msb>
                            <access>read-write</access>
                        </field>
                        <field>
                            <name>ECSEDF0</name>
                            <description>ECC Single bit Error Address Detection Flag</description>
                            <lsb>16</lsb>
                            <msb>16</msb>
                            <access>read-only</access>
                            <enumeratedValues>
                                </enumeratedValues>
                        </field>
                        <field>
                            <name>ECDEDF0</name>
                            <description>ECC Dual Bit Error Address Detection Flag</description>
                            <lsb>17</lsb>
                            <msb>17</msb>
                            <access>read-only</access>
                            <enumeratedValues>
                                </enumeratedValues>
                        </field>
                    </fields>
                </register>
                <register>
                    <name>EC710TMC</name>
                    <description>ECC Test Mode Control Register</description>
                    <addressOffset>0x04</addressOffset>
                    <size>16</size>
                    <access>read-write</access>
                    <resetValue>0x0000</resetValue>
                    <resetMask>0xffff</resetMask>
                    <fields>
                        <field>
                            <name>ECDCS</name>
                            <description>ECC Decode Input Select</description>
                            <lsb>1</lsb>
                            <msb>1</msb>
                            <access>read-write</access>
                            <enumeratedValues>
                                </enumeratedValues>
                        </field>
                        <field>
                            <name>ECTMCE</name>
                            <description>ECC Test Mode Control Enable</description>
                            <lsb>7</lsb>
                            <msb>7</msb>
                            <access>read-write</access>
                            <enumeratedValues>
                                </enumeratedValues>
                        </field>
                        <field>
                            <name>ETMA</name>
                            <description>ECC Test Mode Bit Access Control</description>
                            <lsb>14</lsb>
                            <msb>15</msb>
                            <access>read-write</access>
                        </field>
                    </fields>
                </register>
                <register>
                    <name>EC710TED</name>
                    <description>ECC Test Substitute Data Register</description>
                    <addressOffset>0x0C</addressOffset>
                    <size>32</size>
                    <access>read-write</access>
                    <resetValue>0x00000000</resetValue>
                    <resetMask>0xffffffff</resetMask>
                    <fields>
                        <field>
                            <name>ECEDB</name>
                            <description>ECC Test Substitute Data</description>
                            <lsb>0</lsb>
                            <msb>31</msb>
                            <access>read-write</access>
                        </field>
                    </fields>
                </register>
                <register>
                    <name>EC710EAD0</name>
                    <description>ECC Error Address Register</description>
                    <addressOffset>0x10</addressOffset>
                    <size>32</size>
                    <access>read-only</access>
                    <resetValue>0x00000000</resetValue>
                    <resetMask>0xffffffff</resetMask>
                    <fields>
                        <field>
                            <name>ECEAD</name>
                            <description>ECC Error Address</description>
                            <lsb>0</lsb>
                            <msb>10</msb>
                            <access>read-only</access>
                        </field>
                    </fields>
                </register>
            </registers>
        </peripheral>
        <peripheral>
            <name>GPT320</name>
            <description>General PWM 32-bit Timer 0</description>
            <baseAddress>0x40169000</baseAddress>
            <addressBlock>
                <offset>0x00</offset>
                <size>68</size>
                <usage>registers</usage>
            </addressBlock>
            <addressBlock>
                <offset>0x48</offset>
                <size>36</size>
                <usage>registers</usage>
            </addressBlock>
            <addressBlock>
                <offset>0x88</offset>
                <size>8</size>
                <usage>registers</usage>
            </addressBlock>
            <addressBlock>
                <offset>0xB8</offset>
                <size>8</size>
                <usage>registers</usage>
            </addressBlock>
            <addressBlock>
                <offset>0xD0</offset>
                <size>8</size>
                <usage>registers</usage>
            </addressBlock>
            <registers>
                <register>
                    <name>GTWP</name>
                    <description>General PWM Timer Write,Protection Register</description>
                    <addressOffset>0x00</addressOffset>
                    <size>32</size>
                    <access>read-write</access>
                    <resetValue>0x00000000</resetValue>
                    <resetMask>0xffffffff</resetMask>
                    <fields>
                        <field>
                            <name>WP</name>
                            <description>Register Write Disable</description>
                            <lsb>0</lsb>
                            <msb>0</msb>
                            <access>read-write</access>
                            <enumeratedValues>
                                </enumeratedValues>
                        </field>
                        <field>
                            <name>STRWP</name>
                            <description>GTSTR.CSTRT Bit Write Disable</description>
                            <lsb>1</lsb>
                            <msb>1</msb>
                            <access>read-write</access>
                            <enumeratedValues>
                                </enumeratedValues>
                        </field>
                        <field>
                            <name>STPWP</name>
                            <description>GTSTP.CSTOP Bit Write Disable</description>
                            <lsb>2</lsb>
                            <msb>2</msb>
                            <access>read-write</access>
                            <enumeratedValues>
                                </enumeratedValues>
                        </field>
                        <field>
                            <name>CLRWP</name>
                            <description>GTCLR.CCLR Bit Write Disable</description>
                            <lsb>3</lsb>
                            <msb>3</msb>
                            <access>read-write</access>
                            <enumeratedValues>
                                </enumeratedValues>
                        </field>
                        <field>
                            <name>CMNWP</name>
                            <description>Common Register Write Disabled</description>
                            <lsb>4</lsb>
                            <msb>4</msb>
                            <access>read-write</access>
                            <enumeratedValues>
                                </enumeratedValues>
                        </field>
                        <field>
                            <name>PRKEY</name>
                            <description>GTWP Key Code</description>
                            <lsb>8</lsb>
                            <msb>15</msb>
                            <access>write-only</access>
                        </field>
                    </fields>
                </register>
                <register>
                    <name>GTSTR</name>
                    <description>General PWM Timer Software Start Register</description>
                    <addressOffset>0x04</addressOffset>
                    <size>32</size>
                    <access>read-write</access>
                    <resetValue>0x00000000</resetValue>
                    <resetMask>0xffffffff</resetMask>
                    <fields>
                        <field>
                            <name>CSTRT0</name>
                            <description>Channel n GTCNT Count Start (n : the same as bit position value)</description>
                            <lsb>0</lsb>
                            <msb>0</msb>
                            <access>read-write</access>
                            <enumeratedValues>
                                </enumeratedValues>
                        </field>
                        <field>
                            <name>CSTRT1</name>
                            <description>Channel n GTCNT Count Start (n : the same as bit position value)</description>
                            <lsb>1</lsb>
                            <msb>1</msb>
                            <access>read-write</access>
                            <enumeratedValues>
                                </enumeratedValues>
                        </field>
                        <field>
                            <name>CSTRT2</name>
                            <description>Channel n GTCNT Count Start (n : the same as bit position value)</description>
                            <lsb>2</lsb>
                            <msb>2</msb>
                            <access>read-write</access>
                            <enumeratedValues>
                                </enumeratedValues>
                        </field>
                        <field>
                            <name>CSTRT3</name>
                            <description>Channel n GTCNT Count Start (n : the same as bit position value)</description>
                            <lsb>3</lsb>
                            <msb>3</msb>
                            <access>read-write</access>
                            <enumeratedValues>
                                </enumeratedValues>
                        </field>
                        <field>
                            <name>CSTRT4</name>
                            <description>Channel n GTCNT Count Start (n : the same as bit position value)</description>
                            <lsb>4</lsb>
                            <msb>4</msb>
                            <access>read-write</access>
                            <enumeratedValues>
                                </enumeratedValues>
                        </field>
                        <field>
                            <name>CSTRT5</name>
                            <description>Channel n GTCNT Count Start (n : the same as bit position value)</description>
                            <lsb>5</lsb>
                            <msb>5</msb>
                            <access>read-write</access>
                            <enumeratedValues>
                                </enumeratedValues>
                        </field>
                        <field>
                            <name>CSTRT6</name>
                            <description>Channel n GTCNT Count Start (n : the same as bit position value)</description>
                            <lsb>6</lsb>
                            <msb>6</msb>
                            <access>read-write</access>
                            <enumeratedValues>
                                </enumeratedValues>
                        </field>
                        <field>
                            <name>CSTRT7</name>
                            <description>Channel n GTCNT Count Start (n : the same as bit position value)</description>
                            <lsb>7</lsb>
                            <msb>7</msb>
                            <access>read-write</access>
                            <enumeratedValues>
                                </enumeratedValues>
                        </field>
                        <field>
                            <name>CSTRT8</name>
                            <description>Channel n GTCNT Count Start (n : the same as bit position value)</description>
                            <lsb>8</lsb>
                            <msb>8</msb>
                            <access>read-write</access>
                            <enumeratedValues>
                                </enumeratedValues>
                        </field>
                        <field>
                            <name>CSTRT9</name>
                            <description>Channel n GTCNT Count Start (n : the same as bit position value)</description>
                            <lsb>9</lsb>
                            <msb>9</msb>
                            <access>read-write</access>
                            <enumeratedValues>
                                </enumeratedValues>
                        </field>
                    </fields>
                </register>
                <register>
                    <name>GTSTP</name>
                    <description>General PWM Timer Software Stop Register</description>
                    <addressOffset>0x08</addressOffset>
                    <size>32</size>
                    <access>read-write</access>
                    <resetValue>0xffffffff</resetValue>
                    <resetMask>0xffffffff</resetMask>
                    <fields>
                        <field>
                            <name>CSTOP0</name>
                            <description>Channel n GTCNT Count Stop (n : the same as bit position value)</description>
                            <lsb>0</lsb>
                            <msb>0</msb>
                            <access>read-write</access>
                            <enumeratedValues>
                                </enumeratedValues>
                        </field>
                        <field>
                            <name>CSTOP1</name>
                            <description>Channel n GTCNT Count Stop (n : the same as bit position value)</description>
                            <lsb>1</lsb>
                            <msb>1</msb>
                            <access>read-write</access>
                            <enumeratedValues>
                                </enumeratedValues>
                        </field>
                        <field>
                            <name>CSTOP2</name>
                            <description>Channel n GTCNT Count Stop (n : the same as bit position value)</description>
                            <lsb>2</lsb>
                            <msb>2</msb>
                            <access>read-write</access>
                            <enumeratedValues>
                                </enumeratedValues>
                        </field>
                        <field>
                            <name>CSTOP3</name>
                            <description>Channel n GTCNT Count Stop (n : the same as bit position value)</description>
                            <lsb>3</lsb>
                            <msb>3</msb>
                            <access>read-write</access>
                            <enumeratedValues>
                                </enumeratedValues>
                        </field>
                        <field>
                            <name>CSTOP4</name>
                            <description>Channel n GTCNT Count Stop (n : the same as bit position value)</description>
                            <lsb>4</lsb>
                            <msb>4</msb>
                            <access>read-write</access>
                            <enumeratedValues>
                                </enumeratedValues>
                        </field>
                        <field>
                            <name>CSTOP5</name>
                            <description>Channel n GTCNT Count Stop (n : the same as bit position value)</description>
                            <lsb>5</lsb>
                            <msb>5</msb>
                            <access>read-write</access>
                            <enumeratedValues>
                                </enumeratedValues>
                        </field>
                        <field>
                            <name>CSTOP6</name>
                            <description>Channel n GTCNT Count Stop (n : the same as bit position value)</description>
                            <lsb>6</lsb>
                            <msb>6</msb>
                            <access>read-write</access>
                            <enumeratedValues>
                                </enumeratedValues>
                        </field>
                        <field>
                            <name>CSTOP7</name>
                            <description>Channel n GTCNT Count Stop (n : the same as bit position value)</description>
                            <lsb>7</lsb>
                            <msb>7</msb>
                            <access>read-write</access>
                            <enumeratedValues>
                                </enumeratedValues>
                        </field>
                        <field>
                            <name>CSTOP8</name>
                            <description>Channel n GTCNT Count Stop (n : the same as bit position value)</description>
                            <lsb>8</lsb>
                            <msb>8</msb>
                            <access>read-write</access>
                            <enumeratedValues>
                                </enumeratedValues>
                        </field>
                        <field>
                            <name>CSTOP9</name>
                            <description>Channel n GTCNT Count Stop (n : the same as bit position value)</description>
                            <lsb>9</lsb>
                            <msb>9</msb>
                            <access>read-write</access>
                            <enumeratedValues>
                                </enumeratedValues>
                        </field>
                    </fields>
                </register>
                <register>
                    <name>GTCLR</name>
                    <description>General PWM Timer Software Clear Register</description>
                    <addressOffset>0x0C</addressOffset>
                    <size>32</size>
                    <access>write-only</access>
                    <resetValue>0x00000000</resetValue>
                    <resetMask>0xffffffff</resetMask>
                    <fields>
                        <field>
                            <name>CCLR0</name>
                            <description>Channel n GTCNT Count Clear (n : the same as bit position value)</description>
                            <lsb>0</lsb>
                            <msb>0</msb>
                            <access>write-only</access>
                            <enumeratedValues>
                                </enumeratedValues>
                        </field>
                        <field>
                            <name>CCLR1</name>
                            <description>Channel n GTCNT Count Clear (n : the same as bit position value)</description>
                            <lsb>1</lsb>
                            <msb>1</msb>
                            <access>write-only</access>
                            <enumeratedValues>
                                </enumeratedValues>
                        </field>
                        <field>
                            <name>CCLR2</name>
                            <description>Channel n GTCNT Count Clear (n : the same as bit position value)</description>
                            <lsb>2</lsb>
                            <msb>2</msb>
                            <access>write-only</access>
                            <enumeratedValues>
                                </enumeratedValues>
                        </field>
                        <field>
                            <name>CCLR3</name>
                            <description>Channel n GTCNT Count Clear (n : the same as bit position value)</description>
                            <lsb>3</lsb>
                            <msb>3</msb>
                            <access>write-only</access>
                            <enumeratedValues>
                                </enumeratedValues>
                        </field>
                        <field>
                            <name>CCLR4</name>
                            <description>Channel n GTCNT Count Clear (n : the same as bit position value)</description>
                            <lsb>4</lsb>
                            <msb>4</msb>
                            <access>write-only</access>
                            <enumeratedValues>
                                </enumeratedValues>
                        </field>
                        <field>
                            <name>CCLR5</name>
                            <description>Channel n GTCNT Count Clear (n : the same as bit position value)</description>
                            <lsb>5</lsb>
                            <msb>5</msb>
                            <access>write-only</access>
                            <enumeratedValues>
                                </enumeratedValues>
                        </field>
                        <field>
                            <name>CCLR6</name>
                            <description>Channel n GTCNT Count Clear (n : the same as bit position value)</description>
                            <lsb>6</lsb>
                            <msb>6</msb>
                            <access>write-only</access>
                            <enumeratedValues>
                                </enumeratedValues>
                        </field>
                        <field>
                            <name>CCLR7</name>
                            <description>Channel n GTCNT Count Clear (n : the same as bit position value)</description>
                            <lsb>7</lsb>
                            <msb>7</msb>
                            <access>write-only</access>
                            <enumeratedValues>
                                </enumeratedValues>
                        </field>
                        <field>
                            <name>CCLR8</name>
                            <description>Channel n GTCNT Count Clear (n : the same as bit position value)</description>
                            <lsb>8</lsb>
                            <msb>8</msb>
                            <access>write-only</access>
                            <enumeratedValues>
                                </enumeratedValues>
                        </field>
                        <field>
                            <name>CCLR9</name>
                            <description>Channel n GTCNT Count Clear (n : the same as bit position value)</description>
                            <lsb>9</lsb>
                            <msb>9</msb>
                            <access>write-only</access>
                            <enumeratedValues>
                                </enumeratedValues>
                        </field>
                    </fields>
                </register>
                <register>
                    <name>GTSSR</name>
                    <description>General PWM Timer Start Source Select Register</description>
                    <addressOffset>0x10</addressOffset>
                    <size>32</size>
                    <access>read-write</access>
                    <resetValue>0x00000000</resetValue>
                    <resetMask>0xffffffff</resetMask>
                    <fields>
                        <field>
                            <name>SSGTRGAR</name>
                            <description>GTETRGA Pin Rising Input Source Counter Start Enable</description>
                            <lsb>0</lsb>
                            <msb>0</msb>
                            <access>read-write</access>
                            <enumeratedValues>
                                </enumeratedValues>
                        </field>
                        <field>
                            <name>SSGTRGAF</name>
                            <description>GTETRGA Pin Falling Input Source Counter Start Enable</description>
                            <lsb>1</lsb>
                            <msb>1</msb>
                            <access>read-write</access>
                            <enumeratedValues>
                                </enumeratedValues>
                        </field>
                        <field>
                            <name>SSGTRGBR</name>
                            <description>GTETRGB Pin Rising Input Source Counter Start Enable</description>
                            <lsb>2</lsb>
                            <msb>2</msb>
                            <access>read-write</access>
                            <enumeratedValues>
                                </enumeratedValues>
                        </field>
                        <field>
                            <name>SSGTRGBF</name>
                            <description>GTETRGB Pin Falling Input Source Counter Start Enable</description>
                            <lsb>3</lsb>
                            <msb>3</msb>
                            <access>read-write</access>
                            <enumeratedValues>
                                </enumeratedValues>
                        </field>
                        <field>
                            <name>SSGTRGCR</name>
                            <description>GTETRGC Pin Rising Input Source Counter Start Enable</description>
                            <lsb>4</lsb>
                            <msb>4</msb>
                            <access>read-write</access>
                            <enumeratedValues>
                                </enumeratedValues>
                        </field>
                        <field>
                            <name>SSGTRGCF</name>
                            <description>GTETRGC Pin Falling Input Source Counter Start Enable</description>
                            <lsb>5</lsb>
                            <msb>5</msb>
                            <access>read-write</access>
                            <enumeratedValues>
                                </enumeratedValues>
                        </field>
                        <field>
                            <name>SSGTRGDR</name>
                            <description>GTETRGD Pin Rising Input Source Counter Start Enable</description>
                            <lsb>6</lsb>
                            <msb>6</msb>
                            <access>read-write</access>
                            <enumeratedValues>
                                </enumeratedValues>
                        </field>
                        <field>
                            <name>SSGTRGDF</name>
                            <description>GTETRGD Pin Falling Input Source Counter Start Enable</description>
                            <lsb>7</lsb>
                            <msb>7</msb>
                            <access>read-write</access>
                            <enumeratedValues>
                                </enumeratedValues>
                        </field>
                        <field>
                            <name>SSCARBL</name>
                            <description>GTIOCnA Pin Rising Input during GTIOCnB Value Low Source Counter Start Enable</description>
                            <lsb>8</lsb>
                            <msb>8</msb>
                            <access>read-write</access>
                            <enumeratedValues>
                                </enumeratedValues>
                        </field>
                        <field>
                            <name>SSCARBH</name>
                            <description>GTIOCnA Pin Rising Input during GTIOCnB Value High Source Counter Start Enable</description>
                            <lsb>9</lsb>
                            <msb>9</msb>
                            <access>read-write</access>
                            <enumeratedValues>
                                </enumeratedValues>
                        </field>
                        <field>
                            <name>SSCAFBL</name>
                            <description>GTIOCnA Pin Falling Input during GTIOCnB Value Low Source Counter Start Enable</description>
                            <lsb>10</lsb>
                            <msb>10</msb>
                            <access>read-write</access>
                            <enumeratedValues>
                                </enumeratedValues>
                        </field>
                        <field>
                            <name>SSCAFBH</name>
                            <description>GTIOCnA Pin Falling Input during GTIOCnB Value High Source Counter Start Enable</description>
                            <lsb>11</lsb>
                            <msb>11</msb>
                            <access>read-write</access>
                            <enumeratedValues>
                                </enumeratedValues>
                        </field>
                        <field>
                            <name>SSCBRAL</name>
                            <description>GTIOCnB Pin Rising Input during GTIOCnA Value Low Source Counter Start Enable</description>
                            <lsb>12</lsb>
                            <msb>12</msb>
                            <access>read-write</access>
                            <enumeratedValues>
                                </enumeratedValues>
                        </field>
                        <field>
                            <name>SSCBRAH</name>
                            <description>GTIOCnB Pin Rising Input during GTIOCnA Value High Source Counter Start Enable</description>
                            <lsb>13</lsb>
                            <msb>13</msb>
                            <access>read-write</access>
                            <enumeratedValues>
                                </enumeratedValues>
                        </field>
                        <field>
                            <name>SSCBFAL</name>
                            <description>GTIOCnB Pin Falling Input during GTIOCnA Value Low Source Counter Start Enable</description>
                            <lsb>14</lsb>
                            <msb>14</msb>
                            <access>read-write</access>
                            <enumeratedValues>
                                </enumeratedValues>
                        </field>
                        <field>
                            <name>SSCBFAH</name>
                            <description>GTIOCnB Pin Falling Input during GTIOCnA Value High Source Counter Start Enable</description>
                            <lsb>15</lsb>
                            <msb>15</msb>
                            <access>read-write</access>
                            <enumeratedValues>
                                </enumeratedValues>
                        </field>
                        <field>
                            <name>SSELCA</name>
                            <description>ELC_GPTA Event Source Counter Start Enable</description>
                            <lsb>16</lsb>
                            <msb>16</msb>
                            <access>read-write</access>
                            <enumeratedValues>
                                </enumeratedValues>
                        </field>
                        <field>
                            <name>SSELCB</name>
                            <description>ELC_GPTB Event Source Counter Start Enable</description>
                            <lsb>17</lsb>
                            <msb>17</msb>
                            <access>read-write</access>
                            <enumeratedValues>
                                </enumeratedValues>
                        </field>
                        <field>
                            <name>SSELCC</name>
                            <description>ELC_GPTC Event Source Counter Start Enable</description>
                            <lsb>18</lsb>
                            <msb>18</msb>
                            <access>read-write</access>
                            <enumeratedValues>
                                </enumeratedValues>
                        </field>
                        <field>
                            <name>SSELCD</name>
                            <description>ELC_GPTD Event Source Counter Start Enable</description>
                            <lsb>19</lsb>
                            <msb>19</msb>
                            <access>read-write</access>
                            <enumeratedValues>
                                </enumeratedValues>
                        </field>
                        <field>
                            <name>SSELCE</name>
                            <description>ELC_GPTE Event Source Counter Start Enable</description>
                            <lsb>20</lsb>
                            <msb>20</msb>
                            <access>read-write</access>
                            <enumeratedValues>
                                </enumeratedValues>
                        </field>
                        <field>
                            <name>SSELCF</name>
                            <description>ELC_GPTF Event Source Counter Start Enable</description>
                            <lsb>21</lsb>
                            <msb>21</msb>
                            <access>read-write</access>
                            <enumeratedValues>
                                </enumeratedValues>
                        </field>
                        <field>
                            <name>SSELCG</name>
                            <description>ELC_GPTG Event Source Counter Start Enable</description>
                            <lsb>22</lsb>
                            <msb>22</msb>
                            <access>read-write</access>
                            <enumeratedValues>
                                </enumeratedValues>
                        </field>
                        <field>
                            <name>SSELCH</name>
                            <description>ELC_GPTH Event Source Counter Start Enable</description>
                            <lsb>23</lsb>
                            <msb>23</msb>
                            <access>read-write</access>
                            <enumeratedValues>
                                </enumeratedValues>
                        </field>
                        <field>
                            <name>CSTRT</name>
                            <description>Software Source Counter Start Enable</description>
                            <lsb>31</lsb>
                            <msb>31</msb>
                            <access>read-write</access>
                            <enumeratedValues>
                                </enumeratedValues>
                        </field>
                    </fields>
                </register>
                <register>
                    <name>GTPSR</name>
                    <description>General PWM Timer Stop Source Select Register</description>
                    <addressOffset>0x14</addressOffset>
                    <size>32</size>
                    <access>read-write</access>
                    <resetValue>0x00000000</resetValue>
                    <resetMask>0xffffffff</resetMask>
                    <fields>
                        <field>
                            <name>PSGTRGAR</name>
                            <description>GTETRGA Pin Rising Input Source Counter Stop Enable</description>
                            <lsb>0</lsb>
                            <msb>0</msb>
                            <access>read-write</access>
                            <enumeratedValues>
                                </enumeratedValues>
                        </field>
                        <field>
                            <name>PSGTRGAF</name>
                            <description>GTETRGA Pin Falling Input Source Counter Stop Enable</description>
                            <lsb>1</lsb>
                            <msb>1</msb>
                            <access>read-write</access>
                            <enumeratedValues>
                                </enumeratedValues>
                        </field>
                        <field>
                            <name>PSGTRGBR</name>
                            <description>GTETRGB Pin Rising Input Source Counter Stop Enable</description>
                            <lsb>2</lsb>
                            <msb>2</msb>
                            <access>read-write</access>
                            <enumeratedValues>
                                </enumeratedValues>
                        </field>
                        <field>
                            <name>PSGTRGBF</name>
                            <description>GTETRGB Pin Falling Input Source Counter Stop Enable</description>
                            <lsb>3</lsb>
                            <msb>3</msb>
                            <access>read-write</access>
                            <enumeratedValues>
                                </enumeratedValues>
                        </field>
                        <field>
                            <name>PSGTRGCR</name>
                            <description>GTETRGC Pin Rising Input Source Counter Stop Enable</description>
                            <lsb>4</lsb>
                            <msb>4</msb>
                            <access>read-write</access>
                            <enumeratedValues>
                                </enumeratedValues>
                        </field>
                        <field>
                            <name>PSGTRGCF</name>
                            <description>GTETRGC Pin Falling Input Source Counter Stop Enable</description>
                            <lsb>5</lsb>
                            <msb>5</msb>
                            <access>read-write</access>
                            <enumeratedValues>
                                </enumeratedValues>
                        </field>
                        <field>
                            <name>PSGTRGDR</name>
                            <description>GTETRGD Pin Rising Input Source Counter Stop Enable</description>
                            <lsb>6</lsb>
                            <msb>6</msb>
                            <access>read-write</access>
                            <enumeratedValues>
                                </enumeratedValues>
                        </field>
                        <field>
                            <name>PSGTRGDF</name>
                            <description>GTETRGD Pin Falling Input Source Counter Stop Enable</description>
                            <lsb>7</lsb>
                            <msb>7</msb>
                            <access>read-write</access>
                            <enumeratedValues>
                                </enumeratedValues>
                        </field>
                        <field>
                            <name>PSCARBL</name>
                            <description>GTIOCnA Pin Rising Input during GTIOCnB Value Low Source Counter Stop Enable</description>
                            <lsb>8</lsb>
                            <msb>8</msb>
                            <access>read-write</access>
                            <enumeratedValues>
                                </enumeratedValues>
                        </field>
                        <field>
                            <name>PSCARBH</name>
                            <description>GTIOCnA Pin Rising Input during GTIOCnB Value High Source Counter Stop Enable</description>
                            <lsb>9</lsb>
                            <msb>9</msb>
                            <access>read-write</access>
                            <enumeratedValues>
                                </enumeratedValues>
                        </field>
                        <field>
                            <name>PSCAFBL</name>
                            <description>GTIOCnA Pin Falling Input during GTIOCnB Value Low Source Counter Stop Enable</description>
                            <lsb>10</lsb>
                            <msb>10</msb>
                            <access>read-write</access>
                            <enumeratedValues>
                                </enumeratedValues>
                        </field>
                        <field>
                            <name>PSCAFBH</name>
                            <description>GTIOCnA Pin Falling Input during GTIOCnB Value High Source Counter Stop Enable</description>
                            <lsb>11</lsb>
                            <msb>11</msb>
                            <access>read-write</access>
                            <enumeratedValues>
                                </enumeratedValues>
                        </field>
                        <field>
                            <name>PSCBRAL</name>
                            <description>GTIOCnB Pin Rising Input during GTIOCnA Value Low Source Counter Stop Enable</description>
                            <lsb>12</lsb>
                            <msb>12</msb>
                            <access>read-write</access>
                            <enumeratedValues>
                                </enumeratedValues>
                        </field>
                        <field>
                            <name>PSCBRAH</name>
                            <description>GTIOCnB Pin Rising Input during GTIOCnA Value High Source Counter Stop Enable</description>
                            <lsb>13</lsb>
                            <msb>13</msb>
                            <access>read-write</access>
                            <enumeratedValues>
                                </enumeratedValues>
                        </field>
                        <field>
                            <name>PSCBFAL</name>
                            <description>GTIOCnB Pin Falling Input during GTIOCnA Value Low Source Counter Stop Enable</description>
                            <lsb>14</lsb>
                            <msb>14</msb>
                            <access>read-write</access>
                            <enumeratedValues>
                                </enumeratedValues>
                        </field>
                        <field>
                            <name>PSCBFAH</name>
                            <description>GTIOCnB Pin Falling Input during GTIOCnA Value High Source Counter Stop Enable</description>
                            <lsb>15</lsb>
                            <msb>15</msb>
                            <access>read-write</access>
                            <enumeratedValues>
                                </enumeratedValues>
                        </field>
                        <field>
                            <name>PSELCA</name>
                            <description>ELC_GPTA Event Source Counter Stop Enable</description>
                            <lsb>16</lsb>
                            <msb>16</msb>
                            <access>read-write</access>
                            <enumeratedValues>
                                </enumeratedValues>
                        </field>
                        <field>
                            <name>PSELCB</name>
                            <description>ELC_GPTB Event Source Counter Stop Enable</description>
                            <lsb>17</lsb>
                            <msb>17</msb>
                            <access>read-write</access>
                            <enumeratedValues>
                                </enumeratedValues>
                        </field>
                        <field>
                            <name>PSELCC</name>
                            <description>ELC_GPTC Event Source Counter Stop Enable</description>
                            <lsb>18</lsb>
                            <msb>18</msb>
                            <access>read-write</access>
                            <enumeratedValues>
                                </enumeratedValues>
                        </field>
                        <field>
                            <name>PSELCD</name>
                            <description>ELC_GPTD Event Source Counter Stop Enable</description>
                            <lsb>19</lsb>
                            <msb>19</msb>
                            <access>read-write</access>
                            <enumeratedValues>
                                </enumeratedValues>
                        </field>
                        <field>
                            <name>PSELCE</name>
                            <description>ELC_GPTE Event Source Counter Stop Enable</description>
                            <lsb>20</lsb>
                            <msb>20</msb>
                            <access>read-write</access>
                            <enumeratedValues>
                                </enumeratedValues>
                        </field>
                        <field>
                            <name>PSELCF</name>
                            <description>ELC_GPTF Event Source Counter Stop Enable</description>
                            <lsb>21</lsb>
                            <msb>21</msb>
                            <access>read-write</access>
                            <enumeratedValues>
                                </enumeratedValues>
                        </field>
                        <field>
                            <name>PSELCG</name>
                            <description>ELC_GPTG Event Source Counter Stop Enable</description>
                            <lsb>22</lsb>
                            <msb>22</msb>
                            <access>read-write</access>
                            <enumeratedValues>
                                </enumeratedValues>
                        </field>
                        <field>
                            <name>PSELCH</name>
                            <description>ELC_GPTH Event Source Counter Stop Enable</description>
                            <lsb>23</lsb>
                            <msb>23</msb>
                            <access>read-write</access>
                            <enumeratedValues>
                                </enumeratedValues>
                        </field>
                        <field>
                            <name>CSTOP</name>
                            <description>Software Source Counter Stop Enable</description>
                            <lsb>31</lsb>
                            <msb>31</msb>
                            <access>read-write</access>
                            <enumeratedValues>
                                </enumeratedValues>
                        </field>
                    </fields>
                </register>
                <register>
                    <name>GTCSR</name>
                    <description>General PWM Timer Clear Source Select Register</description>
                    <addressOffset>0x18</addressOffset>
                    <size>32</size>
                    <access>read-write</access>
                    <resetValue>0x00000000</resetValue>
                    <resetMask>0xffffffff</resetMask>
                    <fields>
                        <field>
                            <name>CSGTRGAR</name>
                            <description>GTETRGA Pin Rising Input Source Counter Clear Enable</description>
                            <lsb>0</lsb>
                            <msb>0</msb>
                            <access>read-write</access>
                            <enumeratedValues>
                                </enumeratedValues>
                        </field>
                        <field>
                            <name>CSGTRGAF</name>
                            <description>GTETRGA Pin Falling Input Source Counter Clear Enable</description>
                            <lsb>1</lsb>
                            <msb>1</msb>
                            <access>read-write</access>
                            <enumeratedValues>
                                </enumeratedValues>
                        </field>
                        <field>
                            <name>CSGTRGBR</name>
                            <description>GTETRGB Pin Rising Input Source Counter Clear Enable</description>
                            <lsb>2</lsb>
                            <msb>2</msb>
                            <access>read-write</access>
                            <enumeratedValues>
                                </enumeratedValues>
                        </field>
                        <field>
                            <name>CSGTRGBF</name>
                            <description>GTETRGB Pin Falling Input Source Counter Clear Enable</description>
                            <lsb>3</lsb>
                            <msb>3</msb>
                            <access>read-write</access>
                            <enumeratedValues>
                                </enumeratedValues>
                        </field>
                        <field>
                            <name>CSGTRGCR</name>
                            <description>GTETRGC Pin Rising Input Source Counter Clear Enable</description>
                            <lsb>4</lsb>
                            <msb>4</msb>
                            <access>read-write</access>
                            <enumeratedValues>
                                </enumeratedValues>
                        </field>
                        <field>
                            <name>CSGTRGCF</name>
                            <description>GTETRGC Pin Falling Input Source Counter Clear Enable</description>
                            <lsb>5</lsb>
                            <msb>5</msb>
                            <access>read-write</access>
                            <enumeratedValues>
                                </enumeratedValues>
                        </field>
                        <field>
                            <name>CSGTRGDR</name>
                            <description>GTETRGD Pin Rising Input Source Counter Clear Enable</description>
                            <lsb>6</lsb>
                            <msb>6</msb>
                            <access>read-write</access>
                            <enumeratedValues>
                                </enumeratedValues>
                        </field>
                        <field>
                            <name>CSGTRGDF</name>
                            <description>GTETRGD Pin Falling Input Source Counter Clear Enable</description>
                            <lsb>7</lsb>
                            <msb>7</msb>
                            <access>read-write</access>
                            <enumeratedValues>
                                </enumeratedValues>
                        </field>
                        <field>
                            <name>CSCARBL</name>
                            <description>GTIOCnA Pin Rising Input during GTIOCnB Value Low Source Counter Clear Enable</description>
                            <lsb>8</lsb>
                            <msb>8</msb>
                            <access>read-write</access>
                            <enumeratedValues>
                                </enumeratedValues>
                        </field>
                        <field>
                            <name>CSCARBH</name>
                            <description>GTIOCnA Pin Rising Input during GTIOCnB Value High Source Counter Clear Enable</description>
                            <lsb>9</lsb>
                            <msb>9</msb>
                            <access>read-write</access>
                            <enumeratedValues>
                                </enumeratedValues>
                        </field>
                        <field>
                            <name>CSCAFBL</name>
                            <description>GTIOCnA Pin Falling Input during GTIOCnB Value Low Source Counter Clear Enable</description>
                            <lsb>10</lsb>
                            <msb>10</msb>
                            <access>read-write</access>
                            <enumeratedValues>
                                </enumeratedValues>
                        </field>
                        <field>
                            <name>CSCAFBH</name>
                            <description>GTIOCnA Pin Falling Input during GTIOCnB Value High Source Counter Clear Enable</description>
                            <lsb>11</lsb>
                            <msb>11</msb>
                            <access>read-write</access>
                            <enumeratedValues>
                                </enumeratedValues>
                        </field>
                        <field>
                            <name>CSCBRAL</name>
                            <description>GTIOCnB Pin Rising Input during GTIOCnA Value Low Source Counter Clear Enable</description>
                            <lsb>12</lsb>
                            <msb>12</msb>
                            <access>read-write</access>
                            <enumeratedValues>
                                </enumeratedValues>
                        </field>
                        <field>
                            <name>CSCBRAH</name>
                            <description>GTIOCnB Pin Rising Input during GTIOCnA Value High Source Counter Clear Enable</description>
                            <lsb>13</lsb>
                            <msb>13</msb>
                            <access>read-write</access>
                            <enumeratedValues>
                                </enumeratedValues>
                        </field>
                        <field>
                            <name>CSCBFAL</name>
                            <description>GTIOCnB Pin Falling Input during GTIOCnA Value Low Source Counter Clear Enable</description>
                            <lsb>14</lsb>
                            <msb>14</msb>
                            <access>read-write</access>
                            <enumeratedValues>
                                </enumeratedValues>
                        </field>
                        <field>
                            <name>CSCBFAH</name>
                            <description>GTIOCnB Pin Falling Input during GTIOCnA Value High Source Counter Clear Enable</description>
                            <lsb>15</lsb>
                            <msb>15</msb>
                            <access>read-write</access>
                            <enumeratedValues>
                                </enumeratedValues>
                        </field>
                        <field>
                            <name>CSELCA</name>
                            <description>ELC_GPTA Event Source Counter Clear Enable</description>
                            <lsb>16</lsb>
                            <msb>16</msb>
                            <access>read-write</access>
                            <enumeratedValues>
                                </enumeratedValues>
                        </field>
                        <field>
                            <name>CSELCB</name>
                            <description>ELC_GPTB Event Source Counter Clear Enable</description>
                            <lsb>17</lsb>
                            <msb>17</msb>
                            <access>read-write</access>
                            <enumeratedValues>
                                </enumeratedValues>
                        </field>
                        <field>
                            <name>CSELCC</name>
                            <description>ELC_GPTC Event Source Counter Clear Enable</description>
                            <lsb>18</lsb>
                            <msb>18</msb>
                            <access>read-write</access>
                            <enumeratedValues>
                                </enumeratedValues>
                        </field>
                        <field>
                            <name>CSELCD</name>
                            <description>ELC_GPTD Event Source Counter Clear Enable</description>
                            <lsb>19</lsb>
                            <msb>19</msb>
                            <access>read-write</access>
                            <enumeratedValues>
                                </enumeratedValues>
                        </field>
                        <field>
                            <name>CSELCE</name>
                            <description>ELC_GPTE Event Source Counter Clear Enable</description>
                            <lsb>20</lsb>
                            <msb>20</msb>
                            <access>read-write</access>
                            <enumeratedValues>
                                </enumeratedValues>
                        </field>
                        <field>
                            <name>CSELCF</name>
                            <description>ELC_GPTF Event Source Counter Clear Enable</description>
                            <lsb>21</lsb>
                            <msb>21</msb>
                            <access>read-write</access>
                            <enumeratedValues>
                                </enumeratedValues>
                        </field>
                        <field>
                            <name>CSELCG</name>
                            <description>ELC_GPTG Event Source Counter Clear Enable</description>
                            <lsb>22</lsb>
                            <msb>22</msb>
                            <access>read-write</access>
                            <enumeratedValues>
                                </enumeratedValues>
                        </field>
                        <field>
                            <name>CSELCH</name>
                            <description>ELC_GPTH Event Source Counter Clear Enable</description>
                            <lsb>23</lsb>
                            <msb>23</msb>
                            <access>read-write</access>
                            <enumeratedValues>
                                </enumeratedValues>
                        </field>
                        <field>
                            <name>CCLR</name>
                            <description>Software Source Counter Clear Enable</description>
                            <lsb>31</lsb>
                            <msb>31</msb>
                            <access>read-write</access>
                            <enumeratedValues>
                                </enumeratedValues>
                        </field>
                    </fields>
                </register>
                <register>
                    <name>GTUPSR</name>
                    <description>General PWM Timer Up Count Source Select Register</description>
                    <addressOffset>0x1C</addressOffset>
                    <size>32</size>
                    <access>read-write</access>
                    <resetValue>0x00000000</resetValue>
                    <resetMask>0xffffffff</resetMask>
                    <fields>
                        <field>
                            <name>USGTRGAR</name>
                            <description>GTETRGA Pin Rising Input Source Counter Count Up Enable</description>
                            <lsb>0</lsb>
                            <msb>0</msb>
                            <access>read-write</access>
                            <enumeratedValues>
                                </enumeratedValues>
                        </field>
                        <field>
                            <name>USGTRGAF</name>
                            <description>GTETRGA Pin Falling Input Source Counter Count Up Enable</description>
                            <lsb>1</lsb>
                            <msb>1</msb>
                            <access>read-write</access>
                            <enumeratedValues>
                                </enumeratedValues>
                        </field>
                        <field>
                            <name>USGTRGBR</name>
                            <description>GTETRGB Pin Rising Input Source Counter Count Up Enable</description>
                            <lsb>2</lsb>
                            <msb>2</msb>
                            <access>read-write</access>
                            <enumeratedValues>
                                </enumeratedValues>
                        </field>
                        <field>
                            <name>USGTRGBF</name>
                            <description>GTETRGB Pin Falling Input Source Counter Count Up Enable</description>
                            <lsb>3</lsb>
                            <msb>3</msb>
                            <access>read-write</access>
                            <enumeratedValues>
                                </enumeratedValues>
                        </field>
                        <field>
                            <name>USGTRGCR</name>
                            <description>GTETRGC Pin Rising Input Source Counter Count Up Enable</description>
                            <lsb>4</lsb>
                            <msb>4</msb>
                            <access>read-write</access>
                            <enumeratedValues>
                                </enumeratedValues>
                        </field>
                        <field>
                            <name>USGTRGCF</name>
                            <description>GTETRGC Pin Falling Input Source Counter Count Up Enable</description>
                            <lsb>5</lsb>
                            <msb>5</msb>
                            <access>read-write</access>
                            <enumeratedValues>
                                </enumeratedValues>
                        </field>
                        <field>
                            <name>USGTRGDR</name>
                            <description>GTETRGD Pin Rising Input Source Counter Count Up Enable</description>
                            <lsb>6</lsb>
                            <msb>6</msb>
                            <access>read-write</access>
                            <enumeratedValues>
                                </enumeratedValues>
                        </field>
                        <field>
                            <name>USGTRGDF</name>
                            <description>GTETRGD Pin Falling Input Source Counter Count Up Enable</description>
                            <lsb>7</lsb>
                            <msb>7</msb>
                            <access>read-write</access>
                            <enumeratedValues>
                                </enumeratedValues>
                        </field>
                        <field>
                            <name>USCARBL</name>
                            <description>GTIOCnA Pin Rising Input during GTIOCnB Value Low Source Counter Count Up Enable</description>
                            <lsb>8</lsb>
                            <msb>8</msb>
                            <access>read-write</access>
                            <enumeratedValues>
                                </enumeratedValues>
                        </field>
                        <field>
                            <name>USCARBH</name>
                            <description>GTIOCnA Pin Rising Input during GTIOCnB Value High Source Counter Count Up Enable</description>
                            <lsb>9</lsb>
                            <msb>9</msb>
                            <access>read-write</access>
                            <enumeratedValues>
                                </enumeratedValues>
                        </field>
                        <field>
                            <name>USCAFBL</name>
                            <description>GTIOCnA Pin Falling Input during GTIOCnB Value Low Source Counter Count Up Enable</description>
                            <lsb>10</lsb>
                            <msb>10</msb>
                            <access>read-write</access>
                            <enumeratedValues>
                                </enumeratedValues>
                        </field>
                        <field>
                            <name>USCAFBH</name>
                            <description>GTIOCnA Pin Falling Input during GTIOCnB Value High Source Counter Count Up Enable</description>
                            <lsb>11</lsb>
                            <msb>11</msb>
                            <access>read-write</access>
                            <enumeratedValues>
                                </enumeratedValues>
                        </field>
                        <field>
                            <name>USCBRAL</name>
                            <description>GTIOCnB Pin Rising Input during GTIOCnA Value Low Source Counter Count Up Enable</description>
                            <lsb>12</lsb>
                            <msb>12</msb>
                            <access>read-write</access>
                            <enumeratedValues>
                                </enumeratedValues>
                        </field>
                        <field>
                            <name>USCBRAH</name>
                            <description>GTIOCnB Pin Rising Input during GTIOCnA Value High Source Counter Count Up Enable</description>
                            <lsb>13</lsb>
                            <msb>13</msb>
                            <access>read-write</access>
                            <enumeratedValues>
                                </enumeratedValues>
                        </field>
                        <field>
                            <name>USCBFAL</name>
                            <description>GTIOCnB Pin Falling Input during GTIOCnA Value Low Source Counter Count Up Enable</description>
                            <lsb>14</lsb>
                            <msb>14</msb>
                            <access>read-write</access>
                            <enumeratedValues>
                                </enumeratedValues>
                        </field>
                        <field>
                            <name>USCBFAH</name>
                            <description>GTIOCnB Pin Falling Input during GTIOCnA Value High Source Counter Count Up Enable</description>
                            <lsb>15</lsb>
                            <msb>15</msb>
                            <access>read-write</access>
                            <enumeratedValues>
                                </enumeratedValues>
                        </field>
                        <field>
                            <name>USELCA</name>
                            <description>ELC_GPTA Event Source Counter Count Up Enable</description>
                            <lsb>16</lsb>
                            <msb>16</msb>
                            <access>read-write</access>
                            <enumeratedValues>
                                </enumeratedValues>
                        </field>
                        <field>
                            <name>USELCB</name>
                            <description>ELC_GPTB Event Source Counter Count Up Enable</description>
                            <lsb>17</lsb>
                            <msb>17</msb>
                            <access>read-write</access>
                            <enumeratedValues>
                                </enumeratedValues>
                        </field>
                        <field>
                            <name>USELCC</name>
                            <description>ELC_GPTC Event Source Counter Count Up Enable</description>
                            <lsb>18</lsb>
                            <msb>18</msb>
                            <access>read-write</access>
                            <enumeratedValues>
                                </enumeratedValues>
                        </field>
                        <field>
                            <name>USELCD</name>
                            <description>ELC_GPTD Event Source Counter Count Up Enable</description>
                            <lsb>19</lsb>
                            <msb>19</msb>
                            <access>read-write</access>
                            <enumeratedValues>
                                </enumeratedValues>
                        </field>
                        <field>
                            <name>USELCE</name>
                            <description>ELC_GPTE Event Source Counter Count Up Enable</description>
                            <lsb>20</lsb>
                            <msb>20</msb>
                            <access>read-write</access>
                            <enumeratedValues>
                                </enumeratedValues>
                        </field>
                        <field>
                            <name>USELCF</name>
                            <description>ELC_GPTF Event Source Counter Count Up Enable</description>
                            <lsb>21</lsb>
                            <msb>21</msb>
                            <access>read-write</access>
                            <enumeratedValues>
                                </enumeratedValues>
                        </field>
                        <field>
                            <name>USELCG</name>
                            <description>ELC_GPTG Event Source Counter Count Up Enable</description>
                            <lsb>22</lsb>
                            <msb>22</msb>
                            <access>read-write</access>
                            <enumeratedValues>
                                </enumeratedValues>
                        </field>
                        <field>
                            <name>USELCH</name>
                            <description>ELC_GPTH Event Source Counter Count Up Enable</description>
                            <lsb>23</lsb>
                            <msb>23</msb>
                            <access>read-write</access>
                            <enumeratedValues>
                                </enumeratedValues>
                        </field>
                    </fields>
                </register>
                <register>
                    <name>GTDNSR</name>
                    <description>General PWM Timer Down Count Source Select Register</description>
                    <addressOffset>0x20</addressOffset>
                    <size>32</size>
                    <access>read-write</access>
                    <resetValue>0x00000000</resetValue>
                    <resetMask>0xffffffff</resetMask>
                    <fields>
                        <field>
                            <name>DSGTRGAR</name>
                            <description>GTETRGA Pin Rising Input Source Counter Count Down Enable</description>
                            <lsb>0</lsb>
                            <msb>0</msb>
                            <access>read-write</access>
                            <enumeratedValues>
                                </enumeratedValues>
                        </field>
                        <field>
                            <name>DSGTRGAF</name>
                            <description>GTETRGA Pin Falling Input Source Counter Count Down Enable</description>
                            <lsb>1</lsb>
                            <msb>1</msb>
                            <access>read-write</access>
                            <enumeratedValues>
                                </enumeratedValues>
                        </field>
                        <field>
                            <name>DSGTRGBR</name>
                            <description>GTETRGB Pin Rising Input Source Counter Count Down Enable</description>
                            <lsb>2</lsb>
                            <msb>2</msb>
                            <access>read-write</access>
                            <enumeratedValues>
                                </enumeratedValues>
                        </field>
                        <field>
                            <name>DSGTRGBF</name>
                            <description>GTETRGB Pin Falling Input Source Counter Count Down Enable</description>
                            <lsb>3</lsb>
                            <msb>3</msb>
                            <access>read-write</access>
                            <enumeratedValues>
                                </enumeratedValues>
                        </field>
                        <field>
                            <name>DSGTRGCR</name>
                            <description>GTETRGC Pin Rising Input Source Counter Count Down Enable</description>
                            <lsb>4</lsb>
                            <msb>4</msb>
                            <access>read-write</access>
                            <enumeratedValues>
                                </enumeratedValues>
                        </field>
                        <field>
                            <name>DSGTRGCF</name>
                            <description>GTETRGC Pin Falling Input Source Counter Count Down Enable</description>
                            <lsb>5</lsb>
                            <msb>5</msb>
                            <access>read-write</access>
                            <enumeratedValues>
                                </enumeratedValues>
                        </field>
                        <field>
                            <name>DSGTRGDR</name>
                            <description>GTETRGD Pin Rising Input Source Counter Count Down Enable</description>
                            <lsb>6</lsb>
                            <msb>6</msb>
                            <access>read-write</access>
                            <enumeratedValues>
                                </enumeratedValues>
                        </field>
                        <field>
                            <name>DSGTRGDF</name>
                            <description>GTETRGD Pin Falling Input Source Counter Count Down Enable</description>
                            <lsb>7</lsb>
                            <msb>7</msb>
                            <access>read-write</access>
                            <enumeratedValues>
                                </enumeratedValues>
                        </field>
                        <field>
                            <name>DSCARBL</name>
                            <description>GTIOCnA Pin Rising Input during GTIOCnB Value Low Source Counter Count Down Enable</description>
                            <lsb>8</lsb>
                            <msb>8</msb>
                            <access>read-write</access>
                            <enumeratedValues>
                                </enumeratedValues>
                        </field>
                        <field>
                            <name>DSCARBH</name>
                            <description>GTIOCnA Pin Rising Input during GTIOCnB Value High Source Counter Count Down Enable</description>
                            <lsb>9</lsb>
                            <msb>9</msb>
                            <access>read-write</access>
                            <enumeratedValues>
                                </enumeratedValues>
                        </field>
                        <field>
                            <name>DSCAFBL</name>
                            <description>GTIOCnA Pin Falling Input during GTIOCnB Value Low Source Counter Count Down Enable</description>
                            <lsb>10</lsb>
                            <msb>10</msb>
                            <access>read-write</access>
                            <enumeratedValues>
                                </enumeratedValues>
                        </field>
                        <field>
                            <name>DSCAFBH</name>
                            <description>GTIOCnA Pin Falling Input during GTIOCnB Value High Source Counter Count Down Enable</description>
                            <lsb>11</lsb>
                            <msb>11</msb>
                            <access>read-write</access>
                            <enumeratedValues>
                                </enumeratedValues>
                        </field>
                        <field>
                            <name>DSCBRAL</name>
                            <description>GTIOCnB Pin Rising Input during GTIOCnA Value Low Source Counter Count Down Enable</description>
                            <lsb>12</lsb>
                            <msb>12</msb>
                            <access>read-write</access>
                            <enumeratedValues>
                                </enumeratedValues>
                        </field>
                        <field>
                            <name>DSCBRAH</name>
                            <description>GTIOCnB Pin Rising Input during GTIOCnA Value High Source Counter Count Down Enable</description>
                            <lsb>13</lsb>
                            <msb>13</msb>
                            <access>read-write</access>
                            <enumeratedValues>
                                </enumeratedValues>
                        </field>
                        <field>
                            <name>DSCBFAL</name>
                            <description>GTIOCnB Pin Falling Input during GTIOCnA Value Low Source Counter Count Down Enable</description>
                            <lsb>14</lsb>
                            <msb>14</msb>
                            <access>read-write</access>
                            <enumeratedValues>
                                </enumeratedValues>
                        </field>
                        <field>
                            <name>DSCBFAH</name>
                            <description>GTIOCnB Pin Falling Input during GTIOCnA Value High Source Counter Count Down Enable</description>
                            <lsb>15</lsb>
                            <msb>15</msb>
                            <access>read-write</access>
                            <enumeratedValues>
                                </enumeratedValues>
                        </field>
                        <field>
                            <name>DSELCA</name>
                            <description>ELC_GPTA Event Source Counter Count Down Enable</description>
                            <lsb>16</lsb>
                            <msb>16</msb>
                            <access>read-write</access>
                            <enumeratedValues>
                                </enumeratedValues>
                        </field>
                        <field>
                            <name>DSELCB</name>
                            <description>ELC_GPTB Event Source Counter Count Down Enable</description>
                            <lsb>17</lsb>
                            <msb>17</msb>
                            <access>read-write</access>
                            <enumeratedValues>
                                </enumeratedValues>
                        </field>
                        <field>
                            <name>DSELCC</name>
                            <description>ELC_GPTC Event Source Counter Count Down Enable</description>
                            <lsb>18</lsb>
                            <msb>18</msb>
                            <access>read-write</access>
                            <enumeratedValues>
                                </enumeratedValues>
                        </field>
                        <field>
                            <name>DSELCD</name>
                            <description>ELC_GPTD Event Source Counter Count Down Enable</description>
                            <lsb>19</lsb>
                            <msb>19</msb>
                            <access>read-write</access>
                            <enumeratedValues>
                                </enumeratedValues>
                        </field>
                        <field>
                            <name>DSELCE</name>
                            <description>ELC_GPTE Event Source Counter Count Down Enable</description>
                            <lsb>20</lsb>
                            <msb>20</msb>
                            <access>read-write</access>
                            <enumeratedValues>
                                </enumeratedValues>
                        </field>
                        <field>
                            <name>DSELCF</name>
                            <description>ELC_GPTF Event Source Counter Count Down Enable</description>
                            <lsb>21</lsb>
                            <msb>21</msb>
                            <access>read-write</access>
                            <enumeratedValues>
                                </enumeratedValues>
                        </field>
                        <field>
                            <name>DSELCG</name>
                            <description>ELC_GPTG Event Source Counter Count Down Enable</description>
                            <lsb>22</lsb>
                            <msb>22</msb>
                            <access>read-write</access>
                            <enumeratedValues>
                                </enumeratedValues>
                        </field>
                        <field>
                            <name>DSELCH</name>
                            <description>ELC_GPTF Event Source Counter Count Down Enable</description>
                            <lsb>23</lsb>
                            <msb>23</msb>
                            <access>read-write</access>
                            <enumeratedValues>
                                </enumeratedValues>
                        </field>
                    </fields>
                </register>
                <register>
                    <name>GTICASR</name>
                    <description>General PWM Timer Input Capture Source Select Register A</description>
                    <addressOffset>0x24</addressOffset>
                    <size>32</size>
                    <access>read-write</access>
                    <resetValue>0x00000000</resetValue>
                    <resetMask>0xffffffff</resetMask>
                    <fields>
                        <field>
                            <name>ASGTRGAR</name>
                            <description>GTETRGA Pin Rising Input Source GTCCRA Input Capture Enable</description>
                            <lsb>0</lsb>
                            <msb>0</msb>
                            <access>read-write</access>
                            <enumeratedValues>
                                </enumeratedValues>
                        </field>
                        <field>
                            <name>ASGTRGAF</name>
                            <description>GTETRGA Pin Falling Input Source GTCCRA Input Capture Enable</description>
                            <lsb>1</lsb>
                            <msb>1</msb>
                            <access>read-write</access>
                            <enumeratedValues>
                                </enumeratedValues>
                        </field>
                        <field>
                            <name>ASGTRGBR</name>
                            <description>GTETRGB Pin Rising Input Source GTCCRA Input Capture Enable</description>
                            <lsb>2</lsb>
                            <msb>2</msb>
                            <access>read-write</access>
                            <enumeratedValues>
                                </enumeratedValues>
                        </field>
                        <field>
                            <name>ASGTRGBF</name>
                            <description>GTETRGB Pin Falling Input Source GTCCRA Input Capture Enable</description>
                            <lsb>3</lsb>
                            <msb>3</msb>
                            <access>read-write</access>
                            <enumeratedValues>
                                </enumeratedValues>
                        </field>
                        <field>
                            <name>ASGTRGCR</name>
                            <description>GTETRGC Pin Rising Input Source GTCCRA Input Capture Enable</description>
                            <lsb>4</lsb>
                            <msb>4</msb>
                            <access>read-write</access>
                            <enumeratedValues>
                                </enumeratedValues>
                        </field>
                        <field>
                            <name>ASGTRGCF</name>
                            <description>GTETRGC Pin Falling Input Source GTCCRA Input Capture Enable</description>
                            <lsb>5</lsb>
                            <msb>5</msb>
                            <access>read-write</access>
                            <enumeratedValues>
                                </enumeratedValues>
                        </field>
                        <field>
                            <name>ASGTRGDR</name>
                            <description>GTETRGD Pin Rising Input Source GTCCRA Input Capture Enable</description>
                            <lsb>6</lsb>
                            <msb>6</msb>
                            <access>read-write</access>
                            <enumeratedValues>
                                </enumeratedValues>
                        </field>
                        <field>
                            <name>ASGTRGDF</name>
                            <description>GTETRGD Pin Falling Input Source GTCCRA Input Capture Enable</description>
                            <lsb>7</lsb>
                            <msb>7</msb>
                            <access>read-write</access>
                            <enumeratedValues>
                                </enumeratedValues>
                        </field>
                        <field>
                            <name>ASCARBL</name>
                            <description>GTIOCnA Pin Rising Input during GTIOCnB Value Low Source GTCCRA Input Capture Enable</description>
                            <lsb>8</lsb>
                            <msb>8</msb>
                            <access>read-write</access>
                            <enumeratedValues>
                                </enumeratedValues>
                        </field>
                        <field>
                            <name>ASCARBH</name>
                            <description>GTIOCnA Pin Rising Input during GTIOCnB Value High Source GTCCRA Input Capture Enable</description>
                            <lsb>9</lsb>
                            <msb>9</msb>
                            <access>read-write</access>
                            <enumeratedValues>
                                </enumeratedValues>
                        </field>
                        <field>
                            <name>ASCAFBL</name>
                            <description>GTIOCnA Pin Falling Input during GTIOCnB Value Low Source GTCCRA Input Capture Enable</description>
                            <lsb>10</lsb>
                            <msb>10</msb>
                            <access>read-write</access>
                            <enumeratedValues>
                                </enumeratedValues>
                        </field>
                        <field>
                            <name>ASCAFBH</name>
                            <description>GTIOCnA Pin Falling Input during GTIOCnB Value High Source GTCCRA Input Capture Enable</description>
                            <lsb>11</lsb>
                            <msb>11</msb>
                            <access>read-write</access>
                            <enumeratedValues>
                                </enumeratedValues>
                        </field>
                        <field>
                            <name>ASCBRAL</name>
                            <description>GTIOCnB Pin Rising Input during GTIOCnA Value Low Source GTCCRA Input Capture Enable</description>
                            <lsb>12</lsb>
                            <msb>12</msb>
                            <access>read-write</access>
                            <enumeratedValues>
                                </enumeratedValues>
                        </field>
                        <field>
                            <name>ASCBRAH</name>
                            <description>GTIOCnB Pin Rising Input during GTIOCnA Value High Source GTCCRA Input Capture Enable</description>
                            <lsb>13</lsb>
                            <msb>13</msb>
                            <access>read-write</access>
                            <enumeratedValues>
                                </enumeratedValues>
                        </field>
                        <field>
                            <name>ASCBFAL</name>
                            <description>GTIOCnB Pin Falling Input during GTIOCnA Value Low Source GTCCRA Input Capture Enable</description>
                            <lsb>14</lsb>
                            <msb>14</msb>
                            <access>read-write</access>
                            <enumeratedValues>
                                </enumeratedValues>
                        </field>
                        <field>
                            <name>ASCBFAH</name>
                            <description>GTIOCnB Pin Falling Input during GTIOCnA Value High Source GTCCRA Input Capture Enable</description>
                            <lsb>15</lsb>
                            <msb>15</msb>
                            <access>read-write</access>
                            <enumeratedValues>
                                </enumeratedValues>
                        </field>
                        <field>
                            <name>ASELCA</name>
                            <description>ELC_GPTA Event Source GTCCRA Input Capture Enable</description>
                            <lsb>16</lsb>
                            <msb>16</msb>
                            <access>read-write</access>
                            <enumeratedValues>
                                </enumeratedValues>
                        </field>
                        <field>
                            <name>ASELCB</name>
                            <description>ELC_GPTB Event Source GTCCRA Input Capture Enable</description>
                            <lsb>17</lsb>
                            <msb>17</msb>
                            <access>read-write</access>
                            <enumeratedValues>
                                </enumeratedValues>
                        </field>
                        <field>
                            <name>ASELCC</name>
                            <description>ELC_GPTC Event Source GTCCRA Input Capture Enable</description>
                            <lsb>18</lsb>
                            <msb>18</msb>
                            <access>read-write</access>
                            <enumeratedValues>
                                </enumeratedValues>
                        </field>
                        <field>
                            <name>ASELCD</name>
                            <description>ELC_GPTD Event Source GTCCRA Input Capture Enable</description>
                            <lsb>19</lsb>
                            <msb>19</msb>
                            <access>read-write</access>
                            <enumeratedValues>
                                </enumeratedValues>
                        </field>
                        <field>
                            <name>ASELCE</name>
                            <description>ELC_GPTE Event Source GTCCRA Input Capture Enable</description>
                            <lsb>20</lsb>
                            <msb>20</msb>
                            <access>read-write</access>
                            <enumeratedValues>
                                </enumeratedValues>
                        </field>
                        <field>
                            <name>ASELCF</name>
                            <description>ELC_GPTF Event Source GTCCRA Input Capture Enable</description>
                            <lsb>21</lsb>
                            <msb>21</msb>
                            <access>read-write</access>
                            <enumeratedValues>
                                </enumeratedValues>
                        </field>
                        <field>
                            <name>ASELCG</name>
                            <description>ELC_GPTG Event Source GTCCRA Input Capture Enable</description>
                            <lsb>22</lsb>
                            <msb>22</msb>
                            <access>read-write</access>
                            <enumeratedValues>
                                </enumeratedValues>
                        </field>
                        <field>
                            <name>ASELCH</name>
                            <description>ELC_GPTH Event Source GTCCRA Input Capture Enable</description>
                            <lsb>23</lsb>
                            <msb>23</msb>
                            <access>read-write</access>
                            <enumeratedValues>
                                </enumeratedValues>
                        </field>
                    </fields>
                </register>
                <register>
                    <name>GTICBSR</name>
                    <description>General PWM Timer Input Capture Source Select Register B</description>
                    <addressOffset>0x28</addressOffset>
                    <size>32</size>
                    <access>read-write</access>
                    <resetValue>0x00000000</resetValue>
                    <resetMask>0xffffffff</resetMask>
                    <fields>
                        <field>
                            <name>BSGTRGAR</name>
                            <description>GTETRGA Pin Rising Input Source GTCCRB Input Capture Enable</description>
                            <lsb>0</lsb>
                            <msb>0</msb>
                            <access>read-write</access>
                            <enumeratedValues>
                                </enumeratedValues>
                        </field>
                        <field>
                            <name>BSGTRGAF</name>
                            <description>GTETRGA Pin Falling Input Source GTCCRB Input Capture Enable</description>
                            <lsb>1</lsb>
                            <msb>1</msb>
                            <access>read-write</access>
                            <enumeratedValues>
                                </enumeratedValues>
                        </field>
                        <field>
                            <name>BSGTRGBR</name>
                            <description>GTETRGB Pin Rising Input Source GTCCRB Input Capture Enable</description>
                            <lsb>2</lsb>
                            <msb>2</msb>
                            <access>read-write</access>
                            <enumeratedValues>
                                </enumeratedValues>
                        </field>
                        <field>
                            <name>BSGTRGBF</name>
                            <description>GTETRGB Pin Falling Input Source GTCCRB Input Capture Enable</description>
                            <lsb>3</lsb>
                            <msb>3</msb>
                            <access>read-write</access>
                            <enumeratedValues>
                                </enumeratedValues>
                        </field>
                        <field>
                            <name>BSGTRGCR</name>
                            <description>GTETRGC Pin Rising Input Source GTCCRB Input Capture Enable</description>
                            <lsb>4</lsb>
                            <msb>4</msb>
                            <access>read-write</access>
                            <enumeratedValues>
                                </enumeratedValues>
                        </field>
                        <field>
                            <name>BSGTRGCF</name>
                            <description>GTETRGC Pin Falling Input Source GTCCRB Input Capture Enable</description>
                            <lsb>5</lsb>
                            <msb>5</msb>
                            <access>read-write</access>
                            <enumeratedValues>
                                </enumeratedValues>
                        </field>
                        <field>
                            <name>BSGTRGDR</name>
                            <description>GTETRGD Pin Rising Input Source GTCCRB Input Capture Enable</description>
                            <lsb>6</lsb>
                            <msb>6</msb>
                            <access>read-write</access>
                            <enumeratedValues>
                                </enumeratedValues>
                        </field>
                        <field>
                            <name>BSGTRGDF</name>
                            <description>GTETRGD Pin Falling Input Source GTCCRB Input Capture Enable</description>
                            <lsb>7</lsb>
                            <msb>7</msb>
                            <access>read-write</access>
                            <enumeratedValues>
                                </enumeratedValues>
                        </field>
                        <field>
                            <name>BSCARBL</name>
                            <description>GTIOCnA Pin Rising Input during GTIOCnB Value Low Source GTCCRB Input Capture Enable</description>
                            <lsb>8</lsb>
                            <msb>8</msb>
                            <access>read-write</access>
                            <enumeratedValues>
                                </enumeratedValues>
                        </field>
                        <field>
                            <name>BSCARBH</name>
                            <description>GTIOCnA Pin Rising Input during GTIOCnB Value High Source GTCCRB Input Capture Enable</description>
                            <lsb>9</lsb>
                            <msb>9</msb>
                            <access>read-write</access>
                            <enumeratedValues>
                                </enumeratedValues>
                        </field>
                        <field>
                            <name>BSCAFBL</name>
                            <description>GTIOCnA Pin Falling Input during GTIOCnB Value Low Source GTCCRB Input Capture Enable</description>
                            <lsb>10</lsb>
                            <msb>10</msb>
                            <access>read-write</access>
                            <enumeratedValues>
                                </enumeratedValues>
                        </field>
                        <field>
                            <name>BSCAFBH</name>
                            <description>GTIOCnA Pin Falling Input during GTIOCnB Value High Source GTCCRB Input Capture Enable</description>
                            <lsb>11</lsb>
                            <msb>11</msb>
                            <access>read-write</access>
                            <enumeratedValues>
                                </enumeratedValues>
                        </field>
                        <field>
                            <name>BSCBRAL</name>
                            <description>GTIOCnB Pin Rising Input during GTIOCnA Value Low Source GTCCRB Input Capture Enable</description>
                            <lsb>12</lsb>
                            <msb>12</msb>
                            <access>read-write</access>
                            <enumeratedValues>
                                </enumeratedValues>
                        </field>
                        <field>
                            <name>BSCBRAH</name>
                            <description>GTIOCnB Pin Rising Input during GTIOCnA Value High Source GTCCRB Input Capture Enable</description>
                            <lsb>13</lsb>
                            <msb>13</msb>
                            <access>read-write</access>
                            <enumeratedValues>
                                </enumeratedValues>
                        </field>
                        <field>
                            <name>BSCBFAL</name>
                            <description>GTIOCnB Pin Falling Input during GTIOCnA Value Low Source GTCCRB Input Capture Enable</description>
                            <lsb>14</lsb>
                            <msb>14</msb>
                            <access>read-write</access>
                            <enumeratedValues>
                                </enumeratedValues>
                        </field>
                        <field>
                            <name>BSCBFAH</name>
                            <description>GTIOCnB Pin Falling Input during GTIOCnA Value High Source GTCCRB Input Capture Enable</description>
                            <lsb>15</lsb>
                            <msb>15</msb>
                            <access>read-write</access>
                            <enumeratedValues>
                                </enumeratedValues>
                        </field>
                        <field>
                            <name>BSELCA</name>
                            <description>ELC_GPTA Event Source GTCCRB Input Capture Enable</description>
                            <lsb>16</lsb>
                            <msb>16</msb>
                            <access>read-write</access>
                            <enumeratedValues>
                                </enumeratedValues>
                        </field>
                        <field>
                            <name>BSELCB</name>
                            <description>ELC_GPTB Event Source GTCCRB Input Capture Enable</description>
                            <lsb>17</lsb>
                            <msb>17</msb>
                            <access>read-write</access>
                            <enumeratedValues>
                                </enumeratedValues>
                        </field>
                        <field>
                            <name>BSELCC</name>
                            <description>ELC_GPTC Event Source GTCCRB Input Capture Enable</description>
                            <lsb>18</lsb>
                            <msb>18</msb>
                            <access>read-write</access>
                            <enumeratedValues>
                                </enumeratedValues>
                        </field>
                        <field>
                            <name>BSELCD</name>
                            <description>ELC_GPTD Event Source GTCCRB Input Capture Enable</description>
                            <lsb>19</lsb>
                            <msb>19</msb>
                            <access>read-write</access>
                            <enumeratedValues>
                                </enumeratedValues>
                        </field>
                        <field>
                            <name>BSELCE</name>
                            <description>ELC_GPTE Event Source GTCCRB Input Capture Enable</description>
                            <lsb>20</lsb>
                            <msb>20</msb>
                            <access>read-write</access>
                            <enumeratedValues>
                                </enumeratedValues>
                        </field>
                        <field>
                            <name>BSELCF</name>
                            <description>ELC_GPTF Event Source GTCCRB Input Capture Enable</description>
                            <lsb>21</lsb>
                            <msb>21</msb>
                            <access>read-write</access>
                            <enumeratedValues>
                                </enumeratedValues>
                        </field>
                        <field>
                            <name>BSELCG</name>
                            <description>ELC_GPTG Event Source GTCCRB Input Capture Enable</description>
                            <lsb>22</lsb>
                            <msb>22</msb>
                            <access>read-write</access>
                            <enumeratedValues>
                                </enumeratedValues>
                        </field>
                        <field>
                            <name>BSELCH</name>
                            <description>ELC_GPTH Event Source GTCCRB Input Capture Enable</description>
                            <lsb>23</lsb>
                            <msb>23</msb>
                            <access>read-write</access>
                            <enumeratedValues>
                                </enumeratedValues>
                        </field>
                    </fields>
                </register>
                <register>
                    <name>GTCR</name>
                    <description>General PWM Timer Control Register</description>
                    <addressOffset>0x2C</addressOffset>
                    <size>32</size>
                    <access>read-write</access>
                    <resetValue>0x00000000</resetValue>
                    <resetMask>0xffffffff</resetMask>
                    <fields>
                        <field>
                            <name>CST</name>
                            <description>Count Start</description>
                            <lsb>0</lsb>
                            <msb>0</msb>
                            <access>read-write</access>
                            <enumeratedValues>
                                </enumeratedValues>
                        </field>
                        <field>
                            <name>MD</name>
                            <description>Mode Select</description>
                            <lsb>16</lsb>
                            <msb>18</msb>
                            <access>read-write</access>
                            <enumeratedValues>
                                </enumeratedValues>
                        </field>
                        <field>
                            <name>TPCS</name>
                            <description>Timer Prescaler Select</description>
                            <lsb>23</lsb>
                            <msb>26</msb>
                            <access>read-write</access>
                            <enumeratedValues>
                                </enumeratedValues>
                        </field>
                    </fields>
                </register>
                <register>
                    <name>GTUDDTYC</name>
                    <description>General PWM Timer Count Direction and Duty Setting Register</description>
                    <addressOffset>0x30</addressOffset>
                    <size>32</size>
                    <access>read-write</access>
                    <resetValue>0x00000001</resetValue>
                    <resetMask>0xffffffff</resetMask>
                    <fields>
                        <field>
                            <name>UD</name>
                            <description>Count Direction Setting</description>
                            <lsb>0</lsb>
                            <msb>0</msb>
                            <access>read-write</access>
                            <enumeratedValues>
                                </enumeratedValues>
                        </field>
                        <field>
                            <name>UDF</name>
                            <description>Forcible Count Direction Setting</description>
                            <lsb>1</lsb>
                            <msb>1</msb>
                            <access>read-write</access>
                            <enumeratedValues>
                                </enumeratedValues>
                        </field>
                        <field>
                            <name>OADTY</name>
                            <description>GTIOCnA Output Duty Setting</description>
                            <lsb>16</lsb>
                            <msb>17</msb>
                            <access>read-write</access>
                            <enumeratedValues>
                                </enumeratedValues>
                        </field>
                        <field>
                            <name>OADTYF</name>
                            <description>Forcible GTIOCnA Output Duty Setting</description>
                            <lsb>18</lsb>
                            <msb>18</msb>
                            <access>read-write</access>
                            <enumeratedValues>
                                </enumeratedValues>
                        </field>
                        <field>
                            <name>OADTYR</name>
                            <description>GTIOCnA Output Value Selecting after Releasing 0%/100% Duty Setting</description>
                            <lsb>19</lsb>
                            <msb>19</msb>
                            <access>read-write</access>
                            <enumeratedValues>
                                </enumeratedValues>
                        </field>
                        <field>
                            <name>OBDTY</name>
                            <description>GTIOCnB Output Duty Setting</description>
                            <lsb>24</lsb>
                            <msb>25</msb>
                            <access>read-write</access>
                            <enumeratedValues>
                                </enumeratedValues>
                        </field>
                        <field>
                            <name>OBDTYF</name>
                            <description>Forcible GTIOCnB Output Duty Setting</description>
                            <lsb>26</lsb>
                            <msb>26</msb>
                            <access>read-write</access>
                            <enumeratedValues>
                                </enumeratedValues>
                        </field>
                        <field>
                            <name>OBDTYR</name>
                            <description>GTIOCnB Output Value Selecting after Releasing 0%/100% Duty Setting</description>
                            <lsb>27</lsb>
                            <msb>27</msb>
                            <access>read-write</access>
                            <enumeratedValues>
                                </enumeratedValues>
                        </field>
                    </fields>
                </register>
                <register>
                    <name>GTIOR</name>
                    <description>General PWM Timer I/O Control Register</description>
                    <addressOffset>0x34</addressOffset>
                    <size>32</size>
                    <access>read-write</access>
                    <resetValue>0x00000000</resetValue>
                    <resetMask>0xffffffff</resetMask>
                    <fields>
                        <field>
                            <name>GTIOA</name>
                            <description>GTIOCnA Pin Function Select</description>
                            <lsb>0</lsb>
                            <msb>4</msb>
                            <access>read-write</access>
                        </field>
                        <field>
                            <name>OADFLT</name>
                            <description>GTIOCnA Pin Output Value Setting at the Count Stop</description>
                            <lsb>6</lsb>
                            <msb>6</msb>
                            <access>read-write</access>
                            <enumeratedValues>
                                </enumeratedValues>
                        </field>
                        <field>
                            <name>OAHLD</name>
                            <description>GTIOCnA Pin Output Setting at the Start/Stop Count</description>
                            <lsb>7</lsb>
                            <msb>7</msb>
                            <access>read-write</access>
                            <enumeratedValues>
                                </enumeratedValues>
                        </field>
                        <field>
                            <name>OAE</name>
                            <description>GTIOCnA Pin Output Enable</description>
                            <lsb>8</lsb>
                            <msb>8</msb>
                            <access>read-write</access>
                            <enumeratedValues>
                                </enumeratedValues>
                        </field>
                        <field>
                            <name>OADF</name>
                            <description>GTIOCnA Pin Disable Value Setting</description>
                            <lsb>9</lsb>
                            <msb>10</msb>
                            <access>read-write</access>
                            <enumeratedValues>
                                </enumeratedValues>
                        </field>
                        <field>
                            <name>NFAEN</name>
                            <description>Noise Filter A Enable</description>
                            <lsb>13</lsb>
                            <msb>13</msb>
                            <access>read-write</access>
                            <enumeratedValues>
                                </enumeratedValues>
                        </field>
                        <field>
                            <name>NFCSA</name>
                            <description>Noise Filter A Sampling Clock Select</description>
                            <lsb>14</lsb>
                            <msb>15</msb>
                            <access>read-write</access>
                            <enumeratedValues>
                                </enumeratedValues>
                        </field>
                        <field>
                            <name>GTIOB</name>
                            <description>GTIOCnB Pin Function Select</description>
                            <lsb>16</lsb>
                            <msb>20</msb>
                            <access>read-write</access>
                        </field>
                        <field>
                            <name>OBDFLT</name>
                            <description>GTIOCnB Pin Output Value Setting at the Count Stop</description>
                            <lsb>22</lsb>
                            <msb>22</msb>
                            <access>read-write</access>
                            <enumeratedValues>
                                </enumeratedValues>
                        </field>
                        <field>
                            <name>OBHLD</name>
                            <description>GTIOCnB Pin Output Setting at the Start/Stop Count</description>
                            <lsb>23</lsb>
                            <msb>23</msb>
                            <access>read-write</access>
                            <enumeratedValues>
                                </enumeratedValues>
                        </field>
                        <field>
                            <name>OBE</name>
                            <description>GTIOCnB Pin Output Enable</description>
                            <lsb>24</lsb>
                            <msb>24</msb>
                            <access>read-write</access>
                            <enumeratedValues>
                                </enumeratedValues>
                        </field>
                        <field>
                            <name>OBDF</name>
                            <description>GTIOCnB Pin Disable Value Setting</description>
                            <lsb>25</lsb>
                            <msb>26</msb>
                            <access>read-write</access>
                            <enumeratedValues>
                                </enumeratedValues>
                        </field>
                        <field>
                            <name>NFBEN</name>
                            <description>Noise Filter B Enable</description>
                            <lsb>29</lsb>
                            <msb>29</msb>
                            <access>read-write</access>
                            <enumeratedValues>
                                </enumeratedValues>
                        </field>
                        <field>
                            <name>NFCSB</name>
                            <description>Noise Filter B Sampling Clock Select</description>
                            <lsb>30</lsb>
                            <msb>31</msb>
                            <access>read-write</access>
                            <enumeratedValues>
                                </enumeratedValues>
                        </field>
                    </fields>
                </register>
                <register>
                    <name>GTINTAD</name>
                    <description>General PWM Timer Interrupt Output Setting Register</description>
                    <addressOffset>0x38</addressOffset>
                    <size>32</size>
                    <access>read-write</access>
                    <resetValue>0x00000000</resetValue>
                    <resetMask>0xffffffff</resetMask>
                    <fields>
                        <field>
                            <name>GRP</name>
                            <description>Output Disable Source Select</description>
                            <lsb>24</lsb>
                            <msb>25</msb>
                            <access>read-write</access>
                            <enumeratedValues>
                                </enumeratedValues>
                        </field>
                        <field>
                            <name>GRPABH</name>
                            <description>Same Time Output Level High Disable Request Enable</description>
                            <lsb>29</lsb>
                            <msb>29</msb>
                            <access>read-write</access>
                            <enumeratedValues>
                                </enumeratedValues>
                        </field>
                        <field>
                            <name>GRPABL</name>
                            <description>Same Time Output Level Low Disable Request Enable</description>
                            <lsb>30</lsb>
                            <msb>30</msb>
                            <access>read-write</access>
                            <enumeratedValues>
                                </enumeratedValues>
                        </field>
                    </fields>
                </register>
                <register>
                    <name>GTST</name>
                    <description>General PWM Timer Status Register</description>
                    <addressOffset>0x3C</addressOffset>
                    <size>32</size>
                    <access>read-write</access>
                    <resetValue>0x00008000</resetValue>
                    <resetMask>0xffffffff</resetMask>
                    <fields>
                        <field>
                            <name>TCFA</name>
                            <description>Input Capture/Compare Match Flag A</description>
                            <lsb>0</lsb>
                            <msb>0</msb>
                            <access>read-write</access>
                            <enumeratedValues>
                                </enumeratedValues>
                        </field>
                        <field>
                            <name>TCFB</name>
                            <description>Input Capture/Compare Match Flag B</description>
                            <lsb>1</lsb>
                            <msb>1</msb>
                            <access>read-write</access>
                            <enumeratedValues>
                                </enumeratedValues>
                        </field>
                        <field>
                            <name>TCFC</name>
                            <description>Input Compare Match Flag C</description>
                            <lsb>2</lsb>
                            <msb>2</msb>
                            <access>read-write</access>
                            <enumeratedValues>
                                </enumeratedValues>
                        </field>
                        <field>
                            <name>TCFD</name>
                            <description>Input Compare Match Flag D</description>
                            <lsb>3</lsb>
                            <msb>3</msb>
                            <access>read-write</access>
                            <enumeratedValues>
                                </enumeratedValues>
                        </field>
                        <field>
                            <name>TCFE</name>
                            <description>Input Compare Match Flag E</description>
                            <lsb>4</lsb>
                            <msb>4</msb>
                            <access>read-write</access>
                            <enumeratedValues>
                                </enumeratedValues>
                        </field>
                        <field>
                            <name>TCFF</name>
                            <description>Input Compare Match Flag F</description>
                            <lsb>5</lsb>
                            <msb>5</msb>
                            <access>read-write</access>
                            <enumeratedValues>
                                </enumeratedValues>
                        </field>
                        <field>
                            <name>TCFPO</name>
                            <description>Overflow Flag</description>
                            <lsb>6</lsb>
                            <msb>6</msb>
                            <access>read-write</access>
                            <enumeratedValues>
                                </enumeratedValues>
                        </field>
                        <field>
                            <name>TCFPU</name>
                            <description>Underflow Flag</description>
                            <lsb>7</lsb>
                            <msb>7</msb>
                            <access>read-write</access>
                            <enumeratedValues>
                                </enumeratedValues>
                        </field>
                        <field>
                            <name>TUCF</name>
                            <description>Count Direction Flag</description>
                            <lsb>15</lsb>
                            <msb>15</msb>
                            <access>read-only</access>
                            <enumeratedValues>
                                </enumeratedValues>
                        </field>
                        <field>
                            <name>ODF</name>
                            <description>Output Disable Flag</description>
                            <lsb>24</lsb>
                            <msb>24</msb>
                            <access>read-only</access>
                            <enumeratedValues>
                                </enumeratedValues>
                        </field>
                        <field>
                            <name>OABHF</name>
                            <description>Same Time Output Level High Flag</description>
                            <lsb>29</lsb>
                            <msb>29</msb>
                            <access>read-only</access>
                            <enumeratedValues>
                                </enumeratedValues>
                        </field>
                        <field>
                            <name>OABLF</name>
                            <description>Same Time Output Level Low Flag</description>
                            <lsb>30</lsb>
                            <msb>30</msb>
                            <access>read-only</access>
                            <enumeratedValues>
                                </enumeratedValues>
                        </field>
                        <field>
                            <name>PCF</name>
                            <description>Period Count Function Finish Flag</description>
                            <lsb>31</lsb>
                            <msb>31</msb>
                            <access>read-write</access>
                            <enumeratedValues>
                                </enumeratedValues>
                        </field>
                    </fields>
                </register>
                <register>
                    <name>GTBER</name>
                    <description>General PWM Timer Buffer Enable Register</description>
                    <addressOffset>0x40</addressOffset>
                    <size>32</size>
                    <access>read-write</access>
                    <resetValue>0x00000000</resetValue>
                    <resetMask>0xffffffff</resetMask>
                    <fields>
                        <field>
                            <name>BD0</name>
                            <description>GTCCR Buffer Operation Disable</description>
                            <lsb>0</lsb>
                            <msb>0</msb>
                            <access>read-write</access>
                            <enumeratedValues>
                                </enumeratedValues>
                        </field>
                        <field>
                            <name>BD1</name>
                            <description>GTPR Buffer Operation Disable</description>
                            <lsb>1</lsb>
                            <msb>1</msb>
                            <access>read-write</access>
                            <enumeratedValues>
                                </enumeratedValues>
                        </field>
                        <field>
                            <name>CCRA</name>
                            <description>GTCCRA Buffer Operation</description>
                            <lsb>16</lsb>
                            <msb>17</msb>
                            <access>read-write</access>
                            <enumeratedValues>
                                </enumeratedValues>
                        </field>
                        <field>
                            <name>CCRB</name>
                            <description>GTCCRB Buffer Operation</description>
                            <lsb>18</lsb>
                            <msb>19</msb>
                            <access>read-write</access>
                            <enumeratedValues>
                                </enumeratedValues>
                        </field>
                        <field>
                            <name>PR</name>
                            <description>GTPR Buffer Operation</description>
                            <lsb>20</lsb>
                            <msb>21</msb>
                            <access>read-write</access>
                            <enumeratedValues>
                                </enumeratedValues>
                        </field>
                        <field>
                            <name>CCRSWT</name>
                            <description>GTCCRA and GTCCRB Forcible Buffer Operation</description>
                            <lsb>22</lsb>
                            <msb>22</msb>
                            <access>write-only</access>
                        </field>
                    </fields>
                </register>
                <register>
                    <name>GTCNT</name>
                    <description>General PWM Timer Counter</description>
                    <addressOffset>0x48</addressOffset>
                    <size>32</size>
                    <access>read-write</access>
                    <resetValue>0x00000000</resetValue>
                    <resetMask>0xffffffff</resetMask>
                </register>
                <register>
                    <name>GTCCRA</name>
                    <description>General PWM Timer Compare Capture Register A</description>
                    <addressOffset>0x4C</addressOffset>
                    <size>32</size>
                    <access>read-write</access>
                    <resetValue>0xffffffff</resetValue>
                    <resetMask>0xffffffff</resetMask>
                </register>
                <register>
                    <name>GTCCRB</name>
                    <description>General PWM Timer Compare Capture Register B</description>
                    <addressOffset>0x50</addressOffset>
                    <size>32</size>
                    <access>read-write</access>
                    <resetValue>0xffffffff</resetValue>
                    <resetMask>0xffffffff</resetMask>
                </register>
                <register>
                    <name>GTCCRC</name>
                    <description>General PWM Timer Compare Capture Register C</description>
                    <addressOffset>0x54</addressOffset>
                    <size>32</size>
                    <access>read-write</access>
                    <resetValue>0xffffffff</resetValue>
                    <resetMask>0xffffffff</resetMask>
                </register>
                <register>
                    <name>GTCCRE</name>
                    <description>General PWM Timer Compare Capture Register E</description>
                    <addressOffset>0x58</addressOffset>
                    <size>32</size>
                    <access>read-write</access>
                    <resetValue>0xffffffff</resetValue>
                    <resetMask>0xffffffff</resetMask>
                </register>
                <register>
                    <name>GTCCRD</name>
                    <description>General PWM Timer Compare Capture Register D</description>
                    <addressOffset>0x5C</addressOffset>
                    <size>32</size>
                    <access>read-write</access>
                    <resetValue>0xffffffff</resetValue>
                    <resetMask>0xffffffff</resetMask>
                </register>
                <register>
                    <name>GTCCRF</name>
                    <description>General PWM Timer Compare Capture Register F</description>
                    <addressOffset>0x60</addressOffset>
                    <size>32</size>
                    <access>read-write</access>
                    <resetValue>0xffffffff</resetValue>
                    <resetMask>0xffffffff</resetMask>
                </register>
                <register>
                    <name>GTPR</name>
                    <description>General PWM Timer Cycle Setting Register</description>
                    <addressOffset>0x64</addressOffset>
                    <size>32</size>
                    <access>read-write</access>
                    <resetValue>0xffffffff</resetValue>
                    <resetMask>0xffffffff</resetMask>
                </register>
                <register>
                    <name>GTPBR</name>
                    <description>General PWM Timer Cycle Setting Buffer Register</description>
                    <addressOffset>0x68</addressOffset>
                    <size>32</size>
                    <access>read-write</access>
                    <resetValue>0xffffffff</resetValue>
                    <resetMask>0xffffffff</resetMask>
                </register>
                <register>
                    <name>GTDTCR</name>
                    <description>General PWM Timer Dead Time Control Register</description>
                    <addressOffset>0x88</addressOffset>
                    <size>32</size>
                    <access>read-write</access>
                    <resetValue>0x00000000</resetValue>
                    <resetMask>0xffffffff</resetMask>
                    <fields>
                        <field>
                            <name>TDE</name>
                            <description>Negative,Phase Waveform Setting</description>
                            <lsb>0</lsb>
                            <msb>0</msb>
                            <access>read-write</access>
                            <enumeratedValues>
                                </enumeratedValues>
                        </field>
                    </fields>
                </register>
                <register>
                    <name>GTDVU</name>
                    <description>General PWM Timer Dead Time Value Register U</description>
                    <addressOffset>0x8C</addressOffset>
                    <size>32</size>
                    <access>read-write</access>
                    <resetValue>0xffffffff</resetValue>
                    <resetMask>0xffffffff</resetMask>
                </register>
                <register>
                    <name>GTICLF</name>
                    <description>General PWM Timer Inter Channel Logical Operation Function Setting Register</description>
                    <addressOffset>0xB8</addressOffset>
                    <size>32</size>
                    <access>read-write</access>
                    <resetValue>0x00000000</resetValue>
                    <resetMask>0xffffffff</resetMask>
                    <fields>
                        <field>
                            <name>ICLFA</name>
                            <description>GTIOCnA Output Logical Operation Function Select</description>
                            <lsb>0</lsb>
                            <msb>2</msb>
                            <access>read-write</access>
                            <enumeratedValues>
                                </enumeratedValues>
                        </field>
                        <field>
                            <name>ICLFSELC</name>
                            <description>Inter Channel Signal C Select</description>
                            <lsb>4</lsb>
                            <msb>9</msb>
                            <access>read-write</access>
                            <enumeratedValues>
                                </enumeratedValues>
                        </field>
                        <field>
                            <name>ICLFB</name>
                            <description>GTIOCnB Output Logical Operation Function Select</description>
                            <lsb>16</lsb>
                            <msb>18</msb>
                            <access>read-write</access>
                            <enumeratedValues>
                                </enumeratedValues>
                        </field>
                        <field>
                            <name>ICLFSELD</name>
                            <description>Inter Channel Signal D Select</description>
                            <lsb>20</lsb>
                            <msb>25</msb>
                            <access>read-write</access>
                            <enumeratedValues>
                                </enumeratedValues>
                        </field>
                    </fields>
                </register>
                <register>
                    <name>GTPC</name>
                    <description>General PWM Timer Period Count Register</description>
                    <addressOffset>0xBC</addressOffset>
                    <size>32</size>
                    <access>read-write</access>
                    <resetValue>0x00000000</resetValue>
                    <resetMask>0xffffffff</resetMask>
                    <fields>
                        <field>
                            <name>PCEN</name>
                            <description>Period Count Function Enable</description>
                            <lsb>0</lsb>
                            <msb>0</msb>
                            <access>read-write</access>
                            <enumeratedValues>
                                </enumeratedValues>
                        </field>
                        <field>
                            <name>ASTP</name>
                            <description>Automatic Stop Function Enable</description>
                            <lsb>8</lsb>
                            <msb>8</msb>
                            <access>read-write</access>
                            <enumeratedValues>
                                </enumeratedValues>
                        </field>
                        <field>
                            <name>PCNT</name>
                            <description>Period Counter</description>
                            <lsb>16</lsb>
                            <msb>27</msb>
                            <access>read-write</access>
                        </field>
                    </fields>
                </register>
                <register>
                    <name>GTSECSR</name>
                    <description>General PWM Timer Operation Enable Bit Simultaneous Control Channel Select Register</description>
                    <addressOffset>0xD0</addressOffset>
                    <size>32</size>
                    <access>read-write</access>
                    <resetValue>0x00000000</resetValue>
                    <resetMask>0xffffffff</resetMask>
                    <fields>
                        <field>
                            <name>SECSEL0</name>
                            <description>Channel 0 Operation Enable Bit Simultaneous Control Channel Select</description>
                            <lsb>0</lsb>
                            <msb>0</msb>
                            <access>read-write</access>
                            <enumeratedValues>
                                </enumeratedValues>
                        </field>
                        <field>
                            <name>SECSEL1</name>
                            <description>Channel 1 Operation Enable Bit Simultaneous Control Channel Select</description>
                            <lsb>1</lsb>
                            <msb>1</msb>
                            <access>read-write</access>
                            <enumeratedValues>
                                </enumeratedValues>
                        </field>
                        <field>
                            <name>SECSEL2</name>
                            <description>Channel 2 Operation Enable Bit Simultaneous Control Channel Select</description>
                            <lsb>2</lsb>
                            <msb>2</msb>
                            <access>read-write</access>
                            <enumeratedValues>
                                </enumeratedValues>
                        </field>
                        <field>
                            <name>SECSEL3</name>
                            <description>Channel 3 Operation Enable Bit Simultaneous Control Channel Select</description>
                            <lsb>3</lsb>
                            <msb>3</msb>
                            <access>read-write</access>
                            <enumeratedValues>
                                </enumeratedValues>
                        </field>
                        <field>
                            <name>SECSEL4</name>
                            <description>Channel 4 Operation Enable Bit Simultaneous Control Channel Select</description>
                            <lsb>4</lsb>
                            <msb>4</msb>
                            <access>read-write</access>
                            <enumeratedValues>
                                </enumeratedValues>
                        </field>
                        <field>
                            <name>SECSEL5</name>
                            <description>Channel 5 Operation Enable Bit Simultaneous Control Channel Select</description>
                            <lsb>5</lsb>
                            <msb>5</msb>
                            <access>read-write</access>
                            <enumeratedValues>
                                </enumeratedValues>
                        </field>
                        <field>
                            <name>SECSEL6</name>
                            <description>Channel 6 Operation Enable Bit Simultaneous Control Channel Select</description>
                            <lsb>6</lsb>
                            <msb>6</msb>
                            <access>read-write</access>
                            <enumeratedValues>
                                </enumeratedValues>
                        </field>
                        <field>
                            <name>SECSEL7</name>
                            <description>Channel 7 Operation Enable Bit Simultaneous Control Channel Select</description>
                            <lsb>7</lsb>
                            <msb>7</msb>
                            <access>read-write</access>
                            <enumeratedValues>
                                </enumeratedValues>
                        </field>
                        <field>
                            <name>SECSEL8</name>
                            <description>Channel 8 Operation Enable Bit Simultaneous Control Channel Select</description>
                            <lsb>8</lsb>
                            <msb>8</msb>
                            <access>read-write</access>
                            <enumeratedValues>
                                </enumeratedValues>
                        </field>
                        <field>
                            <name>SECSEL9</name>
                            <description>Channel 9 Operation Enable Bit Simultaneous Control Channel Select</description>
                            <lsb>9</lsb>
                            <msb>9</msb>
                            <access>read-write</access>
                            <enumeratedValues>
                                </enumeratedValues>
                        </field>
                    </fields>
                </register>
                <register>
                    <name>GTSECR</name>
                    <description>General PWM Timer Operation Enable Bit Simultaneous Control Register</description>
                    <addressOffset>0xD4</addressOffset>
                    <size>32</size>
                    <access>read-write</access>
                    <resetValue>0x00000000</resetValue>
                    <resetMask>0xffffffff</resetMask>
                    <fields>
                        <field>
                            <name>SBDCE</name>
                            <description>GTCCR Register Buffer Operation Simultaneous Enable</description>
                            <lsb>0</lsb>
                            <msb>0</msb>
                            <access>read-write</access>
                            <enumeratedValues>
                                </enumeratedValues>
                        </field>
                        <field>
                            <name>SBDPE</name>
                            <description>GTPR Register Buffer Operation Simultaneous Enable</description>
                            <lsb>1</lsb>
                            <msb>1</msb>
                            <access>read-write</access>
                            <enumeratedValues>
                                </enumeratedValues>
                        </field>
                        <field>
                            <name>SBDCD</name>
                            <description>GTCCR Register Buffer Operation Simultaneous Disable</description>
                            <lsb>8</lsb>
                            <msb>8</msb>
                            <access>read-write</access>
                            <enumeratedValues>
                                </enumeratedValues>
                        </field>
                        <field>
                            <name>SBDPD</name>
                            <description>GTPR Register Buffer Operation Simultaneous Disable</description>
                            <lsb>9</lsb>
                            <msb>9</msb>
                            <access>read-write</access>
                            <enumeratedValues>
                                </enumeratedValues>
                        </field>
                        <field>
                            <name>SPCE</name>
                            <description>Period Count Function Simultaneous Enable</description>
                            <lsb>16</lsb>
                            <msb>16</msb>
                            <access>read-write</access>
                            <enumeratedValues>
                                </enumeratedValues>
                        </field>
                        <field>
                            <name>SPCD</name>
                            <description>Period Count Function Simultaneous Disable</description>
                            <lsb>24</lsb>
                            <msb>24</msb>
                            <access>read-write</access>
                            <enumeratedValues>
                                </enumeratedValues>
                        </field>
                    </fields>
                </register>
            </registers>
        </peripheral>
        <peripheral derivedFrom="GPT320">
            <name>GPT321</name>
            <description>General PWM 32-bit Timer 1</description>
            <baseAddress>0x40169100</baseAddress>
        </peripheral>
        <peripheral derivedFrom="GPT320">
            <name>GPT322</name>
            <description>General PWM 32-bit Timer 2</description>
            <baseAddress>0x40169200</baseAddress>
        </peripheral>
        <peripheral derivedFrom="GPT320">
            <name>GPT323</name>
            <description>General PWM 32-bit Timer 3</description>
            <baseAddress>0x40169300</baseAddress>
        </peripheral>
        <peripheral>
            <name>GPT164</name>
            <description>General PWM 16-bit Timer 4</description>
            <baseAddress>0x40169400</baseAddress>
            <addressBlock>
                <offset>0x00</offset>
                <size>68</size>
                <usage>registers</usage>
            </addressBlock>
            <addressBlock>
                <offset>0x48</offset>
                <size>36</size>
                <usage>registers</usage>
            </addressBlock>
            <addressBlock>
                <offset>0x88</offset>
                <size>8</size>
                <usage>registers</usage>
            </addressBlock>
            <addressBlock>
                <offset>0xB8</offset>
                <size>8</size>
                <usage>registers</usage>
            </addressBlock>
            <addressBlock>
                <offset>0xD0</offset>
                <size>8</size>
                <usage>registers</usage>
            </addressBlock>
            <registers>
                <register>
                    <name>GTWP</name>
                    <description>General PWM Timer Write,Protection Register</description>
                    <addressOffset>0x00</addressOffset>
                    <size>32</size>
                    <access>read-write</access>
                    <resetValue>0x00000000</resetValue>
                    <resetMask>0xffffffff</resetMask>
                    <fields>
                        <field>
                            <name>WP</name>
                            <description>Register Write Disable</description>
                            <lsb>0</lsb>
                            <msb>0</msb>
                            <access>read-write</access>
                            <enumeratedValues>
                                </enumeratedValues>
                        </field>
                        <field>
                            <name>STRWP</name>
                            <description>GTSTR.CSTRT Bit Write Disable</description>
                            <lsb>1</lsb>
                            <msb>1</msb>
                            <access>read-write</access>
                            <enumeratedValues>
                                </enumeratedValues>
                        </field>
                        <field>
                            <name>STPWP</name>
                            <description>GTSTP.CSTOP Bit Write Disable</description>
                            <lsb>2</lsb>
                            <msb>2</msb>
                            <access>read-write</access>
                            <enumeratedValues>
                                </enumeratedValues>
                        </field>
                        <field>
                            <name>CLRWP</name>
                            <description>GTCLR.CCLR Bit Write Disable</description>
                            <lsb>3</lsb>
                            <msb>3</msb>
                            <access>read-write</access>
                            <enumeratedValues>
                                </enumeratedValues>
                        </field>
                        <field>
                            <name>CMNWP</name>
                            <description>Common Register Write Disabled</description>
                            <lsb>4</lsb>
                            <msb>4</msb>
                            <access>read-write</access>
                            <enumeratedValues>
                                </enumeratedValues>
                        </field>
                        <field>
                            <name>PRKEY</name>
                            <description>GTWP Key Code</description>
                            <lsb>8</lsb>
                            <msb>15</msb>
                            <access>write-only</access>
                        </field>
                    </fields>
                </register>
                <register>
                    <name>GTSTR</name>
                    <description>General PWM Timer Software Start Register</description>
                    <addressOffset>0x04</addressOffset>
                    <size>32</size>
                    <access>read-write</access>
                    <resetValue>0x00000000</resetValue>
                    <resetMask>0xffffffff</resetMask>
                    <fields>
                        <field>
                            <name>CSTRT0</name>
                            <description>Channel n GTCNT Count Start (n : the same as bit position value)</description>
                            <lsb>0</lsb>
                            <msb>0</msb>
                            <access>read-write</access>
                            <enumeratedValues>
                                </enumeratedValues>
                        </field>
                        <field>
                            <name>CSTRT1</name>
                            <description>Channel n GTCNT Count Start (n : the same as bit position value)</description>
                            <lsb>1</lsb>
                            <msb>1</msb>
                            <access>read-write</access>
                            <enumeratedValues>
                                </enumeratedValues>
                        </field>
                        <field>
                            <name>CSTRT2</name>
                            <description>Channel n GTCNT Count Start (n : the same as bit position value)</description>
                            <lsb>2</lsb>
                            <msb>2</msb>
                            <access>read-write</access>
                            <enumeratedValues>
                                </enumeratedValues>
                        </field>
                        <field>
                            <name>CSTRT3</name>
                            <description>Channel n GTCNT Count Start (n : the same as bit position value)</description>
                            <lsb>3</lsb>
                            <msb>3</msb>
                            <access>read-write</access>
                            <enumeratedValues>
                                </enumeratedValues>
                        </field>
                        <field>
                            <name>CSTRT4</name>
                            <description>Channel n GTCNT Count Start (n : the same as bit position value)</description>
                            <lsb>4</lsb>
                            <msb>4</msb>
                            <access>read-write</access>
                            <enumeratedValues>
                                </enumeratedValues>
                        </field>
                        <field>
                            <name>CSTRT5</name>
                            <description>Channel n GTCNT Count Start (n : the same as bit position value)</description>
                            <lsb>5</lsb>
                            <msb>5</msb>
                            <access>read-write</access>
                            <enumeratedValues>
                                </enumeratedValues>
                        </field>
                        <field>
                            <name>CSTRT6</name>
                            <description>Channel n GTCNT Count Start (n : the same as bit position value)</description>
                            <lsb>6</lsb>
                            <msb>6</msb>
                            <access>read-write</access>
                            <enumeratedValues>
                                </enumeratedValues>
                        </field>
                        <field>
                            <name>CSTRT7</name>
                            <description>Channel n GTCNT Count Start (n : the same as bit position value)</description>
                            <lsb>7</lsb>
                            <msb>7</msb>
                            <access>read-write</access>
                            <enumeratedValues>
                                </enumeratedValues>
                        </field>
                        <field>
                            <name>CSTRT8</name>
                            <description>Channel n GTCNT Count Start (n : the same as bit position value)</description>
                            <lsb>8</lsb>
                            <msb>8</msb>
                            <access>read-write</access>
                            <enumeratedValues>
                                </enumeratedValues>
                        </field>
                        <field>
                            <name>CSTRT9</name>
                            <description>Channel n GTCNT Count Start (n : the same as bit position value)</description>
                            <lsb>9</lsb>
                            <msb>9</msb>
                            <access>read-write</access>
                            <enumeratedValues>
                                </enumeratedValues>
                        </field>
                    </fields>
                </register>
                <register>
                    <name>GTSTP</name>
                    <description>General PWM Timer Software Stop Register</description>
                    <addressOffset>0x08</addressOffset>
                    <size>32</size>
                    <access>read-write</access>
                    <resetValue>0xffffffff</resetValue>
                    <resetMask>0xffffffff</resetMask>
                    <fields>
                        <field>
                            <name>CSTOP0</name>
                            <description>Channel n GTCNT Count Stop (n : the same as bit position value)</description>
                            <lsb>0</lsb>
                            <msb>0</msb>
                            <access>read-write</access>
                            <enumeratedValues>
                                </enumeratedValues>
                        </field>
                        <field>
                            <name>CSTOP1</name>
                            <description>Channel n GTCNT Count Stop (n : the same as bit position value)</description>
                            <lsb>1</lsb>
                            <msb>1</msb>
                            <access>read-write</access>
                            <enumeratedValues>
                                </enumeratedValues>
                        </field>
                        <field>
                            <name>CSTOP2</name>
                            <description>Channel n GTCNT Count Stop (n : the same as bit position value)</description>
                            <lsb>2</lsb>
                            <msb>2</msb>
                            <access>read-write</access>
                            <enumeratedValues>
                                </enumeratedValues>
                        </field>
                        <field>
                            <name>CSTOP3</name>
                            <description>Channel n GTCNT Count Stop (n : the same as bit position value)</description>
                            <lsb>3</lsb>
                            <msb>3</msb>
                            <access>read-write</access>
                            <enumeratedValues>
                                </enumeratedValues>
                        </field>
                        <field>
                            <name>CSTOP4</name>
                            <description>Channel n GTCNT Count Stop (n : the same as bit position value)</description>
                            <lsb>4</lsb>
                            <msb>4</msb>
                            <access>read-write</access>
                            <enumeratedValues>
                                </enumeratedValues>
                        </field>
                        <field>
                            <name>CSTOP5</name>
                            <description>Channel n GTCNT Count Stop (n : the same as bit position value)</description>
                            <lsb>5</lsb>
                            <msb>5</msb>
                            <access>read-write</access>
                            <enumeratedValues>
                                </enumeratedValues>
                        </field>
                        <field>
                            <name>CSTOP6</name>
                            <description>Channel n GTCNT Count Stop (n : the same as bit position value)</description>
                            <lsb>6</lsb>
                            <msb>6</msb>
                            <access>read-write</access>
                            <enumeratedValues>
                                </enumeratedValues>
                        </field>
                        <field>
                            <name>CSTOP7</name>
                            <description>Channel n GTCNT Count Stop (n : the same as bit position value)</description>
                            <lsb>7</lsb>
                            <msb>7</msb>
                            <access>read-write</access>
                            <enumeratedValues>
                                </enumeratedValues>
                        </field>
                        <field>
                            <name>CSTOP8</name>
                            <description>Channel n GTCNT Count Stop (n : the same as bit position value)</description>
                            <lsb>8</lsb>
                            <msb>8</msb>
                            <access>read-write</access>
                            <enumeratedValues>
                                </enumeratedValues>
                        </field>
                        <field>
                            <name>CSTOP9</name>
                            <description>Channel n GTCNT Count Stop (n : the same as bit position value)</description>
                            <lsb>9</lsb>
                            <msb>9</msb>
                            <access>read-write</access>
                            <enumeratedValues>
                                </enumeratedValues>
                        </field>
                    </fields>
                </register>
                <register>
                    <name>GTCLR</name>
                    <description>General PWM Timer Software Clear Register</description>
                    <addressOffset>0x0C</addressOffset>
                    <size>32</size>
                    <access>write-only</access>
                    <resetValue>0x00000000</resetValue>
                    <resetMask>0xffffffff</resetMask>
                    <fields>
                        <field>
                            <name>CCLR0</name>
                            <description>Channel n GTCNT Count Clear (n : the same as bit position value)</description>
                            <lsb>0</lsb>
                            <msb>0</msb>
                            <access>write-only</access>
                            <enumeratedValues>
                                </enumeratedValues>
                        </field>
                        <field>
                            <name>CCLR1</name>
                            <description>Channel n GTCNT Count Clear (n : the same as bit position value)</description>
                            <lsb>1</lsb>
                            <msb>1</msb>
                            <access>write-only</access>
                            <enumeratedValues>
                                </enumeratedValues>
                        </field>
                        <field>
                            <name>CCLR2</name>
                            <description>Channel n GTCNT Count Clear (n : the same as bit position value)</description>
                            <lsb>2</lsb>
                            <msb>2</msb>
                            <access>write-only</access>
                            <enumeratedValues>
                                </enumeratedValues>
                        </field>
                        <field>
                            <name>CCLR3</name>
                            <description>Channel n GTCNT Count Clear (n : the same as bit position value)</description>
                            <lsb>3</lsb>
                            <msb>3</msb>
                            <access>write-only</access>
                            <enumeratedValues>
                                </enumeratedValues>
                        </field>
                        <field>
                            <name>CCLR4</name>
                            <description>Channel n GTCNT Count Clear (n : the same as bit position value)</description>
                            <lsb>4</lsb>
                            <msb>4</msb>
                            <access>write-only</access>
                            <enumeratedValues>
                                </enumeratedValues>
                        </field>
                        <field>
                            <name>CCLR5</name>
                            <description>Channel n GTCNT Count Clear (n : the same as bit position value)</description>
                            <lsb>5</lsb>
                            <msb>5</msb>
                            <access>write-only</access>
                            <enumeratedValues>
                                </enumeratedValues>
                        </field>
                        <field>
                            <name>CCLR6</name>
                            <description>Channel n GTCNT Count Clear (n : the same as bit position value)</description>
                            <lsb>6</lsb>
                            <msb>6</msb>
                            <access>write-only</access>
                            <enumeratedValues>
                                </enumeratedValues>
                        </field>
                        <field>
                            <name>CCLR7</name>
                            <description>Channel n GTCNT Count Clear (n : the same as bit position value)</description>
                            <lsb>7</lsb>
                            <msb>7</msb>
                            <access>write-only</access>
                            <enumeratedValues>
                                </enumeratedValues>
                        </field>
                        <field>
                            <name>CCLR8</name>
                            <description>Channel n GTCNT Count Clear (n : the same as bit position value)</description>
                            <lsb>8</lsb>
                            <msb>8</msb>
                            <access>write-only</access>
                            <enumeratedValues>
                                </enumeratedValues>
                        </field>
                        <field>
                            <name>CCLR9</name>
                            <description>Channel n GTCNT Count Clear (n : the same as bit position value)</description>
                            <lsb>9</lsb>
                            <msb>9</msb>
                            <access>write-only</access>
                            <enumeratedValues>
                                </enumeratedValues>
                        </field>
                    </fields>
                </register>
                <register>
                    <name>GTSSR</name>
                    <description>General PWM Timer Start Source Select Register</description>
                    <addressOffset>0x10</addressOffset>
                    <size>32</size>
                    <access>read-write</access>
                    <resetValue>0x00000000</resetValue>
                    <resetMask>0xffffffff</resetMask>
                    <fields>
                        <field>
                            <name>SSGTRGAR</name>
                            <description>GTETRGA Pin Rising Input Source Counter Start Enable</description>
                            <lsb>0</lsb>
                            <msb>0</msb>
                            <access>read-write</access>
                            <enumeratedValues>
                                </enumeratedValues>
                        </field>
                        <field>
                            <name>SSGTRGAF</name>
                            <description>GTETRGA Pin Falling Input Source Counter Start Enable</description>
                            <lsb>1</lsb>
                            <msb>1</msb>
                            <access>read-write</access>
                            <enumeratedValues>
                                </enumeratedValues>
                        </field>
                        <field>
                            <name>SSGTRGBR</name>
                            <description>GTETRGB Pin Rising Input Source Counter Start Enable</description>
                            <lsb>2</lsb>
                            <msb>2</msb>
                            <access>read-write</access>
                            <enumeratedValues>
                                </enumeratedValues>
                        </field>
                        <field>
                            <name>SSGTRGBF</name>
                            <description>GTETRGB Pin Falling Input Source Counter Start Enable</description>
                            <lsb>3</lsb>
                            <msb>3</msb>
                            <access>read-write</access>
                            <enumeratedValues>
                                </enumeratedValues>
                        </field>
                        <field>
                            <name>SSGTRGCR</name>
                            <description>GTETRGC Pin Rising Input Source Counter Start Enable</description>
                            <lsb>4</lsb>
                            <msb>4</msb>
                            <access>read-write</access>
                            <enumeratedValues>
                                </enumeratedValues>
                        </field>
                        <field>
                            <name>SSGTRGCF</name>
                            <description>GTETRGC Pin Falling Input Source Counter Start Enable</description>
                            <lsb>5</lsb>
                            <msb>5</msb>
                            <access>read-write</access>
                            <enumeratedValues>
                                </enumeratedValues>
                        </field>
                        <field>
                            <name>SSGTRGDR</name>
                            <description>GTETRGD Pin Rising Input Source Counter Start Enable</description>
                            <lsb>6</lsb>
                            <msb>6</msb>
                            <access>read-write</access>
                            <enumeratedValues>
                                </enumeratedValues>
                        </field>
                        <field>
                            <name>SSGTRGDF</name>
                            <description>GTETRGD Pin Falling Input Source Counter Start Enable</description>
                            <lsb>7</lsb>
                            <msb>7</msb>
                            <access>read-write</access>
                            <enumeratedValues>
                                </enumeratedValues>
                        </field>
                        <field>
                            <name>SSCARBL</name>
                            <description>GTIOCnA Pin Rising Input during GTIOCnB Value Low Source Counter Start Enable</description>
                            <lsb>8</lsb>
                            <msb>8</msb>
                            <access>read-write</access>
                            <enumeratedValues>
                                </enumeratedValues>
                        </field>
                        <field>
                            <name>SSCARBH</name>
                            <description>GTIOCnA Pin Rising Input during GTIOCnB Value High Source Counter Start Enable</description>
                            <lsb>9</lsb>
                            <msb>9</msb>
                            <access>read-write</access>
                            <enumeratedValues>
                                </enumeratedValues>
                        </field>
                        <field>
                            <name>SSCAFBL</name>
                            <description>GTIOCnA Pin Falling Input during GTIOCnB Value Low Source Counter Start Enable</description>
                            <lsb>10</lsb>
                            <msb>10</msb>
                            <access>read-write</access>
                            <enumeratedValues>
                                </enumeratedValues>
                        </field>
                        <field>
                            <name>SSCAFBH</name>
                            <description>GTIOCnA Pin Falling Input during GTIOCnB Value High Source Counter Start Enable</description>
                            <lsb>11</lsb>
                            <msb>11</msb>
                            <access>read-write</access>
                            <enumeratedValues>
                                </enumeratedValues>
                        </field>
                        <field>
                            <name>SSCBRAL</name>
                            <description>GTIOCnB Pin Rising Input during GTIOCnA Value Low Source Counter Start Enable</description>
                            <lsb>12</lsb>
                            <msb>12</msb>
                            <access>read-write</access>
                            <enumeratedValues>
                                </enumeratedValues>
                        </field>
                        <field>
                            <name>SSCBRAH</name>
                            <description>GTIOCnB Pin Rising Input during GTIOCnA Value High Source Counter Start Enable</description>
                            <lsb>13</lsb>
                            <msb>13</msb>
                            <access>read-write</access>
                            <enumeratedValues>
                                </enumeratedValues>
                        </field>
                        <field>
                            <name>SSCBFAL</name>
                            <description>GTIOCnB Pin Falling Input during GTIOCnA Value Low Source Counter Start Enable</description>
                            <lsb>14</lsb>
                            <msb>14</msb>
                            <access>read-write</access>
                            <enumeratedValues>
                                </enumeratedValues>
                        </field>
                        <field>
                            <name>SSCBFAH</name>
                            <description>GTIOCnB Pin Falling Input during GTIOCnA Value High Source Counter Start Enable</description>
                            <lsb>15</lsb>
                            <msb>15</msb>
                            <access>read-write</access>
                            <enumeratedValues>
                                </enumeratedValues>
                        </field>
                        <field>
                            <name>SSELCA</name>
                            <description>ELC_GPTA Event Source Counter Start Enable</description>
                            <lsb>16</lsb>
                            <msb>16</msb>
                            <access>read-write</access>
                            <enumeratedValues>
                                </enumeratedValues>
                        </field>
                        <field>
                            <name>SSELCB</name>
                            <description>ELC_GPTB Event Source Counter Start Enable</description>
                            <lsb>17</lsb>
                            <msb>17</msb>
                            <access>read-write</access>
                            <enumeratedValues>
                                </enumeratedValues>
                        </field>
                        <field>
                            <name>SSELCC</name>
                            <description>ELC_GPTC Event Source Counter Start Enable</description>
                            <lsb>18</lsb>
                            <msb>18</msb>
                            <access>read-write</access>
                            <enumeratedValues>
                                </enumeratedValues>
                        </field>
                        <field>
                            <name>SSELCD</name>
                            <description>ELC_GPTD Event Source Counter Start Enable</description>
                            <lsb>19</lsb>
                            <msb>19</msb>
                            <access>read-write</access>
                            <enumeratedValues>
                                </enumeratedValues>
                        </field>
                        <field>
                            <name>SSELCE</name>
                            <description>ELC_GPTE Event Source Counter Start Enable</description>
                            <lsb>20</lsb>
                            <msb>20</msb>
                            <access>read-write</access>
                            <enumeratedValues>
                                </enumeratedValues>
                        </field>
                        <field>
                            <name>SSELCF</name>
                            <description>ELC_GPTF Event Source Counter Start Enable</description>
                            <lsb>21</lsb>
                            <msb>21</msb>
                            <access>read-write</access>
                            <enumeratedValues>
                                </enumeratedValues>
                        </field>
                        <field>
                            <name>SSELCG</name>
                            <description>ELC_GPTG Event Source Counter Start Enable</description>
                            <lsb>22</lsb>
                            <msb>22</msb>
                            <access>read-write</access>
                            <enumeratedValues>
                                </enumeratedValues>
                        </field>
                        <field>
                            <name>SSELCH</name>
                            <description>ELC_GPTH Event Source Counter Start Enable</description>
                            <lsb>23</lsb>
                            <msb>23</msb>
                            <access>read-write</access>
                            <enumeratedValues>
                                </enumeratedValues>
                        </field>
                        <field>
                            <name>CSTRT</name>
                            <description>Software Source Counter Start Enable</description>
                            <lsb>31</lsb>
                            <msb>31</msb>
                            <access>read-write</access>
                            <enumeratedValues>
                                </enumeratedValues>
                        </field>
                    </fields>
                </register>
                <register>
                    <name>GTPSR</name>
                    <description>General PWM Timer Stop Source Select Register</description>
                    <addressOffset>0x14</addressOffset>
                    <size>32</size>
                    <access>read-write</access>
                    <resetValue>0x00000000</resetValue>
                    <resetMask>0xffffffff</resetMask>
                    <fields>
                        <field>
                            <name>PSGTRGAR</name>
                            <description>GTETRGA Pin Rising Input Source Counter Stop Enable</description>
                            <lsb>0</lsb>
                            <msb>0</msb>
                            <access>read-write</access>
                            <enumeratedValues>
                                </enumeratedValues>
                        </field>
                        <field>
                            <name>PSGTRGAF</name>
                            <description>GTETRGA Pin Falling Input Source Counter Stop Enable</description>
                            <lsb>1</lsb>
                            <msb>1</msb>
                            <access>read-write</access>
                            <enumeratedValues>
                                </enumeratedValues>
                        </field>
                        <field>
                            <name>PSGTRGBR</name>
                            <description>GTETRGB Pin Rising Input Source Counter Stop Enable</description>
                            <lsb>2</lsb>
                            <msb>2</msb>
                            <access>read-write</access>
                            <enumeratedValues>
                                </enumeratedValues>
                        </field>
                        <field>
                            <name>PSGTRGBF</name>
                            <description>GTETRGB Pin Falling Input Source Counter Stop Enable</description>
                            <lsb>3</lsb>
                            <msb>3</msb>
                            <access>read-write</access>
                            <enumeratedValues>
                                </enumeratedValues>
                        </field>
                        <field>
                            <name>PSGTRGCR</name>
                            <description>GTETRGC Pin Rising Input Source Counter Stop Enable</description>
                            <lsb>4</lsb>
                            <msb>4</msb>
                            <access>read-write</access>
                            <enumeratedValues>
                                </enumeratedValues>
                        </field>
                        <field>
                            <name>PSGTRGCF</name>
                            <description>GTETRGC Pin Falling Input Source Counter Stop Enable</description>
                            <lsb>5</lsb>
                            <msb>5</msb>
                            <access>read-write</access>
                            <enumeratedValues>
                                </enumeratedValues>
                        </field>
                        <field>
                            <name>PSGTRGDR</name>
                            <description>GTETRGD Pin Rising Input Source Counter Stop Enable</description>
                            <lsb>6</lsb>
                            <msb>6</msb>
                            <access>read-write</access>
                            <enumeratedValues>
                                </enumeratedValues>
                        </field>
                        <field>
                            <name>PSGTRGDF</name>
                            <description>GTETRGD Pin Falling Input Source Counter Stop Enable</description>
                            <lsb>7</lsb>
                            <msb>7</msb>
                            <access>read-write</access>
                            <enumeratedValues>
                                </enumeratedValues>
                        </field>
                        <field>
                            <name>PSCARBL</name>
                            <description>GTIOCnA Pin Rising Input during GTIOCnB Value Low Source Counter Stop Enable</description>
                            <lsb>8</lsb>
                            <msb>8</msb>
                            <access>read-write</access>
                            <enumeratedValues>
                                </enumeratedValues>
                        </field>
                        <field>
                            <name>PSCARBH</name>
                            <description>GTIOCnA Pin Rising Input during GTIOCnB Value High Source Counter Stop Enable</description>
                            <lsb>9</lsb>
                            <msb>9</msb>
                            <access>read-write</access>
                            <enumeratedValues>
                                </enumeratedValues>
                        </field>
                        <field>
                            <name>PSCAFBL</name>
                            <description>GTIOCnA Pin Falling Input during GTIOCnB Value Low Source Counter Stop Enable</description>
                            <lsb>10</lsb>
                            <msb>10</msb>
                            <access>read-write</access>
                            <enumeratedValues>
                                </enumeratedValues>
                        </field>
                        <field>
                            <name>PSCAFBH</name>
                            <description>GTIOCnA Pin Falling Input during GTIOCnB Value High Source Counter Stop Enable</description>
                            <lsb>11</lsb>
                            <msb>11</msb>
                            <access>read-write</access>
                            <enumeratedValues>
                                </enumeratedValues>
                        </field>
                        <field>
                            <name>PSCBRAL</name>
                            <description>GTIOCnB Pin Rising Input during GTIOCnA Value Low Source Counter Stop Enable</description>
                            <lsb>12</lsb>
                            <msb>12</msb>
                            <access>read-write</access>
                            <enumeratedValues>
                                </enumeratedValues>
                        </field>
                        <field>
                            <name>PSCBRAH</name>
                            <description>GTIOCnB Pin Rising Input during GTIOCnA Value High Source Counter Stop Enable</description>
                            <lsb>13</lsb>
                            <msb>13</msb>
                            <access>read-write</access>
                            <enumeratedValues>
                                </enumeratedValues>
                        </field>
                        <field>
                            <name>PSCBFAL</name>
                            <description>GTIOCnB Pin Falling Input during GTIOCnA Value Low Source Counter Stop Enable</description>
                            <lsb>14</lsb>
                            <msb>14</msb>
                            <access>read-write</access>
                            <enumeratedValues>
                                </enumeratedValues>
                        </field>
                        <field>
                            <name>PSCBFAH</name>
                            <description>GTIOCnB Pin Falling Input during GTIOCnA Value High Source Counter Stop Enable</description>
                            <lsb>15</lsb>
                            <msb>15</msb>
                            <access>read-write</access>
                            <enumeratedValues>
                                </enumeratedValues>
                        </field>
                        <field>
                            <name>PSELCA</name>
                            <description>ELC_GPTA Event Source Counter Stop Enable</description>
                            <lsb>16</lsb>
                            <msb>16</msb>
                            <access>read-write</access>
                            <enumeratedValues>
                                </enumeratedValues>
                        </field>
                        <field>
                            <name>PSELCB</name>
                            <description>ELC_GPTB Event Source Counter Stop Enable</description>
                            <lsb>17</lsb>
                            <msb>17</msb>
                            <access>read-write</access>
                            <enumeratedValues>
                                </enumeratedValues>
                        </field>
                        <field>
                            <name>PSELCC</name>
                            <description>ELC_GPTC Event Source Counter Stop Enable</description>
                            <lsb>18</lsb>
                            <msb>18</msb>
                            <access>read-write</access>
                            <enumeratedValues>
                                </enumeratedValues>
                        </field>
                        <field>
                            <name>PSELCD</name>
                            <description>ELC_GPTD Event Source Counter Stop Enable</description>
                            <lsb>19</lsb>
                            <msb>19</msb>
                            <access>read-write</access>
                            <enumeratedValues>
                                </enumeratedValues>
                        </field>
                        <field>
                            <name>PSELCE</name>
                            <description>ELC_GPTE Event Source Counter Stop Enable</description>
                            <lsb>20</lsb>
                            <msb>20</msb>
                            <access>read-write</access>
                            <enumeratedValues>
                                </enumeratedValues>
                        </field>
                        <field>
                            <name>PSELCF</name>
                            <description>ELC_GPTF Event Source Counter Stop Enable</description>
                            <lsb>21</lsb>
                            <msb>21</msb>
                            <access>read-write</access>
                            <enumeratedValues>
                                </enumeratedValues>
                        </field>
                        <field>
                            <name>PSELCG</name>
                            <description>ELC_GPTG Event Source Counter Stop Enable</description>
                            <lsb>22</lsb>
                            <msb>22</msb>
                            <access>read-write</access>
                            <enumeratedValues>
                                </enumeratedValues>
                        </field>
                        <field>
                            <name>PSELCH</name>
                            <description>ELC_GPTH Event Source Counter Stop Enable</description>
                            <lsb>23</lsb>
                            <msb>23</msb>
                            <access>read-write</access>
                            <enumeratedValues>
                                </enumeratedValues>
                        </field>
                        <field>
                            <name>CSTOP</name>
                            <description>Software Source Counter Stop Enable</description>
                            <lsb>31</lsb>
                            <msb>31</msb>
                            <access>read-write</access>
                            <enumeratedValues>
                                </enumeratedValues>
                        </field>
                    </fields>
                </register>
                <register>
                    <name>GTCSR</name>
                    <description>General PWM Timer Clear Source Select Register</description>
                    <addressOffset>0x18</addressOffset>
                    <size>32</size>
                    <access>read-write</access>
                    <resetValue>0x00000000</resetValue>
                    <resetMask>0xffffffff</resetMask>
                    <fields>
                        <field>
                            <name>CSGTRGAR</name>
                            <description>GTETRGA Pin Rising Input Source Counter Clear Enable</description>
                            <lsb>0</lsb>
                            <msb>0</msb>
                            <access>read-write</access>
                            <enumeratedValues>
                                </enumeratedValues>
                        </field>
                        <field>
                            <name>CSGTRGAF</name>
                            <description>GTETRGA Pin Falling Input Source Counter Clear Enable</description>
                            <lsb>1</lsb>
                            <msb>1</msb>
                            <access>read-write</access>
                            <enumeratedValues>
                                </enumeratedValues>
                        </field>
                        <field>
                            <name>CSGTRGBR</name>
                            <description>GTETRGB Pin Rising Input Source Counter Clear Enable</description>
                            <lsb>2</lsb>
                            <msb>2</msb>
                            <access>read-write</access>
                            <enumeratedValues>
                                </enumeratedValues>
                        </field>
                        <field>
                            <name>CSGTRGBF</name>
                            <description>GTETRGB Pin Falling Input Source Counter Clear Enable</description>
                            <lsb>3</lsb>
                            <msb>3</msb>
                            <access>read-write</access>
                            <enumeratedValues>
                                </enumeratedValues>
                        </field>
                        <field>
                            <name>CSGTRGCR</name>
                            <description>GTETRGC Pin Rising Input Source Counter Clear Enable</description>
                            <lsb>4</lsb>
                            <msb>4</msb>
                            <access>read-write</access>
                            <enumeratedValues>
                                </enumeratedValues>
                        </field>
                        <field>
                            <name>CSGTRGCF</name>
                            <description>GTETRGC Pin Falling Input Source Counter Clear Enable</description>
                            <lsb>5</lsb>
                            <msb>5</msb>
                            <access>read-write</access>
                            <enumeratedValues>
                                </enumeratedValues>
                        </field>
                        <field>
                            <name>CSGTRGDR</name>
                            <description>GTETRGD Pin Rising Input Source Counter Clear Enable</description>
                            <lsb>6</lsb>
                            <msb>6</msb>
                            <access>read-write</access>
                            <enumeratedValues>
                                </enumeratedValues>
                        </field>
                        <field>
                            <name>CSGTRGDF</name>
                            <description>GTETRGD Pin Falling Input Source Counter Clear Enable</description>
                            <lsb>7</lsb>
                            <msb>7</msb>
                            <access>read-write</access>
                            <enumeratedValues>
                                </enumeratedValues>
                        </field>
                        <field>
                            <name>CSCARBL</name>
                            <description>GTIOCnA Pin Rising Input during GTIOCnB Value Low Source Counter Clear Enable</description>
                            <lsb>8</lsb>
                            <msb>8</msb>
                            <access>read-write</access>
                            <enumeratedValues>
                                </enumeratedValues>
                        </field>
                        <field>
                            <name>CSCARBH</name>
                            <description>GTIOCnA Pin Rising Input during GTIOCnB Value High Source Counter Clear Enable</description>
                            <lsb>9</lsb>
                            <msb>9</msb>
                            <access>read-write</access>
                            <enumeratedValues>
                                </enumeratedValues>
                        </field>
                        <field>
                            <name>CSCAFBL</name>
                            <description>GTIOCnA Pin Falling Input during GTIOCnB Value Low Source Counter Clear Enable</description>
                            <lsb>10</lsb>
                            <msb>10</msb>
                            <access>read-write</access>
                            <enumeratedValues>
                                </enumeratedValues>
                        </field>
                        <field>
                            <name>CSCAFBH</name>
                            <description>GTIOCnA Pin Falling Input during GTIOCnB Value High Source Counter Clear Enable</description>
                            <lsb>11</lsb>
                            <msb>11</msb>
                            <access>read-write</access>
                            <enumeratedValues>
                                </enumeratedValues>
                        </field>
                        <field>
                            <name>CSCBRAL</name>
                            <description>GTIOCnB Pin Rising Input during GTIOCnA Value Low Source Counter Clear Enable</description>
                            <lsb>12</lsb>
                            <msb>12</msb>
                            <access>read-write</access>
                            <enumeratedValues>
                                </enumeratedValues>
                        </field>
                        <field>
                            <name>CSCBRAH</name>
                            <description>GTIOCnB Pin Rising Input during GTIOCnA Value High Source Counter Clear Enable</description>
                            <lsb>13</lsb>
                            <msb>13</msb>
                            <access>read-write</access>
                            <enumeratedValues>
                                </enumeratedValues>
                        </field>
                        <field>
                            <name>CSCBFAL</name>
                            <description>GTIOCnB Pin Falling Input during GTIOCnA Value Low Source Counter Clear Enable</description>
                            <lsb>14</lsb>
                            <msb>14</msb>
                            <access>read-write</access>
                            <enumeratedValues>
                                </enumeratedValues>
                        </field>
                        <field>
                            <name>CSCBFAH</name>
                            <description>GTIOCnB Pin Falling Input during GTIOCnA Value High Source Counter Clear Enable</description>
                            <lsb>15</lsb>
                            <msb>15</msb>
                            <access>read-write</access>
                            <enumeratedValues>
                                </enumeratedValues>
                        </field>
                        <field>
                            <name>CSELCA</name>
                            <description>ELC_GPTA Event Source Counter Clear Enable</description>
                            <lsb>16</lsb>
                            <msb>16</msb>
                            <access>read-write</access>
                            <enumeratedValues>
                                </enumeratedValues>
                        </field>
                        <field>
                            <name>CSELCB</name>
                            <description>ELC_GPTB Event Source Counter Clear Enable</description>
                            <lsb>17</lsb>
                            <msb>17</msb>
                            <access>read-write</access>
                            <enumeratedValues>
                                </enumeratedValues>
                        </field>
                        <field>
                            <name>CSELCC</name>
                            <description>ELC_GPTC Event Source Counter Clear Enable</description>
                            <lsb>18</lsb>
                            <msb>18</msb>
                            <access>read-write</access>
                            <enumeratedValues>
                                </enumeratedValues>
                        </field>
                        <field>
                            <name>CSELCD</name>
                            <description>ELC_GPTD Event Source Counter Clear Enable</description>
                            <lsb>19</lsb>
                            <msb>19</msb>
                            <access>read-write</access>
                            <enumeratedValues>
                                </enumeratedValues>
                        </field>
                        <field>
                            <name>CSELCE</name>
                            <description>ELC_GPTE Event Source Counter Clear Enable</description>
                            <lsb>20</lsb>
                            <msb>20</msb>
                            <access>read-write</access>
                            <enumeratedValues>
                                </enumeratedValues>
                        </field>
                        <field>
                            <name>CSELCF</name>
                            <description>ELC_GPTF Event Source Counter Clear Enable</description>
                            <lsb>21</lsb>
                            <msb>21</msb>
                            <access>read-write</access>
                            <enumeratedValues>
                                </enumeratedValues>
                        </field>
                        <field>
                            <name>CSELCG</name>
                            <description>ELC_GPTG Event Source Counter Clear Enable</description>
                            <lsb>22</lsb>
                            <msb>22</msb>
                            <access>read-write</access>
                            <enumeratedValues>
                                </enumeratedValues>
                        </field>
                        <field>
                            <name>CSELCH</name>
                            <description>ELC_GPTH Event Source Counter Clear Enable</description>
                            <lsb>23</lsb>
                            <msb>23</msb>
                            <access>read-write</access>
                            <enumeratedValues>
                                </enumeratedValues>
                        </field>
                        <field>
                            <name>CCLR</name>
                            <description>Software Source Counter Clear Enable</description>
                            <lsb>31</lsb>
                            <msb>31</msb>
                            <access>read-write</access>
                            <enumeratedValues>
                                </enumeratedValues>
                        </field>
                    </fields>
                </register>
                <register>
                    <name>GTUPSR</name>
                    <description>General PWM Timer Up Count Source Select Register</description>
                    <addressOffset>0x1C</addressOffset>
                    <size>32</size>
                    <access>read-write</access>
                    <resetValue>0x00000000</resetValue>
                    <resetMask>0xffffffff</resetMask>
                    <fields>
                        <field>
                            <name>USGTRGAR</name>
                            <description>GTETRGA Pin Rising Input Source Counter Count Up Enable</description>
                            <lsb>0</lsb>
                            <msb>0</msb>
                            <access>read-write</access>
                            <enumeratedValues>
                                </enumeratedValues>
                        </field>
                        <field>
                            <name>USGTRGAF</name>
                            <description>GTETRGA Pin Falling Input Source Counter Count Up Enable</description>
                            <lsb>1</lsb>
                            <msb>1</msb>
                            <access>read-write</access>
                            <enumeratedValues>
                                </enumeratedValues>
                        </field>
                        <field>
                            <name>USGTRGBR</name>
                            <description>GTETRGB Pin Rising Input Source Counter Count Up Enable</description>
                            <lsb>2</lsb>
                            <msb>2</msb>
                            <access>read-write</access>
                            <enumeratedValues>
                                </enumeratedValues>
                        </field>
                        <field>
                            <name>USGTRGBF</name>
                            <description>GTETRGB Pin Falling Input Source Counter Count Up Enable</description>
                            <lsb>3</lsb>
                            <msb>3</msb>
                            <access>read-write</access>
                            <enumeratedValues>
                                </enumeratedValues>
                        </field>
                        <field>
                            <name>USGTRGCR</name>
                            <description>GTETRGC Pin Rising Input Source Counter Count Up Enable</description>
                            <lsb>4</lsb>
                            <msb>4</msb>
                            <access>read-write</access>
                            <enumeratedValues>
                                </enumeratedValues>
                        </field>
                        <field>
                            <name>USGTRGCF</name>
                            <description>GTETRGC Pin Falling Input Source Counter Count Up Enable</description>
                            <lsb>5</lsb>
                            <msb>5</msb>
                            <access>read-write</access>
                            <enumeratedValues>
                                </enumeratedValues>
                        </field>
                        <field>
                            <name>USGTRGDR</name>
                            <description>GTETRGD Pin Rising Input Source Counter Count Up Enable</description>
                            <lsb>6</lsb>
                            <msb>6</msb>
                            <access>read-write</access>
                            <enumeratedValues>
                                </enumeratedValues>
                        </field>
                        <field>
                            <name>USGTRGDF</name>
                            <description>GTETRGD Pin Falling Input Source Counter Count Up Enable</description>
                            <lsb>7</lsb>
                            <msb>7</msb>
                            <access>read-write</access>
                            <enumeratedValues>
                                </enumeratedValues>
                        </field>
                        <field>
                            <name>USCARBL</name>
                            <description>GTIOCnA Pin Rising Input during GTIOCnB Value Low Source Counter Count Up Enable</description>
                            <lsb>8</lsb>
                            <msb>8</msb>
                            <access>read-write</access>
                            <enumeratedValues>
                                </enumeratedValues>
                        </field>
                        <field>
                            <name>USCARBH</name>
                            <description>GTIOCnA Pin Rising Input during GTIOCnB Value High Source Counter Count Up Enable</description>
                            <lsb>9</lsb>
                            <msb>9</msb>
                            <access>read-write</access>
                            <enumeratedValues>
                                </enumeratedValues>
                        </field>
                        <field>
                            <name>USCAFBL</name>
                            <description>GTIOCnA Pin Falling Input during GTIOCnB Value Low Source Counter Count Up Enable</description>
                            <lsb>10</lsb>
                            <msb>10</msb>
                            <access>read-write</access>
                            <enumeratedValues>
                                </enumeratedValues>
                        </field>
                        <field>
                            <name>USCAFBH</name>
                            <description>GTIOCnA Pin Falling Input during GTIOCnB Value High Source Counter Count Up Enable</description>
                            <lsb>11</lsb>
                            <msb>11</msb>
                            <access>read-write</access>
                            <enumeratedValues>
                                </enumeratedValues>
                        </field>
                        <field>
                            <name>USCBRAL</name>
                            <description>GTIOCnB Pin Rising Input during GTIOCnA Value Low Source Counter Count Up Enable</description>
                            <lsb>12</lsb>
                            <msb>12</msb>
                            <access>read-write</access>
                            <enumeratedValues>
                                </enumeratedValues>
                        </field>
                        <field>
                            <name>USCBRAH</name>
                            <description>GTIOCnB Pin Rising Input during GTIOCnA Value High Source Counter Count Up Enable</description>
                            <lsb>13</lsb>
                            <msb>13</msb>
                            <access>read-write</access>
                            <enumeratedValues>
                                </enumeratedValues>
                        </field>
                        <field>
                            <name>USCBFAL</name>
                            <description>GTIOCnB Pin Falling Input during GTIOCnA Value Low Source Counter Count Up Enable</description>
                            <lsb>14</lsb>
                            <msb>14</msb>
                            <access>read-write</access>
                            <enumeratedValues>
                                </enumeratedValues>
                        </field>
                        <field>
                            <name>USCBFAH</name>
                            <description>GTIOCnB Pin Falling Input during GTIOCnA Value High Source Counter Count Up Enable</description>
                            <lsb>15</lsb>
                            <msb>15</msb>
                            <access>read-write</access>
                            <enumeratedValues>
                                </enumeratedValues>
                        </field>
                        <field>
                            <name>USELCA</name>
                            <description>ELC_GPTA Event Source Counter Count Up Enable</description>
                            <lsb>16</lsb>
                            <msb>16</msb>
                            <access>read-write</access>
                            <enumeratedValues>
                                </enumeratedValues>
                        </field>
                        <field>
                            <name>USELCB</name>
                            <description>ELC_GPTB Event Source Counter Count Up Enable</description>
                            <lsb>17</lsb>
                            <msb>17</msb>
                            <access>read-write</access>
                            <enumeratedValues>
                                </enumeratedValues>
                        </field>
                        <field>
                            <name>USELCC</name>
                            <description>ELC_GPTC Event Source Counter Count Up Enable</description>
                            <lsb>18</lsb>
                            <msb>18</msb>
                            <access>read-write</access>
                            <enumeratedValues>
                                </enumeratedValues>
                        </field>
                        <field>
                            <name>USELCD</name>
                            <description>ELC_GPTD Event Source Counter Count Up Enable</description>
                            <lsb>19</lsb>
                            <msb>19</msb>
                            <access>read-write</access>
                            <enumeratedValues>
                                </enumeratedValues>
                        </field>
                        <field>
                            <name>USELCE</name>
                            <description>ELC_GPTE Event Source Counter Count Up Enable</description>
                            <lsb>20</lsb>
                            <msb>20</msb>
                            <access>read-write</access>
                            <enumeratedValues>
                                </enumeratedValues>
                        </field>
                        <field>
                            <name>USELCF</name>
                            <description>ELC_GPTF Event Source Counter Count Up Enable</description>
                            <lsb>21</lsb>
                            <msb>21</msb>
                            <access>read-write</access>
                            <enumeratedValues>
                                </enumeratedValues>
                        </field>
                        <field>
                            <name>USELCG</name>
                            <description>ELC_GPTG Event Source Counter Count Up Enable</description>
                            <lsb>22</lsb>
                            <msb>22</msb>
                            <access>read-write</access>
                            <enumeratedValues>
                                </enumeratedValues>
                        </field>
                        <field>
                            <name>USELCH</name>
                            <description>ELC_GPTH Event Source Counter Count Up Enable</description>
                            <lsb>23</lsb>
                            <msb>23</msb>
                            <access>read-write</access>
                            <enumeratedValues>
                                </enumeratedValues>
                        </field>
                    </fields>
                </register>
                <register>
                    <name>GTDNSR</name>
                    <description>General PWM Timer Down Count Source Select Register</description>
                    <addressOffset>0x20</addressOffset>
                    <size>32</size>
                    <access>read-write</access>
                    <resetValue>0x00000000</resetValue>
                    <resetMask>0xffffffff</resetMask>
                    <fields>
                        <field>
                            <name>DSGTRGAR</name>
                            <description>GTETRGA Pin Rising Input Source Counter Count Down Enable</description>
                            <lsb>0</lsb>
                            <msb>0</msb>
                            <access>read-write</access>
                            <enumeratedValues>
                                </enumeratedValues>
                        </field>
                        <field>
                            <name>DSGTRGAF</name>
                            <description>GTETRGA Pin Falling Input Source Counter Count Down Enable</description>
                            <lsb>1</lsb>
                            <msb>1</msb>
                            <access>read-write</access>
                            <enumeratedValues>
                                </enumeratedValues>
                        </field>
                        <field>
                            <name>DSGTRGBR</name>
                            <description>GTETRGB Pin Rising Input Source Counter Count Down Enable</description>
                            <lsb>2</lsb>
                            <msb>2</msb>
                            <access>read-write</access>
                            <enumeratedValues>
                                </enumeratedValues>
                        </field>
                        <field>
                            <name>DSGTRGBF</name>
                            <description>GTETRGB Pin Falling Input Source Counter Count Down Enable</description>
                            <lsb>3</lsb>
                            <msb>3</msb>
                            <access>read-write</access>
                            <enumeratedValues>
                                </enumeratedValues>
                        </field>
                        <field>
                            <name>DSGTRGCR</name>
                            <description>GTETRGC Pin Rising Input Source Counter Count Down Enable</description>
                            <lsb>4</lsb>
                            <msb>4</msb>
                            <access>read-write</access>
                            <enumeratedValues>
                                </enumeratedValues>
                        </field>
                        <field>
                            <name>DSGTRGCF</name>
                            <description>GTETRGC Pin Falling Input Source Counter Count Down Enable</description>
                            <lsb>5</lsb>
                            <msb>5</msb>
                            <access>read-write</access>
                            <enumeratedValues>
                                </enumeratedValues>
                        </field>
                        <field>
                            <name>DSGTRGDR</name>
                            <description>GTETRGD Pin Rising Input Source Counter Count Down Enable</description>
                            <lsb>6</lsb>
                            <msb>6</msb>
                            <access>read-write</access>
                            <enumeratedValues>
                                </enumeratedValues>
                        </field>
                        <field>
                            <name>DSGTRGDF</name>
                            <description>GTETRGD Pin Falling Input Source Counter Count Down Enable</description>
                            <lsb>7</lsb>
                            <msb>7</msb>
                            <access>read-write</access>
                            <enumeratedValues>
                                </enumeratedValues>
                        </field>
                        <field>
                            <name>DSCARBL</name>
                            <description>GTIOCnA Pin Rising Input during GTIOCnB Value Low Source Counter Count Down Enable</description>
                            <lsb>8</lsb>
                            <msb>8</msb>
                            <access>read-write</access>
                            <enumeratedValues>
                                </enumeratedValues>
                        </field>
                        <field>
                            <name>DSCARBH</name>
                            <description>GTIOCnA Pin Rising Input during GTIOCnB Value High Source Counter Count Down Enable</description>
                            <lsb>9</lsb>
                            <msb>9</msb>
                            <access>read-write</access>
                            <enumeratedValues>
                                </enumeratedValues>
                        </field>
                        <field>
                            <name>DSCAFBL</name>
                            <description>GTIOCnA Pin Falling Input during GTIOCnB Value Low Source Counter Count Down Enable</description>
                            <lsb>10</lsb>
                            <msb>10</msb>
                            <access>read-write</access>
                            <enumeratedValues>
                                </enumeratedValues>
                        </field>
                        <field>
                            <name>DSCAFBH</name>
                            <description>GTIOCnA Pin Falling Input during GTIOCnB Value High Source Counter Count Down Enable</description>
                            <lsb>11</lsb>
                            <msb>11</msb>
                            <access>read-write</access>
                            <enumeratedValues>
                                </enumeratedValues>
                        </field>
                        <field>
                            <name>DSCBRAL</name>
                            <description>GTIOCnB Pin Rising Input during GTIOCnA Value Low Source Counter Count Down Enable</description>
                            <lsb>12</lsb>
                            <msb>12</msb>
                            <access>read-write</access>
                            <enumeratedValues>
                                </enumeratedValues>
                        </field>
                        <field>
                            <name>DSCBRAH</name>
                            <description>GTIOCnB Pin Rising Input during GTIOCnA Value High Source Counter Count Down Enable</description>
                            <lsb>13</lsb>
                            <msb>13</msb>
                            <access>read-write</access>
                            <enumeratedValues>
                                </enumeratedValues>
                        </field>
                        <field>
                            <name>DSCBFAL</name>
                            <description>GTIOCnB Pin Falling Input during GTIOCnA Value Low Source Counter Count Down Enable</description>
                            <lsb>14</lsb>
                            <msb>14</msb>
                            <access>read-write</access>
                            <enumeratedValues>
                                </enumeratedValues>
                        </field>
                        <field>
                            <name>DSCBFAH</name>
                            <description>GTIOCnB Pin Falling Input during GTIOCnA Value High Source Counter Count Down Enable</description>
                            <lsb>15</lsb>
                            <msb>15</msb>
                            <access>read-write</access>
                            <enumeratedValues>
                                </enumeratedValues>
                        </field>
                        <field>
                            <name>DSELCA</name>
                            <description>ELC_GPTA Event Source Counter Count Down Enable</description>
                            <lsb>16</lsb>
                            <msb>16</msb>
                            <access>read-write</access>
                            <enumeratedValues>
                                </enumeratedValues>
                        </field>
                        <field>
                            <name>DSELCB</name>
                            <description>ELC_GPTB Event Source Counter Count Down Enable</description>
                            <lsb>17</lsb>
                            <msb>17</msb>
                            <access>read-write</access>
                            <enumeratedValues>
                                </enumeratedValues>
                        </field>
                        <field>
                            <name>DSELCC</name>
                            <description>ELC_GPTC Event Source Counter Count Down Enable</description>
                            <lsb>18</lsb>
                            <msb>18</msb>
                            <access>read-write</access>
                            <enumeratedValues>
                                </enumeratedValues>
                        </field>
                        <field>
                            <name>DSELCD</name>
                            <description>ELC_GPTD Event Source Counter Count Down Enable</description>
                            <lsb>19</lsb>
                            <msb>19</msb>
                            <access>read-write</access>
                            <enumeratedValues>
                                </enumeratedValues>
                        </field>
                        <field>
                            <name>DSELCE</name>
                            <description>ELC_GPTE Event Source Counter Count Down Enable</description>
                            <lsb>20</lsb>
                            <msb>20</msb>
                            <access>read-write</access>
                            <enumeratedValues>
                                </enumeratedValues>
                        </field>
                        <field>
                            <name>DSELCF</name>
                            <description>ELC_GPTF Event Source Counter Count Down Enable</description>
                            <lsb>21</lsb>
                            <msb>21</msb>
                            <access>read-write</access>
                            <enumeratedValues>
                                </enumeratedValues>
                        </field>
                        <field>
                            <name>DSELCG</name>
                            <description>ELC_GPTG Event Source Counter Count Down Enable</description>
                            <lsb>22</lsb>
                            <msb>22</msb>
                            <access>read-write</access>
                            <enumeratedValues>
                                </enumeratedValues>
                        </field>
                        <field>
                            <name>DSELCH</name>
                            <description>ELC_GPTF Event Source Counter Count Down Enable</description>
                            <lsb>23</lsb>
                            <msb>23</msb>
                            <access>read-write</access>
                            <enumeratedValues>
                                </enumeratedValues>
                        </field>
                    </fields>
                </register>
                <register>
                    <name>GTICASR</name>
                    <description>General PWM Timer Input Capture Source Select Register A</description>
                    <addressOffset>0x24</addressOffset>
                    <size>32</size>
                    <access>read-write</access>
                    <resetValue>0x00000000</resetValue>
                    <resetMask>0xffffffff</resetMask>
                    <fields>
                        <field>
                            <name>ASGTRGAR</name>
                            <description>GTETRGA Pin Rising Input Source GTCCRA Input Capture Enable</description>
                            <lsb>0</lsb>
                            <msb>0</msb>
                            <access>read-write</access>
                            <enumeratedValues>
                                </enumeratedValues>
                        </field>
                        <field>
                            <name>ASGTRGAF</name>
                            <description>GTETRGA Pin Falling Input Source GTCCRA Input Capture Enable</description>
                            <lsb>1</lsb>
                            <msb>1</msb>
                            <access>read-write</access>
                            <enumeratedValues>
                                </enumeratedValues>
                        </field>
                        <field>
                            <name>ASGTRGBR</name>
                            <description>GTETRGB Pin Rising Input Source GTCCRA Input Capture Enable</description>
                            <lsb>2</lsb>
                            <msb>2</msb>
                            <access>read-write</access>
                            <enumeratedValues>
                                </enumeratedValues>
                        </field>
                        <field>
                            <name>ASGTRGBF</name>
                            <description>GTETRGB Pin Falling Input Source GTCCRA Input Capture Enable</description>
                            <lsb>3</lsb>
                            <msb>3</msb>
                            <access>read-write</access>
                            <enumeratedValues>
                                </enumeratedValues>
                        </field>
                        <field>
                            <name>ASGTRGCR</name>
                            <description>GTETRGC Pin Rising Input Source GTCCRA Input Capture Enable</description>
                            <lsb>4</lsb>
                            <msb>4</msb>
                            <access>read-write</access>
                            <enumeratedValues>
                                </enumeratedValues>
                        </field>
                        <field>
                            <name>ASGTRGCF</name>
                            <description>GTETRGC Pin Falling Input Source GTCCRA Input Capture Enable</description>
                            <lsb>5</lsb>
                            <msb>5</msb>
                            <access>read-write</access>
                            <enumeratedValues>
                                </enumeratedValues>
                        </field>
                        <field>
                            <name>ASGTRGDR</name>
                            <description>GTETRGD Pin Rising Input Source GTCCRA Input Capture Enable</description>
                            <lsb>6</lsb>
                            <msb>6</msb>
                            <access>read-write</access>
                            <enumeratedValues>
                                </enumeratedValues>
                        </field>
                        <field>
                            <name>ASGTRGDF</name>
                            <description>GTETRGD Pin Falling Input Source GTCCRA Input Capture Enable</description>
                            <lsb>7</lsb>
                            <msb>7</msb>
                            <access>read-write</access>
                            <enumeratedValues>
                                </enumeratedValues>
                        </field>
                        <field>
                            <name>ASCARBL</name>
                            <description>GTIOCnA Pin Rising Input during GTIOCnB Value Low Source GTCCRA Input Capture Enable</description>
                            <lsb>8</lsb>
                            <msb>8</msb>
                            <access>read-write</access>
                            <enumeratedValues>
                                </enumeratedValues>
                        </field>
                        <field>
                            <name>ASCARBH</name>
                            <description>GTIOCnA Pin Rising Input during GTIOCnB Value High Source GTCCRA Input Capture Enable</description>
                            <lsb>9</lsb>
                            <msb>9</msb>
                            <access>read-write</access>
                            <enumeratedValues>
                                </enumeratedValues>
                        </field>
                        <field>
                            <name>ASCAFBL</name>
                            <description>GTIOCnA Pin Falling Input during GTIOCnB Value Low Source GTCCRA Input Capture Enable</description>
                            <lsb>10</lsb>
                            <msb>10</msb>
                            <access>read-write</access>
                            <enumeratedValues>
                                </enumeratedValues>
                        </field>
                        <field>
                            <name>ASCAFBH</name>
                            <description>GTIOCnA Pin Falling Input during GTIOCnB Value High Source GTCCRA Input Capture Enable</description>
                            <lsb>11</lsb>
                            <msb>11</msb>
                            <access>read-write</access>
                            <enumeratedValues>
                                </enumeratedValues>
                        </field>
                        <field>
                            <name>ASCBRAL</name>
                            <description>GTIOCnB Pin Rising Input during GTIOCnA Value Low Source GTCCRA Input Capture Enable</description>
                            <lsb>12</lsb>
                            <msb>12</msb>
                            <access>read-write</access>
                            <enumeratedValues>
                                </enumeratedValues>
                        </field>
                        <field>
                            <name>ASCBRAH</name>
                            <description>GTIOCnB Pin Rising Input during GTIOCnA Value High Source GTCCRA Input Capture Enable</description>
                            <lsb>13</lsb>
                            <msb>13</msb>
                            <access>read-write</access>
                            <enumeratedValues>
                                </enumeratedValues>
                        </field>
                        <field>
                            <name>ASCBFAL</name>
                            <description>GTIOCnB Pin Falling Input during GTIOCnA Value Low Source GTCCRA Input Capture Enable</description>
                            <lsb>14</lsb>
                            <msb>14</msb>
                            <access>read-write</access>
                            <enumeratedValues>
                                </enumeratedValues>
                        </field>
                        <field>
                            <name>ASCBFAH</name>
                            <description>GTIOCnB Pin Falling Input during GTIOCnA Value High Source GTCCRA Input Capture Enable</description>
                            <lsb>15</lsb>
                            <msb>15</msb>
                            <access>read-write</access>
                            <enumeratedValues>
                                </enumeratedValues>
                        </field>
                        <field>
                            <name>ASELCA</name>
                            <description>ELC_GPTA Event Source GTCCRA Input Capture Enable</description>
                            <lsb>16</lsb>
                            <msb>16</msb>
                            <access>read-write</access>
                            <enumeratedValues>
                                </enumeratedValues>
                        </field>
                        <field>
                            <name>ASELCB</name>
                            <description>ELC_GPTB Event Source GTCCRA Input Capture Enable</description>
                            <lsb>17</lsb>
                            <msb>17</msb>
                            <access>read-write</access>
                            <enumeratedValues>
                                </enumeratedValues>
                        </field>
                        <field>
                            <name>ASELCC</name>
                            <description>ELC_GPTC Event Source GTCCRA Input Capture Enable</description>
                            <lsb>18</lsb>
                            <msb>18</msb>
                            <access>read-write</access>
                            <enumeratedValues>
                                </enumeratedValues>
                        </field>
                        <field>
                            <name>ASELCD</name>
                            <description>ELC_GPTD Event Source GTCCRA Input Capture Enable</description>
                            <lsb>19</lsb>
                            <msb>19</msb>
                            <access>read-write</access>
                            <enumeratedValues>
                                </enumeratedValues>
                        </field>
                        <field>
                            <name>ASELCE</name>
                            <description>ELC_GPTE Event Source GTCCRA Input Capture Enable</description>
                            <lsb>20</lsb>
                            <msb>20</msb>
                            <access>read-write</access>
                            <enumeratedValues>
                                </enumeratedValues>
                        </field>
                        <field>
                            <name>ASELCF</name>
                            <description>ELC_GPTF Event Source GTCCRA Input Capture Enable</description>
                            <lsb>21</lsb>
                            <msb>21</msb>
                            <access>read-write</access>
                            <enumeratedValues>
                                </enumeratedValues>
                        </field>
                        <field>
                            <name>ASELCG</name>
                            <description>ELC_GPTG Event Source GTCCRA Input Capture Enable</description>
                            <lsb>22</lsb>
                            <msb>22</msb>
                            <access>read-write</access>
                            <enumeratedValues>
                                </enumeratedValues>
                        </field>
                        <field>
                            <name>ASELCH</name>
                            <description>ELC_GPTH Event Source GTCCRA Input Capture Enable</description>
                            <lsb>23</lsb>
                            <msb>23</msb>
                            <access>read-write</access>
                            <enumeratedValues>
                                </enumeratedValues>
                        </field>
                    </fields>
                </register>
                <register>
                    <name>GTICBSR</name>
                    <description>General PWM Timer Input Capture Source Select Register B</description>
                    <addressOffset>0x28</addressOffset>
                    <size>32</size>
                    <access>read-write</access>
                    <resetValue>0x00000000</resetValue>
                    <resetMask>0xffffffff</resetMask>
                    <fields>
                        <field>
                            <name>BSGTRGAR</name>
                            <description>GTETRGA Pin Rising Input Source GTCCRB Input Capture Enable</description>
                            <lsb>0</lsb>
                            <msb>0</msb>
                            <access>read-write</access>
                            <enumeratedValues>
                                </enumeratedValues>
                        </field>
                        <field>
                            <name>BSGTRGAF</name>
                            <description>GTETRGA Pin Falling Input Source GTCCRB Input Capture Enable</description>
                            <lsb>1</lsb>
                            <msb>1</msb>
                            <access>read-write</access>
                            <enumeratedValues>
                                </enumeratedValues>
                        </field>
                        <field>
                            <name>BSGTRGBR</name>
                            <description>GTETRGB Pin Rising Input Source GTCCRB Input Capture Enable</description>
                            <lsb>2</lsb>
                            <msb>2</msb>
                            <access>read-write</access>
                            <enumeratedValues>
                                </enumeratedValues>
                        </field>
                        <field>
                            <name>BSGTRGBF</name>
                            <description>GTETRGB Pin Falling Input Source GTCCRB Input Capture Enable</description>
                            <lsb>3</lsb>
                            <msb>3</msb>
                            <access>read-write</access>
                            <enumeratedValues>
                                </enumeratedValues>
                        </field>
                        <field>
                            <name>BSGTRGCR</name>
                            <description>GTETRGC Pin Rising Input Source GTCCRB Input Capture Enable</description>
                            <lsb>4</lsb>
                            <msb>4</msb>
                            <access>read-write</access>
                            <enumeratedValues>
                                </enumeratedValues>
                        </field>
                        <field>
                            <name>BSGTRGCF</name>
                            <description>GTETRGC Pin Falling Input Source GTCCRB Input Capture Enable</description>
                            <lsb>5</lsb>
                            <msb>5</msb>
                            <access>read-write</access>
                            <enumeratedValues>
                                </enumeratedValues>
                        </field>
                        <field>
                            <name>BSGTRGDR</name>
                            <description>GTETRGD Pin Rising Input Source GTCCRB Input Capture Enable</description>
                            <lsb>6</lsb>
                            <msb>6</msb>
                            <access>read-write</access>
                            <enumeratedValues>
                                </enumeratedValues>
                        </field>
                        <field>
                            <name>BSGTRGDF</name>
                            <description>GTETRGD Pin Falling Input Source GTCCRB Input Capture Enable</description>
                            <lsb>7</lsb>
                            <msb>7</msb>
                            <access>read-write</access>
                            <enumeratedValues>
                                </enumeratedValues>
                        </field>
                        <field>
                            <name>BSCARBL</name>
                            <description>GTIOCnA Pin Rising Input during GTIOCnB Value Low Source GTCCRB Input Capture Enable</description>
                            <lsb>8</lsb>
                            <msb>8</msb>
                            <access>read-write</access>
                            <enumeratedValues>
                                </enumeratedValues>
                        </field>
                        <field>
                            <name>BSCARBH</name>
                            <description>GTIOCnA Pin Rising Input during GTIOCnB Value High Source GTCCRB Input Capture Enable</description>
                            <lsb>9</lsb>
                            <msb>9</msb>
                            <access>read-write</access>
                            <enumeratedValues>
                                </enumeratedValues>
                        </field>
                        <field>
                            <name>BSCAFBL</name>
                            <description>GTIOCnA Pin Falling Input during GTIOCnB Value Low Source GTCCRB Input Capture Enable</description>
                            <lsb>10</lsb>
                            <msb>10</msb>
                            <access>read-write</access>
                            <enumeratedValues>
                                </enumeratedValues>
                        </field>
                        <field>
                            <name>BSCAFBH</name>
                            <description>GTIOCnA Pin Falling Input during GTIOCnB Value High Source GTCCRB Input Capture Enable</description>
                            <lsb>11</lsb>
                            <msb>11</msb>
                            <access>read-write</access>
                            <enumeratedValues>
                                </enumeratedValues>
                        </field>
                        <field>
                            <name>BSCBRAL</name>
                            <description>GTIOCnB Pin Rising Input during GTIOCnA Value Low Source GTCCRB Input Capture Enable</description>
                            <lsb>12</lsb>
                            <msb>12</msb>
                            <access>read-write</access>
                            <enumeratedValues>
                                </enumeratedValues>
                        </field>
                        <field>
                            <name>BSCBRAH</name>
                            <description>GTIOCnB Pin Rising Input during GTIOCnA Value High Source GTCCRB Input Capture Enable</description>
                            <lsb>13</lsb>
                            <msb>13</msb>
                            <access>read-write</access>
                            <enumeratedValues>
                                </enumeratedValues>
                        </field>
                        <field>
                            <name>BSCBFAL</name>
                            <description>GTIOCnB Pin Falling Input during GTIOCnA Value Low Source GTCCRB Input Capture Enable</description>
                            <lsb>14</lsb>
                            <msb>14</msb>
                            <access>read-write</access>
                            <enumeratedValues>
                                </enumeratedValues>
                        </field>
                        <field>
                            <name>BSCBFAH</name>
                            <description>GTIOCnB Pin Falling Input during GTIOCnA Value High Source GTCCRB Input Capture Enable</description>
                            <lsb>15</lsb>
                            <msb>15</msb>
                            <access>read-write</access>
                            <enumeratedValues>
                                </enumeratedValues>
                        </field>
                        <field>
                            <name>BSELCA</name>
                            <description>ELC_GPTA Event Source GTCCRB Input Capture Enable</description>
                            <lsb>16</lsb>
                            <msb>16</msb>
                            <access>read-write</access>
                            <enumeratedValues>
                                </enumeratedValues>
                        </field>
                        <field>
                            <name>BSELCB</name>
                            <description>ELC_GPTB Event Source GTCCRB Input Capture Enable</description>
                            <lsb>17</lsb>
                            <msb>17</msb>
                            <access>read-write</access>
                            <enumeratedValues>
                                </enumeratedValues>
                        </field>
                        <field>
                            <name>BSELCC</name>
                            <description>ELC_GPTC Event Source GTCCRB Input Capture Enable</description>
                            <lsb>18</lsb>
                            <msb>18</msb>
                            <access>read-write</access>
                            <enumeratedValues>
                                </enumeratedValues>
                        </field>
                        <field>
                            <name>BSELCD</name>
                            <description>ELC_GPTD Event Source GTCCRB Input Capture Enable</description>
                            <lsb>19</lsb>
                            <msb>19</msb>
                            <access>read-write</access>
                            <enumeratedValues>
                                </enumeratedValues>
                        </field>
                        <field>
                            <name>BSELCE</name>
                            <description>ELC_GPTE Event Source GTCCRB Input Capture Enable</description>
                            <lsb>20</lsb>
                            <msb>20</msb>
                            <access>read-write</access>
                            <enumeratedValues>
                                </enumeratedValues>
                        </field>
                        <field>
                            <name>BSELCF</name>
                            <description>ELC_GPTF Event Source GTCCRB Input Capture Enable</description>
                            <lsb>21</lsb>
                            <msb>21</msb>
                            <access>read-write</access>
                            <enumeratedValues>
                                </enumeratedValues>
                        </field>
                        <field>
                            <name>BSELCG</name>
                            <description>ELC_GPTG Event Source GTCCRB Input Capture Enable</description>
                            <lsb>22</lsb>
                            <msb>22</msb>
                            <access>read-write</access>
                            <enumeratedValues>
                                </enumeratedValues>
                        </field>
                        <field>
                            <name>BSELCH</name>
                            <description>ELC_GPTH Event Source GTCCRB Input Capture Enable</description>
                            <lsb>23</lsb>
                            <msb>23</msb>
                            <access>read-write</access>
                            <enumeratedValues>
                                </enumeratedValues>
                        </field>
                    </fields>
                </register>
                <register>
                    <name>GTCR</name>
                    <description>General PWM Timer Control Register</description>
                    <addressOffset>0x2C</addressOffset>
                    <size>32</size>
                    <access>read-write</access>
                    <resetValue>0x00000000</resetValue>
                    <resetMask>0xffffffff</resetMask>
                    <fields>
                        <field>
                            <name>CST</name>
                            <description>Count Start</description>
                            <lsb>0</lsb>
                            <msb>0</msb>
                            <access>read-write</access>
                            <enumeratedValues>
                                </enumeratedValues>
                        </field>
                        <field>
                            <name>MD</name>
                            <description>Mode Select</description>
                            <lsb>16</lsb>
                            <msb>18</msb>
                            <access>read-write</access>
                            <enumeratedValues>
                                </enumeratedValues>
                        </field>
                        <field>
                            <name>TPCS</name>
                            <description>Timer Prescaler Select</description>
                            <lsb>23</lsb>
                            <msb>26</msb>
                            <access>read-write</access>
                            <enumeratedValues>
                                </enumeratedValues>
                        </field>
                    </fields>
                </register>
                <register>
                    <name>GTUDDTYC</name>
                    <description>General PWM Timer Count Direction and Duty Setting Register</description>
                    <addressOffset>0x30</addressOffset>
                    <size>32</size>
                    <access>read-write</access>
                    <resetValue>0x00000001</resetValue>
                    <resetMask>0xffffffff</resetMask>
                    <fields>
                        <field>
                            <name>UD</name>
                            <description>Count Direction Setting</description>
                            <lsb>0</lsb>
                            <msb>0</msb>
                            <access>read-write</access>
                            <enumeratedValues>
                                </enumeratedValues>
                        </field>
                        <field>
                            <name>UDF</name>
                            <description>Forcible Count Direction Setting</description>
                            <lsb>1</lsb>
                            <msb>1</msb>
                            <access>read-write</access>
                            <enumeratedValues>
                                </enumeratedValues>
                        </field>
                        <field>
                            <name>OADTY</name>
                            <description>GTIOCnA Output Duty Setting</description>
                            <lsb>16</lsb>
                            <msb>17</msb>
                            <access>read-write</access>
                            <enumeratedValues>
                                </enumeratedValues>
                        </field>
                        <field>
                            <name>OADTYF</name>
                            <description>Forcible GTIOCnA Output Duty Setting</description>
                            <lsb>18</lsb>
                            <msb>18</msb>
                            <access>read-write</access>
                            <enumeratedValues>
                                </enumeratedValues>
                        </field>
                        <field>
                            <name>OADTYR</name>
                            <description>GTIOCnA Output Value Selecting after Releasing 0%/100% Duty Setting</description>
                            <lsb>19</lsb>
                            <msb>19</msb>
                            <access>read-write</access>
                            <enumeratedValues>
                                </enumeratedValues>
                        </field>
                        <field>
                            <name>OBDTY</name>
                            <description>GTIOCnB Output Duty Setting</description>
                            <lsb>24</lsb>
                            <msb>25</msb>
                            <access>read-write</access>
                            <enumeratedValues>
                                </enumeratedValues>
                        </field>
                        <field>
                            <name>OBDTYF</name>
                            <description>Forcible GTIOCnB Output Duty Setting</description>
                            <lsb>26</lsb>
                            <msb>26</msb>
                            <access>read-write</access>
                            <enumeratedValues>
                                </enumeratedValues>
                        </field>
                        <field>
                            <name>OBDTYR</name>
                            <description>GTIOCnB Output Value Selecting after Releasing 0%/100% Duty Setting</description>
                            <lsb>27</lsb>
                            <msb>27</msb>
                            <access>read-write</access>
                            <enumeratedValues>
                                </enumeratedValues>
                        </field>
                    </fields>
                </register>
                <register>
                    <name>GTIOR</name>
                    <description>General PWM Timer I/O Control Register</description>
                    <addressOffset>0x34</addressOffset>
                    <size>32</size>
                    <access>read-write</access>
                    <resetValue>0x00000000</resetValue>
                    <resetMask>0xffffffff</resetMask>
                    <fields>
                        <field>
                            <name>GTIOA</name>
                            <description>GTIOCnA Pin Function Select</description>
                            <lsb>0</lsb>
                            <msb>4</msb>
                            <access>read-write</access>
                        </field>
                        <field>
                            <name>OADFLT</name>
                            <description>GTIOCnA Pin Output Value Setting at the Count Stop</description>
                            <lsb>6</lsb>
                            <msb>6</msb>
                            <access>read-write</access>
                            <enumeratedValues>
                                </enumeratedValues>
                        </field>
                        <field>
                            <name>OAHLD</name>
                            <description>GTIOCnA Pin Output Setting at the Start/Stop Count</description>
                            <lsb>7</lsb>
                            <msb>7</msb>
                            <access>read-write</access>
                            <enumeratedValues>
                                </enumeratedValues>
                        </field>
                        <field>
                            <name>OAE</name>
                            <description>GTIOCnA Pin Output Enable</description>
                            <lsb>8</lsb>
                            <msb>8</msb>
                            <access>read-write</access>
                            <enumeratedValues>
                                </enumeratedValues>
                        </field>
                        <field>
                            <name>OADF</name>
                            <description>GTIOCnA Pin Disable Value Setting</description>
                            <lsb>9</lsb>
                            <msb>10</msb>
                            <access>read-write</access>
                            <enumeratedValues>
                                </enumeratedValues>
                        </field>
                        <field>
                            <name>NFAEN</name>
                            <description>Noise Filter A Enable</description>
                            <lsb>13</lsb>
                            <msb>13</msb>
                            <access>read-write</access>
                            <enumeratedValues>
                                </enumeratedValues>
                        </field>
                        <field>
                            <name>NFCSA</name>
                            <description>Noise Filter A Sampling Clock Select</description>
                            <lsb>14</lsb>
                            <msb>15</msb>
                            <access>read-write</access>
                            <enumeratedValues>
                                </enumeratedValues>
                        </field>
                        <field>
                            <name>GTIOB</name>
                            <description>GTIOCnB Pin Function Select</description>
                            <lsb>16</lsb>
                            <msb>20</msb>
                            <access>read-write</access>
                        </field>
                        <field>
                            <name>OBDFLT</name>
                            <description>GTIOCnB Pin Output Value Setting at the Count Stop</description>
                            <lsb>22</lsb>
                            <msb>22</msb>
                            <access>read-write</access>
                            <enumeratedValues>
                                </enumeratedValues>
                        </field>
                        <field>
                            <name>OBHLD</name>
                            <description>GTIOCnB Pin Output Setting at the Start/Stop Count</description>
                            <lsb>23</lsb>
                            <msb>23</msb>
                            <access>read-write</access>
                            <enumeratedValues>
                                </enumeratedValues>
                        </field>
                        <field>
                            <name>OBE</name>
                            <description>GTIOCnB Pin Output Enable</description>
                            <lsb>24</lsb>
                            <msb>24</msb>
                            <access>read-write</access>
                            <enumeratedValues>
                                </enumeratedValues>
                        </field>
                        <field>
                            <name>OBDF</name>
                            <description>GTIOCnB Pin Disable Value Setting</description>
                            <lsb>25</lsb>
                            <msb>26</msb>
                            <access>read-write</access>
                            <enumeratedValues>
                                </enumeratedValues>
                        </field>
                        <field>
                            <name>NFBEN</name>
                            <description>Noise Filter B Enable</description>
                            <lsb>29</lsb>
                            <msb>29</msb>
                            <access>read-write</access>
                            <enumeratedValues>
                                </enumeratedValues>
                        </field>
                        <field>
                            <name>NFCSB</name>
                            <description>Noise Filter B Sampling Clock Select</description>
                            <lsb>30</lsb>
                            <msb>31</msb>
                            <access>read-write</access>
                            <enumeratedValues>
                                </enumeratedValues>
                        </field>
                    </fields>
                </register>
                <register>
                    <name>GTINTAD</name>
                    <description>General PWM Timer Interrupt Output Setting Register</description>
                    <addressOffset>0x38</addressOffset>
                    <size>32</size>
                    <access>read-write</access>
                    <resetValue>0x00000000</resetValue>
                    <resetMask>0xffffffff</resetMask>
                    <fields>
                        <field>
                            <name>GRP</name>
                            <description>Output Disable Source Select</description>
                            <lsb>24</lsb>
                            <msb>25</msb>
                            <access>read-write</access>
                            <enumeratedValues>
                                </enumeratedValues>
                        </field>
                        <field>
                            <name>GRPABH</name>
                            <description>Same Time Output Level High Disable Request Enable</description>
                            <lsb>29</lsb>
                            <msb>29</msb>
                            <access>read-write</access>
                            <enumeratedValues>
                                </enumeratedValues>
                        </field>
                        <field>
                            <name>GRPABL</name>
                            <description>Same Time Output Level Low Disable Request Enable</description>
                            <lsb>30</lsb>
                            <msb>30</msb>
                            <access>read-write</access>
                            <enumeratedValues>
                                </enumeratedValues>
                        </field>
                    </fields>
                </register>
                <register>
                    <name>GTST</name>
                    <description>General PWM Timer Status Register</description>
                    <addressOffset>0x3C</addressOffset>
                    <size>32</size>
                    <access>read-write</access>
                    <resetValue>0x00008000</resetValue>
                    <resetMask>0xffffffff</resetMask>
                    <fields>
                        <field>
                            <name>TCFA</name>
                            <description>Input Capture/Compare Match Flag A</description>
                            <lsb>0</lsb>
                            <msb>0</msb>
                            <access>read-write</access>
                            <enumeratedValues>
                                </enumeratedValues>
                        </field>
                        <field>
                            <name>TCFB</name>
                            <description>Input Capture/Compare Match Flag B</description>
                            <lsb>1</lsb>
                            <msb>1</msb>
                            <access>read-write</access>
                            <enumeratedValues>
                                </enumeratedValues>
                        </field>
                        <field>
                            <name>TCFC</name>
                            <description>Input Compare Match Flag C</description>
                            <lsb>2</lsb>
                            <msb>2</msb>
                            <access>read-write</access>
                            <enumeratedValues>
                                </enumeratedValues>
                        </field>
                        <field>
                            <name>TCFD</name>
                            <description>Input Compare Match Flag D</description>
                            <lsb>3</lsb>
                            <msb>3</msb>
                            <access>read-write</access>
                            <enumeratedValues>
                                </enumeratedValues>
                        </field>
                        <field>
                            <name>TCFE</name>
                            <description>Input Compare Match Flag E</description>
                            <lsb>4</lsb>
                            <msb>4</msb>
                            <access>read-write</access>
                            <enumeratedValues>
                                </enumeratedValues>
                        </field>
                        <field>
                            <name>TCFF</name>
                            <description>Input Compare Match Flag F</description>
                            <lsb>5</lsb>
                            <msb>5</msb>
                            <access>read-write</access>
                            <enumeratedValues>
                                </enumeratedValues>
                        </field>
                        <field>
                            <name>TCFPO</name>
                            <description>Overflow Flag</description>
                            <lsb>6</lsb>
                            <msb>6</msb>
                            <access>read-write</access>
                            <enumeratedValues>
                                </enumeratedValues>
                        </field>
                        <field>
                            <name>TCFPU</name>
                            <description>Underflow Flag</description>
                            <lsb>7</lsb>
                            <msb>7</msb>
                            <access>read-write</access>
                            <enumeratedValues>
                                </enumeratedValues>
                        </field>
                        <field>
                            <name>TUCF</name>
                            <description>Count Direction Flag</description>
                            <lsb>15</lsb>
                            <msb>15</msb>
                            <access>read-only</access>
                            <enumeratedValues>
                                </enumeratedValues>
                        </field>
                        <field>
                            <name>ODF</name>
                            <description>Output Disable Flag</description>
                            <lsb>24</lsb>
                            <msb>24</msb>
                            <access>read-only</access>
                            <enumeratedValues>
                                </enumeratedValues>
                        </field>
                        <field>
                            <name>OABHF</name>
                            <description>Same Time Output Level High Flag</description>
                            <lsb>29</lsb>
                            <msb>29</msb>
                            <access>read-only</access>
                            <enumeratedValues>
                                </enumeratedValues>
                        </field>
                        <field>
                            <name>OABLF</name>
                            <description>Same Time Output Level Low Flag</description>
                            <lsb>30</lsb>
                            <msb>30</msb>
                            <access>read-only</access>
                            <enumeratedValues>
                                </enumeratedValues>
                        </field>
                        <field>
                            <name>PCF</name>
                            <description>Period Count Function Finish Flag</description>
                            <lsb>31</lsb>
                            <msb>31</msb>
                            <access>read-write</access>
                            <enumeratedValues>
                                </enumeratedValues>
                        </field>
                    </fields>
                </register>
                <register>
                    <name>GTBER</name>
                    <description>General PWM Timer Buffer Enable Register</description>
                    <addressOffset>0x40</addressOffset>
                    <size>32</size>
                    <access>read-write</access>
                    <resetValue>0x00000000</resetValue>
                    <resetMask>0xffffffff</resetMask>
                    <fields>
                        <field>
                            <name>BD0</name>
                            <description>GTCCR Buffer Operation Disable</description>
                            <lsb>0</lsb>
                            <msb>0</msb>
                            <access>read-write</access>
                            <enumeratedValues>
                                </enumeratedValues>
                        </field>
                        <field>
                            <name>BD1</name>
                            <description>GTPR Buffer Operation Disable</description>
                            <lsb>1</lsb>
                            <msb>1</msb>
                            <access>read-write</access>
                            <enumeratedValues>
                                </enumeratedValues>
                        </field>
                        <field>
                            <name>CCRA</name>
                            <description>GTCCRA Buffer Operation</description>
                            <lsb>16</lsb>
                            <msb>17</msb>
                            <access>read-write</access>
                            <enumeratedValues>
                                </enumeratedValues>
                        </field>
                        <field>
                            <name>CCRB</name>
                            <description>GTCCRB Buffer Operation</description>
                            <lsb>18</lsb>
                            <msb>19</msb>
                            <access>read-write</access>
                            <enumeratedValues>
                                </enumeratedValues>
                        </field>
                        <field>
                            <name>PR</name>
                            <description>GTPR Buffer Operation</description>
                            <lsb>20</lsb>
                            <msb>21</msb>
                            <access>read-write</access>
                            <enumeratedValues>
                                </enumeratedValues>
                        </field>
                        <field>
                            <name>CCRSWT</name>
                            <description>GTCCRA and GTCCRB Forcible Buffer Operation</description>
                            <lsb>22</lsb>
                            <msb>22</msb>
                            <access>write-only</access>
                        </field>
                    </fields>
                </register>
                <register>
                    <name>GTCNT</name>
                    <description>General PWM Timer Counter</description>
                    <addressOffset>0x48</addressOffset>
                    <size>32</size>
                    <access>read-write</access>
                    <resetValue>0x00000000</resetValue>
                    <resetMask>0xffffffff</resetMask>
                </register>
                <register>
                    <name>GTCCRA</name>
                    <description>General PWM Timer Compare Capture Register A</description>
                    <addressOffset>0x4C</addressOffset>
                    <size>32</size>
                    <access>read-write</access>
                    <resetValue>0x0000ffff</resetValue>
                    <resetMask>0xffffffff</resetMask>
                </register>
                <register>
                    <name>GTCCRB</name>
                    <description>General PWM Timer Compare Capture Register B</description>
                    <addressOffset>0x50</addressOffset>
                    <size>32</size>
                    <access>read-write</access>
                    <resetValue>0x0000ffff</resetValue>
                    <resetMask>0xffffffff</resetMask>
                </register>
                <register>
                    <name>GTCCRC</name>
                    <description>General PWM Timer Compare Capture Register C</description>
                    <addressOffset>0x54</addressOffset>
                    <size>32</size>
                    <access>read-write</access>
                    <resetValue>0x0000ffff</resetValue>
                    <resetMask>0xffffffff</resetMask>
                </register>
                <register>
                    <name>GTCCRE</name>
                    <description>General PWM Timer Compare Capture Register E</description>
                    <addressOffset>0x58</addressOffset>
                    <size>32</size>
                    <access>read-write</access>
                    <resetValue>0x0000ffff</resetValue>
                    <resetMask>0xffffffff</resetMask>
                </register>
                <register>
                    <name>GTCCRD</name>
                    <description>General PWM Timer Compare Capture Register D</description>
                    <addressOffset>0x5C</addressOffset>
                    <size>32</size>
                    <access>read-write</access>
                    <resetValue>0x0000ffff</resetValue>
                    <resetMask>0xffffffff</resetMask>
                </register>
                <register>
                    <name>GTCCRF</name>
                    <description>General PWM Timer Compare Capture Register F</description>
                    <addressOffset>0x60</addressOffset>
                    <size>32</size>
                    <access>read-write</access>
                    <resetValue>0x0000ffff</resetValue>
                    <resetMask>0xffffffff</resetMask>
                </register>
                <register>
                    <name>GTPR</name>
                    <description>General PWM Timer Cycle Setting Register</description>
                    <addressOffset>0x64</addressOffset>
                    <size>32</size>
                    <access>read-write</access>
                    <resetValue>0x0000ffff</resetValue>
                    <resetMask>0xffffffff</resetMask>
                </register>
                <register>
                    <name>GTPBR</name>
                    <description>General PWM Timer Cycle Setting Buffer Register</description>
                    <addressOffset>0x68</addressOffset>
                    <size>32</size>
                    <access>read-write</access>
                    <resetValue>0x0000ffff</resetValue>
                    <resetMask>0xffffffff</resetMask>
                </register>
                <register>
                    <name>GTDTCR</name>
                    <description>General PWM Timer Dead Time Control Register</description>
                    <addressOffset>0x88</addressOffset>
                    <size>32</size>
                    <access>read-write</access>
                    <resetValue>0x00000000</resetValue>
                    <resetMask>0xffffffff</resetMask>
                    <fields>
                        <field>
                            <name>TDE</name>
                            <description>Negative,Phase Waveform Setting</description>
                            <lsb>0</lsb>
                            <msb>0</msb>
                            <access>read-write</access>
                            <enumeratedValues>
                                </enumeratedValues>
                        </field>
                    </fields>
                </register>
                <register>
                    <name>GTDVU</name>
                    <description>General PWM Timer Dead Time Value Register U</description>
                    <addressOffset>0x8C</addressOffset>
                    <size>32</size>
                    <access>read-write</access>
                    <resetValue>0x0000ffff</resetValue>
                    <resetMask>0xffffffff</resetMask>
                </register>
                <register>
                    <name>GTICLF</name>
                    <description>General PWM Timer Inter Channel Logical Operation Function Setting Register</description>
                    <addressOffset>0xB8</addressOffset>
                    <size>32</size>
                    <access>read-write</access>
                    <resetValue>0x00000000</resetValue>
                    <resetMask>0xffffffff</resetMask>
                    <fields>
                        <field>
                            <name>ICLFA</name>
                            <description>GTIOCnA Output Logical Operation Function Select</description>
                            <lsb>0</lsb>
                            <msb>2</msb>
                            <access>read-write</access>
                            <enumeratedValues>
                                </enumeratedValues>
                        </field>
                        <field>
                            <name>ICLFSELC</name>
                            <description>Inter Channel Signal C Select</description>
                            <lsb>4</lsb>
                            <msb>9</msb>
                            <access>read-write</access>
                            <enumeratedValues>
                                </enumeratedValues>
                        </field>
                        <field>
                            <name>ICLFB</name>
                            <description>GTIOCnB Output Logical Operation Function Select</description>
                            <lsb>16</lsb>
                            <msb>18</msb>
                            <access>read-write</access>
                            <enumeratedValues>
                                </enumeratedValues>
                        </field>
                        <field>
                            <name>ICLFSELD</name>
                            <description>Inter Channel Signal D Select</description>
                            <lsb>20</lsb>
                            <msb>25</msb>
                            <access>read-write</access>
                            <enumeratedValues>
                                </enumeratedValues>
                        </field>
                    </fields>
                </register>
                <register>
                    <name>GTPC</name>
                    <description>General PWM Timer Period Count Register</description>
                    <addressOffset>0xBC</addressOffset>
                    <size>32</size>
                    <access>read-write</access>
                    <resetValue>0x00000000</resetValue>
                    <resetMask>0xffffffff</resetMask>
                    <fields>
                        <field>
                            <name>PCEN</name>
                            <description>Period Count Function Enable</description>
                            <lsb>0</lsb>
                            <msb>0</msb>
                            <access>read-write</access>
                            <enumeratedValues>
                                </enumeratedValues>
                        </field>
                        <field>
                            <name>ASTP</name>
                            <description>Automatic Stop Function Enable</description>
                            <lsb>8</lsb>
                            <msb>8</msb>
                            <access>read-write</access>
                            <enumeratedValues>
                                </enumeratedValues>
                        </field>
                        <field>
                            <name>PCNT</name>
                            <description>Period Counter</description>
                            <lsb>16</lsb>
                            <msb>27</msb>
                            <access>read-write</access>
                        </field>
                    </fields>
                </register>
                <register>
                    <name>GTSECSR</name>
                    <description>General PWM Timer Operation Enable Bit Simultaneous Control Channel Select Register</description>
                    <addressOffset>0xD0</addressOffset>
                    <size>32</size>
                    <access>read-write</access>
                    <resetValue>0x00000000</resetValue>
                    <resetMask>0xffffffff</resetMask>
                    <fields>
                        <field>
                            <name>SECSEL0</name>
                            <description>Channel 0 Operation Enable Bit Simultaneous Control Channel Select</description>
                            <lsb>0</lsb>
                            <msb>0</msb>
                            <access>read-write</access>
                            <enumeratedValues>
                                </enumeratedValues>
                        </field>
                        <field>
                            <name>SECSEL1</name>
                            <description>Channel 1 Operation Enable Bit Simultaneous Control Channel Select</description>
                            <lsb>1</lsb>
                            <msb>1</msb>
                            <access>read-write</access>
                            <enumeratedValues>
                                </enumeratedValues>
                        </field>
                        <field>
                            <name>SECSEL2</name>
                            <description>Channel 2 Operation Enable Bit Simultaneous Control Channel Select</description>
                            <lsb>2</lsb>
                            <msb>2</msb>
                            <access>read-write</access>
                            <enumeratedValues>
                                </enumeratedValues>
                        </field>
                        <field>
                            <name>SECSEL3</name>
                            <description>Channel 3 Operation Enable Bit Simultaneous Control Channel Select</description>
                            <lsb>3</lsb>
                            <msb>3</msb>
                            <access>read-write</access>
                            <enumeratedValues>
                                </enumeratedValues>
                        </field>
                        <field>
                            <name>SECSEL4</name>
                            <description>Channel 4 Operation Enable Bit Simultaneous Control Channel Select</description>
                            <lsb>4</lsb>
                            <msb>4</msb>
                            <access>read-write</access>
                            <enumeratedValues>
                                </enumeratedValues>
                        </field>
                        <field>
                            <name>SECSEL5</name>
                            <description>Channel 5 Operation Enable Bit Simultaneous Control Channel Select</description>
                            <lsb>5</lsb>
                            <msb>5</msb>
                            <access>read-write</access>
                            <enumeratedValues>
                                </enumeratedValues>
                        </field>
                        <field>
                            <name>SECSEL6</name>
                            <description>Channel 6 Operation Enable Bit Simultaneous Control Channel Select</description>
                            <lsb>6</lsb>
                            <msb>6</msb>
                            <access>read-write</access>
                            <enumeratedValues>
                                </enumeratedValues>
                        </field>
                        <field>
                            <name>SECSEL7</name>
                            <description>Channel 7 Operation Enable Bit Simultaneous Control Channel Select</description>
                            <lsb>7</lsb>
                            <msb>7</msb>
                            <access>read-write</access>
                            <enumeratedValues>
                                </enumeratedValues>
                        </field>
                        <field>
                            <name>SECSEL8</name>
                            <description>Channel 8 Operation Enable Bit Simultaneous Control Channel Select</description>
                            <lsb>8</lsb>
                            <msb>8</msb>
                            <access>read-write</access>
                            <enumeratedValues>
                                </enumeratedValues>
                        </field>
                        <field>
                            <name>SECSEL9</name>
                            <description>Channel 9 Operation Enable Bit Simultaneous Control Channel Select</description>
                            <lsb>9</lsb>
                            <msb>9</msb>
                            <access>read-write</access>
                            <enumeratedValues>
                                </enumeratedValues>
                        </field>
                    </fields>
                </register>
                <register>
                    <name>GTSECR</name>
                    <description>General PWM Timer Operation Enable Bit Simultaneous Control Register</description>
                    <addressOffset>0xD4</addressOffset>
                    <size>32</size>
                    <access>read-write</access>
                    <resetValue>0x00000000</resetValue>
                    <resetMask>0xffffffff</resetMask>
                    <fields>
                        <field>
                            <name>SBDCE</name>
                            <description>GTCCR Register Buffer Operation Simultaneous Enable</description>
                            <lsb>0</lsb>
                            <msb>0</msb>
                            <access>read-write</access>
                            <enumeratedValues>
                                </enumeratedValues>
                        </field>
                        <field>
                            <name>SBDPE</name>
                            <description>GTPR Register Buffer Operation Simultaneous Enable</description>
                            <lsb>1</lsb>
                            <msb>1</msb>
                            <access>read-write</access>
                            <enumeratedValues>
                                </enumeratedValues>
                        </field>
                        <field>
                            <name>SBDCD</name>
                            <description>GTCCR Register Buffer Operation Simultaneous Disable</description>
                            <lsb>8</lsb>
                            <msb>8</msb>
                            <access>read-write</access>
                            <enumeratedValues>
                                </enumeratedValues>
                        </field>
                        <field>
                            <name>SBDPD</name>
                            <description>GTPR Register Buffer Operation Simultaneous Disable</description>
                            <lsb>9</lsb>
                            <msb>9</msb>
                            <access>read-write</access>
                            <enumeratedValues>
                                </enumeratedValues>
                        </field>
                        <field>
                            <name>SPCE</name>
                            <description>Period Count Function Simultaneous Enable</description>
                            <lsb>16</lsb>
                            <msb>16</msb>
                            <access>read-write</access>
                            <enumeratedValues>
                                </enumeratedValues>
                        </field>
                        <field>
                            <name>SPCD</name>
                            <description>Period Count Function Simultaneous Disable</description>
                            <lsb>24</lsb>
                            <msb>24</msb>
                            <access>read-write</access>
                            <enumeratedValues>
                                </enumeratedValues>
                        </field>
                    </fields>
                </register>
            </registers>
        </peripheral>
        <peripheral derivedFrom="GPT164">
            <name>GPT165</name>
            <description>General PWM 16-bit Timer 5</description>
            <baseAddress>0x40169500</baseAddress>
        </peripheral>
        <peripheral derivedFrom="GPT164">
            <name>GPT166</name>
            <description>General PWM 16-bit Timer 6</description>
            <baseAddress>0x40169600</baseAddress>
        </peripheral>
        <peripheral derivedFrom="GPT164">
            <name>GPT167</name>
            <description>General PWM 16-bit Timer 7</description>
            <baseAddress>0x40169700</baseAddress>
        </peripheral>
        <peripheral derivedFrom="GPT164">
            <name>GPT168</name>
            <description>General PWM 16-bit Timer 8</description>
            <baseAddress>0x40169800</baseAddress>
        </peripheral>
        <peripheral derivedFrom="GPT164">
            <name>GPT169</name>
            <description>General PWM 16-bit Timer 9</description>
            <baseAddress>0x40169900</baseAddress>
        </peripheral>
        <peripheral>
            <name>GPT_OPS</name>
            <description>Output Phase Switching Controller</description>
            <baseAddress>0x40169A00</baseAddress>
            <addressBlock>
                <offset>0x00</offset>
                <size>4</size>
                <usage>registers</usage>
            </addressBlock>
            <registers>
                <register>
                    <name>OPSCR</name>
                    <description>Output Phase Switching Control Register</description>
                    <addressOffset>0x00</addressOffset>
                    <size>32</size>
                    <access>read-write</access>
                    <resetValue>0x00000000</resetValue>
                    <resetMask>0xffffffff</resetMask>
                    <fields>
                        <field>
                            <name>UF</name>
                            <lsb>0</lsb>
                            <msb>0</msb>
                            <access>read-write</access>
                        </field>
                        <field>
                            <name>VF</name>
                            <lsb>1</lsb>
                            <msb>1</msb>
                            <access>read-write</access>
                        </field>
                        <field>
                            <name>WF</name>
                            <lsb>2</lsb>
                            <msb>2</msb>
                            <access>read-write</access>
                        </field>
                        <field>
                            <name>U</name>
                            <description>Input U,Phase Monitor</description>
                            <lsb>4</lsb>
                            <msb>4</msb>
                            <access>read-only</access>
                        </field>
                        <field>
                            <name>V</name>
                            <description>Input V,Phase Monitor</description>
                            <lsb>5</lsb>
                            <msb>5</msb>
                            <access>read-only</access>
                        </field>
                        <field>
                            <name>W</name>
                            <description>Input W,Phase Monitor</description>
                            <lsb>6</lsb>
                            <msb>6</msb>
                            <access>read-only</access>
                        </field>
                        <field>
                            <name>EN</name>
                            <description>Output Phase Enable</description>
                            <lsb>8</lsb>
                            <msb>8</msb>
                            <access>read-write</access>
                            <enumeratedValues>
                                </enumeratedValues>
                        </field>
                        <field>
                            <name>FB</name>
                            <description>External Feedback Signal Enable</description>
                            <lsb>16</lsb>
                            <msb>16</msb>
                            <access>read-write</access>
                            <enumeratedValues>
                                </enumeratedValues>
                        </field>
                        <field>
                            <name>P</name>
                            <description>Positive,Phase Output (P) Control</description>
                            <lsb>17</lsb>
                            <msb>17</msb>
                            <access>read-write</access>
                            <enumeratedValues>
                                </enumeratedValues>
                        </field>
                        <field>
                            <name>N</name>
                            <description>Negative,Phase Output (N) Control</description>
                            <lsb>18</lsb>
                            <msb>18</msb>
                            <access>read-write</access>
                            <enumeratedValues>
                                </enumeratedValues>
                        </field>
                        <field>
                            <name>INV</name>
                            <description>Output Phase Invert Control</description>
                            <lsb>19</lsb>
                            <msb>19</msb>
                            <access>read-write</access>
                            <enumeratedValues>
                                </enumeratedValues>
                        </field>
                        <field>
                            <name>RV</name>
                            <description>Output Phase Rotation Direction Reversal Control</description>
                            <lsb>20</lsb>
                            <msb>20</msb>
                            <access>read-write</access>
                            <enumeratedValues>
                                </enumeratedValues>
                        </field>
                        <field>
                            <name>ALIGN</name>
                            <description>Input Phase Alignment</description>
                            <lsb>21</lsb>
                            <msb>21</msb>
                            <access>read-write</access>
                            <enumeratedValues>
                                </enumeratedValues>
                        </field>
                        <field>
                            <name>GRP</name>
                            <description>Output Disabled Source Selection</description>
                            <lsb>24</lsb>
                            <msb>25</msb>
                            <access>read-write</access>
                        </field>
                        <field>
                            <name>GODF</name>
                            <description>Group Output Disable Function</description>
                            <lsb>26</lsb>
                            <msb>26</msb>
                            <access>read-write</access>
                            <enumeratedValues>
                                </enumeratedValues>
                        </field>
                        <field>
                            <name>NFEN</name>
                            <description>External Input Noise Filter Enable</description>
                            <lsb>29</lsb>
                            <msb>29</msb>
                            <access>read-write</access>
                            <enumeratedValues>
                                </enumeratedValues>
                        </field>
                        <field>
                            <name>NFCS</name>
                            <description>External Input Noise Filter Clock Selection</description>
                            <lsb>30</lsb>
                            <msb>31</msb>
                            <access>read-write</access>
                            <enumeratedValues>
                                </enumeratedValues>
                        </field>
                    </fields>
                </register>
            </registers>
        </peripheral>
        <peripheral>
            <name>ADC120</name>
            <description>12-bit A/D Converter</description>
            <baseAddress>0x40170000</baseAddress>
            <addressBlock>
                <offset>0x00</offset>
                <size>2</size>
                <usage>registers</usage>
            </addressBlock>
            <addressBlock>
                <offset>0x04</offset>
                <size>9</size>
                <usage>registers</usage>
            </addressBlock>
            <addressBlock>
                <offset>0x0E</offset>
                <size>40</size>
                <usage>registers</usage>
            </addressBlock>
            <addressBlock>
                <offset>0x38</offset>
                <size>4</size>
                <usage>registers</usage>
            </addressBlock>
            <addressBlock>
                <offset>0x7A</offset>
                <size>1</size>
                <usage>registers</usage>
            </addressBlock>
            <addressBlock>
                <offset>0x80</offset>
                <size>2</size>
                <usage>registers</usage>
            </addressBlock>
            <addressBlock>
                <offset>0x84</offset>
                <size>4</size>
                <usage>registers</usage>
            </addressBlock>
            <addressBlock>
                <offset>0x8C</offset>
                <size>1</size>
                <usage>registers</usage>
            </addressBlock>
            <addressBlock>
                <offset>0x90</offset>
                <size>21</size>
                <usage>registers</usage>
            </addressBlock>
            <addressBlock>
                <offset>0xA6</offset>
                <size>1</size>
                <usage>registers</usage>
            </addressBlock>
            <addressBlock>
                <offset>0xA8</offset>
                <size>5</size>
                <usage>registers</usage>
            </addressBlock>
            <addressBlock>
                <offset>0xB0</offset>
                <size>33</size>
                <usage>registers</usage>
            </addressBlock>
            <addressBlock>
                <offset>0xD2</offset>
                <size>1</size>
                <usage>registers</usage>
            </addressBlock>
            <addressBlock>
                <offset>0xDD</offset>
                <size>14</size>
                <usage>registers</usage>
            </addressBlock>
            <addressBlock>
                <offset>0xEC</offset>
                <size>2</size>
                <usage>registers</usage>
            </addressBlock>
            <registers>
                <register>
                    <name>ADCSR</name>
                    <description>A/D Control Register</description>
                    <addressOffset>0x000</addressOffset>
                    <size>16</size>
                    <access>read-write</access>
                    <resetValue>0x0000</resetValue>
                    <resetMask>0xffff</resetMask>
                    <fields>
                        <field>
                            <name>DBLANS</name>
                            <description>Double Trigger Channel Select</description>
                            <lsb>0</lsb>
                            <msb>4</msb>
                            <access>read-write</access>
                        </field>
                        <field>
                            <name>GBADIE</name>
                            <description>Group B Scan End Interrupt and ELC Event Enable</description>
                            <lsb>6</lsb>
                            <msb>6</msb>
                            <access>read-write</access>
                            <enumeratedValues>
                                </enumeratedValues>
                        </field>
                        <field>
                            <name>DBLE</name>
                            <description>Double Trigger Mode Select</description>
                            <lsb>7</lsb>
                            <msb>7</msb>
                            <access>read-write</access>
                            <enumeratedValues>
                                </enumeratedValues>
                        </field>
                        <field>
                            <name>EXTRG</name>
                            <description>Trigger Select</description>
                            <lsb>8</lsb>
                            <msb>8</msb>
                            <access>read-write</access>
                            <enumeratedValues>
                                </enumeratedValues>
                        </field>
                        <field>
                            <name>TRGE</name>
                            <description>Trigger Start Enable</description>
                            <lsb>9</lsb>
                            <msb>9</msb>
                            <access>read-write</access>
                            <enumeratedValues>
                                </enumeratedValues>
                        </field>
                        <field>
                            <name>ADCS</name>
                            <description>Scan Mode Select</description>
                            <lsb>13</lsb>
                            <msb>14</msb>
                            <access>read-write</access>
                            <enumeratedValues>
                                </enumeratedValues>
                        </field>
                        <field>
                            <name>ADST</name>
                            <description>A/D Conversion Start</description>
                            <lsb>15</lsb>
                            <msb>15</msb>
                            <access>read-write</access>
                            <enumeratedValues>
                                </enumeratedValues>
                        </field>
                    </fields>
                </register>
                <register>
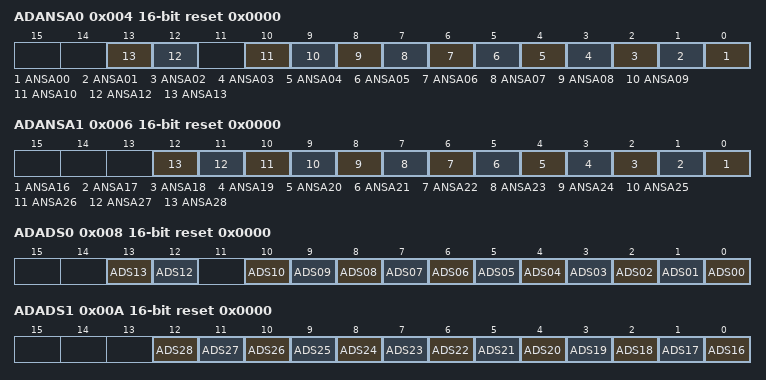
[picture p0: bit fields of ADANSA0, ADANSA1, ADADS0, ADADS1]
                    <name>ADANSA0</name>
                    <description>A/D Channel Select Register A0</description>
                    <addressOffset>0x004</addressOffset>
                    <size>16</size>
                    <access>read-write</access>
                    <resetValue>0x0000</resetValue>
                    <resetMask>0xffff</resetMask>
                    <fields>
                        <field>
                            <name>ANSA00</name>
                            <description>A/D Conversion Channels Select</description>
                            <lsb>0</lsb>
                            <msb>0</msb>
                            <access>read-write</access>
                            <enumeratedValues>
                                </enumeratedValues>
                        </field>
                        <field>
                            <name>ANSA01</name>
                            <description>A/D Conversion Channels Select</description>
                            <lsb>1</lsb>
                            <msb>1</msb>
                            <access>read-write</access>
                            <enumeratedValues>
                                </enumeratedValues>
                        </field>
                        <field>
                            <name>ANSA02</name>
                            <description>A/D Conversion Channels Select</description>
                            <lsb>2</lsb>
                            <msb>2</msb>
                            <access>read-write</access>
                            <enumeratedValues>
                                </enumeratedValues>
                        </field>
                        <field>
                            <name>ANSA03</name>
                            <description>A/D Conversion Channels Select</description>
                            <lsb>3</lsb>
                            <msb>3</msb>
                            <access>read-write</access>
                            <enumeratedValues>
                                </enumeratedValues>
                        </field>
                        <field>
                            <name>ANSA04</name>
                            <description>A/D Conversion Channels Select</description>
                            <lsb>4</lsb>
                            <msb>4</msb>
                            <access>read-write</access>
                            <enumeratedValues>
                                </enumeratedValues>
                        </field>
                        <field>
                            <name>ANSA05</name>
                            <description>A/D Conversion Channels Select</description>
                            <lsb>5</lsb>
                            <msb>5</msb>
                            <access>read-write</access>
                            <enumeratedValues>
                                </enumeratedValues>
                        </field>
                        <field>
                            <name>ANSA06</name>
                            <description>A/D Conversion Channels Select</description>
                            <lsb>6</lsb>
                            <msb>6</msb>
                            <access>read-write</access>
                            <enumeratedValues>
                                </enumeratedValues>
                        </field>
                        <field>
                            <name>ANSA07</name>
                            <description>A/D Conversion Channels Select</description>
                            <lsb>7</lsb>
                            <msb>7</msb>
                            <access>read-write</access>
                            <enumeratedValues>
                                </enumeratedValues>
                        </field>
                        <field>
                            <name>ANSA08</name>
                            <description>A/D Conversion Channels Select</description>
                            <lsb>8</lsb>
                            <msb>8</msb>
                            <access>read-write</access>
                            <enumeratedValues>
                                </enumeratedValues>
                        </field>
                        <field>
                            <name>ANSA09</name>
                            <description>A/D Conversion Channels Select</description>
                            <lsb>9</lsb>
                            <msb>9</msb>
                            <access>read-write</access>
                            <enumeratedValues>
                                </enumeratedValues>
                        </field>
                        <field>
                            <name>ANSA10</name>
                            <description>A/D Conversion Channels Select</description>
                            <lsb>10</lsb>
                            <msb>10</msb>
                            <access>read-write</access>
                            <enumeratedValues>
                                </enumeratedValues>
                        </field>
                        <field>
                            <name>ANSA12</name>
                            <description>A/D Conversion Channels Select</description>
                            <lsb>12</lsb>
                            <msb>12</msb>
                            <access>read-write</access>
                            <enumeratedValues>
                                </enumeratedValues>
                        </field>
                        <field>
                            <name>ANSA13</name>
                            <description>A/D Conversion Channels Select</description>
                            <lsb>13</lsb>
                            <msb>13</msb>
                            <access>read-write</access>
                            <enumeratedValues>
                                </enumeratedValues>
                        </field>
                    </fields>
                </register>
                <register>
                    <name>ADANSA1</name>
                    <description>A/D Channel Select Register A1</description>
                    <addressOffset>0x006</addressOffset>
                    <size>16</size>
                    <access>read-write</access>
                    <resetValue>0x0000</resetValue>
                    <resetMask>0xffff</resetMask>
                    <fields>
                        <field>
                            <name>ANSA16</name>
                            <description>A/D Conversion Channels Select</description>
                            <lsb>0</lsb>
                            <msb>0</msb>
                            <access>read-write</access>
                            <enumeratedValues>
                                </enumeratedValues>
                        </field>
                        <field>
                            <name>ANSA17</name>
                            <description>A/D Conversion Channels Select</description>
                            <lsb>1</lsb>
                            <msb>1</msb>
                            <access>read-write</access>
                            <enumeratedValues>
                                </enumeratedValues>
                        </field>
                        <field>
                            <name>ANSA18</name>
                            <description>A/D Conversion Channels Select</description>
                            <lsb>2</lsb>
                            <msb>2</msb>
                            <access>read-write</access>
                            <enumeratedValues>
                                </enumeratedValues>
                        </field>
                        <field>
                            <name>ANSA19</name>
                            <description>A/D Conversion Channels Select</description>
                            <lsb>3</lsb>
                            <msb>3</msb>
                            <access>read-write</access>
                            <enumeratedValues>
                                </enumeratedValues>
                        </field>
                        <field>
                            <name>ANSA20</name>
                            <description>A/D Conversion Channels Select</description>
                            <lsb>4</lsb>
                            <msb>4</msb>
                            <access>read-write</access>
                            <enumeratedValues>
                                </enumeratedValues>
                        </field>
                        <field>
                            <name>ANSA21</name>
                            <description>A/D Conversion Channels Select</description>
                            <lsb>5</lsb>
                            <msb>5</msb>
                            <access>read-write</access>
                            <enumeratedValues>
                                </enumeratedValues>
                        </field>
                        <field>
                            <name>ANSA22</name>
                            <description>A/D Conversion Channels Select</description>
                            <lsb>6</lsb>
                            <msb>6</msb>
                            <access>read-write</access>
                            <enumeratedValues>
                                </enumeratedValues>
                        </field>
                        <field>
                            <name>ANSA23</name>
                            <description>A/D Conversion Channels Select</description>
                            <lsb>7</lsb>
                            <msb>7</msb>
                            <access>read-write</access>
                            <enumeratedValues>
                                </enumeratedValues>
                        </field>
                        <field>
                            <name>ANSA24</name>
                            <description>A/D Conversion Channels Select</description>
                            <lsb>8</lsb>
                            <msb>8</msb>
                            <access>read-write</access>
                            <enumeratedValues>
                                </enumeratedValues>
                        </field>
                        <field>
                            <name>ANSA25</name>
                            <description>A/D Conversion Channels Select</description>
                            <lsb>9</lsb>
                            <msb>9</msb>
                            <access>read-write</access>
                            <enumeratedValues>
                                </enumeratedValues>
                        </field>
                        <field>
                            <name>ANSA26</name>
                            <description>A/D Conversion Channels Select</description>
                            <lsb>10</lsb>
                            <msb>10</msb>
                            <access>read-write</access>
                            <enumeratedValues>
                                </enumeratedValues>
                        </field>
                        <field>
                            <name>ANSA27</name>
                            <description>A/D Conversion Channels Select</description>
                            <lsb>11</lsb>
                            <msb>11</msb>
                            <access>read-write</access>
                            <enumeratedValues>
                                </enumeratedValues>
                        </field>
                        <field>
                            <name>ANSA28</name>
                            <description>A/D Conversion Channels Select</description>
                            <lsb>12</lsb>
                            <msb>12</msb>
                            <access>read-write</access>
                            <enumeratedValues>
                                </enumeratedValues>
                        </field>
                    </fields>
                </register>
                <register>
                    <name>ADADS0</name>
                    <description>A/D,Converted Value Addition/Average Channel Select Register 0</description>
                    <addressOffset>0x008</addressOffset>
                    <size>16</size>
                    <access>read-write</access>
                    <resetValue>0x0000</resetValue>
                    <resetMask>0xffff</resetMask>
                    <fields>
                        <field>
                            <name>ADS00</name>
                            <description>A/D,Converted Value Addition/Average Channel Select</description>
                            <lsb>0</lsb>
                            <msb>0</msb>
                            <access>read-write</access>
                            <enumeratedValues>
                                </enumeratedValues>
                        </field>
                        <field>
                            <name>ADS01</name>
                            <description>A/D,Converted Value Addition/Average Channel Select</description>
                            <lsb>1</lsb>
                            <msb>1</msb>
                            <access>read-write</access>
                            <enumeratedValues>
                                </enumeratedValues>
                        </field>
                        <field>
                            <name>ADS02</name>
                            <description>A/D,Converted Value Addition/Average Channel Select</description>
                            <lsb>2</lsb>
                            <msb>2</msb>
                            <access>read-write</access>
                            <enumeratedValues>
                                </enumeratedValues>
                        </field>
                        <field>
                            <name>ADS03</name>
                            <description>A/D,Converted Value Addition/Average Channel Select</description>
                            <lsb>3</lsb>
                            <msb>3</msb>
                            <access>read-write</access>
                            <enumeratedValues>
                                </enumeratedValues>
                        </field>
                        <field>
                            <name>ADS04</name>
                            <description>A/D,Converted Value Addition/Average Channel Select</description>
                            <lsb>4</lsb>
                            <msb>4</msb>
                            <access>read-write</access>
                            <enumeratedValues>
                                </enumeratedValues>
                        </field>
                        <field>
                            <name>ADS05</name>
                            <description>A/D,Converted Value Addition/Average Channel Select</description>
                            <lsb>5</lsb>
                            <msb>5</msb>
                            <access>read-write</access>
                            <enumeratedValues>
                                </enumeratedValues>
                        </field>
                        <field>
                            <name>ADS06</name>
                            <description>A/D,Converted Value Addition/Average Channel Select</description>
                            <lsb>6</lsb>
                            <msb>6</msb>
                            <access>read-write</access>
                            <enumeratedValues>
                                </enumeratedValues>
                        </field>
                        <field>
                            <name>ADS07</name>
                            <description>A/D,Converted Value Addition/Average Channel Select</description>
                            <lsb>7</lsb>
                            <msb>7</msb>
                            <access>read-write</access>
                            <enumeratedValues>
                                </enumeratedValues>
                        </field>
                        <field>
                            <name>ADS08</name>
                            <description>A/D,Converted Value Addition/Average Channel Select</description>
                            <lsb>8</lsb>
                            <msb>8</msb>
                            <access>read-write</access>
                            <enumeratedValues>
                                </enumeratedValues>
                        </field>
                        <field>
                            <name>ADS09</name>
                            <description>A/D,Converted Value Addition/Average Channel Select</description>
                            <lsb>9</lsb>
                            <msb>9</msb>
                            <access>read-write</access>
                            <enumeratedValues>
                                </enumeratedValues>
                        </field>
                        <field>
                            <name>ADS10</name>
                            <description>A/D,Converted Value Addition/Average Channel Select</description>
                            <lsb>10</lsb>
                            <msb>10</msb>
                            <access>read-write</access>
                            <enumeratedValues>
                                </enumeratedValues>
                        </field>
                        <field>
                            <name>ADS12</name>
                            <description>A/D,Converted Value Addition/Average Channel Select</description>
                            <lsb>12</lsb>
                            <msb>12</msb>
                            <access>read-write</access>
                            <enumeratedValues>
                                </enumeratedValues>
                        </field>
                        <field>
                            <name>ADS13</name>
                            <description>A/D,Converted Value Addition/Average Channel Select</description>
                            <lsb>13</lsb>
                            <msb>13</msb>
                            <access>read-write</access>
                            <enumeratedValues>
                                </enumeratedValues>
                        </field>
                    </fields>
                </register>
                <register>
                    <name>ADADS1</name>
                    <description>A/D,Converted Value Addition/Average Channel Select Register 1</description>
                    <addressOffset>0x00A</addressOffset>
                    <size>16</size>
                    <access>read-write</access>
                    <resetValue>0x0000</resetValue>
                    <resetMask>0xffff</resetMask>
                    <fields>
                        <field>
                            <name>ADS16</name>
                            <description>A/D,Converted Value Addition/Average Channel Select</description>
                            <lsb>0</lsb>
                            <msb>0</msb>
                            <access>read-write</access>
                            <enumeratedValues>
                                </enumeratedValues>
                        </field>
                        <field>
                            <name>ADS17</name>
                            <description>A/D,Converted Value Addition/Average Channel Select</description>
                            <lsb>1</lsb>
                            <msb>1</msb>
                            <access>read-write</access>
                            <enumeratedValues>
                                </enumeratedValues>
                        </field>
                        <field>
                            <name>ADS18</name>
                            <description>A/D,Converted Value Addition/Average Channel Select</description>
                            <lsb>2</lsb>
                            <msb>2</msb>
                            <access>read-write</access>
                            <enumeratedValues>
                                </enumeratedValues>
                        </field>
                        <field>
                            <name>ADS19</name>
                            <description>A/D,Converted Value Addition/Average Channel Select</description>
                            <lsb>3</lsb>
                            <msb>3</msb>
                            <access>read-write</access>
                            <enumeratedValues>
                                </enumeratedValues>
                        </field>
                        <field>
                            <name>ADS20</name>
                            <description>A/D,Converted Value Addition/Average Channel Select</description>
                            <lsb>4</lsb>
                            <msb>4</msb>
                            <access>read-write</access>
                            <enumeratedValues>
                                </enumeratedValues>
                        </field>
                        <field>
                            <name>ADS21</name>
                            <description>A/D,Converted Value Addition/Average Channel Select</description>
                            <lsb>5</lsb>
                            <msb>5</msb>
                            <access>read-write</access>
                            <enumeratedValues>
                                </enumeratedValues>
                        </field>
                        <field>
                            <name>ADS22</name>
                            <description>A/D,Converted Value Addition/Average Channel Select</description>
                            <lsb>6</lsb>
                            <msb>6</msb>
                            <access>read-write</access>
                            <enumeratedValues>
                                </enumeratedValues>
                        </field>
                        <field>
                            <name>ADS23</name>
                            <description>A/D,Converted Value Addition/Average Channel Select</description>
                            <lsb>7</lsb>
                            <msb>7</msb>
                            <access>read-write</access>
                            <enumeratedValues>
                                </enumeratedValues>
                        </field>
                        <field>
                            <name>ADS24</name>
                            <description>A/D,Converted Value Addition/Average Channel Select</description>
                            <lsb>8</lsb>
                            <msb>8</msb>
                            <access>read-write</access>
                            <enumeratedValues>
                                </enumeratedValues>
                        </field>
                        <field>
                            <name>ADS25</name>
                            <description>A/D,Converted Value Addition/Average Channel Select</description>
                            <lsb>9</lsb>
                            <msb>9</msb>
                            <access>read-write</access>
                            <enumeratedValues>
                                </enumeratedValues>
                        </field>
                        <field>
                            <name>ADS26</name>
                            <description>A/D,Converted Value Addition/Average Channel Select</description>
                            <lsb>10</lsb>
                            <msb>10</msb>
                            <access>read-write</access>
                            <enumeratedValues>
                                </enumeratedValues>
                        </field>
                        <field>
                            <name>ADS27</name>
                            <description>A/D,Converted Value Addition/Average Channel Select</description>
                            <lsb>11</lsb>
                            <msb>11</msb>
                            <access>read-write</access>
                            <enumeratedValues>
                                </enumeratedValues>
                        </field>
                        <field>
                            <name>ADS28</name>
                            <description>A/D,Converted Value Addition/Average Channel Select</description>
                            <lsb>12</lsb>
                            <msb>12</msb>
                            <access>read-write</access>
                            <enumeratedValues>
                                </enumeratedValues>
                        </field>
                    </fields>
                </register>
                <register>
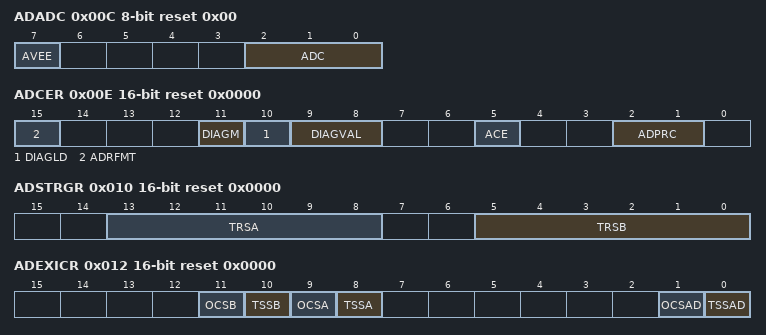
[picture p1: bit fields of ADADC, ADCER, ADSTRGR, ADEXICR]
                    <name>ADADC</name>
                    <description>A/D,Converted Value Addition/Average Count Select Register</description>
                    <addressOffset>0x00C</addressOffset>
                    <size>8</size>
                    <access>read-write</access>
                    <resetValue>0x00</resetValue>
                    <resetMask>0xff</resetMask>
                    <fields>
                        <field>
                            <name>ADC</name>
                            <description>Addition/Average Count Select</description>
                            <lsb>0</lsb>
                            <msb>2</msb>
                            <access>read-write</access>
                            <enumeratedValues>
                                </enumeratedValues>
                        </field>
                        <field>
                            <name>AVEE</name>
                            <description>Average Mode Select</description>
                            <lsb>7</lsb>
                            <msb>7</msb>
                            <access>read-write</access>
                            <enumeratedValues>
                                </enumeratedValues>
                        </field>
                    </fields>
                </register>
                <register>
                    <name>ADCER</name>
                    <description>A/D Control Extended Register</description>
                    <addressOffset>0x00E</addressOffset>
                    <size>16</size>
                    <access>read-write</access>
                    <resetValue>0x0000</resetValue>
                    <resetMask>0xffff</resetMask>
                    <fields>
                        <field>
                            <name>ADPRC</name>
                            <lsb>1</lsb>
                            <msb>2</msb>
                            <access>read-write</access>
                            <enumeratedValues>
                                </enumeratedValues>
                        </field>
                        <field>
                            <name>ACE</name>
                            <description>A/D Data Register Automatic Clearing Enable</description>
                            <lsb>5</lsb>
                            <msb>5</msb>
                            <access>read-write</access>
                            <enumeratedValues>
                                </enumeratedValues>
                        </field>
                        <field>
                            <name>DIAGVAL</name>
                            <description>Self,Diagnosis Conversion Voltage Select</description>
                            <lsb>8</lsb>
                            <msb>9</msb>
                            <access>read-write</access>
                            <enumeratedValues>
                                </enumeratedValues>
                        </field>
                        <field>
                            <name>DIAGLD</name>
                            <description>Self,Diagnosis Mode Select</description>
                            <lsb>10</lsb>
                            <msb>10</msb>
                            <access>read-write</access>
                            <enumeratedValues>
                                </enumeratedValues>
                        </field>
                        <field>
                            <name>DIAGM</name>
                            <description>Self,Diagnosis Enable</description>
                            <lsb>11</lsb>
                            <msb>11</msb>
                            <access>read-write</access>
                            <enumeratedValues>
                                </enumeratedValues>
                        </field>
                        <field>
                            <name>ADRFMT</name>
                            <description>A/D Data Register Format Select</description>
                            <lsb>15</lsb>
                            <msb>15</msb>
                            <access>read-write</access>
                            <enumeratedValues>
                                </enumeratedValues>
                        </field>
                    </fields>
                </register>
                <register>
                    <name>ADSTRGR</name>
                    <description>A/D Conversion Start Trigger Select Register</description>
                    <addressOffset>0x010</addressOffset>
                    <size>16</size>
                    <access>read-write</access>
                    <resetValue>0x0000</resetValue>
                    <resetMask>0xffff</resetMask>
                    <fields>
                        <field>
                            <name>TRSB</name>
                            <description>A/D Conversion Start Trigger Select for Group B</description>
                            <lsb>0</lsb>
                            <msb>5</msb>
                            <access>read-write</access>
                        </field>
                        <field>
                            <name>TRSA</name>
                            <description>A/D Conversion Start Trigger Select</description>
                            <lsb>8</lsb>
                            <msb>13</msb>
                            <access>read-write</access>
                        </field>
                    </fields>
                </register>
                <register>
                    <name>ADEXICR</name>
                    <description>A/D Conversion Extended Input Control Registers</description>
                    <addressOffset>0x012</addressOffset>
                    <size>16</size>
                    <access>read-write</access>
                    <resetValue>0x0000</resetValue>
                    <resetMask>0xffff</resetMask>
                    <fields>
                        <field>
                            <name>TSSAD</name>
                            <description>Temperature Sensor Output A/D,Converted Value Addition/Average Mode Select</description>
                            <lsb>0</lsb>
                            <msb>0</msb>
                            <access>read-write</access>
                            <enumeratedValues>
                                </enumeratedValues>
                        </field>
                        <field>
                            <name>OCSAD</name>
                            <description>Internal Reference Voltage A/D,Converted Value Addition/Average Mode Select</description>
                            <lsb>1</lsb>
                            <msb>1</msb>
                            <access>read-write</access>
                            <enumeratedValues>
                                </enumeratedValues>
                        </field>
                        <field>
                            <name>TSSA</name>
                            <description>Temperature Sensor Output A/D Conversion Select</description>
                            <lsb>8</lsb>
                            <msb>8</msb>
                            <access>read-write</access>
                            <enumeratedValues>
                                </enumeratedValues>
                        </field>
                        <field>
                            <name>OCSA</name>
                            <description>Internal Reference Voltage A/D Conversion Select</description>
                            <lsb>9</lsb>
                            <msb>9</msb>
                            <access>read-write</access>
                            <enumeratedValues>
                                </enumeratedValues>
                        </field>
                        <field>
                            <name>TSSB</name>
                            <description>Temperature Sensor Output A/D Conversion Select for Group B</description>
                            <lsb>10</lsb>
                            <msb>10</msb>
                            <access>read-write</access>
                            <enumeratedValues>
                                </enumeratedValues>
                        </field>
                        <field>
                            <name>OCSB</name>
                            <description>Internal Reference Voltage A/D Conversion Select for Group B</description>
                            <lsb>11</lsb>
                            <msb>11</msb>
                            <access>read-write</access>
                            <enumeratedValues>
                                </enumeratedValues>
                        </field>
                    </fields>
                </register>
                <register>
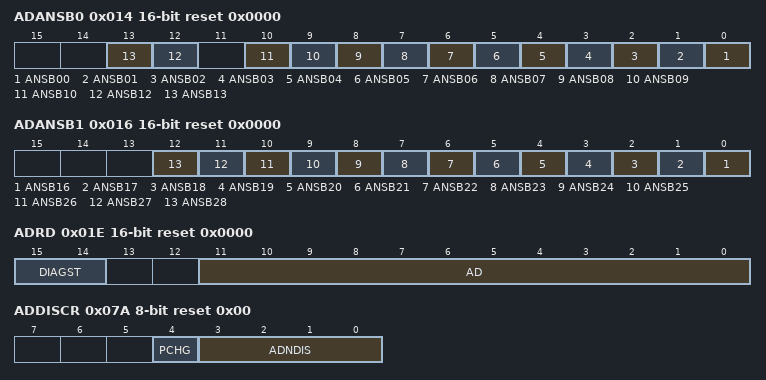
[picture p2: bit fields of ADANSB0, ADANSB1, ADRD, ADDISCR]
                    <name>ADANSB0</name>
                    <description>A/D Channel Select Register B0</description>
                    <addressOffset>0x014</addressOffset>
                    <size>16</size>
                    <access>read-write</access>
                    <resetValue>0x0000</resetValue>
                    <resetMask>0xffff</resetMask>
                    <fields>
                        <field>
                            <name>ANSB00</name>
                            <description>A/D Conversion Channels Select</description>
                            <lsb>0</lsb>
                            <msb>0</msb>
                            <access>read-write</access>
                            <enumeratedValues>
                                </enumeratedValues>
                        </field>
                        <field>
                            <name>ANSB01</name>
                            <description>A/D Conversion Channels Select</description>
                            <lsb>1</lsb>
                            <msb>1</msb>
                            <access>read-write</access>
                            <enumeratedValues>
                                </enumeratedValues>
                        </field>
                        <field>
                            <name>ANSB02</name>
                            <description>A/D Conversion Channels Select</description>
                            <lsb>2</lsb>
                            <msb>2</msb>
                            <access>read-write</access>
                            <enumeratedValues>
                                </enumeratedValues>
                        </field>
                        <field>
                            <name>ANSB03</name>
                            <description>A/D Conversion Channels Select</description>
                            <lsb>3</lsb>
                            <msb>3</msb>
                            <access>read-write</access>
                            <enumeratedValues>
                                </enumeratedValues>
                        </field>
                        <field>
                            <name>ANSB04</name>
                            <description>A/D Conversion Channels Select</description>
                            <lsb>4</lsb>
                            <msb>4</msb>
                            <access>read-write</access>
                            <enumeratedValues>
                                </enumeratedValues>
                        </field>
                        <field>
                            <name>ANSB05</name>
                            <description>A/D Conversion Channels Select</description>
                            <lsb>5</lsb>
                            <msb>5</msb>
                            <access>read-write</access>
                            <enumeratedValues>
                                </enumeratedValues>
                        </field>
                        <field>
                            <name>ANSB06</name>
                            <description>A/D Conversion Channels Select</description>
                            <lsb>6</lsb>
                            <msb>6</msb>
                            <access>read-write</access>
                            <enumeratedValues>
                                </enumeratedValues>
                        </field>
                        <field>
                            <name>ANSB07</name>
                            <description>A/D Conversion Channels Select</description>
                            <lsb>7</lsb>
                            <msb>7</msb>
                            <access>read-write</access>
                            <enumeratedValues>
                                </enumeratedValues>
                        </field>
                        <field>
                            <name>ANSB08</name>
                            <description>A/D Conversion Channels Select</description>
                            <lsb>8</lsb>
                            <msb>8</msb>
                            <access>read-write</access>
                            <enumeratedValues>
                                </enumeratedValues>
                        </field>
                        <field>
                            <name>ANSB09</name>
                            <description>A/D Conversion Channels Select</description>
                            <lsb>9</lsb>
                            <msb>9</msb>
                            <access>read-write</access>
                            <enumeratedValues>
                                </enumeratedValues>
                        </field>
                        <field>
                            <name>ANSB10</name>
                            <description>A/D Conversion Channels Select</description>
                            <lsb>10</lsb>
                            <msb>10</msb>
                            <access>read-write</access>
                            <enumeratedValues>
                                </enumeratedValues>
                        </field>
                        <field>
                            <name>ANSB12</name>
                            <description>A/D Conversion Channels Select</description>
                            <lsb>12</lsb>
                            <msb>12</msb>
                            <access>read-write</access>
                            <enumeratedValues>
                                </enumeratedValues>
                        </field>
                        <field>
                            <name>ANSB13</name>
                            <description>A/D Conversion Channels Select</description>
                            <lsb>13</lsb>
                            <msb>13</msb>
                            <access>read-write</access>
                            <enumeratedValues>
                                </enumeratedValues>
                        </field>
                    </fields>
                </register>
                <register>
                    <name>ADANSB1</name>
                    <description>A/D Channel Select Register B1</description>
                    <addressOffset>0x016</addressOffset>
                    <size>16</size>
                    <access>read-write</access>
                    <resetValue>0x0000</resetValue>
                    <resetMask>0xffff</resetMask>
                    <fields>
                        <field>
                            <name>ANSB16</name>
                            <description>A/D Conversion Channels Select</description>
                            <lsb>0</lsb>
                            <msb>0</msb>
                            <access>read-write</access>
                            <enumeratedValues>
                                </enumeratedValues>
                        </field>
                        <field>
                            <name>ANSB17</name>
                            <description>A/D Conversion Channels Select</description>
                            <lsb>1</lsb>
                            <msb>1</msb>
                            <access>read-write</access>
                            <enumeratedValues>
                                </enumeratedValues>
                        </field>
                        <field>
                            <name>ANSB18</name>
                            <description>A/D Conversion Channels Select</description>
                            <lsb>2</lsb>
                            <msb>2</msb>
                            <access>read-write</access>
                            <enumeratedValues>
                                </enumeratedValues>
                        </field>
                        <field>
                            <name>ANSB19</name>
                            <description>A/D Conversion Channels Select</description>
                            <lsb>3</lsb>
                            <msb>3</msb>
                            <access>read-write</access>
                            <enumeratedValues>
                                </enumeratedValues>
                        </field>
                        <field>
                            <name>ANSB20</name>
                            <description>A/D Conversion Channels Select</description>
                            <lsb>4</lsb>
                            <msb>4</msb>
                            <access>read-write</access>
                            <enumeratedValues>
                                </enumeratedValues>
                        </field>
                        <field>
                            <name>ANSB21</name>
                            <description>A/D Conversion Channels Select</description>
                            <lsb>5</lsb>
                            <msb>5</msb>
                            <access>read-write</access>
                            <enumeratedValues>
                                </enumeratedValues>
                        </field>
                        <field>
                            <name>ANSB22</name>
                            <description>A/D Conversion Channels Select</description>
                            <lsb>6</lsb>
                            <msb>6</msb>
                            <access>read-write</access>
                            <enumeratedValues>
                                </enumeratedValues>
                        </field>
                        <field>
                            <name>ANSB23</name>
                            <description>A/D Conversion Channels Select</description>
                            <lsb>7</lsb>
                            <msb>7</msb>
                            <access>read-write</access>
                            <enumeratedValues>
                                </enumeratedValues>
                        </field>
                        <field>
                            <name>ANSB24</name>
                            <description>A/D Conversion Channels Select</description>
                            <lsb>8</lsb>
                            <msb>8</msb>
                            <access>read-write</access>
                            <enumeratedValues>
                                </enumeratedValues>
                        </field>
                        <field>
                            <name>ANSB25</name>
                            <description>A/D Conversion Channels Select</description>
                            <lsb>9</lsb>
                            <msb>9</msb>
                            <access>read-write</access>
                            <enumeratedValues>
                                </enumeratedValues>
                        </field>
                        <field>
                            <name>ANSB26</name>
                            <description>A/D Conversion Channels Select</description>
                            <lsb>10</lsb>
                            <msb>10</msb>
                            <access>read-write</access>
                            <enumeratedValues>
                                </enumeratedValues>
                        </field>
                        <field>
                            <name>ANSB27</name>
                            <description>A/D Conversion Channels Select</description>
                            <lsb>11</lsb>
                            <msb>11</msb>
                            <access>read-write</access>
                            <enumeratedValues>
                                </enumeratedValues>
                        </field>
                        <field>
                            <name>ANSB28</name>
                            <description>A/D Conversion Channels Select</description>
                            <lsb>12</lsb>
                            <msb>12</msb>
                            <access>read-write</access>
                            <enumeratedValues>
                                </enumeratedValues>
                        </field>
                    </fields>
                </register>
                <register>
                    <name>ADDBLDR</name>
                    <description>A/D Data Duplexing Register</description>
                    <addressOffset>0x018</addressOffset>
                    <size>16</size>
                    <access>read-only</access>
                    <resetValue>0x0000</resetValue>
                    <resetMask>0xffff</resetMask>
                    <fields>
                        <field>
                            <name>ADDBLDR</name>
                            <description>Converted Value 15 to 0</description>
                            <lsb>0</lsb>
                            <msb>15</msb>
                            <access>read-only</access>
                        </field>
                    </fields>
                </register>
                <register>
                    <name>ADTSDR</name>
                    <description>A/D Temperature Sensor Data Register</description>
                    <addressOffset>0x01A</addressOffset>
                    <size>16</size>
                    <access>read-only</access>
                    <resetValue>0x0000</resetValue>
                    <resetMask>0xffff</resetMask>
                    <fields>
                        <field>
                            <name>ADTSDR</name>
                            <description>Converted Value 15 to 0</description>
                            <lsb>0</lsb>
                            <msb>15</msb>
                            <access>read-only</access>
                        </field>
                    </fields>
                </register>
                <register>
                    <name>ADOCDR</name>
                    <description>A/D Internal Reference Voltage Data Register</description>
                    <addressOffset>0x01C</addressOffset>
                    <size>16</size>
                    <access>read-only</access>
                    <resetValue>0x0000</resetValue>
                    <resetMask>0xffff</resetMask>
                    <fields>
                        <field>
                            <name>ADOCDR</name>
                            <description>Converted Value 15 to 0</description>
                            <lsb>0</lsb>
                            <msb>15</msb>
                            <access>read-only</access>
                        </field>
                    </fields>
                </register>
                <register>
                    <name>ADRD</name>
                    <description>A/D Self,Diagnosis Data Register</description>
                    <addressOffset>0x01E</addressOffset>
                    <size>16</size>
                    <access>read-only</access>
                    <resetValue>0x0000</resetValue>
                    <resetMask>0xffff</resetMask>
                    <fields>
                        <field>
                            <name>AD</name>
                            <description>Converted Value 11 to 0</description>
                            <lsb>0</lsb>
                            <msb>11</msb>
                            <access>read-only</access>
                        </field>
                        <field>
                            <name>DIAGST</name>
                            <description>Self,Diagnosis Status</description>
                            <lsb>14</lsb>
                            <msb>15</msb>
                            <access>read-only</access>
                            <enumeratedValues>
                                </enumeratedValues>
                        </field>
                    </fields>
                </register>
                <register>
                    <dim>11</dim>
                    <dimIncrement>0x2</dimIncrement>
                    <dimIndex>0-10</dimIndex>
                    <name>ADDR%s</name>
                    <description>A/D Data Registers %s</description>
                    <addressOffset>0x020</addressOffset>
                    <size>16</size>
                    <access>read-only</access>
                    <resetValue>0x0000</resetValue>
                    <resetMask>0xffff</resetMask>
                    <fields>
                        <field>
                            <name>ADDR</name>
                            <description>Converted Value 15 to 0</description>
                            <lsb>0</lsb>
                            <msb>15</msb>
                            <access>read-only</access>
                        </field>
                    </fields>
                </register>
                <register>
                    <dim>2</dim>
                    <dimIncrement>0x2</dimIncrement>
                    <dimIndex>12-13</dimIndex>
                    <name>ADDR%s_1</name>
                    <description>A/D Data Registers %s</description>
                    <addressOffset>0x038</addressOffset>
                    <size>16</size>
                    <access>read-only</access>
                    <resetValue>0x0000</resetValue>
                    <resetMask>0xffff</resetMask>
                    <fields>
                        <field>
                            <name>ADDR</name>
                            <description>Converted Value 15 to 0</description>
                            <lsb>0</lsb>
                            <msb>15</msb>
                            <access>read-only</access>
                        </field>
                    </fields>
                </register>
                <register>
                    <name>ADDISCR</name>
                    <description>A/D Disconnection Detection Control Register</description>
                    <addressOffset>0x07A</addressOffset>
                    <size>8</size>
                    <access>read-write</access>
                    <resetValue>0x00</resetValue>
                    <resetMask>0xff</resetMask>
                    <fields>
                        <field>
                            <name>ADNDIS</name>
                            <description>Disconnection Detection Assist Setting</description>
                            <lsb>0</lsb>
                            <msb>3</msb>
                            <access>read-write</access>
                            <enumeratedValues>
                                </enumeratedValues>
                        </field>
                        <field>
                            <name>PCHG</name>
                            <description>Precharge/discharge select</description>
                            <lsb>4</lsb>
                            <msb>4</msb>
                            <access>read-write</access>
                            <enumeratedValues>
                                </enumeratedValues>
                        </field>
                    </fields>
                </register>
                <register>
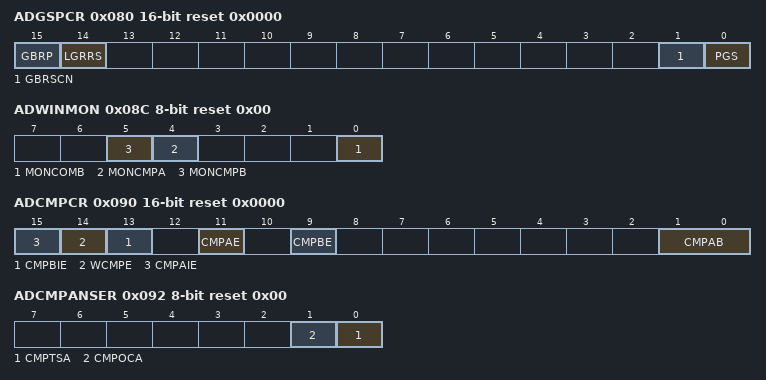
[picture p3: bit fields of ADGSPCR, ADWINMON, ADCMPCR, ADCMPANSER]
                    <name>ADGSPCR</name>
                    <description>A/D Group Scan Priority Control Register</description>
                    <addressOffset>0x080</addressOffset>
                    <size>16</size>
                    <access>read-write</access>
                    <resetValue>0x0000</resetValue>
                    <resetMask>0xffff</resetMask>
                    <fields>
                        <field>
                            <name>PGS</name>
                            <description>Group Priority Operation Setting</description>
                            <lsb>0</lsb>
                            <msb>0</msb>
                            <access>read-write</access>
                            <enumeratedValues>
                                </enumeratedValues>
                        </field>
                        <field>
                            <name>GBRSCN</name>
                            <description>Lower,Priority Group Restart Setting</description>
                            <lsb>1</lsb>
                            <msb>1</msb>
                            <access>read-write</access>
                            <enumeratedValues>
                                </enumeratedValues>
                        </field>
                        <field>
                            <name>LGRRS</name>
                            <description>Enabled only when PGS = 1 and GBRSCN = 1.</description>
                            <lsb>14</lsb>
                            <msb>14</msb>
                            <access>read-write</access>
                            <enumeratedValues>
                                </enumeratedValues>
                        </field>
                        <field>
                            <name>GBRP</name>
                            <description>Single Scan Continuous Start</description>
                            <lsb>15</lsb>
                            <msb>15</msb>
                            <access>read-write</access>
                            <enumeratedValues>
                                </enumeratedValues>
                        </field>
                    </fields>
                </register>
                <register>
                    <name>ADDBLDRA</name>
                    <description>A/D Data Duplexing Register A</description>
                    <addressOffset>0x084</addressOffset>
                    <size>16</size>
                    <access>read-only</access>
                    <resetValue>0x0000</resetValue>
                    <resetMask>0xffff</resetMask>
                    <fields>
                        <field>
                            <name>ADDBLDR</name>
                            <description>Converted Value 15 to 0</description>
                            <lsb>0</lsb>
                            <msb>15</msb>
                            <access>read-only</access>
                        </field>
                    </fields>
                </register>
                <register>
                    <name>ADDBLDRB</name>
                    <description>A/D Data Duplexing Register B</description>
                    <addressOffset>0x086</addressOffset>
                    <size>16</size>
                    <access>read-only</access>
                    <resetValue>0x0000</resetValue>
                    <resetMask>0xffff</resetMask>
                    <fields>
                        <field>
                            <name>ADDBLDR</name>
                            <description>Converted Value 15 to 0</description>
                            <lsb>0</lsb>
                            <msb>15</msb>
                            <access>read-only</access>
                        </field>
                    </fields>
                </register>
                <register>
                    <name>ADWINMON</name>
                    <description>A/D Compare Function Window A/B Status Monitor Register</description>
                    <addressOffset>0x08C</addressOffset>
                    <size>8</size>
                    <access>read-only</access>
                    <resetValue>0x00</resetValue>
                    <resetMask>0xff</resetMask>
                    <fields>
                        <field>
                            <name>MONCOMB</name>
                            <description>Combination Result Monitor</description>
                            <lsb>0</lsb>
                            <msb>0</msb>
                            <access>read-only</access>
                            <enumeratedValues>
                                </enumeratedValues>
                        </field>
                        <field>
                            <name>MONCMPA</name>
                            <description>Comparison Result Monitor A</description>
                            <lsb>4</lsb>
                            <msb>4</msb>
                            <access>read-only</access>
                            <enumeratedValues>
                                </enumeratedValues>
                        </field>
                        <field>
                            <name>MONCMPB</name>
                            <description>Comparison Result Monitor B</description>
                            <lsb>5</lsb>
                            <msb>5</msb>
                            <access>read-only</access>
                            <enumeratedValues>
                                </enumeratedValues>
                        </field>
                    </fields>
                </register>
                <register>
                    <name>ADCMPCR</name>
                    <description>A/D Compare Function Control Register</description>
                    <addressOffset>0x090</addressOffset>
                    <size>16</size>
                    <access>read-write</access>
                    <resetValue>0x0000</resetValue>
                    <resetMask>0xffff</resetMask>
                    <fields>
                        <field>
                            <name>CMPAB</name>
                            <description>Window A/B Composite Conditions Setting</description>
                            <lsb>0</lsb>
                            <msb>1</msb>
                            <access>read-write</access>
                            <enumeratedValues>
                                </enumeratedValues>
                        </field>
                        <field>
                            <name>CMPBE</name>
                            <description>Compare Window B Operation Enable</description>
                            <lsb>9</lsb>
                            <msb>9</msb>
                            <access>read-write</access>
                            <enumeratedValues>
                                </enumeratedValues>
                        </field>
                        <field>
                            <name>CMPAE</name>
                            <description>Compare Window A Operation Enable</description>
                            <lsb>11</lsb>
                            <msb>11</msb>
                            <access>read-write</access>
                            <enumeratedValues>
                                </enumeratedValues>
                        </field>
                        <field>
                            <name>CMPBIE</name>
                            <description>Compare B Interrupt Enable</description>
                            <lsb>13</lsb>
                            <msb>13</msb>
                            <access>read-write</access>
                            <enumeratedValues>
                                </enumeratedValues>
                        </field>
                        <field>
                            <name>WCMPE</name>
                            <description>Window Function Setting</description>
                            <lsb>14</lsb>
                            <msb>14</msb>
                            <access>read-write</access>
                            <enumeratedValues>
                                </enumeratedValues>
                        </field>
                        <field>
                            <name>CMPAIE</name>
                            <description>Compare A Interrupt Enable</description>
                            <lsb>15</lsb>
                            <msb>15</msb>
                            <access>read-write</access>
                            <enumeratedValues>
                                </enumeratedValues>
                        </field>
                    </fields>
                </register>
                <register>
                    <name>ADCMPANSER</name>
                    <description>A/D Compare Function Window A Extended Input Select Register</description>
                    <addressOffset>0x092</addressOffset>
                    <size>8</size>
                    <access>read-write</access>
                    <resetValue>0x00</resetValue>
                    <resetMask>0xff</resetMask>
                    <fields>
                        <field>
                            <name>CMPTSA</name>
                            <description>Temperature Sensor Output Compare Select</description>
                            <lsb>0</lsb>
                            <msb>0</msb>
                            <access>read-write</access>
                            <enumeratedValues>
                                </enumeratedValues>
                        </field>
                        <field>
                            <name>CMPOCA</name>
                            <description>Internal Reference Voltage Compare Select</description>
                            <lsb>1</lsb>
                            <msb>1</msb>
                            <access>read-write</access>
                            <enumeratedValues>
                                </enumeratedValues>
                        </field>
                    </fields>
                </register>
                <register>
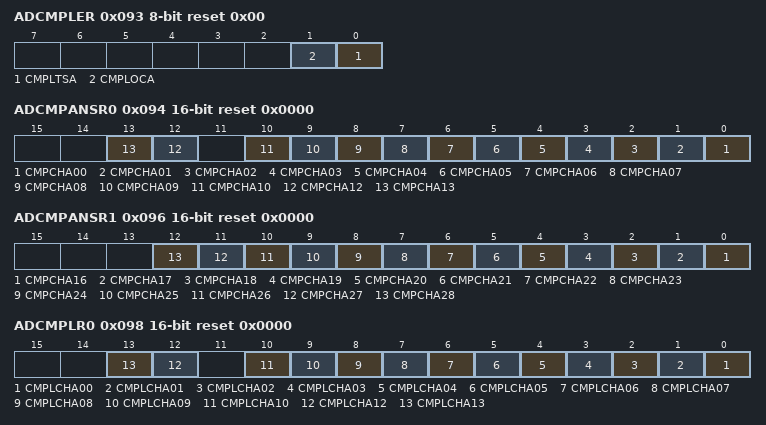
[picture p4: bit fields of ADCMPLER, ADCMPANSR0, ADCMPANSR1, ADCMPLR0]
                    <name>ADCMPLER</name>
                    <description>A/D Compare Function Window A Extended Input Comparison Condition Setting Register</description>
                    <addressOffset>0x093</addressOffset>
                    <size>8</size>
                    <access>read-write</access>
                    <resetValue>0x00</resetValue>
                    <resetMask>0xff</resetMask>
                    <fields>
                        <field>
                            <name>CMPLTSA</name>
                            <description>Compare Window A Temperature Sensor Output Comparison Condition Select</description>
                            <lsb>0</lsb>
                            <msb>0</msb>
                            <access>read-write</access>
                            <enumeratedValues>
                                </enumeratedValues>
                        </field>
                        <field>
                            <name>CMPLOCA</name>
                            <description>Compare Window A Internal Reference Voltage Comparison Condition Select</description>
                            <lsb>1</lsb>
                            <msb>1</msb>
                            <access>read-write</access>
                            <enumeratedValues>
                                </enumeratedValues>
                        </field>
                    </fields>
                </register>
                <register>
                    <name>ADCMPANSR0</name>
                    <description>A/D Compare Function Window A Channel Select Register 0</description>
                    <addressOffset>0x094</addressOffset>
                    <size>16</size>
                    <access>read-write</access>
                    <resetValue>0x0000</resetValue>
                    <resetMask>0xffff</resetMask>
                    <fields>
                        <field>
                            <name>CMPCHA00</name>
                            <description>Compare Window A Channel Select</description>
                            <lsb>0</lsb>
                            <msb>0</msb>
                            <access>read-write</access>
                            <enumeratedValues>
                                </enumeratedValues>
                        </field>
                        <field>
                            <name>CMPCHA01</name>
                            <description>Compare Window A Channel Select</description>
                            <lsb>1</lsb>
                            <msb>1</msb>
                            <access>read-write</access>
                            <enumeratedValues>
                                </enumeratedValues>
                        </field>
                        <field>
                            <name>CMPCHA02</name>
                            <description>Compare Window A Channel Select</description>
                            <lsb>2</lsb>
                            <msb>2</msb>
                            <access>read-write</access>
                            <enumeratedValues>
                                </enumeratedValues>
                        </field>
                        <field>
                            <name>CMPCHA03</name>
                            <description>Compare Window A Channel Select</description>
                            <lsb>3</lsb>
                            <msb>3</msb>
                            <access>read-write</access>
                            <enumeratedValues>
                                </enumeratedValues>
                        </field>
                        <field>
                            <name>CMPCHA04</name>
                            <description>Compare Window A Channel Select</description>
                            <lsb>4</lsb>
                            <msb>4</msb>
                            <access>read-write</access>
                            <enumeratedValues>
                                </enumeratedValues>
                        </field>
                        <field>
                            <name>CMPCHA05</name>
                            <description>Compare Window A Channel Select</description>
                            <lsb>5</lsb>
                            <msb>5</msb>
                            <access>read-write</access>
                            <enumeratedValues>
                                </enumeratedValues>
                        </field>
                        <field>
                            <name>CMPCHA06</name>
                            <description>Compare Window A Channel Select</description>
                            <lsb>6</lsb>
                            <msb>6</msb>
                            <access>read-write</access>
                            <enumeratedValues>
                                </enumeratedValues>
                        </field>
                        <field>
                            <name>CMPCHA07</name>
                            <description>Compare Window A Channel Select</description>
                            <lsb>7</lsb>
                            <msb>7</msb>
                            <access>read-write</access>
                            <enumeratedValues>
                                </enumeratedValues>
                        </field>
                        <field>
                            <name>CMPCHA08</name>
                            <description>Compare Window A Channel Select</description>
                            <lsb>8</lsb>
                            <msb>8</msb>
                            <access>read-write</access>
                            <enumeratedValues>
                                </enumeratedValues>
                        </field>
                        <field>
                            <name>CMPCHA09</name>
                            <description>Compare Window A Channel Select</description>
                            <lsb>9</lsb>
                            <msb>9</msb>
                            <access>read-write</access>
                            <enumeratedValues>
                                </enumeratedValues>
                        </field>
                        <field>
                            <name>CMPCHA10</name>
                            <description>Compare Window A Channel Select</description>
                            <lsb>10</lsb>
                            <msb>10</msb>
                            <access>read-write</access>
                            <enumeratedValues>
                                </enumeratedValues>
                        </field>
                        <field>
                            <name>CMPCHA12</name>
                            <description>Compare Window A Channel Select</description>
                            <lsb>12</lsb>
                            <msb>12</msb>
                            <access>read-write</access>
                            <enumeratedValues>
                                </enumeratedValues>
                        </field>
                        <field>
                            <name>CMPCHA13</name>
                            <description>Compare Window A Channel Select</description>
                            <lsb>13</lsb>
                            <msb>13</msb>
                            <access>read-write</access>
                            <enumeratedValues>
                                </enumeratedValues>
                        </field>
                    </fields>
                </register>
                <register>
                    <name>ADCMPANSR1</name>
                    <description>A/D Compare Function Window A Channel Select Register 1</description>
                    <addressOffset>0x096</addressOffset>
                    <size>16</size>
                    <access>read-write</access>
                    <resetValue>0x0000</resetValue>
                    <resetMask>0xffff</resetMask>
                    <fields>
                        <field>
                            <name>CMPCHA16</name>
                            <description>Compare Window A Channel Select</description>
                            <lsb>0</lsb>
                            <msb>0</msb>
                            <access>read-write</access>
                            <enumeratedValues>
                                </enumeratedValues>
                        </field>
                        <field>
                            <name>CMPCHA17</name>
                            <description>Compare Window A Channel Select</description>
                            <lsb>1</lsb>
                            <msb>1</msb>
                            <access>read-write</access>
                            <enumeratedValues>
                                </enumeratedValues>
                        </field>
                        <field>
                            <name>CMPCHA18</name>
                            <description>Compare Window A Channel Select</description>
                            <lsb>2</lsb>
                            <msb>2</msb>
                            <access>read-write</access>
                            <enumeratedValues>
                                </enumeratedValues>
                        </field>
                        <field>
                            <name>CMPCHA19</name>
                            <description>Compare Window A Channel Select</description>
                            <lsb>3</lsb>
                            <msb>3</msb>
                            <access>read-write</access>
                            <enumeratedValues>
                                </enumeratedValues>
                        </field>
                        <field>
                            <name>CMPCHA20</name>
                            <description>Compare Window A Channel Select</description>
                            <lsb>4</lsb>
                            <msb>4</msb>
                            <access>read-write</access>
                            <enumeratedValues>
                                </enumeratedValues>
                        </field>
                        <field>
                            <name>CMPCHA21</name>
                            <description>Compare Window A Channel Select</description>
                            <lsb>5</lsb>
                            <msb>5</msb>
                            <access>read-write</access>
                            <enumeratedValues>
                                </enumeratedValues>
                        </field>
                        <field>
                            <name>CMPCHA22</name>
                            <description>Compare Window A Channel Select</description>
                            <lsb>6</lsb>
                            <msb>6</msb>
                            <access>read-write</access>
                            <enumeratedValues>
                                </enumeratedValues>
                        </field>
                        <field>
                            <name>CMPCHA23</name>
                            <description>Compare Window A Channel Select</description>
                            <lsb>7</lsb>
                            <msb>7</msb>
                            <access>read-write</access>
                            <enumeratedValues>
                                </enumeratedValues>
                        </field>
                        <field>
                            <name>CMPCHA24</name>
                            <description>Compare Window A Channel Select</description>
                            <lsb>8</lsb>
                            <msb>8</msb>
                            <access>read-write</access>
                            <enumeratedValues>
                                </enumeratedValues>
                        </field>
                        <field>
                            <name>CMPCHA25</name>
                            <description>Compare Window A Channel Select</description>
                            <lsb>9</lsb>
                            <msb>9</msb>
                            <access>read-write</access>
                            <enumeratedValues>
                                </enumeratedValues>
                        </field>
                        <field>
                            <name>CMPCHA26</name>
                            <description>Compare Window A Channel Select</description>
                            <lsb>10</lsb>
                            <msb>10</msb>
                            <access>read-write</access>
                            <enumeratedValues>
                                </enumeratedValues>
                        </field>
                        <field>
                            <name>CMPCHA27</name>
                            <description>Compare Window A Channel Select</description>
                            <lsb>11</lsb>
                            <msb>11</msb>
                            <access>read-write</access>
                            <enumeratedValues>
                                </enumeratedValues>
                        </field>
                        <field>
                            <name>CMPCHA28</name>
                            <description>Compare Window A Channel Select</description>
                            <lsb>12</lsb>
                            <msb>12</msb>
                            <access>read-write</access>
                            <enumeratedValues>
                                </enumeratedValues>
                        </field>
                    </fields>
                </register>
                <register>
                    <name>ADCMPLR0</name>
                    <description>A/D Compare Function Window A Comparison Condition Setting Register 0</description>
                    <addressOffset>0x098</addressOffset>
                    <size>16</size>
                    <access>read-write</access>
                    <resetValue>0x0000</resetValue>
                    <resetMask>0xffff</resetMask>
                    <fields>
                        <field>
                            <name>CMPLCHA00</name>
                            <description>Compare Window A Comparison Condition Select</description>
                            <lsb>0</lsb>
                            <msb>0</msb>
                            <access>read-write</access>
                            <enumeratedValues>
                                </enumeratedValues>
                        </field>
                        <field>
                            <name>CMPLCHA01</name>
                            <description>Compare Window A Comparison Condition Select</description>
                            <lsb>1</lsb>
                            <msb>1</msb>
                            <access>read-write</access>
                            <enumeratedValues>
                                </enumeratedValues>
                        </field>
                        <field>
                            <name>CMPLCHA02</name>
                            <description>Compare Window A Comparison Condition Select</description>
                            <lsb>2</lsb>
                            <msb>2</msb>
                            <access>read-write</access>
                            <enumeratedValues>
                                </enumeratedValues>
                        </field>
                        <field>
                            <name>CMPLCHA03</name>
                            <description>Compare Window A Comparison Condition Select</description>
                            <lsb>3</lsb>
                            <msb>3</msb>
                            <access>read-write</access>
                            <enumeratedValues>
                                </enumeratedValues>
                        </field>
                        <field>
                            <name>CMPLCHA04</name>
                            <description>Compare Window A Comparison Condition Select</description>
                            <lsb>4</lsb>
                            <msb>4</msb>
                            <access>read-write</access>
                            <enumeratedValues>
                                </enumeratedValues>
                        </field>
                        <field>
                            <name>CMPLCHA05</name>
                            <description>Compare Window A Comparison Condition Select</description>
                            <lsb>5</lsb>
                            <msb>5</msb>
                            <access>read-write</access>
                            <enumeratedValues>
                                </enumeratedValues>
                        </field>
                        <field>
                            <name>CMPLCHA06</name>
                            <description>Compare Window A Comparison Condition Select</description>
                            <lsb>6</lsb>
                            <msb>6</msb>
                            <access>read-write</access>
                            <enumeratedValues>
                                </enumeratedValues>
                        </field>
                        <field>
                            <name>CMPLCHA07</name>
                            <description>Compare Window A Comparison Condition Select</description>
                            <lsb>7</lsb>
                            <msb>7</msb>
                            <access>read-write</access>
                            <enumeratedValues>
                                </enumeratedValues>
                        </field>
                        <field>
                            <name>CMPLCHA08</name>
                            <description>Compare Window A Comparison Condition Select</description>
                            <lsb>8</lsb>
                            <msb>8</msb>
                            <access>read-write</access>
                            <enumeratedValues>
                                </enumeratedValues>
                        </field>
                        <field>
                            <name>CMPLCHA09</name>
                            <description>Compare Window A Comparison Condition Select</description>
                            <lsb>9</lsb>
                            <msb>9</msb>
                            <access>read-write</access>
                            <enumeratedValues>
                                </enumeratedValues>
                        </field>
                        <field>
                            <name>CMPLCHA10</name>
                            <description>Compare Window A Comparison Condition Select</description>
                            <lsb>10</lsb>
                            <msb>10</msb>
                            <access>read-write</access>
                            <enumeratedValues>
                                </enumeratedValues>
                        </field>
                        <field>
                            <name>CMPLCHA12</name>
                            <description>Compare Window A Comparison Condition Select</description>
                            <lsb>12</lsb>
                            <msb>12</msb>
                            <access>read-write</access>
                            <enumeratedValues>
                                </enumeratedValues>
                        </field>
                        <field>
                            <name>CMPLCHA13</name>
                            <description>Compare Window A Comparison Condition Select</description>
                            <lsb>13</lsb>
                            <msb>13</msb>
                            <access>read-write</access>
                            <enumeratedValues>
                                </enumeratedValues>
                        </field>
                    </fields>
                </register>
                <register>
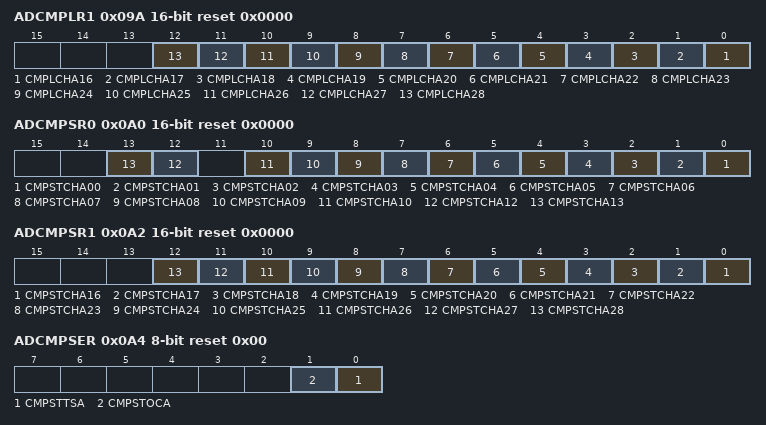
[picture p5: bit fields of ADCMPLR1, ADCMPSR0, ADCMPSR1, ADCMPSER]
                    <name>ADCMPLR1</name>
                    <description>A/D Compare Function Window A Comparison Condition Setting Register 1</description>
                    <addressOffset>0x09A</addressOffset>
                    <size>16</size>
                    <access>read-write</access>
                    <resetValue>0x0000</resetValue>
                    <resetMask>0xffff</resetMask>
                    <fields>
                        <field>
                            <name>CMPLCHA16</name>
                            <description>Compare Window A Comparison Condition Select</description>
                            <lsb>0</lsb>
                            <msb>0</msb>
                            <access>read-write</access>
                            <enumeratedValues>
                                </enumeratedValues>
                        </field>
                        <field>
                            <name>CMPLCHA17</name>
                            <description>Compare Window A Comparison Condition Select</description>
                            <lsb>1</lsb>
                            <msb>1</msb>
                            <access>read-write</access>
                            <enumeratedValues>
                                </enumeratedValues>
                        </field>
                        <field>
                            <name>CMPLCHA18</name>
                            <description>Compare Window A Comparison Condition Select</description>
                            <lsb>2</lsb>
                            <msb>2</msb>
                            <access>read-write</access>
                            <enumeratedValues>
                                </enumeratedValues>
                        </field>
                        <field>
                            <name>CMPLCHA19</name>
                            <description>Compare Window A Comparison Condition Select</description>
                            <lsb>3</lsb>
                            <msb>3</msb>
                            <access>read-write</access>
                            <enumeratedValues>
                                </enumeratedValues>
                        </field>
                        <field>
                            <name>CMPLCHA20</name>
                            <description>Compare Window A Comparison Condition Select</description>
                            <lsb>4</lsb>
                            <msb>4</msb>
                            <access>read-write</access>
                            <enumeratedValues>
                                </enumeratedValues>
                        </field>
                        <field>
                            <name>CMPLCHA21</name>
                            <description>Compare Window A Comparison Condition Select</description>
                            <lsb>5</lsb>
                            <msb>5</msb>
                            <access>read-write</access>
                            <enumeratedValues>
                                </enumeratedValues>
                        </field>
                        <field>
                            <name>CMPLCHA22</name>
                            <description>Compare Window A Comparison Condition Select</description>
                            <lsb>6</lsb>
                            <msb>6</msb>
                            <access>read-write</access>
                            <enumeratedValues>
                                </enumeratedValues>
                        </field>
                        <field>
                            <name>CMPLCHA23</name>
                            <description>Compare Window A Comparison Condition Select</description>
                            <lsb>7</lsb>
                            <msb>7</msb>
                            <access>read-write</access>
                            <enumeratedValues>
                                </enumeratedValues>
                        </field>
                        <field>
                            <name>CMPLCHA24</name>
                            <description>Compare Window A Comparison Condition Select</description>
                            <lsb>8</lsb>
                            <msb>8</msb>
                            <access>read-write</access>
                            <enumeratedValues>
                                </enumeratedValues>
                        </field>
                        <field>
                            <name>CMPLCHA25</name>
                            <description>Compare Window A Comparison Condition Select</description>
                            <lsb>9</lsb>
                            <msb>9</msb>
                            <access>read-write</access>
                            <enumeratedValues>
                                </enumeratedValues>
                        </field>
                        <field>
                            <name>CMPLCHA26</name>
                            <description>Compare Window A Comparison Condition Select</description>
                            <lsb>10</lsb>
                            <msb>10</msb>
                            <access>read-write</access>
                            <enumeratedValues>
                                </enumeratedValues>
                        </field>
                        <field>
                            <name>CMPLCHA27</name>
                            <description>Compare Window A Comparison Condition Select</description>
                            <lsb>11</lsb>
                            <msb>11</msb>
                            <access>read-write</access>
                            <enumeratedValues>
                                </enumeratedValues>
                        </field>
                        <field>
                            <name>CMPLCHA28</name>
                            <description>Compare Window A Comparison Condition Select</description>
                            <lsb>12</lsb>
                            <msb>12</msb>
                            <access>read-write</access>
                            <enumeratedValues>
                                </enumeratedValues>
                        </field>
                    </fields>
                </register>
                <register>
                    <dim>2</dim>
                    <dimIncrement>0x2</dimIncrement>
                    <dimIndex>0-1</dimIndex>
                    <name>ADCMPDR%s</name>
                    <description>A/D Compare Function Window A Lower,Side/Upper,Side Level Setting Register</description>
                    <addressOffset>0x09C</addressOffset>
                    <size>16</size>
                    <access>read-write</access>
                    <resetValue>0x0000</resetValue>
                    <resetMask>0xffff</resetMask>
                </register>
                <register>
                    <name>ADCMPSR0</name>
                    <description>A/D Compare Function Window A Channel Status Register 0</description>
                    <addressOffset>0x0A0</addressOffset>
                    <size>16</size>
                    <access>read-write</access>
                    <resetValue>0x0000</resetValue>
                    <resetMask>0xffff</resetMask>
                    <fields>
                        <field>
                            <name>CMPSTCHA00</name>
                            <description>Compare Window A Flag</description>
                            <lsb>0</lsb>
                            <msb>0</msb>
                            <access>read-write</access>
                            <enumeratedValues>
                                </enumeratedValues>
                        </field>
                        <field>
                            <name>CMPSTCHA01</name>
                            <description>Compare Window A Flag</description>
                            <lsb>1</lsb>
                            <msb>1</msb>
                            <access>read-write</access>
                            <enumeratedValues>
                                </enumeratedValues>
                        </field>
                        <field>
                            <name>CMPSTCHA02</name>
                            <description>Compare Window A Flag</description>
                            <lsb>2</lsb>
                            <msb>2</msb>
                            <access>read-write</access>
                            <enumeratedValues>
                                </enumeratedValues>
                        </field>
                        <field>
                            <name>CMPSTCHA03</name>
                            <description>Compare Window A Flag</description>
                            <lsb>3</lsb>
                            <msb>3</msb>
                            <access>read-write</access>
                            <enumeratedValues>
                                </enumeratedValues>
                        </field>
                        <field>
                            <name>CMPSTCHA04</name>
                            <description>Compare Window A Flag</description>
                            <lsb>4</lsb>
                            <msb>4</msb>
                            <access>read-write</access>
                            <enumeratedValues>
                                </enumeratedValues>
                        </field>
                        <field>
                            <name>CMPSTCHA05</name>
                            <description>Compare Window A Flag</description>
                            <lsb>5</lsb>
                            <msb>5</msb>
                            <access>read-write</access>
                            <enumeratedValues>
                                </enumeratedValues>
                        </field>
                        <field>
                            <name>CMPSTCHA06</name>
                            <description>Compare Window A Flag</description>
                            <lsb>6</lsb>
                            <msb>6</msb>
                            <access>read-write</access>
                            <enumeratedValues>
                                </enumeratedValues>
                        </field>
                        <field>
                            <name>CMPSTCHA07</name>
                            <description>Compare Window A Flag</description>
                            <lsb>7</lsb>
                            <msb>7</msb>
                            <access>read-write</access>
                            <enumeratedValues>
                                </enumeratedValues>
                        </field>
                        <field>
                            <name>CMPSTCHA08</name>
                            <description>Compare Window A Flag</description>
                            <lsb>8</lsb>
                            <msb>8</msb>
                            <access>read-write</access>
                            <enumeratedValues>
                                </enumeratedValues>
                        </field>
                        <field>
                            <name>CMPSTCHA09</name>
                            <description>Compare Window A Flag</description>
                            <lsb>9</lsb>
                            <msb>9</msb>
                            <access>read-write</access>
                            <enumeratedValues>
                                </enumeratedValues>
                        </field>
                        <field>
                            <name>CMPSTCHA10</name>
                            <description>Compare Window A Flag</description>
                            <lsb>10</lsb>
                            <msb>10</msb>
                            <access>read-write</access>
                            <enumeratedValues>
                                </enumeratedValues>
                        </field>
                        <field>
                            <name>CMPSTCHA12</name>
                            <description>Compare Window A Flag</description>
                            <lsb>12</lsb>
                            <msb>12</msb>
                            <access>read-write</access>
                            <enumeratedValues>
                                </enumeratedValues>
                        </field>
                        <field>
                            <name>CMPSTCHA13</name>
                            <description>Compare Window A Flag</description>
                            <lsb>13</lsb>
                            <msb>13</msb>
                            <access>read-write</access>
                            <enumeratedValues>
                                </enumeratedValues>
                        </field>
                    </fields>
                </register>
                <register>
                    <name>ADCMPSR1</name>
                    <description>A/D Compare Function Window A Channel Status Register1</description>
                    <addressOffset>0x0A2</addressOffset>
                    <size>16</size>
                    <access>read-write</access>
                    <resetValue>0x0000</resetValue>
                    <resetMask>0xffff</resetMask>
                    <fields>
                        <field>
                            <name>CMPSTCHA16</name>
                            <description>Compare Window A Flag</description>
                            <lsb>0</lsb>
                            <msb>0</msb>
                            <access>read-write</access>
                            <enumeratedValues>
                                </enumeratedValues>
                        </field>
                        <field>
                            <name>CMPSTCHA17</name>
                            <description>Compare Window A Flag</description>
                            <lsb>1</lsb>
                            <msb>1</msb>
                            <access>read-write</access>
                            <enumeratedValues>
                                </enumeratedValues>
                        </field>
                        <field>
                            <name>CMPSTCHA18</name>
                            <description>Compare Window A Flag</description>
                            <lsb>2</lsb>
                            <msb>2</msb>
                            <access>read-write</access>
                            <enumeratedValues>
                                </enumeratedValues>
                        </field>
                        <field>
                            <name>CMPSTCHA19</name>
                            <description>Compare Window A Flag</description>
                            <lsb>3</lsb>
                            <msb>3</msb>
                            <access>read-write</access>
                            <enumeratedValues>
                                </enumeratedValues>
                        </field>
                        <field>
                            <name>CMPSTCHA20</name>
                            <description>Compare Window A Flag</description>
                            <lsb>4</lsb>
                            <msb>4</msb>
                            <access>read-write</access>
                            <enumeratedValues>
                                </enumeratedValues>
                        </field>
                        <field>
                            <name>CMPSTCHA21</name>
                            <description>Compare Window A Flag</description>
                            <lsb>5</lsb>
                            <msb>5</msb>
                            <access>read-write</access>
                            <enumeratedValues>
                                </enumeratedValues>
                        </field>
                        <field>
                            <name>CMPSTCHA22</name>
                            <description>Compare Window A Flag</description>
                            <lsb>6</lsb>
                            <msb>6</msb>
                            <access>read-write</access>
                            <enumeratedValues>
                                </enumeratedValues>
                        </field>
                        <field>
                            <name>CMPSTCHA23</name>
                            <description>Compare Window A Flag</description>
                            <lsb>7</lsb>
                            <msb>7</msb>
                            <access>read-write</access>
                            <enumeratedValues>
                                </enumeratedValues>
                        </field>
                        <field>
                            <name>CMPSTCHA24</name>
                            <description>Compare Window A Flag</description>
                            <lsb>8</lsb>
                            <msb>8</msb>
                            <access>read-write</access>
                            <enumeratedValues>
                                </enumeratedValues>
                        </field>
                        <field>
                            <name>CMPSTCHA25</name>
                            <description>Compare Window A Flag</description>
                            <lsb>9</lsb>
                            <msb>9</msb>
                            <access>read-write</access>
                            <enumeratedValues>
                                </enumeratedValues>
                        </field>
                        <field>
                            <name>CMPSTCHA26</name>
                            <description>Compare Window A Flag</description>
                            <lsb>10</lsb>
                            <msb>10</msb>
                            <access>read-write</access>
                            <enumeratedValues>
                                </enumeratedValues>
                        </field>
                        <field>
                            <name>CMPSTCHA27</name>
                            <description>Compare Window A Flag</description>
                            <lsb>11</lsb>
                            <msb>11</msb>
                            <access>read-write</access>
                            <enumeratedValues>
                                </enumeratedValues>
                        </field>
                        <field>
                            <name>CMPSTCHA28</name>
                            <description>Compare Window A Flag</description>
                            <lsb>12</lsb>
                            <msb>12</msb>
                            <access>read-write</access>
                            <enumeratedValues>
                                </enumeratedValues>
                        </field>
                    </fields>
                </register>
                <register>
                    <name>ADCMPSER</name>
                    <description>A/D Compare Function Window A Extended Input Channel Status Register</description>
                    <addressOffset>0x0A4</addressOffset>
                    <size>8</size>
                    <access>read-write</access>
                    <resetValue>0x00</resetValue>
                    <resetMask>0xff</resetMask>
                    <fields>
                        <field>
                            <name>CMPSTTSA</name>
                            <description>Compare Window A Temperature Sensor Output Compare Flag</description>
                            <lsb>0</lsb>
                            <msb>0</msb>
                            <access>read-write</access>
                            <enumeratedValues>
                                </enumeratedValues>
                        </field>
                        <field>
                            <name>CMPSTOCA</name>
                            <description>Compare Window A Internal Reference Voltage Compare Flag</description>
                            <lsb>1</lsb>
                            <msb>1</msb>
                            <access>read-write</access>
                            <enumeratedValues>
                                </enumeratedValues>
                        </field>
                    </fields>
                </register>
                <register>
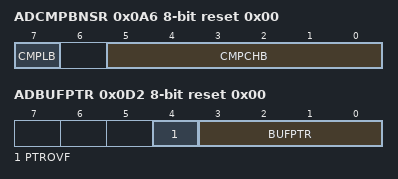
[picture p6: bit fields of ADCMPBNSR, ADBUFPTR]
                    <name>ADCMPBNSR</name>
                    <description>A/D Compare Function Window B Channel Select Register</description>
                    <addressOffset>0x0A6</addressOffset>
                    <size>8</size>
                    <access>read-write</access>
                    <resetValue>0x00</resetValue>
                    <resetMask>0xff</resetMask>
                    <fields>
                        <field>
                            <name>CMPCHB</name>
                            <description>Compare Window B Channel Select</description>
                            <lsb>0</lsb>
                            <msb>5</msb>
                            <access>read-write</access>
                        </field>
                        <field>
                            <name>CMPLB</name>
                            <description>Compare Window B Comparison Condition Setting</description>
                            <lsb>7</lsb>
                            <msb>7</msb>
                            <access>read-write</access>
                            <enumeratedValues>
                                </enumeratedValues>
                        </field>
                    </fields>
                </register>
                <register>
                    <name>ADWINLLB</name>
                    <description>A/D Compare Function Window B Lower,Side/Upper,Side Level Setting Register</description>
                    <addressOffset>0x0A8</addressOffset>
                    <size>16</size>
                    <access>read-write</access>
                    <resetValue>0x0000</resetValue>
                    <resetMask>0xffff</resetMask>
                </register>
                <register>
                    <name>ADWINULB</name>
                    <description>A/D Compare Function Window B Lower,Side/Upper,Side Level Setting Register</description>
                    <addressOffset>0x0AA</addressOffset>
                    <size>16</size>
                    <access>read-write</access>
                    <resetValue>0x0000</resetValue>
                    <resetMask>0xffff</resetMask>
                </register>
                <register>
                    <name>ADCMPBSR</name>
                    <description>A/D Compare Function Window B Status Register</description>
                    <addressOffset>0x0AC</addressOffset>
                    <size>8</size>
                    <access>read-write</access>
                    <resetValue>0x00</resetValue>
                    <resetMask>0xff</resetMask>
                    <fields>
                        <field>
                            <name>CMPSTB</name>
                            <description>Compare Window B Flag</description>
                            <lsb>0</lsb>
                            <msb>0</msb>
                            <access>read-write</access>
                            <enumeratedValues>
                                </enumeratedValues>
                        </field>
                    </fields>
                </register>
                <register>
                    <dim>16</dim>
                    <dimIncrement>0x2</dimIncrement>
                    <dimIndex>0-15</dimIndex>
                    <name>ADBUF%s</name>
                    <description>A/D Data Buffer Registers %s</description>
                    <addressOffset>0x0B0</addressOffset>
                    <size>16</size>
                    <access>read-only</access>
                    <resetValue>0x0000</resetValue>
                    <resetMask>0xffff</resetMask>
                    <fields>
                        <field>
                            <name>ADBUF</name>
                            <description>Converted Value 15 to 0</description>
                            <lsb>0</lsb>
                            <msb>15</msb>
                            <access>read-only</access>
                        </field>
                    </fields>
                </register>
                <register>
                    <name>ADBUFEN</name>
                    <description>A/D Data Buffer Enable Register</description>
                    <addressOffset>0x0D0</addressOffset>
                    <size>8</size>
                    <access>read-write</access>
                    <resetValue>0x00</resetValue>
                    <resetMask>0xff</resetMask>
                    <fields>
                        <field>
                            <name>BUFEN</name>
                            <description>Data Buffer Enable</description>
                            <lsb>0</lsb>
                            <msb>0</msb>
                            <access>read-write</access>
                            <enumeratedValues>
                                </enumeratedValues>
                        </field>
                    </fields>
                </register>
                <register>
                    <name>ADBUFPTR</name>
                    <description>A/D Data Buffer Pointer Register</description>
                    <addressOffset>0x0D2</addressOffset>
                    <size>8</size>
                    <access>read-write</access>
                    <resetValue>0x00</resetValue>
                    <resetMask>0xff</resetMask>
                    <fields>
                        <field>
                            <name>BUFPTR</name>
                            <description>Data Buffer Pointer</description>
                            <lsb>0</lsb>
                            <msb>3</msb>
                            <access>read-write</access>
                        </field>
                        <field>
                            <name>PTROVF</name>
                            <description>Pointer Overflow Flag</description>
                            <lsb>4</lsb>
                            <msb>4</msb>
                            <access>read-write</access>
                            <enumeratedValues>
                                </enumeratedValues>
                        </field>
                    </fields>
                </register>
                <register>
                    <name>ADSSTRL</name>
                    <description>A/D Sampling State Register</description>
                    <addressOffset>0x0DD</addressOffset>
                    <size>8</size>
                    <access>read-write</access>
                    <resetValue>0x0b</resetValue>
                    <resetMask>0xff</resetMask>
                    <fields>
                        <field>
                            <name>SST</name>
                            <description>Sampling Time Setting</description>
                            <lsb>0</lsb>
                            <msb>7</msb>
                            <access>read-write</access>
                        </field>
                    </fields>
                </register>
                <register>
                    <name>ADSSTRT</name>
                    <description>A/D Sampling State Register</description>
                    <addressOffset>0x0DE</addressOffset>
                    <size>8</size>
                    <access>read-write</access>
                    <resetValue>0x0b</resetValue>
                    <resetMask>0xff</resetMask>
                    <fields>
                        <field>
                            <name>SST</name>
                            <description>Sampling Time Setting</description>
                            <lsb>0</lsb>
                            <msb>7</msb>
                            <access>read-write</access>
                        </field>
                    </fields>
                </register>
                <register>
                    <name>ADSSTRO</name>
                    <description>A/D Sampling State Register</description>
                    <addressOffset>0x0DF</addressOffset>
                    <size>8</size>
                    <access>read-write</access>
                    <resetValue>0x0b</resetValue>
                    <resetMask>0xff</resetMask>
                    <fields>
                        <field>
                            <name>SST</name>
                            <description>Sampling Time Setting</description>
                            <lsb>0</lsb>
                            <msb>7</msb>
                            <access>read-write</access>
                        </field>
                    </fields>
                </register>
                <register>
                    <dim>11</dim>
                    <dimIncrement>0x1</dimIncrement>
                    <dimIndex>0-10</dimIndex>
                    <name>ADSSTR%s</name>
                    <description>A/D Sampling State Register</description>
                    <addressOffset>0x0E0</addressOffset>
                    <size>8</size>
                    <access>read-write</access>
                    <resetValue>0x0b</resetValue>
                    <resetMask>0xff</resetMask>
                    <fields>
                        <field>
                            <name>SST</name>
                            <description>Sampling Time Setting</description>
                            <lsb>0</lsb>
                            <msb>7</msb>
                            <access>read-write</access>
                        </field>
                    </fields>
                </register>
                <register>
                    <dim>2</dim>
                    <dimIncrement>0x1</dimIncrement>
                    <dimIndex>12-13</dimIndex>
                    <name>ADSSTR%s_1</name>
                    <description>A/D Sampling State Register</description>
                    <addressOffset>0x0EC</addressOffset>
                    <size>8</size>
                    <access>read-write</access>
                    <resetValue>0x0b</resetValue>
                    <resetMask>0xff</resetMask>
                    <fields>
                        <field>
                            <name>SST</name>
                            <description>Sampling Time Setting</description>
                            <lsb>0</lsb>
                            <msb>7</msb>
                            <access>read-write</access>
                        </field>
                    </fields>
                </register>
            </registers>
        </peripheral>
        <peripheral>
            <name>ADC121</name>
            <description>12-bit A/D Converter</description>
            <baseAddress>0x40170200</baseAddress>
            <addressBlock>
                <offset>0x00</offset>
                <size>2</size>
                <usage>registers</usage>
            </addressBlock>
            <addressBlock>
                <offset>0x04</offset>
                <size>9</size>
                <usage>registers</usage>
            </addressBlock>
            <addressBlock>
                <offset>0x0E</offset>
                <size>24</size>
                <usage>registers</usage>
            </addressBlock>
            <addressBlock>
                <offset>0x40</offset>
                <size>26</size>
                <usage>registers</usage>
            </addressBlock>
            <addressBlock>
                <offset>0x7A</offset>
                <size>1</size>
                <usage>registers</usage>
            </addressBlock>
            <addressBlock>
                <offset>0x80</offset>
                <size>2</size>
                <usage>registers</usage>
            </addressBlock>
            <addressBlock>
                <offset>0x84</offset>
                <size>4</size>
                <usage>registers</usage>
            </addressBlock>
            <addressBlock>
                <offset>0x8C</offset>
                <size>1</size>
                <usage>registers</usage>
            </addressBlock>
            <addressBlock>
                <offset>0x90</offset>
                <size>21</size>
                <usage>registers</usage>
            </addressBlock>
            <addressBlock>
                <offset>0xA6</offset>
                <size>1</size>
                <usage>registers</usage>
            </addressBlock>
            <addressBlock>
                <offset>0xA8</offset>
                <size>5</size>
                <usage>registers</usage>
            </addressBlock>
            <addressBlock>
                <offset>0xB0</offset>
                <size>33</size>
                <usage>registers</usage>
            </addressBlock>
            <addressBlock>
                <offset>0xD2</offset>
                <size>1</size>
                <usage>registers</usage>
            </addressBlock>
            <addressBlock>
                <offset>0xDD</offset>
                <size>6</size>
                <usage>registers</usage>
            </addressBlock>
            <registers>
                <register>
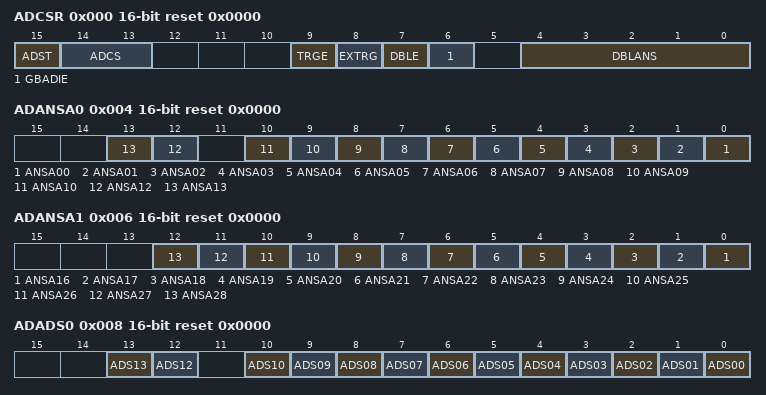
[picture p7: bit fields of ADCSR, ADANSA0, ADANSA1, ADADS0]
                    <name>ADCSR</name>
                    <description>A/D Control Register</description>
                    <addressOffset>0x000</addressOffset>
                    <size>16</size>
                    <access>read-write</access>
                    <resetValue>0x0000</resetValue>
                    <resetMask>0xffff</resetMask>
                    <fields>
                        <field>
                            <name>DBLANS</name>
                            <description>Double Trigger Channel Select</description>
                            <lsb>0</lsb>
                            <msb>4</msb>
                            <access>read-write</access>
                        </field>
                        <field>
                            <name>GBADIE</name>
                            <description>Group B Scan End Interrupt and ELC Event Enable</description>
                            <lsb>6</lsb>
                            <msb>6</msb>
                            <access>read-write</access>
                            <enumeratedValues>
                                </enumeratedValues>
                        </field>
                        <field>
                            <name>DBLE</name>
                            <description>Double Trigger Mode Select</description>
                            <lsb>7</lsb>
                            <msb>7</msb>
                            <access>read-write</access>
                            <enumeratedValues>
                                </enumeratedValues>
                        </field>
                        <field>
                            <name>EXTRG</name>
                            <description>Trigger Select</description>
                            <lsb>8</lsb>
                            <msb>8</msb>
                            <access>read-write</access>
                            <enumeratedValues>
                                </enumeratedValues>
                        </field>
                        <field>
                            <name>TRGE</name>
                            <description>Trigger Start Enable</description>
                            <lsb>9</lsb>
                            <msb>9</msb>
                            <access>read-write</access>
                            <enumeratedValues>
                                </enumeratedValues>
                        </field>
                        <field>
                            <name>ADCS</name>
                            <description>Scan Mode Select</description>
                            <lsb>13</lsb>
                            <msb>14</msb>
                            <access>read-write</access>
                            <enumeratedValues>
                                </enumeratedValues>
                        </field>
                        <field>
                            <name>ADST</name>
                            <description>A/D Conversion Start</description>
                            <lsb>15</lsb>
                            <msb>15</msb>
                            <access>read-write</access>
                            <enumeratedValues>
                                </enumeratedValues>
                        </field>
                    </fields>
                </register>
                <register>
                    <name>ADANSA0</name>
                    <description>A/D Channel Select Register A0</description>
                    <addressOffset>0x004</addressOffset>
                    <size>16</size>
                    <access>read-write</access>
                    <resetValue>0x0000</resetValue>
                    <resetMask>0xffff</resetMask>
                    <fields>
                        <field>
                            <name>ANSA00</name>
                            <description>A/D Conversion Channels Select</description>
                            <lsb>0</lsb>
                            <msb>0</msb>
                            <access>read-write</access>
                            <enumeratedValues>
                                </enumeratedValues>
                        </field>
                        <field>
                            <name>ANSA01</name>
                            <description>A/D Conversion Channels Select</description>
                            <lsb>1</lsb>
                            <msb>1</msb>
                            <access>read-write</access>
                            <enumeratedValues>
                                </enumeratedValues>
                        </field>
                        <field>
                            <name>ANSA02</name>
                            <description>A/D Conversion Channels Select</description>
                            <lsb>2</lsb>
                            <msb>2</msb>
                            <access>read-write</access>
                            <enumeratedValues>
                                </enumeratedValues>
                        </field>
                        <field>
                            <name>ANSA03</name>
                            <description>A/D Conversion Channels Select</description>
                            <lsb>3</lsb>
                            <msb>3</msb>
                            <access>read-write</access>
                            <enumeratedValues>
                                </enumeratedValues>
                        </field>
                        <field>
                            <name>ANSA04</name>
                            <description>A/D Conversion Channels Select</description>
                            <lsb>4</lsb>
                            <msb>4</msb>
                            <access>read-write</access>
                            <enumeratedValues>
                                </enumeratedValues>
                        </field>
                        <field>
                            <name>ANSA05</name>
                            <description>A/D Conversion Channels Select</description>
                            <lsb>5</lsb>
                            <msb>5</msb>
                            <access>read-write</access>
                            <enumeratedValues>
                                </enumeratedValues>
                        </field>
                        <field>
                            <name>ANSA06</name>
                            <description>A/D Conversion Channels Select</description>
                            <lsb>6</lsb>
                            <msb>6</msb>
                            <access>read-write</access>
                            <enumeratedValues>
                                </enumeratedValues>
                        </field>
                        <field>
                            <name>ANSA07</name>
                            <description>A/D Conversion Channels Select</description>
                            <lsb>7</lsb>
                            <msb>7</msb>
                            <access>read-write</access>
                            <enumeratedValues>
                                </enumeratedValues>
                        </field>
                        <field>
                            <name>ANSA08</name>
                            <description>A/D Conversion Channels Select</description>
                            <lsb>8</lsb>
                            <msb>8</msb>
                            <access>read-write</access>
                            <enumeratedValues>
                                </enumeratedValues>
                        </field>
                        <field>
                            <name>ANSA09</name>
                            <description>A/D Conversion Channels Select</description>
                            <lsb>9</lsb>
                            <msb>9</msb>
                            <access>read-write</access>
                            <enumeratedValues>
                                </enumeratedValues>
                        </field>
                        <field>
                            <name>ANSA10</name>
                            <description>A/D Conversion Channels Select</description>
                            <lsb>10</lsb>
                            <msb>10</msb>
                            <access>read-write</access>
                            <enumeratedValues>
                                </enumeratedValues>
                        </field>
                        <field>
                            <name>ANSA12</name>
                            <description>A/D Conversion Channels Select</description>
                            <lsb>12</lsb>
                            <msb>12</msb>
                            <access>read-write</access>
                            <enumeratedValues>
                                </enumeratedValues>
                        </field>
                        <field>
                            <name>ANSA13</name>
                            <description>A/D Conversion Channels Select</description>
                            <lsb>13</lsb>
                            <msb>13</msb>
                            <access>read-write</access>
                            <enumeratedValues>
                                </enumeratedValues>
                        </field>
                    </fields>
                </register>
                <register>
                    <name>ADANSA1</name>
                    <description>A/D Channel Select Register A1</description>
                    <addressOffset>0x006</addressOffset>
                    <size>16</size>
                    <access>read-write</access>
                    <resetValue>0x0000</resetValue>
                    <resetMask>0xffff</resetMask>
                    <fields>
                        <field>
                            <name>ANSA16</name>
                            <description>A/D Conversion Channels Select</description>
                            <lsb>0</lsb>
                            <msb>0</msb>
                            <access>read-write</access>
                            <enumeratedValues>
                                </enumeratedValues>
                        </field>
                        <field>
                            <name>ANSA17</name>
                            <description>A/D Conversion Channels Select</description>
                            <lsb>1</lsb>
                            <msb>1</msb>
                            <access>read-write</access>
                            <enumeratedValues>
                                </enumeratedValues>
                        </field>
                        <field>
                            <name>ANSA18</name>
                            <description>A/D Conversion Channels Select</description>
                            <lsb>2</lsb>
                            <msb>2</msb>
                            <access>read-write</access>
                            <enumeratedValues>
                                </enumeratedValues>
                        </field>
                        <field>
                            <name>ANSA19</name>
                            <description>A/D Conversion Channels Select</description>
                            <lsb>3</lsb>
                            <msb>3</msb>
                            <access>read-write</access>
                            <enumeratedValues>
                                </enumeratedValues>
                        </field>
                        <field>
                            <name>ANSA20</name>
                            <description>A/D Conversion Channels Select</description>
                            <lsb>4</lsb>
                            <msb>4</msb>
                            <access>read-write</access>
                            <enumeratedValues>
                                </enumeratedValues>
                        </field>
                        <field>
                            <name>ANSA21</name>
                            <description>A/D Conversion Channels Select</description>
                            <lsb>5</lsb>
                            <msb>5</msb>
                            <access>read-write</access>
                            <enumeratedValues>
                                </enumeratedValues>
                        </field>
                        <field>
                            <name>ANSA22</name>
                            <description>A/D Conversion Channels Select</description>
                            <lsb>6</lsb>
                            <msb>6</msb>
                            <access>read-write</access>
                            <enumeratedValues>
                                </enumeratedValues>
                        </field>
                        <field>
                            <name>ANSA23</name>
                            <description>A/D Conversion Channels Select</description>
                            <lsb>7</lsb>
                            <msb>7</msb>
                            <access>read-write</access>
                            <enumeratedValues>
                                </enumeratedValues>
                        </field>
                        <field>
                            <name>ANSA24</name>
                            <description>A/D Conversion Channels Select</description>
                            <lsb>8</lsb>
                            <msb>8</msb>
                            <access>read-write</access>
                            <enumeratedValues>
                                </enumeratedValues>
                        </field>
                        <field>
                            <name>ANSA25</name>
                            <description>A/D Conversion Channels Select</description>
                            <lsb>9</lsb>
                            <msb>9</msb>
                            <access>read-write</access>
                            <enumeratedValues>
                                </enumeratedValues>
                        </field>
                        <field>
                            <name>ANSA26</name>
                            <description>A/D Conversion Channels Select</description>
                            <lsb>10</lsb>
                            <msb>10</msb>
                            <access>read-write</access>
                            <enumeratedValues>
                                </enumeratedValues>
                        </field>
                        <field>
                            <name>ANSA27</name>
                            <description>A/D Conversion Channels Select</description>
                            <lsb>11</lsb>
                            <msb>11</msb>
                            <access>read-write</access>
                            <enumeratedValues>
                                </enumeratedValues>
                        </field>
                        <field>
                            <name>ANSA28</name>
                            <description>A/D Conversion Channels Select</description>
                            <lsb>12</lsb>
                            <msb>12</msb>
                            <access>read-write</access>
                            <enumeratedValues>
                                </enumeratedValues>
                        </field>
                    </fields>
                </register>
                <register>
                    <name>ADADS0</name>
                    <description>A/D,Converted Value Addition/Average Channel Select Register 0</description>
                    <addressOffset>0x008</addressOffset>
                    <size>16</size>
                    <access>read-write</access>
                    <resetValue>0x0000</resetValue>
                    <resetMask>0xffff</resetMask>
                    <fields>
                        <field>
                            <name>ADS00</name>
                            <description>A/D,Converted Value Addition/Average Channel Select</description>
                            <lsb>0</lsb>
                            <msb>0</msb>
                            <access>read-write</access>
                            <enumeratedValues>
                                </enumeratedValues>
                        </field>
                        <field>
                            <name>ADS01</name>
                            <description>A/D,Converted Value Addition/Average Channel Select</description>
                            <lsb>1</lsb>
                            <msb>1</msb>
                            <access>read-write</access>
                            <enumeratedValues>
                                </enumeratedValues>
                        </field>
                        <field>
                            <name>ADS02</name>
                            <description>A/D,Converted Value Addition/Average Channel Select</description>
                            <lsb>2</lsb>
                            <msb>2</msb>
                            <access>read-write</access>
                            <enumeratedValues>
                                </enumeratedValues>
                        </field>
                        <field>
                            <name>ADS03</name>
                            <description>A/D,Converted Value Addition/Average Channel Select</description>
                            <lsb>3</lsb>
                            <msb>3</msb>
                            <access>read-write</access>
                            <enumeratedValues>
                                </enumeratedValues>
                        </field>
                        <field>
                            <name>ADS04</name>
                            <description>A/D,Converted Value Addition/Average Channel Select</description>
                            <lsb>4</lsb>
                            <msb>4</msb>
                            <access>read-write</access>
                            <enumeratedValues>
                                </enumeratedValues>
                        </field>
                        <field>
                            <name>ADS05</name>
                            <description>A/D,Converted Value Addition/Average Channel Select</description>
                            <lsb>5</lsb>
                            <msb>5</msb>
                            <access>read-write</access>
                            <enumeratedValues>
                                </enumeratedValues>
                        </field>
                        <field>
                            <name>ADS06</name>
                            <description>A/D,Converted Value Addition/Average Channel Select</description>
                            <lsb>6</lsb>
                            <msb>6</msb>
                            <access>read-write</access>
                            <enumeratedValues>
                                </enumeratedValues>
                        </field>
                        <field>
                            <name>ADS07</name>
                            <description>A/D,Converted Value Addition/Average Channel Select</description>
                            <lsb>7</lsb>
                            <msb>7</msb>
                            <access>read-write</access>
                            <enumeratedValues>
                                </enumeratedValues>
                        </field>
                        <field>
                            <name>ADS08</name>
                            <description>A/D,Converted Value Addition/Average Channel Select</description>
                            <lsb>8</lsb>
                            <msb>8</msb>
                            <access>read-write</access>
                            <enumeratedValues>
                                </enumeratedValues>
                        </field>
                        <field>
                            <name>ADS09</name>
                            <description>A/D,Converted Value Addition/Average Channel Select</description>
                            <lsb>9</lsb>
                            <msb>9</msb>
                            <access>read-write</access>
                            <enumeratedValues>
                                </enumeratedValues>
                        </field>
                        <field>
                            <name>ADS10</name>
                            <description>A/D,Converted Value Addition/Average Channel Select</description>
                            <lsb>10</lsb>
                            <msb>10</msb>
                            <access>read-write</access>
                            <enumeratedValues>
                                </enumeratedValues>
                        </field>
                        <field>
                            <name>ADS12</name>
                            <description>A/D,Converted Value Addition/Average Channel Select</description>
                            <lsb>12</lsb>
                            <msb>12</msb>
                            <access>read-write</access>
                            <enumeratedValues>
                                </enumeratedValues>
                        </field>
                        <field>
                            <name>ADS13</name>
                            <description>A/D,Converted Value Addition/Average Channel Select</description>
                            <lsb>13</lsb>
                            <msb>13</msb>
                            <access>read-write</access>
                            <enumeratedValues>
                                </enumeratedValues>
                        </field>
                    </fields>
                </register>
                <register>
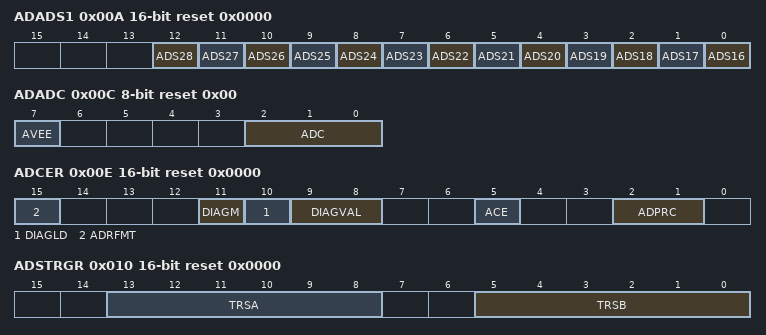
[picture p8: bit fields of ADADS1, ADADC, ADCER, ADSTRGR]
                    <name>ADADS1</name>
                    <description>A/D,Converted Value Addition/Average Channel Select Register 1</description>
                    <addressOffset>0x00A</addressOffset>
                    <size>16</size>
                    <access>read-write</access>
                    <resetValue>0x0000</resetValue>
                    <resetMask>0xffff</resetMask>
                    <fields>
                        <field>
                            <name>ADS16</name>
                            <description>A/D,Converted Value Addition/Average Channel Select</description>
                            <lsb>0</lsb>
                            <msb>0</msb>
                            <access>read-write</access>
                            <enumeratedValues>
                                </enumeratedValues>
                        </field>
                        <field>
                            <name>ADS17</name>
                            <description>A/D,Converted Value Addition/Average Channel Select</description>
                            <lsb>1</lsb>
                            <msb>1</msb>
                            <access>read-write</access>
                            <enumeratedValues>
                                </enumeratedValues>
                        </field>
                        <field>
                            <name>ADS18</name>
                            <description>A/D,Converted Value Addition/Average Channel Select</description>
                            <lsb>2</lsb>
                            <msb>2</msb>
                            <access>read-write</access>
                            <enumeratedValues>
                                </enumeratedValues>
                        </field>
                        <field>
                            <name>ADS19</name>
                            <description>A/D,Converted Value Addition/Average Channel Select</description>
                            <lsb>3</lsb>
                            <msb>3</msb>
                            <access>read-write</access>
                            <enumeratedValues>
                                </enumeratedValues>
                        </field>
                        <field>
                            <name>ADS20</name>
                            <description>A/D,Converted Value Addition/Average Channel Select</description>
                            <lsb>4</lsb>
                            <msb>4</msb>
                            <access>read-write</access>
                            <enumeratedValues>
                                </enumeratedValues>
                        </field>
                        <field>
                            <name>ADS21</name>
                            <description>A/D,Converted Value Addition/Average Channel Select</description>
                            <lsb>5</lsb>
                            <msb>5</msb>
                            <access>read-write</access>
                            <enumeratedValues>
                                </enumeratedValues>
                        </field>
                        <field>
                            <name>ADS22</name>
                            <description>A/D,Converted Value Addition/Average Channel Select</description>
                            <lsb>6</lsb>
                            <msb>6</msb>
                            <access>read-write</access>
                            <enumeratedValues>
                                </enumeratedValues>
                        </field>
                        <field>
                            <name>ADS23</name>
                            <description>A/D,Converted Value Addition/Average Channel Select</description>
                            <lsb>7</lsb>
                            <msb>7</msb>
                            <access>read-write</access>
                            <enumeratedValues>
                                </enumeratedValues>
                        </field>
                        <field>
                            <name>ADS24</name>
                            <description>A/D,Converted Value Addition/Average Channel Select</description>
                            <lsb>8</lsb>
                            <msb>8</msb>
                            <access>read-write</access>
                            <enumeratedValues>
                                </enumeratedValues>
                        </field>
                        <field>
                            <name>ADS25</name>
                            <description>A/D,Converted Value Addition/Average Channel Select</description>
                            <lsb>9</lsb>
                            <msb>9</msb>
                            <access>read-write</access>
                            <enumeratedValues>
                                </enumeratedValues>
                        </field>
                        <field>
                            <name>ADS26</name>
                            <description>A/D,Converted Value Addition/Average Channel Select</description>
                            <lsb>10</lsb>
                            <msb>10</msb>
                            <access>read-write</access>
                            <enumeratedValues>
                                </enumeratedValues>
                        </field>
                        <field>
                            <name>ADS27</name>
                            <description>A/D,Converted Value Addition/Average Channel Select</description>
                            <lsb>11</lsb>
                            <msb>11</msb>
                            <access>read-write</access>
                            <enumeratedValues>
                                </enumeratedValues>
                        </field>
                        <field>
                            <name>ADS28</name>
                            <description>A/D,Converted Value Addition/Average Channel Select</description>
                            <lsb>12</lsb>
                            <msb>12</msb>
                            <access>read-write</access>
                            <enumeratedValues>
                                </enumeratedValues>
                        </field>
                    </fields>
                </register>
                <register>
                    <name>ADADC</name>
                    <description>A/D,Converted Value Addition/Average Count Select Register</description>
                    <addressOffset>0x00C</addressOffset>
                    <size>8</size>
                    <access>read-write</access>
                    <resetValue>0x00</resetValue>
                    <resetMask>0xff</resetMask>
                    <fields>
                        <field>
                            <name>ADC</name>
                            <description>Addition/Average Count Select</description>
                            <lsb>0</lsb>
                            <msb>2</msb>
                            <access>read-write</access>
                            <enumeratedValues>
                                </enumeratedValues>
                        </field>
                        <field>
                            <name>AVEE</name>
                            <description>Average Mode Select</description>
                            <lsb>7</lsb>
                            <msb>7</msb>
                            <access>read-write</access>
                            <enumeratedValues>
                                </enumeratedValues>
                        </field>
                    </fields>
                </register>
                <register>
                    <name>ADCER</name>
                    <description>A/D Control Extended Register</description>
                    <addressOffset>0x00E</addressOffset>
                    <size>16</size>
                    <access>read-write</access>
                    <resetValue>0x0000</resetValue>
                    <resetMask>0xffff</resetMask>
                    <fields>
                        <field>
                            <name>ADPRC</name>
                            <lsb>1</lsb>
                            <msb>2</msb>
                            <access>read-write</access>
                            <enumeratedValues>
                                </enumeratedValues>
                        </field>
                        <field>
                            <name>ACE</name>
                            <description>A/D Data Register Automatic Clearing Enable</description>
                            <lsb>5</lsb>
                            <msb>5</msb>
                            <access>read-write</access>
                            <enumeratedValues>
                                </enumeratedValues>
                        </field>
                        <field>
                            <name>DIAGVAL</name>
                            <description>Self,Diagnosis Conversion Voltage Select</description>
                            <lsb>8</lsb>
                            <msb>9</msb>
                            <access>read-write</access>
                            <enumeratedValues>
                                </enumeratedValues>
                        </field>
                        <field>
                            <name>DIAGLD</name>
                            <description>Self,Diagnosis Mode Select</description>
                            <lsb>10</lsb>
                            <msb>10</msb>
                            <access>read-write</access>
                            <enumeratedValues>
                                </enumeratedValues>
                        </field>
                        <field>
                            <name>DIAGM</name>
                            <description>Self,Diagnosis Enable</description>
                            <lsb>11</lsb>
                            <msb>11</msb>
                            <access>read-write</access>
                            <enumeratedValues>
                                </enumeratedValues>
                        </field>
                        <field>
                            <name>ADRFMT</name>
                            <description>A/D Data Register Format Select</description>
                            <lsb>15</lsb>
                            <msb>15</msb>
                            <access>read-write</access>
                            <enumeratedValues>
                                </enumeratedValues>
                        </field>
                    </fields>
                </register>
                <register>
                    <name>ADSTRGR</name>
                    <description>A/D Conversion Start Trigger Select Register</description>
                    <addressOffset>0x010</addressOffset>
                    <size>16</size>
                    <access>read-write</access>
                    <resetValue>0x0000</resetValue>
                    <resetMask>0xffff</resetMask>
                    <fields>
                        <field>
                            <name>TRSB</name>
                            <description>A/D Conversion Start Trigger Select for Group B</description>
                            <lsb>0</lsb>
                            <msb>5</msb>
                            <access>read-write</access>
                        </field>
                        <field>
                            <name>TRSA</name>
                            <description>A/D Conversion Start Trigger Select</description>
                            <lsb>8</lsb>
                            <msb>13</msb>
                            <access>read-write</access>
                        </field>
                    </fields>
                </register>
                <register>
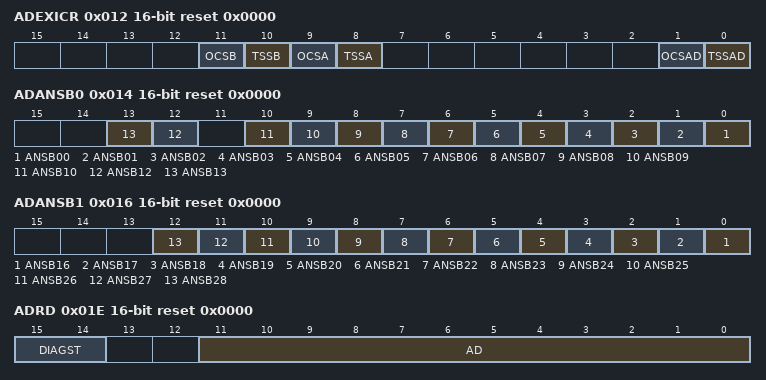
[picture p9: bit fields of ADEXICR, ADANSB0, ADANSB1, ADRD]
                    <name>ADEXICR</name>
                    <description>A/D Conversion Extended Input Control Registers</description>
                    <addressOffset>0x012</addressOffset>
                    <size>16</size>
                    <access>read-write</access>
                    <resetValue>0x0000</resetValue>
                    <resetMask>0xffff</resetMask>
                    <fields>
                        <field>
                            <name>TSSAD</name>
                            <description>Temperature Sensor Output A/D,Converted Value Addition/Average Mode Select</description>
                            <lsb>0</lsb>
                            <msb>0</msb>
                            <access>read-write</access>
                            <enumeratedValues>
                                </enumeratedValues>
                        </field>
                        <field>
                            <name>OCSAD</name>
                            <description>Internal Reference Voltage A/D,Converted Value Addition/Average Mode Select</description>
                            <lsb>1</lsb>
                            <msb>1</msb>
                            <access>read-write</access>
                            <enumeratedValues>
                                </enumeratedValues>
                        </field>
                        <field>
                            <name>TSSA</name>
                            <description>Temperature Sensor Output A/D Conversion Select</description>
                            <lsb>8</lsb>
                            <msb>8</msb>
                            <access>read-write</access>
                            <enumeratedValues>
                                </enumeratedValues>
                        </field>
                        <field>
                            <name>OCSA</name>
                            <description>Internal Reference Voltage A/D Conversion Select</description>
                            <lsb>9</lsb>
                            <msb>9</msb>
                            <access>read-write</access>
                            <enumeratedValues>
                                </enumeratedValues>
                        </field>
                        <field>
                            <name>TSSB</name>
                            <description>Temperature Sensor Output A/D Conversion Select for Group B</description>
                            <lsb>10</lsb>
                            <msb>10</msb>
                            <access>read-write</access>
                            <enumeratedValues>
                                </enumeratedValues>
                        </field>
                        <field>
                            <name>OCSB</name>
                            <description>Internal Reference Voltage A/D Conversion Select for Group B</description>
                            <lsb>11</lsb>
                            <msb>11</msb>
                            <access>read-write</access>
                            <enumeratedValues>
                                </enumeratedValues>
                        </field>
                    </fields>
                </register>
                <register>
                    <name>ADANSB0</name>
                    <description>A/D Channel Select Register B0</description>
                    <addressOffset>0x014</addressOffset>
                    <size>16</size>
                    <access>read-write</access>
                    <resetValue>0x0000</resetValue>
                    <resetMask>0xffff</resetMask>
                    <fields>
                        <field>
                            <name>ANSB00</name>
                            <description>A/D Conversion Channels Select</description>
                            <lsb>0</lsb>
                            <msb>0</msb>
                            <access>read-write</access>
                            <enumeratedValues>
                                </enumeratedValues>
                        </field>
                        <field>
                            <name>ANSB01</name>
                            <description>A/D Conversion Channels Select</description>
                            <lsb>1</lsb>
                            <msb>1</msb>
                            <access>read-write</access>
                            <enumeratedValues>
                                </enumeratedValues>
                        </field>
                        <field>
                            <name>ANSB02</name>
                            <description>A/D Conversion Channels Select</description>
                            <lsb>2</lsb>
                            <msb>2</msb>
                            <access>read-write</access>
                            <enumeratedValues>
                                </enumeratedValues>
                        </field>
                        <field>
                            <name>ANSB03</name>
                            <description>A/D Conversion Channels Select</description>
                            <lsb>3</lsb>
                            <msb>3</msb>
                            <access>read-write</access>
                            <enumeratedValues>
                                </enumeratedValues>
                        </field>
                        <field>
                            <name>ANSB04</name>
                            <description>A/D Conversion Channels Select</description>
                            <lsb>4</lsb>
                            <msb>4</msb>
                            <access>read-write</access>
                            <enumeratedValues>
                                </enumeratedValues>
                        </field>
                        <field>
                            <name>ANSB05</name>
                            <description>A/D Conversion Channels Select</description>
                            <lsb>5</lsb>
                            <msb>5</msb>
                            <access>read-write</access>
                            <enumeratedValues>
                                </enumeratedValues>
                        </field>
                        <field>
                            <name>ANSB06</name>
                            <description>A/D Conversion Channels Select</description>
                            <lsb>6</lsb>
                            <msb>6</msb>
                            <access>read-write</access>
                            <enumeratedValues>
                                </enumeratedValues>
                        </field>
                        <field>
                            <name>ANSB07</name>
                            <description>A/D Conversion Channels Select</description>
                            <lsb>7</lsb>
                            <msb>7</msb>
                            <access>read-write</access>
                            <enumeratedValues>
                                </enumeratedValues>
                        </field>
                        <field>
                            <name>ANSB08</name>
                            <description>A/D Conversion Channels Select</description>
                            <lsb>8</lsb>
                            <msb>8</msb>
                            <access>read-write</access>
                            <enumeratedValues>
                                </enumeratedValues>
                        </field>
                        <field>
                            <name>ANSB09</name>
                            <description>A/D Conversion Channels Select</description>
                            <lsb>9</lsb>
                            <msb>9</msb>
                            <access>read-write</access>
                            <enumeratedValues>
                                </enumeratedValues>
                        </field>
                        <field>
                            <name>ANSB10</name>
                            <description>A/D Conversion Channels Select</description>
                            <lsb>10</lsb>
                            <msb>10</msb>
                            <access>read-write</access>
                            <enumeratedValues>
                                </enumeratedValues>
                        </field>
                        <field>
                            <name>ANSB12</name>
                            <description>A/D Conversion Channels Select</description>
                            <lsb>12</lsb>
                            <msb>12</msb>
                            <access>read-write</access>
                            <enumeratedValues>
                                </enumeratedValues>
                        </field>
                        <field>
                            <name>ANSB13</name>
                            <description>A/D Conversion Channels Select</description>
                            <lsb>13</lsb>
                            <msb>13</msb>
                            <access>read-write</access>
                            <enumeratedValues>
                                </enumeratedValues>
                        </field>
                    </fields>
                </register>
                <register>
                    <name>ADANSB1</name>
                    <description>A/D Channel Select Register B1</description>
                    <addressOffset>0x016</addressOffset>
                    <size>16</size>
                    <access>read-write</access>
                    <resetValue>0x0000</resetValue>
                    <resetMask>0xffff</resetMask>
                    <fields>
                        <field>
                            <name>ANSB16</name>
                            <description>A/D Conversion Channels Select</description>
                            <lsb>0</lsb>
                            <msb>0</msb>
                            <access>read-write</access>
                            <enumeratedValues>
                                </enumeratedValues>
                        </field>
                        <field>
                            <name>ANSB17</name>
                            <description>A/D Conversion Channels Select</description>
                            <lsb>1</lsb>
                            <msb>1</msb>
                            <access>read-write</access>
                            <enumeratedValues>
                                </enumeratedValues>
                        </field>
                        <field>
                            <name>ANSB18</name>
                            <description>A/D Conversion Channels Select</description>
                            <lsb>2</lsb>
                            <msb>2</msb>
                            <access>read-write</access>
                            <enumeratedValues>
                                </enumeratedValues>
                        </field>
                        <field>
                            <name>ANSB19</name>
                            <description>A/D Conversion Channels Select</description>
                            <lsb>3</lsb>
                            <msb>3</msb>
                            <access>read-write</access>
                            <enumeratedValues>
                                </enumeratedValues>
                        </field>
                        <field>
                            <name>ANSB20</name>
                            <description>A/D Conversion Channels Select</description>
                            <lsb>4</lsb>
                            <msb>4</msb>
                            <access>read-write</access>
                            <enumeratedValues>
                                </enumeratedValues>
                        </field>
                        <field>
                            <name>ANSB21</name>
                            <description>A/D Conversion Channels Select</description>
                            <lsb>5</lsb>
                            <msb>5</msb>
                            <access>read-write</access>
                            <enumeratedValues>
                                </enumeratedValues>
                        </field>
                        <field>
                            <name>ANSB22</name>
                            <description>A/D Conversion Channels Select</description>
                            <lsb>6</lsb>
                            <msb>6</msb>
                            <access>read-write</access>
                            <enumeratedValues>
                                </enumeratedValues>
                        </field>
                        <field>
                            <name>ANSB23</name>
                            <description>A/D Conversion Channels Select</description>
                            <lsb>7</lsb>
                            <msb>7</msb>
                            <access>read-write</access>
                            <enumeratedValues>
                                </enumeratedValues>
                        </field>
                        <field>
                            <name>ANSB24</name>
                            <description>A/D Conversion Channels Select</description>
                            <lsb>8</lsb>
                            <msb>8</msb>
                            <access>read-write</access>
                            <enumeratedValues>
                                </enumeratedValues>
                        </field>
                        <field>
                            <name>ANSB25</name>
                            <description>A/D Conversion Channels Select</description>
                            <lsb>9</lsb>
                            <msb>9</msb>
                            <access>read-write</access>
                            <enumeratedValues>
                                </enumeratedValues>
                        </field>
                        <field>
                            <name>ANSB26</name>
                            <description>A/D Conversion Channels Select</description>
                            <lsb>10</lsb>
                            <msb>10</msb>
                            <access>read-write</access>
                            <enumeratedValues>
                                </enumeratedValues>
                        </field>
                        <field>
                            <name>ANSB27</name>
                            <description>A/D Conversion Channels Select</description>
                            <lsb>11</lsb>
                            <msb>11</msb>
                            <access>read-write</access>
                            <enumeratedValues>
                                </enumeratedValues>
                        </field>
                        <field>
                            <name>ANSB28</name>
                            <description>A/D Conversion Channels Select</description>
                            <lsb>12</lsb>
                            <msb>12</msb>
                            <access>read-write</access>
                            <enumeratedValues>
                                </enumeratedValues>
                        </field>
                    </fields>
                </register>
                <register>
                    <name>ADDBLDR</name>
                    <description>A/D Data Duplexing Register</description>
                    <addressOffset>0x018</addressOffset>
                    <size>16</size>
                    <access>read-only</access>
                    <resetValue>0x0000</resetValue>
                    <resetMask>0xffff</resetMask>
                    <fields>
                        <field>
                            <name>ADDBLDR</name>
                            <description>Converted Value 15 to 0</description>
                            <lsb>0</lsb>
                            <msb>15</msb>
                            <access>read-only</access>
                        </field>
                    </fields>
                </register>
                <register>
                    <name>ADTSDR</name>
                    <description>A/D Temperature Sensor Data Register</description>
                    <addressOffset>0x01A</addressOffset>
                    <size>16</size>
                    <access>read-only</access>
                    <resetValue>0x0000</resetValue>
                    <resetMask>0xffff</resetMask>
                    <fields>
                        <field>
                            <name>ADTSDR</name>
                            <description>Converted Value 15 to 0</description>
                            <lsb>0</lsb>
                            <msb>15</msb>
                            <access>read-only</access>
                        </field>
                    </fields>
                </register>
                <register>
                    <name>ADOCDR</name>
                    <description>A/D Internal Reference Voltage Data Register</description>
                    <addressOffset>0x01C</addressOffset>
                    <size>16</size>
                    <access>read-only</access>
                    <resetValue>0x0000</resetValue>
                    <resetMask>0xffff</resetMask>
                    <fields>
                        <field>
                            <name>ADOCDR</name>
                            <description>Converted Value 15 to 0</description>
                            <lsb>0</lsb>
                            <msb>15</msb>
                            <access>read-only</access>
                        </field>
                    </fields>
                </register>
                <register>
                    <name>ADRD</name>
                    <description>A/D Self,Diagnosis Data Register</description>
                    <addressOffset>0x01E</addressOffset>
                    <size>16</size>
                    <access>read-only</access>
                    <resetValue>0x0000</resetValue>
                    <resetMask>0xffff</resetMask>
                    <fields>
                        <field>
                            <name>AD</name>
                            <description>Converted Value 11 to 0</description>
                            <lsb>0</lsb>
                            <msb>11</msb>
                            <access>read-only</access>
                        </field>
                        <field>
                            <name>DIAGST</name>
                            <description>Self,Diagnosis Status</description>
                            <lsb>14</lsb>
                            <msb>15</msb>
                            <access>read-only</access>
                            <enumeratedValues>
                                </enumeratedValues>
                        </field>
                    </fields>
                </register>
                <register>
                    <dim>3</dim>
                    <dimIncrement>0x2</dimIncrement>
                    <dimIndex>0-2</dimIndex>
                    <name>ADDR%s</name>
                    <description>A/D Data Registers %s</description>
                    <addressOffset>0x020</addressOffset>
                    <size>16</size>
                    <access>read-only</access>
                    <resetValue>0x0000</resetValue>
                    <resetMask>0xffff</resetMask>
                    <fields>
                        <field>
                            <name>ADDR</name>
                            <description>Converted Value 15 to 0</description>
                            <lsb>0</lsb>
                            <msb>15</msb>
                            <access>read-only</access>
                        </field>
                    </fields>
                </register>
                <register>
                    <dim>13</dim>
                    <dimIncrement>0x2</dimIncrement>
                    <dimIndex>16-28</dimIndex>
                    <name>ADDR%s_1</name>
                    <description>A/D Data Registers %s</description>
                    <addressOffset>0x040</addressOffset>
                    <size>16</size>
                    <access>read-only</access>
                    <resetValue>0x0000</resetValue>
                    <resetMask>0xffff</resetMask>
                    <fields>
                        <field>
                            <name>ADDR</name>
                            <description>Converted Value 15 to 0</description>
                            <lsb>0</lsb>
                            <msb>15</msb>
                            <access>read-only</access>
                        </field>
                    </fields>
                </register>
                <register>
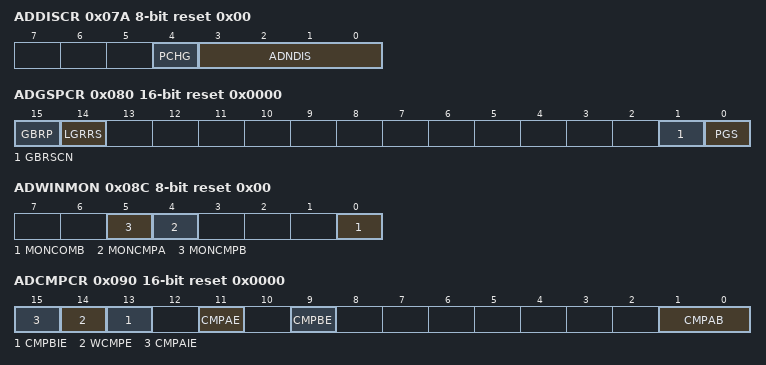
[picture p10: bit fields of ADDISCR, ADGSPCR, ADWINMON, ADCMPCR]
                    <name>ADDISCR</name>
                    <description>A/D Disconnection Detection Control Register</description>
                    <addressOffset>0x07A</addressOffset>
                    <size>8</size>
                    <access>read-write</access>
                    <resetValue>0x00</resetValue>
                    <resetMask>0xff</resetMask>
                    <fields>
                        <field>
                            <name>ADNDIS</name>
                            <description>Disconnection Detection Assist Setting</description>
                            <lsb>0</lsb>
                            <msb>3</msb>
                            <access>read-write</access>
                            <enumeratedValues>
                                </enumeratedValues>
                        </field>
                        <field>
                            <name>PCHG</name>
                            <description>Precharge/discharge select</description>
                            <lsb>4</lsb>
                            <msb>4</msb>
                            <access>read-write</access>
                            <enumeratedValues>
                                </enumeratedValues>
                        </field>
                    </fields>
                </register>
                <register>
                    <name>ADGSPCR</name>
                    <description>A/D Group Scan Priority Control Register</description>
                    <addressOffset>0x080</addressOffset>
                    <size>16</size>
                    <access>read-write</access>
                    <resetValue>0x0000</resetValue>
                    <resetMask>0xffff</resetMask>
                    <fields>
                        <field>
                            <name>PGS</name>
                            <description>Group Priority Operation Setting</description>
                            <lsb>0</lsb>
                            <msb>0</msb>
                            <access>read-write</access>
                            <enumeratedValues>
                                </enumeratedValues>
                        </field>
                        <field>
                            <name>GBRSCN</name>
                            <description>Lower,Priority Group Restart Setting</description>
                            <lsb>1</lsb>
                            <msb>1</msb>
                            <access>read-write</access>
                            <enumeratedValues>
                                </enumeratedValues>
                        </field>
                        <field>
                            <name>LGRRS</name>
                            <description>Enabled only when PGS = 1 and GBRSCN = 1.</description>
                            <lsb>14</lsb>
                            <msb>14</msb>
                            <access>read-write</access>
                            <enumeratedValues>
                                </enumeratedValues>
                        </field>
                        <field>
                            <name>GBRP</name>
                            <description>Single Scan Continuous Start</description>
                            <lsb>15</lsb>
                            <msb>15</msb>
                            <access>read-write</access>
                            <enumeratedValues>
                                </enumeratedValues>
                        </field>
                    </fields>
                </register>
                <register>
                    <name>ADDBLDRA</name>
                    <description>A/D Data Duplexing Register A</description>
                    <addressOffset>0x084</addressOffset>
                    <size>16</size>
                    <access>read-only</access>
                    <resetValue>0x0000</resetValue>
                    <resetMask>0xffff</resetMask>
                    <fields>
                        <field>
                            <name>ADDBLDR</name>
                            <description>Converted Value 15 to 0</description>
                            <lsb>0</lsb>
                            <msb>15</msb>
                            <access>read-only</access>
                        </field>
                    </fields>
                </register>
                <register>
                    <name>ADDBLDRB</name>
                    <description>A/D Data Duplexing Register B</description>
                    <addressOffset>0x086</addressOffset>
                    <size>16</size>
                    <access>read-only</access>
                    <resetValue>0x0000</resetValue>
                    <resetMask>0xffff</resetMask>
                    <fields>
                        <field>
                            <name>ADDBLDR</name>
                            <description>Converted Value 15 to 0</description>
                            <lsb>0</lsb>
                            <msb>15</msb>
                            <access>read-only</access>
                        </field>
                    </fields>
                </register>
                <register>
                    <name>ADWINMON</name>
                    <description>A/D Compare Function Window A/B Status Monitor Register</description>
                    <addressOffset>0x08C</addressOffset>
                    <size>8</size>
                    <access>read-only</access>
                    <resetValue>0x00</resetValue>
                    <resetMask>0xff</resetMask>
                    <fields>
                        <field>
                            <name>MONCOMB</name>
                            <description>Combination Result Monitor</description>
                            <lsb>0</lsb>
                            <msb>0</msb>
                            <access>read-only</access>
                            <enumeratedValues>
                                </enumeratedValues>
                        </field>
                        <field>
                            <name>MONCMPA</name>
                            <description>Comparison Result Monitor A</description>
                            <lsb>4</lsb>
                            <msb>4</msb>
                            <access>read-only</access>
                            <enumeratedValues>
                                </enumeratedValues>
                        </field>
                        <field>
                            <name>MONCMPB</name>
                            <description>Comparison Result Monitor B</description>
                            <lsb>5</lsb>
                            <msb>5</msb>
                            <access>read-only</access>
                            <enumeratedValues>
                                </enumeratedValues>
                        </field>
                    </fields>
                </register>
                <register>
                    <name>ADCMPCR</name>
                    <description>A/D Compare Function Control Register</description>
                    <addressOffset>0x090</addressOffset>
                    <size>16</size>
                    <access>read-write</access>
                    <resetValue>0x0000</resetValue>
                    <resetMask>0xffff</resetMask>
                    <fields>
                        <field>
                            <name>CMPAB</name>
                            <description>Window A/B Composite Conditions Setting</description>
                            <lsb>0</lsb>
                            <msb>1</msb>
                            <access>read-write</access>
                            <enumeratedValues>
                                </enumeratedValues>
                        </field>
                        <field>
                            <name>CMPBE</name>
                            <description>Compare Window B Operation Enable</description>
                            <lsb>9</lsb>
                            <msb>9</msb>
                            <access>read-write</access>
                            <enumeratedValues>
                                </enumeratedValues>
                        </field>
                        <field>
                            <name>CMPAE</name>
                            <description>Compare Window A Operation Enable</description>
                            <lsb>11</lsb>
                            <msb>11</msb>
                            <access>read-write</access>
                            <enumeratedValues>
                                </enumeratedValues>
                        </field>
                        <field>
                            <name>CMPBIE</name>
                            <description>Compare B Interrupt Enable</description>
                            <lsb>13</lsb>
                            <msb>13</msb>
                            <access>read-write</access>
                            <enumeratedValues>
                                </enumeratedValues>
                        </field>
                        <field>
                            <name>WCMPE</name>
                            <description>Window Function Setting</description>
                            <lsb>14</lsb>
                            <msb>14</msb>
                            <access>read-write</access>
                            <enumeratedValues>
                                </enumeratedValues>
                        </field>
                        <field>
                            <name>CMPAIE</name>
                            <description>Compare A Interrupt Enable</description>
                            <lsb>15</lsb>
                            <msb>15</msb>
                            <access>read-write</access>
                            <enumeratedValues>
                                </enumeratedValues>
                        </field>
                    </fields>
                </register>
                <register>
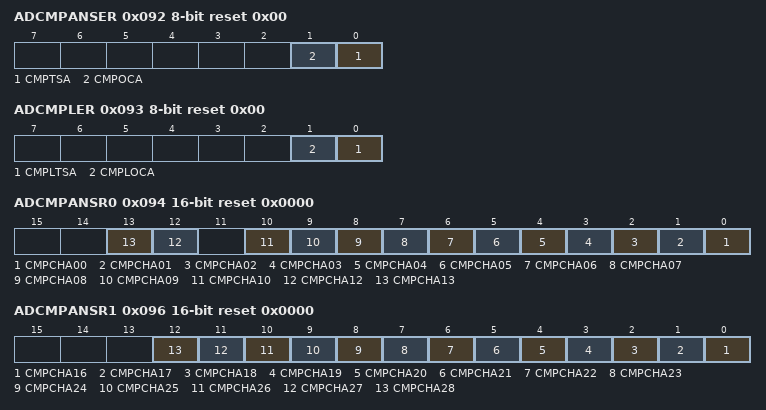
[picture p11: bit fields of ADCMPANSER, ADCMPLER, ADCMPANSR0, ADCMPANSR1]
                    <name>ADCMPANSER</name>
                    <description>A/D Compare Function Window A Extended Input Select Register</description>
                    <addressOffset>0x092</addressOffset>
                    <size>8</size>
                    <access>read-write</access>
                    <resetValue>0x00</resetValue>
                    <resetMask>0xff</resetMask>
                    <fields>
                        <field>
                            <name>CMPTSA</name>
                            <description>Temperature Sensor Output Compare Select</description>
                            <lsb>0</lsb>
                            <msb>0</msb>
                            <access>read-write</access>
                            <enumeratedValues>
                                </enumeratedValues>
                        </field>
                        <field>
                            <name>CMPOCA</name>
                            <description>Internal Reference Voltage Compare Select</description>
                            <lsb>1</lsb>
                            <msb>1</msb>
                            <access>read-write</access>
                            <enumeratedValues>
                                </enumeratedValues>
                        </field>
                    </fields>
                </register>
                <register>
                    <name>ADCMPLER</name>
                    <description>A/D Compare Function Window A Extended Input Comparison Condition Setting Register</description>
                    <addressOffset>0x093</addressOffset>
                    <size>8</size>
                    <access>read-write</access>
                    <resetValue>0x00</resetValue>
                    <resetMask>0xff</resetMask>
                    <fields>
                        <field>
                            <name>CMPLTSA</name>
                            <description>Compare Window A Temperature Sensor Output Comparison Condition Select</description>
                            <lsb>0</lsb>
                            <msb>0</msb>
                            <access>read-write</access>
                            <enumeratedValues>
                                </enumeratedValues>
                        </field>
                        <field>
                            <name>CMPLOCA</name>
                            <description>Compare Window A Internal Reference Voltage Comparison Condition Select</description>
                            <lsb>1</lsb>
                            <msb>1</msb>
                            <access>read-write</access>
                            <enumeratedValues>
                                </enumeratedValues>
                        </field>
                    </fields>
                </register>
                <register>
                    <name>ADCMPANSR0</name>
                    <description>A/D Compare Function Window A Channel Select Register 0</description>
                    <addressOffset>0x094</addressOffset>
                    <size>16</size>
                    <access>read-write</access>
                    <resetValue>0x0000</resetValue>
                    <resetMask>0xffff</resetMask>
                    <fields>
                        <field>
                            <name>CMPCHA00</name>
                            <description>Compare Window A Channel Select</description>
                            <lsb>0</lsb>
                            <msb>0</msb>
                            <access>read-write</access>
                            <enumeratedValues>
                                </enumeratedValues>
                        </field>
                        <field>
                            <name>CMPCHA01</name>
                            <description>Compare Window A Channel Select</description>
                            <lsb>1</lsb>
                            <msb>1</msb>
                            <access>read-write</access>
                            <enumeratedValues>
                                </enumeratedValues>
                        </field>
                        <field>
                            <name>CMPCHA02</name>
                            <description>Compare Window A Channel Select</description>
                            <lsb>2</lsb>
                            <msb>2</msb>
                            <access>read-write</access>
                            <enumeratedValues>
                                </enumeratedValues>
                        </field>
                        <field>
                            <name>CMPCHA03</name>
                            <description>Compare Window A Channel Select</description>
                            <lsb>3</lsb>
                            <msb>3</msb>
                            <access>read-write</access>
                            <enumeratedValues>
                                </enumeratedValues>
                        </field>
                        <field>
                            <name>CMPCHA04</name>
                            <description>Compare Window A Channel Select</description>
                            <lsb>4</lsb>
                            <msb>4</msb>
                            <access>read-write</access>
                            <enumeratedValues>
                                </enumeratedValues>
                        </field>
                        <field>
                            <name>CMPCHA05</name>
                            <description>Compare Window A Channel Select</description>
                            <lsb>5</lsb>
                            <msb>5</msb>
                            <access>read-write</access>
                            <enumeratedValues>
                                </enumeratedValues>
                        </field>
                        <field>
                            <name>CMPCHA06</name>
                            <description>Compare Window A Channel Select</description>
                            <lsb>6</lsb>
                            <msb>6</msb>
                            <access>read-write</access>
                            <enumeratedValues>
                                </enumeratedValues>
                        </field>
                        <field>
                            <name>CMPCHA07</name>
                            <description>Compare Window A Channel Select</description>
                            <lsb>7</lsb>
                            <msb>7</msb>
                            <access>read-write</access>
                            <enumeratedValues>
                                </enumeratedValues>
                        </field>
                        <field>
                            <name>CMPCHA08</name>
                            <description>Compare Window A Channel Select</description>
                            <lsb>8</lsb>
                            <msb>8</msb>
                            <access>read-write</access>
                            <enumeratedValues>
                                </enumeratedValues>
                        </field>
                        <field>
                            <name>CMPCHA09</name>
                            <description>Compare Window A Channel Select</description>
                            <lsb>9</lsb>
                            <msb>9</msb>
                            <access>read-write</access>
                            <enumeratedValues>
                                </enumeratedValues>
                        </field>
                        <field>
                            <name>CMPCHA10</name>
                            <description>Compare Window A Channel Select</description>
                            <lsb>10</lsb>
                            <msb>10</msb>
                            <access>read-write</access>
                            <enumeratedValues>
                                </enumeratedValues>
                        </field>
                        <field>
                            <name>CMPCHA12</name>
                            <description>Compare Window A Channel Select</description>
                            <lsb>12</lsb>
                            <msb>12</msb>
                            <access>read-write</access>
                            <enumeratedValues>
                                </enumeratedValues>
                        </field>
                        <field>
                            <name>CMPCHA13</name>
                            <description>Compare Window A Channel Select</description>
                            <lsb>13</lsb>
                            <msb>13</msb>
                            <access>read-write</access>
                            <enumeratedValues>
                                </enumeratedValues>
                        </field>
                    </fields>
                </register>
                <register>
                    <name>ADCMPANSR1</name>
                    <description>A/D Compare Function Window A Channel Select Register 1</description>
                    <addressOffset>0x096</addressOffset>
                    <size>16</size>
                    <access>read-write</access>
                    <resetValue>0x0000</resetValue>
                    <resetMask>0xffff</resetMask>
                    <fields>
                        <field>
                            <name>CMPCHA16</name>
                            <description>Compare Window A Channel Select</description>
                            <lsb>0</lsb>
                            <msb>0</msb>
                            <access>read-write</access>
                            <enumeratedValues>
                                </enumeratedValues>
                        </field>
                        <field>
                            <name>CMPCHA17</name>
                            <description>Compare Window A Channel Select</description>
                            <lsb>1</lsb>
                            <msb>1</msb>
                            <access>read-write</access>
                            <enumeratedValues>
                                </enumeratedValues>
                        </field>
                        <field>
                            <name>CMPCHA18</name>
                            <description>Compare Window A Channel Select</description>
                            <lsb>2</lsb>
                            <msb>2</msb>
                            <access>read-write</access>
                            <enumeratedValues>
                                </enumeratedValues>
                        </field>
                        <field>
                            <name>CMPCHA19</name>
                            <description>Compare Window A Channel Select</description>
                            <lsb>3</lsb>
                            <msb>3</msb>
                            <access>read-write</access>
                            <enumeratedValues>
                                </enumeratedValues>
                        </field>
                        <field>
                            <name>CMPCHA20</name>
                            <description>Compare Window A Channel Select</description>
                            <lsb>4</lsb>
                            <msb>4</msb>
                            <access>read-write</access>
                            <enumeratedValues>
                                </enumeratedValues>
                        </field>
                        <field>
                            <name>CMPCHA21</name>
                            <description>Compare Window A Channel Select</description>
                            <lsb>5</lsb>
                            <msb>5</msb>
                            <access>read-write</access>
                            <enumeratedValues>
                                </enumeratedValues>
                        </field>
                        <field>
                            <name>CMPCHA22</name>
                            <description>Compare Window A Channel Select</description>
                            <lsb>6</lsb>
                            <msb>6</msb>
                            <access>read-write</access>
                            <enumeratedValues>
                                </enumeratedValues>
                        </field>
                        <field>
                            <name>CMPCHA23</name>
                            <description>Compare Window A Channel Select</description>
                            <lsb>7</lsb>
                            <msb>7</msb>
                            <access>read-write</access>
                            <enumeratedValues>
                                </enumeratedValues>
                        </field>
                        <field>
                            <name>CMPCHA24</name>
                            <description>Compare Window A Channel Select</description>
                            <lsb>8</lsb>
                            <msb>8</msb>
                            <access>read-write</access>
                            <enumeratedValues>
                                </enumeratedValues>
                        </field>
                        <field>
                            <name>CMPCHA25</name>
                            <description>Compare Window A Channel Select</description>
                            <lsb>9</lsb>
                            <msb>9</msb>
                            <access>read-write</access>
                            <enumeratedValues>
                                </enumeratedValues>
                        </field>
                        <field>
                            <name>CMPCHA26</name>
                            <description>Compare Window A Channel Select</description>
                            <lsb>10</lsb>
                            <msb>10</msb>
                            <access>read-write</access>
                            <enumeratedValues>
                                </enumeratedValues>
                        </field>
                        <field>
                            <name>CMPCHA27</name>
                            <description>Compare Window A Channel Select</description>
                            <lsb>11</lsb>
                            <msb>11</msb>
                            <access>read-write</access>
                            <enumeratedValues>
                                </enumeratedValues>
                        </field>
                        <field>
                            <name>CMPCHA28</name>
                            <description>Compare Window A Channel Select</description>
                            <lsb>12</lsb>
                            <msb>12</msb>
                            <access>read-write</access>
                            <enumeratedValues>
                                </enumeratedValues>
                        </field>
                    </fields>
                </register>
                <register>
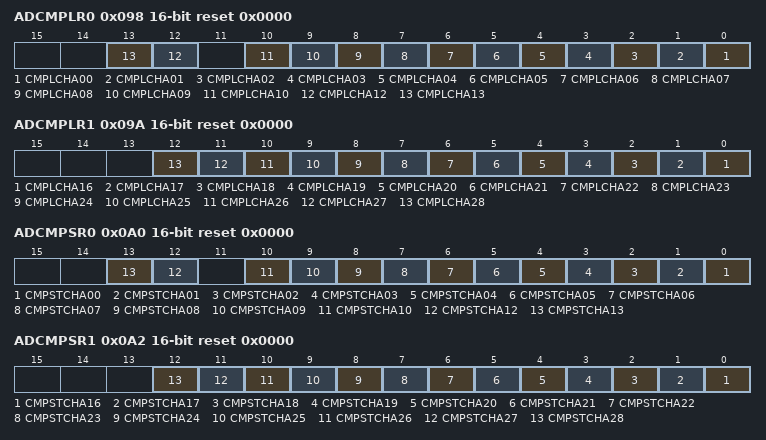
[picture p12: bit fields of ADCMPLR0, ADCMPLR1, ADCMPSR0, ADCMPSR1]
                    <name>ADCMPLR0</name>
                    <description>A/D Compare Function Window A Comparison Condition Setting Register 0</description>
                    <addressOffset>0x098</addressOffset>
                    <size>16</size>
                    <access>read-write</access>
                    <resetValue>0x0000</resetValue>
                    <resetMask>0xffff</resetMask>
                    <fields>
                        <field>
                            <name>CMPLCHA00</name>
                            <description>Compare Window A Comparison Condition Select</description>
                            <lsb>0</lsb>
                            <msb>0</msb>
                            <access>read-write</access>
                            <enumeratedValues>
                                </enumeratedValues>
                        </field>
                        <field>
                            <name>CMPLCHA01</name>
                            <description>Compare Window A Comparison Condition Select</description>
                            <lsb>1</lsb>
                            <msb>1</msb>
                            <access>read-write</access>
                            <enumeratedValues>
                                </enumeratedValues>
                        </field>
                        <field>
                            <name>CMPLCHA02</name>
                            <description>Compare Window A Comparison Condition Select</description>
                            <lsb>2</lsb>
                            <msb>2</msb>
                            <access>read-write</access>
                            <enumeratedValues>
                                </enumeratedValues>
                        </field>
                        <field>
                            <name>CMPLCHA03</name>
                            <description>Compare Window A Comparison Condition Select</description>
                            <lsb>3</lsb>
                            <msb>3</msb>
                            <access>read-write</access>
                            <enumeratedValues>
                                </enumeratedValues>
                        </field>
                        <field>
                            <name>CMPLCHA04</name>
                            <description>Compare Window A Comparison Condition Select</description>
                            <lsb>4</lsb>
                            <msb>4</msb>
                            <access>read-write</access>
                            <enumeratedValues>
                                </enumeratedValues>
                        </field>
                        <field>
                            <name>CMPLCHA05</name>
                            <description>Compare Window A Comparison Condition Select</description>
                            <lsb>5</lsb>
                            <msb>5</msb>
                            <access>read-write</access>
                            <enumeratedValues>
                                </enumeratedValues>
                        </field>
                        <field>
                            <name>CMPLCHA06</name>
                            <description>Compare Window A Comparison Condition Select</description>
                            <lsb>6</lsb>
                            <msb>6</msb>
                            <access>read-write</access>
                            <enumeratedValues>
                                </enumeratedValues>
                        </field>
                        <field>
                            <name>CMPLCHA07</name>
                            <description>Compare Window A Comparison Condition Select</description>
                            <lsb>7</lsb>
                            <msb>7</msb>
                            <access>read-write</access>
                            <enumeratedValues>
                                </enumeratedValues>
                        </field>
                        <field>
                            <name>CMPLCHA08</name>
                            <description>Compare Window A Comparison Condition Select</description>
                            <lsb>8</lsb>
                            <msb>8</msb>
                            <access>read-write</access>
                            <enumeratedValues>
                                </enumeratedValues>
                        </field>
                        <field>
                            <name>CMPLCHA09</name>
                            <description>Compare Window A Comparison Condition Select</description>
                            <lsb>9</lsb>
                            <msb>9</msb>
                            <access>read-write</access>
                            <enumeratedValues>
                                </enumeratedValues>
                        </field>
                        <field>
                            <name>CMPLCHA10</name>
                            <description>Compare Window A Comparison Condition Select</description>
                            <lsb>10</lsb>
                            <msb>10</msb>
                            <access>read-write</access>
                            <enumeratedValues>
                                </enumeratedValues>
                        </field>
                        <field>
                            <name>CMPLCHA12</name>
                            <description>Compare Window A Comparison Condition Select</description>
                            <lsb>12</lsb>
                            <msb>12</msb>
                            <access>read-write</access>
                            <enumeratedValues>
                                </enumeratedValues>
                        </field>
                        <field>
                            <name>CMPLCHA13</name>
                            <description>Compare Window A Comparison Condition Select</description>
                            <lsb>13</lsb>
                            <msb>13</msb>
                            <access>read-write</access>
                            <enumeratedValues>
                                </enumeratedValues>
                        </field>
                    </fields>
                </register>
                <register>
                    <name>ADCMPLR1</name>
                    <description>A/D Compare Function Window A Comparison Condition Setting Register 1</description>
                    <addressOffset>0x09A</addressOffset>
                    <size>16</size>
                    <access>read-write</access>
                    <resetValue>0x0000</resetValue>
                    <resetMask>0xffff</resetMask>
                    <fields>
                        <field>
                            <name>CMPLCHA16</name>
                            <description>Compare Window A Comparison Condition Select</description>
                            <lsb>0</lsb>
                            <msb>0</msb>
                            <access>read-write</access>
                            <enumeratedValues>
                                </enumeratedValues>
                        </field>
                        <field>
                            <name>CMPLCHA17</name>
                            <description>Compare Window A Comparison Condition Select</description>
                            <lsb>1</lsb>
                            <msb>1</msb>
                            <access>read-write</access>
                            <enumeratedValues>
                                </enumeratedValues>
                        </field>
                        <field>
                            <name>CMPLCHA18</name>
                            <description>Compare Window A Comparison Condition Select</description>
                            <lsb>2</lsb>
                            <msb>2</msb>
                            <access>read-write</access>
                            <enumeratedValues>
                                </enumeratedValues>
                        </field>
                        <field>
                            <name>CMPLCHA19</name>
                            <description>Compare Window A Comparison Condition Select</description>
                            <lsb>3</lsb>
                            <msb>3</msb>
                            <access>read-write</access>
                            <enumeratedValues>
                                </enumeratedValues>
                        </field>
                        <field>
                            <name>CMPLCHA20</name>
                            <description>Compare Window A Comparison Condition Select</description>
                            <lsb>4</lsb>
                            <msb>4</msb>
                            <access>read-write</access>
                            <enumeratedValues>
                                </enumeratedValues>
                        </field>
                        <field>
                            <name>CMPLCHA21</name>
                            <description>Compare Window A Comparison Condition Select</description>
                            <lsb>5</lsb>
                            <msb>5</msb>
                            <access>read-write</access>
                            <enumeratedValues>
                                </enumeratedValues>
                        </field>
                        <field>
                            <name>CMPLCHA22</name>
                            <description>Compare Window A Comparison Condition Select</description>
                            <lsb>6</lsb>
                            <msb>6</msb>
                            <access>read-write</access>
                            <enumeratedValues>
                                </enumeratedValues>
                        </field>
                        <field>
                            <name>CMPLCHA23</name>
                            <description>Compare Window A Comparison Condition Select</description>
                            <lsb>7</lsb>
                            <msb>7</msb>
                            <access>read-write</access>
                            <enumeratedValues>
                                </enumeratedValues>
                        </field>
                        <field>
                            <name>CMPLCHA24</name>
                            <description>Compare Window A Comparison Condition Select</description>
                            <lsb>8</lsb>
                            <msb>8</msb>
                            <access>read-write</access>
                            <enumeratedValues>
                                </enumeratedValues>
                        </field>
                        <field>
                            <name>CMPLCHA25</name>
                            <description>Compare Window A Comparison Condition Select</description>
                            <lsb>9</lsb>
                            <msb>9</msb>
                            <access>read-write</access>
                            <enumeratedValues>
                                </enumeratedValues>
                        </field>
                        <field>
                            <name>CMPLCHA26</name>
                            <description>Compare Window A Comparison Condition Select</description>
                            <lsb>10</lsb>
                            <msb>10</msb>
                            <access>read-write</access>
                            <enumeratedValues>
                                </enumeratedValues>
                        </field>
                        <field>
                            <name>CMPLCHA27</name>
                            <description>Compare Window A Comparison Condition Select</description>
                            <lsb>11</lsb>
                            <msb>11</msb>
                            <access>read-write</access>
                            <enumeratedValues>
                                </enumeratedValues>
                        </field>
                        <field>
                            <name>CMPLCHA28</name>
                            <description>Compare Window A Comparison Condition Select</description>
                            <lsb>12</lsb>
                            <msb>12</msb>
                            <access>read-write</access>
                            <enumeratedValues>
                                </enumeratedValues>
                        </field>
                    </fields>
                </register>
                <register>
                    <dim>2</dim>
                    <dimIncrement>0x2</dimIncrement>
                    <dimIndex>0-1</dimIndex>
                    <name>ADCMPDR%s</name>
                    <description>A/D Compare Function Window A Lower,Side/Upper,Side Level Setting Register</description>
                    <addressOffset>0x09C</addressOffset>
                    <size>16</size>
                    <access>read-write</access>
                    <resetValue>0x0000</resetValue>
                    <resetMask>0xffff</resetMask>
                </register>
                <register>
                    <name>ADCMPSR0</name>
                    <description>A/D Compare Function Window A Channel Status Register 0</description>
                    <addressOffset>0x0A0</addressOffset>
                    <size>16</size>
                    <access>read-write</access>
                    <resetValue>0x0000</resetValue>
                    <resetMask>0xffff</resetMask>
                    <fields>
                        <field>
                            <name>CMPSTCHA00</name>
                            <description>Compare Window A Flag</description>
                            <lsb>0</lsb>
                            <msb>0</msb>
                            <access>read-write</access>
                            <enumeratedValues>
                                </enumeratedValues>
                        </field>
                        <field>
                            <name>CMPSTCHA01</name>
                            <description>Compare Window A Flag</description>
                            <lsb>1</lsb>
                            <msb>1</msb>
                            <access>read-write</access>
                            <enumeratedValues>
                                </enumeratedValues>
                        </field>
                        <field>
                            <name>CMPSTCHA02</name>
                            <description>Compare Window A Flag</description>
                            <lsb>2</lsb>
                            <msb>2</msb>
                            <access>read-write</access>
                            <enumeratedValues>
                                </enumeratedValues>
                        </field>
                        <field>
                            <name>CMPSTCHA03</name>
                            <description>Compare Window A Flag</description>
                            <lsb>3</lsb>
                            <msb>3</msb>
                            <access>read-write</access>
                            <enumeratedValues>
                                </enumeratedValues>
                        </field>
                        <field>
                            <name>CMPSTCHA04</name>
                            <description>Compare Window A Flag</description>
                            <lsb>4</lsb>
                            <msb>4</msb>
                            <access>read-write</access>
                            <enumeratedValues>
                                </enumeratedValues>
                        </field>
                        <field>
                            <name>CMPSTCHA05</name>
                            <description>Compare Window A Flag</description>
                            <lsb>5</lsb>
                            <msb>5</msb>
                            <access>read-write</access>
                            <enumeratedValues>
                                </enumeratedValues>
                        </field>
                        <field>
                            <name>CMPSTCHA06</name>
                            <description>Compare Window A Flag</description>
                            <lsb>6</lsb>
                            <msb>6</msb>
                            <access>read-write</access>
                            <enumeratedValues>
                                </enumeratedValues>
                        </field>
                        <field>
                            <name>CMPSTCHA07</name>
                            <description>Compare Window A Flag</description>
                            <lsb>7</lsb>
                            <msb>7</msb>
                            <access>read-write</access>
                            <enumeratedValues>
                                </enumeratedValues>
                        </field>
                        <field>
                            <name>CMPSTCHA08</name>
                            <description>Compare Window A Flag</description>
                            <lsb>8</lsb>
                            <msb>8</msb>
                            <access>read-write</access>
                            <enumeratedValues>
                                </enumeratedValues>
                        </field>
                        <field>
                            <name>CMPSTCHA09</name>
                            <description>Compare Window A Flag</description>
                            <lsb>9</lsb>
                            <msb>9</msb>
                            <access>read-write</access>
                            <enumeratedValues>
                                </enumeratedValues>
                        </field>
                        <field>
                            <name>CMPSTCHA10</name>
                            <description>Compare Window A Flag</description>
                            <lsb>10</lsb>
                            <msb>10</msb>
                            <access>read-write</access>
                            <enumeratedValues>
                                </enumeratedValues>
                        </field>
                        <field>
                            <name>CMPSTCHA12</name>
                            <description>Compare Window A Flag</description>
                            <lsb>12</lsb>
                            <msb>12</msb>
                            <access>read-write</access>
                            <enumeratedValues>
                                </enumeratedValues>
                        </field>
                        <field>
                            <name>CMPSTCHA13</name>
                            <description>Compare Window A Flag</description>
                            <lsb>13</lsb>
                            <msb>13</msb>
                            <access>read-write</access>
                            <enumeratedValues>
                                </enumeratedValues>
                        </field>
                    </fields>
                </register>
                <register>
                    <name>ADCMPSR1</name>
                    <description>A/D Compare Function Window A Channel Status Register1</description>
                    <addressOffset>0x0A2</addressOffset>
                    <size>16</size>
                    <access>read-write</access>
                    <resetValue>0x0000</resetValue>
                    <resetMask>0xffff</resetMask>
                    <fields>
                        <field>
                            <name>CMPSTCHA16</name>
                            <description>Compare Window A Flag</description>
                            <lsb>0</lsb>
                            <msb>0</msb>
                            <access>read-write</access>
                            <enumeratedValues>
                                </enumeratedValues>
                        </field>
                        <field>
                            <name>CMPSTCHA17</name>
                            <description>Compare Window A Flag</description>
                            <lsb>1</lsb>
                            <msb>1</msb>
                            <access>read-write</access>
                            <enumeratedValues>
                                </enumeratedValues>
                        </field>
                        <field>
                            <name>CMPSTCHA18</name>
                            <description>Compare Window A Flag</description>
                            <lsb>2</lsb>
                            <msb>2</msb>
                            <access>read-write</access>
                            <enumeratedValues>
                                </enumeratedValues>
                        </field>
                        <field>
                            <name>CMPSTCHA19</name>
                            <description>Compare Window A Flag</description>
                            <lsb>3</lsb>
                            <msb>3</msb>
                            <access>read-write</access>
                            <enumeratedValues>
                                </enumeratedValues>
                        </field>
                        <field>
                            <name>CMPSTCHA20</name>
                            <description>Compare Window A Flag</description>
                            <lsb>4</lsb>
                            <msb>4</msb>
                            <access>read-write</access>
                            <enumeratedValues>
                                </enumeratedValues>
                        </field>
                        <field>
                            <name>CMPSTCHA21</name>
                            <description>Compare Window A Flag</description>
                            <lsb>5</lsb>
                            <msb>5</msb>
                            <access>read-write</access>
                            <enumeratedValues>
                                </enumeratedValues>
                        </field>
                        <field>
                            <name>CMPSTCHA22</name>
                            <description>Compare Window A Flag</description>
                            <lsb>6</lsb>
                            <msb>6</msb>
                            <access>read-write</access>
                            <enumeratedValues>
                                </enumeratedValues>
                        </field>
                        <field>
                            <name>CMPSTCHA23</name>
                            <description>Compare Window A Flag</description>
                            <lsb>7</lsb>
                            <msb>7</msb>
                            <access>read-write</access>
                            <enumeratedValues>
                                </enumeratedValues>
                        </field>
                        <field>
                            <name>CMPSTCHA24</name>
                            <description>Compare Window A Flag</description>
                            <lsb>8</lsb>
                            <msb>8</msb>
                            <access>read-write</access>
                            <enumeratedValues>
                                </enumeratedValues>
                        </field>
                        <field>
                            <name>CMPSTCHA25</name>
                            <description>Compare Window A Flag</description>
                            <lsb>9</lsb>
                            <msb>9</msb>
                            <access>read-write</access>
                            <enumeratedValues>
                                </enumeratedValues>
                        </field>
                        <field>
                            <name>CMPSTCHA26</name>
                            <description>Compare Window A Flag</description>
                            <lsb>10</lsb>
                            <msb>10</msb>
                            <access>read-write</access>
                            <enumeratedValues>
                                </enumeratedValues>
                        </field>
                        <field>
                            <name>CMPSTCHA27</name>
                            <description>Compare Window A Flag</description>
                            <lsb>11</lsb>
                            <msb>11</msb>
                            <access>read-write</access>
                            <enumeratedValues>
                                </enumeratedValues>
                        </field>
                        <field>
                            <name>CMPSTCHA28</name>
                            <description>Compare Window A Flag</description>
                            <lsb>12</lsb>
                            <msb>12</msb>
                            <access>read-write</access>
                            <enumeratedValues>
                                </enumeratedValues>
                        </field>
                    </fields>
                </register>
                <register>
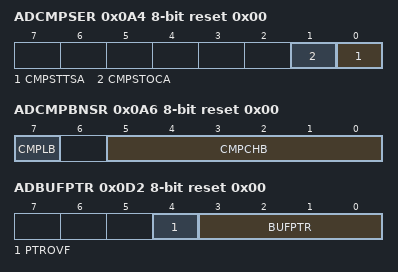
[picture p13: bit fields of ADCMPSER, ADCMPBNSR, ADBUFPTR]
                    <name>ADCMPSER</name>
                    <description>A/D Compare Function Window A Extended Input Channel Status Register</description>
                    <addressOffset>0x0A4</addressOffset>
                    <size>8</size>
                    <access>read-write</access>
                    <resetValue>0x00</resetValue>
                    <resetMask>0xff</resetMask>
                    <fields>
                        <field>
                            <name>CMPSTTSA</name>
                            <description>Compare Window A Temperature Sensor Output Compare Flag</description>
                            <lsb>0</lsb>
                            <msb>0</msb>
                            <access>read-write</access>
                            <enumeratedValues>
                                </enumeratedValues>
                        </field>
                        <field>
                            <name>CMPSTOCA</name>
                            <description>Compare Window A Internal Reference Voltage Compare Flag</description>
                            <lsb>1</lsb>
                            <msb>1</msb>
                            <access>read-write</access>
                            <enumeratedValues>
                                </enumeratedValues>
                        </field>
                    </fields>
                </register>
                <register>
                    <name>ADCMPBNSR</name>
                    <description>A/D Compare Function Window B Channel Select Register</description>
                    <addressOffset>0x0A6</addressOffset>
                    <size>8</size>
                    <access>read-write</access>
                    <resetValue>0x00</resetValue>
                    <resetMask>0xff</resetMask>
                    <fields>
                        <field>
                            <name>CMPCHB</name>
                            <description>Compare Window B Channel Select</description>
                            <lsb>0</lsb>
                            <msb>5</msb>
                            <access>read-write</access>
                        </field>
                        <field>
                            <name>CMPLB</name>
                            <description>Compare Window B Comparison Condition Setting</description>
                            <lsb>7</lsb>
                            <msb>7</msb>
                            <access>read-write</access>
                            <enumeratedValues>
                                </enumeratedValues>
                        </field>
                    </fields>
                </register>
                <register>
                    <name>ADWINLLB</name>
                    <description>A/D Compare Function Window B Lower,Side/Upper,Side Level Setting Register</description>
                    <addressOffset>0x0A8</addressOffset>
                    <size>16</size>
                    <access>read-write</access>
                    <resetValue>0x0000</resetValue>
                    <resetMask>0xffff</resetMask>
                </register>
                <register>
                    <name>ADWINULB</name>
                    <description>A/D Compare Function Window B Lower,Side/Upper,Side Level Setting Register</description>
                    <addressOffset>0x0AA</addressOffset>
                    <size>16</size>
                    <access>read-write</access>
                    <resetValue>0x0000</resetValue>
                    <resetMask>0xffff</resetMask>
                </register>
                <register>
                    <name>ADCMPBSR</name>
                    <description>A/D Compare Function Window B Status Register</description>
                    <addressOffset>0x0AC</addressOffset>
                    <size>8</size>
                    <access>read-write</access>
                    <resetValue>0x00</resetValue>
                    <resetMask>0xff</resetMask>
                    <fields>
                        <field>
                            <name>CMPSTB</name>
                            <description>Compare Window B Flag</description>
                            <lsb>0</lsb>
                            <msb>0</msb>
                            <access>read-write</access>
                            <enumeratedValues>
                                </enumeratedValues>
                        </field>
                    </fields>
                </register>
                <register>
                    <dim>16</dim>
                    <dimIncrement>0x2</dimIncrement>
                    <dimIndex>0-15</dimIndex>
                    <name>ADBUF%s</name>
                    <description>A/D Data Buffer Registers %s</description>
                    <addressOffset>0x0B0</addressOffset>
                    <size>16</size>
                    <access>read-only</access>
                    <resetValue>0x0000</resetValue>
                    <resetMask>0xffff</resetMask>
                    <fields>
                        <field>
                            <name>ADBUF</name>
                            <description>Converted Value 15 to 0</description>
                            <lsb>0</lsb>
                            <msb>15</msb>
                            <access>read-only</access>
                        </field>
                    </fields>
                </register>
                <register>
                    <name>ADBUFEN</name>
                    <description>A/D Data Buffer Enable Register</description>
                    <addressOffset>0x0D0</addressOffset>
                    <size>8</size>
                    <access>read-write</access>
                    <resetValue>0x00</resetValue>
                    <resetMask>0xff</resetMask>
                    <fields>
                        <field>
                            <name>BUFEN</name>
                            <description>Data Buffer Enable</description>
                            <lsb>0</lsb>
                            <msb>0</msb>
                            <access>read-write</access>
                            <enumeratedValues>
                                </enumeratedValues>
                        </field>
                    </fields>
                </register>
                <register>
                    <name>ADBUFPTR</name>
                    <description>A/D Data Buffer Pointer Register</description>
                    <addressOffset>0x0D2</addressOffset>
                    <size>8</size>
                    <access>read-write</access>
                    <resetValue>0x00</resetValue>
                    <resetMask>0xff</resetMask>
                    <fields>
                        <field>
                            <name>BUFPTR</name>
                            <description>Data Buffer Pointer</description>
                            <lsb>0</lsb>
                            <msb>3</msb>
                            <access>read-write</access>
                        </field>
                        <field>
                            <name>PTROVF</name>
                            <description>Pointer Overflow Flag</description>
                            <lsb>4</lsb>
                            <msb>4</msb>
                            <access>read-write</access>
                            <enumeratedValues>
                                </enumeratedValues>
                        </field>
                    </fields>
                </register>
                <register>
                    <name>ADSSTRL</name>
                    <description>A/D Sampling State Register</description>
                    <addressOffset>0x0DD</addressOffset>
                    <size>8</size>
                    <access>read-write</access>
                    <resetValue>0x0b</resetValue>
                    <resetMask>0xff</resetMask>
                    <fields>
                        <field>
                            <name>SST</name>
                            <description>Sampling Time Setting</description>
                            <lsb>0</lsb>
                            <msb>7</msb>
                            <access>read-write</access>
                        </field>
                    </fields>
                </register>
                <register>
                    <name>ADSSTRT</name>
                    <description>A/D Sampling State Register</description>
                    <addressOffset>0x0DE</addressOffset>
                    <size>8</size>
                    <access>read-write</access>
                    <resetValue>0x0b</resetValue>
                    <resetMask>0xff</resetMask>
                    <fields>
                        <field>
                            <name>SST</name>
                            <description>Sampling Time Setting</description>
                            <lsb>0</lsb>
                            <msb>7</msb>
                            <access>read-write</access>
                        </field>
                    </fields>
                </register>
                <register>
                    <name>ADSSTRO</name>
                    <description>A/D Sampling State Register</description>
                    <addressOffset>0x0DF</addressOffset>
                    <size>8</size>
                    <access>read-write</access>
                    <resetValue>0x0b</resetValue>
                    <resetMask>0xff</resetMask>
                    <fields>
                        <field>
                            <name>SST</name>
                            <description>Sampling Time Setting</description>
                            <lsb>0</lsb>
                            <msb>7</msb>
                            <access>read-write</access>
                        </field>
                    </fields>
                </register>
                <register>
                    <dim>3</dim>
                    <dimIncrement>0x1</dimIncrement>
                    <dimIndex>0-2</dimIndex>
                    <name>ADSSTR%s</name>
                    <description>A/D Sampling State Register</description>
                    <addressOffset>0x0E0</addressOffset>
                    <size>8</size>
                    <access>read-write</access>
                    <resetValue>0x0b</resetValue>
                    <resetMask>0xff</resetMask>
                    <fields>
                        <field>
                            <name>SST</name>
                            <description>Sampling Time Setting</description>
                            <lsb>0</lsb>
                            <msb>7</msb>
                            <access>read-write</access>
                        </field>
                    </fields>
                </register>
            </registers>
        </peripheral>
        <peripheral>
            <name>DAC12</name>
            <description>12-bit D/A converter</description>
            <baseAddress>0x40171000</baseAddress>
            <addressBlock>
                <offset>0x00</offset>
                <size>7</size>
                <usage>registers</usage>
            </addressBlock>
            <addressBlock>
                <offset>0x08</offset>
                <size>1</size>
                <usage>registers</usage>
            </addressBlock>
            <addressBlock>
                <offset>0x1C</offset>
                <size>1</size>
                <usage>registers</usage>
            </addressBlock>
            <addressBlock>
                <offset>0x10C0</offset>
                <size>1</size>
                <usage>registers</usage>
            </addressBlock>
            <registers>
                <register>
                    <dim>2</dim>
                    <dimIncrement>0x02</dimIncrement>
                    <dimIndex>0-1</dimIndex>
                    <name>DADR%s</name>
                    <description>D/A Data Register %s</description>
                    <addressOffset>0x00</addressOffset>
                    <size>16</size>
                    <access>read-write</access>
                    <resetValue>0x0000</resetValue>
                    <resetMask>0xffff</resetMask>
                </register>
                <register>
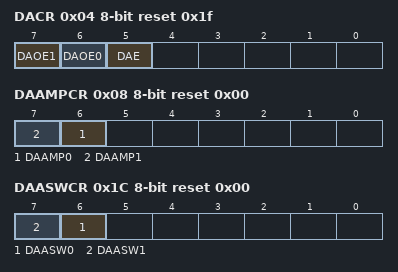
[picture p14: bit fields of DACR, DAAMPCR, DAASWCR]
                    <name>DACR</name>
                    <description>D/A Control Register</description>
                    <addressOffset>0x04</addressOffset>
                    <size>8</size>
                    <access>read-write</access>
                    <resetValue>0x1f</resetValue>
                    <resetMask>0xff</resetMask>
                    <fields>
                        <field>
                            <name>DAE</name>
                            <description>D/A Enable</description>
                            <lsb>5</lsb>
                            <msb>5</msb>
                            <access>read-write</access>
                            <enumeratedValues>
                                </enumeratedValues>
                        </field>
                        <field>
                            <name>DAOE0</name>
                            <description>D/A Output Enable 0</description>
                            <lsb>6</lsb>
                            <msb>6</msb>
                            <access>read-write</access>
                            <enumeratedValues>
                                </enumeratedValues>
                        </field>
                        <field>
                            <name>DAOE1</name>
                            <description>D/A Output Enable 1</description>
                            <lsb>7</lsb>
                            <msb>7</msb>
                            <access>read-write</access>
                            <enumeratedValues>
                                </enumeratedValues>
                        </field>
                    </fields>
                </register>
                <register>
                    <name>DADPR</name>
                    <description>DADRn Format Select Register</description>
                    <addressOffset>0x05</addressOffset>
                    <size>8</size>
                    <access>read-write</access>
                    <resetValue>0x00</resetValue>
                    <resetMask>0xff</resetMask>
                    <fields>
                        <field>
                            <name>DPSEL</name>
                            <description>DADRn Format Select</description>
                            <lsb>7</lsb>
                            <msb>7</msb>
                            <access>read-write</access>
                            <enumeratedValues>
                                </enumeratedValues>
                        </field>
                    </fields>
                </register>
                <register>
                    <name>DAADSCR</name>
                    <description>D/A A/D Synchronous Start Control Register</description>
                    <addressOffset>0x06</addressOffset>
                    <size>8</size>
                    <access>read-write</access>
                    <resetValue>0x00</resetValue>
                    <resetMask>0xff</resetMask>
                    <fields>
                        <field>
                            <name>DAADST</name>
                            <description>D/A A/D Synchronous Conversion</description>
                            <lsb>7</lsb>
                            <msb>7</msb>
                            <access>read-write</access>
                            <enumeratedValues>
                                </enumeratedValues>
                        </field>
                    </fields>
                </register>
                <register>
                    <name>DAAMPCR</name>
                    <description>D/A Output Amplifier Control Register</description>
                    <addressOffset>0x08</addressOffset>
                    <size>8</size>
                    <access>read-write</access>
                    <resetValue>0x00</resetValue>
                    <resetMask>0xff</resetMask>
                    <fields>
                        <field>
                            <name>DAAMP0</name>
                            <description>Amplifier Control 0</description>
                            <lsb>6</lsb>
                            <msb>6</msb>
                            <access>read-write</access>
                            <enumeratedValues>
                                </enumeratedValues>
                        </field>
                        <field>
                            <name>DAAMP1</name>
                            <description>Amplifier Control 1</description>
                            <lsb>7</lsb>
                            <msb>7</msb>
                            <access>read-write</access>
                            <enumeratedValues>
                                </enumeratedValues>
                        </field>
                    </fields>
                </register>
                <register>
                    <name>DAASWCR</name>
                    <description>D/A Amplifier Stabilization Wait Control Register</description>
                    <addressOffset>0x1C</addressOffset>
                    <size>8</size>
                    <access>read-write</access>
                    <resetValue>0x00</resetValue>
                    <resetMask>0xff</resetMask>
                    <fields>
                        <field>
                            <name>DAASW0</name>
                            <description>D/A Amplifier Stabilization Wait 0</description>
                            <lsb>6</lsb>
                            <msb>6</msb>
                            <access>read-write</access>
                            <enumeratedValues>
                                </enumeratedValues>
                        </field>
                        <field>
                            <name>DAASW1</name>
                            <description>D/A Amplifier Stabilization Wait 1</description>
                            <lsb>7</lsb>
                            <msb>7</msb>
                            <access>read-write</access>
                            <enumeratedValues>
                                </enumeratedValues>
                        </field>
                    </fields>
                </register>
                <register>
                    <name>DAADUSR</name>
                    <description>D/A A/D Synchronous Unit Select Register</description>
                    <addressOffset>0x10C0</addressOffset>
                    <size>8</size>
                    <access>read-write</access>
                    <resetValue>0x00</resetValue>
                    <resetMask>0xff</resetMask>
                    <fields>
                        <field>
                            <name>AMADSEL1</name>
                            <description>A/D Unit 1 Select</description>
                            <lsb>1</lsb>
                            <msb>1</msb>
                            <access>read-write</access>
                            <enumeratedValues>
                                </enumeratedValues>
                        </field>
                    </fields>
                </register>
            </registers>
        </peripheral>
        <peripheral>
            <name>TSD</name>
            <description>Temperature Sensor Calibration Data</description>
            <baseAddress>0x407FB000</baseAddress>
            <addressBlock>
                <offset>0x17C</offset>
                <size>4</size>
                <usage>registers</usage>
            </addressBlock>
            <registers>
                <register>
                    <name>TSCDR</name>
                    <description>Temperature Sensor Calibration Data Register</description>
                    <addressOffset>0x017C</addressOffset>
                    <size>32</size>
                    <access>read-only</access>
                    <resetValue>0x00000000</resetValue>
                    <resetMask>0xffff0000</resetMask>
                    <fields>
                        <field>
                            <name>TSCDR</name>
                            <description>Temperature Sensor Calibration Data</description>
                            <lsb>0</lsb>
                            <msb>15</msb>
                            <access>read-only</access>
                        </field>
                    </fields>
                </register>
            </registers>
        </peripheral>
        <peripheral>
            <name>FLAD</name>
            <description>Data Flash</description>
            <baseAddress>0x407FC000</baseAddress>
            <addressBlock>
                <offset>0x40</offset>
                <size>1</size>
                <usage>registers</usage>
            </addressBlock>
            <registers>
                <register>
                    <name>FCKMHZ</name>
                    <description>Data Flash Access Frequency Register</description>
                    <addressOffset>0x40</addressOffset>
                    <size>8</size>
                    <access>read-write</access>
                    <resetValue>0x3c</resetValue>
                    <resetMask>0xff</resetMask>
                    <fields>
                        <field>
                            <name>FCKMHZ</name>
                            <description>Data Flash Access Frequency Register</description>
                            <lsb>0</lsb>
                            <msb>7</msb>
                            <access>read-write</access>
                        </field>
                    </fields>
                </register>
            </registers>
        </peripheral>
        <peripheral>
            <name>FACI</name>
            <description>Flash/CPU Interface</description>
            <baseAddress>0x407FE000</baseAddress>
            <addressBlock>
                <offset>0x10</offset>
                <size>1</size>
                <usage>registers</usage>
            </addressBlock>
            <addressBlock>
                <offset>0x14</offset>
                <size>1</size>
                <usage>registers</usage>
            </addressBlock>
            <addressBlock>
                <offset>0x18</offset>
                <size>1</size>
                <usage>registers</usage>
            </addressBlock>
            <addressBlock>
                <offset>0x30</offset>
                <size>8</size>
                <usage>registers</usage>
            </addressBlock>
            <addressBlock>
                <offset>0x44</offset>
                <size>2</size>
                <usage>registers</usage>
            </addressBlock>
            <addressBlock>
                <offset>0x78</offset>
                <size>2</size>
                <usage>registers</usage>
            </addressBlock>
            <addressBlock>
                <offset>0x7C</offset>
                <size>2</size>
                <usage>registers</usage>
            </addressBlock>
            <addressBlock>
                <offset>0x80</offset>
                <size>6</size>
                <usage>registers</usage>
            </addressBlock>
            <addressBlock>
                <offset>0x8C</offset>
                <size>2</size>
                <usage>registers</usage>
            </addressBlock>
            <addressBlock>
                <offset>0xA0</offset>
                <size>2</size>
                <usage>registers</usage>
            </addressBlock>
            <addressBlock>
                <offset>0xD0</offset>
                <size>1</size>
                <usage>registers</usage>
            </addressBlock>
            <addressBlock>
                <offset>0xD4</offset>
                <size>1</size>
                <usage>registers</usage>
            </addressBlock>
            <addressBlock>
                <offset>0xD8</offset>
                <size>10</size>
                <usage>registers</usage>
            </addressBlock>
            <addressBlock>
                <offset>0xE4</offset>
                <size>2</size>
                <usage>registers</usage>
            </addressBlock>
            <addressBlock>
                <offset>0xE8</offset>
                <size>2</size>
                <usage>registers</usage>
            </addressBlock>
            <registers>
                <register>
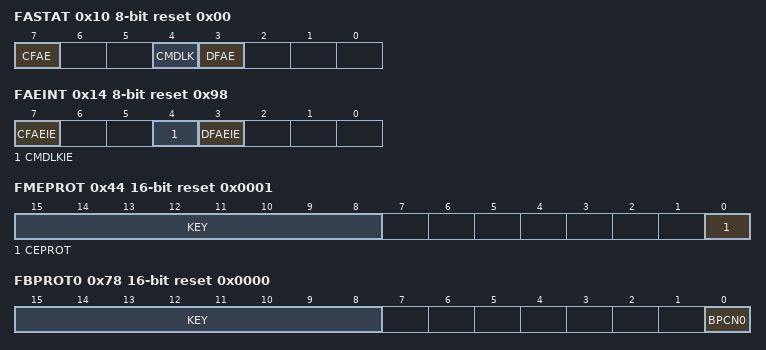
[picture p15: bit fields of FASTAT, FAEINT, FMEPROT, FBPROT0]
                    <name>FASTAT</name>
                    <description>Flash Access Status Register</description>
                    <addressOffset>0x10</addressOffset>
                    <size>8</size>
                    <access>read-write</access>
                    <resetValue>0x00</resetValue>
                    <resetMask>0xff</resetMask>
                    <fields>
                        <field>
                            <name>DFAE</name>
                            <description>Data Flash Memory Access Violation Flag</description>
                            <lsb>3</lsb>
                            <msb>3</msb>
                            <access>read-write</access>
                            <enumeratedValues>
                                </enumeratedValues>
                        </field>
                        <field>
                            <name>CMDLK</name>
                            <description>Command Lock Flag</description>
                            <lsb>4</lsb>
                            <msb>4</msb>
                            <access>read-only</access>
                            <enumeratedValues>
                                </enumeratedValues>
                        </field>
                        <field>
                            <name>CFAE</name>
                            <description>Code Flash Memory Access Violation Flag</description>
                            <lsb>7</lsb>
                            <msb>7</msb>
                            <access>read-write</access>
                            <enumeratedValues>
                                </enumeratedValues>
                        </field>
                    </fields>
                </register>
                <register>
                    <name>FAEINT</name>
                    <description>Flash Access Error Interrupt Enable Register</description>
                    <addressOffset>0x14</addressOffset>
                    <size>8</size>
                    <access>read-write</access>
                    <resetValue>0x98</resetValue>
                    <resetMask>0xff</resetMask>
                    <fields>
                        <field>
                            <name>DFAEIE</name>
                            <description>Data Flash Memory Access Violation Interrupt Enable</description>
                            <lsb>3</lsb>
                            <msb>3</msb>
                            <access>read-write</access>
                            <enumeratedValues>
                                </enumeratedValues>
                        </field>
                        <field>
                            <name>CMDLKIE</name>
                            <description>Command Lock Interrupt Enable</description>
                            <lsb>4</lsb>
                            <msb>4</msb>
                            <access>read-write</access>
                            <enumeratedValues>
                                </enumeratedValues>
                        </field>
                        <field>
                            <name>CFAEIE</name>
                            <description>Code Flash Memory Access Violation Interrupt Enable</description>
                            <lsb>7</lsb>
                            <msb>7</msb>
                            <access>read-write</access>
                            <enumeratedValues>
                                </enumeratedValues>
                        </field>
                    </fields>
                </register>
                <register>
                    <name>FRDYIE</name>
                    <description>Flash Ready Interrupt Enable Register</description>
                    <addressOffset>0x18</addressOffset>
                    <size>8</size>
                    <access>read-write</access>
                    <resetValue>0x00</resetValue>
                    <resetMask>0xff</resetMask>
                    <fields>
                        <field>
                            <name>FRDYIE</name>
                            <description>Flash Ready Interrupt Enable</description>
                            <lsb>0</lsb>
                            <msb>0</msb>
                            <access>read-write</access>
                            <enumeratedValues>
                                </enumeratedValues>
                        </field>
                    </fields>
                </register>
                <register>
                    <name>FSADDR</name>
                    <description>FACI Command Start Address Register</description>
                    <addressOffset>0x30</addressOffset>
                    <size>32</size>
                    <access>read-write</access>
                    <resetValue>0x00000000</resetValue>
                    <resetMask>0xffffffff</resetMask>
                </register>
                <register>
                    <name>FEADDR</name>
                    <description>FACI Command End Address Register</description>
                    <addressOffset>0x34</addressOffset>
                    <size>32</size>
                    <access>read-write</access>
                    <resetValue>0x00000000</resetValue>
                    <resetMask>0xffffffff</resetMask>
                    <fields>
                        <field>
                            <name>FEADDR</name>
                            <description>End Address for FACI Command Processing</description>
                            <lsb>0</lsb>
                            <msb>31</msb>
                            <access>read-write</access>
                        </field>
                    </fields>
                </register>
                <register>
                    <name>FMEPROT</name>
                    <description>Flash P/E Mode Entry Protection Register</description>
                    <addressOffset>0x44</addressOffset>
                    <size>16</size>
                    <access>read-write</access>
                    <resetValue>0x0001</resetValue>
                    <resetMask>0xffff</resetMask>
                    <fields>
                        <field>
                            <name>CEPROT</name>
                            <description>Code Flash P/E Mode Entry Protection</description>
                            <lsb>0</lsb>
                            <msb>0</msb>
                            <access>read-write</access>
                            <enumeratedValues>
                                </enumeratedValues>
                        </field>
                        <field>
                            <name>KEY</name>
                            <description>Key Code</description>
                            <lsb>8</lsb>
                            <msb>15</msb>
                            <access>write-only</access>
                        </field>
                    </fields>
                </register>
                <register>
                    <name>FBPROT0</name>
                    <description>Flash Block Protection Register</description>
                    <addressOffset>0x78</addressOffset>
                    <size>16</size>
                    <access>read-write</access>
                    <resetValue>0x0000</resetValue>
                    <resetMask>0xffff</resetMask>
                    <fields>
                        <field>
                            <name>BPCN0</name>
                            <description>Block Protection for Non,secure Cancel</description>
                            <lsb>0</lsb>
                            <msb>0</msb>
                            <access>read-write</access>
                            <enumeratedValues>
                                </enumeratedValues>
                        </field>
                        <field>
                            <name>KEY</name>
                            <description>Key Code</description>
                            <lsb>8</lsb>
                            <msb>15</msb>
                            <access>write-only</access>
                        </field>
                    </fields>
                </register>
                <register>
                    <name>FBPROT1</name>
                    <description>Flash Block Protection for Secure Register</description>
                    <addressOffset>0x7C</addressOffset>
                    <size>16</size>
                    <access>read-write</access>
                    <resetValue>0x0000</resetValue>
                    <resetMask>0xffff</resetMask>
                    <fields>
                        <field>
                            <name>BPCN1</name>
                            <description>Block Protection for Secure Cancel</description>
                            <lsb>0</lsb>
                            <msb>0</msb>
                            <access>read-write</access>
                            <enumeratedValues>
                                </enumeratedValues>
                        </field>
                        <field>
                            <name>KEY</name>
                            <description>Key Code</description>
                            <lsb>8</lsb>
                            <msb>15</msb>
                            <access>write-only</access>
                        </field>
                    </fields>
                </register>
                <register>
                    <name>FSTATR</name>
                    <description>Flash Status Register</description>
                    <addressOffset>0x80</addressOffset>
                    <size>32</size>
                    <access>read-write</access>
                    <resetValue>0x00008000</resetValue>
                    <resetMask>0xffffffff</resetMask>
                    <fields>
                        <field>
                            <name>FLWEERR</name>
                            <description>Flash Write/Erase Protect Error Flag</description>
                            <lsb>6</lsb>
                            <msb>6</msb>
                            <access>read-only</access>
                            <enumeratedValues>
                                </enumeratedValues>
                        </field>
                        <field>
                            <name>PRGSPD</name>
                            <description>Programming Suspend Status Flag</description>
                            <lsb>8</lsb>
                            <msb>8</msb>
                            <access>read-only</access>
                            <enumeratedValues>
                                </enumeratedValues>
                        </field>
                        <field>
                            <name>ERSSPD</name>
                            <description>Erasure Suspend Status Flag</description>
                            <lsb>9</lsb>
                            <msb>9</msb>
                            <access>read-only</access>
                            <enumeratedValues>
                                </enumeratedValues>
                        </field>
                        <field>
                            <name>DBFULL</name>
                            <description>Data Buffer Full Flag</description>
                            <lsb>10</lsb>
                            <msb>10</msb>
                            <access>read-only</access>
                            <enumeratedValues>
                                </enumeratedValues>
                        </field>
                        <field>
                            <name>SUSRDY</name>
                            <description>Suspend Ready Flag</description>
                            <lsb>11</lsb>
                            <msb>11</msb>
                            <access>read-only</access>
                            <enumeratedValues>
                                </enumeratedValues>
                        </field>
                        <field>
                            <name>PRGERR</name>
                            <description>Programming Error Flag</description>
                            <lsb>12</lsb>
                            <msb>12</msb>
                            <access>read-only</access>
                            <enumeratedValues>
                                </enumeratedValues>
                        </field>
                        <field>
                            <name>ERSERR</name>
                            <description>Erasure Error Flag</description>
                            <lsb>13</lsb>
                            <msb>13</msb>
                            <access>read-only</access>
                            <enumeratedValues>
                                </enumeratedValues>
                        </field>
                        <field>
                            <name>ILGLERR</name>
                            <description>Illegal Command Error Flag</description>
                            <lsb>14</lsb>
                            <msb>14</msb>
                            <access>read-only</access>
                            <enumeratedValues>
                                </enumeratedValues>
                        </field>
                        <field>
                            <name>FRDY</name>
                            <description>Flash Ready Flag</description>
                            <lsb>15</lsb>
                            <msb>15</msb>
                            <access>read-only</access>
                            <enumeratedValues>
                                </enumeratedValues>
                        </field>
                        <field>
                            <name>OTERR</name>
                            <description>Other Error</description>
                            <lsb>20</lsb>
                            <msb>20</msb>
                            <access>read-only</access>
                            <enumeratedValues>
                                </enumeratedValues>
                        </field>
                        <field>
                            <name>SECERR</name>
                            <description>Security Error</description>
                            <lsb>21</lsb>
                            <msb>21</msb>
                            <access>read-only</access>
                            <enumeratedValues>
                                </enumeratedValues>
                        </field>
                        <field>
                            <name>FESETERR</name>
                            <description>FENTRY Setting Error</description>
                            <lsb>22</lsb>
                            <msb>22</msb>
                            <access>read-only</access>
                            <enumeratedValues>
                                </enumeratedValues>
                        </field>
                        <field>
                            <name>ILGCOMERR</name>
                            <description>Illegal Command Error</description>
                            <lsb>23</lsb>
                            <msb>23</msb>
                            <access>read-only</access>
                            <enumeratedValues>
                                </enumeratedValues>
                        </field>
                    </fields>
                </register>
                <register>
                    <name>FENTRYR</name>
                    <description>Flash P/E Mode Entry Register</description>
                    <addressOffset>0x84</addressOffset>
                    <size>16</size>
                    <access>read-write</access>
                    <resetValue>0x0000</resetValue>
                    <resetMask>0xffff</resetMask>
                    <fields>
                        <field>
                            <name>FENTRYC</name>
                            <description>Code Flash P/E Mode Entry</description>
                            <lsb>0</lsb>
                            <msb>0</msb>
                            <access>read-write</access>
                            <enumeratedValues>
                                </enumeratedValues>
                        </field>
                        <field>
                            <name>FENTRYD</name>
                            <description>Data Flash P/E Mode Entry</description>
                            <lsb>7</lsb>
                            <msb>7</msb>
                            <access>read-write</access>
                            <enumeratedValues>
                                </enumeratedValues>
                        </field>
                        <field>
                            <name>KEY</name>
                            <description>Key Code</description>
                            <lsb>8</lsb>
                            <msb>15</msb>
                            <access>write-only</access>
                        </field>
                    </fields>
                </register>
                <register>
                    <name>FSUINITR</name>
                    <description>Flash Sequencer Setup Initialization Register</description>
                    <addressOffset>0x8C</addressOffset>
                    <size>16</size>
                    <access>read-write</access>
                    <resetValue>0x0000</resetValue>
                    <resetMask>0xffff</resetMask>
                    <fields>
                        <field>
                            <name>SUINIT</name>
                            <description>Set,Up Initialization</description>
                            <lsb>0</lsb>
                            <msb>0</msb>
                            <access>read-write</access>
                            <enumeratedValues>
                                </enumeratedValues>
                        </field>
                        <field>
                            <name>KEY</name>
                            <description>Key Code</description>
                            <lsb>8</lsb>
                            <msb>15</msb>
                            <access>write-only</access>
                        </field>
                    </fields>
                </register>
                <register>
                    <name>FCMDR</name>
                    <description>FACI Command Register</description>
                    <addressOffset>0xA0</addressOffset>
                    <size>16</size>
                    <access>read-only</access>
                    <resetValue>0x0000</resetValue>
                    <resetMask>0xffff</resetMask>
                    <fields>
                        <field>
                            <name>PCMDR</name>
                            <description>Pre,command Flag</description>
                            <lsb>0</lsb>
                            <msb>7</msb>
                            <access>read-only</access>
                        </field>
                        <field>
                            <name>CMDR</name>
                            <description>Command Flag</description>
                            <lsb>8</lsb>
                            <msb>15</msb>
                            <access>read-only</access>
                        </field>
                    </fields>
                </register>
                <register>
                    <name>FBCCNT</name>
                    <description>Blank Check Control Register</description>
                    <addressOffset>0xD0</addressOffset>
                    <size>8</size>
                    <access>read-write</access>
                    <resetValue>0x00</resetValue>
                    <resetMask>0xff</resetMask>
                    <fields>
                        <field>
                            <name>BCDIR</name>
                            <description>Blank Check Direction</description>
                            <lsb>0</lsb>
                            <msb>0</msb>
                            <access>read-write</access>
                            <enumeratedValues>
                                </enumeratedValues>
                        </field>
                    </fields>
                </register>
                <register>
                    <name>FBCSTAT</name>
                    <description>Blank Check Status Register</description>
                    <addressOffset>0xD4</addressOffset>
                    <size>8</size>
                    <access>read-write</access>
                    <resetValue>0x00</resetValue>
                    <resetMask>0xff</resetMask>
                    <fields>
                        <field>
                            <name>BCST</name>
                            <description>Blank Check Status Flag</description>
                            <lsb>0</lsb>
                            <msb>0</msb>
                            <access>read-only</access>
                            <enumeratedValues>
                                </enumeratedValues>
                        </field>
                    </fields>
                </register>
                <register>
                    <name>FPSADDR</name>
                    <description>Data Flash Programming Start Address Register</description>
                    <addressOffset>0xD8</addressOffset>
                    <size>32</size>
                    <access>read-write</access>
                    <resetValue>0x00000000</resetValue>
                    <resetMask>0xffffffff</resetMask>
                    <fields>
                        <field>
                            <name>PSADR</name>
                            <description>Programmed Area Start Address</description>
                            <lsb>0</lsb>
                            <msb>16</msb>
                            <access>read-only</access>
                        </field>
                    </fields>
                </register>
                <register>
                    <name>FSUASMON</name>
                    <description>Flash Startup Area Select Monitor Register</description>
                    <addressOffset>0xDC</addressOffset>
                    <size>32</size>
                    <access>read-only</access>
                    <resetValue>0x00000000</resetValue>
                    <resetMask>0x7fff7fff</resetMask>
                    <fields>
                        <field>
                            <name>FSPR</name>
                            <description>Protection Programming Flag to set Boot Flag and Startup Area Control</description>
                            <lsb>15</lsb>
                            <msb>15</msb>
                            <access>read-only</access>
                            <enumeratedValues>
                                </enumeratedValues>
                        </field>
                        <field>
                            <name>BTFLG</name>
                            <description>Flag of Startup Area Select for Boot Swap</description>
                            <lsb>31</lsb>
                            <msb>31</msb>
                            <access>read-only</access>
                            <enumeratedValues>
                                </enumeratedValues>
                        </field>
                    </fields>
                </register>
                <register>
                    <name>FCPSR</name>
                    <description>Flash Sequencer Processing Switching Register</description>
                    <addressOffset>0xE0</addressOffset>
                    <size>16</size>
                    <access>read-write</access>
                    <resetValue>0x0000</resetValue>
                    <resetMask>0xffff</resetMask>
                    <fields>
                        <field>
                            <name>ESUSPMD</name>
                            <description>Erasure Suspend Mode</description>
                            <lsb>0</lsb>
                            <msb>0</msb>
                            <access>read-write</access>
                            <enumeratedValues>
                                </enumeratedValues>
                        </field>
                    </fields>
                </register>
                <register>
                    <name>FPCKAR</name>
                    <description>Flash Sequencer Processing Clock Notification Register</description>
                    <addressOffset>0xE4</addressOffset>
                    <size>16</size>
                    <access>read-write</access>
                    <resetValue>0x0032</resetValue>
                    <resetMask>0xffff</resetMask>
                    <fields>
                        <field>
                            <name>PCKA</name>
                            <description>Flash Sequencer Operating Clock Notification</description>
                            <lsb>0</lsb>
                            <msb>7</msb>
                            <access>read-write</access>
                        </field>
                        <field>
                            <name>KEY</name>
                            <description>Key Code</description>
                            <lsb>8</lsb>
                            <msb>15</msb>
                            <access>write-only</access>
                        </field>
                    </fields>
                </register>
                <register>
                    <name>FSUACR</name>
                    <description>Flash Startup Area Control Register</description>
                    <addressOffset>0xE8</addressOffset>
                    <size>16</size>
                    <access>read-write</access>
                    <resetValue>0x0000</resetValue>
                    <resetMask>0xffff</resetMask>
                    <fields>
                        <field>
                            <name>SAS</name>
                            <description>Startup Area Select</description>
                            <lsb>0</lsb>
                            <msb>1</msb>
                            <access>read-write</access>
                            <enumeratedValues>
                                </enumeratedValues>
                        </field>
                        <field>
                            <name>KEY</name>
                            <description>Key Code</description>
                            <lsb>8</lsb>
                            <msb>15</msb>
                            <access>write-only</access>
                        </field>
                    </fields>
                </register>
            </registers>
        </peripheral>
        <peripheral>
            <name>QSPI</name>
            <description>Quad Serial Peripheral Interface</description>
            <baseAddress>0x64000000</baseAddress>
            <addressBlock>
                <offset>0x00</offset>
                <size>28</size>
                <usage>registers</usage>
            </addressBlock>
            <addressBlock>
                <offset>0x20</offset>
                <size>12</size>
                <usage>registers</usage>
            </addressBlock>
            <addressBlock>
                <offset>0x30</offset>
                <size>8</size>
                <usage>registers</usage>
            </addressBlock>
            <addressBlock>
                <offset>0x804</offset>
                <size>4</size>
                <usage>registers</usage>
            </addressBlock>
            <registers>
                <register>
                    <name>SFMSMD</name>
                    <description>Transfer Mode Control Register</description>
                    <addressOffset>0x000</addressOffset>
                    <size>32</size>
                    <access>read-write</access>
                    <resetValue>0x00000000</resetValue>
                    <resetMask>0xffffffff</resetMask>
                    <fields>
                        <field>
                            <name>SFMRM</name>
                            <description>Serial interface read mode select</description>
                            <lsb>0</lsb>
                            <msb>2</msb>
                            <access>read-write</access>
                            <enumeratedValues>
                                </enumeratedValues>
                        </field>
                        <field>
                            <name>SFMSE</name>
                            <description>QSSL extension function select after SPI bus access</description>
                            <lsb>4</lsb>
                            <msb>5</msb>
                            <access>read-write</access>
                            <enumeratedValues>
                                </enumeratedValues>
                        </field>
                        <field>
                            <name>SFMPFE</name>
                            <description>Prefetch function select</description>
                            <lsb>6</lsb>
                            <msb>6</msb>
                            <access>read-write</access>
                            <enumeratedValues>
                                </enumeratedValues>
                        </field>
                        <field>
                            <name>SFMPAE</name>
                            <description>Function select for stopping prefetch at locations other than on byte boundaries</description>
                            <lsb>7</lsb>
                            <msb>7</msb>
                            <access>read-write</access>
                            <enumeratedValues>
                                </enumeratedValues>
                        </field>
                        <field>
                            <name>SFMMD3</name>
                            <description>SPI mode select.</description>
                            <lsb>8</lsb>
                            <msb>8</msb>
                            <access>read-write</access>
                            <enumeratedValues>
                                </enumeratedValues>
                        </field>
                        <field>
                            <name>SFMOEX</name>
                            <description>Extension select for the I/O buffer output enable signal for the serial interface</description>
                            <lsb>9</lsb>
                            <msb>9</msb>
                            <access>read-write</access>
                            <enumeratedValues>
                                </enumeratedValues>
                        </field>
                        <field>
                            <name>SFMOHW</name>
                            <description>Hold time adjustment for serial transmission</description>
                            <lsb>10</lsb>
                            <msb>10</msb>
                            <access>read-write</access>
                            <enumeratedValues>
                                </enumeratedValues>
                        </field>
                        <field>
                            <name>SFMOSW</name>
                            <description>Setup time adjustment for serial transmission</description>
                            <lsb>11</lsb>
                            <msb>11</msb>
                            <access>read-write</access>
                            <enumeratedValues>
                                </enumeratedValues>
                        </field>
                        <field>
                            <name>SFMCCE</name>
                            <description>Read instruction code select</description>
                            <lsb>15</lsb>
                            <msb>15</msb>
                            <access>read-write</access>
                            <enumeratedValues>
                                </enumeratedValues>
                        </field>
                    </fields>
                </register>
                <register>
                    <name>SFMSSC</name>
                    <description>Chip Selection Control Register</description>
                    <addressOffset>0x004</addressOffset>
                    <size>32</size>
                    <access>read-write</access>
                    <resetValue>0x00000037</resetValue>
                    <resetMask>0xffffffff</resetMask>
                    <fields>
                        <field>
                            <name>SFMSW</name>
                            <description>Minimum High,level Width Select for QSSL Signal</description>
                            <lsb>0</lsb>
                            <msb>3</msb>
                            <access>read-write</access>
                            <enumeratedValues>
                                </enumeratedValues>
                        </field>
                        <field>
                            <name>SFMSHD</name>
                            <description>QSSL Signal Hold Time</description>
                            <lsb>4</lsb>
                            <msb>4</msb>
                            <access>read-write</access>
                            <enumeratedValues>
                                </enumeratedValues>
                        </field>
                        <field>
                            <name>SFMSLD</name>
                            <description>QSSL Signal Setup Time</description>
                            <lsb>5</lsb>
                            <msb>5</msb>
                            <access>read-write</access>
                            <enumeratedValues>
                                </enumeratedValues>
                        </field>
                    </fields>
                </register>
                <register>
                    <name>SFMSKC</name>
                    <description>Clock Control Register</description>
                    <addressOffset>0x008</addressOffset>
                    <size>32</size>
                    <access>read-write</access>
                    <resetValue>0x00000008</resetValue>
                    <resetMask>0xffffffff</resetMask>
                    <fields>
                        <field>
                            <name>SFMDV</name>
                            <description>Serial interface reference cycle select. (Pay attention to irregularities.)</description>
                            <lsb>0</lsb>
                            <msb>4</msb>
                            <access>read-write</access>
                            <enumeratedValues>
                                </enumeratedValues>
                        </field>
                        <field>
                            <name>SFMDTY</name>
                            <description>Duty ratio correction function select for the QSPCLK signal when devided by an odd number</description>
                            <lsb>5</lsb>
                            <msb>5</msb>
                            <access>read-write</access>
                            <enumeratedValues>
                                </enumeratedValues>
                        </field>
                    </fields>
                </register>
                <register>
                    <name>SFMSST</name>
                    <description>Status Register</description>
                    <addressOffset>0x00C</addressOffset>
                    <size>32</size>
                    <access>read-only</access>
                    <resetValue>0x00000080</resetValue>
                    <resetMask>0xffffffff</resetMask>
                    <fields>
                        <field>
                            <name>PFCNT</name>
                            <description>Number of bytes of prefetched data</description>
                            <lsb>0</lsb>
                            <msb>4</msb>
                            <access>read-only</access>
                            <enumeratedValues>
                                </enumeratedValues>
                        </field>
                        <field>
                            <name>PFFUL</name>
                            <description>Prefetch buffer state</description>
                            <lsb>6</lsb>
                            <msb>6</msb>
                            <access>read-only</access>
                            <enumeratedValues>
                                </enumeratedValues>
                        </field>
                        <field>
                            <name>PFOFF</name>
                            <description>Prefetch function operating state</description>
                            <lsb>7</lsb>
                            <msb>7</msb>
                            <access>read-only</access>
                            <enumeratedValues>
                                </enumeratedValues>
                        </field>
                    </fields>
                </register>
                <register>
                    <name>SFMCOM</name>
                    <description>Communication Port Register</description>
                    <addressOffset>0x010</addressOffset>
                    <size>32</size>
                    <access>read-write</access>
                    <resetValue>0x00000000</resetValue>
                    <resetMask>0xffffff00</resetMask>
                    <fields>
                        <field>
                            <name>SFMD</name>
                            <description>Port for direct communication with the SPI bus</description>
                            <lsb>0</lsb>
                            <msb>7</msb>
                            <access>read-write</access>
                        </field>
                    </fields>
                </register>
                <register>
                    <name>SFMCMD</name>
                    <description>Communication Mode Control Register</description>
                    <addressOffset>0x014</addressOffset>
                    <size>32</size>
                    <access>read-write</access>
                    <resetValue>0x00000000</resetValue>
                    <resetMask>0xffffffff</resetMask>
                    <fields>
                        <field>
                            <name>DCOM</name>
                            <description>Mode select for communication with the SPI bus</description>
                            <lsb>0</lsb>
                            <msb>0</msb>
                            <access>read-write</access>
                            <enumeratedValues>
                                </enumeratedValues>
                        </field>
                    </fields>
                </register>
                <register>
                    <name>SFMCST</name>
                    <description>Communication Status Register</description>
                    <addressOffset>0x018</addressOffset>
                    <size>32</size>
                    <access>read-write</access>
                    <resetValue>0x00000000</resetValue>
                    <resetMask>0xffffffff</resetMask>
                    <fields>
                        <field>
                            <name>COMBSY</name>
                            <description>SPI bus cycle completion state in direct communication</description>
                            <lsb>0</lsb>
                            <msb>0</msb>
                            <access>read-only</access>
                            <enumeratedValues>
                                </enumeratedValues>
                        </field>
                        <field>
                            <name>EROMR</name>
                            <description>ROM access detection status in direct communication mode</description>
                            <lsb>7</lsb>
                            <msb>7</msb>
                            <access>read-write</access>
                            <enumeratedValues>
                                </enumeratedValues>
                        </field>
                    </fields>
                </register>
                <register>
                    <name>SFMSIC</name>
                    <description>Instruction Code Register</description>
                    <addressOffset>0x020</addressOffset>
                    <size>32</size>
                    <access>read-write</access>
                    <resetValue>0x00000000</resetValue>
                    <resetMask>0xffffffff</resetMask>
                    <fields>
                        <field>
                            <name>SFMCIC</name>
                            <description>Serial flash instruction code to substitute</description>
                            <lsb>0</lsb>
                            <msb>7</msb>
                            <access>read-write</access>
                        </field>
                    </fields>
                </register>
                <register>
                    <name>SFMSAC</name>
                    <description>Address Mode Control Register</description>
                    <addressOffset>0x024</addressOffset>
                    <size>32</size>
                    <access>read-write</access>
                    <resetValue>0x00000002</resetValue>
                    <resetMask>0xffffffff</resetMask>
                    <fields>
                        <field>
                            <name>SFMAS</name>
                            <description>Number of address bytes select for the serial interface</description>
                            <lsb>0</lsb>
                            <msb>1</msb>
                            <access>read-write</access>
                            <enumeratedValues>
                                </enumeratedValues>
                        </field>
                        <field>
                            <name>SFM4BC</name>
                            <description>Selection of instruction code automatically generated when the serial interface address width is 4 bytes</description>
                            <lsb>4</lsb>
                            <msb>4</msb>
                            <access>read-write</access>
                            <enumeratedValues>
                                </enumeratedValues>
                        </field>
                    </fields>
                </register>
                <register>
                    <name>SFMSDC</name>
                    <description>Dummy Cycle Control Register</description>
                    <addressOffset>0x028</addressOffset>
                    <size>32</size>
                    <access>read-write</access>
                    <resetValue>0x0000ff00</resetValue>
                    <resetMask>0xffffffff</resetMask>
                    <fields>
                        <field>
                            <name>SFMDN</name>
                            <description>Number of dummy cycles select for Fast Read instructions</description>
                            <lsb>0</lsb>
                            <msb>3</msb>
                            <access>read-write</access>
                            <enumeratedValues>
                                </enumeratedValues>
                        </field>
                        <field>
                            <name>SFMXST</name>
                            <description>XIP mode status</description>
                            <lsb>6</lsb>
                            <msb>6</msb>
                            <access>read-only</access>
                            <enumeratedValues>
                                </enumeratedValues>
                        </field>
                        <field>
                            <name>SFMXEN</name>
                            <description>XIP mode permission</description>
                            <lsb>7</lsb>
                            <msb>7</msb>
                            <access>read-write</access>
                            <enumeratedValues>
                                </enumeratedValues>
                        </field>
                        <field>
                            <name>SFMXD</name>
                            <description>Mode data for serial flash (Controls XIP mode.)</description>
                            <lsb>8</lsb>
                            <msb>15</msb>
                            <access>read-write</access>
                        </field>
                    </fields>
                </register>
                <register>
                    <name>SFMSPC</name>
                    <description>SPI Protocol Control Register</description>
                    <addressOffset>0x030</addressOffset>
                    <size>32</size>
                    <access>read-write</access>
                    <resetValue>0x00000010</resetValue>
                    <resetMask>0xffffffff</resetMask>
                    <fields>
                        <field>
                            <name>SFMSPI</name>
                            <description>SPI protocol select</description>
                            <lsb>0</lsb>
                            <msb>1</msb>
                            <access>read-write</access>
                            <enumeratedValues>
                                </enumeratedValues>
                        </field>
                        <field>
                            <name>SFMSDE</name>
                            <description>QSPCLK extended selection bit when switching I/O of QIOn pin</description>
                            <lsb>4</lsb>
                            <msb>4</msb>
                            <access>read-write</access>
                            <enumeratedValues>
                                </enumeratedValues>
                        </field>
                    </fields>
                </register>
                <register>
                    <name>SFMPMD</name>
                    <description>Port Control Register</description>
                    <addressOffset>0x034</addressOffset>
                    <size>32</size>
                    <access>read-write</access>
                    <resetValue>0x00000000</resetValue>
                    <resetMask>0xffffffff</resetMask>
                    <fields>
                        <field>
                            <name>SFMWPL</name>
                            <description>WP pin level specification</description>
                            <lsb>2</lsb>
                            <msb>2</msb>
                            <access>read-write</access>
                            <enumeratedValues>
                                </enumeratedValues>
                        </field>
                    </fields>
                </register>
                <register>
                    <name>SFMCNT1</name>
                    <description>External QSPI Address Register</description>
                    <addressOffset>0x804</addressOffset>
                    <size>32</size>
                    <access>read-write</access>
                    <resetValue>0x00000000</resetValue>
                    <resetMask>0xffffffff</resetMask>
                    <fields>
                        <field>
                            <name>QSPI_EXT</name>
                            <description>Bank switching address</description>
                            <lsb>26</lsb>
                            <msb>31</msb>
                            <access>read-write</access>
                        </field>
                    </fields>
                </register>
            </registers>
        </peripheral>
    </peripherals>
</device>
